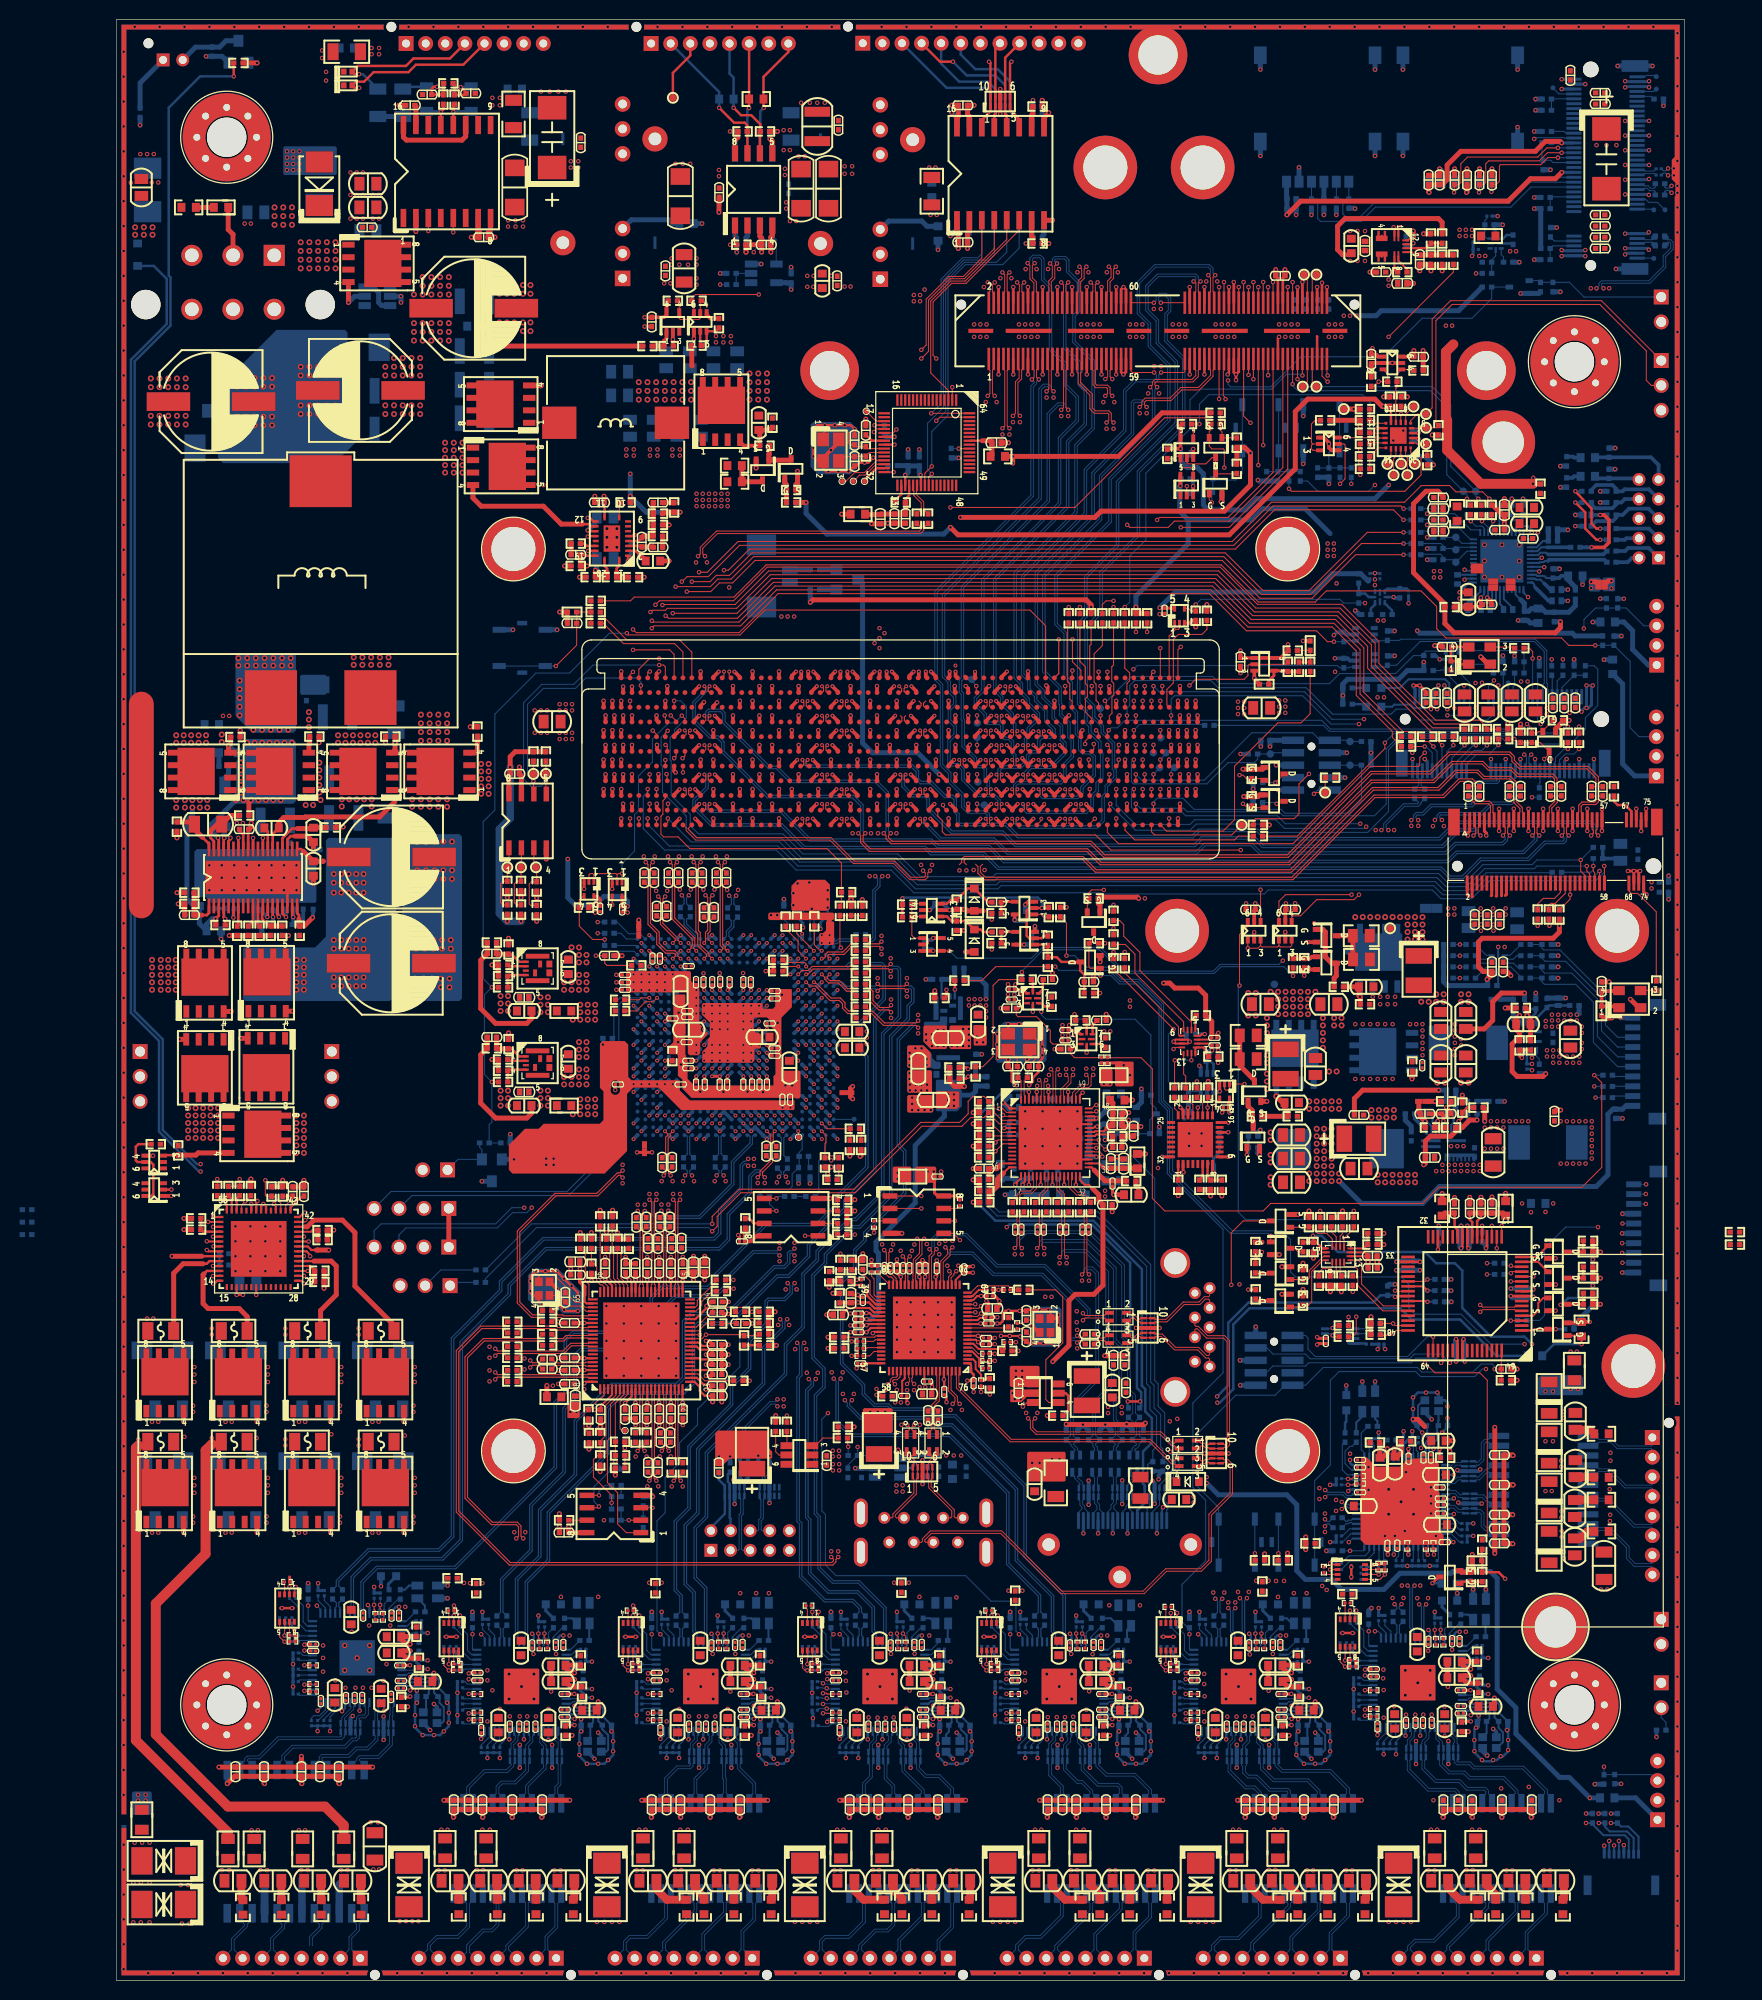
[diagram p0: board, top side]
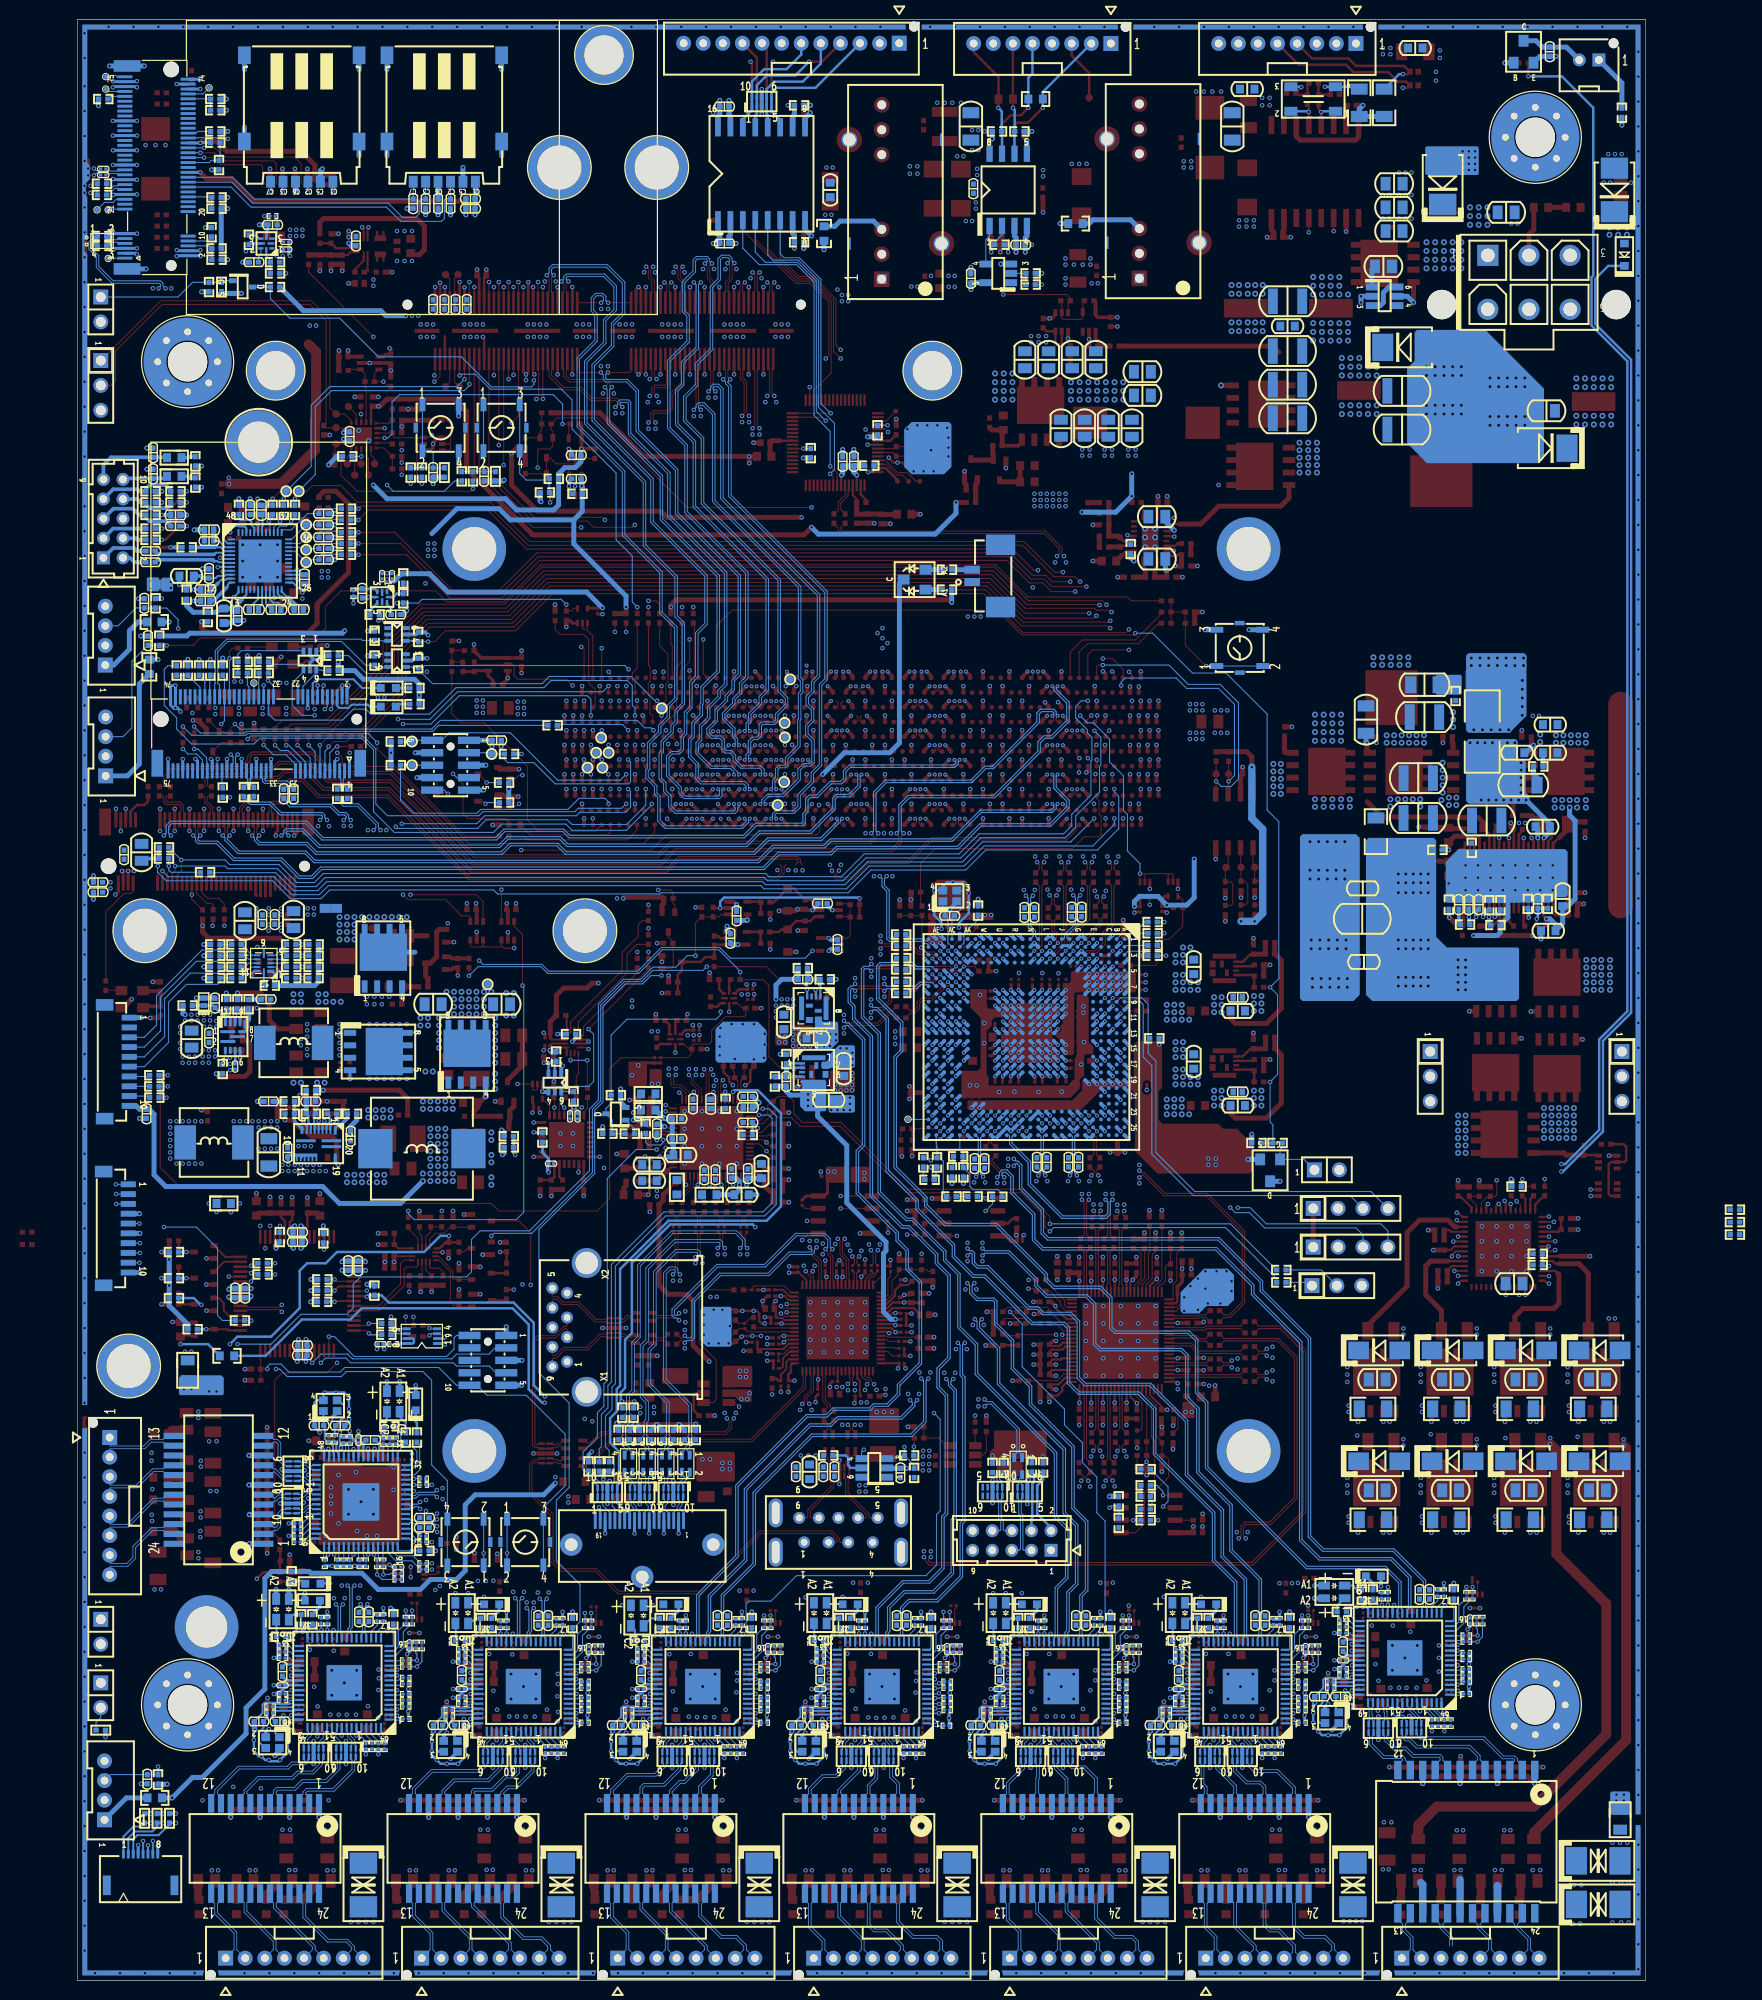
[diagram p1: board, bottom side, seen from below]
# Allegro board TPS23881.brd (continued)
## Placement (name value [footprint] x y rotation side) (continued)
NOREF#2230  -  []  136.13 34.9 0 top
NOREF#2231  -  []  150.88 179.2 0 top
NOREF#2232  -  []  92.93 99.68 90 top
NOREF#2233  -  []  93.21 23.8 270 top
NOREF#2234  -  []  55.77 36.88 270 top
NOREF#2235  -  []  101.3 102.82 0 top
NOREF#2236  -  []  34.46 32.28 0 top
NOREF#2237  -  []  43.46 64.77 0 top
NOREF#2238  -  []  56.52 55.84 270 top
NOREF#2239  -  []  134.95 86.56 90 top
NOREF#2240  -  []  123.42 70.43 0 top
NOREF#2241  -  []  63.25 176.79 90 top
NOREF#2242  -  []  57.26 91.53 0 top
NOREF#2243  -  []  138.25 83.64 90 top
NOREF#2244  -  []  31.19 192.61 0 top
NOREF#2245  -  []  19.8 32.13 0 top
NOREF#2246  -  []  127.03 177.52 270 top
NOREF#2247  -  []  16.48 108 0 top
NOREF#2248  -  []  92.33 61.21 270 top
NOREF#2249  -  []  30.56 36.84 0 top
NOREF#2250  -  []  52.57 36.63 0 top
NOREF#2251  -  []  18.02 31.11 0 top
NOREF#2252  -  []  139.24 140.18 90 top
NOREF#2253  -  []  89.61 29.71 0 top
NOREF#2254  -  []  23.42 28.52 90 top
NOREF#2255  -  []  112.67 37.52 0 top
NOREF#2256  -  []  40.01 95.99 270 top
NOREF#2257  -  []  73.96 111 0 top
NOREF#2258  -  []  38.51 92.08 0 top
NOREF#2259  -  []  150.57 178.1 270 top
NOREF#2260  -  []  128.91 12.52 0 top
NOREF#2261  -  []  93.04 190.7 90 top
NOREF#2262  -  []  130.72 173.1 0 top
NOREF#2263  -  []  126.54 132.26 270 top
NOREF#2264  -  []  129.36 64.76 90 top
NOREF#2265  -  []  68.33 12.52 0 top
NOREF#2266  -  []  79.76 33.9 90 top
NOREF#2267  -  []  63.26 34.52 270 top
NOREF#2268  -  []  61.8 173.69 90 top
NOREF#2269  -  []  156.54 177.5 90 top
NOREF#2270  -  []  65.61 29.58 0 top
NOREF#2271  -  []  126.19 32.5 0 top
NOREF#2272  -  []  127.53 65.43 0 top
NOREF#2273  -  []  146.71 87.67 90 top
NOREF#2274  -  []  130.71 174.24 0 top
NOREF#2275  -  []  58.09 58.6 270 top
NOREF#2276  -  []  36.53 30.75 0 top
NOREF#2277  -  []  52.53 54.43 0 top
NOREF#2278  -  []  121.08 33.01 90 top
NOREF#2279  -  []  130.78 63.24 0 top
NOREF#2280  -  []  48.59 27.42 0 top
NOREF#2281  -  []  61.14 53.09 270 top
NOREF#2282  -  []  116.97 17.4 90 top
NOREF#2283  -  []  87.43 26.34 270 top
NOREF#2284  -  []  137.77 40.21 90 top
NOREF#2285  -  []  124.64 38.96 90 top
NOREF#2286  -  []  133.34 42.85 0 top
NOREF#2287  -  []  39.58 37.2 90 top
NOREF#2288  -  []  56.21 51.38 0 top
NOREF#2289  -  []  50.44 55.37 0 top
NOREF#2290  -  []  109.72 30.61 0 top
NOREF#2291  -  []  146.86 134.54 270 top
NOREF#2292  -  []  136.6 90.09 270 top
NOREF#2293  -  []  48.13 12.52 0 top
NOREF#2294  -  []  73.14 29.21 0 top
NOREF#2295  -  []  150.6 17.02 270 top
NOREF#2296  -  []  37.03 18.72 0 top
NOREF#2297  -  []  103.71 18.72 0 top
NOREF#2298  -  []  83.71 53.94 90 top
NOREF#2299  -  []  -10.06 76.5 0 top
NOREF#2300  -  []  134.37 149.36 90 top
NOREF#2301  -  []  145.11 184.23 0 top
NOREF#2302  -  []  41.14 90.63 0 top
NOREF#2303  -  []  42.21 99.92 90 top
NOREF#2304  -  []  53.39 56.31 270 top
NOREF#2305  -  []  84.56 93.55 0 top
NOREF#2306  -  []  134.99 36.4 0 top
NOREF#2307  -  []  124.98 33.86 90 top
NOREF#2308  -  []  119.96 171.75 270 top
NOREF#2309  -  []  144.73 94.44 90 top
NOREF#2310  -  []  62.1 109.44 270 top
NOREF#2311  -  []  56.77 23.76 270 top
NOREF#2312  -  []  150.88 192.28 0 top
NOREF#2313  -  []  56.85 37.21 270 top
NOREF#2314  -  []  45.49 70.48 0 top
NOREF#2315  -  []  150.57 179.25 270 top
NOREF#2316  -  []  87.22 93.04 90 top
NOREF#2317  -  []  157 182.12 0 top
NOREF#2318  -  []  67.01 64.34 90 top
NOREF#2319  -  []  137.92 120.56 90 top
NOREF#2320  -  []  138.81 26.16 0 top
NOREF#2321  -  []  53.04 29.98 270 top
NOREF#2322  -  []  60.9 25.58 0 top
NOREF#2323  -  []  103.12 63.75 270 top
NOREF#2324  -  []  67.89 152.45 0 top
NOREF#2325  -  []  146 134.54 0 top
NOREF#2326  -  []  142.37 120.78 90 top
NOREF#2327  -  []  103.71 17.09 90 top
NOREF#2328  -  []  65.66 31.62 90 top
NOREF#2329  -  []  136.73 75.62 0 top
NOREF#2330  -  []  65.65 33.78 0 top
NOREF#2331  -  []  148.08 193.8 90 top
NOREF#2332  -  []  60.12 166.32 90 top
NOREF#2333  -  []  109.91 151.21 90 top
NOREF#2334  -  []  39.22 85.42 0 top
NOREF#2335  -  []  118.06 132.66 270 top
NOREF#2336  -  []  122.25 171.75 270 top
NOREF#2337  -  []  82.3 35.97 90 top
NOREF#2338  -  []  132.98 42.24 90 top
NOREF#2339  -  []  138.23 122.1 270 top
NOREF#2340  -  []  148.72 134.09 270 top
NOREF#2341  -  []  132.89 120.09 90 top
NOREF#2342  -  []  133.78 163.78 90 top
NOREF#2343  -  []  45.76 63.5 0 top
NOREF#2344  -  []  65.56 67.06 0 top
NOREF#2345  -  []  111.2 160.32 0 top
NOREF#2346  -  []  140.34 184.11 270 top
NOREF#2347  -  []  151.21 90.75 0 top
NOREF#2348  -  []  93.71 106.95 270 top
NOREF#2349  -  []  50.44 99.59 0 top
NOREF#2350  -  []  83.95 32.16 90 top
NOREF#2351  -  []  49.81 106.81 0 top
NOREF#2352  -  []  40.13 122.81 0 top
NOREF#2353  -  []  140.28 47.19 90 top
NOREF#2354  -  []  133.48 120.55 90 top
NOREF#2355  -  []  38.34 23.8 270 top
NOREF#2356  -  []  57.92 98.11 0 top
NOREF#2357  -  []  47.75 50.14 0 top
NOREF#2358  -  []  115.98 122.17 0 top
NOREF#2359  -  []  102.24 25.78 90 top
NOREF#2360  -  []  57.53 58.29 270 top
NOREF#2361  -  []  27.88 28.61 0 top
NOREF#2362  -  []  147.45 130.81 270 top
NOREF#2363  -  []  25.4 54.14 0 top
NOREF#2364  -  []  82.14 104.85 0 top
NOREF#2365  -  []  17.73 108.92 0 top
NOREF#2366  -  []  61.68 91.68 270 top
NOREF#2367  -  []  63.88 17.4 90 top
NOREF#2368  -  []  133.08 93.65 0 top
NOREF#2369  -  []  130.12 69.42 90 top
NOREF#2370  -  []  51.61 101.8 0 top
NOREF#2371  -  []  134.26 147.47 90 top
NOREF#2372  -  []  153.5 57.37 0 top
NOREF#2373  -  []  13.28 81.46 0 top
NOREF#2374  -  []  135.38 17.44 90 top
NOREF#2375  -  []  51.45 109.55 0 top
NOREF#2376  -  []  131.69 141.17 0 top
NOREF#2377  -  []  45.29 35.51 90 top
NOREF#2378  -  []  110.3 52.26 90 top
NOREF#2379  -  []  43 65.2 270 top
NOREF#2380  -  []  55.36 25.22 0 top
NOREF#2381  -  []  110.49 36.31 90 top
NOREF#2382  -  []  101.01 97.67 90 top
NOREF#2383  -  []  99.44 139.42 270 top
NOREF#2384  -  []  100.32 29.21 0 top
NOREF#2385  -  []  28.97 36.91 90 top
NOREF#2386  -  []  144.98 101.8 0 top
NOREF#2387  -  []  97.61 18.72 0 top
NOREF#2388  -  []  48.46 75.62 270 top
NOREF#2389  -  []  134.4 148.46 0 top
NOREF#2390  -  []  73.91 36.84 270 top
NOREF#2391  -  []  119.42 181.74 0 top
NOREF#2392  -  []  42.97 94.82 270 top
NOREF#2393  -  []  48.46 73.08 270 top
NOREF#2394  -  []  146.56 95.67 90 top
NOREF#2395  -  []  137.16 18.41 90 top
NOREF#2396  -  []  145.71 107.79 0 top
NOREF#2397  -  []  61.84 36.02 0 top
NOREF#2398  -  []  99.71 101.6 90 top
NOREF#2399  -  []  81.41 34.48 270 top
NOREF#2400  -  []  139.81 179.96 0 top
NOREF#2401  -  []  12.52 117.17 0 top
NOREF#2402  -  []  127.97 31.61 90 top
NOREF#2403  -  []  18.57 22.1 0 top
NOREF#2404  -  []  50.44 52.7 270 top
NOREF#2405  -  []  53.04 32.12 0 top
NOREF#2406  -  []  130.54 44.03 0 top
NOREF#2407  -  []  41.14 90.63 0 top
NOREF#2408  -  []  79.65 41 0 top
NOREF#2409  -  []  134.62 52.88 90 top
NOREF#2410  -  []  41.14 100.28 0 top
NOREF#2411  -  []  91.43 26.54 0 top
NOREF#2412  -  []  21.8 39.87 90 top
NOREF#2413  -  []  93.04 109.4 270 top
NOREF#2414  -  []  126.99 42.16 0 top
NOREF#2415  -  []  58.57 82.63 0 top
NOREF#2416  -  []  60.73 70.74 0 top
NOREF#2417  -  []  25.31 36.91 90 top
NOREF#2418  -  []  46.46 58.52 0 top
NOREF#2419  -  []  57.28 109.47 90 top
NOREF#2420  -  []  133.3 130 0 top
NOREF#2421  -  []  67.03 102.95 0 top
NOREF#2422  -  []  27.38 168.48 270 top
NOREF#2423  -  []  143.64 70.6 90 top
NOREF#2424  -  []  62.81 177.47 270 top
NOREF#2425  -  []  152.44 167.8 0 top
NOREF#2426  -  []  20.38 25.93 90 top
NOREF#2427  -  []  115.71 34.47 270 top
NOREF#2428  -  []  139.27 90.09 270 top
NOREF#2429  -  []  144.4 17.44 90 top
NOREF#2430  -  []  135.94 71.07 90 top
NOREF#2431  -  []  116.96 18.41 90 top
NOREF#2432  -  []  99.29 98.35 270 top
NOREF#2433  -  []  118.97 109.52 270 top
NOREF#2434  -  []  124.12 46.18 0 top
NOREF#2435  -  []  83.85 34.67 0 top
NOREF#2436  -  []  25.17 36.94 90 top
NOREF#2437  -  []  87.66 93.19 270 top
NOREF#2438  -  []  80.72 35.51 90 top
NOREF#2439  -  []  100.28 29.07 0 top
NOREF#2440  -  []  142.42 122.1 270 top
NOREF#2441  -  []  140.82 107.39 0 top
NOREF#2442  -  []  36.96 177.55 0 top
NOREF#2443  -  []  30.59 35.43 0 top
NOREF#2444  -  []  138.51 26.72 0 top
NOREF#2445  -  []  18.03 109.26 90 top
NOREF#2446  -  []  132.7 42.24 0 top
NOREF#2447  -  []  79.18 25.58 0 top
NOREF#2448  -  []  63.88 18.41 90 top
NOREF#2449  -  []  83.9 29.86 270 top
NOREF#2450  -  []  123.05 41.59 0 top
NOREF#2451  -  []  142.72 96.32 0 top
NOREF#2452  -  []  139.06 121.75 270 top
NOREF#2453  -  []  129.59 54.87 90 top
NOREF#2454  -  []  122.35 26.78 90 top
NOREF#2455  -  []  100.98 93.55 90 top
NOREF#2456  -  []  53.04 28.05 0 top
NOREF#2457  -  []  125.02 44.56 90 top
NOREF#2458  -  []  120.53 31.62 90 top
NOREF#2459  -  []  140.54 127.05 270 top
NOREF#2460  -  []  128.57 27.83 270 top
NOREF#2461  -  []  50.44 51.84 0 top
NOREF#2462  -  []  88.98 109.68 0 top
NOREF#2463  -  []  92.84 36.31 90 top
NOREF#2464  -  []  50.19 76.48 0 top
NOREF#2465  -  []  83.93 32.51 0 top
NOREF#2466  -  []  37.83 96.22 0 top
NOREF#2467  -  []  139.85 107.73 90 top
NOREF#2468  -  []  134.89 42.24 90 top
NOREF#2469  -  []  135.69 87 0 top
NOREF#2470  -  []  63.88 34.48 270 top
NOREF#2471  -  []  34.75 27.7 0 top
NOREF#2472  -  []  42.56 34.47 270 top
NOREF#2473  -  []  137.85 88.39 0 top
NOREF#2474  -  []  126.23 30.23 0 top
NOREF#2475  -  []  18.02 33.4 0 top
NOREF#2476  -  []  149.5 151.89 0 top
NOREF#2477  -  []  152.1 114.86 270 top
NOREF#2478  -  []  132.03 165.91 0 top
NOREF#2479  -  []  37.21 25.26 90 top
NOREF#2480  -  []  30.18 36.5 0 top
NOREF#2481  -  []  85.17 102.41 270 top
NOREF#2482  -  []  101.98 63.75 270 top
NOREF#2483  -  []  51.64 173.61 90 top
NOREF#2484  -  []  127.2 75.49 0 top
NOREF#2485  -  []  30.89 192.05 0 top
NOREF#2486  -  []  58.53 99.02 270 top
NOREF#2487  -  []  58.99 101.51 0 top
NOREF#2488  -  []  116.09 134.24 270 top
NOREF#2489  -  []  69.14 174.42 270 top
NOREF#2490  -  []  58.52 72.11 0 top
NOREF#2491  -  []  57.61 82.93 90 top
NOREF#2492  -  []  67.89 150.32 0 top
NOREF#2493  -  []  141.12 107.73 90 top
NOREF#2494  -  []  58.24 170.89 90 top
NOREF#2495  -  []  58.04 73.14 90 top
NOREF#2496  -  []  58.55 109.44 270 top
NOREF#2497  -  []  144.2 70.92 270 top
NOREF#2498  -  []  120.22 134.92 0 top
NOREF#2499  -  []  131.46 55.42 270 top
NOREF#2500  -  []  83.95 31.62 90 top
NOREF#2501  -  []  67.01 83.77 0 top
NOREF#2502  -  []  134.95 102.67 0 top
NOREF#2503  -  []  76.89 104.7 270 top
NOREF#2504  -  []  118.24 152.91 90 top
NOREF#2505  -  []  83.61 99.16 0 top
NOREF#2506  -  []  111.35 151.33 0 top
NOREF#2507  -  []  133.22 175.01 90 top
NOREF#2508  -  []  151.59 146.51 90 top
NOREF#2509  -  []  2.99 170.93 0 top
NOREF#2510  -  []  39.45 61.8 0 top
NOREF#2511  -  []  96.02 94.69 0 top
NOREF#2512  -  []  38.8 104.47 90 top
NOREF#2513  -  []  151.59 139.52 90 top
NOREF#2514  -  []  19.75 26.54 0 top
NOREF#2515  -  []  49.23 25.73 0 top
NOREF#2516  -  []  66.22 33.64 90 top
NOREF#2517  -  []  120.75 104.7 270 top
NOREF#2518  -  []  91.19 35.97 90 top
NOREF#2519  -  []  68.2 82.8 90 top
NOREF#2520  -  []  141.86 121.79 270 top
NOREF#2521  -  []  76.15 37.21 270 top
NOREF#2522  -  []  39.88 112.12 270 top
NOREF#2523  -  []  152.68 87.88 90 top
NOREF#2524  -  []  70.35 38.23 0 top
NOREF#2525  -  []  126.44 159.84 0 top
NOREF#2526  -  []  138.91 79.55 0 top
NOREF#2527  -  []  20.09 76.96 270 top
NOREF#2528  -  []  -9.6 76.07 0 top
NOREF#2529  -  []  135.25 143.51 0 top
NOREF#2530  -  []  136.27 34.86 270 top
NOREF#2531  -  []  151.87 17.02 270 top
NOREF#2532  -  []  134.76 34.85 270 top
NOREF#2533  -  []  118.12 34.52 270 top
NOREF#2534  -  []  140.59 46.35 0 top
NOREF#2535  -  []  126.31 143.94 0 top
NOREF#2536  -  []  31.29 31.45 90 top
NOREF#2537  -  []  134.95 104.95 270 top
NOREF#2538  -  []  107.65 156.64 270 top
NOREF#2539  -  []  65.79 176.78 0 top
NOREF#2540  -  []  128 29.59 0 top
NOREF#2541  -  []  37.13 27.44 270 top
NOREF#2542  -  []  82.8 102.54 0 top
NOREF#2543  -  []  61.79 61.55 90 top
NOREF#2544  -  []  19.25 127.3 0 top
NOREF#2545  -  []  146.86 106.1 270 top
NOREF#2546  -  []  132.35 42.24 90 top
NOREF#2547  -  []  37.85 23.76 270 top
NOREF#2548  -  []  152.02 139.98 90 top
NOREF#2549  -  []  146.86 104.95 270 top
NOREF#2550  -  []  30.61 33.53 90 top
NOREF#2551  -  []  139.22 78.27 90 top
NOREF#2552  -  []  52.7 32.14 90 top
NOREF#2553  -  []  107.9 32.4 270 top
NOREF#2554  -  []  79.49 36.63 270 top
NOREF#2555  -  []  37.36 94.64 0 top
NOREF#2556  -  []  81.97 26.42 0 top
NOREF#2557  -  []  149.5 150.75 0 top
NOREF#2558  -  []  100.46 34.48 270 top
NOREF#2559  -  []  146.58 128.52 0 top
NOREF#2560  -  []  119.38 180.47 0 top
NOREF#2561  -  []  122.68 70.89 90 top
NOREF#2562  -  []  68.58 174.12 270 top
NOREF#2563  -  []  126.26 88.01 0 top
NOREF#2564  -  []  75.54 84.28 0 top
NOREF#2565  -  []  42.98 125.78 270 top
NOREF#2566  -  []  78.3 25.58 0 top
NOREF#2567  -  []  57.26 23.8 270 top
NOREF#2568  -  []  138.76 29.35 0 top
NOREF#2569  -  []  6.93 108.92 0 top
NOREF#2570  -  []  124.66 76.4 90 top
NOREF#2571  -  []  138.76 182.83 0 top
NOREF#2572  -  []  60.66 109.74 0 top
NOREF#2573  -  []  75.77 52.27 270 top
NOREF#2574  -  []  48.63 27.56 0 top
NOREF#2575  -  []  12.09 119.25 270 top
NOREF#2576  -  []  144.65 18.41 90 top
NOREF#2577  -  []  58.24 109.78 0 top
NOREF#2578  -  []  141 127.64 0 top
NOREF#2579  -  []  49.33 142.7 90 top
NOREF#2580  -  []  134.95 103.81 0 top
NOREF#2581  -  []  149.2 73.2 0 top
NOREF#2582  -  []  138.81 184.15 270 top
NOREF#2583  -  []  73.1 78.05 0 top
NOREF#2584  -  []  45.72 35.97 90 top
NOREF#2585  -  []  44.15 35.51 0 top
NOREF#2586  -  []  74.83 85.7 270 top
NOREF#2587  -  []  139.09 139.47 90 top
NOREF#2588  -  []  93.68 36.23 90 top
NOREF#2589  -  []  153.16 139.99 90 top
NOREF#2590  -  []  100 97.66 0 top
NOREF#2591  -  []  134.68 50.15 0 top
NOREF#2592  -  []  147.11 120.49 0 top
NOREF#2593  -  []  54.94 51.51 0 top
NOREF#2594  -  []  56.18 149.17 90 top
NOREF#2595  -  []  53.92 76 270 top
NOREF#2596  -  []  26.87 0.16 90 top
NOREF#2597  -  []  50.52 48.08 0 top
NOREF#2598  -  []  108.03 151.21 0 top
NOREF#2599  -  []  68.99 108.94 270 top
NOREF#2600  -  []  134.72 50.29 0 top
NOREF#2601  -  []  27.94 6.93 90 top
NOREF#2602  -  []  100.28 27.47 0 top
NOREF#2603  -  []  65.48 51.79 90 top
NOREF#2604  -  []  135.18 89.66 0 top
NOREF#2605  -  []  164.19 75.49 270 top
NOREF#2606  -  []  61.2 36.63 0 top
NOREF#2607  -  []  131.33 42.24 90 top
NOREF#2608  -  []  34.42 17.44 90 top
NOREF#2609  -  []  45.72 66.8 90 top
NOREF#2610  -  []  58.24 170.89 0 top
NOREF#2611  -  []  137.07 76.33 0 top
NOREF#2612  -  []  53.07 26.29 0 top
NOREF#2613  -  []  76.58 18.41 270 top
NOREF#2614  -  []  43.46 65.91 0 top
NOREF#2615  -  []  75.46 105.03 0 top
NOREF#2616  -  []  54.69 104.5 270 top
NOREF#2617  -  []  125.97 33.86 0 top
NOREF#2618  -  []  149.39 7.98 90 top
NOREF#2619  -  []  55.37 72.17 90 top
NOREF#2620  -  []  92.98 36.27 90 top
NOREF#2621  -  []  126.19 32.78 270 top
NOREF#2622  -  []  75.67 108.15 0 top
NOREF#2623  -  []  140.82 107.39 90 top
NOREF#2624  -  []  135.23 90.37 0 top
NOREF#2625  -  []  64.82 189.03 270 top
NOREF#2626  -  []  139.32 120.78 90 top
NOREF#2627  -  []  102.79 32.37 90 top
NOREF#2628  -  []  101.31 65.81 0 top
NOREF#2629  -  []  122.83 159.13 0 top
NOREF#2630  -  []  88.09 93.65 270 top
NOREF#2631  -  []  128.91 141.57 270 top
NOREF#2632  -  []  118.88 34.52 270 top
NOREF#2633  -  []  54.18 37.39 0 top
NOREF#2634  -  []  71.2 108.51 270 top
NOREF#2635  -  []  42.71 102.77 0 top
NOREF#2636  -  []  83.52 33.58 0 top
NOREF#2637  -  []  133.07 87.96 0 top
NOREF#2638  -  []  60.57 34.47 0 top
NOREF#2639  -  []  151.21 135.71 90 top
NOREF#2640  -  []  84.51 31.93 270 top
NOREF#2641  -  []  131.97 52.91 90 top
NOREF#2642  -  []  48.59 56.79 90 top
NOREF#2643  -  []  49.71 58.55 270 top
NOREF#2644  -  []  60.48 64.14 0 top
NOREF#2645  -  []  122.81 77.83 270 top
NOREF#2646  -  []  85.17 102.41 0 top
NOREF#2647  -  []  43.13 63.07 0 top
NOREF#2648  -  []  120.35 154.36 0 top
NOREF#2649  -  []  52.7 36.59 270 top
NOREF#2650  -  []  54.74 145.92 0 top
NOREF#2651  -  []  61.44 52.74 270 top
NOREF#2652  -  []  141.12 107.73 90 top
NOREF#2653  -  []  42.61 25.58 0 top
NOREF#2654  -  []  119.18 26.99 270 top
NOREF#2655  -  []  84.79 110.16 270 top
NOREF#2656  -  []  127.46 55.3 270 top
NOREF#2657  -  []  141.99 120.73 90 top
NOREF#2658  -  []  65.1 67.77 90 top
NOREF#2659  -  []  73.1 26.4 0 top
NOREF#2660  -  []  117.98 34.48 270 top
NOREF#2661  -  []  10.41 54.14 0 top
NOREF#2662  -  []  89.78 33.65 90 top
NOREF#2663  -  []  15.75 106.58 90 top
NOREF#2664  -  []  10.06 72.54 90 top
NOREF#2665  -  []  30.3 29.26 270 top
NOREF#2666  -  []  114.11 25.58 90 top
NOREF#2667  -  []  24.87 2.26 90 top
NOREF#2668  -  []  146.87 0.16 90 top
NOREF#2669  -  []  57.28 166.27 90 top
NOREF#2670  -  []  58.3 109.47 90 top
NOREF#2671  -  []  122.94 181.73 90 top
NOREF#2672  -  []  121.23 78.28 0 top
NOREF#2673  -  []  56.38 18.41 90 top
NOREF#2674  -  []  53.07 31.62 0 top
NOREF#2675  -  []  140.16 107.39 90 top
NOREF#2676  -  []  12.01 109.32 90 top
NOREF#2677  -  []  115.21 108.97 0 top
NOREF#2678  -  []  57.07 53.26 270 top
NOREF#2679  -  []  121.06 71.53 90 top
NOREF#2680  -  []  100.15 35.51 90 top
NOREF#2681  -  []  53.04 28.97 270 top
NOREF#2682  -  []  135.59 35.89 90 top
NOREF#2683  -  []  109.91 155.27 90 top
NOREF#2684  -  []  21.11 54.14 90 top
NOREF#2685  -  []  49.81 105.56 0 top
NOREF#2686  -  []  34.79 30.48 0 top
NOREF#2687  -  []  149.66 69.6 0 top
NOREF#2688  -  []  20.78 20.82 90 top
NOREF#2689  -  []  76.14 197.59 90 top
NOREF#2690  -  []  73.71 27.44 270 top
NOREF#2691  -  []  157.66 184.01 90 top
NOREF#2692  -  []  33.81 41.02 0 top
NOREF#2693  -  []  120.65 29.95 270 top
NOREF#2694  -  []  122.38 159.56 270 top
NOREF#2695  -  []  53.92 76 0 top
NOREF#2696  -  []  87.41 92.19 90 top
NOREF#2697  -  []  57.53 109.44 270 top
NOREF#2698  -  []  37.21 23.76 270 top
NOREF#2699  -  []  138.8 33.53 0 top
NOREF#2700  -  []  21.16 25.97 90 top
NOREF#2701  -  []  37.36 105.44 90 top
NOREF#2702  -  []  63.14 68.2 0 top
NOREF#2703  -  []  83.64 26.34 270 top
NOREF#2704  -  []  141.6 17.4 90 top
NOREF#2705  -  []  100.89 27.75 270 top
NOREF#2706  -  []  122.56 73.86 90 top
NOREF#2707  -  []  89.4 33.48 0 top
NOREF#2708  -  []  51.77 142.7 0 top
NOREF#2709  -  []  110.22 25.22 90 top
NOREF#2710  -  []  31.17 31.61 90 top
NOREF#2711  -  []  51.59 109.51 270 top
NOREF#2712  -  []  48.81 150.75 0 top
NOREF#2713  -  []  65.47 91.68 0 top
NOREF#2714  -  []  39.45 61.52 270 top
NOREF#2715  -  []  68.28 108.48 270 top
NOREF#2716  -  []  75.46 102.74 0 top
NOREF#2717  -  []  138.81 83.95 90 top
NOREF#2718  -  []  134.75 42.28 90 top
NOREF#2719  -  []  83.06 57.1 90 top
NOREF#2720  -  []  118.87 35.97 90 top
NOREF#2721  -  []  97.78 36.63 270 top
NOREF#2722  -  []  75.26 86.16 270 top
NOREF#2723  -  []  149.52 149.48 0 top
NOREF#2724  -  []  128.32 158.7 90 top
NOREF#2725  -  []  63.73 78.16 0 top
NOREF#2726  -  []  134.95 103.81 270 top
NOREF#2727  -  []  93.37 106.77 270 top
NOREF#2728  -  []  139.67 89.36 0 top
NOREF#2729  -  []  90.75 37.39 0 top
NOREF#2730  -  []  60.27 18.72 0 top
NOREF#2731  -  []  55.07 56.97 0 top
NOREF#2732  -  []  134.4 151.26 0 top
NOREF#2733  -  []  136.73 75.01 90 top
NOREF#2734  -  []  34.75 28.33 270 top
NOREF#2735  -  []  45.16 45.92 0 top
NOREF#2736  -  []  157.38 112.27 0 top
NOREF#2737  -  []  14.17 108 0 top
NOREF#2738  -  []  97.59 139.88 270 top
NOREF#2739  -  []  69.16 81.48 0 top
NOREF#2740  -  []  59.25 25.58 90 top
NOREF#2741  -  []  140.54 128.07 0 top
NOREF#2742  -  []  138.32 79.24 90 top
NOREF#2743  -  []  139.37 32.75 90 top
NOREF#2744  -  []  135.94 69.93 90 top
NOREF#2745  -  []  54.81 109.87 270 top
NOREF#2746  -  []  116.47 34.47 270 top
NOREF#2747  -  []  126.8 27.8 90 top
NOREF#2748  -  []  55.36 23.8 0 top
NOREF#2749  -  []  82.03 34.52 0 top
NOREF#2750  -  []  124.41 42.68 270 top
NOREF#2751  -  []  134.23 44.63 0 top
NOREF#2752  -  []  60.53 69.52 0 top
NOREF#2753  -  []  142.49 178.03 270 top
NOREF#2754  -  []  140.59 183.13 90 top
NOREF#2755  -  []  31.86 30.48 0 top
NOREF#2756  -  []  36.16 193.5 270 top
NOREF#2757  -  []  137.24 45.2 90 top
NOREF#2758  -  []  60.01 25.58 0 top
NOREF#2759  -  []  121.36 133.05 0 top
NOREF#2760  -  []  52.7 31.51 0 top
NOREF#2761  -  []  76.02 18.72 270 top
NOREF#2762  -  []  119.2 152.48 0 top
NOREF#2763  -  []  86.44 93.55 270 top
NOREF#2764  -  []  135.25 177.19 90 top
NOREF#2765  -  []  121.78 26.92 0 top
NOREF#2766  -  []  140.61 72.01 0 top
NOREF#2767  -  []  47.93 33.01 90 top
NOREF#2768  -  []  137.96 136 0 top
NOREF#2769  -  []  90.83 98.91 90 top
NOREF#2770  -  []  64.87 2.26 90 top
NOREF#2771  -  []  53.64 27.42 90 top
NOREF#2772  -  []  152.48 137.46 0 top
NOREF#2773  -  []  108.74 158.75 0 top
NOREF#2774  -  []  54.94 187.83 90 top
NOREF#2775  -  []  136.83 142.43 90 top
NOREF#2776  -  []  98.27 100.28 0 top
NOREF#2777  -  []  16.54 81.41 0 top
NOREF#2778  -  []  144.07 133.78 270 top
NOREF#2779  -  []  42.3 184.31 0 top
NOREF#2780  -  []  50.09 150.44 90 top
NOREF#2781  -  []  54.48 75.69 270 top
NOREF#2782  -  []  55.5 55.84 270 top
NOREF#2783  -  []  126.19 32.14 270 top
NOREF#2784  -  []  64.2 66.76 90 top
NOREF#2785  -  []  138.25 83.64 0 top
NOREF#2786  -  []  100.89 26.99 270 top
NOREF#2787  -  []  45.72 63.75 0 top
NOREF#2788  -  []  119.08 135.2 0 top
NOREF#2789  -  []  141.81 120.47 0 top
NOREF#2790  -  []  119.61 102.82 90 top
NOREF#2791  -  []  14.94 190.7 0 top
NOREF#2792  -  []  140.64 27.17 90 top
NOREF#2793  -  []  32.77 29.21 0 top
NOREF#2794  -  []  6.5 111.38 0 top
NOREF#2795  -  []  89.32 109.98 0 top
NOREF#2796  -  []  60.78 63.58 0 top
NOREF#2797  -  []  55.99 23.8 0 top
NOREF#2798  -  []  96.58 25.58 90 top
NOREF#2799  -  []  134.05 25.96 90 top
NOREF#2800  -  []  65.23 188.16 0 top
NOREF#2801  -  []  55.98 84.25 270 top
NOREF#2802  -  []  7.19 77.01 0 top
NOREF#2803  -  []  141.05 17.09 90 top
NOREF#2804  -  []  66.22 28.05 90 top
NOREF#2805  -  []  139.12 104.95 270 top
NOREF#2806  -  []  39.83 36.23 90 top
NOREF#2807  -  []  144.7 104.95 270 top
NOREF#2808  -  []  25.11 178.82 0 top
NOREF#2809  -  []  67.84 108.94 270 top
NOREF#2810  -  []  54.81 26.4 0 top
NOREF#2811  -  []  76.89 100.89 270 top
NOREF#2812  -  []  134.7 182.83 0 top
NOREF#2813  -  []  84.86 94.11 270 top
NOREF#2814  -  []  57.23 109.78 0 top
NOREF#2815  -  []  157 183.26 0 top
NOREF#2816  -  []  111.2 159.18 270 top
NOREF#2817  -  []  70.52 108.58 0 top
NOREF#2818  -  []  121.67 181.74 270 top
NOREF#2819  -  []  156.84 176.91 90 top
NOREF#2820  -  []  108.87 0.16 0 top
NOREF#2821  -  []  42.97 101.97 90 top
NOREF#2822  -  []  19.81 130.07 90 top
NOREF#2823  -  []  157.1 100.99 90 top
NOREF#2824  -  []  95 35.89 90 top
NOREF#2825  -  []  57.35 76 0 top
NOREF#2826  -  []  14.38 108.74 90 top
NOREF#2827  -  []  19.76 34.15 90 top
NOREF#2828  -  []  134.06 145.21 0 top
NOREF#2829  -  []  57.1 37.17 270 top
NOREF#2830  -  []  137.69 42.16 270 top
NOREF#2831  -  []  48.9 148.82 0 top
NOREF#2832  -  []  137.24 45.83 0 top
NOREF#2833  -  []  53.54 113.3 0 top
NOREF#2834  -  []  137.16 17.4 90 top
NOREF#2835  -  []  152.63 87.58 90 top
NOREF#2836  -  []  38.34 23.8 0 top
NOREF#2837  -  []  18.8 186.18 270 top
NOREF#2838  -  []  124.66 129.74 0 top
NOREF#2839  -  []  152.68 15.57 0 top
NOREF#2840  -  []  67.49 26.78 90 top
NOREF#2841  -  []  65.65 29.72 0 top
NOREF#2842  -  []  136.65 133.15 90 top
NOREF#2843  -  []  87.22 91.77 0 top
NOREF#2844  -  []  146.86 131.11 270 top
NOREF#2845  -  []  20.75 115.32 0 top
NOREF#2846  -  []  124.41 44.84 0 top
NOREF#2847  -  []  126.75 140.49 90 top
NOREF#2848  -  []  135.33 74.75 90 top
NOREF#2849  -  []  143.97 125.81 0 top
NOREF#2850  -  []  140.59 53.85 0 top
NOREF#2851  -  []  55.7 77.84 90 top
NOREF#2852  -  []  17.93 107.7 0 top
NOREF#2853  -  []  34.75 28.69 0 top
NOREF#2854  -  []  32.46 28.65 0 top
NOREF#2855  -  []  56.43 98.26 0 top
NOREF#2856  -  []  79.73 108.89 270 top
NOREF#2857  -  []  64.14 75.53 270 top
NOREF#2858  -  []  148.64 193.5 90 top
NOREF#2859  -  []  97.03 58.04 270 top
NOREF#2860  -  []  46.34 73.3 0 top
NOREF#2861  -  []  127.36 72.95 0 top
NOREF#2862  -  []  134.06 147.5 0 top
NOREF#2863  -  []  60.91 113.3 270 top
NOREF#2864  -  []  126.23 32 0 top
NOREF#2865  -  []  22.61 180.47 90 top
NOREF#2866  -  []  64.58 101.51 0 top
NOREF#2867  -  []  101.98 63.75 90 top
NOREF#2868  -  []  81.02 18.41 90 top
NOREF#2869  -  []  102.22 28.19 0 top
NOREF#2870  -  []  138.81 30.99 90 top
NOREF#2871  -  []  131.19 42.28 90 top
NOREF#2872  -  []  47.36 29.72 0 top
NOREF#2873  -  []  156.54 177.34 0 top
NOREF#2874  -  []  121.08 30.4 270 top
NOREF#2875  -  []  146.09 147.96 0 top
NOREF#2876  -  []  132.51 54.56 90 top
NOREF#2877  -  []  135.13 36.44 90 top
NOREF#2878  -  []  63.32 18.72 0 top
NOREF#2879  -  []  52.96 72.17 90 top
NOREF#2880  -  []  2.24 53.8 0 top
NOREF#2881  -  []  102.22 33.15 0 top
NOREF#2882  -  []  115.82 119.79 90 top
NOREF#2883  -  []  18.19 54.94 0 top
NOREF#2884  -  []  132.07 55.42 0 top
NOREF#2885  -  []  150.57 176.96 270 top
NOREF#2886  -  []  58.66 93.94 270 top
NOREF#2887  -  []  11 79.58 90 top
NOREF#2888  -  []  61.46 101.55 0 top
NOREF#2889  -  []  16.26 107.21 90 top
NOREF#2890  -  []  117.3 35.51 90 top
NOREF#2891  -  []  60.83 18.41 90 top
NOREF#2892  -  []  132.7 54.81 90 top
NOREF#2893  -  []  126.95 41.03 0 top
NOREF#2894  -  []  74.52 110.03 0 top
NOREF#2895  -  []  142.8 175.56 270 top
NOREF#2896  -  []  112.13 23.8 0 top
NOREF#2897  -  []  54.36 57.28 90 top
NOREF#2898  -  []  116.98 36.02 90 top
NOREF#2899  -  []  144.07 135.46 90 top
NOREF#2900  -  []  75.01 106.6 0 top
NOREF#2901  -  []  74.92 23.8 0 top
NOREF#2902  -  []  91.69 38.76 90 top
NOREF#2903  -  []  125.08 58.13 0 top
NOREF#2904  -  []  56.39 108.55 90 top
NOREF#2905  -  []  99.01 35.51 90 top
NOREF#2906  -  []  96.77 17.4 90 top
NOREF#2907  -  []  89.65 32.26 0 top
NOREF#2908  -  []  107.61 31.65 0 top
NOREF#2909  -  []  22.81 38.86 90 top
NOREF#2910  -  []  142.19 132.92 0 top
NOREF#2911  -  []  115.8 70.92 0 top
NOREF#2912  -  []  89.61 30.62 270 top
NOREF#2913  -  []  46.35 145.16 0 top
NOREF#2914  -  []  54.78 150.75 0 top
NOREF#2915  -  []  10.74 109.3 90 top
NOREF#2916  -  []  66.6 85.39 270 top
NOREF#2917  -  []  65.66 79.93 0 top
NOREF#2918  -  []  64.03 64.8 90 top
NOREF#2919  -  []  111.25 138.71 90 top
NOREF#2920  -  []  140.03 134.06 0 top
NOREF#2921  -  []  65.58 64.77 0 top
NOREF#2922  -  []  55.12 58.29 270 top
NOREF#2923  -  []  20.47 22.1 0 top
NOREF#2924  -  []  60.58 17.44 90 top
NOREF#2925  -  []  54.18 49.81 270 top
NOREF#2926  -  []  138.81 32 90 top
NOREF#2927  -  []  127.97 29.45 0 top
NOREF#2928  -  []  124.76 182.04 270 top
NOREF#2929  -  []  113.87 157.78 0 top
NOREF#2930  -  []  39.57 104.22 0 top
NOREF#2931  -  []  107.9 28.05 0 top
NOREF#2932  -  []  140.24 177.16 90 top
NOREF#2933  -  []  125.65 136.09 90 top
NOREF#2934  -  []  21.65 26.54 0 top
NOREF#2935  -  []  18.29 39.51 270 top
NOREF#2936  -  []  131.19 141.99 270 top
NOREF#2937  -  []  50.7 74.19 0 top
NOREF#2938  -  []  137.81 111.93 90 top
NOREF#2939  -  []  13.61 65.44 90 top
NOREF#2940  -  []  50.06 143.13 0 top
NOREF#2941  -  []  134.37 144.65 0 top
NOREF#2942  -  []  52.19 73.14 90 top
NOREF#2943  -  []  157.07 111.71 0 top
NOREF#2944  -  []  47.37 32.16 90 top
NOREF#2945  -  []  81.99 29.07 0 top
NOREF#2946  -  []  126.75 143.48 270 top
NOREF#2947  -  []  75.46 99.31 0 top
NOREF#2948  -  []  56.64 52.81 270 top
NOREF#2949  -  []  155.5 100.96 270 top
NOREF#2950  -  []  75.46 106.68 0 top
NOREF#2951  -  []  101.68 35.1 0 top
NOREF#2952  -  []  136.02 130.3 90 top
NOREF#2953  -  []  70.99 32.42 0 top
NOREF#2954  -  []  57.26 23.8 0 top
NOREF#2955  -  []  87 51.08 90 top
NOREF#2956  -  []  117.4 116.28 90 top
NOREF#2957  -  []  40.08 17.09 90 top
NOREF#2958  -  []  34.79 28.83 0 top
NOREF#2959  -  []  47.32 31.93 0 top
NOREF#2960  -  []  136.56 63.75 0 top
NOREF#2961  -  []  114.87 25.58 90 top
NOREF#2962  -  []  6.5 110.24 0 top
NOREF#2963  -  []  76.89 106.6 270 top
NOREF#2964  -  []  129.18 139.32 0 top
NOREF#2965  -  []  94.59 106.98 270 top
NOREF#2966  -  []  56.01 173.9 90 top
NOREF#2967  -  []  52.18 102.43 90 top
NOREF#2968  -  []  128 55.3 0 top
NOREF#2969  -  []  134.11 184.14 90 top
NOREF#2970  -  []  99.01 35.51 0 top
NOREF#2971  -  []  154.98 115.32 90 top
NOREF#2972  -  []  74.64 199.29 0 top
NOREF#2973  -  []  139.12 106.1 270 top
NOREF#2974  -  []  -9.6 78.61 0 top
NOREF#2975  -  []  26.29 38.98 90 top
NOREF#2976  -  []  84.56 92.41 0 top
NOREF#2977  -  []  100.03 102.16 270 top
NOREF#2978  -  []  47.41 26.04 0 top
NOREF#2979  -  []  15.32 106.12 0 top
NOREF#2980  -  []  132.72 6.93 90 top
NOREF#2981  -  []  51.59 56.92 0 top
NOREF#2982  -  []  93.64 110.03 270 top
NOREF#2983  -  []  111.53 62.61 90 top
NOREF#2984  -  []  57.78 52.81 270 top
NOREF#2985  -  []  127.97 27.55 0 top
NOREF#2986  -  []  20.85 28.22 90 top
NOREF#2987  -  []  12.57 80.04 90 top
NOREF#2988  -  []  53.07 28.19 0 top
NOREF#2989  -  []  115.76 25.58 0 top
NOREF#2990  -  []  143.28 103.38 0 top
NOREF#2991  -  []  126.57 50.53 90 top
NOREF#2992  -  []  157.42 112.01 0 top
NOREF#2993  -  []  41 99.92 0 top
NOREF#2994  -  []  72.57 81.66 0 top
NOREF#2995  -  []  135.2 44.56 0 top
NOREF#2996  -  []  82.5 51.38 90 top
NOREF#2997  -  []  73.14 27.3 0 top
NOREF#2998  -  []  31.17 33.22 90 top
NOREF#2999  -  []  107.9 28.69 0 top
NOREF#3000  -  []  94.69 18.72 0 top
NOREF#3001  -  []  111.49 23.8 0 top
NOREF#3002  -  []  120.51 28.83 0 top
NOREF#3003  -  []  101.22 17.4 90 top
NOREF#3004  -  []  83.39 34.24 90 top
NOREF#3005  -  []  132.05 72.09 0 top
NOREF#3006  -  []  66.37 0.56 90 top
NOREF#3007  -  []  44.52 115.27 90 top
NOREF#3008  -  []  84.12 58.42 270 top
NOREF#3009  -  []  68.53 110.06 270 top
NOREF#3010  -  []  127.33 37.77 0 top
NOREF#3011  -  []  0 0 0 top
NOREF#3012  -  []  99.32 52.51 90 top
NOREF#3013  -  []  137.62 120.47 0 top
NOREF#3014  -  []  37.97 36.31 90 top
NOREF#3015  -  []  75.01 100.28 0 top
NOREF#3016  -  []  34.11 17.09 90 top
NOREF#3017  -  []  124.12 47.19 0 top
NOREF#3018  -  []  130.58 173.46 0 top
NOREF#3019  -  []  17.02 109.26 90 top
NOREF#3020  -  []  100.32 26.85 0 top
NOREF#3021  -  []  134.06 69.93 0 top
NOREF#3022  -  []  82.7 105.16 90 top
NOREF#3023  -  []  140.59 78.23 90 top
NOREF#3024  -  []  56.79 37.52 0 top
NOREF#3025  -  []  53.31 49.81 0 top
NOREF#3026  -  []  103.12 63.75 90 top
NOREF#3027  -  []  17.98 31.61 90 top
NOREF#3028  -  []  135.76 131.28 270 top
NOREF#3029  -  []  33.35 41.45 0 top
NOREF#3030  -  []  52.18 37.72 0 top
NOREF#3031  -  []  150.29 134.54 270 top
NOREF#3032  -  []  84.41 98.9 0 top
NOREF#3033  -  []  50.62 77.9 270 top
NOREF#3034  -  []  98.73 100.71 0 top
NOREF#3035  -  []  6.63 108.36 90 top
NOREF#3036  -  []  66.84 95.21 270 top
NOREF#3037  -  []  6.79 164.35 90 top
NOREF#3038  -  []  84.2 31.58 270 top
NOREF#3039  -  []  59.89 102.08 270 top
NOREF#3040  -  []  52.18 101.94 270 top
NOREF#3041  -  []  68.87 0.16 0 top
NOREF#3042  -  []  129.27 54.81 90 top
NOREF#3043  -  []  142.52 99.09 90 top
NOREF#3044  -  []  152.2 192.23 90 top
NOREF#3045  -  []  80.47 18.72 0 top
NOREF#3046  -  []  145.44 102.23 0 top
NOREF#3047  -  []  75.46 104.27 0 top
NOREF#3048  -  []  77.42 18.72 270 top
NOREF#3049  -  []  94.69 36.23 90 top
NOREF#3050  -  []  133.3 26 90 top
NOREF#3051  -  []  141.27 61.21 0 top
NOREF#3052  -  []  127.53 65.43 90 top
NOREF#3053  -  []  45.92 144.7 0 top
NOREF#3054  -  []  118.61 29.21 0 top
NOREF#3055  -  []  72.47 53.51 270 top
NOREF#3056  -  []  85.17 27.7 270 top
NOREF#3057  -  []  128.91 143.5 270 top
NOREF#3058  -  []  64.16 76.73 90 top
NOREF#3059  -  []  120.47 32.65 0 top
NOREF#3060  -  []  62.23 67.44 270 top
NOREF#3061  -  []  130.42 24.18 0 top
NOREF#3062  -  []  56.18 146.89 90 top
NOREF#3063  -  []  113.14 25.58 0 top
NOREF#3064  -  []  47.36 33.78 0 top
NOREF#3065  -  []  146.79 107.77 0 top
NOREF#3066  -  []  57.81 37.52 0 top
NOREF#3067  -  []  138.51 28.91 0 top
NOREF#3068  -  []  130.54 44.03 90 top
NOREF#3069  -  []  102.87 139.42 270 top
NOREF#3070  -  []  28.87 0.16 0 top
NOREF#3071  -  []  150.88 176.4 90 top
NOREF#3072  -  []  97.87 97.92 0 top
NOREF#3073  -  []  65.18 156.97 0 top
NOREF#3074  -  []  109.68 27.17 0 top
NOREF#3075  -  []  103.25 52.51 90 top
NOREF#3076  -  []  55.42 29.35 270 top
NOREF#3077  -  []  64.31 26.99 270 top
NOREF#3078  -  []  141.35 17.44 90 top
NOREF#3079  -  []  61.24 181.84 90 top
NOREF#3080  -  []  24.93 28.5 90 top
NOREF#3081  -  []  66.5 157.94 0 top
NOREF#3082  -  []  65.43 177.04 0 top
NOREF#3083  -  []  129.53 44.02 90 top
NOREF#3084  -  []  88.39 92.63 270 top
NOREF#3085  -  []  144.7 102.67 270 top
NOREF#3086  -  []  100.34 93.55 90 top
NOREF#3087  -  []  5.87 83.72 90 top
NOREF#3088  -  []  135.19 88.39 0 top
NOREF#3089  -  []  99.24 105.79 0 top
NOREF#3090  -  []  53.75 78.16 0 top
NOREF#3091  -  []  55.19 54.56 0 top
NOREF#3092  -  []  46.87 5.46 270 top
NOREF#3093  -  []  58.24 167.18 0 top
NOREF#3094  -  []  38.81 36.23 90 top
NOREF#3095  -  []  142.04 71.58 90 top
NOREF#3096  -  []  98.42 95.51 90 top
NOREF#3097  -  []  115.9 25.62 90 top
NOREF#3098  -  []  18.67 179.32 0 top
NOREF#3099  -  []  58.08 103.59 0 top
NOREF#3100  -  []  48.13 12.52 0 top
NOREF#3101  -  []  132.99 88.65 0 top
NOREF#3102  -  []  139.27 178.77 0 top
NOREF#3103  -  []  47.96 140.28 0 top
NOREF#3104  -  []  50.44 99.31 270 top
NOREF#3105  -  []  55.07 71.83 90 top
NOREF#3106  -  []  158.7 111.3 270 top
NOREF#3107  -  []  4.95 84.86 90 top
NOREF#3108  -  []  74.5 18.72 270 top
NOREF#3109  -  []  24.17 28.5 90 top
NOREF#3110  -  []  55.62 73.14 90 top
NOREF#3111  -  []  126.57 52.18 90 top
NOREF#3112  -  []  45.42 60.53 0 top
NOREF#3113  -  []  73.25 84.38 270 top
NOREF#3114  -  []  34.42 36.59 270 top
NOREF#3115  -  []  80.77 18.38 270 top
NOREF#3116  -  []  110.29 27.44 270 top
NOREF#3117  -  []  140.87 107.7 90 top
NOREF#3118  -  []  69.19 84.48 0 top
NOREF#3119  -  []  146.37 0.56 90 top
NOREF#3120  -  []  83.9 32.65 0 top
NOREF#3121  -  []  73.65 23.8 0 top
NOREF#3122  -  []  82.91 53.54 0 top
NOREF#3123  -  []  84.87 2.26 0 top
NOREF#3124  -  []  65.61 28.97 0 top
NOREF#3125  -  []  67.51 25.73 0 top
NOREF#3126  -  []  47.32 33.92 0 top
NOREF#3127  -  []  8.38 109.37 90 top
NOREF#3128  -  []  71.49 36.63 270 top
NOREF#3129  -  []  76.28 87.3 270 top
NOREF#3130  -  []  126.19 29.07 0 top
NOREF#3131  -  []  2.92 54.14 0 top
NOREF#3132  -  []  89.61 29.98 270 top
NOREF#3133  -  []  54.85 26.54 0 top
NOREF#3134  -  []  96.52 96.79 0 top
NOREF#3135  -  []  142.62 70.6 90 top
NOREF#3136  -  []  75.01 103.84 0 top
NOREF#3137  -  []  47.37 30.61 90 top
NOREF#3138  -  []  116.41 18.72 0 top
NOREF#3139  -  []  134.19 26 90 top
NOREF#3140  -  []  123.77 47.5 0 top
NOREF#3141  -  []  22.05 38.9 90 top
NOREF#3142  -  []  7.69 170.45 90 top
NOREF#3143  -  []  76.07 53.98 270 top
NOREF#3144  -  []  115.52 122.61 270 top
NOREF#3145  -  []  43.46 68.33 0 top
NOREF#3146  -  []  58.99 112.99 270 top
NOREF#3147  -  []  61.79 63.58 90 top
NOREF#3148  -  []  14.1 80.54 90 top
NOREF#3149  -  []  121.21 154.36 270 top
NOREF#3150  -  []  118.24 174.12 0 top
NOREF#3151  -  []  6.17 117.2 90 top
NOREF#3152  -  []  107.07 140 270 top
NOREF#3153  -  []  66.22 30.4 270 top
NOREF#3154  -  []  76.89 103.56 270 top
NOREF#3155  -  []  118.49 153.89 270 top
NOREF#3156  -  []  53.29 77.84 90 top
NOREF#3157  -  []  96.37 95 0 top
NOREF#3158  -  []  95.4 99.34 90 top
NOREF#3159  -  []  107.94 31.62 0 top
NOREF#3160  -  []  25.68 54.94 0 top
NOREF#3161  -  []  33.9 33.48 90 top
NOREF#3162  -  []  36.53 27.17 0 top
NOREF#3163  -  []  93.04 176.73 0 top
NOREF#3164  -  []  34.42 31.51 0 top
NOREF#3165  -  []  10.06 74.55 0 top
NOREF#3166  -  []  89.53 33.52 90 top
NOREF#3167  -  []  134.95 135.71 0 top
NOREF#3168  -  []  134.82 178.61 0 top
NOREF#3169  -  []  150.91 191.39 0 top
NOREF#3170  -  []  120.62 68.4 90 top
NOREF#3171  -  []  65.35 25.73 90 top
NOREF#3172  -  []  37.07 23.8 270 top
NOREF#3173  -  []  136.53 184.11 270 top
NOREF#3174  -  []  116.64 73.86 90 top
NOREF#3175  -  []  111.63 23.76 270 top
NOREF#3176  -  []  79.65 41 270 top
NOREF#3177  -  []  74.4 87.3 0 top
NOREF#3178  -  []  62.37 33.86 90 top
NOREF#3179  -  []  50.9 98.88 0 top
NOREF#3180  -  []  58.12 103.45 0 top
NOREF#3181  -  []  130.35 160.1 90 top
NOREF#3182  -  []  45.76 62.23 0 top
NOREF#3183  -  []  150.88 176.91 0 top
NOREF#3184  -  []  65.1 67.77 0 top
NOREF#3185  -  []  28.52 38.43 90 top
NOREF#3186  -  []  65.65 28.19 0 top
NOREF#3187  -  []  152.78 121.77 270 top
NOREF#3188  -  []  16.48 106.12 90 top
NOREF#3189  -  []  131.05 42.24 0 top
NOREF#3190  -  []  129.92 160.55 90 top
NOREF#3191  -  []  96.72 138 0 top
NOREF#3192  -  []  60.9 25.58 90 top
NOREF#3193  -  []  21.79 38.86 90 top
NOREF#3194  -  []  128.22 173.94 0 top
NOREF#3195  -  []  75.46 105.54 0 top
NOREF#3196  -  []  101.73 104.24 270 top
NOREF#3197  -  []  126.9 159.13 0 top
NOREF#3198  -  []  48.59 27.06 0 top
NOREF#3199  -  []  93.04 176.73 90 top
NOREF#3200  -  []  134.06 150.95 0 top
NOREF#3201  -  []  124.28 65.23 90 top
NOREF#3202  -  []  119.53 88.14 0 top
NOREF#3203  -  []  19.38 130.53 90 top
NOREF#3204  -  []  66.55 84.07 90 top
NOREF#3205  -  []  100.66 17.09 90 top
NOREF#3206  -  []  143.28 102.23 0 top
NOREF#3207  -  []  70.94 30.62 270 top
NOREF#3208  -  []  125.73 181.7 270 top
NOREF#3209  -  []  119.94 43.28 270 top
NOREF#3210  -  []  132.36 85.6 90 top
NOREF#3211  -  []  63.25 176.78 0 top
NOREF#3212  -  []  70.31 38.37 0 top
NOREF#3213  -  []  131.01 36.58 90 top
NOREF#3214  -  []  135.7 89.66 0 top
NOREF#3215  -  []  60.83 68.96 0 top
NOREF#3216  -  []  134.06 148.16 90 top
NOREF#3217  -  []  61.19 71.45 0 top
NOREF#3218  -  []  54.94 76 270 top
NOREF#3219  -  []  69.6 80.39 270 top
NOREF#3220  -  []  71.32 31.76 270 top
NOREF#3221  -  []  56.72 94.77 270 top
NOREF#3222  -  []  144.09 17.09 90 top
NOREF#3223  -  []  117.84 34.52 0 top
NOREF#3224  -  []  66.37 91.11 90 top
NOREF#3225  -  []  73.56 78.49 0 top
NOREF#3226  -  []  60.16 91.68 270 top
NOREF#3227  -  []  134.61 42.24 0 top
NOREF#3228  -  []  54.05 77.81 270 top
NOREF#3229  -  []  126.99 40.89 0 top
NOREF#3230  -  []  146.96 87.63 90 top
NOREF#3231  -  []  76.02 18.72 0 top
NOREF#3232  -  []  55.5 75.68 90 top
NOREF#3233  -  []  91.77 60.91 270 top
NOREF#3234  -  []  126.9 154.18 0 top
NOREF#3235  -  []  112.73 36.2 90 top
NOREF#3236  -  []  83.63 54.61 90 top
NOREF#3237  -  []  156.7 55.37 90 top
NOREF#3238  -  []  145.44 104.52 0 top
NOREF#3239  -  []  26.37 0.56 90 top
NOREF#3240  -  []  -9.6 77.34 0 top
NOREF#3241  -  []  21.74 40.18 0 top
NOREF#3242  -  []  134.37 145.8 0 top
NOREF#3243  -  []  47.45 139.12 90 top
NOREF#3244  -  []  131.27 178.23 270 top
NOREF#3245  -  []  141.22 149.52 90 top
NOREF#3246  -  []  82.4 24.99 90 top
NOREF#3247  -  []  132.72 175.01 90 top
NOREF#3248  -  []  49.01 112.13 270 top
NOREF#3249  -  []  127.99 67.01 0 top
NOREF#3250  -  []  55.07 73.46 0 top
NOREF#3251  -  []  17.77 36.4 0 top
NOREF#3252  -  []  98.17 18.41 90 top
NOREF#3253  -  []  151.78 101.89 270 top
NOREF#3254  -  []  140.72 177.83 270 top
NOREF#3255  -  []  24.71 65.1 0 top
NOREF#3256  -  []  91.39 31.23 90 top
NOREF#3257  -  []  43.47 62.36 0 top
NOREF#3258  -  []  97.42 34.47 270 top
NOREF#3259  -  []  44.17 94.02 270 top
NOREF#3260  -  []  156.54 176.48 90 top
NOREF#3261  -  []  33.9 34.09 0 top
NOREF#3262  -  []  132.79 127.3 0 top
NOREF#3263  -  []  56.39 82.63 0 top
NOREF#3264  -  []  137.16 36.35 90 top
NOREF#3265  -  []  137.27 45.34 0 top
NOREF#3266  -  []  61.75 181.84 90 top
NOREF#3267  -  []  16.09 170.45 0 top
NOREF#3268  -  []  75.46 103.12 0 top
NOREF#3269  -  []  141.3 89.36 90 top
NOREF#3270  -  []  71.6 31.79 270 top
NOREF#3271  -  []  140.63 47.5 0 top
NOREF#3272  -  []  124.45 42.55 0 top
NOREF#3273  -  []  39.45 64.21 0 top
NOREF#3274  -  []  18.75 108.92 0 top
NOREF#3275  -  []  83.9 33.29 0 top
NOREF#3276  -  []  103.18 67.09 90 top
NOREF#3277  -  []  144.73 122.1 0 top
NOREF#3278  -  []  52.1 103.96 0 top
NOREF#3279  -  []  132.51 125.43 90 top
NOREF#3280  -  []  118.19 154.23 270 top
NOREF#3281  -  []  47.62 186.94 90 top
NOREF#3282  -  []  24.71 53.8 0 top
NOREF#3283  -  []  146 120.47 0 top
NOREF#3284  -  []  66.04 85.09 270 top
NOREF#3285  -  []  73.1 27.17 0 top
NOREF#3286  -  []  128.91 12.52 0 top
NOREF#3287  -  []  141.52 139.83 0 top
NOREF#3288  -  []  84.19 100.36 0 top
NOREF#3289  -  []  45.42 67.36 270 top
NOREF#3290  -  []  35.67 192.48 0 top
NOREF#3291  -  []  39.83 123.37 0 top
NOREF#3292  -  []  134.82 56.85 0 top
NOREF#3293  -  []  58.99 102.12 270 top
NOREF#3294  -  []  20.37 29.32 90 top
NOREF#3295  -  []  85.72 110.21 270 top
NOREF#3296  -  []  136.83 126.44 90 top
NOREF#3297  -  []  149.2 69.16 0 top
NOREF#3298  -  []  119.61 104.7 0 top
NOREF#3299  -  []  98.7 101.6 0 top
NOREF#3300  -  []  100.69 24.99 90 top
NOREF#3301  -  []  71.36 31.62 0 top
NOREF#3302  -  []  61.85 82.93 90 top
NOREF#3303  -  []  45.45 27.61 0 top
NOREF#3304  -  []  129.26 71.3 0 top
NOREF#3305  -  []  43.13 62.05 0 top
NOREF#3306  -  []  83.9 28.33 0 top
NOREF#3307  -  []  54.56 113.3 0 top
NOREF#3308  -  []  90.22 27.42 90 top
NOREF#3309  -  []  44.87 2.26 90 top
NOREF#3310  -  []  92.93 99.68 90 top
NOREF#3311  -  []  133.21 53.64 0 top
NOREF#3312  -  []  30.61 34.54 90 top
NOREF#3313  -  []  140.03 104.19 270 top
NOREF#3314  -  []  73.1 31.51 0 top
NOREF#3315  -  []  115.25 109.22 0 top
NOREF#3316  -  []  121.69 73.86 0 top
NOREF#3317  -  []  104.06 26.78 90 top
NOREF#3318  -  []  134.72 90.09 0 top
NOREF#3319  -  []  109.47 35.97 90 top
NOREF#3320  -  []  126.35 37.01 0 top
NOREF#3321  -  []  126.19 31 270 top
NOREF#3322  -  []  126.44 157.15 270 top
NOREF#3323  -  []  145.29 173.2 270 top
NOREF#3324  -  []  64.11 24.99 90 top
NOREF#3325  -  []  53.85 112.95 270 top
NOREF#3326  -  []  129.49 160.1 0 top
NOREF#3327  -  []  17.98 33.26 90 top
NOREF#3328  -  []  53.98 103.96 270 top
NOREF#3329  -  []  57.66 75.65 270 top
NOREF#3330  -  []  56.69 83.91 270 top
NOREF#3331  -  []  146.41 87.33 90 top
NOREF#3332  -  []  20.57 39.23 90 top
NOREF#3333  -  []  77.53 26.19 270 top
NOREF#3334  -  []  36.56 26.54 0 top
NOREF#3335  -  []  123.65 44.25 0 top
NOREF#3336  -  []  65.61 31.93 0 top
NOREF#3337  -  []  34.28 36.63 270 top
NOREF#3338  -  []  89.92 36.59 270 top
NOREF#3339  -  []  64.31 27.75 270 top
NOREF#3340  -  []  86.14 26.04 0 top
NOREF#3341  -  []  99.69 98.22 0 top
NOREF#3342  -  []  83.64 26.34 0 top
NOREF#3343  -  []  124.09 46.94 90 top
NOREF#3344  -  []  50.52 46.94 0 top
NOREF#3345  -  []  136.86 29.45 0 top
NOREF#3346  -  []  51.46 91.25 90 top
NOREF#3347  -  []  132.69 88.09 0 top
NOREF#3348  -  []  83.16 109.55 0 top
NOREF#3349  -  []  101.93 26.34 0 top
NOREF#3350  -  []  38.98 23.8 270 top
NOREF#3351  -  []  44.97 34.52 270 top
NOREF#3352  -  []  120.4 181.48 90 top
NOREF#3353  -  []  143.51 120.78 90 top
NOREF#3354  -  []  126.37 0.56 90 top
NOREF#3355  -  []  128.65 24.14 270 top
NOREF#3356  -  []  75.01 100.89 0 top
NOREF#3357  -  []  146.33 140.36 90 top
NOREF#3358  -  []  120.04 103.28 90 top
NOREF#3359  -  []  65.61 32.65 0 top
NOREF#3360  -  []  50.06 50.06 0 top
NOREF#3361  -  []  146.13 171.78 0 top
NOREF#3362  -  []  156.7 55.37 90 top
NOREF#3363  -  []  140.54 126.19 0 top
NOREF#3364  -  []  26.28 37.39 0 top
NOREF#3365  -  []  37.13 29.35 270 top
NOREF#3366  -  []  27.46 126.87 0 top
NOREF#3367  -  []  68.35 150.75 0 top
NOREF#3368  -  []  140.15 176.67 0 top
NOREF#3369  -  []  60.83 82.93 90 top
NOREF#3370  -  []  61.04 169.98 0 top
NOREF#3371  -  []  28.83 36.94 90 top
NOREF#3372  -  []  70.48 108.33 0 top
NOREF#3373  -  []  45.72 67.31 0 top
NOREF#3374  -  []  125.12 131.83 0 top
NOREF#3375  -  []  18.69 106.58 90 top
NOREF#3376  -  []  137.67 121.79 270 top
NOREF#3377  -  []  14.94 30.8 0 top
NOREF#3378  -  []  125.35 55.85 270 top
NOREF#3379  -  []  101.73 106.65 270 top
NOREF#3380  -  []  49.1 56.92 0 top
NOREF#3381  -  []  57.87 95.57 0 top
NOREF#3382  -  []  73.81 108.61 90 top
NOREF#3383  -  []  41.27 112.12 270 top
NOREF#3384  -  []  55.75 54.86 90 top
NOREF#3385  -  []  150.88 191.13 90 top
NOREF#3386  -  []  114.25 25.62 90 top
NOREF#3387  -  []  151.38 121.79 270 top
NOREF#3388  -  []  100.34 93.55 0 top
NOREF#3389  -  []  145.44 105.66 0 top
NOREF#3390  -  []  80.52 33.9 90 top
NOREF#3391  -  []  37.49 96.52 0 top
NOREF#3392  -  []  86.44 51.38 90 top
NOREF#3393  -  []  86.44 92.41 270 top
NOREF#3394  -  []  125.12 130.18 0 top
NOREF#3395  -  []  20.22 71.25 0 top
NOREF#3396  -  []  17.98 32.63 0 top
NOREF#3397  -  []  68.99 108.94 0 top
NOREF#3398  -  []  18.8 109.22 90 top
NOREF#3399  -  []  128.78 42.28 90 top
NOREF#3400  -  []  135.15 88.14 90 top
NOREF#3401  -  []  58.62 82.93 90 top
NOREF#3402  -  []  39.9 63.5 0 top
NOREF#3403  -  []  18.26 34.71 270 top
NOREF#3404  -  []  58.43 113.3 0 top
NOREF#3405  -  []  137.24 46.47 0 top
NOREF#3406  -  []  3.2 54.94 0 top
NOREF#3407  -  []  82.6 29.35 270 top
NOREF#3408  -  []  54.85 27.3 0 top
NOREF#3409  -  []  30.59 31.11 0 top
NOREF#3410  -  []  138.02 89.46 0 top
NOREF#3411  -  []  118.44 35.51 90 top
NOREF#3412  -  []  86.39 52.7 0 top
NOREF#3413  -  []  50.55 25.78 90 top
NOREF#3414  -  []  150.57 179.78 0 top
NOREF#3415  -  []  89.65 31.62 0 top
NOREF#3416  -  []  52.88 150.32 90 top
NOREF#3417  -  []  17.65 34.43 0 top
NOREF#3418  -  []  152.86 20.99 270 top
NOREF#3419  -  []  138.85 26.42 0 top
NOREF#3420  -  []  99.87 139.88 270 top
NOREF#3421  -  []  103.58 139.88 0 top
NOREF#3422  -  []  95.86 108.03 90 top
NOREF#3423  -  []  135.66 89.41 0 top
NOREF#3424  -  []  135.08 18.72 0 top
NOREF#3425  -  []  34.67 17.4 90 top
NOREF#3426  -  []  52.73 78.16 270 top
NOREF#3427  -  []  126.35 34.03 90 top
NOREF#3428  -  []  123.19 41.63 90 top
NOREF#3429  -  []  124.23 101.35 0 top
NOREF#3430  -  []  103.25 59.94 90 top
NOREF#3431  -  []  76.89 101.14 270 top
NOREF#3432  -  []  84.07 57.1 90 top
NOREF#3433  -  []  131.09 125.86 0 top
NOREF#3434  -  []  66.84 100.29 0 top
NOREF#3435  -  []  36.56 31.37 0 top
NOREF#3436  -  []  134.82 48.37 0 top
NOREF#3437  -  []  51.73 109.55 270 top
NOREF#3438  -  []  74.42 23.76 270 top
NOREF#3439  -  []  75.01 106.25 0 top
NOREF#3440  -  []  107.43 36.63 0 top
NOREF#3441  -  []  41 90.27 0 top
NOREF#3442  -  []  81.03 18.41 270 top
NOREF#3443  -  []  150.8 122.1 270 top
NOREF#3444  -  []  133.36 93.04 90 top
NOREF#3445  -  []  53.31 31.79 270 top
NOREF#3446  -  []  124.92 56.31 270 top
NOREF#3447  -  []  101.3 107.65 0 top
NOREF#3448  -  []  38.96 102.44 0 top
NOREF#3449  -  []  142.57 70.92 0 top
NOREF#3450  -  []  50.89 91.39 0 top
NOREF#3451  -  []  129.15 24.18 270 top
NOREF#3452  -  []  126.19 28.71 270 top
NOREF#3453  -  []  138.38 33.96 0 top
NOREF#3454  -  []  11.25 109.3 90 top
NOREF#3455  -  []  89.31 106.68 90 top
NOREF#3456  -  []  141.25 148.16 90 top
NOREF#3457  -  []  75.69 23.76 270 top
NOREF#3458  -  []  98.04 34.43 270 top
NOREF#3459  -  []  107.57 32.42 0 top
NOREF#3460  -  []  53.04 27.7 0 top
NOREF#3461  -  []  144.98 187.02 90 top
NOREF#3462  -  []  66.88 100.91 0 top
NOREF#3463  -  []  61.79 67.9 90 top
NOREF#3464  -  []  121.11 170.13 0 top
NOREF#3465  -  []  145.31 175.51 0 top
NOREF#3466  -  []  34.09 28.65 90 top
NOREF#3467  -  []  34.75 30.34 0 top
NOREF#3468  -  []  53.04 30.34 0 top
NOREF#3469  -  []  11 109.33 90 top
NOREF#3470  -  []  115.77 73.86 0 top
NOREF#3471  -  []  37.48 36.27 90 top
NOREF#3472  -  []  95 25.62 90 top
NOREF#3473  -  []  54.76 147.32 0 top
NOREF#3474  -  []  48.41 138.43 0 top
NOREF#3475  -  []  19.43 81.28 270 top
NOREF#3476  -  []  150.57 177.5 0 top
NOREF#3477  -  []  138.3 17.44 90 top
NOREF#3478  -  []  19.76 34.43 0 top
NOREF#3479  -  []  59.13 91.64 270 top
NOREF#3480  -  []  36.27 40.94 0 top
NOREF#3481  -  []  120.09 33.58 0 top
NOREF#3482  -  []  53.75 49.35 270 top
NOREF#3483  -  []  17.48 107.26 90 top
NOREF#3484  -  []  104.26 18.41 90 top
NOREF#3485  -  []  25.03 37.52 0 top
NOREF#3486  -  []  55.83 18.72 0 top
NOREF#3487  -  []  35.94 17.44 90 top
NOREF#3488  -  []  102.36 29.95 270 top
NOREF#3489  -  []  149.2 73.86 0 top
NOREF#3490  -  []  101.93 28.52 0 top
NOREF#3491  -  []  102.24 31.62 90 top
NOREF#3492  -  []  49.81 107.95 0 top
NOREF#3493  -  []  51.84 76.07 0 top
NOREF#3494  -  []  72.21 144.32 270 top
NOREF#3495  -  []  135.24 34.85 0 top
NOREF#3496  -  []  132.69 88.09 90 top
NOREF#3497  -  []  35.36 27.42 90 top
NOREF#3498  -  []  39.52 37.52 0 top
NOREF#3499  -  []  136.53 63.5 0 top
NOREF#3500  -  []  152.35 120.35 0 top
NOREF#3501  -  []  131.7 44.59 270 top
NOREF#3502  -  []  145.64 100.51 0 top
NOREF#3503  -  []  66.22 32.37 90 top
NOREF#3504  -  []  137.24 44.56 90 top
NOREF#3505  -  []  91.62 35.51 90 top
NOREF#3506  -  []  124.41 42.05 270 top
NOREF#3507  -  []  139.83 127.61 270 top
NOREF#3508  -  []  107.94 29.84 0 top
NOREF#3509  -  []  65.67 25.78 90 top
NOREF#3510  -  []  56.77 168.16 0 top
NOREF#3511  -  []  133.68 174.57 90 top
NOREF#3512  -  []  93.34 23.76 270 top
NOREF#3513  -  []  149.17 71.17 0 top
NOREF#3514  -  []  137.03 34.86 270 top
NOREF#3515  -  []  65.66 33.12 270 top
NOREF#3516  -  []  61.2 36.02 90 top
NOREF#3517  -  []  121.16 17.44 90 top
NOREF#3518  -  []  89 107.24 270 top
NOREF#3519  -  []  142.82 105.23 0 top
NOREF#3520  -  []  104.01 138.46 90 top
NOREF#3521  -  []  108.58 153.42 0 top
NOREF#3522  -  []  60.64 102.12 270 top
NOREF#3523  -  []  89.28 32.14 90 top
NOREF#3524  -  []  134.37 54.98 90 top
NOREF#3525  -  []  41 99.92 90 top
NOREF#3526  -  []  66.33 97.75 270 top
NOREF#3527  -  []  59.75 101.51 0 top
NOREF#3528  -  []  53.04 31.76 270 top
NOREF#3529  -  []  85.06 101.55 0 top
NOREF#3530  -  []  124.41 50.41 0 top
NOREF#3531  -  []  109.2 151.47 0 top
NOREF#3532  -  []  16.5 36.4 0 top
NOREF#3533  -  []  134.26 149.76 0 top
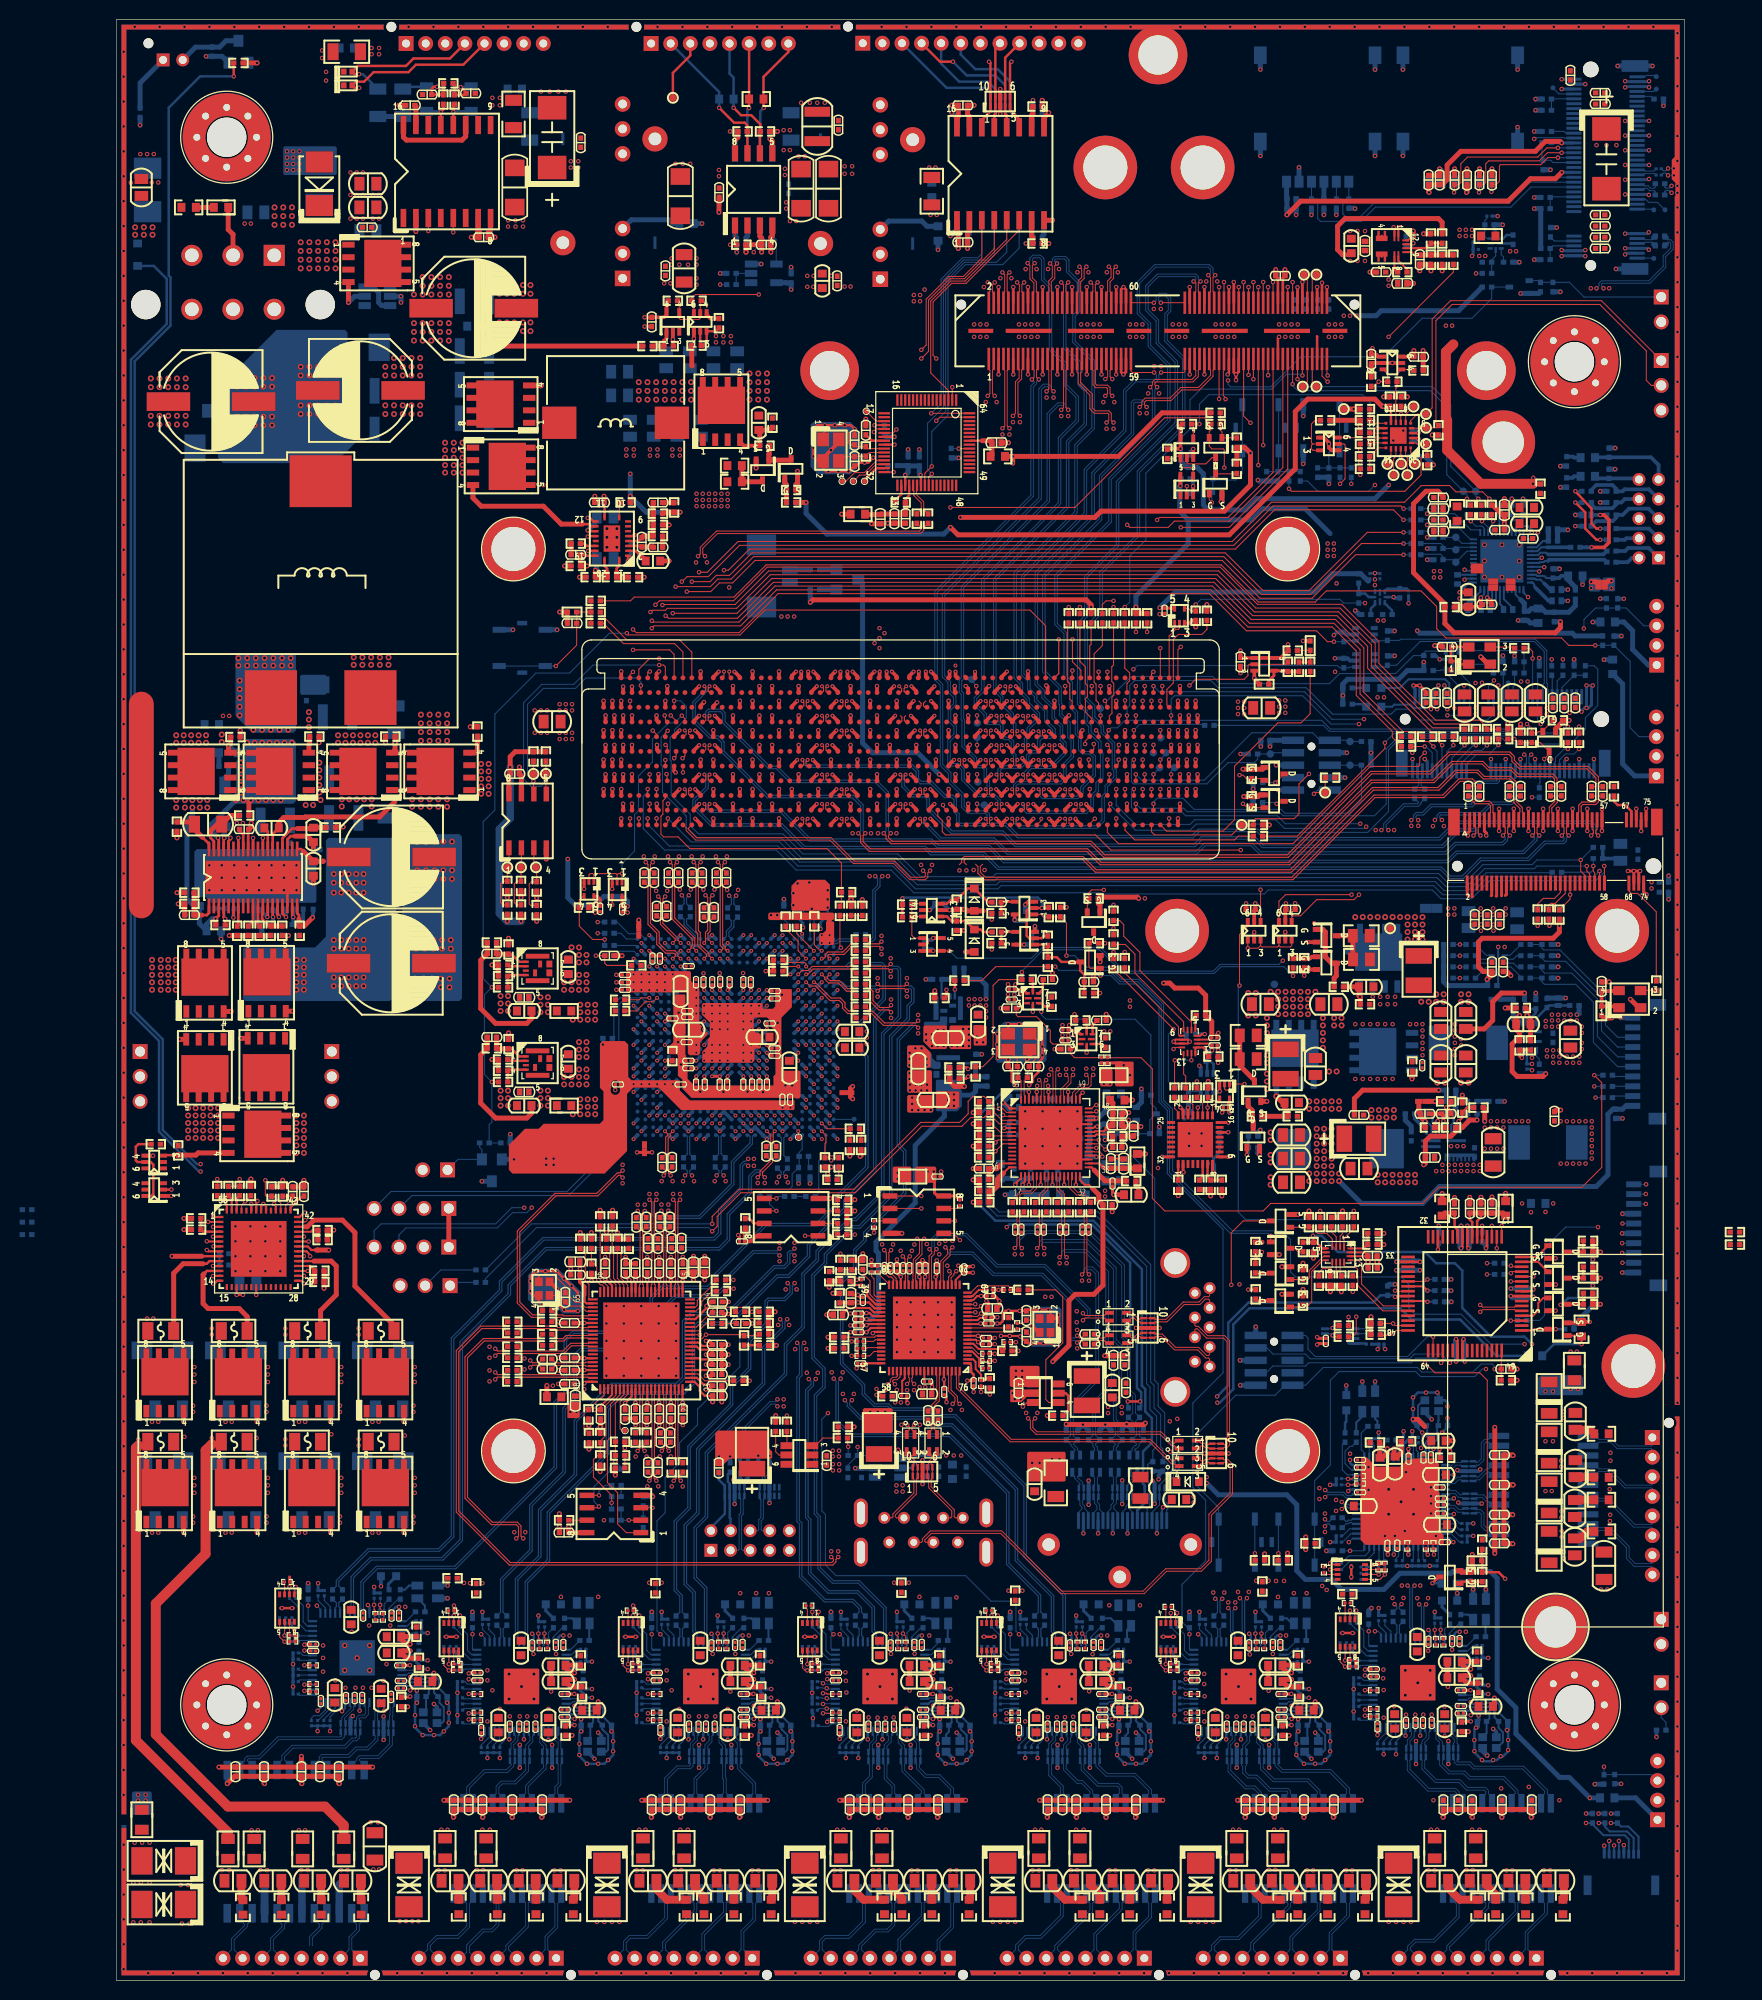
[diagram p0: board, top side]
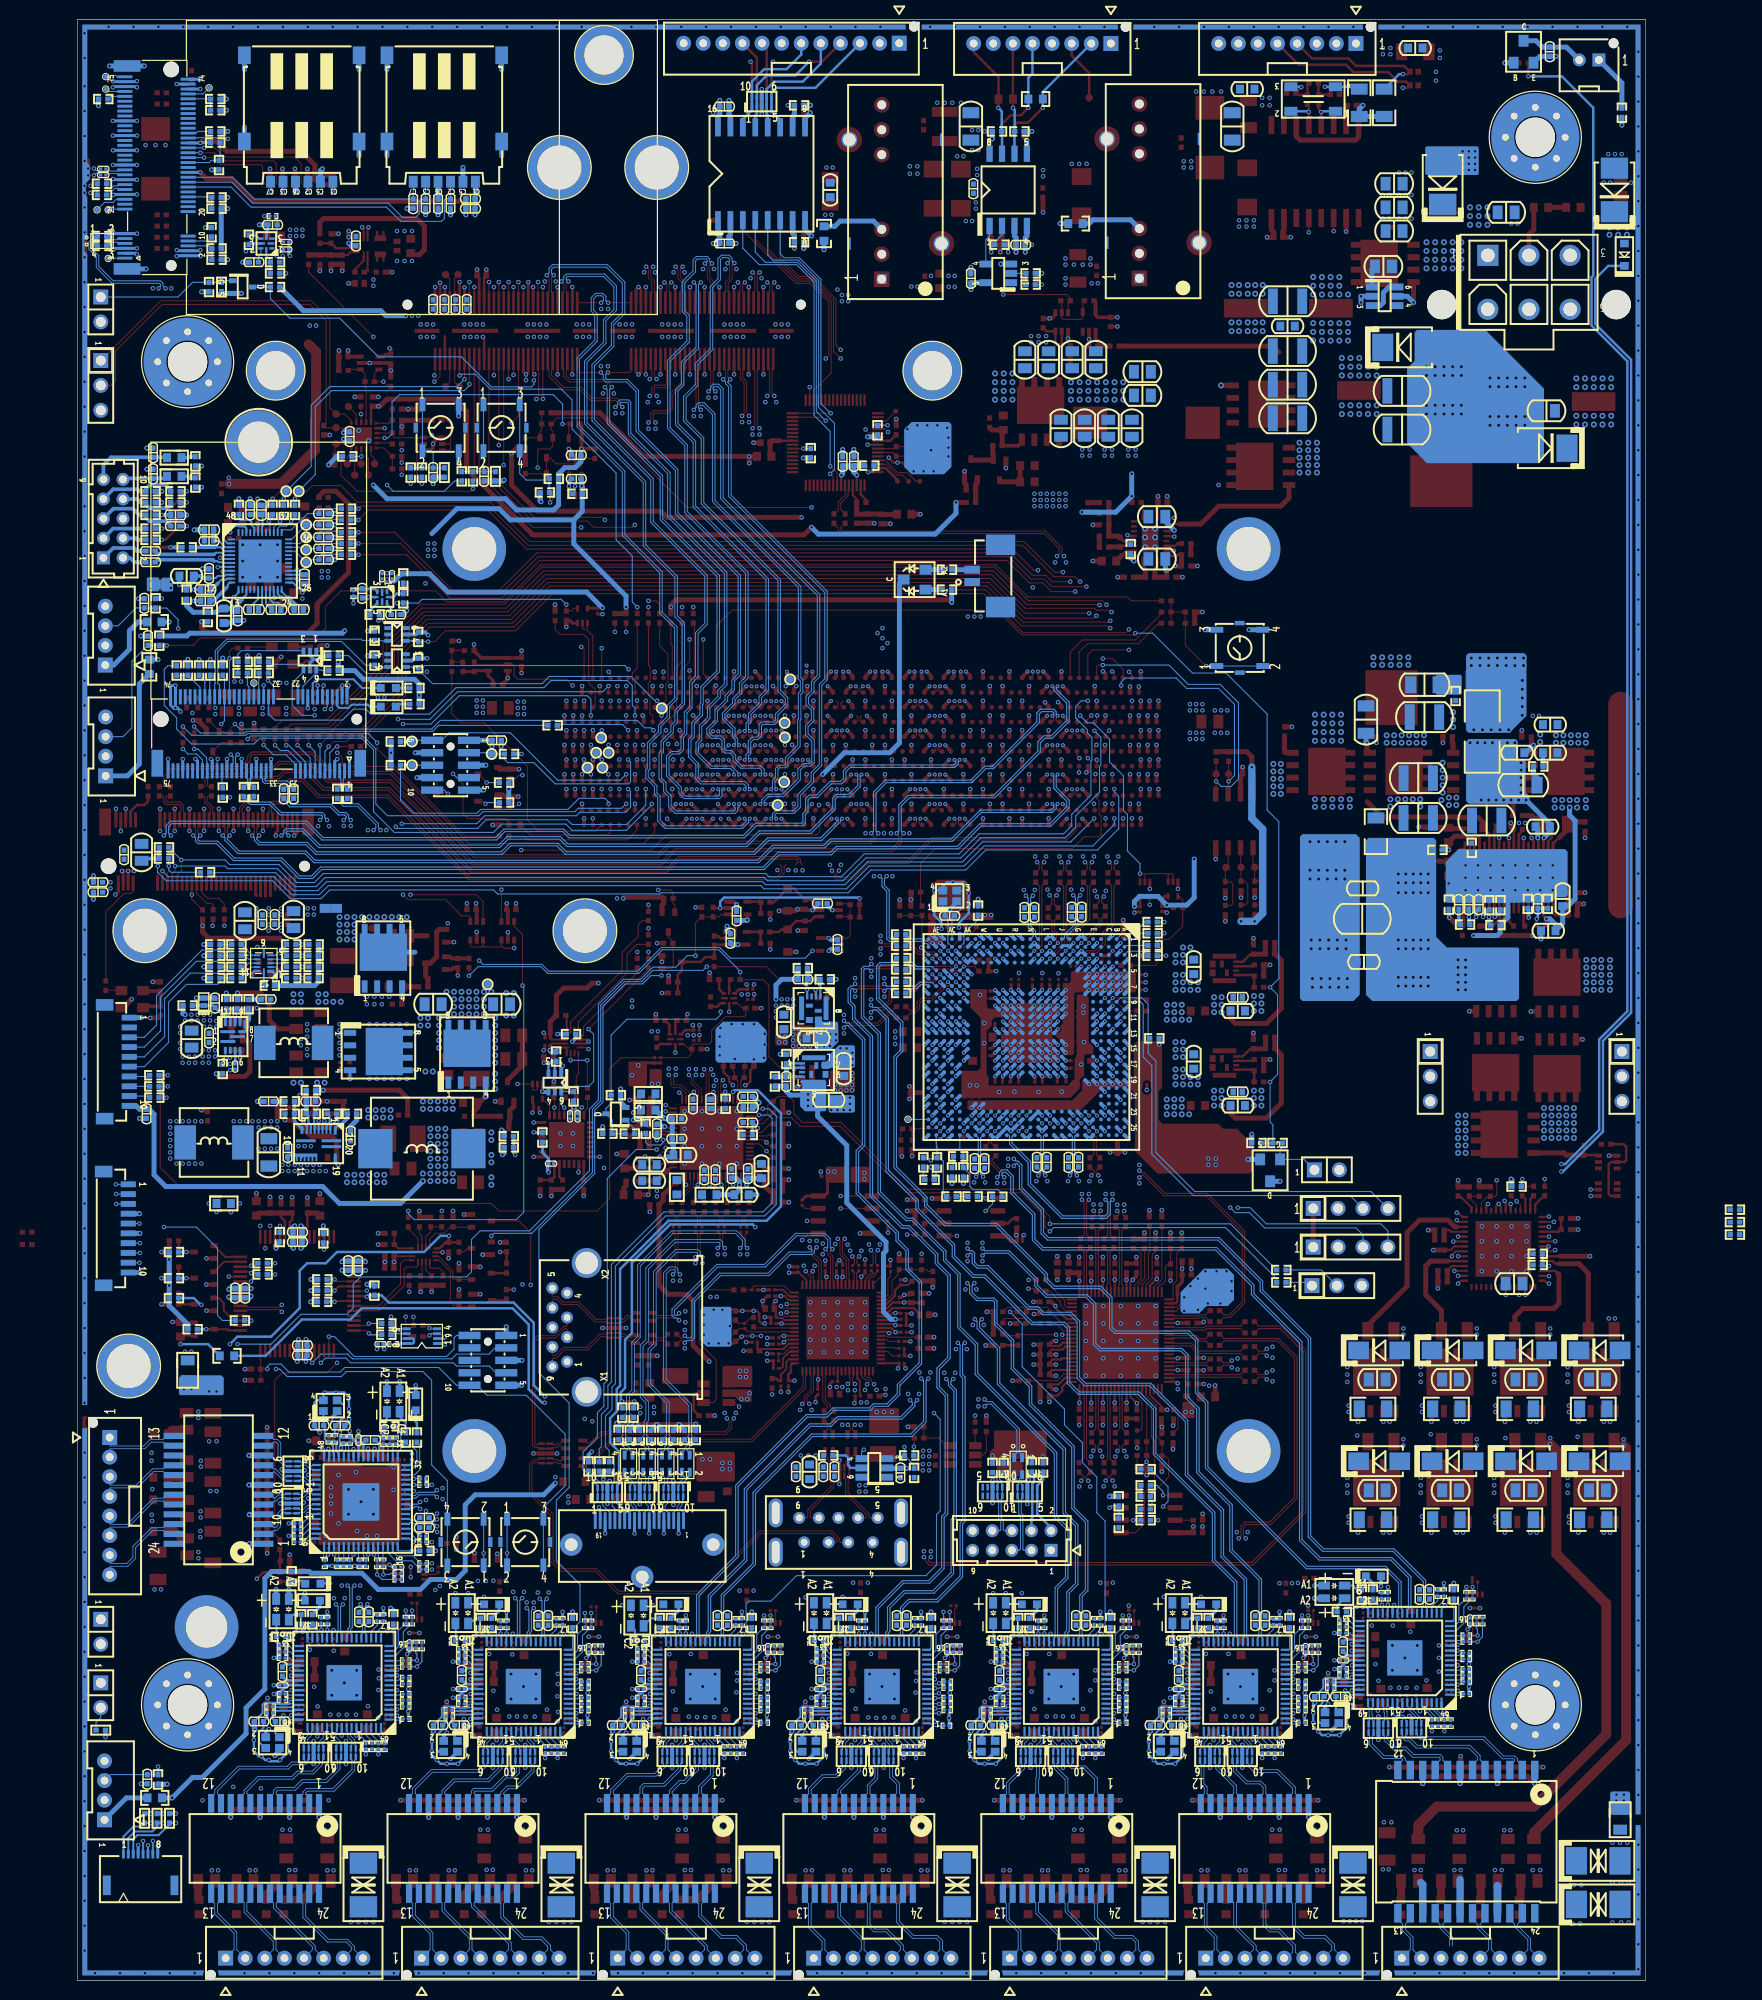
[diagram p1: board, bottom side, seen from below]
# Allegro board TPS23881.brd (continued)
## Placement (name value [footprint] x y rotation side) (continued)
NOREF#3534  -  []  53.29 145.87 90 top
NOREF#3535  -  []  58.53 98.39 270 top
NOREF#3536  -  []  54.31 147.75 0 top
NOREF#3537  -  []  52.65 56.97 0 top
NOREF#3538  -  []  144.98 104.09 0 top
NOREF#3539  -  []  146.56 130.77 270 top
NOREF#3540  -  []  82.8 58.08 270 top
NOREF#3541  -  []  56.13 17.44 90 top
NOREF#3542  -  []  142.09 98.63 90 top
NOREF#3543  -  []  149.2 69.39 0 top
NOREF#3544  -  []  49.99 75.62 270 top
NOREF#3545  -  []  135.17 40.06 0 top
NOREF#3546  -  []  138.33 78.23 90 top
NOREF#3547  -  []  115.44 18.41 90 top
NOREF#3548  -  []  124.28 66.37 90 top
NOREF#3549  -  []  30.56 35.57 0 top
NOREF#3550  -  []  19.12 21.79 90 top
NOREF#3551  -  []  57.4 37.52 270 top
NOREF#3552  -  []  135.23 87.96 0 top
NOREF#3553  -  []  157.09 184.15 0 top
NOREF#3554  -  []  29.16 191.57 0 top
NOREF#3555  -  []  128.78 36.69 90 top
NOREF#3556  -  []  127.18 143.94 270 top
NOREF#3557  -  []  111.66 159.89 0 top
NOREF#3558  -  []  63.4 188.59 0 top
NOREF#3559  -  []  50.11 73.14 90 top
NOREF#3560  -  []  150.75 120.78 90 top
NOREF#3561  -  []  138.51 26.11 90 top
NOREF#3562  -  []  127.53 66.57 90 top
NOREF#3563  -  []  145.95 147.6 90 top
NOREF#3564  -  []  143.89 92.95 90 top
NOREF#3565  -  []  45.73 34.52 270 top
NOREF#3566  -  []  89.28 109.73 90 top
NOREF#3567  -  []  96.56 95.89 0 top
NOREF#3568  -  []  102.18 28.97 0 top
NOREF#3569  -  []  50.44 53.11 0 top
NOREF#3570  -  []  133.55 182.83 90 top
NOREF#3571  -  []  51.89 58.2 270 top
NOREF#3572  -  []  51.83 33.48 90 top
NOREF#3573  -  []  31.17 36.56 90 top
NOREF#3574  -  []  115.49 84.96 0 top
NOREF#3575  -  []  126.23 26.67 0 top
NOREF#3576  -  []  55.45 77.81 270 top
NOREF#3577  -  []  124.79 135.31 0 top
NOREF#3578  -  []  136.6 18.72 0 top
NOREF#3579  -  []  22.38 20.47 90 top
NOREF#3580  -  []  103.45 27.42 0 top
NOREF#3581  -  []  73.51 111.43 270 top
NOREF#3582  -  []  133.97 53.64 0 top
NOREF#3583  -  []  85.01 91.97 0 top
NOREF#3584  -  []  98.81 64.64 0 top
NOREF#3585  -  []  152.8 98.84 0 top
NOREF#3586  -  []  120.22 134.92 270 top
NOREF#3587  -  []  127.38 177.38 270 top
NOREF#3588  -  []  134.4 147.83 0 top
NOREF#3589  -  []  135.25 142.8 90 top
NOREF#3590  -  []  138.89 174.83 90 top
NOREF#3591  -  []  61.61 33.86 90 top
NOREF#3592  -  []  127.37 55.3 0 top
NOREF#3593  -  []  120.52 32.16 90 top
NOREF#3594  -  []  149.22 127.23 270 top
NOREF#3595  -  []  150.88 177.55 90 top
NOREF#3596  -  []  39.57 94.56 0 top
NOREF#3597  -  []  143 121.79 270 top
NOREF#3598  -  []  123.49 182.04 270 top
NOREF#3599  -  []  134.95 106.1 0 top
NOREF#3600  -  []  84.07 18.41 270 top
NOREF#3601  -  []  116.84 36.06 90 top
NOREF#3602  -  []  17.22 65.1 0 top
NOREF#3603  -  []  144.87 2.26 0 top
NOREF#3604  -  []  152.55 21.34 270 top
NOREF#3605  -  []  145.54 184.68 90 top
NOREF#3606  -  []  135.41 102.23 0 top
NOREF#3607  -  []  85.47 101.85 0 top
NOREF#3608  -  []  43.04 34.47 0 top
NOREF#3609  -  []  121.67 171.45 270 top
NOREF#3610  -  []  99.83 34.52 270 top
NOREF#3611  -  []  17.91 36.44 90 top
NOREF#3612  -  []  58.88 83.91 270 top
NOREF#3613  -  []  141.48 103.85 270 top
NOREF#3614  -  []  100.89 29.35 270 top
NOREF#3615  -  []  56.13 108.58 90 top
NOREF#3616  -  []  131.8 85.29 90 top
NOREF#3617  -  []  144.4 127.23 270 top
NOREF#3618  -  []  142.47 66.88 90 top
NOREF#3619  -  []  118.61 27.61 0 top
NOREF#3620  -  []  138.99 176.42 90 top
NOREF#3621  -  []  45.59 34.48 270 top
NOREF#3622  -  []  28.75 29.79 0 top
NOREF#3623  -  []  144.37 98.63 0 top
NOREF#3624  -  []  53.07 32.26 0 top
NOREF#3625  -  []  19.13 40.31 0 top
NOREF#3626  -  []  51.56 76.07 270 top
NOREF#3627  -  []  143.89 70.57 270 top
NOREF#3628  -  []  127.99 67.01 0 top
NOREF#3629  -  []  137.79 184.11 270 top
NOREF#3630  -  []  52.55 194.36 90 top
NOREF#3631  -  []  11.26 70.72 90 top
NOREF#3632  -  []  24.87 2.26 0 top
NOREF#3633  -  []  149.17 73.84 0 top
NOREF#3634  -  []  20.52 25.97 90 top
NOREF#3635  -  []  19.89 25.97 90 top
NOREF#3636  -  []  132.54 26 90 top
NOREF#3637  -  []  103.3 61.26 270 top
NOREF#3638  -  []  128.77 142.93 0 top
NOREF#3639  -  []  117.09 34.43 270 top
NOREF#3640  -  []  156.41 192.33 0 top
NOREF#3641  -  []  42.11 123.9 0 top
NOREF#3642  -  []  44.58 35.97 90 top
NOREF#3643  -  []  97.41 98.35 0 top
NOREF#3644  -  []  60.78 84.25 270 top
NOREF#3645  -  []  70.98 28.83 0 top
NOREF#3646  -  []  156.64 25.07 0 top
NOREF#3647  -  []  95.02 103.4 90 top
NOREF#3648  -  []  55.42 27.44 270 top
NOREF#3649  -  []  32.92 193.93 270 top
NOREF#3650  -  []  44.69 34.52 0 top
NOREF#3651  -  []  30.56 31.89 0 top
NOREF#3652  -  []  130 36.58 90 top
NOREF#3653  -  []  1.14 178.69 0 top
NOREF#3654  -  []  122.38 158.7 0 top
NOREF#3655  -  []  96.58 25.58 0 top
NOREF#3656  -  []  108.96 138.44 90 top
NOREF#3657  -  []  89.61 28.33 270 top
NOREF#3658  -  []  127.47 130.32 0 top
NOREF#3659  -  []  82.03 27.61 0 top
NOREF#3660  -  []  128.15 141.72 270 top
NOREF#3661  -  []  134.44 159.05 270 top
NOREF#3662  -  []  32.8 28.96 0 top
NOREF#3663  -  []  126.19 30.37 270 top
NOREF#3664  -  []  100.63 110.79 270 top
NOREF#3665  -  []  125.22 133.88 90 top
NOREF#3666  -  []  140.61 73.15 0 top
NOREF#3667  -  []  151.08 70.03 270 top
NOREF#3668  -  []  104.01 17.44 90 top
NOREF#3669  -  []  51.23 104.95 270 top
NOREF#3670  -  []  83.93 29.72 0 top
NOREF#3671  -  []  45.72 61.98 90 top
NOREF#3672  -  []  133.54 83.95 0 top
NOREF#3673  -  []  51.61 101.04 0 top
NOREF#3674  -  []  127.97 31.89 0 top
NOREF#3675  -  []  116.2 74.32 90 top
NOREF#3676  -  []  46.81 35.1 0 top
NOREF#3677  -  []  42.21 90.27 90 top
NOREF#3678  -  []  107.05 33.48 90 top
NOREF#3679  -  []  101.3 105.23 0 top
NOREF#3680  -  []  100.32 34.52 0 top
NOREF#3681  -  []  33.4 33.52 90 top
NOREF#3682  -  []  76.02 52.24 270 top
NOREF#3683  -  []  37.83 36.27 0 top
NOREF#3684  -  []  123.39 152.98 0 top
NOREF#3685  -  []  151.08 74.73 270 top
NOREF#3686  -  []  5.87 85.6 0 top
NOREF#3687  -  []  49.83 140 270 top
NOREF#3688  -  []  40.13 35.89 90 top
NOREF#3689  -  []  112.52 12.52 270 top
NOREF#3690  -  []  132.61 73.41 270 top
NOREF#3691  -  []  55.75 145.93 90 top
NOREF#3692  -  []  55.12 167.13 270 top
NOREF#3693  -  []  134 34.85 270 top
NOREF#3694  -  []  45.97 138.18 90 top
NOREF#3695  -  []  48.92 52.1 0 top
NOREF#3696  -  []  138.55 18.41 90 top
NOREF#3697  -  []  127.97 31.13 0 top
NOREF#3698  -  []  2.92 65.44 0 top
NOREF#3699  -  []  51.94 72.17 90 top
NOREF#3700  -  []  131.04 72.09 0 top
NOREF#3701  -  []  58.12 83.95 270 top
NOREF#3702  -  []  60.78 60.4 0 top
NOREF#3703  -  []  116.89 154.38 0 top
NOREF#3704  -  []  56.77 54.86 90 top
NOREF#3705  -  []  88.52 12.52 0 top
NOREF#3706  -  []  140.59 178.82 90 top
NOREF#3707  -  []  59.88 91.68 0 top
NOREF#3708  -  []  136.73 35.89 0 top
NOREF#3709  -  []  123.65 43.38 90 top
NOREF#3710  -  []  126.9 156.72 0 top
NOREF#3711  -  []  54.81 29.07 0 top
NOREF#3712  -  []  120.47 33.92 0 top
NOREF#3713  -  []  129.53 42.52 270 top
NOREF#3714  -  []  60.2 109.44 270 top
NOREF#3715  -  []  53.04 29.71 0 top
NOREF#3716  -  []  62.61 51.84 90 top
NOREF#3717  -  []  120.47 29.58 0 top
NOREF#3718  -  []  132.84 42.28 90 top
NOREF#3719  -  []  64.02 34.52 270 top
NOREF#3720  -  []  54.81 30.75 0 top
NOREF#3721  -  []  94.69 109.91 0 top
NOREF#3722  -  []  61.54 91.64 270 top
NOREF#3723  -  []  107.01 37.96 90 top
NOREF#3724  -  []  5.08 -25.4 0 top
NOREF#3725  -  []  145.44 190.75 0 top
NOREF#3726  -  []  133.55 184.45 0 top
NOREF#3727  -  []  143.26 121.75 270 top
NOREF#3728  -  []  34.11 18.72 0 top
NOREF#3729  -  []  115.44 17.4 90 top
NOREF#3730  -  []  136.53 78.27 90 top
NOREF#3731  -  []  28.52 38.43 0 top
NOREF#3732  -  []  134.37 44.59 270 top
NOREF#3733  -  []  19.13 80.94 270 top
NOREF#3734  -  []  115.43 34.47 0 top
NOREF#3735  -  []  109.72 29.21 0 top
NOREF#3736  -  []  143.43 120.27 90 top
NOREF#3737  -  []  109.68 138.25 0 top
NOREF#3738  -  []  17.98 30.98 0 top
NOREF#3739  -  []  65.61 29.86 270 top
NOREF#3740  -  []  142.19 134.92 270 top
NOREF#3741  -  []  45.42 61.14 270 top
NOREF#3742  -  []  127.27 88.01 90 top
NOREF#3743  -  []  66.19 51.33 90 top
NOREF#3744  -  []  66.57 102.51 90 top
NOREF#3745  -  []  62.43 35.51 90 top
NOREF#3746  -  []  157.07 110.69 0 top
NOREF#3747  -  []  6.96 109.8 0 top
NOREF#3748  -  []  84.07 29.95 270 top
NOREF#3749  -  []  10.69 108.99 0 top
NOREF#3750  -  []  131.06 161.52 270 top
NOREF#3751  -  []  64.85 91.64 270 top
NOREF#3752  -  []  138.02 140.18 0 top
NOREF#3753  -  []  83.82 18.38 270 top
NOREF#3754  -  []  126.9 157.86 0 top
NOREF#3755  -  []  138.25 34.62 90 top
NOREF#3756  -  []  127.97 26.78 0 top
NOREF#3757  -  []  133.6 44.59 270 top
NOREF#3758  -  []  62.12 36.63 270 top
NOREF#3759  -  []  75.55 23.8 0 top
NOREF#3760  -  []  150.57 191.08 0 top
NOREF#3761  -  []  45.72 61.09 0 top
NOREF#3762  -  []  123.85 70.89 90 top
NOREF#3763  -  []  34.75 26.15 0 top
NOREF#3764  -  []  136.6 17.09 90 top
NOREF#3765  -  []  62.61 71.88 270 top
NOREF#3766  -  []  85.52 101.98 0 top
NOREF#3767  -  []  100.46 96.6 0 top
NOREF#3768  -  []  66.22 31.93 270 top
NOREF#3769  -  []  157.38 111.25 0 top
NOREF#3770  -  []  67.11 177.34 270 top
NOREF#3771  -  []  61.47 168.55 90 top
NOREF#3772  -  []  115.8 70.92 270 top
NOREF#3773  -  []  61.21 112.95 270 top
NOREF#3774  -  []  146.25 98.88 90 top
NOREF#3775  -  []  139.37 30.68 90 top
NOREF#3776  -  []  12.14 81.46 0 top
NOREF#3777  -  []  115.39 124 0 top
NOREF#3778  -  []  125.86 32.52 90 top
NOREF#3779  -  []  55.14 78.16 0 top
NOREF#3780  -  []  139.88 101.47 0 top
NOREF#3781  -  []  127.2 76.63 270 top
NOREF#3782  -  []  13.53 117.17 90 top
NOREF#3783  -  []  78.3 26.19 270 top
NOREF#3784  -  []  116.95 34.47 0 top
NOREF#3785  -  []  139.85 107.73 90 top
NOREF#3786  -  []  40.84 110.16 0 top
NOREF#3787  -  []  62.36 109.4 270 top
NOREF#3788  -  []  76.57 26.19 270 top
NOREF#3789  -  []  101.68 35.1 270 top
NOREF#3790  -  []  72.16 53.85 270 top
NOREF#3791  -  []  142.82 125.81 90 top
NOREF#3792  -  []  118.57 26.71 0 top
NOREF#3793  -  []  151.64 136.17 90 top
NOREF#3794  -  []  47.32 75.62 270 top
NOREF#3795  -  []  60.78 64.59 0 top
NOREF#3796  -  []  112.73 37.2 90 top
NOREF#3797  -  []  138.99 177.18 90 top
NOREF#3798  -  []  60.96 109.4 270 top
NOREF#3799  -  []  86.44 52.39 90 top
NOREF#3800  -  []  74.19 50.83 0 top
NOREF#3801  -  []  119.28 108.97 90 top
NOREF#3802  -  []  46.81 58.66 90 top
NOREF#3803  -  []  73.77 36.27 0 top
NOREF#3804  -  []  87.66 92.16 270 top
NOREF#3805  -  []  34.79 27.56 0 top
NOREF#3806  -  []  130.96 37.9 0 top
NOREF#3807  -  []  67.81 89.52 90 top
NOREF#3808  -  []  66.93 158.39 90 top
NOREF#3809  -  []  137.24 101.8 0 top
NOREF#3810  -  []  58.28 25.58 90 top
NOREF#3811  -  []  128.78 54.72 90 top
NOREF#3812  -  []  51.57 102.43 0 top
NOREF#3813  -  []  55.83 109.87 0 top
NOREF#3814  -  []  130.25 36.61 90 top
NOREF#3815  -  []  140.27 100.08 0 top
NOREF#3816  -  []  54.86 112.95 270 top
NOREF#3817  -  []  130 37.58 90 top
NOREF#3818  -  []  146.74 179.25 270 top
NOREF#3819  -  []  127.58 164.01 270 top
NOREF#3820  -  []  47.93 28.69 90 top
NOREF#3821  -  []  41.77 103.45 90 top
NOREF#3822  -  []  96.02 94.69 90 top
NOREF#3823  -  []  128.65 25.64 90 top
NOREF#3824  -  []  60.85 34.47 270 top
NOREF#3825  -  []  62.1 64.14 270 top
NOREF#3826  -  []  40.08 18.72 0 top
NOREF#3827  -  []  136.86 27.09 0 top
NOREF#3828  -  []  37.36 95.5 270 top
NOREF#3829  -  []  139.93 100.38 0 top
NOREF#3830  -  []  119.28 109.47 0 top
NOREF#3831  -  []  120.62 75.74 0 top
NOREF#3832  -  []  89.89 31.79 270 top
NOREF#3833  -  []  48.03 73.53 270 top
NOREF#3834  -  []  49.61 143.56 270 top
NOREF#3835  -  []  127.66 76.2 0 top
NOREF#3836  -  []  140.94 62.66 0 top
NOREF#3837  -  []  132.92 87.96 90 top
NOREF#3838  -  []  154.06 118.37 0 top
NOREF#3839  -  []  45.29 35.51 0 top
NOREF#3840  -  []  139.6 107.7 90 top
NOREF#3841  -  []  54.41 58.6 270 top
NOREF#3842  -  []  134.32 130 0 top
NOREF#3843  -  []  118.06 43.28 0 top
NOREF#3844  -  []  103 60.92 270 top
NOREF#3845  -  []  111.71 37.2 90 top
NOREF#3846  -  []  134.11 175.03 90 top
NOREF#3847  -  []  49.35 53.52 270 top
NOREF#3848  -  []  26.92 38.98 90 top
NOREF#3849  -  []  156.54 182.55 0 top
NOREF#3850  -  []  126.61 53.09 0 top
NOREF#3851  -  []  149.15 131.11 270 top
NOREF#3852  -  []  96.72 25.62 90 top
NOREF#3853  -  []  45.72 62.48 0 top
NOREF#3854  -  []  134.06 71.07 0 top
NOREF#3855  -  []  60.35 67.44 0 top
NOREF#3856  -  []  101.45 51.83 90 top
NOREF#3857  -  []  71.55 27.7 270 top
NOREF#3858  -  []  17.48 108.13 0 top
NOREF#3859  -  []  16.18 106.12 90 top
NOREF#3860  -  []  145.44 103.38 0 top
NOREF#3861  -  []  56.12 36.27 0 top
NOREF#3862  -  []  47.93 30.3 90 top
NOREF#3863  -  []  21.39 117.6 0 top
NOREF#3864  -  []  118.61 26.85 0 top
NOREF#3865  -  []  70.76 108.97 270 top
NOREF#3866  -  []  153.14 17.02 270 top
NOREF#3867  -  []  136.22 182.83 0 top
NOREF#3868  -  []  138.91 40.21 0 top
NOREF#3869  -  []  74.4 84.28 0 top
NOREF#3870  -  []  140.28 44.27 90 top
NOREF#3871  -  []  89.67 33.48 90 top
NOREF#3872  -  []  50.9 54.94 0 top
NOREF#3873  -  []  101.42 64.06 0 top
NOREF#3874  -  []  76.89 105.97 270 top
NOREF#3875  -  []  73.63 55.32 0 top
NOREF#3876  -  []  137.46 29.73 270 top
NOREF#3877  -  []  55.5 23.76 270 top
NOREF#3878  -  []  54.55 104.53 270 top
NOREF#3879  -  []  124.46 17.4 90 top
NOREF#3880  -  []  128 27.69 0 top
NOREF#3881  -  []  93.84 23.8 0 top
NOREF#3882  -  []  91.26 38.3 90 top
NOREF#3883  -  []  102.16 107.11 270 top
NOREF#3884  -  []  126.19 31.86 0 top
NOREF#3885  -  []  124.97 71.86 270 top
NOREF#3886  -  []  56.82 72.14 90 top
NOREF#3887  -  []  62.69 68.63 0 top
NOREF#3888  -  []  141.25 148.16 0 top
NOREF#3889  -  []  156.67 102.41 0 top
NOREF#3890  -  []  138.76 30.24 270 top
NOREF#3891  -  []  79.32 26.15 270 top
NOREF#3892  -  []  20.22 72.39 0 top
NOREF#3893  -  []  127.91 54.86 0 top
NOREF#3894  -  []  120.78 153.9 270 top
NOREF#3895  -  []  43.13 17.09 90 top
NOREF#3896  -  []  43.43 63.63 0 top
NOREF#3897  -  []  85.5 103.25 0 top
NOREF#3898  -  []  65.65 32.51 0 top
NOREF#3899  -  []  126.23 28.57 0 top
NOREF#3900  -  []  72.9 36.93 270 top
NOREF#3901  -  []  60.82 62.81 0 top
NOREF#3902  -  []  131.6 73.41 270 top
NOREF#3903  -  []  109.72 26.54 0 top
NOREF#3904  -  []  134.25 53.04 90 top
NOREF#3905  -  []  51.05 78.36 270 top
NOREF#3906  -  []  2.03 14.1 0 top
NOREF#3907  -  []  130.63 140.67 0 top
NOREF#3908  -  []  123.11 70.43 90 top
NOREF#3909  -  []  30.56 36.21 0 top
NOREF#3910  -  []  110.35 36.27 0 top
NOREF#3911  -  []  54.48 75.68 90 top
NOREF#3912  -  []  55.5 75.69 270 top
NOREF#3913  -  []  107.21 156.18 270 top
NOREF#3914  -  []  11.43 80.04 90 top
NOREF#3915  -  []  24.77 178.51 0 top
NOREF#3916  -  []  43.47 63.37 0 top
NOREF#3917  -  []  94.86 25.58 0 top
NOREF#3918  -  []  87.22 93.04 0 top
NOREF#3919  -  []  144.81 100.05 270 top
NOREF#3920  -  []  65.7 26.04 0 top
NOREF#3921  -  []  129.24 135.56 0 top
NOREF#3922  -  []  111.71 36.2 90 top
NOREF#3923  -  []  141.91 134.92 270 top
NOREF#3924  -  []  132.92 134.04 270 top
NOREF#3925  -  []  127 139.06 0 top
NOREF#3926  -  []  28.56 40.82 90 top
NOREF#3927  -  []  141 89.41 90 top
NOREF#3928  -  []  121.67 181.73 90 top
NOREF#3929  -  []  101.22 18.41 90 top
NOREF#3930  -  []  107.9 27.7 0 top
NOREF#3931  -  []  115.39 122.12 90 top
NOREF#3932  -  []  109.93 62.63 0 top
NOREF#3933  -  []  89.78 36.63 0 top
NOREF#3934  -  []  128.67 72.39 90 top
NOREF#3935  -  []  56.02 113.3 270 top
NOREF#3936  -  []  12.4 20.78 90 top
NOREF#3937  -  []  138.89 175.69 0 top
NOREF#3938  -  []  45.45 34.52 0 top
NOREF#3939  -  []  67.06 85.09 270 top
NOREF#3940  -  []  66.92 27.56 0 top
NOREF#3941  -  []  70.98 29.84 0 top
NOREF#3942  -  []  65.99 83.77 0 top
NOREF#3943  -  []  110.22 25.22 0 top
NOREF#3944  -  []  140.03 77.93 90 top
NOREF#3945  -  []  36.96 192.18 90 top
NOREF#3946  -  []  72.11 81.23 90 top
NOREF#3947  -  []  46.34 71.96 0 top
NOREF#3948  -  []  53.85 58.29 270 top
NOREF#3949  -  []  36.53 31.51 0 top
NOREF#3950  -  []  1.27 179.83 90 top
NOREF#3951  -  []  68.1 109.6 270 top
NOREF#3952  -  []  104.72 139.88 0 top
NOREF#3953  -  []  107.9 30.34 0 top
NOREF#3954  -  []  92.48 109.09 270 top
NOREF#3955  -  []  56.31 58.29 270 top
NOREF#3956  -  []  83.06 51.08 90 top
NOREF#3957  -  []  86.16 110.67 270 top
NOREF#3958  -  []  70.61 33.52 90 top
NOREF#3959  -  []  73.1 76.5 270 top
NOREF#3960  -  []  138.68 127.61 270 top
NOREF#3961  -  []  68.33 182.25 90 top
NOREF#3962  -  []  138.81 32.54 90 top
NOREF#3963  -  []  44.08 34.47 270 top
NOREF#3964  -  []  49.35 105.99 270 top
NOREF#3965  -  []  143.59 70.92 0 top
NOREF#3966  -  []  150.22 114 0 top
NOREF#3967  -  []  138.38 32.08 90 top
NOREF#3968  -  []  37.83 104.72 0 top
NOREF#3969  -  []  142.82 101.8 0 top
NOREF#3970  -  []  59.39 25.62 90 top
NOREF#3971  -  []  109.68 31.51 0 top
NOREF#3972  -  []  134.95 136.32 270 top
NOREF#3973  -  []  150.88 180.34 0 top
NOREF#3974  -  []  56.29 95.22 0 top
NOREF#3975  -  []  130.68 140.97 90 top
NOREF#3976  -  []  140.49 134.49 0 top
NOREF#3977  -  []  144.57 107.79 0 top
NOREF#3978  -  []  66.62 51.79 90 top
NOREF#3979  -  []  37.07 23.8 0 top
NOREF#3980  -  []  138.2 40.67 90 top
NOREF#3981  -  []  153.09 135.84 90 top
NOREF#3982  -  []  125.72 37.01 270 top
NOREF#3983  -  []  150.93 151.46 90 top
NOREF#3984  -  []  118.57 27.47 0 top
NOREF#3985  -  []  47.22 109.42 0 top
NOREF#3986  -  []  133.34 42.24 90 top
NOREF#3987  -  []  126.42 154.74 270 top
NOREF#3988  -  []  140.11 107.7 90 top
NOREF#3989  -  []  121.92 181.7 270 top
NOREF#3990  -  []  36.32 35.97 90 top
NOREF#3991  -  []  49.78 150.5 90 top
NOREF#3992  -  []  133.07 87.43 0 top
NOREF#3993  -  []  137.07 75.31 0 top
NOREF#3994  -  []  125.48 181.73 90 top
NOREF#3995  -  []  124.1 43.81 0 top
NOREF#3996  -  []  34.49 191.36 90 top
NOREF#3997  -  []  41.72 25.58 90 top
NOREF#3998  -  []  92.57 23.8 0 top
NOREF#3999  -  []  72.72 84.38 270 top
NOREF#4000  -  []  102.79 33.64 90 top
NOREF#4001  -  []  66.22 33.01 90 top
NOREF#4002  -  []  43.13 63.68 270 top
NOREF#4003  -  []  82.45 53.98 270 top
NOREF#4004  -  []  59.75 112.95 270 top
NOREF#4005  -  []  60.78 102.08 270 top
NOREF#4006  -  []  125.34 34.47 0 top
NOREF#4007  -  []  54.99 40.49 270 top
NOREF#4008  -  []  118.28 173.86 0 top
NOREF#4009  -  []  57.86 37.21 270 top
NOREF#4010  -  []  97.78 36.63 0 top
NOREF#4011  -  []  122.22 182.04 270 top
NOREF#4012  -  []  101.32 98.22 270 top
NOREF#4013  -  []  51.77 143.56 270 top
NOREF#4014  -  []  38.76 85.85 0 top
NOREF#4015  -  []  151.59 147.37 0 top
NOREF#4016  -  []  98.36 96.76 0 top
NOREF#4017  -  []  20.29 114.88 90 top
NOREF#4018  -  []  149.66 71.63 0 top
NOREF#4019  -  []  85.01 93.12 0 top
NOREF#4020  -  []  126.87 5.46 270 top
NOREF#4021  -  []  57.3 91.39 0 top
NOREF#4022  -  []  71.03 32.28 0 top
NOREF#4023  -  []  62.06 37.95 0 top
NOREF#4024  -  []  46.38 144.27 0 top
NOREF#4025  -  []  120.22 25.73 90 top
NOREF#4026  -  []  88.9 33.52 90 top
NOREF#4027  -  []  47.32 29.86 270 top
NOREF#4028  -  []  18.02 30.48 0 top
NOREF#4029  -  []  102.18 28.33 0 top
NOREF#4030  -  []  56.4 36.88 270 top
NOREF#4031  -  []  109.93 62.63 90 top
NOREF#4032  -  []  64.71 91.68 0 top
NOREF#4033  -  []  126.44 100 270 top
NOREF#4034  -  []  49.8 149.22 270 top
NOREF#4035  -  []  53.21 73.14 90 top
NOREF#4036  -  []  128.32 157.43 90 top
NOREF#4037  -  []  61.79 59.39 90 top
NOREF#4038  -  []  17.13 36.4 90 top
NOREF#4039  -  []  126.23 30.86 0 top
NOREF#4040  -  []  116.07 36.63 270 top
NOREF#4041  -  []  9.68 107.21 0 top
NOREF#4042  -  []  56.95 82.93 90 top
NOREF#4043  -  []  135.42 47.49 90 top
NOREF#4044  -  []  132.92 134.04 0 top
NOREF#4045  -  []  63.6 66.22 0 top
NOREF#4046  -  []  55.31 104.53 270 top
NOREF#4047  -  []  134.11 177.19 90 top
NOREF#4048  -  []  128.15 140.47 0 top
NOREF#4049  -  []  125.09 39.4 0 top
NOREF#4050  -  []  79.18 26.19 270 top
NOREF#4051  -  []  118.54 24.54 90 top
NOREF#4052  -  []  138.68 120.52 90 top
NOREF#4053  -  []  133.53 87 0 top
NOREF#4054  -  []  49.17 96.52 0 top
NOREF#4055  -  []  12.14 20.82 90 top
NOREF#4056  -  []  134.54 176.73 90 top
NOREF#4057  -  []  126.54 130.61 270 top
NOREF#4058  -  []  53.67 54.43 0 top
NOREF#4059  -  []  10.06 73.69 90 top
NOREF#4060  -  []  18.87 20.82 90 top
NOREF#4061  -  []  101.31 68.09 0 top
NOREF#4062  -  []  83.95 25.78 0 top
NOREF#4063  -  []  14.38 108.74 0 top
NOREF#4064  -  []  115.57 34.43 270 top
NOREF#4065  -  []  140.03 132.92 90 top
NOREF#4066  -  []  151.59 139.52 0 top
NOREF#4067  -  []  27.38 38.43 90 top
NOREF#4068  -  []  152.6 20.02 90 top
NOREF#4069  -  []  128.57 29.73 270 top
NOREF#4070  -  []  126.44 159.84 90 top
NOREF#4071  -  []  37.97 177.55 90 top
NOREF#4072  -  []  125.86 31.89 0 top
NOREF#4073  -  []  69.16 83.36 270 top
NOREF#4074  -  []  17.73 108.92 90 top
NOREF#4075  -  []  9.68 107.21 90 top
NOREF#4076  -  []  109.6 152.91 90 top
NOREF#4077  -  []  126.49 54.89 90 top
NOREF#4078  -  []  56.02 113.3 0 top
NOREF#4079  -  []  53.2 36.63 0 top
NOREF#4080  -  []  37.49 105.03 0 top
NOREF#4081  -  []  123.19 181.7 270 top
NOREF#4082  -  []  76.33 18.38 270 top
NOREF#4083  -  []  137.54 184.15 270 top
NOREF#4084  -  []  134.52 70.36 0 top
NOREF#4085  -  []  157.09 184.78 0 top
NOREF#4086  -  []  102.69 59.64 0 top
NOREF#4087  -  []  57.28 109.47 270 top
NOREF#4088  -  []  61.79 62.56 90 top
NOREF#4089  -  []  152.93 87.92 90 top
NOREF#4090  -  []  46.02 27.75 270 top
NOREF#4091  -  []  61.04 25.62 90 top
NOREF#4092  -  []  129.41 36.69 90 top
NOREF#4093  -  []  49.86 72.17 90 top
NOREF#4094  -  []  149.66 74.3 0 top
NOREF#4095  -  []  18.23 80.97 90 top
NOREF#4096  -  []  138.63 121.84 0 top
NOREF#4097  -  []  59.75 102.12 270 top
NOREF#4098  -  []  65.66 25.78 0 top
NOREF#4099  -  []  60.78 82.63 0 top
NOREF#4100  -  []  121.74 27.06 0 top
NOREF#4101  -  []  47.68 145.11 90 top
NOREF#4102  -  []  118.97 24.99 90 top
NOREF#4103  -  []  129.92 24.14 270 top
NOREF#4104  -  []  113.87 153.24 0 top
NOREF#4105  -  []  15.52 108.74 90 top
NOREF#4106  -  []  34.91 36.63 270 top
NOREF#4107  -  []  52.1 145.06 90 top
NOREF#4108  -  []  83.59 52.7 0 top
NOREF#4109  -  []  121.08 28.05 90 top
NOREF#4110  -  []  141.52 175.26 0 top
NOREF#4111  -  []  58.28 25.58 0 top
NOREF#4112  -  []  20.93 118.03 270 top
NOREF#4113  -  []  37.59 18.41 90 top
NOREF#4114  -  []  38.96 92.79 0 top
NOREF#4115  -  []  80.35 37.95 90 top
NOREF#4116  -  []  142.72 94.44 90 top
NOREF#4117  -  []  124.41 45.48 0 top
NOREF#4118  -  []  52.96 58.25 270 top
NOREF#4119  -  []  88.39 90.75 0 top
NOREF#4120  -  []  14.61 106.58 90 top
NOREF#4121  -  []  140.59 44.83 0 top
NOREF#4122  -  []  140.03 104.19 0 top
NOREF#4123  -  []  60.19 109.43 90 top
NOREF#4124  -  []  21.07 39.19 0 top
NOREF#4125  -  []  136.89 27.23 0 top
NOREF#4126  -  []  144.86 182.3 0 top
NOREF#4127  -  []  152.1 115.14 90 top
NOREF#4128  -  []  6.12 55.74 270 top
NOREF#4129  -  []  54.86 18.41 90 top
NOREF#4130  -  []  152.68 17.5 270 top
NOREF#4131  -  []  130.63 142.29 270 top
NOREF#4132  -  []  131.83 177.93 270 top
NOREF#4133  -  []  46 72.26 270 top
NOREF#4134  -  []  131.69 53.52 0 top
NOREF#4135  -  []  126.14 71.86 270 top
NOREF#4136  -  []  136.83 184.45 270 top
NOREF#4137  -  []  140.87 107.7 90 top
NOREF#4138  -  []  104.43 26.04 0 top
NOREF#4139  -  []  124.7 33.86 0 top
NOREF#4140  -  []  20.37 30.09 90 top
NOREF#4141  -  []  71.25 33.52 90 top
NOREF#4142  -  []  133.35 53.07 90 top
NOREF#4143  -  []  137.69 104.52 0 top
NOREF#4144  -  []  128.56 174.24 0 top
NOREF#4145  -  []  47.07 25.73 90 top
NOREF#4146  -  []  48.16 57.25 90 top
NOREF#4147  -  []  129.58 54.86 0 top
NOREF#4148  -  []  62.87 35.97 90 top
NOREF#4149  -  []  100.13 65.61 90 top
NOREF#4150  -  []  16.26 78.52 0 top
NOREF#4151  -  []  135.22 38.33 0 top
NOREF#4152  -  []  54.3 77.84 90 top
NOREF#4153  -  []  54.43 150.44 0 top
NOREF#4154  -  []  75.01 99.75 0 top
NOREF#4155  -  []  89.65 26.29 0 top
NOREF#4156  -  []  137.62 121.84 0 top
NOREF#4157  -  []  28.69 32.13 0 top
NOREF#4158  -  []  153.21 122.22 270 top
NOREF#4159  -  []  115.52 117.14 0 top
NOREF#4160  -  []  121.16 170.43 90 top
NOREF#4161  -  []  133.86 97.66 0 top
NOREF#4162  -  []  49.4 58.2 270 top
NOREF#4163  -  []  144.3 94.89 90 top
NOREF#4164  -  []  128.27 165.85 90 top
NOREF#4165  -  []  31.17 35.93 90 top
NOREF#4166  -  []  147.75 66.42 0 top
NOREF#4167  -  []  154.92 115.63 0 top
NOREF#4168  -  []  129.67 136.68 90 top
NOREF#4169  -  []  55.24 55.88 270 top
NOREF#4170  -  []  122.81 171.45 270 top
NOREF#4171  -  []  19.76 71.68 270 top
NOREF#4172  -  []  91.07 100.05 0 top
NOREF#4173  -  []  36.18 193.15 270 top
NOREF#4174  -  []  146.86 103.81 270 top
NOREF#4175  -  []  -8.18 78.18 90 top
NOREF#4176  -  []  136.91 17.44 90 top
NOREF#4177  -  []  132.46 157.99 270 top
NOREF#4178  -  []  61.21 109.43 90 top
NOREF#4179  -  []  131.09 126.87 0 top
NOREF#4180  -  []  120.62 72.95 0 top
NOREF#4181  -  []  120.53 25.78 90 top
NOREF#4182  -  []  126.19 29.35 270 top
NOREF#4183  -  []  53.04 26.15 0 top
NOREF#4184  -  []  19.76 31.99 0 top
NOREF#4185  -  []  100.98 93.55 0 top
NOREF#4186  -  []  92.34 36.27 90 top
NOREF#4187  -  []  42.61 25.58 90 top
NOREF#4188  -  []  83.82 58.08 270 top
NOREF#4189  -  []  133.3 156.01 270 top
NOREF#4190  -  []  124.08 46.94 0 top
NOREF#4191  -  []  20.47 20.47 90 top
NOREF#4192  -  []  73.14 26.54 0 top
NOREF#4193  -  []  10.69 108.99 90 top
NOREF#4194  -  []  93.5 177.16 0 top
NOREF#4195  -  []  108.07 33.65 90 top
NOREF#4196  -  []  131.8 172.75 90 top
NOREF#4197  -  []  107.9 29.71 0 top
NOREF#4198  -  []  147.22 109.19 270 top
NOREF#4199  -  []  14.17 106.12 90 top
NOREF#4200  -  []  132.11 72.39 90 top
NOREF#4201  -  []  63.23 67.01 0 top
NOREF#4202  -  []  49.49 109.6 270 top
NOREF#4203  -  []  75.46 103.89 0 top
NOREF#4204  -  []  27.32 37.39 270 top
NOREF#4205  -  []  47.78 54.38 0 top
NOREF#4206  -  []  65.2 79.5 90 top
NOREF#4207  -  []  62.97 61.16 0 top
NOREF#4208  -  []  141.17 102.57 0 top
NOREF#4209  -  []  151.33 21.44 0 top
NOREF#4210  -  []  55.68 58.6 270 top
NOREF#4211  -  []  134.86 48.51 0 top
NOREF#4212  -  []  63.56 75.39 0 top
NOREF#4213  -  []  128.64 73.66 90 top
NOREF#4214  -  []  121.41 171.41 270 top
NOREF#4215  -  []  141.38 107.7 90 top
NOREF#4216  -  []  135.59 35.89 0 top
NOREF#4217  -  []  52.55 199.66 0 top
NOREF#4218  -  []  63.07 109.74 0 top
NOREF#4219  -  []  83.5 109.86 0 top
NOREF#4220  -  []  134.95 102.67 270 top
NOREF#4221  -  []  151.08 72.06 270 top
NOREF#4222  -  []  45.49 70.48 270 top
NOREF#4223  -  []  58.22 53.26 270 top
NOREF#4224  -  []  146.56 120.78 90 top
NOREF#4225  -  []  67.31 85.05 270 top
NOREF#4226  -  []  134.4 148.97 0 top
NOREF#4227  -  []  67.13 82.5 0 top
NOREF#4228  -  []  83.49 100.2 0 top
NOREF#4229  -  []  17.65 39.51 270 top
NOREF#4230  -  []  138.3 83.95 90 top
NOREF#4231  -  []  115.42 87.71 0 top
NOREF#4232  -  []  133.68 176.73 0 top
NOREF#4233  -  []  121.06 75.29 270 top
NOREF#4234  -  []  60.15 25.62 90 top
NOREF#4235  -  []  136.07 131.62 270 top
NOREF#4236  -  []  19.05 109.26 90 top
NOREF#4237  -  []  146.33 141.5 90 top
NOREF#4238  -  []  114.87 25.58 0 top
NOREF#4239  -  []  32.44 29.71 90 top
NOREF#4240  -  []  158.8 57.37 270 top
NOREF#4241  -  []  63.28 177.04 0 top
NOREF#4242  -  []  65.58 65.91 0 top
NOREF#4243  -  []  49.78 78.36 270 top
NOREF#4244  -  []  140.34 103.85 270 top
NOREF#4245  -  []  135 184.11 270 top
NOREF#4246  -  []  103.58 138 90 top
NOREF#4247  -  []  89.65 28.19 0 top
NOREF#4248  -  []  121.18 104.24 270 top
NOREF#4249  -  []  107.66 139.99 270 top
NOREF#4250  -  []  16.78 36.4 90 top
NOREF#4251  -  []  57.59 112.98 90 top
NOREF#4252  -  []  146.02 113.46 270 top
NOREF#4253  -  []  137.49 182.83 0 top
NOREF#4254  -  []  137.24 104.09 0 top
NOREF#4255  -  []  150.22 115.14 0 top
NOREF#4256  -  []  118.44 35.51 0 top
NOREF#4257  -  []  139.78 43.26 270 top
NOREF#4258  -  []  3.2 66.24 0 top
NOREF#4259  -  []  123.44 170.43 90 top
NOREF#4260  -  []  43 67.61 0 top
NOREF#4261  -  []  128.73 139.75 270 top
NOREF#4262  -  []  64.99 91.68 270 top
NOREF#4263  -  []  67.71 178.58 90 top
NOREF#4264  -  []  9.73 65.1 0 top
NOREF#4265  -  []  6.87 127.8 90 top
NOREF#4266  -  []  91.43 29.21 0 top
NOREF#4267  -  []  40.39 94.36 270 top
NOREF#4268  -  []  102.79 30.3 90 top
NOREF#4269  -  []  131.9 164.64 0 top
NOREF#4270  -  []  36.7 39.52 90 top
NOREF#4271  -  []  73.65 25.83 270 top
NOREF#4272  -  []  116.07 36.63 0 top
NOREF#4273  -  []  63.82 101.51 0 top
NOREF#4274  -  []  56.26 56.97 0 top
NOREF#4275  -  []  146.3 121.75 270 top
NOREF#4276  -  []  126.57 52.95 90 top
NOREF#4277  -  []  55.42 83.95 270 top
NOREF#4278  -  []  85.78 27.06 270 top
NOREF#4279  -  []  142.82 104.09 0 top
NOREF#4280  -  []  135.46 130 0 top
NOREF#4281  -  []  88.52 6.93 90 top
NOREF#4282  -  []  125.55 154.74 0 top
NOREF#4283  -  []  139.34 75.34 90 top
NOREF#4284  -  []  135.29 50.15 90 top
NOREF#4285  -  []  47.9 143.13 0 top
NOREF#4286  -  []  133.16 25.96 90 top
NOREF#4287  -  []  44.87 2.26 0 top
NOREF#4288  -  []  141.38 107.7 90 top
NOREF#4289  -  []  54.85 31.37 0 top
NOREF#4290  -  []  127.71 166.17 270 top
NOREF#4291  -  []  107.9 31.48 0 top
NOREF#4292  -  []  34.75 28.97 270 top
NOREF#4293  -  []  134.06 150.95 90 top
NOREF#4294  -  []  97.9 34.47 0 top
NOREF#4295  -  []  54.43 146.48 0 top
NOREF#4296  -  []  140.28 50.24 0 top
NOREF#4297  -  []  139.37 30.78 270 top
NOREF#4298  -  []  24.93 28.5 0 top
NOREF#4299  -  []  126.19 28.08 0 top
NOREF#4300  -  []  49.56 74.19 0 top
NOREF#4301  -  []  142.93 67.31 0 top
NOREF#4302  -  []  65.61 28.33 0 top
NOREF#4303  -  []  135.08 17.09 90 top
NOREF#4304  -  []  126.03 182.04 270 top
NOREF#4305  -  []  132.46 120.55 90 top
NOREF#4306  -  []  152.04 148.08 0 top
NOREF#4307  -  []  138.91 43.51 0 top
NOREF#4308  -  []  138.18 120.78 90 top
NOREF#4309  -  []  70.99 32.14 90 top
NOREF#4310  -  []  51.94 50.06 90 top
NOREF#4311  -  []  19.8 30.23 0 top
NOREF#4312  -  []  62.45 91.68 270 top
NOREF#4313  -  []  54.94 76 0 top
NOREF#4314  -  []  52.18 101.18 270 top
NOREF#4315  -  []  57 84.25 270 top
NOREF#4316  -  []  13.28 79.58 90 top
NOREF#4317  -  []  85.51 102.11 0 top
NOREF#4318  -  []  133.86 183.17 90 top
NOREF#4319  -  []  73.1 29.07 0 top
NOREF#4320  -  []  37.13 26.68 270 top
NOREF#4321  -  []  24.77 179.12 270 top
NOREF#4322  -  []  110.29 29.35 270 top
NOREF#4323  -  []  69.42 108.48 270 top
NOREF#4324  -  []  156.54 181.69 90 top
NOREF#4325  -  []  64.39 61.59 270 top
NOREF#4326  -  []  145.7 100.2 90 top
NOREF#4327  -  []  144.87 2.26 90 top
NOREF#4328  -  []  121.41 17.4 90 top
NOREF#4329  -  []  61.98 36.59 270 top
NOREF#4330  -  []  140.28 44.27 0 top
NOREF#4331  -  []  131.52 155.88 0 top
NOREF#4332  -  []  147.65 125.81 0 top
NOREF#4333  -  []  140.28 53.29 0 top
NOREF#4334  -  []  129.41 42.28 90 top
NOREF#4335  -  []  39.9 66.04 0 top
NOREF#4336  -  []  56.06 145.87 90 top
NOREF#4337  -  []  136.89 29.59 0 top
NOREF#4338  -  []  144.86 181.43 90 top
NOREF#4339  -  []  98.17 17.4 90 top
NOREF#4340  -  []  145.62 142.72 0 top
NOREF#4341  -  []  50.85 26.34 270 top
NOREF#4342  -  []  135.41 126.87 0 top
NOREF#4343  -  []  46.94 31.7 90 top
NOREF#4344  -  []  76.53 108.15 90 top
NOREF#4345  -  []  143.15 94.89 90 top
NOREF#4346  -  []  136.89 34.9 0 top
NOREF#4347  -  []  7.65 76.58 0 top
NOREF#4348  -  []  103.49 27.56 0 top
NOREF#4349  -  []  65.65 33.15 0 top
NOREF#4350  -  []  62.1 62.1 270 top
NOREF#4351  -  []  120.52 25.78 0 top
NOREF#4352  -  []  102.18 32.65 0 top
NOREF#4353  -  []  142.26 62.11 90 top
NOREF#4354  -  []  130.56 36.27 90 top
NOREF#4355  -  []  67.89 151.18 270 top
NOREF#4356  -  []  127.56 41.03 270 top
NOREF#4357  -  []  102.18 31.93 0 top
NOREF#4358  -  []  128.64 55.3 0 top
NOREF#4359  -  []  134.86 56.59 0 top
NOREF#4360  -  []  111.96 36.23 90 top
NOREF#4361  -  []  91.39 30.75 0 top
NOREF#4362  -  []  143 120.73 90 top
NOREF#4363  -  []  139.37 33.39 90 top
NOREF#4364  -  []  35.64 18.72 0 top
NOREF#4365  -  []  20.93 117.17 0 top
NOREF#4366  -  []  151.79 12.88 0 top
NOREF#4367  -  []  97.14 34.47 0 top
NOREF#4368  -  []  158.7 112.32 270 top
NOREF#4369  -  []  49.53 26.29 0 top
NOREF#4370  -  []  63.37 109.4 270 top
NOREF#4371  -  []  38.51 102.87 0 top
NOREF#4372  -  []  107.82 33.52 90 top
NOREF#4373  -  []  123.7 25.78 90 top
NOREF#4374  -  []  158.39 110.74 90 top
NOREF#4375  -  []  152.53 137.15 90 top
NOREF#4376  -  []  134.75 184.15 270 top
NOREF#4377  -  []  41.86 25.62 90 top
NOREF#4378  -  []  118.57 29.07 0 top
NOREF#4379  -  []  19.76 33.46 90 top
NOREF#4380  -  []  75.01 105.46 0 top
NOREF#4381  -  []  47.38 25.78 90 top
NOREF#4382  -  []  56.71 77.84 90 top
NOREF#4383  -  []  88.98 110.29 270 top
NOREF#4384  -  []  59.66 73.33 0 top
NOREF#4385  -  []  62.26 174.12 0 top
NOREF#4386  -  []  54.31 17.09 90 top
NOREF#4387  -  []  56.39 17.4 90 top
NOREF#4388  -  []  150.88 179.83 90 top
NOREF#4389  -  []  49.35 109.56 270 top
NOREF#4390  -  []  68.73 89.56 90 top
NOREF#4391  -  []  76.4 86.16 270 top
NOREF#4392  -  []  109.68 29.07 0 top
NOREF#4393  -  []  138.8 32.89 0 top
NOREF#4394  -  []  49.48 104.83 0 top
NOREF#4395  -  []  74.8 18.38 270 top
NOREF#4396  -  []  139.32 183.13 90 top
NOREF#4397  -  []  138 18.72 0 top
NOREF#4398  -  []  144.73 92.02 90 top
NOREF#4399  -  []  115.01 25.62 90 top
NOREF#4400  -  []  93.12 106.81 270 top
NOREF#4401  -  []  134.95 127.3 0 top
NOREF#4402  -  []  115.52 119.71 90 top
NOREF#4403  -  []  87.3 190.83 90 top
NOREF#4404  -  []  53.29 147.5 0 top
NOREF#4405  -  []  140.82 107.39 0 top
NOREF#4406  -  []  82.21 105.66 270 top
NOREF#4407  -  []  53.75 46.18 90 top
NOREF#4408  -  []  65.65 28.83 0 top
NOREF#4409  -  []  69.84 33.48 0 top
NOREF#4410  -  []  37.2 36.27 0 top
NOREF#4411  -  []  149.87 189.45 270 top
NOREF#4412  -  []  137.69 105.66 0 top
NOREF#4413  -  []  47.32 32.65 0 top
NOREF#4414  -  []  135.97 174.57 90 top
NOREF#4415  -  []  136.22 65.07 0 top
NOREF#4416  -  []  62.43 35.51 0 top
NOREF#4417  -  []  57.96 98.25 0 top
NOREF#4418  -  []  59.45 113.3 270 top
NOREF#4419  -  []  60.64 101.51 0 top
NOREF#4420  -  []  97.16 139.42 270 top
NOREF#4421  -  []  137.27 46.61 0 top
NOREF#4422  -  []  47.37 31.62 90 top
NOREF#4423  -  []  88.82 92.18 270 top
NOREF#4424  -  []  150.67 114.43 0 top
NOREF#4425  -  []  127.66 72.39 0 top
NOREF#4426  -  []  62.61 70.74 270 top
NOREF#4427  -  []  129.78 24.18 0 top
NOREF#4428  -  []  100.32 27.61 0 top
NOREF#4429  -  []  39.9 67.18 0 top
NOREF#4430  -  []  56.9 75.69 270 top
NOREF#4431  -  []  80.19 109.73 0 top
NOREF#4432  -  []  139.34 172.72 0 top
NOREF#4433  -  []  48.63 26.92 0 top
NOREF#4434  -  []  151.59 150.32 0 top
NOREF#4435  -  []  150.91 176.66 0 top
NOREF#4436  -  []  92 26.68 270 top
NOREF#4437  -  []  74.19 50.83 90 top
NOREF#4438  -  []  152.44 30.8 0 top
NOREF#4439  -  []  20.55 76.53 0 top
NOREF#4440  -  []  136.22 64.06 0 top
NOREF#4441  -  []  54.41 72.14 90 top
NOREF#4442  -  []  137.11 126.19 0 top
NOREF#4443  -  []  10.61 71.37 0 top
NOREF#4444  -  []  123.77 101.78 270 top
NOREF#4445  -  []  75.77 52.27 90 top
NOREF#4446  -  []  7.65 77.72 0 top
NOREF#4447  -  []  53.24 167.13 0 top
NOREF#4448  -  []  10.29 80.04 90 top
NOREF#4449  -  []  133.59 54.94 0 top
NOREF#4450  -  []  118.52 42.85 0 top
NOREF#4451  -  []  53.7 166.7 0 top
NOREF#4452  -  []  9.55 108.86 0 top
NOREF#4453  -  []  21.21 39.23 90 top
NOREF#4454  -  []  56.82 56.18 270 top
NOREF#4455  -  []  122.38 78.28 0 top
NOREF#4456  -  []  63.74 29.21 0 top
NOREF#4457  -  []  7.44 154.38 90 top
NOREF#4458  -  []  98.84 64.9 0 top
NOREF#4459  -  []  88.52 12.52 0 top
NOREF#4460  -  []  19.76 30.09 0 top
NOREF#4461  -  []  59.64 109.74 0 top
NOREF#4462  -  []  56.31 173.56 90 top
NOREF#4463  -  []  157.12 25.53 0 top
NOREF#4464  -  []  56.87 58.6 270 top
NOREF#4465  -  []  110.44 152.73 0 top
NOREF#4466  -  []  10.06 73.41 0 top
NOREF#4467  -  []  105.16 52.51 90 top
NOREF#4468  -  []  147.16 121.81 270 top
NOREF#4469  -  []  47.42 72.95 90 top
NOREF#4470  -  []  89.31 107.19 0 top
NOREF#4471  -  []  148.01 134.54 270 top
NOREF#4472  -  []  92.28 59.89 90 top
NOREF#4473  -  []  39.45 66.47 270 top
NOREF#4474  -  []  133.86 34.81 270 top
NOREF#4475  -  []  45.45 26.85 0 top
NOREF#4476  -  []  34.81 33.48 90 top
NOREF#4477  -  []  17.98 35.04 0 top
NOREF#4478  -  []  43 66.34 270 top
NOREF#4479  -  []  30.59 32.64 0 top
NOREF#4480  -  []  12.56 117.42 0 top
NOREF#4481  -  []  45.42 63.8 270 top
NOREF#4482  -  []  11.84 20.47 90 top
NOREF#4483  -  []  153.47 151.46 90 top
NOREF#4484  -  []  53.04 28.33 270 top
NOREF#4485  -  []  127.23 56.95 0 top
NOREF#4486  -  []  140.59 103.88 90 top
NOREF#4487  -  []  37.34 36.31 90 top
NOREF#4488  -  []  106.41 33.48 0 top
NOREF#4489  -  []  63.73 76.28 90 top
NOREF#4490  -  []  108.71 6.93 90 top
NOREF#4491  -  []  36.19 18.41 90 top
NOREF#4492  -  []  54.85 30.61 0 top
NOREF#4493  -  []  67.61 85.39 270 top
NOREF#4494  -  []  5.74 116.74 90 top
NOREF#4495  -  []  94.44 36.2 90 top
NOREF#4496  -  []  107.9 31.76 270 top
NOREF#4497  -  []  138.8 30.1 0 top
NOREF#4498  -  []  140.16 72.72 0 top
NOREF#4499  -  []  134.09 68.78 0 top
NOREF#4500  -  []  134.9 75.21 90 top
NOREF#4501  -  []  52.57 36.63 270 top
NOREF#4502  -  []  92.33 12.52 270 top
NOREF#4503  -  []  136.53 64.52 0 top
NOREF#4504  -  []  7.62 5.84 90 top
NOREF#4505  -  []  34.79 32.26 0 top
NOREF#4506  -  []  82.6 26.99 270 top
NOREF#4507  -  []  80.35 37.95 0 top
NOREF#4508  -  []  127.46 54.43 0 top
NOREF#4509  -  []  102.57 64.06 270 top
NOREF#4510  -  []  75.46 98.17 0 top
NOREF#4511  -  []  68.4 56.95 270 top
NOREF#4512  -  []  45.45 29.21 0 top
NOREF#4513  -  []  18.15 39.55 0 top
NOREF#4514  -  []  37.71 23.8 0 top
NOREF#4515  -  []  45.39 24.54 90 top
NOREF#4516  -  []  108.28 152.86 0 top
NOREF#4517  -  []  71.11 33.48 0 top
NOREF#4518  -  []  123.39 64.96 90 top
NOREF#4519  -  []  39.12 96.52 270 top
NOREF#4520  -  []  81.55 34.52 270 top
NOREF#4521  -  []  133.05 121.97 0 top
NOREF#4522  -  []  103.18 64.81 90 top
NOREF#4523  -  []  121.67 76.86 90 top
NOREF#4524  -  []  134.54 69.22 0 top
NOREF#4525  -  []  151.66 92.33 0 top
NOREF#4526  -  []  132.37 165.61 0 top
NOREF#4527  -  []  114.99 135.31 270 top
NOREF#4528  -  []  84.51 28.33 270 top
NOREF#4529  -  []  137.92 121.75 270 top
NOREF#4530  -  []  89.31 105.79 0 top
NOREF#4531  -  []  30.56 34.85 0 top
NOREF#4532  -  []  56.43 97.98 90 top
NOREF#4533  -  []  98.41 36.02 0 top
NOREF#4534  -  []  89.34 106.93 0 top
NOREF#4535  -  []  135.25 135.76 90 top
NOREF#4536  -  []  34.42 32.14 90 top
NOREF#4537  -  []  150.5 121.75 270 top
NOREF#4538  -  []  3.07 85.72 0 top
NOREF#4539  -  []  119.96 35.1 270 top
NOREF#4540  -  []  54.4 73.14 90 top
NOREF#4541  -  []  30.61 28.71 90 top
NOREF#4542  -  []  128 26.92 0 top
NOREF#4543  -  []  134.87 158.6 270 top
NOREF#4544  -  []  62.56 101.55 90 top
NOREF#4545  -  []  115.98 120.14 0 top
NOREF#4546  -  []  13.03 106.12 90 top
NOREF#4547  -  []  75.01 102.69 0 top
NOREF#4548  -  []  136.83 24.92 90 top
NOREF#4549  -  []  62.51 61.59 0 top
NOREF#4550  -  []  114.43 135 270 top
NOREF#4551  -  []  33.86 37.86 0 top
NOREF#4552  -  []  144.98 191.47 90 top
NOREF#4553  -  []  126.58 49.64 90 top
NOREF#4554  -  []  131.85 85.6 90 top
NOREF#4555  -  []  108.28 159.18 0 top
NOREF#4556  -  []  126.61 51.44 0 top
NOREF#4557  -  []  43.43 63.12 90 top
NOREF#4558  -  []  91.94 23.8 270 top
NOREF#4559  -  []  0 0 0 top
NOREF#4560  -  []  134.4 144.91 0 top
NOREF#4561  -  []  72.57 81.66 0 top
NOREF#4562  -  []  136.73 76.02 90 top
NOREF#4563  -  []  0 0 0 top
NOREF#4564  -  []  127.75 142.93 0 top
NOREF#4565  -  []  127.7 72.64 0 top
NOREF#4566  -  []  65.05 51.33 90 top
NOREF#4567  -  []  131.34 73.37 270 top
NOREF#4568  -  []  119.51 134.47 270 top
NOREF#4569  -  []  74.55 36.84 270 top
NOREF#4570  -  []  54.86 17.4 90 top
NOREF#4571  -  []  47.5 29.95 270 top
NOREF#4572  -  []  138.07 78.27 90 top
NOREF#4573  -  []  48.92 56.26 0 top
NOREF#4574  -  []  55.5 25.26 90 top
NOREF#4575  -  []  59.25 25.58 0 top
NOREF#4576  -  []  126.19 28.44 0 top
NOREF#4577  -  []  81.97 24.54 90 top
NOREF#4578  -  []  85.72 108.05 270 top
NOREF#4579  -  []  140.39 179.82 90 top
NOREF#4580  -  []  107.19 33.52 90 top
NOREF#4581  -  []  48.03 73.53 0 top
NOREF#4582  -  []  110.82 140.13 0 top
NOREF#4583  -  []  60.48 62.1 0 top
NOREF#4584  -  []  152.78 136.18 90 top
NOREF#4585  -  []  44.15 35.51 90 top
NOREF#4586  -  []  136.41 34.9 270 top
NOREF#4587  -  []  43.18 34.43 270 top
NOREF#4588  -  []  63.53 75.25 0 top
NOREF#4589  -  []  58.05 93.66 0 top
NOREF#4590  -  []  93.43 37.2 90 top
NOREF#4591  -  []  34.91 33.65 90 top
NOREF#4592  -  []  70.94 27.7 0 top
NOREF#4593  -  []  7.62 14.1 270 top
NOREF#4594  -  []  54.61 17.44 90 top
NOREF#4595  -  []  73.1 78.92 270 top
NOREF#4596  -  []  134.4 149.61 0 top
NOREF#4597  -  []  138.89 173.15 0 top
NOREF#4598  -  []  63.12 34.48 270 top
NOREF#4599  -  []  17.27 36.44 90 top
NOREF#4600  -  []  57.92 98.74 0 top
NOREF#4601  -  []  68.83 182.25 90 top
NOREF#4602  -  []  70.47 34.09 0 top
NOREF#4603  -  []  30.05 38.02 0 top
NOREF#4604  -  []  123.39 170.13 0 top
NOREF#4605  -  []  48.92 56.26 270 top
NOREF#4606  -  []  93.37 37.52 0 top
NOREF#4607  -  []  144.98 190.32 0 top
NOREF#4608  -  []  29.26 31.99 90 top
NOREF#4609  -  []  121.06 68.86 90 top
NOREF#4610  -  []  42.44 110.11 0 top
NOREF#4611  -  []  149.17 70.56 270 top
NOREF#4612  -  []  122.38 25.73 0 top
NOREF#4613  -  []  11.84 22.1 0 top
NOREF#4614  -  []  46.05 70.17 90 top
NOREF#4615  -  []  29.32 30.42 90 top
NOREF#4616  -  []  55.24 75.65 270 top
NOREF#4617  -  []  16.64 36.44 90 top
NOREF#4618  -  []  128.09 64.76 90 top
NOREF#4619  -  []  120.7 182.04 270 top
NOREF#4620  -  []  53.98 52.83 270 top
NOREF#4621  -  []  112.45 128.45 270 top
NOREF#4622  -  []  57.04 113.3 0 top
NOREF#4623  -  []  20.71 39.19 90 top
NOREF#4624  -  []  57.23 18.72 0 top
NOREF#4625  -  []  62.1 83.91 270 top
NOREF#4626  -  []  134.37 151.51 0 top
NOREF#4627  -  []  107.94 28.83 0 top
NOREF#4628  -  []  99.21 110.36 0 top
NOREF#4629  -  []  54.31 18.72 0 top
NOREF#4630  -  []  130.7 42.24 90 top
NOREF#4631  -  []  145.44 191.9 0 top
NOREF#4632  -  []  53.8 56.97 0 top
NOREF#4633  -  []  12.45 108.86 90 top
NOREF#4634  -  []  134.82 176.73 90 top
NOREF#4635  -  []  121.74 27.42 0 top
NOREF#4636  -  []  107.9 29.98 270 top
NOREF#4637  -  []  31.66 190.3 0 top
NOREF#4638  -  []  129.39 42.48 270 top
NOREF#4639  -  []  31.83 30.34 0 top
NOREF#4640  -  []  144.7 106.1 270 top
NOREF#4641  -  []  56.26 71.83 90 top
NOREF#4642  -  []  44.88 68.76 270 top
NOREF#4643  -  []  107.68 33.48 0 top
NOREF#4644  -  []  138.76 33.03 0 top
NOREF#4645  -  []  111.66 158.75 0 top
NOREF#4646  -  []  131.9 156.67 0 top
NOREF#4647  -  []  128.51 25.6 90 top
NOREF#4648  -  []  31.19 192.1 90 top
NOREF#4649  -  []  73.1 30.75 0 top
NOREF#4650  -  []  140.17 134.25 90 top
NOREF#4651  -  []  132.21 42.28 90 top
NOREF#4652  -  []  103.45 27.06 0 top
NOREF#4653  -  []  143.87 94.44 0 top
NOREF#4654  -  []  43.46 67.18 0 top
NOREF#4655  -  []  30.47 191.01 90 top
NOREF#4656  -  []  82.55 58.12 270 top
NOREF#4657  -  []  129.27 36.65 0 top
NOREF#4658  -  []  17.98 29.07 0 top
NOREF#4659  -  []  45.42 26.71 0 top
NOREF#4660  -  []  142.06 176.61 0 top
NOREF#4661  -  []  151.41 17.5 270 top
NOREF#4662  -  []  37.71 23.8 270 top
NOREF#4663  -  []  45.42 66.75 0 top
NOREF#4664  -  []  140.63 53.59 0 top
NOREF#4665  -  []  124.45 50.55 0 top
NOREF#4666  -  []  140.03 182.83 0 top
NOREF#4667  -  []  114.88 17.09 90 top
NOREF#4668  -  []  51.94 46.51 90 top
NOREF#4669  -  []  101.3 138 0 top
NOREF#4670  -  []  124.66 78.28 0 top
NOREF#4671  -  []  145.24 148.82 0 top
NOREF#4672  -  []  66.22 28.69 90 top
NOREF#4673  -  []  133.74 44.63 270 top
NOREF#4674  -  []  43.55 36.02 0 top
NOREF#4675  -  []  54.1 112.98 90 top
NOREF#4676  -  []  107.96 33.48 90 top
NOREF#4677  -  []  125.86 32.8 0 top
NOREF#4678  -  []  75.13 37.21 270 top
NOREF#4679  -  []  58.7 171.32 0 top
NOREF#4680  -  []  83.26 102.11 0 top
NOREF#4681  -  []  28.71 29.65 0 top
NOREF#4682  -  []  40.39 103.15 90 top
NOREF#4683  -  []  54.1 112.99 270 top
NOREF#4684  -  []  128.51 24.18 0 top
NOREF#4685  -  []  151.5 98.44 90 top
NOREF#4686  -  []  116.93 38.75 270 top
NOREF#4687  -  []  129.41 66.57 90 top
NOREF#4688  -  []  110.16 158.32 90 top
NOREF#4689  -  []  56.89 75.68 90 top
NOREF#4690  -  []  83.99 26.04 0 top
NOREF#4691  -  []  141.05 18.72 0 top
NOREF#4692  -  []  140.63 50.55 0 top
NOREF#4693  -  []  52.65 71.83 90 top
NOREF#4694  -  []  114.3 157.33 270 top
NOREF#4695  -  []  135.41 103.38 0 top
NOREF#4696  -  []  56.57 58.25 270 top
NOREF#4697  -  []  85.42 190.83 0 top
NOREF#4698  -  []  43.69 36.06 90 top
NOREF#4699  -  []  102.44 138 0 top
NOREF#4700  -  []  89.61 31.76 270 top
NOREF#4701  -  []  132.21 54.85 90 top
NOREF#4702  -  []  57.84 109.78 270 top
NOREF#4703  -  []  41 99.92 0 top
NOREF#4704  -  []  116.7 36.02 0 top
NOREF#4705  -  []  134.95 104.95 0 top
NOREF#4706  -  []  72.11 81.23 90 top
NOREF#4707  -  []  139.55 107.39 0 top
NOREF#4708  -  []  49.63 96.09 0 top
NOREF#4709  -  []  134.37 151 90 top
NOREF#4710  -  []  37.06 85.42 0 top
NOREF#4711  -  []  140.59 47.24 90 top
NOREF#4712  -  []  134.95 106.1 270 top
NOREF#4713  -  []  124.41 51.32 0 top
NOREF#4714  -  []  102.74 60.96 270 top
NOREF#4715  -  []  101.12 93.59 90 top
NOREF#4716  -  []  62.32 178.53 90 top
NOREF#4717  -  []  125.48 181.74 270 top
NOREF#4718  -  []  128.91 12.52 270 top
NOREF#4719  -  []  125.7 72.31 270 top
NOREF#4720  -  []  146.3 130.81 270 top
NOREF#4721  -  []  41.71 112.57 270 top
NOREF#4722  -  []  65.82 177.04 0 top
NOREF#4723  -  []  34.75 32.4 270 top
NOREF#4724  -  []  116.19 34.47 0 top
NOREF#4725  -  []  66.84 95.21 0 top
NOREF#4726  -  []  64.01 35.97 90 top
NOREF#4727  -  []  59.27 91.68 270 top
NOREF#4728  -  []  96.52 17.44 90 top
NOREF#4729  -  []  131.09 54.99 0 top
NOREF#4730  -  []  72.16 53.85 0 top
NOREF#4731  -  []  84.41 97.96 0 top
NOREF#4732  -  []  27.81 38.89 90 top
NOREF#4733  -  []  43.83 36.02 90 top
NOREF#4734  -  []  68.33 6.93 90 top
NOREF#4735  -  []  107.61 32.28 0 top
NOREF#4736  -  []  66.83 55.52 0 top
NOREF#4737  -  []  21.79 164.67 0 top
NOREF#4738  -  []  81.43 53.94 90 top
NOREF#4739  -  []  149.15 134.54 270 top
NOREF#4740  -  []  23.37 38.56 90 top
NOREF#4741  -  []  151.66 90.04 0 top
NOREF#4742  -  []  98.3 139.42 270 top
NOREF#4743  -  []  39.45 62.66 270 top
NOREF#4744  -  []  48.41 140.72 0 top
NOREF#4745  -  []  108.03 60.04 0 top
NOREF#4746  -  []  126.44 158.29 0 top
NOREF#4747  -  []  102.18 29.86 270 top
NOREF#4748  -  []  137.77 79.55 0 top
NOREF#4749  -  []  51.13 75.62 270 top
NOREF#4750  -  []  73.56 77.22 0 top
NOREF#4751  -  []  27.94 12.52 0 top
NOREF#4752  -  []  77.72 18.38 270 top
NOREF#4753  -  []  91.64 99.91 90 top
NOREF#4754  -  []  98.27 101.14 270 top
NOREF#4755  -  []  134.05 25.96 0 top
NOREF#4756  -  []  59.13 83.95 270 top
NOREF#4757  -  []  45.19 46.94 0 top
NOREF#4758  -  []  107.9 32.12 0 top
NOREF#4759  -  []  123.77 46.89 90 top
NOREF#4760  -  []  109.72 27.3 0 top
NOREF#4761  -  []  128.64 42.24 0 top
NOREF#4762  -  []  114.73 153.24 90 top
NOREF#4763  -  []  61.93 113.3 0 top
NOREF#4764  -  []  11.66 126.82 0 top
NOREF#4765  -  []  104.27 17.4 90 top
NOREF#4766  -  []  137.24 44.56 0 top
NOREF#4767  -  []  66.57 102.51 0 top
NOREF#4768  -  []  77.98 18.41 270 top
NOREF#4769  -  []  142.47 67.74 0 top
NOREF#4770  -  []  47.36 28.19 0 top
NOREF#4771  -  []  27 127.3 0 top
NOREF#4772  -  []  115.52 122.61 0 top
NOREF#4773  -  []  45.67 138.13 90 top
NOREF#4774  -  []  111.53 62.61 90 top
NOREF#4775  -  []  41.27 108.74 90 top
NOREF#4776  -  []  77.67 26.15 270 top
NOREF#4777  -  []  136.14 133.65 90 top
NOREF#4778  -  []  142.11 121.75 270 top
NOREF#4779  -  []  134.26 149.76 90 top
NOREF#4780  -  []  89.78 36.63 270 top
NOREF#4781  -  []  44.88 67.61 270 top
NOREF#4782  -  []  55.42 26.68 270 top
NOREF#4783  -  []  136.53 63.5 90 top
NOREF#4784  -  []  83.93 33.15 0 top
NOREF#4785  -  []  61.21 109.44 270 top
NOREF#4786  -  []  46.3 72.21 0 top
NOREF#4787  -  []  60.82 60.66 0 top
NOREF#4788  -  []  56.29 95.22 270 top
NOREF#4789  -  []  124.09 45.93 90 top
NOREF#4790  -  []  128.64 54.69 90 top
NOREF#4791  -  []  120.47 29.86 270 top
NOREF#4792  -  []  48.9 76.07 270 top
NOREF#4793  -  []  153.11 21.03 270 top
NOREF#4794  -  []  134.82 176.45 0 top
NOREF#4795  -  []  126.62 49.78 0 top
NOREF#4796  -  []  132.51 126.44 90 top
NOREF#4797  -  []  10.69 54.94 0 top
NOREF#4798  -  []  102.79 33.01 90 top
NOREF#4799  -  []  129.67 134.14 90 top
NOREF#4800  -  []  65.23 33.58 0 top
NOREF#4801  -  []  150.09 9.7 0 top
NOREF#4802  -  []  17.51 39.55 270 top
NOREF#4803  -  []  106.79 140 0 top
NOREF#4804  -  []  95.25 17.4 90 top
NOREF#4805  -  []  108.06 36.63 270 top
NOREF#4806  -  []  47.32 28.33 0 top
NOREF#4807  -  []  78.85 34.47 0 top
NOREF#4808  -  []  124.21 181.73 90 top
NOREF#4809  -  []  112.32 153.59 270 top
NOREF#4810  -  []  7.62 5.84 90 top
NOREF#4811  -  []  15.39 79.53 90 top
NOREF#4812  -  []  123.9 17.09 90 top
NOREF#4813  -  []  61.69 52.77 90 top
NOREF#4814  -  []  73.14 30.61 0 top
NOREF#4815  -  []  83.39 35.1 0 top
NOREF#4816  -  []  67.06 156.11 90 top
NOREF#4817  -  []  124.74 65.66 0 top
NOREF#4818  -  []  18.26 106.12 0 top
NOREF#4819  -  []  61.7 52.78 270 top
NOREF#4820  -  []  130.42 42.24 0 top
NOREF#4821  -  []  59.66 72.11 90 top
NOREF#4822  -  []  123.95 76.86 90 top
NOREF#4823  -  []  20.07 109.25 90 top
NOREF#4824  -  []  109.6 155.32 90 top
NOREF#4825  -  []  88.85 105.36 0 top
NOREF#4826  -  []  55.49 36.27 0 top
NOREF#4827  -  []  116.93 37.95 0 top
NOREF#4828  -  []  70.12 33.48 90 top
NOREF#4829  -  []  49.35 105.99 0 top
NOREF#4830  -  []  17.98 33.26 0 top
NOREF#4831  -  []  138.05 183.13 90 top
NOREF#4832  -  []  53.85 146.18 90 top
NOREF#4833  -  []  137.17 34.9 270 top
NOREF#4834  -  []  128.14 54.72 90 top
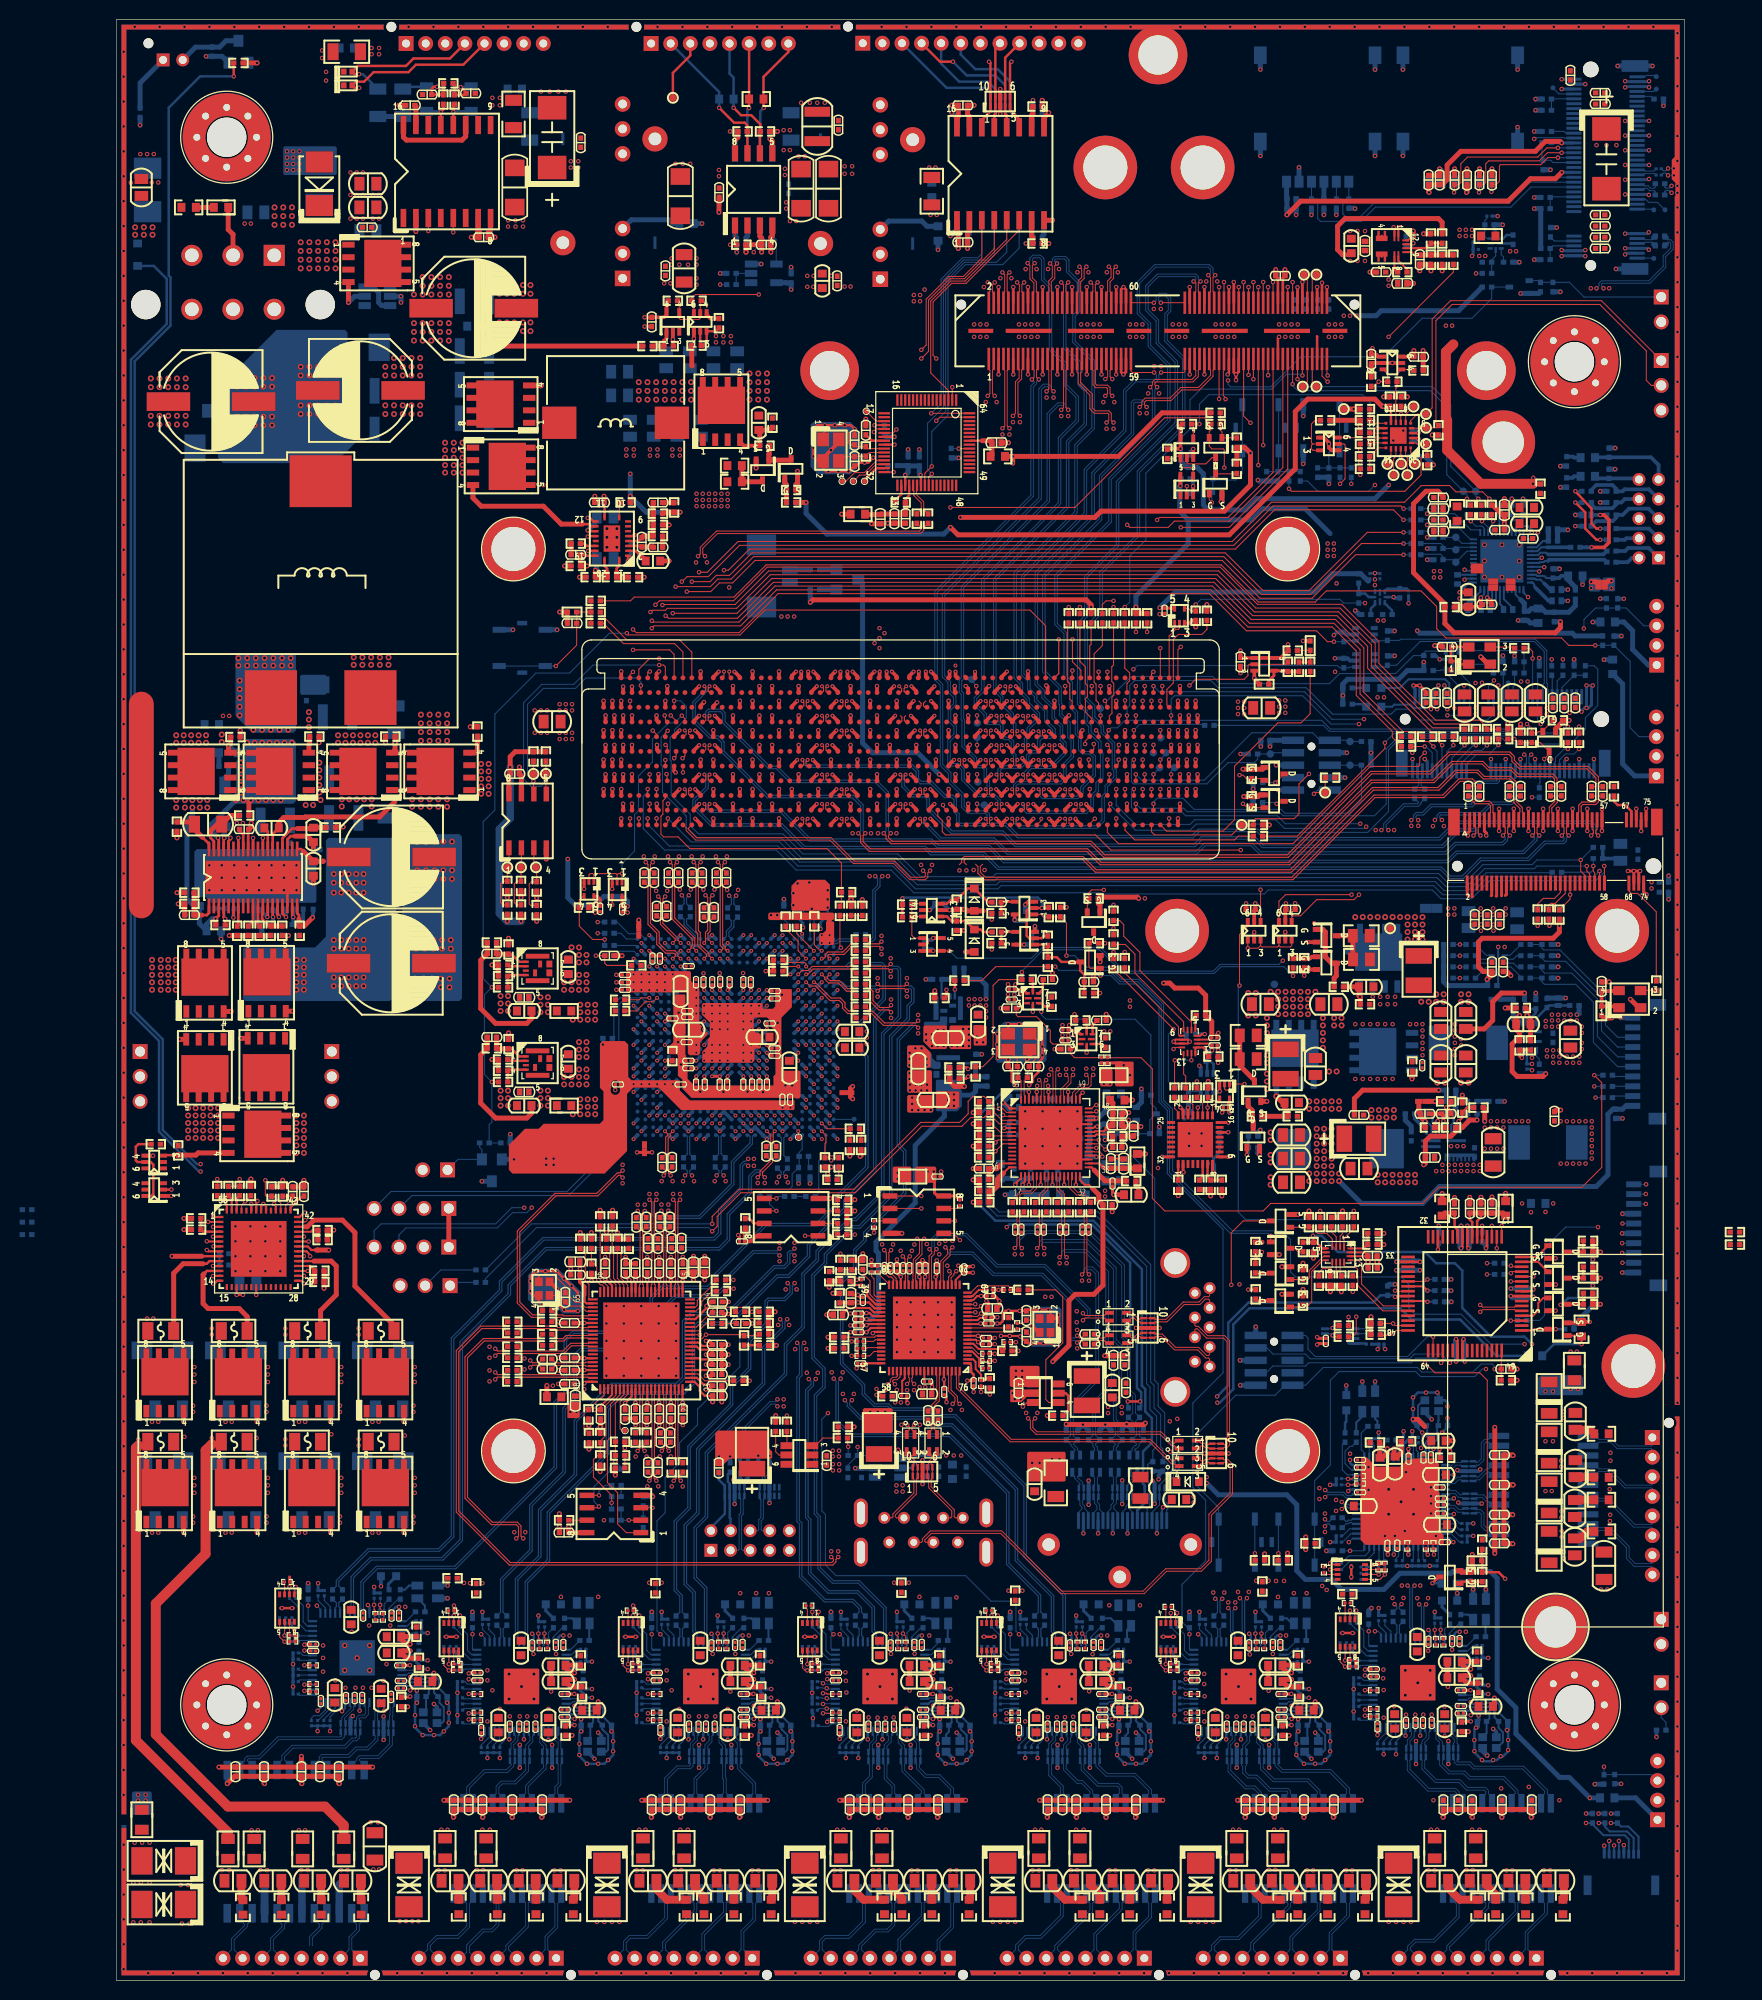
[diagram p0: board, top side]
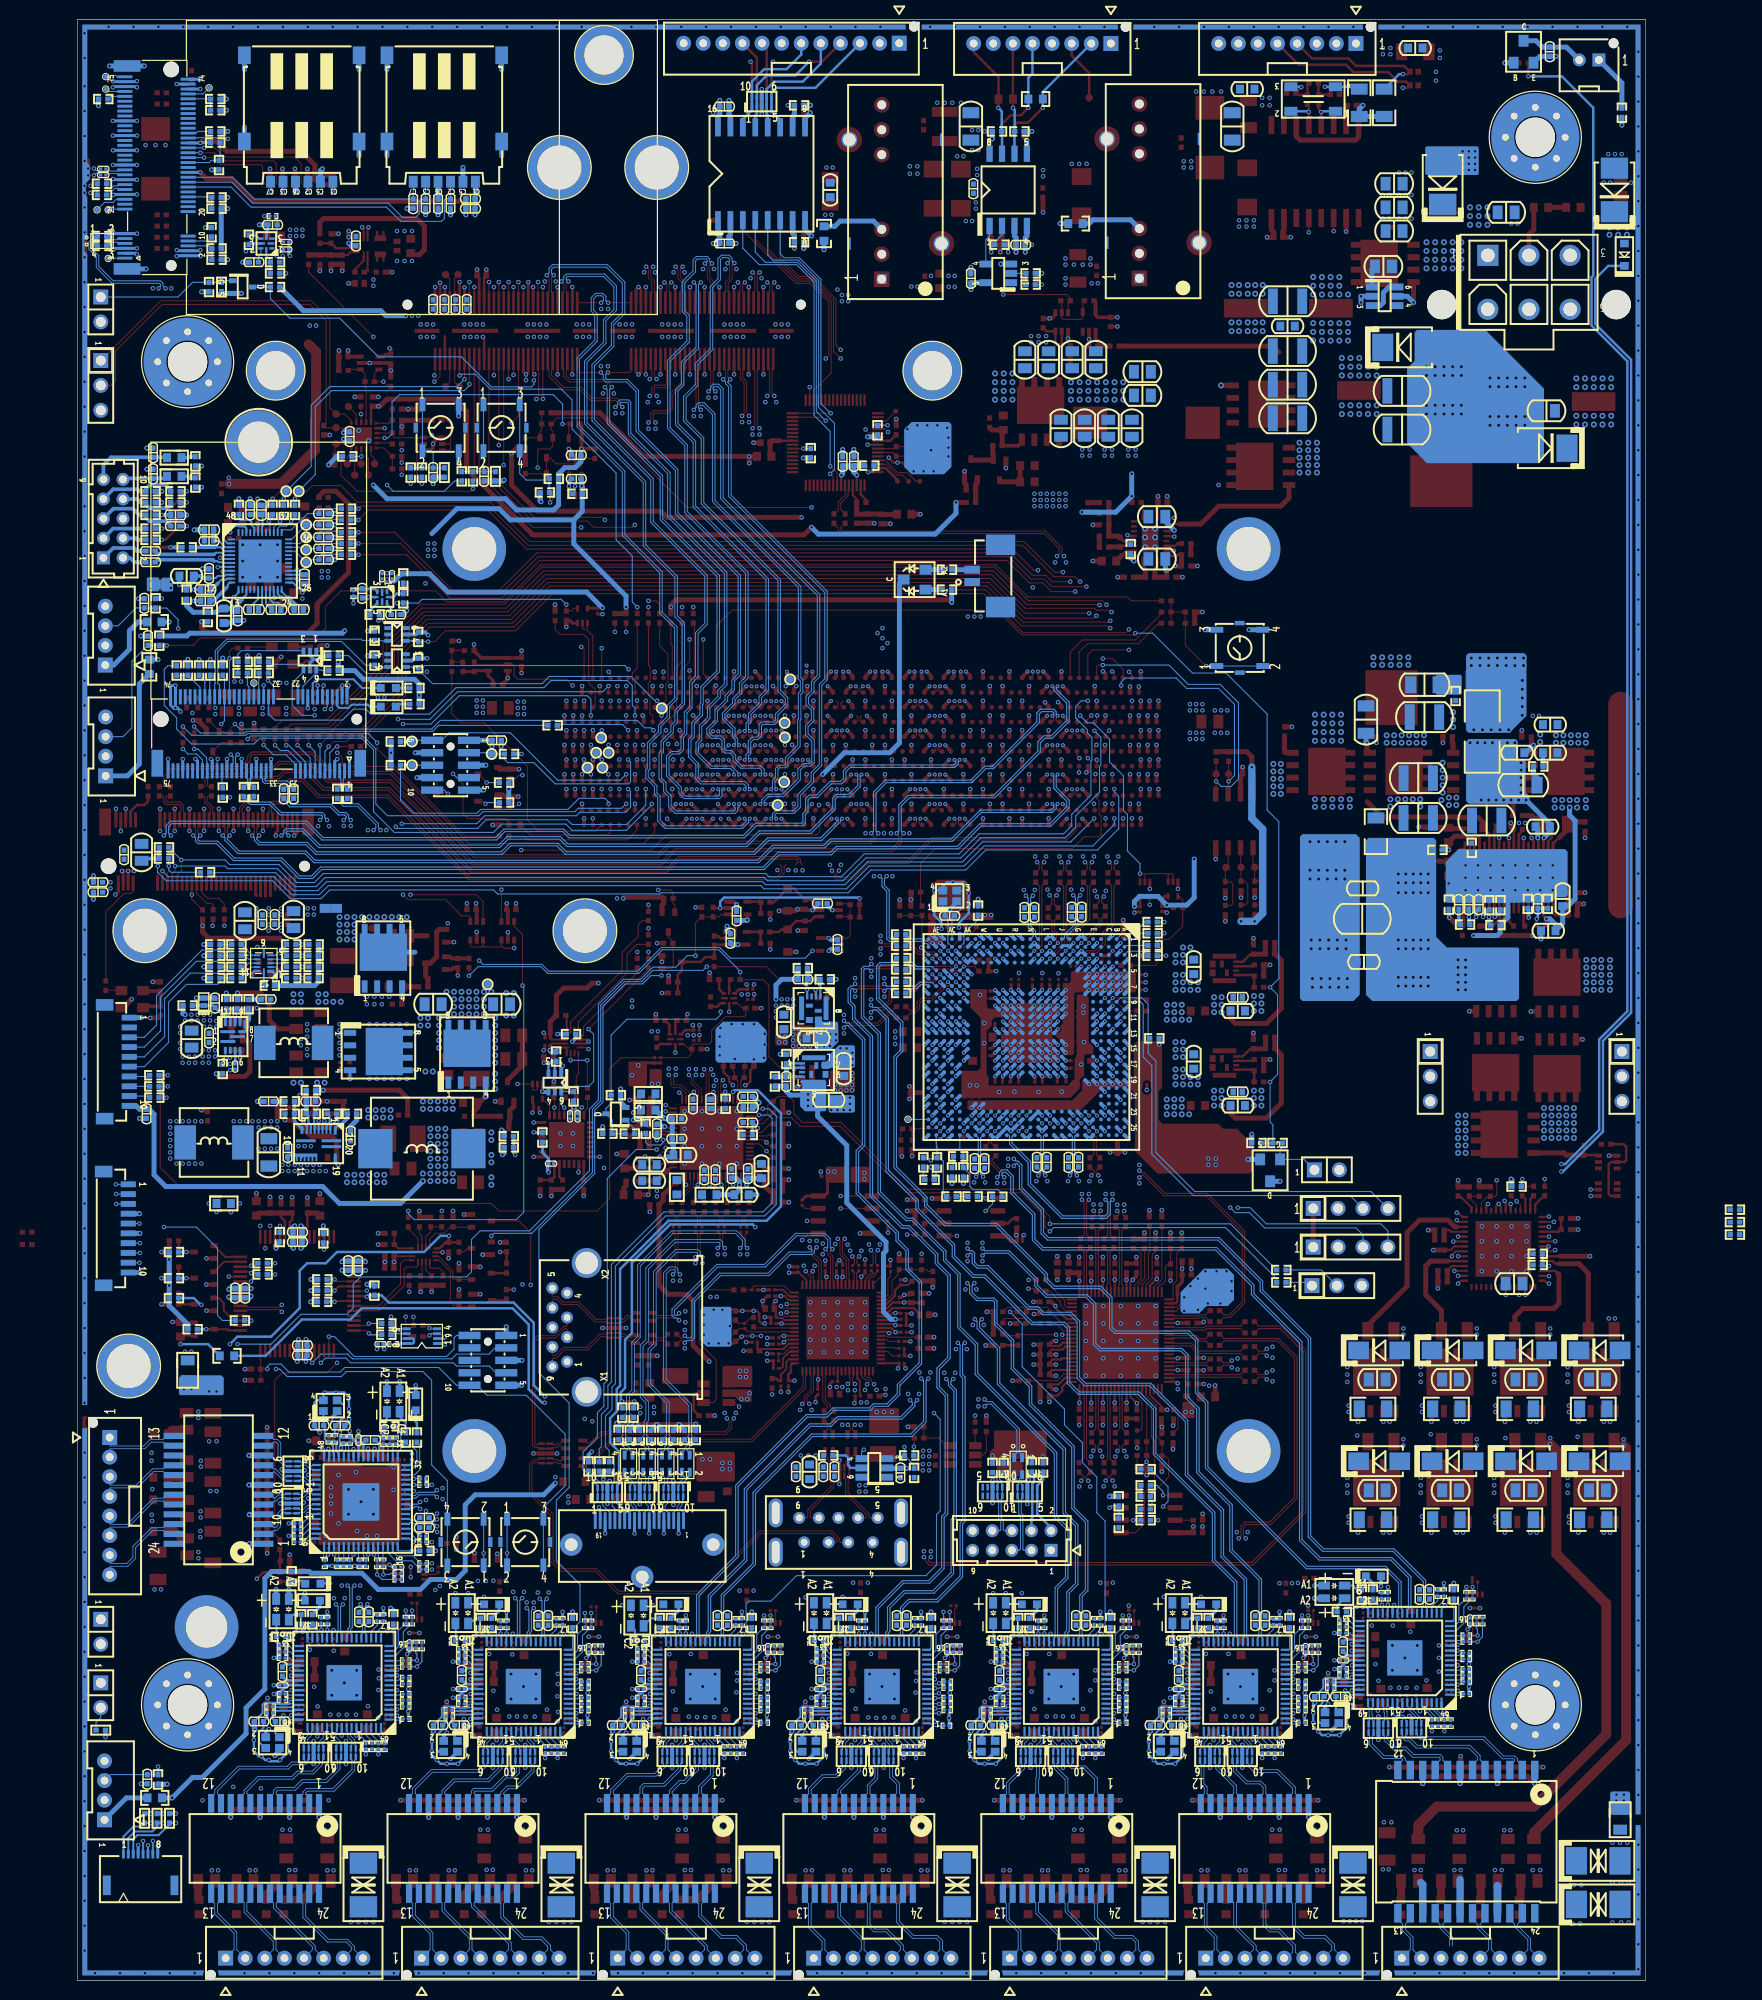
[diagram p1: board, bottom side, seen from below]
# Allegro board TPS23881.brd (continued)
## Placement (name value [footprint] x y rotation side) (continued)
NOREF#4835  -  []  52.2 58.55 270 top
NOREF#4836  -  []  75.06 23.76 270 top
NOREF#4837  -  []  76.1 37.52 0 top
NOREF#4838  -  []  138 17.09 90 top
NOREF#4839  -  []  134.47 76.63 0 top
NOREF#4840  -  []  91.39 30.47 90 top
NOREF#4841  -  []  140.02 89.66 0 top
NOREF#4842  -  []  156.87 191.9 0 top
NOREF#4843  -  []  88.27 33.52 90 top
NOREF#4844  -  []  74.96 108.61 90 top
NOREF#4845  -  []  135.41 105.66 0 top
NOREF#4846  -  []  99.01 138 0 top
NOREF#4847  -  []  58.09 93.8 0 top
NOREF#4848  -  []  42.55 125.32 270 top
NOREF#4849  -  []  45.52 140.03 0 top
NOREF#4850  -  []  28.05 199.26 0 top
NOREF#4851  -  []  63.68 109.74 270 top
NOREF#4852  -  []  91.39 31.51 0 top
NOREF#4853  -  []  66.88 27.06 0 top
NOREF#4854  -  []  14.83 107.65 0 top
NOREF#4855  -  []  107.43 36.63 270 top
NOREF#4856  -  []  141.22 103.89 270 top
NOREF#4857  -  []  134.86 49.15 0 top
NOREF#4858  -  []  157.81 74.05 90 top
NOREF#4859  -  []  126.95 42.3 0 top
NOREF#4860  -  []  127.37 54.69 90 top
NOREF#4861  -  []  75.72 52.58 0 top
NOREF#4862  -  []  35.05 36.59 270 top
NOREF#4863  -  []  140.03 27.8 0 top
NOREF#4864  -  []  62.48 112.99 270 top
NOREF#4865  -  []  39.45 110.69 0 top
NOREF#4866  -  []  67.67 110.06 0 top
NOREF#4867  -  []  22.35 38.56 90 top
NOREF#4868  -  []  138.91 74.88 0 top
NOREF#4869  -  []  126.19 26.53 0 top
NOREF#4870  -  []  139.37 122.1 270 top
NOREF#4871  -  []  61.09 83.91 270 top
NOREF#4872  -  []  45.76 60.83 0 top
NOREF#4873  -  []  67.01 65.48 90 top
NOREF#4874  -  []  54.15 72.17 90 top
NOREF#4875  -  []  34.91 36.63 0 top
NOREF#4876  -  []  138.76 120.47 0 top
NOREF#4877  -  []  67.84 108.94 0 top
NOREF#4878  -  []  135.25 183.13 90 top
NOREF#4879  -  []  137.69 102.23 0 top
NOREF#4880  -  []  53.04 77.81 270 top
NOREF#4881  -  []  10.69 66.24 0 top
NOREF#4882  -  []  93.68 107.11 270 top
NOREF#4883  -  []  158.39 111.76 90 top
NOREF#4884  -  []  85.42 176.86 0 top
NOREF#4885  -  []  132.07 42.24 0 top
NOREF#4886  -  []  72.11 82.09 0 top
NOREF#4887  -  []  76.89 99.75 270 top
NOREF#4888  -  []  140.16 71.58 0 top
NOREF#4889  -  []  61.04 168.1 90 top
NOREF#4890  -  []  22.76 40.18 0 top
NOREF#4891  -  []  134.35 37.01 270 top
NOREF#4892  -  []  98.95 34.47 270 top
NOREF#4893  -  []  51.94 52.58 270 top
NOREF#4894  -  []  140.59 103.89 270 top
NOREF#4895  -  []  67.13 84.12 270 top
NOREF#4896  -  []  84.51 33.92 270 top
NOREF#4897  -  []  83.9 51.42 90 top
NOREF#4898  -  []  73.69 83.92 270 top
NOREF#4899  -  []  126.67 78.28 270 top
NOREF#4900  -  []  50.06 46.51 0 top
NOREF#4901  -  []  137.39 89.23 0 top
NOREF#4902  -  []  143.23 100.51 0 top
NOREF#4903  -  []  60.78 59.39 0 top
NOREF#4904  -  []  66.87 5.46 270 top
NOREF#4905  -  []  39.57 36.2 90 top
NOREF#4906  -  []  39.45 65.61 0 top
NOREF#4907  -  []  135.36 89.36 90 top
NOREF#4908  -  []  94.69 17.09 90 top
NOREF#4909  -  []  149.66 75.44 0 top
NOREF#4910  -  []  19.8 33.6 0 top
NOREF#4911  -  []  6.63 108.36 0 top
NOREF#4912  -  []  66.88 94.31 0 top
NOREF#4913  -  []  125.96 88.57 0 top
NOREF#4914  -  []  75.06 18.41 270 top
NOREF#4915  -  []  55.31 103.92 0 top
NOREF#4916  -  []  149.66 127.69 270 top
NOREF#4917  -  []  126.23 27.94 0 top
NOREF#4918  -  []  116.61 132.21 0 top
NOREF#4919  -  []  125.81 76.4 0 top
NOREF#4920  -  []  116.41 17.09 90 top
NOREF#4921  -  []  148.59 130.81 270 top
NOREF#4922  -  []  94.97 100.76 0 top
NOREF#4923  -  []  134.67 126.44 90 top
NOREF#4924  -  []  137.85 43.26 0 top
NOREF#4925  -  []  40.31 112.57 270 top
NOREF#4926  -  []  128 30.99 0 top
NOREF#4927  -  []  115.49 86.11 0 top
NOREF#4928  -  []  63.82 91.68 0 top
NOREF#4929  -  []  56.85 37.2 90 top
NOREF#4930  -  []  149.39 12.68 90 top
NOREF#4931  -  []  123.77 100.91 0 top
NOREF#4932  -  []  57.48 73.46 0 top
NOREF#4933  -  []  131.97 141.78 270 top
NOREF#4934  -  []  19.99 38.43 90 top
NOREF#4935  -  []  73.1 31.51 270 top
NOREF#4936  -  []  140.08 184.15 270 top
NOREF#4937  -  []  120.27 171.41 270 top
NOREF#4938  -  []  134.06 145.75 90 top
NOREF#4939  -  []  56.26 73.46 0 top
NOREF#4940  -  []  120.52 30.61 90 top
NOREF#4941  -  []  18.75 108.92 90 top
NOREF#4942  -  []  146.47 140.72 0 top
NOREF#4943  -  []  140.59 45.85 90 top
NOREF#4944  -  []  120.51 33.15 0 top
NOREF#4945  -  []  53.21 57.28 90 top
NOREF#4946  -  []  73.38 110.03 0 top
NOREF#4947  -  []  145 109.21 270 top
NOREF#4948  -  []  145.31 181.86 0 top
NOREF#4949  -  []  142.62 70.61 270 top
NOREF#4950  -  []  72.11 81.23 0 top
NOREF#4951  -  []  120.62 75.74 270 top
NOREF#4952  -  []  60.71 34.43 270 top
NOREF#4953  -  []  134.37 131.32 270 top
NOREF#4954  -  []  102.23 30.61 90 top
NOREF#4955  -  []  39.9 61.09 0 top
NOREF#4956  -  []  54.43 151.05 270 top
NOREF#4957  -  []  134.85 47.62 0 top
NOREF#4958  -  []  152.86 141.27 0 top
NOREF#4959  -  []  149.86 134.09 270 top
NOREF#4960  -  []  55.63 72.14 90 top
NOREF#4961  -  []  17.13 37.01 0 top
NOREF#4962  -  []  57.53 17.44 90 top
NOREF#4963  -  []  36.53 30.47 90 top
NOREF#4964  -  []  54.18 45.72 90 top
NOREF#4965  -  []  34.79 29.84 0 top
NOREF#4966  -  []  131.57 36.27 90 top
NOREF#4967  -  []  134.49 36.97 270 top
NOREF#4968  -  []  136.27 184.15 270 top
NOREF#4969  -  []  110.36 25.26 90 top
NOREF#4970  -  []  41.77 94.24 270 top
NOREF#4971  -  []  2.03 10.29 0 top
NOREF#4972  -  []  121.08 33.64 90 top
NOREF#4973  -  []  126.7 139.62 0 top
NOREF#4974  -  []  12.14 79.58 90 top
NOREF#4975  -  []  87.3 176.86 90 top
NOREF#4976  -  []  62.48 112.98 90 top
NOREF#4977  -  []  126.44 153.75 0 top
NOREF#4978  -  []  30.56 31.25 0 top
NOREF#4979  -  []  138.8 28.57 0 top
NOREF#4980  -  []  91.43 30.61 0 top
NOREF#4981  -  []  122.25 170.13 0 top
NOREF#4982  -  []  137.11 90.37 90 top
NOREF#4983  -  []  129.55 36.65 90 top
NOREF#4984  -  []  96.14 197.59 0 top
NOREF#4985  -  []  127.01 139.07 90 top
NOREF#4986  -  []  40.39 17.44 90 top
NOREF#4987  -  []  34.79 31.62 0 top
NOREF#4988  -  []  43 64.34 0 top
NOREF#4989  -  []  107.94 28.19 0 top
NOREF#4990  -  []  61.47 51.84 90 top
NOREF#4991  -  []  140.15 177.66 270 top
NOREF#4992  -  []  146.47 141.86 0 top
NOREF#4993  -  []  132.67 56.34 90 top
NOREF#4994  -  []  107.57 32.14 90 top
NOREF#4995  -  []  6.3 154.25 90 top
NOREF#4996  -  []  62.81 176.61 0 top
NOREF#4997  -  []  146.61 122.1 270 top
NOREF#4998  -  []  58.04 57.28 90 top
NOREF#4999  -  []  92.57 23.8 270 top
NOREF#5000  -  []  99.44 35.97 90 top
NOREF#5001  -  []  36.6 84.99 0 top
NOREF#5002  -  []  15.95 109.19 90 top
NOREF#5003  -  []  86.87 0.16 90 top
NOREF#5004  -  []  138.84 107.7 90 top
NOREF#5005  -  []  12.39 21.79 90 top
NOREF#5006  -  []  108.03 60.04 90 top
NOREF#5007  -  []  95.86 109.91 0 top
NOREF#5008  -  []  40.64 18.41 90 top
NOREF#5009  -  []  132.66 174.7 0 top
NOREF#5010  -  []  71.63 36.59 270 top
NOREF#5011  -  []  54.76 148.46 0 top
NOREF#5012  -  []  119.63 153.9 270 top
NOREF#5013  -  []  60.78 67.89 0 top
NOREF#5014  -  []  138.94 120.56 90 top
NOREF#5015  -  []  27.94 12.52 0 top
NOREF#5016  -  []  17.65 35.34 0 top
NOREF#5017  -  []  124.58 42.41 0 top
NOREF#5018  -  []  125.02 45.2 90 top
NOREF#5019  -  []  20.09 75.08 0 top
NOREF#5020  -  []  123.52 76.4 90 top
NOREF#5021  -  []  110.63 36.27 90 top
NOREF#5022  -  []  43.38 123.9 0 top
NOREF#5023  -  []  62.18 51.38 0 top
NOREF#5024  -  []  17.91 54.14 0 top
NOREF#5025  -  []  124.41 50.41 90 top
NOREF#5026  -  []  18.95 131.95 0 top
NOREF#5027  -  []  145.31 176.66 0 top
NOREF#5028  -  []  57.48 71.83 90 top
NOREF#5029  -  []  0 0 0 top
NOREF#5030  -  []  133.3 156.01 0 top
NOREF#5031  -  []  150.99 99.86 0 top
NOREF#5032  -  []  128.24 141.1 0 top
NVMH1  STANDOFF-M3X6.6-W-update  [HOLEC256D177-PT]  40.5 146 0 top
NVMH2  STANDOFF-M3X6.6-W-update  [HOLEC256D177-PT]  119.5 146 0 top
NVMH3  STANDOFF-M3X6.6-W-update  [HOLEC256D177-PT]  40.5 54 0 top
NVMH4  STANDOFF-M3X6.6-W-update  [HOLEC256D177-PT]  119.5 54 0 top
OOB1  WF100-10/BM10B-SRSS-TB  [WF100S-10P-BM10B-SRSS]  154.7 93.7 270 bottom
OOBMH1  3525031514600P  [HOLEC256D177-PT]  108.21 107.07 180 bottom
OOBMH2  3525031514600P  [HOLEC256D177-PT]  153.11 107.07 180 bottom
OOBMH3  3525031514600P  [HOLEC256D177-PT]  154.76 62.67 180 bottom
PL1  IHLP2525/1UH  [IHLP2525_LS-030]  146.05 85.47 180 bottom
PL2  SMPI1004HW/1UH  [IHLP4040-S_LS-040]  124.84 84.84 180 bottom
PL3  SPM0630T/1.5UH  [IHLP2525_LS-030]  137.92 95.63 180 bottom
PL4  GSTC135P/6.8UH  [IHLP5050-S_LS-050]  50.93 158.88 0 top
PLED1  LED0603-Y  [SM0603_LED]  135.97 40.46 0 bottom
POE1  WF200-8/B08B-PASK(LF)(SN)  [WF200D-8P-PASK]  24.87 2.26 0 bottom
POE2  WF200-8/B08B-PASK(LF)(SN)  [WF200D-8P-PASK]  44.87 2.26 0 bottom
POE3  WF200-8/B08B-PASK(LF)(SN)  [WF200D-8P-PASK]  64.87 2.26 0 bottom
POE4  WF200-8/B08B-PASK(LF)(SN)  [WF200D-8P-PASK]  84.87 2.26 0 bottom
POE5  WF200-8/B08B-PASK(LF)(SN)  [WF200D-8P-PASK]  104.87 2.26 0 bottom
POE6  WF200-8/B08B-PASK(LF)(SN)  [WF200D-8P-PASK]  124.87 2.26 0 bottom
POE7  WF200-8/B08B-PASK(LF)(SN)  [WF200D-8P-PASK]  144.87 2.26 0 bottom
POE8  WF200-8/B08B-PASK(LF)(SN)  [WF200D-8P-PASK]  156.7 55.37 90 bottom
POESLT1  PH254-3X1  [CONHD3X1]  21.97 94.74 270 bottom
POESLT2  PH254-3X1  [CONHD3X1]  2.41 94.74 270 bottom
PSON1  SW-STS-05-A  [SWTS5X5_STS05]  116.71 158.37 180 bottom
PSON2  SW-STS-05-A  [SWTS5X5_STS05]  122.94 158.37 180 bottom
PSON3  SW-STS-05-A  [SWTS5X5_STS05]  41.4 135.92 90 bottom
PWRBTN1  WF200-04/CI0104P1VK0  [WF200D-4P]  157.23 16.38 270 bottom
Q2  PJT138K  [SOT363]  123.7 156.72 270 top
Q3  BSS138BKW  [SOT323-GSD]  99.34 103.89 90 top
Q4  BSS138BKW  [SOT323-GSD]  112.14 152.65 0 top
Q5  BSS138BKW  [SOT323-GSD]  112.14 156.34 180 top
Q6  BSS138BKW  [SOT323-GSD]  147.07 68.96 270 top
Q7  BSS138BKW  [SOT323-GSD]  147.07 71.63 270 top
Q8  BSS138BKW  [SOT323-GSD]  147.07 74.3 270 top
Q10  BSS138BKW  [SOT323-GSD]  147.07 66.42 90 top
Q11  BSS138BKW  [SOT323-GSD]  118.75 69.34 90 top
Q12  BSS138BKW  [SOT323-GSD]  118.77 77.47 90 top
Q13  BSS138BKW  [SOT323-GSD]  118.77 72.14 90 top
Q14  BSS138BKW  [SOT323-GSD]  118.77 74.68 270 top
Q15  PMBT3904,215  [SOT23-BEC]  12.45 196.72 180 bottom
Q17  BSS138BKW  [SOT323-GSD]  146.18 126.36 180 top
Q19  BSS138BKW  [SOT323-GSD]  136.04 41.15 90 top
Q20  PDC8974X  [POWERPAK-SO8]  4.95 50.27 0 top
Q21  PDC8974X  [POWERPAK-SO8]  12.45 50.27 0 top
Q22  PDC8974X  [POWERPAK-SO8]  4.95 61.57 0 top
Q23  PDC8974X  [POWERPAK-SO8]  12.45 61.57 0 top
Q24  PDC8974X  [POWERPAK-SO8]  19.94 50.27 0 top
Q25  PDC8974X  [POWERPAK-SO8]  19.94 61.57 0 top
Q26  PDC8974X  [POWERPAK-SO8]  27.43 50.27 0 top
Q27  PDC8974X  [POWERPAK-SO8]  27.43 61.57 0 top
Q29  PDN3916S  [SOT23-GSD]  38.3 82.63 0 bottom
Q30  PDC09D8BX  [POWERPAK-SO8]  27.18 175.13 270 top
Q31  PDC2601X  [POWERPAK-SO8]  61.72 160.66 0 top
Q32  BSS138BKW  [SOT323-GSD]  65.91 154.05 180 top
Q33  PJT138K  [SOT363]  59.56 169.16 0 top
Q34  BSS138BKW  [SOT323-GSD]  68.83 154.18 0 top
Q36  PDC2601X  [POWERPAK-SO8]  120.24 95.08 180 bottom
Q37  BSS138BKW  [SOT323-GSD]  116.1 90.68 0 top
Q38  BSS138BKW  [SOT323-GSD]  115.98 85.98 0 top
Q39  PDC2601X  [POWERPAK-SO8]  128.68 94.74 270 bottom
Q40  PDC2601X  [POWERPAK-SO8]  128.78 104.88 180 bottom
Q41  BSS138BKW  [SOT323-GSD]  123.44 106.55 270 top
Q42  BSS138BKW  [SOT323-GSD]  123.44 103.76 270 top
Q43  PDC09C6BX  [POWERPAK-SO8]  38.61 160.78 90 top
Q44  PDC0982BX  [POWERPAK-SO8]  39.88 154.43 270 top
Q45  PDC0982BX  [POWERPAK-SO8]  8.13 123.32 90 top
Q46  PDC0982BX  [POWERPAK-SO8]  24.64 123.32 90 top
Q47  PDC0982BX  [POWERPAK-SO8]  16.13 123.32 90 top
Q48  PDC0982BX  [POWERPAK-SO8]  32.51 123.32 90 top
Q50  BSS138BKW  [SOT323-GSD]  99.69 107.95 180 top
Q51  PJT138K  [SOT363]  111.28 91.57 0 bottom
Q52  PJT138K  [SOT363]  136.27 134.62 0 bottom
Q53  PJT138K  [SOT363]  127.38 137.29 270 bottom
Q54  PJT138K  [SOT363]  127.38 134.62 90 bottom
Q55  BSS138BKW  [SOT323-GSD]  105.05 88.39 90 bottom
Q57  BSS138BKW  [SOT323-GSD]  118.11 120.27 270 top
Q58  BSS138BKW  [SOT323-GSD]  143.13 172.72 270 bottom
Q59  BSS138BKW  [SOT323-GSD]  118.11 123.06 270 top
Q63  PDC6901X  [POWERPAK-SO8]  15.37 102.36 0 top
Q64  PDC6901X  [POWERPAK-SO8]  9.02 92.48 180 top
Q65  PDC6901X  [POWERPAK-SO8]  14.94 86.31 270 top
Q66  2N7002DW  [SOT363]  3.85 83.47 90 top
Q67  PDC6901X  [POWERPAK-SO8]  9.03 102.34 0 top
Q68  PDC6901X  [POWERPAK-SO8]  15.3 92.58 180 top
Q69  2N7002DW  [SOT363]  3.85 80.66 90 top
R2  47K-R2  [SM0402_R]  99.72 105.79 0 top
R3  47K-R2  [SM0402_R]  99.69 110.36 0 top
R4  @4.7K-R2  [SM0402_R]  145.92 102.23 0 bottom
R5  @4.7K-R2  [SM0402_R]  135.89 102.23 180 bottom
R6  @4.7K-R2  [SM0402_R]  145.92 103.38 0 bottom
R7  @4.7K-R2  [SM0402_R]  135.89 104.52 180 bottom
R8  @4.7K-R2  [SM0402_R]  145.92 104.52 0 bottom
R9  @4.7K-R2  [SM0402_R]  135.89 103.38 180 bottom
R10  @4.7K-R2  [SM0402_R]  145.92 105.66 0 bottom
R11  @4.7K-R2  [SM0402_R]  135.89 105.66 180 bottom
R22  1K-1%-R2  [SM0402_R]  71.27 141.86 0 bottom
R23  1K-1%-R2  [SM0402_R]  71.27 143.89 0 bottom
R24  100K-1%-R2  [SM0402_R]  110.11 139.19 270 top
R29  100K-R2  [SM0402_R]  128.02 163.07 90 top
R31  100K-R2  [SM0402_R]  127.38 155.45 180 top
R36  @10K-R2  [SM0402_R]  127.38 160.27 180 top
R40  100K-R2  [SM0402_R]  99.21 100.71 180 top
R42  162K-1%-R2  [SM0402_R]  85.72 107.57 270 top
R43  100K-R2  [SM0402_R]  89.79 105.79 180 top
R46  100K-R2  [SM0402_R]  108.97 151.64 0 bottom
R48  @10K-R2  [SM0402_R]  109.22 158.75 0 top
R51  5.1K-1%-R2  [SM0402_R]  111.38 153.16 0 bottom
R56  330-1%-R2  [SM0402_R]  150.14 74.3 0 bottom
R57  330-1%-R2  [SM0402_R]  150.14 71.63 0 bottom
R58  330-1%-R2  [SM0402_R]  150.14 69.6 0 bottom
R61  @4.7K-1%-R2  [SM0402_R]  165.13 76.33 0 top
R62  @4.7K-1%-R2  [SM0402_R]  165.13 75.06 180 top
R63  100K-1%-R2  [SM0402_R]  150.14 68.96 0 top
R64  100K-1%-R2  [SM0402_R]  150.14 72.77 0 top
R65  100K-1%-R2  [SM0402_R]  150.14 75.44 0 top
R81  10K-1%-R2  [SM0402_R]  141.76 61.21 0 top
R84  270-1%-R3  [SM0603_R]  135.25 78.74 90 top
R85  10K-1%-R2  [SM0402_R]  148.23 66.42 0 bottom
R86  470K-1%-R3  [SM0603_R]  144.73 63.7 0 bottom
R87  47K-1%-R3  [SM0603_R]  149.48 66.42 90 top
R90  @8.2K-R2  [SM0402_R]  128.14 76.2 180 top
R91  8.2K-R2  [SM0402_R]  128.14 75.06 0 top
R92  @2.2K-R2  [SM0402_R]  42.55 124.84 270 top
R93  @2.2K-R2  [SM0402_R]  43.81 124.84 270 top
R98  @10K-R2  [SM0402_R]  39.88 109.22 90 top
R100  @10K-R2  [SM0402_R]  42.88 111.58 270 top
R101  @10K-R2  [SM0402_R]  41.27 111.63 270 top
R112  @10K-R2  [SM0402_R]  140.31 149.99 270 top
R114  @10K-R2  [SM0402_R]  143.51 149.99 270 bottom
R123  @2.2K-R2  [SM0402_R]  139.24 149.99 270 top
R124  @2.2K-R2  [SM0402_R]  138.18 149.99 270 top
R139  33-R2  [SM0402_R]  2.41 190.5 270 bottom
R141  47K-R2  [SM0402_R]  115.95 125.09 0 bottom
R142  47K-R2  [SM0402_R]  127.51 126.36 180 bottom
R143  47K-R2  [SM0402_R]  127.51 123.95 180 bottom
R144  47K-R2  [SM0402_R]  123.83 122.68 180 top
R145  47K-R2  [SM0402_R]  116.46 117.86 0 top
R155  100K-1%-R1  [SM0201_R]  89.1 70.43 180 top
R156  100K-1%-R1  [SM0201_R]  88.72 62.43 180 top
R157  100K-1%-R1  [SM0201_R]  75.9 64.47 0 top
R158  100K-1%-R1  [SM0201_R]  77.67 72.59 270 top
R159  1M-1%-R1  [SM0201_R]  91.9 66.75 270 top
R162  @30K-1%-R2  [SM0402_R]  72.72 71.83 270 top
R163  5.1K-1%-R2  [SM0402_R]  74.37 71.32 180 top
R164  @39K-1%-R2  [SM0402_R]  75.01 72.97 270 top
R165  510K-R2  [SM0402_R]  90.88 64.21 0 top
R166  100K-1%-R1  [SM0201_R]  88.72 63.2 180 top
R167  20K-1%-R1  [SM0201_R]  75.9 65.18 180 top
R168  @100K-1%-R1  [SM0201_R]  88.72 63.92 0 top
R170  287-1%-R2  [SM0402_R]  96.09 57.61 0 top
R171  287-1%-R2  [SM0402_R]  83.39 53.54 180 bottom
R172  @10K-R2  [SM0402_R]  79.2 154.51 0 bottom
R173  12K-1%-R2  [SM0402_R]  80.01 150.75 180 top
R174  @10K-R2  [SM0402_R]  78.36 158.12 270 bottom
R175  @10K-R2  [SM0402_R]  85.17 155.78 270 bottom
R176  470K-R2  [SM0402_R]  76.45 155.96 90 top
R177  0-R3  [SM0603_R]  83.82 178.18 270 bottom
R178  0-R6  [SM1206_R]  83.19 182.5 90 top
R181  287-1%-R2  [SM0402_R]  67.26 56.46 270 top
R187  @47K-R2  [SM0402_R]  133.86 135.13 0 bottom
R188  330-1%-R2  [SM0402_R]  125.6 130.18 0 bottom
R189  330-1%-R2  [SM0402_R]  125.6 131.83 0 bottom
R190  47K-R2  [SM0402_R]  133.86 133.6 180 bottom
R191  @47K-R2  [SM0402_R]  145.16 133.6 90 bottom
R192  47K-R2  [SM0402_R]  143.13 134.49 180 bottom
R193  @47K-R2  [SM0402_R]  140.97 134.49 0 bottom
R194  33-1%-R2  [SM0402_R]  143.13 135.89 0 top
R195  47K-R2  [SM0402_R]  148.72 133.6 90 bottom
R196  @47K-R2  [SM0402_R]  147.07 128.52 180 top
R197  47K-R2  [SM0402_R]  129.67 137.16 90 bottom
R198  47K-R2  [SM0402_R]  125.22 137.03 90 bottom
R199  47K-R2  [SM0402_R]  143.26 126.75 90 top
R200  47K-R2  [SM0402_R]  129.67 134.62 90 bottom
R201  47K-R2  [SM0402_R]  125.22 134.37 90 bottom
R202  100-R2  [SM0402_R]  129.67 139.32 180 bottom
R204  @10K-R2  [SM0402_R]  126.75 143 90 bottom
R210  @10K-1%-R2  [SM0402_R]  145.8 175.51 180 bottom
R212  10K-1%-R2  [SM0402_R]  145.8 176.66 180 bottom
R213  10K-1%-R2  [SM0402_R]  146.3 178.31 90 bottom
R215  @10K-1%-R2  [SM0402_R]  145.8 181.86 180 bottom
R216  10K-1%-R2  [SM0402_R]  145.8 180.72 180 bottom
R221  10K-1%-R2  [SM0402_R]  145.92 188.59 180 bottom
R222  10K-1%-R2  [SM0402_R]  157.35 191.9 180 bottom
R223  @10K-R2  [SM0402_R]  139.83 175.26 180 bottom
R224  @100K-R2  [SM0402_R]  145.92 187.45 180 bottom
R225  @100K-R2  [SM0402_R]  145.92 190.75 0 bottom
R226  100-R2  [SM0402_R]  142.49 177.55 270 bottom
R227  100K-R2  [SM0402_R]  145.54 185.17 270 bottom
R228  100K-R2  [SM0402_R]  145.92 191.9 180 bottom
R230  330-R2  [SM0402_R]  138.13 41.22 270 bottom
R240  47K-R2  [SM0402_R]  120.02 135.64 180 top
R242  @2.2K-R2  [SM0402_R]  105.16 138.94 90 top
R243  @2.2K-R2  [SM0402_R]  104.01 138.94 90 top
R245  @10K-1%-R2  [SM0402_R]  135.25 175.51 90 top
R246  110K-1%-R2  [SM0402_R]  135.25 177.67 90 top
R247  30K-1%-R2  [SM0402_R]  134.11 177.67 270 top
R249  @120-R3  [SM0603_R]  65.28 191.9 0 top
R251  @120-R3  [SM0603_R]  62.23 191.9 180 bottom
R253  523-1%-R2  [SM0402_R]  63.88 188.59 180 top
R254  523-1%-R2  [SM0402_R]  66.17 188.59 180 top
R257  523-1%-R2  [SM0402_R]  66.17 188.59 0 bottom
R259  523-1%-R2  [SM0402_R]  63.88 188.59 0 bottom
R260  0-R3  [SM0603_R]  58.17 179.2 0 bottom
R261  0-R6  [SM1206_R]  40.51 190.37 270 top
R262  0-R6  [SM1206_R]  23.5 196.72 0 top
R264  59-1%-R6  [SM1206_R]  29.21 191.52 90 bottom
R265  @120-R2  [SM0402_R]  33.86 193.5 180 top
R267  59-1%-R6  [SM1206_R]  26.67 191.52 270 bottom
R269  1K-1%-R1  [SM0201_R]  26.29 39.24 270 bottom
R270  @1K-1%-R1  [SM0201_R]  26.42 37.08 270 top
R273  4.99K-1%-R2  [SM0402_R]  29.06 28.4 90 top
R274  @4.7K-1%-R2  [SM0402_R]  19.56 39.37 90 bottom
R275  3.3K-R1  [SM0201_R]  18.29 29.21 0 bottom
R276  3.3K-R1  [SM0201_R]  18.29 30.48 180 bottom
R277  3.3K-R1  [SM0201_R]  20.57 39.5 90 bottom
R278  3.3K-R1  [SM0201_R]  21.21 39.5 90 bottom
R279  3.3K-R1  [SM0201_R]  26.92 39.24 90 bottom
R280  @3.3K-R1  [SM0201_R]  27.18 37.08 270 top
R281  33-1%-R1  [SM0201_R]  18.29 34.54 0 bottom
R282  33-1%-R1  [SM0201_R]  18.29 35.18 0 bottom
R283  33-1%-R1  [SM0201_R]  17.65 39.24 270 bottom
R284  33-1%-R1  [SM0201_R]  18.29 39.24 270 bottom
R285  1M-R1  [SM0201_R]  32.13 29.84 180 bottom
R286  330-R2  [SM0402_R]  27.81 39.37 270 bottom
R287  @33-1%-R1  [SM0201_R]  17.27 36.7 270 bottom
R288  330-R2  [SM0402_R]  28.96 39.37 270 bottom
R289  330-R2  [SM0402_R]  30.99 37.59 180 bottom
R290  33K-R1  [SM0201_R]  17.96 34.57 180 top
R291  @3.3K-R1  [SM0201_R]  16.64 36.7 90 bottom
R293  1K-1%-R1  [SM0201_R]  43.05 36.32 270 bottom
R294  4.99K-1%-R2  [SM0402_R]  45.82 25.48 90 top
R295  @1K-1%-R1  [SM0201_R]  43.18 34.16 270 top
R298  @4.7K-1%-R2  [SM0402_R]  36.32 36.45 90 bottom
R299  3.3K-R1  [SM0201_R]  35.05 26.29 0 bottom
R300  3.3K-R1  [SM0201_R]  35.05 27.56 180 bottom
R301  3.3K-R1  [SM0201_R]  37.34 36.58 90 bottom
R302  3.3K-R1  [SM0201_R]  37.97 36.58 90 bottom
R303  3.3K-R1  [SM0201_R]  43.69 36.32 90 bottom
R304  @3.3K-R1  [SM0201_R]  43.94 34.16 270 top
R305  33-1%-R1  [SM0201_R]  35.05 31.62 0 bottom
R306  33-1%-R1  [SM0201_R]  35.05 32.26 0 bottom
R307  33-1%-R1  [SM0201_R]  34.42 36.32 270 bottom
R308  33-1%-R1  [SM0201_R]  35.05 36.32 270 bottom
R309  1M-R1  [SM0201_R]  48.9 26.92 180 bottom
R310  330-R2  [SM0402_R]  44.58 36.45 270 bottom
R311  @33-1%-R1  [SM0201_R]  34.04 33.78 270 bottom
R312  330-R2  [SM0402_R]  45.72 36.45 270 bottom
R313  330-R2  [SM0402_R]  47.75 34.67 180 bottom
R314  33K-R1  [SM0201_R]  34.72 31.65 180 top
R315  @3.3K-R1  [SM0201_R]  33.4 33.78 90 bottom
R317  1K-1%-R1  [SM0201_R]  61.34 36.32 270 bottom
R318  @1K-1%-R1  [SM0201_R]  61.47 34.16 270 top
R321  4.99K-1%-R2  [SM0402_R]  64.11 25.48 90 top
R322  @4.7K-1%-R2  [SM0402_R]  54.61 36.45 90 bottom
R323  3.3K-R1  [SM0201_R]  53.34 26.29 0 bottom
R324  3.3K-R1  [SM0201_R]  53.34 27.56 180 bottom
R325  3.3K-R1  [SM0201_R]  55.63 36.58 90 bottom
R326  3.3K-R1  [SM0201_R]  56.26 36.58 90 bottom
R327  3.3K-R1  [SM0201_R]  61.98 36.32 90 bottom
R328  @3.3K-R1  [SM0201_R]  62.23 34.16 270 top
R329  33-1%-R1  [SM0201_R]  53.34 31.62 0 bottom
R330  33-1%-R1  [SM0201_R]  53.34 32.26 0 bottom
R331  33-1%-R1  [SM0201_R]  52.7 36.32 270 bottom
R332  33-1%-R1  [SM0201_R]  53.34 36.32 270 bottom
R333  330-R2  [SM0402_R]  62.87 36.45 270 bottom
R334  1M-R1  [SM0201_R]  67.18 26.92 180 bottom
R335  @33-1%-R1  [SM0201_R]  52.32 33.78 270 bottom
R336  330-R2  [SM0402_R]  64.01 36.45 270 bottom
R337  330-R2  [SM0402_R]  66.04 34.67 180 bottom
R338  33K-R1  [SM0201_R]  53.01 31.65 180 top
R339  @3.3K-R1  [SM0201_R]  51.69 33.78 90 bottom
R341  1K-1%-R1  [SM0201_R]  79.63 36.32 270 bottom
R342  4.99K-1%-R2  [SM0402_R]  82.4 25.48 90 top
R343  @1K-1%-R1  [SM0201_R]  79.76 34.16 270 top
R346  @4.7K-1%-R2  [SM0402_R]  72.9 36.45 90 bottom
R347  3.3K-R1  [SM0201_R]  71.32 25.98 0 bottom
R348  3.3K-R1  [SM0201_R]  71.25 27.56 180 bottom
R349  3.3K-R1  [SM0201_R]  73.91 36.58 90 bottom
R350  3.3K-R1  [SM0201_R]  74.55 36.58 90 bottom
R351  3.3K-R1  [SM0201_R]  80.26 36.32 90 bottom
R352  @3.3K-R1  [SM0201_R]  80.52 34.16 270 top
R353  33-1%-R1  [SM0201_R]  71.63 31.62 0 bottom
R354  33-1%-R1  [SM0201_R]  71.63 32.26 0 bottom
R355  33-1%-R1  [SM0201_R]  70.99 36.32 270 bottom
R356  330-R2  [SM0402_R]  81.15 36.45 270 bottom
R357  33-1%-R1  [SM0201_R]  71.63 36.32 270 bottom
R358  1M-R1  [SM0201_R]  85.47 26.92 180 bottom
R359  @33-1%-R1  [SM0201_R]  70.61 33.78 270 bottom
R360  330-R2  [SM0402_R]  82.3 36.45 270 bottom
R361  330-R2  [SM0402_R]  84.33 34.67 180 bottom
R362  33K-R1  [SM0201_R]  71.3 31.65 180 top
R363  @3.3K-R1  [SM0201_R]  69.98 33.78 90 bottom
R364  1K-1%-R1  [SM0201_R]  97.92 36.32 270 bottom
R366  @1K-1%-R1  [SM0201_R]  98.04 34.16 270 top
R369  4.99K-1%-R2  [SM0402_R]  100.69 25.48 90 top
R370  @4.7K-1%-R2  [SM0402_R]  91.19 36.45 90 bottom
R371  3.3K-R1  [SM0201_R]  89.92 26.29 0 bottom
R372  3.3K-R1  [SM0201_R]  89.92 27.56 180 bottom
R373  3.3K-R1  [SM0201_R]  92.2 36.58 90 bottom
R374  3.3K-R1  [SM0201_R]  92.84 36.58 90 bottom
R375  3.3K-R1  [SM0201_R]  98.55 36.32 90 bottom
R376  @3.3K-R1  [SM0201_R]  98.81 34.16 270 top
R377  33-1%-R1  [SM0201_R]  89.92 31.62 0 bottom
R378  33-1%-R1  [SM0201_R]  89.92 32.26 0 bottom
R379  33-1%-R1  [SM0201_R]  89.28 36.32 270 bottom
R380  33-1%-R1  [SM0201_R]  89.92 36.32 270 bottom
R381  330-R2  [SM0402_R]  99.44 36.45 270 bottom
R382  1M-R1  [SM0201_R]  103.76 26.92 180 bottom
R383  @33-1%-R1  [SM0201_R]  88.9 33.78 270 bottom
R384  330-R2  [SM0402_R]  100.58 36.45 270 bottom
R385  330-R2  [SM0402_R]  102.62 34.67 180 bottom
R386  33K-R1  [SM0201_R]  89.59 31.65 180 top
R387  @3.3K-R1  [SM0201_R]  88.27 33.78 90 bottom
R389  1K-1%-R1  [SM0201_R]  116.2 36.32 270 bottom
R390  @1K-1%-R1  [SM0201_R]  116.33 34.16 270 top
R393  4.99K-1%-R2  [SM0402_R]  118.97 25.48 90 top
R394  @4.7K-1%-R2  [SM0402_R]  109.47 36.45 90 bottom
R395  3.3K-R1  [SM0201_R]  108.2 26.29 0 bottom
R396  3.3K-R1  [SM0201_R]  108.2 27.56 180 bottom
R397  3.3K-R1  [SM0201_R]  110.49 36.58 90 bottom
R398  3.3K-R1  [SM0201_R]  116.84 36.32 90 bottom
R399  3.3K-R1  [SM0201_R]  111.12 36.58 90 bottom
R400  @3.3K-R1  [SM0201_R]  117.09 34.16 270 top
R401  33-1%-R1  [SM0201_R]  108.2 31.62 0 bottom
R402  33-1%-R1  [SM0201_R]  108.2 32.26 0 bottom
R403  33-1%-R1  [SM0201_R]  107.57 36.32 270 bottom
R404  33-1%-R1  [SM0201_R]  108.2 36.32 270 bottom
R405  330-R2  [SM0402_R]  117.73 36.45 270 bottom
R406  1M-R1  [SM0201_R]  122.05 26.92 180 bottom
R407  @33-1%-R1  [SM0201_R]  107.19 33.78 270 bottom
R408  330-R2  [SM0402_R]  118.87 36.45 270 bottom
R409  330-R2  [SM0402_R]  120.9 34.67 180 bottom
R410  33K-R1  [SM0201_R]  107.87 31.65 180 top
R411  @3.3K-R1  [SM0201_R]  106.55 33.78 90 bottom
R412  1K-1%-R1  [SM0201_R]  134.49 36.7 270 bottom
R414  @1K-1%-R1  [SM0201_R]  134.62 34.54 270 top
R417  4.99K-1%-R2  [SM0402_R]  137.26 25.86 90 top
R418  @4.7K-1%-R2  [SM0402_R]  127.76 36.83 90 bottom
R419  3.3K-R1  [SM0201_R]  126.49 26.67 0 bottom
R420  3.3K-R1  [SM0201_R]  126.49 27.94 180 bottom
R421  3.3K-R1  [SM0201_R]  128.78 36.96 90 bottom
R422  3.3K-R1  [SM0201_R]  129.41 36.96 90 bottom
R423  3.3K-R1  [SM0201_R]  135.13 36.7 90 bottom
R424  @3.3K-R1  [SM0201_R]  135.38 34.54 270 top
R425  33-1%-R1  [SM0201_R]  126.49 32 0 bottom
R426  33-1%-R1  [SM0201_R]  126.49 32.64 0 bottom
R427  33-1%-R1  [SM0201_R]  125.86 36.7 270 bottom
R428  33-1%-R1  [SM0201_R]  126.49 36.7 270 bottom
R429  330-R2  [SM0402_R]  136.02 36.83 270 bottom
R430  1M-R1  [SM0201_R]  140.34 27.3 180 bottom
R431  @33-1%-R1  [SM0201_R]  125.48 34.16 270 bottom
R432  330-R2  [SM0402_R]  137.16 36.83 270 bottom
R433  330-R2  [SM0402_R]  139.19 35.05 180 bottom
R434  33K-R1  [SM0201_R]  126.16 32.03 180 top
R435  @3.3K-R1  [SM0201_R]  124.84 34.16 90 bottom
R437  1K-1%-R1  [SM0201_R]  124.71 50.55 0 bottom
R438  @1K-1%-R1  [SM0201_R]  126.87 50.67 0 top
R441  4.99K-1%-R2  [SM0402_R]  135.56 53.31 180 top
R442  @4.7K-1%-R2  [SM0402_R]  124.59 43.81 180 bottom
R443  3.3K-R1  [SM0201_R]  134.75 42.55 90 bottom
R444  3.3K-R1  [SM0201_R]  133.48 42.55 270 bottom
R445  3.3K-R1  [SM0201_R]  124.71 44.7 180 bottom
R446  3.3K-R1  [SM0201_R]  124.71 51.18 180 bottom
R447  3.3K-R1  [SM0201_R]  124.71 45.34 180 bottom
R448  @3.3K-R1  [SM0201_R]  126.87 51.44 0 top
R449  33-1%-R1  [SM0201_R]  129.41 42.55 90 bottom
R450  33-1%-R1  [SM0201_R]  128.78 42.55 90 bottom
R451  33-1%-R1  [SM0201_R]  124.71 41.91 0 bottom
R452  33-1%-R1  [SM0201_R]  124.71 42.55 0 bottom
R453  1M-R1  [SM0201_R]  134.37 55.24 270 bottom
R454  330-R2  [SM0402_R]  125.35 55.37 270 bottom
R455  @33-1%-R1  [SM0201_R]  127.25 41.53 0 bottom
R456  330-R2  [SM0402_R]  126.49 55.37 270 bottom
R457  330-R2  [SM0402_R]  128.17 56.52 180 bottom
R458  33K-R1  [SM0201_R]  129.39 42.21 270 top
R459  @3.3K-R1  [SM0201_R]  127.25 40.89 180 bottom
R460  75-1%-R3  [SM0603_R]  24.97 7.44 90 top
R461  75-1%-R3  [SM0603_R]  20.9 7.44 90 top
R462  75-1%-R3  [SM0603_R]  16.84 7.44 90 top
R463  75-1%-R3  [SM0603_R]  12.9 7.44 90 top
R464  75-1%-R3  [SM0603_R]  46.61 7.49 90 top
R465  75-1%-R3  [SM0603_R]  42.8 7.49 90 top
R466  75-1%-R3  [SM0603_R]  38.86 7.49 90 top
R467  75-1%-R3  [SM0603_R]  34.92 7.49 90 top
R468  75-1%-R3  [SM0603_R]  66.8 7.49 90 top
R469  75-1%-R3  [SM0603_R]  62.99 7.49 90 top
R470  75-1%-R3  [SM0603_R]  59.94 7.49 90 top
R471  75-1%-R3  [SM0603_R]  58.17 7.49 90 top
R472  75-1%-R3  [SM0603_R]  87 7.49 90 top
R473  75-1%-R3  [SM0603_R]  83.19 7.49 90 top
R474  75-1%-R3  [SM0603_R]  80.14 7.49 90 top
R475  75-1%-R3  [SM0603_R]  78.36 7.49 90 top
R476  75-1%-R3  [SM0603_R]  107.19 7.49 90 top
R477  75-1%-R3  [SM0603_R]  103.38 7.49 90 top
R478  75-1%-R3  [SM0603_R]  100.33 7.49 90 top
R479  75-1%-R3  [SM0603_R]  98.55 7.49 90 top
R480  75-1%-R3  [SM0603_R]  127.38 7.49 90 top
R481  75-1%-R3  [SM0603_R]  123.57 7.49 90 top
R482  75-1%-R3  [SM0603_R]  120.52 7.49 90 top
R483  75-1%-R3  [SM0603_R]  118.75 7.49 90 top
R484  75-1%-R3  [SM0603_R]  147.57 7.49 90 top
R485  75-1%-R3  [SM0603_R]  143.76 7.49 90 top
R486  75-1%-R3  [SM0603_R]  140.72 7.49 90 top
R487  75-1%-R3  [SM0603_R]  138.94 7.49 90 top
R488  75-1%-R3  [SM0603_R]  151.51 55.75 180 top
R489  75-1%-R3  [SM0603_R]  151.51 51.31 180 top
R490  75-1%-R3  [SM0603_R]  151.51 49.02 180 top
R491  75-1%-R3  [SM0603_R]  151.51 45.8 180 top
R496  0.2-1%-R6  [SM1206_R]  5.33 46.99 180 bottom
R497  0.2-1%-R6  [SM1206_R]  12.83 46.99 180 bottom
R498  0.2-1%-R6  [SM1206_R]  5.33 58.29 180 bottom
R499  0.2-1%-R6  [SM1206_R]  12.83 58.29 180 bottom
R500  0.2-1%-R6  [SM1206_R]  20.32 46.99 180 bottom
R501  0.2-1%-R6  [SM1206_R]  20.32 58.29 180 bottom
R502  0.2-1%-R6  [SM1206_R]  27.81 46.99 180 bottom
R503  0.2-1%-R6  [SM1206_R]  27.81 58.29 180 bottom
R504  1M-R2  [SM0402_R]  102.01 86.87 90 bottom
R505  499-1%-R2  [SM0402_R]  96.9 55.63 90 bottom
R506  499-1%-R2  [SM0402_R]  100.33 55.63 90 bottom
R507  499-1%-R2  [SM0402_R]  102.62 55.63 90 bottom
R508  499-1%-R2  [SM0402_R]  98.04 55.63 90 bottom
R509  2.2K-1%-R2  [SM0402_R]  102.11 86.11 180 top
R510  499-1%-R2  [SM0402_R]  99.19 55.63 90 bottom
R511  499-1%-R2  [SM0402_R]  101.47 55.63 90 bottom
R512  6.8K-1%-R2  [SM0402_R]  103.53 81.53 0 top
R513  499-1%-R2  [SM0402_R]  103.63 55.63 90 bottom
R514  499-1%-R2  [SM0402_R]  104.78 55.63 90 bottom
R515  10K-1%-R2  [SM0402_R]  93.85 89.41 270 bottom
R516  6.2-R2  [SM0402_R]  99.39 78.88 270 top
R517  6.2-R2  [SM0402_R]  98.3 78.87 270 top
R518  6.2-R2  [SM0402_R]  97.16 78.87 270 top
R519  47K-R2  [SM0402_R]  107.85 52.43 270 bottom
R520  6.2-R2  [SM0402_R]  96.01 78.87 270 top
R521  6.2-R2  [SM0402_R]  94.87 78.87 270 top
R522  6.2-R2  [SM0402_R]  93.73 78.87 270 top
R523  6.2-R2  [SM0402_R]  92.58 78.87 270 top
R524  6.2-R2  [SM0402_R]  91.44 78.87 270 top
R525  1M-1%-R2  [SM0402_R]  92.46 92.08 180 top
R526  10K-1%-R2  [SM0402_R]  104.39 57.91 270 bottom
R527  10K-1%-R2  [SM0402_R]  103.25 57.91 270 bottom
R528  0-R6  [SM1206_R]  95.83 50.75 270 top
R529  1M-R2  [SM0402_R]  91.59 86.23 180 bottom
R530  2K-1%-R2  [SM0402_R]  105.74 52.43 90 bottom
R531  2K-1%-R2  [SM0402_R]  106.76 52.43 90 bottom
R532  2K-1%-R2  [SM0402_R]  88.52 89.66 180 top
R533  2K-1%-R2  [SM0402_R]  88.52 88.52 180 top
R534  4.7K-1%-R2  [SM0402_R]  88.52 81.66 180 top
R535  2K-1%-R2  [SM0402_R]  88.52 87.38 0 top
R536  2K-1%-R2  [SM0402_R]  88.52 86.23 0 top
R537  2K-1%-R2  [SM0402_R]  88.52 85.09 0 top
R538  2K-1%-R2  [SM0402_R]  88.52 83.95 0 top
R539  1K-1%-R2  [SM0402_R]  88.54 79.38 180 top
R540  20K-1%-R2  [SM0402_R]  105.92 86.36 0 bottom
R541  @7.5K-1%-R2  [SM0402_R]  105.05 90.3 0 bottom
R558  12.1K-1%-R2  [SM0402_R]  68.1 109.12 90 bottom
R559  12.1K-1%-R2  [SM0402_R]  56.72 94.28 90 top
R560  47K-1%-R2  [SM0402_R]  47.7 109.42 180 top
R561  10K-1%-R2  [SM0402_R]  76.1 109.09 270 top
R562  @1K-R2  [SM0402_R]  74.96 109.09 90 top
R563  @4.7K-R2  [SM0402_R]  53.04 103.53 0 top
R565  1K-R2  [SM0402_R]  74.45 111 180 top
R566  4.7K-R2  [SM0402_R]  69.42 108 90 top
R567  4.7K-R2  [SM0402_R]  71.2 108.03 90 top
R568  4.7K-R2  [SM0402_R]  67.51 102.95 180 top
R569  4.7K-R2  [SM0402_R]  67.51 104.09 180 top
R570  4.7K-R2  [SM0402_R]  51.38 100.03 180 top
R571  4.7K-R2  [SM0402_R]  51.38 98.88 180 top
R574  200K-R2  [SM0402_R]  72.29 83.44 270 bottom
R575  200K-R2  [SM0402_R]  74.83 85.22 270 top
R578  200K-R2  [SM0402_R]  72.29 83.44 270 top
R579  1K-1%-R2  [SM0402_R]  68.28 108 90 top
R583  1K-1%-R2  [SM0402_R]  73.05 81.66 180 top
R585  1K-1%-R2  [SM0402_R]  75.97 85.22 270 top
R587  1K-1%-R2  [SM0402_R]  73.05 81.66 180 bottom
R589  @4.7K-1%-R2  [SM0402_R]  50.11 96.09 180 bottom
R605  200K-1%-R2  [SM0402_R]  -9.12 76.07 180 bottom
R606  200K-1%-R2  [SM0402_R]  69.6 82.42 270 bottom
R607  @4.7K-1%-R2  [SM0402_R]  74.04 77.22 180 top
R608  1K-R2  [SM0402_R]  64.16 77.22 90 top
R610  1K-1%-R2  [SM0402_R]  70.76 82.42 270 bottom
R615  1K-1%-R2  [SM0402_R]  -9.12 78.61 0 bottom
R618  1K-R2  [SM0402_R]  74.04 78.49 180 top
R621  @4.7K-1%-R2  [SM0402_R]  66.04 68.2 180 top
R622  @4.7K-1%-R2  [SM0402_R]  66.04 67.06 180 top
R625  4.7K-R2  [SM0402_R]  51.13 75.13 270 top
R626  4.7K-R2  [SM0402_R]  50.62 77.42 270 top
R627  4.7K-R2  [SM0402_R]  49.99 75.13 270 top
R628  4.7K-R2  [SM0402_R]  49.35 77.42 270 top
R629  200K-1%-R2  [SM0402_R]  49.35 53.04 270 top
R630  200K-1%-R2  [SM0402_R]  48.21 55.32 270 top
R631  @1K-1%-R2  [SM0402_R]  48.16 57.73 270 top
R632  1K-1%-R2  [SM0402_R]  52.27 75.13 90 top
R633  @1K-1%-R2  [SM0402_R]  49.35 55.32 90 top
R634  12.1K-1%-R2  [SM0402_R]  47.32 75.13 90 top
R635  12.1K-1%-R2  [SM0402_R]  63.45 61.16 0 top
R636  200K-1%-R2  [SM0402_R]  66.07 65.91 0 top
R637  200K-1%-R2  [SM0402_R]  51.38 54.94 0 top
R638  @10K-1%-R2  [SM0402_R]  48.46 75.13 270 top
R639  1K-1%-R2  [SM0402_R]  51.38 52.27 180 top
R640  1K-1%-R2  [SM0402_R]  66.07 64.77 0 top
R641  1K-1%-R2  [SM0402_R]  48.46 72.59 90 top
R644  @4.7K-1%-R2  [SM0402_R]  51 46.94 0 bottom
R645  1K-1%-R2  [SM0402_R]  45.67 46.94 0 top
R648  1K-1%-R2  [SM0402_R]  53.75 46.66 90 bottom
R651  316K-1%-R2  [SM0402_R]  38.3 95.07 180 top
R654  100K-1%-R2  [SM0402_R]  40.01 95.5 270 top
R655  226K-1%-R2  [SM0402_R]  38.3 105.87 180 top
R659  300K-1%-R2  [SM0402_R]  40.01 105.16 270 top
R661  100K-R2  [SM0402_R]  39.7 85.42 180 bottom
R662  47K-R3  [SM0603_R]  7.37 180.85 180 top
R663  150K-1%-R2  [SM0402_R]  54.18 166.7 0 top
R664  100K-R2  [SM0402_R]  66.93 158.88 270 top
R665  10K-1%-R2  [SM0402_R]  56.34 166.7 0 top
R667  100K-R2  [SM0402_R]  66.12 156.54 0 top
R668  100K-R2  [SM0402_R]  56.77 171.32 0 top
R669  309K-1%-R2  [SM0402_R]  59.18 166.75 0 top
R670  470-R3  [SM0603_R]  63.07 154.51 180 top
R671  470-R3  [SM0603_R]  63.07 152.86 180 top
R673  750K-1%-R2  [SM0402_R]  61.47 169.04 90 top
R674  100K-R2  [SM0402_R]  68.83 152.02 0 top
R677  330-R3  [SM0603_R]  152.1 18.62 0 bottom
R680  330-R3  [SM0603_R]  152.15 138.56 0 bottom
R681  @10K-R2  [SM0402_R]  152.02 140.46 270 bottom
R682  330-R3  [SM0603_R]  152.65 133.99 270 bottom
R684  @499K-1%-R2  [SM0402_R]  138.96 89.03 0 top
R685  @100K-1%-R2  [SM0402_R]  137.31 89.03 90 top
R686  20K-1%-R2  [SM0402_R]  136.17 90.81 0 bottom
R687  1K-1%-R2  [SM0402_R]  138.33 89.66 0 bottom
R688  4.7K-R2  [SM0402_R]  138.33 88.39 180 bottom
R689  2.7K-1%-R2  [SM0402_R]  136.17 88.39 0 bottom
R690  @243K-1%-R2  [SM0402_R]  136.17 87 0 top
R691  60.4K-1%-R2  [SM0402_R]  134.01 87 0 top
R692  7.87K-1%-R2  [SM0402_R]  134.01 88.39 0 bottom
R693  10-R5  [SM0805_R]  115.47 93.98 180 top
R694  10-R5  [SM0805_R]  115.47 96.39 180 top
R695  3.3-R2  [SM0402_R]  142.52 99.57 270 bottom
R696  10K-1%-R2  [SM0402_R]  148.74 99.44 0 bottom
R697  26.1K-1%-R2  [SM0402_R]  143.66 99.57 90 bottom
R698  5.76K-1%-R2  [SM0402_R]  144.81 99.57 270 bottom
R699  10K-1%-R2  [SM0402_R]  143.15 95.38 90 top
R700  @10K-1%-R2  [SM0402_R]  144.3 95.38 270 top
R701  10K-1%-R2  [SM0402_R]  145.16 92.96 270 bottom
R702  100K-R2  [SM0402_R]  132.21 93.22 90 top
R703  10-R5  [SM0805_R]  127 106.55 180 top
R704  10-R5  [SM0805_R]  127.03 104.14 180 top
R705  200K-1%-R2  [SM0402_R]  85.98 103.25 180 bottom
R706  100K-1%-R2  [SM0402_R]  88.82 91.69 270 bottom
R711  100K-1%-R2  [SM0402_R]  83.74 102.11 180 bottom
R713  100K-1%-R2  [SM0402_R]  87.66 93.98 270 bottom
R714  100-R2  [SM0402_R]  95.4 99.82 90 top
R715  100-R2  [SM0402_R]  100.89 95.66 90 top
R718  27.4K-1%-R2  [SM0402_R]  52.7 143.13 180 top
R719  402K-1%-R2  [SM0402_R]  50.55 143.13 180 top
R720  2.2-1%-R2  [SM0402_R]  48.39 143.13 0 top
R721  115-1%-R2  [SM0402_R]  56.9 150.24 270 top
R722  22.1K-1%-R2  [SM0402_R]  55.24 149.61 0 top
R723  24.9K-1%-R2  [SM0402_R]  52.53 146 270 bottom
R724  2.2-1%-R2  [SM0402_R]  46.86 146.56 0 top
R725  10.7K-1%-R2  [SM0402_R]  55.24 147.32 0 top
R726  1.58K-1%-R2  [SM0402_R]  55.24 148.46 180 top
R727  137-1%-R2  [SM0402_R]  46.86 144.27 0 top
R729  0.003-1%-R12  [SM2512_R]  16.66 127.38 90 bottom
R730  0.009-1%-R6  [SM1206_R]  27.51 117.17 270 bottom
R731  71.5K-1%-R2  [SM0402_R]  18.69 107.06 270 top
R733  1.3K-1%-R2  [SM0402_R]  20.07 109.73 270 bottom
R735  3.3-R2  [SM0402_R]  12.14 126.82 180 top
R737  10-R2  [SM0402_R]  13.03 118.82 180 top
R738  10-R2  [SM0402_R]  6.17 117.68 90 top
R739  3.3-R2  [SM0402_R]  27.94 126.87 0 top
R740  357K-1%-R2  [SM0402_R]  10.62 107.65 180 top
R741  100-R2  [SM0402_R]  14.61 107.06 90 top
R742  22.1K-1%-R2  [SM0402_R]  9.98 109.8 270 bottom
R744  3.3-R2  [SM0402_R]  20.19 126.87 0 top
R746  3.3-R2  [SM0402_R]  19.38 131.01 90 bottom
R747  8.2K-1%-R2  [SM0402_R]  18.41 107.7 180 bottom
R748  30K-1%-R2  [SM0402_R]  12.01 109.8 90 bottom
R749  3.3-R2  [SM0402_R]  36.83 127.38 90 top
R751  1.87K-1%-R2  [SM0402_R]  14.81 109.68 270 bottom
R752  165K-1%-R2  [SM0402_R]  15.32 107.65 0 bottom
R753  75K-1%-R2  [SM0402_R]  15.95 109.68 270 bottom
R756  47K-R2  [SM0402_R]  134.11 175.51 90 top
R757  47K-R2  [SM0402_R]  147.22 108.71 270 top
R759  @47K-R2  [SM0402_R]  151.16 114.43 0 bottom
R760  47K-R2  [SM0402_R]  151.16 115.57 0 bottom
R761  33-1%-R2  [SM0402_R]  157.1 101.47 90 top
R762  0-R3  [SM0603_R]  136.78 149.61 90 top
R763  1K-1%-R2  [SM0402_R]  140.36 101.47 0 bottom
R768  100K-R2  [SM0402_R]  111.63 81.15 90 top
R769  @10K-R2  [SM0402_R]  110.49 81.15 90 top
R771  2.2K-R2  [SM0402_R]  109.37 90.17 270 bottom
R1334  200K-R1  [SM0201_R]  127.79 64.9 180 bottom
R1474  47K-R2  [SM0402_R]  116.46 120.14 180 bottom
R1475  100K-R2  [SM0402_R]  146.56 172.72 270 bottom
R1476  100K-R2  [SM0402_R]  139.83 172.72 180 bottom
R1477  4.7K-R2  [SM0402_R]  116.2 74.8 270 top
R1478  162K-1%-R2  [SM0402_R]  85.72 109.73 270 top
R1479  100K-R2  [SM0402_R]  89.79 108.84 180 top
R1482  100K-R2  [SM0402_R]  96.29 108.97 90 top
R1483  100K-R2  [SM0402_R]  141.48 127.64 0 top
R1484  49.9-1%-R2  [SM0402_R]  110.24 90.55 270 top
R1485  49.9-1%-R2  [SM0402_R]  107.95 90.55 270 top
R1486  49.9-1%-R2  [SM0402_R]  109.09 90.55 270 top
R1488  @100K-R2  [SM0402_R]  112.78 81.15 90 top
R1490  47K-R2  [SM0402_R]  116.46 122.17 180 bottom
R1491  4.7K-1%-R2  [SM0402_R]  129.69 70.36 90 bottom
R1493  2.2K-1%-R2  [SM0402_R]  152.53 149.48 180 bottom
R1498  4.7K-1%-R2  [SM0402_R]  135.03 69.22 0 bottom
R1499  4.7K-1%-R2  [SM0402_R]  134.9 75.69 90 bottom
R1500  4.7K-1%-R2  [SM0402_R]  135 70.36 0 bottom
R1505  4.7K-1%-R2  [SM0402_R]  135 71.5 0 bottom
R1506  10K-1%-R2  [SM0402_R]  6.3 84.66 90 top
R1507  10K-1%-R2  [SM0402_R]  4.01 85.29 0 top
R1508  0-R3  [SM0603_R]  89.92 155.45 180 top
R1509  100K-R2  [SM0402_R]  138.2 41.15 90 top
R1510  3.3-R2  [SM0402_R]  10.95 123.83 0 bottom
RA1  10K-1%-R1  [SM0201_R]  100.48 93.85 90 top
RA2  10K-1%-R1  [SM0201_R]  101.12 93.85 90 top
RA3  10K-1%-R1  [SM0201_R]  86.06 79.32 270 top
RA4  10K-1%-R1  [SM0201_R]  77.29 77.17 90 top
RA5  10K-1%-R1  [SM0201_R]  77.04 72.59 270 top
RA6  10K-1%-R1  [SM0201_R]  90.88 70.43 0 top
RA7  10K-1%-R1  [SM0201_R]  76.02 71.2 90 top
RA8  @10K-1%-R1  [SM0201_R]  90.88 65.1 0 top
RA9  10K-1%-R1  [SM0201_R]  75.9 63.7 0 top
RA10  10K-1%-R1  [SM0201_R]  88.21 60.91 90 top
RA11  10K-1%-R1  [SM0201_R]  131.7 44.32 270 top
RA12  10K-1%-R1  [SM0201_R]  133.6 44.32 270 top
RA13  10K-1%-R1  [SM0201_R]  134.37 44.32 270 top
RA14  10K-1%-R1  [SM0201_R]  128.75 42.21 90 top
RA15  10K-1%-R1  [SM0201_R]  123.19 41.9 90 top
RA16  10K-1%-R1  [SM0201_R]  17.4 40.64 0 top
RA17  10K-1%-R1  [SM0201_R]  125.6 38.48 0 top
RA18  10K-1%-R1  [SM0201_R]  70.61 38.23 0 top
RA19  10K-1%-R1  [SM0201_R]  107.31 38.1 0 top
RA20  10K-1%-R1  [SM0201_R]  34.16 37.72 0 top
RA21  10K-1%-R1  [SM0201_R]  52.45 37.72 0 top
RA22  10K-1%-R1  [SM0201_R]  89.03 37.72 0 top
RA23  10K-1%-R1  [SM0201_R]  17.96 35.2 0 top
RA24  10K-1%-R1  [SM0201_R]  126.16 32.66 0 top
RA25  10K-1%-R1  [SM0201_R]  34.72 32.28 0 top
RA26  10K-1%-R1  [SM0201_R]  53.01 32.28 0 top
RA27  10K-1%-R1  [SM0201_R]  71.3 32.28 0 top
RA28  10K-1%-R1  [SM0201_R]  89.59 32.28 0 top
RA29  10K-1%-R1  [SM0201_R]  107.87 32.28 0 top
RA30  10K-1%-R1  [SM0201_R]  20.07 32.13 180 top
RA31  10K-1%-R1  [SM0201_R]  20.07 30.23 180 top
RA32  10K-1%-R1  [SM0201_R]  128.27 29.59 180 top
RA33  10K-1%-R1  [SM0201_R]  20.07 29.46 180 top
RA34  10K-1%-R1  [SM0201_R]  36.83 29.21 180 top
RA35  10K-1%-R1  [SM0201_R]  55.12 29.21 180 top
RA36  10K-1%-R1  [SM0201_R]  73.41 29.21 180 top
RA37  10K-1%-R1  [SM0201_R]  91.69 29.21 180 top
RA38  10K-1%-R1  [SM0201_R]  109.98 29.21 180 top
RA39  10K-1%-R1  [SM0201_R]  128.27 27.69 180 top
RA40  10K-1%-R1  [SM0201_R]  36.83 27.3 180 top
RA41  10K-1%-R1  [SM0201_R]  55.12 27.3 180 top
RA42  10K-1%-R1  [SM0201_R]  73.41 27.3 180 top
RA43  10K-1%-R1  [SM0201_R]  91.69 27.3 180 top
RA44  10K-1%-R1  [SM0201_R]  109.98 27.3 180 top
RA45  10K-1%-R1  [SM0201_R]  128.27 26.92 180 top
RA46  10K-1%-R1  [SM0201_R]  36.83 26.54 180 top
RA47  10K-1%-R1  [SM0201_R]  55.12 26.54 180 top
RA48  10K-1%-R1  [SM0201_R]  73.41 26.54 180 top
RA49  10K-1%-R1  [SM0201_R]  91.69 26.54 180 top
RA50  10K-1%-R1  [SM0201_R]  109.98 26.54 180 top
RA51  10K-1%-R1  [SM0201_R]  140.08 179.96 180 bottom
RA52  10K-1%-R1  [SM0201_R]  131.83 141.48 90 bottom
RA53  @10K-1%-R1  [SM0201_R]  132.84 55.12 270 bottom
RA54  @10K-1%-R1  [SM0201_R]  132.21 55.12 270 bottom
RA55  10K-1%-R1  [SM0201_R]  128.78 54.99 270 bottom
RA56  10K-1%-R1  [SM0201_R]  128.14 54.99 270 bottom
RA57  10K-1%-R1  [SM0201_R]  127.51 54.99 270 bottom
RA58  10K-1%-R1  [SM0201_R]  137.54 46.61 0 bottom
RA59  10K-1%-R1  [SM0201_R]  137.54 45.97 0 bottom
RA60  10K-1%-R1  [SM0201_R]  137.54 45.34 0 bottom
RA61  10K-1%-R1  [SM0201_R]  137.54 44.7 0 bottom
RA62  10K-1%-R1  [SM0201_R]  132.84 42.55 90 bottom
RA63  10K-1%-R1  [SM0201_R]  132.21 42.55 90 bottom
RA64  10K-1%-R1  [SM0201_R]  131.19 42.55 90 bottom
RA65  10K-1%-R1  [SM0201_R]  130.56 42.55 90 bottom
RA66  10K-1%-R1  [SM0201_R]  30.86 36.7 180 bottom
RA67  10K-1%-R1  [SM0201_R]  30.86 36.07 180 bottom
RA68  10K-1%-R1  [SM0201_R]  30.86 35.43 180 bottom
RA69  10K-1%-R1  [SM0201_R]  139.06 34.16 180 bottom
RA70  10K-1%-R1  [SM0201_R]  120.78 33.78 180 bottom
RA71  10K-1%-R1  [SM0201_R]  102.49 33.78 180 bottom
RA72  10K-1%-R1  [SM0201_R]  84.2 33.78 180 bottom
RA73  10K-1%-R1  [SM0201_R]  65.91 33.78 180 bottom
RA74  10K-1%-R1  [SM0201_R]  47.62 33.78 180 bottom
RA75  10K-1%-R1  [SM0201_R]  139.06 33.53 180 bottom
RA76  10K-1%-R1  [SM0201_R]  18.29 33.4 0 bottom
RA77  10K-1%-R1  [SM0201_R]  120.78 33.15 180 bottom
RA78  10K-1%-R1  [SM0201_R]  102.49 33.15 180 bottom
RA79  10K-1%-R1  [SM0201_R]  84.2 33.15 180 bottom
RA80  10K-1%-R1  [SM0201_R]  65.91 33.15 180 bottom
RA81  10K-1%-R1  [SM0201_R]  47.62 33.15 180 bottom
RA82  10K-1%-R1  [SM0201_R]  139.06 32.89 180 bottom
RA83  10K-1%-R1  [SM0201_R]  18.29 32.77 0 bottom
RA84  10K-1%-R1  [SM0201_R]  120.78 32.51 180 bottom
RA85  10K-1%-R1  [SM0201_R]  102.49 32.51 180 bottom
RA86  10K-1%-R1  [SM0201_R]  84.2 32.51 180 bottom
RA87  10K-1%-R1  [SM0201_R]  65.91 32.51 180 bottom
RA88  10K-1%-R1  [SM0201_R]  47.62 32.51 180 bottom
RA89  @10K-1%-R1  [SM0201_R]  30.86 31.75 180 bottom
RA90  10K-1%-R1  [SM0201_R]  18.29 31.75 0 bottom
RA91  @10K-1%-R1  [SM0201_R]  30.86 31.11 180 bottom
RA92  10K-1%-R1  [SM0201_R]  18.29 31.11 0 bottom
RA93  10K-1%-R1  [SM0201_R]  126.49 30.86 0 bottom
RA94  10K-1%-R1  [SM0201_R]  108.2 30.48 0 bottom
RA95  10K-1%-R1  [SM0201_R]  89.92 30.48 0 bottom
RA96  10K-1%-R1  [SM0201_R]  71.25 30.48 0 bottom
RA97  10K-1%-R1  [SM0201_R]  53.34 30.48 0 bottom
RA98  10K-1%-R1  [SM0201_R]  35.05 30.48 0 bottom
RA99  10K-1%-R1  [SM0201_R]  126.49 30.23 0 bottom
RA100  10K-1%-R1  [SM0201_R]  108.2 29.84 0 bottom
RA101  10K-1%-R1  [SM0201_R]  89.92 29.84 0 bottom
RA102  10K-1%-R1  [SM0201_R]  71.25 29.84 0 bottom
RA103  10K-1%-R1  [SM0201_R]  53.34 29.84 0 bottom
RA104  10K-1%-R1  [SM0201_R]  35.05 29.84 0 bottom
RA105  @10K-1%-R1  [SM0201_R]  139.06 29.21 180 bottom
RA106  10K-1%-R1  [SM0201_R]  126.49 29.21 0 bottom
RA107  @10K-1%-R1  [SM0201_R]  120.78 28.83 180 bottom
RA108  10K-1%-R1  [SM0201_R]  108.2 28.83 0 bottom
RA109  @10K-1%-R1  [SM0201_R]  102.49 28.83 180 bottom
RA110  10K-1%-R1  [SM0201_R]  89.92 28.83 0 bottom
RA111  @10K-1%-R1  [SM0201_R]  84.2 28.83 180 bottom
RA112  10K-1%-R1  [SM0201_R]  71.25 28.83 0 bottom
RA113  @10K-1%-R1  [SM0201_R]  65.91 28.83 180 bottom
RA114  10K-1%-R1  [SM0201_R]  53.34 28.83 0 bottom
RA115  @10K-1%-R1  [SM0201_R]  47.62 28.83 180 bottom
RA116  10K-1%-R1  [SM0201_R]  35.05 28.83 0 bottom
RA117  @10K-1%-R1  [SM0201_R]  139.06 28.57 180 bottom
RA118  10K-1%-R1  [SM0201_R]  126.49 28.57 0 bottom
RA119  @10K-1%-R1  [SM0201_R]  120.78 28.19 180 bottom
RA120  10K-1%-R1  [SM0201_R]  108.2 28.19 0 bottom
RA121  @10K-1%-R1  [SM0201_R]  102.49 28.19 180 bottom
RA122  10K-1%-R1  [SM0201_R]  89.92 28.19 0 bottom
RA123  @10K-1%-R1  [SM0201_R]  84.2 28.19 180 bottom
RA124  10K-1%-R1  [SM0201_R]  71.25 28.19 0 bottom
RA125  @10K-1%-R1  [SM0201_R]  65.91 28.19 180 bottom
RA126  10K-1%-R1  [SM0201_R]  53.34 28.19 0 bottom
RA127  @10K-1%-R1  [SM0201_R]  47.62 28.19 180 bottom
RA128  10K-1%-R1  [SM0201_R]  35.05 28.19 0 bottom
RA129  10K-1%-R1  [SM0201_R]  21.79 26.24 270 bottom
RA130  10K-1%-R1  [SM0201_R]  21.16 26.24 270 bottom
RA131  10K-1%-R1  [SM0201_R]  20.52 26.24 270 bottom
RA132  10K-1%-R1  [SM0201_R]  19.89 26.24 270 bottom
RA133  10K-1%-R1  [SM0201_R]  130.56 23.88 270 bottom
RA134  10K-1%-R1  [SM0201_R]  129.92 23.88 270 bottom
RA135  10K-1%-R1  [SM0201_R]  129.29 23.88 270 bottom
RA136  10K-1%-R1  [SM0201_R]  128.65 23.88 270 bottom
RA137  10K-1%-R1  [SM0201_R]  112.27 23.5 270 bottom
RA138  10K-1%-R1  [SM0201_R]  111.63 23.5 270 bottom
RA139  10K-1%-R1  [SM0201_R]  111 23.5 270 bottom
RA140  10K-1%-R1  [SM0201_R]  110.36 23.5 270 bottom
RA141  10K-1%-R1  [SM0201_R]  93.98 23.5 270 bottom
RA142  10K-1%-R1  [SM0201_R]  93.34 23.5 270 bottom
RA143  10K-1%-R1  [SM0201_R]  92.71 23.5 270 bottom
RA144  10K-1%-R1  [SM0201_R]  92.08 23.5 270 bottom
RA145  10K-1%-R1  [SM0201_R]  75.69 23.5 270 bottom
RA146  10K-1%-R1  [SM0201_R]  75.06 23.5 270 bottom
RA147  10K-1%-R1  [SM0201_R]  74.42 23.5 270 bottom
RA148  10K-1%-R1  [SM0201_R]  73.79 23.5 270 bottom
RA149  10K-1%-R1  [SM0201_R]  57.4 23.5 270 bottom
RA150  10K-1%-R1  [SM0201_R]  56.77 23.5 270 bottom
RA151  10K-1%-R1  [SM0201_R]  56.13 23.5 270 bottom
RA152  10K-1%-R1  [SM0201_R]  55.5 23.5 270 bottom
RA153  10K-1%-R1  [SM0201_R]  39.12 23.5 270 bottom
RA154  10K-1%-R1  [SM0201_R]  38.48 23.5 270 bottom
RA155  10K-1%-R1  [SM0201_R]  37.85 23.5 270 bottom
RA156  10K-1%-R1  [SM0201_R]  37.21 23.5 270 bottom
RB1  10K-R2  [SM0402_R]  93.98 191.13 180 top
RB2  10K-R2  [SM0402_R]  93.98 177.16 180 top
RB3  10K-R2  [SM0402_R]  63.75 177.04 180 top
RB4  10K-R2  [SM0402_R]  131.19 174.24 180 top
RB5  10K-R2  [SM0402_R]  132.84 164.21 0 top
RB6  10K-R2  [SM0402_R]  129.92 161.04 270 top
RB7  10K-R2  [SM0402_R]  131.06 161.04 270 top
RB8  10K-R2  [SM0402_R]  123.32 159.13 180 top
RB9  10K-R2  [SM0402_R]  127.38 159.13 0 top
RB10  10K-R2  [SM0402_R]  134.87 158.12 90 top
RB11  10K-R2  [SM0402_R]  127.38 157.86 0 top
RB12  10K-R2  [SM0402_R]  107.21 155.7 270 top
RB13  10K-R2  [SM0402_R]  133.73 155.07 90 top
RB14  0-R1  [SM0201_R]  32.13 30.48 0 bottom
RB15  0-R1  [SM0201_R]  48.9 27.56 0 bottom
RB16  0-R1  [SM0201_R]  67.18 27.56 0 bottom
RB17  0-R1  [SM0201_R]  85.47 27.56 0 bottom
RB18  0-R1  [SM0201_R]  103.76 27.56 0 bottom
RB19  0-R1  [SM0201_R]  122.05 27.56 0 bottom
RB20  0-R1  [SM0201_R]  140.34 27.94 0 bottom
RB21  0-R1  [SM0201_R]  133.73 55.24 90 bottom
RB22  10K-R2  [SM0402_R]  114.3 154.18 270 top
RB23  10K-R2  [SM0402_R]  51.94 150.75 0 top
RB24  10K-R2  [SM0402_R]  115.82 123.06 90 top
RB25  10K-R2  [SM0402_R]  115.82 120.27 90 top
RB26  10K-R2  [SM0402_R]  39.88 111.63 270 top
RB27  10K-R2  [SM0402_R]  41.27 109.22 90 top
RB28  10K-R2  [SM0402_R]  42.88 109.17 90 top
RB29  10K-R2  [SM0402_R]  12.32 107.06 270 top
RB30  10K-R2  [SM0402_R]  15.75 107.06 270 top
RB31  10K-R2  [SM0402_R]  39.45 103.58 0 top
RB32  10K-R2  [SM0402_R]  83.97 100.2 0 top
RB33  10K-R2  [SM0402_R]  39.45 102.44 0 top
RB34  10K-R2  [SM0402_R]  85.5 93.12 0 top
RB35  10K-R2  [SM0402_R]  85.5 91.97 0 top
RB36  10K-R2  [SM0402_R]  111.15 94.23 90 bottom
RB37  10K-R2  [SM0402_R]  109.63 96.52 0 bottom
RB38  10K-R2  [SM0402_R]  110.64 98.42 180 top
RB39  10K-R2  [SM0402_R]  111.91 94.23 180 top
RB40  10K-R2  [SM0402_R]  39.45 93.93 0 top
RB41  10K-R2  [SM0402_R]  39.45 92.79 0 top
RB42  10K-R2  [SM0402_R]  111.38 90.55 270 top
RB43  10K-R2  [SM0402_R]  116.36 88.14 180 top
RB44  10K-R2  [SM0402_R]  13.72 80.52 90 top
RB45  10K-R2  [SM0402_R]  15.82 80.47 90 top
RB46  10K-R2  [SM0402_R]  16.97 80.47 90 top
RB47  10K-R2  [SM0402_R]  121.67 77.34 90 top
RB48  10K-R2  [SM0402_R]  123.95 77.34 90 top
RB49  10K-R2  [SM0402_R]  125.09 77.34 90 top
RB50  10K-R2  [SM0402_R]  122.12 74.8 270 top
RB51  10K-R2  [SM0402_R]  121.06 72.01 90 top
RB52  10K-R2  [SM0402_R]  122.68 71.37 270 top
RB53  10K-R2  [SM0402_R]  123.85 71.37 270 top
RB54  10K-R2  [SM0402_R]  124.97 71.37 270 top
RB55  10K-R2  [SM0402_R]  121.06 69.34 90 top
RB56  10K-R2  [SM0402_R]  128.47 67.01 180 top
RB57  10K-R2  [SM0402_R]  128.47 65.86 180 top
RB58  10K-R2  [SM0402_R]  74.63 51.77 270 bottom
RB59  10K-R2  [SM0402_R]  74.12 56.46 180 top
RB60  10K-R2  [SM0402_R]  86.36 191.26 0 bottom
RB61  10K-R2  [SM0402_R]  86.36 177.29 0 bottom
RB62  10K-R2  [SM0402_R]  62.74 174.12 180 bottom
RB63  10K-R2  [SM0402_R]  132.46 155.45 180 bottom
RB64  10K-R2  [SM0402_R]  151.64 136.65 270 bottom
RB65  10K-R2  [SM0402_R]  13.16 80.98 0 bottom
RB66  10K-R2  [SM0402_R]  151.76 20.5 90 bottom
RECOVERY1  WF200-04/CI0104P1VK0  [WF200D-4P]  157.11 122.86 270 bottom
RESET1  WF200-04/CI0104P1VK0  [WF200D-4P]  157.14 134.17 270 bottom
RZ1  0-R2  [SM0402_R]  12.45 195.58 0 top
RZ2  0-R2  [SM0402_R]  136.4 175.51 90 top
RZ3  0-R2  [SM0402_R]  59.18 171.32 180 top
RZ4  0-R2  [SM0402_R]  112.14 159.89 0 top
RZ5  0-R2  [SM0402_R]  127.38 156.72 180 top
RZ6  0-R2  [SM0402_R]  127.38 154.18 180 top
RZ7  0-R2  [SM0402_R]  145.29 152.15 90 top
RZ8  0-R2  [SM0402_R]  68.83 150.75 180 top
RZ9  0-R2  [SM0402_R]  81.66 149.1 270 top
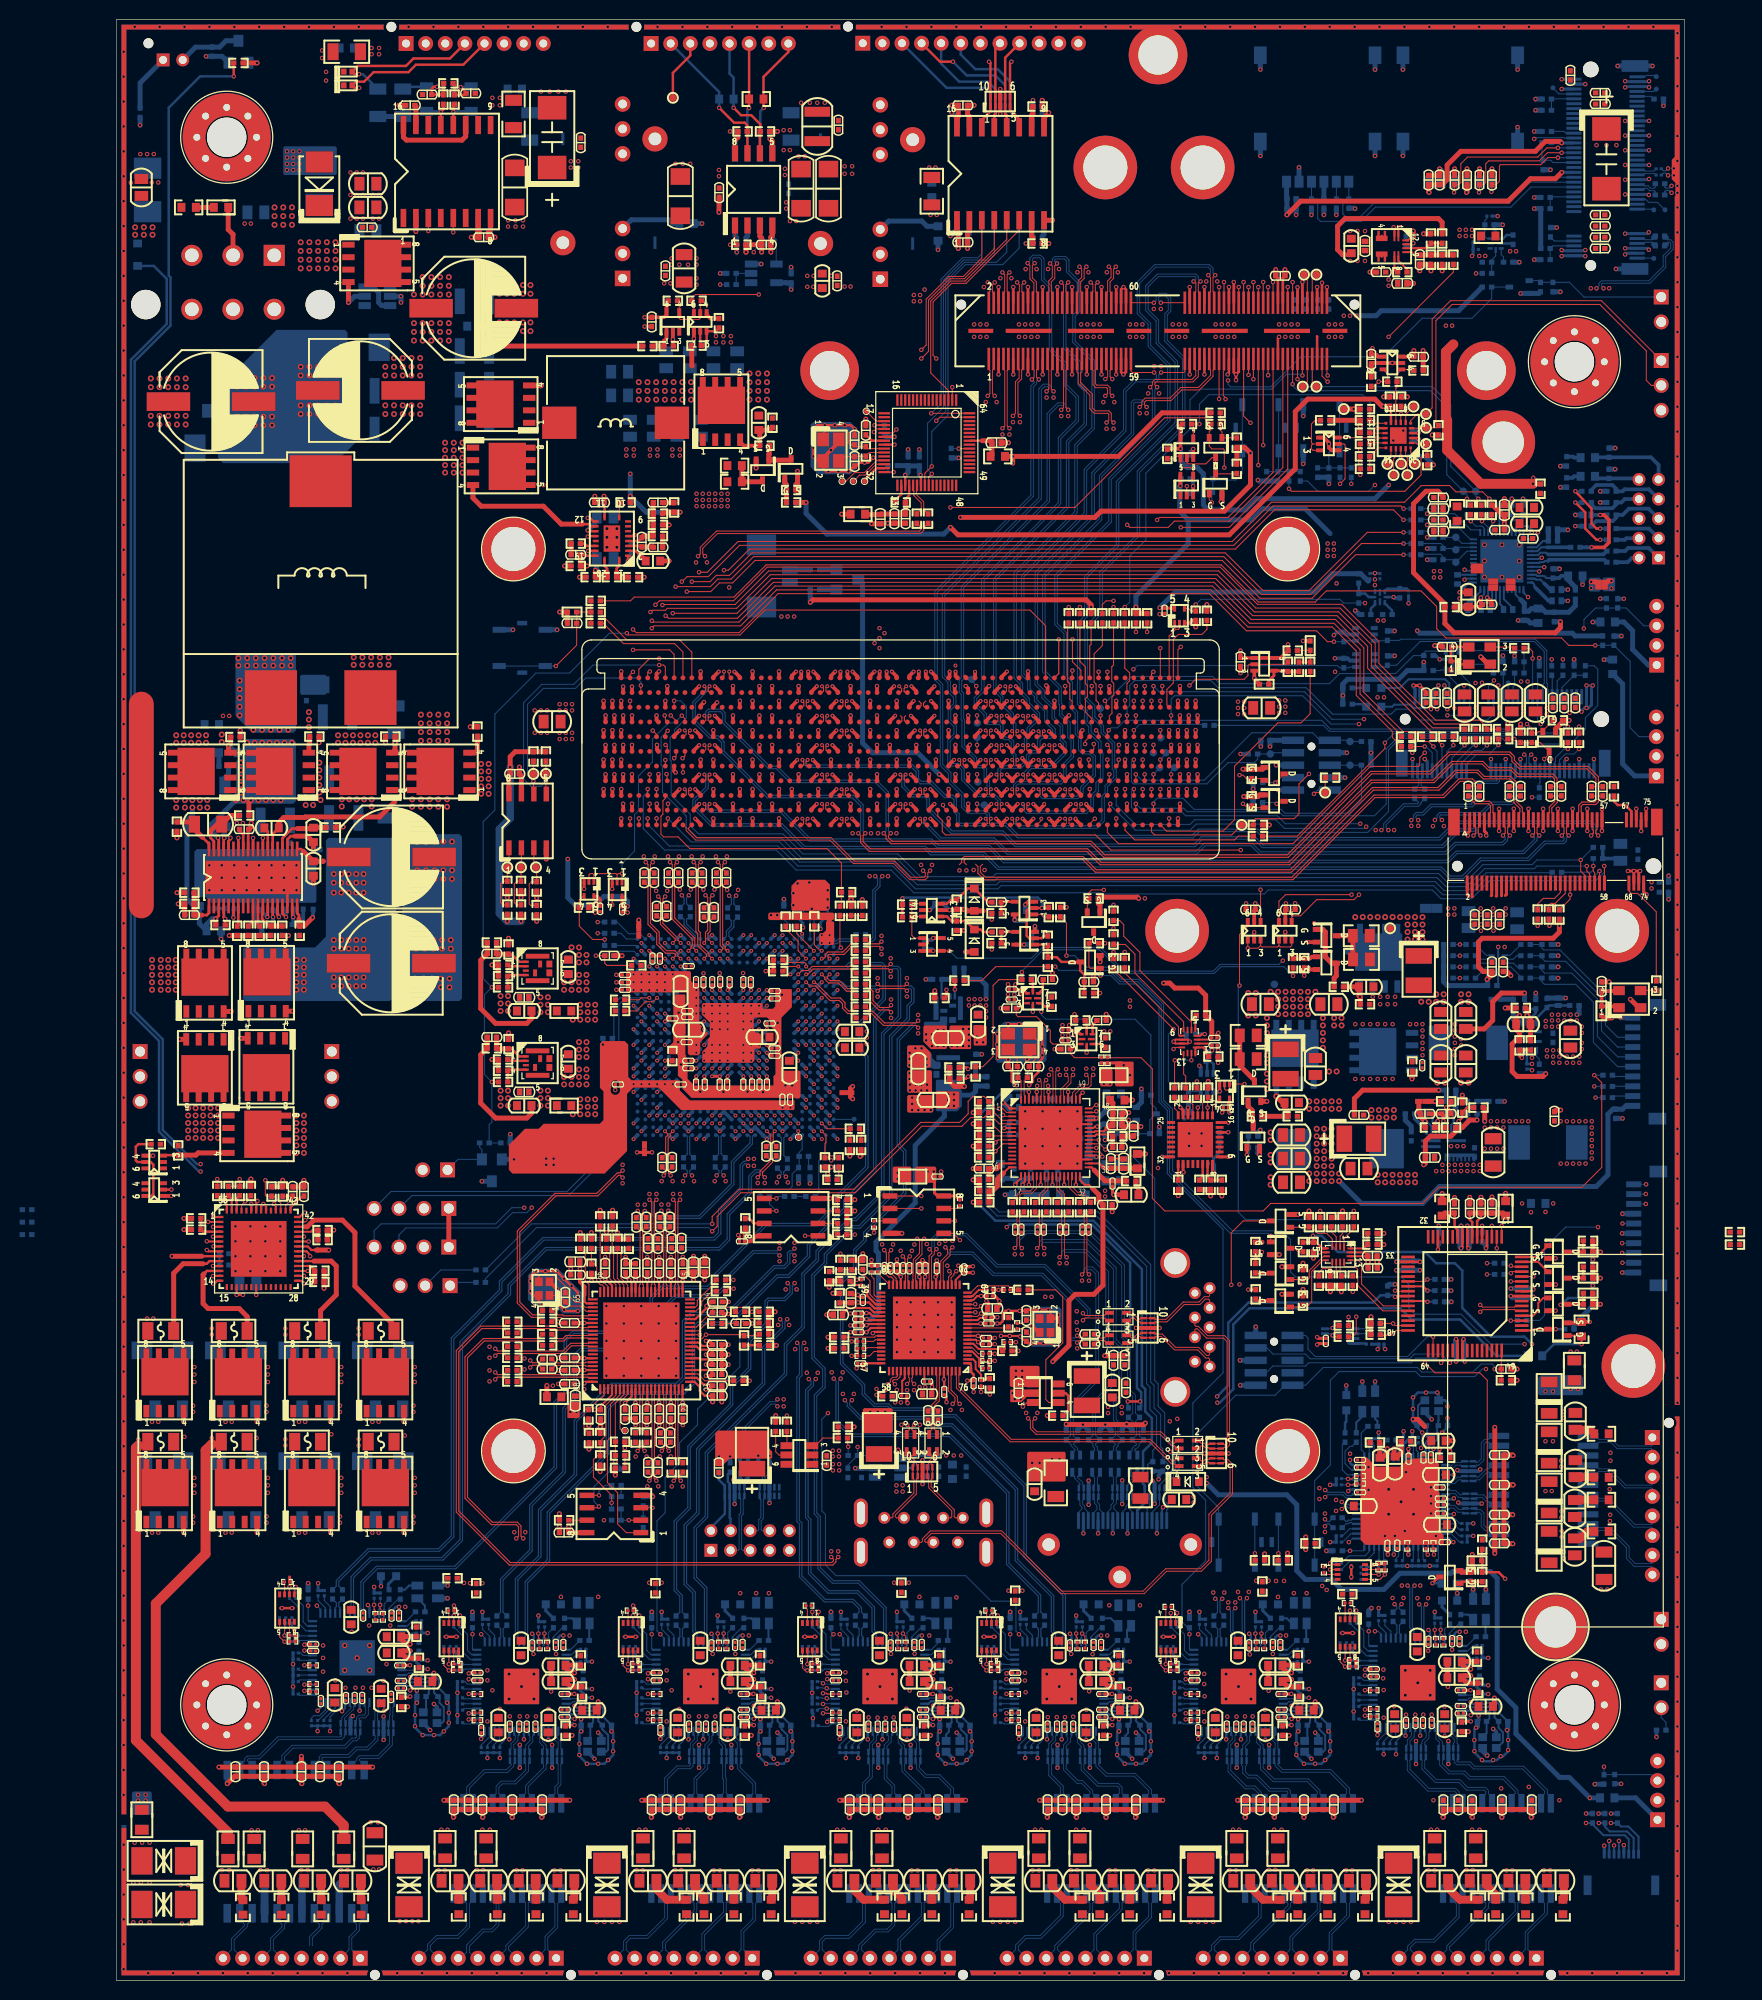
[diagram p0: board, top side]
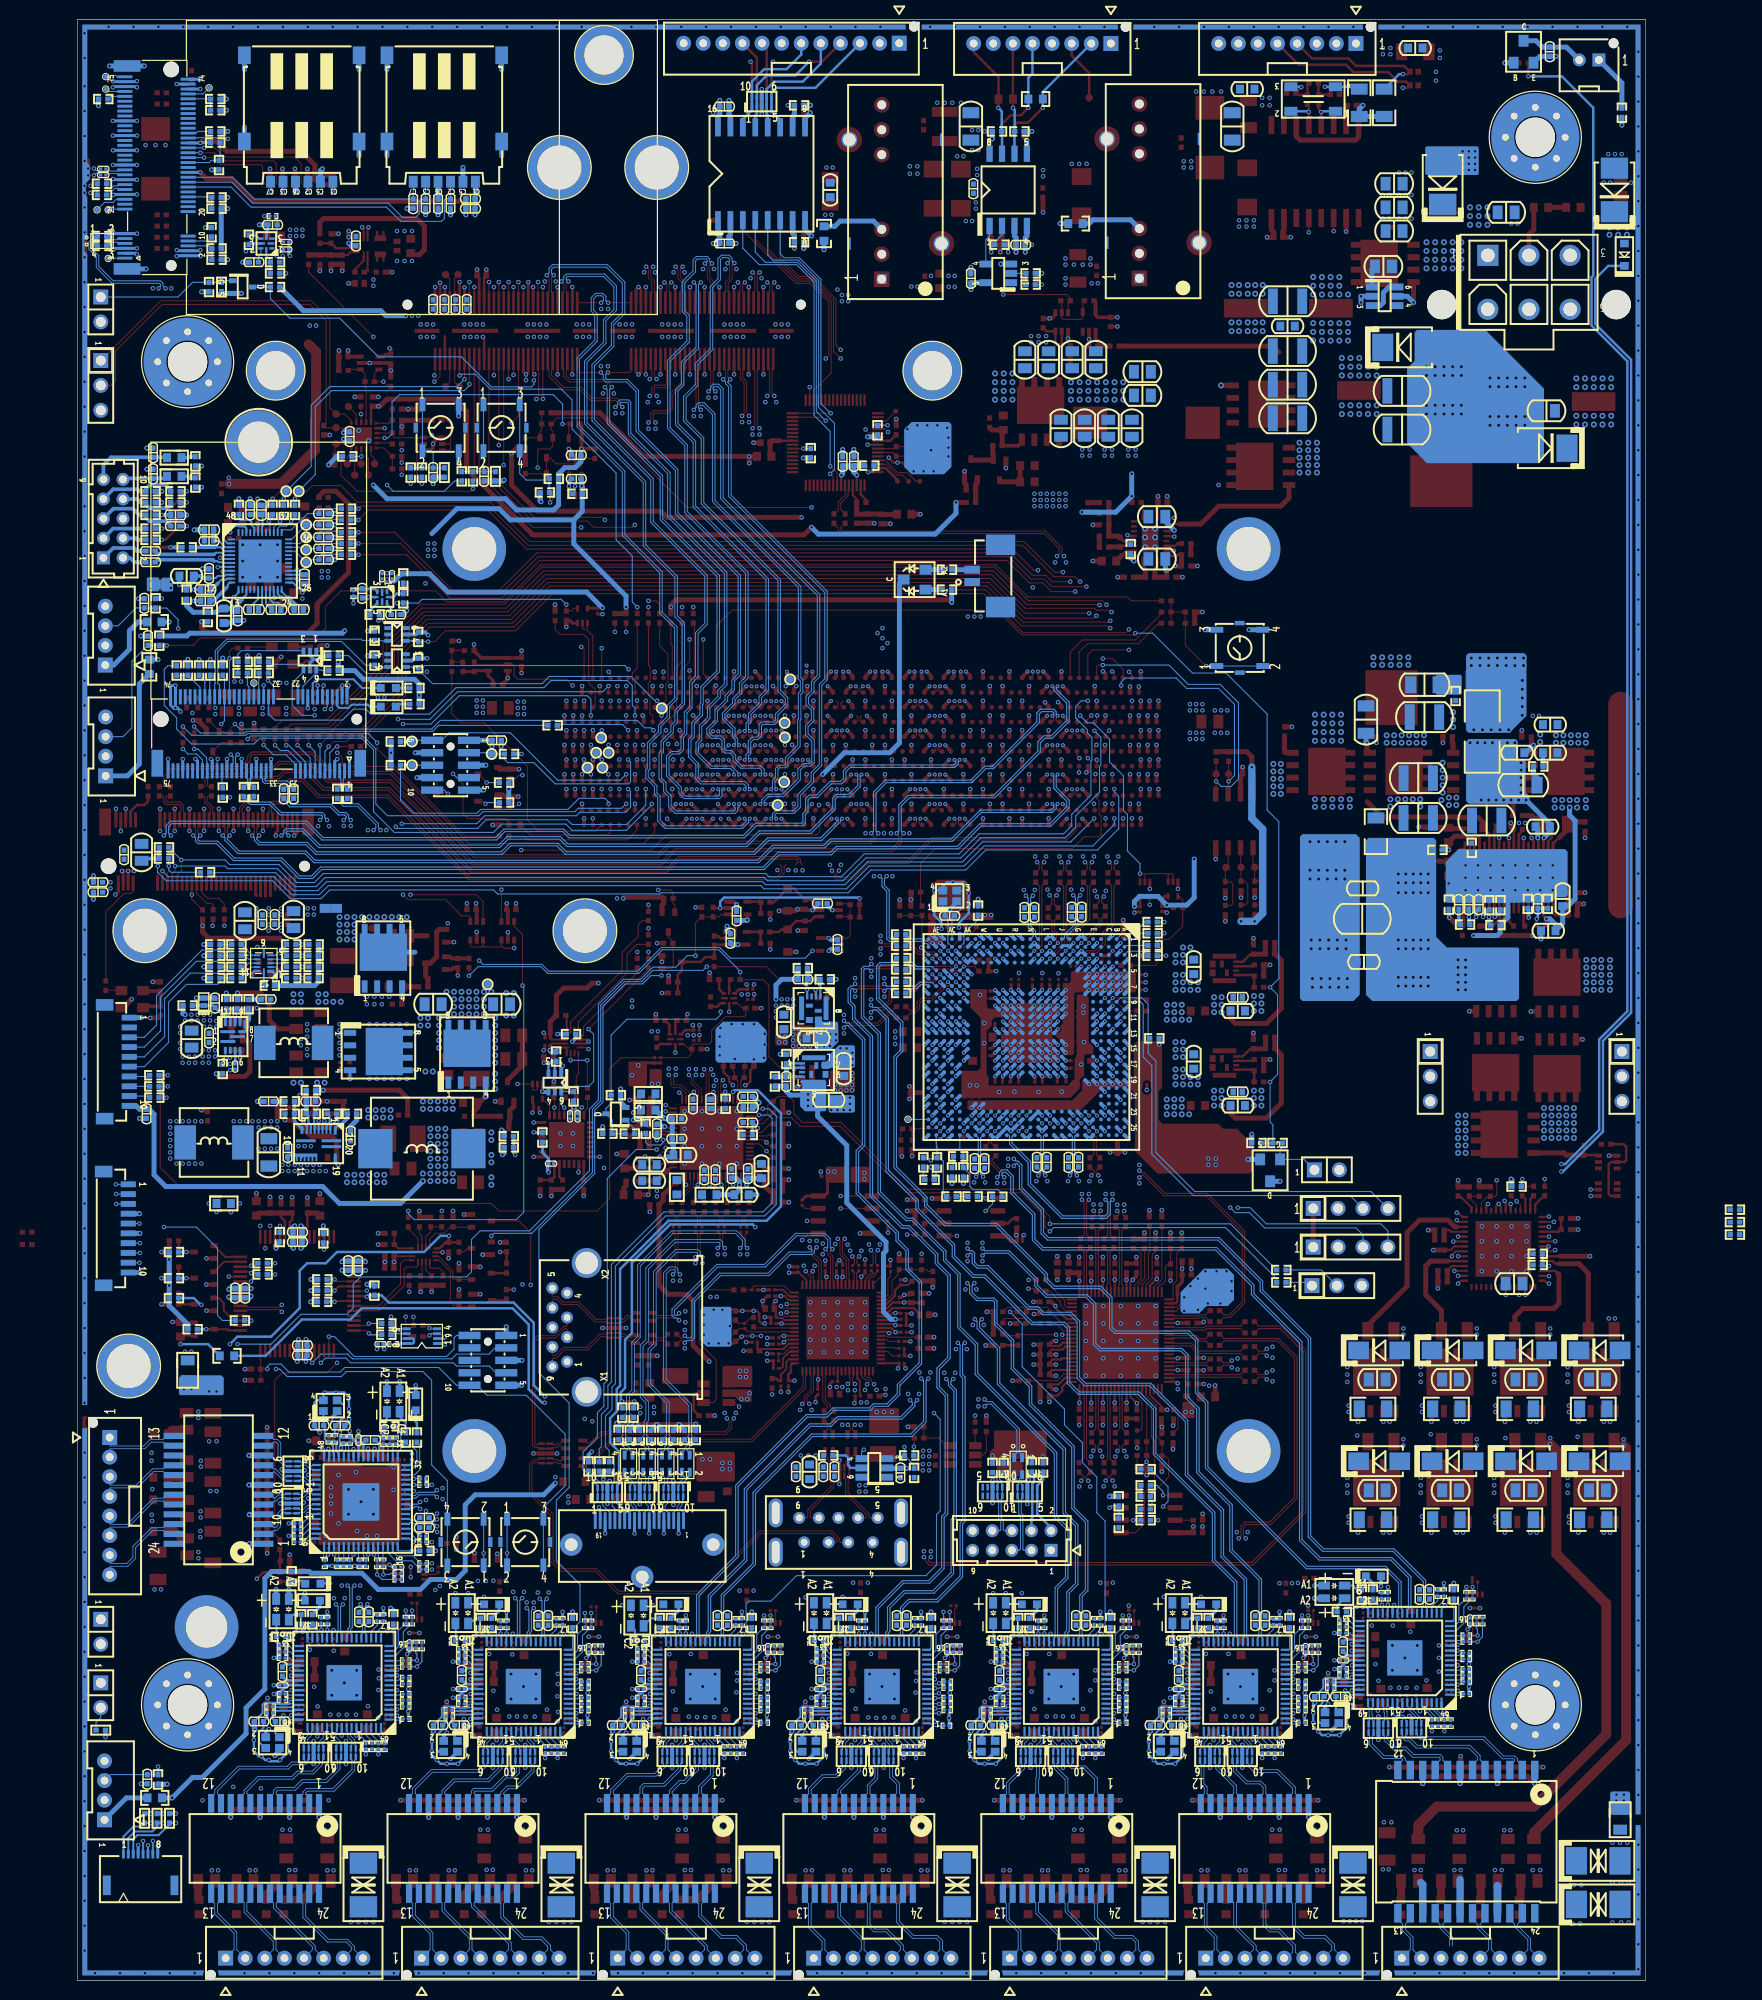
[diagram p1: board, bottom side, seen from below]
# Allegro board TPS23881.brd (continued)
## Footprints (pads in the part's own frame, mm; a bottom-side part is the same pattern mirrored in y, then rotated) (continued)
BTBS-60X2P05-QSH-01
  round 1.016 hole 1.016 unplated: (-20.065,2.67) (20.065,2.67)
  rect 0.279x2.286 smd: 1(-17.25,-2.865) 2(-17.25,2.865) 3(-16.75,-2.865) 4(-16.75,2.865) 5(-16.25,-2.865) 6(-16.25,2.865) 7(-15.75,-2.865) 8(-15.75,2.865) 9(-15.25,-2.865) 10(-15.25,2.865) 11(-14.75,-2.865) 12(-14.75,2.865) 13(-14.25,-2.865) 14(-14.25,2.865) 15(-13.75,-2.865) 16(-13.75,2.865) 17(-13.25,-2.865) 18(-13.25,2.865) 19(-12.75,-2.865) 20(-12.75,2.865) 21(-12.25,-2.865) 22(-12.25,2.865) 23(-11.75,-2.865) 24(-11.75,2.865) 25(-11.25,-2.865) 26(-11.25,2.865) 27(-10.75,-2.865) 28(-10.75,2.865) 29(-10.25,-2.865) 30(-10.25,2.865) 31(-9.75,-2.865) 32(-9.75,2.865) 33(-9.25,-2.865) 34(-9.25,2.865) 35(-8.75,-2.865) 36(-8.75,2.865) 37(-8.25,-2.865) 38(-8.25,2.865) 39(-7.75,-2.865) 40(-7.75,2.865) 41(-7.25,-2.865) 42(-7.25,2.865) 43(-6.75,-2.865) 44(-6.75,2.865) 45(-6.25,-2.865) 46(-6.25,2.865) 47(-5.75,-2.865) 48(-5.75,2.865) 49(-5.25,-2.865) 50(-5.25,2.865) 51(-4.75,-2.865) 52(-4.75,2.865) 53(-4.25,-2.865) 54(-4.25,2.865) 55(-3.75,-2.865) 56(-3.75,2.865) 57(-3.25,-2.865) 58(-3.25,2.865) 59(-2.75,-2.865) 60(-2.75,2.865) 61(2.75,-2.865) 62(2.75,2.865) 63(3.25,-2.865) 64(3.25,2.865) 65(3.75,-2.865) 66(3.75,2.865) 67(4.25,-2.865) 68(4.25,2.865) 69(4.75,-2.865) 70(4.75,2.865) 71(5.25,-2.865) 72(5.25,2.865) 73(5.75,-2.865) 74(5.75,2.865) 75(6.25,-2.865) 76(6.25,2.865) 77(6.75,-2.865) 78(6.75,2.865) 79(7.25,-2.865) 80(7.25,2.865) 81(7.75,-2.865) 82(7.75,2.865) 83(8.25,-2.865) 84(8.25,2.865) 85(8.75,-2.865) 86(8.75,2.865) 87(9.25,-2.865) 88(9.25,2.865) 89(9.75,-2.865) 90(9.75,2.865) 91(10.25,-2.865) 92(10.25,2.865) 93(10.75,-2.865) 94(10.75,2.865) 95(11.25,-2.865) 96(11.25,2.865) 97(11.75,-2.865) 98(11.75,2.865) 99(12.25,-2.865) 100(12.25,2.865) 101(12.75,-2.865) 102(12.75,2.865) 103(13.25,-2.865) 104(13.25,2.865) 105(13.75,-2.865) 106(13.75,2.865) 107(14.25,-2.865) 108(14.25,2.865) 109(14.75,-2.865) 110(14.75,2.865) 111(15.25,-2.865) 112(15.25,2.865) 113(15.75,-2.865) 114(15.75,2.865) 115(16.25,-2.865) 116(16.25,2.865) 117(16.75,-2.865) 118(16.75,2.865) 119(17.25,-2.865) 120(17.25,2.865)
  rect 2.54x0.432 smd: P1(-18.065,0) P4(-1.935,0) P5(1.935,0) P8(18.065,0)
  rect 4.699x0.432 smd: P2(-13.175,0) P3(-6.825,0) P6(6.825,0) P7(13.175,0)
BTBS-BGA699-MIRMEZ-203456003
  round 0.5 smd: A3(-28.5,-7.7) A4(-27.6,-7.7) A5(-26.7,-7.7) A6(-25.8,-7.7) A7(-24.9,-7.7) A8(-24,-7.7) A9(-23.1,-7.7) A10(-22.2,-7.7) A11(-21.3,-7.7) A12(-20.4,-7.7) A13(-19.1,-7.7) A14(-18.2,-7.7) A15(-17.3,-7.7) A16(-16.4,-7.7) A17(-15.1,-7.7) A18(-14.2,-7.7) A19(-13.3,-7.7) A20(-12.4,-7.7) A21(-11.1,-7.7) A22(-10.2,-7.7) A23(-9.3,-7.7) A24(-8.4,-7.7) A25(-7.1,-7.7) A26(-6.2,-7.7) A27(-5.3,-7.7) A28(-4.4,-7.7) A29(-3.1,-7.7) A30(-2.2,-7.7) A31(-1.3,-7.7) A32(-0.4,-7.7) A33(0.9,-7.7) A34(1.8,-7.7) A35(2.7,-7.7) A36(3.6,-7.7) A37(4.9,-7.7) A38(5.8,-7.7) A39(6.7,-7.7) A40(7.6,-7.7) A41(8.5,-7.7) A42(9.4,-7.7) A43(10.3,-7.7) A44(11.2,-7.7) A45(12.1,-7.7) A46(13,-7.7) A47(13.9,-7.7) A48(14.8,-7.7) A49(15.7,-7.7) A50(16.6,-7.7) A51(17.5,-7.7) A52(18.4,-7.7) A53(19.3,-7.7) A54(20.2,-7.7) A55(21.1,-7.7) A56(22,-7.7) A57(22.9,-7.7) A58(23.8,-7.7) A59(24.7,-7.7) A60(25.6,-7.7) A61(26.5,-7.7) A62(27.4,-7.7) A63(28.3,-7.7) B3(-28.3,-6.2) B4(-27.4,-6.2) B5(-26.5,-6.2) B6(-25.6,-6.2) B7(-24.7,-6.2) B8(-23.8,-6.2) B9(-22.9,-6.2) B10(-22,-6.2) B11(-21.1,-6.2) B12(-20.2,-6.2) B13(-19.3,-6.2) B14(-18.4,-6.2) B15(-17.1,-6.2) B16(-16.2,-6.2) B17(-15.3,-6.2) B18(-14.4,-6.2) B19(-13.1,-6.2) B20(-12.2,-6.2) B21(-11.3,-6.2) B22(-10.4,-6.2) B23(-9.1,-6.2) B24(-8.2,-6.2) B25(-7.3,-6.2) B26(-6.4,-6.2) B27(-5.1,-6.2) B28(-4.2,-6.2) B29(-3.3,-6.2) B30(-2.4,-6.2) B31(-1.1,-6.2) B32(-0.2,-6.2) B33(0.7,-6.2) B34(1.6,-6.2) B35(2.9,-6.2) B36(3.8,-6.2) B37(4.7,-6.2) B38(5.6,-6.2) B39(6.9,-6.2) B40(7.8,-6.2) B41(8.7,-6.2) B42(9.6,-6.2) B43(10.5,-6.2) B44(11.4,-6.2) B45(12.3,-6.2) B46(13.2,-6.2) B47(14.1,-6.2) B48(15,-6.2) B49(15.9,-6.2) B50(16.8,-6.2) B51(17.7,-6.2) B52(18.6,-6.2) B53(19.5,-6.2) B54(20.4,-6.2) B55(21.3,-6.2) B56(22.2,-6.2) B57(23.1,-6.2) B58(24,-6.2) B59(24.9,-6.2) B60(25.8,-6.2) B61(26.7,-6.2) B62(27.6,-6.2) B63(28.5,-6.2) C1(-30.3,-4.7) C2(-29.4,-4.7) C3(-28.5,-4.7) C4(-27.6,-4.7) C5(-26.7,-4.7) C6(-25.8,-4.7) C7(-24.9,-4.7) C8(-24,-4.7) C9(-23.1,-4.7) C10(-22.2,-4.7) C11(-21.3,-4.7) C12(-20.4,-4.7) C13(-19.1,-4.7) C14(-18.2,-4.7) C15(-17.3,-4.7) C16(-16.4,-4.7) C17(-15.1,-4.7) C18(-14.2,-4.7) C19(-13.3,-4.7) C20(-12.4,-4.7) C21(-11.1,-4.7) C22(-10.2,-4.7) C23(-9.3,-4.7) C24(-8.4,-4.7) C25(-7.1,-4.7) C26(-6.2,-4.7) C27(-5.3,-4.7) C28(-4.4,-4.7) C29(-3.1,-4.7) C30(-2.2,-4.7) C31(-1.3,-4.7) C32(-0.4,-4.7) C33(0.9,-4.7) C34(1.8,-4.7) C35(2.7,-4.7) C36(3.6,-4.7) C37(4.9,-4.7) C38(5.8,-4.7) C39(6.7,-4.7) C40(7.6,-4.7) C41(8.5,-4.7) C42(9.4,-4.7) C43(10.3,-4.7) C44(11.2,-4.7) C45(12.1,-4.7) C46(13,-4.7) C47(13.9,-4.7) C48(14.8,-4.7) C49(15.7,-4.7) C50(16.6,-4.7) C51(17.5,-4.7) C52(18.4,-4.7) C53(19.3,-4.7) C54(20.2,-4.7) C55(21.1,-4.7) C56(22,-4.7) C57(22.9,-4.7) C58(23.8,-4.7) C59(24.7,-4.7) C60(25.6,-4.7) C61(26.5,-4.7) C62(27.4,-4.7) C63(28.3,-4.7) C64(29.2,-4.7) C65(30.1,-4.7) D1(-30.1,-3.2) D2(-29.2,-3.2) D3(-28.3,-3.2) D4(-27.4,-3.2) D5(-26.5,-3.2) D6(-25.6,-3.2) D7(-24.7,-3.2) D8(-23.8,-3.2) D9(-22.9,-3.2) D10(-22,-3.2) D11(-21.1,-3.2) D12(-20.2,-3.2) D13(-19.3,-3.2) D14(-18.4,-3.2) D15(-17.1,-3.2) D16(-16.2,-3.2) D17(-15.3,-3.2) D18(-14.4,-3.2) D19(-13.1,-3.2) D20(-12.2,-3.2) D21(-11.3,-3.2) D22(-10.4,-3.2) D23(-9.1,-3.2) D24(-8.2,-3.2) D25(-7.3,-3.2) D26(-6.4,-3.2) D27(-5.1,-3.2) D28(-4.2,-3.2) D29(-3.3,-3.2) D30(-2.4,-3.2) D31(-1.1,-3.2) D32(-0.2,-3.2) D33(0.7,-3.2) D34(1.6,-3.2) D35(2.9,-3.2) D36(3.8,-3.2) D37(4.7,-3.2) D38(5.6,-3.2) D39(6.9,-3.2) D40(7.8,-3.2) D41(8.7,-3.2) D42(9.6,-3.2) D43(10.5,-3.2) D44(11.4,-3.2) D45(12.3,-3.2) D46(13.2,-3.2) D47(14.1,-3.2) D48(15,-3.2) D49(15.9,-3.2) D50(16.8,-3.2) D51(17.7,-3.2) D52(18.6,-3.2) D53(19.5,-3.2) D54(20.4,-3.2) D55(21.3,-3.2) D56(22.2,-3.2) D57(23.1,-3.2) D58(24,-3.2) D59(24.9,-3.2) D60(25.8,-3.2) D61(26.7,-3.2) D62(27.6,-3.2) D63(28.5,-3.2) D64(29.4,-3.2) D65(30.3,-3.2) E1(-30.3,-1.7) E2(-29.4,-1.7) E3(-28.5,-1.7) E4(-27.6,-1.7) E5(-26.7,-1.7) E6(-25.8,-1.7) E7(-24.9,-1.7) E8(-24,-1.7) E9(-23.1,-1.7) E10(-22.2,-1.7) E11(-21.3,-1.7) E12(-20.4,-1.7) E13(-19.1,-1.7) E14(-18.2,-1.7) E15(-17.3,-1.7) E16(-16.4,-1.7) E17(-15.1,-1.7) E18(-14.2,-1.7) E19(-13.3,-1.7) E20(-12.4,-1.7) E21(-11.1,-1.7) E22(-10.2,-1.7) E23(-9.3,-1.7) E24(-8.4,-1.7) E25(-7.1,-1.7) E26(-6.2,-1.7) E27(-5.3,-1.7) E28(-4.4,-1.7) E29(-3.1,-1.7) E30(-2.2,-1.7) E31(-1.3,-1.7) E32(-0.4,-1.7) E33(0.9,-1.7) E34(1.8,-1.7) E35(2.7,-1.7) E36(3.6,-1.7) E37(4.9,-1.7) E38(5.8,-1.7) E39(6.7,-1.7) E40(7.6,-1.7) E41(8.5,-1.7) E42(9.4,-1.7) E43(10.3,-1.7) E44(11.2,-1.7) E45(12.1,-1.7) E46(13,-1.7) E47(13.9,-1.7) E48(14.8,-1.7) E49(15.7,-1.7) E50(16.6,-1.7) E51(17.5,-1.7) E52(18.4,-1.7) E53(19.3,-1.7) E54(20.2,-1.7) E55(21.1,-1.7) E56(22,-1.7) E57(22.9,-1.7) E58(23.8,-1.7) E59(24.7,-1.7) E60(25.6,-1.7) E61(26.5,-1.7) E62(27.4,-1.7) E63(28.3,-1.7) E64(29.2,-1.7) E65(30.1,-1.7) F1(-30.1,-0.2) F2(-29.2,-0.2) F3(-28.3,-0.2) F4(-27.4,-0.2) F5(-26.5,-0.2) F6(-25.6,-0.2) F7(-24.7,-0.2) F8(-23.8,-0.2) F9(-22.9,-0.2) F10(-22,-0.2) F11(-21.1,-0.2) F12(-20.2,-0.2) F13(-19.3,-0.2) F14(-18.4,-0.2) F15(-17.1,-0.2) F16(-16.2,-0.2) F17(-15.3,-0.2) F18(-14.4,-0.2) F19(-13.1,-0.2) F20(-12.2,-0.2) F21(-11.3,-0.2) F22(-10.4,-0.2) F23(-9.1,-0.2) F24(-8.2,-0.2) F25(-7.3,-0.2) F26(-6.4,-0.2) F27(-5.1,-0.2) F28(-4.2,-0.2) F29(-3.3,-0.2) F30(-2.4,-0.2) F31(-1.1,-0.2) F32(-0.2,-0.2) F33(0.7,-0.2) F34(1.6,-0.2) F35(2.9,-0.2) F36(3.8,-0.2) F37(4.7,-0.2) F38(5.6,-0.2) F39(6.9,-0.2) F40(7.8,-0.2) F41(8.7,-0.2) F42(9.6,-0.2) F43(10.5,-0.2) F44(11.4,-0.2) F45(12.3,-0.2) F46(13.2,-0.2) F47(14.1,-0.2) F48(15,-0.2) F49(15.9,-0.2) F50(16.8,-0.2) F51(17.7,-0.2) F52(18.6,-0.2) F53(19.5,-0.2) F54(20.4,-0.2) F55(21.3,-0.2) F56(22.2,-0.2) F57(23.1,-0.2) F58(24,-0.2) F59(24.9,-0.2) F60(25.8,-0.2) F61(26.7,-0.2) F62(27.6,-0.2) F63(28.5,-0.2) F64(29.4,-0.2) F65(30.3,-0.2) G1(-30.3,1.3) G2(-29.4,1.3) G3(-28.5,1.3) G4(-27.6,1.3) G5(-26.7,1.3) G6(-25.8,1.3) G7(-24.9,1.3) G8(-24,1.3) G9(-23.1,1.3) G10(-22.2,1.3) G11(-21.3,1.3) G12(-20.4,1.3) G13(-19.1,1.3) G14(-18.2,1.3) G15(-17.3,1.3) G16(-16.4,1.3) G17(-15.1,1.3) G18(-14.2,1.3) G19(-13.3,1.3) G20(-12.4,1.3) G21(-11.1,1.3) G22(-10.2,1.3) G23(-9.3,1.3) G24(-8.4,1.3) G25(-7.1,1.3) G26(-6.2,1.3) G27(-5.3,1.3) G28(-4.4,1.3) G29(-3.1,1.3) G30(-2.2,1.3) G31(-1.3,1.3) G32(-0.4,1.3) G33(0.9,1.3) G34(1.8,1.3) G35(2.7,1.3) G36(3.6,1.3) G37(4.9,1.3) G38(5.8,1.3) G39(6.7,1.3) G40(7.6,1.3) G41(8.5,1.3) G42(9.4,1.3) G43(10.3,1.3) G44(11.2,1.3) G45(12.1,1.3) G46(13,1.3) G47(13.9,1.3) G48(14.8,1.3) G49(15.7,1.3) G50(16.6,1.3) G51(17.5,1.3) G52(18.4,1.3) G53(19.3,1.3) G54(20.2,1.3) G55(21.1,1.3) G56(22,1.3) G57(22.9,1.3) G58(23.8,1.3) G59(24.7,1.3) G60(25.6,1.3) G61(26.5,1.3) G62(27.4,1.3) G63(28.3,1.3) G64(29.2,1.3) G65(30.1,1.3) H1(-30.1,2.8) H2(-29.2,2.8) H3(-28.3,2.8) H4(-27.4,2.8) H5(-26.5,2.8) H6(-25.6,2.8) H7(-24.7,2.8) H8(-23.8,2.8) H9(-22.9,2.8) H10(-22,2.8) H11(-21.1,2.8) H12(-20.2,2.8) H13(-19.3,2.8) H14(-18.4,2.8) H15(-17.1,2.8) H16(-16.2,2.8) H17(-15.3,2.8) H18(-14.4,2.8) H19(-13.1,2.8) H20(-12.2,2.8) H21(-11.3,2.8) H22(-10.4,2.8) H23(-9.1,2.8) H24(-8.2,2.8) H25(-7.3,2.8) H26(-6.4,2.8) H27(-5.1,2.8) H28(-4.2,2.8) H29(-3.3,2.8) H30(-2.4,2.8) H31(-1.1,2.8) H32(-0.2,2.8) H33(0.7,2.8) H34(1.6,2.8) H35(2.9,2.8) H36(3.8,2.8) H37(4.7,2.8) H38(5.6,2.8) H39(6.9,2.8) H40(7.8,2.8) H41(8.7,2.8) H42(9.6,2.8) H43(10.5,2.8) H44(11.4,2.8) H45(12.3,2.8) H46(13.2,2.8) H47(14.1,2.8) H48(15,2.8) H49(15.9,2.8) H50(16.8,2.8) H51(17.7,2.8) H52(18.6,2.8) H53(19.5,2.8) H54(20.4,2.8) H55(21.3,2.8) H56(22.2,2.8) H57(23.1,2.8) H58(24,2.8) H59(24.9,2.8) H60(25.8,2.8) H61(26.7,2.8) H62(27.6,2.8) H63(28.5,2.8) H64(29.4,2.8) H65(30.3,2.8) J1(-30.3,4.3) J2(-29.4,4.3) J3(-28.5,4.3) J4(-27.6,4.3) J5(-26.7,4.3) J6(-25.8,4.3) J7(-24.9,4.3) J8(-24,4.3) J9(-23.1,4.3) J10(-22.2,4.3) J11(-21.3,4.3) J12(-20.4,4.3) J13(-19.1,4.3) J14(-18.2,4.3) J15(-17.3,4.3) J16(-16.4,4.3) J17(-15.1,4.3) J18(-14.2,4.3) J19(-13.3,4.3) J20(-12.4,4.3) J21(-11.1,4.3) J22(-10.2,4.3) J23(-9.3,4.3) J24(-8.4,4.3) J25(-7.1,4.3) J26(-6.2,4.3) J27(-5.3,4.3) J28(-4.4,4.3) J29(-3.1,4.3) J30(-2.2,4.3) J31(-1.3,4.3) J32(-0.4,4.3) J33(0.9,4.3) J34(1.8,4.3) J35(2.7,4.3) J36(3.6,4.3) J37(4.9,4.3) J38(5.8,4.3) J39(6.7,4.3) J40(7.6,4.3) J41(8.5,4.3) J42(9.4,4.3) J43(10.3,4.3) J44(11.2,4.3) J45(12.1,4.3) J46(13,4.3) J47(13.9,4.3) J48(14.8,4.3) J49(15.7,4.3) J50(16.6,4.3) J51(17.5,4.3) J52(18.4,4.3) J53(19.3,4.3) J54(20.2,4.3) J55(21.1,4.3) J56(22,4.3) J57(22.9,4.3) J58(23.8,4.3) J59(24.7,4.3) J60(25.6,4.3) J61(26.5,4.3) J62(27.4,4.3) J63(28.3,4.3) J64(29.2,4.3) J65(30.1,4.3) K3(-28.3,5.8) K4(-27.4,5.8) K5(-26.5,5.8) K6(-25.6,5.8) K7(-24.7,5.8) K8(-23.8,5.8) K9(-22.9,5.8) K10(-22,5.8) K11(-21.1,5.8) K12(-20.2,5.8) K13(-19.3,5.8) K14(-18.4,5.8) K15(-17.1,5.8) K16(-16.2,5.8) K17(-15.3,5.8) K18(-14.4,5.8) K19(-13.1,5.8) K20(-12.2,5.8) K21(-11.3,5.8) K22(-10.4,5.8) K23(-9.1,5.8) K24(-8.2,5.8) K25(-7.3,5.8) K26(-6.4,5.8) K27(-5.1,5.8) K28(-4.2,5.8) K29(-3.3,5.8) K30(-2.4,5.8) K31(-1.1,5.8) K32(-0.2,5.8) K33(0.7,5.8) K34(1.6,5.8) K35(2.9,5.8) K36(3.8,5.8) K37(4.7,5.8) K38(5.6,5.8) K39(6.9,5.8) K40(7.8,5.8) K41(8.7,5.8) K42(9.6,5.8) K43(10.5,5.8) K44(11.4,5.8) K45(12.3,5.8) K46(13.2,5.8) K47(14.1,5.8) K48(15,5.8) K49(15.9,5.8) K50(16.8,5.8) K51(17.7,5.8) K52(18.6,5.8) K53(19.5,5.8) K54(20.4,5.8) K55(21.3,5.8) K56(22.2,5.8) K57(23.1,5.8) K58(24,5.8) K59(24.9,5.8) K60(25.8,5.8) K61(26.7,5.8) K62(27.6,5.8) K63(28.5,5.8) L3(-28.5,7.3) L4(-27.6,7.3) L5(-26.7,7.3) L6(-25.8,7.3) L7(-24.9,7.3) L8(-24,7.3) L9(-23.1,7.3) L10(-22.2,7.3) L11(-21.3,7.3) L12(-20.4,7.3) L13(-19.1,7.3) L14(-18.2,7.3) L15(-17.3,7.3) L16(-16.4,7.3) L17(-15.1,7.3) L18(-14.2,7.3) L19(-13.3,7.3) L20(-12.4,7.3) L21(-11.1,7.3) L22(-10.2,7.3) L23(-9.3,7.3) L24(-8.4,7.3) L25(-7.1,7.3) L26(-6.2,7.3) L27(-5.3,7.3) L28(-4.4,7.3) L29(-3.1,7.3) L30(-2.2,7.3) L31(-1.3,7.3) L32(-0.4,7.3) L33(0.9,7.3) L34(1.8,7.3) L35(2.7,7.3) L36(3.6,7.3) L37(4.9,7.3) L38(5.8,7.3) L39(6.7,7.3) L40(7.6,7.3) L41(8.5,7.3) L42(9.4,7.3) L43(10.3,7.3) L44(11.2,7.3) L45(12.1,7.3) L46(13,7.3) L47(13.9,7.3) L48(14.8,7.3) L49(15.7,7.3) L50(16.6,7.3) L51(17.5,7.3) L52(18.4,7.3) L53(19.3,7.3) L54(20.2,7.3) L55(21.1,7.3) L56(22,7.3) L57(22.9,7.3) L58(23.8,7.3) L59(24.7,7.3) L60(25.6,7.3) L61(26.5,7.3) L62(27.4,7.3) L63(28.3,7.3)
CM-CHOKE-1210-4P
  rect 0.61x0.406 smd: 1(-0.584,0.33) 2(0.584,0.33) 3(0.584,-0.33) 4(-0.584,-0.33)
CM-CHOKE-2012-4P
  rect 0.914x0.406 smd: 1(-0.875,0.4) 2(0.875,0.4) 3(0.875,-0.4) 4(-0.875,-0.4)
CM-CHOKE-ACT45B-4P
  rect 1.346x0.914 smd: 1(-2.275,1.25) 2(2.275,1.25) 3(2.275,-1.25) 4(-2.275,-1.25)
CONHD2X1
  rect 1.524x1.524 hole 1.016: 1(0,0)
  round 1.524 hole 1.016: 2(2.54,0)
CONHD3X1
  rect 1.524x1.524 hole 1.016: 1(0,0)
  round 1.524 hole 1.016: 2(2.54,0) 3(5.08,0)
CONHD4X1
  rect 1.524x1.524 hole 1.016: 1(0,0)
  round 1.524 hole 1.016: 2(2.54,0) 3(5.08,0) 4(7.62,0)
CONHS5X2P127_WP
  round 0.813 hole 0.813 unplated: (-1.905,0) (1.905,0)
  rect 0.762x2.261 smd: 1(-2.54,1.875) 2(-1.27,1.875) 3(0,1.875) 4(1.27,1.875) 5(2.54,1.875) 6(-2.54,-1.875) 7(-1.27,-1.875) 8(0,-1.875) 9(1.27,-1.875) 10(2.54,-1.875)
DFN8_2X3P05H06-TH10X63
  rect 0.305x0.61 smd: 1(-0.75,-1.4) 2(-0.25,-1.4) 3(0.25,-1.4) 4(0.75,-1.4) 5(0.75,1.4) 6(0.25,1.4) 7(-0.25,1.4) 8(-0.75,1.4)
  rect 1.6x0.254 smd: 9(0,0)
DFN10_2D5X1P05H06
  rect 0.254x0.686 smd: 1(-1,-0.44) 2(-0.5,-0.44) 4(0.5,-0.44) 5(1,-0.44) 6(1,0.44) 7(0.5,0.44) 9(-0.5,0.44) 10(-1,0.44)
  rect 0.406x0.711 smd: 3(0,-0.44) 8(0,0.44)
DFN1006-2L
  rect 0.61x0.559 smd: 1(0,0.425) 2(0,-0.425)
DIPICS6P_RDL03W
  rect 1.6x1.6 hole 0.889: 1(0,0)
  round 1.6 hole 0.889: 2(2.54,0) 3(5.08,0) 6(12.7,0) 7(15.24,0) 8(17.78,0)
  round 2.591 hole 1.295: 9(3.632,-6.096) 12(14.224,3.302)
  rect 1.27x0.305 smd: 10(14.224,-6.096) 11(3.632,3.302)
FPC8P05_51540
  rect 0.305x0.889 smd: 1(-1.75,0) 2(-1.25,0) 3(-0.75,0) 4(-0.25,0) 5(0.25,0) 6(0.75,0) 7(1.25,0) 8(1.75,0)
  rect 0.813x2.007 smd: P1(3.45,-3.175) P2(-3.45,-3.175)
HDMI-S19PV_CHD-8X0A-190
  rect 0.305x1.702 smd: 1(-4.21,-2.45) 2(-3.71,-2.45) 3(-3.21,-2.45) 4(-2.71,-2.45) 5(-2.21,-2.45) 6(-1.71,-2.45) 7(-1.21,-2.45) 8(-0.71,-2.45) 9(-0.21,-2.45) 10(0.29,-2.45) 11(0.79,-2.45) 12(1.29,-2.45) 13(1.79,-2.45) 14(2.29,-2.45) 15(2.79,-2.45) 16(3.29,-2.45) 17(3.79,-2.45) 18(4.29,-2.45) 19(4.79,-2.45)
  round 2.286 hole 1.295: X1(-7.25,0) X2(0,3.3) X3(7.25,0)
HOLEC236D158-PT
  round 5.994 hole 4.013: 1(0,0)
HOLEC256D166-PT
  round 6.502 hole 4.216: 1(0,0)
HOLEC256D177-PT
  round 6.502 hole 4.496: 1(0,0)
HOLETB354C158D158N-V8_OSP
  round 4.013 hole 4.013 unplated: (0,0)
  round 1.219 hole 0.711: 2(3.048,0) 3(2.159,2.159) 4(0,3.048) 5(-2.159,2.159) 6(-3.048,0) 7(-2.159,-2.159) 8(0,-3.048) 9(2.159,-2.159)
IHLP2525_LS-030
  rect 2.21x3.505 smd: 1(-2.946,0) 2(2.946,0)
IHLP4040-S_LS-040
  rect 3.505x4.013 smd: 1(-4.75,0) 2(4.75,0)
IHLP5050-S_LS-050
  rect 3.505x3.302 smd: 1(-5.742,0) 2(5.742,0)
LQFP64_10X10P05H16
  rect 1.397x0.279 smd: 1(-5.8,3.75) 2(-5.8,3.25) 3(-5.8,2.75) 4(-5.8,2.25) 5(-5.8,1.75) 6(-5.8,1.25) 7(-5.8,0.75) 8(-5.8,0.25) 9(-5.8,-0.25) 10(-5.8,-0.75) 11(-5.8,-1.25) 12(-5.8,-1.75) 13(-5.8,-2.25) 14(-5.8,-2.75) 15(-5.8,-3.25) 16(-5.8,-3.75) 33(5.8,-3.75) 34(5.8,-3.25) 35(5.8,-2.75) 36(5.8,-2.25) 37(5.8,-1.75) 38(5.8,-1.25) 39(5.8,-0.75) 40(5.8,-0.25) 41(5.8,0.25) 42(5.8,0.75) 43(5.8,1.25) 44(5.8,1.75) 45(5.8,2.25) 46(5.8,2.75) 47(5.8,3.25) 48(5.8,3.75)
  rect 0.279x1.397 smd: 17(-3.75,-5.8) 18(-3.25,-5.8) 19(-2.75,-5.8) 20(-2.25,-5.8) 21(-1.75,-5.8) 22(-1.25,-5.8) 23(-0.75,-5.8) 24(-0.25,-5.8) 25(0.25,-5.8) 26(0.75,-5.8) 27(1.25,-5.8) 28(1.75,-5.8) 29(2.25,-5.8) 30(2.75,-5.8) 31(3.25,-5.8) 32(3.75,-5.8) 49(3.75,5.8) 50(3.25,5.8) 51(2.75,5.8) 52(2.25,5.8) 53(1.75,5.8) 54(1.25,5.8) 55(0.75,5.8) 56(0.25,5.8) 57(-0.25,5.8) 58(-0.75,5.8) 59(-1.25,5.8) 60(-1.75,5.8) 61(-2.25,5.8) 62(-2.75,5.8) 63(-3.25,5.8) 64(-3.75,5.8)
M2-67H40-E-2230
  round 1.092 hole 1.092 unplated: (-10,0)
  round 1.6 hole 1.6 unplated: (10,0)
  rect 0.305x1.549 smd: 1(-9.25,5.275) 2(-9,-2.275) 3(-8.75,5.275) 4(-8.5,-2.275) 5(-8.25,5.275) 6(-8,-2.275) 7(-7.75,5.275) 8(-7.5,-2.275) 9(-7.25,5.275) 10(-7,-2.275) 11(-6.75,5.275) 12(-6.5,-2.275) 13(-6.25,5.275) 14(-6,-2.275) 15(-5.75,5.275) 16(-5.5,-2.275) 17(-5.25,5.275) 18(-5,-2.275) 19(-4.75,5.275) 20(-4.5,-2.275) 21(-4.25,5.275) 22(-4,-2.275) 23(-3.75,5.275) 32(-1.5,-2.275) 33(-1.25,5.275) 34(-1,-2.275) 35(-0.75,5.275) 36(-0.5,-2.275) 37(-0.25,5.275) 38(0,-2.275) 39(0.25,5.275) 40(0.5,-2.275) 41(0.75,5.275) 42(1,-2.275) 43(1.25,5.275) 44(1.5,-2.275) 45(1.75,5.275) 46(2,-2.275) 47(2.25,5.275) 48(2.5,-2.275) 49(2.75,5.275) 50(3,-2.275) 51(3.25,5.275) 52(3.5,-2.275) 53(3.75,5.275) 54(4,-2.275) 55(4.25,5.275) 56(4.5,-2.275) 57(4.75,5.275) 58(5,-2.275) 59(5.25,5.275) 60(5.5,-2.275) 61(5.75,5.275) 62(6,-2.275) 63(6.25,5.275) 64(6.5,-2.275) 65(6.75,5.275) 66(7,-2.275) 67(7.25,5.275) 68(7.5,-2.275) 69(7.75,5.275) 70(8,-2.275) 71(8.25,5.275) 72(8.5,-2.275) 73(8.75,5.275) 74(9,-2.275) 75(9.25,5.275)
  rect 1.194x2.743 smd: P1(-10.35,4.5) P2(10.35,4.5)
M2-67H85-B-3052
  round 1.092 hole 1.092 unplated: (-10,0)
  round 1.6 hole 1.6 unplated: (10,0)
  rect 0.305x1.549 smd: 1(-9.25,4.725) 2(-9,-1.725) 3(-8.75,4.725) 4(-8.5,-1.725) 5(-8.25,4.725) 6(-8,-1.725) 7(-7.75,4.725) 8(-7.5,-1.725) 9(-7.25,4.725) 10(-7,-1.725) 11(-6.75,4.725) 20(-4.5,-1.725) 21(-4.25,4.725) 22(-4,-1.725) 23(-3.75,4.725) 24(-3.5,-1.725) 25(-3.25,4.725) 26(-3,-1.725) 27(-2.75,4.725) 28(-2.5,-1.725) 29(-2.25,4.725) 30(-2,-1.725) 31(-1.75,4.725) 32(-1.5,-1.725) 33(-1.25,4.725) 34(-1,-1.725) 35(-0.75,4.725) 36(-0.5,-1.725) 37(-0.25,4.725) 38(0,-1.725) 39(0.25,4.725) 40(0.5,-1.725) 41(0.75,4.725) 42(1,-1.725) 43(1.25,4.725) 44(1.5,-1.725) 45(1.75,4.725) 46(2,-1.725) 47(2.25,4.725) 48(2.5,-1.725) 49(2.75,4.725) 50(3,-1.725) 51(3.25,4.725) 52(3.5,-1.725) 53(3.75,4.725) 54(4,-1.725) 55(4.25,4.725) 56(4.5,-1.725) 57(4.75,4.725) 58(5,-1.725) 59(5.25,4.725) 60(5.5,-1.725) 61(5.75,4.725) 62(6,-1.725) 63(6.25,4.725) 64(6.5,-1.725) 65(6.75,4.725) 66(7,-1.725) 67(7.25,4.725) 68(7.5,-1.725) 69(7.75,4.725) 70(8,-1.725) 71(8.25,4.725) 72(8.5,-1.725) 73(8.75,4.725) 74(9,-1.725) 75(9.25,4.725)
  rect 1.194x2.743 smd: P1(-10.35,4.5) P2(10.35,4.5)
M2-67H85-M-2280
  round 1.092 hole 1.092 unplated: (-10,0)
  round 1.6 hole 1.6 unplated: (10,0)
  rect 0.305x1.549 smd: 1(-9.25,4.725) 2(-9,-1.725) 3(-8.75,4.725) 4(-8.5,-1.725) 5(-8.25,4.725) 6(-8,-1.725) 7(-7.75,4.725) 8(-7.5,-1.725) 9(-7.25,4.725) 10(-7,-1.725) 11(-6.75,4.725) 12(-6.5,-1.725) 13(-6.25,4.725) 14(-6,-1.725) 15(-5.75,4.725) 16(-5.5,-1.725) 17(-5.25,4.725) 18(-5,-1.725) 19(-4.75,4.725) 20(-4.5,-1.725) 21(-4.25,4.725) 22(-4,-1.725) 23(-3.75,4.725) 24(-3.5,-1.725) 25(-3.25,4.725) 26(-3,-1.725) 27(-2.75,4.725) 28(-2.5,-1.725) 29(-2.25,4.725) 30(-2,-1.725) 31(-1.75,4.725) 32(-1.5,-1.725) 33(-1.25,4.725) 34(-1,-1.725) 35(-0.75,4.725) 36(-0.5,-1.725) 37(-0.25,4.725) 38(0,-1.725) 39(0.25,4.725) 40(0.5,-1.725) 41(0.75,4.725) 42(1,-1.725) 43(1.25,4.725) 44(1.5,-1.725) 45(1.75,4.725) 46(2,-1.725) 47(2.25,4.725) 48(2.5,-1.725) 49(2.75,4.725) 50(3,-1.725) 51(3.25,4.725) 52(3.5,-1.725) 53(3.75,4.725) 54(4,-1.725) 55(4.25,4.725) 56(4.5,-1.725) 57(4.75,4.725) 58(5,-1.725) 67(7.25,4.725) 68(7.5,-1.725) 69(7.75,4.725) 70(8,-1.725) 71(8.25,4.725) 72(8.5,-1.725) 73(8.75,4.725) 74(9,-1.725) 75(9.25,4.725)
  rect 1.194x2.743 smd: P1(-10.35,4.5) P2(10.35,4.5)
OSC3225
  rect 1.194x0.94 smd: 1(-1.1,-0.875) 2(1.1,-0.875) 3(1.1,0.875) 4(-1.1,0.875)
POWERPAK-SO8
  rect 0.61x1.27 smd: 1(-1.905,-3.505) 2(-0.635,-3.505) 3(0.635,-3.505) 4(1.905,-3.505) 5(1.905,2.261) 6(0.635,2.261) 7(-0.635,2.261) 8(-1.905,2.261)
  rect 4.826x3.81 smd: 9(0,0)
QFN8_1D25X1D5P05H08
  rect 0.533x0.254 smd: 1(-0.565,0.5) 3(-0.565,-0.5) 5(0.565,-0.5) 7(0.565,0.5)
  rect 0.711x0.254 smd: 2(-0.475,0) 6(0.475,0)
  rect 0.254x0.584 smd: 4(0,-0.665) 8(0,0.665)
QFN10_3X3H13_MUN3CA
  rect 0.61x0.254 smd: 1(-1.2,0.675) 2(-1.2,0.225) 3(-1.2,-0.225) 4(-1.2,-0.675)
  rect 2.413x0.508 smd: 5(0,-1.247) 8(0,1.247)
  rect 0.61x0.711 smd: 6(1.2,-0.45) 7(1.2,0.45)
  rect 0.406x0.711 smd: 9(0.26,0.45) 10(-0.26,-0.45)
QFN12_2D5X3P04H10_MPS
  rect 1.041x0.203 smd: 1(-1.025,0.7) 2(-1.025,0.3) 7(1.025,0.3) 8(1.025,0.7)
  round 0 smd: 3(-1.05,-0.35) 6(1.05,-0.35)
  custom 0.263x0.263 smd: 4(-1.05,-1) 5(1.05,-1)
  rect 0.203x0.711 smd: 9(0.6,1.45) 10(0.2,1.45) 11(-0.2,1.45) 12(-0.6,1.45)
QFN12_2X3P05H10_MPS
  rect 1.549x0.305 smd: 1(-0.5,0.5) 2(-0.5,-0.5) 7(0.5,0)
  rect 0.305x0.711 smd: 3(-0.75,-1.4) 4(-0.25,-1.4) 5(0.25,-1.4) 6(0.75,-1.4) 9(0.75,1.4) 10(0.25,1.4) 11(-0.25,1.4) 12(-0.75,1.4)
  rect 0.711x0.305 smd: 8(0.9,0.5)
QFN20_3X3P05H08-TH67
  rect 0.292x0.292 smd: 1(-1.265,1.256) 6(-1.265,-1.256) 11(1.265,-1.256) 16(1.265,1.256)
  rect 0.559x0.254 smd: 2(-1.35,0.75) 3(-1.35,0.25) 4(-1.35,-0.25) 5(-1.35,-0.75) 12(1.35,-0.75) 13(1.35,-0.25) 14(1.35,0.25) 15(1.35,0.75)
  rect 0.254x0.559 smd: 7(-0.75,-1.35) 8(-0.25,-1.35) 9(0.25,-1.35) 10(0.75,-1.35) 17(0.75,1.35) 18(0.25,1.35) 19(-0.25,1.35) 20(-0.75,1.35)
  rect 1.702x1.702 smd: 21(0,0)
QFN20_4D5X3D5P05H10-TH67X106
  rect 0.254x0.61 smd: 1(-0.75,2.15) 10(-0.75,-2.15) 11(0.75,-2.15) 20(0.75,2.15)
  rect 0.61x0.254 smd: 2(-1.65,1.75) 3(-1.65,1.25) 4(-1.65,0.75) 5(-1.65,0.25) 6(-1.65,-0.25) 7(-1.65,-0.75) 8(-1.65,-1.25) 9(-1.65,-1.75) 12(1.65,-1.75) 13(1.65,-1.25) 14(1.65,-0.75) 15(1.65,-0.25) 16(1.65,0.25) 17(1.65,0.75) 18(1.65,1.25) 19(1.65,1.75)
  rect 1.702x2.692 smd: 21(0,0)
QFN21_3X4PH10_MPS
  rect 0.889x0.305 smd: 1(-1.35,1.7)
  rect 0.813x0.203 smd: 2(-1.4,1.2) 3(-1.4,0.8) 4(-1.4,0.4) 5(-1.4,0) 6(-1.4,-0.4) 7(-1.4,-0.8) 8(-1.4,-1.2)
  rect 0.813x0.305 smd: 9(-1.4,-1.7) 19(1.4,1.7)
  rect 0.305x2.007 smd: 10(-0.3,-1.3) 20(0.3,1.3) 21(-0.3,1.3)
  custom 0.2x0.2 smd: 11(1.4,-1.7)
  round 0 smd: 12(1.4,-1.2) 13(1.4,-0.8) 14(1.4,-0.4) 15(1.4,0) 16(1.4,0.4) 17(1.4,0.8) 18(1.4,1.2)
QFN32_5X5P05H06-TH142
  rect 0.813x0.305 smd: 1(-2.475,1.75) 2(-2.475,1.25) 3(-2.475,0.75) 4(-2.475,0.25) 5(-2.475,-0.25) 6(-2.475,-0.75) 7(-2.475,-1.25) 8(-2.475,-1.75) 17(2.475,-1.75) 18(2.475,-1.25) 19(2.475,-0.75) 20(2.475,-0.25) 21(2.475,0.25) 22(2.475,0.75) 23(2.475,1.25) 24(2.475,1.75)
  rect 0.305x0.813 smd: 9(-1.75,-2.475) 10(-1.25,-2.475) 11(-0.75,-2.475) 12(-0.25,-2.475) 13(0.25,-2.475) 14(0.75,-2.475) 15(1.25,-2.475) 16(1.75,-2.475) 25(1.75,2.475) 26(1.25,2.475) 27(0.75,2.475) 28(0.25,2.475) 29(-0.25,2.475) 30(-0.75,2.475) 31(-1.25,2.475) 32(-1.75,2.475)
  rect 3.607x3.607 smd: 33(0,0)
QFN48_6X6P04H10-TH173
  rect 0.711x0.203 smd: 1(-2.9,2.2) 2(-2.9,1.8) 3(-2.9,1.4) 4(-2.9,1) 5(-2.9,0.6) 6(-2.9,0.2) 7(-2.9,-0.2) 8(-2.9,-0.6) 9(-2.9,-1) 10(-2.9,-1.4) 11(-2.9,-1.8) 12(-2.9,-2.2) 25(2.9,-2.2) 26(2.9,-1.8) 27(2.9,-1.4) 28(2.9,-1) 29(2.9,-0.6) 30(2.9,-0.2) 31(2.9,0.2) 32(2.9,0.6) 33(2.9,1) 34(2.9,1.4) 35(2.9,1.8) 36(2.9,2.2)
  rect 0.203x0.711 smd: 13(-2.2,-2.9) 14(-1.8,-2.9) 15(-1.4,-2.9) 16(-1,-2.9) 17(-0.6,-2.9) 18(-0.2,-2.9) 19(0.2,-2.9) 20(0.6,-2.9) 21(1,-2.9) 22(1.4,-2.9) 23(1.8,-2.9) 24(2.2,-2.9) 37(2.2,2.9) 38(1.8,2.9) 39(1.4,2.9) 40(1,2.9) 41(0.6,2.9) 42(0.2,2.9) 43(-0.2,2.9) 44(-0.6,2.9) 45(-1,2.9) 46(-1.4,2.9) 47(-1.8,2.9) 48(-2.2,2.9)
  rect 4.394x4.394 smd: 49(0,0)
QFN56_8X8P05H10-TH224
  rect 0.61x0.24 smd: 1(-3.9,3.25) 2(-3.9,2.75) 3(-3.9,2.25) 4(-3.9,1.75) 5(-3.9,1.25) 6(-3.9,0.75) 7(-3.9,0.25) 8(-3.9,-0.25) 9(-3.9,-0.75) 10(-3.9,-1.25) 11(-3.9,-1.75) 12(-3.9,-2.25) 13(-3.9,-2.75) 14(-3.9,-3.25) 29(3.9,-3.25) 30(3.9,-2.75) 31(3.9,-2.25) 32(3.9,-1.75) 33(3.9,-1.25) 34(3.9,-0.75) 35(3.9,-0.25) 36(3.9,0.25) 37(3.9,0.75) 38(3.9,1.25) 39(3.9,1.75) 40(3.9,2.25) 41(3.9,2.75) 42(3.9,3.25)
  rect 0.24x0.61 smd: 15(-3.25,-3.9) 16(-2.75,-3.9) 17(-2.25,-3.9) 18(-1.75,-3.9) 19(-1.25,-3.9) 20(-0.75,-3.9) 21(-0.25,-3.9) 22(0.25,-3.9) 23(0.75,-3.9) 24(1.25,-3.9) 25(1.75,-3.9) 26(2.25,-3.9) 27(2.75,-3.9) 28(3.25,-3.9) 43(3.25,3.9) 44(2.75,3.9) 45(2.25,3.9) 46(1.75,3.9) 47(1.25,3.9) 48(0.75,3.9) 49(0.25,3.9) 50(-0.25,3.9) 51(-0.75,3.9) 52(-1.25,3.9) 53(-1.75,3.9) 54(-2.25,3.9) 55(-2.75,3.9) 56(-3.25,3.9)
  rect 5.69x5.69 smd: 57(0,0)
QFN64_8X8P04H09-TH256
  rect 0.813x0.203 smd: 1(-3.9,3) 2(-3.9,2.6) 3(-3.9,2.2) 4(-3.9,1.8) 5(-3.9,1.4) 6(-3.9,1) 7(-3.9,0.6) 8(-3.9,0.2) 9(-3.9,-0.2) 10(-3.9,-0.6) 11(-3.9,-1) 12(-3.9,-1.4) 13(-3.9,-1.8) 14(-3.9,-2.2) 15(-3.9,-2.6) 16(-3.9,-3) 33(3.9,-3) 34(3.9,-2.6) 35(3.9,-2.2) 36(3.9,-1.8) 37(3.9,-1.4) 38(3.9,-1) 39(3.9,-0.6) 40(3.9,-0.2) 41(3.9,0.2) 42(3.9,0.6) 43(3.9,1) 44(3.9,1.4) 45(3.9,1.8) 46(3.9,2.2) 47(3.9,2.6) 48(3.9,3)
  rect 0.203x0.813 smd: 17(-3,-3.9) 18(-2.6,-3.9) 19(-2.2,-3.9) 20(-1.8,-3.9) 21(-1.4,-3.9) 22(-1,-3.9) 23(-0.6,-3.9) 24(-0.2,-3.9) 25(0.2,-3.9) 26(0.6,-3.9) 27(1,-3.9) 28(1.4,-3.9) 29(1.8,-3.9) 30(2.2,-3.9) 31(2.6,-3.9) 32(3,-3.9) 49(3,3.9) 50(2.6,3.9) 51(2.2,3.9) 52(1.8,3.9) 53(1.4,3.9) 54(1,3.9) 55(0.6,3.9) 56(0.2,3.9) 57(-0.2,3.9) 58(-0.6,3.9) 59(-1,3.9) 60(-1.4,3.9) 61(-1.8,3.9) 62(-2.2,3.9) 63(-2.6,3.9) 64(-3,3.9)
  rect 6.502x6.502 smd: 65(0,0)
QFN64_9X9P05H10-TH142
  rect 0.914x0.229 smd: 1(-4.551,3.75) 2(-4.551,3.25) 3(-4.551,2.75) 4(-4.551,2.25) 5(-4.551,1.75) 6(-4.551,1.25) 7(-4.551,0.75) 8(-4.551,0.25) 9(-4.551,-0.25) 10(-4.551,-0.75) 11(-4.551,-1.25) 12(-4.551,-1.75) 13(-4.551,-2.25) 14(-4.551,-2.75) 15(-4.551,-3.25) 16(-4.551,-3.75) 33(4.551,-3.75) 34(4.551,-3.25) 35(4.551,-2.75) 36(4.551,-2.25) 37(4.551,-1.75) 38(4.551,-1.25) 39(4.551,-0.75) 40(4.551,-0.25) 41(4.551,0.25) 42(4.551,0.75) 43(4.551,1.25) 44(4.551,1.75) 45(4.551,2.25) 46(4.551,2.75) 47(4.551,3.25) 48(4.551,3.75)
  rect 0.229x0.914 smd: 17(-3.75,-4.551) 18(-3.25,-4.551) 19(-2.75,-4.551) 20(-2.25,-4.551) 21(-1.75,-4.551) 22(-1.25,-4.551) 23(-0.75,-4.551) 24(-0.25,-4.551) 25(0.25,-4.551) 26(0.75,-4.551) 27(1.25,-4.551) 28(1.75,-4.551) 29(2.25,-4.551) 30(2.75,-4.551) 31(3.25,-4.551) 32(3.75,-4.551) 49(3.75,4.551) 50(3.25,4.551) 51(2.75,4.551) 52(2.25,4.551) 53(1.75,4.551) 54(1.25,4.551) 55(0.75,4.551) 56(0.25,4.551) 57(-0.25,4.551) 58(-0.75,4.551) 59(-1.25,4.551) 60(-1.75,4.551) 61(-2.25,4.551) 62(-2.75,4.551) 63(-3.25,4.551) 64(-3.75,4.551)
  rect 3.607x3.607 smd: 65(0,0)
QFN76_9X9P04H09-TH252
  rect 0.864x0.241 smd: 1(-4.4,3.6) 2(-4.4,3.2) 3(-4.4,2.8) 4(-4.4,2.4) 5(-4.4,2) 6(-4.4,1.6) 7(-4.4,1.2) 8(-4.4,0.8) 9(-4.4,0.4) 10(-4.4,0) 11(-4.4,-0.4) 12(-4.4,-0.8) 13(-4.4,-1.2) 14(-4.4,-1.6) 15(-4.4,-2) 16(-4.4,-2.4) 17(-4.4,-2.8) 18(-4.4,-3.2) 19(-4.4,-3.6) 39(4.4,-3.6) 40(4.4,-3.2) 41(4.4,-2.8) 42(4.4,-2.4) 43(4.4,-2) 44(4.4,-1.6) 45(4.4,-1.2) 46(4.4,-0.8) 47(4.4,-0.4) 48(4.4,0) 49(4.4,0.4) 50(4.4,0.8) 51(4.4,1.2) 52(4.4,1.6) 53(4.4,2) 54(4.4,2.4) 55(4.4,2.8) 56(4.4,3.2) 57(4.4,3.6)
  rect 0.241x0.864 smd: 20(-3.6,-4.4) 21(-3.2,-4.4) 22(-2.8,-4.4) 23(-2.4,-4.4) 24(-2,-4.4) 25(-1.6,-4.4) 26(-1.2,-4.4) 27(-0.8,-4.4) 28(-0.4,-4.4) 29(0,-4.4) 30(0.4,-4.4) 31(0.8,-4.4) 32(1.2,-4.4) 33(1.6,-4.4) 34(2,-4.4) 35(2.4,-4.4) 36(2.8,-4.4) 37(3.2,-4.4) 38(3.6,-4.4) 58(3.6,4.4) 59(3.2,4.4) 60(2.8,4.4) 61(2.4,4.4) 62(2,4.4) 63(1.6,4.4) 64(1.2,4.4) 65(0.8,4.4) 66(0.4,4.4) 67(0,4.4) 68(-0.4,4.4) 69(-0.8,4.4) 70(-1.2,4.4) 71(-1.6,4.4) 72(-2,4.4) 73(-2.4,4.4) 74(-2.8,4.4) 75(-3.2,4.4) 76(-3.6,4.4)
  rect 6.401x6.401 smd: 77(0,0)
QFN88_10X10P04H10-TH
  rect 1.016x0.229 smd: 1(-4.95,4.2) 2(-4.95,3.8) 3(-4.95,3.4) 4(-4.95,3) 5(-4.95,2.6) 6(-4.95,2.2) 7(-4.95,1.8) 8(-4.95,1.4) 9(-4.95,1) 10(-4.95,0.6) 11(-4.95,0.2) 12(-4.95,-0.2) 13(-4.95,-0.6) 14(-4.95,-1) 15(-4.95,-1.4) 16(-4.95,-1.8) 17(-4.95,-2.2) 18(-4.95,-2.6) 19(-4.95,-3) 20(-4.95,-3.4) 21(-4.95,-3.8) 22(-4.95,-4.2) 45(4.95,-4.2) 46(4.95,-3.8) 47(4.95,-3.4) 48(4.95,-3) 49(4.95,-2.6) 50(4.95,-2.2) 51(4.95,-1.8) 52(4.95,-1.4) 53(4.95,-1) 54(4.95,-0.6) 55(4.95,-0.2) 56(4.95,0.2) 57(4.95,0.6) 58(4.95,1) 59(4.95,1.4) 60(4.95,1.8) 61(4.95,2.2) 62(4.95,2.6) 63(4.95,3) 64(4.95,3.4) 65(4.95,3.8) 66(4.95,4.2)
  rect 0.229x1.016 smd: 23(-4.2,-4.95) 24(-3.8,-4.95) 25(-3.4,-4.95) 26(-3,-4.95) 27(-2.6,-4.95) 28(-2.2,-4.95) 29(-1.8,-4.95) 30(-1.4,-4.95) 31(-1,-4.95) 32(-0.6,-4.95) 33(-0.2,-4.95) 34(0.2,-4.95) 35(0.6,-4.95) 36(1,-4.95) 37(1.4,-4.95) 38(1.8,-4.95) 39(2.2,-4.95) 40(2.6,-4.95) 41(3,-4.95) 42(3.4,-4.95) 43(3.8,-4.95) 44(4.2,-4.95) 67(4.2,4.95) 68(3.8,4.95) 69(3.4,4.95) 70(3,4.95) 71(2.6,4.95) 72(2.2,4.95) 73(1.8,4.95) 74(1.4,4.95) 75(1,4.95) 76(0.6,4.95) 77(0.2,4.95) 78(-0.2,4.95) 79(-0.6,4.95) 80(-1,4.95) 81(-1.4,4.95) 82(-1.8,4.95) 83(-2.2,4.95) 84(-2.6,4.95) 85(-3,4.95) 86(-3.4,4.95) 87(-3.8,4.95) 88(-4.2,4.95)
  rect 7.798x7.798 smd: 89(0,0)
SER2918H_LS-178
  rect 5.334x5.588 smd: 1(-5.08,-14.351) 2(5.08,-14.351)
  rect 6.35x5.283 smd: 3(0,7.722)
SHORT-0402
  rect 0.762x0.508 smd: 1(-0.378,0) 2(0.378,0)
SHORT-0603
  rect 1.143x0.914 smd: 1(-0.569,0) 2(0.569,0)
SHORT_25X40
  rect 0.635x1.016 smd: 1(-0.318,0) 2(0.318,0)
SIM_N0601B010
  rect 0.914x1.219 smd: C1(-3.175,0) C2(-0.635,0) C3(1.905,0) C5(-1.905,0) C6(0.635,0) C7(3.175,0)
  rect 1.295x1.803 smd: P1(-5.85,-4.1) P2(5.85,-4.1) P3(5.85,-12.9) P4(-5.85,-12.9)
SM0201_C
  rect 0.33x0.305 smd: 1(-0.267,0) 2(0.267,0)
SM0201_R
  rect 0.33x0.305 smd: 1(-0.267,0) 2(0.267,0)
SM0402_B
  rect 0.508x0.508 smd: 1(-0.457,0) 2(0.457,0)
SM0402_C
  rect 0.559x0.508 smd: 1(-0.47,0) 2(0.47,0)
SM0402_CM
  rect 0.559x0.711 smd: 1(-0.47,0) 2(0.47,0)
SM0402_D
  rect 0.508x0.711 smd: A(0.381,0) C(-0.381,0)
SM0402_R
  rect 0.559x0.508 smd: 1(-0.483,0) 2(0.483,0)
SM0402_V
  rect 0.559x0.508 smd: 1(-0.483,0) 2(0.483,0)
SM0603_B
  rect 0.813x0.914 smd: 1(-0.737,0) 2(0.737,0)
SM0603_C
  rect 0.813x0.914 smd: 1(-0.737,0) 2(0.737,0)
SM0603_LED
  rect 0.813x0.813 smd: A(0.775,0) C(-0.775,0)
SM0603_R
  rect 0.813x0.914 smd: 1(-0.737,0) 2(0.737,0)
SM0805_B
  rect 1.016x1.397 smd: 1(-1.016,0) 2(1.016,0)
SM0805_C
  rect 1.016x1.397 smd: 1(-0.864,0) 2(0.864,0)
SM0805_F
  rect 1.092x1.651 smd: 1(-1.092,0) 2(1.092,0)
SM0805_LED-4
  rect 1.194x0.813 smd: A1(-1.05,0.65) A2(-1.05,-0.65) C1(1.05,0.65) C2(1.05,-0.65)
SM0805_R
  rect 1.016x1.397 smd: 1(-0.864,0) 2(0.864,0)
SM1206_C
  rect 1.143x1.727 smd: 1(-1.397,0) 2(1.397,0)
SM1206_F
  rect 1.143x1.803 smd: 1(-1.321,0) 2(1.321,0)
SM1206_R
  rect 1.143x1.727 smd: 1(-1.397,0) 2(1.397,0)
SM1210_C
  rect 1.016x2.616 smd: 1(-1.499,0) 2(1.499,0)
SM1210_C30
  rect 1.016x2.616 smd: 1(-1.499,0) 2(1.499,0)
SM1512_CB20
  rect 1.6x2.692 smd: 1(-1.5,0) 2(1.5,0)
SM1808_C
  rect 1.702x2.007 smd: 1(-2,0) 2(2,0)
SM2512_R
  rect 2.032x3.048 smd: 1(-2.9,0) 2(2.9,0)
SM2917_CD19
  rect 2.413x2.921 smd: 1(-3.05,0) 2(3.05,0)
SMA
  rect 2.108x1.803 smd: A(-2.1,0) C(2.1,0)
SMB
  rect 2.159x2.794 smd: A(-2.223,0) C(2.223,0)
SMB_TVS
  rect 2.159x2.794 smd: 1(2.223,0) 2(-2.223,0)
SMEC103X103_165
  rect 4.445x1.905 smd: 1(-4.35,0) 2(4.35,0)
SMF
  rect 1.092x1.702 smd: 1(-1.6,0) 2(1.6,0)
SOD323
  rect 0.787x0.889 smd: A(-1.143,0) C(1.143,0)
SOP8_W150P127H18
  rect 0.559x1.524 smd: 1(-1.905,-2.746) 2(-0.635,-2.746) 3(0.635,-2.746) 4(1.905,-2.746) 5(1.905,2.746) 6(0.635,2.746) 7(-0.635,2.746) 8(-1.905,2.746)
SOP8_W200P127H22
  rect 0.635x1.651 smd: 1(-1.905,-3.683) 2(-0.635,-3.683) 3(0.635,-3.683) 4(1.905,-3.683) 5(1.905,3.683) 6(0.635,3.683) 7(-0.635,3.683) 8(-1.905,3.683)
SOP16_W300P127H27
  rect 0.584x1.854 smd: 1(-4.445,-4.74) 2(-3.175,-4.74) 3(-1.905,-4.74) 4(-0.635,-4.74) 5(0.635,-4.74) 6(1.905,-4.74) 7(3.175,-4.74) 8(4.445,-4.74) 9(4.445,4.74) 10(3.175,4.74) 11(1.905,4.74) 12(0.635,4.74) 13(-0.635,4.74) 14(-1.905,4.74) 15(-3.175,4.74) 16(-4.445,4.74)
SOT23-5
  rect 0.711x1.27 smd: 1(-0.95,-1.295) 2(0,-1.295) 3(0.95,-1.295) 4(0.95,1.295) 5(-0.95,1.295)
SOT23-6
  rect 0.711x1.27 smd: 1(-0.95,-1.295) 2(0,-1.295) 3(0.95,-1.295) 4(0.95,1.295) 5(0,1.295) 6(-0.95,1.295)
SOT23-AAC
  rect 1.016x1.219 smd: A1(-1.016,-1.118) A2(1.016,-1.118) C(0,1.118)
SOT23-BEC
  rect 1.016x1.219 smd: B(-1.016,-1.118) C(0,1.118) E(1.016,-1.118)
SOT23-GSD
  rect 1.016x1.219 smd: D(0,1.118) G(-1.016,-1.118) S(1.016,-1.118)
SOT323-GSD
  rect 0.508x0.762 smd: D(0,1.016) G(-0.65,-1.016) S(0.65,-1.016)
SOT353
  rect 0.406x0.813 smd: 1(-0.65,-1) 2(0,-1) 3(0.65,-1) 4(0.65,1) 5(-0.65,1)
SOT363
  rect 0.406x0.711 smd: 1(-0.65,-0.95) 2(0,-0.95) 3(0.65,-0.95) 4(0.65,0.95) 5(0,0.95) 6(-0.65,0.95)
SOT553
  rect 0.305x0.66 smd: 1(-0.5,-0.75) 2(0,-0.75) 3(0.5,-0.75) 4(0.5,0.75) 5(-0.5,0.75)
SWTS5X5_STS05
  rect 0.61x1.346 smd: 1(-1.85,2.35) 2(-1.85,-2.35) 3(1.85,2.35) 4(1.85,-2.35)
  rect 0.457x1.016 smd: 5(-2.525,0) 6(2.525,0)
TF-18D1X12D2X6D2P127-24P
  rect 0.762x1.905 smd: 1(-6.985,-7.303) 2(-5.715,-7.303) 3(-4.445,-7.303) 4(-3.175,-7.303) 5(-1.905,-7.303) 6(-0.635,-7.303) 7(0.635,-7.303) 8(1.905,-7.303) 9(3.175,-7.303) 10(4.445,-7.303) 11(5.715,-7.303) 12(6.985,-7.303) 13(6.985,7.303) 14(5.715,7.303) 15(4.445,7.303) 16(3.175,7.303) 17(1.905,7.303) 18(0.635,7.303) 19(-0.635,7.303) 20(-1.905,7.303) 21(-3.175,7.303) 22(-4.445,7.303) 23(-5.715,7.303) 24(-6.985,7.303)
TF-L22T0022-24P
  rect 0.635x1.905 smd: 1(-5.5,-4.6) 2(-4.5,-4.6) 3(-3.5,-4.6) 4(-2.5,-4.6) 5(-1.5,-4.6) 6(-0.5,-4.6) 7(0.5,-4.6) 8(1.5,-4.6) 9(2.5,-4.6) 10(3.5,-4.6) 11(4.5,-4.6) 12(5.5,-4.6) 13(5.5,4.6) 14(4.5,4.6) 15(3.5,4.6) 16(2.5,4.6) 17(1.5,4.6) 18(0.5,4.6) 19(-0.5,4.6) 20(-1.5,4.6) 21(-2.5,4.6) 22(-3.5,4.6) 23(-4.5,4.6) 24(-5.5,4.6)
TF-L22T0030-24P
  rect 0.635x2.108 smd: 1(-5.5,-4.55) 2(-4.5,-4.55) 3(-3.5,-4.55) 4(-2.5,-4.55) 5(-1.5,-4.55) 6(-0.5,-4.55) 7(0.5,-4.55) 8(1.5,-4.55) 9(2.5,-4.55) 10(3.5,-4.55) 11(4.5,-4.55) 12(5.5,-4.55) 13(5.5,4.55) 14(4.5,4.55) 15(3.5,4.55) 16(2.5,4.55) 17(1.5,4.55) 18(0.5,4.55) 19(-0.5,4.55) 20(-1.5,4.55) 21(-2.5,4.55) 22(-3.5,4.55) 23(-4.5,4.55) 24(-5.5,4.55)
TP20T
  round 0.508 smd: 1(0,0)
TP30T
  round 0.762 smd: 1(0,0)
TQFN12_2X1D7P04H06
  rect 0.66x0.305 smd: 1(-0.68,0.85)
  rect 0.66x0.203 smd: 2(-0.68,0.4) 3(-0.68,0) 4(-0.68,-0.4) 5(-0.68,-0.8) 7(0.68,-0.8) 8(0.68,-0.4) 9(0.68,0) 10(0.68,0.4) 11(0.68,0.8)
  rect 0.203x0.66 smd: 6(0,-0.85) 12(0,0.85)
TQFN16_2D6X1D8P04H06
  rect 0.762x0.203 smd: 1(-0.725,0.6)
  rect 0.66x0.203 smd: 2(-0.775,0.2) 3(-0.775,-0.2) 4(-0.775,-0.6) 9(0.775,-0.6) 10(0.775,-0.2) 11(0.775,0.2) 12(0.775,0.6)
  rect 0.203x0.559 smd: 5(-0.6,-1.226) 8(0.6,-1.226) 13(0.6,1.226) 16(-0.6,1.226)
  rect 0.203x0.66 smd: 6(-0.2,-1.175) 7(0.2,-1.175) 14(0.2,1.175) 15(-0.2,1.175)
TQFP64_7X7P04H12
  rect 1.194x0.241 smd: 1(-4.35,3) 2(-4.35,2.6) 3(-4.35,2.2) 4(-4.35,1.8) 5(-4.35,1.4) 6(-4.35,1) 7(-4.35,0.6) 8(-4.35,0.2) 9(-4.35,-0.2) 10(-4.35,-0.6) 11(-4.35,-1) 12(-4.35,-1.4) 13(-4.35,-1.8) 14(-4.35,-2.2) 15(-4.35,-2.6) 16(-4.35,-3) 33(4.35,-3) 34(4.35,-2.6) 35(4.35,-2.2) 36(4.35,-1.8) 37(4.35,-1.4) 38(4.35,-1) 39(4.35,-0.6) 40(4.35,-0.2) 41(4.35,0.2) 42(4.35,0.6) 43(4.35,1) 44(4.35,1.4) 45(4.35,1.8) 46(4.35,2.2) 47(4.35,2.6) 48(4.35,3)
  rect 0.241x1.194 smd: 17(-3,-4.35) 18(-2.6,-4.35) 19(-2.2,-4.35) 20(-1.8,-4.35) 21(-1.4,-4.35) 22(-1,-4.35) 23(-0.6,-4.35) 24(-0.2,-4.35) 25(0.2,-4.35) 26(0.6,-4.35) 27(1,-4.35) 28(1.4,-4.35) 29(1.8,-4.35) 30(2.2,-4.35) 31(2.6,-4.35) 32(3,-4.35) 49(3,4.35) 50(2.6,4.35) 51(2.2,4.35) 52(1.8,4.35) 53(1.4,4.35) 54(1,4.35) 55(0.6,4.35) 56(0.2,4.35) 57(-0.2,4.35) 58(-0.6,4.35) 59(-1,4.35) 60(-1.4,4.35) 61(-1.8,4.35) 62(-2.2,4.35) 63(-2.6,4.35) 64(-3,4.35)
TSSOP38_W170P05H12-TH134X382
  rect 1.524x0.279 smd: 1(-2.9,4.5) 2(-2.9,4) 3(-2.9,3.5) 4(-2.9,3) 5(-2.9,2.5) 6(-2.9,2) 7(-2.9,1.5) 8(-2.9,1) 9(-2.9,0.5) 10(-2.9,0) 11(-2.9,-0.5) 12(-2.9,-1) 13(-2.9,-1.5) 14(-2.9,-2) 15(-2.9,-2.5) 16(-2.9,-3) 17(-2.9,-3.5) 18(-2.9,-4) 19(-2.9,-4.5) 20(2.9,-4.5) 21(2.9,-4) 22(2.9,-3.5) 23(2.9,-3) 24(2.9,-2.5) 25(2.9,-2) 26(2.9,-1.5) 27(2.9,-1) 28(2.9,-0.5) 29(2.9,0) 30(2.9,0.5) 31(2.9,1) 32(2.9,1.5) 33(2.9,2) 34(2.9,2.5) 35(2.9,3) 36(2.9,3.5) 37(2.9,4) 38(2.9,4.5)
  rect 3.404x9.703 smd: 39(0,0)
USB3A_WU3R-09
  round 1.219 hole 0.711: 1(-3.5,2) 2(-1,2) 3(1,2) 4(3.5,2) 5(4,3.5) 6(2,3.5) 7(0,3.5) 8(-2,3.5) 9(-4,3.5)
  round 3.048 hole 2.311: X1(-6.57,0) X2(6.57,0)
USB31AV_UAA131C-40021
  round 1.219 hole 0.711: 1(3.5,1) 2(1,1) 3(-1,1) 4(-3.5,1) 5(-4,-1.5) 6(-2,-1.5) 7(0,-1.5) 8(2,-1.5) 9(4,-1.5)
  oval 1.422x2.946 hole 0.787x2.311: X1(-6.4,2) X2(6.4,2) X3(6.4,-2) X4(-6.4,-2)
VSSOP8_W90P05H09
  rect 0.813x0.305 smd: 1(-1.55,0.75) 2(-1.55,0.25) 3(-1.55,-0.25) 4(-1.55,-0.75) 5(1.55,-0.75) 6(1.55,-0.25) 7(1.55,0.25) 8(1.55,0.75)
WF100S-10P-BM10B-SRSS
  rect 0.61x1.549 smd: 1(-4.5,0) 2(-3.5,0) 3(-2.5,0) 4(-1.5,0) 5(-0.5,0) 6(0.5,0) 7(1.5,0) 8(2.5,0) 9(3.5,0) 10(4.5,0)
  rect 1.194x1.803 smd: P1(-5.8,-2.515) P2(5.8,-2.515)
WF125S-2P-85205
  rect 0.813x1.6 smd: 1(-0.625,0) 2(0.625,0)
  rect 2.108x2.997 smd: P1(-3.175,-2.9) P2(3.175,-2.9)
WF200D-2P-PASK
  round 1.016 hole 1.016 unplated: (1.5,1.7)
  rect 1.321x1.321 hole 0.813: 1(0,0)
  round 1.321 hole 0.813: 2(-2,0)
WF200D-4P
  rect 1.524x1.524 hole 0.813: 1(0,0)
  round 1.524 hole 0.813: 2(-2,0) 3(-4,0) 4(-6,0)
WF200D-5X2P-CI01
  rect 1.321x1.321 hole 0.813: 1(4,-1)
  round 1.321 hole 0.813: 2(4,1) 3(2,-1) 4(2,1) 5(0,-1) 6(0,1) 7(-2,-1) 8(-2,1) 9(-4,-1) 10(-4,1)
WF200D-8P-PASK
  round 1.016 hole 1.016 unplated: (1.5,1.7)
  rect 1.524x1.524 hole 0.813: 1(0,0)
  round 1.524 hole 0.813: 2(-2,0) 3(-4,0) 4(-6,0) 5(-8,0) 6(-10,0) 7(-12,0) 8(-14,0)
WF200D-12P-PASK
  round 1.016 hole 1.016 unplated: (1.5,1.7)
  rect 1.524x1.524 hole 0.813: 1(0,0)
  round 1.524 hole 0.813: 2(-2,0) 3(-4,0) 4(-6,0) 5(-8,0) 6(-10,0) 7(-12,0) 8(-14,0) 9(-16,0) 10(-18,0) 11(-20,0) 12(-22,0)
XTAL2016-4
  rect 0.889x0.813 smd: 1(-0.7,-0.55) 2(0.7,-0.55) 3(0.7,0.55) 4(-0.7,0.55)
XTAL3225-4
  rect 1.397x1.194 smd: 1(-1.1,-0.8) 2(1.1,-0.8) 3(1.1,0.8) 4(-1.1,0.8)

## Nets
1V2_DCVDD: C27.1 CA130.1 U16.42
1V8_AVDD: C38.1 CA134.1 RZ166.1 RZ168.1 U16.15
1V8_CPVDD: C42.1 CA54.1 RZ12.1 U16.23
1V8_TPM_IRQ#: J1.C57 Q57.S RB25.1
3.3VCC: C69.1 CA49.1 CA127.1 CA128.1 R172.2 R174.2 R175.2 U25.23 U25.35 U25.39
3V3_MICVDD: C40.1 CA131.1 U16.3
3V3_SPI_CLK: R1484.1 U86.12
3V3_SPI_MISO_IO1: R1485.1 U86.15
3V3_SPI_MOSI_IO0: R1486.1 U86.13
5V_DISCHG_D: Q37.D R693.2 R694.2
5V_GP_OOB: OOB1.7 RZ187.2
5V_HDMI2: C292.2 F9.2 HDMI1.18 R530.1 R531.1
5V_ON_D: Q37.G Q38.D RB43.2
5V_SPKVDD: C34.1 C35.1 CA52.1 RZ7.1 U16.2 U16.46
5V_SW_G: C407.2 Q36.4 RB43.1 RZ113.2
5VCC: CB5.1 R1508.2 U25.57
+V1.2S: FB29.2 FB30.2 FB32.2 FB33.2 FB34.2 R715.2 U81.6(VOUT)
+V1.2SB: C427.1 C428.1 C429.1 C431.1 CA26.1 R706.2 U20.46 U79.5(VOUT1) U81.2
+V1.2SB_PG: RB34.2 RZ57.1 U79.2
+V1.05S: C374.1 C385.1 C386.1 C387.1 CB6.2 FB35.1 R655.2 U73.5(VOUT1)
+V1.05S_PG: RB31.2 U73.2
+V1.8S: C136.1 C891.1 C910.1 CA11.1 CA50.1 CA56.1 CA59.1 CA123.1 CA124.1 CA129.1 CA136.1 CA145.1 J4.1 J14.102 Q17.G Q50.G Q52.2 Q52.5 Q53.5 Q54.2 Q57.G Q59.G R3.2 R5.2 R7.2 R9.2 R11.2 R46.1 R92.1 R93.1 R98.1 R114.1 R141.1 R142.1 R143.1 R144.1 R187.2 R193.2 R195.2 R196.1 R198.2 R201.2 R240.2 R242.2 R243.2 R540.2 R681.1 R714.2 R757.2 R762.1 R763.1 R1476.2 R1483.2 RB3.1 RB24.2 RB25.2 RB27.1 RB28.1 RB62.2 U10.5 U15.8 U33.1 U33.5 U36.3 U37.5 U38.3 U80.6(VOUT) U85.1 U87.2
+V1.8S_PG: CM44.1 CM45.1 RA1.2 RA2.2 RZ187.1 U80.3 U81.3
+V1.8SB: C424.1 C425.1 C426.1 C430.1 CB12.1 R705.1 RB38.1 U78.5(VOUT1) U80.2 U86.3
+V1.8SB_EN: RZ51.2 U78.4
+V1.8SB_PG: RB32.2 U78.2
+V2.5S: C376.1 C380.1 C381.1 C382.1 CB8.2 FB37.1 R651.2 U72.5(VOUT1)
+V2.5S_PG: RB40.2 U72.2
+V3.3_WLAN: C81.1 C82.1 C83.1 C84.1 C87.1 C88.1 C89.1 C90.1 CA57.1 CA58.1 FB5.2 R188.1 R189.1 R190.2 R192.2 R197.2 R199.2 R200.2 R202.2 RA52.1 U30.6(VOUT) WIFI1.2 WIFI1.4 WIFI1.72 WIFI1.74
+V3.3_WLAN_PG: CM65.1 RA52.2 U30.3
+V3.3NVME: C479.1 C480.1 C481.1 C482.1 C483.1 C486.1 C487.1 C488.1 CA137.1 CA138.1 CA139.1 FB39.2 R759.2 R760.2 S8.2 SSD2.2 SSD2.4 SSD2.12 SSD2.14 SSD2.16 SSD2.18 SSD2.70 SSD2.72 SSD2.74
+V3.3S: C137.1 C138.1 C139.1 C140.1 C141.1 C892.2 CA8.1 CA18.1 CA62.2 CA63.2 CA144.2 CB3.1 CB4.1 CE8.1 FB7.1 FB28.2 FB31.2 J14.108 J14.110 J14.118 J14.120 Q29.D(3) Q40.5 Q40.6 Q40.7 Q40.8 Q40.9 R2.2 R4.2 R6.2 R8.2 R10.2 R191.2 R245.1 R560.1 R703.1 R704.1 R1334.1 R1474.2 R1490.2 RA1.1 RA2.1 RB4.2 RB6.1 RB7.1 RB31.1 RB33.1 RB34.1 RB35.1 RB40.1 RB41.1 RB44.2 RB45.2 RB46.2 RB56.2 RB57.2 RB65.2 S8.1 TP51.1 U3.5 U5.5 U34.7 U40.7 U85.11(VCCB) U88.5(VCC) U89.5(VCC)
+V3.3SB: C91.1 C129.1 C341.1 C344.1 C347.1 C419.1 CA46.1 CA125.1 CA126.1 CA140.1 CA141.1 CA142.1 CA143.1 CB1.1 CB2.1 CB10.1 CB11.1 CB13.1 CB19.1 CB134.1 CB135.1 CB137.1 CB138.1 FB3.1 J11.1 J13.1 Q39.5 Q39.6 Q39.7 Q39.8 Q39.9 Q40.1 Q40.2 Q40.3(S3) R22.1 R40.1 R48.1 R51.1 R204.2 R223.2 R561.1 R563.2 R605.2 R621.1 R622.1 R636.2 R771.2 R1475.2 R1488.1 RB8.1 RB9.1 RB10.1 RB11.1 RB12.1 RB13.1 RB32.1 RB36.2 RB42.1 RB63.1 RB64.1 RB66.1 RZ15.1 RZ61.1 RZ99.2 RZ117.2 RZ118.1 RZ122.2 RZ123.2 RZ124.2 RZ125.2 RZ126.2 RZ127.2 RZ192.1 U4.5 U6.4(VDD) U7.6(VCCB) U9.5 U11.5 U12.5 U18.8(VDD#8) U18.22 U19.5 U30.1 U30.2 U32.1 U32.2 U67.D5 U67.E5 U67.F5 U67.G5 U80.1 U81.1 U86.2(VCCB) U90.5(VCC) U91.5
+V3.3SB_EN: Q14.G RZ32.2 RZ51.1
+V3.3SB_EN#: JPSON1.1 Q39.4 R702.1 RB50.1 RZ72.2 U14.5
+V3.3SB_GND: C418.2 R700.1 RZ53.2 U77.10
+V3.3SB_PGOOD: R701.1 U77.3
+V3.3SB_VCC: C418.1 R699.2 R701.2 U77.9
+V3.3V: CA68.2 U65.43
+V3P3A_HUB: CA22.1 FB3.2 R155.1 R156.1 R157.1 R158.1 R166.1 RA3.1 RA4.1 RA5.1 RA6.1 RA9.1 RA10.1 RZ79.1 RZ90.2 RZ98.1 U20.49 U21.8
+V5S: C71.1 C900.1 C901.1 C902.1 C903.1 C904.1 C905.1 C906.1 C907.1 C908.1 C909.1 CA7.1 CA10.1 CA122.1 CE9.1 D54.A J1.L22(SYS_VIN_MV_10) J1.L23 J1.L26 J1.L27 J1.L30 J1.L31 J1.L34 J1.L35 J1.L38 J1.L39 Q36.5 Q36.6 Q36.7 Q36.8 Q36.9 R230.1 R677.1 R680.1 R682.1 R693.1 R694.1 R1508.1 RB2.1 RB59.1 RB61.1 RZ4.1 RZ7.2 TP50.1 U24.1 U26.1 U40.1
+V5S_ISO: C74.2 C76.2 C77.1 CA1.1 CA2.1 CA5.1 CA118.1 CA119.1 R254.1 R259.1 RB1.1 RB60.1 U24.16 U26.16 U27.6 U36.8(VDDB) U38.8(VDDB) UART1.1 UART1.12
+V5SB: C63.1 C64.1 C80.1 C378.1 C379.1 C383.1 C384.1 C400.2 C401.1 C402.1 C403.1 C404.1 C407.1 C420.1 C421.1 C422.1 C423.1 CA45.1 CA47.2 CA67.1 CA148.1 CE10.1 OOB1.10 PL2.2 Q36.1 Q36.2 Q36.3(S3) R162.2 R163.2 R165.2 R668.1 R686.1 RB22.1 RB58.2 RZ113.1 RZU5.1 U7.1 U22.1 U23.1 U28.1 U72.3 U72.6 U72.10 U73.3 U73.6 U73.10 U75.5(VDD) U78.3 U78.6 U78.10 U79.3 U79.6 U79.10
+V5SB_EN: R684.1 R685.1 R1477.2 RZ73.2 U76.8
+V5SB_EN#: Q13.G RB51.1 U14.7
+V5SB_GND: C405.2 R691.1 R692.1 S6.1 U76.2
+V5SB_PGOOD: R687.1 R688.2 U76.9
+V12S_PGOOD: RB23.1 U92.10
+V12SB: C394.1 C396.1 C409.1 C410.1 C447.1 C448.1 C449.1 C450.1 C451.1 C452.1 C453.1 C454.1 C455.1 C456.1 CA146.1 PL1.1 PL4.2 Q31.5 Q31.6 Q31.7 Q31.8 Q31.9 R664.1 R669.1 R696.2 R721.2 R722.2 RB23.2 U77.1
+VIN_PSON#: Q65.4 Q66.3 R1506.1
AGND: AUDIO1.6(NC/MIC2) C38.2 C40.2 C42.2 C46.2 C47.2 C54.2 C838.2 C839.2 CA14.2 CA15.2 CA16.2 CA54.2 CA131.2 CA132.2 CA134.2 RZ153.1 RZ154.1 U16.9 U16.22 U16.25 VS1.2(B) VS2.2(B) VS3.2(B) VS4.2(B) VS5.2(B)
AVDD33_HUB: CA25.1 CA29.1 CA30.1 CA32.1 RZ98.2 U20.1 U20.11 U20.21 U20.62
AVDD_CAM_2V8: C142.1 C143.1 CA121.1 J14.81 J14.82 J14.83 R246.2 U34.5 U34.6 U34.12(VOUT_S)
DVDD10_HUB: C499.1 CA42.1 CA43.1 CA44.1 U20.12 U20.45 U20.47
DVDD33_HUB: C59.1 CA27.1 CA28.1 CA31.1 CA33.1 RZ79.2 U20.7 U20.17 U20.30 U20.43
DVDD_CAM_LV: J14.55 J14.56 J14.57 J14.58
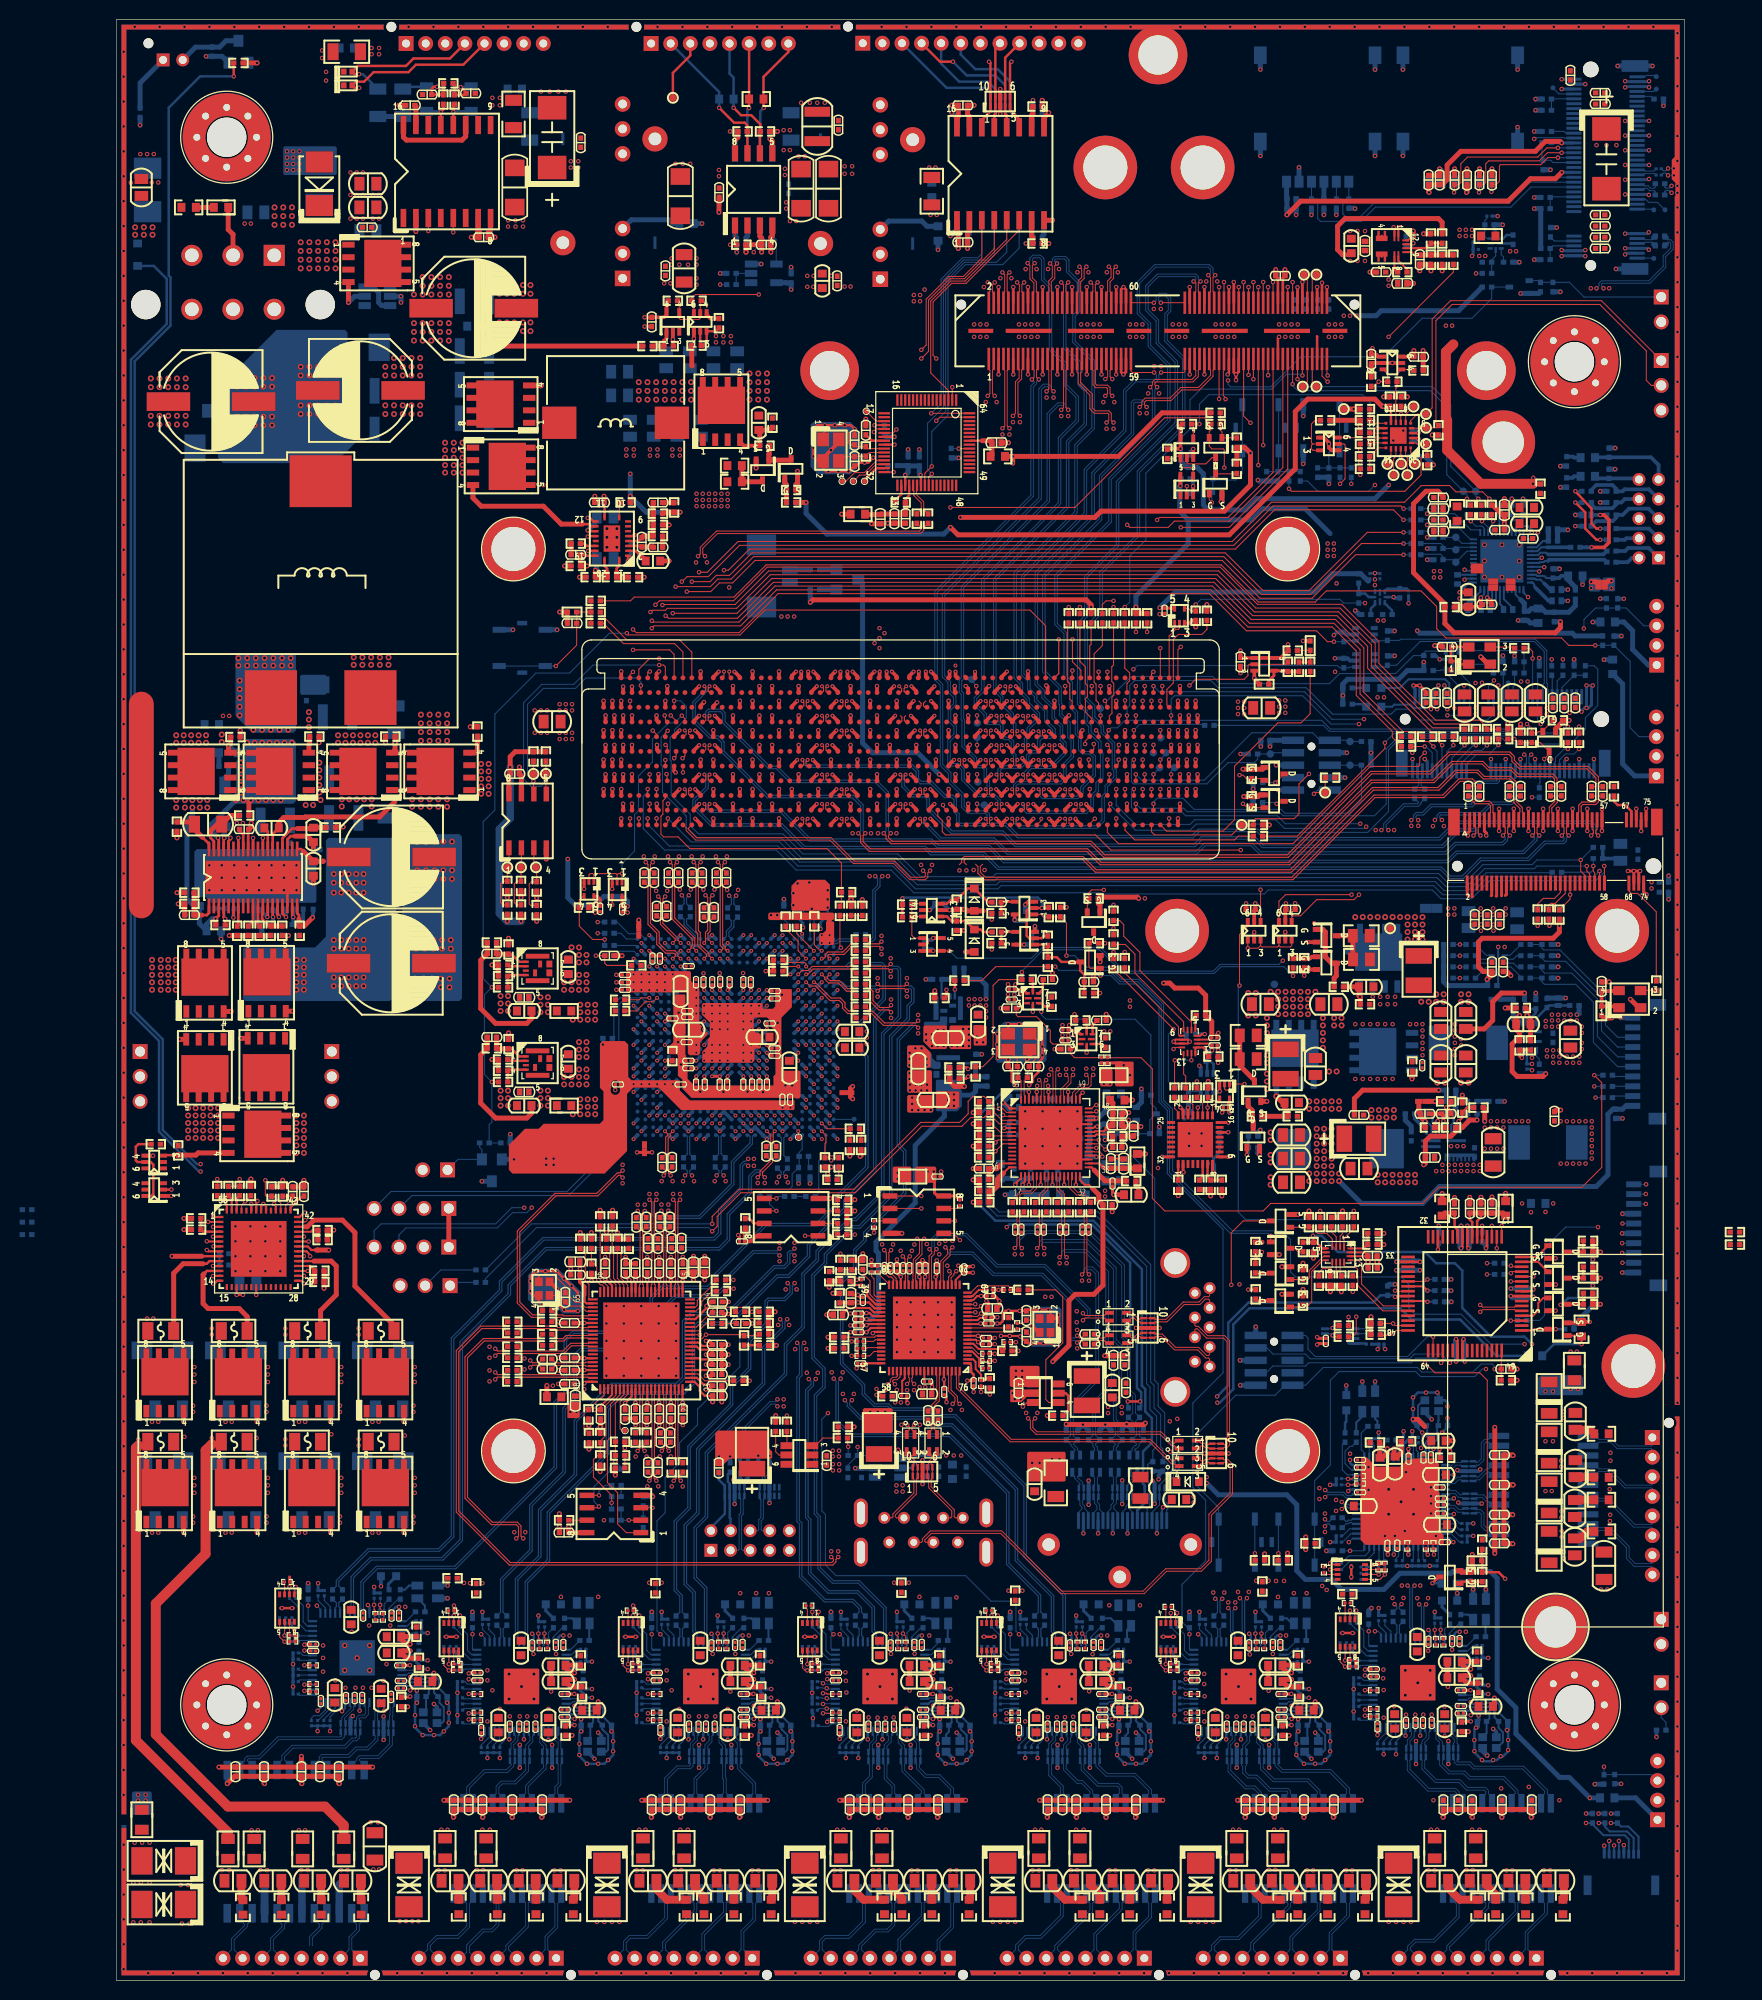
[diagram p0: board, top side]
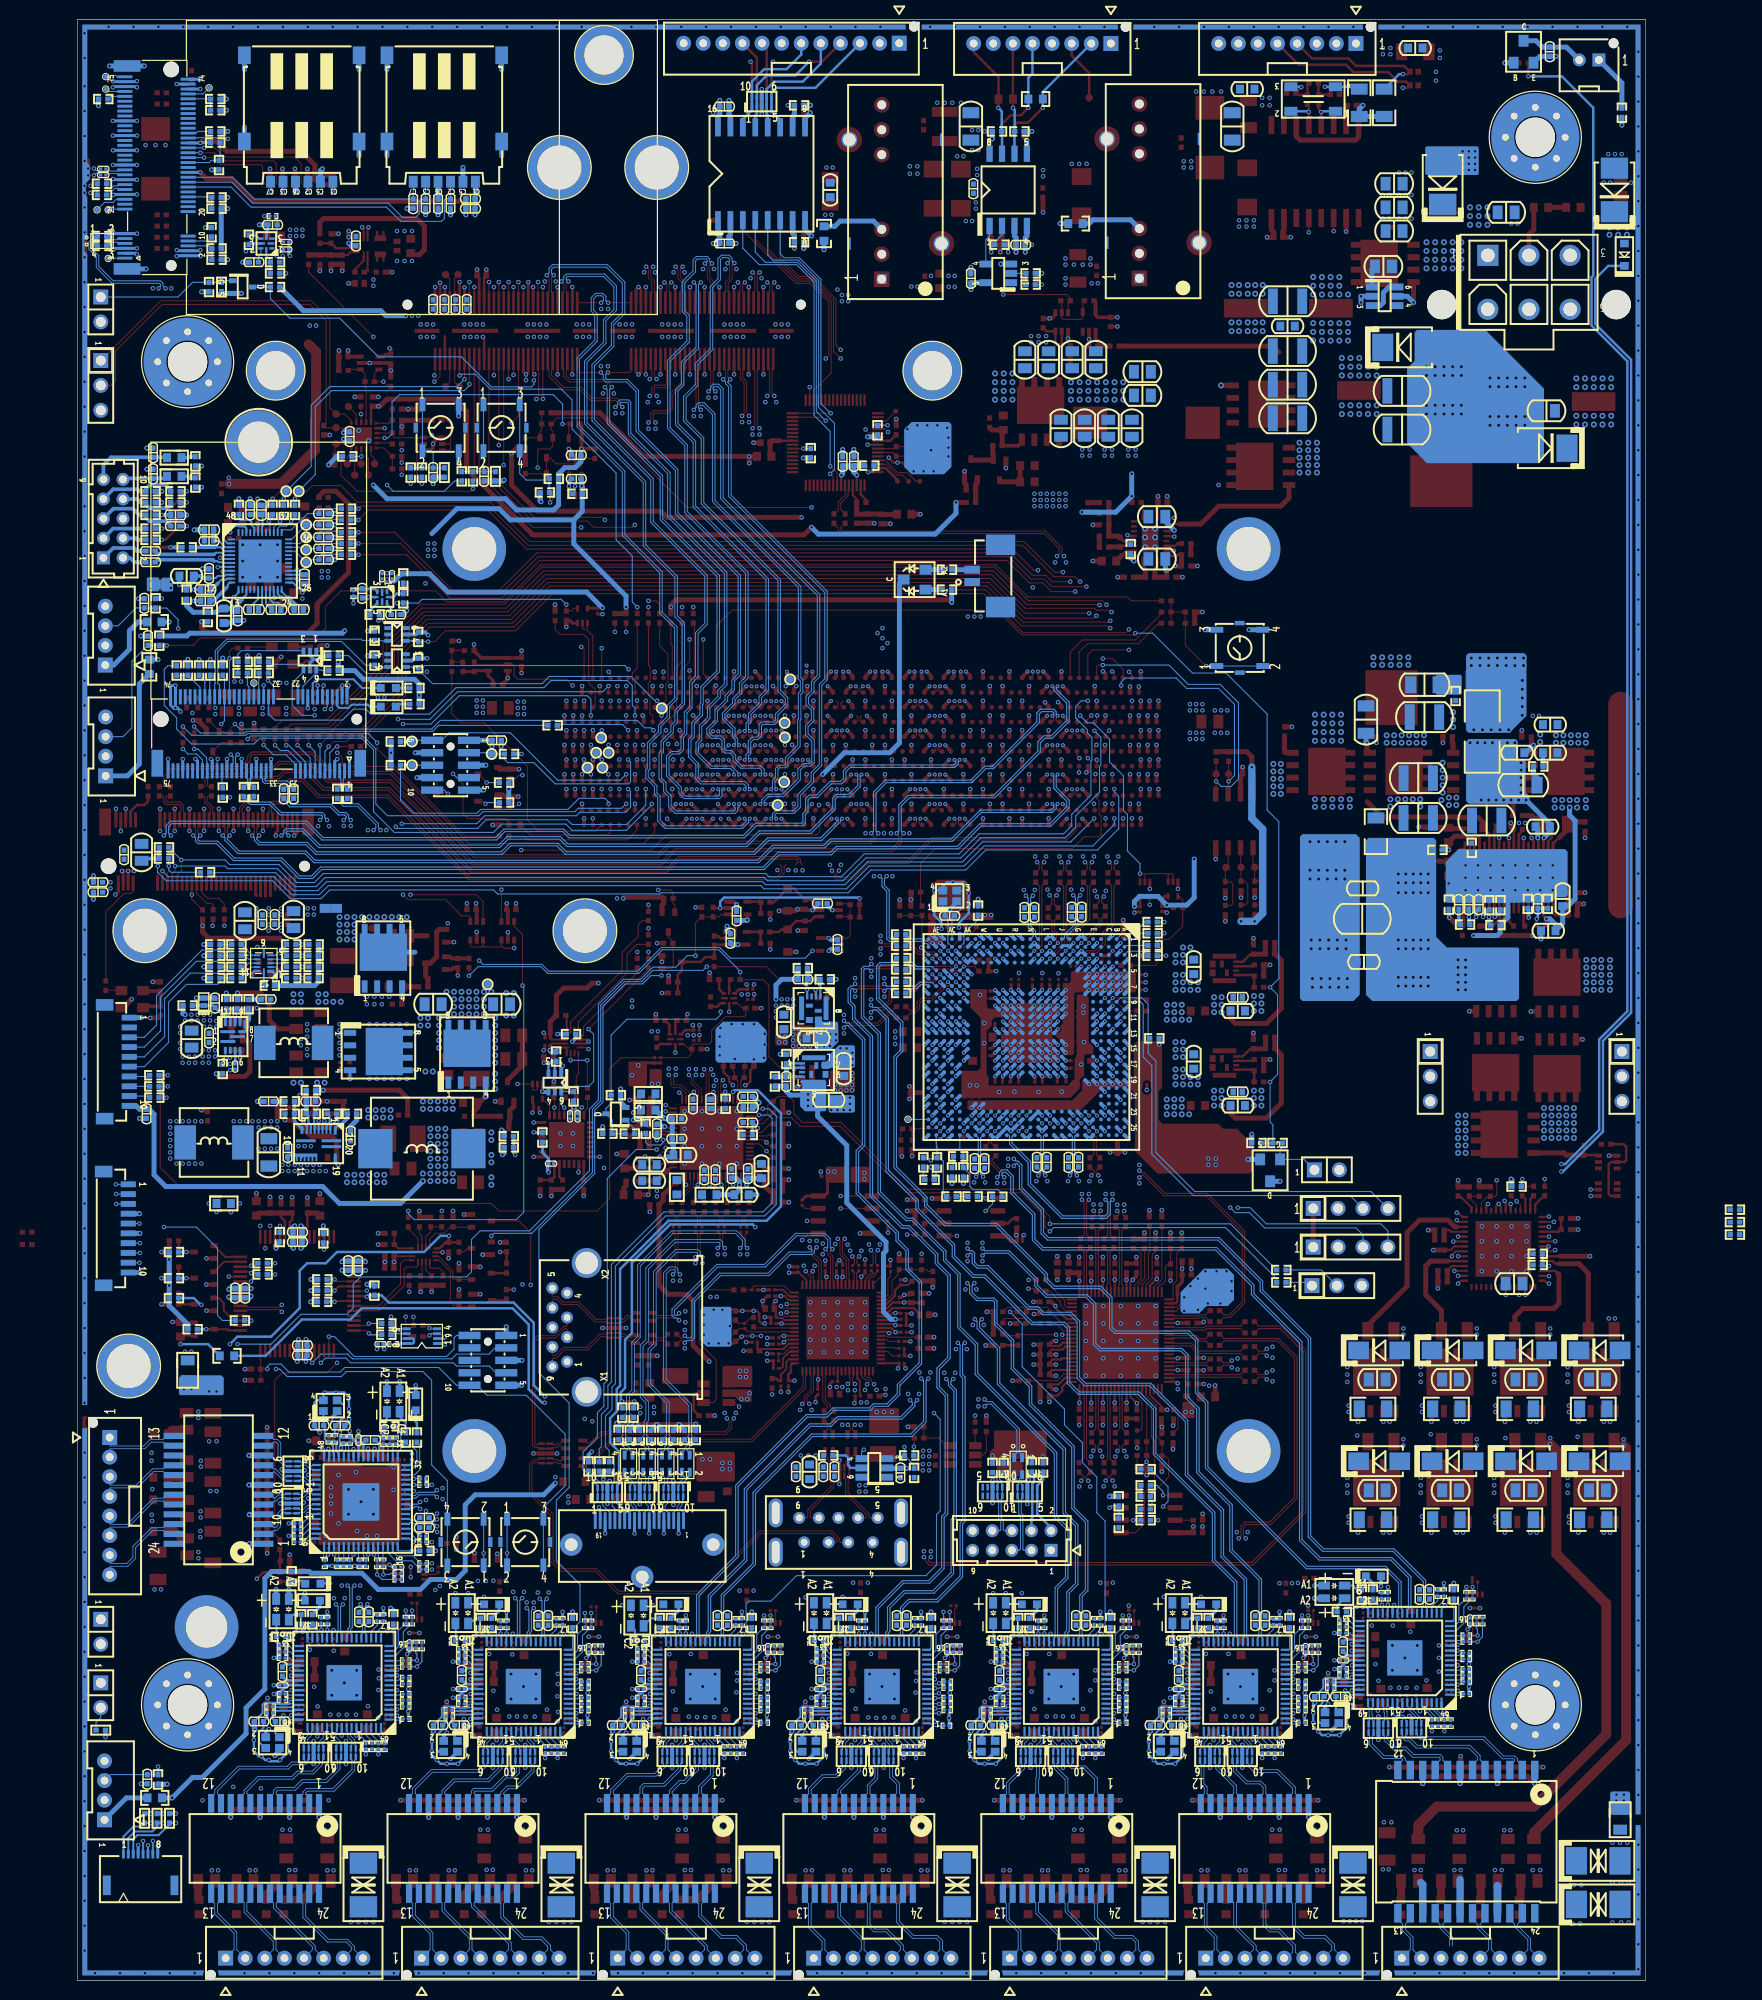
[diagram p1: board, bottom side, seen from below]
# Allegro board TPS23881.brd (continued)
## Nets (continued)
GND: BAT1.1 BAT1.P1 BAT1.P2 C1.2 C2.2 C18.2 C19.2 C20.2 C21.2 C22.2 C23.2 C24.2 C25.2 C27.2 C30.2 C34.2 C35.2 C57.2 C58.2 C59.2 C60.2 C61.2 C62.2 C63.2 C64.2 C65.2 C66.2 C67.2 C68.2 C70.2 C72.2 C73.2 C75.2 C78.1 C79.1 C80.2 C81.2 C82.2 C83.2 C84.2 C87.2 C88.2 C89.2 C90.2 C91.2 C92.2 C110.2 C111.1 C112.1 C113.1 C117.1 C118.1 C119.1 C120.1 C121.1 C123.1 C124.1 C125.1 C126.1 C128.1 C129.2 C130.2 C132.2 C134.2 C135.2 C136.2 C137.2 C138.2 C139.2 C140.2 C141.2 C142.2 C143.2 C156.2 C158.1 C160.1 C166.2 C167.2 C168.2 C169.2 C170.2 C172.2 C173.2 C174.2 C175.2 C176.2 C177.2 C178.2 C179.2 C181.2 C182.2 C183.2 C184.2 C185.2 C186.2 C187.2 C188.2 C190.2 C191.2 C192.2 C193.2 C194.2 C195.2 C196.2 C197.2 C199.2 C200.2 C201.2 C202.2 C203.2 C204.2 C205.2 C207.2 C208.2 C209.2 C210.2 C211.2 C212.2 C213.2 C214.2 C215.2 C217.2 C218.2 C219.2 C220.2 C221.2 C222.2 C223.2 C224.2 C226.2 C227.2 C228.2 C229.2 C230.2 C231.2 C232.2 C233.2 C235.2 C236.2 C237.2 C239.2 C243.2 C248.2 C253.2 C258.2 C263.2 C268.2 C273.2 C279.2 C288.2 C290.2 C291.1 C292.1 C293.2 C294.1 C295.2 C296.2 C297.1 C298.2 C299.2 C300.2 C301.2 C302.2 C303.2 C304.2 C305.2 C306.2 C307.2 C308.2 C309.2 C310.2 C311.2 C312.2 C313.2 C314.2 C315.2 C316.2 C317.2 C318.2 C323.2 C324.2 C326.2 C327.2 C329.2 C330.2 C332.2 C333.2 C335.2 C336.2 C337.2 C338.2 C339.2 C340.2 C341.2 C342.2 C343.2 C344.2 C345.2 C346.2 C347.2 C348.2 C349.2 C350.2 C351.2 C352.2 C353.2 C354.2 C355.2 C356.2 C357.2 C358.2 C359.2 C360.2 C361.2 C362.2 C363.2 C364.2 C369.2 C370.2 C374.2 C375.2 C376.2 C377.2 C378.2 C379.2 C381.2 C382.2 C383.2 C384.2 C386.2 C387.2 C388.2 C389.1 C390.2 C391.2 C393.2 C396.2 C397.2 C398.2 C399.2 C401.2 C402.2 C403.2 C404.2 C406.2 C409.2 C410.2 C412.2 C413.2 C414.2 C415.2 C417.2 C420.2 C421.2 C422.2 C423.2 C425.2 C426.2 C428.2 C429.2 C430.2 C431.2 C432.2 C434.2 C436.2 C437.2 C438.2 C439.2 C442.2 C443.2 C444.2 C447.2 C448.2 C449.2 C450.2 C451.2 C452.2 C453.2 C454.2 C455.2 C456.2 C457.1 C458.2 C462.1 C463.2 C464.2 C465.2 C466.1 C468.1 C469.1 C479.2 C480.2 C481.2 C482.2 C483.2 C486.2 C487.2 C488.2 C499.2 C891.2 C892.1 C900.2 C901.2 C902.2 C903.2 C904.2 C905.2 C906.2 C907.2 C908.2 C909.2 C910.2 C911.2 C912.2 C913.2 C914.2 C915.2 C916.2 C920.2 C921.2 C922.1 CA4.2 CA5.2 CA6.1 CA7.2 CA8.2 CA9.1 CA10.2 CA11.2 CA12.1 CA13.2 CA17.2 CA18.2 CA19.2 CA22.2 CA25.2 CA26.2 CA27.2 CA28.2 CA29.2 CA30.2 CA31.2 CA32.2 CA33.2 CA34.2 CA35.2 CA36.2 CA37.2 CA38.2 CA39.2 CA40.2 CA41.2 CA42.2 CA43.2 CA44.2 CA45.2 CA46.2 CA47.1 CA48.2 CA50.2 CA51.2 CA52.2 CA55.2 CA56.2 CA57.2 CA58.2 CA59.2 CA60.2 CA61.2 CA62.1 CA63.1 CA64.2 CA65.2 CA67.2 CA68.1 CA69.2 CA70.2 CA71.2 CA72.2 CA73.2 CA76.2 CA77.2 CA80.2 CA81.2 CA82.2 CA83.2 CA84.2 CA85.2 CA86.2 CA87.2 CA88.2 CA89.2 CA90.2 CA91.2 CA92.2 CA93.2 CA94.2 CA95.2 CA96.2 CA97.2 CA98.2 CA99.2 CA100.2 CA101.2 CA102.2 CA103.2 CA104.2 CA105.2 CA106.2 CA107.2 CA108.2 CA109.2 CA110.2 CA111.2 CA112.2 CA113.2 CA114.2 CA115.2 CA116.2 CA117.2 CA119.2 CA120.2 CA121.2 CA122.2 CA123.2 CA124.2 CA125.2 CA126.2 CA127.2 CA128.2 CA129.2 CA130.2 CA133.2 CA135.2 CA136.2 CA137.2 CA138.2 CA139.2 CA140.2 CA141.2 CA142.2 CA143.2 CA144.1 CA145.2 CA146.2 CA147.2 CA148.2 CA149.2 CA150.2 CA151.2 CA152.2 CA153.2 CA248.2 CAMMH1.1 CAMMH2.1 CAMMH3.1 CB1.2 CB2.2 CB3.2 CB4.2 CB5.2 CB6.1 CB7.1 CB8.1 CB9.1 CB10.2 CB11.2 CB12.2 CB13.2 CB14.2 CB15.2 CB16.2 CB17.2 CB18.2 CB19.2 CB20.1 CB29.2 CB30.2 CB31.2 CB32.2 CB33.2 CB34.2 CB35.2 CB36.2 CB37.2 CB38.2 CB39.2 CB40.2 CB41.2 CB42.2 CB43.2 CB44.2 CB45.2 CB46.2 CB47.2 CB48.2 CB49.2 CB50.2 CB51.2 CB52.2 CB53.2 CB54.2 CB55.2 CB56.2 CB57.2 CB58.2 CB59.2 CB60.2 CB61.2 CB62.2 CB63.2 CB64.2 CB65.2 CB66.2 CB67.2 CB68.2 CB69.2 CB70.2 CB71.2 CB72.2 CB73.2 CB74.2 CB75.2 CB76.2 CB77.2 CB78.2 CB79.2 CB80.2 CB81.2 CB82.2 CB83.2 CB84.2 CB85.2 CB86.2 CB87.2 CB88.2 CB89.2 CB90.2 CB91.2 CB92.2 CB93.2 CB94.2 CB95.2 CB96.2 CB97.2 CB98.2 CB99.2 CB100.2 CB101.2 CB102.2 CB103.2 CB104.2 CB105.2 CB106.2 CB107.2 CB108.2 CB109.2 CB110.2 CB111.2 CB112.2 CB113.2 CB114.2 CB115.2 CB116.2 CB117.2 CB118.2 CB119.2 CB120.2 CB121.2 CB122.2 CB123.2 CB124.2 CB125.2 CB126.2 CB127.2 CB128.2 CB129.2 CB130.2 CB131.2 CB132.2 CB133.2 CB134.2 CB135.2 CB136.2 CB137.2 CB138.2 CB139.2 CB140.2 CB141.2 CB142.2 CB143.2 CB144.2 CB145.2 CB146.2 CB147.2 CB148.2 CB149.2 CB150.2 CB151.2 CB152.2 CB153.2 CB154.2 CE2.2 CE3.2(-) CE4.2(-) CE5.2(-) CE6.2(-) CE7.2(-) CE8.2(-) CE9.2(-) CE10.2(-) CE11.2(-) CE12.2(-) CE13.2(-) CM2.2 CM3.2 CM4.2 CM5.2 CM6.2 CM7.2 CM8.2 CM9.2 CM10.2 CM11.2 CM12.2 CM13.2 CM14.2 CM15.2 CM16.2 CM17.2 CM18.2 CM19.2 CM20.2 CM21.2 CM22.2 CM23.2 CM24.2 CM44.2 CM45.2 CM64.2 CM65.2 CN1.4 CN1.7 CN1.X1 CN1.X2 CN2.4 CN2.7 CN2.X1 CN2.X2 CN2.X3 CN2.X4 CV1.1 CV8.1 D2.A D5.3 D5.8 D7.3 D7.8 D8.3 D8.8 D11.3 D11.8 D12.1 D13.1 D16.3 D16.8 D19.3 D19.8 D21.3 D21.8 D23.3 D23.8 D24.3 D24.8 D27.3 D27.8 D29.3 D29.8 D31.3 D31.8 D32.3 D32.8 D35.3 D35.8 D37.3 D37.8 D39.3 D39.8 D42.3 D42.8 D43.3 D43.8 D44.3 D44.8 D45.3 D45.8 D55.3 D55.8 D56.3 D56.8 D57.3 D57.8 D59.A D60.A D62.C D63.A D64.A D65.A D66.3 D66.8 DB1.3 DB1.5 DC_IN1.4 DC_IN1.5 DC_IN1.6 FB46.2 FB47.1 FB48.1 FB49.1 FB50.1 H1.2 H1.3 H1.4 H1.5 H1.6 H1.7 H1.8 H1.9 H2.2 H2.3 H2.4 H2.5 H2.6 H2.7 H2.8 H2.9 H3.2 H3.3 H3.4 H3.5 H3.6 H3.7 H3.8 H3.9 H4.2 H4.3 H4.4 H4.5 H4.6 H4.7 H4.8 H4.9 HDMI1.2 HDMI1.5 HDMI1.8 HDMI1.11 HDMI1.17 J1.A3 J1.A9 J1.A12 J1.A13 J1.A16 J1.A17 J1.A20 J1.A21 J1.A24 J1.A25 J1.A28 J1.A29 J1.A32 J1.A33 J1.A36 J1.A37 J1.A40 J1.A43 J1.A46 J1.A49 J1.A52 J1.A63 J1.B4 J1.B7 J1.B11 J1.B14 J1.B15 J1.B18 J1.B19 J1.B22 J1.B23 J1.B26 J1.B27 J1.B30 J1.B31 J1.B34 J1.B35 J1.B38 J1.B39 J1.B41 J1.B44 J1.B47 J1.B50 J1.B53 J1.B57 J1.C3 J1.C9 J1.C12 J1.C13 J1.C16 J1.C17 J1.C20 J1.C21 J1.C24 J1.C25 J1.C28 J1.C29 J1.C32 J1.C33 J1.C36 J1.C37 J1.C40 J1.C43 J1.C46 J1.C49 J1.C52 J1.C62 J1.D4 J1.D7 J1.D11 J1.D14 J1.D15 J1.D18 J1.D19 J1.D22 J1.D23 J1.D26 J1.D27 J1.D30 J1.D31 J1.D34 J1.D35 J1.D38 J1.D39 J1.D41 J1.D44 J1.D47 J1.D50 J1.D53 J1.D57 J1.D63 J1.E3 J1.E9 J1.E12 J1.E13 J1.E16 J1.E17 J1.E20 J1.E21 J1.E24 J1.E25 J1.E28 J1.E29 J1.E32 J1.E33 J1.E36 J1.E37 J1.E40 J1.E43 J1.E46 J1.E49 J1.E52 J1.E57 J1.E62 J1.F4 J1.F7 J1.F11 J1.F14 J1.F15 J1.F18 J1.F19 J1.F22 J1.F23 J1.F26 J1.F27 J1.F30 J1.F31 J1.F34 J1.F35 J1.F38 J1.F39 J1.F41 J1.F44 J1.F47 J1.F50 J1.F57 J1.F62 J1.G3 J1.G9 J1.G12 J1.G13 J1.G16 J1.G17 J1.G20 J1.G21 J1.G24 J1.G25 J1.G28 J1.G29 J1.G32 J1.G33 J1.G36 J1.G37 J1.G40 J1.G43 J1.G46 J1.G49 J1.G52 J1.G57 J1.G62 J1.H4 J1.H7 J1.H11 J1.H14 J1.H15 J1.H18 J1.H19 J1.H22 J1.H23 J1.H26 J1.H27 J1.H30 J1.H31 J1.H34 J1.H35 J1.H38 J1.H39 J1.H41 J1.H44 J1.H47 J1.H50 J1.H56 J1.H63 J1.J3 J1.J8 J1.J12 J1.J13 J1.J16 J1.J17 J1.J20 J1.J21 J1.J24 J1.J25 J1.J28 J1.J29 J1.J32 J1.J33 J1.J36 J1.J37 J1.J40 J1.J43 J1.J46 J1.J49 J1.J56 J1.K4 J1.K8 J1.K11 J1.K14 J1.K15 J1.K18 J1.K19 J1.K22 J1.K23 J1.K26 J1.K27 J1.K30 J1.K31 J1.K34 J1.K35 J1.K38 J1.K39 J1.K41 J1.K42 J1.K45 J1.K48 J1.K55 J1.K63 J1.L3 J1.L7 J1.L12 J1.L13 J1.L16 J1.L17 J1.L20 J1.L21 J1.L24 J1.L25 J1.L28 J1.L29 J1.L32 J1.L33 J1.L36 J1.L37 J1.L40 J1.L43 J1.L46 J4.3 J4.5 J4.7 J4.9 J7.3 J11.2 J13.2 J14.5 J14.6 J14.11 J14.12 J14.17 J14.18 J14.23 J14.24 J14.29 J14.30 J14.35 J14.36 J14.41 J14.42 J14.47 J14.48 J14.53 J14.54 J14.63 J14.64 J14.69 J14.70 J14.79 J14.80 J14.99 J14.100 J14.115 J14.116 J14.P1 J14.P2 J14.P3 J14.P4 J14.P5 J14.P6 J14.P7 J14.P8 JPPCIE1.2 JPSON1.2 JSIM1.C5 JSIM1.P1 JSIM1.P2 JSIM1.P3 JSIM1.P4 JSIM2.C5 JSIM2.P1 JSIM2.P2 JSIM2.P3 JSIM2.P4 MCUCON1.3 MHB1.1 MHB2.1 MHE1.1 MHM1.1 NCSI1.4 NCSI1.6 NCSI1.10 NGFF1.3 NGFF1.5 NGFF1.11 NGFF1.27 NGFF1.33 NGFF1.39 NGFF1.45 NGFF1.51 NGFF1.57 NGFF1.71 NGFF1.73 NGFF1.P1 NGFF1.P2 NVMH1.1 NVMH2.1 NVMH3.1 NVMH4.1 OOB1.1 OOBMH1.1 OOBMH2.1 OOBMH3.1 POESLT1.3 POESLT2.3 PSON2.3 PSON2.4 PSON3.3 PSON3.4 PWRBTN1.2(GND1) PWRBTN1.4 Q2.1 Q2.4(S2) Q3.S Q4.S Q6.S(SOURCE) Q7.S(SOURCE) Q8.S(SOURCE) Q10.S(SOURCE) Q11.S(SOURCE) Q12.S(SOURCE) Q13.S(SOURCE) Q14.S(SOURCE) Q15.E(EMITTER) Q19.S Q32.S Q33.1 Q33.4(S2) Q34.S Q37.S Q38.S Q41.S Q42.S Q44.1 Q44.2 Q44.3(S3) Q47.1 Q47.2 Q47.3(S3) Q48.1 Q48.2 Q48.3(S3) Q51.1 Q51.4(S2) Q55.S(SOURCE) Q58.S Q66.4(S2) Q69.1 R24.2 R29.2 R31.2 R36.2 R42.2 R43.2 R61.1 R63.2 R64.2 R65.2 R87.2 R91.2 R100.2 R101.2 R145.2 R164.1 R167.2 R168.2 R170.1 R171.1 R177.2 R178.1 R181.1 R210.2 R215.2 R227.2 R228.2 R247.1 R260.2 R262.1 R270.2 R273.1 R280.2 R287.1 R291.2 R294.1 R295.2 R304.2 R311.1 R315.2 R318.2 R321.1 R328.2 R335.1 R339.2 R342.1 R343.2 R352.2 R359.1 R363.2 R366.2 R369.1 R376.2 R383.1 R387.2 R390.2 R393.1 R400.2 R407.1 R411.2 R414.2 R417.1 R424.2 R431.1 R435.2 R438.2 R441.1 R448.2 R455.1 R459.2 R496.1 R497.1 R498.1 R499.1 R500.1 R501.1 R502.1 R503.1 R504.2 R515.2 R519.1 R528.1 R529.1 R539.2 R541.1 R558.2 R559.2 R562.2 R565.1 R566.2 R567.2 R568.2 R569.2 R570.2 R571.2 R579.2 R583.2 R585.2 R587.2 R610.2 R615.2 R625.1 R626.1 R627.1 R628.1 R631.2 R632.2 R633.2 R634.2 R635.2 R639.2 R640.2 R641.1 R654.1 R659.1 R661.1 R665.2 R673.2 R674.2 R685.2 R698.1 R711.2 R713.1 R718.1 R723.1 R726.1 R746.1 R756.1 R768.1 R769.1 R1478.2 R1479.2 R1482.2 R1509.2 R1510.1 RA7.2 RA8.2 RA11.1 RA12.1 RA13.1 RA30.1 RA31.1 RA32.1 RA33.1 RA34.1 RA35.1 RA36.1 RA37.1 RA38.1 RA39.1 RA40.1 RA41.1 RA42.1 RA43.1 RA44.1 RA45.1 RA46.1 RA47.1 RA48.1 RA49.1 RA50.1 RB5.2 RB26.2 RB37.1 RB39.1 RECOVERY1.2(GND1) RECOVERY1.4 RESET1.2(GND1) RESET1.4 RZ13.2 RZ53.1 RZ58.1 RZ66.1 RZ69.1 RZ70.1 RZ71.1 RZ75.1 RZ77.1 RZ112.2 RZ116.1 RZ119.2 RZ121.1 RZ177.1 RZ199.2 RZ200.1 RZ202.1 RZ207.1 RZ208.1 RZ209.1 RZ210.1 RZU19.1 RZU29.2 RZU34.1 RZU36.2 RZU38.2 S2.1 S3.1 S4.1 S5.1 S6.2 SPI1.4 SPI2.4 SSD2.1 SSD2.3 SSD2.9 SSD2.15 SSD2.21 SSD2.27 SSD2.33 SSD2.39 SSD2.45 SSD2.51 SSD2.57 SSD2.71 SSD2.73 SSD2.75 TP17.1 TP18.4 TP18.8 U3.3 U4.3 U5.3 U6.3 U6.12 U6.21 U7.2 U7.5 U9.3 U10.3 U11.3 U12.3 U13.9 U13.20(VSSA) U13.25 U13.55 U14.6 U15.4 U15.7(WP) U16.49 U18.2 U18.9 U18.16 U18.23 U18.32 U18.33 U19.3 U20.77 U21.4 U22.2 U23.2 U24.2 U24.8 U25.25 U26.2 U26.8 U27.1 U28.2 U29.2 U30.4 U32.4 U33.3 U34.1 U34.2 U34.11 U36.4 U37.3 U38.4 U39.1 U40.2 U40.8 U41.65 U42.4 U42.9 U43.65 U44.4 U44.9 U45.65 U46.4 U46.9 U47.65 U48.4 U48.9 U49.65 U50.4 U50.9 U51.65 U52.4 U52.9 U53.65 U54.4 U54.9 U55.65 U56.4 U56.9 U65.21 U65.46 U65.48 U65.49 U65.50 U65.51 U65.57 U66.19 U66.25 U66.31 U66.35 U66.44(VSS_2) U66.65 U67.K10 U67.K11 U67.K15 U67.K16 U67.L10 U67.L11 U67.L12 U67.L13 U67.L14 U67.L15 U67.L16 U67.M10 U67.M11 U67.M12 U67.M13 U67.M14 U67.M15 U67.M16 U67.N10 U67.N11 U67.N12 U67.N13 U67.N14 U67.N15 U67.N16 U67.P10 U67.P11 U67.P12 U67.P13 U67.P14 U67.P15 U67.P16 U67.R10 U67.R11 U67.R12 U67.R13 U67.R14 U67.R15 U67.R16 U67.T10 U67.T11 U67.T14 U67.T16 U70.89 U72.7 U73.7 U74.2 U75.2 U76.11 U76.12 U76.13 U76.14 U76.15 U76.16 U76.17 U76.18 U77.2 U78.7 U79.7 U80.4 U81.4 U83.30 U84.2 U85.6 U86.10 U86.11 U87.1 U88.2 U89.2 U90.2 U91.3 U92.6 U92.12 U92.15 U92.21 USB1.7 USB1.9 USB1.10 VS1.1 VS2.1 VS3.1 VS4.1 VS5.1 WIFI1.1 WIFI1.7 WIFI1.18 WIFI1.33 WIFI1.39 WIFI1.45 WIFI1.51 WIFI1.57 WIFI1.63 WIFI1.69 WIFI1.75 WOL1.2 X1.2 X1.4 X2.2 X2.4 X3.2 X3.4 X4.2 X4.4 X5.2 X5.4 X6.2 X6.4 X7.2 X7.4 X8.2 X8.4 X9.2 X9.4 X10.2 X10.4 X11.2 X11.4 Y1.2 Y1.4 Y2.2 Y2.4 Z1.1 Z2.1 Z3.1 Z4.1 Z5.1 Z6.1 Z7.1 Z8.1 Z9.1 Z10.1 Z12.1 Z16.1 Z17.1 Z18.1
GNDA: S2.2 S3.2 S4.2 S5.2 U67.A4 U67.A10 U67.A13 U67.A14 U67.A17 U67.A18 U67.A20 U67.A24 U67.A26 U67.AA2 U67.AA4 U67.AA5 U67.AA7 U67.AA24 U67.AA26 U67.AB1 U67.AB3 U67.AB8 U67.AB10 U67.AB17 U67.AB18 U67.AB21 U67.AB22 U67.AC4 U67.AC6 U67.AC8 U67.AC10 U67.AC15 U67.AC16 U67.AC19 U67.AC20 U67.AC23 U67.AC25 U67.AC26 U67.AD1 U67.AD2 U67.AD5 U67.AD7 U67.AD9 U67.AD11 U67.AD17 U67.AD18 U67.AD21 U67.AD22 U67.AE1 U67.AE2 U67.AE15 U67.AE16 U67.AE19 U67.AE20 U67.AE23 U67.AE24 U67.AF4 U67.AF6 U67.AF8 U67.AF10 U67.AF17 U67.AF18 U67.AF21 U67.AF22 U67.AF26 U67.B2 U67.B3 U67.B11 U67.B12 U67.B15 U67.B16 U67.B21 U67.B25 U67.C1 U67.C5 U67.C10 U67.C13 U67.C14 U67.C17 U67.C18 U67.C23 U67.D11 U67.D12 U67.D15 U67.D16 U67.D20 U67.D22 U67.D23 U67.D25 U67.E2 U67.E4 U67.E13 U67.E14 U67.E17 U67.E18 U67.E24 U67.E26 U67.F1 U67.F3 U67.F24 U67.F26 U67.G1 U67.G3 U67.G23 U67.G25 U67.H2 U67.H4 U67.H23 U67.H25 U67.J2 U67.J4 U67.J24 U67.J26 U67.K1 U67.K3 U67.K9 U67.K12 U67.K13 U67.K14 U67.K17 U67.K24 U67.K26 U67.L1 U67.L3 U67.L9 U67.L17 U67.L23 U67.L25 U67.M2 U67.M4 U67.M9 U67.M17 U67.M23 U67.M25 U67.N2 U67.N4 U67.N9 U67.N17 U67.N24 U67.N26 U67.P1 U67.P3 U67.P9 U67.P17 U67.P24 U67.P26 U67.R1 U67.R3 U67.R9 U67.R17 U67.R23 U67.R25 U67.T2 U67.T4 U67.T9(GNDA99) U67.T12 U67.T13 U67.T15 U67.T17 U67.T23 U67.T25 U67.U2 U67.U4 U67.U24 U67.U26 U67.V1 U67.V3 U67.V24 U67.V26 U67.W1 U67.W3 U67.W23 U67.W25 U67.Y2 U67.Y4 U67.Y23 U67.Y25
V0P9_LAN1: C172.1 CB43.1 CB44.1 CB49.1 CB66.1 CB90.1 RZ128.2 U41.11 U41.32 U41.42 U41.59
V0P9_LAN2: C181.1 CB50.1 CB51.1 CB68.1 CB82.1 CB109.1 RZ130.2 U43.11 U43.32 U43.42 U43.59
V0P9_LAN3: C190.1 CB52.1 CB53.1 CB69.1 CB83.1 CB113.1 RZ131.2 U45.11 U45.32 U45.42 U45.59
V0P9_LAN4: C199.1 CB54.1 CB55.1 CB70.1 CB84.1 CB117.1 RZ132.2 U47.11 U47.32 U47.42 U47.59
V0P9_LAN5: C208.1 CB56.1 CB57.1 CB71.1 CB85.1 CB121.1 RZ133.2 U49.11 U49.32 U49.42 U49.59
V0P9_LAN6: C217.1 CB58.1 CB59.1 CB72.1 CB86.1 CB125.1 RZ134.2 U51.11 U51.32 U51.42 U51.59
V0P9_LAN7: C226.1 CB46.1 CB47.1 CB67.1 CB81.1 CB104.1 RZ129.2 U53.11 U53.32 U53.42 U53.59
V0P9_LAN8: C235.1 CB32.1 CB33.1 CB34.1 CB39.1 CB42.1 RZ105.2 U55.11 U55.32 U55.42 U55.59
V1P5_LAN1: C170.1 CB79.1 CB80.1 CB88.1 CB89.1 RZ135.2 U41.47 U41.56
V1P5_LAN2: C179.1 CB93.1 CB99.1 CB110.1 CB111.1 RZ137.2 U43.47 U43.56
V1P5_LAN3: C188.1 CB94.1 CB100.1 CB114.1 CB115.1 RZ138.2 U45.47 U45.56
V1P5_LAN4: C197.1 CB95.1 CB101.1 CB118.1 CB119.1 RZ139.2 U47.47 U47.56
V1P5_LAN5: C207.1 CB96.1 CB102.1 CB122.1 CB123.1 RZ140.2 U49.47 U49.56
V1P5_LAN6: C215.1 CB97.1 CB103.1 CB126.1 CB127.1 RZ141.2 U51.47 U51.56
V1P5_LAN7: C224.1 CB92.1 CB98.1 CB105.1 CB106.1 RZ136.2 U53.47 U53.56
V1P5_LAN8: C233.1 CB30.1 CB31.1 CB37.1 CB38.1 RZ104.2 U55.47 U55.56
V1P8_B: R212.2 R216.2 R222.1
V3.3_M2_B: C110.1 C111.2 C112.2 C113.2 CA6.2 CA9.2 CA12.2 CE2.1 FB7.2 NGFF1.2 NGFF1.4 NGFF1.70 NGFF1.72 NGFF1.74 R213.2 R221.2 R226.2 RA51.1 U32.6(VOUT)
V3P3_LAN1: C168.1 C169.1 CB45.1 CB65.1 CB87.1 CB91.1 CB141.1 CB148.1 LANACT1.A LANLINK1.A1 LANLINK1.A2 R269.1 R274.2 R275.1 R276.2 R277.2 R278.2 R279.2 R290.1 RA16.2 RA23.2 RA66.1 RA67.1 RA68.1 RA76.1 RA83.1 RA89.1 RA90.1 RA91.1 RA92.1 RA96.1 RA102.1 RA111.1 RA112.1 RA123.1 RA124.1 RA129.2 RA130.2 RA131.2 RA132.2 RZ117.1 U41.10 U41.27 U41.41 U41.51 U41.64 U42.8
V3P3_LAN2: C177.1 C178.1 CB60.1 CB74.1 CB112.1 CB129.1 CB147.1 CB154.1 LANACT2.A LANLINK2.A1 LANLINK2.A2 R293.1 R298.2 R299.1 R300.2 R301.2 R302.2 R303.2 R314.1 RA20.2 RA25.2 RA74.1 RA81.1 RA88.1 RA98.1 RA104.1 RA115.1 RA116.1 RA127.1 RA128.1 RA153.2 RA154.2 RA155.2 RA156.2 RZ122.1 U43.10 U43.27 U43.41 U43.51 U43.64 U44.8
V3P3_LAN3: C186.1 C187.1 CB61.1 CB75.1 CB116.1 CB130.1 CB146.1 CB153.1 LANACT3.A LANLINK3.A1 LANLINK3.A2 R317.1 R322.2 R323.1 R324.2 R325.2 R326.2 R327.2 R338.1 RA21.2 RA26.2 RA73.1 RA80.1 RA87.1 RA97.1 RA103.1 RA113.1 RA114.1 RA125.1 RA126.1 RA149.2 RA150.2 RA151.2 RA152.2 RZ123.1 U45.10 U45.27 U45.41 U45.51 U45.64 U46.8
V3P3_LAN4: C195.1 C196.1 CB62.1 CB76.1 CB120.1 CB131.1 CB145.1 CB152.1 LANACT4.A LANLINK4.A1 LANLINK4.A2 R341.1 R346.2 R347.1 R348.2 R349.2 R350.2 R351.2 R362.1 RA18.2 RA27.2 RA72.1 RA79.1 RA86.1 RA145.2 RA146.2 RA147.2 RA148.2 RZ124.1 U47.10 U47.27 U47.41 U47.51 U47.64 U48.8
V3P3_LAN5: C204.1 C205.1 CB63.1 CB77.1 CB124.1 CB132.1 CB144.1 CB151.1 LANACT5.A LANLINK5.A1 LANLINK5.A2 R364.1 R370.2 R371.1 R372.2 R373.2 R374.2 R375.2 R386.1 RA22.2 RA28.2 RA71.1 RA78.1 RA85.1 RA95.1 RA101.1 RA109.1 RA110.1 RA121.1 RA122.1 RA141.2 RA142.2 RA143.2 RA144.2 RZ125.1 U49.10 U49.27 U49.41 U49.51 U49.64 U50.8
V3P3_LAN6: C213.1 C214.1 CB64.1 CB78.1 CB128.1 CB133.1 CB143.1 CB150.1 LANACT6.A LANLINK6.A1 LANLINK6.A2 R389.1 R394.2 R395.1 R396.2 R397.2 R398.2 R399.2 R410.1 RA19.2 RA29.2 RA70.1 RA77.1 RA84.1 RA94.1 RA100.1 RA107.1 RA108.1 RA119.1 RA120.1 RA137.2 RA138.2 RA139.2 RA140.2 RZ126.1 U51.10 U51.27 U51.41 U51.51 U51.64 U52.8
V3P3_LAN7: C222.1 C223.1 CB48.1 CB73.1 CB107.1 CB108.1 CB142.1 CB149.1 LANACT7.A LANLINK7.A1 LANLINK7.A2 R412.1 R418.2 R419.1 R420.2 R421.2 R422.2 R423.2 R434.1 RA17.2 RA24.2 RA69.1 RA75.1 RA82.1 RA93.1 RA99.1 RA105.1 RA106.1 RA117.1 RA118.1 RA133.2 RA134.2 RA135.2 RA136.2 RZ127.1 U53.10 U53.27 U53.41 U53.51 U53.64 U54.8
V3P3_LAN8: C231.1 C232.1 CB35.1 CB36.1 CB40.1 CB41.1 CB139.1 CB140.1 LANACT8.A LANLINK8.A1 LANLINK8.A2 R437.1 R442.2 R443.1 R444.2 R445.2 R446.2 R447.2 R458.1 RA14.2 RA15.2 RA53.1 RA54.1 RA55.1 RA56.1 RA57.1 RA58.2 RA59.2 RA60.2 RA61.2 RA62.1 RA63.1 RA64.1 RA65.1 RZ99.1 U55.10 U55.27 U55.41 U55.51 U55.64 U56.8
VBUS_IN: R163.1 RA7.1 U20.42
VCC1.8: C70.1 U25.24
VCC5_USB1: C65.1 C66.1 CA76.1 CA77.1 CE11.1 CN1.1(VBUS) U22.6(VO)
VCC5_USB2: C67.1 C68.1 CA82.1 CA83.1 CA84.1 CE12.1 CE13.1 CN2.1(VBUS) U23.6(VO) U28.6(VO) USB1.1
VCC25P: C324.1 C327.1 C330.1 C333.1 C336.1 C338.1 C340.1 C343.1 C346.1 C349.1 C351.1 C353.1 C355.1 C357.1 C359.1 C377.1 CB9.2 CM17.1 CM18.1 CM19.1 CM20.1 CM21.1 CM22.1 CM23.1 CM24.1 FB37.2 U67.AA12 U67.AA13 U67.AA14 U67.AA15 U67.AA16 U67.AB12 U67.AB13 U67.AB14 U67.AC12 U67.AC13 U67.AC14 U67.AD12 U67.AD13 U67.AD14 U67.AE12 U67.AE13 U67.AE14 U67.AF12 U67.AF13 U67.AF14 U67.E11 U67.E12 U67.J16 U67.J17 U67.J18 U67.K8 U67.K18 U67.L8 U67.M8 U67.N18 U67.R8 U67.T8 U67.T18 U67.U10 U67.U18 U70.13 U70.19 U70.24 U70.29 U70.48 U70.54 U70.68 U70.85
VCC_DCIN: C388.1 C389.2 C437.1 C438.1 C439.1 C442.1 C443.1 C459.2 C462.2 C469.2 C922.2 CE3.1 CE4.1 D60.C Q30.5 Q30.6 Q30.7 Q30.8 Q30.9 Q43.5 Q43.6 Q43.7 Q43.8 Q43.9 Q45.5 Q45.6 Q45.7 Q45.8 Q45.9 R663.1 R720.1 R740.2 U74.4 U83.3
VCC_SRC: C1.1 C2.1 C74.1 C75.1 C155.1 C156.1 CA17.1 CA19.1 J1.B3 J1.B63 J1.C1 J1.C2 J1.C63 J1.C64 J1.C65 J1.D1 J1.D2 J1.D3 J1.D64 J1.D65 J1.E1 J1.E2 J1.E63 J1.E64 J1.E65 J1.F1 J1.F2 J1.F3 J1.F63 J1.F64 J1.F65 J1.G1 J1.G2 J1.G63 J1.G64 J1.G65 J1.H1 J1.H2 J1.H3 J1.H64 J1.H65 J1.J1 J1.J2 J1.J63 J1.J64 J1.J65 J1.K3 Q31.1 Q31.2 Q31.3(S3) R139.2 R670.2 R671.2 RZ27.1 U27.2 U39.2
VDD105: CM5.1 CM8.1 CM11.1 CM14.1 FB36.2 U70.9 U70.23 U70.33 U70.58
VDD105P: C323.1 C326.1 C329.1 C332.1 C335.1 C337.1 C339.1 C342.1 C345.1 C348.1 C350.1 C352.1 C354.1 C356.1 C358.1 C360.1 C361.1 C362.1 C363.1 C364.1 C375.1 CB7.2 CM2.1 CM3.1 CM4.1 CM6.1 CM7.1 CM9.1 CM10.1 CM12.1 CM13.1 CM15.1 CM16.1 FB35.2 FB36.1 U67.A6 U67.A7 U67.A8 U67.B6 U67.B7 U67.B8 U67.C6 U67.C7 U67.C8 U67.D6 U67.D7 U67.D8 U67.E6 U67.E7 U67.E8 U67.F6 U67.F7 U67.F8 U67.J8 U67.J9 U67.J10 U67.J11 U67.J14 U67.J15 U67.L18 U67.M18 U67.N8 U67.P8 U67.P18 U67.R18 U67.U8 U67.U9 U67.U13 U67.U14 U67.U15 U67.U16 U67.U17 U70.10 U70.16 U70.22 U70.26 U70.32 U70.45 U70.51 U70.57 U70.73 U70.82 U70.88
VDD_1V8_CDC: C30.1 C911.1 CA48.1 CA51.1 R112.1 R123.1 R124.1 R762.2 RZ12.2 RZ168.2 U16.43
VDD_A: C313.1 C314.1 C315.1 C316.1 C317.1 FB34.1 U66.17 U66.36 U66.45 U66.46
VDD_BBAT: D1.C J1.D37
VDD_PLL_A_A: C307.1 C308.1 FB31.1 U66.34
VDD_PLL_P_A: C309.1 C310.1 FB32.1 U66.42
VDDE_A: C298.1 C299.1 C300.1 FB28.1 R532.2 R533.2 R534.2 R535.1 R536.1 R537.1 R538.1 RZU28.2 U66.1 U66.43
VIN_PWR_BAD_G: Q5.G RZ4.2 RZU4.1 RZU5.2
VIN_PWR_BAD_N: J1.L55 Q5.S Q33.6 RZ3.2 RZU4.2
VIN_PWR_ON: RB6.2 RZ8.1 RZ191.1 U6.10
VIN_PWR_ON_5V: Q38.G RZ116.2 RZ191.2
VIN_PWR_ON_SRC: Q34.G R674.1 RZ8.2
VIN_SHUTDOWN_N: Q33.5 R668.2 RZ3.1 U75.4
VIN_SHUTDOWN_Q: Q33.2 Q33.3 R669.2 R673.1
06DPE_RSTN: C370.1 R622.2 RZ85.2
06DPE_RSTN_R: RZ85.1 U70.36
06INT_HOTPLUG: TP49.1 U70.8
06PERSTN: C369.1 R621.2 RZ81.1 U70.37
06REXT: R634.1 U70.67
06REXT2: R635.1 U70.25
06SM_CLK: RZU32.1 U70.42
06SM_DATA: RZU33.1 U70.41
06SPI_CS: SPI2.1 U70.6
06SPI_SCK: R637.1 RZ108.2 RZ111.2 U70.7
06SPI_SDIO: R629.1 R633.1 RZ109.1 RZ114.1 U70.5
06SPI_SDIO1: RZ109.2 RZ110.2
06TESTEN: R632.1 U70.59
06UART_RX: J13.4 U70.35
06UART_TX: J13.3 R636.1 RZ89.2 U70.34
06UPE_CLKREQN: R638.2 R641.2 U70.65
06WP#: R648.2 RZU36.1 SPI2.3(WP#)
06XI: C371.2 U70.69 X11.3
06XO: C371.1 U70.70(XO) X11.1
12DPE_CLKN0: RZ37.2 RZ83.1
12DPE_CLKP0: RZ33.2 RZ80.1
12DPE_CLKREQN0: R566.1 U67.AC3
12DPE_CLKREQN1: R567.1 U67.AD3
12DPE_CLKREQN2: R568.1 U67.AB5
12DPE_CLKREQN3: R569.1 U67.AC5
12DPE_CLKREQN4: R570.1 U67.C9
12DPE_CLKREQN5: R571.1 U67.D9
12DPE_RSTN: C318.1 R563.1 RZ182.1
12DPE_RXN0: CM56.2 U67.P23
12DPE_RXN1: CM50.2 U67.T24
12DPE_RXP0: CM57.2 U67.N23
12DPE_RXP1: CM51.2 U67.R24
12DPE_TXN0: CM52.2 U67.P25
12DPE_TXN1: CM54.2 U67.T26
12DPE_TXP0: CM53.2 U67.N25
12DPE_TXP1: CM55.2 U67.R26
422RX+: NMEA0183.5 R251.1 R254.2 U36.6
422RX-: NMEA0183.2 R251.2 R253.1 U36.7
422TX+_485+: NMEA0183.6 R249.1 R259.2 U38.6
422TX-_485-: NMEA0183.8 R249.2 R257.1 U38.7
1812_RST_N: RZ180.1 U67.A2
1812DEBUG27: R575.1 RZ59.1 U67.AD24
1812DEBUG27_P: R585.1 RZ59.2
1812DEBUG28: TP48.1 U67.AF24
1812GPIO5: R578.1 RZ60.1 U67.AD25
1812GPIO5_P: R583.1 RZ60.2
1812INT_HOTPLUG: TP47.1 U67.AA25
1812SMCL: RZU44.1 U67.A1
1812SMDA: RZU43.1 U67.B1
1812SPI_CS: SPI1.1 U67.AD26
1812SPI_SCK: R606.1 RZ65.2 RZ196.2 U67.AB26
1812SPI_SCK_P: R610.1 RZ196.1
1812SPI_SDIO: R574.1 RZ68.1 RZ195.1 RZ197.1 U67.AE26
1812SPI_SDIO1: RZ197.2 RZ198.2
1812SPI_SDIO_P: R587.1 RZ195.2
1812TESTEN: R579.1 U67.AB4
1812UART_TX: R605.1 RZ193.2
1812UART_TX_P: R615.1 RZ193.1
1812WP#: R618.2 RZU29.1 SPI1.3(WP#)
1812XI: C319.2 U67.AC1 X10.3
1812XO: C319.1 U67.AC2 X10.1
6408_INT#: RB54.1 RZU31.2 U14.11
9633_HPD: Q55.G R504.1 RZU45.2 U66.40
51770_AGND: C459.1 C460.1 C471.1 C475.1 C476.1 C477.1 R733.1 R742.1 R748.2 R751.1 R752.1 R753.1 RZ177.2 RZ687.1 U83.17 U83.39
51770_ATRK: C477.2 U83.16
51770_BIAS: CA64.1 RZ27.2 RZU19.2 U83.1
51770_COMP: C475.2 R747.2 U83.18
51770_IMONOUT: R748.1 U83.6
51770_MODE: RB30.1 RZ687.2 U83.12
51770_VCC: C468.2 CA60.1 R741.1 RB29.2 RB30.2 RZ31.1 U83.31
-SPKOUT: BUZZ1.2 CA117.1 Q15.C
ACC_ON: D58.C R86.1
ACC_ON#: Q10.D R85.1 U13.1
ACC_ON_R: Q10.G R86.2 R87.1
ACOK_CON: AUTOPW1.2 R1482.1 RZU20.1 U91.1 Z16.2
ACOK_CON_OR: C894.1 R1479.1 U91.4(Y)
ACOK_CON_OR_CR: C894.2 D65.C(-) R1478.1 U90.3
ACOK_OR_RISING: RZ6.2 U12.4(Y)
ACOK_WOL_FB: RZ28.2 RZ30.2 RZU20.2 RZU24.2 U9.2 U91.2
ACOK_WOL_OR: C10.1 R43.1 U9.4(Y)
ACOK_WOL_OR_CR: C10.2 D2.C(-) R42.1 U90.1
ACOK_WOL_RISING: RZ28.1 RZ30.1 U12.1 U12.2 U90.4 U90.6
ALERT: NMEA0183.3 TP60.1
ASM1806_GPIO5: R630.1 R631.1 U70.2
ASM_VCC33: CA72.1 CA73.1 CA80.1 CA88.1 CB15.1 CB16.1 CB17.1 CB18.1 CB29.1 Q29.S R574.2 R575.2 R578.2 R589.2 R606.2 R607.1 R608.1 R618.1 R629.2 R630.2 R637.2 R638.1 R644.1 R645.1 R648.1 SPI1.8 SPI2.8 U67.A19 U67.AA8 U67.AA9 U67.B19 U67.C19 U67.D19 U67.E19 U67.F19 U67.W22 U67.Y22 U70.4 U70.39 U70.63
AUD_MCLK01_CDC: C916.1 RZ155.2 U16.37
AUDIO_CODEC_INT: R112.2 RZ156.2 U16.40
AUDIO_CPN1: C43.2 U16.21
AUDIO_CPN2: C45.2 U16.18
AUDIO_CPN_VEE: C47.1 U16.27
AUDIO_CPP1: C43.1 U16.20
AUDIO_CPP2: C45.1 U16.19
AUDIO_CPP_VPP: C46.1 U16.24
AUDIO_LDO_EN: R114.2 U16.44
AUDIO_MIC1P: C44.2 U16.13
AUDIO_MIC_1P: AUDIO1.5 C44.1 R1493.1
AUDIO_MICBIAS: CA14.1 R1493.2 RZ164.1
AUDIO_MICBIAS_C: RZ164.2 U16.4
AUDIO_VREF1: CA15.1 U16.11
AUDIO_VREF2: CA16.1 U16.12(VREF2)
AUDIO_VREF_DAC: C54.1 CA132.1 RZ166.2 U16.10
AUTOPWON: RZ115.1 U13.40
BAT_CONN: BAT1.2 R23.1
BAT_CONN_LIM: D1.A2 R23.2
BRD_SEL: R36.1 RB9.2 U6.11
BT_WAKE_AP_M2E_CON: Q52.6 R190.1 WIFI1.20
BTN_OOB: OOB1.9 RZ190.2
BUTTON_POWER_ON_N: RB13.2 RZ152.2 TP12.1 U6.2
BUTTON_POWER_ON_N_CON: CA153.1 PWRBTN1.3 RB66.2 RZ151.1 RZ190.1
BUTTON_POWER_ON_N_KEY: C132.1 PSON1.1 PSON1.2 RZ151.2 RZ152.1 Z7.2
CAM0_PWDN: J1.L49 J14.93
CAM0_RST: J1.L5 J14.95
CAM1_PWDN: J1.F10 J14.90
CAM1_RST: J1.F9 J14.92
CAM_AVDD_EN: J1.F56 RZ2.1
CAM_BACKLIGHT_PWM: J14.109 RZ18.1
CAM_ERROR1: J1.L15 J14.76
CAM_ERROR2: J1.L9 J14.78
CAM_ERROR3: J1.A7 J14.84
CAM_ERROR4: J1.L4 J14.86
CAM_FRSYNC1: J1.A62 J14.85
CAM_FRSYNC2: J1.F59 J14.98
CAM_FRSYNC3: J1.E59 J14.97
CAM_FRSYNC4: J1.G7 J14.96
CAM_INT1: J1.E61 J14.117 TP10.1
CAM_INT2: J1.D62 J14.106 TP9.1
CAM_INT3: J1.F60 J14.103 TP8.1
CAM_INT4: J1.D60 J14.104 TP7.1
CAM_PG: RB4.1 U34.8
CAM_SPI_CS0: J14.113 TP53.1
CAM_SPI_MISO: J14.114 TP55.1
CAM_SPI_MOSI: J14.112 TP54.1
CAM_SPI_SCK: J14.111 TP52.1
CAM_TE_RSV: J14.101 RZU7.1
CAM_VDD_SYS_EN: J1.E10 J14.119
CAM_VDDEN: CA13.1 R245.2 R756.2 RZ2.2 U34.9
CAN0_DIN: J1.F58 U40.5
CAN0_DOUT: J1.D59 U40.3
CAN_REF: C159.1 C162.2 C163.2 C164.2 NMEA2000.6 R261.1 U40.9 U40.10 U40.15
CANH: C162.1 D12.2 FL2.4 NMEA2000.5 R264.2 R265.2 RZU1.2
CANL: C164.1 D13.2 FL2.3 NMEA2000.4 R265.1 R267.1 RZU2.2
CARRIER_POWER_ON: R24.1 RZ5.2 RZ45.1 RZ56.1 RZ147.1 RZ167.1 RZU26.1 U4.4(Y)
CARRIER_SHUTDOWN_N: Q4.D Q5.D RB22.2 U11.2
CASE1_GND: C160.2 NMEA2000.1 R262.2
CCG4_LED: AUTOPW1.1 RZ115.2 RZ120.1 Z10.2
CHIPENABLE: RZ90.1 RZU34.2 U20.50
CLK-ISP0: R61.2 R62.1
CLK-ISP0#: RZ203.2 SW1.3 SW1.4 U13.13
CLKREQ_M2_KEY_B_N: NGFF1.52 R221.1
CODEC_INT: J1.B8 RZ156.1
COMR_A: C291.2 R505.2 R506.2 R507.2 R508.2 R510.2 R511.2 R513.2 R514.2 U66.32
CSI_0_CLK_N: J1.F42 J14.9
CSI_0_CLK_P: J1.F43 J14.7
CSI_0_D0_N: J1.E41 J14.3
CSI_0_D0_P: J1.E42 J14.1
CSI_0_D1_N: J1.E38 J14.15
CSI_0_D1_P: J1.E39 J14.13
CSI_1_CLK_N: J1.H42 J14.10
CSI_1_CLK_P: J1.H43 J14.8
CSI_1_D0_N: J1.G42 J14.4
CSI_1_D0_P: J1.G41 J14.2
CSI_1_D1_N: J1.J42 J14.16
CSI_1_D1_P: J1.J41 J14.14
CSI_2_CLK_N: J1.B42 J14.27
CSI_2_CLK_P: J1.B43 J14.25
CSI_2_D0_N: J1.A42 J14.21
CSI_2_D0_P: J1.A41 J14.19
CSI_2_D1_N: J1.C41 J14.33
CSI_2_D1_P: J1.C42 J14.31
CSI_3_CLK_N: J1.F45 J14.28
CSI_3_CLK_P: J1.F46 J14.26
CSI_3_D0_N: J1.E44 J14.22
CSI_3_D0_P: J1.E45 J14.20
CSI_3_D1_N: J1.G45 J14.34
CSI_3_D1_P: J1.G44 J14.32
CSI_4_CLK_N: J1.F49 J14.45
CSI_4_CLK_P: J1.F48 J14.43
CSI_4_D0_N: J1.G47 J14.39
CSI_4_D0_P: J1.G48 J14.37
CSI_4_D1_N: J1.E48 J14.51
CSI_4_D1_P: J1.E47 J14.49
CSI_5_CLK_N: J1.C45 J14.67
CSI_5_CLK_P: J1.C44 J14.65
CSI_5_D0_N: J1.D43 J14.61
CSI_5_D0_P: J1.D42 J14.59
CSI_5_D1_N: J1.D45 J14.73
CSI_5_D1_P: J1.D46 J14.71
CSI_6_CLK_N: J1.J45 J14.46
CSI_6_CLK_P: J1.J44 J14.44
CSI_6_D0_N: J1.K43 J14.40
CSI_6_D0_P: J1.K44 J14.38
CSI_6_D1_N: J1.H45 J14.52
CSI_6_D1_P: J1.H46 J14.50
CSI_7_CLK_N: J1.B46 J14.68
CSI_7_CLK_P: J1.B45 J14.66
CSI_7_D0_N: J1.A45 J14.62
CSI_7_D0_P: J1.A44 J14.60
CSI_7_D1_N: J1.C48 J14.74
CSI_7_D1_P: J1.C47 J14.72
CTS2#: R174.1 U25.20
CVB_STBY: RZU8.2 RZU9.1 U33.4(Y) Z8.2
CVM_PRSNT: J1.L63 PSON1.3 PSON1.4 Q4.G R51.2 RZU38.1
DCD2#: TP38.1 U25.19
DIO_INT#: RZU31.1 U13.18
DIO_SCL: U13.44 U14.12
DIO_SDA: U13.43 U14.13
DM: RZ9.1 U25.37
DP: RZ10.1 U25.38
DP2_AUX_CH_N_I2C6_DAT: J1.G54 U66.47
DP2_AUX_CH_P_I2C6_CLK: J1.G53 U66.48
DP2_HPD_CH0_HPD: J1.K50 Q55.D R540.1 R541.2 RZU45.1
DPE_CLKN0: RZ87.1 U70.75
DPE_CLKN1: RZ93.1 U70.77
DPE_CLKN2: RZ94.1 U70.79
DPE_CLKP0: RZ84.1 U70.74
DPE_CLKP1: RZ88.1 U70.76
DPE_CLKP2: RZ92.1 U70.78
DPE_CLKREQN0: R625.2 U70.60
DPE_CLKREQN1: R626.2 U70.61
DPE_CLKREQN2: R627.2 U70.62
DPE_CLKREQN3: R628.2 U70.64
DPE_RSTN_R: RZ182.2 U67.A3
DPE_RXN0: RZ107.1 U70.21
DPE_RXN1: RZ102.1 U70.12
DPE_RXN6: RZ97.1 U70.87
DPE_RXP0: RZ106.1 U70.20
DPE_RXP1: RZ101.1 U70.11
DPE_RXP6: RZ96.1 U70.86
DPE_TXN0: CM61.1 U70.18
DPE_TXN1: CM63.1 U70.15
DPE_TXN6: CM59.1 U70.84
DPE_TXP0: CM60.1 U70.17
DPE_TXP1: CM62.1 U70.14
DPE_TXP6: CM58.1 U70.83
DSR2#: R172.1 U25.32
DSR4#: R175.1 U25.55
DTR2: TP37.1 U25.29
E_TX0N_A: R522.1 U66.23
E_TX0N_R_A: CB23.2 R522.2
E_TX0P_A: R521.1 U66.24
E_TX0P_R_A: CB24.2 R521.2
E_TX1N_A: R520.1 U66.26
E_TX1N_R_A: CB25.2 R520.2
E_TX1P_A: R518.1 U66.27
E_TX1P_R_A: CB26.2 R518.2
E_TX2N_A: R517.1 U66.29
E_TX2N_R_A: CB27.2 R517.2
E_TX2P_A: R516.1 U66.30
E_TX2P_R_A: CB28.2 R516.2
E_TXCN_A: R524.1 U66.20
E_TXCN_R_A: CB21.2 R524.2
E_TXCP_A: R523.1 U66.21
E_TXCP_R_A: CB22.2 R523.2
EEPROM_A0: R98.2 RB26.1 TP23.1 U15.1
EEPROM_A1: R101.1 RB27.2 TP22.1 U15.2
EEPROM_A2: R100.1 RB28.2 TP20.1 U15.3
EFM8_ACOK: R31.1 RZ6.1 U6.16
EFM8_D_ONKEY_N: RB63.2 TP13.1 U6.19
EFM8_FORCE_SHUTDOWN: R48.2 RZ204.1 U6.14 U11.4(Y)
EFM8_MODULE_POWER_ON: RB5.1 RZU3.2 U6.9 U7.4
EFM8_P0_4: TP14.1 U6.18
EFM8_PSHOLD: RZ5.1 U6.15
EFM8_RST_MON: Q2.6 RB11.2 RZ201.1 U6.13 U19.1 U19.2
EFM8SB10_C2CK: MCUCON1.2 RB10.2 TP16.1 U6.5
EFM8SB10_C2D: MCUCON1.1 TP15.1 U6.6
ETH_WOL_EN_N: Q58.G R1475.1 WOL1.1 Z17.2
ETH_WOL_EN_STATUS: J1.A47 Q58.D R1476.1
F1: R1498.1 TP18.3 U13.42 Z4.2
F2: R1499.1 TP18.2 U13.30 Z3.2
F3: R1500.1 TP18.1 U13.39 Z2.2
FC_PWR_OFF: NGFF1.6 R210.1 R212.1
FORCE_RECOVERY_N: J1.L10 RZ19.2
FORCE_RECOVERY_N_CON: CA135.1 RB64.2 RECOVERY1.3 RZ11.1
FORCE_RECOVERY_N_KEY: C135.1 PSON3.1 PSON3.2 RZ11.2 RZ19.1 RZU6.1 Z12.2
HDMI_DP0_TX0_N: J1.D52 U66.51
HDMI_DP0_TX0_P: J1.D51 U66.50
HDMI_DP0_TX1_N: J1.B52 U66.54
HDMI_DP0_TX1_P: J1.B51 U66.53
HDMI_DP0_TX2_N: J1.A50 U66.56
HDMI_DP0_TX2_P: J1.A51 U66.55
HDMI_DP0_TX3_N: J1.C50 U66.59
HDMI_DP0_TX3_P: J1.C51 U66.58
HDMI_GND: C294.2 HDMI1.X1 HDMI1.X2 HDMI1.X3 R528.2
HMCU_SCL_A: R535.2 U66.7
HMCU_SDA_A: R536.2 U66.8
HPO_L: FB41.1 RZ686.2
HPO_R: FB40.2 RZ685.2
HUB_RESET#: C60.1 R162.1 R164.2 RZ76.1 U20.41
HUB_XTAL1: C58.1 R159.2 U20.9 X1.1
HUB_XTAL2: RZ82.2 U20.10(X2)
HUB_XTAL2_R: C57.1 R159.1 RZ82.1 X1.3
I2C_GP1_CLK: J1.K5 R92.2 TP21.1 U15.6
I2C_GP1_DAT: J1.L8 R93.2 TP19.1 U15.5
I2C_GP2_CLK: J1.J61 J14.87 RZ91.1 RZU22.2
I2C_GP2_CLK_3V3: RB57.1 RZ206.2 RZU32.2 RZU44.2 U13.48
I2C_GP2_DAT: J1.K61 J14.89 RZ86.1 RZU23.2
I2C_GP2_DAT_3V3: RB56.1 RZ205.2 RZU33.2 RZU43.2 U13.47
I2C_GP3_CLK: J1.F53 J14.75 R242.1
I2C_GP3_DAT: J1.E53 J14.77 R243.1
I2C_GP9_CLK: J1.A53 J14.105 RZ158.1 RZU40.2 TP29.1
I2C_GP9_DAT: J1.C53 J14.107 RZ157.1 RZU41.2 TP28.1
I2C_INT_CCG4: J1.E56 Q59.S RB24.1
I2C_SCL_CDC: R124.2 RZ158.2 U16.38
I2C_SDA_CDC: R123.2 RZ157.2 U16.39
I2S1_DIN: J1.H8 RZ163.1
I2S1_DIN_CDC: C912.1 RZ163.2 TP27.1 U16.34
I2S1_DOUT: J1.C7 RZ165.1
I2S1_DOUT_CDC: C913.1 RZ165.2 TP26.1 U16.33
I2S1_FS: J1.D8 RZ161.1
I2S1_FS_CDC: C914.1 RZ161.2 TP25.1 U16.35
I2S1_SCLK: J1.L14 RZ159.1
I2S1_SCLK_CDC: C915.1 RZ159.2 TP24.1 U16.36
I2S4_DIN: J1.J59 WIFI1.12
I2S4_DOUT: J1.K59 WIFI1.14
I2S4_FS: J1.C60 WIFI1.10
I2S4_SCLK: J1.C59 WIFI1.8
I210_JTAG_CLK1: R278.1 U41.19
I210_JTAG_TDI1: R279.1 R280.1 U41.29
I210_JTAG_TDO1: R276.1 U41.4
I210_JTAG_TMS1: R277.1 U41.18
I2101 SDP0: RA132.1 U41.63
I2101 SDP1: RA130.1 U41.61
I2101 SDP2: RA131.1 U41.62
I2101 SDP3: RA129.1 U41.60
I2101_RSET: R273.2 U41.48
I2101_SMB_ALERT#: RA67.2 U41.35
I2101_SMCLK: RA66.2 U41.34
I2101_SMDATA: RA68.2 U41.36
I2102_RSET: R294.2 U43.48
I2102_SMB_ALERT#: RA81.2 U43.35
I2102_SMCLK: RA74.2 U43.34
I2102_SMDATA: RA88.2 U43.36
I2103_RSET: R321.2 U45.48
I2103_SMB_ALERT#: RA80.2 U45.35
I2103_SMCLK: RA73.2 U45.34
I2103_SMDATA: RA87.2 U45.36
I2104_RSET: R342.2 U47.48
I2104_SMB_ALERT#: RA79.2 U47.35
I2104_SMCLK: RA72.2 U47.34
I2104_SMDATA: RA86.2 U47.36
I2105_RSET: R369.2 U49.48
I2105_SMB_ALERT#: RA78.2 U49.35
I2105_SMCLK: RA71.2 U49.34
I2105_SMDATA: RA85.2 U49.36
I2106_RSET: R393.2 U51.48
I2106_SMB_ALERT#: RA77.2 U51.35
I2106_SMCLK: RA70.2 U51.34
I2106_SMDATA: RA84.2 U51.36
I2107_RSET: R417.2 U53.48
I2107_SMB_ALERT#: RA75.2 U53.35
I2107_SMCLK: RA69.2 U53.34
I2107_SMDATA: RA82.2 U53.36
I2108_RSET: R441.2 U55.48
I2108_SMB_ALERT#: RA56.2 U55.35
I2108_SMCLK: RA57.2 U55.34
I2108_SMDATA: RA55.2 U55.36
IGN: DC_IN1.2 FB38.1
IN1P: AUDIO1.1 C898.1
IN2P: AUDIO1.2 C899.1
INTR_ISP1: R1505.1 U13.38
ISO12_REF: C157.2 C158.2 C159.2 CA3.2 CE1.2(-) NMEA0183.1 NMEA2000.8 R261.2 U39.7
ISO_+V12S: C155.2 C157.1 CA3.1 CE1.1 NMEA0183.4 NMEA2000.7 U39.6
ISO_GND: C76.1 C77.2 C78.2 CA1.2 CA2.2 CA118.2 D9.3 D9.8 D10.3 D10.8 NMEA0183.7 R253.2 R257.2 U24.9 U24.15 U26.9 U26.15 U27.7 U36.5 U38.5 UART1.11
ISO_RX1: D9.4 D9.7 U24.12 UART1.9
ISO_RX2: D9.5 D9.6(NC4) U24.11 UART1.7
ISO_RX3: D10.4 D10.7 U26.12 UART1.5
ISO_RX4: D10.5 D10.6(NC4) U26.11 UART1.3
ISO_TX1: D9.1 D9.10 U24.14 UART1.10
ISO_TX2: D9.2 D9.9 U24.13 UART1.8
ISO_TX3: D10.1 D10.10 U26.14 UART1.6
ISO_TX4: D10.2 D10.9 U26.13 UART1.4
JD1: RZ160.1 RZU37.1 U16.6
JD2: RZ162.2 RZU39.2 U16.8
JTAG_TCK: J1.A60 J4.4 R145.1 TP33.1
JTAG_TDI: J1.B60 J4.8 R143.2 TP31.1
JTAG_TDO: J1.D58 J4.6 R142.2 TP32.1
JTAG_TMS: J1.E58 J4.2 R141.2 TP34.1
JTAG_TRST_N: J1.G61 TP6.1
KSENSA: RZ66.2 RZ69.2 U65.4
KSENSB: RZ200.2 RZ202.2 U65.11
KSENSC: RZ75.2 RZ77.2 U65.32
KSENSD: RZ70.2 RZ71.2 U65.39
LAN1_ACT#: R286.2 U41.30
LAN1_CBOT: C171.2 U41.37
LAN1_CT1_A+_V-: C242.2 D14.1 FB8.1 U57.24
LAN1_CT2_A-_V+: C241.2 D15.1 FB9.1 U57.21
LAN1_CT3_B+_V+: C240.2 D17.1 FB10.1 U57.18
LAN1_CT4_B-_V-: C238.2 D18.1 FB11.1 U57.15
LAN1_CTOP: C171.1 U41.40
LAN1_DEV_OFF: R269.2 R270.1 U41.28
LAN1_LINK_100#: R288.2 U41.31
LAN1_LINK_1000#: R289.2 U41.33
LAN1_MDI0+: D16.1 D16.10 U41.58 U57.2
LAN1_MDI0+_T: POE1.8 U57.23
LAN1_MDI0-: D16.2 D16.9 U41.57 U57.3
LAN1_MDI0-_T: POE1.7 U57.22
LAN1_MDI1+: D16.4 D16.7 U41.55 U57.5
LAN1_MDI1+_T: POE1.6 U57.20
LAN1_MDI1-: D16.5 D16.6(NC4) U41.54 U57.6
LAN1_MDI1-_T: POE1.5 U57.19
LAN1_MDI2+: D19.1 D19.10 U41.53 U57.8
LAN1_MDI2+_T: POE1.3 U57.17
LAN1_MDI2-: D19.2 D19.9 U41.52 U57.9
LAN1_MDI2-_T: POE1.4 U57.16
LAN1_MDI3+: D19.4 D19.7 U41.50 U57.11
LAN1_MDI3+_T: POE1.2 U57.14
LAN1_MDI3-: D19.5 D19.6(NC4) U41.49 U57.12(TD4-)
LAN1_MDI3-_T: POE1.1 U57.13
LAN1_NVM_CS: R284.1 U42.1
LAN1_NVM_SI: R281.1 R290.2 R291.1 U42.5
LAN1_NVM_SK: R282.1 R287.2 U42.6
LAN1_NVM_SO: R283.1 U42.2
LAN1_PWR_GOOD: R275.2 U41.1
LAN1_VDD0P9_OUT: C166.1 RZ128.1 U41.38
LAN1_VDD1P5_OUT: C167.1 RZ135.1 U41.39
LAN1_XTAL1: C174.1 R285.2 U41.46 X2.1
LAN1_XTAL2: RB14.1 U41.45(XTAL2)
LAN2_ACT#: R310.2 U43.30
LAN2_CBOT: C180.2 U43.37
LAN2_CT1_A+_V-: C247.2 D20.1 FB12.1 U58.24
LAN2_CT2_A-_V+: C246.2 D22.1 FB13.1 U58.21
LAN2_CTOP: C180.1 U43.40
LAN2_DEV_OFF: R293.2 R295.1 U43.28
LAN2_LINK_100#: R312.2 U43.31
LAN2_LINK_1000#: R313.2 U43.33
LAN2_MDI0+: D21.1 D21.10 U43.58 U58.2
LAN2_MDI0+_T: POE2.8 U58.23
LAN2_MDI0-: D21.2 D21.9 U43.57 U58.3
LAN2_MDI0-_T: POE2.7 U58.22
LAN2_MDI1+: D21.4 D21.7 U43.55 U58.5
LAN2_MDI1+_T: POE2.6 U58.20
LAN2_MDI1-: D21.5 D21.6(NC4) U43.54 U58.6
LAN2_MDI1-_T: POE2.5 U58.19
LAN2_MDI2+: D23.1 D23.10 U43.53 U58.8
LAN2_MDI2+_T: POE2.4 U58.17
LAN2_MDI2-: D23.2 D23.9 U43.52 U58.9
LAN2_MDI2-_T: POE2.3 U58.16
LAN2_MDI3+: D23.4 D23.7 U43.50 U58.11
LAN2_MDI3+_T: POE2.2 U58.14
LAN2_MDI3-: D23.5 D23.6(NC4) U43.49 U58.12(TD4-)
LAN2_MDI3-_T: POE2.1 U58.13
LAN2_NVM_CS: R308.1 U44.1
LAN2_NVM_SI: R305.1 R314.2 R315.1 U44.5
LAN2_NVM_SK: R306.1 R311.2 U44.6
LAN2_NVM_SO: R307.1 U44.2
LAN2_PWR_GOOD: R299.2 U43.1
LAN2_VDD0P9_OUT: C175.1 RZ130.1 U43.38
LAN2_VDD1P5_OUT: C176.1 RZ137.1 U43.39
LAN2_XTAL1: C183.1 R309.2 U43.46 X3.1
LAN2_XTAL2: RB15.1 U43.45(XTAL2)
LAN3_ACT#: R333.2 U45.30
LAN3_CBOT: C189.2 U45.37
LAN3_CT1_A+_V-: C252.2 D25.1 FB16.1 U59.24
LAN3_CT2_A-_V+: C251.2 D26.1 FB17.1 U59.21
LAN3_CTOP: C189.1 U45.40
LAN3_DEV_OFF: R317.2 R318.1 U45.28
LAN3_LINK_100#: R336.2 U45.31
LAN3_LINK_1000#: R337.2 U45.33
LAN3_MDI0+: D24.1 D24.10 U45.58 U59.2
LAN3_MDI0+_T: POE3.8 U59.23
LAN3_MDI0-: D24.2 D24.9 U45.57 U59.3
LAN3_MDI0-_T: POE3.7 U59.22
LAN3_MDI1+: D24.4 D24.7 U45.55 U59.5
LAN3_MDI1+_T: POE3.6 U59.20
LAN3_MDI1-: D24.5 D24.6(NC4) U45.54 U59.6
LAN3_MDI1-_T: POE3.5 U59.19
LAN3_MDI2+: D27.1 D27.10 U45.53 U59.8
LAN3_MDI2+_T: POE3.4 U59.17
LAN3_MDI2-: D27.2 D27.9 U45.52 U59.9
LAN3_MDI2-_T: POE3.3 U59.16
LAN3_MDI3+: D27.4 D27.7 U45.50 U59.11
LAN3_MDI3+_T: POE3.2 U59.14
LAN3_MDI3-: D27.5 D27.6(NC4) U45.49 U59.12(TD4-)
LAN3_MDI3-_T: POE3.1 U59.13
LAN3_NVM_CS: R332.1 U46.1
LAN3_NVM_SI: R329.1 R338.2 R339.1 U46.5
LAN3_NVM_SK: R330.1 R335.2 U46.6
LAN3_NVM_SO: R331.1 U46.2
LAN3_PWR_GOOD: R323.2 U45.1
LAN3_VDD0P9_OUT: C184.1 RZ131.1 U45.38
LAN3_VDD1P5_OUT: C185.1 RZ138.1 U45.39
LAN3_XTAL1: C192.1 R334.2 U45.46 X4.1
LAN3_XTAL2: RB16.1 U45.45(XTAL2)
LAN4_ACT#: R356.2 U47.30
LAN4_CBOT: C198.2 U47.37
LAN4_CT1_A+_V-: C257.2 D28.1 FB18.1 U60.24
LAN4_CT2_A-_V+: C256.2 D30.1 FB19.1 U60.21
LAN4_CTOP: C198.1 U47.40
LAN4_DEV_OFF: R341.2 R343.1 U47.28
LAN4_LINK_100#: R360.2 U47.31
LAN4_LINK_1000#: R361.2 U47.33
LAN4_MDI0+: D29.1 D29.10 U47.58 U60.2
LAN4_MDI0+_T: POE4.8 U60.23
LAN4_MDI0-: D29.2 D29.9 U47.57 U60.3
LAN4_MDI0-_T: POE4.7 U60.22
LAN4_MDI1+: D29.4 D29.7 U47.55 U60.5
LAN4_MDI1+_T: POE4.6 U60.20
LAN4_MDI1-: D29.5 D29.6(NC4) U47.54 U60.6
LAN4_MDI1-_T: POE4.5 U60.19
LAN4_MDI2+: D31.1 D31.10 U47.53 U60.8
LAN4_MDI2+_T: POE4.4 U60.17
LAN4_MDI2-: D31.2 D31.9 U47.52 U60.9
LAN4_MDI2-_T: POE4.3 U60.16
LAN4_MDI3+: D31.4 D31.7 U47.50 U60.11
LAN4_MDI3+_T: POE4.2 U60.14
LAN4_MDI3-: D31.5 D31.6(NC4) U47.49 U60.12(TD4-)
LAN4_MDI3-_T: POE4.1 U60.13
LAN4_NVM_CS: R357.1 U48.1
LAN4_NVM_SI: R353.1 R362.2 R363.1 U48.5
LAN4_NVM_SK: R354.1 R359.2 U48.6
LAN4_NVM_SO: R355.1 U48.2
LAN4_PWR_GOOD: R347.2 U47.1
LAN4_VDD0P9_OUT: C193.1 RZ132.1 U47.38
LAN4_VDD1P5_OUT: C194.1 RZ139.1 U47.39
LAN4_XTAL1: C201.1 R358.2 U47.46 X5.1
LAN4_XTAL2: RB17.1 U47.45(XTAL2)
LAN5_ACT#: R381.2 U49.30
LAN5_CBOT: C206.2 U49.37
LAN5_CT1_A+_V-: C262.2 D33.1 FB20.1 U61.24
LAN5_CT2_A-_V+: C261.2 D34.1 FB21.1 U61.21
LAN5_CTOP: C206.1 U49.40
LAN5_DEV_OFF: R364.2 R366.1 U49.28
LAN5_LINK_100#: R384.2 U49.31
LAN5_LINK_1000#: R385.2 U49.33
LAN5_MDI0+: D32.1 D32.10 U49.58 U61.2
LAN5_MDI0+_T: POE5.8 U61.23
LAN5_MDI0-: D32.2 D32.9 U49.57 U61.3
LAN5_MDI0-_T: POE5.7 U61.22
LAN5_MDI1+: D32.4 D32.7 U49.55 U61.5
LAN5_MDI1+_T: POE5.6 U61.20
LAN5_MDI1-: D32.5 D32.6(NC4) U49.54 U61.6
LAN5_MDI1-_T: POE5.5 U61.19
LAN5_MDI2+: D35.1 D35.10 U49.53 U61.8
LAN5_MDI2+_T: POE5.4 U61.17
LAN5_MDI2-: D35.2 D35.9 U49.52 U61.9
LAN5_MDI2-_T: POE5.3 U61.16
LAN5_MDI3+: D35.4 D35.7 U49.50 U61.11
LAN5_MDI3+_T: POE5.2 U61.14
LAN5_MDI3-: D35.5 D35.6(NC4) U49.49 U61.12(TD4-)
LAN5_MDI3-_T: POE5.1 U61.13
LAN5_NVM_CS: R380.1 U50.1
LAN5_NVM_SI: R377.1 R386.2 R387.1 U50.5
LAN5_NVM_SK: R378.1 R383.2 U50.6
LAN5_NVM_SO: R379.1 U50.2
LAN5_PWR_GOOD: R371.2 U49.1
LAN5_VDD0P9_OUT: C202.1 RZ133.1 U49.38
LAN5_VDD1P5_OUT: C203.1 RZ140.1 U49.39
LAN5_XTAL1: C210.1 R382.2 U49.46 X6.1
LAN5_XTAL2: RB18.1 U49.45(XTAL2)
LAN6_ACT#: R405.2 U51.30
LAN6_CBOT: C216.2 U51.37
LAN6_CT1_A+_V-: C267.2 D36.1 FB22.1 U62.24
LAN6_CT2_A-_V+: C266.2 D38.1 FB23.1 U62.21
LAN6_CTOP: C216.1 U51.40
LAN6_DEV_OFF: R389.2 R390.1 U51.28
LAN6_LINK_100#: R408.2 U51.31
LAN6_LINK_1000#: R409.2 U51.33
LAN6_MDI0+: D37.1 D37.10 U51.58 U62.2
LAN6_MDI0+_T: POE6.8 U62.23
LAN6_MDI0-: D37.2 D37.9 U51.57 U62.3
LAN6_MDI0-_T: POE6.7 U62.22
LAN6_MDI1+: D37.4 D37.7 U51.55 U62.5
LAN6_MDI1+_T: POE6.6 U62.20
LAN6_MDI1-: D37.5 D37.6(NC4) U51.54 U62.6
LAN6_MDI1-_T: POE6.5 U62.19
LAN6_MDI2+: D39.1 D39.10 U51.53 U62.8
LAN6_MDI2+_T: POE6.4 U62.17
LAN6_MDI2-: D39.2 D39.9 U51.52 U62.9
LAN6_MDI2-_T: POE6.3 U62.16
LAN6_MDI3+: D39.4 D39.7 U51.50 U62.11
LAN6_MDI3+_T: POE6.2 U62.14
LAN6_MDI3-: D39.5 D39.6(NC4) U51.49 U62.12(TD4-)
LAN6_MDI3-_T: POE6.1 U62.13
LAN6_NVM_CS: R404.1 U52.1
LAN6_NVM_SI: R401.1 R410.2 R411.1 U52.5
LAN6_NVM_SK: R402.1 R407.2 U52.6
LAN6_NVM_SO: R403.1 U52.2
LAN6_PWR_GOOD: R395.2 U51.1
LAN6_VDD0P9_OUT: C211.1 RZ134.1 U51.38
LAN6_VDD1P5_OUT: C212.1 RZ141.1 U51.39
LAN6_XTAL1: C219.1 R406.2 U51.46 X7.1
LAN6_XTAL2: RB19.1 U51.45(XTAL2)
LAN7_ACT#: R429.2 U53.30
LAN7_CBOT: C225.2 U53.37
LAN7_CT1_A+_V-: C272.2 D40.1 FB26.1 U63.24
LAN7_CT2_A-_V+: C271.2 D41.1 FB27.1 U63.21
LAN7_CTOP: C225.1 U53.40
LAN7_DEV_OFF: R412.2 R414.1 U53.28
LAN7_LINK_100#: R432.2 U53.31
LAN7_LINK_1000#: R433.2 U53.33
LAN7_MDI0+: D42.1 D42.10 U53.58 U63.2
LAN7_MDI0+_T: POE7.8 U63.23
LAN7_MDI0-: D42.2 D42.9 U53.57 U63.3
LAN7_MDI0-_T: POE7.7 U63.22
LAN7_MDI1+: D42.4 D42.7 U53.55 U63.5
LAN7_MDI1+_T: POE7.6 U63.20
LAN7_MDI1-: D42.5 D42.6(NC4) U53.54 U63.6
LAN7_MDI1-_T: POE7.5 U63.19
LAN7_MDI2+: D43.1 D43.10 U53.53 U63.8
LAN7_MDI2+_T: POE7.4 U63.17
LAN7_MDI2-: D43.2 D43.9 U53.52 U63.9
LAN7_MDI2-_T: POE7.3 U63.16
LAN7_MDI3+: D43.4 D43.7 U53.50 U63.11
LAN7_MDI3+_T: POE7.2 U63.14
LAN7_MDI3-: D43.5 D43.6(NC4) U53.49 U63.12(TD4-)
LAN7_MDI3-_T: POE7.1 U63.13
LAN7_NVM_CS: R428.1 U54.1
LAN7_NVM_SI: R425.1 R434.2 R435.1 U54.5
LAN7_NVM_SK: R426.1 R431.2 U54.6
LAN7_NVM_SO: R427.1 U54.2
LAN7_PWR_GOOD: R419.2 U53.1
LAN7_VDD0P9_OUT: C220.1 RZ129.1 U53.38
LAN7_VDD1P5_OUT: C221.1 RZ136.1 U53.39
LAN7_XTAL1: C228.1 R430.2 U53.46 X8.1
LAN7_XTAL2: RB20.1 U53.45(XTAL2)
LAN8_ACT#: R454.2 U55.30
LAN8_CBOT: C234.2 U55.37
LAN8_CTOP: C234.1 U55.40
LAN8_DEV_OFF: R437.2 R438.1 U55.28
LAN8_LINK_100#: R456.2 U55.31
LAN8_LINK_1000#: R457.2 U55.33
LAN8_MDI0+: D44.1 D44.10 U55.58 U64.2
LAN8_MDI0+_T: POE8.8 U64.23
LAN8_MDI0-: D44.2 D44.9 U55.57 U64.3
LAN8_MDI0-_T: POE8.7 U64.22
LAN8_MDI1+: D44.4 D44.7 U55.55 U64.5
LAN8_MDI1+_T: POE8.6 U64.20
LAN8_MDI1-: D44.5 D44.6(NC4) U55.54 U64.6
LAN8_MDI1-_T: POE8.5 U64.19
LAN8_MDI2+: D45.1 D45.10 U55.53 U64.8
LAN8_MDI2+_T: POE8.4 U64.17
LAN8_MDI2-: D45.2 D45.9 U55.52 U64.9
LAN8_MDI2-_T: POE8.3 U64.16
LAN8_MDI3+: D45.4 D45.7 U55.50 U64.11
LAN8_MDI3+_T: POE8.2 U64.14
LAN8_MDI3-: D45.5 D45.6(NC4) U55.49 U64.12(TD4-)
LAN8_MDI3-_T: POE8.1 U64.13
LAN8_NVM_CS: R452.1 U56.1
LAN8_NVM_SI: R449.1 R458.2 R459.1 U56.5
LAN8_NVM_SK: R450.1 R455.2 U56.6
LAN8_NVM_SO: R451.1 U56.2
LAN8_PWR_GOOD: R443.2 U55.1
LAN8_VDD0P9_OUT: C229.1 RZ105.1 U55.38
LAN8_VDD1P5_OUT: C230.1 RZ104.1 U55.39
LAN8_XTAL1: C237.1 R453.2 U55.46 X9.1
LAN8_XTAL2: RB21.1 U55.45(XTAL2)
LAN_CLKN1: RZ184.2 U41.25
LAN_CLKN2: RZ50.2 U43.25
LAN_CLKN3: RZ48.2 U45.25
LAN_CLKN4: RZ186.2 U47.25
LAN_CLKN5: RZ54.2 U49.25
LAN_CLKN6: RZ87.2 U51.25
LAN_CLKN7: RZ93.2 U53.25
LAN_CLKN8: RZ94.2 U55.25
LAN_CLKP1: RZ183.2 U41.26
LAN_CLKP2: RZ52.2 U43.26
LAN_CLKP3: RZ42.2 U45.26
LAN_CLKP4: RZ185.2 U47.26
LAN_CLKP5: RZ55.2 U49.26
LAN_CLKP6: RZ84.2 U51.26
LAN_CLKP7: RZ88.2 U53.26
LAN_CLKP8: RZ92.2 U55.26
LAN_GND: CV1.2 CV8.2 D14.2(CATHODE) D15.2(CATHODE) D17.2(CATHODE) D18.2(CATHODE) D20.2(CATHODE) D22.2(CATHODE) D25.2(CATHODE) D26.2(CATHODE) D28.2(CATHODE) D30.2(CATHODE) D33.2(CATHODE) D34.2(CATHODE) D36.2(CATHODE) D38.2(CATHODE) D40.2(CATHODE) D41.2(CATHODE) FB47.2 FB48.2 FB49.2 FB50.2 R460.1 R461.1 R462.1 R463.1 R464.1 R465.1 R466.1 R467.1 R468.1 R469.1 R470.1 R471.1 R472.1 R473.1 R474.1 R475.1 R476.1 R477.1 R478.1 R479.1 R480.1 R481.1 R482.1 R483.1 R484.1 R485.1 R486.1 R487.1 R488.1 R489.1 R490.1 R491.1 TH1.2(P2) TH2.2(P2) TH3.2(P2) TH4.2(P2)
LED_ON1: Q6.D R58.1 R63.1 TP18.7 Z1.2
LED_ON1#: Q6.G U13.4
LED_ON2: Q7.D R57.1 R64.1 TP18.6 Z5.2
LED_ON2#: Q7.G U13.15
LED_ON3: Q8.D R56.1 R65.1 TP18.5 Z6.2
LED_ON3#: Q8.G U13.16
LOUT-L: AUDIO1.9 C838.1 FB41.2
LOUT-R: AUDIO1.10 C839.1 FB40.1
M2_5G_PLTRST_N: NGFF1.50 U88.6
M2_B_EN: R223.1 RZ147.2 U32.8
M2_B_PG: CM64.1 RA51.2 U32.3
M2_WIFI_PLTRST_N: R191.1 U88.4 WIFI1.52
M2E_ALERT_N: J1.B55 RZ169.2
M2E_AP_WAKE_BT: Q52.4(S2) R193.1 RZ22.1 RZ25.2 RZU42.2
M2E_AP_WAKE_BT_CON: Q52.3 R192.1 RZ170.2
M2E_BT_DISABLE_N: J1.F55 Q54.1 R201.1
M2E_BT_WAKE: J1.J55 Q52.1 R187.1
M2E_SAR_TOUT: RZ21.1 RZ171.2
M2E_SDIO_EN: J1.B58 RZU17.1
M2E_SDIO_WAKE: J1.L6 R1483.1 RZU12.1
M2E_WIFI_DISABLE_N: J1.J4 Q53.4(S2) R198.1
M2E_WIFI_WAKE: J1.G55 Q17.S Q50.S R3.1 R196.2 RZU16.1
M2M_ALERT_N: J1.A55 R757.1 SSD2.44
M.2_BT_RF_KILL#: Q54.6 R200.1 WIFI1.54
M.2_RESET: NGFF1.67 R222.2
M.2_WIFI_RF_KILL#: Q53.3 R197.1 WIFI1.56(W_DISABLE#)
M.2_WIFI_SUS_CLK: R194.2 WIFI1.50
MCLK01_AUDIO_MCLK: J1.H9 RZ155.1
MCLK02_CAM0_MCLK: J14.91 RZ16.1
MCLK02_MCLK: J1.J54 RZ16.2
MCLK03_CAM1_MCLK: J14.88 RZ14.1
MCLK03_MCLK: J1.H53 RZ14.2
MCLK04_CAM2_MCLK: J14.94 RZ17.1
MCLK04_MCLK: J1.H55 RZ17.2
MCU2_FLASH#: J1.C61 RZ203.1
MCU2_RST#: C24.1 DB1.10 R81.1 SW2.3 SW2.4 U13.64
MCU2_VDD: C18.1 C19.1 C20.1 C21.1 CA70.1 CA71.1 CA149.1 CA150.1 CA151.1 CA152.1 DB1.1 FB1.2 FB2.1 R56.2 R57.2 R58.2 R62.2 R81.2 R84.2 R85.2 R90.1 R1477.1 R1491.2 R1498.2 R1499.2 R1500.2 R1505.2 RB47.2 RB48.2 RB49.2 RB50.2 RB51.2 RB52.2 RB53.2 RB54.2 RB55.2 U13.8 U13.24 U13.34 U13.56 U14.14(VCCP) U14.15
MCU2_VDD_REF: C22.1 C23.1 CA69.1 FB2.2 U13.22 U13.23
MCU_BUZZ: R1491.1 RZ1.1 U13.41
MCU_CARRIER_POWER_ON: J1.L62 U4.1 U4.2
MCU_IRQ#: Q59.D R1490.1 U13.19
MCU_OP_A: R539.1 RZU28.1 U66.16
MCU_P25_A: R515.1 U66.60
MCU_P70_RXD: R532.1 RZU47.1 U66.4
MCU_P71_TXD: R533.1 RZU46.1 U66.5
MCU_SCL_A: R537.2 U66.9 U66.38
MCU_SDA_A: R538.2 U66.10 U66.37
MCU_VDD: C412.1 C413.1 C414.1 C415.1 CB14.1 CB136.1 FB1.1 PL3.2 Q39.1 Q39.2 Q39.3(S3) R697.2 R702.2 U77.5(VOUT)
MCU_VDD_EN: C417.1 D64.C(-) R696.1 U77.12
MOD_SHUTDOWN_N: J1.L52 R46.2 U10.2
MOD_SHUTDOWN_N_3V3: RB12.2 U10.4(Y) U11.1
MOD_TEMP_SHDN_EN_N: J1.J62 RZ13.1
MODULE_POWER_ON: J1.L54 R29.1 RZU3.1 U7.3
N_SIN1: U24.5 U25.3
N_SIN2: U24.6(VOD) U25.22
N_SIN3: U25.41 U26.5
N_SIN4: U25.64 U26.6(VOD)
N_SOUT1: U24.3 U25.2
N_SOUT2: U24.4 U25.21
N_SOUT3: U25.40 U26.3
N_SOUT4: U25.63 U26.4
NC_SI1_ARB_IN: RA89.2 U41.43
NC_SI1_ARB_OUT: RA91.2 U41.44
NC_SI1_CLK: RA33.2 U41.2
NC_SI1_CRS_DV: RA31.2 U41.3
NC_SI1_RXD0: RA90.2 U41.6
NC_SI1_RXD1: RA92.2 U41.5
NC_SI1_TX_EN: RA30.2 U41.7
NC_SI1_TXD0: RA76.2 U41.9
NC_SI1_TXD1: RA83.2 U41.8
NCSI4_ARBIN: RA111.2 U47.43
NCSI4_ARBOUT: RA123.2 U47.44
NCSI4_CLKIN: NCSI1.5 RA48.2 U47.2
NCSI4_CRS_DV: NCSI1.9 RA42.2 U47.3
NCSI4_RXD0: NCSI1.7 RA112.2 U47.6
NCSI4_RXD1: NCSI1.8 RA124.2 U47.5
NCSI4_TX_EN: NCSI1.3 RA36.2 U47.7
NCSI4_TXD0: NCSI1.1 RA96.2 U47.9
NCSI4_TXD1: NCSI1.2 RA102.2 U47.8
NVM_CS1: R284.2 U41.15
NVM_SI1: R281.2 U41.12
NVM_SK1: R282.2 U41.13
NVM_SO1: R283.2 U41.14
NVME_PCIE_WAKE_N: R759.1 RZ178.1 SSD2.54
OVCUR1#: RA6.2 RZ74.1 U20.19
OVCUR2#: RA10.2 RZ95.1 U20.2
OVCUR3#: RA9.2 U20.54
OVCUR4#: RA5.2 U20.40
P0_TOD_CLK_IN_3V3: RZ41.1 U85.8
P1_TOD_CLK_IN_3V3: RZ47.1 U85.7
P_SPI_CK: U20.14 U21.6
P_SPI_CZ: U20.16 U21.1
P_SPI_DI: U20.15 U21.2
P_SPI_DO: U20.13 U21.5
P_SPI_HOLD#: RA3.2 U21.7
P_SPI_WP#: RA4.2 U21.3(WP#)
PCIE1_CLKREQ_N: J1.B37 RZ174.1
PCIE1_RST_N: J1.B36 U88.1 U88.3 U89.1 U89.3
PCIE4_CLK_N: J1.E22 SSD2.53
PCIE4_CLK_P: J1.E23 SSD2.55
PCIE4_CLKREQ_N: J1.G8 SSD2.52
PCIE4_RST_N: J1.J9 R760.1 SSD2.50
PCIE5_CLK_N: J1.F25 RZ181.2
PCIE5_CLK_P: J1.F24 RZ179.2
PCIE5_CLKREQ_N: J1.C8 R565.2 RZU21.2
PCIE5_RST_N: R560.2 RZ81.2 RZ180.2 U3.4(Y) U41.17 U43.17 U45.17 U47.17
PCIE5_RST_N1: U5.4(Y) U49.17 U51.17 U53.17 U55.17
PCIE5RST_N: J1.H10 U3.1 U3.2 U5.1 U5.2
PCIE_3V3_EN: J1.L48 R661.2 RZ194.2 RZU25.1 RZU27.1
PCIE_RST#: RZ67.1 U89.6
PCIE_RXN1: CM82.2 U67.V23
PCIE_RXN2: CM94.2 U67.Y24
PCIE_RXN3: CM92.2 U67.L24
PCIE_RXN4: CM90.2 U67.G24
PCIE_RXN5: CM88.2 U67.E23
PCIE_RXN6: CM86.2 RZ107.2
PCIE_RXN7: CM84.2 RZ102.2
PCIE_RXN8: CM80.2 RZ97.2
PCIE_RXP1: CM81.2 U67.U23
PCIE_RXP2: CM93.2 U67.W24
PCIE_RXP3: CM91.2 U67.M24
PCIE_RXP4: CM89.2 U67.H24
PCIE_RXP5: CM87.2 U67.F23
PCIE_RXP6: CM85.2 RZ106.2
PCIE_RXP7: CM83.2 RZ101.2
PCIE_RXP8: CM79.2 RZ96.2
PCIE_TXN1: CM47.2 U41.23
PCIE_TXN2: CM77.2 U43.23
PCIE_TXN3: CM74.2 U45.23
PCIE_TXN4: CM76.2 U47.23
PCIE_TXN5: CM48.2 U49.23
PCIE_TXN6: CM61.2 U51.23
PCIE_TXN7: CM63.2 U53.23
PCIE_TXN8: CM59.2 U55.23
PCIE_TXP1: CM46.2 U41.24
PCIE_TXP2: CM78.2 U43.24
PCIE_TXP3: CM73.2 U45.24
PCIE_TXP4: CM75.2 U47.24
PCIE_TXP5: CM49.2 U49.24
PCIE_TXP6: CM60.2 U51.24
PCIE_TXP7: CM62.2 U53.24
PCIE_TXP8: CM58.2 U55.24
PCIE_WAKE#: Q3.G Q50.D R2.1 R274.1 R298.1 R322.1 R346.1 R370.1 R394.1 R418.1 R442.1 U41.16 U43.16 U45.16 U47.16 U49.16 U51.16 U53.16 U55.16
PCIE_WAKE_N: J1.A8 RZ178.2
PGANG: R166.2 R168.1 U20.5
PLTRST#_TPM: U18.17 U19.4(Y)
POE_56: C460.2 C466.2 C920.1 C921.1 CE6.1 CE7.1 Q63.5 Q63.6 Q63.7 Q63.8 Q63.9 R730.2 R731.2 RZ26.1 U83.20(VOUT)
POE_EN: C471.2 Q69.2 R740.1 R742.2 RZ78.2 U83.4
POE_EN#: Q11.G RB55.1 U14.8
POE_FAST_SHUTDOWN: RZ62.1 U65.56
POE_GATE: Q64.5 Q64.6 Q64.7 Q64.8 Q64.9 Q65.1 Q65.2 Q65.3(S3) Q68.5 Q68.6 Q68.7 Q68.8 Q68.9 R1506.2 R1507.2
POE_IN: C393.1 CE5.1 D63.C DC_IN1.3 Q67.5 Q67.6 Q67.7 Q67.8 Q67.9
POE_IN_MOS: POESLT2.1 Q64.1 Q64.2 Q64.3(S3) Q67.1 Q67.2 Q67.3(S3)
POE_INT#: RB45.1 U13.17 U65.45
POE_OUT1A: C280.2 D46.A F1.2 FB8.2
POE_OUT1B: C281.2 D47.A F2.2 FB11.2
POE_OUT2: C282.2 D48.A F3.2 FB12.2
POE_OUT3: C283.2 D49.A F4.2 FB16.2
POE_OUT4: C284.2 D50.A F5.2 FB18.2
POE_OUT5: C285.2 D51.A F6.2 FB20.2
POE_OUT6: C286.2 D52.A F7.2 FB22.2
POE_OUT7: C287.2 D53.A F8.2 FB26.2
POE_RST#: CA248.1 RB46.1 U65.44
POE_SCL: RB44.1 U13.12 U65.53
POE_SDA: RB65.1 RZ63.2 RZ64.2 U13.11
POE_SHUTDOWN: RZ62.2 RZU30.2
POE_VCC: C279.1 C280.1 C281.1 C282.1 C283.1 C284.1 C285.1 C286.1 C287.1 D46.C(CATHODE) D47.C(CATHODE) D48.C(CATHODE) D49.C(CATHODE) D50.C(CATHODE) D51.C(CATHODE) D52.C(CATHODE) D53.C(CATHODE) FB9.2 FB10.2 FB13.2 FB17.2 FB19.2 FB21.2 FB23.2 FB27.2 Q65.5 Q65.6 Q65.7 Q65.8 Q65.9 U65.17(VPWR)
POE_VCC_MOS: POESLT1.1 Q63.1 Q63.2 Q63.3(S3) Q68.1 Q68.2 Q68.3(S3)
POWER_BTN_DEB_N: J1.L61 RB7.2 U6.8
PREXT1: R558.1 U67.AB2
PREXT2: R559.1 U67.E16
PSE_D1: F1.1 Q20.5 Q20.6 Q20.7 Q20.8 Q20.9 U65.3
PSE_D2: F2.1 Q21.5 Q21.6 Q21.7 Q21.8 Q21.9 U65.5
PSE_D3: F3.1 Q22.5 Q22.6 Q22.7 Q22.8 Q22.9 U65.10
PSE_D4: F4.1 Q23.5 Q23.6 Q23.7 Q23.8 Q23.9 U65.12
PSE_D5: F5.1 Q24.5 Q24.6 Q24.7 Q24.8 Q24.9 U65.31
PSE_D6: F6.1 Q25.5 Q25.6 Q25.7 Q25.8 Q25.9 U65.33
PSE_D7: F7.1 Q26.5 Q26.6 Q26.7 Q26.8 Q26.9 U65.38
PSE_D8: F8.1 Q27.5 Q27.6 Q27.7 Q27.8 Q27.9 U65.40
PSE_GATE1: Q20.4 U65.1
PSE_GATE2: Q21.4 U65.7
PSE_GATE3: Q22.4 U65.8
PSE_GATE4: Q23.4 U65.14
PSE_GATE5: Q24.4 U65.29
PSE_GATE6: Q25.4 U65.35
PSE_GATE7: Q26.4 U65.36
PSE_GATE8: Q27.4 U65.42
PSE_SEN1: Q20.1 Q20.2 Q20.3(S3) R496.2 U65.2
PSE_SEN2: Q21.1 Q21.2 Q21.3(S3) R497.2 U65.6
PSE_SEN3: Q22.1 Q22.2 Q22.3(S3) R498.2 U65.9
PSE_SEN4: Q23.1 Q23.2 Q23.3(S3) R499.2 U65.13
PSE_SEN5: Q24.1 Q24.2 Q24.3(S3) R500.2 U65.30
PSE_SEN6: Q25.1 Q25.2 Q25.3(S3) R501.2 U65.34
PSE_SEN7: Q26.1 Q26.2 Q26.3(S3) R502.2 U65.37
PSE_SEN8: Q27.1 Q27.2 Q27.3(S3) R503.2 U65.41
PSELF: R165.1 RA8.1 U20.6
PWM01_BKLIGHT_GMSL_INT3_GP68: J1.K57 RZ18.2
PWREN1#: R155.2 U20.18
PWREN2#: R156.2 U20.4
PWREN3#: R157.2 U20.53
PWREN4#: R158.2 U20.38
RI2#: TP35.1 U25.31
RTERM: R167.1 U20.51
RTS2#: TP36.1 U25.30
RX_PAVDD_A: C301.1 C302.1 FB29.1 U66.49 U66.52 U66.57
RXNE_UP: CA23.2 U20.36
RXPE_UP: CA24.2 U20.37
SAFE_3V3: J1.L53 RZ15.2
SBU1: D66.1 D66.10 RZ207.2 USB1.6
SBU2: D66.2 D66.9 RZ208.2 USB1.8
SDMMC1_CLK: J1.B6 RZU18.1
SDMMC1_CMD: J1.A5 RZU13.1
SDMMC1_D0: J1.E8 RZU14.1
SDMMC1_D1: J1.F8 RZU15.1
SDMMC1_D2: J1.A4 RZU10.1
SDMMC1_D3: J1.D6 RZU11.1
SNN_EFM8_P1_7: TP59.1 U6.7
SNN_EFM8SB10_P0_1: TP57.1 U6.1
SNN_EFM8SB10_P0_2: TP58.1 U6.20
SNN_EFM8SB10_P0_5: TP56.1 U6.17
SNN_GP92_CAN2: J1.F40 TP3.1
SNN_GP93_CAN2: J1.D40 TP4.1
SNN_GP94_CAN2: J1.B40 TP5.1
SNN_MID1: J1.H40 TP2.1
SOC_PWR_REQ: J1.J60 RZU8.1 U33.2
SPI1_CS0: J1.E55 RZ43.1
SPI1_MISO: J1.A56 RZ29.1
SPI1_MOSI: J1.D55 RZ34.1
SPI1_SCK: J1.J57 RZ44.1
SPKOUT: BUZZ1.1 R139.1
SRC_ON_D: Q32.G Q34.D R667.2
STANDBY_REQ_N_GP109: J1.L11 RZU6.2
SW2CLK: DB1.4 U13.52
SW2DIO: DB1.2 U13.53
SW2O: DB1.6 U13.50
SYS_RST_IN_N: J1.L60 J4.10 Q2.5 R144.2 RZ150.2 RZ188.1 TP30.1
SYS_RST_IN_N_CON: CA133.1 R681.2 RESET1.3 RZ149.1
SYS_RST_IN_N_KEY: C134.1 PSON2.1 PSON2.2 RZ149.2 RZ150.1 Z9.2
SYS_RST_IN_Q: Q2.2 Q2.3 RB8.2
SYSRST#_OOB: OOB1.8 RZ188.2
SYSTEM_OC_N: J1.A61 RZ20.2
SYSTEM_OC_N_BU: R240.1 RZ20.1 RZU9.2 Z18.2
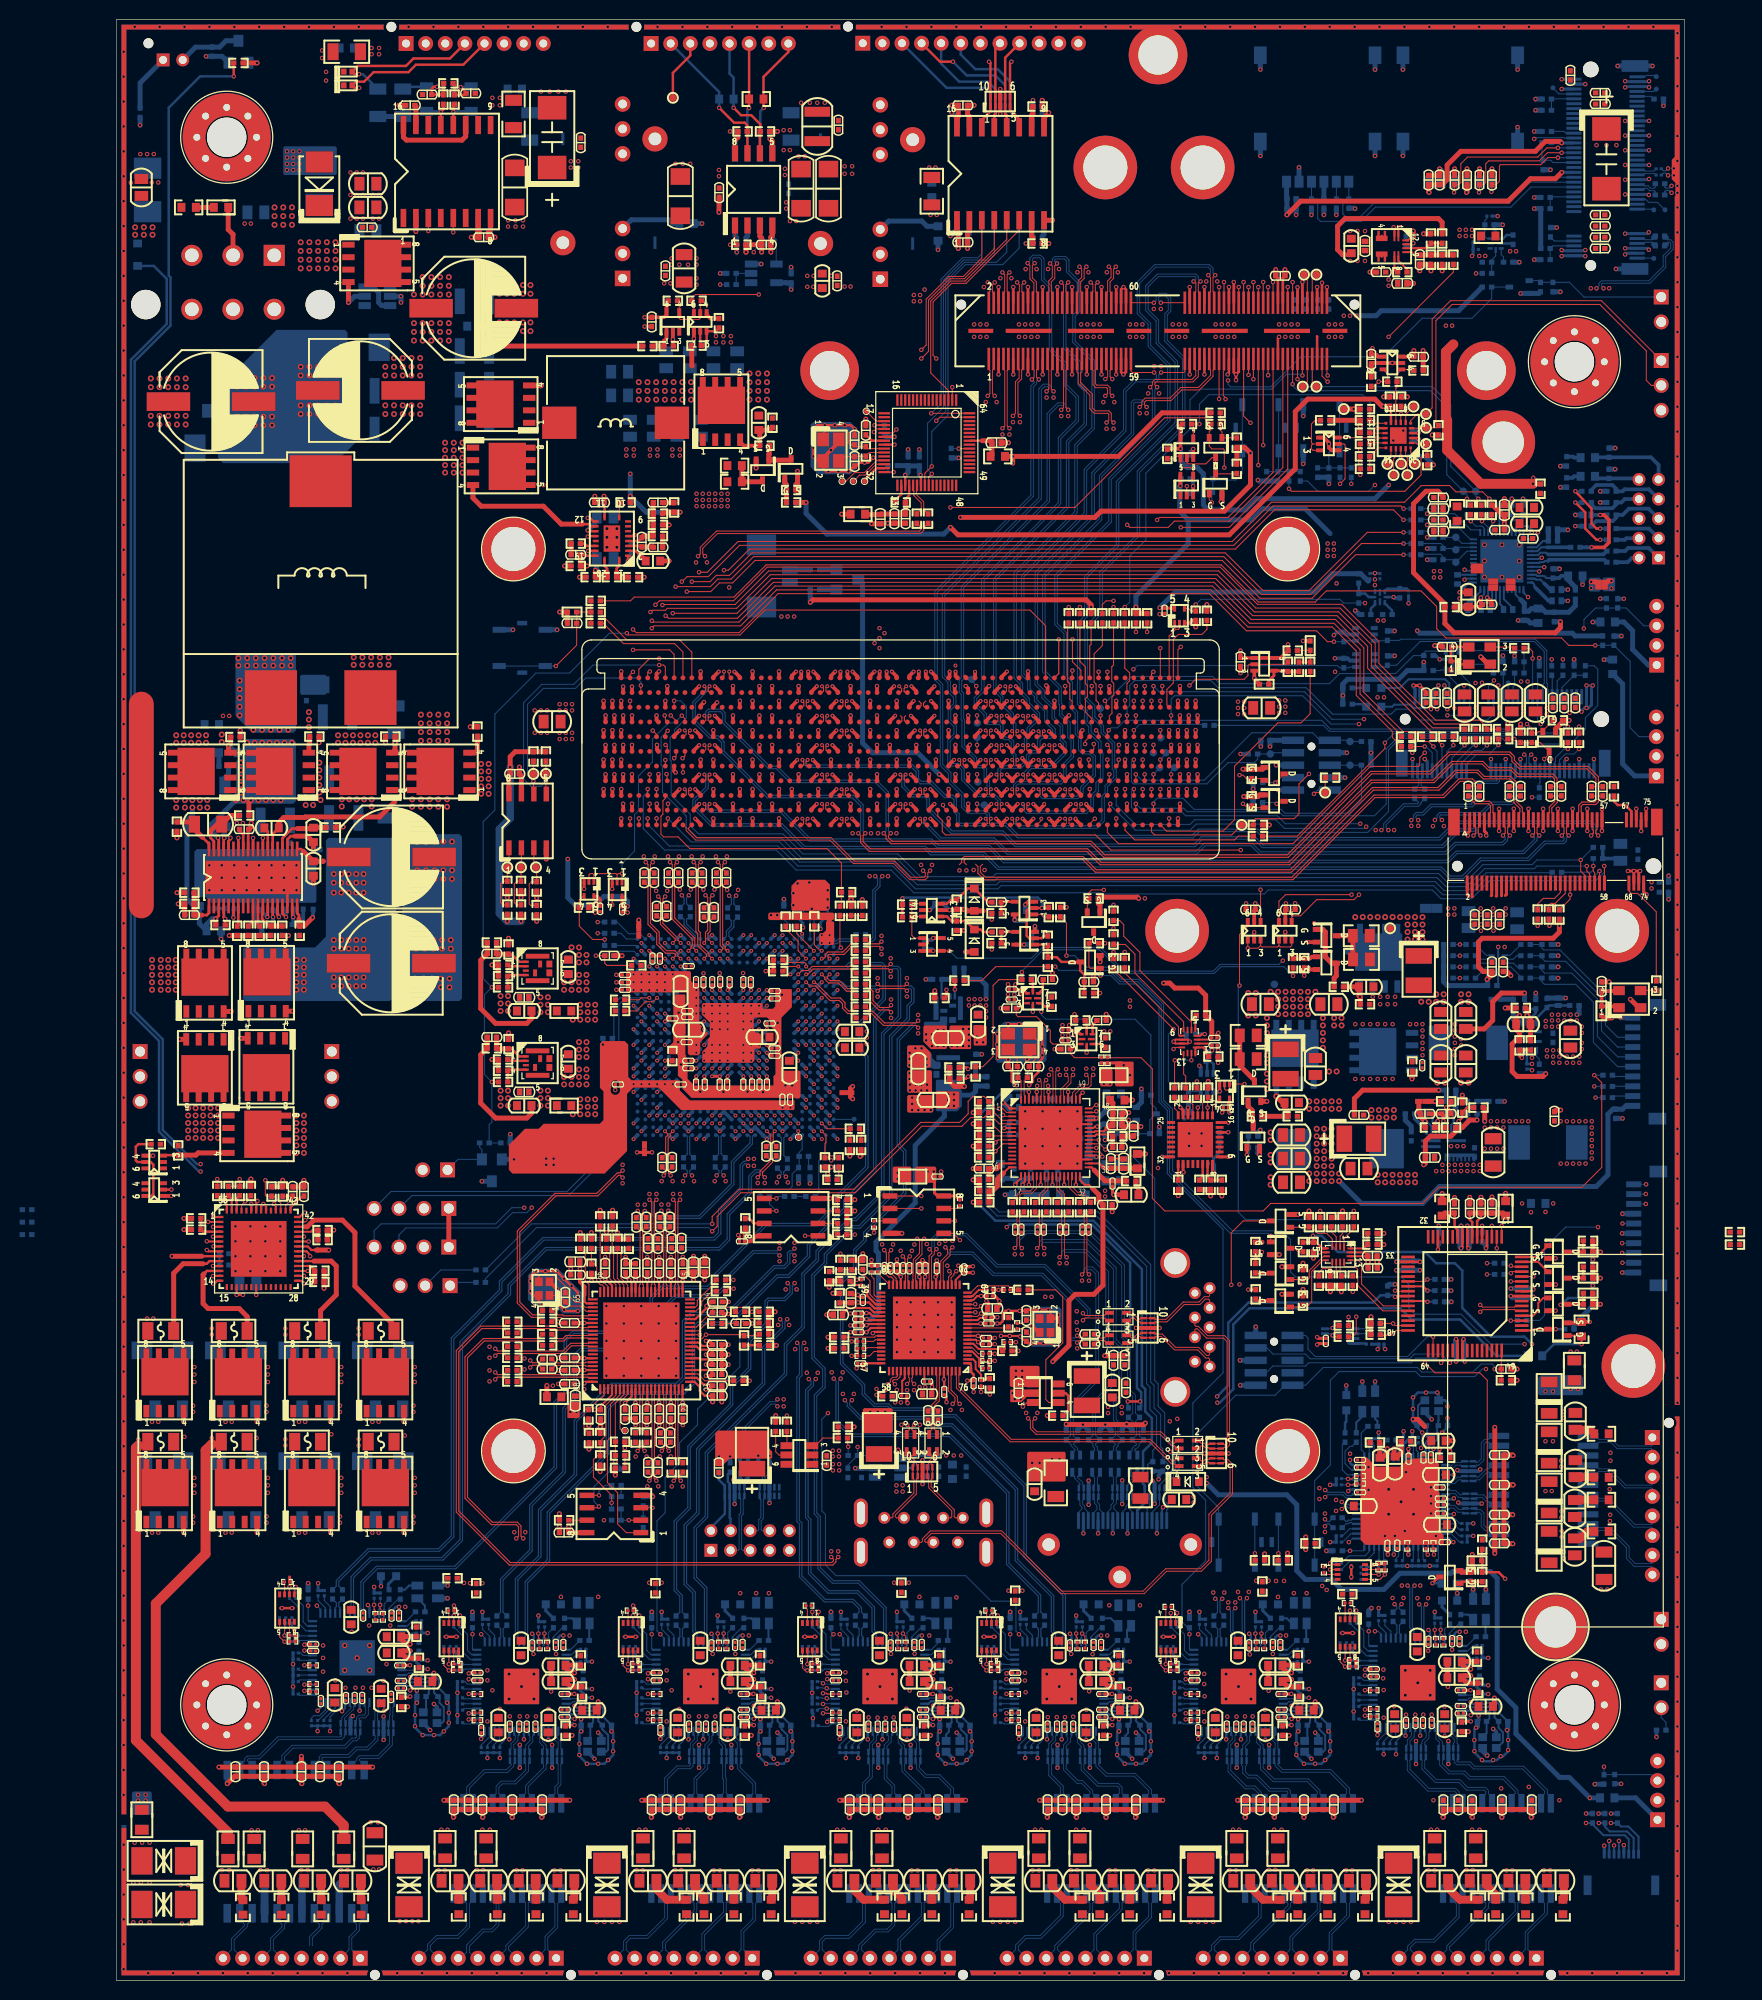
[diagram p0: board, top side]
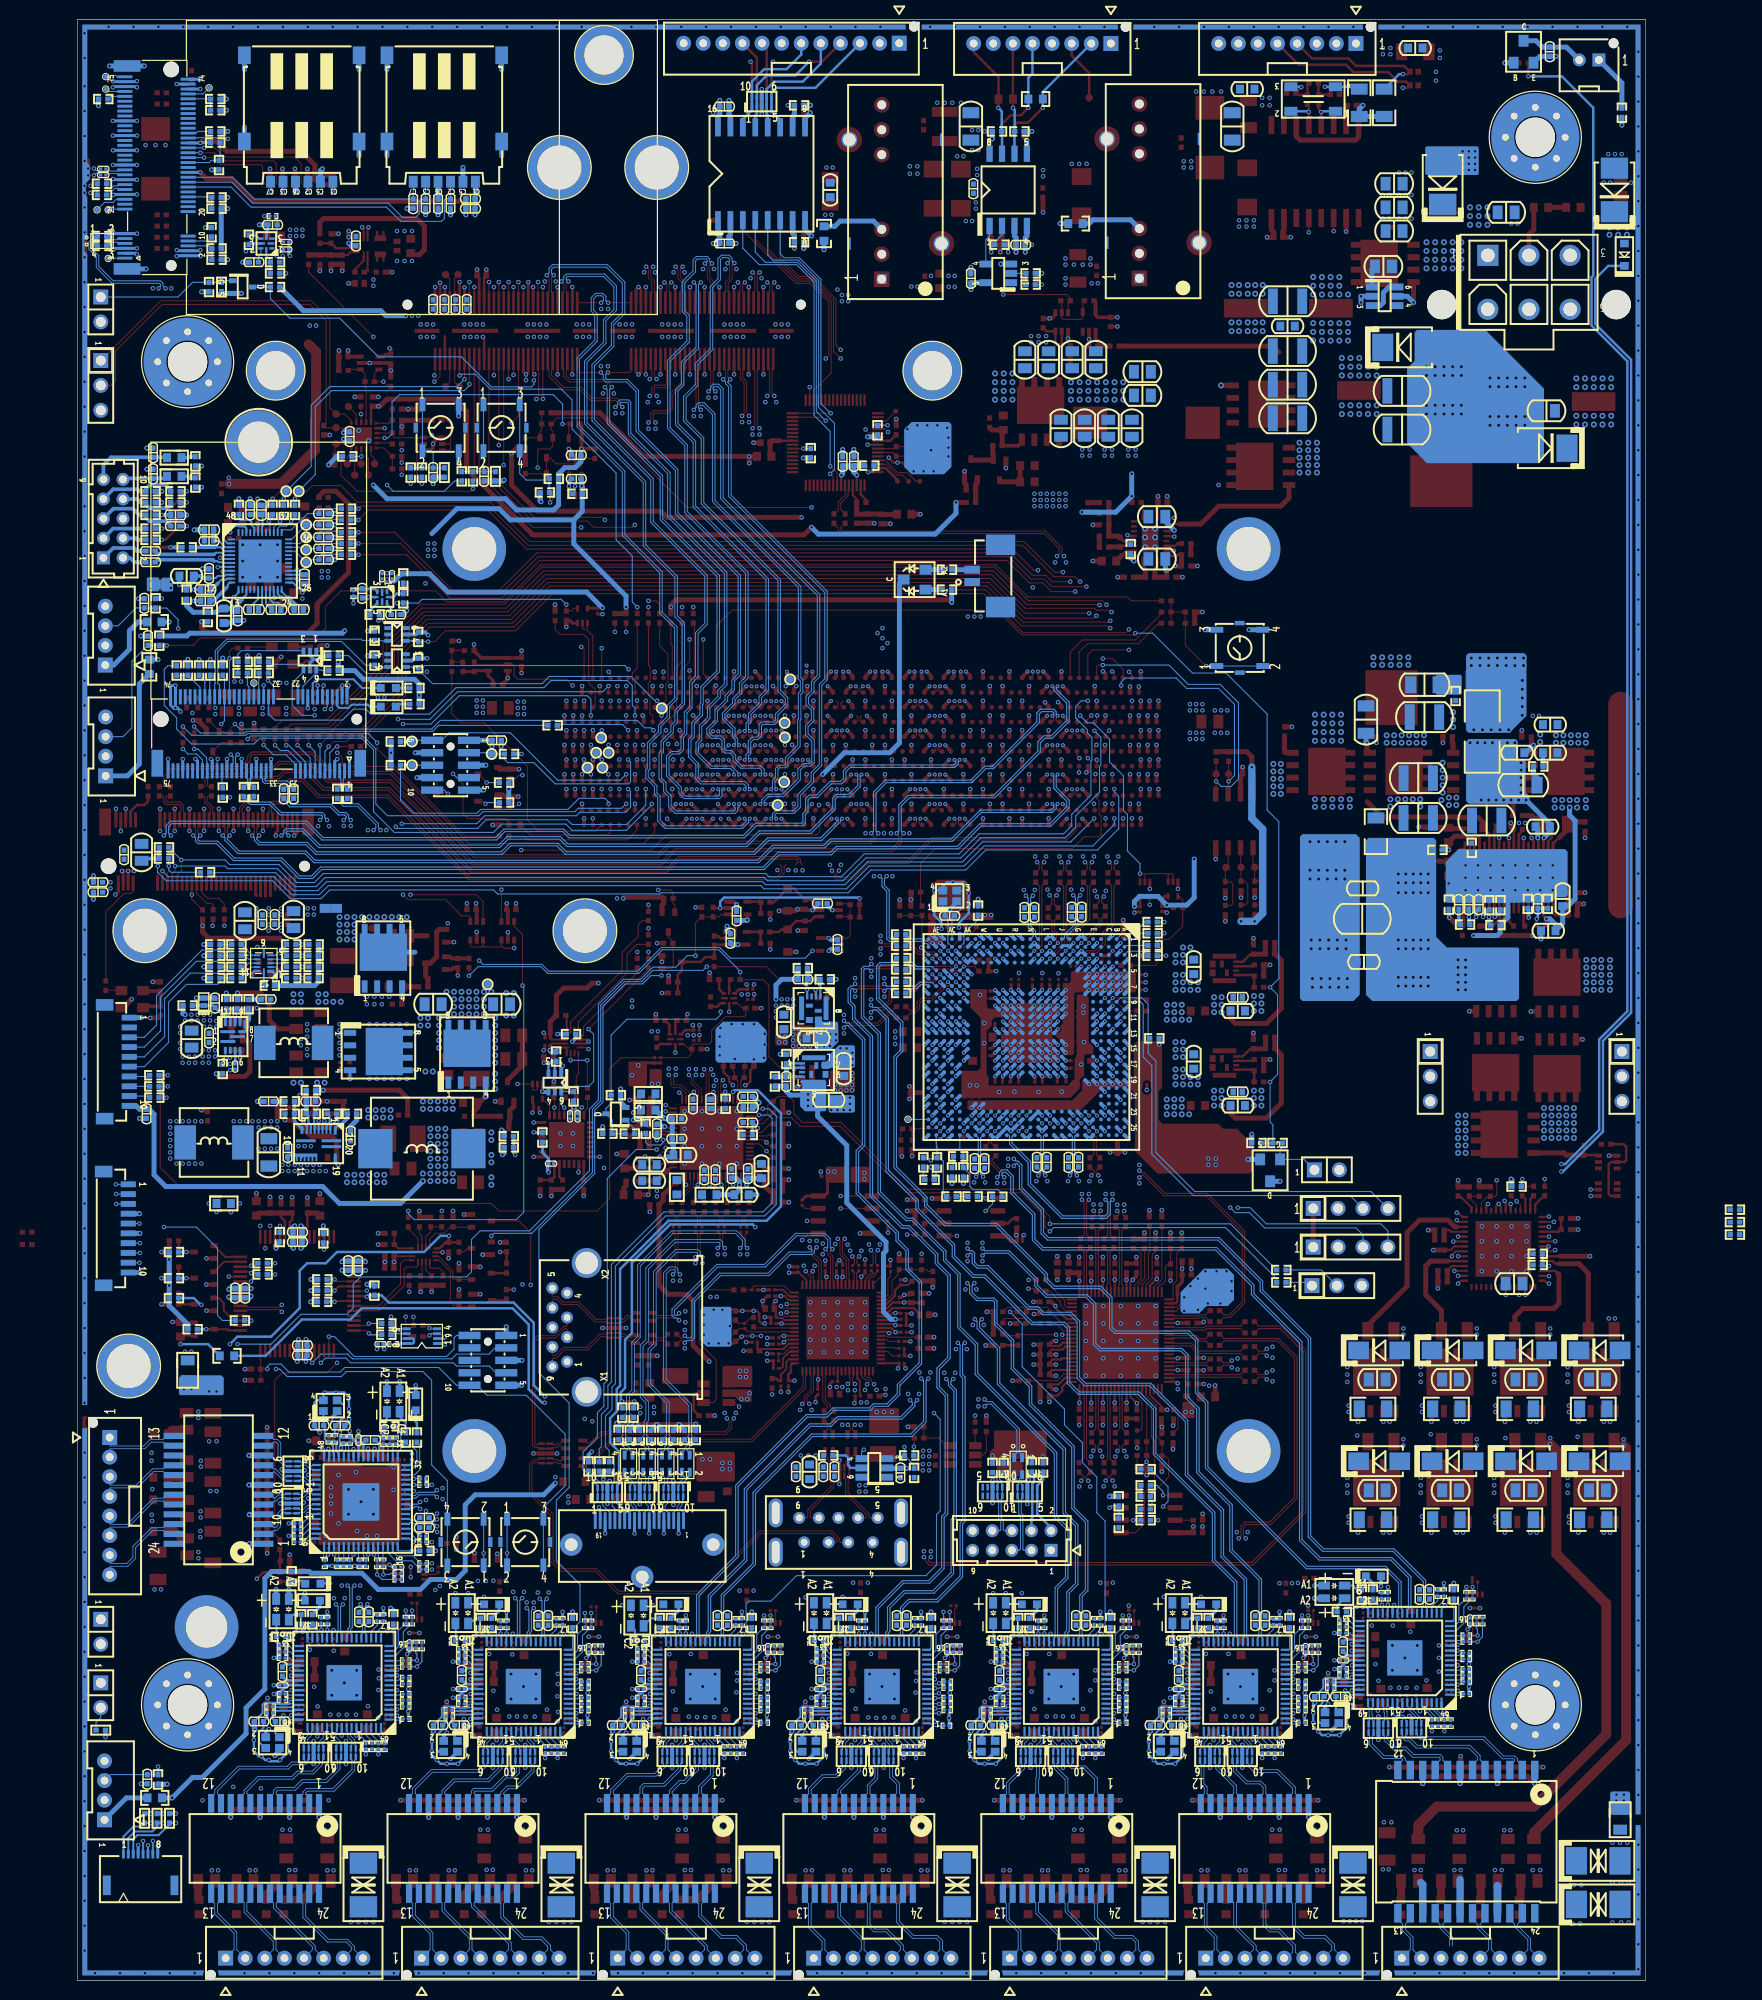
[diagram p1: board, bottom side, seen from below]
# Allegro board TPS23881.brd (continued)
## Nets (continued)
TCA6408A_ADDR: R90.2 R91.1 U14.16
TPM_CS#: Q51.6 R771.1 U18.20
TPM_IRQ#: Q57.D R1474.1 RB42.2 U18.18
TPM_PP: R768.2 R1488.2 U18.7
TPM_SPI_CS0: Q51.5 RZ43.2
TPM_SPI_MISO: RZ29.2 U86.6
TPM_SPI_MOSI: RZ34.2 U86.8
TPM_SPI_SCK: RZ44.2 U86.9
TX0N_A: CB23.1 L10.4 R507.1
TX0N_A-E: D56.2 D56.9 HDMI1.9 L10.3
TX0P_A: CB24.1 L10.1 R511.1
TX0P_A-E: D56.1 D56.10 HDMI1.7 L10.2
TX1N_A: CB25.1 L9.4 R506.1
TX1N_A-E: D55.5 D55.6(NC4) HDMI1.6 L9.3
TX1P_A: CB26.1 L9.1 R510.1
TX1P_A-E: D55.4 D55.7 HDMI1.4 L9.2
TX2N_A: CB27.1 L8.4 R508.1
TX2N_A-E: D55.2 D55.9 HDMI1.3 L8.3
TX2P_A: CB28.1 L8.1 R505.1
TX2P_A-E: D55.1 D55.10 HDMI1.1 L8.2
TX_AVDD_A: C303.1 C304.1 C305.1 C306.1 FB30.1 U66.22 U66.28
TX_CEC_A: D57.5 D57.6(NC4) HDMI1.13 U66.62
TX_HPD_A: D57.1 D57.10 HDMI1.19 R519.2 U66.39
TX_PVDD_A: C311.1 C312.1 FB33.1 U66.18
TX_RSEN_A: C296.1 R526.1 R527.1 R529.2 U66.6
TX_SCL_A: D57.4 D57.7 HDMI1.15 R530.2 U66.2
TX_SDA_A: D57.2 D57.9 HDMI1.16(TMDS-SDA) R531.2 U66.3
TXCN_A: CB21.1 L11.4 R514.1 R526.2
TXCN_A-E: D56.5 D56.6(NC4) HDMI1.12 L11.3
TXCP_A: CB22.1 L11.1 R513.1 R527.2
TXCP_A-E: D56.4 D56.7 HDMI1.10 L11.2
TXNE_UP: CA20.2 U20.33
TXPE_UP: CA21.2 U20.34
TYPE-C0_CC1-C: D11.5 D11.6(NC4) RZ209.2 USB1.2
TYPE-C0_CC2-C: D11.4 D11.7 RZ210.2 USB1.4
TYPEC0_DM-E: D11.2 D11.9 L7.2 USB1.3
TYPEC0_DP-E: D11.1 D11.10 L7.3 USB1.5
UART0_RX_OOB_3V3: OOB1.5 R6.1 RZ39.2
UART0_TX_OOB_3V3: OOB1.6 R4.1 RZ36.2
UART1_CTS: J1.H54 TP11.1
UART1_RTS: J1.L51 RZ148.1
UART1_RXD: J1.K54 RB3.2 U36.1
UART1_TXD: J1.K53 RZ145.1
UART2_CTS: J1.A57 RZ25.1
UART2_RTS: J1.G58 RZ171.1
UART2_RX_OOB_3V3: OOB1.3 R10.1 RZ47.2
UART2_RXD: J1.C56 R9.1 RZ38.1
UART2_RXD_3V3: RZ39.1 U85.9
UART2_TX_OOB_3V3: OOB1.4 R8.1 RZ41.2
UART2_TXD: J1.C58 R5.1 RZ35.1
UART2_TXD_3V3: RZ36.1 U85.10
UART3_RXD: J1.K60 R11.1 RZ46.1
UART3_TXD: J1.H62 R7.1 RZ40.1
UART5_CTS: J1.H57 WIFI1.34
UART5_RTS: J1.K58 WIFI1.36
UART5_RXD: J1.H58 WIFI1.22
UART5_TXD: J1.J58 WIFI1.32
UART1812_RX: J11.4 R589.1 U67.B9
UART1812_TX: J11.3 U67.A9
UART_RXD: J7.2 RZU47.2
UART_TXD: J7.1 RZU46.2
UFS0_REF_CLK: J1.A6 SSD2.56
UFS0_RST_N: J1.C6 SSD2.58
UIM1_CLK: C120.2 JSIM1.C3 NGFF1.32
UIM1_DATA: C118.2 JSIM1.C7 NGFF1.34
UIM1_DET: NGFF1.66 R225.2 R228.1
UIM1_PWR: C119.2 CA120.1 JSIM1.C1 NGFF1.36 R225.1
UIM1_RESET: C121.2 JSIM1.C2 NGFF1.30
UIM1_VPP: C117.2 JSIM1.C6(VPP)
UIM2_CLK: C125.2 JSIM2.C3 NGFF1.44
UIM2_DATA: C124.2 JSIM2.C7 NGFF1.42
UIM2_DET: NGFF1.40 R224.2 R227.1
UIM2_PWR: C128.2 CA4.1 JSIM2.C1 NGFF1.48 R224.1
UIM2_RESET: C126.2 JSIM2.C2 NGFF1.46
UIM2_VPP: C123.2 JSIM2.C6(VPP)
UPE_CLKN: RZ83.2 U70.72
UPE_CLKP: RZ80.2 U70.71
UPE_CLKREQN: R561.2 R562.1 RZU21.1 U67.AF3
UPE_RXN0: CM56.1 U70.47
UPE_RXN1: CM50.1 U70.56
UPE_RXP0: CM57.1 U70.46
UPE_RXP1: CM51.1 U70.55
UPE_TXN0: CM52.1 U70.50
UPE_TXN1: CM54.1 U70.53
UPE_TXP0: CM53.1 U70.49
UPE_TXP1: CM55.1 U70.52
UPHY0_RX2_N: CA20.1 J1.C35
UPHY0_RX2_P: CA21.1 J1.C34
UPHY0_RX3_N: J1.B32 RZ172.1
UPHY0_RX3_P: J1.B33 RZ173.1
UPHY0_RX4_N: J1.D32 SSD2.5
UPHY0_RX4_P: J1.D33 SSD2.7
UPHY0_RX5_N: J1.A35 SSD2.17
UPHY0_RX5_P: J1.A34 SSD2.19
UPHY0_SF_PCIE1_CLK_N: J1.D48 WIFI1.49
UPHY0_SF_PCIE1_CLK_P: J1.D49 WIFI1.47
UPHY0_TX2_N: CA23.1 J1.K33
UPHY0_TX2_P: CA24.1 J1.K32
UPHY0_TX3_N: CM66.1 J1.G34
UPHY0_TX3_P: CM67.1 J1.G35
UPHY0_TX4_N: CM25.1 J1.J34
UPHY0_TX4_N_M2M: CM25.2 SSD2.11
UPHY0_TX4_P: CM26.1 J1.J35
UPHY0_TX4_P_M2M: CM26.2 SSD2.13
UPHY0_TX5_N: CM27.1 J1.H33
UPHY0_TX5_N_M2M: CM27.2 SSD2.23
UPHY0_TX5_P: CM28.1 J1.H32
UPHY0_TX5_P_M2M: CM28.2 SSD2.25
UPHY0_TX6_N_M2M: CM29.2 SSD2.35
UPHY0_TX6_P_M2M: CM1.2 SSD2.37
UPHY0_TX7_N_M2M: CM30.2 SSD2.47
UPHY0_TX7_P_M2M: CM31.2 SSD2.49
UPHY1_RX0_N: CM41.2 J1.D25
UPHY1_RX0_P: CM40.2 J1.D24
UPHY1_RX1_N: CM68.2 J1.B24
UPHY1_RX1_P: CM69.2 J1.B25
UPHY1_RX2_N: CM43.2 J1.C26
UPHY1_RX2_P: CM42.2 J1.C27
UPHY1_RX3_N: CM70.2 J1.A27
UPHY1_RX3_P: CM71.2 J1.A26
UPHY1_TX0_N: CM33.2 J1.H25
UPHY1_TX0_P: CM32.2 J1.H24
UPHY1_TX1_N: CM35.2 J1.K24
UPHY1_TX1_P: CM34.2 J1.K25
UPHY1_TX2_N: CM37.2 J1.G26
UPHY1_TX2_P: CM36.2 J1.G27
UPHY1_TX3_N: CM39.2 J1.J27
UPHY1_TX3_P: CM38.2 J1.J26
UPHY_RX0_N: J1.A23 RZ143.1
UPHY_RX0_P: J1.A22 RZ142.1
UPHY_RX10_N: J1.B13 SSD2.29
UPHY_RX10_P: J1.B12 SSD2.31
UPHY_RX11_N: J1.D13 SSD2.41
UPHY_RX11_P: J1.D12 SSD2.43
UPHY_TX0_N: CA246.1 J1.J23
UPHY_TX0_P: CA247.1 J1.J22
UPHY_TX10_N: CM29.1 J1.K12
UPHY_TX10_P: CM1.1 J1.K13
UPHY_TX11_N: CM30.1 J1.H13
UPHY_TX11_P: CM31.1 J1.H12
USB2_0_N: J1.F13 L7.1
USB2_0_P: J1.F12 L7.4
USB2_1_N: FL1.1 J1.C10 RZ144.1
USB2_1_P: FL1.4 J1.C11 RZ146.1
USB2_1N_CON: CN1.2 D5.1 D5.10 L2.2
USB2_1P_CON: CN1.3 D5.2 D5.9 L2.3
USB2_2_N: J1.A11 U20.32
USB2_2_P: J1.A10 U20.31
USB2_2N_CON: CN2.2 D5.4 D5.7 L1.2
USB2_2P_CON: CN2.3 D5.5 D5.6(NC4) L1.3
USB2_3_N: J1.G10 RZ175.1
USB2_3_P: J1.G11 RZ176.1
USB2_DWN_DM1: L2.1 U20.23
USB2_DWN_DM2: L1.1 U20.76
USB2_DWN_DM3: U13.6 U20.61
USB2_DWN_DM4: RZ9.2 U20.64
USB2_DWN_DP1: L2.4 U20.22
USB2_DWN_DP2: L1.4 U20.75
USB2_DWN_DP3: U13.5 U20.60
USB2_DWN_DP4: RZ10.2 U20.63
USB3_DWN_RXN1: L4.1 U20.27
USB3_DWN_RXN2: L3.4 U20.73
USB3_DWN_RXP1: L4.4 U20.28
USB3_DWN_RXP2: L3.1 U20.74
USB3_DWN_TXN1: CA74.1 U20.24
USB3_DWN_TXN2: CA79.1 U20.70
USB3_DWN_TXP1: CA75.1 U20.25
USB3_DWN_TXP2: CA78.1 U20.71
USB3_RXN1_CON: CN1.5 D7.1 D7.10 L4.2
USB3_RXN2_CON: CN2.5 D8.1 D8.10 L3.3
USB3_RXP1_CON: CN1.6 D7.2 D7.9 L4.3
USB3_RXP2_CON: CN2.6 D8.2 D8.9 L3.2
USB3_TXN1_CON: CN1.8 D7.4 D7.7 L6.2
USB3_TXN2_CON: CN2.8 D8.4 D8.7 L5.3
USB3_TXP1_CON: CN1.9 D7.5 D7.6(NC4) L6.3
USB3_TXP2_CON: CN2.9 D8.5 D8.6(NC4) L5.2
USB31_RX_DN: NGFF1.29 RZ143.2
USB31_RX_DP: NGFF1.31 RZ142.2
USB31_TX_DN: CA246.2 NGFF1.35
USB31_TX_DP: CA247.2 NGFF1.37
USB_AGND: C69.2 C71.2 CA49.2 FB46.1 R173.1 U25.36
USB_EN: Q12.D RZ100.1 RZU35.1
USB_EN#: Q12.G RB47.1 U14.4
USB_EN_R: RB58.1 RZ100.2 U22.3 U23.3
USB_GND: C79.2 R178.2 UART1.2
USB_N0: FL1.2 NGFF1.9 RZ144.2
USB_OC0_N: RZ74.2 U22.4
USB_OC1_N: RZ95.2 RZ103.1 U23.4
USB_P0: FL1.3 NGFF1.7 RZ146.2
USBHUB_PLTRST_N: RZ76.2 U89.4
VP10_HUB: C61.1 CA34.1 CA35.1 CA36.1 CA37.1 CA38.1 CA39.1 CA40.1 CA41.1 U20.8 U20.26 U20.29 U20.35 U20.48 U20.57 U20.67 U20.72
VP10_MEM_A: C62.1 U20.44
WDISABLE#1: NGFF1.8(W_DISABLE#1 (O)(0/3.3V)) R213.1
WDISABLE#2: NGFF1.26 R215.1 R216.1
WLAN_EN: R204.1 RZ167.2 U30.8
XOSCI: C72.1 R176.1 U25.27 Y1.3
XOSCO: C73.1 R176.2 U25.26(XTAL_OUT) Y1.1
N16109: J1.J51 RZU7.2
N19928: CA61.1 Q3.D R40.2 RZ32.1 RZU24.1 U9.1
N16629600: R305.2 U43.12
N16629602: R306.2 U43.13
N16629604: R307.2 U43.14
N16629606: R308.2 U43.15
N16629666: RA104.2 U43.8
N16629668: RA40.2 U43.3
N16629670: RA116.2 U43.6
N16629672: RA128.2 U43.5
N16629674: RA34.2 U43.7
N16629676: RA98.2 U43.9
N16629678: RA46.2 U43.2
N16629694: RA156.1 U43.63
N16629698: RA154.1 U43.61
N16629702: RA155.1 U43.62
N16629706: RA153.1 U43.60
N16629714: R301.1 U43.18
N16629874: RA20.1 U44.3(WP#)
N16629908: R303.1 R304.1 U43.29
N16629916: RA115.2 U43.43
N16629918: RA127.2 U43.44
N16629942: C182.1 R309.1 RB15.2 X3.3
N16629964: R302.1 U43.19
N16629966: RA25.1 U44.7
N16629970: R300.1 U43.4
N16633178: R329.2 U45.12
N16633180: R330.2 U45.13
N16633182: R331.2 U45.14
N16633184: R332.2 U45.15
N16633272: RA152.1 U45.63
N16633276: RA150.1 U45.61
N16633280: RA151.1 U45.62
N16633284: RA149.1 U45.60
N16633292: R325.1 U45.18
N16633452: RA21.1 U46.3(WP#)
N16633486: R327.1 R328.1 U45.29
N16633520: C191.1 R334.1 RB16.2 X4.3
N16633542: R326.1 U45.19
N16633544: RA26.1 U46.7
N16633548: R324.1 U45.4
N16636756: R353.2 U47.12
N16636758: R354.2 U47.13
N16636760: R355.2 U47.14
N16636762: R357.2 U47.15
N16636850: RA148.1 U47.63
N16636854: RA146.1 U47.61
N16636858: RA147.1 U47.62
N16636862: RA145.1 U47.60
N16636870: R349.1 U47.18
N16637030: RA18.1 U48.3(WP#)
N16637064: R351.1 R352.1 U47.29
N16637098: C200.1 R358.1 RB17.2 X5.3
N16637120: R350.1 U47.19
N16637122: RA27.1 U48.7
N16637126: R348.1 U47.4
N16640334: R377.2 U49.12
N16640336: R378.2 U49.13
N16640338: R379.2 U49.14
N16640340: R380.2 U49.15
N16640428: RA144.1 U49.63
N16640432: RA142.1 U49.61
N16640436: RA143.1 U49.62
N16640440: RA141.1 U49.60
N16640448: R373.1 U49.18
N16640608: RA22.1 U50.3(WP#)
N16640642: R375.1 R376.1 U49.29
N16640676: C209.1 R382.1 RB18.2 X6.3
N16640698: R374.1 U49.19
N16640700: RA28.1 U50.7
N16640704: R372.1 U49.4
N16643912: R401.2 U51.12
N16643914: R402.2 U51.13
N16643916: R403.2 U51.14
N16643918: R404.2 U51.15
N16644006: RA140.1 U51.63
N16644010: RA138.1 U51.61
N16644014: RA139.1 U51.62
N16644018: RA137.1 U51.60
N16644026: R397.1 U51.18
N16644186: RA19.1 U52.3(WP#)
N16644220: R398.1 R400.1 U51.29
N16644254: C218.1 R406.1 RB19.2 X7.3
N16644276: R399.1 U51.19
N16644278: RA29.1 U52.7
N16644282: R396.1 U51.4
N16647490: R425.2 U53.12
N16647492: R426.2 U53.13
N16647494: R427.2 U53.14
N16647496: R428.2 U53.15
N16647584: RA136.1 U53.63
N16647588: RA134.1 U53.61
N16647592: RA135.1 U53.62
N16647596: RA133.1 U53.60
N16647604: R421.1 U53.18
N16647764: RA17.1 U54.3(WP#)
N16647798: R423.1 R424.1 U53.29
N16647832: C227.1 R430.1 RB20.2 X8.3
N16647854: R422.1 U53.19
N16647856: RA24.1 U54.7
N16647860: R420.1 U53.4
N16651068: R449.2 U55.12
N16651070: R450.2 U55.13
N16651072: R451.2 U55.14
N16651074: R452.2 U55.15
N16651162: RA61.1 U55.63
N16651166: RA59.1 U55.61
N16651170: RA60.1 U55.62
N16651174: RA58.1 U55.60
N16651182: R445.1 U55.18
N16651342: RA15.1 U56.3(WP#)
N16651376: R446.1 R448.1 U55.29
N16651410: C236.1 R453.1 RB21.2 X9.3
N16651432: R447.1 U55.19
N16651434: RA14.1 U56.7
N16651438: R444.1 U55.4
N16705548: CA53.2 PL4.1 Q43.1 Q43.2 Q43.3(S3) Q44.5 Q44.6 Q44.7 Q44.8 Q44.9 R727.2 U92.19
N16706602: Q44.4 U92.13
N16715221: C472.1 C917.2 C919.1 Q45.1 Q45.2 Q45.3(S3) Q47.5 Q47.6 Q47.7 Q47.8 Q47.9 R729.1 R737.1 U83.36
N16715269: L12.1 R729.2 R738.1
N16715333: R735.1 U83.34
N16715396: C467.2 C473.1 C474.2 L12.2 Q46.1 Q46.2 Q46.3(S3) Q48.5 Q48.6 Q48.7 Q48.8 Q48.9 U83.25
N16716334: C463.1 C464.1 C465.1 Q46.5 Q46.6 Q46.7 Q46.8 Q46.9 R730.1 RZ24.1
N16716474: C472.2 U83.35
N16716845: C470.1 R738.2 U83.38
N16716849: C470.2 R737.2 U83.37
N16717006: C919.2 Q45.4 R735.2
N16717017: C467.1 Q46.4 R739.2
N16717021: R739.1 U83.27
N16717190: Q48.4 R749.1
N16717194: R749.2 U83.29
N16717547: Q47.4 R744.1
N16717551: R744.2 U83.32
N16717863: C473.2 U83.26
N16718141: C474.1 R746.2
N16719242: C918.2 RZ24.2 U83.23
N16719249: C918.1 RZ26.2 U83.22
N16719556: R731.1 R733.2 U83.19
N16830344: C419.2 Q40.4 RZ49.1 RZ118.2
N16830441: Q41.G Q42.D RZ49.2
N16830443: Q41.D R703.2 R704.2
N16830501: Q42.G RZ45.2 RZ121.2
N16831259: C424.2 R705.2 R711.1 U78.1
N16831562: R718.2 R719.1 U92.1
N16831739: C436.1 R719.2 R720.2 U92.20(VIN)
N16832049: R723.2 U92.2
N16832178: C444.1 U92.3
N16832533: C441.1 C446.1 U92.4
N16832601: C441.2 R725.2
N16833149: C440.1 R721.1
N16833152: C440.2 C446.2 R722.1 R725.1 R726.2 U92.5
N16834080: R724.2 U92.17
N16834083: CA53.1 R724.1
N16834553: RA47.2 U45.2
N16834556: RA41.2 U45.3
N16834559: RA114.2 U45.6
N16834562: RA126.2 U45.5
N16834578: RA35.2 U45.7
N16834580: RA97.2 U45.9
N16834582: RA103.2 U45.8
N16834584: RA113.2 U45.43
N16834593: RA125.2 U45.44
N16835211: C457.2 R727.1 U92.11
N16835305: C458.1 U92.14
N16836271: Q43.4 U92.18
N16840068: RA49.2 U49.2
N16840070: RA43.2 U49.3
N16840072: RA110.2 U49.6
N16840074: RA122.2 U49.5
N16840076: RA37.2 U49.7
N16840078: RA95.2 U49.9
N16840080: RA101.2 U49.8
N16840082: RA109.2 U49.43
N16840084: RA121.2 U49.44
N16841727: RA50.2 U51.2
N16841729: RA44.2 U51.3
N16841731: RA108.2 U51.6
N16841733: RA120.2 U51.5
N16841735: RA38.2 U51.7
N16841737: RA94.2 U51.9
N16841739: RA100.2 U51.8
N16841741: RA107.2 U51.43
N16841743: RA119.2 U51.44
N16843394: RA45.2 U53.2
N16843396: RA39.2 U53.3
N16843398: RA106.2 U53.6
N16843400: RA118.2 U53.5
N16843402: RA32.2 U53.7
N16843404: RA93.2 U53.9
N16843406: RA99.2 U53.8
N16843408: RA105.2 U53.43
N16843410: RA117.2 U53.44
N16845078: RA13.2 U55.2
N16845083: RA12.2 U55.3
N16845085: RA63.2 U55.6
N16845087: RA62.2 U55.5
N16845090: RA11.2 U55.7
N16845094: RA65.2 U55.9
N16845096: RA64.2 U55.8
N16845099: RA54.2 U55.43
N16845103: RA53.2 U55.44
N16849261: R741.2 U83.11
N16849480: RB29.1 U83.7
N16849547: RZ31.2 U83.10
N16849713: R753.2 U83.15
N16849718: R752.2 U83.14
N16849723: R751.2 U83.13
N16849728: C476.2 R747.1
N16940595: C258.1 CA105.1 CA106.1 CA107.1 CA108.1 U61.1 U61.4 U61.7 U61.10
N16940606: C259.1 R476.2
N16940607: C260.1 R477.2
N16940608: C261.1 R478.2
N16940609: C262.1 R479.2
N16940656: C263.1 CA109.1 CA110.1 CA111.1 CA112.1 U62.1 U62.4 U62.7 U62.10
N16940667: C264.1 R480.2
N16940668: C265.1 R481.2
N16940669: C266.1 R482.2
N16940670: C267.1 R483.2
N16942353: C273.1 CA81.1 CA85.1 CA86.1 CA87.1 U64.1 U64.4 U64.7 U64.10
N16942364: C274.1 R488.2
N16942365: C275.1 R489.2
N16942366: C276.1 R490.2
N16942367: C277.1 R491.2
N16942442: C269.1 R484.2
N16942443: C270.1 R485.2
N16942444: C271.1 R486.2
N16942445: C272.1 R487.2
N17060195: RB62.1 RZ148.2 U37.2
N17060201: U37.4(Y) U38.1
N17062477: RZ119.1 SW2.1 SW2.2
N17062487: RZ112.1 SW1.1 SW1.2
N17062540: RZ199.1 U13.21
N17062551: C25.1 R84.1 U13.26
N17068458: U40.11 U40.16(VISOOUT)
N17071169: FL2.1 RZU1.1 U40.13
N17071172: FL2.2 RZU2.1 U40.12
N17071866: C163.1 R264.1 R267.2
N17107581: D1.A1(ANODE) R22.2
N17475821: C239.1 CA89.1 CA90.1 CA91.1 CA92.1 U57.1 U57.4 U57.7 U57.10
N17477312: C243.1 CA93.1 CA94.1 CA95.1 CA96.1 U58.1 U58.4 U58.7 U58.10
N17477531: C245.2 U58.18
N17477559: C244.2 U58.15
N17486236: C248.1 CA97.1 CA98.1 CA99.1 CA100.1 U59.1 U59.4 U59.7 U59.10
N17486352: C250.2 U59.18
N17486475: C249.2 U59.15
N17486917: C253.1 CA101.1 CA102.1 CA103.1 CA104.1 U60.1 U60.4 U60.7 U60.10
N17487128: C255.2 U60.18
N17487156: C254.2 U60.15
N17488314: C260.2 U61.18
N17488336: C259.2 U61.15
N17488976: C265.2 U62.18
N17489028: C264.2 U62.15
N17489888: C269.2 U63.15
N17489893: C270.2 U63.18
N17490600: C274.2 TH4.1 U64.15
N17490605: C275.2 TH3.1 U64.18
N17490610: C276.2 TH2.1 U64.21
N17490615: C277.2 TH1.1 U64.24
N17518837: RB59.2 RZU35.2 U28.3
N17518839: R181.2 U28.5
N17518846: RZ103.2 U28.4
N17524230: D54.C(CATHODE) F9.1
N17525472: R177.1 U27.3
N17533418: RB2.2 U24.7
N17533420: RB1.2 U24.10
N17533862: RB61.2 U26.7
N17533864: RB60.2 U26.10
N17921312: C293.1 R525.1 U66.63 Y2.1
N17921343: C295.1 R525.2 U66.64 Y2.3(XOUT)
N17924096: C297.2 R534.1 U66.15
N17924979: C289.1 R509.2 U66.41
N17925260: C288.1 C289.2 R509.1
N17925590: CB20.2 R512.1 U66.33
N17925618: C290.1 R512.2
N17945769: RZ145.2 U38.2
N17954676: C268.1 CA113.1 CA114.1 CA115.1 CA116.1 U63.1 U63.4 U63.7 U63.10
N17962248: RZ63.1 U65.55
N17962251: RZ64.1 U65.54
N17978352: CM46.1 U67.U25
N17978356: CM47.1 U67.V25
N17978406: CM78.1 U67.W26
N17978410: CM77.1 U67.Y26
N17979269: CM73.1 U67.M26
N17979281: CM74.1 U67.L26
N17979323: CM75.1 U67.H26
N17979335: CM76.1 U67.G26
N17979425: CM49.1 U67.F25
N17979437: CM48.1 U67.E25
N17981424: RZ183.1 U67.AE5
N17981427: RZ184.1 U67.AF5
N17981727: RZ52.1 U67.AD6
N17981744: RZ50.1 U67.AE6
N17982049: RZ185.1 U67.AE7
N17982065: RZ186.1 U67.AF7
N17982119: RZ55.1 U67.AB7
N17982135: RZ54.1 U67.AC7
N17983399: CM33.1 U67.G4
N17983402: CM32.1 U67.F4
N17983405: CM41.1 U67.G2
N17983408: CM40.1 U67.F2
N17983588: CM69.1 U67.H1
N17983600: CM68.1 U67.J1
N17983612: CM34.1 U67.H3
N17983616: CM35.1 U67.J3
N17983696: CM42.1 U67.K2
N17983708: CM43.1 U67.L2
N17983720: CM36.1 U67.K4
N17983724: CM37.1 U67.L4
N17983804: CM71.1 U67.M1
N17983816: CM70.1 U67.N1
N17983828: CM38.1 U67.M3
N17983832: CM39.1 U67.N3
N17985522: CM81.1 U41.21
N17985526: CM82.1 U41.20
N17985638: CM93.1 U43.21
N17985642: CM94.1 U43.20
N17985774: CM91.1 U45.21
N17985778: CM92.1 U45.20
N17985910: CM89.1 U47.21
N17985914: CM90.1 U47.20
N17986046: CM87.1 U49.21
N17986050: CM88.1 U49.20
N17986184: CM85.1 U51.21
N17986188: CM86.1 U51.20
N17986320: CM83.1 U53.21
N17986324: CM84.1 U53.20
N17986454: CM79.1 U55.21
N17986458: CM80.1 U55.20
N17989951: C385.2 R655.1 R659.2 U73.1
N17989959: RB33.2 RZU25.2 U73.4
N17990621: RB41.2 RZU27.2 U72.4
N17990625: C380.2 R651.1 R654.2 U72.1
N18023847: Q11.D RZ78.1
N18024364: Q14.D RZ72.1
N18025778: R714.1 U80.5
N18025836: RZ56.2 U80.8
N18025865: C434.1 U80.7
N18053287: R226.1 U32.5
N18053364: C130.1 U32.7
N18054826: C427.2 R706.1 R713.2 U79.1
N18054834: RB35.2 RZU26.2 U79.4
N18055461: R246.1 R247.2 U34.10
N18068175: JPPCIE1.1 Q29.G RZ194.1
N18076130: LANLINK1.C1 R288.1
N18076153: LANLINK1.C2(CATHODE2_2) R289.1
N18076291: LANACT1.C(2) R286.1
N18076865: LANACT2.C(2) R310.1
N18076892: LANLINK2.C1 R312.1
N18076913: LANLINK2.C2(CATHODE2_2) R313.1
N18077498: LANACT3.C(2) R333.1
N18077525: LANLINK3.C1 R336.1
N18077546: LANLINK3.C2(CATHODE2_2) R337.1
N18078897: LANACT4.C(2) R356.1
N18078924: LANLINK4.C1 R360.1
N18078945: LANLINK4.C2(CATHODE2_2) R361.1
N18079699: LANACT5.C(2) R381.1
N18079726: LANLINK5.C1 R384.1
N18079747: LANLINK5.C2(CATHODE2_2) R385.1
N18080540: LANACT6.C(2) R405.1
N18080567: LANLINK6.C1 R408.1
N18080588: LANLINK6.C2(CATHODE2_2) R409.1
N18081372: LANACT7.C(2) R429.1
N18081399: LANLINK7.C1 R432.1
N18081420: LANLINK7.C2(CATHODE2_2) R433.1
N18082215: LANACT8.C(2) R454.1
N18082242: LANLINK8.C1 R456.1
N18082263: LANLINK8.C2(CATHODE2_2) R457.1
N18092346: J1.K40 TP1.1
N18120066: R260.1 U39.3
N18165594: R715.1 U81.5
N18165656: RZ57.2 U81.8
N18165690: C432.1 U81.7
N18173925: RZ204.2 U13.3
N18173928: RZ201.2 U13.14
N18186882: RZU22.1 SSD2.40
N18186907: RZU23.1 SSD2.42
N18187137: RZ23.2 SSD2.69
N18187139: R761.2 SSD2.68(SUSCLK)
N18187141: R761.1 U84.3
N18187143: CA65.1 FB39.1 U84.1 U84.4(VDD)
N18192110: R763.2 U85.12
N18192155: RZ35.2 U85.2
N18192178: RZ38.2 U85.3
N18192205: RZ40.2 U85.4
N18192224: RZ46.2 U85.5
N18194663: RZ61.2 U18.1
N18194685: RZ192.2 U18.14
N18194768: R1484.2 U18.19
N18194804: R1485.2 U18.24
N18194817: R1486.2 U18.21
N18194942: R769.2 U18.6
N18195475: RB38.2 U86.5
N18195479: RB39.2 U86.1 U86.16
N18195489: RB37.2 U86.4
N18196140: Q51.2 Q51.3 RB36.1
N18233097: Q15.B RZ1.2
N18237049: RZ176.2 WIFI1.3
N18237080: RZ175.2 WIFI1.5
N18237082: LED1.C WIFI1.6
N18237084: LED1.A R188.2
N18237134: RZU18.2 WIFI1.9
N18237158: RZU13.2 WIFI1.11
N18237182: RZU14.2 WIFI1.13
N18237217: RZU15.2 WIFI1.15
N18237219: LED2.C WIFI1.16
N18237221: LED2.A R189.2
N18237240: RZU10.2 WIFI1.17
N18237264: RZU11.2 WIFI1.19
N18237285: RZU12.2 WIFI1.21
N18237289: RZU17.2 WIFI1.23
N18237399: CM67.2 WIFI1.35
N18237422: CM66.2 WIFI1.37
N18237451: RZU42.1 WIFI1.38
N18237476: RZ173.2 WIFI1.41
N18237478: TP39.1 WIFI1.40
N18237490: RZ172.2 WIFI1.43
N18237492: RZ170.1 WIFI1.42
N18237555: RZ174.2 WIFI1.53
N18237567: Q17.D R199.1 RZU16.2 WIFI1.55
N18237624: RZ21.2 WIFI1.59
N18237626: RZU41.1 WIFI1.58
N18237645: RZ22.2 WIFI1.61
N18237647: RZU40.1 WIFI1.60
N18237667: R195.1 RZ169.1 WIFI1.62
N18238169: R194.1 U29.3
N18238171: CA55.1 FB5.1 U29.1 U29.4(VDD)
N18239373: R202.1 U30.5
N18239450: C92.1 U30.7
N18353073: PLED1.A R230.2
N18353085: PLED1.C(2) Q19.D
N18355368: PWRBTN1.1 R677.2
N18355613: R680.2 RESET1.1
N18355836: R682.2 RECOVERY1.1
N18552806: AUDIO1.4 RZ162.1
N18554011: AUDIO1.3 RZ160.2
N18656044: R1334.2 U87.7(VREF2) U87.8
N18656142: RZ91.2 U87.3
N18656144: RZ206.1 U87.6
N18656178: RZ86.2 U87.4
N18656180: RZ205.1 U87.5
N18665598: POESLT1.2 Q63.4 Q68.4
N18665787: POESLT2.2 Q64.4 Q67.4
N18665860: Q66.5 Q69.6 R1507.1
N18790442: RZ67.2 U14.1
N18790882: RB53.1 U14.10
N18790917: RB48.1 RZU30.1 U14.3
N18790923: RB49.1 U14.2
N18791105: RB52.1 U14.9
N18797950: C391.1 C392.1 D61.C DC_IN1.1(VCC1) Q30.1 Q30.2 Q30.3(S3) U74.3 U74.6
N18798062: Q30.4 U74.5
N18798086: D61.A D62.A
N18798173: C392.2 U74.1(VCAP)
N18798292: C394.2 Q31.4 R664.2 R667.1
N18798370: Q32.D R670.1 R671.1
N18798998: R663.2 R665.1 U75.1
N18799362: FB38.2 R662.1
N18799364: C390.1 D58.A D59.C R662.2
N18880064: Q13.D RZ73.1
N18880909: Q19.G R1509.1 RZ120.2
N18881934: RZ685.1 U16.26
N18881943: RZ686.1 U16.28
N18882012: AUDIO1.7 RZ153.2 RZU37.2
N18882124: AUDIO1.8 RZ154.2 RZU39.1
N18931604: R173.2 U25.34
N19048317: C898.2 U16.5
N19048952: C899.2 U16.7
N19126579: C917.1 R1510.2
N20328471: R644.2 RZ114.2 SPI2.2
N20328520: RZ111.1 SPI2.6
N20328523: RZ110.1 SPI2.5
N20328554: R645.2 SPI2.7
N20493475: R639.1 RZ108.1
N20493478: R640.1 RZ89.1
N25237920: C173.1 R285.1 RB14.2 X2.3
N53913115: R607.2 RZ68.2 SPI1.2
N53913461: RZ65.1 SPI1.6
N53913464: RZ198.1 SPI1.5
N53913963: R608.2 SPI1.7
N54184803: RZ33.1 U67.AD4
N54186028: RZ37.1 U67.AE4
N54369784: RZ179.1 U67.AF1
N54371660: RZ181.1 U67.AF2
N54465881: RZ42.1 U67.AA6
N54465893: RZ48.1 U67.AB6
N59689924: C254.1 R472.2
N59689926: C255.1 R473.2
N59689928: C256.1 R474.2
N59689930: C257.1 R475.2
N59691945: C249.1 R468.2
N59691947: C250.1 R469.2
N59691949: C251.1 R470.2
N59691951: C252.1 R471.2
N59697516: C238.1 R460.2
N59697518: C240.1 R461.2
N59697520: C241.1 R462.2
N59697522: C242.1 R463.2
N59698211: C244.1 R464.2
N59698213: C245.1 R465.2
N59698215: C246.1 R466.2
N59698217: C247.1 R467.2
N60625316: CA75.2 L6.4
N60625341: CA74.2 L6.1
N63435656: R170.2 U22.5
N63437012: R171.2 U23.5
N63438290: CA79.2 L5.4
N63438309: CA78.2 L5.1
N66390376: NGFF1.1 TP40.1
N66390584: NGFF1.21 TP41.1
N66390616: NGFF1.25 TP42.1
N66390835: NGFF1.69 TP43.1
N66390837: NGFF1.68 TP44.1
N66390898: NGFF1.75 TP45.1
N100957080: RA16.1 U42.3(WP#)
N101129395: RA23.1 U42.7
N198711181: R695.2 U77.8
N198711183: CM72.1 R695.1
N198715748: CM72.2 PL3.1 U77.7
N209543093: R697.1 R698.2 U77.11
N209574440: R699.1 R700.2 U77.6
N236903799: RZ189.2 U76.1
N236903801: C395.1 RZ189.1
N236903803: C397.1 C398.1 C399.1 PL1.2(L2) R684.2 U76.10 U76.21(VIN_2)
N236903807: C395.2 PL2.1 U76.20
N236903827: C400.1 R686.2 R689.2 U76.7
N236903834: CA147.1 R687.2
N236903849: CA66.1 R689.1 RZ58.2 U76.6
N236903854: C406.1 R688.1 R690.2 U76.19
N236903856: C405.1 CA66.2 U76.5
N236903864: R690.1 R691.2 U76.4
N236903867: R692.2 U76.3

Pads without a net: D66 4 5 6 7; DB1 7 8 9; HDMI1 14; J1 A14 A15 A18 A19 A30 A31 A38 A39 A48 A54 A58 A59 B5 B9 B10 B16 B17 B20 B21 B28 B29 B48 B49 B54 B56 B59 B61 B62 C4 C5 C14 C15 C18 C19 C22 C23 C30 C31 C38 C39 C54 C55 D5 D9 D10 D16 D17 D20 D21 D28 D29 D36 D54 D56 D61 E4 E5 E6 E7 E11 E14 E15 E18 E19 E26 E27 E30 E31 E34 E35 E50 E51 E54 E60 F5 F6 F16 F17 F20 F21 F28 F29 F32 F33 F36 F37 F51 F52 F54 F61 G4 G5 G6 G14 G15 G18 G19 G22 G23 G30 G31 G38 G39 G50 G51 G56 G59 G60 H5 H6 H16 H17 H20 H21 H28 H29 H36 H37 H48 H49 H51 H52 H59 H60 H61 J5 J6 J7 J10 J11 J14 J15 J18 J19 J30 J31 J38 J39 J47 J48 J50 J52 J53 K6 K7 K9 K10 K16 K17 K20 K21 K28 K29 K36 K37 K46 K47 K49 K51 K52 K56 K62 L18 L19 L41 L42 L44 L45 L47 L50 L56 L57 L58 L59; L12 3; NCSI1 P1 P2; NGFF1 10 20 22 23 24 28 38 41 43 47 49 53 54 55 56 58 59 60 61 62 63 64 65; NMEA2000 2 3; OOB1 2 P1 P2; PSON1 5 6; PSON2 5 6; PSON3 5 6; Q53 1 2 6; Q54 3 4 5; Q66 1 2 6; Q69 3 4 5; RZ23 1; SSD2 6 8 10 20 22 24 26 28 30 32 34 36 38 46 48 67 P1 P2; SW1 5 6; SW2 5 6; TP18 P1 P2; U10 1; U13 2 7 10 27 28 29 31 32 33 35 36 37 45 46 49 51 54 57 58 59 60 61 62 63; U16 1 14 16 17 29 30 31 32 41 45 47 48; U18 3 4 5 10 11 12 13 15 25 26 27 28 29 30 31; U20 3 20 39 52 55 56 58 59 65 66 68 69; U25 1 4 5 6 7 8 9 10 11 12 13 14 15 16 17 18 28 33 42 43 44 45 46 47 48 49 50 51 52 53 54 56 58 59 60 61 62; U27 8 9 10 11 12; U34 3 4; U36 2; U37 1; U39 8 9 10 11 12; U40 4 6 14; U41 22; U43 22; U45 22; U47 22; U49 22; U51 22; U53 22; U55 22; U65 15 16 18 19 20 22 23 24 25 26 27 28 47 52; U66 11 12 13 14 61; U67 A5 A11 A12 A15 A16 A21 A22 A23 A25 AA1 AA3 AB9 AB11 AB23 AB24 AB25 AC9 AC11 AC17 AC18 AC21 AC22 AC24 AD8 AD10 AD15 AD16 AD19 AD20 AD23 AE3 AE8 AE9 AE10 AE11 AE17 AE18 AE21 AE22 AE25 AF9 AF11 AF15 AF16 AF19 AF20 AF23 AF25 B4 B5 B10 B13 B14 B17 B18 B20 B22 B23 B24 B26 C2 C3 C4 C11 C12 C15 C16 C20 C21 C22 C24 C25 C26 D1 D2 D3 D4 D10 D13 D14 D17 D18 D21 D24 D26 E1 E3 E9 E10 J23 J25 K23 K25 P2 P4 R2 R4 T1 T3 U1 U3 V2 V4 W2 W4 Y1 Y3; U70 1 3 27 28 30 31 38 40 43 44 66 80 81; U72 8 9; U73 8 9; U75 3; U77 4; U78 8 9; U79 8 9; U83 2 5 8 9 21 24 28 33; U86 7 14; U92 7 8 9 16; WIFI1 44 46 48 64 65 66 67 68 70 71 73 P1 P2

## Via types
v1: diameter 0.457, hole 0.254, TOP to BOTTOM, 3886 vias
v2: diameter 0.61, hole 0.305, TOP to BOTTOM, 723 vias
v3: diameter 0.406, hole 0.203, TOP to BOTTOM, 593 vias
v4: diameter 0.559, hole 0.305, TOP to BOTTOM, 40 vias
v5: diameter 0.508, hole 0.305, TOP to BOTTOM, 8 vias
v6: diameter 0.508, hole 0.254, TOP to BOTTOM, 2 vias

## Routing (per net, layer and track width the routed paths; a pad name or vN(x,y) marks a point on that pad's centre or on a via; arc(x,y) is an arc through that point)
1V2_DCVDD: length 3.1
  BOTTOM w0.203: U16.42 141.15,148.28 141.1,148.34 141.1,149.39 C27.1
  BOTTOM w0.508: CA130.1 C27.1
1V8_AVDD: length 9
  BOTTOM w0.203: U16.15 142.75,141.35 143.26,140.84
  BOTTOM w0.508: RZ166.1 148.84,140.21 148.18,139.55 RZ168.1 145.82,139.55 145.44,139.93 C38.1 144.37,139.93 144.11,139.66 CA134.1 143.64,140.46 143.26,140.84
1V8_CPVDD: length 4.7
  TOP w0.381: v1(139.19,141.05) 139.19,140.5 CA54.1 139.13,140.11 C42.1
  TOP w0.508: RZ12.1 136.53,140.11 C42.1
  BOTTOM w0.203: U16.23 139.55,141.41 v1(139.19,141.05)
1V8_TPM_IRQ#: length 15.9
  TOP w0.107: J1.C57 v1(102.9,121.52) ; v1(114.94,120.02) 115.16,119.79 RB25.1 115.99,119.62 Q57.S
  IN1 w0.124: v1(102.9,121.52) 102.9,121.13 103.38,120.65 114.3,120.65 v1(114.94,120.02)
3.3VCC: length 11.1
  TOP w0.229: v1(82.04,153.54) 82.08,153.51 U25.39 ; U25.35 v1(80.48,153.54)
  TOP w0.254: U25.23 v1(79.38,157.44)
  TOP w0.508: v1(78.69,148.63) C69.1 CA49.1
  BOTTOM w0.508: R174.2 78.55,157.44 v1(79.38,157.44) ; CA128.1 CA127.1 81.92,153.67 v1(82.04,153.54) ; CA128.1 80.73,154.51 R172.2 ; CA128.1 80.77,153.84 v1(80.48,153.54) ; R175.2 v1(85.93,155.3)
3V3_MICVDD: length 3.2
  BOTTOM w0.203: CA131.1 145.54,146.81 144.9,146.18 U16.3
  BOTTOM w0.508: CA131.1 C40.1
3V3_SPI_CLK: length 5.9
  TOP w0.107: R1484.1 v1(110.24,91.69) ; v1(107.85,95) 108.01,95.16 U86.12
  IN3 w0.124: v1(107.85,95) 108.61,94.23 108.61,93.32 v1(110.24,91.69)
3V3_SPI_MISO_IO1: length 5.3
  TOP w0.107: R1485.1 107.95,93.83 v1(107.98,93.85) ; U86.15 v1(109.67,93.85)
  BOTTOM w0.107: v1(109.67,93.85) v1(107.98,93.85)
3V3_SPI_MOSI_IO0: length 3.6
  TOP w0.107: U86.13 108.87,92.46 109.09,92.24 R1486.1
5V_DISCHG_D: length 5.3
  TOP w0.508: Q37.D 116.1,91.82 114.6,93.32 R693.2 R694.2
5V_GP_OOB: length 2.1
  BOTTOM w0.107: OOB1.7 152.76,92.2 RZ187.2
5V_HDMI2: length 3.4
  BOTTOM w0.203: v1(106.78,48.26) 106.65,48.13 HDMI1.18
  BOTTOM w0.381: R530.1 R531.1 106.32,51.51 v1(106.32,51.1)
5V_ON_D: length 2.9
  TOP w0.508: Q37.G 115.45,89.15 115.87,88.73 RB43.2 115.87,87.76 115.98,87.66 Q38.D
5V_SPKVDD: length 4.3
  BOTTOM w0.203: U16.46 142.75,148.13 142.95,148.34 144.02,148.34 144.4,147.96 v1(144.4,147.7) ; U16.2 144.68,146.58 145.03,146.94 v1(145.03,147.7)
5V_SW_G: length 6.7
  TOP w0.508: v2(118.34,90.17) 118.97,89.53 C407.2 119.18,89 119.53,88.65 RZ113.2 RB43.1
  BOTTOM w0.508: Q36.4 v2(118.34,90.17)
5VCC: length 3.8
  TOP w0.229: 88.34,157.04 U25.57
  TOP w0.508: 88.34,157.04 89.12,157.04 CB5.1 89.32,155.59 R1508.2
+V1.2S: length 0.8
  TOP w0.508: FB32.2 v1(103.66,89.79)
  vias: v1(100.76,96.8) v1(100.86,80.54) v1(100.86,79.96) v1(101.4,96.8)
+V1.2SB: length 31.5
  TOP w0.229: v1(76.53,67.44) 76.61,67.44 76.7,67.35 U20.46
  TOP w0.254: CA26.1 v1(76.53,67.44)
  BOTTOM w0.508: v1(76.53,67.44) 76.99,67.44 77.75,68.2 77.75,74.17 77.5,74.42 77.5,75.31 81.5,79.31 81.5,85.17 84.47,88.14 84.47,89.14 84.48,89.15 ; R706.2 88.81,91.22 C427.1 87.66,90.68 87.27,90.3 85.62,90.3
  vias: v1(84.86,90.37) v1(84.86,89.79) v1(84.86,89.2) v1(85.45,90.37) v1(85.45,89.79) v1(85.45,89.2) v1(97.12,96.41) v1(97.73,96.41)
+V1.2SB_PG: length 17.6
  TOP w0.254: v1(86.89,92.96) 86.74,93.12 RB34.2 ; RZ57.1 97.87,98.42 v1(97.74,98.55)
  IN1 w0.254: v1(97.74,98.55) 97.36,98.17 90.07,98.17 89.05,97.16 89.05,93.98 88.04,92.96 v1(86.89,92.96)
  BOTTOM w0.254: U79.2 86.77,93.09 v1(86.89,92.96)
+V1.05S: length 13.8
  TOP w0.508: 42.37,98.88 42.37,98.12 41.86,97.61 38.68,97.61 37.16,99.14 37.16,104.05 C385.1 37.83,105.85 R655.2
  vias: v2(43.26,100.28) v2(43.26,99.52) v2(43.26,98.76) v2(44.02,100.28) v2(44.02,99.52) v2(44.02,98.76)
+V1.05S_PG: length 1.9
  TOP w0.254: RB31.2 40.06,103.45 U73.2
+V1.8S: length 228.3
  TOP w0.279: J14.102 119,173.65 C136.1
  TOP w0.305: C891.1 122.62,65.49 v1(122.5,65.61) ; U33.1 115.32,134.89
  TOP w0.381: 115.32,134.89 114.75,134.89 CA56.1 v1(114.68,135.64) ; U10.5 v1(108.55,152.44) ; U33.1 U33.5 118.79,134.89 R240.2 v1(119.53,136.27)
  TOP w0.508: U15.8 40.05,122.94 CA59.1 v1(40.17,123.75) 40.17,124.82 40.68,125.32 R92.1 R93.1 ; v1(115.01,120.75) RB25.2 116.46,120.75 116.63,120.92 Q57.G ; Q17.G 146.83,127.65 147.55,128.37 R196.1 v1(148.21,128.52) ; CA11.1 65.82,177.72 65.65,177.9 U36.3 ; CA11.1 RB3.1 64.24,176.29 v1(64.22,176.28) ; CA11.1 v1(65.82,176.28) ; R1483.2 v1(141.96,128.24) ; v1(104.01,140.08) R243.2 R242.2 ; v1(104.29,110.36) 104.17,110.49 100.3,110.49 R3.2 100.18,109.84 100.34,109.68 Q50.G ; R98.1 v1(39.88,108.03) ; v1(139.84,102.11) 140.34,102.6 CA145.1 139.43,102.91 138.96,103.38 138.96,105.92 139.34,106.3 146.58,106.3 147.22,106.93 v1(147.22,107.57) R757.2 ; v1(114.94,123.55) RB24.2 116.93,123.55 Q59.G ; C136.1 v1(119.21,174.5) ; RB28.1 v1(42.88,108.03) ; RB27.1 v1(41.27,108.03)
  IN2 w0.508: v1(148.21,128.52) 149.63,128.52 150.01,128.14 150.01,127.51 153.06,124.46 153.06,113.16 147.47,107.57 v1(147.22,107.57)
  IN2 w1.016: 52.86,113.28 52.4,113.74 52.4,113.87 47.83,113.87 42.88,108.92 v1(42.88,108.03) v1(41.27,108.03) v1(39.88,108.03)
  IN3 w0.508: 106.83,88.39 107.4,87.82 107.4,85.28 110.52,82.17 110.52,78.36 117.63,71.25 117.63,67.94 119.96,65.61 v1(122.5,65.61)
  BOTTOM w0.254: U85.1 140.09,102.91 139.84,102.66 v1(139.84,102.11) ; v1(122.5,65.61) 122.65,65.47 U87.2
  BOTTOM w0.305: 135.89,134.75 136.27,135.13 Q52.2 ; 135.89,134.75 v1(135,134.75) 134.62,135.13 R187.2 ; 135.89,134.75 136.27,134.37 Q52.5
  BOTTOM w0.381: v1(124.21,137.21) 124.51,137.52 R198.2 125.45,137.29 Q53.5 ; Q54.2 125.86,134.62 125.63,134.85 R201.2 v1(124.31,134.85) ; R141.1 v1(114.68,125.09) ; R681.1 v1(151.38,140.94)
  BOTTOM w0.508: R193.2 v1(141.45,135.13) ; U37.5 68.33,173.17 68.35,173.14 CA124.1 v1(68.83,172.47) ; v1(126.49,169.8) 128.52,169.8 129.03,170.31 136.93,170.31 R1476.2 ; R143.1 v1(127.99,125.22) R142.1 ; R114.1 v1(143.51,151.13) ; v1(64.22,176.28) CA123.1 64.22,177.76 64.39,177.93 U38.3 ; v1(139.84,102.11) 139.88,102.07 R763.1 135.79,101.47 135.41,101.85 R5.2 R9.2 R7.2 R11.2 ; 123.83,147.57 121.28,150.11 116.97,150.11 115.82,148.97 109.35,148.97 ; v1(104.01,140.08) 104.01,141.2 109.35,146.53 109.35,148.97 ; CA129.1 108.55,153.09 v1(108.55,152.44) 108.48,152.38 R46.1 108.48,149.83 109.35,148.97 ; R540.2 v1(106.4,87.07) ; R195.2 v1(148.72,134.75) ; J4.1 CA136.1 v1(117.69,125.86) ; RB62.2 v1(61.59,174.12)
  BOTTOM w0.762: v1(40.17,123.75) 40.17,118.53 39.07,117.42 39.07,108.84 v1(39.88,108.03) v1(41.27,108.03)
  vias: v1(103.4,99.95) v1(103.4,99.31) v1(104.93,110.36) v1(123.57,146.56) v1(123.57,145.92) v1(123.57,145.29) v1(124.21,146.56) v1(124.21,145.92) v1(124.21,145.29) v1(125.22,169.8) v1(125.86,169.8) v1(134.42,143.74) v1(134.42,143.1) v1(135.05,143.74) v1(135.05,143.1)
+V1.8S_PG: length 92.7
  TOP w0.107: CM45.1 97.31,94.56 97.75,94.12 RA1.2 RA2.2 101.13,94.11 104.55,94.11 105.69,92.96 105.69,79.76 106.96,78.49 116.99,78.49 117.75,79.25 133.25,79.25 134.9,80.9 149.5,80.9 151.54,82.93 151.54,91.57 v1(150.77,92.33) ; CM45.1 97.59,95 98.1,95.51 U81.3 ; CM45.1 97.31,95.38 97.18,95.5 95.53,95.5 95.28,95.76 95.28,96.9 93.88,98.3 91.97,98.3 91.81,98.46 CM44.1 92.13,99.16 92.64,99.68 U80.3
  BOTTOM w0.107: RZ187.1 v1(150.77,92.33)
+V1.8SB: length 16.1
  TOP w0.203: U86.3 111.57,95.96 CB12.1
  TOP w0.305: 111.75,96.56 CB12.1
  TOP w0.508: v1(106.83,101.73) 107.47,101.73 107.98,101.22 110.39,101.22 111.12,100.48 RB38.1 111.75,97.8 111.75,96.56
  BOTTOM w0.508: R705.1 86.46,102.12 C424.1 88.14,102.11 88.72,101.52 v1(88.72,100.08)
  vias: v1(86.97,100.08) v1(86.97,99.44) v1(87.55,100.08) v1(87.55,99.44) v1(88.14,100.08) v1(88.14,99.44) v1(88.72,99.44) v1(88.72,98.86) v1(88.72,98.22) v1(91.61,100.57) v1(92.21,100.57)
+V1.8SB_EN: length 1.6
  TOP w0.254: RZ51.2 85.54,101.97 v1(85.54,101.07)
  BOTTOM w0.203: U78.4 v1(85.54,101.07)
+V1.8SB_PG: length 1.6
  TOP w0.254: v1(84.68,101.04) 84.68,100.43 RB32.2
  BOTTOM w0.203: v1(84.68,101.04) 84.64,100.99 U78.2
+V2.5S: length 13.8
  TOP w0.508: 42.37,89.23 42.37,88.47 41.86,87.96 38.68,87.96 37.16,89.48 37.16,94.41 R651.2 37.82,96.2 C380.1
  vias: v2(43.26,90.75) v2(43.26,89.99) v2(43.26,89.23) v2(44.02,90.75) v2(44.02,89.99) v2(44.02,89.23)
+V2.5S_PG: length 1.9
  TOP w0.254: RB40.2 40.06,93.79 U72.2
+V3.3_WLAN: length 30.7
  TOP w0.305: C84.1 133.6,131.44 v1(132.97,132.08) v1(132.33,132.08)
  TOP w0.508: R199.2 v1(143.26,128.14)
  IN1 w0.508: v1(143.26,128.14) 143.26,128.3 142.67,128.88 142.67,131.85 v1(143.31,132.49)
  BOTTOM w0.279: WIFI1.74 150.49,131.95 v1(150.61,132.08) v1(149.99,132.08) ; WIFI1.72 v1(149.99,129.79)
  BOTTOM w0.305: WIFI1.74 150.49,130.1 150.18,129.79 v1(149.99,129.79) 149.78,129.79 149.48,129.49 v1(149.48,129.41) ; WIFI1.2 132.49,131.75 132.33,131.9 v1(132.33,132.08) ; RA52.1 v1(131.83,140.46) ; v1(132.97,132.08) 132.99,132.06 WIFI1.4 ; v1(149.99,132.08) WIFI1.72
  BOTTOM w0.508: v1(133.38,134.47) R190.2 131.7,133.6 130.81,132.72 125.6,132.72 125.12,132.23 R189.1 v1(125.12,131.06) R188.1 ; R197.2 v1(130.4,137.64) ; R192.2 v1(142.65,135.1) ; R200.2 v1(130.4,135.1)
  vias: v1(128.7,138.71) v1(129.29,138.71) v1(138.66,132.33) v1(139.32,132.36) v1(143.97,132.49)
+V3.3_WLAN_PG: length 2.6
  BOTTOM w0.254: U30.3 129.4,141.69 129.66,141.95 CM65.1
  BOTTOM w0.305: CM65.1 131.62,141.95 RA52.2
+V3.3NVME: length 29.6
  TOP w0.305: 141.71,110.67 141.81,110.77 SSD2.18 ; 140.77,110.59 140.81,110.64 SSD2.14 ; SSD2.70 v1(154.81,113.16) ; v1(154.81,113.16) v1(155.45,113.16) 155.31,113.02 SSD2.72 ; v1(154.81,113.16) v1(154.2,113.16) ; SSD2.4 138.31,110.56 138.33,110.54 ; SSD2.2 137.81,110.73 137.97,110.57 ; 141.3,110.64 141.31,110.65 SSD2.16 ; SSD2.12 140.31,110.7 140.26,110.64 ; SSD2.74 155.81,111.04 v1(156.11,110.74)
  TOP w0.508: v1(152.55,98.17) 151.77,98.17 FB39.2
  IN1 w0.508: 148.36,109.09 149,108.46 149,104.39 151.54,101.85 151.54,98.55 151.92,98.17 v1(152.55,98.17)
  BOTTOM w0.381: 152.81,114.43 R759.2 R760.2
  vias: v1(135.86,109.35) v1(135.86,108.71) v1(136.5,109.35) v1(136.5,108.71) v1(139.19,109.35) v1(139.19,108.71) v1(140.46,109.35) v1(140.46,108.71) v1(141.73,109.35) v1(141.73,108.71) v1(156.62,112.01) v1(156.62,111.38)
+V3.3S: length 287.2
  TOP w0.203: U34.7 130.39,174.46 130.3,174.37
  TOP w0.279: J14.110 v1(121,173.23) ; J14.120 v1(123.5,172.72) ; J14.118 v1(123,173.17) ; J14.108 v1(120.5,172.7)
  TOP w0.305: U3.5 49.05,110.58 49.35,110.27 CB3.1 48.96,109.56 v1(48.84,109.68) ; RA1.1 RA2.1 102.53,93.59 v1(102.77,93.34) ; v1(52.15,109.55) 52.11,109.51 CB4.1 51.58,109.52 U5.5
  TOP w0.381: v1(119.32,109.86) CA63.2 119.25,109.21 U88.5 ; R560.1 48.44,109.68 v1(48.84,109.68) ; R2.2 v1(100.86,105.79) ; U89.5 116.08,109.11 CA62.2 v1(116.19,109.86)
  TOP w0.508: v1(104.98,84.3) FB31.2 ; v1(86.51,91.19) 85.52,91.19 85.01,91.69 RB35.1 RB34.1 ; v1(127.99,67.69) RB56.2 RB57.2 ; RB7.1 v1(131.7,161.52) ; RB44.2 v1(13.72,81.74) ; R245.1 v1(135.25,174.37) ; v1(16.97,81.61) RB46.2 RB45.2 ; v1(38.3,93.93) RB40.1 RB41.1 ; v1(36.2,177.8) CA8.1 ; v1(142.27,102.49) 141.85,102.91 CA144.2 ; RB33.1 RB31.1 v1(38.3,103.58) ; RB6.1 v1(129.29,161.52)
  TOP w0.559: U40.7 36.9,178.44 37,178.34 CA8.1
  IN1 w0.508: v1(114.58,70.99) 114.58,69.85 115.47,68.96 127.15,68.96 127.99,68.12 v1(127.99,67.69) ; v1(124.49,142.49) 124.49,139.83 127.32,136.99 135.11,136.99 135.86,136.25 144.58,136.25 145.16,135.66 v1(145.16,134.87) ; v1(100.86,105.79) 103.4,105.79 106.2,103 112.67,103 112.93,103.25
  IN2 w0.508: v1(128.68,64.39) 128.68,64.64 127.99,65.33 v1(127.99,67.69)
  IN2 w0.762: 120.52,176.02 88.21,176.02 87.78,175.59 82.88,175.59 79.2,171.91 69.67,171.91 68.78,171.02 63.96,171.02 63.07,171.91 46.41,171.91 41.66,176.66 36.96,176.66 36.2,177.42 v1(36.2,177.8)
  IN3 w0.508: 125.55,104.24 130.61,104.24 133.5,101.35 141.12,101.35 v1(142.27,102.49) 142.39,102.62 144.42,102.62 144.81,102.23 v1(147.09,102.23) v1(147.09,103.38) v1(147.09,104.52) v1(147.09,105.66) ; 106.26,77.72 106.96,77.03 109.18,77.03 114.58,71.63 v1(114.58,70.99) ; 106.26,77.72 v1(106.26,82.87) ; 106.26,77.72 104.38,75.84 89.79,75.84 88.16,77.47 88.16,89.03 86.51,90.68 v1(86.51,91.19)
  BOTTOM w0.203: v1(142.27,102.49) 142.27,102.62 141.92,102.96 U85.11
  BOTTOM w0.305: R1334.1 C892.2 128.79,64.5 v1(128.68,64.39)
  BOTTOM w0.508: v1(46.05,114.38) 46.05,110.44 46.81,109.68 v1(48.84,109.68) 49.73,110.57 51.64,110.57 52.15,110.06 v1(52.15,109.55) ; R1490.2 v1(115.98,121.54) R1474.2 ; R4.2 v1(147.09,102.23) ; Q40.9 125.55,104.88 ; R10.2 v1(147.09,105.66) ; Q29.D v1(37.29,81.51) ; v1(13.72,81.74) 13.64,81.66 RB65.2 ; R6.2 v1(147.09,103.38) ; R191.2 v1(145.16,134.87) ; R8.2 v1(147.09,104.52)
  vias: v1(103.4,92.33) v1(128.47,117.33) v1(129.79,173.48) v1(129.79,172.85) v1(130.35,117.33) v1(137.03,178.56) v1(137.03,177.93) v1(137.67,178.56) v1(137.67,177.93) v1(138.3,178.56) v1(138.3,177.93) v2(126.39,108.46) v2(127.15,108.46) v2(127.91,108.46) v2(128.68,108.46) v2(129.44,108.46) v2(130.2,108.46) v2(130.96,108.46) v2(131.72,108.46) v2(131.72,107.7) v2(131.72,106.93) v2(131.72,106.17) v2(132.49,108.46) v2(132.49,107.7) v2(132.49,106.93) v2(132.49,106.17) v2(133.25,108.46) v2(133.25,107.7) v2(133.25,106.93) v2(133.25,106.17)
+V3.3SB: length 164.5
  TOP w0.203: CB13.1 111.59,95.56 U86.2
  TOP w0.254: v1(113.56,88.52) 113.45,88.63 CB19.1 113.45,89.42 113.56,89.53 U19.5 ; U6.4 132.8,157.82 v1(132.84,157.86) ; v1(91.72,101.6) 91.61,101.49 CB10.1 92.48,101.09 92.9,100.68 U80.1 ; v1(97.21,97.43) 97.09,97.32 CB11.1 97.97,96.93 98.38,96.51 U81.1
  TOP w0.305: CB13.1 v1(111.77,94.87) ; U18.22 v1(109.32,89.03) ; U18.8 111.82,82.51 v1(111.91,82.42) ; U4.5 107.93,139.97 CB2.1 106.9,140 v1(106.43,140)
  TOP w0.381: RB12.1 107.26,156.23 v1(108.56,156.23) U11.5 108.56,158.57 R48.1 ; U9.5 v1(92.61,105.65) ; R40.1 v1(100.36,100.71) ; U91.5 v1(91.64,108.16) ; U7.6 132.36,165.62 CA46.1 ; U90.5 v1(82.96,109.17) ; U12.5 v1(83.34,106.31)
  TOP w0.508: v1(67.21,68.2) R621.1 R622.1 66.52,65.94 R636.2 ; v1(121.34,45.24) RZ99.2 v1(121.34,43.94) ; RB10.1 v1(134.24,157.63) ; RB11.1 v1(126.9,158.5) RB9.1 RB8.1 ; CA46.1 v1(132.37,166.24) ; v1(70.79,140.56) 71.04,140.82 98.93,140.82 99.44,140.31 v1(99.44,140.08) RZ15.1 ; R1488.1 v1(112.78,80.01) ; RB13.1 v1(134.37,154.58) ; RZ61.1 v1(108.33,80.04) ; RB32.1 v1(83.49,100.94) ; J11.1 J13.1 ; RB42.1 v1(111.38,91.69) ; R561.1 v1(76.1,110.24)
  IN2 w0.508: v1(99.44,140.08) 99.95,140.08 101.35,141.48 105.54,141.48 106.43,140.59 v1(106.43,140)
  BOTTOM w0.305: U67.D5 v3(55.16,103.42) ; U67.E5 v3(55.96,103.42) ; RZ192.1 112.55,84.45 111.93,83.83 CB138.1 112.04,83.2 112.04,82.55 v1(111.91,82.42) ; U67.F5 v3(56.76,103.42) ; CB1.1 109.73,88.62 v1(109.32,89.03) 108.97,88.67 CB137.1
  BOTTOM w0.381: v1(82.96,109.17) 83.01,109.17 83.5,109.66 CA141.1 ; v3(57.56,103.42) 57.96,103.02 U67.G5 ; v1(108.56,156.23) 108.62,156.17 CA126.1 ; CA143.1 83.16,106.13 v1(83.34,106.31)
  BOTTOM w0.508: 127.76,142.75 127.69,142.75 126.95,143.48 R204.2 124.05,143.48 122.17,141.6 108.03,141.6 v1(106.43,140) ; R22.1 v1(70.79,140.56) ; CA142.1 93.19,105.65 v1(92.61,105.65) ; v1(132.72,137.67) 132.97,137.41 148.54,137.41 148.82,137.13 RB64.1 ; RB36.2 111.62,94.72 v1(111.77,94.87) ; v1(109.32,89.03) 109.37,89.08 R771.2 ; CA125.1 132.75,157.95 v1(132.84,157.86) ; v1(147.32,172.24) R1475.2 ; CA140.1 91.68,108.12 v1(91.64,108.16) ; CA126.1 108.62,154.9 109.22,154.31 110.26,154.31 110.9,153.67 R51.1 110.9,150.5 111.4,149.99 115.19,149.99 116.33,151.13 128.4,151.13 v1(129.79,152.53) ; RB63.1 133.5,155.45 v1(134.37,154.58) ; RB66.1 v1(150.83,20.02)
  vias: v1(35.46,40.54) v1(36.07,40.51) v1(37.34,40.51) v1(54.36,40.56) v1(55.63,40.56) v1(79.35,40.56) v1(79.71,82.37) v1(79.71,81.74) v1(80.85,40.56) v1(91.01,39.75) v1(92.43,39.75) v1(116.28,40.77) v1(117.55,40.77) v1(118.31,40.74) v1(119.13,40.74) v1(123.01,40.23) v1(123.47,39.83) v1(126.39,97.54) v1(126.39,91.95) v1(127.15,97.54) v1(127.15,91.95) v1(127.91,97.54) v1(127.91,91.95) v1(128.17,100.33) v1(128.4,142.9) v1(128.4,142.32) v1(128.68,97.54) v1(128.68,91.95) v1(128.93,100.33) v1(128.93,99.57) v1(129.44,97.54) v1(129.44,91.95) v1(129.69,100.33) v1(129.69,99.57) v1(130.2,97.54) v1(130.2,91.95) v1(130.45,100.33) v1(130.45,99.57) v1(132.11,117.76) v1(132.82,117.76) v1(139.04,175.9) v1(139.65,175.9)
+V3.3SB_EN: length 53.4
  TOP w0.107: v1(95.78,103.4) RZ32.2 89.71,103.4 88.29,101.98 RZ51.1 ; Q14.G v1(117.75,75.95)
  BOTTOM w0.107: v1(95.78,103.4) 96.16,103.02 101.27,103.02 102.42,101.87 104.2,101.87 106.6,99.47 106.6,89.69 107.45,88.84 107.45,82.39 113.64,76.2 117.5,76.2 v1(117.75,75.95)
+V3.3SB_EN#: length 112.6
  TOP w0.254: RB50.1 122.12,75.9 v1(122.07,75.95) ; RB50.1 122.42,75.29 123.04,74.66 U14.5 ; RB50.1 RZ72.2
  TOP w0.508: R702.1 132.21,92.1 132.18,92.08 v1(132.18,91.95)
  IN1 w0.254: v1(132.18,91.95) 132.18,91.39 131.34,90.55 119.91,90.55 118.39,89.03 116.87,89.03 116.1,88.27 116.1,78.61 118.77,75.95 v1(122.07,75.95) ; v1(144.42,64.9) 143.41,63.88 143.41,60.45 139.78,56.82 139.78,43.73 142.74,40.77 149.1,40.77 153.04,36.83 JPSON1.1
  BOTTOM w0.254: v1(144.42,64.9) 143.66,65.66 140.23,65.66 137.31,68.58 137.31,72.39 136.56,73.15 134.65,73.15 133.5,74.3 124.61,74.3 122.96,75.95 v1(122.07,75.95) ; Q39.4 v1(132.18,91.95)
+V3.3SB_GND: length 4.3
  TOP w0.508: RZ53.2 143.92,99.03 v1(143.92,98.42) 144.27,98.07 C418.2 144.27,95.89 R700.1
  BOTTOM w0.305: v1(143.92,98.42) 143.9,98.4 U77.10
+V3.3SB_PGOOD: length 1.5
  BOTTOM w0.107: U77.3 144.9,94.23 145.16,93.97 R701.1
+V3.3SB_VCC: length 11.8
  TOP w0.508: v1(145.82,92.48) 145.54,92.2 142.9,92.2 142.39,92.71 142.39,95.5 142.75,95.86 R699.2 143.15,96.65 142.8,97 C418.1 142.8,98.07 v1(143.15,98.42)
  BOTTOM w0.305: U77.9 143.39,98.18 v1(143.15,98.42)
  BOTTOM w0.508: R701.2 v1(145.82,92.48)
+V3.3V: length 2.1
  TOP w0.229: CA68.2 18.75,79.83 17.76,78.85 U65.43
+V3P3A_HUB: length 14
  TOP w0.229: U20.49 77.29,66.15 v1(77.17,66.02)
  TOP w0.254: R156.1 R166.1 v1(89.61,63.2) ; R157.1 RA9.1 v1(75.01,63.7) ; RA10.1 v1(88.21,60.02)
  TOP w0.305: RA6.1 v1(89.99,70.43) R155.1 ; RA3.1 85.64,80.01 U21.8 83.77,80.01 83.46,80.32 83.46,81.95 CA22.1 ; RA4.1 v1(77.29,76.28) ; v1(77.55,59.72) 77.93,59.72 RZ98.1 ; R158.1 RA5.1 v1(77.04,73.48)
  TOP w0.508: RZ79.1 v1(73.1,70.08) ; RZ90.2 v1(72.59,65.61)
  vias: v1(77.55,60.33) v1(82.75,82.5) v1(83.39,82.5)
+V5S: length 173.5
  TOP w0.107: 77.94,148.63 C71.1
  TOP w0.381: J1.L31 78.58,132.98 v3(78.58,133.5) ; J1.L26 73.86,132.92 v3(73.86,133.5) ; v3(69.86,133.5) 69.86,132.92 J1.L22 ; J1.L38 85.61,133.05 v3(85.61,133.5) ; J1.L27 74.58,132.98 v3(74.58,133.5) ; v3(81.86,133.5) 81.86,132.92 J1.L34 ; 86.58,132.98 J1.L39 ; J1.L30 77.86,132.92 v3(77.86,133.5) ; J1.L23 70.58,132.98 v3(70.58,133.5) ; v3(82.58,133.5) 82.58,132.98 J1.L35
  TOP w0.508: v1(91.44,155.45) R1508.1 ; v1(91.44,155.45) v1(91.44,154.76) ; v1(91.44,155.45) 102.23,155.45 106.68,159.89 RZ4.1 ; RB59.1 v1(75.26,56.46) ; RB2.1 v1(95.12,177.16) ; v1(85.89,176.66) CA10.1 85.89,178.27 85.75,178.41 U24.1 ; C71.1 v1(77.04,148.58)
  TOP w1.016: v1(144.53,152.65) 139.19,152.65 135.76,156.08 135.76,159.14 135.64,159.27 135.64,166.12 136.4,166.88
  IN1 w0.508: v1(144.53,152.65) 136.65,152.65 134.75,150.75 134.75,145.03 133.65,143.94 133.65,140.21 136.32,137.54 147.96,137.54 148.97,138.56 v1(150.62,138.56) 151.13,138.56 151.64,138.05 151.64,134.85 v1(151.76,134.72)
  BOTTOM w0.508: R680.1 v1(150.62,138.56) ; v1(95.12,177.16) CA122.1 94.45,177.89 94.61,178.05 94.61,178.88 U26.1 ; R677.1 v1(150.32,18.62) 148.23,20.7 147.24,20.7 142.78,25.16 142.78,27.81 140.87,29.72 140.87,41.02 140.18,41.71 R230.1 136.35,41.71 136.17,41.53 130.96,41.53 129.31,39.88 124.99,39.88 123.98,40.89 121.31,40.89 120.42,41.78 120.42,48.51 119.41,49.53 112.42,49.53 v1(111.23,50.72) ; v1(85.89,176.66) 85.88,176.67 RB61.1 ; R682.1 v1(151.76,134.72)
  vias: v1(26.16,182.12) v1(26.16,179.71) v1(26.8,182.12) v1(26.8,179.71) v1(76.84,112.62) v1(78.72,112.62) v1(81.36,171.91) v1(81.36,171.27) v1(81.99,171.91) v1(81.99,171.27) v1(82.45,172.47) v1(94.77,69.72) v1(95.4,69.72) v1(111.23,51.33) v1(135.64,168.78) v1(136.27,168.78) v1(144.55,153.26) v2(117.37,98.17) v2(117.37,97.41) v2(117.37,96.65) v2(117.37,95.89) v2(117.37,95.12) v2(117.37,94.36) v2(117.37,93.6) v2(117.75,100.84) v2(118.52,100.84) v2(118.52,100.08) v2(118.52,99.31) v2(118.52,98.55) v2(119.28,100.84) v2(119.28,100.08) v2(119.28,99.31) v2(119.28,98.55) v2(120.04,100.84) v2(120.04,100.08) v2(120.04,99.31) v2(120.04,98.55) v2(120.8,100.84) v2(120.8,100.08) v2(120.8,99.31) v2(120.8,98.55) v2(121.56,100.84) v2(121.56,100.08) v2(121.56,99.31) v2(121.56,98.55) v2(122.33,100.84) v2(123.09,98.17) v2(123.09,97.41) v2(123.09,96.65) v2(123.09,95.89) v2(123.09,95.12) v3(85.6,134.11)
+V5S_ISO: length 8.7
  TOP w0.508: v1(85.22,191.26) CA1.1 85.89,190.13 85.75,189.99 U24.16 ; v1(67.44,188.59) R254.1 ; v1(94.45,191.77) 94.46,191.76 RB1.1
  BOTTOM w0.508: U26.16 94.64,190.12 94.45,190.31 CA118.1 v1(94.45,191.77) ; v1(85.22,191.26) RB60.1 ; v1(62.61,188.59) R259.1
  vias: v1(61.47,184.66) v1(61.47,184.02) v1(68.07,188.72) v1(68.07,186.69) v1(68.2,184.78) v1(68.2,184.15) v1(68.71,188.72) v1(68.71,186.69) v1(74.3,185.04) v1(74.3,184.28) v1(75.06,185.04) v1(75.06,184.28)
+V5SB: length 230.6
  TOP w0.254: R165.2 v1(92.02,64.21)
  TOP w0.356: U75.5 56.12,169.89 55.87,169.63 CA45.1 v1(53.89,169.63)
  TOP w0.381: U7.1 128.74,165.62 128.54,165.82 CA47.2 128.02,166.34 v1(128.14,166.47) ; U75.5 56.12,171.16 R668.1
  TOP w0.508: v1(72.72,70.69) R162.2 73.86,71.35 R163.2 ; CA67.1 126.3,89.95 127.15,90.81 v1(134.9,90.81) ; v1(86.11,149.22) 99.82,149.22 100.46,149.86 113.03,149.86 115.7,152.53 v1(115.7,155.77) 115.11,156.36 RZU5.1 RB22.1
  IN1 w0.508: 68.53,147.78 68.53,164.29 64.08,168.73 54.79,168.73 v1(53.89,169.63) ; 68.53,147.78 67.94,147.19 56.79,147.19 48.16,138.56 48.16,122.17 44.7,118.72 44.7,102.77 v2(45.67,101.8) ; 68.53,147.78 69.11,147.19 82.68,147.19 84.71,149.22 v1(86.11,149.22) ; v1(128.14,166.47) 128.14,166.37 126.75,164.97 126.75,161.93 120.65,155.83 115.75,155.83 v1(115.7,155.77)
  BOTTOM w0.508: C400.2 135.7,90.41 R686.1 v1(134.9,90.81) ; v2(124.74,81.53) 127.03,79.25 133.25,79.25 134.98,80.98 150.98,80.98 152.17,82.17 152.17,88.35 152.68,88.86 CA148.1 153.66,88.86 154,89.2 OOB1.10
  vias: v1(40.59,45.72) v1(41.71,45.72) v1(73.1,52.65) v1(73.1,52.02) v1(73.74,52.65) v1(73.74,52.02) v1(80.92,92.53) v1(80.92,91.95) v1(80.95,91.36) v1(80.95,90.78) v1(81.53,91.36) v1(81.53,90.78) v1(82.12,91.36) v1(82.12,90.78) v1(82.7,91.36) v1(82.7,90.78) v1(85.22,95.3) v1(85.8,95.3) v1(86.39,97.05) v1(86.39,96.47) v1(86.39,95.89) v1(86.39,95.3) v1(86.97,97.05) v1(86.97,96.47) v1(86.97,95.89) v1(86.97,95.3) v1(91.77,62.18) v1(91.77,61.54) v1(92.41,62.18) v1(92.41,61.54) v2(45.67,101.04) v2(45.67,92.15) v2(45.67,91.39) v2(46.43,101.8) v2(46.43,101.04) v2(46.43,92.15) v2(46.43,91.39) v2(47.19,102.57) v2(47.19,101.8) v2(47.19,101.04) v2(47.19,92.91) v2(47.19,92.15) v2(47.19,91.39) v2(47.96,102.57) v2(47.96,101.8) v2(47.96,101.04) v2(47.96,92.91) v2(47.96,92.15) v2(47.96,91.39) v2(121.69,89.66) v2(121.69,88.9) v2(121.69,82.3) v2(121.69,81.53) v2(122.45,89.66) v2(122.45,88.9) v2(122.45,86.87) v2(122.45,86.11) v2(122.45,85.34) v2(122.45,84.58) v2(122.45,83.82) v2(122.45,83.06) v2(122.45,82.3) v2(122.45,81.53) v2(123.22,89.66) v2(123.22,88.9) v2(123.22,86.87) v2(123.22,86.11) v2(123.22,85.34) v2(123.22,84.58) v2(123.22,83.82) v2(123.22,83.06) v2(123.22,82.3) v2(123.22,81.53) v2(123.98,89.66) v2(123.98,88.9) v2(123.98,86.87) v2(123.98,86.11) v2(123.98,85.34) v2(123.98,84.58) v2(123.98,83.82) v2(123.98,83.06) v2(123.98,82.3) v2(123.98,81.53) v2(124.74,89.66) v2(124.74,88.9) v2(124.74,82.3)
+V5SB_EN: length 33.9
  TOP w0.254: R684.1 137.79,89.03 R685.1 137.31,88.01 v1(136.93,87.63) ; RZ73.2 R1477.2 116.84,74.32 v1(116.87,74.3)
  IN1 w0.254: v1(116.87,74.3) 117.63,74.3 118.39,75.06 125.37,75.06 127.66,77.34 131.72,77.34 134.14,79.76 134.14,83.19 135.53,84.58 135.53,86.23 v1(136.93,87.63)
  BOTTOM w0.203: U76.8 136.58,87.15 136.93,87.5 v1(136.93,87.63)
+V5SB_EN#: length 5.1
  TOP w0.107: Q13.G 121.02,71.49 RB51.1 121.58,71.53 121.69,71.63 121.69,72.39 123.16,73.86 U14.7
+V5SB_GND: length 5
  TOP w0.508: R691.1 133.5,87.02 v1(133.5,87.63) 133.03,88.1 C405.2 132.87,88.55 S6.1
  BOTTOM w0.203: v1(133.5,87.63) 133.67,87.63 134.18,87.11 U76.2
  BOTTOM w0.305: v1(133.5,87.63) 133.5,88.37 R692.1
+V5SB_PGOOD: length 3.2
  BOTTOM w0.305: U76.9 137.08,86.89 137.85,87.66 R688.2 R687.1
+V12S_PGOOD: length 1.6
  TOP w0.107: RB23.1 51.3,150.58 U92.10
+V12SB: length 13.7
  TOP w0.508: R722.2 55.88,149.76 R721.2 v1(57.51,149.76) ; 58.75,164.67 58.7,164.72 R669.1 ; RB23.2 v1(52.43,151.38)
  BOTTOM w0.508: v1(149,98.5) 149.1,98.6 149.22,98.6 R696.2 ; v1(52.43,153.67) v1(52.43,151.38) 54.05,149.76 v1(57.51,149.76)
  vias: v1(134.32,117.73) v1(135.43,117.73) v1(145.82,97.87) v1(145.82,97.28) v1(146.46,98.5) v1(146.46,97.92) v1(146.46,97.28) v1(147.09,98.5) v1(147.09,97.92) v1(147.09,97.28) v1(147.35,87.63) v1(147.35,83.31) v1(147.73,98.5) v1(147.73,97.92) v1(147.98,87.63) v1(147.98,83.31) v1(148.36,98.5) v1(148.36,97.92) v1(148.62,87.63) v1(148.62,83.31) v1(149,97.92) v1(149.25,87.63) v1(149.25,83.31) v1(149.5,97.28) v1(149.5,96.65) v1(149.89,87.63) v1(149.89,83.31) v1(150.52,87.63) v1(150.52,87) v1(150.52,86.36) v1(150.52,85.72) v1(150.52,85.09) v1(150.52,84.45) v1(150.52,83.82) v2(53.29,163.02) v2(53.29,162.13) v2(53.29,161.24) v2(54.18,163.02) v2(54.18,162.13) v2(54.18,161.24) v2(55.07,163.02) v2(55.07,162.13) v2(55.07,161.24) v2(55.96,163.02) v2(55.96,162.13) v2(55.96,161.24) v2(56.85,163.02) v2(56.85,162.13) v2(56.85,161.24) v2(57.73,163.02) v2(57.73,162.13) v2(57.73,161.24) v2(58.62,163.02) v2(58.62,162.13) v2(58.62,161.24) v2(64.59,163.91) v2(64.59,163.02) v2(64.59,162.13) v2(64.59,161.24) v2(65.48,163.91) v2(65.48,163.02) v2(65.48,162.13) v2(65.48,161.24) v2(66.37,163.91) v2(66.37,163.02) v2(66.37,162.13) v2(66.37,161.24)
+VIN_PSON#: length 6.7
  TOP w0.254: Q66.3 4.87,84.18 R1506.1
  TOP w0.508: Q65.4 8.33,84.4 8.1,84.18 R1506.1
AGND: length 16.8
  TOP w0.381: CA54.2 140.3,140.6 v1(139.85,141.05) ; C42.2 v1(137.03,141.58)
  TOP w0.508: VS1.2 150.91,142.65 v1(150.46,142.65)
  BOTTOM w0.203: U16.9 145.09,143.78 v1(145.16,143.71) ; U16.25 138.01,142.58 137.16,141.73 137.16,141.71 v1(137.03,141.58) ; v1(139.85,141.05) 139.95,141.15 U16.22
  BOTTOM w0.381: CA16.2 v1(148.08,140.72) ; CA15.2 v1(148.08,141.86)
  BOTTOM w0.508: C54.2 v1(149.58,142.37) ; RZ154.1 v1(151.38,150.75) ; CA131.2 C40.2 v1(148.08,147.96) ; C38.2 144.25,138.46 143.98,138.72 CA134.2 v1(143,138.72) ; CA132.2 v1(147.23,143.98) ; RZ153.1 v1(151.38,151.89) ; C839.2 v1(152.91,154.14) ; C838.2 v1(152.91,156.3) ; CA14.2 v1(148.84,149.48)
  vias: v1(137.03,140.94) v1(150.46,142.02)
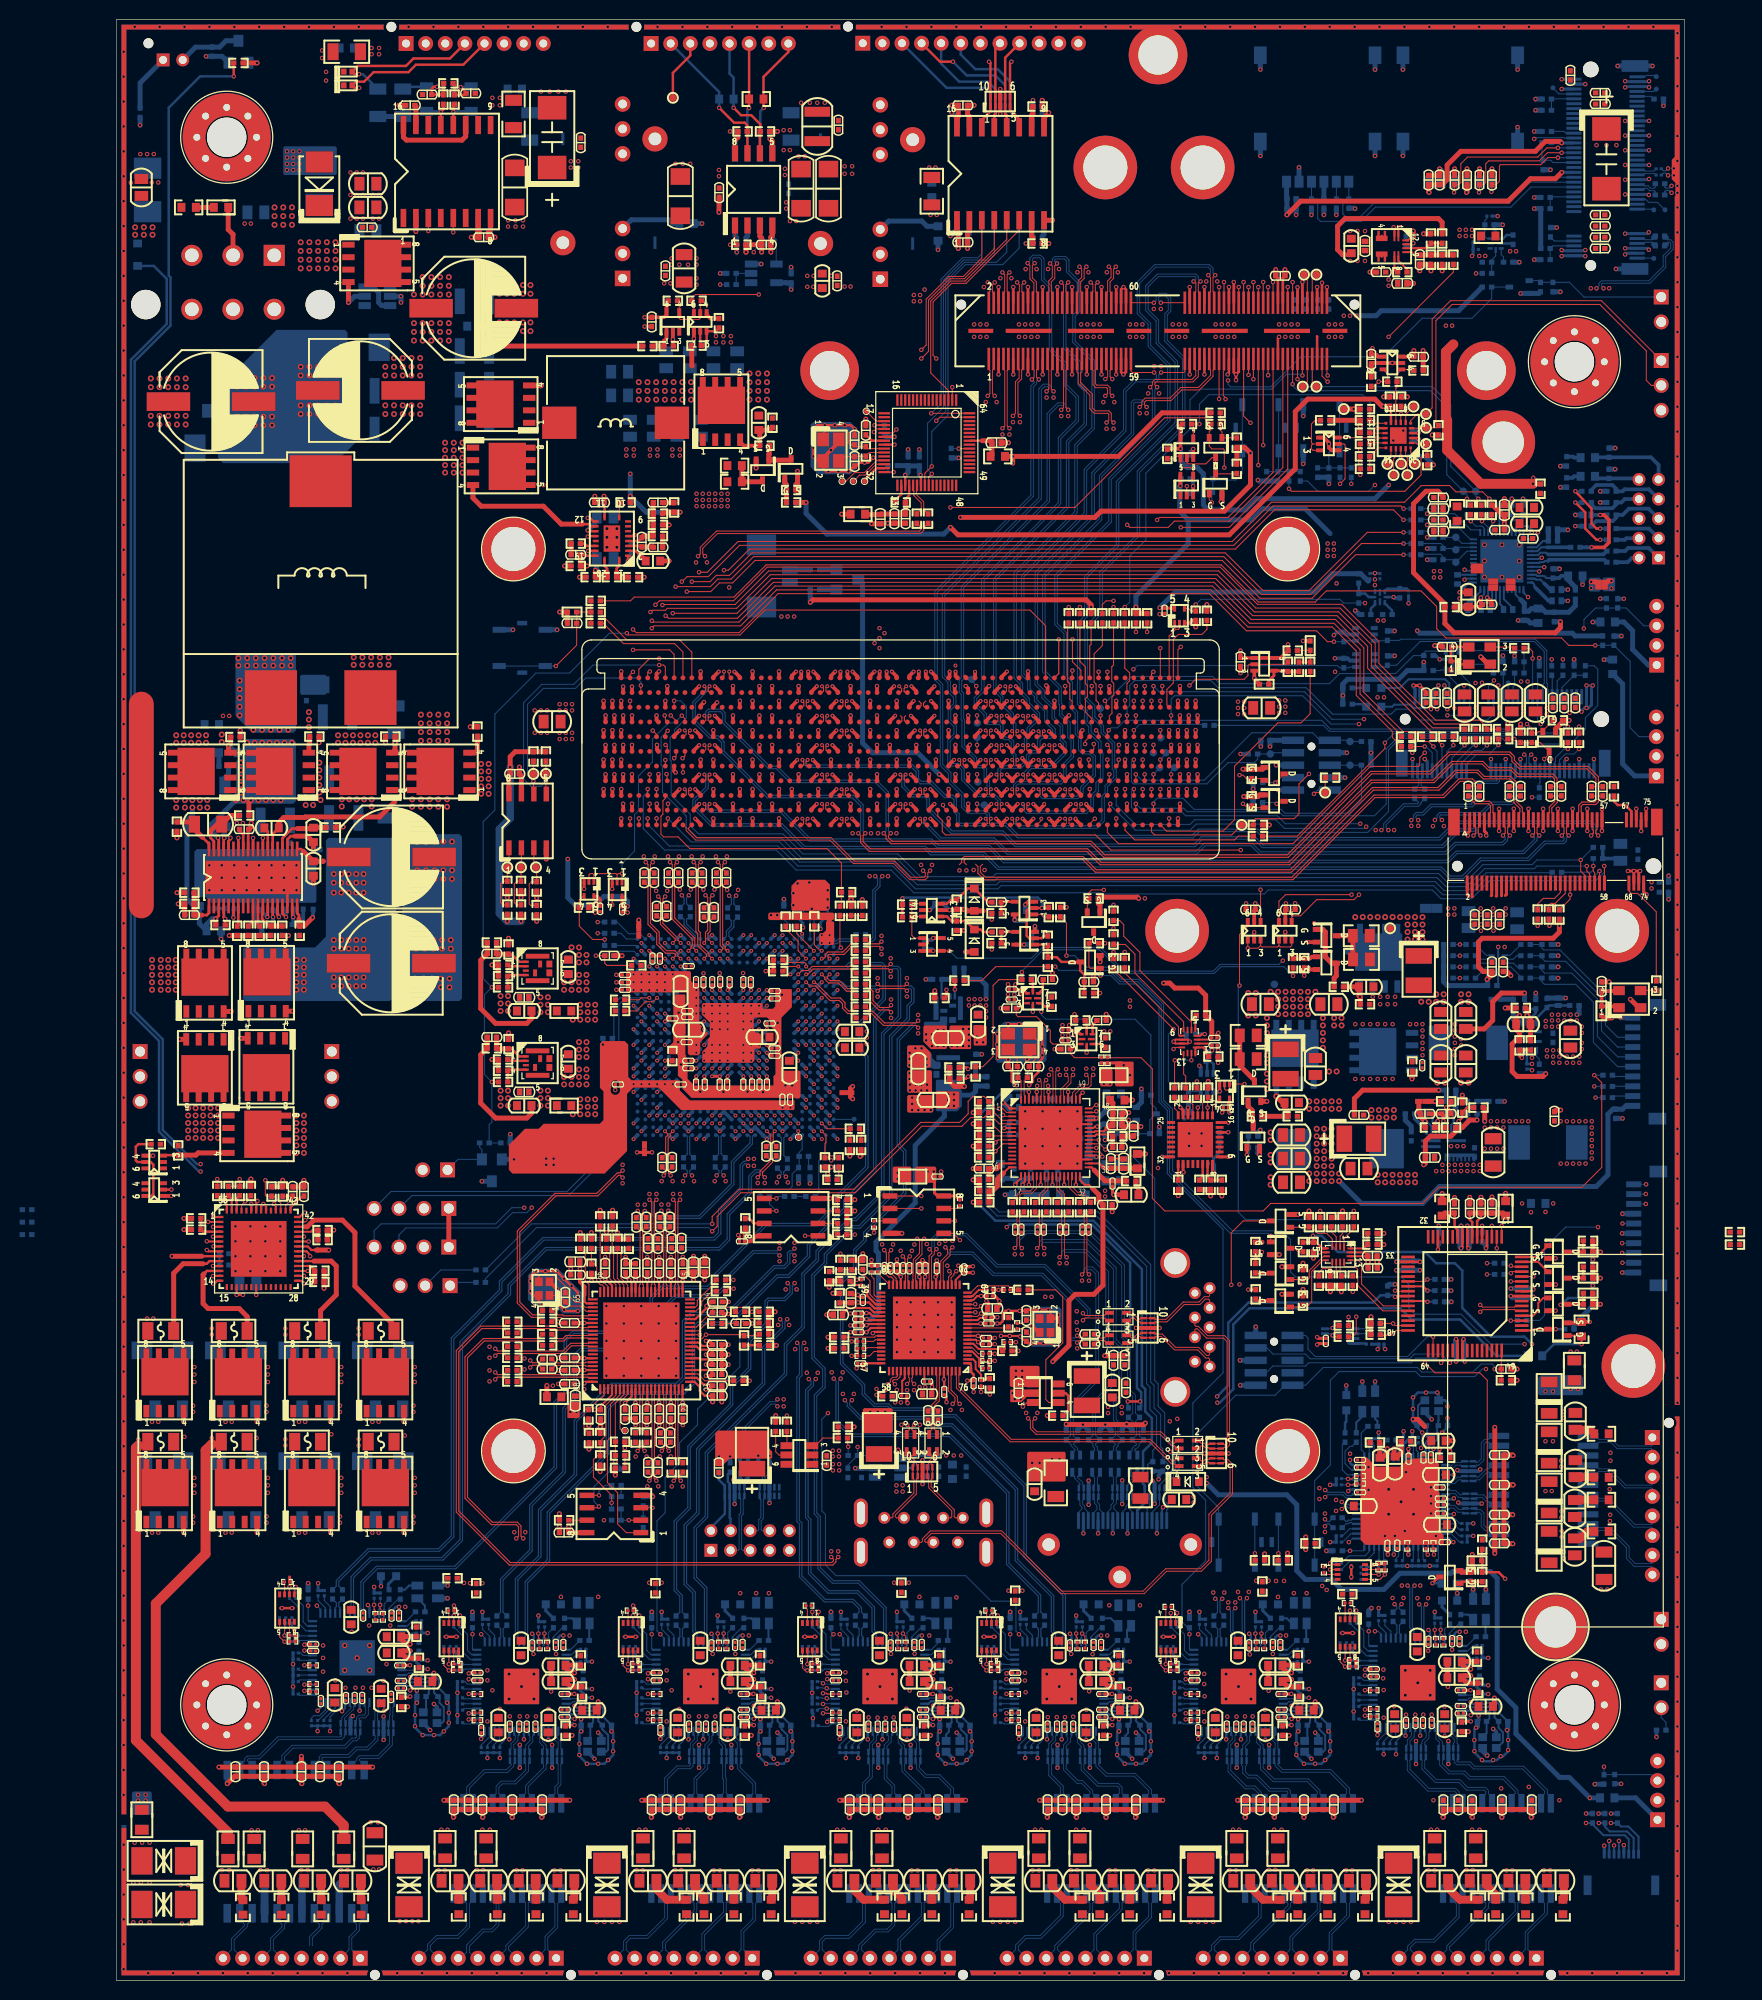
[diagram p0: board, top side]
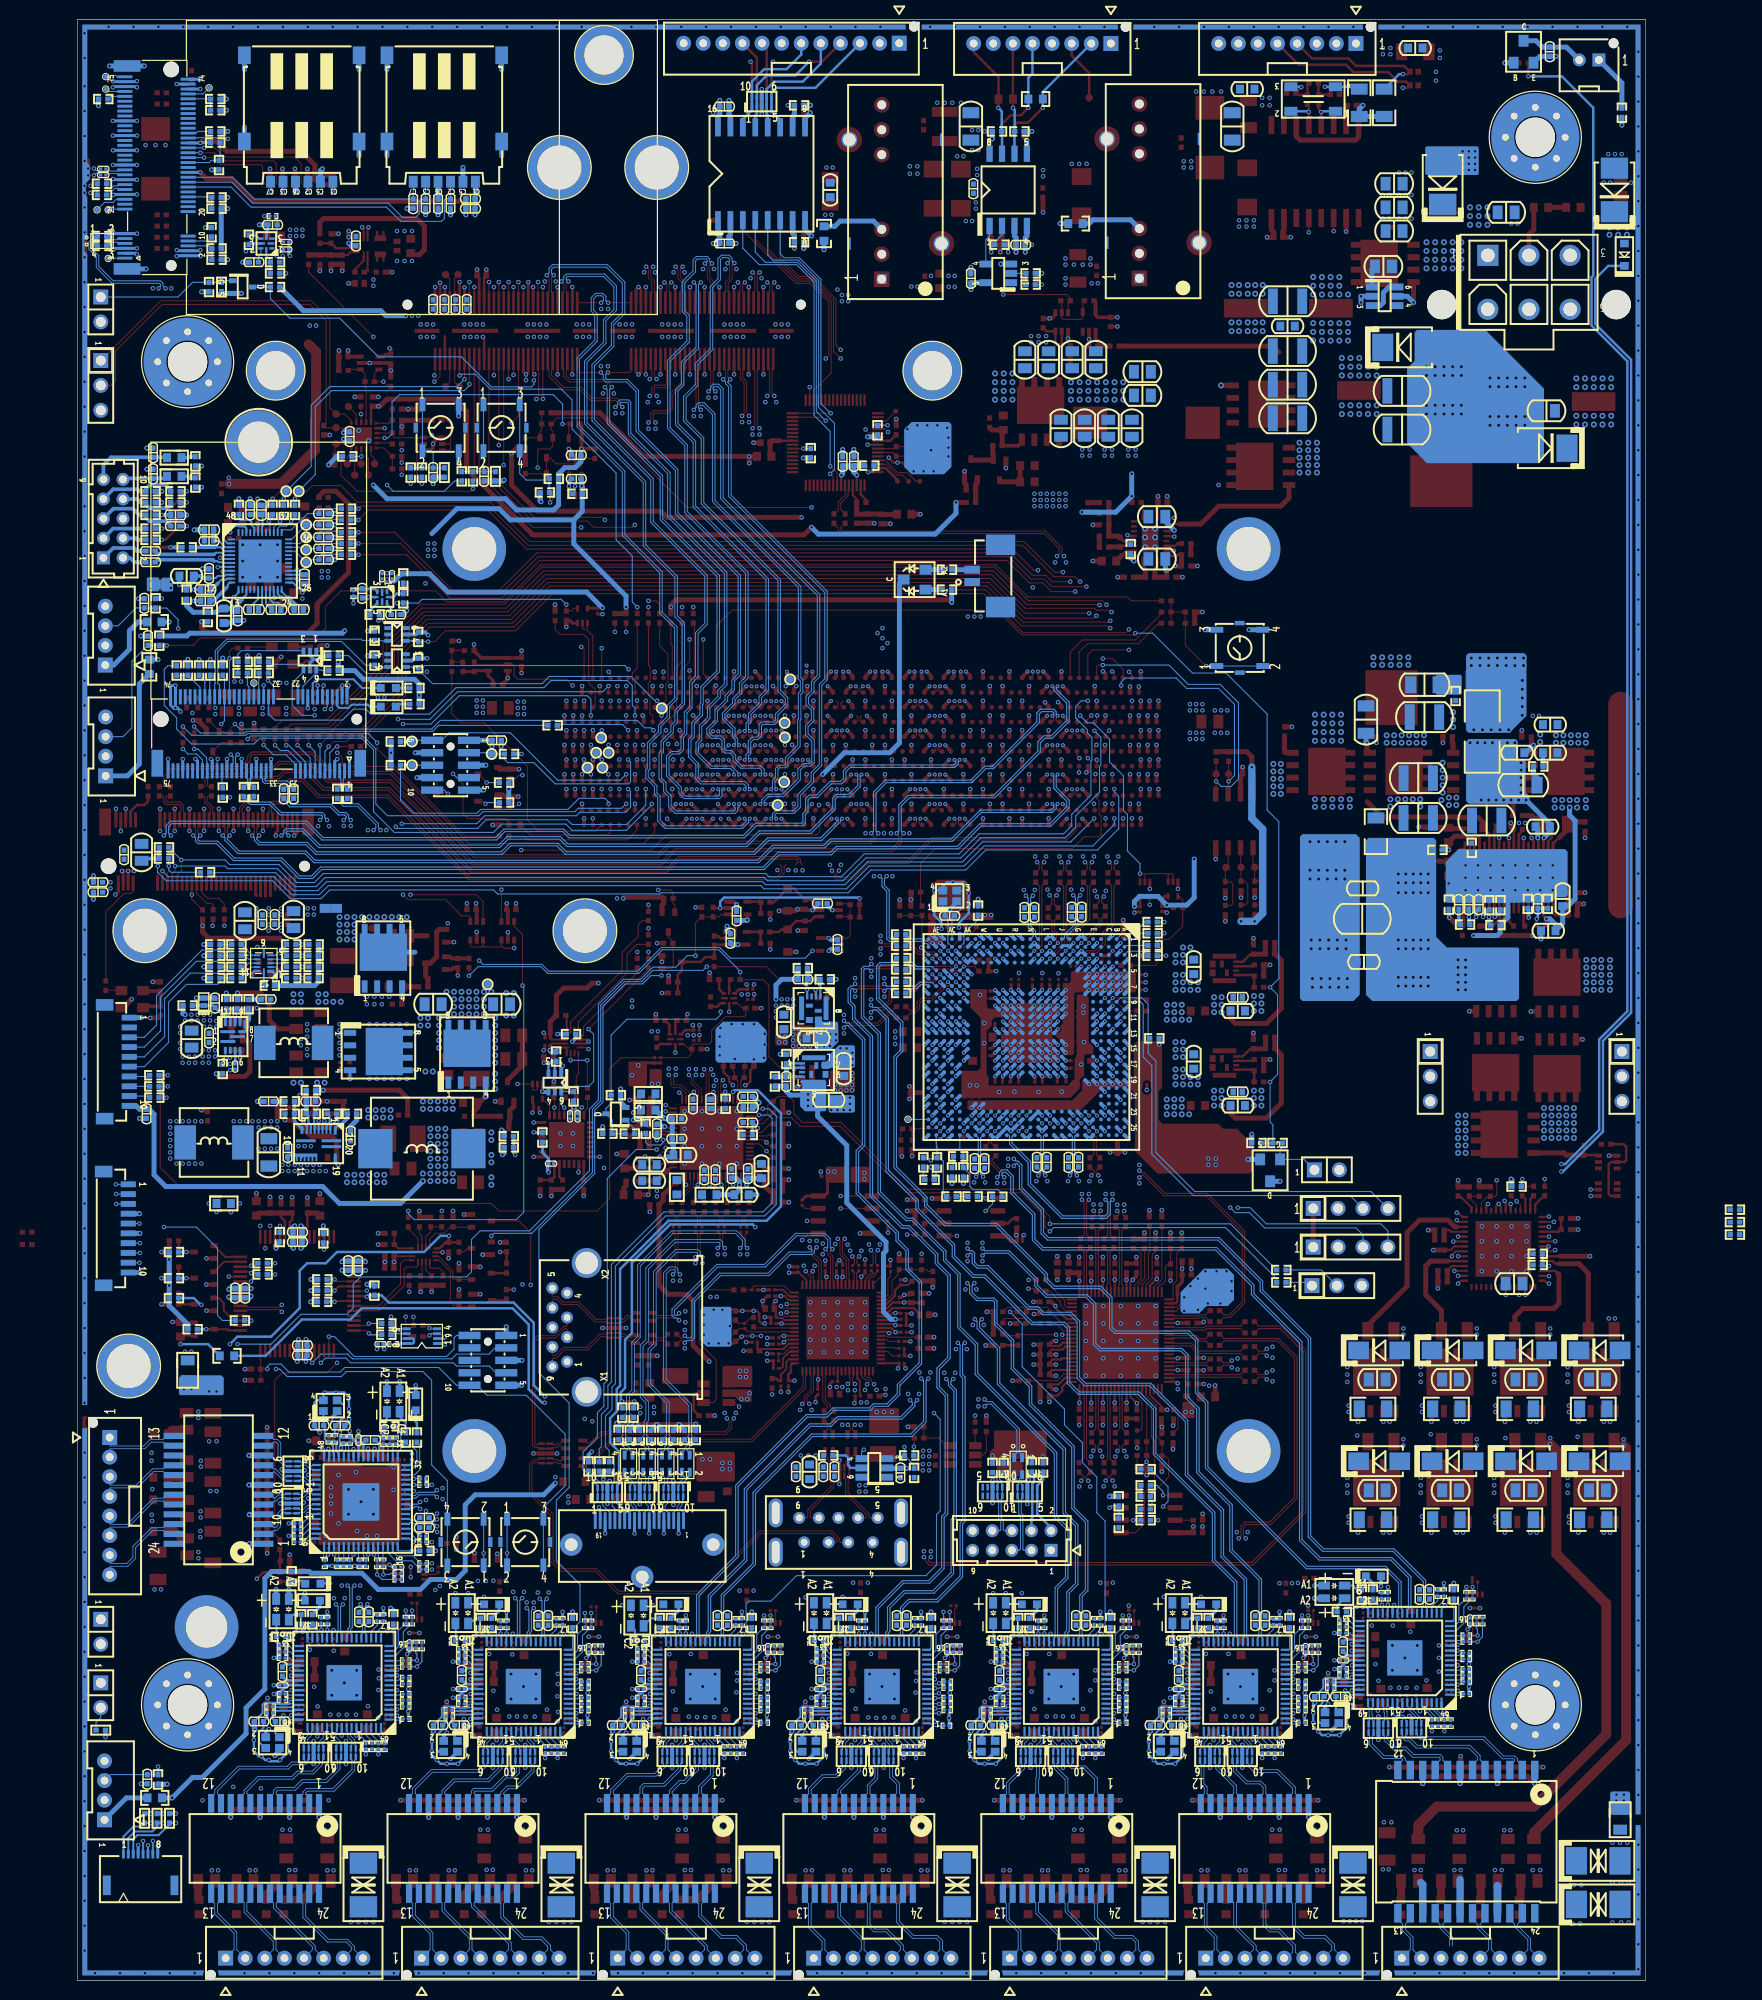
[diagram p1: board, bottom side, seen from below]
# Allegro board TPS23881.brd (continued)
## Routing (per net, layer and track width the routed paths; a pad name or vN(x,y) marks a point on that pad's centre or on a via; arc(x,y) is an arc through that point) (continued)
AVDD33_HUB: length 10
  TOP w0.203: CA29.1 86.42,72.25 85.62,71.45 U20.21 ; CA30.1 80.16,59.68 80.16,61.14 80.42,61.4 U20.62 ; U20.1 86.99,62.95 87.2,62.74 87.2,62.43 ; U20.11 88.11,66.95 v1(88.16,67)
  TOP w0.254: CA25.1 87.45,61.8 87.2,62.05 87.2,62.43
  TOP w0.305: CA25.1 v1(86.82,61.18) ; CA32.1 88.22,67.01 88.21,67 v1(88.16,67) ; v1(87.38,72.19) 86.55,72.19 CA29.1
  vias: v1(79.45,58.95) v1(80.04,58.95)
AVDD_CAM_2V8: length 23.3
  TOP w0.203: v1(132.31,177.8) 132.08,177.8 131.77,177.48 U34.12
  TOP w0.279: v1(114.22,163.8) v1(114.22,163.22) ; v1(114.22,163.8) 114,164.03 J14.81 ; v1(114.22,163.8) 114.5,164.08 J14.83 ; J14.82 v1(114,173.23)
  TOP w0.508: R246.2 135.25,179.32 134.87,179.71 125.35,179.71 124.59,178.94 124.59,176.53 125.09,176.02 125.35,176.02 ; v1(132.31,177.8) v1(132.31,178.44)
  vias: v1(125.86,175.39) v1(126.62,175.39) v1(127.38,175.39)
DVDD10_HUB: length 8.2
  TOP w0.203: CA42.1 88.63,67.56 88.08,67.56 87.87,67.35 U20.12
  TOP w0.229: U20.47 76.65,66.95 v1(76.53,66.83) ; CA44.1 76.01,68.07 v1(76.53,68.07) 76.84,68.07 77.16,67.75 U20.45
  TOP w0.254: CA43.1 76.45,66.8 76.48,66.83 v1(76.53,66.83) ; CA42.1 88.71,68.16 88.89,68.34 C499.1
  TOP w0.305: C499.1 88.98,68.62 88.98,69.08 v1(88.76,69.29)
DVDD33_HUB: length 10
  TOP w0.203: U20.7 87.66,65.35 v1(87.91,65.1) 88.11,64.9 CA31.1 ; U20.17 87.25,69.35 87.31,69.4 87.42,69.4 87.82,69.8 v1(88.21,69.8)
  TOP w0.229: v1(81.92,71.75) 82.02,71.65 U20.30 ; C59.1 74.96,69.15 v1(75.64,69.15) CA28.1 76.77,69.15 77.37,68.55 U20.43
  TOP w0.305: RZ79.2 73.8,69.13 C59.1 ; CA27.1 v1(88.21,69.8) ; CA33.1 v1(81.92,71.75)
DVDD_CAM_LV: length 15.7
  TOP w0.279: J14.57 103,164.06 v1(102.74,163.8) 102.5,164.05 J14.55 ; J14.58 103,172.46 v1(102.74,172.72) 102.5,172.48 J14.56
  IN1 w0.508: v1(102.74,163.8) v1(102.74,172.72)
GND: length 1417.8
  TOP w0.203: U66.19 v1(93.09,81.15) ; U34.1 130.79,178.67 v1(130.94,178.82) ; U66.25 v1(95.49,81.15) ; v1(132.31,177.19) 132.2,177.08 U34.11 ; U66.35 98.47,83.73 v1(98.04,83.31) ; U34.2 130.39,178.73 v1(130.3,178.82) ; U14.6 v1(122.73,74.26) ; U66.31 v1(97.89,81.15) ; v1(90.25,65.74) v1(91.14,65.74) 92.15,65.74 v1(92.21,65.67) 92.7,65.19 C58.2 ; U66.44 96.69,87.33 U66.65 ; U86.11 109.3,95.56 v1(109.5,95.76) 109.3,95.96 U86.10 108.05,95.96 v1(107.85,95.76) 108.05,95.56 U86.11
  TOP w0.229: CA37.2 75.63,62.55 v1(75.51,62.43) ; U65.46 16.26,79.01 v1(16.08,79.2) ; U65.49 14.76,78.97 v1(14.99,79.2) 15.03,79.2 15.26,78.97 U65.48 ; U65.21 v1(14.26,69.93) ; U25.25 v1(79.38,156.65)
  TOP w0.254: v1(87.45,60.02) CA25.2 ; v1(136.68,63.12) 136.83,63.27 U13.55 136.83,65.26 v1(136.68,65.41) ; v1(118.62,167.64) 118.5,167.52 J14.99 ; v1(74.88,66.8) CA43.2 CA26.2 CA44.2 v1(74.88,68.02) ; v1(96.52,96.42) 96.52,95.92 C431.2 ; v1(90.96,100.58) 90.96,100.16 C430.2 ; CB11.2 96.56,97.4 v1(96.52,97.43) ; v1(47.07,68.28) 45.8,68.28 v1(45.67,68.4) 45.03,69.04 v1(44.65,69.04) v1(43.38,69.04) 43.34,69.04 43.09,69.29 X11.4 42.49,69.86 42.24,70.12 v1(42.24,70.31) v1(42.24,71.32) 42.24,71.83 v1(42.75,72.34) v1(43.76,72.34) v1(44.91,72.34) 44.91,72.34 v1(45.67,71.58) v1(46.43,70.82) 47.07,70.18 v1(47.07,69.67) ; J14.115 122.5,167.67 122.48,167.69 ; U6.3 132.74,157.32 v1(132.84,157.23) ; CB19.2 112.92,88.63 v1(112.8,88.52) ; CA40.2 84.68,59.52 v1(84.68,58.98) ; C58.2 93.05,64.97 v1(93.55,64.97) v1(94.56,64.97) v1(95.58,64.97) 96.09,65.48 v1(96.09,65.86) v1(96.09,66.88) v1(96.09,67.89) 95.7,67.5 X1.2 95.29,68.2 v1(95.08,68.41) v1(94.18,68.41) 92.96,68.41 C57.2 v1(92.15,68.29) v1(91.01,68.29) 90.68,68.29 90.43,68.03 90.43,67.26 90.18,67.01 v1(89.87,67.01) ; J14.23 v1(94.5,163.8) ; J14.41 v1(99,163.8) ; J14.47 v1(100.5,163.8) ; v1(91.85,91.31) 91.72,91.31 91.34,91.69 91.34,92.85 C295.2 ; v1(52.86,147.42) 52.75,147.32 U92.6 ; v1(113.37,163.8) 113.5,163.93 J14.79 ; v1(75.01,65.18) R167.2 ; v1(144.55,70.48) 144.36,70.3 U13.9 ; v1(137.19,74.68) 137.33,74.82 U13.25 137.33,76.82 v1(137.19,76.96) ; v1(90.96,101.6) 91.07,101.49 CB10.2 ; U6.12 v1(128.65,158.32) ; U92.12 48.67,148.82 48.31,149.17 v1(48.08,149.17) ; U80.4 v1(93.5,98.81) ; U13.20 139.83,74.78 v1(139.73,74.68) ; RA8.2 v1(91.77,65.1) ; v1(48.08,147.27) 48.13,147.32 U92.15 ; v1(14.39,79.5) 14.26,79.38 U65.50 ; v1(90.97,93.94) 90.81,94.11 v1(89.94,94.11) 89.87,94.18 v1(89.87,95.47) v1(89.87,96.56) Y2.2 v1(90.97,97.54) v1(92.1,97.54) v1(93.24,97.54) 94.01,97.54 v1(94.39,97.16) 94.49,97.05 94.49,96.29 v1(94.47,96.27) v1(94.47,95.25) v1(94.47,94.36) 94.47,94.03 94.07,93.64 C293.2 94.07,92.65 93.5,92.08 93.5,91.69 v1(93.12,91.31) ; J14.63 v1(109.5,163.8) ; v1(77.22,155.32) 76.71,154.81 v1(76.33,154.81) 75.82,154.81 75.48,154.47 C72.2 74.76,153.92 v1(74.68,153.92) v1(73.66,153.92) v1(72.64,153.92) 72.39,153.92 72.1,154.22 Y1.2 71.59,154.98 v1(71.12,155.45) v1(71.12,156.34) v1(71.12,157.35) 71.12,158.24 v1(71.25,158.37) 71.5,158.62 v1(72.26,158.62) v1(73.28,158.62) v1(74.3,158.62) 74.93,158.62 v1(75.31,158.24) C73.2 ; U65.51 v1(13.76,79.2) ; J14.35 v1(97.5,163.8) ; J14.29 v1(96,163.8) ; J14.69 v1(111,163.8) ; J14.53 v1(102,163.8) ; U81.4 v1(98.98,94.64) ; CA36.2 v1(74.88,66.12)
  TOP w0.279: J14.70 v1(111,172.72) ; J14.54 v1(102,172.72) ; J14.48 v1(100.5,172.72) ; CA60.2 13.44,117.36 U83.30 ; J14.80 v1(113.5,172.72) ; J14.36 v1(97.5,172.72) ; J14.5 v1(90,163.8) ; J14.100 118.5,173.64 C136.2 118.15,173.99 ; J14.24 v1(94.5,172.72) ; J14.18 v1(93,172.72) ; J14.17 v1(93,163.8) ; J14.116 v1(122.5,172.72) ; J14.6 v1(90,172.72) ; J14.30 v1(96,172.72) ; J14.64 v1(109.5,172.72) ; J14.11 v1(91.5,163.8) ; J14.42 v1(99,172.72) ; J14.12 v1(91.5,172.72)
  TOP w0.305: CB12.2 112.28,96.51 v1(112.42,96.65) ; 91.4,125.45 J1.F44 ; 91.4,125.45 v3(90.85,126) ; 91.4,125.45 v3(91.95,126) ; CA22.2 84.15,82.11 v1(84.15,82.5) ; SSD2.75 v1(156.06,119.51) ; v1(63.44,76.02) 63.56,75.9 CB29.2 ; U18.16 v1(113.44,87.51) ; SSD2.3 138.06,117.23 137.87,117.04 v1(137.87,116.78) 137.56,117.09 SSD2.1 ; v1(141.06,117.24) SSD2.15 v1(141.06,119.51) ; C341.2 C344.2 54.69,104.69 v3(54.36,105.02) ; v3(94.65,126) 94.1,125.45 ; 94.1,125.45 J1.F47 ; 94.1,125.45 v3(93.55,126) ; CA32.2 CA42.2 v1(89.87,67.64) ; v1(151.56,117.24) SSD2.57 v1(151.56,119.51) ; U18.2 108.82,82.46 v1(108.86,82.42) ; CA27.2 89.62,69.8 90.08,69.34 v1(90.08,69.29) 90.08,68.78 C499.2 ; C345.2 v1(51,101.8) ; CB15.2 v1(50.89,90.82) ; CA33.2 81.92,73.13 v1(82.25,73.46) 82.55,73.15 CA35.2 ; U18.32 v1(106.71,84) ; v1(139.75,116.78) 139.75,117.04 139.56,117.23 SSD2.9 ; CB4.2 52.08,108.98 v1(52.15,108.92) ; C891.2 122.62,64.96 v1(122.5,64.85) ; v1(106.43,139.36) 106.86,139.36 CB2.2 ; CB20.1 101.63,80.26 v1(101.75,80.14) ; v1(144.06,117.24) SSD2.27 v1(144.06,119.51) ; SSD2.71 v1(155.06,119.51) ; v1(147.06,117.24) SSD2.39 v1(147.06,119.51) ; v1(145.56,117.24) SSD2.33 v1(145.56,119.51) ; v1(53.11,84.46) S5.1 v1(54.64,84.46) ; U3.3 v1(47.71,111.33) ; SSD2.73 v1(155.56,117.23) ; C61.2 83.21,59.86 v1(83.21,60.53) 83.21,60.85 CA41.2 ; C59.2 75.07,69.93 v1(75.64,69.93) 75.88,69.68 CA28.2 ; v1(150.06,119.51) SSD2.51 v1(150.06,117.24) ; U4.3 109.47,138.44 109.74,138.71 R24.2 ; U19.3 v1(112.56,90.68) ; CA39.2 v1(89.61,65.53) ; U5.3 v1(50.58,111.33) ; R168.2 v1(89.61,63.92) ; v1(87.38,72.83) 87.05,72.83 87,72.78 CA29.2 ; C360.2 v1(51,102.57) ; v1(108.53,89.05) 108.82,88.76 U18.23 ; v1(80.72,58.88) 80.63,58.97 CA30.2 ; RA7.2 v1(75.51,71.46) ; v1(148.56,117.24) SSD2.45 v1(148.56,119.51) ; v1(48.84,108.92) 48.96,109.03 CB3.2 ; CB13.2 112.31,94.98 v1(112.42,94.87) ; v1(142.56,119.51) SSD2.21 v1(142.56,117.24) ; CA34.2 v1(79.63,73.53) ; CA38.2 v1(83.69,73.43) ; CA31.2 v1(89.61,64.9) ; 112.39,93.85 v1(112.39,93.6) ; C348.2 v1(51,101.04) ; U18.9 v1(113.44,84)
  TOP w0.356: CA45.2 v1(53.89,168.69)
  TOP w0.381: J1.H30 v1(77.6,129.02) ; J1.C20 v1(67.6,121.52) ; Q10.S 149.39,67.07 R87.2 v1(150.29,67.16) ; J1.F11 58.9,125.44 v3(59.45,126) ; v1(62.41,67.97) 61.94,67.97 C369.2 ; J1.K48 95,131.95 v1(94.87,132.08) ; J1.B14 61.6,119.45 v3(61.05,120) ; v1(61.28,130.35) 60.9,129.97 J1.J13 ; J1.E25 v1(72.9,124.52) ; 96.8,122.45 v3(97.35,123) ; 96.8,122.45 v3(96.25,122.99) ; 96.8,122.45 J1.D50 ; J1.B38 85.6,119.45 v3(85.05,120) ; J1.D18 v1(65.6,123.02) ; J1.K39 86.9,131.77 v1(86.65,132.02) ; J1.H15 v1(62.9,129.02) ; J1.E12 v1(59.6,124.52) ; v3(89.25,120) 88.7,119.45 J1.B41 ; J1.G36 83.6,126.95 v3(83.05,127.5) ; J1.H4 v1(52.6,129.02) ; CM7.2 CM14.2 v1(51.94,73.79) ; v1(90.22,99.16) CM44.2 ; J1.J37 v1(84.9,130.52) ; J1.A32 v1(79.6,118.52) ; CM9.2 v1(45.09,63.5) ; J1.F35 v1(82.9,126.02) ; J1.H41 88.7,128.44 v3(89.25,128.99) ; 93,123.94 93,124.02 92.43,124.59 v3(92.43,124.66) ; 93,123.94 J1.E46 ; 93,123.94 v3(93.55,124.5) ; v3(83.11,130.5) 83.6,130 J1.J36 ; J1.K35 82.9,131.44 v3(83.45,132) ; J1.C40 87.6,120.94 v3(88.15,121.5) ; v3(90.85,124.5) 90.3,123.94 ; 90.3,123.94 90.3,123.95 v3(89.75,124.5) ; 90.3,123.94 J1.E43 ; v1(52.96,56.64) CM16.2 51.94,57.32 CM11.2 ; v1(102.33,129.02) 102.2,128.89 J1.H56 ; v3(88.15,130.5) 87.6,129.94 J1.J40 ; J1.J25 72.9,129.94 v3(73.45,130.5) ; v3(91.95,128.99) 91.91,128.99 91.4,128.48 91.4,128.45 ; v3(73.05,122.99) 73.6,122.45 J1.D26 ; J1.E24 71.6,123.95 v3(71.05,124.5) ; v1(57.05,123.22) 56.9,123.36 J1.E9 ; J1.C62 v1(107.4,121.52) ; CM2.2 CM5.2 v1(62.43,64.85) ; CM2.2 v1(62.43,63.83) ; CM2.2 CM20.2 ; J1.H39 v1(86.9,129.02) ; v3(90.85,120) 91.4,119.45 ; 91.4,119.45 J1.B44 ; 91.4,119.45 v3(91.95,120) ; J1.E49 95.7,123.95 v3(95.15,124.5) ; J1.C28 75.6,120.95 v3(75.05,121.5) ; J1.H23 70.9,128.44 v3(71.45,128.99) ; J1.E28 v1(75.6,124.52) ; J1.E57 v1(102.9,124.52) ; J1.L29 76.9,133.06 v3(77.33,133.5) ; 93,117.94 93,117.95 v3(92.45,118.5) ; 93,117.94 J1.A46 ; 93,117.94 v3(93.55,118.5) ; J1.H19 v1(66.9,129.02) ; v3(59.05,127.5) 59.6,126.95 J1.G12 ; J1.J33 80.9,130.06 v3(81.33,130.5) ; U91.3 93.04,110.03 v1(92.74,109.73) ; 93,126.94 J1.G46 ; 93,126.94 93.08,126.94 v3(93.55,127.41) ; 93,126.94 92.91,126.94 v3(92.45,127.41) ; J1.D63 v1(108.5,123.02) ; J1.L7 55.1,133.26 v1(55.35,133.52) ; v3(85,133.5) 85,132.96 J1.L37 ; 95.7,120.95 J1.C49 ; 95.7,120.95 v3(96.25,121.5) ; 95.7,120.95 v3(95.15,121.5) ; J1.E52 98.27,123.99 v1(98.27,124.52) ; Q33.4 60.21,169.9 60.59,169.52 v1(60.81,169.52) R673.2 ; 94.1,122.45 J1.D47 ; 94.1,122.45 v3(93.55,122.99) ; 94.1,122.45 v3(94.65,122.99) ; CM10.2 v1(45.09,60.83) ; J1.F23 70.9,125.44 v3(71.45,126) ; CM19.2 v1(54.15,73.79) ; v3(87.6,133.48) J1.L40 ; J1.H50 96.8,128.65 v1(97.18,129.03) ; J1.C17 v1(64.9,121.52) ; J1.A28 75.6,117.95 v3(75.05,118.5) ; J1.J16 v1(63.6,130.52) ; v3(89.75,130.5) 90.3,129.95 90.3,129.94 ; v3(79.11,133.5) 79.6,133 J1.L32 ; J1.A21 68.9,117.94 v3(69.45,118.5) ; v3(73.33,133.5) 72.9,133.06 J1.L25 ; J1.C36 83.6,120.95 v3(83.05,121.5) ; v1(93.42,66.75) 94.07,66.1 X1.4 ; v3(81.45,121.5) 80.9,120.94 J1.C33 ; v3(59.05,118.5) 59.6,117.95 J1.A12 ; v3(61.05,123) 61.6,122.45 J1.D14 ; J1.J24 71.6,129.95 v3(71.05,130.5) ; J1.G3 v1(51.5,127.52) ; J1.B19 v1(66.9,120.02) ; J1.F26 73.6,125.45 v3(73.05,126) ; CA56.2 v1(114.68,133.35) ; J1.C9 56.9,120.94 v3(57.45,121.5) ; J1.H22 v1(69.6,129.02) ; J1.B34 81.6,119.45 v3(81.05,120) ; v3(59.45,128.99) 58.9,128.44 J1.H11 ; v1(44.91,70.56) 44.21,71.26 X11.2 ; v3(75.05,130.5) 75.6,129.95 J1.J28 ; J1.E62 v1(107.4,124.52) ; J1.G25 72.9,126.94 v3(73.45,127.5) ; J1.D34 81.6,122.45 v3(81.05,122.99) ; J1.K41 88.7,131.69 v1(89.03,132.02) ; R665.2 56.77,166.75 v1(56.77,167.39) U75.2 ; U33.3 v1(116.09,132.84) 116.09,132.72 Z8.1 ; J1.H31 78.9,128.44 v3(79.45,128.99) ; J1.L46 v1(93,133.52) ; CM3.2 45.21,67.06 v1(45.09,67.18) ; Q2.1 123.18,157.37 123.7,156.84 v1(123.7,156.72) 123.7,156.34 123.97,156.07 Q2.4 ; CM23.2 v1(54.1,56.64) ; J1.J32 v1(79.6,130.52) ; J1.F27 v1(74.9,126.02) ; C308.2 101.8,83.78 v1(102.06,84.04) 102.31,83.78 C307.2 ; v3(57.45,127.5) 56.9,126.94 J1.G9 ; v3(83.45,128.99) 82.9,128.44 J1.H35 ; CM21.2 v1(56.57,56.64) ; R1482.2 v1(96.93,109.45) ; 91.4,128.45 v3(90.85,128.99) ; 91.4,128.45 J1.H44 ; v3(90.85,121.5) 90.3,120.94 ; 90.3,120.94 J1.C43 ; 90.3,120.94 90.3,120.95 v3(89.75,121.5) ; 95.7,117.95 J1.A49 ; 95.7,117.95 v3(95.15,118.5) ; 95.7,117.95 v3(96.25,118.5) ; J1.D27 v1(74.9,123.02) ; J1.D57 v1(103.1,123.02) ; v3(97.85,121.5) 98.4,120.95 J1.C52 ; v3(90.15,132) 89.6,131.44 J1.K42 ; U7.5 v1(130.18,164.97) U7.2 128.23,164.97 CA47.1 ; J1.A25 72.9,117.94 v3(73.45,118.5) ; v3(89.25,122.99) 88.7,122.44 J1.D41 ; v3(61.05,126) 61.6,125.45 J1.F14 ; v3(81.33,133.5) 80.9,133.06 J1.L33 ; R31.2 v1(126.9,154.81) ; J1.G29 v1(76.9,127.52) ; v3(79.33,132) 78.9,131.56 J1.K31 ; v3(92.45,130.5) 93,129.95 J1.J46 ; J1.J49 v1(95.7,130.52) ; J1.E17 v1(64.9,124.52) ; v3(69.45,130.5) 68.9,129.94 J1.J21 ; J1.G20 v1(67.6,127.52) ; 90.3,129.94 J1.J43 ; 90.3,129.94 v3(90.85,130.5) ; v3(59.45,123) 58.9,122.44 J1.D11 ; J1.G57 v1(102.9,127.52) ; CA63.1 v1(120.26,109.86) ; J1.A24 71.6,117.95 v3(71.05,118.5) ; J1.H47 94.1,128.45 v3(93.55,128.99) ; J1.C21 v1(68.9,121.52) ; 91.4,122.45 91.4,122.49 91.91,122.99 v3(91.95,122.99) ; 91.4,122.45 J1.D44 ; 91.4,122.45 v3(90.85,122.99) ; J1.F7 55.15,125.51 v1(55.15,126.02) ; J1.E29 v1(76.9,124.52) ; v1(111.05,53.75) D5.3 D5.8 v1(113.46,53.75) ; CA72.2 v1(49.86,73.79) ; J1.C25 72.9,120.94 v3(73.45,121.5) ; J1.B53 98.95,119.91 v3(98.95,120) ; J1.L17 v1(64.9,133.52) ; J1.K34 81.6,131.5 v3(81.11,132) ; J1.F57 v1(103.1,126.02) ; J1.G17 v1(64.9,127.52) ; v3(63.05,133.5) 63.6,132.95 J1.L16 ; 90.3,126.94 J1.G43 ; 90.3,126.94 90.3,126.95 v3(89.75,127.5) ; 90.3,126.94 90.38,126.94 v3(90.85,127.41) ; J1.H26 73.6,128.45 v3(73.05,128.99) ; CA73.2 v1(62.46,69.22) ; v3(69.45,124.5) 68.9,123.94 J1.E21 ; C370.2 v1(64.85,67.01) ; U88.2 v1(119.25,106.93) ; J1.F22 v1(69.6,126.02) ; J1.A36 83.6,117.95 v3(83.05,118.5) ; U9.3 v1(93.71,107.53) ; J1.A40 87.6,117.94 v3(88.15,118.5) ; U89.2 v1(116.08,106.91) ; J1.F62 v1(107.6,126.02) ; v3(97.85,118.5) 97.85,118.41 J1.A52 ; J1.A17 v1(64.9,118.52) ; v3(93.55,120) 94.1,119.45 J1.B47 94.65,119.91 v3(94.65,120) ; J1.J3 v1(51.5,130.52) ; v3(92.45,121.5) 93,120.95 93,120.94 ; v1(66.24,102.95) R568.2 R569.2 ; J1.B11 58.9,119.44 v3(59.45,120) ; J1.G13 v1(60.9,127.52) ; J1.G33 80.9,126.94 v3(81.45,127.5) ; v1(82.25,50.62) D8.3 D8.8 v1(82.25,53.06) ; J1.A33 80.9,117.94 v3(81.45,118.5) ; 90.3,117.94 90.3,117.95 v3(89.75,118.5) ; 90.3,117.94 v3(90.85,118.5) ; 90.3,117.94 J1.A43 ; J1.H7 55.1,128.56 v1(55.1,129.02) ; J1.F38 v1(85.6,126.02) ; J1.C3 v1(51.5,121.52) ; J1.A20 v1(67.6,118.52) ; J1.G24 v1(71.6,127.52) ; J1.E36 v1(83.6,124.52) ; J1.K30 v1(77.6,132.02) ; Q41.S v1(121.56,105.9) ; J1.K14 61.6,131.45 v3(61.05,132) ; J1.K27 v1(74.9,132.02) ; CM20.2 v1(62.43,62.81) ; CM20.2 CM6.2 ; U90.2 v1(84.99,109.17) 85.65,109.17 R1478.2 ; J1.K22 v1(69.6,132.02) ; CM12.2 v1(55.37,56.64) ; J1.D35 v1(82.9,123.02) ; J1.B35 82.9,119.44 v3(83.45,120) ; Q6.S v1(146.82,68.31) ; v1(85.52,132.02) 85.52,131.44 J1.K38 ; v1(98.55,127.51) 98.4,127.36 J1.G52 ; J1.C13 v1(60.9,121.52) ; v3(57.45,118.5) 56.9,117.94 J1.A9 ; CM4.2 v1(55.37,73.79) ; v3(73.05,132) 73.6,131.45 J1.K26 ; J1.D4 v1(52.6,123.02) ; J1.H34 81.6,128.45 v3(81.05,128.99) ; v3(61.05,128.99) 61.6,128.45 J1.H14 ; J1.K8 v1(56.2,132.02) ; J1.L13 60.9,132.94 v3(61.45,133.5) ; J1.B57 v1(103.1,120.02) ; J1.C24 v1(71.6,121.52) ; v3(75.11,133.5) 75.6,133 J1.L28 ; J1.E32 v1(79.6,124.52) ; v3(90.85,133.5) 90.3,132.94 J1.L43 ; v3(91.75,132) 92.3,131.45 J1.K45 ; J1.B39 v1(86.9,120.02) ; J1.F39 86.9,125.86 v1(87.07,126.03) ; v3(71.45,132) 70.9,131.44 J1.K23 ; 87.6,123.94 v3(88.15,124.5) ; 87.6,123.94 87.6,123.95 v3(87.05,124.5) ; 87.6,123.94 J1.E40 ; J1.F41 88.7,125.44 v3(89.25,126) ; J1.F15 v1(62.9,126.02) ; CM24.2 v1(46.34,72.59) CB9.1 ; 93,120.94 J1.C46 ; 93,120.94 v3(93.55,121.5) ; J1.E33 v1(80.9,124.52) ; R641.1 v1(48.46,71.37) ; J1.D15 v1(62.9,123.02) ; J1.L21 68.9,133.06 v3(69.33,133.5) ; Q66.4 v1(3.73,84.12) ; J1.K15 v1(62.9,132.02) ; J1.E20 v1(67.6,124.52) ; J1.F19 v1(66.9,126.02) ; v3(98.95,123) 99.5,122.45 J1.D53 ; J1.A29 v1(76.9,118.52) ; J1.C16 v1(63.6,121.52) ; J1.D19 v1(66.9,123.02) ; J1.G40 87.6,126.94 v3(88.15,127.5) ; J1.D39 v1(86.9,123.02) ; Q8.S v1(146.82,73.65) ; J1.D38 v1(85.6,123.02) ; J1.B15 v1(62.9,120.02) ; v3(79.45,120) 78.9,119.44 J1.B31 ; J1.C32 v1(79.6,121.51) ; J1.B18 v1(65.6,120.02) ; J1.G62 v1(107.4,127.52) ; J1.B23 70.9,119.44 v3(71.45,120) ; R635.2 v1(64.59,61.16) ; R43.2 v1(89.31,105.16) ; J1.H18 v1(65.6,129.02) ; v1(55.12,120.02) 55.12,119.54 J1.B7 ; R1479.2 v1(89.31,108.2) ; Q7.S v1(146.84,70.98) ; U12.3 v1(83.34,105.01) ; J1.K63 v1(108.5,132.02) ; J1.F31 v1(78.9,126.02) ; v3(71.11,133.5) 71.6,133 J1.L24 ; J1.F50 96.8,125.45 v3(96.25,126) ; J1.B4 v1(52.6,120.02) ; J1.G28 75.6,126.95 v3(75.05,127.5) ; v3(79.45,122.99) 78.9,122.44 J1.D31 ; Y1.4 73.7,156.88 v1(72.9,156.08) 72.1,155.28 Y1.2 ; J1.F18 v1(65.6,126.02) ; J1.F34 v1(81.6,126.02) ; J1.D22 v1(69.6,123.02) ; CM15.2 v1(57.78,56.64) ; J1.J17 v1(64.9,130.52) ; J1.K11 58.9,131.44 v3(59.45,132) ; J1.L12 v1(59.6,133.52) ; J1.J8 v1(56,130.52) ; v1(59.94,130.38) 59.6,130.03 J1.J12 ; J1.C37 v1(84.9,121.52) ; J1.L20 v1(67.6,133.52) ; J1.K4 v1(52.6,131.97) ; CM13.2 v1(57.78,73.79) ; Q33.1 v1(58.91,167.46) ; J1.E37 84.9,123.94 v3(85.45,124.5) ; J1.H38 v1(85.6,129.02) ; J1.L3 v1(51.5,133.52) ; J1.G32 v1(79.6,127.52) ; v3(95.15,127.41) J1.G49 ; J1.K18 v1(65.6,132.02) ; J1.J29 v1(76.9,130.52) ; v1(101.3,132.02) J1.K55 ; CM22.2 v1(56.57,73.79) ; J1.E3 v1(51.5,124.52) ; J1.J20 v1(67.6,130.52) ; J1.H27 v1(74.9,129.02) ; J1.D30 v1(77.6,123.02) ; CA62.1 v1(115.25,109.86) ; v3(71.45,122.99) 70.9,122.44 J1.D23 ; J1.G37 v1(84.9,127.52) ; J1.H63 v1(108.5,129.02) ; J1.E16 v1(63.6,124.52) ; J1.A3 v1(51.5,118.52) ; J1.B22 v1(69.6,120.02) ; J1.F30 v1(77.6,126.02) ; J1.L36 83.6,133 v3(83.11,133.5) ; J1.F4 v1(52.6,126.02) ; J1.G21 v1(68.9,127.52) ; J1.A37 v1(84.9,118.52) ; v1(102,130.52) J1.J56 ; v1(95.73,95) CM45.2 ; Q69.1 v1(5.59,80.01) ; J1.C29 v1(76.9,121.52) ; J1.B50 96.8,119.45 v3(97.35,120) ; CM17.2 v1(45.09,62.23) ; J1.A16 v1(63.6,118.52) ; v1(121.18,102.49) RZ121.1 121.67,103.28 121.83,103.11 Q42.S ; J1.C12 59.6,120.95 v3(59.05,121.5) ; J1.K19 v1(66.9,132.02) ; U10.3 v1(109.85,152.4) ; J1.B30 v1(77.6,120.02) ; J1.B26 73.6,119.45 v3(73.05,120) ; J1.E13 v1(60.9,124.52) ; J1.G16 v1(63.6,127.52) ; J1.D7 v1(55.3,123.04) ; U11.3 v1(109.86,156.21) ; J1.B27 v1(74.9,120.02) ; J1.A63 v1(108.3,118.52) ; J1.A13 v1(60.9,118.52) ; Z18.1 v1(121.06,136.63)
  TOP w0.406: v1(104.01,66.55) D7.3 D7.8 v1(106.43,66.55)
  TOP w0.508: C211.2 C212.2 ; R64.2 Z5.1 v1(151.41,71.63) ; R417.1 v1(137.92,25.37) ; RZ13.2 v1(111.25,140.34) ; v1(76.15,74.12) C60.2 76.14,73.46 R164.1 ; Q19.S 137.23,41.63 R1509.2 138.33,41.76 Z10.1 v1(138.33,43.43) ; 133.48,56.49 132.74,57.23 v1(132.28,57.23) ; C377.2 v1(60.02,73.86) ; CA65.2 v1(152.3,101.85) ; C179.2 49.15,27.71 v1(49.15,28.42) ; CA91.2 CA90.2 CA89.2 v1(10.45,21.76) ; CA91.2 v1(18.87,22.86) ; CA91.2 C239.2 CA92.2 v1(26.14,21.76) ; C207.2 104.01,27.71 v1(104.01,28.42) ; C233.2 v1(136.4,55.04) ; 65.26,155.07 v1(65.26,154.25) ; C432.2 v1(100.98,98.54) ; v1(51.13,76.28) R625.1 R632.2 ; CA18.2 v1(127.89,174.24) ; CA5.2 v1(61.47,180.34) ; C30.2 v1(141.6,151.13) ; C25.2 v1(136.53,79.86) ; RZ71.1 RZ70.1 v1(22.17,76.53) ; CA4.2 C128.1 v1(135,184.78) ; C224.2 140.59,28.09 v1(140.59,28.8) ; RZ119.2 v1(117.14,43.51) ; 119.76,69.99 v1(118.9,69.99) ; CA80.2 49.4,56.52 v1(49.35,56.46) R633.2 ; C70.2 v1(76.45,159.26) ; R726.1 v1(56.39,148.46) ; R101.2 v1(41.27,110.44) ; CA88.2 v1(45.2,46.3) ; U24.2 87.02,178.46 86.83,178.27 CA10.2 v1(86.83,176.66) ; C396.2 146.88,88.77 v1(147.35,88.77) ; R659.1 v1(40.01,106.3) ; C24.2 v1(142.9,62.36) ; v1(69.48,153.93) Q34.S 69.48,152.73 69.32,152.56 R674.2 ; v1(13.75,118.06) 13.75,117.68 CA60.2 ; v1(86.64,18.38) CA104.2 C253.2 CA103.2 CA102.2 CA101.2 v1(73.79,18.38) ; R393.1 v1(119.63,24.99) ; R42.2 v1(86.49,107.09) ; R654.1 v1(40.01,96.65) ; v1(75.11,91.19) 74.9,90.98 S3.1 74.9,90.12 v1(75.11,89.92) ; v1(53.59,18.38) CA97.2 CA98.2 CA99.2 C248.2 CA100.2 v1(66.45,18.38) ; v1(48.21,56.59) 48.16,56.64 R631.2 ; Z1.1 R63.2 v1(151.41,68.96) ; v1(134.11,174.37) R756.1 134.1,175.04 CA13.2 v1(132.97,174.37) ; v1(103.28,88.52) 102.73,88.52 C310.2 102.6,87.27 C309.2 102.74,87.08 C288.2 v1(104.52,87.08) ; C318.2 v1(51.59,104.52) ; v1(33.4,18.38) CA93.2 CA94.2 CA95.2 C243.2 CA96.2 v1(46.25,18.38) ; R181.1 v1(67.26,57.61) ; v1(94.18,18.38) CA105.2 CA106.2 CA107.2 C258.2 CA108.2 v1(106.76,18.38) ; R685.2 v1(137.31,90.3) ; v1(154.46,100.08) 155.32,99.21 U84.2 ; R91.2 v1(129.31,75.06) ; RZ53.1 v1(141.68,99.19) ; Q14.S v1(118.64,74.03) ; U15.4 v1(43.86,114.38) ; R583.2 v1(72.57,82.3) ; S6.2 v1(134.52,89.66) RZ58.1 ; R565.1 74.93,110.26 v1(74.96,110.24) R562.2 ; C295.2 v1(90.97,93.94) ; R1478.2 v1(86.51,109.25) 86.64,109.25 86.79,109.09 D65.A v1(88.42,109.09) ; R24.2 v1(110.11,138.05) ; C23.2 v1(139.22,79.88) ; C184.2 C185.2 ; CA71.2 128.64,73.25 v1(128.61,73.28) CA70.2 ; C297.1 v1(87.41,82.8) ; C197.2 85.72,27.71 v1(85.72,28.42) ; CA76.2 C66.2 v1(100.83,63.72) ; R634.2 v1(47.32,76.28) ; R65.2 Z6.1 v1(151.41,74.3) ; Q12.S v1(120.55,78.12) ; U24.8 v1(95.5,179.54) ; v1(32.38,31.34) 32.38,30.63 C170.2 ; C188.2 67.44,27.71 v1(67.44,28.42) ; R639.2 v1(50.9,51.54) ; v1(61.76,59) CM8.2 CM18.2 ; C444.2 v1(56.39,144.78) ; v1(54.71,49.35) 54.58,49.48 SPI2.4 ; Q4.S 112.79,150.92 v1(112.7,150.83) ; D2.A v1(86.64,104.9) ; v1(139.19,135) 139.94,134.25 U29.2 ; v1(127.03,18.38) CA112.2 C263.2 CA111.2 CA110.2 CA109.2 v1(114.38,18.38) ; v1(19.13,81.61) CA68.1 CA248.2 ; v1(152.53,142.75) 152.21,142.75 VS1.1 ; RZ69.1 v1(6.88,76.58) ; v1(75.87,84.05) 75.97,84.15 R585.2 ; U36.4 66.92,177.95 66.76,177.8 CA11.2 v1(66.76,176.28) ; v1(92.92,93.98) 93.18,94.23 Y2.4 ; CA64.2 6.96,108.67 RZU19.1 v1(6.3,109.8) ; R342.1 v1(83.06,24.99) ; R626.1 v1(50.62,78.56) ; CA8.2 37.93,178.33 38.17,178.56 U40.8 ; R100.2 v1(42.88,110.39) ; v1(140.63,43.56) CA87.2 CA86.2 CA85.2 C273.2 CA81.2 v1(140.63,56.41) ; R145.2 v1(117.63,117.86) ; Q38.S v1(116.63,84.22) ; R321.1 v1(64.77,24.99) ; C290.2 v1(101.75,80.14) ; CA55.2 135.17,136.14 v1(134.49,136.14) ; FB46.2 v1(73.99,149.56) ; U40.2 v1(30.55,178.38) ; C193.2 C194.2 ; RB26.2 v1(39.88,110.44) ; v1(119.48,43.59) RZ112.2 ; RZ75.1 RZ77.1 v1(21.18,70.59) ; C202.2 C203.2 ; S4.1 v1(53.29,108.15) ; C123.1 v1(137.79,184.78) ; CB7.1 v1(58.88,73.86) ; CA61.2 v1(99.68,102.49) ; RZU34.1 v1(72.59,64.47) ; CA69.2 v1(138.07,79.88) ; C135.2 46,138.44 Z12.1 v1(45.21,139.57) ; R294.1 v1(46.48,24.99) ; SPI1.4 v1(72.8,79.76) ; R36.2 v1(126.24,160.27) TP17.1 ; CB5.2 v1(91.01,156.84) ; Q13.S v1(118.9,72.79) ; C141.2 v1(132.33,173.1) ; RB39.1 112.39,93.85 ; C434.2 v1(95.49,102.78) ; C457.1 v1(48.81,151.38) ; R273.1 v1(29.72,27.91) ; v1(122.3,28.42) 122.3,27.71 C215.2 ; v1(133.31,166.24) CA46.2 133.32,165.6 RB5.2 ; C175.2 C176.2 ; C22.2 v1(140.34,79.91) ; C291.1 v1(101.59,78.4) ; R29.2 v1(128.02,164.21) CA47.1 ; Q3.S v1(100.36,103.89) ; R539.2 v1(87.4,79.38) ; Q37.S v1(117.37,89.66) ; R628.1 v1(49.35,78.56) ; R170.1 v1(94.97,57.61) ; R769.1 R768.1 v1(111.63,80.01) ; v1(136.04,53.98) R441.1 ; C220.2 C221.2 ; RZU29.2 v1(75.34,79.63) ; C124.1 v1(140.34,184.78) ; R718.1 v1(53.85,143.13) ; R369.1 v1(101.35,24.99) ; U15.7 41.32,122.86 CA59.2 v1(41.11,123.76) ; C125.1 v1(139.06,184.78) ; RZ66.1 v1(6.88,77.72) ; R640.2 v1(67.34,64.77) ; C62.2 v1(72.47,67.89) ; C136.2 v1(118.28,174.5) ; U21.4 v1(80.14,76.2) ; C126.1 v1(136.53,184.78) ; R627.1 v1(49.99,76.28) ; R247.1 v1(133.35,178.16)
  TOP w0.559: CA8.2 v1(38.61,177.8)
  IN3 w0.124: 110.91,46.74 112.76,48.6 112.76,54.86 117.4,59.5 121.64,59.5 125.26,63.11 130.68,63.11 131.7,64.13 138.09,64.13 141.86,67.89 145.4,67.89 146.95,69.45 151.59,69.45 153.06,70.92 153.06,75.64 v1(153.62,76.2) 154.18,76.2 154.38,76.4 154.38,77.5 154.26,77.62 153.19,77.62 152.17,76.61 152.17,72.39 v1(151.41,71.63) 151.41,70.71 151,70.31 146.34,70.31 144.78,68.75 141.5,68.75 137.74,64.99 131.34,64.99 130.33,63.97 124.9,63.97 121.39,60.46 117.01,60.46 111.8,55.25 111.8,48.99 110.51,47.7 94.82,47.7 89.04,41.92 88.42,41.92 87.53,42.8 77.84,42.8 76.88,41.85 69.94,41.85 67.45,39.35 67.45,29.13 67.97,28.61 67.97,27.56 70.2,25.33 72.32,25.33 73.41,26.42 v1(74.42,26.42) 74.42,26.57 74.12,26.87 72.36,26.87 71.78,26.29 70.46,26.29 68.83,27.92 68.83,28.96 68.31,29.48 68.31,39 70.3,40.99 77.24,40.99 78.2,41.94 87.18,41.94 88.06,41.06 89.39,41.06 95.08,46.74 110.91,46.74
  BOTTOM w0.203: C227.2 141.1,27.27 141.1,28.12 140.89,28.32 139.81,28.32 139.68,28.19 138.37,28.19 v1(138.18,28.39) ; v1(101.6,28.01) 101.8,27.81 103.11,27.81 103.23,27.94 104.32,27.94 104.52,27.74 104.52,26.89 C209.2 ; C182.2 49.66,26.89 49.66,27.74 49.45,27.94 48.37,27.94 48.24,27.81 46.93,27.81 v1(46.74,28.01) ; v1(65.02,28.01) 65.22,27.81 66.53,27.81 66.66,27.94 67.74,27.94 67.94,27.74 67.94,26.89 C191.2 ; v1(83.31,28.01) 83.51,27.81 84.82,27.81 84.94,27.94 86.03,27.94 86.23,27.74 86.23,26.89 C200.2 ; v1(119.89,28.01) 120.08,27.81 121.39,27.81 121.52,27.94 122.61,27.94 122.81,27.74 122.81,26.89 C218.2 ; C173.2 32.89,29.81 32.89,30.66 32.69,30.86 31.6,30.86 31.48,30.73 30.17,30.73 v1(29.97,30.93) ; U85.6 v1(140.97,105.41) ; C236.2 132.7,56.4 v1(133.22,55.88) 133.22,54.43 v1(133.1,54.31)
  BOTTOM w0.254: v1(50.51,25.4) 50.67,25.23 v1(50.67,24.38) v1(50.67,23.37) 50.67,22.99 v1(50.16,22.48) 49.78,22.1 v1(49.15,22.1) v1(48.01,22.1) 47.23,22.87 v1(47.23,23) v1(47.23,24.13) 47.23,25.22 v1(47.41,25.4) ; v1(71.83,107.26) 71.83,107.9 72.57,108.64 v1(72.57,109.42) v1(72.57,110.26) v1(72.57,111.19) 71.72,111.19 X10.4 71.69,111.59 71.3,111.99 v1(70.69,111.99) 69.6,111.99 v1(69.49,111.89) 69.06,111.45 v1(69.06,110.9) v1(69.06,109.68) 69.06,108.85 70.05,107.85 v1(70.05,107.39) ; v1(30.65,28.32) 30.47,28.14 v1(30.47,27.05) v1(30.47,25.92) 30.47,25.8 v1(31.24,25.02) v1(32.38,25.02) 33.02,25.02 v1(33.4,25.4) 33.4,25.43 33.91,25.93 v1(33.91,26.29) v1(33.91,27.3) 33.91,28.16 v1(33.74,28.32) ; U32.4 140.72,178.41 140.55,178.57 CM64.2 ; CB135.2 127.93,143.54 v1(128.4,143.54) 128.87,143.54 C91.2 ; v1(123.66,25.4) 123.83,25.23 v1(123.83,24.38) v1(123.83,23.37) 123.83,22.99 v1(123.32,22.48) 122.94,22.1 v1(122.3,22.1) v1(121.16,22.1) 120.38,22.87 v1(120.38,23) v1(120.38,24.13) 120.38,25.22 v1(120.56,25.4) ; v1(135.25,55.88) 135.8,56.43 C237.2 ; v1(105.37,25.4) 105.54,25.23 v1(105.54,24.38) v1(105.54,23.37) 105.54,22.99 v1(105.03,22.48) 104.65,22.1 v1(104.01,22.1) v1(102.87,22.1) 102.09,22.87 v1(102.09,23) v1(102.09,24.13) 102.09,25.22 v1(102.27,25.4) ; v1(144.42,92.84) 144.31,92.95 CB136.2 ; v1(122.5,64.85) 122.62,64.97 U87.1 ; U30.4 v1(130.3,141.1) ; v1(141.88,25.53) 141.99,25.43 v1(141.99,24.51) v1(141.99,23.5) 141.99,23.37 141.48,22.86 v1(141.22,22.86) 140.84,22.48 v1(140.46,22.48) 140.34,22.35 139.45,22.35 v1(139.32,22.48) 138.54,23.26 v1(138.54,23.38) v1(138.54,24.51) 138.54,25.6 v1(138.72,25.78) ; v1(68.8,25.4) 68.96,25.23 v1(68.96,24.38) v1(68.96,23.37) 68.96,22.99 v1(68.45,22.48) 68.07,22.1 v1(67.44,22.1) v1(66.29,22.1) 65.52,22.87 v1(65.52,23) v1(65.52,24.13) 65.52,25.22 v1(65.7,25.4) ; v1(135.8,57.35) v1(135.8,58.55) 135.8,58.92 135.54,59.17 X9.4 134.89,59.83 v1(134.76,59.96) v1(133.6,59.96) 132.78,59.96 v1(132.28,59.46) v1(132.28,58.29) v1(132.28,57.23) ; v1(87.08,25.4) 87.25,25.23 v1(87.25,24.38) v1(87.25,23.37) 87.25,22.99 v1(86.74,22.48) 86.36,22.1 v1(85.72,22.1) v1(84.58,22.1) 83.81,22.87 v1(83.81,23) v1(83.81,24.13) 83.81,25.22 v1(83.99,25.4)
  BOTTOM w0.305: v1(156.37,189.67) NGFF1.57 v1(153.92,189.67) ; CB139.2 v1(131.32,56.01) ; v1(156.37,193.09) 156.29,193.17 NGFF1.71 154,193.17 v1(153.92,193.09) ; WIFI1.33 v1(140.24,124.58) ; WIFI1.63 147.74,124.37 v1(147.96,124.59) ; CB148.2 v1(31.75,32.64) ; HDMI1.5 v1(100.15,45.59) ; CB134.2 C129.2 138.42,176.01 v1(138.3,175.9) ; v1(133.48,124.58) 133.74,124.32 WIFI1.7 ; NGFF1.3 154.05,176.17 v1(153.92,176.04) ; WIFI1.45 v1(143.24,124.58) ; v1(156.34,178.31) 156.2,178.17 NGFF1.11 v1(153.92,178.17) ; v1(156.37,188.17) NGFF1.51 v1(153.92,188.17) ; HDMI1.8 v1(101.65,45.59) ; WIFI1.57 146.24,124.45 v1(146.36,124.58) ; WIFI1.18 v1(136.49,129.76) ; v1(156.34,176.53) 156.2,176.67 NGFF1.5 v1(153.92,176.67) ; WIFI1.1 v1(132.24,124.58) ; v1(156.34,182.12) 156.29,182.17 NGFF1.27 v1(153.92,182.17) ; HDMI1.2 v1(98.65,45.59) ; CB154.2 v1(48.51,29.72) ; CB149.2 v1(139.95,30.1) ; CB151.2 v1(103.38,29.72) ; HDMI1.17 v1(106.15,45.59) ; HDMI1.11 v1(103.15,45.59) ; CB153.2 v1(66.8,29.72) ; WIFI1.39 v1(141.74,124.58) ; v1(156.37,185.17) NGFF1.39 v1(153.92,185.17) ; v1(156.37,193.72) 156.31,193.67 NGFF1.73 153.97,193.67 v1(153.92,193.72) ; TP18.8 v1(151.79,13.74) ; WIFI1.75 v1(150.74,124.58) ; v1(129.44,64.39) 129.32,64.5 C892.1 ; WIFI1.69 v1(149.24,124.58) ; v1(156.37,183.75) 156.29,183.67 NGFF1.33 v1(153.92,183.67) ; CB150.2 v1(121.67,29.72) ; WIFI1.51 v1(144.74,124.58) ; v1(153.92,186.67) NGFF1.45 v1(156.37,186.67) ; TP18.4 v1(153.79,13.79) ; CB152.2 v1(85.09,29.72)
  BOTTOM w0.356: v3(61.56,99.42) 61.96,99.02 U67.M10 ; U67.L10 v3(60.76,99.42) ; v3(61.56,98.62) 61.96,98.22 U67.M11 ; U67.N11 v3(62.36,98.62) ; U67.L12 v3(60.76,97.82) ; U67.P14 63.56,95.82 v3(63.96,95.42) ; U67.M12 61.96,97.42 v3(61.56,97.82) ; U67.M15 v3(61.56,94.62) ; U67.R15 64.36,95.02 v3(64.76,94.62) ; U67.N14 v3(62.36,95.42) ; U67.P11 v3(63.96,98.62) ; v3(61.56,97.02) 61.96,96.62 U67.M13 ; U67.M16 v3(61.56,93.82) ; U67.R16 64.36,94.22 v3(64.76,93.82) ; U67.L15 v3(60.76,94.62) ; v3(64.76,95.42) 64.36,95.82 U67.R14 ; U67.R11 v3(64.76,98.62) ; U67.M14 v3(61.56,95.42) ; U67.P15 63.56,95.02 v3(63.96,94.62) ; U67.P12 v3(63.96,97.82) ; U67.N10 v3(62.36,99.42) ; U67.K16 v3(59.96,93.82) ; v3(65.56,95.42) 65.16,95.82 U67.T14 ; U67.K11 v3(59.96,98.62) ; U67.P10 v3(63.96,99.42) ; U67.T16 65.16,94.22 v3(65.56,93.82) ; U67.R13 v3(64.76,97.02) ; U67.N15 v3(62.36,94.62) ; v3(63.96,93.82) 63.56,94.22 U67.P16 ; U67.T11 v3(65.56,98.62) ; U67.T10 v3(65.56,99.42) ; U67.R12 v3(64.76,97.82) ; U67.L16 v3(60.76,93.82) ; U67.R10 v3(64.76,99.42) ; U67.L14 v3(60.76,95.42) ; U67.N12 v3(62.36,97.82) ; U67.N16 v3(62.36,93.82) ; U67.L13 v3(60.76,97.02) ; U67.L11 v3(60.76,98.62) ; U67.K15 v3(59.96,94.62) ; U67.K10 v3(59.96,99.42) ; U67.P13 v3(63.96,97.02) ; U67.N13 v3(62.36,97.02)
  BOTTOM w0.381: v1(59.44,21.69) D24.8 D24.3 v1(59.44,24.03) ; X7.4 121.22,23.31 v1(121.92,22.61) ; v1(109.85,152.4) 109.85,152.88 CA129.2 ; CA141.2 84.44,109.71 v1(84.99,109.17) ; C219.2 v1(120.56,26.64) ; v1(67.44,25.27) 67.76,24.95 X4.2 ; v1(81.03,21.69) D31.8 D31.3 v1(81.03,24.03) ; v1(139.29,48.64) D44.8 D44.3 137.01,48.64 v1(136.91,48.74) ; v1(135.89,22.07) D43.8 D43.3 v1(135.89,24.41) ; v1(105.92,48.62) D57.3 D57.8 105.92,50.72 v1(105.69,50.95) ; v1(62.94,51.05) 63.07,50.93 D11.8 D11.3 v1(63.07,48.59) ; v1(85.72,25.27) 86.04,24.95 X5.2 ; v1(96.01,24.03) D32.3 D32.8 v1(96.01,21.69) ; Z4.1 v1(149.94,17.02) ; v1(122.3,25.27) 122.62,24.95 X7.2 ; v1(102.62,48.59) D56.8 D56.3 v1(102.62,51) ; v1(99.19,50.98) D55.3 D55.8 v1(99.19,48.51) ; v1(107.52,53.92) 107.85,53.59 R519.1 ; v1(139.14,52.12) 138.96,51.94 D45.8 D45.3 136.91,51.94 v1(136.8,52.04) ; v1(103.63,22.61) 102.93,23.31 X6.4 ; v1(77.72,21.69) D29.8 D29.3 v1(77.72,24.03) ; RZ208.1 v1(66.62,53.52) ; v1(130.3,141.1) 130.39,141.01 CM65.2 ; X3.4 48.07,23.31 v1(48.77,22.61) ; v1(32.38,28.19) 32.7,27.87 X2.2 ; v1(140.46,25.65) 140.78,25.33 X8.2 ; v1(49.15,25.27) 49.47,24.95 X3.2 ; v1(110.49,93.29) 110.63,93.16 Q51.1 ; Z2.1 v1(152.48,17.02) ; v1(117.6,24.03) D39.3 D39.8 v1(117.6,21.69) ; C237.2 v1(135.8,57.35) ; v1(99.31,24.03) D35.3 D35.8 v1(99.31,21.69) ; D16.8 D16.3 23.88,26.75 v1(24.1,26.97) ; v1(66.62,51.03) D66.3 D66.8 v1(66.62,48.69) ; Z16.1 v1(157.12,24.82) ; Q51.4 112.49,90.62 v1(112.56,90.68) ; X2.4 31.3,26.23 v1(32,25.53) ; v1(132.28,57.23) 132.28,57.01 C236.2 ; v1(132.59,22.07) D42.8 D42.3 v1(132.59,24.41) ; v1(67.06,22.61) 66.36,23.31 X4.4 ; v1(83.34,105.01) 83.16,105.19 CA143.2 ; v1(109.86,156.21) 109.56,155.91 CA126.2 ; C183.2 v1(47.41,26.64) ; X10.2 70.29,109.95 v1(70.94,109.3) ; v1(138.98,27.03) 138.98,26.54 C228.2 ; v1(62.74,21.69) D27.8 D27.3 v1(62.74,24.03) ; v1(114.3,21.69) D37.8 D37.3 v1(114.3,24.03) ; v1(27.25,26.92) D19.3 D19.8 v1(27.25,24.54) ; CA153.2 v1(153.52,20.05) ; C192.2 v1(65.7,26.64) ; RZ207.1 v1(65.48,53.52) ; X9.2 133.49,57.93 v1(134.19,57.23) ; v1(104.01,25.27) 104.33,24.95 X6.2 ; RZ209.1 v1(61.47,53.44) ; C174.2 v1(30.65,29.57) ; v1(109.5,95.76) 109.14,96.11 RB37.1 ; C210.2 v1(102.27,26.64) ; CA133.2 v1(153.8,140.93) ; RZ210.1 v1(62.61,53.44) ; v1(41.15,24.03) D21.3 D21.8 v1(41.15,21.69) ; v1(136.68,65.41) 136.56,65.29 C19.2 CA152.2 136.68,63.64 v1(136.68,63.12) ; v1(85.34,22.61) 84.64,23.31 X5.4 ; v1(44.45,24.03) D23.3 D23.8 v1(44.45,21.69) ; Z3.1 v1(151.21,17.02) ; C201.2 v1(83.99,26.64)
  BOTTOM w0.508: NCSI1.10 v1(153.63,72.2) ; JSIM2.P1 v1(131.25,186.11) ; v1(137.19,76.96) 137.07,76.85 C18.2 CA149.2 137.07,74.79 v1(137.19,74.68) ; v1(116.63,84.22) 116.46,84.38 RZ116.1 ; v1(120.36,180.09) C119.1 CA120.2 ; CA124.2 v1(68.83,174.75) ; v1(138.72,25.78) 138.85,25.91 C228.2 ; J4.5 v1(118.54,121.41) ; v1(139.85,22.94) 139.38,23.41 X8.4 ; R558.2 v1(68.1,110.29) ; C182.2 v1(50.51,25.4) ; JSIM1.C5 v1(120.65,184.92) ; v1(153.16,195.27) NGFF1.P2 v1(156.72,195.27) ; PSON3.3 v1(44.96,137.77) ; C922.1 v1(10.67,106.22) ; PSON2.4 v1(121.09,154.69) ; C227.2 141.95,25.67 141.88,25.6 v1(141.88,25.53) ; v1(92.79,177.16) CA122.2 93.51,177.91 93.37,178.05 U26.2 ; C219.2 v1(120.56,25.4) ; v1(63.28,176.28) CA123.2 63.28,177.76 63.12,177.93 U38.4 ; CA136.2 v1(116.75,125.86) ; v1(132.84,157.23) 132.63,157.01 CA125.2 ; C92.2 126.8,139.32 v1(126.39,139.73) ; C913.2 v1(133.73,144.91) ; R610.2 v1(70.76,81.28) ; v1(103.28,87.76) 102.41,87.76 R504.2 ; C183.2 v1(47.41,25.4) ; U23.2 77.36,52.24 C64.2 v1(75.37,52.24) ; R583.2 v1(72.57,82.3) ; C192.2 v1(65.7,25.4) ; C912.2 v1(133.73,146.05) ; v1(126.36,180.72) 126.33,180.76 C118.1 ; C914.2 v1(133.73,147.19) ; C120.1 v1(124.46,180.09) ; C200.2 v1(87.08,25.4) ; v1(33.74,28.32) C173.2 ; JSIM1.P1 v1(116.71,186.11) ; R711.2 v1(82.58,102.11) ; JSIM2.P3 v1(142.95,194.91) ; R227.2 v1(146.3,184.68) ; v1(30.65,28.32) C174.2 ; C300.2 v1(100.86,85.72) ; v1(9.14,196.25) CA117.2 10.78,196.25 Q15.E ; C209.2 v1(105.37,25.4) ; CA128.2 v1(80.77,156.16) ; R215.2 v1(144.65,181.86) ; R713.1 v1(88.29,94.46) ; C132.2 118.48,152.93 Z7.1 116.56,152.93 v1(116.46,153.03) ; v1(29.03,171.15) v1(29.03,171.78) U74.2 ; R177.2 v1(83.82,176.53) ; v1(142.37,151.13) CA130.2 C27.2 ; R698.1 v1(144.81,100.71) ; v1(147.85,100.2) D64.A 145.99,100.2 C417.2 ; U26.8 85.75,178.59 v1(85.09,177.93) ; CM64.2 v1(141.43,179.07) ; OOB1.1 v1(153.47,98.2) ; v1(139.73,74.68) 139.73,74.96 RZ199.2 ; v1(135,184.78) 135.2,184.59 JSIM2.C5 ; CA142.2 93.71,107.11 v1(93.71,107.53) ; C201.2 v1(83.99,25.4) ; J4.7 v1(125.53,125.22) ; v1(144.55,70.48) 144.46,70.57 CA150.2 CA151.2 v1(142.27,70.57) ; Z17.1 145.12,172.07 Q58.S v1(143.26,172.07) ; R228.2 v1(144.78,191.9) ; JSIM1.P2 v1(128.41,186.11) ; J4.9 v1(125.35,122.68) ; C191.2 v1(68.8,25.4) ; CA148.2 v1(153.66,87.92) ; J4.3 v1(118.31,123.95) ; v1(112.7,150.83) 112.78,150.9 RZU38.2 ; JSIM2.P4 v1(131.25,194.91) ; CA140.2 v1(92.74,109.73) ; C210.2 v1(102.27,25.4) ; U37.3 v1(65.79,175.07) ; C130.2 v1(143.13,175.26) ; v1(104.57,90.93) R541.1 104.57,89.58 Q55.S ; CA147.2 v1(141.63,89.66) ; R210.2 v1(144.65,175.51) ; Z9.1 123.71,153.33 C134.2 v1(123.7,152.65) ; C117.1 v1(123.19,180.09) ; R661.1 v1(40.18,86.31) ; v1(132.99,72.43) C21.2 C20.2 v1(130.58,72.43) ; NCSI1.6 v1(153.62,76.2) ; JSIM1.P3 v1(128.41,194.91) ; DB1.3 v1(114.63,63.25) ; JSIM2.P2 v1(142.95,189.02) ; C121.1 v1(121.92,180.09) ; CA127.2 v1(81.92,156.16) ; C311.2 v1(90.65,80.14) ; C218.2 v1(123.66,25.4) ; RZU36.2 v1(54.71,49.35) ; JSIM1.P4 v1(116.71,194.91) ; NGFF1.P1 v1(152.98,174.57) ; C915.2 v1(133.73,148.46) ; CA135.2 v1(153.54,137.12) ; CA121.2 132.07,176.95 v1(132.31,177.19) ; PSON3.4 v1(40.46,137.77) ; R1510.1 C462.1 ; NCSI1.4 v1(153.65,78.2) ; C916.2 v1(133.73,149.61) ; R260.2 v1(59.74,179.2) ; PSON2.3 v1(121.09,159.57) ; C487.2 v1(158.36,110.27) ; CA137.2 v1(158.36,112.67) ; DB1.5 v1(114.66,60.71)
  vias: v1(0.74,196.72) v1(0.74,194.18) v1(0.74,191.64) v1(0.74,189.1) v1(0.74,186.56) v1(0.74,184.02) v1(0.74,181.48) v1(0.74,178.94) v1(0.74,176.4) v1(0.74,173.86) v1(0.74,171.32) v1(0.74,168.78) v1(0.74,166.24) v1(0.74,163.7) v1(0.74,161.16) v1(0.74,158.62) v1(0.74,156.08) v1(0.74,153.54) v1(0.74,151) v1(0.74,148.46) v1(0.74,145.92) v1(0.74,143.38) v1(0.74,140.84) v1(0.74,138.3) v1(0.74,135.76) v1(0.74,133.22) v1(0.74,130.68) v1(0.74,128.14) v1(0.74,125.6) v1(0.74,123.06) v1(0.74,120.52) v1(0.74,117.98) v1(0.74,115.44) v1(0.74,112.9) v1(0.74,110.36) v1(0.74,107.82) v1(0.74,105.28) v1(0.74,102.74) v1(0.74,100.2) v1(0.74,97.66) v1(0.74,95.12) v1(0.74,92.58) v1(0.74,90.04) v1(0.74,87.5) v1(0.74,84.96) v1(0.74,82.42) v1(0.74,79.88) v1(0.74,77.34) v1(0.74,74.8) v1(0.74,72.26) v1(0.74,69.72) v1(0.74,67.18) v1(0.74,64.64) v1(0.74,62.1) v1(0.74,59.56) v1(0.74,57.02) v1(0.74,54.48) v1(0.74,51.94) v1(0.74,49.4) v1(0.74,46.86) v1(0.74,44.32) v1(0.74,41.78) v1(0.74,39.24) v1(0.74,36.7) v1(0.74,34.16) v1(0.74,31.62) v1(0.74,29.08) v1(0.74,26.54) v1(0.74,24) v1(0.74,21.46) v1(0.74,18.92) v1(1.47,183.36) v1(1.87,199.26) v1(2.21,18.95) v1(2.21,18.34) v1(2.44,186.28) v1(2.97,18.95) v1(2.97,18.34) v1(3.12,186.28) v1(3.61,183.39) v1(3.81,186.28) v1(4.27,183.39) v1(4.41,199.26) v1(6.95,199.26) v1(7.82,58.62) v1(7.82,57.99) v1(7.82,47.32) v1(7.82,46.69) v1(9.49,199.26) v1(10.87,128.98) v1(11.51,128.98) v1(12.03,199.26) v1(12.14,76.91) v1(12.14,75.39) v1(12.14,73.86) v1(12.14,72.34) v1(13.08,179.2) v1(13.72,179.2) v1(13.67,76.91) v1(13.67,75.39) v1(13.67,73.86) v1(13.67,72.34) v1(14.57,199.26) v1(15.19,76.91) v1(15.19,75.39) v1(15.19,73.86) v1(15.19,72.34) v1(15.32,58.62) v1(15.32,57.99) v1(15.32,47.32) v1(15.32,46.69) v1(16.71,76.91) v1(16.71,75.39) v1(16.71,73.86) v1(16.71,72.34) v1(16.89,37.97) v1(17.11,199.26) v1(17.91,37.97) v1(19.65,199.26) v1(20.98,196.85) v1(20.98,196.09) v1(21.08,34.16) v1(21.08,32.89) v1(21.08,31.5) v1(21.39,194.67) v1(21.39,193.78) v1(22.19,199.26) v1(22.35,30.61) v1(22.81,58.62) v1(22.81,57.99) v1(22.81,47.32) v1(22.81,46.69) v1(23.37,29.84) v1(23.88,184.4) v1(23.88,182.12) v1(23.88,179.71) v1(24,35.56) v1(24.38,29.84) v1(24.51,184.4) v1(24.51,182.12) v1(24.51,179.71) v1(24.73,199.26) v1(25.15,184.4) v1(25.15,182.12) v1(25.15,179.71) v1(25.15,29.84) v1(25.78,36.2) v1(25.93,16.13) v1(26.04,29.84) v1(26.7,16.13) v1(27.25,30.56) v1(27.56,32.26) v1(27.94,36.2) v1(29.81,199.26) v1(30.3,58.62) v1(30.3,57.99) v1(30.3,47.32) v1(30.3,46.69) v1(32.35,199.26) v1(33.66,35.05) v1(34.67,35.05) v1(34.89,199.26) v1(37.43,199.26) v1(37.85,31.62) v1(37.85,30.61) v1(37.85,26.42) v1(38.06,64.63) v1(38.06,63.51) v1(38.06,62.22) v1(38.06,61.1) v1(38.35,29.59) v1(39.12,27.69) v1(39.97,199.26) v1(39.95,179.53) v1(39.95,178.89) v1(40.13,26.92) v1(40.72,179.53) v1(40.72,178.89) v1(41.15,26.92) v1(41.48,179.53) v1(41.48,178.89) v1(41.63,63.44) v1(41.63,62.32) v1(41.91,26.92) v1(42.51,199.26) v1(42.55,33.3) v1(42.67,129.54) v1(42.67,127.25) v1(42.8,26.92) v1(43.31,129.54) v1(43.31,127.25) v1(43.94,129.54) v1(43.94,127.25) v1(44.07,27.69) v1(44.35,29.46) v1(44.86,33.3) v1(45.05,199.26) v1(46.3,57.99) v1(46.94,57.99) v1(47.59,199.26) v1(49.99,68.78) v1(49.99,67.01) v1(49.99,65.23) v1(49.99,63.45) v1(49.99,61.67) v1(50.13,199.26) v1(51.64,83.19) v1(51.64,81.31) v1(51.77,68.78) v1(51.77,67.01) v1(51.77,65.23) v1(51.77,63.45) v1(51.77,61.67) v1(51.94,35.05) v1(52.02,156.16) v1(52.02,155.52) v1(52.78,156.16) v1(52.78,155.52) v1(52.97,53.43) v1(52.96,35.05) v1(53.19,79.12) v1(53.54,68.78) v1(53.54,67.01) v1(53.54,65.23) v1(53.54,63.45) v1(53.54,61.67) v1(53.8,114.64) v1(53.9,79.12) v1(54.09,53.43) v1(54.17,50.39) v1(54.43,156.16) v1(54.43,155.52) v1(54.38,80.21) v1(54.91,114.64) v1(55.07,111.14) v1(55.09,80.21) v1(55.21,199.26) v1(55.19,156.16) v1(55.19,155.52) v1(55.32,68.78) v1(55.32,67.01) v1(55.32,65.23) v1(55.32,63.45) v1(55.32,61.67) v1(55.28,50.39) v1(55.44,53.44) v1(55.63,81.52) v1(55.6,79.14) v1(55.88,173.1) v1(56.13,31.62) v1(56.13,30.61) v1(56.13,26.42) v1(56.18,111.14) v1(56.27,114.64) v1(56.31,79.14) v1(56.52,173.1) v1(56.55,53.44) v1(56.64,29.59) v1(56.72,156.16) v1(56.72,155.52) v1(56.74,81.52) v1(56.65,50.38) v1(56.79,80.21) v1(57.1,68.78) v1(57.1,67.01) v1(57.1,65.23) v1(57.1,63.45) v1(57.1,61.67) v1(57.3,95.71) v1(57.39,114.64) v1(57.35,99.34) v1(57.35,98.7) v1(57.4,27.69) v1(57.48,156.16) v1(57.48,155.52) v1(57.48,111.26) v1(57.51,80.21) v1(57.58,93.42) v1(57.75,199.26) v1(57.81,81.52) v1(57.77,50.38) v1(58.42,26.92) v1(58.6,111.26) v1(58.69,114.64) v1(58.93,81.52) v1(59.18,173.61) v1(59.18,172.97) v1(59.44,26.92) v1(59.56,90.65) v1(59.8,114.64) v1(59.89,111.26) v1(59.89,102.72) v1(60.2,26.92) v1(60.29,199.26) v1(60.83,33.3) v1(61.01,111.26) v1(61.04,81.52) v1(61.09,26.92) v1(61.16,167.72) v1(61.16,167.08) v1(61.16,114.64) v1(61.54,102.74) v1(61.93,167.72) v1(61.93,167.08) v1(61.93,90.63) v1(62.15,81.52) v1(62.28,114.64) v1(62.31,111.23) v1(62.36,27.69) v1(62.64,29.46) v1(62.69,167.72) v1(62.69,167.08) v1(62.83,199.26) v1(63.14,33.3) v1(63.42,111.23) v1(63.93,102.74) v1(64.39,90.65) v1(65.04,83.79) v1(65.04,83.08) v1(65.37,199.26) v1(65.43,81.33) v1(65.96,90.6) v1(66.14,81.33) v1(66.78,108.66) v1(67.41,108.66) v1(67.39,81.39) v1(67.46,97.66) v1(67.46,95.61) v1(67.51,66.85) v1(67.65,75.23) v1(67.65,73.36) v1(67.84,139.12) v1(67.91,199.26) v1(67.89,100.53) v1(68.07,59.27) v1(68.07,58.55) v1(68.25,91.29) v1(68.33,181.36) v1(68.33,180.72) v1(68.28,70.48) v1(68.48,139.12) v1(68.5,81.39) v1(68.63,66.85) v1(68.71,179.45) v1(68.94,91.29) v1(69.14,139.12) v1(69.17,75.23) v1(69.17,73.36) v1(69.25,64.39) v1(69.34,179.45) v1(69.39,70.48) v1(70.23,35.05) v1(70.45,199.26) v1(70.37,64.39) v1(70.43,61.98) v1(70.48,172.75) v1(71.09,172.75) v1(71.25,35.05) v1(71.55,61.98) v1(72.92,43.76) v1(72.99,199.26) v1(72.97,62.02) v1(73.08,54.03) v1(73.08,53.44) v1(73.63,43.76) v1(73.71,54.03) v1(73.71,53.44) v1(74.09,62.02) v1(74.12,59.82) v1(74.3,172.77) v1(74.37,31.42) v1(74.42,30.56) v1(74.47,29.36) v1(74.9,172.77) v1(75.11,117.01) v1(75.23,59.82) v1(75.54,27.53) v1(76.56,96.8) v1(76.56,96.16) v1(76.56,95.5) v1(76.73,26.82) v1(76.91,57.99) v1(76.99,117.01) v1(77.65,26.8) v1(77.7,117.01) v1(77.66,102.22) v1(77.66,100.34) v1(77.67,57.99) v1(78.07,199.26) v1(78.05,106.54) v1(78.05,104.66) v1(78.12,75.07) v1(78.44,57.99) v1(78.46,60.22) v1(78.49,26.77) v1(78.99,104.25) v1(78.99,102.37) v1(79.03,100.05) v1(79.03,98.17) v1(79.02,33.3) v1(79.24,75.07) v1(79.3,26.82) v1(79.58,117.01) v1(79.63,69.16) v1(79.63,67.89) v1(79.63,66.62) v1(79.63,65.35) v1(79.63,64.08) v1(79.63,60.22) v1(80.01,74.42) v1(80.09,56.67) v1(80.61,199.26) v1(80.64,102.23) v1(80.64,100.36) v1(80.59,27.71) v1(80.67,60.2) v1(80.92,94.61) v1(80.92,93.98) v1(80.92,93.34) v1(80.92,29.57) v1(81.03,69.16) v1(81.03,67.89) v1(81.03,66.62) v1(81.03,65.35) v1(81.03,64.08) v1(81.18,90.04) v1(81.18,89.41) v1(81.18,88.77) v1(81.15,74.42) v1(81.41,75.06) v1(81.38,60.2) v1(81.43,33.32) v1(81.51,95.07) v1(81.51,94.49) v1(81.79,98.48) v1(81.79,96.6) v1(81.81,90.04) v1(81.81,89.41) v1(81.81,88.77) v1(81.97,56.67) v1(82.09,113.78) v1(82.14,95.07) v1(82.14,94.49) v1(82.45,88.77) v1(82.42,69.16) v1(82.42,67.89) v1(82.42,66.62) v1(82.42,65.35) v1(82.42,64.08) v1(82.6,96.49) v1(82.6,95.89) v1(82.65,93.95) v1(82.65,93.37) v1(82.68,75.11) v1(83.15,199.26) v1(83.06,180.09) v1(83.08,88.77) v1(83.21,113.78) v1(83.21,96.49) v1(83.21,95.89) v1(83.21,95.3) v1(83.69,180.09) v1(83.79,96.93) v1(83.79,95.3) v1(83.82,69.16) v1(83.82,67.89) v1(83.82,66.62) v1(83.82,65.35) v1(83.82,64.08) v1(83.95,75.16) v1(83.95,74.07) v1(84.4,96.93) v1(84.4,95.3) v1(84.57,75.44) v1(84.66,53.54) v1(84.77,72.9) v1(85.09,58.19) v1(85.22,69.16) v1(85.22,67.89) v1(85.22,66.62) v1(85.22,65.35) v1(85.22,64.08) v1(85.28,75.44) v1(85.42,53.54) v1(85.69,199.26) v1(85.89,72.9) v1(86,113.22) v1(86.18,53.54) v1(86.26,58.19) v1(86.72,113.22) v1(87.5,168.91) v1(87.5,167.64) v1(87.45,113.26) v1(87.76,96.27) v1(87.78,95.68) v1(88.14,168.91) v1(88.14,167.64) v1(88.23,199.26) v1(88.39,96.27) v1(88.42,95.68) v1(88.5,172.72) v1(88.52,35.05) v1(88.57,113.26) v1(88.69,160.99) v1(88.77,168.91) v1(88.77,167.64) v1(89.53,35.05) v1(89.81,160.99) v1(90.19,173.63) v1(90.4,157.68) v1(90.77,199.26) v1(91.11,157.68) v1(91.31,173.63) v1(91.41,59.89) v1(91.47,158.94) v1(91.64,59.28) v1(91.66,74.06) v1(92.08,168.91) v1(92.08,167.64) v1(92.18,158.94) v1(92.25,59.28) v1(92.37,74.06) v1(92.71,168.91) v1(92.71,167.64) v1(92.71,88.65) v1(92.71,86.87) v1(92.71,85.09) v1(92.71,83.31) v1(92.68,31.37) v1(92.68,30.58) v1(92.71,26.42) v1(92.76,174.55) v1(92.81,57.89) v1(92.76,29.39) v1(93.31,199.26) v1(93.34,168.91) v1(93.34,167.64) v1(93.42,52.78) v1(93.42,52.15) v1(93.88,174.55) v1(93.93,91.24) v1(93.94,74.06) v1(93.85,27.61) v1(93.98,168.91) v1(93.98,167.64) v1(93.95,57.89) v1(94.18,52.78) v1(94.18,52.15) v1(94.49,88.65) v1(94.49,86.87) v1(94.49,85.09) v1(94.49,83.31) v1(94.65,74.06) v1(94.89,161.45) v1(95.05,174.56) v1(95.02,26.85) v1(95.13,92.35) v1(95.05,91.24) v1(95.45,53.16) v1(95.61,161.45) v1(95.85,199.26) v1(95.94,26.85) v1(96.16,174.56) v1(96.23,73.15) v1(96.22,53.16) v1(96.25,92.35) v1(96.27,88.65) v1(96.27,86.87) v1(96.27,85.09) v1(96.27,83.31) v1(96.39,159.56) v1(96.77,26.85) v1(96.89,92.94) v1(96.94,73.15) v1(97.1,159.56) v1(97.41,33.3) v1(97.6,92.94) v1(97.61,26.9) v1(98.05,174.23) v1(98.04,88.65) v1(98.04,86.87) v1(98.04,85.09) v1(97.97,68.25) v1(97.97,67.13) v1(98.02,66.34) v1(98.02,64.47) v1(98.39,199.26) v1(98.42,168.91) v1(98.42,167.64) v1(98.51,71.37) v1(98.95,93) v1(98.96,27.61) v1(99.06,168.91) v1(99.06,167.64) v1(99.16,174.23) v1(99.23,71.37) v1(99.24,29.49) v1(99.59,33.27) v1(99.69,168.91) v1(99.69,167.64) v1(99.66,93) v1(100.33,168.91) v1(100.33,167.64) v1(100.69,160.99) v1(100.93,199.26) v1(101.05,174.23) v1(101.02,158.27) v1(101.17,58.5) v1(101.17,57.86) v1(101.73,158.27) v1(101.8,160.99) v1(102.16,174.23) v1(102.57,58.5) v1(102.57,57.86) v1(103.4,168.91) v1(103.4,167.64) v1(103.47,199.26) v1(104.04,168.91) v1(104.04,167.64) v1(104.39,159.85) v1(104.67,168.91) v1(104.67,167.64) v1(105.11,159.85) v1(105.26,161.87) v1(105.84,170.49) v1(105.87,164.64) v1(106.38,161.87) v1(106.55,170.49) v1(106.58,164.64) v1(106.81,35.05) v1(107.77,168.91) v1(107.77,167.64) v1(107.82,35.05) v1(108.41,168.91) v1(108.41,167.64) v1(108.55,199.26) v1(109.04,168.91) v1(109.04,167.64) v1(109.44,86.39) v1(109.44,85.12) v1(109.91,49.35) v1(109.91,48.74) v1(110.71,86.39) v1(110.71,85.12) v1(110.95,27.38) v1(110.97,31.27) v1(110.97,30.23) v1(111.02,28.98) v1(111,26.42) v1(111.09,199.26) v1(111.19,173.3) v1(111.91,39.56) v1(112.14,168.91) v1(112.14,167.64) v1(112.09,27.61) v1(112.31,173.3) v1(112.78,168.91) v1(112.78,167.64) v1(113.02,39.56) v1(113.33,26.9) v1(113.41,168.91) v1(113.41,167.64) v1(113.44,38.56) v1(113.63,199.26) v1(114.05,168.91) v1(114.05,167.64) v1(114.15,38.56) v1(114.27,26.9) v1(114.43,39.62) v1(115.14,26.92) v1(115.53,39.62) v1(115.62,33.25) v1(115.93,26.92) v1(116.17,199.26) v1(117.17,27.61) v1(117.55,29.54) v1(117.98,33.3) v1(118.62,168.91) v1(118.62,130.56) v1(118.62,129.92) v1(118.62,129.29) v1(118.71,199.26) v1(119.25,168.91) v1(119.25,167.64) v1(119.25,130.56) v1(119.25,129.92) v1(119.25,129.29) v1(119.89,168.91) v1(119.89,167.64) v1(120.52,168.91) v1(120.52,167.64) v1(121.25,199.26) v1(122.73,50.22) v1(122.73,49.1) v1(123.3,47.62) v1(123.3,45.74) v1(123.7,168.91) v1(123.7,167.64) v1(123.79,199.26) v1(124.33,168.91) v1(124.33,167.64) v1(124.43,49) v1(124.43,47.89) v1(124.97,168.91) v1(124.97,167.64) v1(125.09,35.43) v1(125.86,178.44) v1(125.98,42.16) v1(125.98,41.15) v1(126.11,35.43) v1(126.33,199.26) v1(126.62,178.44) v1(127.38,178.44) v1(127.74,52.35) v1(127.74,50.04) v1(128.87,199.26) v1(129.24,30.81) v1(129.26,31.7) v1(129.29,29.62) v1(129.29,26.8) v1(129.41,45.34) v1(130.19,39.01) v1(130.43,45.34) v1(130.35,27.97) v1(131.14,40.27) v1(131.31,39.01) v1(131.41,199.26) v1(131.44,45.85) v1(131.57,51.84) v1(131.57,27.1) v1(132.51,27.1) v1(132.72,38.99) v1(133.02,40.27) v1(133.35,51.56) v1(133.35,46.61) v1(133.32,27.1) v1(133.82,38.99) v1(133.83,33.63) v1(133.95,199.26) v1(134.11,50.29) v1(134.11,49.4) v1(134.11,48.64) v1(134.11,47.62) v1(134.19,27.1) v1(134.37,18.38) v1(134.65,82.55) v1(134.62,45.34) v1(135.28,83.19) v1(135.28,82.55) v1(135.48,27.94) v1(135.79,129.67) v1(135.84,29.95) v1(135.92,83.19) v1(135.92,82.55) v1(136.27,33.73) v1(136.49,199.26) v1(136.55,83.19) v1(136.55,82.55) v1(137.19,83.19) v1(137.19,82.55) v1(137.82,83.19) v1(137.82,82.55) v1(138.46,83.19) v1(138.46,82.55) v1(138.68,129.79) v1(138.68,129.16) v1(139.03,199.26) v1(139.09,83.19) v1(139.09,82.55) v1(139.22,107.7) v1(139.22,107.06) v1(140.49,107.7) v1(140.49,107.06) v1(141.1,129.79) v1(141.1,129.16) v1(141.27,19.58) v1(141.57,199.26) v1(141.63,105.41) v1(143.51,129.79) v1(143.51,129.16) v1(144.11,199.26) v1(144.09,19.74) v1(145.92,129.79) v1(145.92,129.16) v1(145.95,94.87) v1(145.95,94.23) v1(146.65,199.26) v1(146.58,94.87) v1(146.58,94.23) v1(146.58,93.6) v1(147.22,94.87) v1(147.22,94.23) v1(147.22,93.6) v1(147.22,18.38) v1(147.98,94.23) v1(147.98,93.6) v1(148.26,129.29) v1(148.36,64.14) v1(148.62,94.23) v1(148.62,93.6) v1(149,64.14) v1(149.19,199.26) v1(149.25,94.23) v1(149.25,93.6) v1(149.5,95.63) v1(149.5,95) v1(150.42,172.59) v1(151.46,39.88) v1(151.73,199.26) v1(152.12,39.88) v1(152.3,172.59) v1(152.53,141.99) v1(154.27,199.26) v1(156.81,199.26) v1(158.89,184.82) v1(158.89,184.11) v1(159.26,198.62) v1(159.26,196.08) v1(159.26,193.21) v1(159.26,190.67) v1(159.26,188.13) v1(159.26,185.59) v1(159.26,183.05) v1(159.26,182.33) v1(159.26,180.84) v1(159.26,178.3) v1(159.26,175.76) v1(159.26,173.22) v1(159.26,170.68) v1(159.26,168.14) v1(159.26,165.6) v1(159.26,163.06) v1(159.26,160.52) v1(159.26,157.98) v1(159.26,155.44) v1(159.26,152.9) v1(159.26,150.36) v1(159.26,147.82) v1(159.26,145.28) v1(159.26,142.74) v1(159.26,140.2) v1(159.26,137.66) v1(159.26,135.12) v1(159.26,132.58) v1(159.26,130.04) v1(159.26,127.5) v1(159.26,124.96) v1(159.26,122.42) v1(159.26,119.88) v1(159.26,117.34) v1(159.26,114.8) v1(159.26,112.26) v1(159.26,109.72) v1(159.26,107.18) v1(159.26,104.64) v1(159.26,102.1) v1(159.26,99.56) v1(159.26,97.02) v1(159.26,94.48) v1(159.26,91.94) v1(159.26,89.4) v1(159.26,86.86) v1(159.26,84.32) v1(159.26,81.78) v1(159.26,79.24) v1(159.26,76.7) v1(159.26,74.16) v1(159.26,71.62) v1(159.26,69.08) v1(159.26,66.54) v1(159.26,64) v1(159.26,61.46) v1(159.26,58.92) v2(10.74,127.08) v2(10.74,126.31) v2(12.32,163.45) v2(12.32,162.56) v2(12.32,159.51) v2(12.32,158.62) v2(13.21,163.45) v2(13.21,162.56) v2(13.21,159.51) v2(13.21,158.62) v2(14.1,163.45) v2(14.1,162.56) v2(14.1,159.51) v2(14.1,158.62) v2(14.99,163.45) v2(14.99,162.56) v2(14.99,159.51) v2(14.99,158.62) v2(15.88,163.45) v2(15.88,162.56) v2(15.88,159.51) v2(15.88,158.62) v2(18.8,164.59) v2(18.8,163.7) v2(18.8,160.66) v2(18.8,159.77) v2(19.3,120.65) v2(19.3,119.89) v2(19.63,129.36) v2(19.63,128.6) v2(19.63,127.84) v2(19.68,164.59) v2(19.68,163.7) v2(19.68,160.66) v2(19.68,159.77) v2(20.07,120.65) v2(20.07,119.89) v2(20.57,164.59) v2(20.57,163.7) v2(20.57,160.66) v2(20.57,159.77) v2(20.7,124.21) v2(20.7,123.44) v2(20.7,122.68) v2(20.7,121.92) v2(20.7,121.16) v2(20.83,120.4) v2(21.46,164.59) v2(21.46,163.7) v2(21.46,160.66) v2(21.46,159.77) v2(22.35,164.59) v2(22.35,163.7) v2(22.35,160.66) v2(22.35,159.77) v2(30.43,102.18) v2(30.43,101.3) v2(30.56,106.12) v2(30.56,105.23) v2(30.68,116.15) v2(30.68,113.23) v2(30.68,112.34) v2(31.32,102.18) v2(31.32,101.3) v2(31.45,106.12) v2(31.45,105.23) v2(31.57,116.15) v2(31.57,113.23) v2(31.57,112.34) v2(32.21,102.18) v2(32.21,101.3) v2(32.33,106.12) v2(32.33,105.23) v2(32.46,116.15) v2(32.46,113.23) v2(32.46,112.34) v2(33.1,102.18) v2(33.1,101.3) v2(33.22,106.12) v2(33.22,105.23) v2(33.35,116.15) v2(33.35,113.23) v2(33.35,112.34) v2(33.53,156.84) v2(33.53,156.08) v2(33.53,155.32) v2(33.53,154.56) v2(33.53,153.8) v2(33.99,102.18) v2(33.99,101.3) v2(34.11,106.12) v2(34.11,105.23) v2(34.24,116.15) v2(34.24,113.23) v2(34.24,112.34) v2(34.42,156.84) v2(34.42,156.08) v2(34.42,155.32) v2(34.42,154.56) v2(34.42,153.8) v2(35.31,156.84) v2(35.31,156.08) v2(35.31,155.32) v2(35.31,154.56) v2(35.31,153.8) v2(37.21,124.08) v2(37.21,123.32) v2(37.21,122.56) v2(37.21,121.79) v2(37.21,121.03) v2(37.97,124.08) v2(37.97,123.32) v2(37.97,122.56) v2(37.97,121.79) v2(37.97,121.03) v2(39.07,172.92) v2(39.07,172.03) v2(39.07,169.11) v2(39.07,168.22) v2(39.19,100.41) v2(39.19,99.64) v2(39.19,98.88) v2(39.19,90.75) v2(39.19,89.99) v2(39.19,89.23) v2(39.83,172.92) v2(39.83,172.03) v2(39.83,169.11) v2(39.83,168.22) v2(39.95,100.41) v2(39.95,99.64) v2(39.95,98.88) v2(39.95,90.75) v2(39.95,89.99) v2(39.95,89.23) v2(40.59,172.92) v2(40.59,172.03) v2(40.59,169.11) v2(40.59,168.22) v2(41.48,172.92) v2(41.48,172.03) v2(41.48,169.11) v2(41.48,168.22) v2(42.24,172.92) v2(42.24,172.03) v2(42.24,169.11) v2(42.24,168.22) v2(46.43,105.36) v2(47.19,105.36) v2(47.19,104.6) v2(47.19,103.84) v2(47.19,95.71) v2(47.19,94.95) v2(47.19,94.18) v2(47.96,104.6) v2(47.96,103.84) v2(47.96,95.71) v2(47.96,94.95) v2(47.96,94.18) v2(50.04,148.08) v2(50.04,147.19) v2(50.04,146.18) v2(51.05,148.08) v2(51.05,147.19) v2(51.05,146.18) v2(115.47,100.71) v2(115.47,98.42) v2(116.23,100.71) v2(116.23,98.42) v2(117.37,92.48) v2(117.37,91.69) v2(117.37,90.93) v2(117.75,86.49) v2(117.75,85.72) v2(117.75,84.2) v2(117.75,83.44) v2(117.75,81.92) v2(117.75,81.15) v2(123.72,92.71) v2(124.23,98.17) v2(124.23,97.41) v2(124.49,92.71) v2(124.99,98.17) v2(124.99,97.41) v2(128.04,88.77) v2(128.04,88.01) v2(128.68,82.17) v2(128.68,81.41) v2(128.8,88.77) v2(128.8,88.01) v2(129.44,82.17) v2(129.44,81.41) v2(129.57,88.77) v2(129.57,88.01) v2(130.2,82.17) v2(130.2,81.41) v2(130.33,88.77) v2(130.33,88.01) v2(130.96,82.17) v2(130.96,81.41) v2(131.72,82.17) v2(131.72,81.41) v2(132.49,82.17) v2(132.49,81.41) v2(133.12,99.82) v2(133.88,99.82) v2(134.65,100.58) v2(134.65,99.82) v2(134.77,91.57) v2(135.41,100.58) v2(135.41,99.82) v2(135.53,91.57) v2(137.19,100.58) v2(137.19,99.82) v2(137.19,91.57) v2(137.95,100.58) v2(137.95,99.82) v2(137.95,91.57) v4(23.29,34.16) v4(23.29,31.62) v4(24.56,32.89) v4(25.83,34.16) v4(25.83,31.62) v4(40.06,31.24) v4(40.06,28.7) v4(41.33,29.97) v4(42.6,31.24) v4(42.6,28.7) v4(58.34,31.24) v4(58.34,28.7) v4(59.61,29.97) v4(60.88,31.24) v4(60.88,28.7) v4(76.63,31.24) v4(76.63,28.7) v4(77.9,29.97) v4(79.17,31.24) v4(79.17,28.7) v4(94.92,31.24) v4(94.92,28.7) v4(96.19,29.97) v4(97.46,31.24) v4(97.46,28.7) v4(113.21,31.24) v4(113.21,28.7) v4(114.48,29.97) v4(115.75,31.24) v4(115.75,28.7) v4(129.79,50.09) v4(129.79,47.55) v4(131.06,48.82) v4(131.5,31.62) v4(131.5,29.08) v4(132.33,50.09) v4(132.33,47.55) v4(132.77,30.35) v4(134.04,31.62) v4(134.04,29.08) v5(139.57,146.43) v5(139.57,144.78) v5(139.57,143.13) v5(141.35,146.43) v5(141.35,143.13) v5(143.13,146.43) v5(143.13,144.78) v5(143.13,143.13) v6(130.27,157.07) v6(131.29,158.08)
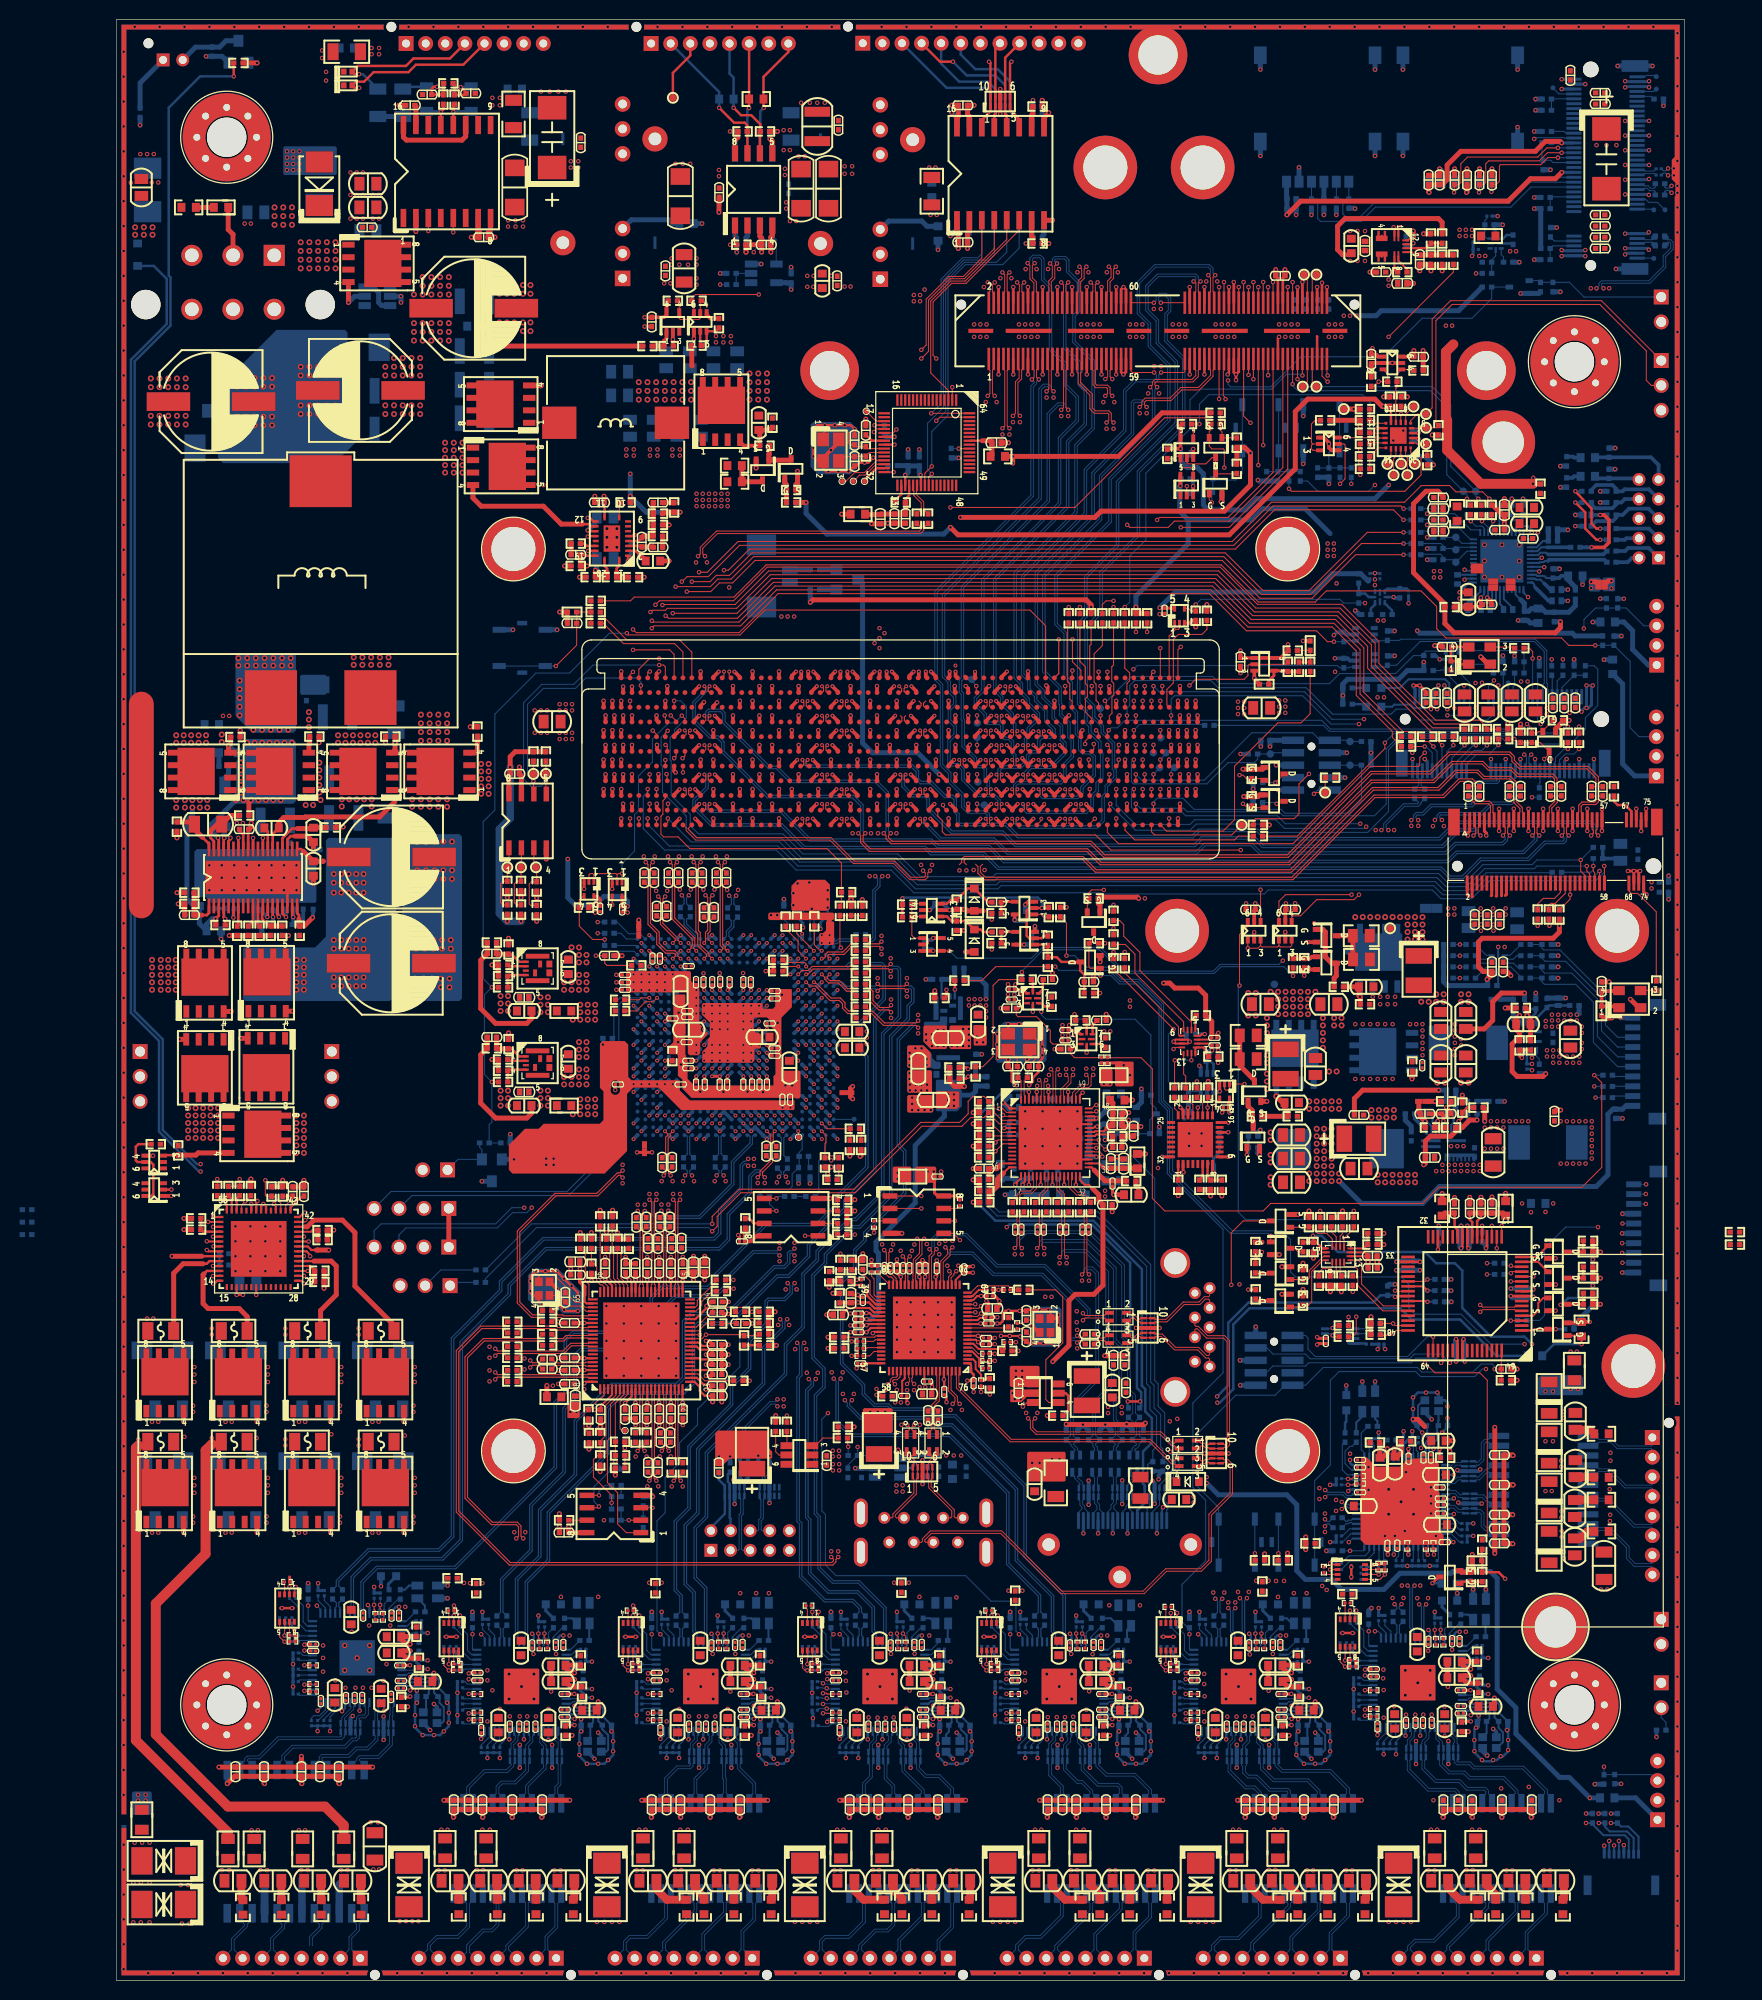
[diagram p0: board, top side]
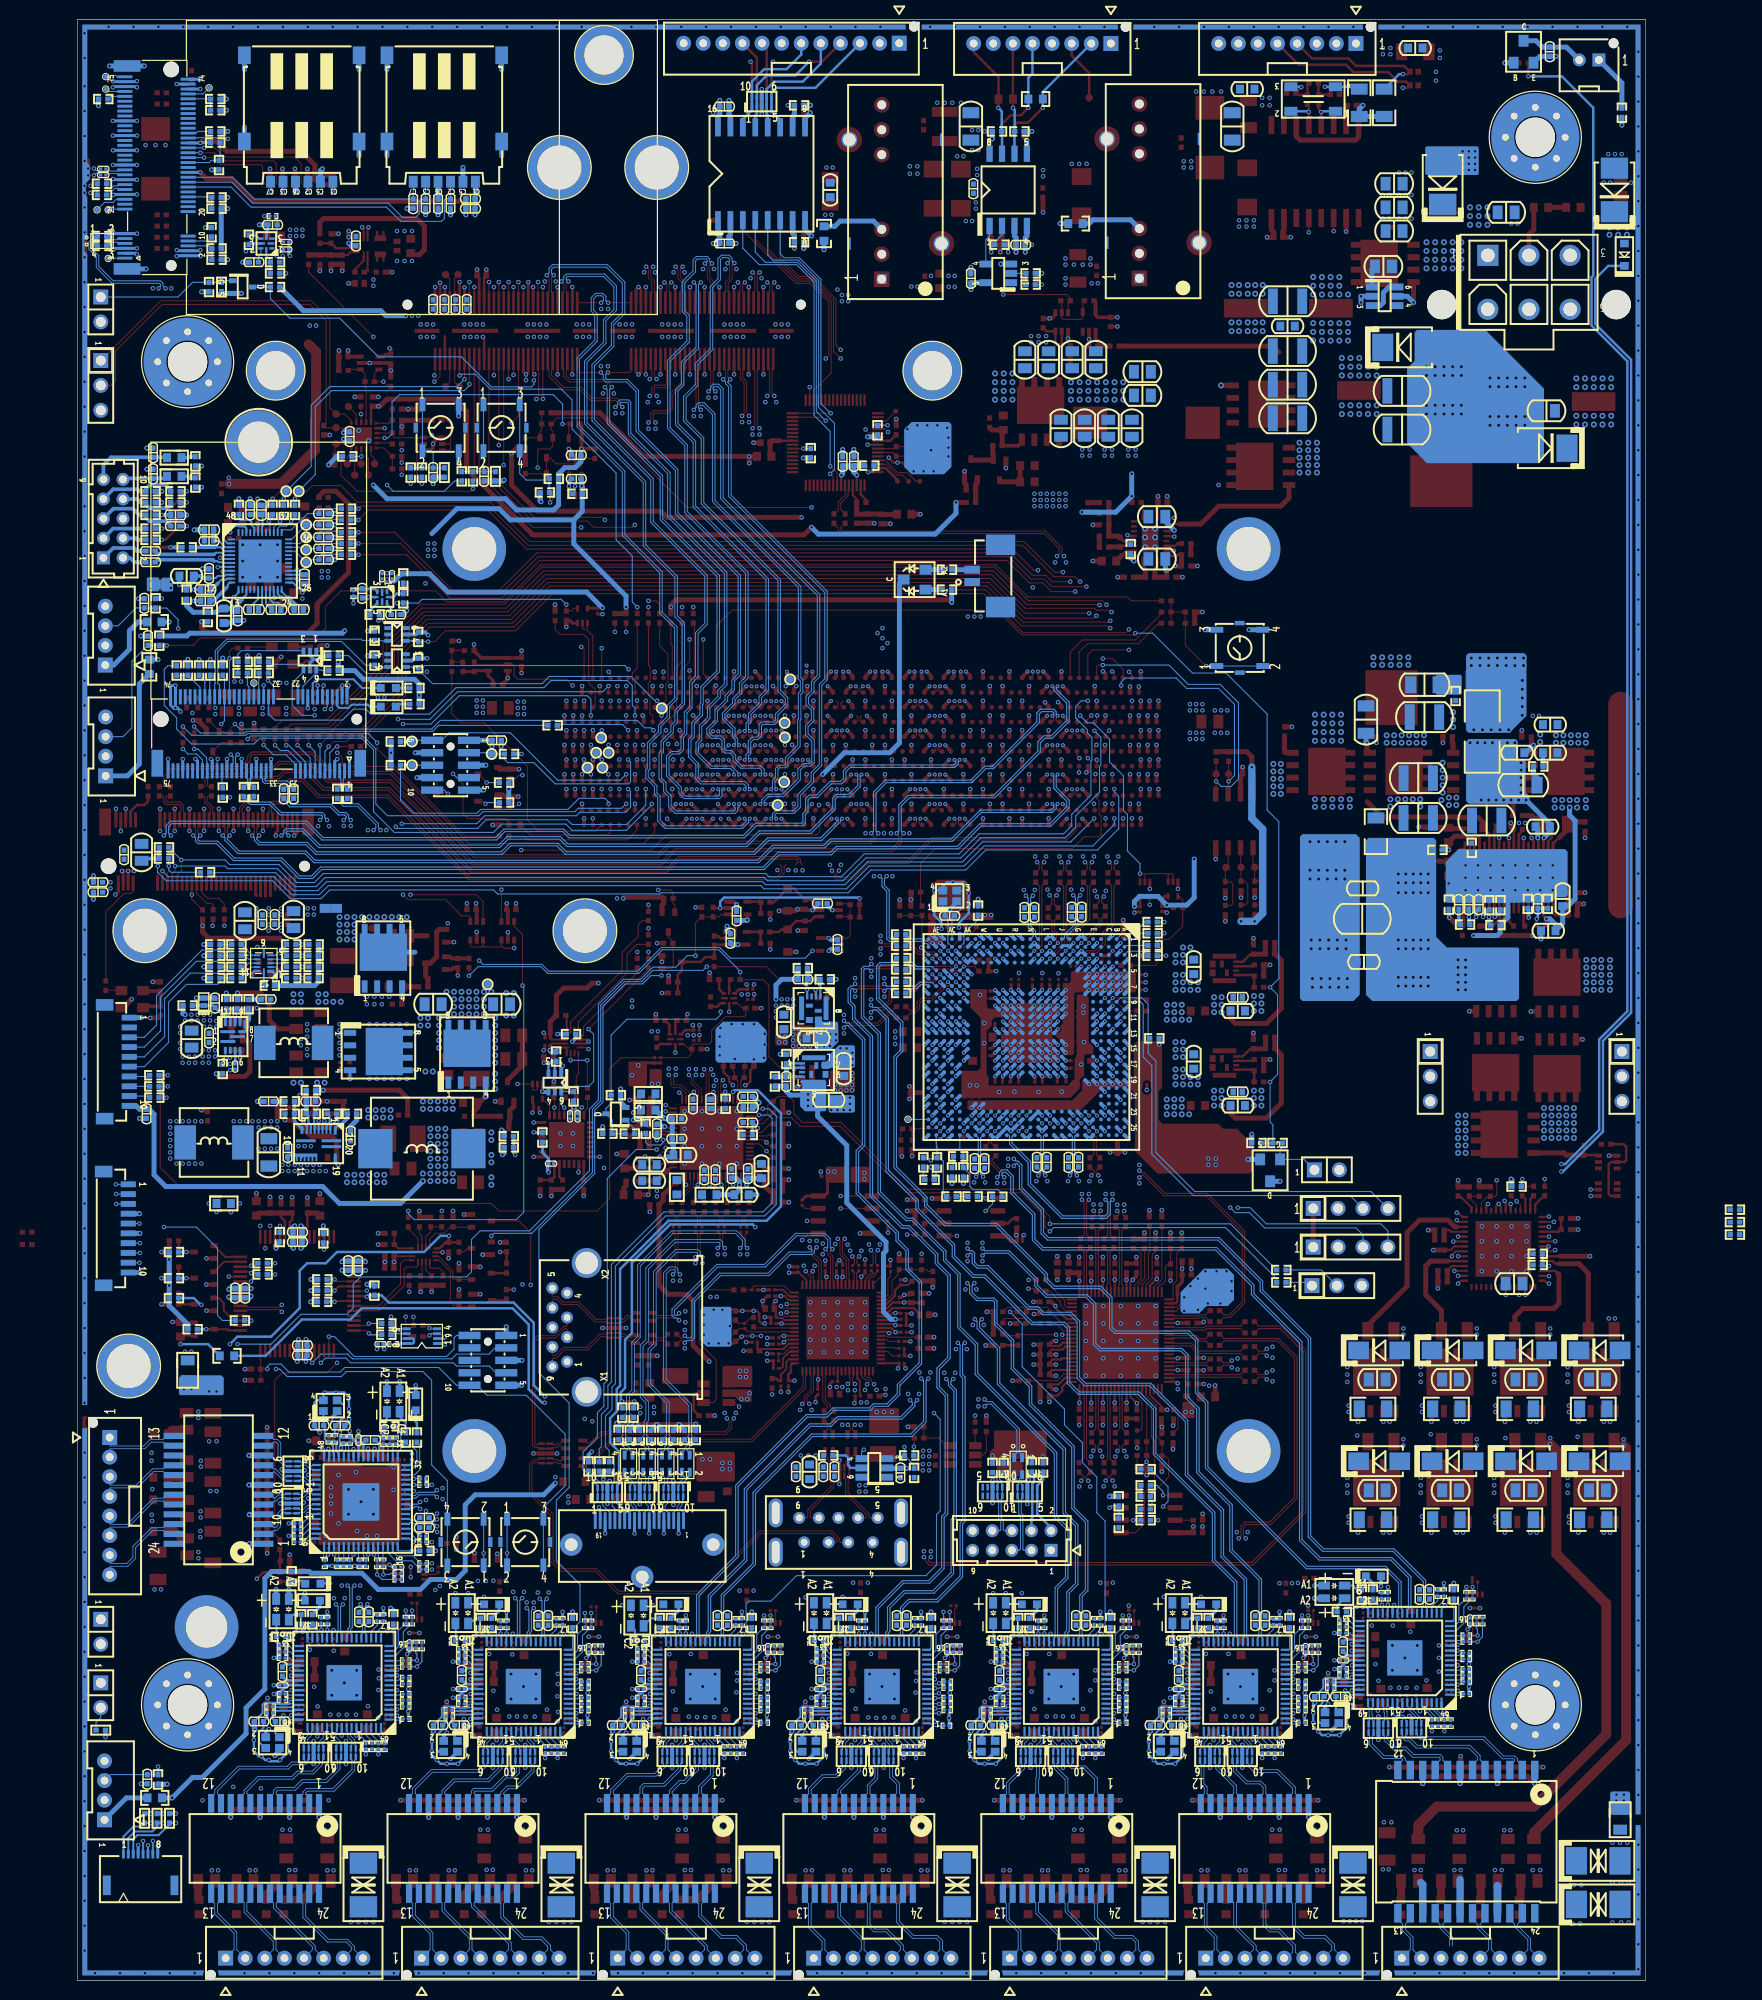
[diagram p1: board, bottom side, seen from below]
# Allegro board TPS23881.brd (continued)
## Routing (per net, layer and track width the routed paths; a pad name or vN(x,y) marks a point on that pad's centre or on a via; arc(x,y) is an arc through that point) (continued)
GNDA: length 101.2
  BOTTOM w0.305: v3(58.36,105.82) U67.H2 58.88,105.54 59.44,105.54 U67.J2
  BOTTOM w0.356: v3(63.96,93.02) 63.56,93.42 U67.P17 ; U67.N9 v3(62.36,100.22) ; U67.K14 v3(59.96,95.42) ; U67.L9 v3(60.76,100.22) ; v3(61.56,100.22) 61.96,99.82 U67.M9 ; U67.T17 65.16,93.42 v3(65.56,93.02) ; v3(64.76,93.02) 64.36,93.42 U67.R17 ; U67.M17 v3(61.56,93.02) ; U67.K12 v3(59.96,97.82) ; U67.T15 65.16,95.02 v3(65.56,94.62) ; U67.R9 v3(64.76,100.22) ; U67.K17 v3(59.96,93.02) ; U67.N17 v3(62.36,93.02) ; U67.T12 v3(65.56,97.82) ; U67.T13 v3(65.56,97.02) ; U67.P9 v3(63.96,100.22) ; U67.K9 v3(59.96,100.22) ; U67.T9 v3(65.56,100.22) ; U67.K13 v3(59.96,97.02) ; U67.L17 v3(60.76,93.02)
  BOTTOM w0.381: U67.D16 55.56,94.22 v3(55.16,93.82) ; v3(54.36,93.02) 54.76,93.42 U67.C17 ; U67.K24 60.36,87.82 v3(59.96,87.42) ; U67.AB21 v3(70.36,89.82) ; U67.H25 58.76,87.02 v3(58.36,86.62) 58.35,86.61 58.34,86.61 58.34,86.63 57.96,87.02 U67.G25 ; U67.T2 v3(65.56,105.82) ; v3(72.76,91.42) 72.36,91.82 U67.AE19 ; U67.A13 v3(52.76,97.02) ; U67.C1 v3(54.36,106.62) ; U67.AB10 v3(70.36,99.42) ; v3(55.96,93.02) 56.36,93.42 U67.E17 ; U67.AB18 v3(70.36,92.22) ; U67.D15 v3(55.16,94.62) ; v3(53.56,86.62) 53.96,87.02 U67.B25 ; U67.AD17 71.56,93.42 v3(71.96,93.02) ; U67.C13 v3(54.36,97.02) ; v3(55.16,86.62) 55.56,87.02 U67.D25 ; U67.F1 v3(57.56,106.62) U67.G1 ; U67.M4 v3(61.56,104.22) ; U67.AC6 v3(71.16,102.62) U67.AD5 ; U67.C14 v3(54.36,95.42) ; U67.B12 53.96,97.42 v3(53.56,97.82) ; U67.M2 v3(62.36,105.82) U67.N2 ; v3(55.16,89.02) 55.56,89.42 U67.D22 ; U67.M25 61.96,87.02 v3(61.56,86.62) 61.16,87.02 U67.L25 ; U67.L1 v3(60.76,106.62) U67.K1 ; U67.Y2 v3(67.96,105.82) ; U67.AA2 v3(68.76,105.82) ; U67.B15 v3(53.56,94.62) ; U67.A17 v3(52.76,93.02) ; U67.G3 v3(57.56,105.02) U67.F3 ; U67.AA26 69.16,86.21 v3(68.76,85.82) ; U67.R1 v3(64.76,106.62) ; v3(55.16,90.62) 55.56,91.02 U67.D20 ; v3(70.36,93.02) 69.96,93.42 U67.AB17 ; v3(55.96,95.42) 56.36,95.82 U67.E14 ; U67.J26 59.56,86.22 v3(59.16,85.82) ; U67.L23 61.16,88.62 v3(60.76,88.22) ; U67.AD9 v3(71.96,100.22) ; U67.AC15 70.76,95.02 v3(71.16,94.62) ; U67.N4 v3(62.36,104.22) ; v3(72.76,93.82) 72.36,94.22 U67.AE16 ; U67.AD21 v3(71.96,89.82) ; U67.AC25 v3(71.16,86.62) ; U67.AF17 73.16,93.42 v3(73.56,93.02) ; U67.C18 54.76,92.62 v3(54.36,92.22) ; U67.A10 v3(52.76,99.42) ; U67.B3 v3(53.56,105.02) ; U67.AB22 v3(70.36,89.02) ; U67.U2 v3(66.36,105.82) ; U67.W3 v3(67.96,105.02) ; v3(58.36,88.22) 58.76,88.62 U67.H23 ; U67.AF21 73.16,90.22 v3(73.56,89.82) ; U67.R3 v3(64.76,105.02) ; U67.AA7 v3(69.56,101.82) ; U67.N24 U67.M23 61.96,88.62 v3(61.56,88.22) ; U67.E24 56.36,87.82 v3(56.76,87.42) 57.16,87.82 U67.F24 ; U67.B21 53.96,90.22 v3(53.56,89.82) ; U67.T23 v3(65.56,88.22) 65.96,87.82 U67.U24 ; U67.C5 v3(54.36,103.42) ; U67.Y4 v3(68.76,104.22) U67.AA4 v3(69.56,104.22) ; U67.AC16 70.76,94.22 v3(71.16,93.82) ; U67.A24 53.16,87.82 v3(52.76,87.42) ; U67.AF18 73.16,92.62 v3(73.56,92.22) ; U67.W1 v3(67.96,106.62) ; U67.AE2 v3(72.76,105.82) ; v3(71.16,91.42) 70.76,91.82 U67.AC19 ; U67.AD7 v3(71.96,101.82) ; v3(54.36,88.22) 54.76,88.62 U67.C23 ; U67.Y23 v3(68.76,88.22) ; v3(52.76,90.62) 53.16,91.02 U67.A20 ; U67.AE1 v3(72.76,106.62) ; U67.AF22 73.16,89.42 v3(73.56,89.02) ; U67.E2 v3(55.96,105.82) ; v3(57.56,88.22) 57.96,88.62 U67.G23 ; v3(59.96,85.82) 60.36,86.22 U67.K26 ; v3(72.76,90.62) 72.36,91.02 U67.AE20 ; U67.K3 v3(60.76,105.02) U67.L3 ; U67.AF8 v3(73.56,101.02) ; U67.E4 v3(55.96,104.22) ; v3(59.16,87.42) 59.56,87.82 U67.J24 ; U67.B2 v3(53.56,105.82) ; U67.R23 v3(64.76,88.22) ; U67.A18 v3(52.76,92.22) ; U67.AD2 v3(71.96,105.82) ; U67.AC26 v3(71.16,85.82) ; U67.E13 v3(55.96,97.02) ; U67.E18 56.36,92.62 v3(55.96,92.22) ; U67.AD22 v3(71.96,89.02) ; U67.P3 v3(63.96,105.02) ; U67.C10 v3(54.36,99.42) ; U67.H4 v3(58.36,104.22) ; U67.V1 v3(67.16,106.62) ; U67.V26 66.76,86.21 v3(66.36,85.82) 65.96,86.22 U67.U26 U67.T25 65.16,87.01 v3(64.76,86.62) 64.36,87.02 U67.R25 v3(63.96,87.42) 63.56,87.82 U67.P24 ; U67.AF26 v3(73.56,85.82) ; v3(52.76,85.82) 53.16,86.22 U67.A26 ; U67.AE15 72.36,95.02 v3(72.76,94.62) ; U67.AB1 v3(69.96,106.76) ; U67.AB3 v3(70.36,105.02) ; U67.AF4 v3(73.56,104.22) ; U67.AC8 v3(71.16,101.02) ; U67.AC10 v3(71.16,99.42) ; U67.D23 55.56,88.62 v3(55.16,88.22) ; U67.AB8 v3(70.36,101.02) ; U67.V24 v3(67.16,87.42) ; U67.AD18 71.56,92.62 v3(71.96,92.22) ; U67.AD11 v3(71.96,98.62) ; U67.D12 v3(55.16,97.82) ; U67.B11 53.96,98.22 v3(53.56,98.62) ; U67.A14 v3(52.76,95.42) ; U67.J4 v3(59.16,104.22) ; U67.AC20 v3(71.16,90.62) ; U67.B16 v3(53.56,93.82) ; U67.T4 v3(65.56,104.22) ; U67.AC23 v3(71.16,88.22) ; U67.AE24 v3(72.76,87.42) ; U67.E26 56.36,86.22 v3(56.76,85.82) 57.16,86.22 U67.F26 ; U67.U4 v3(66.36,104.22) ; U67.W25 v3(67.96,86.62) 68.36,87.02 U67.Y25 ; U67.AF6 v3(73.56,102.62) ; U67.D11 v3(55.16,98.62) ; U67.N26 v3(63.16,85.82) 63.56,86.22 U67.P26 ; U67.V3 v3(67.16,105.02) ; U67.W23 v3(67.96,88.22) ; U67.AC4 v3(71.16,104.22) ; U67.P1 v3(63.96,106.62) ; U67.AA24 v3(69.56,87.42) ; U67.AF10 v3(73.56,99.42) ; U67.AE23 v3(72.76,88.22) ; U67.A4 v3(52.76,104.22) ; U67.AA5 v3(68.76,102.62) ; U67.AD1 v3(71.96,106.62)
V0P9_LAN1: length 5.1
  TOP w0.305: CB49.1 19.23,34.29 v1(19.18,34.24) ; CB66.1 29.93,32.13 v1(29.95,32.14)
  BOTTOM w0.229: v1(28.83,38.1) 28.52,38.1 28.31,37.9 U41.32 ; v1(19.18,34.24) 19.27,34.14 U41.11 ; U41.42 v1(29.95,32.14) ; U41.59 23.31,27.76 v1(23.01,27.46)
  vias: v1(29.46,38.1)
V0P9_LAN2: length 5
  TOP w0.305: v1(46.71,29.22) 46.7,29.21 CB82.1 ; v1(35.94,31.32) 35.99,31.37 CB68.1
  BOTTOM w0.229: v1(45.59,35.18) 45.28,35.18 45.08,34.98 U43.32 ; U43.59 v1(40.08,24.59) ; v1(35.94,31.32) 36.04,31.22 U43.11 ; U43.42 v1(46.71,29.22)
  vias: v1(46.23,35.18)
V0P9_LAN3: length 5
  TOP w0.305: v1(65,29.22) 64.99,29.21 CB83.1 ; v1(54.23,31.32) 54.28,31.37 CB69.1
  BOTTOM w0.229: v1(54.23,31.32) 54.33,31.22 U45.11 ; v1(63.88,35.18) 63.57,35.18 63.36,34.98 U45.32 ; U45.59 v1(58.36,24.59) ; U45.42 v1(65,29.22)
  vias: v1(64.52,35.18)
V0P9_LAN4: length 5
  TOP w0.305: CB84.1 83.27,29.21 v1(83.29,29.22) ; CB70.1 72.57,31.37 v1(72.52,31.32)
  BOTTOM w0.229: v1(82.17,35.18) 81.86,35.18 81.65,34.98 U47.32 ; U47.11 72.61,31.22 v1(72.52,31.32) ; U47.59 v1(76.65,24.59)
  BOTTOM w0.254: U47.42 v1(83.29,29.22)
  vias: v1(82.93,35.18)
V0P9_LAN5: length 5
  TOP w0.305: CB85.1 101.56,29.21 v1(101.57,29.22) ; CB71.1 90.86,31.37 v1(90.81,31.32)
  BOTTOM w0.229: U49.11 90.9,31.22 v1(90.81,31.32) ; U49.32 99.94,34.98 100.14,35.18 v1(100.46,35.18) ; U49.59 v1(94.94,24.59)
  BOTTOM w0.254: U49.42 v1(101.57,29.22)
  vias: v1(101.09,35.18)
V0P9_LAN6: length 5
  TOP w0.305: v1(119.86,29.22) 119.85,29.21 CB86.1 ; CB72.1 109.14,31.37 v1(109.09,31.32)
  BOTTOM w0.229: U51.42 v1(119.86,29.22) ; v1(109.09,31.32) 109.19,31.22 U51.11 ; v1(118.75,35.18) 118.43,35.18 118.23,34.98 U51.32 ; U51.59 v1(113.23,24.59)
  vias: v1(119.33,35.18)
V0P9_LAN7: length 5
  TOP w0.305: CB81.1 138.14,29.59 v1(138.15,29.6) ; CB67.1 127.43,31.75 v1(127.38,31.7)
  BOTTOM w0.229: U53.59 v1(131.52,24.97) ; U53.42 v1(138.15,29.6) ; v1(127.38,31.7) 127.48,31.6 U53.11 ; U53.32 136.52,35.36 136.72,35.56 v1(137.03,35.56)
  vias: v1(137.67,35.56)
V0P9_LAN8: length 5
  TOP w0.305: CB42.1 129.67,43.48 v1(129.72,43.43) ; v1(131.81,54.2) 131.83,54.19 CB32.1
  BOTTOM w0.229: U55.59 v1(136.45,47.57) ; v1(125.86,53.09) 125.86,52.77 126.06,52.57 U55.32 ; U55.11 129.81,43.53 v1(129.72,43.43) ; U55.42 v1(131.81,54.2)
  vias: v1(125.86,53.72)
V1P5_LAN1: length 10
  IN3 w0.508: v1(24.81,27.51) 26.13,26.19 27.94,26.19 28.73,26.97 28.73,28.93 29.38,29.58 v1(29.97,29.58)
  BOTTOM w0.203: U41.56 v1(24.81,27.51)
  BOTTOM w0.229: U41.47 29.91,29.64 v1(29.97,29.58)
V1P5_LAN2: length 9.9
  IN3 w0.508: v1(41.58,24.59) 42.79,23.37 45.19,23.37 45.69,23.88 45.69,25.88 46.47,26.66 v1(46.74,26.66)
  BOTTOM w0.229: U43.47 46.67,26.72 v1(46.74,26.66) ; U43.56 v1(41.58,24.59)
V1P5_LAN3: length 9.9
  IN3 w0.508: v1(59.86,24.59) 61.08,23.37 63.5,23.37 64.01,23.88 64.01,25.91 64.76,26.66 v1(65.02,26.66)
  BOTTOM w0.229: U45.47 64.96,26.72 v1(65.02,26.66) ; U45.56 v1(59.86,24.59)
V1P5_LAN4: length 10
  IN3 w0.508: v1(78.15,24.59) 79.5,23.24 81.56,23.24 82.32,24 82.32,25.93 83.05,26.66 v1(83.31,26.66)
  BOTTOM w0.229: U47.56 v1(78.15,24.59)
  BOTTOM w0.254: v1(83.31,26.66) 83.25,26.72 U47.47
V1P5_LAN5: length 9.9
  IN3 w0.508: v1(101.6,26.66) 101.33,26.66 100.48,25.81 100.48,23.88 99.97,23.37 97.66,23.37 v1(96.44,24.59)
  BOTTOM w0.229: U49.56 v1(96.44,24.59)
  BOTTOM w0.254: v1(101.6,26.66) 101.54,26.72 U49.47
V1P5_LAN6: length 9.9
  IN3 w0.508: v1(119.89,26.66) 119.62,26.66 118.77,25.81 118.77,23.88 118.26,23.37 115.95,23.37 v1(114.73,24.59)
  BOTTOM w0.229: U51.56 v1(114.73,24.59) ; v1(119.89,26.66) 119.82,26.72 U51.47
V1P5_LAN7: length 10.1
  IN3 w0.508: v1(133.02,24.97) 133.63,24.97 134.92,23.67 136.55,23.67 137.06,24.18 137.06,26.35 137.74,27.04 v1(138.18,27.04)
  BOTTOM w0.229: U53.56 v1(133.02,24.97) ; U53.47 138.11,27.1 v1(138.18,27.04)
V1P5_LAN8: length 7.7
  IN3 w0.508: v1(134.38,54.23) 134.38,53.86 135.53,52.7 135.53,50.08 v1(136.45,49.17)
  BOTTOM w0.229: v1(134.38,54.23) 134.31,54.17 U55.47 ; v1(136.45,49.17) 136.35,49.07 U55.56
V1P8_B: length 26.1
  IN3 w0.508: v1(144.65,180.72) 145.67,180.72 148.72,183.77 148.72,189.1 150.83,191.21 v1(157.84,191.21)
  BOTTOM w0.508: R222.1 v1(157.84,191.21) ; v1(144.65,180.72) R216.2 R212.2
V3.3_M2_B: length 11.9
  BOTTOM w0.254: U32.6 142.39,177.16 R226.2
  BOTTOM w0.305: v1(149.86,176.5) 149.78,176.42 NGFF1.4 147.52,176.42 v1(147.45,176.5) ; v1(147.45,175.87) 147.5,175.92 NGFF1.2 149.81,175.92 v1(149.86,175.87) ; RA51.1 v1(140.92,179.96) ; NGFF1.72 v1(149.86,193.42) ; NGFF1.70 v1(147.45,192.92) ; NGFF1.74 v1(147.45,193.92)
  BOTTOM w0.508: v1(146.94,178.79) R213.2 ; R221.2 v1(144.65,188.59)
  vias: v1(142.19,176.38) v1(142.8,176.38) v1(151,187.2) v1(152.02,187.2) v1(153.03,187.2)
V3P3_LAN1: length 27.5
  TOP w0.305: RA16.2 17.67,41.15 ; R290.1 RA23.2 18.15,35.28 v1(18.15,35.81)
  BOTTOM w0.203: 20.81,27.92 20.81,27.8 v1(20.52,27.51)
  BOTTOM w0.229: v1(25.65,38.28) 25.81,38.12 U41.27 ; v1(21.79,25.43) RA129.2 RA130.2 RA131.2 ; RA131.2 v1(20.52,25.43) ; RA131.2 RA132.2 ; 30.23,32.64 U41.41 ; 20.81,27.92 U41.64 ; U41.10 v1(19.18,33.64) ; U41.51 v1(27.31,27.51)
  BOTTOM w0.254: CB141.1 17.91,36.06 v1(18.15,35.81)
  BOTTOM w0.305: v1(31.75,35.43) RA68.1 RA67.1 RA66.1 ; LANLINK1.A1 v1(33.78,40.27) ; RA76.1 RA83.1 v1(18.02,32.26) RA90.1 RA92.1 R276.2 v1(18.02,29.97) R275.1 ; RA124.1 RA112.1 v1(70.98,29.34) RA102.1 RA96.1 ; v1(26.29,40.13) R269.1 R279.2 ; RA91.1 RA89.1 ; RA89.1 31.13,31.93 30.85,32.21 30.85,32.21 30.59,32.46 30.59,32.64 CB148.1 30.23,32.64 ; RA89.1 v1(31.75,31.75) ; v1(20.57,40.51) R277.2 R278.2
  BOTTOM w0.381: LANACT1.A v1(26.99,40.2)
  BOTTOM w0.508: LANLINK1.A2 v1(33.78,38.97) ; R274.2 v1(19.56,40.51)
V3P3_LAN2: length 23.7
  TOP w0.229: CB129.1 v1(37.21,24.64)
  TOP w0.254: U44.8 v1(34.91,32.89)
  TOP w0.305: R314.1 RA25.2 34.91,32.36 v1(34.91,32.89) ; RA20.2 v1(34.43,38.23)
  BOTTOM w0.229: RA155.2 RA154.2 RA153.2 v1(39.12,22.68) ; RA155.2 v1(37.85,22.68) ; RA155.2 RA156.2 ; U43.27 42.58,35.2 v1(42.42,35.36) ; U43.51 v1(44.08,24.51) ; U43.10 v1(35.94,30.72) ; v1(37.21,24.64) 37.58,25 U43.64 ; U43.41 46.99,29.72
  BOTTOM w0.254: v1(34.91,32.89) 34.67,33.14 CB147.1
  BOTTOM w0.305: R299.1 v1(34.79,27.05) R300.2 RA128.1 RA116.1 v1(34.79,29.34) RA104.1 RA98.1 ; v1(48.51,32.51) RA88.1 RA81.1 RA74.1 ; v1(37.34,37.59) R301.2 R302.2 ; v1(43.05,37.21) R293.1 R303.2 ; RA115.1 47.89,29.01 47.61,29.29 47.61,29.29 47.36,29.54 CB154.1 47.35,29.72 46.99,29.72 ; RA115.1 RA127.1 ; RA115.1 v1(48.51,28.83)
  BOTTOM w0.508: R298.2 v1(36.32,37.59)
  vias: v1(45.35,39.12) v1(49.15,39.12)
V3P3_LAN3: length 22.9
  TOP w0.229: CB130.1 v1(55.5,24.64)
  TOP w0.305: RA21.2 v1(52.72,38.23) ; v1(53.2,32.89) 53.2,32.36 RA26.2 R338.1
  BOTTOM w0.229: RA152.2 RA151.2 ; RA151.2 v1(56.13,22.68) ; RA151.2 RA150.2 RA149.2 v1(57.4,22.68) ; v1(55.5,24.64) 55.86,25 U45.64 ; U45.51 v1(62.36,24.51) ; U45.10 v1(54.23,30.72) ; v1(60.71,35.36) 60.86,35.2 U45.27 ; 65.28,29.72 U45.41
  BOTTOM w0.254: CB146.1 52.96,33.14 v1(53.2,32.89)
  BOTTOM w0.305: v1(66.8,32.51) RA87.1 RA80.1 RA73.1 ; R323.1 v1(53.07,27.05) R324.2 RA126.1 RA114.1 v1(53.07,29.34) RA103.1 RA97.1 ; v1(55.63,37.59) R325.2 R326.2 ; R327.2 R317.1 v1(61.34,37.21) ; 65.28,29.72 65.64,29.72 CB153.1 65.65,29.54 65.9,29.29 65.9,29.29 66.18,29.01 RA113.1 ; RA113.1 RA125.1 ; RA113.1 v1(66.8,28.83)
  BOTTOM w0.508: R322.2 v1(54.61,37.59)
  vias: v1(63.64,39.5) v1(65.26,39.5) v1(66.56,39.5)
V3P3_LAN4: length 19.5
  TOP w0.229: CB131.1 v1(73.79,24.64)
  TOP w0.305: v1(71.49,32.89) 71.49,32.36 RA27.2 R362.1
  BOTTOM w0.229: v1(72.52,30.72) U47.10 ; v1(73.79,24.64) 74.15,25 U47.64 ; RA147.2 v1(74.42,22.68) ; RA147.2 RA148.2 ; RA147.2 RA146.2 RA145.2 v1(75.69,22.68) ; v1(78.99,35.36) 79.15,35.2 U47.27 ; U47.51 v1(80.65,24.51) ; U47.41 83.57,29.72
  BOTTOM w0.254: v1(71.49,32.89) 71.25,33.14 CB145.1
  BOTTOM w0.305: RA72.1 RA79.1 RA86.1 v1(85.09,32.51) ; R348.2 70.98,27.3 71.06,27.23 v1(71.06,26.75) R347.1 ; v1(85.09,28.83) 84.64,28.83 83.93,29.54 CB152.1 83.93,29.72 83.57,29.72 ; R351.2 R341.1 v1(79.63,37.59) ; R350.2 R349.2 v1(73.91,37.59)
  BOTTOM w0.508: R346.2 v1(72.9,37.59)
  vias: v1(81.93,39.12) v1(85.7,39.07)
V3P3_LAN5: length 22.5
  TOP w0.229: CB132.1 v1(92.08,24.64)
  TOP w0.305: R386.1 RA28.2 89.78,32.36 v1(89.78,32.89)
  BOTTOM w0.229: U49.27 97.44,35.2 v1(97.28,35.36) ; RA143.2 RA142.2 RA141.2 v1(93.98,22.68) ; RA143.2 RA144.2 ; RA143.2 v1(92.71,22.68) ; U49.41 101.85,29.72 ; U49.51 v1(98.94,24.51) ; v1(92.08,24.64) 92.44,25 U49.64 ; U49.10 v1(90.81,30.72)
  BOTTOM w0.254: CB144.1 89.53,33.14 v1(89.78,32.89)
  BOTTOM w0.305: v1(97.92,37.21) R364.1 R375.2 ; 101.85,29.72 102.22,29.72 CB151.1 102.22,29.54 102.47,29.29 102.59,29.29 102.76,29.12 RA109.1 ; R371.1 v1(89.65,27.05) R372.2 RA122.1 RA110.1 v1(89.65,29.34) RA101.1 RA95.1 ; R374.2 R373.2 v1(92.2,37.59) ; v1(103.38,28.83) RA109.1 ; RA109.1 RA121.1 ; RA71.1 RA78.1 RA85.1 v1(103.38,32.51)
  BOTTOM w0.508: R370.2 v1(91.19,37.59)
  vias: v1(101.3,38.26) v1(104.42,38.26)
V3P3_LAN6: length 22.9
  TOP w0.229: CB133.1 v1(110.36,24.64)
  TOP w0.305: v1(108.07,32.89) 108.07,32.36 RA29.2 R410.1
  BOTTOM w0.229: RA139.2 RA138.2 RA137.2 v1(112.27,22.68) ; RA139.2 v1(111,22.68) ; RA139.2 RA140.2 ; v1(115.57,35.36) 115.73,35.2 U51.27 ; 120.14,29.72 U51.41 ; v1(110.36,24.64) 110.73,25 U51.64 ; U51.51 v1(117.23,24.51) ; U51.10 v1(109.09,30.72)
  BOTTOM w0.254: v1(108.07,32.89) 107.82,33.14 CB143.1
  BOTTOM w0.305: RA70.1 RA77.1 RA84.1 v1(121.67,32.51) ; R398.2 R389.1 v1(116.2,37.59) ; RA107.1 121.04,29.07 120.83,29.29 120.76,29.29 120.51,29.54 CB150.1 120.51,29.72 120.14,29.72 ; RA107.1 RA119.1 ; RA107.1 v1(121.67,28.83) ; R399.2 R397.2 v1(110.49,37.59) ; R395.1 v1(107.94,27.05) R396.2 RA120.1 RA108.1 v1(107.94,29.34) RA100.1 RA94.1
  BOTTOM w0.508: R394.2 v1(109.47,37.59)
  vias: v1(118.5,39.12) v1(120.13,39.5) v1(121.43,39.5)
V3P3_LAN7: length 25.3
  TOP w0.229: CB108.1 v1(128.65,25.02)
  TOP w0.305: v1(126.35,33.27) 126.35,32.74 RA24.2 R434.1
  BOTTOM w0.229: RA136.2 RA135.2 ; RA135.2 v1(129.29,23.06) ; RA135.2 RA134.2 RA133.2 v1(130.56,23.06) ; U53.51 v1(135.52,24.89) ; U53.64 129.02,25.38 v1(128.65,25.02) ; U53.10 v1(127.38,31.1) ; v1(133.86,35.74) 134.02,35.58 U53.27 ; 138.43,30.1 U53.41
  BOTTOM w0.254: v1(126.35,33.27) 126.11,33.52 CB142.1
  BOTTOM w0.305: RA105.1 139.33,29.39 139.05,29.67 139.05,29.67 138.8,29.92 CB149.1 138.79,30.1 138.43,30.1 ; RA105.1 v1(139.95,29.21) ; RA105.1 RA117.1 ; v1(128.78,37.97) R421.2 R422.2 ; R423.2 R412.1 v1(134.49,37.59) ; RA93.1 RA99.1 v1(126.23,29.72) RA106.1 RA118.1 R420.2 v1(126.23,27.43) R419.1 ; RA69.1 RA75.1 RA82.1 v1(139.95,32.89)
  BOTTOM w0.508: R418.2 127.76,37.69 v1(128.04,37.97) ; LANLINK7.A1 v1(138.42,39.88) ; LANACT7.A v1(136.79,39.5) ; LANLINK7.A2 v1(139.71,39.88)
V3P3_LAN8: length 24.7
  TOP w0.229: CB40.1 v1(136.4,44.7)
  TOP w0.305: R458.1 RA14.2 128.68,42.41 v1(128.14,42.41)
  BOTTOM w0.229: v1(125.68,49.91) 125.84,50.07 U55.27 ; 131.31,54.48 U55.41 ; U55.64 136.03,45.07 v1(136.4,44.7) ; U55.51 v1(136.45,51.57) ; U55.10 v1(130.31,43.43)
  BOTTOM w0.254: v1(128.14,42.41) 127.9,42.16 CB140.1 ; v1(138.43,45.34) RA60.2 RA61.2 ; v1(138.43,46.61) RA58.2 RA59.2
  BOTTOM w0.305: v1(132.21,56.01) RA54.1 ; RA54.1 132.03,55.38 131.75,55.11 131.75,55.1 131.5,54.85 CB139.1 131.31,54.85 131.31,54.48 ; RA54.1 RA53.1 ; v1(128.78,55.88) RA55.1 RA56.1 RA57.1 ; R446.2 R437.1 v1(123.83,50.55) ; R447.2 R445.2 v1(123.83,44.7) ; R443.1 v1(133.99,42.28) R444.2 RA62.1 RA63.1 v1(131.7,42.28) RA64.1 RA65.1
  BOTTOM w0.381: LANACT8.A v1(125.48,60.68) ; LANLINK8.A1 v1(127.11,61.09) ; LANLINK8.A2 v1(128.41,61.09)
  BOTTOM w0.508: R442.2 v1(123.44,43.81)
VBUS_IN: length 4.5
  TOP w0.229: R163.1 75.25,70.93 RA7.1 76.59,70.36 76.59,69.83 77.47,68.95 U20.42
VCC1.8: length 2.1
  TOP w0.229: U25.24 77.34,157.04
  TOP w0.254: C70.1 77.05,157.04 77.34,157.04
VCC5_USB2:
  vias: v1(79.58,50.5) v1(79.58,49.86) v1(80.21,50.5) v1(80.21,49.86)
VCC25P: length 49.6
  TOP w0.229: U70.24 59.22,61.46 59.89,60.78 60.69,60.78 CM18.1 ; U70.54 v1(54.16,71.46) ; U70.48 v1(56.56,71.33) ; 47.76,69.93 47.76,69.23 47.94,69.06 U70.68 ; U70.85 v1(47.74,62.26) ; U70.29 59.51,63.46 59.63,63.33 60.53,63.33 60.82,63.05 CM20.1 ; U70.13 v1(54.16,58.93) ; U70.19 v1(56.56,58.93)
  TOP w0.305: C349.1 61.59,101.05 v3(61.56,101.02) ; C333.1 60.02,92.16 v3(59.96,92.22) ; C340.1 59.15,93.8 v3(59.16,93.82) ; C355.1 60.78,101.04 v3(60.76,101.02) ; v3(59.96,101.02) 59.89,101.09 C338.1 ; C351.1 64.72,101.06 v3(64.76,101.02) ; C359.1 62.31,92.16 v3(62.36,92.22) ; v3(59.16,92.22) 59.13,92.19 C353.1 ; v3(55.96,97.82) 56.26,98.12 C357.1 ; v3(59.16,93.02) 59.14,93.04 C346.1 ; C336.1 65.61,92.17 v3(65.56,92.22) ; v3(66.36,92.22) 66.37,92.21 C343.1
  TOP w0.381: CM19.1 54.15,72.04 54.15,71.47 v1(54.16,71.46) ; v1(60.15,60.27) 60.44,60.27 CM18.1 ; v1(47.74,62.26) 47.73,62.24 46.71,62.24 CM17.1 ; CM21.1 56.57,58.92 v1(56.56,58.93) ; CM22.1 56.55,72.03 56.55,71.34 v1(56.56,71.33) ; CM23.1 54.16,58.44 v1(54.16,58.93) ; v1(60.15,62.81) CM20.1 ; CB9.2 v1(47.28,72.59) CM24.1 47.28,71.23 47.76,70.75 47.76,69.93
  TOP w0.508: C377.1 v1(60.02,71.45)
  BOTTOM w0.356: v3(65.56,92.22) 65.16,92.62 U67.T18 ; U67.U18 v3(66.36,92.22) ; U67.M8 61.96,100.62 v3(61.56,101.02) ; U67.T8 v3(65.56,101.02) ; U67.J16 v3(59.16,93.82) ; U67.R8 v3(64.76,101.02) ; U67.K8 v3(59.96,101.02) ; U67.K18 v3(59.96,92.22) ; U67.J18 v3(59.16,92.22) ; U67.L8 v3(60.76,101.02) ; U67.U10 v3(66.36,99.42) ; U67.J17 v3(59.16,93.02) ; U67.N18 v3(62.36,92.22)
  BOTTOM w0.381: U67.AA16 69.16,94.22 v3(69.56,93.82) ; v3(73.56,95.42) 73.16,95.82 U67.AF14 ; U67.AF12 73.16,97.42 v3(73.56,97.82) ; U67.AA13 69.16,96.62 v3(69.56,97.02) ; v3(71.16,97.02) 70.76,96.62 U67.AC13 ; U67.AA14 69.16,95.82 v3(69.56,95.42) ; v3(71.96,97.02) 71.56,96.62 U67.AD13 ; v3(71.96,95.42) 71.56,95.82 U67.AD14 ; v3(71.16,97.82) 70.76,97.42 U67.AC12 ; U67.AD12 71.56,97.42 v3(71.96,97.82) ; U67.AA12 69.16,97.42 v3(69.56,97.82) ; U67.E11 v3(55.96,98.62) ; U67.AE12 72.36,97.42 v3(72.76,97.82) ; U67.AB13 69.96,96.62 v3(70.36,97.02) ; v3(70.36,95.42) 69.96,95.82 U67.AB14 ; v3(70.36,97.82) 69.96,97.42 U67.AB12 ; v3(72.76,97.02) 72.36,96.62 U67.AE13 ; U67.E12 v3(55.96,97.82) ; v3(69.56,94.62) 69.16,95.02 U67.AA15 ; U67.AC14 70.76,95.82 v3(71.16,95.42) ; v3(72.76,95.42) 72.36,95.82 U67.AE14 ; v3(73.56,97.02) 73.16,96.62 U67.AF13
  vias: v2(46.56,88.34) v2(47.32,89.87) v2(47.32,89.1) v2(47.32,88.34) v2(48.08,89.87) v2(48.08,89.1) v2(48.08,88.34) v2(48.84,89.87) v2(48.84,89.1) v2(48.84,88.34)
VCC_DCIN: length 66.9
  TOP w0.279: v1(10.11,108.28) 10.44,108.61 U83.3
  TOP w0.508: R663.1 38.05,166.7 37.41,166.07 ; R740.2 10.13,108.25 v1(10.11,108.28) ; R720.1 v1(47.24,143.13)
  IN1 w0.508: v1(47.24,143.13) 47.24,142.62 46.1,141.48 37.34,141.48 35.76,143.05 35.76,149.91 30.99,154.69 v2(30.99,159.77)
  BOTTOM w0.508: v2(7.75,119.63) 7.75,118.85 7.19,118.29 7.19,110.31 7.92,109.58 C459.2 8.46,107.8 C922.2 9.19,107.72 9.75,108.28 v1(10.11,108.28)
  vias: v2(6.1,127) v2(6.1,126.24) v2(6.1,120.4) v2(6.1,119.63) v2(6.86,127) v2(6.86,126.24) v2(6.99,120.4) v2(6.99,119.63) v2(7.62,127) v2(7.62,126.24) v2(7.75,120.4) v2(8.38,127) v2(8.38,126.24) v2(8.51,120.4) v2(8.51,119.63) v2(9.14,127) v2(9.14,126.24) v2(9.27,120.4) v2(9.27,119.63) v2(27.43,164.59) v2(27.43,163.7) v2(27.43,160.66) v2(27.43,159.77) v2(28.32,165.48) v2(28.32,164.59) v2(28.32,163.7) v2(28.32,160.66) v2(28.32,159.77) v2(29.21,165.48) v2(29.21,164.59) v2(29.21,163.7) v2(29.21,160.66) v2(29.21,159.77) v2(30.1,165.48) v2(30.1,164.59) v2(30.1,163.7) v2(30.1,160.66) v2(30.1,159.77) v2(30.35,171.96) v2(30.35,169.04) v2(30.35,168.15) v2(30.35,167.26) v2(30.99,165.48) v2(30.99,164.59) v2(30.99,163.7) v2(30.99,160.66) v2(31.24,173.74) v2(31.24,172.85) v2(31.24,171.96) v2(31.24,169.04) v2(31.24,168.15) v2(31.24,167.26) v2(32.13,173.74) v2(32.13,172.85) v2(32.13,171.96) v2(32.13,169.04) v2(32.13,168.15) v2(32.13,167.26) v2(33.02,173.74) v2(33.02,172.85) v2(33.02,171.96) v2(33.02,169.04) v2(33.02,168.15) v2(33.02,167.26) v2(33.91,173.74) v2(33.91,172.85) v2(33.91,171.96) v2(33.91,169.04) v2(33.91,168.15) v2(33.91,167.26)
VCC_SRC: length 177.1
  TOP w0.381: J1.F2 v1(50.8,126.02) ; J1.C1 v1(49.7,121.52) ; J1.E65 v1(110.1,124.52) ; J1.C2 v1(50.6,121.52) ; J1.B3 v1(51.7,120.02) ; J1.H1 v1(49.9,129.02) ; J1.J65 v1(110.1,130.52) ; J1.B63 v1(108.5,120.02) ; J1.H65 v1(110.3,129.02) ; J1.D2 v1(50.8,123.02) ; J1.K3 v1(51.7,131.97) ; J1.D3 v1(51.7,123.02) ; J1.G64 v1(109.2,127.52) ; J1.J64 v1(109.2,130.52) ; J1.C64 v1(109.2,121.52) ; J1.H3 v1(51.7,129.02) ; J1.J1 v1(49.7,130.52) ; J1.C63 v1(108.3,121.52) ; J1.G2 v1(50.6,127.52) ; J1.J63 v1(108.3,130.52) ; J1.J2 v1(50.6,130.52) ; J1.F1 v1(49.9,126.02) ; J1.E63 v1(108.3,124.52) ; J1.G65 v1(110.1,127.52) ; J1.H64 v1(109.4,129.02) ; J1.E2 v1(50.6,124.52) ; J1.E1 v1(49.7,124.52) ; J1.H2 v1(50.8,129.02) ; J1.D1 v1(49.9,123.02) ; J1.F64 v1(109.4,126.02) ; J1.G63 v1(108.3,127.52) ; J1.C65 v1(110.1,121.52) ; J1.G1 v1(49.7,127.52) ; J1.F3 v1(51.7,126.02) ; J1.D65 v1(110.3,123.02) ; J1.E64 v1(109.2,124.52) ; J1.D64 v1(109.4,123.02) ; J1.F65 v1(110.3,126.02) ; J1.F63 v1(108.5,126.02)
  TOP w0.508: v1(6.17,110.95) RZ27.1
  IN1 w0.508: U39.2 50.07,174.57 43.26,174.57 41.35,176.48 25.6,176.48 22.56,179.53 22.56,187.15 16.97,192.74 15.7,192.74 13.03,195.4 9.86,195.4 3.68,189.23 v1(2.41,189.23) 2.41,188.95 5.16,186.21 5.16,168.61 1.98,165.43 1.98,111.96 3,110.95 v1(6.17,110.95)
  BOTTOM w0.508: R139.2 v1(2.41,189.23)
  vias: v1(45.21,130.18) v1(45.21,129.54) v1(45.21,127.25) v1(45.21,126.62) v1(45.85,130.18) v1(45.85,129.54) v1(45.85,127.25) v1(45.85,126.62) v1(46.48,130.18) v1(46.48,129.54) v1(46.48,127.25) v1(46.48,126.62) v1(56.64,175.64) v1(56.64,175.01) v1(57.43,175.01) v1(58.32,175.01) v1(59.13,144.64) v1(59.18,175.64) v1(59.18,175.01) v1(59.18,151.64) v1(59.18,151) v1(59.18,150.37) v1(59.82,151.64) v1(59.82,151) v1(59.82,150.37) v1(60.25,144.64) v1(60.45,151.64) v1(60.45,151) v1(60.45,150.37) v1(61.09,151.64) v1(61.09,151) v1(61.09,150.37) v1(61.72,151.64) v1(61.72,151) v1(61.72,150.37) v1(62.36,151.64) v1(62.36,151) v1(62.36,150.37) v1(70.48,173.86) v1(71.12,173.86) v1(72.9,173.86) v1(114.43,130.43) v1(114.43,129.79) v1(114.43,129.16) v1(115.06,130.43) v1(115.06,129.79) v1(115.06,129.16)
VDD105: length 12.9
  TOP w0.229: U70.33 59.43,65.06 59.77,64.72 60.69,64.72 CM5.1 ; CM8.1 60.02,59.64 59.51,60.15 59.51,60.53 58.98,61.06 U70.23 ; v1(52.32,71.45) 52.37,71.4 52.37,71.35 52.56,71.16 U70.58 ; U70.9 52.56,59.54 v1(51.89,58.88)
  TOP w0.381: CM11.1 v1(51.89,58.88) ; v1(60.15,65.23) 60.44,65.23 CM5.1 ; v1(52.32,71.45) 51.94,71.83 CM14.1
  TOP w0.508: FB36.2 v1(43.92,60.68) ; CM8.1 v1(60.82,59)
  vias: v1(44.53,60.66)
VDD105P: length 53.8
  TOP w0.229: U70.51 v1(55.36,71.46) ; U70.16 v1(55.36,58.93) ; U70.10 52.95,60.29 v1(52.95,58.93) ; U70.26 60.59,62.26 60.82,62.03 CM6.1 ; U70.82 v1(47.74,63.46) ; U70.73 v1(47.74,67.06) ; U70.45 v1(57.76,71.33) ; U70.88 47.89,61.06 v1(47.74,60.9) ; CM2.1 60.82,64.11 60.59,64.34 59.51,64.34 59.19,64.66 U70.32 ; U70.22 v1(57.76,58.93)
  TOP w0.254: U70.57 v1(52.96,71.45)
  TOP w0.305: C354.1 66.67,94.31 v3(66.36,94.62) ; v3(66.36,100.22) 66.43,100.15 C352.1 ; v3(59.16,101.02) 59.13,101.05 C337.1 ; C332.1 64.76,91.73 v3(64.76,92.22) ; v3(63.96,92.22) 63.96,92.21 C350.1 ; C339.1 66.71,95.07 v3(66.36,95.42) ; C358.1 66.46,100.91 v3(66.36,101.02) ; C335.1 63.96,101.02 v3(63.96,101.02) ; v3(66.36,97.02) 66.37,97.03 C342.1 ; C356.1 62.56,101.22 v3(62.36,101.02) ; v3(60.76,92.22) v3(61.56,92.22) 61.54,92.2 C364.1
  TOP w0.381: CM6.1 60.69,61.67 v1(60.15,61.67) ; CM2.1 v1(60.15,63.83) ; CM12.1 55.37,58.92 v1(55.36,58.93) ; CM4.1 55.37,71.47 v1(55.36,71.46) ; v1(57.76,58.93) 57.78,58.9 CM15.1 ; v1(47.74,67.06) CM3.1 ; v1(57.76,71.33) 57.78,71.36 CM13.1 ; v1(47.74,63.46) 47.69,63.5 CM9.1 ; CM16.1 52.96,58.92 v1(52.95,58.93)
  TOP w0.508: CM13.1 58.8,72.17 CB7.2 v1(58.88,71.45) ; CM7.1 v1(52.96,71.45)
  BOTTOM w0.356: U67.U15 v3(66.36,94.62) ; U67.J14 v3(59.16,95.42) ; U67.J11 v3(59.16,98.62) ; U67.M18 v3(61.56,92.22) ; U67.N8 v3(62.36,101.02) ; U67.P18 63.56,92.62 v3(63.96,92.22) ; v3(64.76,92.22) 64.36,92.62 U67.R18 ; U67.U14 v3(66.36,95.42) ; U67.L18 v3(60.76,92.22) ; U67.U9 v3(66.36,100.22) ; U67.J8 v3(59.16,101.02) ; U67.P8 v3(63.96,101.02) ; U67.U13 v3(66.36,97.02) ; U67.U8 v3(66.36,101.02) ; U67.J10 v3(59.16,99.42) ; U67.J15 v3(59.16,94.62) ; U67.U16 v3(66.36,93.82) ; U67.J9 v3(59.16,100.22) ; U67.U17 v3(66.36,93.02)
  BOTTOM w0.381: U67.A8 v3(52.76,101.02) ; U67.C8 v3(54.36,101.02) ; U67.D8 v3(55.16,101.02) ; v3(53.56,101.02) 53.96,100.62 U67.B8 ; U67.B6 53.96,102.22 v3(53.56,102.62) ; U67.A7 v3(52.76,101.82) ; U67.E7 v3(55.96,101.82) ; U67.A6 v3(52.76,102.62) ; U67.E6 v3(55.96,102.62) ; U67.D7 v3(55.16,101.82) ; U67.F6 v3(56.76,102.62) ; U67.B7 53.96,101.42 v3(53.56,101.82) ; U67.C6 54.36,102.62 v3(54.36,102.62) ; U67.D6 v3(55.16,102.62) ; U67.E8 v3(55.96,101.02) ; U67.C7 v3(54.36,101.82) ; U67.F8 v3(56.76,101.02) ; U67.F7 v3(56.76,101.82)
  vias: v1(47.73,60.3) v2(46.56,97.99) v2(47.32,99.52) v2(47.32,98.76) v2(47.32,97.99) v2(48.08,99.52) v2(48.08,98.76) v2(48.08,97.99) v2(48.84,99.52) v2(48.84,98.76) v2(48.84,97.99)
VDD_1V8_CDC: length 35.2
  TOP w0.508: v1(147.32,138.58) 147.32,137.98 146.81,137.46 136.47,137.46 135.53,138.4 RZ12.2 135.53,140.39 132.33,143.59 132.33,150.62 133.6,151.89 134.84,151.89 135.34,151.39 CA48.1 ; CA51.1 141.6,147.97 v1(141.6,148.59) C30.1 141.37,149.52 140.42,150.47 R112.1
  BOTTOM w0.203: U16.43 141.55,148.54 v1(141.6,148.59)
  BOTTOM w0.508: RZ168.2 v1(147.32,138.58)
VDD_A: length 34.5
  TOP w0.203: U66.36 99.84,84.13 v1(99.97,84) ; U66.17 92.29,81.85 91.84,81.4 91.84,81.28 v1(91.71,81.15) ; U66.45 99.77,87.73 v1(99.97,87.93) 99.77,88.13 U66.46
  IN1 w0.508: v1(99.97,87.93) 100.05,88.01 100.74,88.01 101.51,87.24 101.51,84.49 101.24,84.23 101.24,83.82 100.74,83.31 ; 100.74,83.31 100.21,83.31 99.97,83.54 v1(99.97,84) ; 100.74,83.31 100.1,82.68 100.1,79.5 99.59,78.99 92.22,78.99 91.71,79.5 v1(91.71,81.15)
  BOTTOM w0.508: FB34.1 100.76,88.54 100.15,87.93 v1(99.97,87.93) 99.92,87.88 C315.1 C316.1 99.3,85.33 99.19,85.22 C314.1 99.39,84 v1(99.97,84) ; v1(91.71,81.15) 91.71,81.71 C317.1 91.58,81.81 C313.1
VDD_BBAT: length 27
  TOP w0.381: J1.D37 84.05,123.01 v1(83.95,123.01)
  BOTTOM w0.508: v1(83.95,123.01) 81.74,125.22 77.11,125.22 76.12,126.21 76.12,142.44 D1.C
VDD_PLL_A_A: length 5.2
  TOP w0.203: 100.6,83.02 100.28,83.33 U66.34
  TOP w0.406: 100.6,83.02 100.77,82.84 C308.1
  TOP w0.508: FB31.1 104.15,82.84 C307.1 C308.1
VDD_PLL_P_A: length 5.4
  TOP w0.203: 101.05,86.93 100.74,86.61 99.85,86.61 99.77,86.53 U66.42
  TOP w0.508: 101.05,86.93 101.37,87.25 C309.1 101.64,88.37 C310.1 101.66,89.5 FB32.1
VDDE_A: length 13.1
  TOP w0.203: v1(100.06,87.08) 99.81,87.08 99.66,86.93 U66.43 ; v1(90.45,89.53) 90.58,89.53 91.18,88.93 U66.1
  TOP w0.508: R537.1 v1(87.4,85.09) ; R537.1 R538.1 ; R537.1 R536.1 R535.1 v1(87.4,87.38) ; v1(87.4,88.52) R533.2 R532.2 ; v1(87.4,81.66) R534.2 88.04,80.59 RZU28.2
  BOTTOM w0.508: C300.1 100.57,87.34 100.32,87.08 v1(100.06,87.08) ; C299.1 91.08,90.17 v1(90.45,89.53) 90.96,89.03 C298.1
  vias: v1(100.74,91.44) v1(101.37,91.44)
VIN_PWR_BAD_G: length 4.1
  TOP w0.107: RZU5.2 114.27,157.35 Q5.G 112.79,157.95 112.62,158.12 RZU4.1 RZ4.2
VIN_PWR_BAD_N: length 110
  TOP w0.107: v1(85.09,150.24) 97.79,150.24 106.93,159.38 111.02,159.38 RZU4.2 111.66,158.16 111.49,157.99 Q5.S 111.49,156.48 111.76,156.21 112.92,156.21 113.03,156.1 v1(113.03,154.31) ; Q33.6 58.91,171.11 RZ3.2 58.7,171.6 59.05,171.96 v1(65.53,171.96) ; J1.L55 v1(101.1,133.48)
  IN1 w0.124: v1(101.1,133.48) 101.1,144.56 107.8,151.26 109.68,151.26 112.73,154.31 v1(113.03,154.31)
  IN3 w0.124: v1(65.53,171.96) 65.53,169.59 69.34,165.78 69.34,155.14 70.24,154.24 70.24,152.26 71.5,151 84.33,151 v1(85.09,150.24)
VIN_PWR_ON: length 159.7
  TOP w0.254: U6.10 130.03,160.44 RB6.2
  TOP w0.508: v1(85.09,148.21) 85.85,147.45 113.54,147.45 120.27,154.18 120.27,160.02 121.54,161.29 128.4,161.29 129.13,160.55 v1(129.29,160.55) RB6.2 ; RZ8.1 v1(70.36,150.75)
  IN3 w0.508: v1(116.71,86.74) 115.98,87.48 115.98,92.08 114.78,93.27 114.78,97.54 113.97,98.35 113.97,101.73 115.24,103 116.23,103 120.04,106.81 122.58,106.81 124,108.23 124,131.24 125.78,133.02 125.78,140.87 126.27,141.35 126.27,151.47 126.62,151.82 126.62,152.91 126.11,153.42 126.11,158.75 127.91,160.55 v1(129.29,160.55)
  BOTTOM w0.508: v1(85.09,148.21) 84.4,147.52 72.47,147.52 70.36,149.63 v1(70.36,150.75) ; RZ191.1 116.46,86.49 v1(116.71,86.74)
VIN_PWR_ON_5V: length 2.7
  TOP w0.254: Q38.G v1(115.33,84.2)
  BOTTOM w0.254: v1(115.33,84.2) 115.49,84.37 RZ116.2 RZ191.2
VIN_PWR_ON_SRC: length 2.5
  TOP w0.508: RZ8.2 R674.1 68.35,152.56 68.18,152.73 Q34.G
VIN_SHUTDOWN_N: length 5.9
  TOP w0.107: RZ3.1 59.56,171.22 Q33.5 59.56,169.54 59.44,169.42 57.53,169.42 57.42,169.53 U75.4 57.42,171.16 R668.2
VIN_SHUTDOWN_Q: length 4.8
  TOP w0.254: Q33.2 59.56,166.85 R669.2 59.96,166.75 60.21,167 Q33.3 61.13,168.21 R673.1
06DPE_RSTN: length 4.6
  TOP w0.107: R622.2 65.56,67.41 65.45,67.51 63.34,67.51 63.23,67.41 C370.1 RZ85.2
06DPE_RSTN_R: length 2.6
  TOP w0.107: RZ85.1 60.15,67.01 59.4,66.26 U70.36
06INT_HOTPLUG: length 4.9
  TOP w0.107: TP49.1 51.56,56.08 51.38,56.26 51.38,59 52.16,59.78 U70.8
06PERSTN: length 8.7
  TOP w0.107: RZ81.1 63.14,68.33 ; 63.14,68.33 63.14,68.35 63.45,68.66 65.1,68.66 R621.2 ; 63.14,68.33 62.81,68.66 61.04,68.66 60.82,68.44 C369.1 60.68,68.15 59.19,66.66 U70.37
06REXT: length 5.9
  TOP w0.107: U70.67 48.32,69.46 48.21,69.56 48.21,70.99 47.83,71.37 47.83,74.14 R634.1
06REXT2: length 4.7
  TOP w0.107: U70.25 59.33,61.86 60.02,61.16 R635.1
06SM_CLK: length 4.2
  TOP w0.107: RZU32.1 61.19,71.29 59.26,69.36 59.26,68.85 59.06,68.66 U70.42
06SM_DATA: length 3.8
  TOP w0.107: RZU33.1 60.78,70.31 59.71,69.24 59.71,68.86 59.11,68.26 U70.41
06SPI_CS: length 17.4
  TOP w0.107: SPI2.1 52.02,45.67 51.13,46.56 51.13,49.73 50.09,50.77 50.09,55.05 50.41,55.37 50.41,58.77 51.36,59.72 U70.6
06SPI_SCK: length 8.8
  TOP w0.107: v1(50.9,52.91) RZ108.2 R637.1 50.9,54.95 50.9,58.87 51.76,59.73 U70.7
  BOTTOM w0.107: RZ111.2 51.49,52.32 v1(50.9,52.91)
06SPI_SDIO: length 14.8
  TOP w0.107: v1(50.52,48.72) 50.52,49.48 48.66,51.34 48.66,53.13 49.05,53.52 R629.1 R633.1 49.35,55.01 49.92,55.58 49.92,58.66 50.96,59.7 U70.5
  BOTTOM w0.107: RZ109.1 v1(50.52,48.72) RZ114.1
06SPI_SDIO1: length 1.1
  BOTTOM w0.107: RZ110.2 RZ109.2
06TESTEN: length 5.2
  TOP w0.107: R632.1 52.06,74.65 51.49,74.08 51.49,71.59 52.16,70.92 U70.59
06UART_RX: length 47.8
  TOP w0.107: U70.35 v1(59.51,65.86)
  IN3 w0.124: v1(59.51,65.86) 59.51,66.09 60.72,67.29 60.72,71.8 59.97,72.54 51.92,72.54 49.21,75.26 44.53,75.26 41.61,78.18 v1(41.61,78.82)
  BOTTOM w0.107: v1(41.61,78.82) 40.34,78.82 38.68,77.17 27,77.17 26.29,76.45 J13.4
06UART_TX: length 51.9
  TOP w0.107: R636.1 65.43,65.76 RZ89.2 63.93,65.86 v1(60.15,65.86) 59.73,65.45 59.34,65.45 59.33,65.46 U70.34
  IN3 w0.124: v1(42.37,78.82) 42.37,78.03 44.7,75.69 49.39,75.69 52.1,72.97 60.15,72.97 61.15,71.98 61.15,67.11 60.15,66.12 v1(60.15,65.86)
  BOTTOM w0.107: J13.3 28.83,76.04 29.54,76.75 38.85,76.75 40.41,78.31 41.86,78.31 v1(42.37,78.82)
06UPE_CLKREQN: length 5.2
  TOP w0.107: U70.65 49.76,70.73 49.55,70.94 49.38,70.94 48.99,71.33 48.99,72.81 48.72,73.08 R641.2 R638.2
06WP#: length 3.4
  TOP w0.107: SPI2.3 v1(54.69,48.21)
  BOTTOM w0.107: v1(54.69,48.21) 54.51,48.39 RZU36.1 R648.2
06XI: length 7.8
  TOP w0.107: X11.3 43.09,71.79 43.21,71.91 44.7,71.91 45.8,70.82 C371.2 45.83,70.14 46.81,69.16 47.32,69.16 47.83,68.66 U70.69
06XO: length 5.1
  TOP w0.107: U70.70 47.9,68.26 47.37,68.78 46.22,68.78 C371.1 45.14,69.86 X11.1
12DPE_CLKN0: length 81.1
  TOP w0.114: v1(78.05,105.24) 77.83,105.47 76.87,105.47 RZ37.2 ; v1(51.64,82.6) 51.41,82.37 51.1,82.37 49.01,80.28 44.74,80.28 40.89,76.43 40.89,69.09 42.35,67.63 43.01,67.63 RZ83.1
  IN1 w0.122: v1(78.05,105.24) 77.83,105.47 77.55,105.47 77.17,105.86 77.17,107.77 76.78,108.15 68.66,108.15 67.51,109.3 64.59,109.3 62.69,107.39 52.91,107.39 52.27,106.76 52.27,103.71 51.89,103.33 51.89,90.09 51,89.2 51,82.5 51.13,82.37 51.41,82.37 v1(51.64,82.6)
12DPE_CLKP0: length 81.1
  TOP w0.114: RZ33.2 76.87,105.73 77.83,105.73 v1(78.05,105.96) ; RZ80.1 43.01,67.88 42.46,67.88 41.15,69.19 41.15,76.33 44.84,80.02 49.11,80.02 51.21,82.12 51.41,82.12 v1(51.64,81.89)
  IN1 w0.122: v1(51.64,81.89) 51.41,82.12 51.03,82.12 50.75,82.39 50.75,89.31 51.64,90.2 51.64,103.43 52.02,103.81 52.02,106.86 52.8,107.65 62.58,107.65 64.49,109.55 67.62,109.55 68.76,108.41 76.89,108.41 77.42,107.88 77.42,105.96 77.65,105.73 77.83,105.73 v1(78.05,105.96)
12DPE_CLKREQN0: length 3.8
  TOP w0.107: R566.1 69.42,106.76 70.31,105.87 70.31,105.87 v3(71.16,105.02)
  BOTTOM w0.107: U67.AC3 v3(71.16,105.02)
12DPE_CLKREQN1: length 3.5
  TOP w0.107: R567.1 71.2,105.64 71.82,105.02 v3(71.96,105.02)
  BOTTOM w0.107: U67.AD3 v3(71.96,105.02)
12DPE_CLKREQN2: length 2.3
  TOP w0.107: R568.1 68.47,103.42 v3(69.56,103.42)
  BOTTOM w0.114: U67.AB5 v3(69.56,103.42)
12DPE_CLKREQN3: length 3.4
  TOP w0.107: v3(70.36,103.42) 70.36,103.68 70.21,103.83 68.25,103.83 R569.1
  BOTTOM w0.114: U67.AC5 v3(70.36,103.42)
12DPE_CLKREQN4: length 3.1
  TOP w0.107: v3(54.36,100.22) 53.54,100.22 53.35,100.03 R570.1
  BOTTOM w0.107: U67.C9 v3(54.36,100.22)
12DPE_CLKREQN5: length 4.4
  TOP w0.107: v3(55.16,100.22) 54.76,99.82 53.98,99.82 53.04,98.88 R571.1
  BOTTOM w0.107: U67.D9 v3(55.16,100.22)
12DPE_RSTN: length 5.4
  TOP w0.107: R563.1 50.04,103.53 49.82,103.75 C318.1 v1(48.92,104.52)
  BOTTOM w0.107: RZ182.1 v1(48.92,104.52)
12DPE_RXN0: length 19.6
  TOP w0.114: v1(56.79,79.63) 57.02,79.4 57.02,76.03 CM56.2
  IN3 w0.122: v1(56.79,79.63) 57.02,79.4 57.02,78.52 57.29,78.25 58.16,78.25 60.27,80.36 60.27,83.92 62.69,86.33 62.69,86.74 63.65,87.7 63.65,87.9 v3(63.96,88.22)
  BOTTOM w0.114: v3(63.96,88.22) 63.56,88.62 U67.P23
12DPE_RXN1: length 22.2
  TOP w0.114: CM50.2 53.37,78.14 53.37,78.31 v1(53.19,78.49)
  IN3 w0.122: v1(53.19,78.49) 53.42,78.26 53.42,77.92 54.89,76.45 59.41,76.45 63.78,80.82 63.78,84.02 65.43,85.67 65.43,87.28 v3(65.56,87.42)
  BOTTOM w0.114: v3(65.56,87.42) 65.16,87.82 U67.T24
12DPE_RXP0: length 18.7
  TOP w0.114: CM57.2 57.28,76.03 57.28,79.4 v1(57.51,79.63)
  IN3 w0.122: v3(63.16,88.21) 63.4,87.98 63.4,87.81 62.43,86.84 62.43,86.44 60.02,84.02 60.02,80.47 58.06,78.51 57.4,78.51 57.28,78.63 57.28,79.4 v1(57.51,79.63)
  BOTTOM w0.114: U67.N23 62.76,88.61 v3(63.16,88.21)
12DPE_RXP1: length 21.5
  TOP w0.114: v1(53.9,78.49) 53.72,78.31 53.72,78.14 CM51.2
  IN3 w0.122: v3(64.76,87.42) 65.18,87 65.18,85.78 63.53,84.12 63.53,80.92 59.31,76.71 54.99,76.71 53.67,78.03 53.67,78.26 v1(53.9,78.49)
  BOTTOM w0.114: U67.R24 64.36,87.82 v3(64.76,87.42)
12DPE_TXN0: length 17.1
  TOP w0.114: v1(55.6,78.5) 55.79,78.31 55.79,78.15 CM52.2
  IN3 w0.122: v1(55.6,78.5) 55.83,78.27 55.83,77.65 56.13,77.34 59.13,77.34 62.97,81.18 62.97,84.43 63.83,85.29 63.83,86.48 v3(63.96,86.62)
  BOTTOM w0.114: v3(63.96,86.62) 63.56,87.02 U67.P25
12DPE_TXN1: length 21.8
  TOP w0.114: CM54.2 54.61,76.03 54.61,79.4 v1(54.38,79.63)
  BOTTOM w0.114: U67.T26 65,86.22 64.89,86.1 64.89,85.32 62.99,83.42 62.99,81.17 59.54,77.72 55.01,77.72 54.61,78.13 54.61,79.4 v1(54.38,79.63)
12DPE_TXP0: length 16.4
  TOP w0.114: CM53.2 56.12,78.15 56.12,78.31 v1(56.31,78.5)
  IN3 w0.122: v1(56.31,78.5) 56.08,78.27 56.08,77.75 56.24,77.6 59.03,77.6 62.71,81.28 62.71,84.54 63.58,85.4 63.58,86.2 v3(63.16,86.62)
  BOTTOM w0.114: U67.N25 62.76,87.02 v3(63.16,86.62)
12DPE_TXP1: length 21
  TOP w0.114: CM55.2 54.86,76.03 54.86,79.4 v1(55.09,79.63)
  BOTTOM w0.114: U67.R26 64.52,86.22 64.63,86.1 64.63,85.42 62.74,83.53 62.74,81.28 59.44,77.98 55.12,77.98 54.86,78.23 54.86,79.4 v1(55.09,79.63)
422RX+: length 13.1
  TOP w0.254: v1(62.97,191.01) 63.73,190.25 64.77,190.25 65.68,189.33 R254.2 65.65,188.56 U36.6
  BOTTOM w0.254: NMEA0183.5 62.55,194.5 62.97,194.08 R251.1 v1(62.97,191.01)
422RX-: length 15.1
  TOP w0.254: v1(61.49,191.01) 63.02,189.48 64.11,189.48 64.36,189.23 R253.1 64.38,188.58 U36.7
  BOTTOM w0.254: v1(61.49,191.01) R251.2 61.49,192.62 NMEA0183.2
422TX+_485+: length 11.3
  TOP w0.254: NMEA0183.6 64.55,191.9 R249.1 v1(64.54,190.98)
  BOTTOM w0.254: U38.6 64.39,188.57 R259.2 64.36,190.8 v1(64.54,190.98)
422TX-_485-: length 12.5
  TOP w0.254: v1(66.04,191.01) 66.01,191.03 R249.2 66.01,194.16 68.55,196.69 NMEA0183.8
  BOTTOM w0.254: U38.7 65.66,188.57 R257.1 65.68,190.65 v1(66.04,191.01)
1812_RST_N: length 2.4
  BOTTOM w0.107: RZ180.1 53.02,105.56 U67.A2
1812DEBUG27: length 4.9
  TOP w0.107: R575.1 74.85,85.72 RZ59.1 72.51,86.87 v3(71.96,87.42)
  BOTTOM w0.107: U67.AD24 v3(71.96,87.42)
1812DEBUG27_P: length 1.2
  TOP w0.107: R585.1 75.97,86.72 RZ59.2
1812DEBUG28: length 2.1
  BOTTOM w0.107: TP48.1 75.24,87.82 U67.AF24
1812GPIO5: length 5
  TOP w0.107: v3(71.96,86.62) 72.4,86.18 72.4,85.46 72.29,85.34 R578.1 72.57,83.92 72.75,84.1 73.15,84.1 73.33,83.92 RZ60.1
  BOTTOM w0.107: U67.AD25 v3(71.96,86.62)
1812GPIO5_P: length 1.4
  TOP w0.107: RZ60.2 73.69,81.81 R583.1
1812INT_HOTPLUG: length 1.2
  TOP w0.107: v3(69.56,86.62) 69.6,86.58 TP47.1
  BOTTOM w0.107: U67.AA25 v3(69.56,86.62)
1812SMCL: length 2.6
  BOTTOM w0.107: U67.A1 52.05,106.22 51.46,106.81 RZU44.1
1812SMDA: length 3.9
  BOTTOM w0.107: U67.B1 53.42,106.76 52.27,106.76 51.08,107.95 RZU43.1
1812SPI_CS: length 12.7
  TOP w0.107: SPI1.1 v1(70.26,75.95)
  IN1 w0.124: v1(70.26,75.95) 70.64,75.95 71.4,76.71 71.4,85.25 v3(71.96,85.82)
  BOTTOM w0.107: U67.AD26 v3(71.96,85.82)
1812SPI_SCK: length 9.9
  BOTTOM w0.107: U67.AB26 69.96,84.77 69.65,84.46 RZ196.2 69.65,82.7 R606.1 68.94,82.25 68.94,80.98 68.61,80.64 66.07,80.64 65.66,80.24 65.66,79.93
1812SPI_SCK_P: length 1.4
  BOTTOM w0.107: RZ196.1 70.61,82.8 R610.1
1812SPI_SDIO: length 18.1
  TOP w0.107: RZ68.1 v1(75.34,76.07)
  IN1 w0.124: v1(72.92,83.64) 73.36,83.64 73.81,83.19 73.81,77.6 v1(75.34,76.07)
  BOTTOM w0.107: R574.1 72.01,83.92 71.65,83.57 71.65,80.31 RZ197.1 ; R574.1 72.29,85.02 72.36,85.09 U67.AE26 ; R574.1 72.64,83.92 v1(72.92,83.64) 73.2,83.92 RZ195.1
1812SPI_SDIO1: length 1.2
  BOTTOM w0.107: RZ197.2 RZ198.2
1812SPI_SDIO_P: length 1.4
  BOTTOM w0.107: RZ195.2 73.69,81.81 R587.1
1812TESTEN: length 4.7
  TOP w0.107: R579.1 68.28,107.26 69.55,105.99 69.55,105.03 v3(70.36,104.22)
  BOTTOM w0.107: U67.AB4 v3(70.36,104.22)
1812WP#: length 3.1
  TOP w0.107: SPI1.3 R618.2 RZU29.1
1812XI: length 6
  BOTTOM w0.107: U67.AC1 70.76,108.35 C319.2 69.64,109.47 69.64,111.04 69.76,111.17 X10.3
1812XO: length 5
  BOTTOM w0.107: X10.1 71.69,109.16 71.46,108.93 C319.1 71.18,108.3 71.18,105.85 70.76,105.43 U67.AC2
6408_INT#: length 2.7
  TOP w0.107: RZU31.2 RB54.1 124.85,71.98 U14.11
9633_HPD: length 7.1
  TOP w0.107: U66.40 v1(100.23,85.73)
  BOTTOM w0.107: v1(100.23,85.73) 100.23,85.48 100.49,85.22 101.75,85.22 102.01,85.47 R504.1 103.12,86.39 RZU45.2 103.15,86.85 Q55.G
51770_AGND: length 9.8
  TOP w0.279: v1(17.09,111.2) 17.44,110.86 U83.17
  TOP w0.508: C460.1 v1(20.09,111.89) ; RZ687.1 v1(17.55,106.58)
  BOTTOM w0.508: 14.05,110.31 14.05,108.43 R752.1 14.83,106.86 15.11,106.58 v1(17.55,106.58)
  vias: v1(9.47,113.74) v1(9.47,112.47) v1(9.47,111.2) v1(10.74,113.74) v1(10.74,112.47) v1(10.74,111.2) v1(12.01,113.74) v1(12.01,112.47) v1(12.01,111.2) v1(13.28,113.74) v1(13.28,112.47) v1(13.28,111.2) v1(14.55,113.74) v1(14.55,112.47) v1(14.55,111.2) v1(15.82,113.74) v1(15.82,112.47) v1(15.82,111.2) v1(17.09,113.74) v1(17.09,112.47) v1(18.36,113.74) v1(18.36,112.47) v1(18.36,111.2)
51770_ATRK: length 2.2
  TOP w0.279: v1(17.3,108.46) 16.94,108.82 U83.16
  BOTTOM w0.381: v1(17.3,108.46) 17.3,108.98 C477.2
51770_BIAS: length 4.6
  TOP w0.279: U83.1 9.44,108.88 9.22,108.66 8.71,108.66
  TOP w0.508: RZ27.2 RZU19.2 7.91,109.79 CA64.1 8.71,108.66
51770_COMP: length 2.8
  TOP w0.279: v1(18.03,108.46) 17.94,108.56 U83.18
  BOTTOM w0.381: R747.2 18.03,107.8 v1(18.03,108.46) C475.2
51770_IMONOUT: length 2.1
  TOP w0.279: U83.6 v1(11.94,108.41)
  BOTTOM w0.381: v1(11.94,108.41) 11.94,109.24 R748.1
51770_MODE: length 3.7
  TOP w0.279: U83.12 14.94,108.84 14.86,108.76 14.86,108.28 15.6,107.54 RB30.1
  TOP w0.508: RZ687.2 RB30.1
51770_VCC: length 24
  TOP w0.279: CA60.1 12.56,117.26 12.94,116.88 U83.31
  TOP w0.508: v1(11.51,106.58) RB29.2 RZ31.1 R741.1 RB30.2
  IN3 w0.508: v1(11.51,106.58) 10.9,107.19 9.17,107.19 8.08,108.28 8.08,116.03 9.47,117.42 11.65,117.42 v1(12.28,118.06) v1(12.9,118.06)
-SPKOUT: length 6.5
  BOTTOM w0.508: BUZZ1.2 8.07,197.19 CA117.1 10.53,197.19 11.18,197.84 Q15.C
ACC_ON: length 266.9
  IN3 w0.254: v1(8.59,82.5) 8.76,82.68 21.26,82.68 23.62,80.31 35.08,80.31 39.22,76.17 39.22,70.37 46,63.59 46,59.88 47.08,58.8 49.11,58.8 50.74,57.18 61.06,57.18 62.33,55.9 67.23,55.9 72.13,51 77.42,51 79.07,52.65 81.43,52.65 81.89,52.2 89.95,52.2 92.07,54.32 105.94,54.32 106.7,55.09 108.55,55.09 112.32,58.85 v1(112.32,58.93)
  BOTTOM w0.254: v1(8.59,82.5) 8.43,82.5 4.34,86.58 4.34,95.83 1.48,98.7 1.48,165.31 5.13,168.96 5.13,173.56 3.81,174.88 D58.C ; R86.1 140.79,63.7 137.08,67.41 132.13,67.41 130.99,68.55 115.6,68.55 113.94,66.9 113.94,60.3 112.57,58.93 v1(112.32,58.93)
ACC_ON#: length 4.4
  TOP w0.203: Q10.D 144.68,66.42 144.55,66.3 U13.1
  TOP w0.254: Q10.D v1(146.84,66.42)
  BOTTOM w0.254: R85.1 v1(146.84,66.42)
ACC_ON_R: length 6.7
  TOP w0.203: v1(149.48,64.9) R87.1 149.39,65.77 Q10.G
  BOTTOM w0.254: v1(149.48,64.9) 146.66,64.9 R86.2
ACOK_CON: length 137.5
  TOP w0.107: U91.1 94.32,108.73 94.56,108.48 RZU20.1 R1482.1 96.93,107.85 v1(96.93,104.52)
  IN1 w0.124: v1(143.66,64.9) 142.32,63.55 142.32,59.82 139.09,56.59 139.09,53.58 138.57,53.06 138.57,47.32 139.41,46.48 139.41,41.97 141.31,40.07 148.78,40.07 155.34,33.51 155.34,29.03 156.56,27.81 157.61,27.81
  BOTTOM w0.107: v1(143.66,64.9) 140.23,64.9 137.19,67.94 132.49,67.94 131.85,68.58 131.85,70.99 131.09,71.75 120.29,71.75 119.79,72.26 119.79,75.56 118.9,76.45 113.87,76.45 107.75,82.58 107.75,88.87 106.83,89.79 106.83,99.57 104.29,102.11 102.51,102.11 101.27,103.35 98.93,103.35 97.76,104.52 v1(96.93,104.52) ; Z16.2 158.09,26.31 157.61,26.8 157.61,27.81
ACOK_CON_OR: length 2.5
  TOP w0.254: R1479.1 90.26,108.85 C894.1 90.31,110.03 U91.4
ACOK_CON_OR_CR: length 6.4
  TOP w0.254: C894.2 88.93,109.98 D65.C 86.89,111.38 R1478.1 85.13,110.21 84.73,109.82 U90.3
ACOK_OR_RISING: length 92
  TOP w0.107: RZ6.2 v1(126.9,153.57) ; U12.4 v1(84.99,105.01)
  IN3 w0.124: v1(126.9,153.57) 127.21,153.26 127.21,151.78 126.81,151.38 126.81,131.7 124.44,129.34 124.44,107.14 122.33,105.03 120.01,105.03 v1(119,104.01)
  BOTTOM w0.107: v1(84.99,105.01) 85.74,104.27 93.37,104.27 94.46,105.36 100.41,105.36 102.82,102.95 111.91,102.95 112.6,103.63 118.62,103.63 v1(119,104.01)
ACOK_WOL_FB: length 24.3
  TOP w0.254: RZU20.2 94.93,109.38 v1(94.41,109.38) U91.2 93.15,109.38 92.86,109.09 92.86,106.55 93.12,106.3 U9.2 94.39,106.3 94.61,106.53 RZU24.2 ; RZ30.2 RZ28.2 v1(80.19,110.36)
  BOTTOM w0.254: v1(94.41,109.38) 94.41,110.04 94.01,110.45 80.27,110.45 v1(80.19,110.36)
ACOK_WOL_OR: length 2.6
  TOP w0.254: R43.1 90.28,105.8 C10.1 90.3,106.95 U9.4
ACOK_WOL_OR_CR: length 5.9
  TOP w0.254: U90.1 84.73,108.52 85.2,108.05 R42.1 86.66,108.05 D2.C 88.16,107.19 88.42,106.93 C10.2
ACOK_WOL_RISING: length 8.3
  TOP w0.107: RZ30.1 81.15,106.58 81.42,106.31 U12.1 82.69,106.31 82.83,106.17 82.83,105.79 82.7,105.66 U12.2 ; RZ30.1 81.21,108.52 U90.6 ; RZ30.1 RZ28.1 81.24,109.82 U90.4
ALERT: length 6.3
  TOP w0.254: TP60.1 56.77,194.56 58.55,196.34 NMEA0183.3
ASM1806_GPIO5: length 5.8
  TOP w0.107: U70.2 49.76,59.66 49.48,59.39 49.33,59.39 R631.1 47.83,58.22 47.7,58.09 47.7,56.31 R630.1
ASM_VCC33: length 32
  TOP w0.203: U70.4 50.56,59.73 49.4,58.57 CA80.1
  TOP w0.229: U70.63 50.56,70.88 49.9,71.54 v1(49.86,71.54) ; U70.39 59.07,67.46 60.2,68.58 v1(60.2,68.78)
  TOP w0.305: v3(68.76,89.02) 68.73,89.05 CB18.1 ; v3(67.96,89.02) 67.94,89.03 CB17.1 ; v3(56.76,91.42) 56.79,91.39 CB16.1
  TOP w0.381: v1(49.86,71.54) CA72.1 ; R637.2 v1(51.87,54.31) ; v1(48.79,58.2) CA80.1 ; v1(64.21,76.02) 64.1,75.91 CB29.1 64.74,75.39 65.3,75.95 SPI1.8 ; CA73.1 60.63,69.22 v1(60.2,68.78)
  TOP w0.508: R629.2 v1(49.35,51.89) ; R608.1 64.16,76.07 v1(64.21,76.02) ; SPI2.8 CA88.1 v1(46.14,46.3) ; R630.2 v1(48.21,54.18) ; R645.1 v1(45.19,47.6) ; R607.1 R618.1 v1(75.34,78.49) ; R638.1 v1(48.46,76.28) ; R575.2 v1(74.83,84.07) ; R578.2 v1(72.92,82.96)
  BOTTOM w0.305: v1(49.63,95.45) R589.2 ; U67.AA8 v3(69.56,101.02) ; U67.AA9 v3(69.56,100.22)
  BOTTOM w0.381: U67.W22 v3(67.96,89.02) ; v3(54.36,91.42) 54.76,91.82 U67.C19 ; U67.E19 56.36,91.82 v3(55.96,91.42) ; v3(56.76,91.42) 57.16,91.82 U67.F19 ; U67.A19 53.16,91.82 v3(52.76,91.42) ; U67.B19 53.96,91.82 v3(53.56,91.42) ; U67.D19 55.56,91.82 v3(55.16,91.42) ; U67.Y22 v3(68.76,89.02)
  BOTTOM w0.508: R606.2 v1(69.6,81.28) ; Q29.S v1(40.56,83.74) ; R578.2 v1(72.92,82.96)
  vias: v1(43.84,83.82) v1(43.84,83.19) v1(44.6,83.82) v1(44.6,83.19) v1(49.73,46.94)
AUD_MCLK01_CDC: length 7.4
  BOTTOM w0.107: RZ155.2 135.13,150.11 135.34,149.9 C916.1 136.53,149.61 138.18,147.96 139.04,147.96 139.15,147.85 U16.37
AUDIO_CODEC_INT: length 2.8
  TOP w0.107: v1(140.46,148.84) 140.31,149 R112.2
  BOTTOM w0.107: RZ156.2 140.08,149.22 v1(140.46,148.84) 140.35,148.73 U16.40
AUDIO_CPN1: length 2.8
  BOTTOM w0.203: U16.21 140.35,140.86 140.02,140.53 139.51,140.53 139.23,140.25 C43.2
AUDIO_CPN2: length 2.4
  BOTTOM w0.203: C45.2 142.46,139.99 141.55,140.9 U16.18
AUDIO_CPN_VEE: length 1.6
  BOTTOM w0.203: U16.27 136.84,143.38 C47.1
AUDIO_CPP1: length 2.3
  BOTTOM w0.203: C43.1 140.75,140.41 U16.20
AUDIO_CPP2: length 2.2
  BOTTOM w0.203: C45.1 141.52,140.04 141.15,140.41 U16.19
AUDIO_CPP_VPP: length 2.6
  BOTTOM w0.203: U16.24 139.15,141.65 138.51,141.01
  BOTTOM w0.508: 138.51,141.01 137.88,140.38 C46.1
AUDIO_LDO_EN: length 3
  BOTTOM w0.203: U16.44 141.95,148.17 142.24,148.46 142.24,148.77 142.44,148.97 143.31,148.97 143.51,149.17 R114.2
AUDIO_MIC1P: length 12.2
  IN3 w0.508: v1(144.02,141.1) 144.02,141.48 144.53,141.99 144.53,145.54 145.92,146.94 148.08,146.94 148.84,147.7 v1(148.84,148.34)
  BOTTOM w0.203: U16.13 143.55,141.56 v1(144.02,141.1)
  BOTTOM w0.381: C44.2 v1(148.84,148.34)
AUDIO_MIC_1P: length 8.2
  BOTTOM w0.381: AUDIO1.5 156.32,150.11 154.31,150.11 153.67,149.48 R1493.1 153.01,149.2 152.65,148.84 150.96,148.84 C44.1
AUDIO_MICBIAS: length 8.1
  TOP w0.381: v1(150.5,146.16) 151.76,146.16 152.27,146.67 152.27,148.97 151.76,149.48 v1(151.38,149.48)
  BOTTOM w0.381: RZ164.1 149.97,146.18 149.99,146.16 v1(150.5,146.16) ; R1493.2 v1(151.38,149.48) CA14.1
AUDIO_MICBIAS_C: length 4.3
  BOTTOM w0.203: U16.4 144.97,145.78 145.37,146.18 145.95,146.18
  BOTTOM w0.381: RZ164.2 145.95,146.18
AUDIO_VREF1: length 2.7
  BOTTOM w0.203: 145.67,142.49 145.29,142.88 144.83,142.88 144.73,142.98 U16.11
  BOTTOM w0.381: CA15.1 146.22,141.95 145.67,142.49
AUDIO_VREF2: length 3.1
  BOTTOM w0.203: U16.12 144.44,142.58 144.65,142.37 144.65,142.18 144.78,142.05
  BOTTOM w0.381: 144.78,142.05 146.12,140.72 CA16.1
AUDIO_VREF_DAC: length 5.8
  BOTTOM w0.203: CA132.1 145.88,143.04 145.67,143.26 144.97,143.26 144.85,143.38 U16.10
  BOTTOM w0.381: C54.1 147.41,143.26 147.19,143.04 CA132.1
  BOTTOM w0.508: RZ166.2 148.84,142.11 148.11,142.85 C54.1
AUTOPWON: length 34.1
  TOP w0.107: RZ115.1 139.34,44.96 139.85,45.47 139.85,61.21 139.09,61.98 134.52,61.98 v1(133.5,62.99) ; v1(130.45,70.36) 130.52,70.3 U13.40
  IN1 w0.124: v1(133.5,62.99) 131.98,64.52 131.98,69.85 131.47,70.36 v1(130.45,70.36)
BAT_CONN: length 2.1
  BOTTOM w0.508: BAT1.2 70.78,143.88 R23.1
BAT_CONN_LIM: length 1.7
  BOTTOM w0.508: R23.2 D1.A2
BRD_SEL: length 2.9
  TOP w0.107: U6.11 128.17,158.83 RB9.2 R36.1
BT_WAKE_AP_M2E_CON: length 4.6
  BOTTOM w0.107: WIFI1.20 136.99,132 135.62,133.36 Q52.6 135.13,133.67 135.06,133.6 R190.1
BTN_OOB: length 2.1
  BOTTOM w0.107: RZ190.2 152.79,90.2 OOB1.9
BUTTON_POWER_ON_N: length 20.3
  TOP w0.107: U6.2 132.58,156.82 132.69,156.72 TP12.1 133.73,156.59 RB13.2 133.32,155.55 133.1,155.32 133.1,153.54 131.44,151.89 119.89,151.89 v1(119.63,152.15)
  BOTTOM w0.107: RZ152.2 v1(119.63,152.15)
BUTTON_POWER_ON_N_CON: length 183.6
  IN1 w0.124: v1(151.76,21.79) 154.99,25.02 154.99,33.5 148.67,39.82 141.12,39.82 138.98,41.97 138.98,43.7 138.01,44.66 138.01,47.48 138.31,47.78 138.31,53.16 138.72,53.57 138.72,56.58 142.02,59.88 142.02,64.02 145.06,67.06 148.62,67.06 149.76,68.2 149.76,77.6 153.19,81.03 153.19,87.76 v1(150.9,90.04)
  IN3 w0.124: v1(128.4,152.53) 128.4,151.4 127.98,150.98 127.98,141.51 128.24,141.25 128.24,139.9 127.92,139.58 127.92,128.6 130.36,126.16 130.36,123.03 133.38,120.02 133.38,114.17 137.31,110.24 143.54,110.24 144.42,109.35 144.42,107.31 145.54,106.2 147.53,106.2 147.69,106.05 147.69,104.89 150.3,102.28 150.3,96.74 151.41,95.63 151.41,90.55 v1(150.9,90.04)
  BOTTOM w0.107: v1(128.4,152.53) 127.76,151.89 122.56,151.89 121.51,152.93 RZ151.1 ; RZ190.1 v1(150.9,90.04) ; PWRBTN1.3 156.62,20.99 CA153.1 151.78,20.99 RB66.2 v1(151.76,21.79)
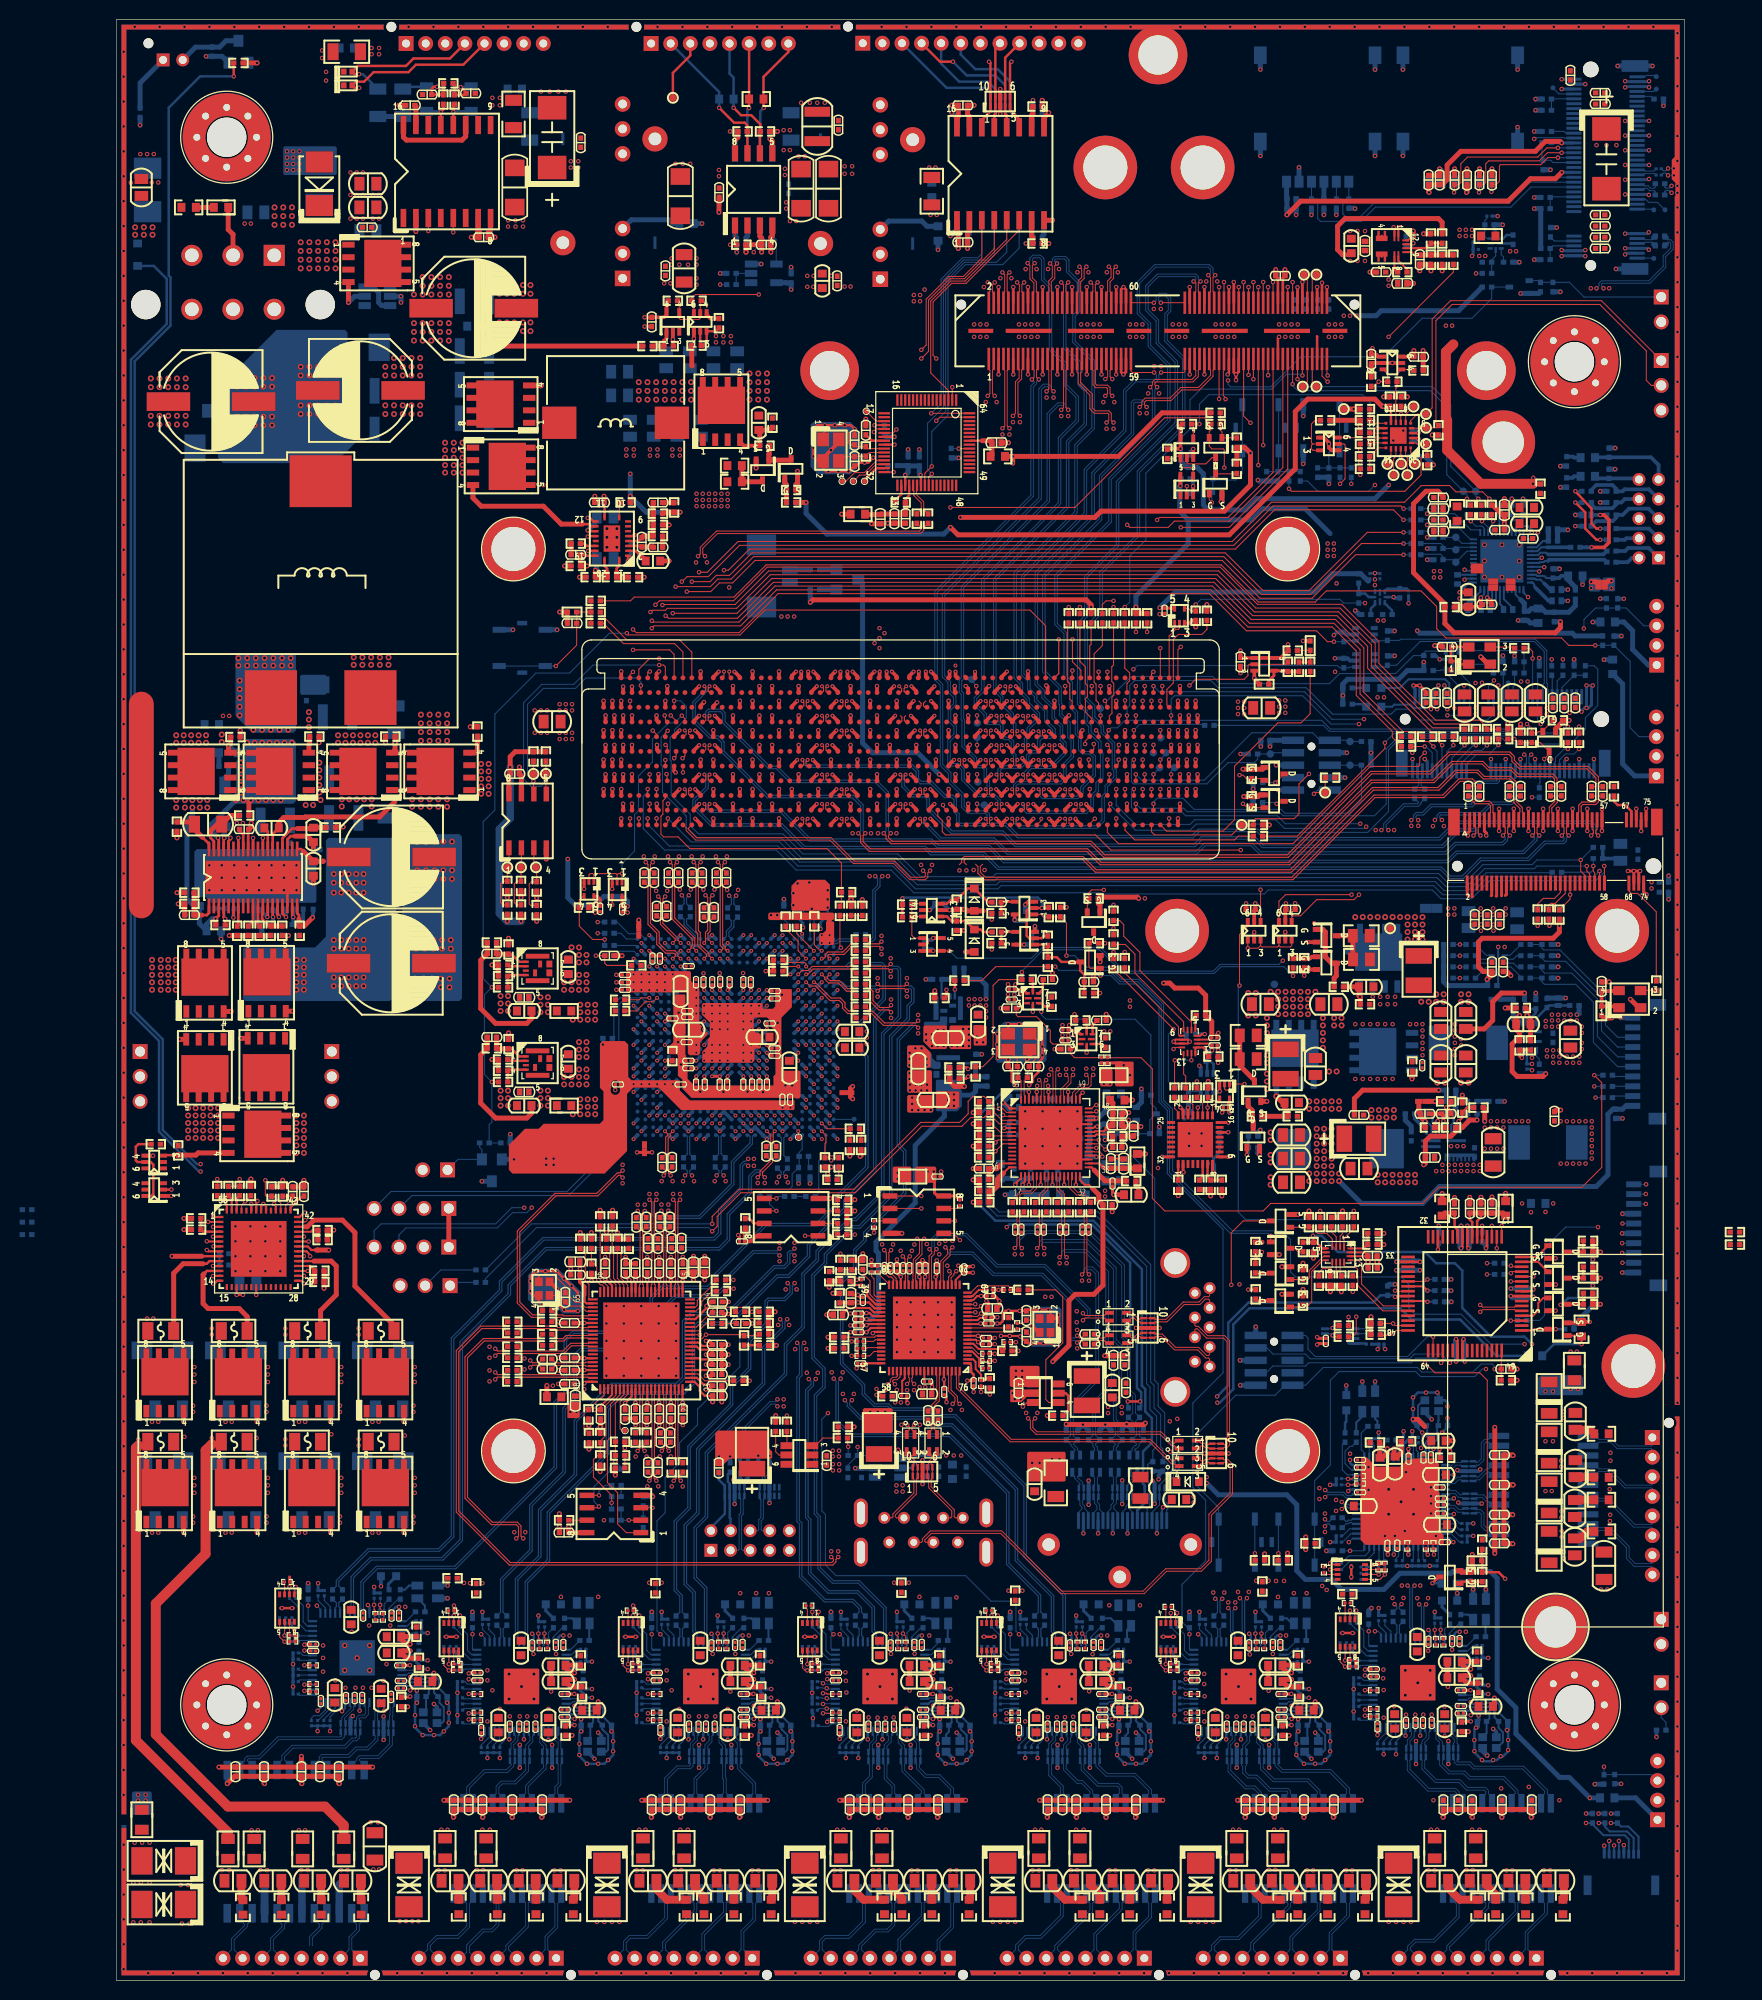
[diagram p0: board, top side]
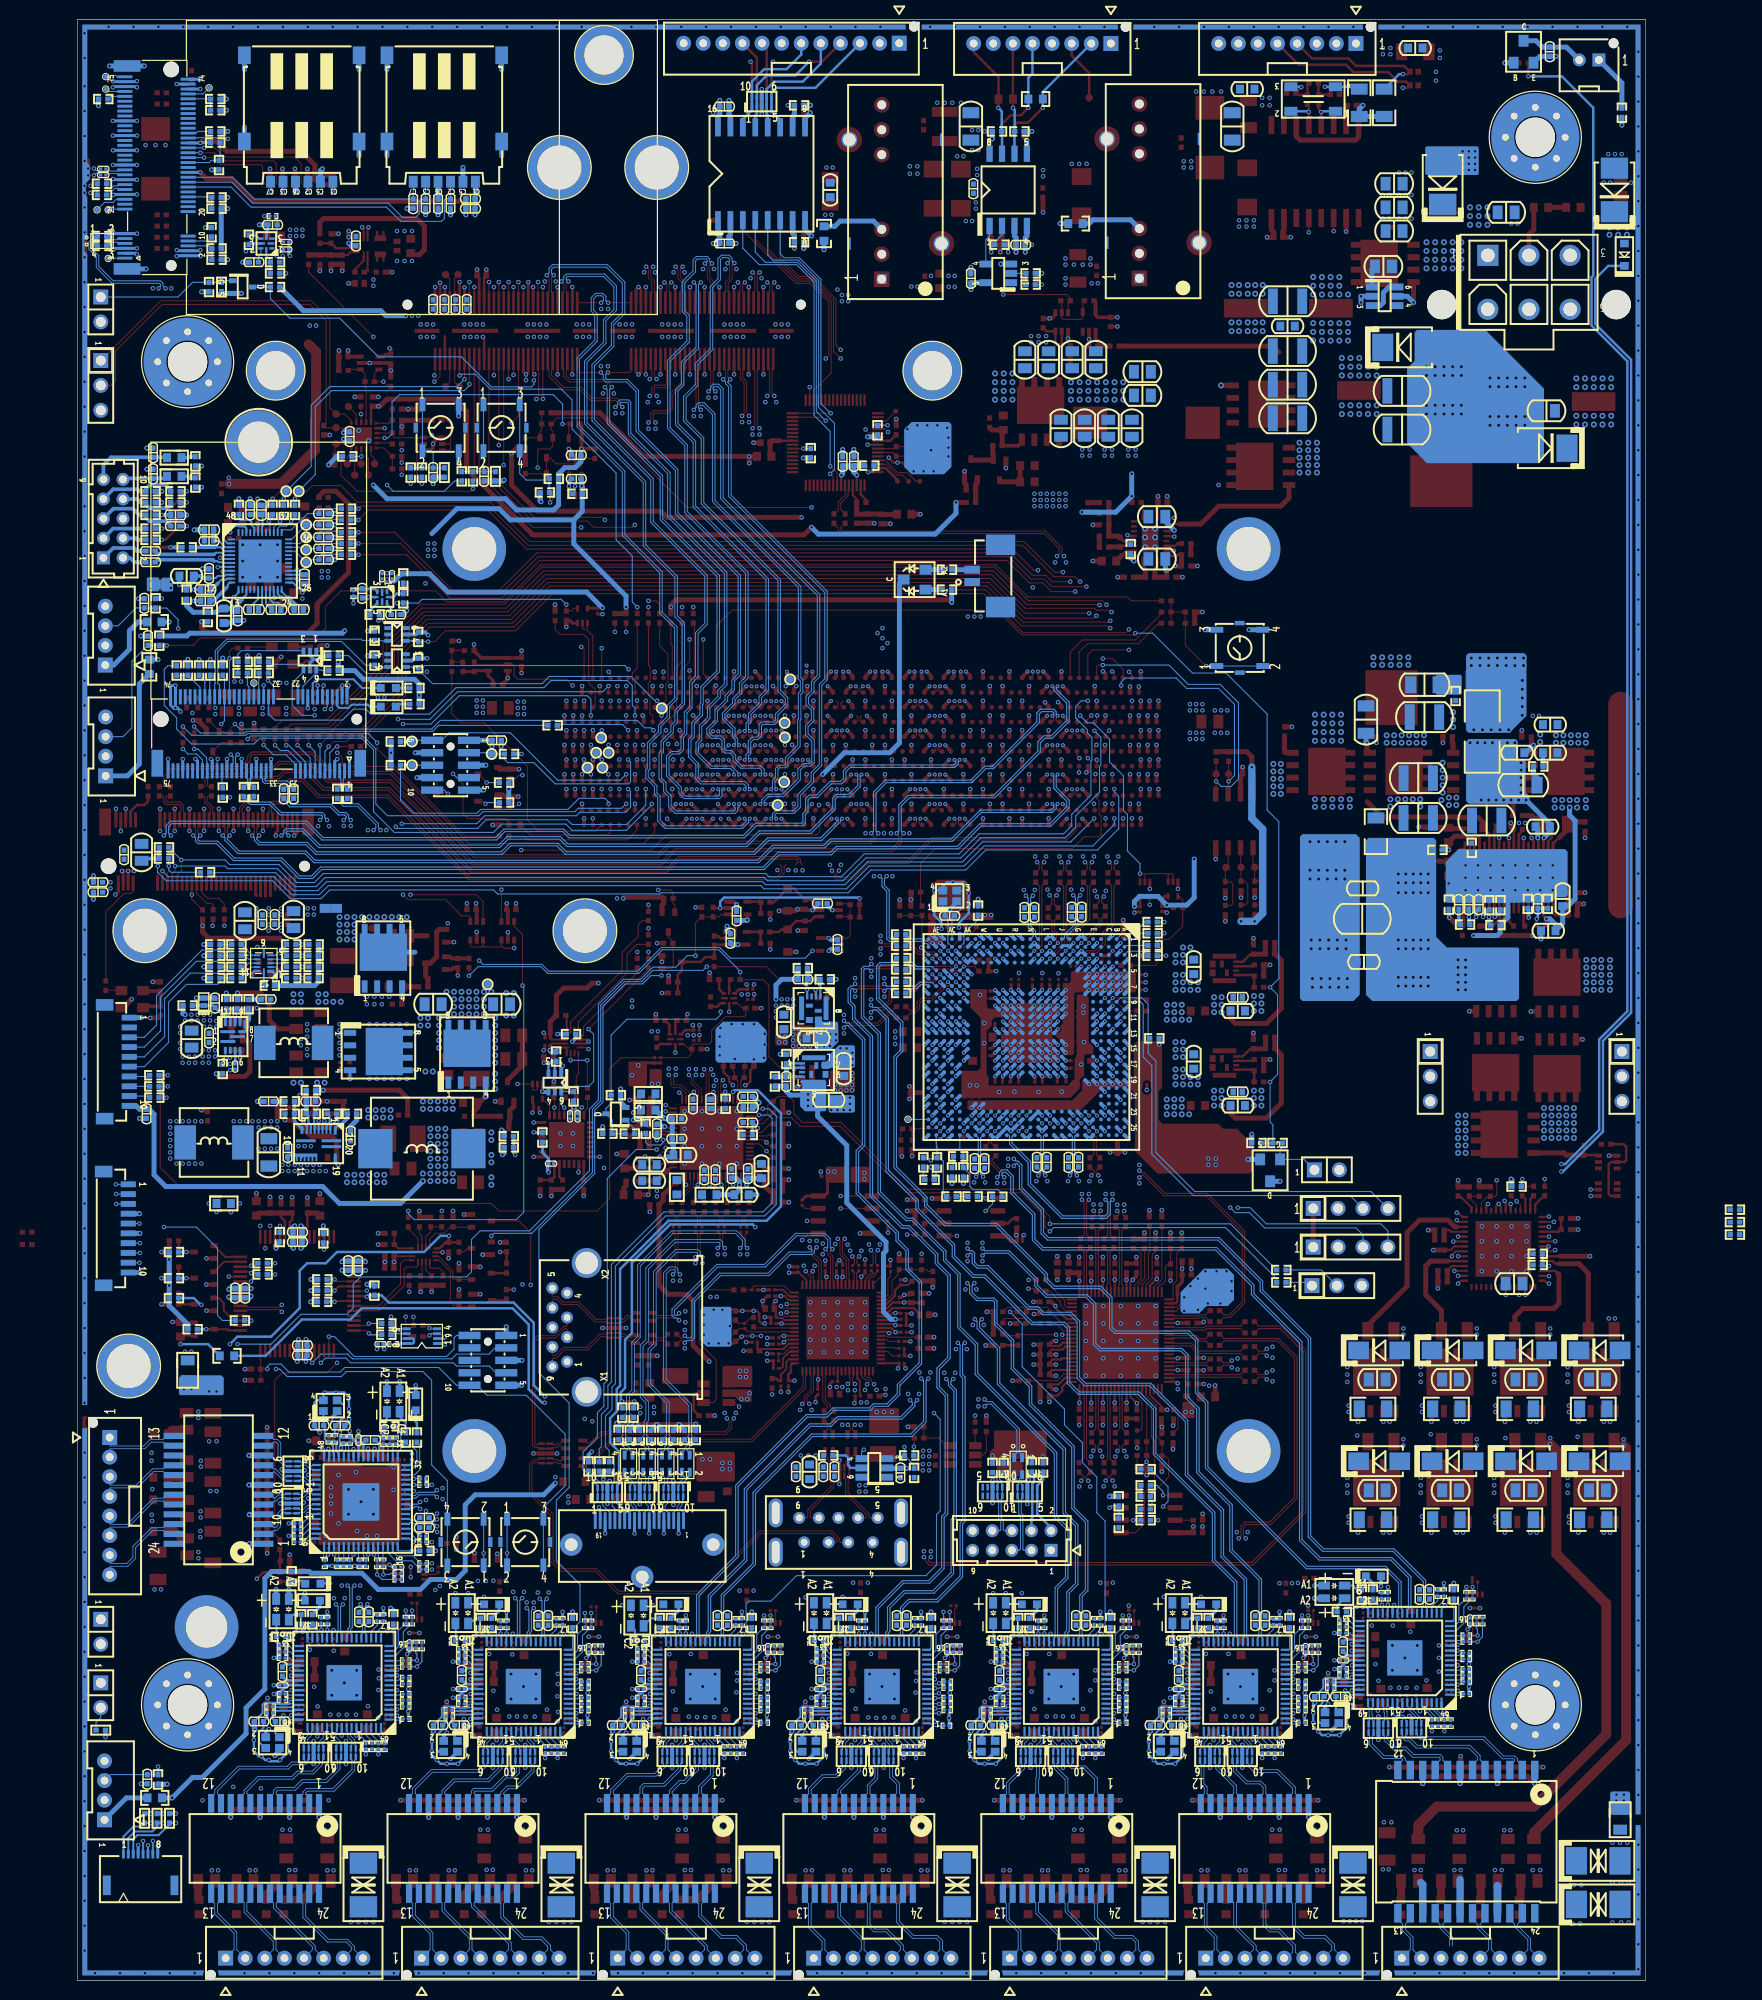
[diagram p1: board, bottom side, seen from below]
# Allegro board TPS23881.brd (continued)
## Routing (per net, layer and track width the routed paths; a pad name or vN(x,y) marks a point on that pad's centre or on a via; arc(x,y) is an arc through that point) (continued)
BUTTON_POWER_ON_N_KEY: length 10.3
  BOTTOM w0.107: PSON1.1 PSON1.2 118.56,153.96 118.5,153.9 ; 118.5,153.9 C132.1 ; 118.5,153.9 Z7.2 ; 118.5,153.9 RZ152.1 RZ151.2
CAM0_PWDN: length 44.3
  TOP w0.107: J14.93 v1(117,156.59)
  TOP w0.127: v1(96.14,136.78) 96.14,133.3 J1.L49
  IN1 w0.124: v1(96.14,136.78) 97.69,138.33 97.69,142.24 108.61,153.16 110.42,153.16 113.85,156.59 v1(117,156.59)
CAM0_RST: length 79.6
  TOP w0.107: J1.L5 53.3,133.74 54.38,134.82 v1(55.37,134.82) ; J14.95 v1(117.5,163.73)
  IN1 w0.124: v1(117.5,163.73) 117.5,163.02 114.92,160.44 109.54,160.44 91.85,142.75 70.23,142.75 63.31,135.83 57.27,135.83 56.26,134.82 v1(55.37,134.82)
CAM1_PWDN: length 101.2
  TOP w0.107: v1(57.76,124.66) 58,124.9 J1.F10 ; J14.90 v1(116,173.23)
  IN1 w0.124: v1(116,173.23) 116,170.9 115.66,170.56 115.66,165.97 114.93,165.24 114.93,162.84 114.49,162.39 111.77,162.39 111.35,161.97 109.25,161.97 91.33,144.05 69.72,144.05 62.78,137.11 55.86,137.11 53.52,134.77 53.52,133.1 53.92,132.7 53.92,131.13 53.52,130.73 53.52,126.09 55.58,124.03 57.12,124.03 v1(57.76,124.66)
CAM1_RST: length 98.6
  TOP w0.107: J14.92 v1(116.5,172.72) ; J1.F9 57.1,124.87 v1(56.9,124.66)
  IN1 w0.124: v1(116.5,172.72) 116.5,163.23 115.23,161.97 111.95,161.97 111.53,161.55 109.43,161.55 91.49,143.6 69.87,143.6 62.96,136.69 56.04,136.69 53.95,134.6 53.95,133.27 54.35,132.87 54.35,130.96 53.95,130.56 53.95,126.26 55.19,125.02 56.54,125.02 v1(56.9,124.66)
CAM_AVDD_EN: length 69.8
  TOP w0.107: RZ2.1 136.4,174.24 v1(129.79,167.64) ; v1(102.28,126.02) 102.2,125.94 J1.F56
  IN1 w0.124: v1(102.28,126.02) 101.73,126.57 101.73,127.89 101.26,128.35 101.26,130.98 102.11,131.83 102.11,137.16 104.78,139.83 104.78,145.14 112.79,153.15 113.78,153.15 114.26,153.64 122.04,153.64 124.99,156.59 124.99,158.01 129.31,162.33 129.31,167.16 v1(129.79,167.64)
CAM_BACKLIGHT_PWM: length 38.8
  TOP w0.107: J14.109 v1(121,163.7) ; RZ18.1 v1(102.87,140.08)
  BOTTOM w0.107: v1(121,163.7) 120.87,163.83 119.38,163.83 117.86,162.31 110.62,162.31 109.53,161.22 109.53,158.25 105.03,153.75 105.03,146.94 103.38,145.29 103.38,140.59 v1(102.87,140.08)
CAM_ERROR1: length 80.7
  TOP w0.107: v3(62.52,133.5) 62.52,133.04 J1.L15 ; J14.76 v1(112.5,172.72)
  IN1 w0.124: v1(62.52,142.08) 62.61,141.99 65.53,141.99 68.83,145.29 91.14,145.29 108.84,162.98 110.94,162.98 111.55,163.6 112.44,163.6 112.45,163.6 112.45,164.19 114.66,166.39 114.66,169.98 112.5,172.13 v1(112.5,172.72)
  IN3 w0.124: v3(62.52,133.5) v1(62.52,142.08)
CAM_ERROR2: length 91.8
  TOP w0.107: J14.78 v1(113,173.23) ; v1(52.7,135.71) 56.44,135.71 56.9,135.25 J1.L9
  IN1 w0.124: v1(113,173.23) 113,171.99 114.91,170.08 114.91,166.29 112.7,164.08 112.7,163.5 112.55,163.34 111.66,163.34 111.04,162.73 108.94,162.73 91.25,145.04 68.94,145.04 62.39,138.49 55.84,138.49 53.06,135.71 v1(52.7,135.71)
CAM_ERROR3: length 103.1
  TOP w0.107: J14.84 v1(114.5,172.72) ; J1.A7 v1(55.1,118.52)
  IN1 w0.124: v1(55.1,118.52) 55.1,118.81 54.69,119.23 53.9,119.23 53.08,120.04 53.08,132.16 52.22,133.02 52.22,134.52 55.94,138.24 62.49,138.24 69.04,144.79 91.35,144.79 109.04,162.48 111.15,162.48 111.76,163.09 112.65,163.09 112.95,163.4 112.95,163.98 115.16,166.18 115.16,170.21 114.5,170.87 v1(114.5,172.72)
CAM_ERROR4: length 88.3
  TOP w0.107: v1(52.7,133.47) 52.4,133.17 J1.L4 ; J14.86 v1(115,173.23)
  IN1 w0.124: v1(115,173.23) 115,170.73 115.41,170.31 115.41,166.08 114.68,165.35 114.68,162.94 114.39,162.65 111.67,162.65 111.25,162.23 109.15,162.23 91.46,144.53 69.15,144.53 62.6,137.98 56.37,137.98 52.7,134.32 v1(52.7,133.47)
CAM_FRSYNC1: length 52.4
  TOP w0.107: J1.A62 v1(107.4,118.52) ; v1(115.7,158.88) 115,159.58 J14.85
  IN3 w0.124: v1(115.7,158.88) 115.32,158.88 111.02,154.58 111.02,151.89 109.75,150.62 109.75,147.57 109.12,146.94 109.12,138.56 108.1,137.54 108.1,132.21 108.08,132.19 108.08,131.85 108.1,131.83 108.1,131.32 108.72,130.7 108.72,130.05 108.08,129.41 108.08,128.65 107.82,128.4 107.82,126.75 108.02,126.55 108.02,125.85 107.82,125.65 107.82,123.83 108.08,123.57 108.08,122.43 107.82,122.17 107.82,121.03 107.4,120.61 v1(107.4,118.52)
CAM_FRSYNC2: length 57.3
  TOP w0.107: J1.F59 v1(104.9,126.02) ; J14.98 v1(118,173.23)
  IN3 w0.124: v1(104.9,126.02) 104.9,129.79 105.16,130.05 105.16,131.68 105.32,131.85 105.32,136.27 106.06,137.01 106.06,138.39 106.94,139.27 106.94,146.97 106.65,147.26 106.65,156.25 110.72,160.32 113.48,160.32 114.79,161.63 114.79,165.53 116.36,167.1 116.36,170.39 118,172.03 v1(118,173.23)
CAM_FRSYNC3: length 51.6
  TOP w0.107: v1(106.17,148.97) 106.43,149.22 113.41,149.22 118,153.81 J14.97 ; J1.E59 v1(104.7,124.52)
  IN3 w0.124: v1(106.17,148.97) 106.17,147.32 105.74,146.89 105.74,137.38 104.42,136.05 104.42,131.85 104.27,131.69 104.27,130.36 104.42,130.21 104.42,128.85 104.27,128.69 104.27,126.62 104.42,126.47 104.42,125.2 104.7,124.92 v1(104.7,124.52)
CAM_FRSYNC4: length 93.7
  TOP w0.107: v1(54.71,127.48) 55.1,127.09 J1.G7 ; J14.96 v1(117.5,172.72)
  IN1 w0.124: v1(54.71,127.48) 54.48,127.71 54.48,130.05 54.84,130.4 54.84,134.88 56.21,136.26 63.13,136.26 70.05,143.17 91.67,143.17 109.37,160.87 111.19,160.87 111.19,160.87 112.55,160.87 114.75,160.87 117.03,163.16 117.03,172.25 v1(117.5,172.72)
CAM_INT1: length 52.5
  TOP w0.107: J1.E61 v1(106.5,124.52) ; J14.117 123,163.64 v1(123.57,163.07)
  IN3 w0.124: v1(106.5,124.52) 106.93,124.95 106.93,129.12 107.84,130.03 107.84,131.73 107.83,131.74 107.83,132.3 107.85,132.32 107.85,137.65 108.86,138.66 108.86,147.04 109.44,147.62 109.44,150.67 110.52,151.74 110.52,154.71 117.98,162.18 120.4,162.18 121.28,163.07 v1(123.57,163.07)
  BOTTOM w0.107: TP10.1 107.06,125.08 v1(106.5,124.52)
CAM_INT2: length 61.1
  TOP w0.107: J14.106 v1(120,173.23) ; J1.D62 v1(107.6,123.02)
  IN3 w0.124: v1(107.6,123.02) 106.95,123.02 105.98,123.99 105.98,125.15 106.3,125.48 106.3,126.36 105.79,126.87 105.79,128.33 107.59,130.13 107.59,131.62 107.58,131.64 107.58,132.4 107.6,132.42 107.6,137.75 108.61,138.76 108.61,147.15 109.19,147.72 109.19,150.77 110.26,151.84 110.26,154.82 116.87,161.42 116.87,169.37 120,172.5 v1(120,173.23)
  BOTTOM w0.107: TP9.1 107.6,123.35 v1(107.6,123.02)
CAM_INT3: length 55
  TOP w0.107: J14.103 119.5,154.17 113.54,148.21 v1(108.58,148.21) ; J1.F60 v1(105.8,126.02)
  IN1 w0.124: v1(105.8,126.02) 105.8,126.36 105.41,126.75 102.36,126.75 101.98,127.13 101.98,127.99 101.52,128.46 101.52,130.88 102.36,131.72 102.36,137.06 105.03,139.72 105.03,145.03 108.2,148.21 v1(108.58,148.21)
  BOTTOM w0.107: v1(105.8,126.02) 105.79,126.01 TP8.1
CAM_INT4: length 59.2
  TOP w0.107: J14.104 v1(119.5,172.72) ; J1.D60 v1(105.8,123.02)
  IN3 w0.124: v1(119.5,172.72) 119.5,172.36 116.61,169.47 116.61,161.52 107.94,152.84 107.94,147.8 108.23,147.5 108.23,138.74 107.35,137.85 107.35,132.53 107.33,132.51 107.33,131.53 107.34,131.52 107.34,130.33 105.38,128.37 105.38,124.23 105.8,123.82 v1(105.8,123.02)
  BOTTOM w0.107: TP7.1 106.43,123.64 v1(105.8,123.02)
CAM_PG: length 2
  TOP w0.203: RB4.1 131.67,174.52 130.79,175.41 U34.8
CAM_SPI_CS0: length 3
  TOP w0.107: J14.113 122,162.99 TP53.1
CAM_SPI_MISO: length 3
  TOP w0.107: TP55.1 122,173.56 J14.114
CAM_SPI_MOSI: length 3
  TOP w0.107: TP54.1 121.5,173.65 J14.112
CAM_SPI_SCK: length 3
  TOP w0.107: TP52.1 121.5,163.03 J14.111
CAM_TE_RSV: length 41.2
  TOP w0.107: J14.101 119,154.3 113.54,148.85 107.95,148.85 107.31,148.21 103.38,148.21 v1(103.12,148.46) ; RZU7.1 v1(97.16,140.08)
  IN3 w0.124: v1(97.16,140.08) 97.16,142.62 103,148.46 v1(103.12,148.46)
CAM_VDD_SYS_EN: length 94.5
  TOP w0.107: J1.E10 v1(57.8,123.22) ; J14.119 123.5,163.78 v1(123.57,163.7)
  IN1 w0.124: v1(123.57,163.7) 123.06,163.7 121.27,161.91 117,161.91 115.1,160.01 109.72,160.01 92.02,142.32 74.55,142.32 67.63,135.4 57.44,135.4 56.06,134.01 56.06,133.22 55.52,132.69 55.52,127.51 58.19,124.84 58.19,123.61 v1(57.8,123.22)
CAM_VDDEN: length 5
  TOP w0.203: U34.9 132.15,176.28 132.45,175.98 CA13.1
  TOP w0.508: CA13.1 134.1,175.98 R756.2 R245.2 RZ2.2
CAN0_DIN: length 107.5
  TOP w0.107: U40.5 v1(34.36,178.31) ; J1.F58 v1(104,126.02)
  IN1 w0.124: v1(104,126.02) 103.33,125.35 101.09,125.35 100.58,125.86 100.58,127.89 98.81,129.67 98.81,131.44 93.85,136.4 v1(77.34,136.4)
  IN3 w0.124: v1(77.34,136.4) 76.99,136.4 76.28,137.11 76.28,142.27 67.62,150.93 67.62,164.99 61.8,170.81 46.71,170.81 40.36,177.16 35.51,177.16 v1(34.36,178.31)
CAN0_DOUT: length 112.7
  TOP w0.107: U40.3 v1(31.82,178.44) ; J1.D59 v1(104.9,123.02)
  IN1 w0.124: v1(104.9,123.02) 104.9,123.32 104.65,123.57 101.09,123.57 100.2,124.46 100.2,126.36 99.19,127.38 99.19,128.4 98.3,129.29 98.3,131.44 93.85,135.89 v1(77.85,135.89)
  IN3 w0.124: v1(31.82,178.44) 32,178.44 33.53,176.91 40.26,176.91 46.61,170.56 61.7,170.56 67.25,165.01 67.25,150.95 76.03,142.17 76.03,136.57 76.71,135.89 v1(77.85,135.89)
CAN_REF: length 2.1
  TOP w0.508: U40.15 30.55,191.15 C163.2
  vias: v1(38.35,192.02) v1(38.35,191.26) v1(39.12,192.02) v1(39.12,191.26)
CANH: length 31.3
  TOP w0.254: NMEA2000.5 35.39,195.4 30.56,195.4 29.79,194.64 26.24,194.64 25.27,193.68 24.43,193.68 D12.2 24.3,193.04 v1(24.77,193.04) ; v1(32.72,193.15) 32.36,193.15 32.17,192.95 C162.1 33.32,192.35 RZU1.2 33.38,192.35 R265.2
  IN1 w0.254: v1(32.72,193.15) 24.87,193.15 v1(24.77,193.04)
  BOTTOM w0.254: R264.2 29.44,193.15 FL2.4 v1(32.72,193.15)
CANL: length 31.4
  TOP w0.254: v1(24.77,194.44) 24.3,194.44 D13.2 24.63,195.28 29.54,195.28 30.3,196.04 34.02,196.04 NMEA2000.4 ; v1(35.12,193.12) 35.67,192.56 C164.1 35.52,192.33 RZU2.2 34.49,193.34 R265.1
  IN1 w0.254: v1(35.12,193.12) 34.45,193.12 33.76,193.8 25.4,193.8 v1(24.77,194.44)
  BOTTOM w0.254: FL2.3 35.15,193.15 v1(35.12,193.12) ; v1(24.77,194.44) 25.15,194.44 R267.1
CARRIER_POWER_ON: length 148.4
  TOP w0.107: U4.4 109.36,139.94 109.63,139.67 R24.1 v1(110.11,140.34) ; v1(92.38,102.84) RZ56.1 90.04,102.08 89.43,101.47 89.43,94.23 88.39,93.19 RZU26.1 ; RZ45.1 v1(120.04,102.46) ; RZ5.2 v1(126.9,156.08)
  IN3 w0.124: v1(120.04,102.46) 120.04,103.89 120.93,104.78 122.43,104.78 124.74,107.08 124.74,129.28 127.06,131.6 127.06,140.17 v1(127.38,140.49) 127.12,140.75 127.12,151.34 127.46,151.68 127.46,155.52 v1(126.9,156.08) 127.46,156.64 127.46,158.42 128.32,159.28 131.85,159.28 134.87,162.31 134.87,165.33 138.05,168.5 138.05,173.46 v1(138.71,174.12)
  BOTTOM w0.107: v1(127.38,140.49) RZ167.1 125.2,140.49 124.82,140.87 110.64,140.87 v1(110.11,140.34) ; v1(92.38,102.84) 92.38,102.95 94.56,105.13 100.31,105.13 102.72,102.71 112.01,102.71 112.7,103.4 119.11,103.4 v1(120.04,102.46) ; RZ147.1 v1(138.71,174.12)
CARRIER_SHUTDOWN_N: length 7.6
  TOP w0.107: U11.2 109.21,154.79 109.32,154.69 111.15,154.69 111.78,155.32 Q5.D Q4.D 114.27,153.67 RB22.2
CASE1_GND:
  vias: v1(26.04,197.1) v1(26.04,196.47) v1(26.8,197.1) v1(26.8,196.47)
CCG4_LED: length 26.9
  TOP w0.254: v1(141.68,40.97) 141.02,41.63 RZ120.1 139.34,42.75 Z10.2 139.29,43.92 RZ115.2
  IN1 w0.254: v1(141.68,40.97) 142.27,40.39 148.91,40.39 155.65,33.64 155.65,31.01 156.31,30.35 AUTOPW1.1
CHIPENABLE: length 5
  TOP w0.107: U20.50 77.47,65.75 77.33,65.61 RZ90.1 RZU34.2
CLK-ISP0#: length 49.4
  TOP w0.107: v1(142.27,72.14) 142.42,72.3 U13.13
  IN1 w0.124: v1(142.27,72.14) 141.63,72.14 141.25,71.75 141.25,66.55 139.73,65.02 v1(139.73,62.36)
  BOTTOM w0.107: v1(139.73,62.36) 139.34,62.36 138.58,61.59 133.06,61.59 132.55,62.1 124.74,62.1 123.85,61.21 123.85,52.58 122.25,50.97 SW1.4 SW1.3 ; v1(142.27,72.14) 141.71,72.14 RZ203.2
CLKREQ_M2_KEY_B_N: length 2.4
  BOTTOM w0.107: R221.1 147.7,188.59 147.88,188.42 NGFF1.52
CODEC_INT: length 111.9
  TOP w0.107: J1.B8 56.28,119.44 v1(56.28,120.02) ; v1(140.08,151.13) 139.38,151.83 136.66,151.83 136.02,152.48 133.12,152.48 131.42,150.77 117.84,150.77 113.84,146.77 63.42,146.77 60.29,143.64 v1(59.44,143.64)
  IN3 w0.124: v1(56.28,120.02) 56.28,121.1 58.72,123.55 58.72,125.91 59.94,127.13 59.94,127.86 58.98,128.83 58.98,140.46 59.44,140.92 v1(59.44,143.64)
  BOTTOM w0.107: RZ156.1 v1(140.08,151.13)
COMR_A: length 45
  TOP w0.203: U66.32 98.29,81.64 98.78,81.15 99.21,81.15 99.59,80.77
  TOP w0.508: 99.59,80.77 100.23,80.14 100.23,79.57 C291.2 100.65,70.9 99.72,69.98 97.82,69.98 97.18,69.34 97.18,64.77 v1(95.53,63.12) ; v1(96.9,56.74) 96.95,56.69 v1(98.6,56.69) v1(100.89,56.69) 103.01,56.69 v1(103.06,56.74) 103.12,56.68 104.81,56.68 v1(104.98,56.85)
  IN1 w0.508: v1(95.53,63.12) 95.53,58.12 v1(96.9,56.74)
  BOTTOM w0.508: R511.2 v1(100.89,56.69) 100.33,56.13 R506.2 ; R510.2 v1(98.6,56.69) 98.04,56.13 R508.2 ; R505.2 v1(96.9,56.74) ; v1(104.98,56.85) 104.78,56.64 R514.2 ; R513.2 103.63,56.17 v1(103.06,56.74) 102.62,56.3 R507.2
CSI_0_CLK_N: length 47.3
  TOP w0.102: J1.F42 89.8,125.36 89.93,125.49 89.93,125.85 v3(89.78,126) ; v1(91.11,158.32) 90.88,158.54 90.88,164.21 91,164.33 J14.9
  IN3 w0.109: v3(89.78,126) 89.92,126.13 89.92,126.58 89.81,126.69 88.03,126.69 86.14,128.58 86.14,129.36 86.31,129.53 86.31,131.03 85.98,131.36 85.98,132.69 86.06,132.77 86.06,144.74 89.48,148.16 89.48,158.55 89.99,159.05 90.62,159.05 90.88,158.8 90.88,158.54 v1(91.11,158.32)
CSI_0_CLK_P: length 46.5
  TOP w0.102: J14.7 90.5,164.34 90.63,164.21 90.63,158.54 v1(90.4,158.32) ; v3(90.32,126) 90.18,125.86 90.18,125.49 90.31,125.36 J1.F43
  IN3 w0.109: v3(90.32,126) 90.18,126.13 90.18,126.68 89.92,126.94 88.14,126.94 86.39,128.68 86.39,129.23 86.56,129.4 86.56,131.13 86.23,131.46 86.23,132.58 86.32,132.67 86.32,144.64 89.74,148.06 89.74,158.44 90.1,158.8 90.52,158.8 90.63,158.69 90.63,158.54 v1(90.4,158.32)
CSI_0_D0_N: length 49.8
  TOP w0.102: v3(88.68,124.5) 88.83,124.35 88.83,123.99 88.7,123.86 J1.E41 ; J14.3 89.5,164.35 89.38,164.23 89.38,161.85 v1(89.6,161.62)
  IN3 w0.109: v3(88.68,124.5) 88.82,124.36 88.82,123.88 88.71,123.78 85.63,123.78 85.07,124.34 85.07,126.39 84.48,126.97 84.48,128.34 84.22,128.6 84.22,132.25 83.81,132.65 83.81,144.62 88.11,148.92 88.11,159.21 89.38,160.47 89.38,161.39 v1(89.6,161.62)
CSI_0_D0_P: length 50.6
  TOP w0.102: J1.E42 89.25,123.86 89.08,124.03 89.08,124.36 v3(89.22,124.5) ; J14.1 89,164.34 89.12,164.22 89.12,161.85 v1(88.89,161.62)
  IN3 w0.109: v1(88.89,161.62) 89.12,161.39 89.12,160.58 87.86,159.31 87.86,149.03 83.56,144.73 83.56,132.55 83.96,132.14 83.96,128.5 84.23,128.23 84.23,126.87 84.81,126.28 84.81,124.23 85.52,123.52 88.82,123.52 89.08,123.78 89.08,124.36 v3(89.22,124.5)
CSI_0_D1_N: length 49.1
  TOP w0.102: J14.15 92.5,164.41 92.35,164.26 92.35,163.34 91.97,162.96 91.97,159.78 v1(92.18,159.58) ; v3(85.98,124.5) 86.13,124.35 86.13,123.99 86,123.86 J1.E38
  IN3 w0.109: v3(85.98,124.5) 86.08,124.59 86.08,127.47 84.82,128.73 84.82,129.67 85.35,130.2 85.35,130.71 84.73,131.33 84.73,132.46 84.33,132.87 84.33,144.27 88.65,148.58 88.65,158.96 90.04,160.35 91.61,160.35 91.95,160.01 91.95,159.81 v1(92.18,159.58)
CSI_0_D1_P: length 48.2
  TOP w0.102: J1.E39 86.51,123.86 86.38,123.99 86.38,124.36 v3(86.52,124.5) ; v1(91.47,159.58) 91.72,159.83 91.72,163.07 92.1,163.44 92.1,164.26 92,164.36 J14.13
  IN3 w0.109: v1(91.47,159.58) 91.69,159.81 91.69,159.9 91.5,160.1 90.14,160.1 88.9,158.85 88.9,148.48 84.58,144.16 84.58,132.97 84.99,132.57 84.99,131.44 85.61,130.82 85.61,130.1 85.07,129.56 85.07,128.84 86.33,127.57 86.33,124.68 v3(86.52,124.5)
CSI_1_CLK_N: length 57.2
  TOP w0.102: J14.10 91,172.15 90.88,172.27 90.88,173.98 v1(91.1,174.21) ; J1.H42 89.8,128.36 89.93,128.49 89.93,128.85 v3(89.78,128.99)
  IN3 w0.109: v1(91.1,174.21) 90.88,174.44 90.88,174.54 90.98,174.65 91.46,174.65 92.27,173.84 93.24,173.84 93.5,173.58 93.5,172.21 91.34,170.05 91.34,167.03 92.13,166.24 92.13,162.74 94.5,160.36 94.5,148.66 89.3,143.45 89.3,132.5 89.47,132.33 89.47,131.5 90.15,130.82 90.15,130.32 89.94,130.1 89.94,129.15 v3(89.78,128.99)
CSI_1_CLK_P: length 58
  TOP w0.102: v1(90.39,174.21) 90.62,173.98 90.62,172.29 90.5,172.17 J14.8 ; J1.H43 90.33,128.36 90.18,128.51 90.18,128.86 v3(90.32,128.99)
  IN3 w0.109: v3(90.32,128.99) 90.19,129.12 90.19,130 90.41,130.21 90.41,130.92 89.72,131.61 89.72,132.44 89.55,132.61 89.55,143.35 94.76,148.55 94.76,160.47 92.38,162.84 92.38,166.34 91.59,167.13 91.59,169.95 93.75,172.11 93.75,173.68 93.34,174.09 92.38,174.09 91.57,174.9 90.88,174.9 90.62,174.65 90.62,174.44 v1(90.39,174.21)
CSI_1_D0_N: length 53.9
  TOP w0.102: J14.4 89.5,172.15 89.38,172.27 89.38,172.96 v1(89.6,173.19) ; J1.G42 89.2,126.86 89.08,126.97 89.08,127.36 v3(89.22,127.5)
  IN3 w0.109: v3(89.22,127.5) 89.06,127.65 89.06,128.28 88.66,128.68 88.66,129.37 87.6,130.42 87.6,131.56 87.31,131.85 87.31,132.88 87.12,133.07 87.12,143.69 93.22,149.78 93.22,159.83 89.51,163.54 89.51,170.26 89.38,170.39 89.38,172.96 v1(89.6,173.19)
CSI_1_D0_P: length 53.9
  TOP w0.102: J14.2 89,172.16 89.12,172.28 89.12,172.96 v1(88.89,173.19) ; J1.G41 88.7,126.86 88.83,126.99 88.83,127.35 v3(88.68,127.5)
  IN3 w0.109: v1(88.89,173.19) 89.12,172.96 89.12,170.28 89.26,170.15 89.26,163.43 92.96,159.72 92.96,149.89 86.87,143.79 86.87,132.97 87.06,132.78 87.06,131.74 87.35,131.45 87.35,130.31 88.4,129.26 88.4,128.58 88.81,128.18 88.81,127.62 v3(88.68,127.5)
CSI_1_D1_N: length 50.5
  TOP w0.102: v1(92.6,173.19) 92.38,172.96 92.38,172.27 92.5,172.15 J14.16 ; v3(89.22,130.5) 89.08,130.36 89.08,129.99 89.21,129.86 J1.J42
  IN3 w0.109: v1(92.6,173.19) 92.38,172.96 92.38,172.03 90.73,170.38 90.73,163.41 93.99,160.15 93.99,149.11 88.78,143.91 88.78,132.61 88.58,132.41 88.58,131.47 89.06,130.99 89.06,130.65 v3(89.22,130.5)
CSI_1_D1_P: length 50.5
  TOP w0.102: J1.J41 88.7,129.86 88.83,129.99 88.83,130.35 v3(88.68,130.5) ; v1(91.89,173.19) 92.12,172.96 92.12,172.29 92,172.17 J14.14
  IN3 w0.109: v3(88.68,130.5) 88.81,130.62 88.81,130.88 88.32,131.36 88.32,132.51 88.53,132.72 88.53,144.01 93.73,149.22 93.73,160.04 90.47,163.3 90.47,170.48 92.12,172.13 92.12,172.96 v1(91.89,173.19)
CSI_2_CLK_N: length 57.6
  TOP w0.102: J1.B42 89.8,119.36 89.93,119.49 89.93,119.85 v3(89.78,120) ; v1(95.61,162.08) 95.38,162.31 95.38,164.25 95.5,164.37 J14.27
  BOTTOM w0.102: v1(95.61,162.08) 95.38,162.31 95.38,162.56 95.13,162.81 94.56,162.81 94.11,162.36 94.11,151.22 84.25,141.37 84.25,132.97 84.84,132.38 84.84,131.43 85.39,130.87 85.39,130.22 84.86,129.69 84.86,128.46 85.45,127.88 85.45,127.15 84.81,126.51 84.81,124.24 85.19,123.86 85.83,123.86 86.23,123.46 86.23,122.45 87.94,120.74 89.49,120.74 89.92,120.31 89.92,120.13 v3(89.78,120)
CSI_2_CLK_P: length 56.8
  TOP w0.102: J14.25 95,164.37 95.12,164.25 95.12,162.31 v1(94.89,162.08) ; v3(90.32,120) 90.18,119.86 90.18,119.49 90.31,119.36 J1.B43
  BOTTOM w0.102: v1(94.89,162.08) 95.12,162.31 95.12,162.46 95.02,162.56 94.67,162.56 94.36,162.26 94.36,151.12 84.51,141.26 84.51,133.07 85.09,132.49 85.09,131.54 85.65,130.98 85.65,130.11 85.12,129.58 85.12,128.56 85.7,127.98 85.7,127.04 85.06,126.41 85.06,124.34 85.29,124.11 85.94,124.11 86.49,123.56 86.49,122.56 88.05,121 89.59,121 90.18,120.41 90.18,120.13 v3(90.32,120)
CSI_2_D0_N: length 55.6
  TOP w0.102: J1.A42 89.21,117.86 89.08,117.99 89.08,118.36 v3(89.22,118.5) ; J14.21 94,164.36 93.88,164.23 93.88,163.53 v1(94.1,163.3)
  BOTTOM w0.102: v3(89.22,118.5) 89.08,118.63 89.08,118.99 88.77,119.29 86.95,119.29 86.49,119.76 86.49,120.97 85.14,122.32 85.14,123.19 84.3,124.03 84.3,132.2 83.74,132.76 83.74,141.58 93.55,151.38 93.55,162.53 93.88,162.86 93.88,163.07 v1(94.1,163.3)
CSI_2_D0_P: length 55.6
  TOP w0.102: v1(93.39,163.3) 93.62,163.53 93.62,164.23 93.5,164.36 J14.19 ; J1.A41 88.7,117.86 88.83,117.99 88.83,118.35 v3(88.68,118.5)
  BOTTOM w0.102: v3(88.68,118.5) 88.82,118.63 88.82,118.88 88.67,119.04 86.85,119.04 86.23,119.66 86.23,120.86 84.89,122.21 84.89,123.08 84.05,123.92 84.05,132.09 83.49,132.65 83.49,141.69 93.29,151.49 93.29,162.64 93.62,162.97 93.62,163.07 v1(93.39,163.3)
CSI_2_D1_N: length 52.9
  TOP w0.102: v3(88.68,121.5) 88.83,121.35 88.83,120.99 88.7,120.86 J1.C41 ; v1(97.1,160.2) 96.88,160.43 96.88,164.24 97,164.36 J14.33
  BOTTOM w0.102: v3(88.68,121.5) 88.82,121.63 88.82,122.26 88.52,122.57 88.52,123.51 88.34,123.69 87.75,123.69 87.5,123.94 87.5,124.61 86.26,125.86 86.26,128.51 86.18,128.59 86.18,131.18 85.98,131.38 85.98,132.64 86.18,132.84 86.18,142.19 94.95,150.95 94.95,159.82 96.04,160.91 96.63,160.91 96.88,160.66 96.88,160.43 v1(97.1,160.2)
CSI_2_D1_P: length 52.1
  TOP w0.102: J1.C42 89.21,120.86 89.08,120.99 89.08,121.36 v3(89.22,121.5) ; J14.31 96.5,164.36 96.62,164.24 96.62,160.43 v1(96.39,160.2)
  BOTTOM w0.102: v3(89.22,121.5) 89.08,121.63 89.08,122.37 88.77,122.67 88.77,123.61 88.44,123.94 87.86,123.94 87.76,124.04 87.76,124.72 86.51,125.96 86.51,128.62 86.44,128.69 86.44,131.29 86.23,131.49 86.23,132.53 86.44,132.74 86.44,142.08 95.2,150.84 95.2,159.71 96.14,160.66 96.52,160.66 96.62,160.55 96.62,160.43 v1(96.39,160.2)
CSI_3_CLK_N: length 62.7
  TOP w0.102: J14.28 95.5,172.15 95.38,172.27 95.38,173.25 95.73,173.61 95.73,174.9 v1(95.96,175.13) ; J1.F45 92.5,125.36 92.63,125.49 92.63,125.85 v3(92.48,126)
  BOTTOM w0.102: v3(92.48,126) 92.62,126.13 92.62,126.65 92.89,126.92 92.89,127.73 93.93,128.77 93.93,129.15 92.89,130.2 92.89,130.63 92.2,131.32 92.2,132.21 91.57,132.84 91.57,143.62 97.76,149.81 97.76,156.63 99.52,158.39 99.52,165.15 97.56,167.1 97.56,169.85 98.02,170.31 98.02,173.17 96.93,174.27 96.93,175.38 96.72,175.59 95.83,175.59 95.73,175.48 95.73,175.35 v1(95.96,175.13)
CSI_3_CLK_P: length 63.5
  TOP w0.102: v1(95.25,175.13) 95.48,174.9 95.48,173.71 95.12,173.35 95.12,172.26 95,172.14 J14.26 ; v3(93.02,126) 92.88,125.86 92.88,125.51 93.04,125.36 J1.F46
  BOTTOM w0.102: v3(93.02,126) 92.88,126.13 92.88,126.55 93.14,126.81 93.14,127.62 94.19,128.67 94.19,129.26 93.14,130.3 93.14,130.74 92.46,131.42 92.46,132.31 91.82,132.95 91.82,143.51 98.02,149.71 98.02,156.53 99.77,158.28 99.77,165.25 97.82,167.21 97.82,169.75 98.27,170.21 98.27,173.28 97.18,174.37 97.18,175.49 96.83,175.84 95.73,175.84 95.48,175.59 95.48,175.35 v1(95.25,175.13)
CSI_3_D0_N: length 66.3
  TOP w0.102: J14.22 94,172.12 93.85,172.27 93.85,173.25 93.45,173.66 93.45,174.93 v1(93.68,175.16) ; J1.E44 91.4,123.86 91.53,123.99 91.53,124.35 v3(91.38,124.5)
  BOTTOM w0.102: v3(91.38,124.5) 91.52,124.63 91.52,124.93 91.29,125.16 91.29,126.3 91.03,126.56 90.57,126.56 90.2,126.94 90.2,127.98 90.06,128.11 88.87,128.11 88.52,128.46 88.52,129.07 87.52,130.08 87.52,130.85 88.27,131.6 88.27,142.9 96.09,150.72 96.09,157.36 97.89,159.16 97.89,161.46 96.7,162.66 96.7,164.82 95.17,166.34 95.17,172.67 94.39,173.45 94.39,175.51 94.18,175.72 93.6,175.72 93.45,175.56 93.45,175.39 v1(93.68,175.16)
CSI_3_D0_P: length 67.2
  TOP w0.102: J14.20 93.5,172.19 93.57,172.27 93.6,172.27 93.6,172.27 93.6,173.15 93.19,173.55 93.19,174.93 v1(92.96,175.16) ; v3(91.92,124.5) 91.78,124.36 91.78,123.98 91.9,123.86 J1.E45
  BOTTOM w0.102: v1(92.96,175.16) 93.19,175.39 93.19,175.67 93.5,175.97 94.28,175.97 94.64,175.62 94.64,173.56 95.43,172.77 95.43,166.45 96.95,164.92 96.95,162.76 98.15,161.57 98.15,159.06 96.34,157.25 96.34,150.62 88.52,142.79 88.52,131.5 87.77,130.75 87.77,130.18 88.77,129.18 88.77,128.56 88.98,128.36 90.17,128.36 90.45,128.08 90.45,127.04 90.68,126.81 91.14,126.81 91.54,126.41 91.54,125.27 91.78,125.03 91.78,124.63 v3(91.92,124.5)
CSI_3_D1_N: length 54.6
  TOP w0.102: v3(91.91,127.43) 91.78,127.3 91.78,126.99 91.91,126.86 J1.G45 ; J14.34 97,172.15 96.88,172.27 96.88,172.96 v1(97.1,173.19)
  BOTTOM w0.102: v3(91.91,127.43) 91.89,127.43 91.77,127.55 91.77,128.23 91.52,128.49 91.52,129.23 90.44,130.3 90.44,130.96 89.74,131.67 89.74,142.85 97.17,150.28 97.17,156.88 98.97,158.68 98.97,162.22 98.37,162.81 98.37,165.07 96.88,166.57 96.88,172.96 v1(97.1,173.19)
CSI_3_D1_P: length 54.6
  TOP w0.102: J14.32 96.5,172.11 96.62,172.24 96.62,172.96 v1(96.39,173.19) ; J1.G44 91.4,126.86 91.53,126.99 91.53,127.29 v3(91.38,127.43)
  BOTTOM w0.102: v1(96.39,173.19) 96.62,172.96 96.62,166.47 98.12,164.97 98.12,162.71 98.72,162.11 98.72,158.79 96.91,156.99 96.91,150.38 89.48,142.95 89.48,131.56 90.19,130.86 90.19,130.19 91.26,129.12 91.26,128.38 91.52,128.13 91.52,127.55 91.4,127.43 v3(91.38,127.43)
CSI_4_CLK_N: length 47
  TOP w0.102: J14.45 100,164.36 99.88,164.24 99.88,162.87 100.03,162.71 101.12,162.71 101.37,162.46 101.37,161.85 v1(101.6,161.62) ; v3(95.72,126) 95.58,125.86 95.58,125.48 95.7,125.36 J1.F49
  IN3 w0.109: v3(95.72,126) 95.56,126.15 95.56,126.77 95.78,126.99 95.78,127.84 95.23,128.39 95.23,129.53 95.12,129.64 95.12,131.2 95.53,131.61 95.53,134.7 94.88,135.35 94.88,143.07 102.86,151.06 102.86,159.89 102.22,160.53 101.57,160.53 101.37,160.73 101.37,161.39 v1(101.6,161.62)
CSI_4_CLK_P: length 47
  TOP w0.102: J14.43 99.5,164.36 99.62,164.24 99.62,162.76 99.92,162.46 101.02,162.46 101.12,162.36 101.12,161.85 v1(100.89,161.62) ; J1.F48 95.2,125.36 95.33,125.49 95.33,125.85 v3(95.18,126)
  IN3 w0.109: v1(100.89,161.62) 101.12,161.39 101.12,160.63 101.47,160.27 102.12,160.27 102.61,159.78 102.61,151.16 94.63,143.18 94.63,135.24 95.28,134.59 95.28,131.72 94.85,131.29 94.85,129.55 94.98,129.42 94.98,128.29 95.53,127.74 95.53,127.1 95.29,126.86 95.29,126.1 v3(95.18,126)
CSI_4_D0_N: length 46.7
  TOP w0.102: J14.39 98.5,164.07 98.38,163.95 98.38,162.99 99.57,161.8 99.57,160.4 99.87,160.1 101.25,160.1 101.5,159.85 101.5,159.13 v1(101.73,158.9) ; J1.G47 94.1,126.86 94.23,126.99 94.23,127.27 v3(94.08,127.41)
  IN3 w0.109: v1(101.73,158.9) 101.5,159.13 101.5,159.44 101.22,159.72 100.36,159.72 99.85,159.2 99.85,149.49 93.84,143.48 93.84,129.45 94.19,129.1 94.19,127.53 v3(94.08,127.41)
CSI_4_D0_P: length 45.8
  TOP w0.102: v1(101.02,158.9) 101.24,159.13 101.24,159.74 101.14,159.84 99.77,159.84 99.31,160.3 99.31,161.69 98.12,162.89 98.12,163.95 98,164.07 J14.37 ; v3(94.61,127.41) 94.48,127.28 94.48,127.04 94.66,126.86 J1.G48
  IN3 w0.109: v3(94.61,127.41) 94.46,127.56 94.46,129.21 94.11,129.57 94.11,143.39 100.1,149.38 100.1,159.1 100.46,159.46 101.11,159.46 101.24,159.33 101.24,159.13 v1(101.02,158.9)
CSI_4_D1_N: length 49.4
  TOP w0.102: J14.51 101.5,164.33 101.38,164.21 101.38,163.57 v1(101.6,163.34) ; v3(94.62,124.5) 94.48,124.36 94.48,123.96 94.58,123.86 J1.E48
  IN3 w0.109: v3(94.62,124.5) 94.49,124.62 94.49,124.8 94.72,125.03 96.19,125.03 96.89,125.73 96.89,127.88 96.27,128.5 96.27,129.79 96.52,130.05 96.52,131.1 96.3,131.32 96.3,135.02 95.67,135.65 95.67,142.7 103.68,150.71 103.68,161.24 102.16,162.76 101.53,162.76 101.37,162.92 101.37,163.11 v1(101.6,163.34)
CSI_4_D1_P: length 49.4
  TOP w0.102: v3(94.08,124.5) 94.23,124.35 94.23,123.99 94.1,123.86 J1.E47 ; J14.49 101,164.33 101.12,164.21 101.12,163.57 v1(100.89,163.34)
  IN3 w0.109: v3(94.08,124.5) 94.24,124.65 94.24,124.91 94.61,125.29 96.09,125.29 96.64,125.84 96.64,127.77 96.01,128.4 96.01,129.9 96.27,130.15 96.27,131 96.05,131.22 96.05,134.91 95.41,135.55 95.41,142.8 103.42,150.81 103.42,161.14 102.05,162.51 101.43,162.51 101.12,162.82 101.12,163.11 v1(100.89,163.34)
CSI_5_CLK_N: length 60
  TOP w0.102: v3(91.92,121.5) 91.78,121.36 91.78,121 91.92,120.86 J1.C45 ; J14.67 110.5,164.37 110.38,164.25 110.38,163.59 109.83,163.04 106.05,163.04 105.94,162.94 105.94,162.74 v1(106.17,162.51)
  BOTTOM w0.102: v1(106.17,162.51) 105.94,162.28 105.94,158.79 100.53,153.38 100.53,148.99 94.74,143.19 94.74,133.58 96.39,131.93 96.39,130.28 96.47,130.21 96.47,129.14 97.3,128.31 97.3,126.92 97.65,126.57 97.65,124.78 96.9,124.04 96.9,122.54 96.4,122.04 91.98,122.04 91.78,121.83 91.78,121.63 v3(91.92,121.5)
CSI_5_CLK_P: length 60.1
  TOP w0.102: J14.65 110,164.35 110.12,164.22 110.12,163.69 109.72,163.3 105.94,163.3 105.69,163.05 105.69,162.74 v1(105.46,162.51) ; v3(91.38,121.5) 91.53,121.35 91.53,120.99 91.4,120.86 J1.C44
  BOTTOM w0.102: v1(105.46,162.51) 105.69,162.28 105.69,158.9 100.28,153.48 100.28,149.09 94.49,143.3 94.49,133.48 96.14,131.83 96.14,130.18 96.22,130.1 96.22,129.04 97.05,128.2 97.05,126.81 97.39,126.47 97.39,124.89 96.65,124.14 96.65,122.65 96.29,122.29 91.88,122.29 91.52,121.94 91.52,121.63 v3(91.38,121.5)
CSI_5_D0_N: length 58.3
  TOP w0.102: v3(90.32,122.99) 90.18,122.86 90.18,122.49 90.31,122.36 J1.D43 ; v1(106.58,164.01) 108.89,164.01 109,164.12 J14.61
  BOTTOM w0.102: v1(106.58,164.01) 106.35,163.78 106.35,163.32 106.07,163.04 103.97,163.04 103,162.07 103,158.03 98.98,154.02 98.98,149.59 92.58,143.19 92.58,133.26 93.22,132.63 93.22,131.74 93.9,131.05 93.9,130.62 94.95,129.57 94.95,128.51 95.78,127.68 95.78,127.15 95.32,126.69 94.46,126.69 94.23,126.46 94.23,125.52 93.9,125.19 93.4,125.19 93.09,124.88 93.09,124.42 92.3,123.64 90.38,123.64 90.18,123.43 90.18,123.13 v3(90.32,122.99)
CSI_5_D0_P: length 58.3
  TOP w0.102: v1(105.87,164.01) 103.66,164.01 103.5,164.17 J14.59 ; v3(89.78,122.99) 89.93,122.85 89.93,122.49 89.8,122.36 J1.D42
  BOTTOM w0.102: v3(89.78,122.99) 89.92,123.13 89.92,123.54 90.28,123.89 92.2,123.89 92.83,124.53 92.83,124.98 93.29,125.44 93.8,125.44 93.98,125.62 93.98,126.56 94.36,126.94 95.21,126.94 95.53,127.26 95.53,127.57 94.69,128.41 94.69,129.47 93.65,130.51 93.65,130.95 92.96,131.63 92.96,132.52 92.33,133.16 92.33,143.3 98.73,149.7 98.73,154.13 102.74,158.14 102.74,162.18 103.86,163.3 105.97,163.3 106.1,163.42 106.1,163.78 v1(105.87,164.01)
CSI_5_D1_N: length 59.7
  TOP w0.102: v3(92.48,122.99) 92.63,122.85 92.63,122.49 92.5,122.36 J1.D45 ; J14.73 112,164.37 111.88,164.25 111.88,163.61 110.49,162.23 108.69,162.23 107.6,161.14 105.06,161.14 104.88,160.96 104.88,160.71 v1(105.11,160.48)
  BOTTOM w0.102: v3(92.48,122.99) 92.48,123.1 93.25,123.87 95.29,123.87 96.63,125.21 96.63,126.15 96.29,126.5 96.29,127.89 95.46,128.72 95.46,129.78 94.41,130.83 94.41,131.47 93.73,132.15 93.73,143.62 99.52,149.41 99.52,153.8 103.53,157.81 103.53,160.96 103.78,161.21 104.63,161.21 104.88,160.96 104.88,160.71 v1(105.11,160.48)
CSI_5_D1_P: length 58.7
  TOP w0.102: J1.D46 93.03,122.36 92.88,122.51 92.88,122.86 v3(93.02,122.99) ; J14.71 111.5,164.37 111.62,164.25 111.62,163.72 110.39,162.48 108.58,162.48 107.49,161.39 104.95,161.39 104.62,161.06 104.62,160.71 v1(104.39,160.48)
  BOTTOM w0.102: v3(93.02,122.99) 93.02,123.27 93.36,123.61 95.4,123.61 96.89,125.1 96.89,126.26 96.54,126.6 96.54,127.99 95.71,128.83 95.71,129.89 94.67,130.93 94.67,131.57 93.98,132.26 93.98,143.51 99.77,149.3 99.77,153.7 103.78,157.71 103.78,160.86 103.89,160.96 104.52,160.96 104.62,160.86 104.62,160.71 v1(104.39,160.48)
CSI_6_CLK_N: length 50.4
  TOP w0.102: J14.46 100,172.15 99.88,172.27 99.88,172.96 v1(100.1,173.19) ; v3(91.92,130.5) 91.78,130.36 91.78,129.99 91.91,129.86 J1.J45
  IN3 w0.109: v1(100.1,173.19) 99.88,172.96 99.88,171.32 97.87,169.31 97.87,165.1 98.4,164.57 98.4,149.86 91.69,143.15 91.69,133.1 92.48,132.31 92.48,131.66 91.81,130.99 91.81,130.6 v3(91.92,130.5)
CSI_6_CLK_P: length 50.5
  TOP w0.102: v3(91.38,130.5) 91.53,130.35 91.53,129.99 91.4,129.86 J1.J44 ; J14.44 99.5,172.11 99.62,172.24 99.62,172.96 v1(99.39,173.19)
  IN3 w0.109: v3(91.38,130.5) 91.54,130.65 91.54,131.1 92.23,131.79 92.23,132.21 91.44,132.99 91.44,143.26 98.15,149.97 98.15,164.46 97.61,164.99 97.61,169.42 99.62,171.43 99.62,172.96 v1(99.39,173.19)
CSI_6_D0_N: length 54.2
  TOP w0.102: v3(90.68,132) 90.8,131.88 90.8,131.51 90.66,131.36 J1.K43 ; v1(98.96,174.8) 98.73,174.57 98.73,173.61 98.38,173.25 98.38,172.27 98.5,172.15 J14.40
  IN3 w0.109: v3(90.68,132) 90.79,132.1 90.79,132.47 90.07,133.2 90.07,142.97 95.4,148.31 95.4,160.27 96.57,161.44 96.57,169.85 97.94,171.22 97.94,173.17 97.28,173.83 97.28,175.18 97.62,175.51 98.5,175.51 98.73,175.28 98.73,175.02 v1(98.96,174.8)
CSI_6_D0_P: length 53.4
  TOP w0.102: v1(98.25,174.8) 98.48,174.57 98.48,173.71 98.12,173.35 98.12,172.26 98,172.14 J14.38 ; J1.K44 91.2,131.36 91.06,131.5 91.06,131.83 v3(91.22,132)
  IN3 w0.109: v1(98.25,174.8) 98.48,175.02 98.48,175.18 98.4,175.26 97.72,175.26 97.54,175.07 97.54,173.94 98.2,173.28 98.2,171.12 96.82,169.74 96.82,161.34 95.66,160.17 95.66,148.21 90.32,142.87 90.32,133.31 91.05,132.58 91.05,132.17 v3(91.22,132)
CSI_6_D1_N: length 57.7
  TOP w0.102: v1(101.96,174.8) 101.73,174.57 101.73,173.61 101.38,173.25 101.38,172.27 101.5,172.15 J14.52 ; J1.H45 92.48,128.36 92.63,128.51 92.63,128.85 v3(92.48,128.99)
  IN3 w0.109: v1(101.96,174.8) 101.73,175.02 101.73,175.21 101.47,175.46 100.58,175.46 100.28,175.16 100.28,173.86 100.94,173.2 100.94,165.84 99.64,164.55 99.64,163.5 99,162.86 99,149.73 92.21,142.94 92.21,133.31 93,132.53 93,130.1 92.62,129.72 92.62,129.13 v3(92.48,128.99)
CSI_6_D1_P: length 56.8
  TOP w0.102: J1.H46 93.01,128.36 92.88,128.49 92.88,128.86 v3(93.02,128.99) ; J14.50 101,172.14 101.12,172.26 101.12,173.35 101.48,173.71 101.48,174.57 v1(101.25,174.8)
  IN3 w0.109: v1(101.25,174.8) 101.48,175.02 101.48,175.1 101.37,175.21 100.69,175.21 100.53,175.05 100.53,173.97 101.19,173.31 101.19,165.74 99.9,164.44 99.9,163.4 99.25,162.75 99.25,149.62 92.46,142.84 92.46,133.42 93.25,132.63 93.25,129.99 92.89,129.63 92.89,129.12 v3(93.02,128.99)
CSI_7_CLK_N: length 77.1
  TOP w0.102: J1.B46 93.01,119.36 92.88,119.49 92.88,119.86 v3(93.02,120) ; J14.68 110.5,172.15 110.38,172.27 110.38,173.14 110.53,173.3 v1(110.6,173.3)
  BOTTOM w0.102: v3(93.02,120) 93.02,119.71 92.88,119.57 92.88,119.39 92.98,119.29 98.9,119.29 99.42,119.81 99.42,120.85 99.93,121.37 99.93,122.19 100.39,122.65 100.39,125.08 100.2,125.27 100.2,126.26 99.19,127.28 99.19,127.89 98.78,128.3 98.78,129.44 98.04,130.18 98.04,138.46 98.78,139.19 98.78,143.21 102.01,146.43 102.01,152.89 108,158.88 108,165.05 106.07,166.98 106.07,169.26 105,170.33 105,172.85 106.19,174.04 110.13,174.04 110.38,173.79 110.38,173.52 v1(110.6,173.3)
CSI_7_CLK_P: length 77.1
  TOP w0.102: v1(109.89,173.3) 109.97,173.3 110.12,173.14 110.12,172.26 110,172.14 J14.66 ; J1.B45 92.5,119.36 92.63,119.49 92.63,119.85 v3(92.48,120)
  BOTTOM w0.102: v1(109.89,173.3) 110.12,173.52 110.12,173.69 110.02,173.79 106.3,173.79 105.26,172.75 105.26,170.43 106.32,169.37 106.32,167.08 108.25,165.15 108.25,158.77 102.26,152.78 102.26,146.33 99.03,143.1 99.03,139.09 98.3,138.35 98.3,130.28 99.03,129.54 99.03,128.4 99.44,127.99 99.44,127.38 100.46,126.37 100.46,125.37 100.65,125.18 100.65,122.54 100.19,122.08 100.19,121.26 99.67,120.74 99.67,119.7 99.01,119.04 92.87,119.04 92.62,119.29 92.62,119.57 92.48,119.71 v3(92.48,120)
CSI_7_D0_N: length 74.6
  TOP w0.102: v3(91.92,118.5) 91.78,118.36 91.78,117.99 91.91,117.86 J1.A45 ; J14.62 v1(106.55,171.12)
  BOTTOM w0.102: v3(91.92,118.5) 91.78,118.36 91.78,118.21 92.22,117.77 99.95,117.77 100.53,118.35 100.53,120.79 100.86,121.12 100.86,121.86 101.75,122.75 101.75,123.38 101.59,123.54 101.59,126.12 100.46,127.25 100.46,127.89 99.57,128.78 99.57,129.92 98.81,130.68 98.81,138.05 100.33,139.57 100.33,143.68 104.14,147.49 104.14,153.94 108.76,158.56 108.76,165.38 106.96,167.18 106.96,170 107.31,170.36 107.31,171.53 107.01,171.83 106.5,171.83 106.32,171.65 106.32,171.35 v1(106.55,171.12)
CSI_7_D0_P: length 76.2
  TOP w0.102: v1(105.84,171.12) J14.60 ; J1.A44 91.4,117.86 91.53,117.99 91.53,118.35 v3(91.38,118.5)
  BOTTOM w0.102: v1(105.84,171.12) 106.07,171.35 106.07,171.76 106.4,172.09 107.12,172.09 107.57,171.63 107.57,170.25 107.21,169.9 107.21,167.29 109.02,165.48 109.02,158.46 104.39,153.84 104.39,147.39 100.58,143.58 100.58,139.47 99.06,137.94 99.06,130.79 99.82,130.03 99.82,128.88 100.71,127.99 100.71,127.36 101.85,126.22 101.85,123.65 102.01,123.49 102.01,122.64 101.12,121.75 101.12,121.02 100.79,120.69 100.79,118.25 100.05,117.52 92.11,117.52 91.52,118.1 91.52,118.36 v3(91.38,118.5)
CSI_7_D1_N: length 78.7
  TOP w0.102: J14.74 112,172.15 111.88,172.27 111.88,173.7 v1(112.1,173.93) ; J1.C48 94.6,120.86 94.48,120.98 94.48,121.36 v3(94.62,121.5)
  BOTTOM w0.102: v3(94.62,121.5) 94.48,121.36 94.48,120.9 94.58,120.79 97.97,120.79 98.37,121.2 98.37,121.71 99.63,122.96 99.63,124.76 99.3,125.09 98.55,125.09 98.16,125.49 98.16,126.79 97.81,127.13 97.81,129.26 97.28,129.79 97.28,132.33 96.67,132.94 96.67,137.36 95.73,138.3 95.73,143.33 101.24,148.84 101.24,153.2 107.24,159.2 107.24,164.69 105.26,166.67 105.26,168.91 104.14,170.02 104.14,173.23 105.92,175.01 111.51,175.01 111.88,174.64 111.88,174.16 v1(112.1,173.93)
CSI_7_D1_P: length 78.7
  TOP w0.102: v3(94.08,121.5) 94.23,121.35 94.23,120.99 94.1,120.86 J1.C47 ; v1(111.39,173.93) 111.62,173.7 111.62,172.24 111.5,172.11 J14.72
  BOTTOM w0.102: v3(94.08,121.5) 94.22,121.36 94.22,120.79 94.47,120.54 98.08,120.54 98.63,121.09 98.63,121.6 99.88,122.86 99.88,124.87 99.4,125.35 98.66,125.35 98.41,125.6 98.41,126.89 98.07,127.23 98.07,129.37 97.54,129.9 97.54,132.44 96.93,133.05 96.93,137.47 95.99,138.41 95.99,143.23 101.5,148.74 101.5,153.1 107.49,159.09 107.49,164.8 105.51,166.78 105.51,169.01 104.39,170.13 104.39,173.12 106.02,174.75 111.4,174.75 111.62,174.54 111.62,174.16 v1(111.39,173.93)
CTS2#: length 2
  TOP w0.107: U25.20 77.37,158.65 v1(77.34,158.62)
  BOTTOM w0.107: v1(77.34,158.62) 78.33,158.62 R174.1
CVB_STBY: length 4.2
  TOP w0.305: RZU9.1 RZU8.2 119.42,133.59 U33.4 118.09,133.1 117.58,132.58 Z8.2
CVM_PRSNT: length 35.2
  TOP w0.107: v1(111.76,150.75) 111.49,151.02 Q4.G ; v1(108.58,136.02) 108.3,135.73 J1.L63
  IN1 w0.124: v1(108.58,136.02) 110.9,136.02 112.67,137.79 112.67,148.95 111.76,149.86 v1(111.76,150.75)
  BOTTOM w0.107: v1(111.76,150.75) 111.76,151.71 RZU38.1 111.86,151.82 R51.2 111.99,153.03 114.2,153.03 114.86,153.7 PSON1.4 PSON1.3
DCD2#: length 2.2
  TOP w0.107: U25.19 77.51,159.04 TP38.1
DIO_INT#: length 18.5
  TOP w0.107: U13.18 v1(140.83,74.68) ; RZU31.1 v1(126.14,70.23)
  IN3 w0.124: v1(126.14,70.23) 128.04,70.23 129.31,71.5 132.99,71.5 135.53,74.04 140.36,74.04 140.83,74.51 v1(140.83,74.68)
DIO_SCL: length 9.8
  TOP w0.107: U13.44 129.22,68.3 126.64,70.87 126.64,72.52 126.39,72.77 125.37,72.77 125.25,72.9 U14.12
DIO_SDA: length 9.1
  TOP w0.107: U14.13 126.67,73.46 127.03,73.1 127.03,71.03 129.26,68.8 U13.43
DM: length 3.4
  TOP w0.102: U25.37 81.28,152 81.36,151.92 81.36,151.46 82.11,150.71 82.11,150.03 RZ9.1
DP: length 3.4
  TOP w0.102: RZ10.1 82.36,150.03 82.36,150.81 81.61,151.56 81.61,151.92 81.68,151.98 U25.38
DP2_AUX_CH_N_I2C6_DAT: length 42.8
  TOP w0.107: v1(99.95,127.51) 100.2,127.26 J1.G54 ; v1(99.97,88.65) 99.86,88.53 U66.47
  IN3 w0.124: v1(99.97,88.65) 102.28,90.95 102.28,103.38 100.2,105.46 100.2,114.5 100.67,114.97 100.67,120.88 100.2,121.35 100.2,127.26 v1(99.95,127.51)
DP2_AUX_CH_P_I2C6_CLK: length 41.2
  TOP w0.107: v1(99.97,89.28) 99.85,89.28 99.5,88.93 U66.48 ; J1.G53 98.83,126.39 v1(98.83,126.11)
  IN3 w0.124: v1(98.83,126.11) 98.77,126.05 98.77,123.89 99.77,122.89 99.77,121.16 100.24,120.69 100.24,115.15 99.77,114.68 99.77,105.28 101.85,103.2 101.85,91.25 99.97,89.37 v1(99.97,89.28)
DP2_HPD_CH0_HPD: length 60.8
  TOP w0.107: J1.K50 v1(96.8,132.02)
  IN3 w0.124: v1(94.36,98.81) 94.36,99.14 93.6,99.9 93.6,106.4 93.17,106.83 93.17,116.81 93.97,117.61 93.97,118.76 95.61,120.4 95.61,121.76 96.65,122.81 96.65,124.44 97.69,125.48 97.69,131.13 v1(96.8,132.02)
  BOTTOM w0.107: RZU45.1 R540.1 105.44,87.76 Q55.D 106.07,88.93 105.54,89.46 R541.2 105.54,96.42 103.91,98.04 94.82,98.04 94.36,98.5 v1(94.36,98.81)
DPE_CLKN0: length 8
  TOP w0.114: RZ87.1 41.31,66.48 44.77,66.48 44.92,66.33 48.12,66.33 48.2,66.26 U70.75
DPE_CLKN1: length 4.5
  TOP w0.114: RZ93.1 44.87,65.21 45.66,65.21 45.97,65.53 48.08,65.53 48.16,65.46 U70.77
DPE_CLKN2: length 8.3
  TOP w0.114: RZ94.1 41.31,63.94 45.66,63.94 46.44,64.73 48.12,64.73 48.2,64.66 U70.79
DPE_CLKP0: length 8
  TOP w0.114: U70.74 48.19,66.66 48.12,66.58 45.03,66.58 44.87,66.74 41.31,66.74 RZ84.1
DPE_CLKP1: length 4.5
  TOP w0.114: RZ88.1 44.87,65.47 45.55,65.47 45.87,65.78 48.13,65.78 48.2,65.86 U70.76
DPE_CLKP2: length 8.3
  TOP w0.114: U70.78 48.22,65.06 48.14,64.98 46.34,64.98 45.55,64.2 41.31,64.2 RZ92.1
DPE_CLKREQN0: length 4.7
  TOP w0.107: R625.2 51.1,74.62 51.1,71.61 51.76,70.95 U70.60
DPE_CLKREQN1: length 7.1
  TOP w0.107: U70.61 51.36,70.97 50.71,71.61 50.71,74.19 50.58,74.33 50.58,76.89 R626.2
DPE_CLKREQN2: length 4.8
  TOP w0.107: R627.2 49.99,74.37 50.33,74.03 50.33,71.58 50.96,70.95 U70.62
DPE_CLKREQN3: length 7.3
  TOP w0.107: 49.35,77.06 R628.2 49.35,71.47 49.69,71.13 49.8,71.13 50.16,70.77 U70.64
DPE_RSTN_R: length 2.7
  BOTTOM w0.107: U67.A3 52.8,104.98 51.23,104.98 RZ182.2
DPE_RXN0: length 7.7
  TOP w0.114: U70.21 57.36,59.85 57.29,59.78 57.29,53.31 RZ107.1
DPE_RXN1: length 4.7
  TOP w0.114: RZ102.1 53.65,56.31 53.65,59.24 53.69,59.27 53.69,59.78 53.76,59.85 U70.12
DPE_RXN6: length 8
  TOP w0.114: RZ97.1 41.31,61.53 48.1,61.53 48.17,61.46 U70.87
DPE_RXP0: length 7.7
  TOP w0.114: U70.20 56.96,59.86 57.03,59.78 57.03,53.2 RZ106.1
DPE_RXP1: length 4.7
  TOP w0.114: U70.11 53.36,59.85 53.43,59.78 53.43,59.38 53.4,59.34 53.4,56.29 RZ101.1
DPE_RXP6: length 8
  TOP w0.114: U70.86 48.17,61.86 48.09,61.78 41.32,61.78 RZ96.1
DPE_TXN0: length 4.7
  TOP w0.114: U70.18 56.16,59.85 56.09,59.78 56.09,56.27 CM61.1
DPE_TXN1: length 7.7
  TOP w0.114: U70.15 54.96,59.85 54.89,59.78 54.89,53.15 CM63.1
DPE_TXN6: length 4.4
  TOP w0.114: U70.84 47.88,62.66 47.8,62.73 44.78,62.73 CM59.1
DPE_TXP0: length 4.6
  TOP w0.114: CM60.1 55.83,56.17 55.83,59.78 55.76,59.86 U70.17
DPE_TXP1: length 7.7
  TOP w0.114: U70.14 54.56,59.86 54.63,59.78 54.63,53.2 CM62.1
DPE_TXP6: length 4.4
  TOP w0.114: CM58.1 44.8,62.98 47.8,62.98 47.88,63.06 U70.83
DSR2#: length 2.1
  TOP w0.107: U25.32 v1(79.3,153.85)
  BOTTOM w0.107: R172.1 78.71,153.97 78.84,153.85 v1(79.3,153.85)
DSR4#: length 1.9
  TOP w0.107: U25.55 v1(85.93,156.25)
  BOTTOM w0.107: v1(85.93,156.25) 85.18,156.25 R175.1
DTR2: length 5.2
  TOP w0.107: U25.29 77.57,155.04 76.32,153.8 75.31,153.8 74.42,152.91 TP37.1
E_TX0N_A: length 3.1
  TOP w0.089: R522.1 94.16,79.78 94.16,80.16 94.75,80.76 94.75,81.65 94.69,81.71 U66.23
E_TX0N_R_A: length 1.8
  TOP w0.089: R522.2 94.16,77.95 94.16,77.03 CB23.2
E_TX0P_A: length 3.1
  TOP w0.089: U66.24 95.09,81.71 95.03,81.65 95.03,80.64 94.44,80.05 94.44,79.78 R521.1
E_TX0P_R_A: length 1.8
  TOP w0.089: CB24.2 94.44,77.03 94.44,77.95 R521.2
E_TX1N_A: length 3.1
  TOP w0.089: R520.1 96.44,79.78 96.44,80.1 95.95,80.59 95.95,81.62 95.89,81.68 U66.26
E_TX1N_R_A: length 1.8
  TOP w0.089: CB25.2 96.44,77.03 96.44,77.95 R520.2
E_TX1P_A: length 3.1
  TOP w0.089: R518.1 96.72,79.78 96.72,80.21 96.23,80.71 96.23,81.6 96.29,81.66 U66.27
E_TX1P_R_A: length 1.8
  TOP w0.089: R518.2 96.72,77.95 96.72,77.03 CB26.2
E_TX2N_A: length 3.8
  TOP w0.089: R517.1 98.7,79.76 98.7,79.87 98.46,80.11 97.95,80.11 97.16,80.91 97.16,81.64 97.09,81.7 U66.29
E_TX2N_R_A: length 1.8
  TOP w0.089: R517.2 98.73,77.95 98.73,77.03 CB27.2
E_TX2P_A: length 3.8
  TOP w0.089: R516.1 98.98,79.78 98.98,79.98 98.58,80.39 98.07,80.39 97.43,81.03 97.43,81.66 97.49,81.72 U66.30
E_TX2P_R_A: length 1.8
  TOP w0.089: R516.2 99.01,78.02 99.01,77.03 CB28.2
E_TXCN_A: length 4.2
  TOP w0.089: U66.20 93.49,81.72 93.57,81.64 93.57,80.86 93.23,80.52 92.23,80.52 91.9,80.19 91.9,79.81 R524.1
E_TXCN_R_A: length 1.8
  TOP w0.089: R524.2 91.87,77.95 91.87,77.03 CB21.2
E_TXCP_A: length 4.2
  TOP w0.089: U66.21 93.89,81.67 93.85,81.64 93.85,80.75 93.34,80.24 92.34,80.24 92.18,80.07 92.18,79.76 R523.1
E_TXCP_R_A: length 1.8
  TOP w0.089: CB22.2 92.15,77.03 92.15,77.95 R523.2
EEPROM_A0: length 7
  TOP w0.107: U15.1 40.05,113.71 TP23.1 RB26.1 39.47,112.12 39.19,111.84 39.19,109.93 39.42,109.7 R98.2
EEPROM_A1: length 6.9
  TOP w0.107: RB27.2 40.82,109.7 40.59,109.93 40.59,111.84 40.87,112.12 R101.1 TP22.1 41.32,113.58 U15.2
EEPROM_A2: length 7.3
  TOP w0.107: RB28.2 42.27,109.65 42.11,109.8 42.11,111.84 42.34,112.06 R100.1 42.88,113.46 TP20.1 42.59,113.75 U15.3
EFM8_ACOK: length 3.3
  TOP w0.107: U6.16 128.73,156.32 R31.1 RZ6.1
EFM8_D_ONKEY_N: length 2.5
  TOP w0.107: TP13.1 131.03,154.97 v1(131.03,155.45) U6.19
  BOTTOM w0.107: RB63.2 v1(131.03,155.45)
EFM8_FORCE_SHUTDOWN: length 136.4
  TOP w0.107: U11.4 109.86,158.59 R48.2 v1(110.49,158.75) ; U6.14 v1(128.65,157.32)
  IN3 w0.124: v1(151.16,76.83) 153.16,78.84 153.16,96.16 151.84,97.48 151.84,102.92 149.23,105.53 149.23,106.8 143.89,112.14 140.94,112.14 136.72,116.36 136.72,119.16 132.99,122.89 132.99,125.35 129.95,128.4 129.95,131.64 128.27,133.32 128.27,139.57 128.91,140.21 128.91,157.07 v1(128.65,157.32)
  BOTTOM w0.107: v1(110.49,158.75) 110.49,160.78 111.45,161.74 127.13,161.74 127.89,160.98 127.89,157.73 128.3,157.32 v1(128.65,157.32) ; RZ204.1 145.19,67.31 145.69,67.82 145.69,74.68 147.85,76.83 v1(151.16,76.83)
EFM8_MODULE_POWER_ON: length 6.9
  TOP w0.107: RB5.1 132.25,164.32 U7.4 130.66,163.86 RZU3.2 130.66,162.53 130.53,162.41 U6.9
EFM8_P0_4: length 2.8
  TOP w0.107: U6.18 130.53,155.45 130.3,155.22 TP14.1
EFM8_PSHOLD: length 1.6
  TOP w0.107: RZ5.1 127.97,156.82 U6.15
EFM8_RST_MON: length 127.3
  TOP w0.107: U6.13 127.9,157.82 RB11.2 127.86,157.58 127.64,157.35 124.66,157.35 Q2.6 124.19,157.37 123.95,157.61 v1(123.83,157.61) ; v1(115.09,91.43) U19.1 113.56,91.42 113.56,90.93 113.44,90.81 113.18,90.81 113.06,90.93 U19.2
  IN1 w0.124: v1(115.09,91.43) 115.47,91.05 115.47,85.34 114.83,84.71 114.83,81.28 115.3,80.81 115.3,73.95 117.01,72.24 128.65,72.24 130.58,74.17 134.26,74.17 135.28,73.15 v1(139.83,73.15)
  IN3 w0.124: v1(123.83,157.61) 124.33,157.1 124.33,152.27 125.22,151.39 125.22,149.03 125.22,141.79 124.73,141.3 124.73,134.64 122.95,132.86 122.95,125.48 119.86,122.39 119.86,118.87 119.27,118.28 119.27,114.55 118.16,113.45 118.16,106.15 115.9,103.89 115.25,103.89 113.35,101.98 113.35,97.91 114.09,97.18 114.09,92.43 v1(115.09,91.43)
  BOTTOM w0.107: RZ201.1 v1(139.83,73.15)
EFM8SB10_C2CK: length 42.5
  TOP w0.107: MCUCON1.2 156.59,162.69 156.08,163.19 156.08,166.2 151.35,170.94 136.27,170.94 134.62,169.29 134.62,158.85 RB10.2 134.65,158.37 TP16.1 133.56,158.32 U6.5
EFM8SB10_C2D: length 38.7
  TOP w0.107: U6.6 132.05,159.1 132.72,159.77 TP15.1 134.23,160.4 134.23,169.45 136.11,171.33 151.51,171.33 MCUCON1.1
ETH_WOL_EN_N: length 14.2
  BOTTOM w0.107: Q58.G 145.12,173.37 Z17.2 R1475.1 148.23,173.2 149.73,171.7 WOL1.1
ETH_WOL_EN_STATUS: length 89
  TOP w0.107: v3(94.36,118.49) 94.36,118.32 J1.A47
  IN3 w0.124: v1(113.41,163.19) 112.83,163.19 111.86,162.23 110.8,162.23 105.15,156.58 105.15,149.89 104.81,149.54 104.81,147.78 104.45,147.42 104.45,138.74 102.53,136.82 101.59,136.82 97.94,133.18 97.94,125.37 96.9,124.33 96.9,122.7 95.86,121.66 95.86,120.29 94.36,118.8 v3(94.36,118.49)
  BOTTOM w0.107: v1(113.41,163.19) 113.41,162.79 113.67,162.54 117.76,162.54 120.83,165.61 129.29,165.61 133.22,169.54 138.3,169.54 140.31,171.55 R1476.1 Q58.D
F1: length 73.8
  TOP w0.203: U13.42 133.68,69.3 v1(133.76,69.22)
  IN1 w0.203: v1(133.76,69.22) 133.76,68.2 135.03,66.93 137.14,66.93 138.56,65.52 138.56,58.69 137.11,57.25 137.11,54.24 135.61,52.74 135.61,39.61 140.92,34.3 140.92,30.62 142.19,29.35 142.19,27.01 143,25.05 143,22.95 145.68,20.27 147.08,20.27 149.38,17.97 149.38,16.26 149.58,16.05 v1(149.94,16.05)
  BOTTOM w0.203: TP18.3 154.29,14.39 153.87,14.81 151.71,14.81 150.6,15.93 Z4.2 v1(149.94,16.05) ; R1498.1 v1(133.76,69.22)
F2: length 81
  TOP w0.254: U13.30 v1(134.83,74.55)
  IN1 w0.203: v1(151.23,16.05) 150.72,16.05 150.52,16.26 150.52,17.29 147.21,20.6 145.82,20.6 143.33,23.08 143.33,25.12 142.52,27.08 142.52,29.48 141.25,30.75 141.25,34.44 137.31,38.37 137.31,41.61 135.94,42.98 135.94,52.6 137.44,54.1 137.44,57.11 138.89,58.56 138.89,65.84 140.61,67.56 140.61,73.66 140.36,73.91 135.46,73.91 v1(134.83,74.55)
  BOTTOM w0.203: v1(151.23,16.05) Z3.2 151.87,15.67 152.35,15.19 154.13,15.19 154.79,14.52 TP18.2
  BOTTOM w0.254: v1(134.83,74.55) 134.9,74.62 R1499.1
F3: length 77.4
  TOP w0.203: U13.39 133.32,70.8 v1(133.76,70.36)
  IN1 w0.203: v1(133.76,70.36) 133.25,69.85 133.25,68.2 134.9,66.55 137.06,66.55 138.23,65.38 138.23,58.83 136.78,57.39 136.78,56.07 135.53,54.82 135.53,53.13 135.28,52.87 135.28,39.47 140.59,34.16 140.59,30.48 141.86,29.21 141.86,26.95 142.67,24.98 142.67,22.81 145.54,19.94 146.94,19.94 149.05,17.83 149.05,16.12 149.67,15.49 151.92,15.49 v1(152.48,16.05)
  BOTTOM w0.203: v1(152.48,16.05) Z2.2 153.49,15.7 154.25,15.7 155.29,14.66 TP18.1 ; R1500.1 v1(133.76,70.36)
FC_PWR_OFF: length 3.7
  BOTTOM w0.107: NGFF1.6 146.54,176.92 R212.1 R210.1
FORCE_RECOVERY_N: length 12.3
  TOP w0.107: J1.L10 57.8,135.49 56.95,136.35 51.74,136.35 49.66,138.43 RZ19.2
FORCE_RECOVERY_N_CON: length 122.8
  TOP w0.107: RZ11.1 52.45,140.72 52.83,141.1 63,141.1 66.29,144.38 112.72,144.38 116.51,140.59 122.31,140.59 123.44,141.73 133.1,141.73 134.7,140.13 134.7,137.87 135.64,136.93 147.42,136.93 148.18,136.17 v1(150.88,136.17)
  BOTTOM w0.107: v1(150.88,136.17) RB64.2 151.65,136.18 CA135.1 154.43,134.53 154.43,127.76 155.33,126.86 RECOVERY1.3
FORCE_RECOVERY_N_KEY: length 15.9
  TOP w0.107: RZU6.1 RZ11.2 ; RZU6.1 Z12.2 46.96,138.44 C135.1 46.95,136.19 v1(44.83,134.07) ; RZU6.1 RZ19.1
  BOTTOM w0.107: v1(44.83,134.07) PSON3.1 PSON3.2
HDMI_DP0_TX0_N: length 39.9
  TOP w0.089: J1.D52 98.41,122.36 98.3,122.47 98.3,122.88 v3(98.42,123) ; U66.51 97.49,90.18 97.56,90.25 97.56,90.55 98.35,91.34 99.07,91.34 99.16,91.43 99.16,92.14 v1(98.95,92.36)
  IN3 w0.094: v3(98.42,123) 98.29,122.87 98.29,122.27 98.55,122.01 98.55,121.35 99.62,120.28 99.62,119.52 99.29,119.19 99.29,114.89 98.79,114.39 98.79,101.9 99.29,101.4 99.29,95.67 100.84,94.12 100.84,92.3 100.1,91.57 99.42,91.57 99.16,91.82 99.16,92.14 v1(98.95,92.36)
HDMI_DP0_TX0_P: length 38.9
  TOP w0.089: v3(97.88,123) 98.02,122.86 98.02,122.47 97.91,122.36 J1.D51 ; v1(99.66,92.36) 99.44,92.14 99.44,91.31 99.19,91.06 98.46,91.06 97.84,90.44 97.84,90.25 97.89,90.19 U66.50
  IN3 w0.094: v1(99.66,92.36) 99.44,92.14 99.44,91.94 99.53,91.85 99.99,91.85 100.56,92.42 100.56,94.01 99.01,95.56 99.01,101.28 98.51,101.78 98.51,114.51 99.01,115.01 99.01,119.3 99.34,119.63 99.34,120.17 98.27,121.24 98.27,121.9 98.01,122.16 98.01,122.87 v3(97.88,123)
HDMI_DP0_TX1_N: length 35.7
  TOP w0.089: U66.54 96.29,90.18 96.35,90.24 96.35,90.91 97.1,91.66 97.1,92.14 v1(96.89,92.36) ; J1.B52 98.5,119.36 98.3,119.56 98.3,119.88 v3(98.42,120)
  IN3 w0.094: v3(98.42,120) 98.29,119.87 98.29,118.98 98.51,118.77 98.51,115.34 97.97,114.8 97.97,101.62 98.51,101.08 98.51,91.44 98.19,91.13 97.36,91.13 97.1,91.39 97.1,92.14 v1(96.89,92.36)
HDMI_DP0_TX1_P: length 34.8
  TOP w0.089: v1(97.6,92.36) 97.38,92.14 97.38,91.54 96.63,90.79 96.63,90.24 96.69,90.18 U66.53 ; J1.B51 97.83,119.36 98.02,119.55 98.02,119.86 v3(97.88,120)
  IN3 w0.094: v1(97.6,92.36) 97.38,92.14 97.38,91.5 97.48,91.41 98.08,91.41 98.23,91.56 98.23,100.96 97.69,101.5 97.69,114.92 98.23,115.46 98.23,118.65 98.01,118.87 98.01,119.87 v3(97.88,120)
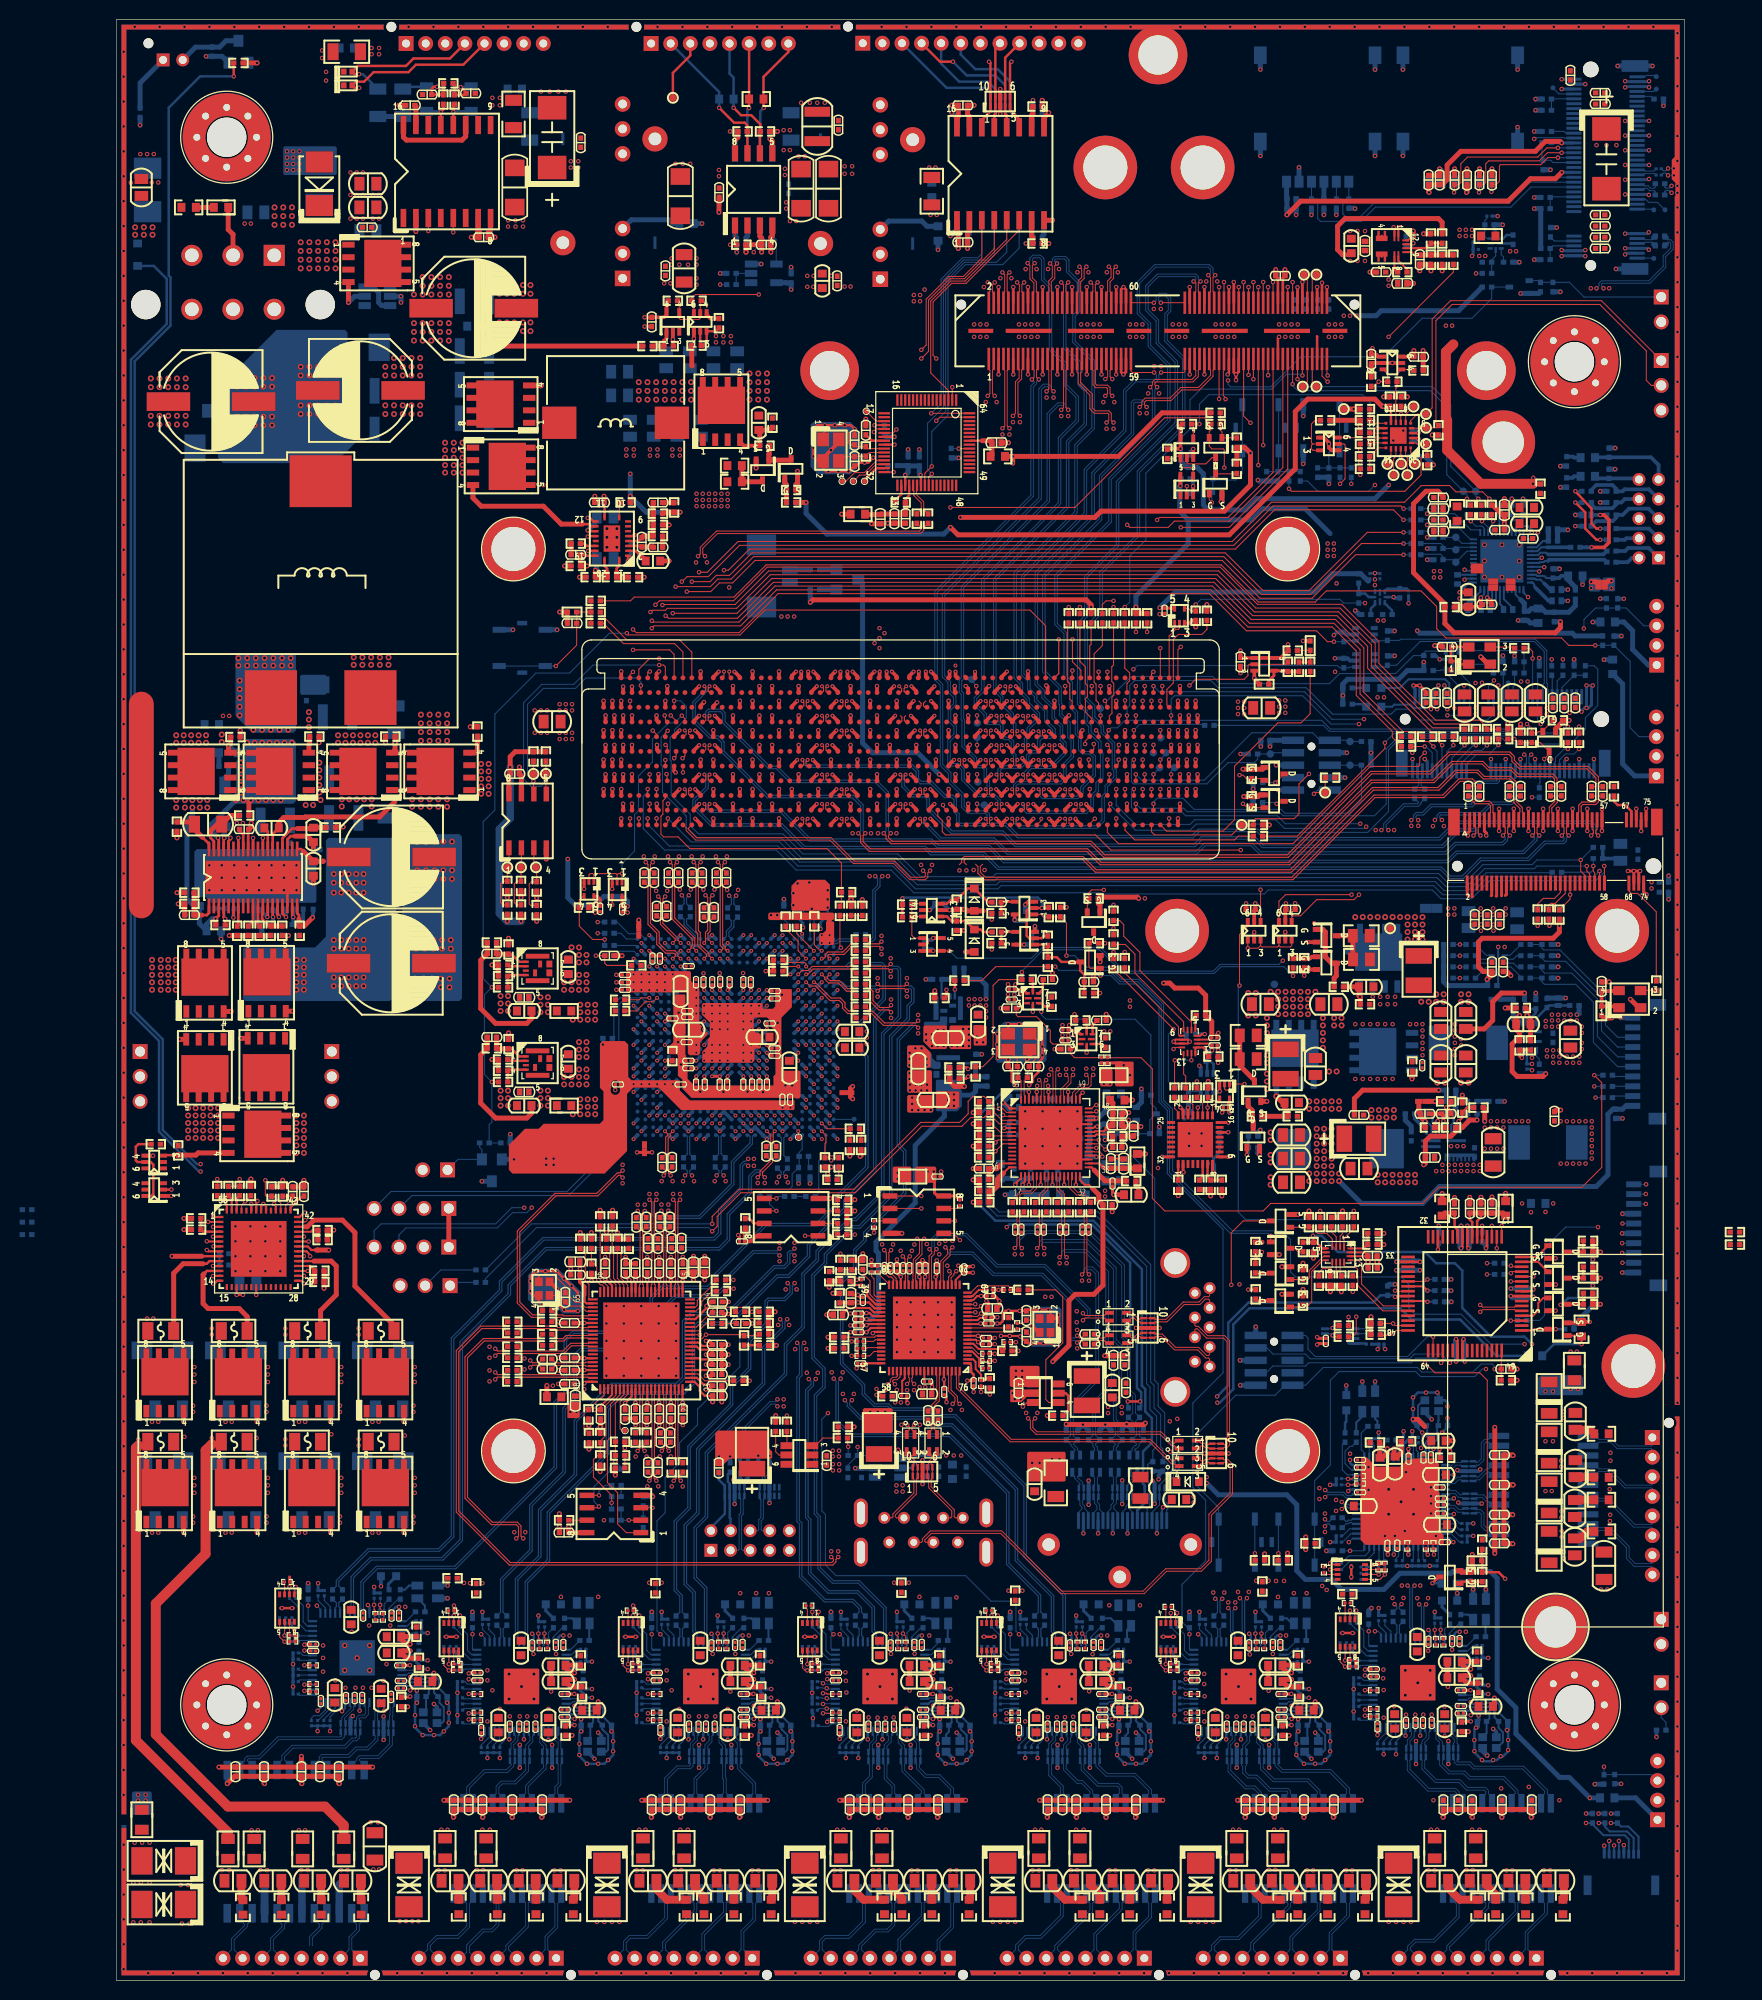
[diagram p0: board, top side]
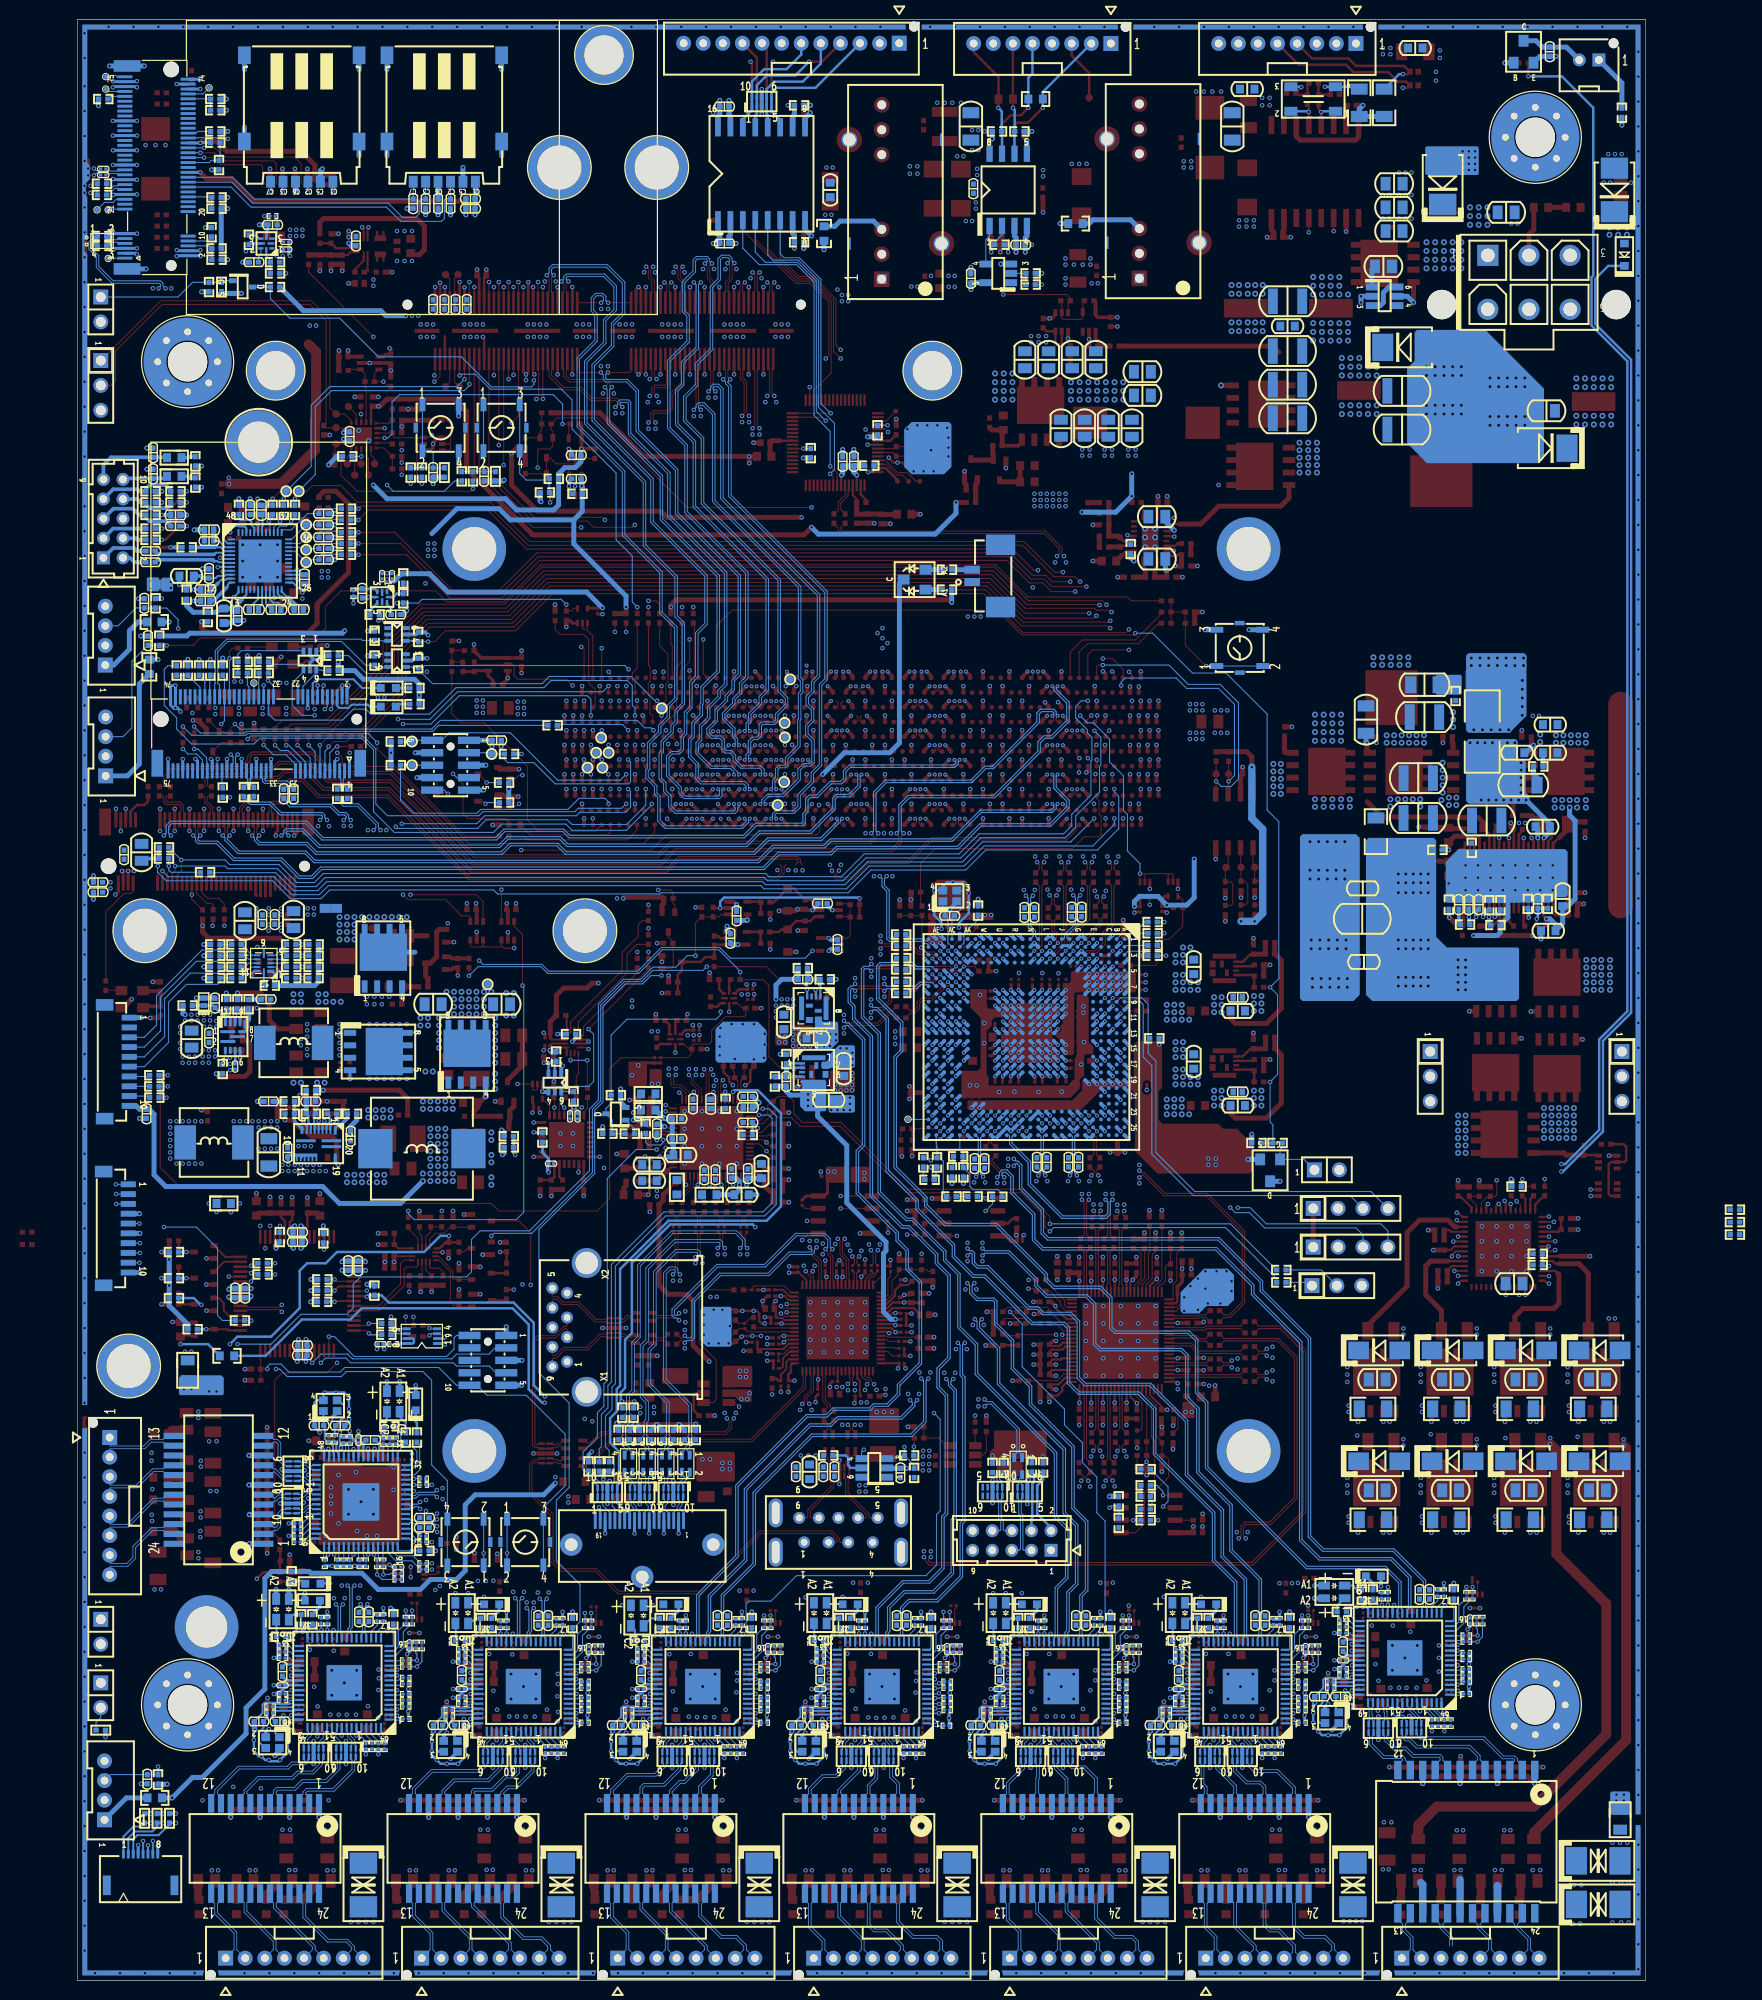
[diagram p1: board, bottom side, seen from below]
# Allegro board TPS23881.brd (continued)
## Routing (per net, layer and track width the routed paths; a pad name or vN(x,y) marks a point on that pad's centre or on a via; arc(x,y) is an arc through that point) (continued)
HDMI_DP0_TX2_N: length 31.4
  TOP w0.089: J1.A50 96.75,117.86 96.9,118.01 96.9,118.38 v3(96.78,118.5) ; U66.56 95.49,90.17 95.55,90.23 95.55,92.72 v1(95.34,92.94)
  IN3 w0.094: v3(96.78,118.5) 96.91,118.37 96.91,117.68 95.55,116.32 95.55,104.37 96.39,103.53 96.39,99.77 95.83,99.2 95.83,95.49 96.22,95.1 96.22,94.07 95.55,93.41 95.55,93.15 v1(95.34,92.94)
HDMI_DP0_TX2_P: length 31.4
  TOP w0.089: v3(97.32,118.5) 97.18,118.36 97.18,118.01 97.33,117.86 J1.A51 ; v1(96.05,92.94) 95.83,92.72 95.83,90.22 95.89,90.16 U66.55
  IN3 w0.094: v1(96.05,92.94) 95.83,93.15 95.83,93.29 96.49,93.95 96.49,95.21 96.11,95.6 96.11,99.09 96.67,99.66 96.67,103.65 95.83,104.48 95.83,116.21 97.19,117.56 97.19,118.37 v3(97.32,118.5)
HDMI_DP0_TX3_N: length 35
  TOP w0.089: J1.C50 96.74,120.86 96.9,121.02 96.9,121.38 v3(96.78,121.5) ; U66.59 94.29,90.17 94.35,90.23 94.35,91.61 v1(94.14,91.83)
  IN3 w0.094: v1(94.14,91.83) 94.35,92.04 94.35,93.38 95.05,94.08 95.05,99.18 94.22,100.01 94.22,107.87 93.68,108.4 93.68,116.01 95.58,117.91 95.58,119.29 96.91,120.62 96.91,121.37 v3(96.78,121.5)
HDMI_DP0_TX3_P: length 35
  TOP w0.089: J1.C51 97.34,120.86 97.18,121.02 97.18,121.36 v3(97.32,121.5) ; U66.58 94.69,90.12 94.63,90.18 94.63,91.61 v1(94.85,91.83)
  IN3 w0.094: v1(94.85,91.83) 94.63,92.04 94.63,93.27 95.33,93.96 95.33,99.3 94.5,100.13 94.5,107.98 93.96,108.52 93.96,115.89 95.86,117.79 95.86,119.17 97.19,120.5 97.19,121.37 v3(97.32,121.5)
HMCU_SCL_A: length 2.8
  TOP w0.107: U66.7 90.83,86.53 90.78,86.49 90.2,86.49 89.31,87.38 R535.2
HMCU_SDA_A: length 2.4
  TOP w0.107: U66.8 89.56,86.13 89.46,86.23 R536.2
HPO_L: length 1.5
  BOTTOM w0.381: FB41.1 148.72,155.32 148.62,155.42 RZ686.2
HPO_R: length 1.5
  BOTTOM w0.381: FB40.2 148.72,153.42 148.56,153.26 RZ685.2
HUB_RESET#: length 7.8
  TOP w0.107: U20.41 77.49,69.35 76.88,69.96 76.88,71.35 76.28,71.96 76.28,72.38 C60.1 75.02,72.5 R164.2 RZ76.1 73.38,72.49 73.2,72.31 R162.1
HUB_XTAL1: length 9.6
  TOP w0.107: U20.9 91.56,66.15 R159.2 92.48,66.48 C58.1 93.49,65.48 95.07,65.48 95.29,65.7 X1.1 95.29,66.23
HUB_XTAL2: length 4.2
  TOP w0.107: U20.10 90.91,66.55 RZ82.2
HUB_XTAL2_R: length 3.6
  TOP w0.107: X1.3 94.04,67.35 C57.1 92.51,67.02 R159.1 91.3,67.61 RZ82.1
I2C_GP1_CLK: length 25.4
  TOP w0.107: U15.6 42.55,121.06 v1(42.55,122.3) TP21.1 R92.2 ; J1.K5 v1(53.5,132.08)
  BOTTOM w0.107: v1(42.55,122.3) 41.94,122.91 41.94,130.15 43.57,131.78 46.83,131.78 47.89,132.84 53.09,132.84 53.5,132.43 v1(53.5,132.08)
I2C_GP1_DAT: length 31.2
  TOP w0.107: J1.L8 56,133.99 55.83,134.16 v1(55.37,134.16) ; R93.2 TP19.1 v1(43.81,122.3) 43.81,121.06 U15.5
  BOTTOM w0.107: v1(55.37,134.16) 48.63,134.16 46.66,132.19 43.4,132.19 41.53,130.32 41.53,122.56 42.29,121.79 43.31,121.79 v1(43.81,122.3)
I2C_GP2_CLK: length 164.3
  TOP w0.107: RZ91.1 126.11,65.66 126.49,66.04 v1(126.49,67.69) ; J14.87 v1(115.5,163.76) ; RZU22.2 v1(145,107.57) ; J1.J61 v1(106.5,130.52)
  IN1 w0.124: v1(128.66,130.87) 127.89,131.65 122.66,131.65 122.04,131.04 107.02,131.04 v1(106.5,130.52)
  IN3 w0.124: v1(115.5,163.76) 115.44,163.7 115.44,161.57 113.77,159.89 110.9,159.89 107.08,156.07 107.08,147.44 107.37,147.15 107.37,139.09 106.49,138.21 106.49,136.84 106.08,136.43 106.08,134.05 106.27,133.86 106.27,130.75 v1(106.5,130.52) ; v1(126.49,67.69) 127.39,68.59 134.04,68.59 134.52,69.08 134.52,72.21 135.92,73.61 140.66,73.61 142.52,75.47 145.75,75.47 151.84,81.56 151.84,95.91 150.73,97.02 150.73,102.46 148.12,105.07 148.12,106.22 147.71,106.63 145.94,106.63 v1(145,107.57) 145,109.38 143.6,110.77 137.38,110.77 133.8,114.35 133.8,120.19 130.79,123.2 130.79,126.34 128.66,128.47 v1(128.66,130.87)
I2C_GP2_CLK_3V3: length 130.8
  TOP w0.107: U13.48 130.56,66.3 v1(130.25,65.99) 130.05,65.79 129.03,65.79 RB57.1 ; RZU32.2 v1(62.94,71.45)
  IN1 w0.124: v1(130.25,65.99) 127.33,65.99 120.14,58.8 114.83,58.8 112.88,56.85 107.64,56.85 v1(107.47,57.02)
  IN3 w0.124: v1(49.1,106.81) 49.1,106.06 49.91,105.25 49.91,100.71 50.62,100 50.62,93.17 50.04,92.58 50.04,80.8 51.97,78.86 51.97,78.01 54.9,75.08 60.3,75.08 62.94,72.44 v1(62.94,71.45) 63.7,70.69 63.7,67.01 71.53,59.18 73.15,59.18 74.42,57.91 75.57,57.91 77.47,56.01 105.24,56.01 106.26,57.02 v1(107.47,57.02)
  BOTTOM w0.107: v1(130.25,65.99) 130.12,65.86 RB57.1 ; RZU44.2 v1(49.1,106.81)
I2C_GP2_DAT: length 159.6
  TOP w0.107: RZU23.2 146.14,107.63 v1(146.2,107.57) ; J14.89 v1(116,163.32) ; J1.K61 v1(106.7,132.02) ; RZ86.1 v1(125.7,67.67)
  IN1 w0.124: v1(106.7,132.02) 107.22,132.54 109.86,132.54 110.92,131.47 121.87,131.47 122.48,132.08 128.12,132.08 v1(129.32,130.87)
  IN3 w0.124: v1(116,163.32) 116,161.51 107.51,153.02 107.51,147.62 107.8,147.32 107.8,138.91 106.92,138.03 106.92,132.7 106.7,132.48 v1(106.7,132.02) ; v1(129.32,130.87) 129.32,128.41 131.22,126.51 131.22,123.7 136.04,118.88 136.04,116.08 140.66,111.46 141.65,111.46 143.61,111.46 146.2,108.87 v1(146.2,107.57) 146.71,107.06 147.89,107.06 148.55,106.4 148.55,105.25 151.16,102.64 151.16,97.2 152.27,96.09 152.27,81.38 145.93,75.04 142.7,75.04 140.32,72.66 135.57,72.66 134.95,72.03 134.95,68.9 134.21,68.16 127.73,68.16 126.75,67.18 126.19,67.18 v1(125.7,67.67)
I2C_GP2_DAT_3V3: length 133.4
  TOP w0.107: RB56.1 v1(130.25,67.01) 130.46,66.8 U13.47 ; v1(62.97,70.56) 62.41,70.56 RZU33.2
  IN1 w0.124: v1(108.23,57.28) 112.7,57.28 114.66,59.23 119.96,59.23 127.28,66.55 129.79,66.55 v1(130.25,67.01)
  IN3 w0.124: v1(108.23,57.28) 108.23,57.15 107.42,56.34 106.18,56.34 105.42,55.58 86.94,55.58 77.29,55.58 75.39,57.48 74.24,57.48 72.97,58.75 71.35,58.75 63.27,66.83 63.27,70.33 63.05,70.56 v1(62.97,70.56) 62.46,71.07 62.46,72.32 60.12,74.66 54.72,74.66 51.54,77.83 51.54,78.68 49.61,80.62 49.61,92.76 50.19,93.34 50.19,99.82 49.48,100.53 49.48,105.07 48.54,106.01 48.54,107.39 v1(49.1,107.95)
  BOTTOM w0.107: RB56.1 v1(130.25,67.01) ; RZU43.2 v1(49.1,107.95)
I2C_GP3_CLK: length 48.8
  TOP w0.107: J14.75 v1(112.5,161.31) ; J1.F53 99.72,125.58 v1(99.72,126.11) ; R242.1 v1(105.16,137.54)
  IN3 w0.124: v1(112.5,161.31) 111.1,161.31 106.01,156.22 106.01,149.53 105.66,149.18 105.66,147.42 105.31,147.07 105.31,137.7 v1(105.16,137.54) 103.38,135.76 101.74,135.76 98.93,132.95 98.93,130.53 99.49,129.97 99.49,127.12 99.74,126.87 99.74,126.14 v1(99.72,126.11)
I2C_GP3_DAT: length 51.8
  TOP w0.107: R243.1 v1(104.01,137.54) ; v1(99.2,124.52) 99.2,123.96 J1.E53 ; J14.77 113,164.2 112.93,164.13 112.93,161.65 113.16,161.42 v1(113.16,161.29)
  IN3 w0.124: v1(113.16,161.29) 113.16,161.54 112.9,161.8 110.98,161.8 105.58,156.4 105.58,149.71 105.23,149.36 105.23,147.6 104.88,147.24 104.88,138.41 v1(104.01,137.54) 102.87,136.4 101.77,136.4 98.5,133.13 98.5,130.35 99.06,129.79 99.06,126.75 99.3,126.51 99.3,124.62 v1(99.2,124.52)
I2C_GP9_CLK: length 116.4
  TOP w0.107: v1(99.82,118.49) 99.3,117.97 J1.A53 ; J14.105 v1(120,162.81)
  IN1 w0.124: v1(99.82,118.49) 100.74,117.57 112.64,117.57 113.6,118.53 122.41,118.53 125.36,121.48 134.3,121.48 136.4,123.57 137.67,123.57 139.19,125.09 142.6,125.09 144.85,127.35 144.85,132.03 v1(147.57,134.75)
  IN3 w0.124: v1(147.57,134.75) 147.57,135.04 145.15,137.46 137.14,137.46 135.96,138.63 135.96,149.3 v1(137.79,151.13)
  BOTTOM w0.107: RZU40.2 v1(147.57,134.75) ; RZ158.1 v1(137.79,151.13) 137.79,151.51 TP29.1 135.73,153.58 135.73,160.49 134.06,162.15 120.51,162.15 120,162.67 v1(120,162.81)
I2C_GP9_DAT: length 119.7
  TOP w0.107: J1.C53 v1(99.3,121.52) ; J14.107 v1(120.5,163.32)
  IN1 w0.124: v1(146.43,134.75) 146.43,134.47 144.42,132.46 144.42,127.53 142.42,125.52 139.01,125.52 137.49,124 136.22,124 134.12,121.9 125.18,121.9 122.24,118.96 113.42,118.96 112.47,118.01 100.91,118.01 100.33,118.59 100.33,120.49 v1(99.3,121.52)
  IN3 w0.124: v1(146.43,134.75) 145.92,135.25 145.92,136.08 144.97,137.03 136.96,137.03 135.54,138.46 135.54,149.48 137.82,151.76 138.3,151.76 v1(138.94,151.13)
  BOTTOM w0.107: RZU41.2 v1(146.43,134.75) ; v1(120.5,163.32) 121.26,162.57 124.04,162.57 134.23,162.57 136.14,160.66 136.14,154.44 TP28.1 138.68,151.38 v1(138.94,151.13) RZ157.1
I2C_INT_CCG4: length 16.7
  TOP w0.107: v1(114.58,122.94) 114.94,122.94 115.29,122.58 RB24.1 116.93,122.58 Q59.S ; v1(102.25,124.52) 102.2,124.47 102.2,124.06 J1.E56
  IN1 w0.124: v1(114.58,122.94) 111.76,122.94 110.87,123.82 102.49,123.82 102.25,124.06 v1(102.25,124.52)
I2C_SCL_CDC: length 3.6
  TOP w0.107: R124.2 v1(138.18,148.84)
  BOTTOM w0.107: RZ158.2 137.79,149.22 v1(138.18,148.84) 138.68,148.34 139.32,148.34 139.55,148.1 U16.38
I2C_SDA_CDC: length 2.9
  TOP w0.107: R123.2 139.24,148.92 v1(139.32,148.84)
  BOTTOM w0.107: U16.39 139.95,148.21 v1(139.32,148.84) 138.94,149.22 RZ157.2
I2S1_DIN: length 94.6
  TOP w0.107: J1.H8 56.01,128.55 56.01,128.95 v1(55.94,129.02) ; v1(57.05,142.16) 60.59,142.16 61.36,142.93 62.7,142.93 65,145.22 112.97,145.22 116.83,141.37 121.83,141.37 127.02,146.56 v1(131.32,146.56)
  IN3 w0.124: v1(57.05,142.16) 57.25,141.96 57.25,131.78 56.44,130.96 56.44,129.52 v1(55.94,129.02)
  BOTTOM w0.107: RZ163.1 v1(131.32,146.56)
I2S1_DIN_CDC: length 5.9
  BOTTOM w0.107: RZ163.2 135.13,146.56 135.34,146.34 C912.1 136.53,146.05 TP27.1 136.91,146.18 U16.34
I2S1_DOUT: length 101.6
  TOP w0.107: v1(58.19,141.66) 60.63,141.66 61.52,142.54 62.87,142.54 65.16,144.84 112.81,144.84 116.67,140.98 121.99,140.98 126.42,145.41 v1(131.32,145.41) ; J1.C7 v1(55.1,121.52)
  IN3 w0.124: v1(58.19,141.66) 58.19,141.22 58.12,141.15 58.12,128.5 57.71,128.09 57.11,128.09 56.9,127.88 56.9,125.73 56.46,125.3 56.46,124.36 55.92,123.82 55.31,123.82 54.88,123.39 54.88,121.74 v1(55.1,121.52)
  BOTTOM w0.107: RZ165.1 v1(131.32,145.41)
I2S1_DOUT_CDC: length 6.6
  BOTTOM w0.107: U16.33 137.78,145.78 TP26.1 136.4,144.91 C913.1 135.34,145.2 135.08,145.47 133.27,145.47 133.07,145.26 RZ165.2
I2S1_FS: length 100.9
  TOP w0.107: v1(58.7,142.67) 60.55,142.67 61.2,143.32 62.54,143.32 64.84,145.61 113.13,145.61 116.99,141.75 121.67,141.75 127.61,147.7 v1(131.32,147.7) ; v1(56.12,123.04) 56.17,122.99 56.17,122.39 J1.D8
  IN3 w0.124: v1(56.12,123.04) 56.12,123.19 57.34,124.41 57.34,125.13 59.51,127.3 59.51,127.69 58.55,128.65 58.55,140.64 58.7,140.79 v1(58.7,142.67)
  BOTTOM w0.107: RZ161.1 v1(131.32,147.7)
I2S1_FS_CDC: length 6.2
  BOTTOM w0.107: RZ161.2 133.2,147.83 135.13,147.83 135.34,147.61 C914.1 TP25.1 137.26,146.58 U16.35
I2S1_SCLK: length 84.2
  TOP w0.107: v1(131.32,148.97) 130.29,150 118.16,150 114.16,145.99 64.59,145.99 62.43,143.84 v1(61.98,143.84) ; J1.L14 61.98,133.04 v3(61.98,133.5)
  IN3 w0.124: v3(61.98,133.5) v1(61.98,143.84)
  BOTTOM w0.107: RZ159.1 v1(131.32,148.97)
I2S1_SCLK_CDC: length 6.4
  BOTTOM w0.107: U16.36 138.14,146.98 TP24.1 C915.1 135.34,148.76 135.06,149.03 133.13,149.03 RZ159.2
I2S4_DIN: length 34.3
  TOP w0.107: J1.J59 v1(104.7,130.52)
  IN1 w0.124: v1(104.7,130.52) 104.74,130.52 105.41,131.19 105.74,131.19 106.25,131.7 106.25,132.26 106.97,132.98 110.02,132.98 111.1,131.9 121.69,131.9 122.3,132.51 134.44,132.51 v1(134.87,132.08)
  BOTTOM w0.107: v1(134.87,132.08) 134.99,131.97 WIFI1.12
I2S4_DOUT: length 34.1
  TOP w0.107: J1.K59 v1(104.9,132.02)
  IN1 w0.124: v1(135.49,132.08) 134.63,132.94 122.12,132.94 121.51,132.33 111.28,132.33 110.2,133.41 106.7,133.41 105.74,132.45 105.17,132.45 104.9,132.18 v1(104.9,132.02)
  BOTTOM w0.107: WIFI1.14 v1(135.49,132.08)
I2S4_FS: length 34.8
  TOP w0.107: J1.C60 v1(105.6,121.52)
  IN1 w0.124: v1(105.6,121.52) 106.11,122.02 114.97,122.02 116.05,123.1 119.9,123.1 120.98,124.18 125.95,124.18 128.65,126.88 132.43,126.88 134.75,129.2 v1(134.75,129.67)
  BOTTOM w0.107: v1(134.75,129.67) 134.49,129.93 WIFI1.10
I2S4_SCLK: length 35
  TOP w0.107: J1.C59 v1(104.7,121.52)
  IN1 w0.124: v1(104.7,121.52) 105.63,122.45 114.79,122.45 115.87,123.53 119.73,123.53 120.8,124.61 125.77,124.61 128.47,127.31 132.25,127.31 134.11,129.17 v1(134.11,129.67)
  BOTTOM w0.107: v1(134.11,129.67) 133.99,129.79 WIFI1.8
I210_JTAG_CLK1: length 2
  BOTTOM w0.107: U41.19 21.81,38.13 21.21,38.73 R278.1
I210_JTAG_TDI1: length 2.6
  TOP w0.107: v1(26.9,38.3) 26.9,37.92 27.18,37.64 R280.1
  BOTTOM w0.107: R279.1 26.92,38.33 v1(26.9,38.3) 26.81,38.22 U41.29
I210_JTAG_TDO1: length 1.6
  BOTTOM w0.107: U41.4 18.66,30.64 18.55,30.54 R276.1
I210_JTAG_TMS1: length 2.1
  BOTTOM w0.107: U41.18 21.31,38 20.57,38.73 R277.1
I2101 SDP0: length 2.8
  BOTTOM w0.107: RA132.1 19.89,26.77 20.12,27 20.73,27 21.31,27.59 U41.63
I2101 SDP1: length 2.3
  BOTTOM w0.107: U41.61 22.31,27.77 21.16,26.62 RA130.1
I2101 SDP2: length 2.4
  BOTTOM w0.107: RA131.1 20.56,26.5 21.81,27.75 U41.62
I2101 SDP3: length 2.3
  BOTTOM w0.107: RA129.1 21.79,26.87 22.81,27.89 U41.60
I2101_RSET: length 1.9
  TOP w0.254: R273.2 29.9,28.88 v1(29.97,28.96)
  BOTTOM w0.229: U41.48 29.79,29.14 v1(29.97,28.96)
I2101_SMB_ALERT#: length 1.7
  BOTTOM w0.107: U41.35 29.67,35.64 30.1,36.07 RA67.2
I2101_SMCLK: length 1.7
  BOTTOM w0.107: RA66.2 30.23,36.7 29.67,36.14 U41.34
I2101_SMDATA: length 1.6
  BOTTOM w0.107: U41.36 29.84,35.14 30.14,35.43 RA68.2
I2102_RSET: length 1.9
  TOP w0.254: v1(46.74,26.04) 45.9,26.04 R294.2
  BOTTOM w0.229: U43.48 46.55,26.22 v1(46.74,26.04)
I2102_SMB_ALERT#: length 1.7
  BOTTOM w0.107: RA81.2 46.86,33.15 46.44,32.72 U43.35
I2102_SMCLK: length 1.7
  BOTTOM w0.107: U43.34 46.43,33.22 46.99,33.78 RA74.2
I2102_SMDATA: length 1.6
  BOTTOM w0.107: U43.36 46.61,32.22 46.9,32.51 RA88.2
I2103_RSET: length 1.9
  TOP w0.254: R321.2 64.19,26.04 v1(65.02,26.04)
  BOTTOM w0.229: v1(65.02,26.04) 64.84,26.22 U45.48
I2103_SMB_ALERT#: length 1.7
  BOTTOM w0.107: RA80.2 65.15,33.15 64.73,32.72 U45.35
I2103_SMCLK: length 1.7
  BOTTOM w0.107: U45.34 64.72,33.22 65.28,33.78 RA73.2
I2103_SMDATA: length 1.6
  BOTTOM w0.107: U45.36 64.9,32.22 65.19,32.51 RA87.2
I2104_RSET: length 1.9
  TOP w0.254: R342.2 82.47,26.04 v1(83.31,26.04)
  BOTTOM w0.254: v1(83.31,26.04) 83.13,26.22 U47.48
I2104_SMB_ALERT#: length 1.7
  BOTTOM w0.107: U47.35 83.14,32.72 83.57,33.15 RA79.2
I2104_SMCLK: length 1.7
  BOTTOM w0.107: U47.34 83.13,33.22 83.69,33.78 RA72.2
I2104_SMDATA: length 1.6
  BOTTOM w0.107: RA86.2 83.41,32.51 83.12,32.22 U47.36
I2105_RSET: length 1.9
  TOP w0.254: v1(101.6,26.04) 100.76,26.04 R369.2
  BOTTOM w0.107: U49.48 101.41,26.22 v1(101.6,26.04)
I2105_SMB_ALERT#: length 1.7
  BOTTOM w0.107: U49.35 101.3,32.72 101.73,33.15 RA78.2
I2105_SMCLK: length 1.7
  BOTTOM w0.107: U49.34 101.29,33.22 101.85,33.78 RA71.2
I2105_SMDATA: length 1.6
  BOTTOM w0.107: RA85.2 101.76,32.51 101.47,32.22 U49.36
I2106_RSET: length 1.9
  TOP w0.254: R393.2 119.05,26.04 v1(119.89,26.04)
  BOTTOM w0.229: v1(119.89,26.04) 119.7,26.22 U51.48
I2106_SMB_ALERT#: length 1.7
  BOTTOM w0.107: U51.35 119.59,32.72 120.02,33.15 RA77.2
I2106_SMCLK: length 1.7
  BOTTOM w0.107: U51.34 119.58,33.22 120.14,33.78 RA70.2
I2106_SMDATA: length 1.6
  BOTTOM w0.107: RA84.2 120.05,32.51 119.76,32.22 U51.36
I2107_RSET: length 1.9
  TOP w0.254: R417.2 137.34,26.42 v1(138.18,26.42)
  BOTTOM w0.229: U53.48 137.99,26.6 v1(138.18,26.42)
I2107_SMB_ALERT#: length 1.7
  BOTTOM w0.107: U53.35 137.88,33.1 138.3,33.53 RA75.2
I2107_SMCLK: length 1.7
  BOTTOM w0.107: RA69.2 138.43,34.16 137.87,33.6 U53.34
I2107_SMDATA: length 1.6
  BOTTOM w0.107: U53.36 138.05,32.6 138.34,32.89 RA82.2
I2108_RSET: length 1.9
  TOP w0.254: v1(135,54.23) 135,53.39 R441.2
  BOTTOM w0.229: v1(135,54.23) 134.81,54.04 U55.48
I2108_SMB_ALERT#: length 1.4
  BOTTOM w0.107: U55.35 128.31,54.55 RA56.2
I2108_SMCLK: length 1.5
  BOTTOM w0.107: RA57.2 127.81,54.42 U55.34
I2108_SMDATA: length 1.4
  BOTTOM w0.107: RA55.2 128.81,54.69 U55.36
IGN: length 5.1
  TOP w0.508: DC_IN1.2 11.89,178.1 11.4,178.59 FB38.1
IN1P: length 4.9
  BOTTOM w0.381: AUDIO1.1 156.33,146.1 154.23,146.1 153.92,145.8 C898.1
IN2P: length 2.5
  BOTTOM w0.381: AUDIO1.2 154.62,145.1 154.18,144.65 C899.1
INTR_ISP1: length 2.8
  TOP w0.107: U13.38 133.55,71.3 v1(133.76,71.5)
  BOTTOM w0.107: R1505.1 v1(133.76,71.5)
ISO12_REF:
  vias: v1(43.31,192.66) v1(44.2,192.66) v1(45.09,192.66) v1(45.85,192.66)
ISO_+V12S:
  vias: v1(46.35,185.55) v1(46.35,184.91) v1(47.12,185.55) v1(47.12,184.91) v1(57.02,185.29) v1(57.78,185.29) v1(58.55,185.29)
ISO_GND: length 19
  TOP w0.381: v1(90.17,192.91) D9.8 D9.3 v1(90.17,190.37)
  TOP w0.508: R253.2 63.4,187.99 v1(63.12,187.71) ; v1(95.12,190.5) 94.64,190.02 U24.9 ; v1(66.67,187.83) 66.92,187.59 U36.5 ; U24.15 87.02,190.12 86.83,190.31 CA1.2 v1(87.5,191.26)
  BOTTOM w0.381: v1(90.17,192.91) D9.8 D9.3 v1(90.17,190.37)
  BOTTOM w0.508: v1(85.22,190.5) 85.75,189.97 U26.9 ; v1(63.12,187.71) U38.5 ; v1(93.51,191.77) CA118.2 93.51,190.26 93.37,190.12 U26.15 ; R257.2 66.65,187.86 v1(66.67,187.83)
  vias: v1(69.6,186.06) v1(69.85,191.52) v1(70.23,186.06) v1(70.74,191.52) v1(71.5,191.52) v1(72.26,191.52)
ISO_RX1: length 9.2
  TOP w0.254: UART1.9 90.67,196.12 D9.7 D9.4 90.67,190.38 90.83,190.22 U24.12
ISO_RX2: length 11.1
  TOP w0.254: U24.11 92.1,189.84 91.17,190.77 D9.5 D9.6 91.17,195.56 v1(91.31,195.71)
  IN3 w0.254: UART1.7 90.03,195.71 v1(91.31,195.71)
ISO_RX3: length 12.6
  BOTTOM w0.254: U26.12 89.56,190.27 89.67,190.38 D10.4 D10.7 89.67,192.9 88.9,193.68 85.98,193.68 84.14,195.51 UART1.5
ISO_RX4: length 15
  BOTTOM w0.254: U26.11 88.29,189.76 89.17,190.64 D10.5 D10.6 89.17,192.53 88.66,193.04 84.69,193.04 UART1.3
ISO_TX1: length 13
  TOP w0.254: U24.14 88.29,189.76 89.17,190.64 D9.1 D9.10 89.17,195.56 v1(89.03,195.71)
  IN1 w0.254: v1(89.03,195.71) 89.41,196.09 92.64,196.09 UART1.10
ISO_TX2: length 8.8
  TOP w0.254: UART1.8 89.67,197.12 D9.9 D9.2 89.67,190.38 89.56,190.27 U24.13
ISO_TX3: length 12.4
  BOTTOM w0.254: U26.14 92.1,189.84 91.17,190.77 D10.1 D10.10 91.17,193.69 89.92,194.94 87.63,194.94 86.14,196.43 UART1.6
ISO_TX4: length 14.7
  TOP w0.254: UART1.4 84.03,195.71 v1(85.34,195.71)
  BOTTOM w0.254: U26.13 90.83,190.22 90.67,190.38 D10.2 D10.9 90.67,193.3 89.66,194.31 86.74,194.31 v1(85.34,195.71)
JD1: length 14.8
  TOP w0.254: v1(151.38,148.08) 151,148.08 150.5,148.59 150.5,150.11 v1(148.84,151.89)
  IN3 w0.254: v1(151.38,148.08) 150.5,148.08 147.52,145.11 v1(145.41,145.11)
  BOTTOM w0.203: v1(145.41,145.11) 145.24,145.11 145.11,144.98 U16.6
  BOTTOM w0.254: RZU37.1 v1(148.84,151.89) ; RZ160.1 v1(151.38,148.08)
JD2: length 14.7
  TOP w0.254: v1(148.84,150.75) 149.86,149.73 149.86,148.08 151,146.94 v1(151.38,146.94)
  IN3 w0.254: v1(145.67,144.15) 146.05,144.53 147.96,144.53 150.37,146.94 v1(151.38,146.94)
  BOTTOM w0.203: U16.8 145.63,144.18 v1(145.67,144.15)
  BOTTOM w0.254: RZ162.2 v1(151.38,146.94) ; RZU39.2 v1(148.84,150.75)
JTAG_TCK: length 23.3
  TOP w0.107: v1(121.67,123.06) 120.65,122.05 120.65,119 120.14,118.49 116.21,118.49 115.98,118.26 R145.1 TP33.1 113.79,116.84 105.92,116.84 105.6,117.16 J1.A60
  BOTTOM w0.107: J4.4 121.28,122.68 v1(121.67,123.06)
JTAG_TDI: length 30.2
  TOP w0.107: J1.B60 v1(105.8,120.02)
  BOTTOM w0.107: J4.8 TP31.1 R143.2 127.03,120.4 125.68,119.05 119.23,119.05 118.84,119.44 109.95,119.44 108.81,120.57 106.17,120.57 105.8,120.2 v1(105.8,120.02)
JTAG_TDO: length 26.3
  TOP w0.107: J1.D58 v1(104,123.02)
  BOTTOM w0.107: R142.2 TP32.1 125.73,126.49 J4.6 122.81,126.49 122.05,127.25 115.82,127.25 111,122.43 104.59,122.43 v1(104,123.02)
JTAG_TMS: length 21.2
  TOP w0.107: J1.E58 v1(103.8,124.52)
  BOTTOM w0.107: v1(103.8,124.52) 103.55,124.27 103.55,122.26 103.76,122.05 111.25,122.05 113.41,124.21 116.08,124.21 116.43,124.56 R141.2 TP34.1 117.86,125.22 J4.2
JTAG_TRST_N: length 1.5
  TOP w0.107: J1.G61 v1(106.5,127.52)
  BOTTOM w0.107: TP6.1 106.55,127.47 v1(106.5,127.52)
KSENSA: length 3.2
  TOP w0.254: RZ66.2 RZ69.2 8.83,76.37 U65.4
KSENSB: length 2.6
  TOP w0.229: U65.11 v1(9.86,72.87)
  BOTTOM w0.229: RZ200.2 RZ202.2 10.41,72.87 v1(9.86,72.87)
KSENSC: length 3.1
  TOP w0.203: U65.32 19.51,72.87
  TOP w0.254: RZ75.2 19.74,72.87 19.51,72.87
  TOP w0.508: RZ77.2 RZ75.2
KSENSD: length 3.2
  TOP w0.203: U65.39 19.85,76.37 20.02,76.53 RZ70.2
  TOP w0.508: RZ70.2 RZ71.2
LAN1_ACT#: length 1.7
  BOTTOM w0.107: U41.30 27.31,38.39 R286.2
LAN1_CBOT: length 1.9
  BOTTOM w0.229: C171.2 30.61,34.76 29.78,34.76 29.66,34.64 U41.37
LAN1_CT1_A+_V-:
  vias: v1(10.74,11.25) v1(11.51,11.25)
LAN1_CT2_A-_V+: length 2.8
  BOTTOM w0.813: U57.21 15.11,9.65
  vias: v1(14.68,11.25) v1(15.37,11.25)
LAN1_CT3_B+_V+: length 3.4
  BOTTOM w0.762: U57.18 18.92,10.29
  vias: v1(6.55,9.73) v1(7.32,9.73) v1(18.87,11.25) v1(19.51,11.25)
LAN1_CT4_B-_V-: length 3.2
  BOTTOM w0.762: U57.15 22.73,9.78 22.94,9.98
  vias: v1(6.67,5.8) v1(7.44,5.79) v1(22.94,11.25) v1(23.57,11.25)
LAN1_CTOP: length 1.9
  BOTTOM w0.229: 30.16,33.14 U41.40
  BOTTOM w0.305: C171.1 30.44,33.14 30.16,33.14
LAN1_DEV_OFF: length 2.5
  TOP w0.107: v1(26.29,38.3) 26.29,37.82 26.42,37.69 R270.1
  BOTTOM w0.107: U41.28 26.31,38.28 v1(26.29,38.3) R269.2
LAN1_LINK_100#: length 2.1
  BOTTOM w0.107: U41.31 27.81,37.97 28.73,38.89 R288.2
LAN1_LINK_1000#: length 1.8
  BOTTOM w0.107: R289.2 29.56,36.64 U41.33
LAN1_MDI0+: length 16.2
  BOTTOM w0.089: U57.2 12.57,21.89 13.08,22.4 13.08,22.63 13.33,22.89 14.49,22.89 16.44,24.84 22.88,24.84 22.97,24.93 22.97,25.02 22.88,25.11 D16.10 D16.1 22.88,26.48 22.99,26.59 22.99,26.84 23.93,27.77 23.93,27.91 23.81,28.03 U41.58
LAN1_MDI0+_T: length 5.7
  BOTTOM w0.089: POE1.8 11.73,3.13 11.73,4.25 13.07,5.59 13.07,5.72 12.57,6.21 U57.23
LAN1_MDI0-: length 16.2
  BOTTOM w0.089: U41.57 24.31,27.99 24.21,27.89 24.21,27.66 23.27,26.72 23.27,26.59 23.38,26.48 D16.2 D16.9 23.38,25.15 23.25,25.03 23.25,24.81 22.99,24.56 16.56,24.56 14.61,22.61 13.45,22.61 13.36,22.52 13.36,22.4 13.84,21.92 U57.3
LAN1_MDI0-_T: length 5.7
  BOTTOM w0.089: POE1.7 12.01,3.13 12.01,4.14 13.35,5.47 13.35,5.73 13.84,6.22 U57.22
LAN1_MDI1+: length 14.4
  BOTTOM w0.089: U57.5 16.38,22 16.88,22.49 16.88,22.94 17.91,23.98 23.28,23.98 24.01,24.71 24.38,24.71 24.49,24.82 24.49,24.99 24.38,25.1 D16.7 D16.4 24.38,26.45 24.49,26.56 24.49,26.81 24.74,27.06 25.26,27.06 25.42,27.22 25.42,27.82 25.31,27.93 U41.55
LAN1_MDI1+_T: length 5.6
  BOTTOM w0.089: U57.20 16.38,6.22 16.88,5.73 16.88,5.44 15.73,4.3 15.73,3.13 POE1.6
LAN1_MDI1-: length 14.4
  BOTTOM w0.089: U41.54 25.81,27.97 25.7,27.86 25.7,27.11 25.38,26.78 24.85,26.78 24.77,26.69 24.77,26.57 24.88,26.46 D16.5 D16.6 24.88,25.1 24.77,24.99 24.77,24.7 24.5,24.43 24.13,24.43 23.39,23.7 18.03,23.7 17.16,22.83 17.16,22.5 17.65,22 U57.6
LAN1_MDI1-_T: length 5.6
  BOTTOM w0.089: POE1.5 16.01,3.13 16.01,4.18 17.16,5.33 17.16,5.73 17.65,6.22 U57.19
LAN1_MDI2+: length 11.9
  BOTTOM w0.089: U41.53 26.31,27.97 26.42,27.86 26.42,27.48 26.37,27.42 26.37,26.52 26.25,26.41 D19.1 D19.10 26.25,25.08 26.39,24.94 26.39,24.61 25.58,23.8 24.41,23.8 23.65,23.04 20.94,23.04 20.69,22.79 20.69,22.47 20.19,21.97 U57.8
LAN1_MDI2+_T: length 3.9
  BOTTOM w0.089: 19.71,3.53 19.71,4.47 20.69,5.44 20.69,5.73 20.19,6.22 U57.17
LAN1_MDI2-: length 11.9
  BOTTOM w0.089: U41.52 26.81,27.95 26.7,27.84 26.7,27.36 26.64,27.3 26.64,26.52 26.75,26.41 D19.2 D19.9 26.75,25.03 26.67,24.94 26.67,24.5 25.69,23.52 24.53,23.52 23.77,22.76 21.06,22.76 20.97,22.67 20.97,22.47 21.46,21.97 U57.9
LAN1_MDI2-_T: length 3.9
  BOTTOM w0.089: U57.16 21.46,6.22 20.97,5.73 20.97,5.33 19.99,4.35 19.99,3.53
LAN1_MDI3+: length 9.8
  BOTTOM w0.089: U41.50 27.81,27.94 27.92,27.83 27.92,27.1 27.86,27.04 27.86,26.54 27.75,26.43 D19.4 D19.7 27.75,25.08 27.86,24.97 27.86,24.12 26.66,22.91 24.78,22.91 24.52,22.66 24.52,22.47 24,21.95 U57.11
LAN1_MDI3+_T: length 5.5
  BOTTOM w0.089: U57.14 24,6.22 24.5,5.73 24.5,5.19 23.73,4.43 23.73,3.13 POE1.2
LAN1_MDI3-: length 9.7
  BOTTOM w0.089: U57.12 25.27,21.97 24.8,22.44 24.8,22.54 24.89,22.63 26.77,22.63 28.14,24 28.14,24.94 28.25,25.05 D19.6 D19.5 28.25,26.43 28.14,26.54 28.14,26.92 28.2,26.98 28.2,27.85 28.31,27.96 U41.49
LAN1_MDI3-_T: length 5.5
  BOTTOM w0.089: POE1.1 24.01,3.13 24.01,4.31 24.78,5.08 24.78,5.73 25.27,6.22 U57.13
LAN1_NVM_CS: length 1.4
  TOP w0.107: U42.1 18.15,39.99 v1(18.29,40.13)
  BOTTOM w0.107: R284.1 v1(18.29,40.13)
LAN1_NVM_SI: length 5.8
  TOP w0.107: U42.5 16.65,35.04 v1(17.14,34.54) 17.17,34.57 R290.2
  BOTTOM w0.107: R291.1 16.64,35.05 v1(17.14,34.54) R281.1
LAN1_NVM_SK: length 3.6
  TOP w0.107: v1(17.14,35.18) 17.15,35.18 U42.6
  BOTTOM w0.107: R287.2 17.27,35.89 17.14,35.76 v1(17.14,35.18) R282.1
LAN1_NVM_SO: length 1.4
  TOP w0.107: U42.2 v1(17.65,40.13)
  BOTTOM w0.107: R283.1 17.65,40.13 v1(17.65,40.13)
LAN1_PWR_GOOD: length 1.5
  BOTTOM w0.107: R275.2 18.68,29.08 19.43,29.08 19.49,29.14 U41.1
LAN1_VDD0P9_OUT: length 3.9
  TOP w0.508: RZ128.1 29.08,35.08 C166.1 29.06,34.8 29.57,34.29 v1(29.97,34.29)
  BOTTOM w0.229: U41.38 29.82,34.14 v1(29.97,34.29)
LAN1_VDD1P5_OUT: length 3.9
  TOP w0.508: v1(29.97,33.62) 29.27,33.62 C167.1 29.59,32.87 RZ135.1
  BOTTOM w0.229: U41.39 29.95,33.64 v1(29.97,33.62)
LAN1_XTAL1: length 5.6
  BOTTOM w0.203: U41.46 29.55,30.14 29.65,30.04 31.67,30.04 R285.2 31.86,29.24 C174.1 31.58,27.63 X2.1
LAN1_XTAL2: length 2.9
  BOTTOM w0.203: U41.45 29.59,30.64 29.83,30.4 31.79,30.4 RB14.1
LAN2_ACT#: length 1.7
  BOTTOM w0.107: R310.2 44.08,35.47 U43.30
LAN2_CBOT: length 1.9
  BOTTOM w0.229: C180.2 47.37,31.84 46.54,31.84 46.42,31.72 U43.37
LAN2_CT1_A+_V-:
  vias: v1(32.87,11.23) v1(33.5,11.23)
LAN2_CT2_A-_V+:
  vias: v1(36.78,11.25) v1(37.41,11.25)
LAN2_CTOP: length 1.9
  BOTTOM w0.229: 46.93,30.22 U43.40
  BOTTOM w0.305: C180.1 47.2,30.22 46.93,30.22
LAN2_DEV_OFF: length 2.5
  TOP w0.107: R295.1 43.18,34.77 43.05,34.9 v1(43.05,35.38)
  BOTTOM w0.107: R293.2 v1(43.05,35.38) 43.08,35.36 U43.28
LAN2_LINK_100#: length 2.1
  BOTTOM w0.107: R312.2 45.49,35.97 44.58,35.05 U43.31
LAN2_LINK_1000#: length 1.8
  BOTTOM w0.107: U43.33 46.32,33.72 R313.2
LAN2_MDI0+: length 11
  BOTTOM w0.089: U58.2 35.38,18.74 35.74,19.1 35.74,19.72 37.5,21.49 39.79,21.49 40.26,21.96 40.26,22.07 40.15,22.18 D21.10 D21.1 40.15,23.54 40.26,23.65 40.26,24.14 40.69,24.57 40.69,24.94 40.58,25.05 U43.58
LAN2_MDI0+_T: length 10
  BOTTOM w0.089: U58.23 35.38,8.18 35.74,7.82 35.74,5.54 34.77,4.57 32.64,4.57 31.73,3.66 31.73,3.13 POE2.8
LAN2_MDI0-: length 11
  BOTTOM w0.089: U43.57 41.08,25.07 40.97,24.96 40.97,24.46 40.54,24.03 40.54,23.65 40.65,23.54 D21.2 D21.9 40.65,22.21 40.54,22.1 40.54,21.84 39.9,21.21 37.62,21.21 36.02,19.61 36.02,19.13 36.38,18.77 U58.3
LAN2_MDI0-_T: length 10
  BOTTOM w0.089: POE2.7 32.01,3.13 32.01,3.55 32.75,4.29 34.89,4.29 36.02,5.42 36.02,7.82 36.38,8.18 U58.22
LAN2_MDI1+: length 9.9
  BOTTOM w0.089: U58.5 38.38,18.69 38.74,19.05 38.74,19.82 39.24,20.32 40.63,20.32 41.76,21.45 41.76,22.12 41.65,22.23 D21.7 D21.4 41.65,23.54 41.76,23.65 41.76,24.02 42.19,24.45 42.19,24.92 42.08,25.03 U43.55
LAN2_MDI1+_T: length 9
  BOTTOM w0.089: U58.20 38.38,8.23 38.74,7.87 38.74,5.73 38.24,5.23 37.35,5.23 35.73,3.61 35.73,2.87 35.12,2.26 POE2.6
LAN2_MDI1-: length 9.9
  BOTTOM w0.089: U58.6 39.38,18.69 39.02,19.05 39.02,19.7 39.36,20.04 40.74,20.04 42.04,21.34 42.04,22.12 42.15,22.23 D21.6 D21.5 42.15,23.56 42.04,23.67 42.04,23.9 42.47,24.33 42.47,24.92 42.58,25.03 U43.54
LAN2_MDI1-_T: length 9
  BOTTOM w0.089: U58.19 39.38,8.23 39.02,7.87 39.02,5.62 38.35,4.95 37.47,4.95 36.01,3.5 36.01,2.87 36.61,2.26 POE2.5
LAN2_MDI2+: length 8.6
  BOTTOM w0.089: U43.53 43.08,25.12 43.19,25.01 43.19,24.25 43.56,23.88 43.56,23.62 43.45,23.51 D23.1 D23.10 43.45,22.16 43.56,22.05 43.56,21.7 41.73,19.87 41.73,19.1 41.38,18.75 U58.8
LAN2_MDI2+_T: length 7.9
  BOTTOM w0.089: U58.17 41.38,8.28 41.74,7.92 41.74,5.56 39.73,3.55 39.73,3.13 POE2.4
LAN2_MDI2-: length 8.6
  BOTTOM w0.089: U58.9 42.38,18.73 42.01,19.1 42.01,19.75 43.84,21.58 43.84,22.05 43.95,22.16 D23.9 D23.2 43.95,23.51 43.84,23.62 43.84,23.99 43.47,24.37 43.47,25.01 43.58,25.12 U43.52
LAN2_MDI2-_T: length 7.9
  BOTTOM w0.089: POE2.3 40.87,2.26 40.01,3.12 40.01,3.43 42.02,5.44 42.02,7.92 42.38,8.28 U58.16
LAN2_MDI3+: length 7.9
  BOTTOM w0.089: U43.50 44.58,25.07 44.69,24.96 44.69,24.58 45.06,24.21 45.06,23.67 44.95,23.56 D23.4 D23.7 44.95,22.16 45.06,22.05 45.06,20.07 44.74,19.75 44.74,19.06 44.38,18.7 U58.11
LAN2_MDI3+_T: length 7.5
  BOTTOM w0.089: POE2.2 43.73,3.13 43.73,4.49 44.74,5.5 44.74,7.84 44.38,8.2 U58.14
LAN2_MDI3-: length 7.9
  BOTTOM w0.089: U58.12 45.38,18.7 45.02,19.06 45.02,19.63 45.34,19.96 45.34,22.05 45.45,22.16 D23.6 D23.5 45.45,23.56 45.34,23.67 45.34,24.32 44.97,24.7 44.97,24.98 45.08,25.09 U43.49
LAN2_MDI3-_T: length 7.5
  BOTTOM w0.089: U58.13 45.38,8.2 45.02,7.84 45.02,5.38 44.01,4.37 44.01,3.12 44.87,2.26 POE2.1
LAN2_NVM_CS: length 1.4
  TOP w0.107: U44.1 34.91,37.07 v1(35.05,37.21)
  BOTTOM w0.107: R308.1 v1(35.05,37.21)
LAN2_NVM_SI: length 5.8
  TOP w0.107: U44.5 33.41,32.12 v1(33.91,31.62) R314.2
  BOTTOM w0.107: R305.1 v1(33.91,31.62) 33.4,32.13 R315.1
LAN2_NVM_SK: length 3.6
  TOP w0.107: v1(33.91,32.26) 33.91,32.26 U44.6
  BOTTOM w0.107: R306.1 v1(33.91,32.26) 33.91,32.89 34.04,33.02 R311.2
LAN2_NVM_SO: length 1.4
  TOP w0.107: v1(34.41,37.21) U44.2
  BOTTOM w0.107: R307.1 34.42,37.21 v1(34.41,37.21)
LAN2_PWR_GOOD: length 1.5
  BOTTOM w0.107: U43.1 36.25,26.22 36.2,26.16 35.45,26.16 R299.2
LAN2_VDD0P9_OUT: length 3.9
  TOP w0.508: v1(46.74,31.37) 46.33,31.37 45.82,31.88 C175.1 45.85,32.16 RZ130.1
  BOTTOM w0.229: U43.38 46.59,31.22 v1(46.74,31.37)
LAN2_VDD1P5_OUT: length 3.8
  TOP w0.508: v1(46.74,30.7) 46.04,30.7 C176.1 46.35,29.95 RZ137.1
  BOTTOM w0.229: v1(46.74,30.7) 46.71,30.72 U43.39
LAN2_XTAL1: length 5.6
  BOTTOM w0.203: X3.1 48.35,24.71 C183.1 48.63,26.31 R309.2 48.44,27.12 46.42,27.12 46.31,27.22 U43.46
LAN2_XTAL2: length 2.9
  BOTTOM w0.203: U43.45 46.35,27.72 46.59,27.48 48.55,27.48 RB15.1
LAN3_ACT#: length 1.7
  BOTTOM w0.107: U45.30 62.36,35.47 R333.2
LAN3_CBOT: length 1.9
  BOTTOM w0.229: C189.2 65.66,31.84 64.83,31.84 64.71,31.72 U45.37
LAN3_CT1_A+_V-:
  vias: v1(53.06,11.23) v1(53.7,11.23)
LAN3_CT2_A-_V+:
  vias: v1(57,11.25) v1(57.63,11.25)
LAN3_CTOP: length 1.9
  BOTTOM w0.229: 65.21,30.22 U45.40
  BOTTOM w0.305: C189.1 65.49,30.22 65.21,30.22
LAN3_DEV_OFF: length 2.5
  TOP w0.107: v1(61.34,35.38) 61.34,34.9 61.47,34.77 R318.1
  BOTTOM w0.107: R317.2 v1(61.34,35.38) 61.36,35.36 U45.28
LAN3_LINK_100#: length 2.1
  BOTTOM w0.107: U45.31 62.86,35.05 63.78,35.97 R336.2
LAN3_LINK_1000#: length 1.8
  BOTTOM w0.107: R337.2 64.61,33.72 U45.33
LAN3_MDI0+: length 9.7
  BOTTOM w0.089: U45.58 58.86,25.05 58.97,24.94 58.97,24.57 58.55,24.14 58.55,23.65 58.44,23.54 D24.1 D24.10 58.44,22.18 58.55,22.07 58.55,21.96 58.46,21.87 57.16,21.87 55.93,20.64 55.93,19.13 55.57,18.77 U59.2
LAN3_MDI0+_T: length 9.9
  BOTTOM w0.089: POE3.8 51.73,3.13 51.73,3.99 52.31,4.57 54.1,4.57 55.93,6.4 55.93,7.82 55.57,8.18 U59.23
LAN3_MDI0-: length 9.7
  BOTTOM w0.089: U59.3 56.57,18.77 56.21,19.13 56.21,20.52 57.28,21.59 58.57,21.59 58.83,21.84 58.83,22.1 58.94,22.21 D24.9 D24.2 58.94,23.54 58.83,23.65 58.83,24.03 59.25,24.46 59.25,24.96 59.36,25.07 U45.57
LAN3_MDI0-_T: length 9.9
  BOTTOM w0.089: U59.22 56.57,8.18 56.21,7.82 56.21,6.29 54.22,4.29 52.43,4.29 52.01,3.88 52.01,3.13 POE3.7
LAN3_MDI1+: length 8.3
  BOTTOM w0.089: U59.5 58.57,18.69 58.93,19.05 58.93,20.6 59.09,20.76 59.1,20.76 60.05,21.71 60.05,22.12 59.94,22.23 D24.7 D24.4 59.94,23.54 60.05,23.65 60.05,24.02 60.47,24.45 60.47,24.92 60.36,25.03 U45.55
LAN3_MDI1+_T: length 8.4
  BOTTOM w0.089: U59.20 58.57,8.23 58.93,7.87 58.93,7.12 55.73,3.91 55.73,3.13 POE3.6
LAN3_MDI1-: length 8.3
  BOTTOM w0.089: U45.54 60.86,25.03 60.75,24.92 60.75,24.33 60.33,23.9 60.33,23.67 60.44,23.56 D24.5 D24.6 60.44,22.23 60.33,22.12 60.33,21.59 59.21,20.48 59.21,20.48 59.21,19.07 59.57,18.71 U59.6
LAN3_MDI1-_T: length 8.4
  BOTTOM w0.089: POE3.5 56.01,3.13 56.01,3.8 59.21,7 59.21,7.87 59.57,8.23 U59.19
LAN3_MDI2+: length 7.8
  BOTTOM w0.089: U59.8 61.57,18.77 61.93,19.13 61.93,20.48 61.85,20.56 61.85,22.05 61.74,22.16 D27.10 D27.1 61.74,23.51 61.85,23.62 61.85,23.88 61.47,24.25 61.47,25.01 61.36,25.12 U45.53
LAN3_MDI2+_T: length 8
  BOTTOM w0.089: POE3.4 59.73,3.13 59.73,4.75 61.93,6.95 61.93,7.92 61.57,8.28 U59.17
LAN3_MDI2-: length 7.8
  BOTTOM w0.089: U45.52 61.86,25.12 61.75,25.01 61.75,24.37 62.13,23.99 62.13,23.62 62.24,23.51 D27.2 D27.9 62.24,22.16 62.13,22.05 62.13,20.68 62.21,20.6 62.21,19.13 62.57,18.77 U59.9
LAN3_MDI2-_T: length 8
  BOTTOM w0.089: U59.16 62.57,8.28 62.21,7.92 62.21,6.84 60.01,4.64 60.01,3.13 POE3.3
LAN3_MDI3+: length 8.5
  BOTTOM w0.089: U45.50 62.86,25.07 62.97,24.96 62.97,24.58 63.35,24.21 63.35,23.67 63.24,23.56 D27.4 D27.7 63.24,22.16 63.35,22.05 63.35,21.6 64.93,20.02 64.93,19.02 64.57,18.66 U59.11
LAN3_MDI3+_T: length 7.6
  BOTTOM w0.089: U59.14 64.57,8.2 64.93,7.84 64.93,6.27 63.73,5.07 63.73,3.12 POE3.2
LAN3_MDI3-: length 8.5
  BOTTOM w0.089: U59.12 65.57,18.66 65.21,19.02 65.21,20.13 63.63,21.72 63.63,22.05 63.74,22.16 D27.6 D27.5 63.74,23.56 63.63,23.67 63.63,24.32 63.25,24.7 63.25,24.98 63.36,25.09 U45.49
LAN3_MDI3-_T: length 7.6
  BOTTOM w0.089: POE3.1 64.01,3.13 64.01,4.95 65.21,6.16 65.21,7.84 65.57,8.2 U59.13
LAN3_NVM_CS: length 1.4
  TOP w0.107: U46.1 53.2,37.07 v1(53.34,37.21)
  BOTTOM w0.107: R332.1 v1(53.34,37.21)
LAN3_NVM_SI: length 5.8
  TOP w0.107: R338.2 v1(52.2,31.62) 51.7,32.12 U46.5
  BOTTOM w0.107: R329.1 v1(52.2,31.62) 51.69,32.13 R339.1
LAN3_NVM_SK: length 3.6
  TOP w0.107: v1(52.2,32.26) 52.2,32.26 U46.6
  BOTTOM w0.107: R330.1 v1(52.2,32.26) 52.2,32.89 52.32,33.02 R335.2
LAN3_NVM_SO: length 1.4
  TOP w0.107: v1(52.7,37.21) U46.2
  BOTTOM w0.107: v1(52.7,37.21) 52.7,37.21 R331.1
LAN3_PWR_GOOD: length 1.5
  BOTTOM w0.107: U45.1 54.54,26.22 54.48,26.16 53.73,26.16 R323.2
LAN3_VDD0P9_OUT: length 3.9
  TOP w0.508: v1(65.02,31.37) 64.62,31.37 64.11,31.88 C184.1 64.14,32.16 RZ131.1
  BOTTOM w0.229: U45.38 64.88,31.22 v1(65.02,31.37)
LAN3_VDD1P5_OUT: length 3.8
  TOP w0.508: RZ138.1 64.64,29.95 C185.1 64.33,30.7 v1(65.02,30.7)
  BOTTOM w0.229: v1(65.02,30.7) 65,30.72 U45.39
LAN3_XTAL1: length 5.6
  BOTTOM w0.203: U45.46 64.6,27.22 64.71,27.12 66.72,27.12 R334.2 66.92,26.31 C192.1 66.64,24.71 X4.1
LAN3_XTAL2: length 2.9
  BOTTOM w0.203: RB16.1 66.84,27.48 64.88,27.48 64.64,27.72 U45.45
LAN4_ACT#: length 1.7
  BOTTOM w0.107: U47.30 80.65,35.47 R356.2
LAN4_CBOT: length 1.9
  BOTTOM w0.229: U47.37 83,31.72 83.12,31.84 83.95,31.84 C198.2
LAN4_CT1_A+_V-:
  vias: v1(73.25,11.23) v1(73.89,11.23)
LAN4_CT2_A-_V+:
  vias: v1(77.19,11.25) v1(77.83,11.25)
LAN4_CTOP: length 1.9
  BOTTOM w0.229: U47.40 83.5,30.22
  BOTTOM w0.305: C198.1 83.78,30.22 83.5,30.22
LAN4_DEV_OFF: length 2.5
  TOP w0.107: v1(79.63,35.38) 79.63,35.18 79.76,35.05 R343.1
  BOTTOM w0.107: R341.2 v1(79.63,35.38) 79.65,35.36 U47.28
LAN4_LINK_100#: length 2.1
  BOTTOM w0.107: U47.31 81.15,35.05 82.07,35.97 R360.2
LAN4_LINK_1000#: length 1.9
  BOTTOM w0.107: U47.33 83.13,33.72 83.85,34.44 R361.2
LAN4_MDI0+: length 8.1
  BOTTOM w0.089: U60.2 75.76,18.74 76.12,19.1 76.12,20.12 76.83,20.83 76.83,21.97 76.72,22.08 D29.10 D29.1 76.72,23.54 76.83,23.65 76.83,24.14 77.26,24.57 77.26,24.95 77.15,25.06 U47.58
LAN4_MDI0+_T: length 10.3
  BOTTOM w0.089: U60.23 75.76,8.18 76.12,7.82 76.12,6.03 74.66,4.57 72.25,4.57 71.73,4.05 71.73,3.13 POE4.8
LAN4_MDI0-: length 8.1
  BOTTOM w0.089: U47.57 77.65,25.07 77.54,24.96 77.54,24.46 77.11,24.03 77.11,23.65 77.22,23.54 D29.2 D29.9 77.22,22.11 77.11,22 77.11,20.71 76.4,20 76.4,19.13 76.76,18.77 U60.3
LAN4_MDI0-_T: length 10.3
  BOTTOM w0.089: POE4.7 72.01,3.12 72.01,3.94 72.36,4.29 74.78,4.29 76.4,5.92 76.4,7.82 76.76,8.18 U60.22
LAN4_MDI1+: length 8.1
  BOTTOM w0.089: U47.55 78.65,25.03 78.76,24.92 78.76,24.45 78.33,24.02 78.33,23.65 78.22,23.54 D29.4 D29.7 78.22,22.11 78.33,22 78.33,20.56 79.12,19.77 79.12,19.05 78.76,18.69 U60.5
LAN4_MDI1+_T: length 9.2
  BOTTOM w0.089: U60.20 78.76,8.23 79.12,7.87 79.12,5.73 78.62,5.23 77.37,5.23 75.73,3.59 75.73,3.13 POE4.6
LAN4_MDI1-: length 8.1
  BOTTOM w0.089: U47.54 79.15,25.03 79.04,24.92 79.04,24.33 78.61,23.9 78.61,23.67 78.72,23.56 D29.5 D29.6 78.72,22.08 78.61,21.97 78.61,20.68 79.4,19.89 79.4,19.05 79.76,18.69 U60.6
LAN4_MDI1-_T: length 9.2
  BOTTOM w0.089: U60.19 79.76,8.23 79.4,7.87 79.4,5.62 78.74,4.95 77.48,4.95 76.01,3.48 76.01,3.12 POE4.5
LAN4_MDI2+: length 8.6
  BOTTOM w0.089: U60.8 81.76,18.74 82.12,19.1 82.12,19.33 80.14,21.32 80.14,21.97 80.03,22.08 D31.10 D31.1 80.03,23.51 80.14,23.62 80.14,23.88 79.76,24.25 79.76,25.01 79.65,25.12 U47.53
LAN4_MDI2+_T: length 8.1
  BOTTOM w0.089: U60.17 81.76,8.28 82.12,7.92 82.12,6.57 79.73,4.18 79.73,3.13 POE4.4
LAN4_MDI2-: length 8.6
  BOTTOM w0.089: U60.9 82.76,18.73 82.4,19.09 82.4,19.45 80.42,21.44 80.42,22 80.53,22.11 D31.9 D31.2 80.53,23.51 80.42,23.62 80.42,23.99 80.04,24.37 80.04,25.01 80.15,25.12 U47.52
LAN4_MDI2-_T: length 8.1
  BOTTOM w0.089: U60.16 82.76,8.28 82.4,7.92 82.4,6.46 80.01,4.06 80.01,3.12 POE4.3
LAN4_MDI3+: length 10
  BOTTOM w0.089: U60.11 84.76,18.72 85.12,19.08 85.12,19.46 83.9,20.69 82.52,20.69 81.64,21.58 81.64,22 81.53,22.11 D31.7 D31.4 81.53,23.56 81.64,23.67 81.64,24.21 81.26,24.58 81.26,24.96 81.15,25.07 U47.50
LAN4_MDI3+_T: length 7.7
  BOTTOM w0.089: POE4.2 83.73,3.13 83.73,4.1 85.12,5.5 85.12,7.84 84.76,8.2 U60.14
LAN4_MDI3-: length 10
  BOTTOM w0.089: U47.49 81.65,25.09 81.54,24.98 81.54,24.7 81.92,24.32 81.92,23.67 82.03,23.56 D31.5 D31.6 82.03,22.08 81.92,21.97 81.92,21.7 82.64,20.97 84.01,20.97 85.4,19.58 85.4,19.02 85.76,18.66 U60.12
LAN4_MDI3-_T: length 7.7
  BOTTOM w0.089: U60.13 85.76,8.2 85.4,7.84 85.4,5.38 84.01,3.99 84.01,3.12 POE4.1
LAN4_NVM_CS: length 2.2
  TOP w0.107: U48.1 71.49,37.07 71.63,37.22 v1(71.63,37.59)
  BOTTOM w0.107: R357.1 71.63,37.59 v1(71.63,37.59)
LAN4_NVM_SI: length 5.9
  TOP w0.107: U48.5 69.99,31.88 70.25,31.62 v1(70.48,31.62) 70.51,31.65 R362.2
  BOTTOM w0.107: R363.1 69.98,32.13 v1(70.48,31.62) R353.1
LAN4_NVM_SK: length 3.6
  TOP w0.107: U48.6 70.49,32.26 v1(70.48,32.26)
  BOTTOM w0.107: R359.2 70.61,33.02 70.48,32.89 v1(70.48,32.26) R354.1
LAN4_NVM_SO: length 2.1
  TOP w0.107: U48.2 70.99,37.59 v1(70.99,37.59)
  BOTTOM w0.107: R355.1 v1(70.99,37.59)
LAN4_PWR_GOOD: length 1.9
  BOTTOM w0.107: R347.2 71.66,25.91 72.65,25.91 72.96,26.22 U47.1
LAN4_VDD0P9_OUT: length 3.9
  TOP w0.508: v1(83.31,31.37) 82.91,31.37 82.4,31.88 C193.1 82.42,32.16 RZ132.1
  BOTTOM w0.254: U47.38 83.16,31.22 v1(83.31,31.37)
LAN4_VDD1P5_OUT: length 3.8
  TOP w0.508: v1(83.31,30.7) 82.61,30.7 C194.1 82.93,29.95 RZ139.1
  BOTTOM w0.254: v1(83.31,30.7) 83.29,30.72 U47.39
LAN4_XTAL1: length 5.6
  BOTTOM w0.203: X5.1 84.64,25.08 84.92,25.36 C201.1 85.2,26.31 R358.2 85.01,27.12 82.99,27.12 82.89,27.22 U47.46
LAN4_XTAL2: length 2.9
  BOTTOM w0.203: RB17.1 85.13,27.48 83.17,27.48 82.93,27.72 U47.45
LAN5_ACT#: length 1.7
  BOTTOM w0.107: U49.30 98.94,35.47 R381.2
LAN5_CBOT: length 1.9
  BOTTOM w0.229: C206.2 102.23,31.84 101.41,31.84 101.29,31.72 U49.37
LAN5_CT1_A+_V-:
  vias: v1(93.47,11.23) v1(94.11,11.23)
LAN5_CT2_A-_V+:
  vias: v1(97.38,11.25) v1(98.02,11.25)
LAN5_CTOP: length 1.9
  BOTTOM w0.229: U49.40 101.79,30.22
  BOTTOM w0.305: 101.79,30.22 102.07,30.22 C206.1
LAN5_DEV_OFF: length 2.5
  TOP w0.107: R366.1 98.04,34.92 97.92,35.05 v1(97.92,35.38)
  BOTTOM w0.107: U49.28 97.94,35.36 v1(97.92,35.38) R364.2
LAN5_LINK_100#: length 2.1
  BOTTOM w0.107: U49.31 99.44,35.05 100.36,35.97 R384.2
LAN5_LINK_1000#: length 1.8
  BOTTOM w0.107: R385.2 101.18,33.72 U49.33
LAN5_MDI0+: length 8.3
  BOTTOM w0.089: U49.58 95.44,25.03 95.55,24.92 95.55,24.57 95.12,24.14 95.12,23.65 95.01,23.54 D32.1 D32.10 95.01,22.16 95.12,22.05 95.12,20.89 96.32,19.7 96.32,19.1 95.96,18.74 U61.2
LAN5_MDI0+_T: length 9.9
  BOTTOM w0.089: U61.23 95.96,8.18 96.32,7.82 96.32,6.66 94.23,4.57 92.7,4.57 91.73,3.6 91.73,3.13 POE5.8
LAN5_MDI0-: length 8.3
  BOTTOM w0.089: U61.3 96.96,18.76 96.6,19.12 96.6,19.81 95.4,21.01 95.4,22.02 95.51,22.13 D32.9 D32.2 95.51,23.54 95.4,23.65 95.4,24.03 95.83,24.46 95.83,24.94 95.94,25.05 U49.57
LAN5_MDI0-_T: length 9.9
  BOTTOM w0.089: POE5.7 92.01,3.12 92.01,3.48 92.82,4.29 94.35,4.29 96.6,6.54 96.6,7.82 96.96,8.18 U61.22
LAN5_MDI1+: length 9.2
  BOTTOM w0.089: U49.55 96.94,24.88 97.05,24.77 97.05,24.45 96.62,24.02 96.62,23.65 96.51,23.54 D32.4 D32.7 96.51,22.16 96.62,22.05 96.62,21.47 98,20.1 98.46,20.1 99.32,19.24 99.32,19.07 98.96,18.71 U61.5
LAN5_MDI1+_T: length 8.6
  BOTTOM w0.089: POE5.6 95.73,3.13 95.73,3.54 99.32,7.13 99.32,7.87 98.96,8.23 U61.20
LAN5_MDI1-: length 9.2
  BOTTOM w0.089: U61.6 99.96,18.69 99.6,19.05 99.6,19.36 98.58,20.38 98.11,20.38 96.9,21.59 96.9,22.02 97.01,22.13 D32.6 D32.5 97.01,23.56 96.9,23.67 96.9,23.9 97.33,24.33 97.33,24.77 97.44,24.88 U49.54
LAN5_MDI1-_T: length 8.6
  BOTTOM w0.089: POE5.5 96.01,3.12 96.01,3.43 99.6,7.01 99.6,7.87 99.96,8.23 U61.19
LAN5_MDI2+: length 10.6
  BOTTOM w0.089: U49.53 97.94,24.88 98.05,24.77 98.05,24.25 98.42,23.88 98.42,23.75 98.31,23.64 D35.1 D35.10 98.31,22.21 98.42,22.1 98.42,21.46 100.08,19.81 102.1,19.81 102.32,19.59 102.32,19.09 101.96,18.73 U61.8
LAN5_MDI2+_T: length 8.2
  BOTTOM w0.089: U61.17 101.96,8.28 102.32,7.92 102.32,7.34 99.73,4.75 99.73,3.13 POE5.4
LAN5_MDI2-: length 10.6
  BOTTOM w0.089: U49.52 98.44,24.88 98.33,24.77 98.33,24.37 98.7,23.99 98.7,23.79 98.81,23.68 D35.2 D35.9 98.81,22.11 98.7,22 98.7,21.58 100.19,20.09 102.21,20.09 102.6,19.71 102.6,19.09 102.96,18.73 U61.9
LAN5_MDI2-_T: length 8.2
  BOTTOM w0.089: POE5.3 100.01,3.12 100.01,4.63 102.6,7.22 102.6,7.92 102.96,8.28 U61.16
LAN5_MDI3+: length 11.7
  BOTTOM w0.089: U49.50 99.44,25 99.55,24.89 99.55,24.58 99.92,24.21 99.92,23.67 99.81,23.56 D35.4 D35.7 99.81,22.23 99.92,22.12 99.92,21.86 100.95,20.83 103.83,20.83 105.32,19.34 105.32,19.07 104.96,18.71 U61.11
LAN5_MDI3+_T: length 7.8
  BOTTOM w0.089: U61.14 104.96,8.2 105.32,7.84 105.32,6.51 103.73,4.92 103.73,3.13 POE5.2
LAN5_MDI3-: length 11.7
  BOTTOM w0.089: U61.12 105.96,18.66 105.6,19.02 105.6,19.45 103.94,21.11 101.07,21.11 100.2,21.97 100.2,22.1 100.31,22.21 D35.6 D35.5 100.31,23.56 100.2,23.67 100.2,24.32 99.83,24.7 99.83,24.89 99.94,25 U49.49
LAN5_MDI3-_T: length 7.8
  BOTTOM w0.089: POE5.1 104.01,3.12 104.01,4.81 105.6,6.4 105.6,7.84 105.96,8.2 U61.13
LAN5_NVM_CS: length 1.4
  TOP w0.107: U50.1 89.78,37.07 v1(89.92,37.21)
  BOTTOM w0.107: R380.1 v1(89.92,37.21)
LAN5_NVM_SI: length 5.8
  TOP w0.107: U50.5 88.28,32.12 v1(88.77,31.62) 88.8,31.65 R386.2
  BOTTOM w0.107: R377.1 v1(88.77,31.62) 88.27,32.13 R387.1
LAN5_NVM_SK: length 3.6
  TOP w0.107: v1(88.77,32.26) 88.77,32.89 88.78,32.89 U50.6
  BOTTOM w0.107: R383.2 88.9,33.02 88.77,32.89 v1(88.77,32.26) R378.1
LAN5_NVM_SO: length 1.4
  TOP w0.107: v1(89.28,37.21) U50.2
  BOTTOM w0.107: R379.1 89.28,37.21 v1(89.28,37.21)
LAN5_PWR_GOOD: length 1.5
  BOTTOM w0.107: R371.2 90.42,26.29 90.55,26.16 91.06,26.16 91.12,26.22 U49.1
LAN5_VDD0P9_OUT: length 3.9
  TOP w0.508: RZ133.1 100.71,32.16 C202.1 100.69,31.88 101.19,31.37 v1(101.6,31.37)
  BOTTOM w0.254: U49.38 101.45,31.22 v1(101.6,31.37)
LAN5_VDD1P5_OUT: length 3.8
  TOP w0.508: RZ140.1 101.22,29.95 C203.1 100.9,30.7 v1(101.6,30.7)
  BOTTOM w0.254: U49.39 101.57,30.72 v1(101.6,30.7)
LAN5_XTAL1: length 5.6
  BOTTOM w0.203: X6.1 102.93,24.95 103.21,25.24 C210.1 103.49,26.31 R382.2 103.3,27.12 101.28,27.12 101.18,27.22 U49.46
LAN5_XTAL2: length 2.9
  BOTTOM w0.203: U49.45 101.22,27.72 101.46,27.48 103.42,27.48 RB18.1
LAN6_ACT#: length 1.7
  BOTTOM w0.107: U51.30 117.23,35.47 R405.2
LAN6_CBOT: length 1.9
  BOTTOM w0.229: U51.37 119.58,31.72 119.69,31.84 120.18,31.84 120.43,31.58 C216.2
LAN6_CT1_A+_V-:
  vias: v1(113.59,11.23) v1(114.22,11.23)
LAN6_CT2_A-_V+:
  vias: v1(117.6,11.28) v1(118.24,11.28)
LAN6_CTOP: length 1.9
  BOTTOM w0.229: U51.40 120.08,30.22
  BOTTOM w0.305: C216.1 120.35,30.22 120.08,30.22
LAN6_DEV_OFF: length 2.5
  TOP w0.107: R390.1 116.33,34.77 116.2,34.9 v1(116.2,35.38)
  BOTTOM w0.107: U51.28 116.23,35.36 v1(116.2,35.38) R389.2
LAN6_LINK_100#: length 2.1
  BOTTOM w0.107: R408.2 118.64,35.97 117.73,35.05 U51.31
LAN6_LINK_1000#: length 1.8
  BOTTOM w0.107: R409.2 119.47,33.72 U51.33
LAN6_MDI0+: length 9.6
  BOTTOM w0.089: U62.2 116.15,18.64 116.51,19 116.51,19.09 116.05,19.54 115.15,19.54 113.41,21.29 113.41,22.07 113.3,22.18 D37.10 D37.1 113.3,23.54 113.41,23.65 113.41,24.14 113.84,24.57 113.84,24.94 113.73,25.05 U51.58
LAN6_MDI0+_T: length 10.2
  BOTTOM w0.089: U62.23 116.15,8.18 116.51,7.82 116.51,6.54 114.41,4.45 112.58,4.45 111.73,3.6 111.73,3.13 POE6.8
LAN6_MDI0-: length 9.6
  BOTTOM w0.089: U62.3 117.15,18.64 116.79,19 116.79,19.2 116.17,19.82 115.27,19.82 113.69,21.4 113.69,22.05 113.8,22.16 D37.9 D37.2 113.8,23.54 113.69,23.65 113.69,24.03 114.12,24.46 114.12,24.96 114.23,25.07 U51.57
LAN6_MDI0-_T: length 10.2
  BOTTOM w0.089: POE6.7 112.01,3.13 112.01,3.48 112.69,4.17 114.53,4.17 116.79,6.43 116.79,7.82 117.15,8.18 U62.22
LAN6_MDI1+: length 11.3
  BOTTOM w0.089: U51.55 115.23,25.03 115.34,24.92 115.34,24.45 114.91,24.02 114.91,23.65 114.8,23.54 D37.4 D37.7 114.8,21.93 114.91,21.82 114.91,21.14 115.4,20.65 116.26,20.65 117.6,19.3 119.42,19.3 119.51,19.22 119.51,19.09 119.15,18.73 U62.5
LAN6_MDI1+_T: length 8.7
  BOTTOM w0.089: POE6.6 115.73,3.13 115.73,3.84 119.51,7.62 119.51,7.87 119.15,8.23 U62.20
LAN6_MDI1-: length 11.3
  BOTTOM w0.089: U62.6 120.15,18.69 119.79,19.05 119.79,19.33 119.54,19.58 117.72,19.58 116.37,20.93 115.52,20.93 115.19,21.26 115.19,21.82 115.3,21.93 D37.6 D37.5 115.3,23.56 115.19,23.67 115.19,23.9 115.62,24.33 115.62,24.92 115.73,25.03 U51.54
LAN6_MDI1-_T: length 8.7
  BOTTOM w0.089: POE6.5 116.01,3.13 116.01,3.73 119.79,7.51 119.79,7.87 120.15,8.23 U62.19
LAN6_MDI2+: length 12.2
  BOTTOM w0.089: U51.53 116.23,25.12 116.34,25.01 116.34,24.25 116.71,23.88 116.71,23.62 116.6,23.51 D39.1 D39.10 116.6,22.18 116.71,22.07 116.71,21.56 118.01,20.27 121.5,20.27 122.51,19.26 122.51,19.03 122.15,18.67 U62.8
LAN6_MDI2+_T: length 8.3
  BOTTOM w0.089: U62.17 122.15,8.28 122.51,7.92 122.51,7.19 119.73,4.41 119.73,3.13 POE6.4
LAN6_MDI2-: length 12.2
  BOTTOM w0.089: U51.52 116.73,25.12 116.62,25.01 116.62,24.37 116.99,23.99 116.99,23.62 117.1,23.51 D39.2 D39.9 117.1,22.18 116.99,22.07 116.99,21.68 118.12,20.55 121.62,20.55 122.79,19.37 122.79,19.02 123.15,18.66 U62.9
LAN6_MDI2-_T: length 8.3
  BOTTOM w0.089: U62.16 123.15,8.28 122.79,7.92 122.79,7.08 120.01,4.3 120.01,3.13 POE6.3
LAN6_MDI3+: length 13.7
  BOTTOM w0.089: U51.50 117.73,25.07 117.84,24.96 117.84,24.58 118.21,24.21 118.21,23.67 118.1,23.56 D39.4 D39.7 118.1,22.19 118.21,22.08 118.21,21.89 118.87,21.23 123.77,21.23 125.51,19.49 125.51,19.06 125.15,18.7 U62.11
LAN6_MDI3+_T: length 7.8
  BOTTOM w0.089: POE6.2 123.73,3.13 123.73,4.86 125.51,6.64 125.51,7.84 125.15,8.2 U62.14
LAN6_MDI3-: length 13.7
  BOTTOM w0.089: U51.49 118.23,25.09 118.12,24.98 118.12,24.7 118.49,24.32 118.49,23.67 118.6,23.56 D39.5 D39.6 118.6,22.18 118.49,22.07 118.49,22.01 118.99,21.51 123.88,21.51 125.79,19.61 125.79,19.09 126.15,18.73 U62.12
LAN6_MDI3-_T: length 7.8
  BOTTOM w0.089: POE6.1 124.01,3.13 124.01,4.74 125.79,6.52 125.79,7.84 126.15,8.2 U62.13
LAN6_NVM_CS: length 2
  TOP w0.107: v1(108.21,37.47) 108.21,37.22 108.07,37.07 U52.1
  BOTTOM w0.107: R404.1 108.2,37.46 v1(108.21,37.47)
LAN6_NVM_SI: length 5.8
  TOP w0.107: U52.5 106.56,32.12 v1(107.06,31.62) R410.2
  BOTTOM w0.107: R401.1 v1(107.06,31.62) 106.55,32.13 R411.1
LAN6_NVM_SK: length 3.6
  TOP w0.107: v1(107.06,32.26) 107.07,32.26 U52.6
  BOTTOM w0.107: R402.1 v1(107.06,32.26) 107.06,32.89 107.19,33.02 R407.2
LAN6_NVM_SO: length 1.9
  TOP w0.107: v1(107.57,37.47) 107.56,37.46 U52.2
  BOTTOM w0.107: R403.1 v1(107.57,37.47)
LAN6_PWR_GOOD: length 1.5
  BOTTOM w0.107: U51.1 109.41,26.22 109.35,26.16 108.84,26.16 108.71,26.29 R395.2
LAN6_VDD0P9_OUT: length 3.9
  TOP w0.508: RZ134.1 119,32.16 C211.1 118.97,31.88 119.48,31.37 v1(119.89,31.37)
  BOTTOM w0.229: U51.38 119.74,31.22 v1(119.89,31.37)
LAN6_VDD1P5_OUT: length 3.8
  TOP w0.508: RZ141.1 119.51,29.95 C212.1 119.19,30.7 v1(119.89,30.7)
  BOTTOM w0.229: v1(119.89,30.7) 119.86,30.72 U51.39
LAN6_XTAL1: length 5.6
  BOTTOM w0.203: X7.1 121.5,24.71 C219.1 121.78,26.31 R406.2 121.59,27.12 119.57,27.12 119.46,27.22 U51.46
LAN6_XTAL2: length 2.9
  BOTTOM w0.203: RB19.1 121.7,27.48 119.75,27.48 119.51,27.72 U51.45
LAN7_ACT#: length 1.7
  BOTTOM w0.107: U53.30 135.52,35.85 R429.2
LAN7_CBOT: length 1.9
  BOTTOM w0.229: C225.2 138.81,32.22 137.98,32.22 137.86,32.1 U53.37
LAN7_CT1_A+_V-:
  vias: v1(133.86,11.23) v1(134.49,11.23)
LAN7_CT2_A-_V+:
  vias: v1(137.74,11.25) v1(138.38,11.25)
LAN7_CTOP: length 1.9
  BOTTOM w0.229: 138.37,30.6 U53.40
  BOTTOM w0.305: 138.37,30.6 138.64,30.6 C225.1
LAN7_DEV_OFF: length 2.5
  TOP w0.107: R414.1 134.62,35.15 134.49,35.28 v1(134.49,35.76)
  BOTTOM w0.107: R412.2 v1(134.49,35.76) 134.52,35.74 U53.28
LAN7_LINK_100#: length 2.1
  BOTTOM w0.107: R432.2 136.93,36.35 136.02,35.43 U53.31
LAN7_LINK_1000#: length 1.8
  BOTTOM w0.107: R433.2 137.76,34.1 U53.33
LAN7_MDI0+: length 11.9
  BOTTOM w0.089: U63.2 136.34,18.64 136.7,19 136.7,19.11 136.51,19.3 133.79,19.3 131.7,21.4 131.7,22.45 131.59,22.56 D42.10 D42.1 131.59,23.94 131.7,24.05 131.7,24.52 132.13,24.95 132.13,25.32 132.02,25.43 U53.58
LAN7_MDI0+_T: length 10.3
  BOTTOM w0.089: POE7.8 131.73,3.13 131.73,3.47 132.45,4.19 134.37,4.19 136.7,6.53 136.7,7.82 136.34,8.18 U63.23
LAN7_MDI0-: length 11.9
  BOTTOM w0.089: U53.57 132.52,25.45 132.41,25.34 132.41,24.84 131.98,24.41 131.98,24.05 132.09,23.94 D42.2 D42.9 132.09,22.57 131.98,22.46 131.98,21.51 133.91,19.58 136.63,19.58 136.98,19.23 136.98,19 137.34,18.64 U63.3
LAN7_MDI0-_T: length 10.3
  BOTTOM w0.089: U63.22 137.34,8.18 136.98,7.82 136.98,6.41 134.48,3.91 132.56,3.91 132.01,3.36 132.01,3.13 POE7.7
LAN7_MDI1+: length 13.4
  BOTTOM w0.089: U53.55 133.52,25.41 133.63,25.3 133.63,24.83 133.2,24.4 133.2,24.16 133.09,24.05 D42.4 D42.7 133.09,22.59 133.2,22.48 133.2,21.55 134.55,20.19 136.96,20.19 137.74,19.41 139.55,19.41 139.7,19.25 139.7,19.03 139.34,18.67 U63.5
LAN7_MDI1+_T: length 8.7
  BOTTOM w0.089: U63.20 139.34,8.23 139.7,7.87 139.7,7.5 135.73,3.52 135.73,3.13 POE7.6
LAN7_MDI1-: length 13.4
  BOTTOM w0.089: U63.6 140.34,18.68 139.98,19.04 139.98,19.37 139.67,19.68 137.86,19.68 137.07,20.47 134.67,20.47 133.48,21.67 133.48,22.45 133.59,22.56 D42.6 D42.5 133.59,23.94 133.48,24.05 133.48,24.28 133.91,24.71 133.91,25.3 134.02,25.41 U53.54
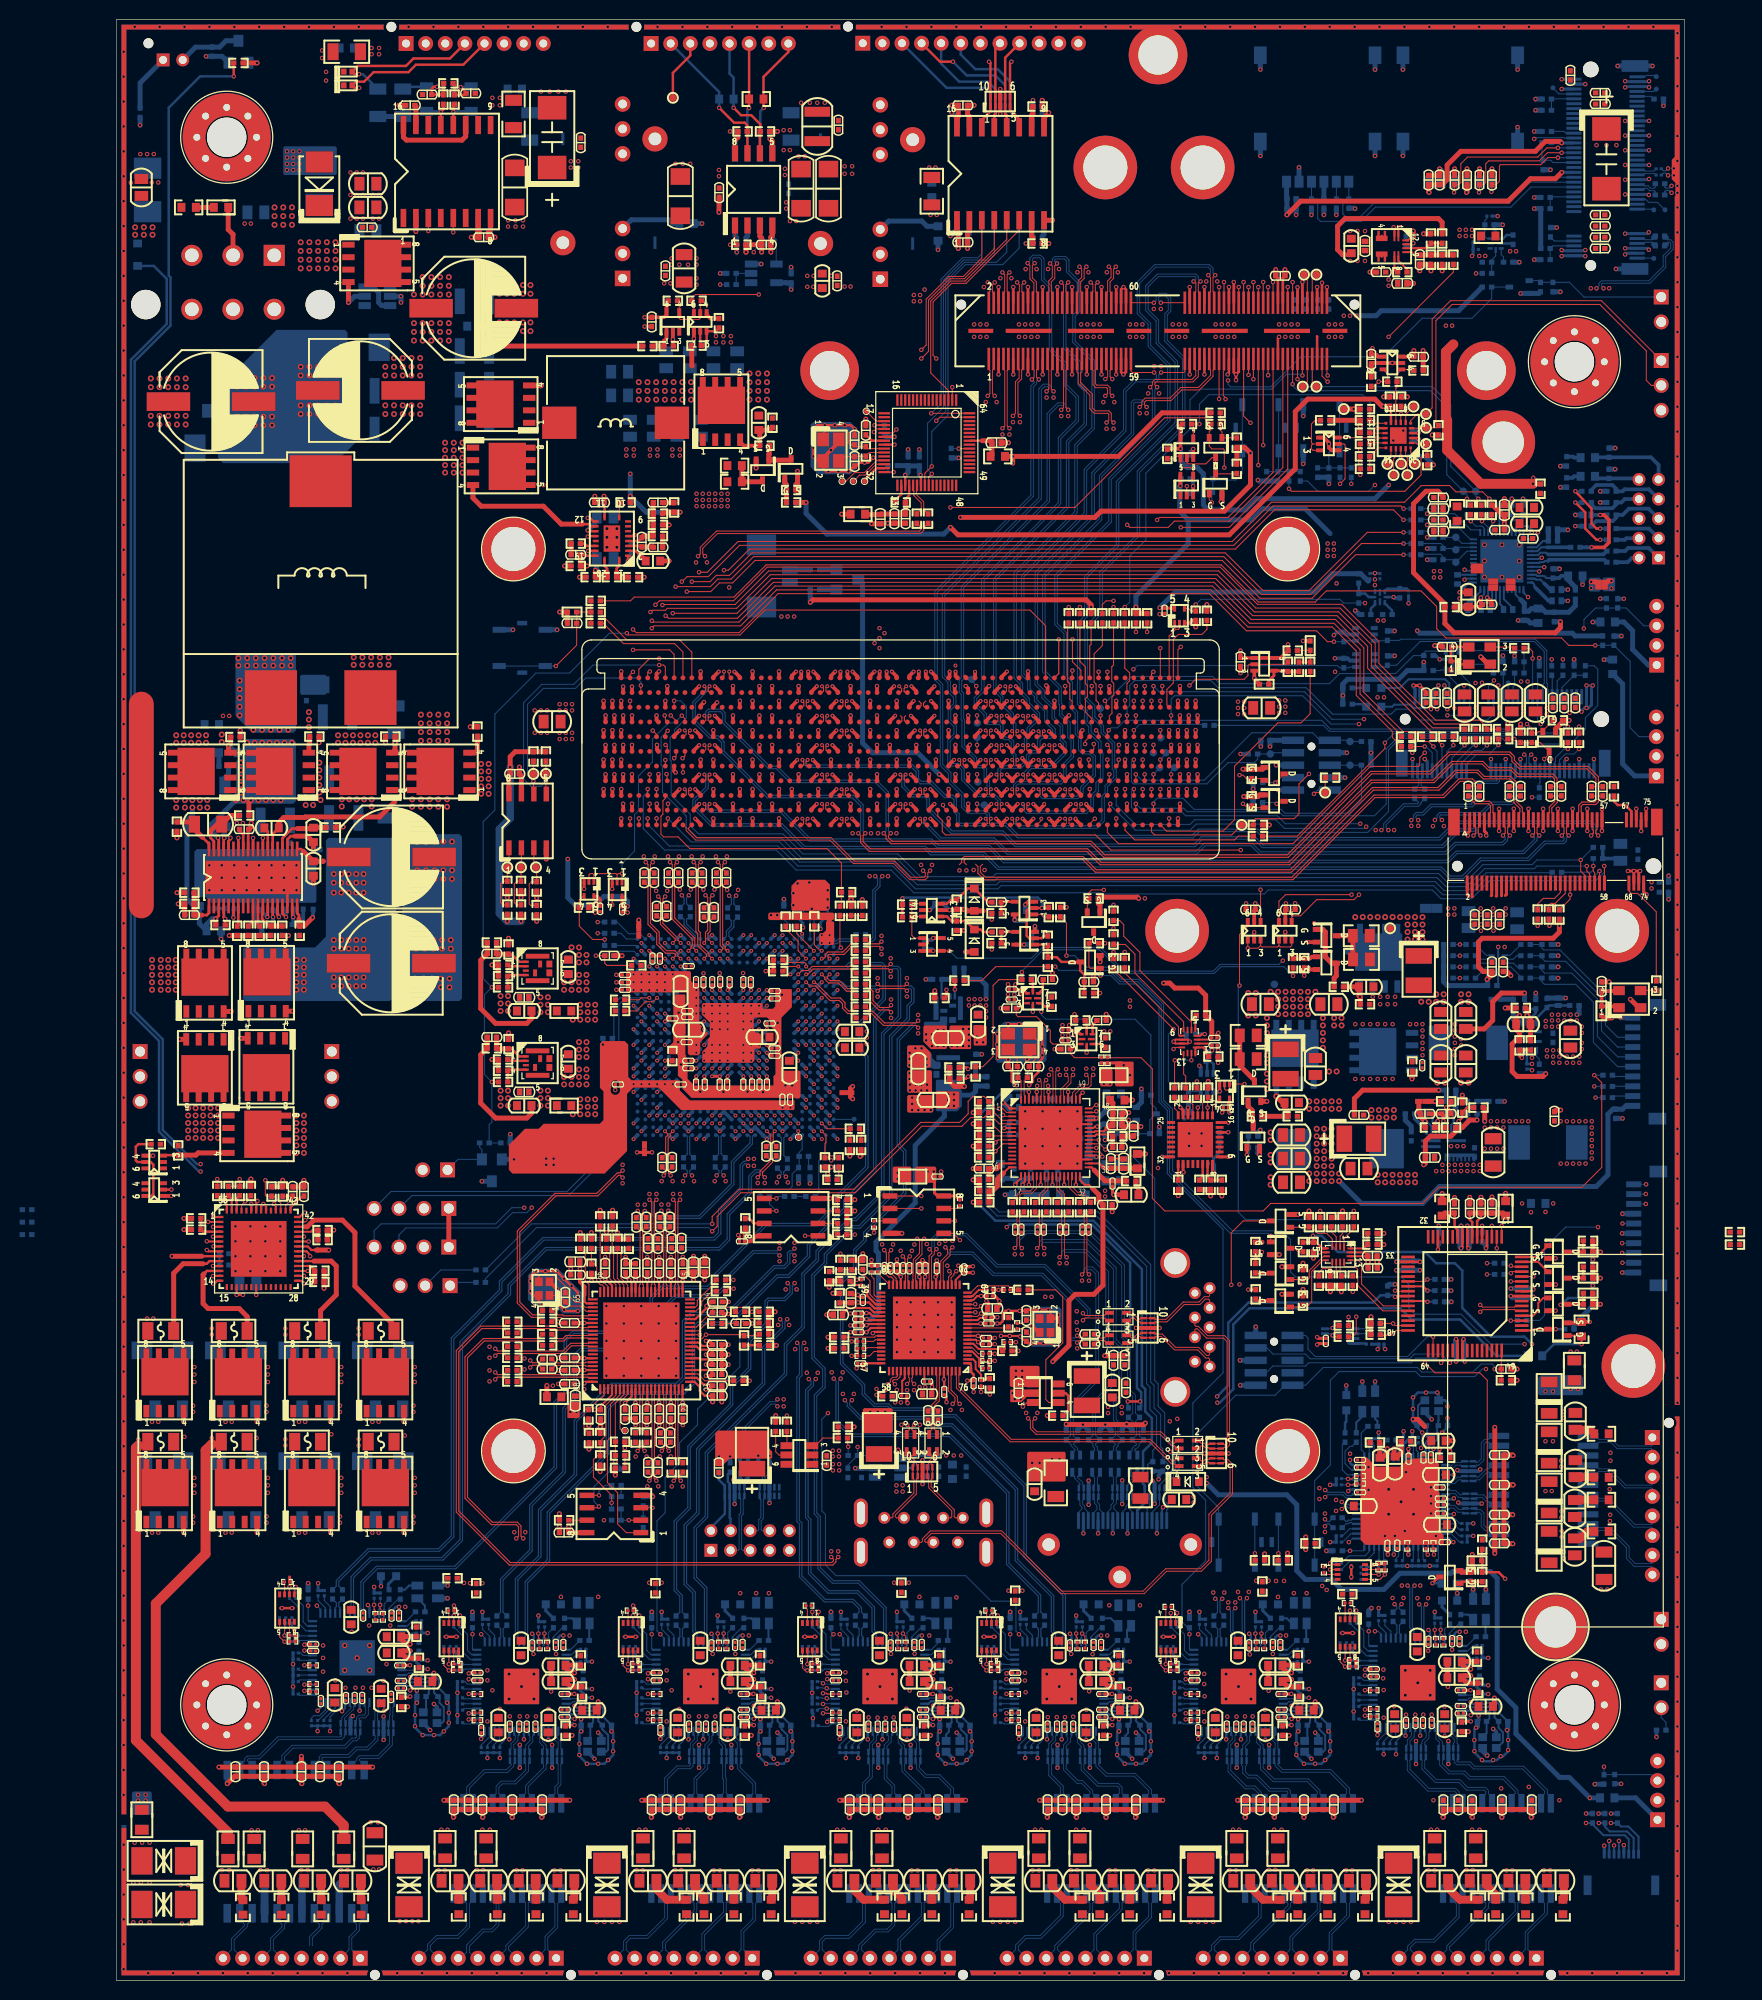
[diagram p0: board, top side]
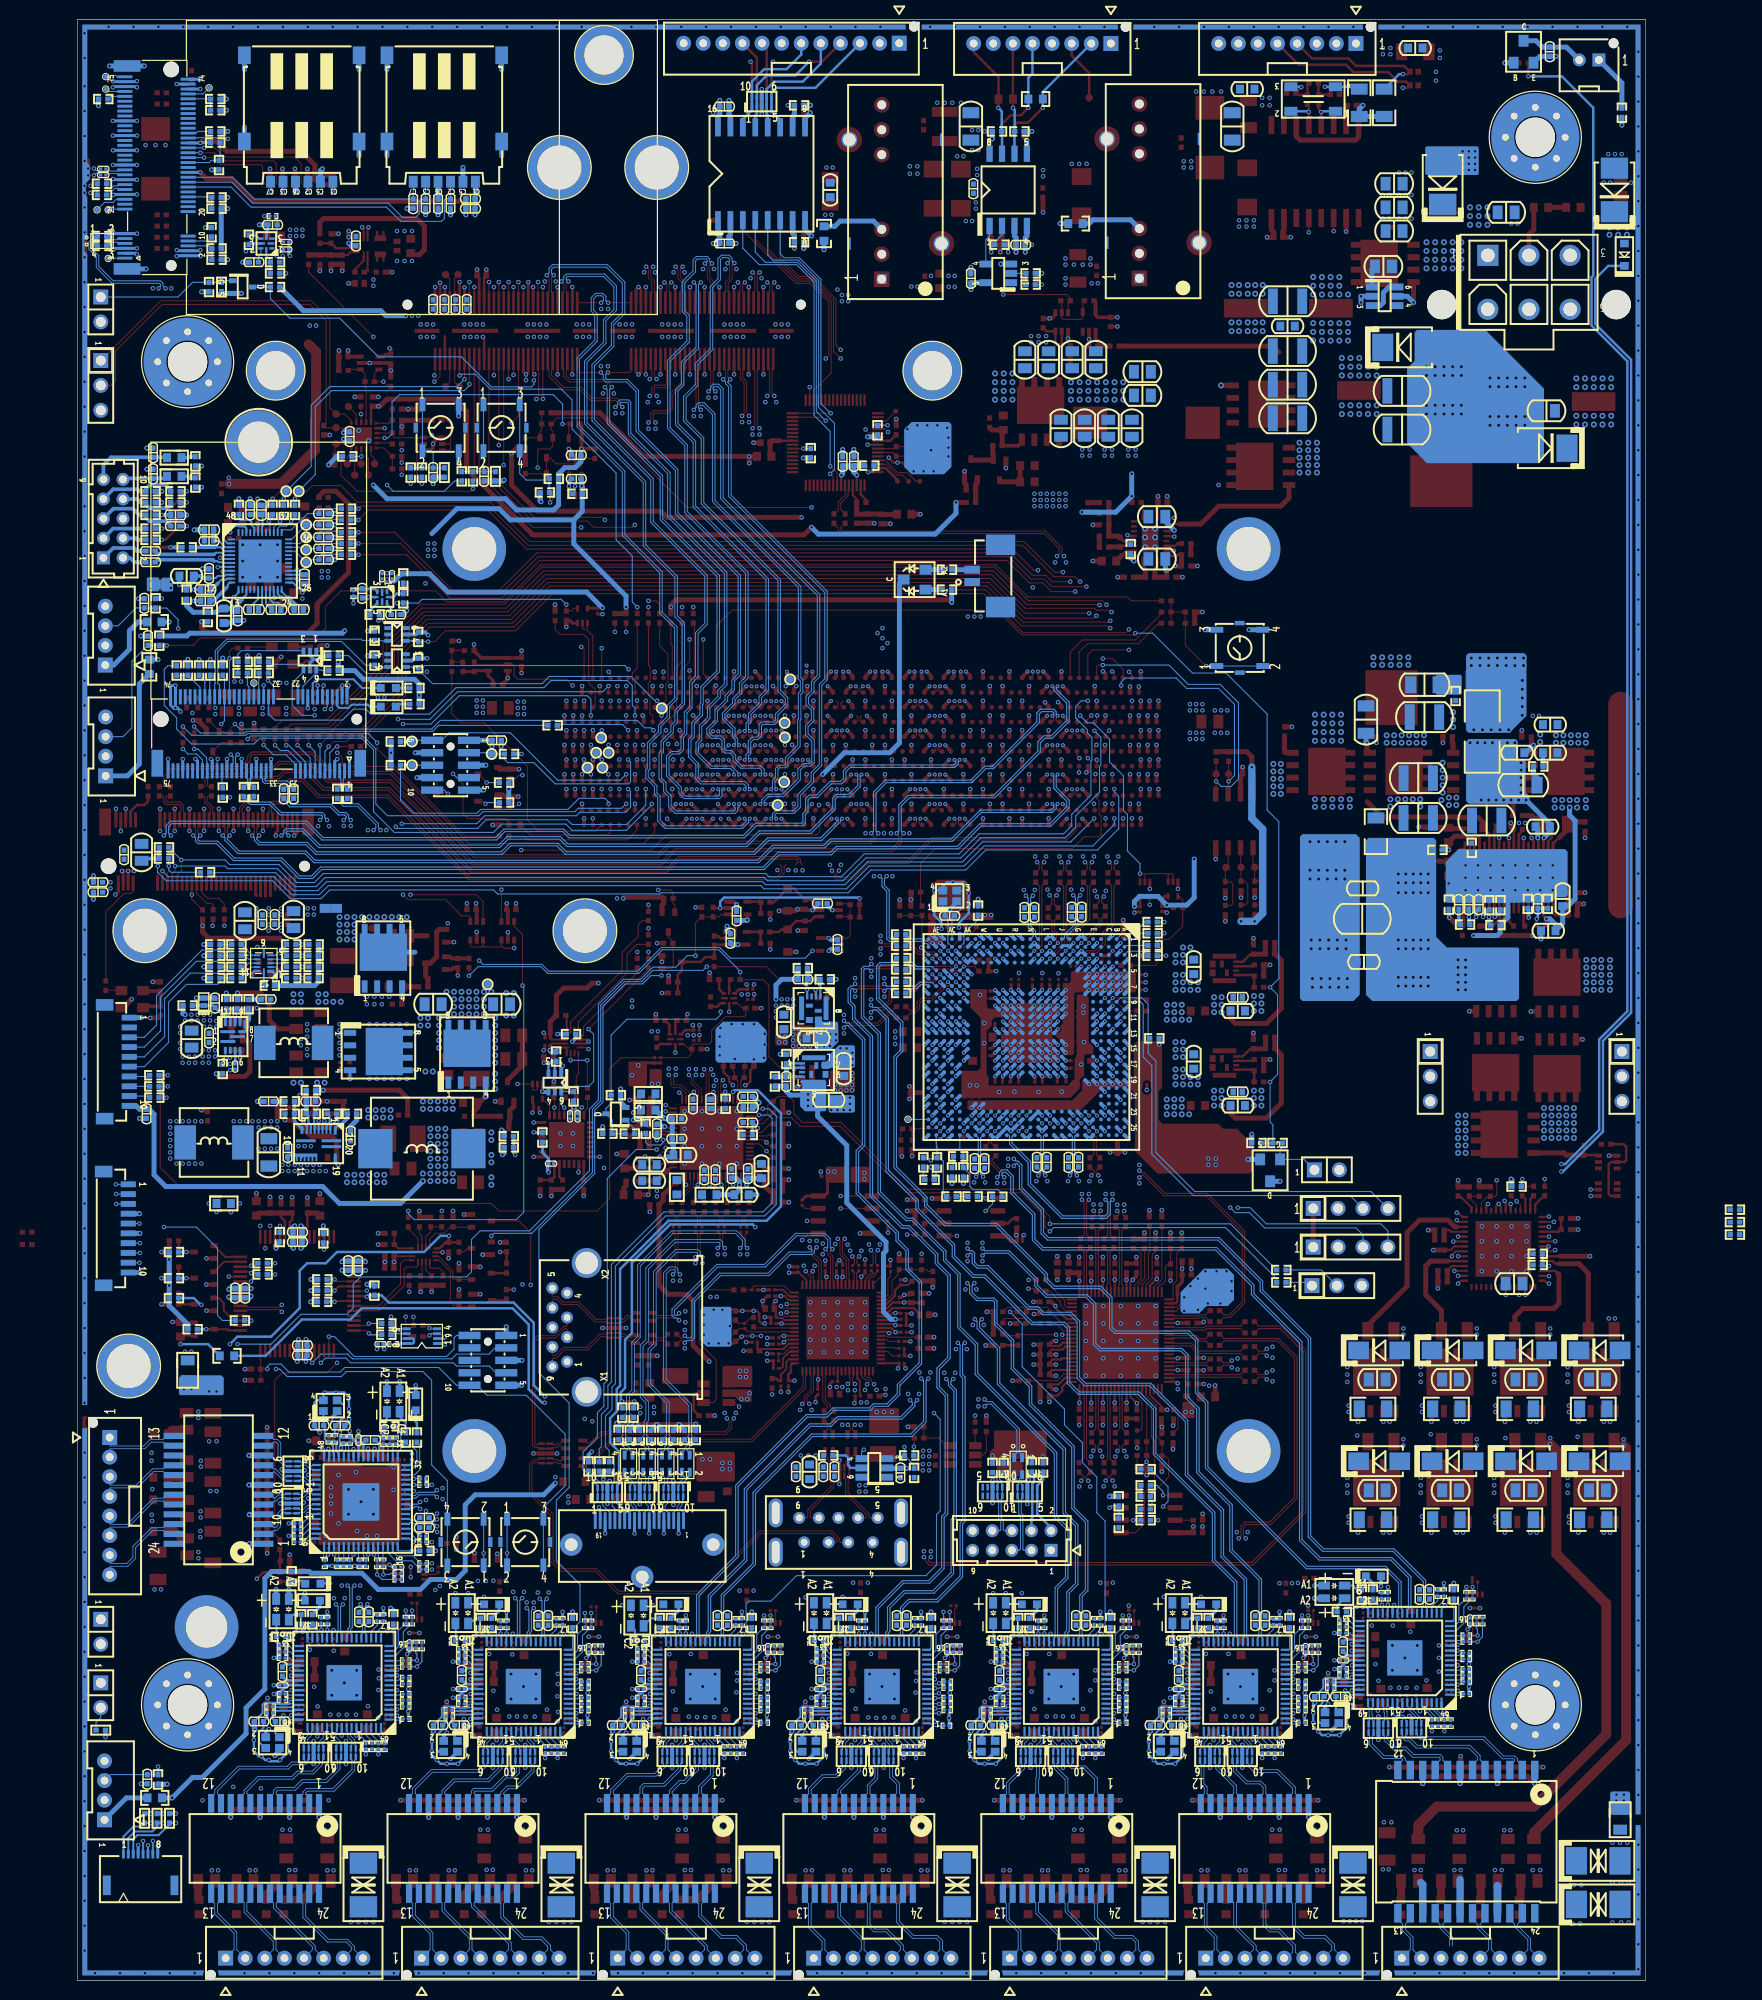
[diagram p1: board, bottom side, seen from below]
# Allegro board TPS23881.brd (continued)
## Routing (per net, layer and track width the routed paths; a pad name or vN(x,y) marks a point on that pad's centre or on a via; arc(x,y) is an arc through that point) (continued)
LAN7_MDI1-_T: length 8.7
  BOTTOM w0.089: POE7.5 136.01,3.13 136.01,3.41 139.98,7.38 139.98,7.87 140.34,8.23 U63.19
LAN7_MDI2+: length 14.3
  BOTTOM w0.089: U63.8 142.34,18.7 142.7,19.06 142.7,19.27 141.45,20.52 138,20.52 137.45,21.07 135.9,21.07 135,21.97 135,22.44 134.89,22.55 D43.10 D43.1 134.89,23.89 135,24 135,24.26 134.63,24.63 134.63,25.39 134.52,25.5 U53.53
LAN7_MDI2+_T: length 8.3
  BOTTOM w0.089: U63.17 142.34,8.28 142.7,7.92 142.7,7.07 139.73,4.09 139.73,3.13 POE7.4
LAN7_MDI2-: length 14.3
  BOTTOM w0.089: U53.52 135.02,25.5 134.91,25.39 134.91,24.75 135.28,24.37 135.28,24 135.39,23.89 D43.2 D43.9 135.39,22.56 135.28,22.45 135.28,22.09 136.02,21.35 137.57,21.35 138.11,20.8 141.57,20.8 142.98,19.39 142.98,19.06 143.34,18.7 U63.9
LAN7_MDI2-_T: length 8.3
  BOTTOM w0.089: U63.16 143.34,8.28 142.98,7.92 142.98,6.95 140.01,3.98 140.01,3.13 POE7.3
LAN7_MDI3+: length 15.7
  BOTTOM w0.089: U63.11 145.34,18.7 145.7,19.06 145.7,19.32 143.46,21.56 138.46,21.56 138.02,22 136.75,22 136.5,22.25 136.5,22.48 136.39,22.59 D43.7 D43.4 136.39,24.15 136.5,24.26 136.5,24.59 136.13,24.96 136.13,25.34 136.02,25.45 U53.50
LAN7_MDI3+_T: length 7.9
  BOTTOM w0.089: U63.14 145.34,8.2 145.7,7.84 145.7,6.89 143.73,4.92 143.73,3.13 POE7.2
LAN7_MDI3-: length 15.7
  BOTTOM w0.089: U63.12 146.34,18.7 145.98,19.06 145.98,19.44 143.58,21.84 138.57,21.84 138.14,22.28 136.87,22.28 136.78,22.36 136.78,22.48 136.89,22.59 D43.6 D43.5 136.89,24.08 136.78,24.19 136.78,24.7 136.41,25.08 136.41,25.36 136.52,25.47 U53.49
LAN7_MDI3-_T: length 7.9
  BOTTOM w0.089: POE7.1 144.01,3.13 144.01,4.8 145.98,6.78 145.98,7.84 146.34,8.2 U63.13
LAN7_NVM_CS: length 1.7
  TOP w0.107: v1(126.49,37.72) 126.35,37.58 U54.1
  BOTTOM w0.107: R428.1 v1(126.49,37.72)
LAN7_NVM_SI: length 5.8
  TOP w0.107: U54.5 124.85,32.5 v1(125.35,32) R434.2
  BOTTOM w0.107: R425.1 v1(125.35,32) 124.84,32.51 R435.1
LAN7_NVM_SK: length 3.6
  TOP w0.107: U54.6 125.35,32.64 v1(125.35,32.64)
  BOTTOM w0.107: R426.1 v1(125.35,32.64) 125.35,33.27 125.48,33.4 R431.2
LAN7_NVM_SO: length 1.6
  TOP w0.107: v1(125.85,37.72) U54.2
  BOTTOM w0.107: R427.1 125.86,37.71 v1(125.85,37.72)
LAN7_PWR_GOOD: length 1.5
  BOTTOM w0.107: U53.1 127.69,26.6 127.64,26.54 126.89,26.54 R419.2
LAN7_VDD0P9_OUT: length 3.9
  TOP w0.508: v1(138.18,31.75) 137.77,31.75 137.26,32.26 C220.1 137.29,32.54 RZ129.1
  BOTTOM w0.229: v1(138.18,31.75) 138.03,31.6 U53.38
LAN7_VDD1P5_OUT: length 3.8
  TOP w0.508: RZ136.1 137.79,30.33 C221.1 137.48,31.08 v1(138.18,31.08)
  BOTTOM w0.229: U53.39 138.15,31.1 v1(138.18,31.08)
LAN7_XTAL1: length 5.7
  BOTTOM w0.203: U53.46 137.75,27.6 137.86,27.5 139.88,27.5 R430.2 140.07,26.7 C228.1 139.79,25.21 X8.1
LAN7_XTAL2: length 2.9
  BOTTOM w0.203: U53.45 137.79,28.1 138.03,27.86 139.99,27.86 RB20.1
LAN8_ACT#: length 4.6
  BOTTOM w0.107: R454.2 125.07,54.61 125.07,52.07 125.57,51.57 U55.30
LAN8_CBOT: length 2
  BOTTOM w0.229: U55.37 129.31,53.92 129.2,54.03 129.2,54.7 C234.2
LAN8_CTOP: length 1.9
  BOTTOM w0.229: 130.81,54.42 U55.40
  BOTTOM w0.305: 130.81,54.42 130.81,54.86 C234.1
LAN8_DEV_OFF: length 2.5
  TOP w0.107: v1(125.66,50.55) 126.14,50.55 126.26,50.67 R438.1
  BOTTOM w0.107: R437.2 v1(125.66,50.55) 125.68,50.57 U55.28
LAN8_LINK_100#: length 4.2
  BOTTOM w0.107: R456.2 126.09,54.48 125.86,54.48 125.35,53.98 125.35,52.7 125.99,52.07 U55.31
LAN8_LINK_1000#: length 3.6
  BOTTOM w0.107: R457.2 127,55.83 127,54.13 127.31,53.81 U55.33
LAN8_MDI0+: length 7.4
  BOTTOM w0.089: U55.58 135.98,48.07 136.09,48.18 136.41,48.18 136.84,47.75 137.42,47.75 137.53,47.64 D44.1 D44.10 138.73,47.75 139.05,47.75 139.24,47.56 139.24,46.3 139.65,45.9 139.95,45.9 140.31,45.54 U64.2
LAN8_MDI0+_T: length 9.7
  BOTTOM w0.089: U64.23 150.87,45.54 151.23,45.9 152.3,45.9 154.05,44.15 154.05,43.03 154.84,42.23 156.61,42.23 156.7,42.15 POE8.8
LAN8_MDI0-: length 7.4
  BOTTOM w0.089: U55.57 135.96,48.57 136.07,48.46 136.53,48.46 136.96,48.03 137.36,48.03 137.47,48.14 D44.2 D44.9 138.73,48.03 139.17,48.03 139.52,47.68 139.52,46.42 139.77,46.18 139.93,46.18 140.29,46.54 U64.3
LAN8_MDI0-_T: length 9.7
  BOTTOM w0.089: POE8.7 156.7,42.6 156.61,42.51 154.96,42.51 154.33,43.14 154.33,44.26 152.41,46.18 151.23,46.18 150.87,46.54 U64.22
LAN8_MDI1+: length 6
  BOTTOM w0.089: U55.55 136,49.57 136.12,49.68 136.53,49.68 136.96,49.25 137.29,49.25 137.4,49.14 D44.4 D44.7 138.69,49.14 138.8,49.25 139.34,49.25 139.7,48.9 139.9,48.9 140.26,48.54 U64.5
LAN8_MDI1+_T: length 8.6
  BOTTOM w0.089: U64.20 150.9,48.54 151.26,48.9 152.13,48.9 154.79,46.23 156.61,46.23 156.7,46.15 POE8.6
LAN8_MDI1-: length 6
  BOTTOM w0.089: U64.6 140.27,49.54 139.91,49.18 139.81,49.18 139.46,49.53 138.79,49.53 138.67,49.64 D44.6 D44.5 137.4,49.64 137.29,49.53 137.07,49.53 136.64,49.96 136.12,49.96 136,50.07 U55.54
LAN8_MDI1-_T: length 8.6
  BOTTOM w0.089: U64.19 150.89,49.54 151.25,49.18 152.24,49.18 154.91,46.51 156.61,46.51 156.7,46.6 POE8.5
LAN8_MDI2+: length 6.2
  BOTTOM w0.089: U64.8 140.33,51.54 140,51.87 139.87,51.87 139.05,51.05 138.73,51.05 138.62,50.94 D45.10 D45.1 137.3,50.94 137.19,51.05 136.91,51.05 136.53,50.68 136.02,50.68 135.91,50.57 U55.53
LAN8_MDI2+_T: length 8.2
  BOTTOM w0.089: POE8.4 156.7,50.15 156.61,50.23 153.88,50.23 152.22,51.9 151.21,51.9 150.85,51.54 U64.17
LAN8_MDI2-: length 6.2
  BOTTOM w0.089: U55.52 135.91,51.07 136.02,50.96 136.42,50.96 136.79,51.33 137.16,51.33 137.27,51.44 D45.2 D45.9 138.65,51.44 138.76,51.33 138.94,51.33 139.75,52.15 139.95,52.15 140.35,52.54 U64.9
LAN8_MDI2-_T: length 8.2
  BOTTOM w0.089: POE8.3 156.7,50.6 156.61,50.51 154,50.51 152.33,52.18 151.23,52.18 150.87,52.54 U64.16
LAN8_MDI3+: length 7.8
  BOTTOM w0.089: U64.11 140.36,54.54 140,54.9 139.71,54.9 139.52,54.71 139.52,53.09 138.99,52.55 138.73,52.55 138.63,52.44 D45.7 D45.4 137.27,52.44 137.16,52.55 136.66,52.55 136.29,52.18 136.08,52.18 135.96,52.07 U55.50
LAN8_MDI3+_T: length 7.8
  BOTTOM w0.089: U64.14 150.88,54.54 151.24,54.9 152.44,54.9 153.11,54.23 156.61,54.23 156.7,54.15 POE8.2
LAN8_MDI3-: length 7.8
  BOTTOM w0.089: U55.49 135.95,52.57 136.06,52.46 136.17,52.46 136.54,52.83 137.19,52.83 137.3,52.94 D45.5 D45.6 138.65,52.94 138.76,52.83 138.87,52.83 139.24,53.2 139.24,54.83 139.59,55.18 139.97,55.18 140.33,55.54 U64.12
LAN8_MDI3-_T: length 7.8
  BOTTOM w0.089: POE8.1 156.7,54.6 156.61,54.51 153.22,54.51 152.56,55.18 151.27,55.18 150.91,55.54 U64.13
LAN8_NVM_CS: length 1.4
  TOP w0.107: U56.1 123.96,42.41 v1(123.83,42.55)
  BOTTOM w0.107: R452.1 v1(123.83,42.55)
LAN8_NVM_SI: length 5.8
  TOP w0.107: R458.2 v1(129.41,41.4) 128.92,40.91 U56.5
  BOTTOM w0.107: R449.1 v1(129.41,41.4) 128.91,40.89 R459.1
LAN8_NVM_SK: length 3.6
  TOP w0.107: U56.6 128.77,41.41 v1(128.78,41.4)
  BOTTOM w0.107: R455.2 128.02,41.53 128.14,41.4 v1(128.78,41.4) R450.1
LAN8_NVM_SO: length 1.4
  TOP w0.107: U56.2 v1(123.83,41.91)
  BOTTOM w0.107: R451.1 123.83,41.91 v1(123.83,41.91)
LAN8_PWR_GOOD: length 1.5
  BOTTOM w0.107: R443.2 134.87,42.94 134.87,43.69 134.81,43.75 U55.1
LAN8_VDD0P9_OUT: length 3.9
  TOP w0.508: RZ105.1 128.88,53.34 C229.1 129.16,53.31 129.67,53.82 v1(129.67,54.23)
  BOTTOM w0.229: v1(129.67,54.23) 129.81,54.08 U55.38
LAN8_VDD1P5_OUT: length 3.8
  TOP w0.508: v1(130.34,54.23) 130.34,53.53 C230.1 130.56,53.31 131.09,53.85 RZ104.1
  BOTTOM w0.229: v1(130.34,54.23) 130.31,54.2 U55.39
LAN8_XTAL1: length 5.2
  BOTTOM w0.203: X9.1 134.89,57.16 134.86,57.14 C237.1 134.75,56.48 134.75,55.2 134.53,54.98 R453.2 134.37,54.97 133.91,54.52 133.91,53.89 133.81,53.8 U55.46
LAN8_XTAL2: length 1.8
  BOTTOM w0.203: U55.45 133.31,53.76 133.58,54.03 133.58,54.83 RB21.1
LAN_CLKN1: length 105.5
  BOTTOM w0.114: RZ184.2 76.87,103.57 78,103.57 78.2,103.37 78.2,100.17 75.77,97.74 75.77,94.79 76.43,94.13 76.43,83.01 73.3,79.88 73.3,79.12 71.4,77.22 66.19,77.22 61.04,72.06 61.04,71.56 60.3,70.82 55.58,70.82 54.43,69.67 54.43,66.62 54.05,66.24 46.56,66.24 45.67,65.35 45.67,60.02 44.65,59 44.65,52.38 34.51,42.24 26.51,42.24 24.93,40.66 24.93,37.94 24.81,37.82 U41.25
LAN_CLKN2: length 91.2
  TOP w0.114: v1(79.03,99.47) 78.8,99.24 77.88,99.24 77.19,99.93 77.19,100.89 76.92,101.16 76.67,101.16 76.43,101.4 RZ50.2
  BOTTOM w0.114: U43.25 41.58,34.89 41.7,35.01 41.7,40.66 43.94,42.9 43.94,47.75 49.96,53.77 49.96,58.34 51.64,60.02 57.76,60.02 58.75,61.01 58.75,66.6 59.28,67.13 62.53,67.13 67.36,71.96 68.53,71.96 70.48,73.91 70.48,75.04 74.19,78.74 74.19,79.58 77.24,82.63 77.24,98.12 78.36,99.24 78.8,99.24 v1(79.03,99.47)
LAN_CLKN3: length 81.8
  TOP w0.114: v1(78.99,102.96) 78.77,103.19 76.87,103.19 RZ48.2
  BOTTOM w0.114: v1(78.99,102.96) 79.22,103.19 79.64,103.19 79.76,103.07 79.76,98.32 78.05,96.61 78.05,80.45 75.36,77.75 74.72,77.75 71.37,74.4 71.37,73.53 69.93,72.09 69.93,66.7 68.14,64.91 68.14,61.91 64.52,58.29 60.07,53.85 60.07,47.35 58.93,46.21 58.93,41.02 59.99,39.96 59.99,35.01 59.86,34.89 U45.25
LAN_CLKN4: length 81.8
  TOP w0.114: v1(77.66,100.93) 77.9,101.17 80.42,101.17 v1(80.64,100.94)
  BOTTOM w0.114: v1(77.66,100.93) 77.43,101.16 76.87,101.16 RZ186.2 ; U47.25 78.15,34.89 78.27,35.01 78.27,37.93 75.69,40.51 73.05,40.51 71.56,42 71.56,47.21 71.2,47.57 71.2,59.72 72.05,60.57 72.05,62.34 70.94,63.45 70.94,71.96 72.21,73.23 72.21,74.1 75.09,76.97 75.75,76.97 78.87,80.09 78.87,96.33 80.66,98.12 80.66,99.42 81.11,99.87 81.11,101.06 81,101.17 80.87,101.17 v1(80.64,100.94)
LAN_CLKN5: length 87.1
  TOP w0.114: RZ54.2 76.87,98.87 77.15,98.87 78.36,97.66 81.56,97.66 v1(81.79,97.89)
  BOTTOM w0.114: v1(81.79,97.89) 81.56,97.66 81.29,97.66 79.65,96.02 79.65,85.16 80.29,84.53 80.29,80.37 76.23,76.31 76.23,75.54 75.21,74.53 75.21,72.62 73.86,71.28 73.86,62.89 76.08,60.67 76.08,59.76 77.29,58.55 78.69,58.55 79.09,58.14 82.8,58.14 83.49,57.45 85.52,57.45 92.58,50.39 92.58,43.2 96.56,39.22 96.56,35.01 96.44,34.89 U49.25
LAN_CLKN6: length 114.2
  TOP w0.114: RZ87.2 39.46,66.48 37.27,66.48 34.92,64.14 34.92,47.88 40.18,42.62 72.98,42.62 73.15,42.79 73.15,42.95 v1(72.92,43.18)
  IN1 w0.122: v1(72.92,43.18) 73.15,42.95 73.15,42.31 74.32,41.15 77.66,41.15 78.57,42.06 87.02,42.06 88.57,40.51 100.1,40.51 101.42,39.19 103.51,39.19 104.45,40.13 114.73,40.13 114.85,40.01 114.85,39.22 v1(114.62,38.99)
  BOTTOM w0.114: v1(114.62,38.99) 114.85,38.76 114.85,35.01 114.73,34.89 U51.25
LAN_CLKN7: length 135.3
  TOP w0.114: RZ93.2 43.01,65.21 37.53,65.21 35.81,63.5 35.81,49.28 38.35,46.74 40.89,46.74 41.27,46.35 41.27,45.31 v1(41.5,45.09)
  IN1 w0.122: v1(41.5,45.09) 41.27,44.86 41.27,44.44 41.4,44.32 53.41,44.32 58.87,38.86 61.73,38.86 63.11,37.48 69.07,37.48 69.72,36.83 83.67,36.83 86.85,33.66 95.63,33.66 96.52,32.77 100.71,32.77 101.6,33.66 114.7,33.66 115.59,34.54 131.21,34.54 133.14,36.47 133.14,38.13 v1(132.91,38.35)
  BOTTOM w0.114: v1(132.91,38.35) 133.14,38.13 133.14,35.48 133.02,35.36 U53.25
LAN_CLKN8: length 100.6
  TOP w0.114: RZ94.2 39.46,63.94 38.87,63.94 v1(38.65,63.72)
  IN1 w0.122: v1(123.32,49.3) 123.09,49.53 121.06,49.53 119.41,47.88 108.61,47.88 107.39,49.1 92.28,49.1 90.15,51.22 71.99,51.22 66.78,56.43 62.24,56.43 59.21,59.46 59.21,62.38 57.58,64.01 42.69,64.01 41.41,65.29 39.51,65.29 39.37,65.15 39.37,64.16 39.15,63.94 38.87,63.94 v1(38.65,63.72)
  BOTTOM w0.114: v1(123.32,49.3) 123.55,49.53 125.12,49.53 125.45,49.19 125.93,49.19 126.06,49.07 U55.25
LAN_CLKP1: length 105.9
  BOTTOM w0.114: RZ183.2 76.87,103.82 78.11,103.82 78.45,103.48 78.45,100.07 76.02,97.63 76.02,94.9 76.68,94.24 76.68,82.9 73.56,79.78 73.56,79.02 71.5,76.96 66.29,76.96 61.29,71.96 61.29,71.45 60.4,70.56 55.68,70.56 54.69,69.57 54.69,66.52 54.16,65.99 46.66,65.99 45.92,65.25 45.92,59.91 44.91,58.9 44.91,52.27 34.62,41.99 26.62,41.99 25.19,40.56 25.19,37.96 25.31,37.83 U41.26
LAN_CLKP2: length 90.8
  TOP w0.114: v1(79.03,98.76) 78.8,98.98 77.77,98.98 76.94,99.82 76.94,100.78 76.82,100.9 76.67,100.9 76.43,100.66 RZ52.2
  BOTTOM w0.114: U43.26 42.08,34.89 41.95,35.01 41.95,40.56 44.2,42.8 44.2,47.65 50.22,53.67 50.22,58.24 51.74,59.77 57.86,59.77 59,60.91 59,66.5 59.39,66.88 62.64,66.88 67.47,71.7 68.63,71.7 70.74,73.81 70.74,74.93 74.45,78.64 74.45,79.47 77.5,82.52 77.5,98.01 78.47,98.98 78.8,98.98 v1(79.03,98.76)
LAN_CLKP3: length 82.2
  TOP w0.114: RZ42.2 76.87,103.44 78.77,103.44 v1(78.99,103.67)
  BOTTOM w0.114: U45.26 60.36,34.89 60.24,35.01 60.24,40.07 59.18,41.13 59.18,46.1 60.33,47.24 60.33,53.74 64.62,58.04 68.39,61.81 68.39,64.8 70.18,66.59 70.18,71.98 71.63,73.43 71.63,74.3 74.83,77.49 75.46,77.49 78.31,80.34 78.31,96.51 80.01,98.21 80.01,103.18 79.74,103.44 79.22,103.44 v1(78.99,103.67)
LAN_CLKP4: length 82.2
  TOP w0.114: v1(80.64,101.65) 80.42,101.42 77.88,101.42 v1(77.66,101.64)
  BOTTOM w0.114: v1(80.64,101.65) 80.87,101.42 81.1,101.42 81.36,101.16 81.36,99.76 80.91,99.31 80.91,98.02 79.12,96.22 79.12,79.98 75.86,76.72 75.2,76.72 72.47,73.99 72.47,73.12 71.2,71.85 71.2,63.55 72.3,62.45 72.3,60.46 71.45,59.61 71.45,47.68 71.82,47.31 71.82,42.1 73.16,40.77 75.8,40.77 78.53,38.04 78.53,35.01 78.65,34.89 U47.26 ; RZ185.2 76.87,101.41 77.43,101.41 v1(77.66,101.64)
LAN_CLKP5: length 86.7
  TOP w0.114: RZ55.2 76.87,98.62 77.05,98.62 78.25,97.41 81.56,97.41 v1(81.79,97.18)
  BOTTOM w0.114: v1(81.79,97.18) 81.56,97.41 81.4,97.41 79.91,95.92 79.91,85.27 80.54,84.63 80.54,80.26 76.48,76.2 76.48,75.44 75.46,74.42 75.46,72.52 74.12,71.17 74.12,62.99 76.34,60.77 76.34,59.86 77.4,58.8 78.79,58.8 79.2,58.39 82.91,58.39 83.6,57.71 85.63,57.71 92.84,50.5 92.84,43.31 96.82,39.33 96.82,35.01 96.94,34.89 U49.26
LAN_CLKP6: length 115.5
  TOP w0.114: v1(73.63,43.18) 73.41,42.95 73.41,42.68 73.09,42.37 40.08,42.37 34.67,47.77 34.67,64.24 37.17,66.74 39.46,66.74 RZ84.2
  IN1 w0.122: v1(115.33,38.99) 115.1,39.22 115.1,40.12 114.83,40.39 104.34,40.39 103.4,39.45 101.52,39.45 100.2,40.77 88.67,40.77 87.13,42.31 78.46,42.31 77.55,41.4 74.42,41.4 73.41,42.42 73.41,42.95 v1(73.63,43.18)
  BOTTOM w0.114: U51.26 115.23,34.89 115.1,35.01 115.1,38.76 v1(115.33,38.99)
LAN_CLKP7: length 137
  TOP w0.114: RZ88.2 43.01,65.47 37.42,65.47 35.56,63.61 35.56,49.17 38.25,46.48 40.79,46.48 41.02,46.25 41.02,45.31 v1(40.79,45.09)
  IN1 w0.122: v1(133.62,38.35) 133.39,38.13 133.39,36.37 131.32,34.29 115.7,34.29 114.81,33.4 101.71,33.4 100.82,32.51 96.41,32.51 95.53,33.4 86.74,33.4 83.57,36.58 69.62,36.58 68.97,37.23 63,37.23 61.62,38.61 58.77,38.61 53.31,44.07 41.29,44.07 41.02,44.34 41.02,44.86 v1(40.79,45.09)
  BOTTOM w0.114: 133.52,34.52 U53.26 133.52,35.39 133.39,35.52 133.39,38.13 v1(133.62,38.35)
LAN_CLKP8: length 100.6
  TOP w0.114: v1(38.65,64.43) 38.87,64.2 39.46,64.2 RZ92.2
  IN1 w0.122: v1(38.65,64.43) 38.87,64.2 39.05,64.2 39.12,64.27 39.12,65.26 39.4,65.54 41.52,65.54 42.8,64.26 57.68,64.26 59.46,62.48 59.46,59.56 62.34,56.68 66.89,56.68 72.1,51.48 90.26,51.48 92.38,49.35 107.5,49.35 108.72,48.13 119.3,48.13 120.95,49.78 123.09,49.78 v1(123.32,50.01)
  BOTTOM w0.114: v1(123.32,50.01) 123.55,49.78 125.22,49.78 125.56,49.45 125.98,49.45 126.1,49.57 U55.26
LAN_GND:
  vias: v1(0.74,13.84) v1(0.74,11.3) v1(0.74,8.76) v1(0.74,6.22) v1(0.74,3.68) v1(0.74,1.14) v1(1.73,9.98) v1(1.73,5.92) v1(1.85,14.05) v1(2.49,9.98) v1(2.49,5.92) v1(2.62,14.05) v1(3.24,0.74) v1(3.38,14.05) v1(3.38,9.98) v1(3.38,5.92) v1(5.78,0.74) v1(8.32,0.74) v1(10.86,0.74) v1(13.4,0.74) v1(15.94,0.74) v1(18.48,0.74) v1(21.02,0.74) v1(23.56,0.74) v1(26.21,11.33) v1(26.8,11.33) v1(28.64,0.74) v1(28.91,6.05) v1(29.54,6.05) v1(30.18,6.05) v1(30.81,6.05) v1(31.18,0.74) v1(33.72,0.74) v1(36.26,0.74) v1(38.8,0.74) v1(41.34,0.74) v1(43.88,0.74) v1(49.02,5.97) v1(48.96,0.74) v1(49.78,5.97) v1(50.55,5.97) v1(51.31,5.97) v1(51.5,0.74) v1(54.04,0.74) v1(56.58,0.74) v1(59.12,0.74) v1(61.66,0.74) v1(64.2,0.74) v1(69.22,5.97) v1(69.28,0.74) v1(69.98,5.97) v1(70.74,5.97) v1(71.5,5.97) v1(71.82,0.74) v1(74.36,0.74) v1(76.9,0.74) v1(79.44,0.74) v1(81.98,0.74) v1(84.52,0.74) v1(89.41,5.97) v1(89.6,0.74) v1(90.17,5.97) v1(90.93,5.97) v1(91.69,5.97) v1(92.14,0.74) v1(94.68,0.74) v1(97.22,0.74) v1(99.76,0.74) v1(102.3,0.74) v1(104.84,0.74) v1(107.38,0.74) v1(109.6,5.97) v1(109.92,0.74) v1(110.36,5.97) v1(111.12,5.97) v1(111.89,5.97) v1(112.46,0.74) v1(115,0.74) v1(117.54,0.74) v1(120.08,0.74) v1(122.62,0.74) v1(125.16,0.74) v1(127.7,0.74) v1(129.79,5.97) v1(130.24,0.74) v1(130.56,5.97) v1(131.32,5.97) v1(132.08,5.97) v1(132.78,0.74) v1(135.32,0.74) v1(137.86,0.74) v1(140.4,0.74) v1(142.94,0.74) v1(145.8,60.07) v1(145.8,54.99) v1(145.8,49.91) v1(146.43,49.91) v1(146.56,60.07) v1(146.56,54.99) v1(147.45,45.85) v1(147.45,45.21) v1(148.02,0.74) v1(148.36,60.33) v1(149.12,60.33) v1(150.56,0.74) v1(152.35,50.11) v1(152.43,53.82) v1(152.43,53.01) v1(152.4,47.5) v1(152.37,46.86) v1(153.1,0.74) v1(155.64,0.74) v1(158.18,0.74) v1(159.26,53.84) v1(159.26,51.3) v1(159.26,48.76) v1(159.26,46.22) v1(159.26,43.68) v1(159.26,41.14) v1(159.26,38.6) v1(159.26,36.06) v1(159.26,33.52) v1(159.26,30.98) v1(159.26,28.44) v1(159.26,25.9) v1(159.26,23.36) v1(159.26,20.82) v1(159.26,18.28) v1(159.26,15.74) v1(159.26,13.2) v1(159.26,10.66) v1(159.26,8.12) v1(159.26,5.58) v1(159.26,3.04)
LED_ON1: length 77.1
  TOP w0.254: Z1.2 R63.1 Q6.D 147.4,68.96 v1(147.35,68.91)
  IN1 w0.203: v1(152.29,14.22) 152.29,14.98 153.06,15.75 153.06,18.74 150.88,20.93 145.95,20.93 143.66,23.22 143.66,25.18 142.85,27.15 142.85,29.62 141.58,30.89 141.58,34.57 137.64,38.51 137.64,41.74 137.06,42.32 137.06,47.87 137.36,48.17 137.36,53.56 137.77,53.97 137.77,56.97 141.07,60.27 141.07,64.41 145.57,68.91 v1(147.35,68.91)
  BOTTOM w0.203: TP18.7 v1(152.29,14.22)
  BOTTOM w0.254: v1(147.35,68.91) 147.42,68.91 148.11,69.6 R58.1
LED_ON1#: length 3.9
  TOP w0.203: U13.4 144.53,67.8 145.06,68.33 145.06,69.09 145.58,69.61 Q6.G
LED_ON2: length 78.6
  TOP w0.203: Q7.D v1(148.87,71.63)
  TOP w0.254: R64.1 Z5.2 v1(148.87,71.63)
  IN1 w0.203: v1(148.87,71.63) 148.87,68.33 148.22,67.68 144.8,67.68 141.4,64.28 141.4,60.14 138.1,56.84 138.1,53.83 137.69,53.42 137.69,48.04 137.39,47.73 137.39,42.67 138.96,41.1 138.96,37.66 141.91,34.71 141.91,31.03 143.18,29.76 143.18,27.21 143.99,25.25 143.99,23.36 146.09,21.26 151.01,21.26 153.39,18.88 153.39,15.61 152.79,15.01 v1(152.79,13.77)
  BOTTOM w0.203: TP18.6 v1(152.79,13.77)
  BOTTOM w0.254: v1(148.87,71.63) Z5.2
LED_ON2#: length 3.1
  TOP w0.203: U13.15 145.03,73.3 Q7.G
LED_ON3: length 81.5
  TOP w0.254: R65.1 Z6.2 v1(148.87,74.3) Q8.D
  IN1 w0.203: v1(153.29,14.22) 153.29,15.04 153.72,15.47 153.72,19.02 151.15,21.59 146.23,21.59 144.32,23.49 144.32,25.31 143.51,27.28 143.51,29.89 142.24,31.16 142.24,34.85 140.41,36.68 140.41,40.13 137.72,42.81 137.72,47.6 138.02,47.9 138.02,53.28 138.43,53.69 138.43,56.7 141.73,60 141.73,64.14 144.94,67.35 148.4,67.35 149.38,68.33 149.38,73.79 v1(148.87,74.3)
  BOTTOM w0.203: TP18.5 v1(153.29,14.22)
  BOTTOM w0.254: Z6.2 v1(148.87,74.3)
LED_ON3#: length 3.2
  TOP w0.203: Q8.G 144.9,73.8 U13.16
LOUT-L: length 8.3
  BOTTOM w0.381: FB41.2 150.89,155.36 C838.1 156.55,155.36 157.34,154.58 AUDIO1.9
LOUT-R: length 4.6
  BOTTOM w0.381: FB40.1 151.07,153.2 C839.1 155.23,153.2 AUDIO1.10
M2_5G_PLTRST_N: length 101
  TOP w0.107: v1(126.01,110.74) 119.28,110.74 118.6,110.07 U88.6
  IN3 w0.124: v1(126.01,110.74) 126.06,110.8 126.06,130 127.49,131.42 127.49,139.76 127.81,140.08 127.81,141.07 127.55,141.33 127.55,151.16 127.95,151.56 127.95,158.3 128.5,158.85 132.18,158.85 135.64,162.31 135.64,165.48 143.69,173.53 143.69,182.68 144.65,183.64 v1(144.65,187.83)
  BOTTOM w0.107: v1(144.65,187.83) 144.78,187.96 147.7,187.96 147.74,187.92 NGFF1.50
M2_B_EN: length 2.6
  BOTTOM w0.107: U32.8 140.72,175.9 140.31,175.49 R223.1 RZ147.2
M2_B_PG: length 2.8
  BOTTOM w0.107: U32.3 139.78,177.66 139.61,177.84 CM64.1 139.61,179.51 139.81,179.71 RA51.2
M2_WIFI_PLTRST_N: length 59.4
  TOP w0.107: v1(126.77,110.74) 126.26,110.24 122.45,110.24 120.8,108.58 120.04,108.58 119.9,108.45 U88.4
  IN1 w0.124: v1(126.77,110.74) 126.77,111.25 131.72,116.2 152.43,116.2 152.81,116.59 152.81,124.97 151.03,126.75 146.71,126.75 v1(145.31,128.14)
  BOTTOM w0.107: R191.1 144.99,132.95 WIFI1.52 144.99,128.47 v1(145.31,128.14)
M2E_ALERT_N: length 67.6
  TOP w0.107: J1.B55 101.3,119.91 101.4,120.01 v1(101.4,120.02)
  BOTTOM w0.107: v1(101.4,120.02) 101.4,119.89 103.97,117.31 109.52,117.31 110.16,117.95 116.69,117.95 117.54,117.09 127.66,117.09 129.78,119.21 129.78,125.51 130.97,126.7 141.4,126.7 141.99,126.11 148.34,126.11 149.86,127.64 149.86,128.78 151.13,130.05 151.13,133.73 150.77,134.09 RZ169.2
M2E_AP_WAKE_BT: length 57.7
  TOP w0.107: RZ22.1 v1(149.22,127.89) ; RZ25.2 120.48,116.71 129.41,125.65 v1(129.41,126.24)
  IN1 w0.124: v1(135.79,129.03) 135.19,129.03 132.61,126.45 129.63,126.45 v1(129.41,126.24)
  BOTTOM w0.107: v1(129.41,126.24) 129.41,126.27 130.31,127.17 142.65,127.17 142.82,127 148.34,127 v1(149.22,127.89) ; v1(135.79,129.03) 137.06,129.03 138.07,130.05 138.07,132.33 136.92,133.49 Q52.4 136.92,134.13 137.03,134.24 140.23,134.24 R193.1 RZU42.2
M2E_AP_WAKE_BT_CON: length 8.8
  BOTTOM w0.107: RZ170.2 R192.1 143.61,135.28 143.26,135.64 137.24,135.64 Q52.3
M2E_BT_DISABLE_N: length 33.2
  TOP w0.107: v1(101.1,126.02) 101.3,125.82 J1.F55
  IN3 w0.124: v1(103.76,133.73) 103.12,133.73 102.36,132.97 102.36,131.83 101.47,130.94 101.47,129.67 101.85,129.29 101.85,126.87 101.1,126.12 v1(101.1,126.02)
  BOTTOM w0.107: Q54.1 125.86,133.97 125.77,133.88 R201.1 124.82,133.88 124.59,134.11 104.14,134.11 v1(103.76,133.73)
M2E_BT_WAKE: length 38.4
  TOP w0.107: v1(100.85,130.52) 100.97,130.39 100.97,129.99 J1.J55
  BOTTOM w0.107: Q52.1 135.61,135.59 133.56,135.59 133.38,135.4 R187.1 132.33,135.13 130.5,133.3 124.79,133.3 123.76,132.27 112.57,132.27 111.84,133 103.54,133 101.05,130.52 v1(100.85,130.52)
M2E_SAR_TOUT: length 37.3
  TOP w0.107: RZ21.1 v1(148.08,127.89)
  BOTTOM w0.107: RZ171.2 123.13,128.02 123.75,127.4 142.75,127.4 142.92,127.23 147.43,127.23 v1(148.08,127.89)
M2E_SDIO_EN: length 47.2
  TOP w0.107: J1.B58 v1(104,120.02) ; RZU17.1 v1(142.62,126.62)
  BOTTOM w0.107: v1(104,120.02) 104.46,119.56 108.89,119.56 109.24,119.21 118.61,119.21 119.03,118.8 128.35,118.8 129.55,119.99 129.55,125.61 130.87,126.93 142.31,126.93 v1(142.62,126.62)
M2E_SDIO_WAKE: length 103.8
  TOP w0.107: v1(54.42,133.5) 54.31,133.5 54.2,133.4 J1.L6 ; v1(54.99,140.31) 55.41,140.73 62.96,140.73 66.39,144.15 112.62,144.15 116.41,140.36 125.01,140.36 128.81,136.56 128.81,134.32 134.59,128.54 139.09,128.54 139.83,127.8 RZU12.1 140.97,127.61 R1483.1
  IN3 w0.124: v1(54.99,140.31) 55.12,140.18 55.12,136.9 54.42,136.21 v1(54.42,133.5)
M2E_WIFI_DISABLE_N: length 86.7
  TOP w0.107: J1.J4 v1(52.4,130.52) ; v1(124.21,136.55) 123.55,136.55 122.44,137.66 115.29,137.66 111.5,141.45 67.51,141.45 63.53,137.47 53.03,137.47 v1(52.7,137.79)
  IN3 w0.124: v1(52.7,137.79) 52.7,136.91 51.08,135.29 51.08,131.84 v1(52.4,130.52)
  BOTTOM w0.107: v1(124.21,136.55) R198.1 125.31,136.64 Q53.4
M2E_WIFI_WAKE: length 69.5
  TOP w0.107: v1(100.74,111.23) 99.49,111.23 99.21,110.95 R3.1 99.21,109.86 99.05,109.69 Q50.S ; v1(101.23,127.52) 101.1,127.39 J1.G55 ; v1(143.92,128.14) 144.4,127.66 RZU16.1 144.91,127.23 145.06,127.38 Q17.S 145.53,127.47 R196.2
  IN3 w0.124: v1(100.74,111.23) 100.63,111.33 100.63,114.32 101.1,114.79 101.1,118.98 101.81,119.7 101.81,120.48 100.63,121.67 100.63,126.92 v1(101.23,127.52)
  BOTTOM w0.107: v1(143.92,128.14) 143.41,127.64 123.85,127.64 122.96,128.52 102.87,128.52 102.11,127.76 101.47,127.76 v1(101.23,127.52)
M2M_ALERT_N: length 65.2
  TOP w0.107: SSD2.44 v1(148.31,110.74) 148.31,110.29 R757.1 ; v1(133.48,125.22) 132.97,124.71 132.97,123.93 132.86,123.83 127.92,123.83 120.04,115.95 102.24,115.95 101.1,117.09 J1.A55
  IN3 w0.124: v1(133.48,125.22) 133.73,125.22 134.09,124.86 134.09,122.15 136.97,119.26 136.97,116.46 141.04,112.39 144.17,112.39 145.82,110.74 v1(148.31,110.74)
M.2_BT_RF_KILL#: length 23.5
  BOTTOM w0.107: WIFI1.54 145.49,132.13 145.67,132.31 145.67,135.56 144.66,136.57 133.01,136.57 130.58,134.14 R200.1 129.5,133.97 Q54.6
M.2_RESET: length 1.8
  BOTTOM w0.107: R222.2 156.6,192.17 NGFF1.67
M.2_WIFI_RF_KILL#: length 22.9
  BOTTOM w0.107: Q53.3 129.63,136.64 R197.1 130.91,136.68 131.04,136.8 144.75,136.8 145.92,135.64 145.92,132.33 145.99,132.27 WIFI1.56
M.2_WIFI_SUS_CLK: length 5.6
  TOP w0.107: v1(144.49,134.83) 144.49,135.55 144.15,135.89 R194.2
  BOTTOM w0.107: WIFI1.50 v1(144.49,134.83)
MCLK01_AUDIO_MCLK: length 92.7
  TOP w0.107: v1(57.68,142.67) 57.71,142.67 58.22,143.18 60.38,143.18 63.58,146.38 114,146.38 118,150.39 131.04,150.39 v1(131.32,150.11) ; v1(56.55,129.02) 57.1,128.47 J1.H9
  IN3 w0.124: v1(56.55,129.02) 57.68,130.16 v1(57.68,142.67)
  BOTTOM w0.107: RZ155.1 v1(131.32,150.11)
MCLK02_CAM0_MCLK: length 34.7
  TOP w0.107: J14.91 v1(116.5,154.56) ; v1(101.73,140.72) 100.97,140.72 100.58,140.34 RZ16.1
  IN1 w0.124: v1(101.73,140.72) 101.73,142.7 112.61,153.58 113.6,153.58 114.58,154.56 v1(116.5,154.56)
MCLK02_MCLK: length 9.1
  TOP w0.107: RZ16.2 100.58,136.14 99.74,135.3 99.74,132.41 99.95,132.21 99.95,130.56 100.2,130.3 J1.J54
MCLK03_CAM1_MCLK: length 42.4
  TOP w0.107: J14.88 v1(115.5,172.72) ; v1(98.3,140.08) RZ14.1
  IN3 w0.124: v1(98.3,140.08) 98.3,143 103.95,148.65 103.95,149.9 104.29,150.24 104.29,156.93 110.45,163.09 111.13,163.09 115.5,167.45 v1(115.5,172.72)
MCLK03_MCLK: length 10.8
  TOP w0.107: RZ14.2 98.3,134.54 98.86,133.99 98.86,132.28 99.06,132.08 99.06,130.94 98.86,130.73 98.86,129.36 99.5,128.72 J1.H53
MCLK04_CAM2_MCLK: length 43.2
  TOP w0.107: J14.94 v1(117,173.23) ; RZ17.1 v1(101.73,140.08)
  IN3 w0.124: v1(117,173.23) 117,171.64 115.93,170.57 115.93,167.28 111.31,162.66 110.62,162.66 104.72,156.76 104.72,150.06 104.38,149.72 104.38,148.32 101.09,145.03 101.09,140.72 v1(101.73,140.08)
MCLK04_MCLK: length 10.4
  TOP w0.107: RZ17.2 101.73,134.16 101.55,133.99 101.55,132.49 101.75,132.28 101.75,131.09 101.57,130.91 101.57,129.26 101.3,128.99 J1.H55
MCU2_FLASH#: length 100.8
  TOP w0.107: J1.C61 v1(106.5,121.52)
  IN1 w0.124: v1(132.21,125.22) 130.74,123.75 121.16,123.75 120.08,122.68 116.23,122.68 114.45,120.9 106.81,120.9 106.5,121.21 v1(106.5,121.52)
  IN3 w0.124: v1(139.83,72.01) 140.36,72.01 142.96,74.61 146.49,74.61 152.78,80.9 152.78,96.19 151.59,97.38 151.59,102.81 148.98,105.43 148.98,106.7 143.79,111.89 140.84,111.89 136.47,116.26 136.47,119.06 132.74,122.78 132.74,124.97 132.49,125.22 v1(132.21,125.22)
  BOTTOM w0.107: RZ203.1 v1(139.83,72.01)
MCU2_RST#: length 52.1
  TOP w0.107: C24.1 v1(140.61,62.36) ; C24.1 141.29,63.33 141.33,63.37 U13.64 ; C24.1 141.29,61.23 R81.1
  BOTTOM w0.107: v1(140.61,62.36) 140.61,62.61 140.36,62.87 139.22,62.87 138.4,62.05 133.18,62.05 132.72,62.51 123.12,62.51 121.31,60.71 DB1.10 119.23,60.71 118.21,59.69 114.2,59.69 110.23,55.72 110.23,50.45 112.45,48.23 SW2.3 SW2.4
MCU2_VDD: length 49.1
  TOP w0.203: U14.14 127.37,73.86 CA70.1 127.32,74.26 U14.15
  TOP w0.254: v1(137.95,74.68) 137.83,74.8 U13.24 v1(137.83,76.96) ; v1(137.57,63.12) 137.33,63.36 U13.56 137.33,65.29 v1(137.44,65.41) ; U13.34 v1(132.99,73.3)
  TOP w0.279: U13.34 v1(130.6,73.3) ; v1(142.27,69.8) U13.8 144.48,69.8 v1(144.55,69.72)
  TOP w0.508: v1(125.09,78.49) RB49.2 RB48.2 ; RB53.2 RB54.2 v1(124.97,70.23) ; RB53.2 RB52.2 ; RB53.2 v1(123.85,70.23) ; R84.2 v1(135.25,80.26) ; RB47.2 v1(121.67,78.49) ; RB55.2 v1(121.06,70.48) ; R1477.1 v1(116.87,75.29) ; CA71.1 127.7,73.25 v1(127.67,73.28) CA70.1 ; FB2.1 v1(141.73,80.29) ; RB50.2 v1(122.12,73.66) ; R81.2 v1(142.9,61.21) ; RB51.2 v1(121.06,73.15) ; R90.1 v1(129.31,76.2)
  BOTTOM w0.381: v1(137.44,65.41) 137.5,65.34 C19.1 CA152.1 137.5,63.18 v1(137.57,63.12)
  BOTTOM w0.508: v1(137.95,74.68) 138.01,74.74 CA149.1 C18.1 138.01,76.78 v1(137.83,76.96) ; R1500.2 v1(136.17,70.36) ; R56.2 v1(150.62,73.53) R57.2 v1(150.62,70.87) R58.2 150.62,68.81 148.72,66.9 R85.2 ; DB1.1 v1(116.23,66.67) ; v1(144.55,69.72) 144.46,69.63 CA150.1 CA151.1 142.43,69.63 v1(142.27,69.8) ; R1505.2 v1(136.17,71.5) ; v1(130.6,73.3) 130.67,73.37 C20.1 C21.1 132.92,73.37 v1(132.99,73.3) ; R1499.2 v1(134.9,76.96) ; R1498.2 v1(136.19,69.22) ; v1(130.45,70.99) 129.84,70.99 R1491.2
  vias: v1(143.41,79.25) v1(144.32,78.36)
MCU2_VDD_REF: length 8.9
  TOP w0.254: CA69.1 138.07,77.6 138.33,77.35 U13.23 ; C23.1 139.22,77.85 138.83,77.46 U13.22
  TOP w0.508: FB2.2 141.47,78.27 C22.1 C23.1 CA69.1
MCU_BUZZ: length 275.7
  TOP w0.254: U13.41 130.53,69.8 v1(130.45,69.72) ; RZ1.1 v1(11.96,194.21)
  IN3 w0.254: v1(112.29,59.56) 112.1,59.56 111.75,59.21 111.75,58.82 108.39,55.47 106.55,55.47 105.78,54.7 91.91,54.7 89.79,52.58 82.05,52.58 81.59,53.04 78.69,53.04 77.04,51.38 72.29,51.38 67.39,56.28 62.49,56.28 61.22,57.56 50.9,57.56 49.27,59.18 47.24,59.18 46.38,60.04 46.38,63.75 39.6,70.53 39.6,76.33 35.24,80.7 23.78,80.7 21.42,83.06 8.79,83.06 v1(8.59,83.26)
  BOTTOM w0.254: v1(130.45,69.72) 130.3,69.88 R1491.1 128.96,69.88 128.22,69.14 115.49,69.14 113.44,67.08 113.44,60.71 v1(112.29,59.56) ; v1(8.59,83.26) 8.2,83.26 4.72,86.74 4.72,95.99 1.86,98.85 1.86,165.15 5.51,168.8 5.51,173.72 5.33,173.89 5.33,191.01 8.53,194.21 v1(11.96,194.21)
MCU_CARRIER_POWER_ON: length 6.9
  TOP w0.107: U4.1 107.96,137.91 108.07,137.81 ; 108.07,137.81 108.34,137.81 108.46,137.92 U4.2 ; 108.07,137.81 107.4,137.14 J1.L62
MCU_IRQ#: length 76.7
  TOP w0.107: Q59.D v1(118.24,122.17) ; U13.19 v1(140.33,76.96)
  IN3 w0.124: v1(140.33,76.96) 139.56,77.72 128.68,77.72 127.03,79.38 116.87,79.38 114.81,81.43 114.81,89.31 113.66,90.46 113.66,97 112.92,97.74 112.92,102.16 115.16,104.4 115.81,104.4 117.73,106.33 117.73,113.62 118.84,114.73 118.84,118.46 119.43,119.05 119.43,121.95 119.2,122.17 v1(118.24,122.17)
  BOTTOM w0.107: R1490.1 v1(118.24,122.17)
MCU_OP_A: length 4.9
  TOP w0.203: U66.16 91.09,82.93 90.51,82.36
  TOP w0.508: R539.1 RZU28.1 89.37,80.52 89.88,81.03 89.88,81.72 90.51,82.36
MCU_P25_A: length 1.5
  TOP w0.203: U66.60 v1(93.89,90.63)
  BOTTOM w0.203: v1(93.89,90.63) 93.85,90.08 R515.1
MCU_P70_RXD: length 63.7
  TOP w0.107: U66.4 90.34,87.73 89.56,88.52 89.56,89.28 89.17,89.66 R532.1 88.62,90.06 88.51,90.17 87.4,90.17 86.89,89.66 86.89,88.39 86.02,87.52 82.05,87.52 75.24,80.7 63.55,80.7 60.78,77.93 v1(60.78,77.17)
  BOTTOM w0.107: v1(60.78,77.17) 42.34,77.17 RZU47.1
MCU_P71_TXD: length 62.7
  TOP w0.107: v1(60.78,76.4) 61.29,76.91 61.29,77.93 63.7,80.34 75.39,80.34 82.17,87.12 86.26,87.12 87.15,88.01 88.51,88.01 88.62,88.12 R533.1 88.93,88.52 90.07,87.38 90.86,87.38 90.9,87.33 U66.5
  BOTTOM w0.107: v1(60.78,76.4) 60.4,76.78 42.85,76.78 37.64,71.58 RZU46.1
MCU_SCL_A: length 16.5
  TOP w0.107: U66.38 99.92,84.93 99.95,84.91 v1(99.97,84.91) ; R537.2 89.31,85.09 v1(89.69,85.47) 89.95,85.73 U66.9
  IN3 w0.124: v1(99.97,84.91) 98.96,83.9 98.96,83.06 98.32,82.42 92.74,82.42 v1(89.69,85.47)
MCU_SDA_A: length 17.6
  TOP w0.107: U66.37 99.77,84.53 99.8,84.5 100.33,84.5 100.58,84.25 v1(100.58,84.02) ; R538.2 89.05,83.95 v1(89.69,84.58) 90.44,85.33 U66.10
  IN3 w0.124: v1(89.69,84.58) 92.28,81.99 98.66,81.99 100.58,83.92 v1(100.58,84.02)
MCU_VDD: length 11.2
  TOP w0.508: C413.1 139.55,97.05 140.41,97.92 140.41,99.82 141.3,100.71 v1(143.66,100.71)
  BOTTOM w0.254: U77.5 143.9,93.62 CB136.1 v1(144.42,93.48)
  BOTTOM w0.508: R697.2 v1(143.66,100.71)
  vias: v1(131.98,97.54) v1(132.61,97.54) v1(133.25,97.54) v1(133.25,96.9) v1(133.25,96.27) v1(133.25,95.63) v1(133.25,95) v1(133.25,94.36) v1(136.55,97.54) v1(136.55,96.9) v1(136.55,96.27) v1(136.55,95.63) v1(136.55,95) v1(136.55,94.36) v1(137.19,96.01) v1(137.19,95.38) v1(144.42,94.11) v1(145.8,78.38) v1(146.58,79.25)
MCU_VDD_EN: length 4.4
  BOTTOM w0.254: U77.12 144.9,98.17 C417.1 146.16,99.44 D64.C R696.1
MOD_SHUTDOWN_N: length 27.1
  TOP w0.107: v1(97.54,136.78) 97.54,134.49 98.4,133.63 J1.L52 ; U10.2 109.2,152.4 v1(109.21,152.41)
  IN1 w0.124: v1(109.21,152.41) 108.56,151.76 107.57,151.76 98.83,143.03 98.83,138.07 v1(97.54,136.78)
  BOTTOM w0.107: R46.2 109.21,151.88 v1(109.21,152.41)
MOD_SHUTDOWN_N_3V3: length 4.4
  TOP w0.107: RB12.2 107.85,155.22 108.1,155.47 108.37,155.47 U11.1 108.56,154.46 108.71,154.31 109.6,154.31 109.85,154.06 U10.4
MOD_TEMP_SHDN_EN_N: length 12
  TOP w0.107: RZ13.1 111.25,137.79 110.74,137.29 108.33,137.29 107.83,136.79 107.83,132.34 107.17,131.68 107.17,130.09 J1.J62
MODULE_POWER_ON: length 52.3
  TOP w0.107: J1.L54 v1(100.2,133.48) ; U7.3 129.69,163.86 RZU3.1 v1(128.78,163.07) 128.3,162.59 R29.1
  IN1 w0.124: v1(100.2,133.48) 100.61,133.89 100.61,144.42 107.7,151.51 109.58,151.51 113.26,155.19 123.24,155.19 124.74,156.69 124.74,158.12 128.78,162.15 v1(128.78,163.07)
N_SIN1: length 23.2
  TOP w0.107: U25.3 84.88,162.16 83.08,163.96 83.08,171.29 85.12,173.33 86.59,173.33 90.83,177.57 U24.5
N_SIN2: length 29.1
  TOP w0.107: U25.22 79.23,157.84 v1(79.58,158.19) ; U24.6 92.1,178.51 86.69,173.1 85.22,173.1 83.31,171.2 83.31,165.76 v1(83.64,165.43)
  IN1 w0.124: v1(83.64,165.43) 79.58,161.37 v1(79.58,158.19)
N_SIN3: length 31.7
  TOP w0.107: U25.41 82.88,153.36 v1(83.19,153.67)
  BOTTOM w0.107: v1(83.19,153.67) 82.75,154.1 82.75,158.83 84.37,160.44 84.37,173.42 86.42,175.47 89.03,175.47 89.56,176.01 U26.5
N_SIN4: length 26.6
  TOP w0.107: U25.64 v1(83.13,159.84)
  BOTTOM w0.107: v1(83.13,159.84) 84.13,160.85 84.13,173.52 86.32,175.71 87.88,175.71 88.29,176.11 U26.6
N_SOUT1: length 24.3
  TOP w0.107: U25.2 v1(85.28,162.51) ; v1(82.12,166.32) 82.61,166.81 82.61,171.49 84.93,173.8 86.4,173.8 88.29,175.69 U24.3
  IN1 w0.124: v1(85.28,162.51) 85.28,165.19 84.15,166.32 v1(82.12,166.32)
N_SOUT2: length 28.9
  TOP w0.107: v1(77.29,157.94) 77.6,158.25 U25.21 ; U24.4 89.56,176.63 86.5,173.57 85.02,173.57 82.84,171.39 82.84,166.16 v1(82.12,165.43)
  IN1 w0.124: v1(82.12,165.43) 82.12,164.8 78.82,161.49 78.82,159.08 77.67,157.94 v1(77.29,157.94)
N_SOUT3: length 33.3
  TOP w0.107: U25.40 82.48,153.72 v1(83.19,154.43)
  BOTTOM w0.107: U26.3 92.1,176.68 90.42,175.01 86.61,175.01 84.84,173.23 84.84,159.64 83.19,157.99 v1(83.19,154.43)
N_SOUT4: length 28.9
  TOP w0.107: U25.63 84.01,159.44 v1(83.64,159.08)
  BOTTOM w0.107: v1(83.64,159.08) 84.6,160.04 84.6,173.33 86.52,175.24 89.79,175.24 90.83,176.28 U26.4
NC_SI1_ARB_IN: length 1.5
  BOTTOM w0.107: RA89.2 30.49,31.64 U41.43
NC_SI1_ARB_OUT: length 1.7
  BOTTOM w0.107: RA91.2 30.37,31.34 29.8,31.34 29.61,31.14 U41.44
NC_SI1_CLK: length 1.5
  TOP w0.107: RA33.2 19.25,29.46 v1(19.18,29.54)
  BOTTOM w0.107: v1(19.18,29.54) 19.23,29.59 19.3,29.59 19.36,29.64 U41.2
NC_SI1_CRS_DV: length 1.5
  TOP w0.107: v1(19.18,30.17) 19.74,30.17 RA31.2
  BOTTOM w0.107: U41.3 19.3,30.14 19.28,30.17 v1(19.18,30.17)
NC_SI1_RXD0: length 1.5
  BOTTOM w0.107: U41.6 18.66,31.64 RA90.2
NC_SI1_RXD1: length 1.5
  BOTTOM w0.107: RA92.2 18.58,31.14 U41.5
NC_SI1_TX_EN: length 1.5
  TOP w0.107: v1(19.18,32.14) 19.19,32.13 RA30.2
  BOTTOM w0.107: U41.7 v1(19.18,32.14)
NC_SI1_TXD0: length 1.6
  BOTTOM w0.107: U41.9 19.05,33.14 18.79,33.4 RA76.2
NC_SI1_TXD1: length 1.5
  BOTTOM w0.107: RA83.2 18.68,32.64 U41.8
NCSI4_ARBIN: length 1.5
  BOTTOM w0.107: RA111.2 83.91,28.8 82.96,28.8 82.88,28.72 U47.43
NCSI4_ARBOUT: length 1.7
  BOTTOM w0.203: U47.44 82.85,28.22 83.1,28.47 83.62,28.47 83.9,28.19 RA123.2
NCSI4_CLKIN: length 128.7
  TOP w0.107: v1(72.52,26.37) 72.52,26.44 72.62,26.54 RA48.2
  IN3 w0.124: v1(72.52,26.37) 72.01,25.86 70.28,25.86 68.4,27.74 68.4,28.78 67.88,29.3 67.88,39.17 70.12,41.42 77.06,41.42 78.02,42.37 87.36,42.37 88.24,41.49 89.22,41.49 94.9,47.17 110.73,47.17 112.33,48.78 112.33,55.03 117.23,59.93 121.47,59.93 125.08,63.54 130.51,63.54 131.52,64.56 137.91,64.56 141.68,68.32 145.22,68.32 146.77,69.88 151.41,69.88 152.6,71.07 152.6,76.15 v1(153.65,77.2)
  BOTTOM w0.107: v1(72.52,26.37) 72.52,26.62 72.62,26.72 U47.2 ; NCSI1.5 v1(153.65,77.2)
NCSI4_CRS_DV: length 125.7
  TOP w0.107: v1(72.09,27.25) 73.08,27.25 RA42.2
  IN3 w0.124: v1(153.65,73.2) 153.77,73.2 154.08,72.9 154.08,71.02 151.59,68.53 148.08,68.53 147.37,67.82 146.08,67.82 144.82,66.56 141.17,66.56 138.28,63.67 131.89,63.67 130.87,62.66 125.45,62.66 121.73,58.94 117.63,58.94 114.3,55.61 114.3,46.55 108.66,40.92 106.3,40.92 105.15,39.77 100.48,39.77 98.49,41.76 91.11,41.76 89.96,40.61 87.87,40.61 86.99,41.49 78.38,41.49 77.38,40.48 70.44,40.48 68.76,38.81 68.76,29.67 70.69,27.74 71.59,27.74 v1(72.09,27.25)
  BOTTOM w0.107: U47.3 72.54,27.22 72.52,27.25 v1(72.09,27.25) ; NCSI1.9 v1(153.65,73.2)
NCSI4_RXD0: length 125.9
  IN3 w0.124: v1(72.47,28.78) 72.41,28.72 71,28.72 69.67,30.05 69.67,38.43 70.82,39.57 77.75,39.57 78.19,40.01 86.97,40.01 87.4,39.57 90.24,39.57 91.18,40.51 98.45,40.51 100.1,38.86 105.53,38.86 106.67,40.01 109.04,40.01 115.21,46.18 115.21,55.23 118.01,58.03 122.11,58.03 125.82,61.75 131.25,61.75 131.49,61.99 137.89,61.99 141.54,65.65 145.23,65.65 146.47,66.88 147.72,66.88 148.46,67.62 151.99,67.62 155.27,70.9 155.27,73.55 v1(153.62,75.2)
  BOTTOM w0.107: RA112.2 71.98,28.83 72.03,28.78 v1(72.47,28.78) 72.52,28.72 U47.6 ; NCSI1.7 v1(153.62,75.2)
NCSI4_RXD1: length 125.7
  IN3 w0.124: v1(72.09,28.19) 70.88,28.19 69.22,29.86 69.22,38.62 70.63,40.03 77.57,40.03 78.57,41.03 86.8,41.03 87.68,40.15 90.15,40.15 91.3,41.3 98.31,41.3 100.29,39.32 105.34,39.32 106.49,40.46 108.85,40.46 114.76,46.37 114.76,55.42 117.82,58.49 121.92,58.49 125.63,62.2 131.06,62.2 131.38,62.52 137.77,62.52 141.35,66.1 145.05,66.1 146.28,67.34 147.54,67.34 148.27,68.07 151.8,68.07 154.82,71.09 154.82,73 v1(153.62,74.2)
  BOTTOM w0.107: U47.5 72.11,28.22 v1(72.09,28.19) RA124.2 ; NCSI1.8 v1(153.62,74.2)
NCSI4_TX_EN: length 121.8
  TOP w0.107: v1(72.09,29.29) 72.45,29.29 72.53,29.21 RA36.2
  IN3 w0.124: v1(72.09,29.29) 71.81,29.29 71.07,30.03 71.07,32.59 70.83,32.83 70.83,35.62 72.29,37.08 72.29,37.74 73.66,39.12 77.94,39.12 78.37,39.55 86.78,39.55 87.5,38.83 90.28,38.83 90.58,39.14 98.76,39.14 100.22,37.67 104.98,37.67 106.86,39.55 109.23,39.55 119.21,49.53 120.17,49.53 123.34,52.7 123.34,54.28 130.36,61.29 131.44,61.29 131.68,61.54 138.07,61.54 140.9,64.36 146.19,64.36 148.49,66.66 151.67,66.66 156.03,71.02 v1(156.03,79.2)
  BOTTOM w0.107: v1(72.09,29.29) 72.15,29.22 U47.7 ; NCSI1.3 v1(156.03,79.2)
NCSI4_TXD0: length 120.9
  IN3 w0.124: v1(156.06,81.2) 156.94,80.32 156.94,70.64 149.52,63.22 142.94,63.22 140.34,60.63 132.06,60.63 131.81,60.38 130.74,60.38 124.25,53.9 124.25,52.33 120.54,48.62 119.58,48.62 109.61,38.64 107.24,38.64 105.36,36.76 99.85,36.76 98.38,38.23 90.96,38.23 90.66,37.92 81.22,37.92 80.97,38.18 75.16,38.18 74.07,37.08 73.94,37.08 72.57,35.71 72.57,32.23 72.09,31.75 v1(72.09,30.3)
  BOTTOM w0.107: RA96.2 71.91,30.48 v1(72.09,30.3) 72.17,30.22 U47.9 ; NCSI1.1 v1(156.06,81.2)
NCSI4_TXD1: length 121.3
  IN3 w0.124: v1(72.47,29.79) 71.95,29.79 71.63,30.11 71.63,31.94 72.11,32.42 72.11,35.9 73.43,37.22 73.43,37.97 74.09,38.63 81.15,38.63 81.41,38.38 90.47,38.38 90.77,38.68 98.57,38.68 100.04,37.21 105.17,37.21 107.05,39.1 109.42,39.1 119.4,49.08 120.36,49.08 123.8,52.52 123.8,54.09 130.55,60.84 131.63,60.84 131.87,61.08 140.15,61.08 142.75,63.68 149.33,63.68 156.49,70.83 156.49,79.76 v1(156.03,80.21)
  BOTTOM w0.107: U47.8 72.54,29.72 v1(72.47,29.79) 72.09,29.79 72.03,29.84 RA102.2 ; NCSI1.2 156.02,80.2 v1(156.03,80.21)
NVM_CS1: length 3.9
  BOTTOM w0.107: R284.2 19.05,38.21 19.05,36.58 19.48,36.14 U41.15
NVM_SI1: length 1.5
  BOTTOM w0.107: R281.2 18.68,34.67 19.43,34.67 19.46,34.64 U41.12
NVM_SK1: length 1.5
  BOTTOM w0.107: R282.2 18.59,35.14 U41.13
NVM_SO1: length 4.7
  BOTTOM w0.107: U41.14 19.35,35.64 18.54,36.45 18.54,38.09 R283.2
NVME_PCIE_WAKE_N: length 6.3
  TOP w0.107: v1(150.67,113.67) 150.67,113.13 150.81,112.99 SSD2.54
  BOTTOM w0.107: RZ178.1 150.44,113.03 150.67,113.26 v1(150.67,113.67) R759.1
OVCUR1#: length 5.8
  TOP w0.107: U20.19 87.17,70.15 87.86,70.84 90.98,70.84 91.15,70.68 RA6.2 RZ74.1
OVCUR2#: length 4.1
  TOP w0.203: RA10.2 88.21,61.8 87.66,62.36 87.66,63.09 87.4,63.35 U20.2
  TOP w0.254: RZ95.1 88.7,61.39 88.48,61.18 RA10.2
OVCUR3#: length 2
  TOP w0.107: U20.54 77.29,64.15 76.85,63.7 RA9.2
OVCUR4#: length 3.3
  TOP w0.107: U20.40 77.47,69.75 77.29,69.93 77.29,71.58 77.04,71.83 RA5.2
P0_TOD_CLK_IN_3V3: length 1.8
  BOTTOM w0.107: RZ41.1 142.88,104.52 142.52,104.16 U85.8
P1_TOD_CLK_IN_3V3: length 2.1
  BOTTOM w0.107: U85.7 142.18,104.56 RZ47.1
P_SPI_CK: length 13.2
  TOP w0.107: v1(87.63,68.15) U20.14 ; U21.6 v1(85.55,77.47)
  IN1 w0.124: v1(87.63,68.15) 86.99,68.15 86.57,68.57 86.57,71.75 86.94,72.13 86.94,76.66 86.13,77.47 v1(85.55,77.47)
P_SPI_CZ: length 19.6
  TOP w0.107: v1(87.62,68.97) 87.59,68.95 U20.16 ; U21.1 v1(82.12,80.01)
  IN1 w0.124: v1(87.62,68.97) 87.62,70.9 88.34,71.62 88.34,76.69 85.02,80.01 v1(82.12,80.01)
P_SPI_DI: length 20.7
  TOP w0.107: U20.15 87.43,68.55 87.44,68.56 87.99,68.56 v1(88.21,68.78) ; U21.2 v1(82.12,78.74)
  IN1 w0.124: v1(82.12,78.74) 85.58,78.74 87.84,76.48 87.84,71.83 87.07,71.07 87.07,68.78 87.32,68.53 87.96,68.53 v1(88.21,68.78)
P_SPI_DO: length 13.7
  TOP w0.107: v1(86.06,75.51) 85.37,76.2 U21.5 ; U20.13 87.4,67.75 87.43,67.72 87.84,67.72 88.14,68.02 v1(88.21,68.02)
  IN1 w0.124: v1(88.21,68.02) 88.21,67.89 87.83,67.51 86.91,67.51 86.06,68.36 86.06,71.96 86.44,72.34 86.44,75.13 v1(86.06,75.51)
P_SPI_HOLD#: length 1.8
  TOP w0.107: U21.7 85.74,78.74 RA3.2
P_SPI_WP#: length 1.6
  TOP w0.107: RA4.2 77.33,77.47 U21.3
PCIE1_CLKREQ_N: length 66.2
  TOP w0.107: v1(84.33,119.89) 84.33,119.73 J1.B37
  IN1 w0.124: v1(84.33,119.89) 84.35,119.87 84.35,117.55 84.78,117.12 93.21,117.12 94.07,116.26 122.17,116.26 125.96,120.04 143.79,120.04 v1(144.42,120.68)
  BOTTOM w0.107: RZ174.1 v1(144.42,120.68)
PCIE1_RST_N: length 51.2
  TOP w0.107: 118.6,105.55 118.46,105.41 116.87,105.41 116.73,105.55 ; 118.6,105.55 U88.1 ; 118.6,105.55 118.75,105.41 119.76,105.41 119.9,105.55 U88.3 ; 116.73,105.55 116.46,105.28 v1(115.43,105.28) U89.1 ; 116.73,105.55 U89.3 ; J1.B36 83.8,118.76 84.25,118.31 84.25,117.17 84.58,116.84 99.9,116.84 101.45,115.29 v1(114.71,115.29)
  IN3 w0.124: v1(115.43,105.28) 114.71,106 v1(114.71,115.29)
PCIE4_CLK_N: length 91
  TOP w0.114: J1.E22 69.99,123.86 70.1,123.98 70.1,124.37 v3(69.98,124.5) ; v1(150.46,116.78) 150.68,117.01 150.68,117.29 150.56,117.42 SSD2.53
  BOTTOM w0.114: v3(69.98,124.5) 70.12,124.36 70.12,124.06 70.46,123.72 81.13,123.72 81.58,123.27 81.58,122.48 82.02,122.05 83.08,122.05 84.48,120.65 85.22,120.65 85.45,120.42 85.45,119.17 85.72,118.89 85.72,118.04 85.99,117.78 90.7,117.78 91.94,116.54 109.84,116.54 110.48,117.18 116.37,117.18 117.22,116.32 135.04,116.32 136.71,118 150.38,118 150.68,117.69 150.68,117.01 v1(150.46,116.78)
PCIE4_CLK_P: length 91
  TOP w0.114: J1.E23 70.48,123.86 70.36,123.98 70.36,124.34 v3(70.52,124.5) ; SSD2.55 151.06,117.42 150.94,117.29 150.94,117.01 v1(151.17,116.78)
  BOTTOM w0.114: v3(70.52,124.5) 70.38,124.36 70.38,124.16 70.56,123.98 81.23,123.98 81.84,123.37 81.84,122.58 82.12,122.3 83.19,122.3 84.59,120.9 85.32,120.9 85.7,120.53 85.7,119.28 85.98,119 85.98,118.15 86.09,118.03 90.8,118.03 92.04,116.79 109.74,116.79 110.37,117.43 116.47,117.43 117.33,116.58 134.93,116.58 136.61,118.25 150.48,118.25 150.94,117.79 150.94,117.01 v1(151.17,116.78)
PCIE4_CLKREQ_N: length 109.3
  TOP w0.107: J1.G8 56,127.22 v1(56.24,127.46) ; SSD2.52 150.31,112.86 150.01,113.16 v1(150.01,113.67)
  BOTTOM w0.107: v1(56.24,127.46) 55.58,126.8 55.58,123.95 55.71,123.82 55.71,121.19 58.14,118.76 58.14,117.61 59.21,116.54 67.82,116.54 69.87,114.49 79.54,114.49 81.87,112.17 89.6,112.17 89.92,112.48 134.73,112.48 135.64,111.57 137.76,111.57 139.59,113.4 144.66,113.4 144.93,113.67 v1(150.01,113.67)
PCIE4_RST_N: length 114.7
  TOP w0.107: J1.J9 v1(56.9,130.52) ; SSD2.50 149.81,112.72 149.39,113.14 v1(149.39,114.29)
  BOTTOM w0.107: v1(56.9,130.52) 57.57,130.52 58.14,129.95 58.14,128.75 56.95,127.56 56.95,127.25 56.49,126.79 56.49,124.49 56.59,124.39 56.59,120.89 58.55,118.93 58.55,117.78 59.38,116.95 67.99,116.95 70.04,114.9 79.71,114.9 82.04,112.58 89.43,112.58 89.75,112.9 134.9,112.9 135.82,111.98 137.59,111.98 139.42,113.81 144.44,113.81 144.92,114.29 v1(149.39,114.29) R760.1
PCIE5_CLK_N: length 29.2
  TOP w0.114: v3(72.52,126) 72.39,125.87 72.39,125.5 72.53,125.36 J1.F25
  IN1 w0.122: v1(78.13,112.62) 77.9,112.85 77.9,114.86 77.12,115.65 73.86,115.65 72.69,116.81 72.69,118.57 73.71,119.58 73.71,120.52 72.97,121.26 72.97,121.77 74.27,123.06 74.27,124.87 73.66,125.48 72.53,125.48 72.38,125.63 72.38,125.86 v3(72.52,126)
  BOTTOM w0.114: v1(78.13,112.62) 77.9,112.39 77.9,111.58 77.42,111.1 77.42,106.25 77.15,105.98 76.87,105.98 RZ181.2
PCIE5_CLK_P: length 28.8
  TOP w0.114: J1.F24 71.99,125.36 72.14,125.5 72.14,125.84 v3(71.98,126)
  IN1 w0.122: v1(77.42,112.62) 77.65,112.85 77.65,114.75 77.01,115.39 73.76,115.39 72.44,116.71 72.44,118.67 73.46,119.69 73.46,120.42 72.72,121.15 72.72,121.87 74.02,123.17 74.02,124.76 73.55,125.22 72.42,125.22 72.12,125.52 72.12,125.86 v3(71.98,126)
  BOTTOM w0.114: RZ179.2 76.87,106.24 77.05,106.24 77.17,106.35 77.17,111.2 77.65,111.69 77.65,112.39 v1(77.42,112.62)
PCIE5_CLKREQ_N: length 28.2
  TOP w0.107: J1.C8 56,120.57 55.75,120.32 55.75,118.95 55.55,118.75 55.55,116.92 55.83,116.64 57.3,116.64 58.5,115.44 72.49,115.44 73.96,113.97 R565.2 73.96,109.75 RZU21.2
PCIE5_RST_N: length 153.8
  TOP w0.107: U3.4 47.54,110.53 47.22,110.21 R560.2 47.22,107.54 48.59,106.17 v1(49.81,106.17) ; RZ81.2 v1(64.85,68.2)
  IN1 w0.124: v1(20.45,38.23) 20.45,37.77 20.7,37.51 30.02,37.51 31.04,36.5 36.02,36.5 v1(37.21,35.31) 37.92,34.59 50.11,34.59 51.51,35.99 54.82,35.99 v1(55.5,35.31) 55.5,34.97 55.88,34.59 67,34.59 68.4,35.99 73.1,35.99 v1(73.79,35.31)
  IN3 w0.124: v1(49.81,106.17) 50.34,105.64 50.34,100.88 51.05,100.18 51.05,92.99 50.46,92.4 50.46,80.98 52.4,79.04 52.4,78.19 55.08,75.51 60.48,75.51 64.85,71.15 v1(64.85,68.2)
  BOTTOM w0.107: U47.17 74.15,34.94 v1(73.79,35.31) ; v1(64.85,68.2) 63.6,66.95 63.6,62.59 59.28,58.27 59.28,56.67 57.45,54.84 57.45,52.81 55.98,51.33 55.98,47.7 55.14,46.86 55.14,35.66 v1(55.5,35.31) 55.86,34.94 U45.17 ; U41.17 20.81,37.86 v1(20.45,38.23) ; U43.17 37.58,34.94 v1(37.21,35.31) ; RZ180.2 v1(49.81,106.17)
PCIE5_RST_N1: length 164.4
  TOP w0.107: U5.4 v1(50.58,109.72)
  IN1 w0.124: v1(50.58,109.72) 50.58,106.35 49.72,105.49 49.72,100.21 50.1,99.83 50.1,94.38 49.39,93.67 49.39,81.24 51.75,78.87 51.75,75.44 52.36,74.83 52.36,73.44 53.35,72.45 58.89,72.45 59.39,71.96 59.39,70.56 60.94,69 60.94,61.91 64.74,58.12 72.34,58.12 v1(72.59,57.86)
  IN3 w0.124: v1(92.08,35.31) 92.2,35.18 95.38,35.18 96.09,35.89 98.63,35.89 98.65,35.87 105.72,35.87 105.74,35.89 108.03,35.89 109.12,34.8 109.86,34.8 v1(110.36,35.31) 110.62,35.56 113.92,35.56 114.94,36.58 121.16,36.58 123.19,34.54 127.56,34.54 128.4,35.38 v1(128.4,35.61) 128.4,36.2 127.51,37.08 127.51,42.93 v1(125.73,44.7)
  BOTTOM w0.107: U49.17 92.44,34.94 v1(92.08,35.31) 92.08,35.33 91.77,35.64 91.77,38.4 91.49,38.68 89.23,38.68 86.63,41.28 73.42,41.28 72.34,42.37 72.34,47.53 71.97,47.89 71.97,57.24 v1(72.59,57.86) ; v1(128.4,35.61) 128.73,35.61 129.02,35.32 U53.17 ; v1(125.73,44.7) 126.09,45.07 U55.17 ; U51.17 110.73,34.94 v1(110.36,35.31)
PCIE5RST_N: length 26.4
  TOP w0.107: 48.71,112.78 48.59,112.89 48.34,112.89 48.21,112.77 U3.2 ; 48.71,112.78 48.83,112.89 50.96,112.89 51.08,112.78 ; 48.71,112.78 U3.1 ; U5.1 v1(51.58,112.89) 51.2,112.89 51.08,112.78 ; 51.08,112.78 U5.2 ; v1(57.68,129.01) 58,128.69 J1.H10
  BOTTOM w0.107: v1(57.68,129.01) 56.95,128.27 56.34,128.27 54.69,126.62 54.69,124.28 53.26,122.86 53.26,119.33 52.86,118.92 52.86,115.19 51.58,113.91 v1(51.58,112.89)
PCIE_3V3_EN: length 114.6
  TOP w0.107: v1(52.07,137.41) 52.25,137.24 63.63,137.24 66.17,139.78 93.19,139.78 94.8,138.17 J1.L48 ; RZU25.1 v1(38.3,101.3) ; RZU27.1 v1(38.3,91.64)
  BOTTOM w0.107: v1(52.07,137.41) 50.29,137.41 46.23,133.35 42.8,133.35 38.61,129.16 38.61,119.38 37.41,118.19 37.41,102.18 v1(38.3,101.3) 37.54,100.53 37.54,92.41 v1(38.3,91.64) 38.3,87.55 38.02,87.27 RZ194.2 R661.2
PCIE_RST#: length 43.3
  TOP w0.107: v1(114.58,101.47) 114.58,106.68 115.43,107.53 U89.6 ; RZ67.1 v1(126.24,78.49)
  BOTTOM w0.107: v1(126.24,78.49) 126.24,78.21 125.63,77.6 115.21,77.6 114.45,78.36 114.45,101.35 v1(114.58,101.47)
PCIE_RXN1: length 83.2
  IN1 w0.122: v1(64.45,83.79) 64.22,83.57 64.05,83.57 63.88,83.74 63.88,84.6 65.57,86.29 65.57,86.47 66.88,87.78 66.88,87.93 v3(67.16,88.22)
  BOTTOM w0.114: v1(64.45,83.79) 64.22,83.57 64.03,83.57 63.63,83.16 63.63,80.88 61.42,78.67 61.42,76.28 60.91,75.77 43.51,75.77 39.07,71.32 39.07,70.43 34.16,65.53 34.16,45.34 32.84,44.02 25.65,44.02 22.43,40.8 22.43,40.22 CM82.2 ; U67.V23 v3(67.16,88.22)
PCIE_RXN2: length 73.3
  IN1 w0.122: v1(67.65,74.65) 67.42,74.42 67.21,74.42 66.7,74.93 66.7,80.67 66.93,80.9 66.93,82.17 68.32,83.56 68.32,85.97 68.63,86.28 68.63,87.28 v3(68.76,87.42)
  BOTTOM w0.114: v1(67.65,74.65) 67.42,74.42 64.92,74.42 62.05,71.56 62.05,70.92 61.06,69.93 56.97,69.93 56.08,69.04 56.08,64.97 55.58,64.47 47.32,64.47 46.69,63.83 46.69,59.51 45.54,58.37 45.54,51.89 42.16,48.51 42.16,43.92 39.19,40.94 39.19,37.55 CM94.2 ; U67.Y24 v3(68.76,87.42)
PCIE_RXN3: length 61.3
  IN1 w0.122: v1(68.48,71.12) 68.71,71.35 68.71,72.18 68.5,72.39 67.67,72.39 65.61,74.45 65.61,79.96 60.55,85.01 60.55,86.77 60.88,87.1 60.88,87.29 v3(60.76,87.42)
  BOTTOM w0.114: v3(60.76,87.42) 61.16,87.82 U67.L24 ; v1(68.48,71.12) 68.71,70.89 68.71,70.18 68.12,69.6 66.47,69.6 66.17,69.3 66.17,67.01 64.47,65.3 64.47,62.48 62.62,60.64 62.62,58.81 58.29,54.48 58.29,48.24 56.9,46.84 56.9,39.75 57.47,39.17 57.47,37.55 CM92.2
PCIE_RXN4: length 61.9
  IN1 w0.122: v3(57.56,87.42) 57.71,87.27 57.71,85.19 60.33,82.57 60.33,81.07 62.43,78.96 62.43,75.41 66.5,71.35 66.5,66.52 67.36,65.66 69.56,65.66 69.68,65.54 69.68,65.25 v1(69.45,65.02)
  BOTTOM w0.114: v3(57.56,87.42) 57.96,87.82 U67.G24 ; v1(69.45,65.02) 69.68,64.8 69.68,61.8 69.42,61.54 69.42,46.81 69.68,46.55 69.68,41.14 72.22,38.61 75.08,38.61 75.76,37.93 75.76,37.55 CM90.2
PCIE_RXN5: length 80.5
  IN1 w0.122: v3(55.96,88.22) 56.23,87.94 56.23,87.84 56.03,87.63 54.74,87.63 54.36,87.25 54.36,85.85 55.5,84.71 57.04,84.71 59.54,82.21 59.54,80.49 61.65,78.38 61.65,75.09 65.71,71.02 65.71,64.83 67.17,63.37 73.28,63.37 73.41,63.25 73.41,61.61 v1(73.18,61.38)
  BOTTOM w0.114: U67.E23 56.36,88.62 v3(55.96,88.22) ; CM88.2 94.05,37.55 94.05,39.2 90.81,42.44 90.81,49.66 84.99,55.47 74.85,55.47 73.41,56.92 73.41,61.15 v1(73.18,61.38)
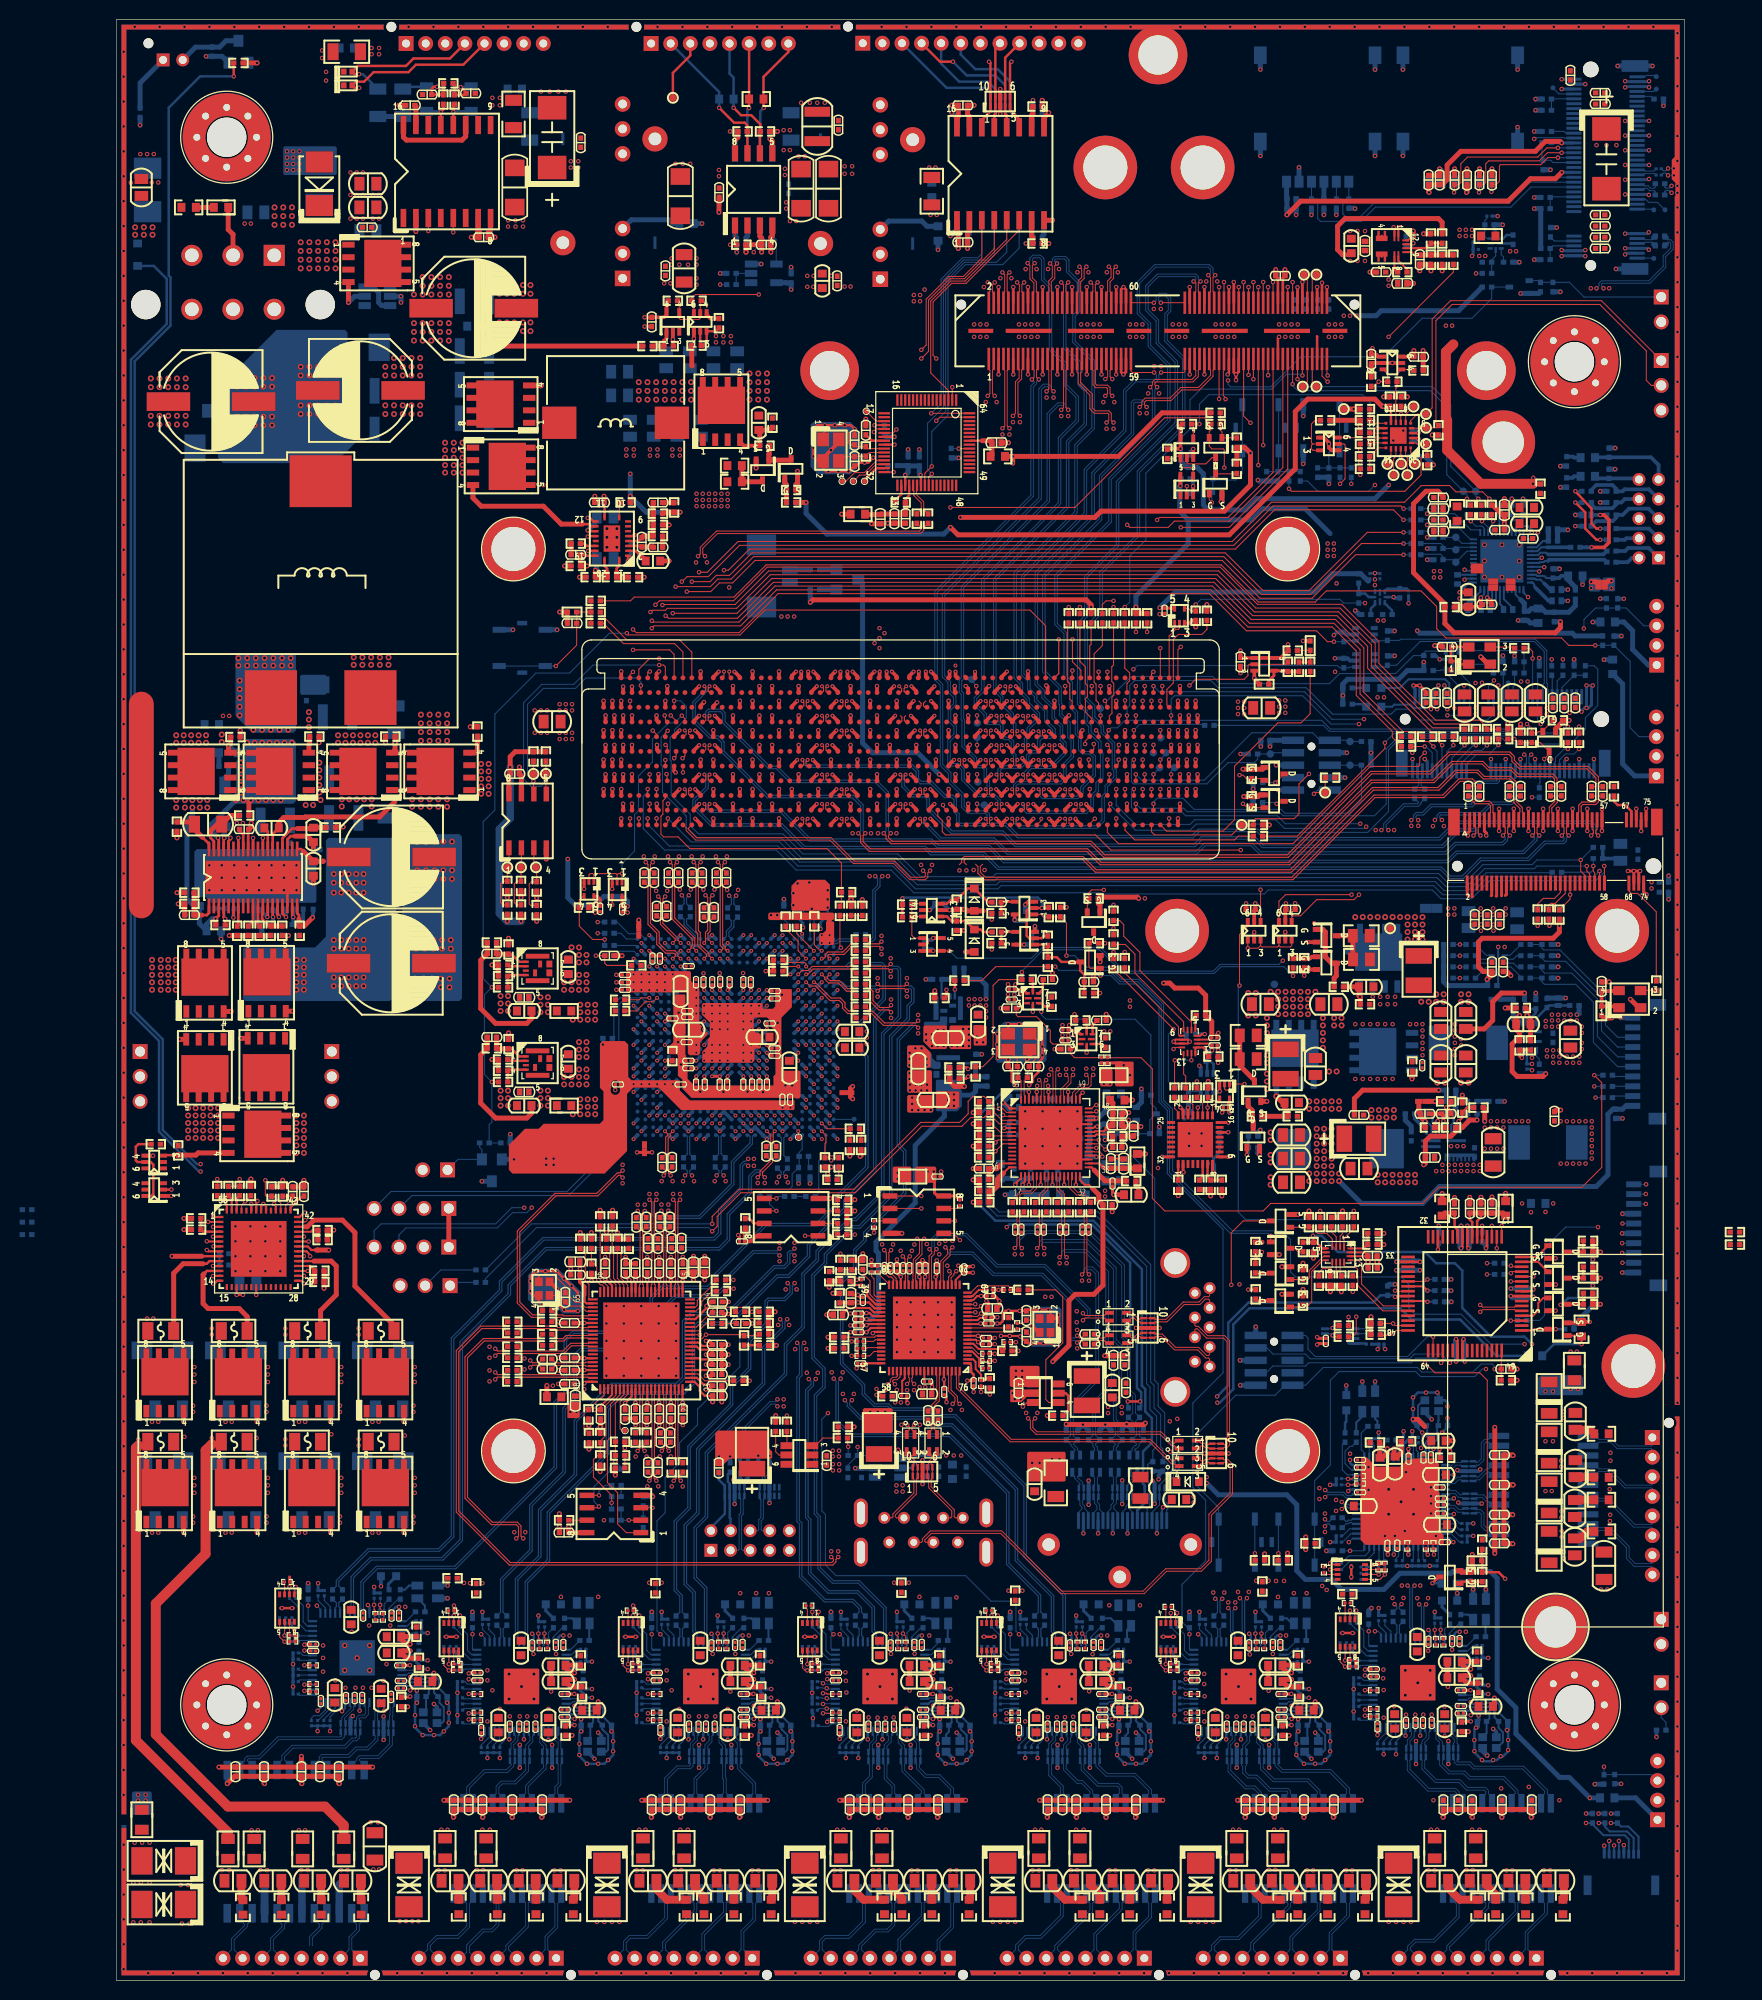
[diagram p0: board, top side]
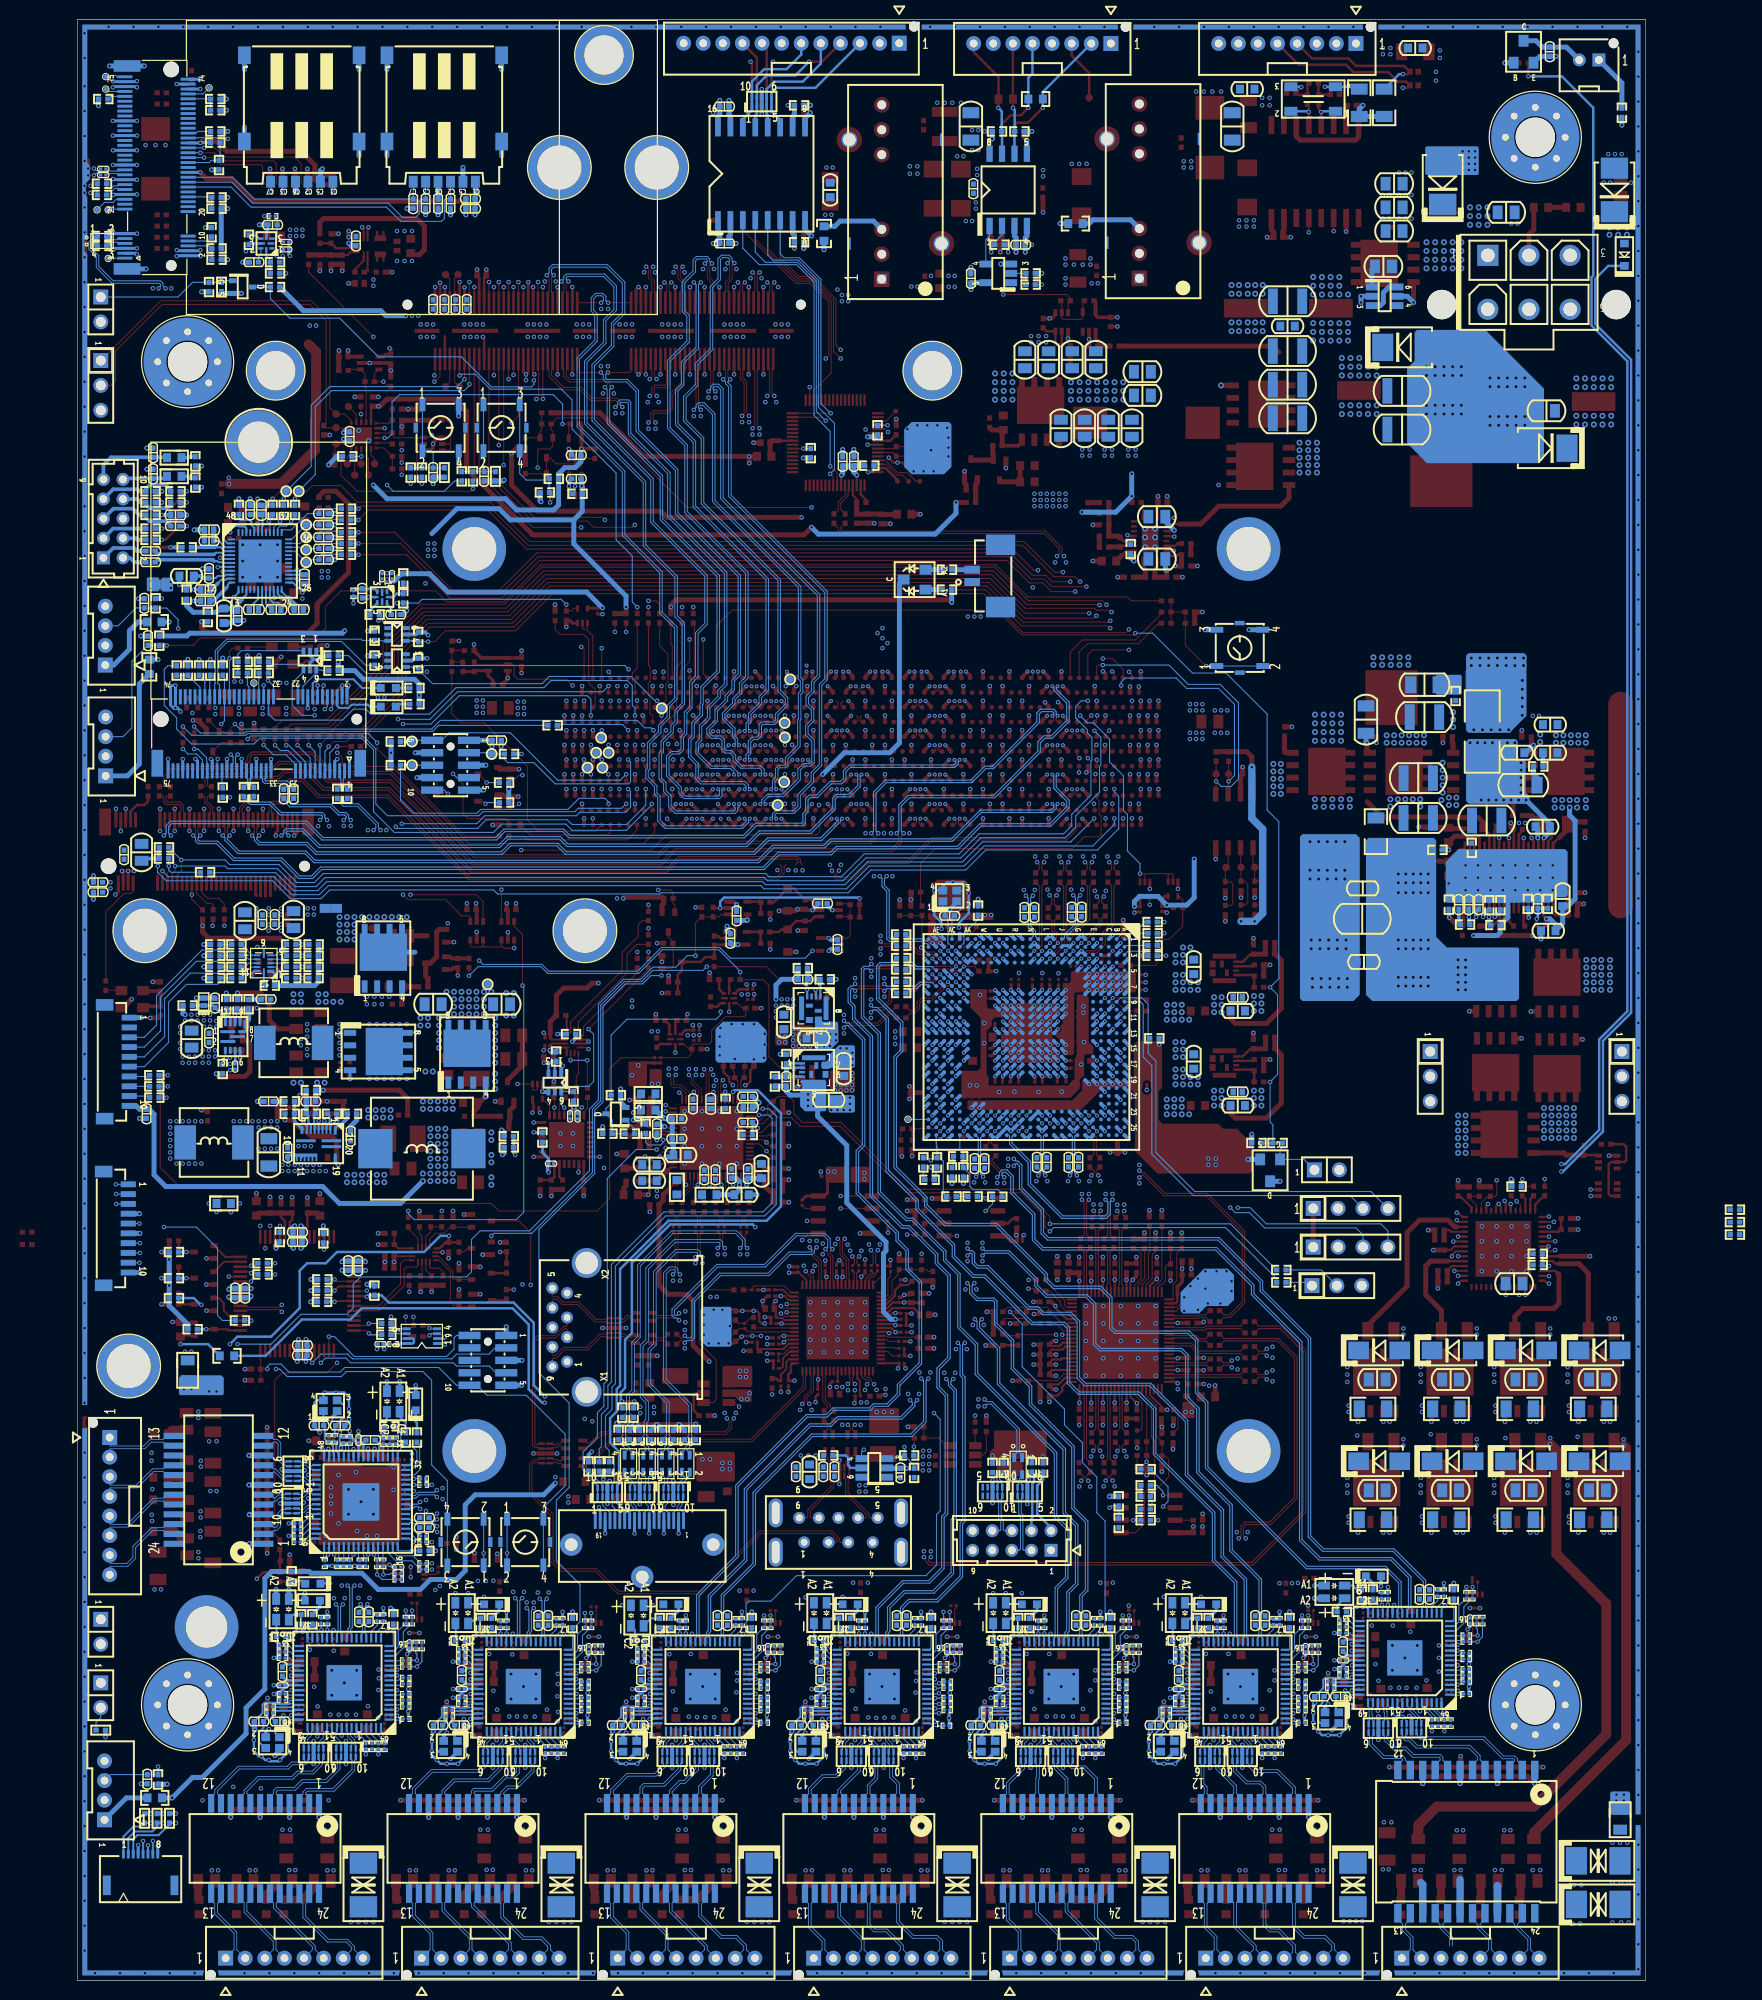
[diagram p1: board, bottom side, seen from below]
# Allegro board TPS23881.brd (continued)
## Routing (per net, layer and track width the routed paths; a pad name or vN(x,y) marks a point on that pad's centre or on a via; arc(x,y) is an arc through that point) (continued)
PCIE_RXN6: length 68.8
  TOP w0.114: RZ107.2 57.34,51.4 57.34,51.19 v1(57.57,50.97)
  IN1 w0.122: v1(57.57,50.97) 57.34,50.74 57.34,45.05 60.22,42.16 72.55,42.16 74.1,40.62 77.88,40.62 78.79,41.53 86.75,41.53 89.05,39.22 98.92,39.22 100.4,37.74 105.1,37.74 105.76,38.41 112.22,38.41 112.34,38.53 112.34,38.7 v1(112.11,38.93)
  BOTTOM w0.114: v1(112.11,38.93) 112.34,38.7 112.34,37.55 CM86.2
PCIE_RXN7: length 94.9
  TOP w0.114: v1(53.89,54.01) 53.66,54.24 53.66,54.44 RZ102.2
  IN1 w0.122: v1(130.4,38.37) 130.63,38.14 130.63,37 130.45,36.83 122.96,36.83 122.32,36.2 115.34,36.2 113.69,34.54 87.21,34.54 84.04,37.72 80.45,37.72 79.91,38.26 63.85,38.26 62.42,39.69 59.27,39.69 53.66,45.3 53.66,53.78 v1(53.89,54.01)
  BOTTOM w0.114: CM84.2 130.63,37.93 130.63,38.14 v1(130.4,38.37)
PCIE_RXN8: length 95.9
  TOP w0.114: v1(38.65,61.3) 38.87,61.53 39.46,61.53 RZ97.2
  IN1 w0.122: v1(123.3,46.32) 123.07,46.55 122.2,46.55 121.88,46.23 107.21,46.23 106.89,46.55 92.46,46.55 89.36,49.66 87.71,49.66 86.26,48.21 77.93,48.21 76.48,49.66 71.34,49.66 66.13,54.86 61.26,54.86 58.21,57.91 51.71,57.91 50.53,59.1 48.62,59.1 48.33,58.8 43.52,58.8 42.25,60.07 39.77,60.07 39.24,60.6 39.24,61.46 39.17,61.53 38.87,61.53 v1(38.65,61.3)
  BOTTOM w0.114: v1(123.3,46.32) 123.53,46.55 123.74,46.55 CM80.2
PCIE_RXP1: length 83.2
  IN1 w0.122: v1(64.45,83.08) 64.22,83.31 63.95,83.31 63.63,83.63 63.63,84.71 65.32,86.4 65.32,86.58 66.62,87.89 66.62,87.95 v3(66.36,88.22)
  BOTTOM w0.114: U67.U23 v3(66.36,88.22) ; CM81.2 22.68,40.22 22.68,40.69 25.75,43.76 32.95,43.76 34.42,45.23 34.42,65.43 39.32,70.33 39.32,71.22 43.62,75.51 61.01,75.51 61.67,76.17 61.67,78.56 63.88,80.77 63.88,83.06 64.14,83.31 64.22,83.31 v1(64.45,83.08)
PCIE_RXP2: length 73.4
  IN1 w0.122: v1(67.65,73.94) 67.42,74.17 67.1,74.17 66.45,74.82 66.45,80.77 66.67,81 66.67,82.27 68.07,83.67 68.07,86.08 68.38,86.39 68.38,87 v3(67.96,87.42)
  BOTTOM w0.114: v1(67.65,73.94) 67.42,74.17 65.02,74.17 62.31,71.45 62.31,70.82 61.16,69.67 57.08,69.67 56.34,68.93 56.34,64.87 55.68,64.21 47.43,64.21 46.94,63.72 46.94,59.41 45.8,58.26 45.8,51.79 42.42,48.41 42.42,43.81 39.44,40.84 39.44,37.56 CM93.2 ; U67.W24 v3(67.96,87.42)
PCIE_RXP3: length 61.5
  IN1 w0.122: v1(69.19,71.12) 68.96,71.35 68.96,72.29 68.61,72.64 67.77,72.64 65.86,74.55 65.86,80.06 60.81,85.12 60.81,86.67 61.14,87 61.14,87.17 61.38,87.42 v3(61.56,87.42)
  BOTTOM w0.114: v3(61.56,87.42) 61.96,87.82 U67.M24 ; v1(69.19,71.12) 68.96,70.89 68.96,70.08 68.22,69.34 66.57,69.34 66.42,69.19 66.42,66.9 64.72,65.2 64.72,62.38 62.88,60.54 62.88,58.71 58.55,54.38 58.55,48.13 57.15,46.74 57.15,39.86 57.73,39.28 57.73,37.56 CM91.2
PCIE_RXP4: length 62
  IN1 w0.122: v1(70.16,65.02) 69.93,65.25 69.93,65.64 69.66,65.91 67.46,65.91 66.75,66.62 66.75,71.45 62.69,75.52 62.69,79.07 60.58,81.18 60.58,82.68 57.96,85.29 57.96,87.02 v3(58.36,87.42)
  BOTTOM w0.114: v1(70.16,65.02) 69.93,64.8 69.93,61.69 69.67,61.43 69.67,46.92 69.93,46.66 69.93,41.25 72.32,38.86 75.18,38.86 76.02,38.03 76.02,37.56 CM89.2 ; U67.H24 58.76,87.82 v3(58.36,87.42)
PCIE_RXP5: length 80.5
  IN1 w0.122: v3(56.76,88.22) 56.49,87.94 56.49,87.73 56.13,87.38 54.84,87.38 54.61,87.14 54.61,85.96 55.6,84.96 57.15,84.96 59.8,82.32 59.8,80.59 61.9,78.49 61.9,75.19 65.97,71.13 65.97,64.94 67.28,63.63 73.38,63.63 73.66,63.35 73.66,61.61 v1(73.89,61.38)
  BOTTOM w0.114: CM87.2 94.3,37.56 94.3,39.3 91.06,42.55 91.06,49.76 85.09,55.73 74.96,55.73 73.66,57.03 73.66,61.15 v1(73.89,61.38) ; v3(56.76,88.22) 57.16,88.62 U67.F23
PCIE_RXP6: length 69.6
  TOP w0.114: v1(56.86,50.97) 57.09,51.19 57.09,51.4 RZ106.2
  IN1 w0.122: v1(56.86,50.97) 57.09,50.74 57.09,44.94 60.12,41.91 72.45,41.91 73.99,40.37 77.98,40.37 78.89,41.27 86.64,41.27 88.95,38.97 98.81,38.97 100.3,37.49 105.2,37.49 105.87,38.15 112.32,38.15 112.59,38.42 112.59,38.7 v1(112.82,38.93)
  BOTTOM w0.114: CM85.2 112.59,37.56 112.59,38.7 v1(112.82,38.93)
PCIE_RXP7: length 95.8
  TOP w0.114: v1(53.17,54.01) 53.4,54.24 53.4,54.44 RZ101.2
  IN1 w0.122: v1(131.11,38.37) 130.88,38.14 130.88,36.9 130.56,36.58 123.06,36.58 122.43,35.94 115.44,35.94 113.79,34.29 87.11,34.29 83.93,37.47 80.35,37.47 79.8,38.01 63.74,38.01 62.31,39.44 59.16,39.44 53.4,45.2 53.4,53.78 v1(53.17,54.01)
  BOTTOM w0.114: CM83.2 130.88,37.94 130.88,38.14 v1(131.11,38.37)
PCIE_RXP8: length 95.9
  TOP w0.114: v1(38.65,62.01) 38.87,61.79 39.46,61.79 RZ96.2
  IN1 w0.122: v1(38.65,62.01) 38.87,61.79 39.28,61.79 39.5,61.57 39.5,60.7 39.87,60.33 42.35,60.33 43.62,59.05 48.22,59.05 48.52,59.35 50.64,59.35 51.82,58.17 58.32,58.17 61.37,55.12 66.24,55.12 71.45,49.91 76.58,49.91 78.03,48.46 86.15,48.46 87.6,49.91 89.46,49.91 92.57,46.81 107,46.81 107.32,46.48 121.77,46.48 122.09,46.81 123.07,46.81 v1(123.3,47.03)
  BOTTOM w0.114: CM79.2 123.73,46.81 123.53,46.81 v1(123.3,47.03)
PCIE_TXN1: length 81.3
  TOP w0.114: v1(66.14,81.92) 65.91,82.14 65.91,82.42 66.93,83.44 66.93,83.73 CM47.2
  BOTTOM w0.114: U41.23 23.81,37.81 23.93,37.93 23.93,41.17 25.89,43.13 33.21,43.13 35.05,44.97 35.05,65.15 39.95,70.05 39.95,70.94 43.76,74.75 61.44,74.75 62.31,75.62 62.31,78.18 64.52,80.39 64.52,82.04 65.15,82.68 65.65,82.68 65.91,82.41 65.91,82.14 v1(66.14,81.92)
PCIE_TXN2: length 68.4
  IN1 w0.122: v1(69.17,74.65) 68.95,74.42 68.7,74.42 68.58,74.54 68.58,80.01 68.07,80.52 68.07,81.75 v1(68.3,81.98)
  BOTTOM w0.114: v1(68.3,81.98) 68.07,82.21 68.07,82.46 CM77.2 ; v1(69.17,74.65) 68.95,74.42 68.68,74.42 68.45,74.2 68.45,73.26 68.1,72.9 67.06,72.9 62.87,68.71 61.98,68.71 61.42,68.15 58.62,68.15 57.73,67.26 57.73,61.52 57.12,60.91 50.5,60.91 46.7,57.11 46.7,51.65 43.05,48.01 43.05,43.31 40.7,40.95 40.7,34.98 40.58,34.86 U43.23
PCIE_TXN3: length 56.3
  IN1 w0.122: v1(61.24,82.11) 61.47,81.88 61.47,81.2 64.72,77.95 64.72,74.23 67.34,71.61 67.35,71.61 67.39,71.57 67.39,69.69 67.94,69.13 67.94,67.67 v1(67.72,67.44)
  BOTTOM w0.114: v1(61.24,82.11) 61.47,82.33 61.47,82.59 CM74.2 ; U45.23 58.86,34.86 58.99,34.98 58.99,35.4 58.8,35.58 58.8,39.5 57.91,40.39 57.91,46.46 59.18,47.73 59.18,54.23 65.89,60.93 65.89,64.54 67.94,66.6 67.94,67.21 v1(67.72,67.44)
PCIE_TXN4: length 62.3
  IN1 w0.122: v1(58.01,82.11) 58.24,81.88 58.24,81.23 58.76,80.71 58.76,80.16 59.97,78.96 59.97,75.66 63.96,71.67 63.96,63.92 65.39,62.48 70.76,62.48 70.87,62.38 70.87,61.57 v1(70.64,61.34)
  BOTTOM w0.114: v1(70.64,61.34) 70.87,61.11 70.87,60.78 70.31,60.22 70.31,47.19 70.6,46.9 70.6,41.48 72.59,39.5 75.57,39.5 77.09,37.97 77.09,35.58 77.27,35.4 77.27,34.98 77.15,34.86 U47.23 ; v1(58.01,82.11) 58.24,82.33 58.24,82.59 CM76.2
PCIE_TXN5: length 75.9
  TOP w0.114: CM48.2 56.06,82.59 56.06,82.33 v1(55.83,82.11)
  IN1 w0.122: v1(74.32,59.18) 74.55,59.41 74.55,60.33 74.43,60.45 66.17,60.45 63.07,63.55 63.07,69.34 61.87,70.53 61.87,72.65 57.98,76.55 57.98,80.33 57.54,80.77 56.48,80.77 56.06,81.19 56.06,81.88 v1(55.83,82.11)
  BOTTOM w0.114: v1(74.32,59.18) 74.55,58.95 74.55,58.57 75.87,57.25 82.35,57.25 83.08,56.52 85.2,56.52 91.69,50.03 91.69,42.82 95.38,39.14 95.38,35.58 95.56,35.4 95.56,34.98 95.44,34.86 U49.23
PCIE_TXN6: length 75.7
  TOP w0.114: CM61.2 56.12,54.51 56.12,54.25 v1(56.35,54.03)
  IN1 w0.122: v1(113.44,37.97) 113.67,37.74 113.67,37.21 113.42,36.96 100.08,36.96 98.59,38.44 88.73,38.44 87.34,39.83 73.68,39.83 72.12,41.38 59.82,41.38 56.44,44.76 56.44,49.94 56.12,50.25 56.12,53.8 v1(56.35,54.03)
  BOTTOM w0.114: U51.23 113.73,34.86 113.85,34.98 113.85,35.4 113.67,35.58 113.67,37.74 v1(113.44,37.97)
PCIE_TXN7: length 95.5
  TOP w0.114: v1(55.08,50.98) 54.85,51.21 54.85,51.46 CM63.2
  IN1 w0.122: v1(131.72,40.27) 131.95,40.05 131.95,39.87 131.83,39.75 124.48,39.75 121.8,37.07 114.69,37.07 113.69,36.07 87.61,36.07 85.07,38.61 81.28,38.61 80.84,39.04 73.35,39.04 71.8,40.6 59.48,40.6 55.52,44.56 55.52,49.56 54.85,50.23 54.85,50.75 v1(55.08,50.98)
  BOTTOM w0.114: v1(131.72,40.27) 131.95,40.05 131.95,35.96 132.14,35.78 132.14,35.43 132.02,35.31 U53.23
PCIE_TXN8: length 97.7
  TOP w0.114: CM59.2 43.08,62.75 42.44,62.75 v1(42.21,62.52)
  IN1 w0.122: v1(42.21,62.52) 42.44,62.75 42.62,62.75 42.67,62.69 42.67,60.75 43.81,59.61 48.04,59.61 49.42,61 58.17,61 58.4,60.77 58.4,59.16 58.47,59.08 61.91,55.65 66.46,55.65 71.67,50.44 76.8,50.44 78.25,48.99 85.93,48.99 87.38,50.44 89.79,50.44 92.79,47.45 107.34,47.45 107.78,47.01 120.02,47.01 121.33,48.32 124.79,48.32 v1(125.01,48.09)
  BOTTOM w0.114: v1(125.01,48.09) 125.24,48.32 125.57,48.32 125.69,48.19 125.98,48.19 126.11,48.07 U55.23
PCIE_TXP1: length 80.5
  TOP w0.114: CM46.2 66.67,83.73 66.67,83.54 65.66,82.53 65.66,82.14 v1(65.43,81.92)
  BOTTOM w0.114: v1(65.43,81.92) 65.66,82.14 65.66,82.31 65.54,82.42 65.26,82.42 64.77,81.94 64.77,80.29 62.56,78.08 62.56,75.51 61.54,74.5 43.87,74.5 40.21,70.84 40.21,69.95 35.31,65.05 35.31,44.87 33.32,42.88 26,42.88 24.19,41.07 24.19,37.91 24.31,37.79 U41.24
PCIE_TXP2: length 68.4
  IN1 w0.122: v1(67.59,81.98) 67.82,81.75 67.82,80.41 68.33,79.9 68.33,74.44 68.6,74.17 68.95,74.17 v1(69.17,73.94)
  BOTTOM w0.114: CM78.2 67.82,82.46 67.82,82.21 v1(67.59,81.98) ; v1(69.17,73.94) 68.95,74.17 68.78,74.17 68.71,74.09 68.71,73.15 68.2,72.65 67.16,72.65 62.97,68.45 62.08,68.45 61.52,67.89 58.73,67.89 57.99,67.15 57.99,61.42 57.23,60.66 50.6,60.66 46.95,57.01 46.95,51.55 43.31,47.9 43.31,43.2 40.95,40.85 40.95,34.99 41.08,34.87 U43.24
PCIE_TXP3: length 56.3
  IN1 w0.122: v1(68.43,67.44) 68.2,67.67 68.2,69.24 67.64,69.8 67.64,71.67 67.45,71.86 67.45,71.86 64.97,74.34 64.97,78.05 61.72,81.31 61.72,81.88 v1(61.95,82.11)
  BOTTOM w0.114: v1(61.95,82.11) 61.72,82.33 61.72,82.59 CM73.2 ; v1(68.43,67.44) 68.2,67.21 68.2,66.49 66.14,64.44 66.14,60.83 59.44,54.12 59.44,47.62 58.17,46.35 58.17,40.49 59.05,39.6 59.05,35.69 59.24,35.5 59.24,34.99 59.36,34.87 U45.24
PCIE_TXP4: length 62.3
  IN1 w0.122: v1(71.35,61.34) 71.12,61.57 71.12,62.48 70.87,62.74 65.5,62.74 64.21,64.02 64.21,71.78 60.22,75.77 60.22,79.06 59.01,80.27 59.01,80.81 58.5,81.33 58.5,81.88 v1(58.72,82.11)
  BOTTOM w0.114: CM75.2 58.5,82.59 58.5,82.33 v1(58.72,82.11) ; U47.24 77.65,34.87 77.53,34.99 77.53,35.5 77.34,35.69 77.34,38.08 75.67,39.75 72.69,39.75 70.85,41.59 70.85,47.01 70.56,47.3 70.56,60.12 71.12,60.68 71.12,61.11 v1(71.35,61.34)
PCIE_TXP5: length 75.9
  TOP w0.114: CM49.2 56.31,82.59 56.31,82.33 v1(56.54,82.11)
  IN1 w0.122: v1(56.54,82.11) 56.31,81.88 56.31,81.3 56.58,81.03 57.64,81.03 58.23,80.44 58.23,76.65 62.13,72.75 62.13,70.64 63.32,69.44 63.32,63.66 66.27,60.71 74.53,60.71 74.8,60.44 74.8,59.41 v1(75.03,59.18)
  BOTTOM w0.114: U49.24 95.94,34.87 95.82,34.99 95.82,35.5 95.63,35.69 95.63,39.24 91.95,42.93 91.95,50.13 85.31,56.77 83.19,56.77 82.45,57.51 75.97,57.51 74.8,58.68 74.8,58.95 v1(75.03,59.18)
PCIE_TXP6: length 76.6
  TOP w0.114: v1(55.64,54.03) 55.87,54.25 55.87,54.53 CM60.2
  IN1 w0.122: v1(114.15,37.97) 113.92,37.74 113.92,37.1 113.52,36.7 99.97,36.7 98.49,38.19 88.62,38.19 87.24,39.57 73.57,39.57 72.02,41.13 59.71,41.13 56.18,44.65 56.18,49.83 55.87,50.15 55.87,53.8 v1(55.64,54.03)
  BOTTOM w0.114: v1(114.15,37.97) 113.92,37.74 113.92,35.69 114.1,35.5 114.1,34.99 114.23,34.87 U51.24
PCIE_TXP7: length 96.4
  TOP w0.114: v1(54.37,50.98) 54.6,51.21 54.6,51.49 CM62.2
  IN1 w0.122: v1(54.37,50.98) 54.6,50.75 54.6,50.12 55.27,49.45 55.27,44.45 59.38,40.35 71.69,40.35 73.25,38.79 80.74,38.79 81.17,38.35 84.96,38.35 87.5,35.81 113.79,35.81 114.8,36.82 121.91,36.82 124.59,39.5 131.94,39.5 132.21,39.77 132.21,40.05 v1(132.44,40.27)
  BOTTOM w0.114: v1(132.44,40.27) 132.21,40.05 132.21,36.07 132.39,35.88 132.39,35.37 132.52,35.25 U53.24
PCIE_TXP8: length 97.7
  TOP w0.114: CM58.2 43.1,63 42.44,63 v1(42.21,63.23)
  IN1 w0.122: v1(125.01,48.8) 124.79,48.57 121.22,48.57 119.91,47.26 107.88,47.26 107.45,47.7 92.89,47.7 89.9,50.69 87.28,50.69 85.83,49.25 78.36,49.25 76.91,50.69 71.77,50.69 66.56,55.9 62.02,55.9 58.65,59.26 58.65,60.88 58.28,61.25 49.32,61.25 47.93,59.87 43.92,59.87 42.93,60.86 42.93,62.8 42.72,63 42.44,63 v1(42.21,63.23)
  BOTTOM w0.114: U55.24 126.17,48.57 126.04,48.45 125.8,48.45 125.67,48.57 125.24,48.57 v1(125.01,48.8)
PCIE_WAKE#: length 228.6
  TOP w0.107: v1(100.41,102.49) 100.36,102.54 Q3.G 99.35,103.24 99.21,103.38 99.21,105.77 R2.1 99.24,105.97 99.69,106.43 Q50.D
  IN1 w0.124: v1(19.56,38.23) 19.56,37.97 20.45,37.08 29.84,37.08 30.86,36.07 35.56,36.07 v1(36.32,35.31) 37.47,34.16 50.29,34.16 51.69,35.56 54.36,35.56 v1(54.61,35.31) 54.61,34.8 55.24,34.16 67.18,34.16 68.58,35.56 72.9,35.56 v1(73.15,35.31)
  IN3 w0.124: v1(125.86,43.81) 126.01,43.81 127.08,42.75 127.08,36.91 127.76,36.22 v1(127.76,35.61) 127.76,35.58 127.15,34.97 123.37,34.97 121.34,37.01 114.76,37.01 113.74,35.99 110.16,35.99 v1(109.47,35.31) 108.46,36.32 105.56,36.32 105.54,36.3 98.82,36.3 98.81,36.32 95.91,36.32 95.2,35.61 92.71,35.61 92.5,35.81 91.69,35.81 v1(91.19,35.31) 90.3,36.2 77.34,36.2 76.71,35.56 74.68,35.56 74.42,35.81 73.66,35.81 v1(73.15,35.31)
  BOTTOM w0.107: v1(100.41,102.49) 101.47,102.49 102.32,101.64 104.1,101.64 106.37,99.37 106.37,89.59 107.21,88.75 107.21,82.3 112.9,76.61 112.9,61.98 109.82,58.89 109.82,50.28 111.12,48.97 111.12,42.8 108.71,40.39 108.71,36.58 109.32,35.97 R394.1 v1(109.47,35.31) 109.47,33.83 109.58,33.72 U51.16 ; U55.16 127.31,43.92 127.21,43.81 v1(125.86,43.81) R442.1 ; U53.16 127.87,34.1 127.76,34.21 v1(127.76,35.61) R418.1 ; R274.1 v1(19.56,38.23) 19.56,36.75 19.66,36.64 U41.16 ; U45.16 54.72,33.72 54.61,33.83 v1(54.61,35.31) R322.1 ; R346.1 72.9,35.56 v1(73.15,35.31) 72.9,35.05 72.9,33.9 73.08,33.72 U47.16 ; R298.1 v1(36.32,35.31) 36.32,33.83 36.43,33.72 U43.16 ; U49.16 91.37,33.72 91.19,33.91 v1(91.19,35.31) R370.1
PCIE_WAKE_N: length 95.1
  TOP w0.107: v1(56.25,118.52) 56.25,118.11 J1.A8
  BOTTOM w0.107: v1(56.25,118.52) 58.6,116.18 58.65,116.12 67.65,116.12 69.7,114.08 79.37,114.08 81.7,111.76 89.77,111.76 90.09,112.07 134.56,112.07 135.47,111.16 137.93,111.16 139.76,112.99 146.44,112.99 RZ178.2
PGANG: length 2.6
  TOP w0.107: R166.2 R168.1 87.93,63.92 87.3,64.55 U20.5
PLTRST#_TPM: length 2
  TOP w0.107: U18.17 111.82,89.2 U19.4
POE_56: length 3.2
  TOP w0.254: U83.20 18.84,115.4 19.06,115.18
  TOP w0.508: 21.11,114.17 21.08,114.15 C460.2 19.06,115.18
  vias: v2(18.36,104.09) v2(18.36,103.33) v2(18.36,102.57) v2(18.36,101.8) v2(18.36,101.04) v2(19.13,104.09) v2(19.13,103.33) v2(19.13,102.57) v2(19.13,101.8) v2(19.13,101.04) v2(22.17,112.85) v2(22.17,111.96) v2(22.17,110.95) v2(22.17,106.12) v2(22.17,105.23) v2(22.17,102.31) v2(22.17,101.42) v2(22.94,112.85) v2(22.94,111.96) v2(22.94,110.95) v2(22.94,106.12) v2(22.94,105.23) v2(22.94,102.31) v2(22.94,101.42) v2(23.7,112.85) v2(23.7,111.96) v2(23.7,110.95) v2(23.7,106.12) v2(23.7,105.23) v2(23.7,102.31) v2(23.7,101.42) v2(24.46,112.85) v2(24.46,111.96) v2(24.46,110.95) v2(24.46,106.12) v2(24.46,105.23) v2(24.46,102.31) v2(24.46,101.42) v2(25.22,112.85) v2(25.22,111.96) v2(25.22,110.95) v2(25.22,106.12) v2(25.22,105.23) v2(25.22,102.31) v2(25.22,101.42)
POE_EN: length 178.5
  TOP w0.254: RZ78.2 v1(115.47,70.46) ; R740.1 v1(11.1,108.28) ; Q69.2 v1(5.61,80.66)
  TOP w0.279: U83.4 10.94,108.44 v1(11.1,108.28)
  IN3 w0.254: v1(5.61,80.66) 5.61,83.64 6.12,84.15 ; 6.12,84.15 5.61,84.66 5.61,97.05 6.17,97.61 12.01,97.61 12.52,98.12 12.52,107.26 12.27,107.52 11.86,107.52 v1(11.1,108.28) ; 6.12,84.15 9.09,84.15 9.8,83.44 21.58,83.44 23.94,81.08 35.39,81.08 39.98,76.49 39.98,70.69 46.76,63.91 46.76,60.2 47.4,59.56 49.43,59.56 51.05,57.94 61.38,57.94 62.65,56.66 68.02,56.66 69.6,55.08 87.15,55.08 87.15,55.08 105.62,55.08 106.39,55.85 108.24,55.85 111.31,58.93 111.31,59.8 113.07,61.56 113.07,68.07 v1(115.47,70.46)
  BOTTOM w0.254: v1(11.1,108.28) 11,108.38 C471.2 9.99,109.33 R742.2
POE_EN#: length 7.5
  TOP w0.107: U14.8 123.1,73.46 121.95,72.31 121.95,69.22 121.59,68.86 RB55.1 120.89,68.69 119.76,68.69
POE_FAST_SHUTDOWN: length 2
  TOP w0.229: RZ62.1 10.36,80.04 11.26,79.13 U65.56
POE_GATE:
  vias: v2(7.32,88.98) v2(7.32,88.21) v2(7.32,87.45) v2(7.32,86.69) v2(7.32,85.93) v2(8.08,88.98) v2(8.08,88.21) v2(8.08,87.45) v2(8.08,86.69) v2(8.08,85.93) v2(8.84,88.98) v2(8.84,88.21) v2(8.84,87.45) v2(8.84,86.69) v2(8.84,85.93) v2(9.6,88.98) v2(9.6,88.21) v2(9.6,87.45) v2(9.6,86.69) v2(9.6,85.93) v2(10.36,88.98) v2(10.36,88.21) v2(10.36,87.45) v2(10.36,86.69) v2(10.36,85.93)
POE_IN: length 20.6
  TOP w2.54: 2.54,109.6 2.54,130.18
  vias: v2(3.51,163.4) v2(3.51,162.51) v2(3.51,159.59) v2(3.51,158.7) v2(3.63,104.09) v2(3.63,103.33) v2(3.63,102.57) v2(3.63,101.8) v2(3.63,101.04) v2(4.39,163.4) v2(4.39,162.51) v2(4.39,159.59) v2(4.39,158.7) v2(4.52,104.09) v2(4.52,103.33) v2(4.52,102.57) v2(4.52,101.8) v2(4.52,101.04) v2(5.28,163.4) v2(5.28,162.51) v2(5.28,159.59) v2(5.28,158.7) v2(5.28,104.09) v2(5.28,103.33) v2(5.28,102.57) v2(5.28,101.8) v2(5.28,101.04) v2(6.05,104.09) v2(6.05,103.33) v2(6.05,102.57) v2(6.05,101.8) v2(6.05,101.04) v2(6.17,163.4) v2(6.17,162.51) v2(6.17,159.59) v2(6.17,158.7) v2(7.06,163.4) v2(7.06,162.51) v2(7.06,159.59) v2(7.06,158.7)
POE_INT#: length 166.8
  TOP w0.107: v1(15.19,81.61) 15.19,80.09 15.3,79.98 RB45.1 16.05,79.98 16.76,79.28 U65.45 ; U13.17 v1(141.33,76.96)
  IN3 w0.124: v1(15.19,81.61) 15.7,81.1 21.67,81.1 25.6,77.17 36.59,77.17 38.2,75.55 38.2,69.72 42.87,65.05 42.87,59.84 47.01,55.7 60.8,55.7 61.56,54.94 67.39,54.94 71.89,50.44 77.71,50.44 79.29,52.01 81.27,52.01 81.65,51.63 95.91,51.63 97.46,53.18 107.6,53.18 113.64,59.23 113.64,60.48 116.71,63.55 122.66,63.55 123.31,64.2 123.31,70.96 124.49,72.14 128.85,72.14 132.78,76.07 140.44,76.07 v1(141.33,76.96)
POE_OUT1A: length 44.1
  TOP w1.016: FB8.2 11.38,15.09 1.98,24.49 1.98,54.31 v1(2.24,54.56)
  vias: v1(2.24,55.19)
POE_OUT1B: length 56.4
  TOP w1.016: v1(9.73,54.69) 9.09,54.05 9.09,43.51 4.01,38.43 4.01,25.1 11.38,17.73 21.29,17.73 23.19,15.82 FB11.2
  vias: v1(9.73,55.32)
POE_OUT2: length 70.4
  IN2 w1.016: 3.71,66.55 3.76,66.5 3.76,59.89 5.41,58.24 5.41,45.03 13.36,37.08 26.11,37.08 26.95,36.25 26.95,34.92 28.6,33.27 28.6,19.71 32.03,16.28 32.03,15.37
  vias: v1(3.12,67.51) v1(3.76,67.51) v1(33.15,15.37) v1(33.78,15.37)
POE_OUT3: length 84.8
  IN2 w1.016: 10.74,65.1 10.74,62.56 13.16,60.15 13.16,42.37 16.28,39.24 30.12,39.24 32.66,36.7 32.66,34.82 33.3,34.19 48.87,34.19 50.55,32.51 50.55,27.51 52.11,25.95 52.11,16.12 53.11,15.11
  vias: v1(9.73,66.5) v1(9.73,65.86) v1(53.34,15.37) v1(53.98,15.37)
POE_OUT4: length 85.2
  IN2 w1.016: 17.17,54.1 17.22,54.05 17.22,44.27 19.46,42.04 37.24,42.04 40.87,38.4 43.76,38.4 44.3,37.87 49.17,37.87 50.72,36.32 57.43,36.32 59.59,34.16 67.36,34.16 68.63,32.89 68.63,27.41 70.48,25.55 70.48,17.3 72.54,15.24
  vias: v1(17.22,55.19) v1(17.22,54.56) v1(73.53,15.37) v1(74.17,15.37)
POE_OUT5: length 113.5
  IN2 w1.016: 18.24,65.86 18.24,64.21 19.25,63.2 19.25,59 20.9,57.35 20.9,45.29 22.12,44.07 37.87,44.07 41.17,40.77 52.04,40.77 54.33,38.48 61.37,38.48 63.14,36.7 68.12,36.7 68.38,36.45 84.07,36.45 86.69,33.83 86.69,28.35 88.82,26.21 88.82,18.54 92,15.37 92.61,15.37
  vias: v1(17.22,66.5) v1(17.22,65.86) v1(93.73,15.37) v1(94.36,15.37)
POE_OUT6: length 111.3
  IN2 w1.016: 113.56,15.37 113.18,15.37 108.28,20.27 108.28,24.61 105.82,27.08 105.82,29.01 104.44,30.38 104.44,32.99 103.15,34.29 95.78,34.29 93.73,36.35 86.51,36.35 84.79,38.07 80.85,38.07 80.24,38.68 69.09,38.68 67.26,40.51 58.06,40.51 55.65,42.93 41.43,42.93 35.89,48.46 28.52,48.46 24.66,52.32 24.66,53.59
  IN3 w1.016: v1(24.71,55.19) v1(24.71,54.56)
  vias: v1(113.92,15.37) v1(114.55,15.37)
POE_OUT7: length 140.9
  IN2 w1.016: 25.17,65.15 26.24,64.08 31.83,64.08 33.22,62.69 33.22,53.92 38.38,48.76 40.8,48.76 44.86,44.7 56.54,44.7 59.11,42.14 67.89,42.14 69.24,40.79 77.19,40.79 78.05,41.66 85.37,41.66 88.37,38.66 98.4,38.66 100.1,36.96 103.15,36.96 103.78,36.32 112.17,36.32 113.18,35.31 113.18,33.53 114.33,32.38 117.37,32.38 118.77,30.99 118.77,22.1 120.84,20.03 128.23,20.03 132.89,15.37 133.38,15.37
  vias: v1(24.71,66.5) v1(24.71,65.86) v1(134.11,15.37) v1(134.75,15.37)
POE_RST#: length 2.8
  TOP w0.107: RB46.1 17.97,79.98 CA248.1 17.98,79.79 17.26,79.07 U65.44
POE_SCL: length 165.6
  TOP w0.107: U65.53 12.76,79.08 v1(13.14,79.46) RB44.1 ; U13.12 v1(144.55,71.8)
  IN3 w0.124: v1(144.55,71.8) 143.66,70.91 143.66,69.77 143.13,69.24 141.45,69.24 140.97,69.72 138.25,69.72 134.69,66.17 131.72,66.17 130.58,65.02 125.35,65.02 123.01,62.69 117.53,62.69 115.77,60.93 115.77,60.1 108,52.32 97.82,52.32 95.7,50.2 81.5,50.2 80.56,51.15 79.64,51.15 78.07,49.58 71.54,49.58 67.03,54.08 61.21,54.08 60.48,54.81 46.69,54.81 40.1,61.4 40.1,66.48 37.31,69.27 37.31,75.18 36.22,76.28 25.2,76.28 21.44,80.04 13.27,80.04 13.14,79.91 v1(13.14,79.46)
POE_SDA: length 162.8
  TOP w0.107: U13.11 v1(142.27,71.3) ; v1(12.57,81.74) RZ64.2 RZ63.2
  IN3 w0.124: v1(142.27,71.3) 141.35,70.38 138.3,70.38 135.45,67.53 129.4,67.53 127.91,66.04 125.76,66.04 122.83,63.12 117.35,63.12 115.34,61.11 115.34,60.27 107.82,52.75 107.78,52.75 97.64,52.75 96.08,51.2 81.11,51.2 80.73,51.58 79.47,51.58 77.89,50.01 71.71,50.01 67.21,54.51 61.39,54.51 60.66,55.24 46.87,55.24 40.52,61.58 40.52,66.66 37.74,69.44 37.74,75.36 36.4,76.71 25.37,76.71 21.61,80.47 13.67,80.47 12.57,81.56 v1(12.57,81.74)
  BOTTOM w0.107: RB65.1 12.67,81.64 v1(12.57,81.74)
POE_SHUTDOWN: length 155.5
  TOP w0.107: RZ62.2 v1(10.29,81.74) ; RZU30.2 v1(122.81,78.49)
  IN3 w0.124: v1(122.81,78.49) 123.8,77.5 123.8,71.81 123.05,71.06 123.05,64.3 122.55,63.8 116.61,63.8 113.39,60.58 113.39,59.33 108.83,54.77 106.84,54.77 106.07,54.01 92.2,54.01 90.08,51.88 81.76,51.88 81.37,52.26 79.13,52.26 77.55,50.69 72,50.69 67.49,55.19 61.67,55.19 60.91,55.95 47.16,55.95 43.12,59.99 43.12,65.16 38.46,69.82 38.46,75.66 36.69,77.42 25.7,77.42 20.88,82.24 11.38,82.24 10.87,81.74 v1(10.29,81.74)
POE_VCC: length 1.4
  TOP w0.229: U65.17 v1(12.26,69.93) v1(12.9,69.93)
  vias: v1(7.95,62.56) v1(7.95,61.8) v1(7.95,61.04) v1(7.95,51.26) v1(7.95,50.5) v1(7.95,49.73) v1(13.79,15.32) v1(14.43,15.32) v1(15.44,62.56) v1(15.44,61.8) v1(15.44,61.04) v1(15.44,51.26) v1(15.44,50.5) v1(15.44,49.73) v1(18.62,15.32) v1(19.25,15.32) v1(22.94,62.56) v1(22.94,61.8) v1(22.94,61.04) v1(22.94,51.26) v1(22.94,50.5) v1(22.94,49.73) v1(30.43,62.56) v1(30.43,61.8) v1(30.43,61.04) v1(30.43,51.26) v1(30.43,50.5) v1(30.43,49.73) v1(37.34,15.37) v1(38.1,15.37) v1(57.53,15.37) v1(58.29,15.37) v1(77.72,15.37) v1(78.49,15.37) v1(97.92,15.37) v1(98.68,15.37) v1(118.11,15.37) v1(118.87,15.37) v1(138.3,15.37) v1(139.06,15.37) v2(18.36,88.21) v2(18.36,87.45) v2(18.36,86.69) v2(18.36,85.93) v2(18.36,85.17) v2(18.36,84.4) v2(19.13,88.21) v2(19.13,87.45) v2(19.13,86.69) v2(19.13,85.93) v2(19.13,85.17) v2(19.13,84.4)
POWER_BTN_DEB_N: length 47
  TOP w0.107: RB7.2 v1(131.06,159.77) 131.03,159.73 U6.8 ; v1(106.5,135.89) J1.L61
  IN1 w0.124: v1(131.06,159.77) 127.1,159.77 125.24,157.91 125.24,156.48 122.14,153.38 118.11,153.38 113.18,148.46 113.18,137.29 111.15,135.25 107.14,135.25 v1(106.5,135.89)
PREXT1: length 4
  BOTTOM w0.107: R558.1 68.1,108.2 69.55,106.76 69.55,105.83 U67.AB2
PREXT2: length 1.3
  TOP w0.305: v3(55.96,93.82) 55.98,93.8 R559.1
  BOTTOM w0.107: v3(55.96,93.82) 56.36,94.22 U67.E16
PSE_D1: length 25.7
  TOP w0.229: U65.3 v1(9.86,76.87)
  IN1 w0.508: v1(6.93,55.45) 6.55,55.45 5.54,56.46 5.54,72.47 7.44,74.37 7.44,76.02 7.95,76.53 9.52,76.53 v1(9.86,76.87)
PSE_D2: length 24.4
  TOP w0.229: U65.5 v1(9.86,75.87)
  IN3 w0.508: v1(14.3,55.32) 14.55,55.32 15.19,55.96 15.19,57.23 14.15,58.27 14.15,65.76 11.25,68.66 11.25,75.01 10.36,75.9 9.88,75.9 v1(9.86,75.87)
PSE_D3: length 11.2
  TOP w0.229: 10.11,73.37 U65.10
  TOP w0.254: 10.11,73.37 9.48,73.37 9.22,73.1 8.84,73.1
  TOP w0.508: 8.84,73.1 6.81,73.1 5.84,72.14 F3.1
PSE_D4: length 11.4
  TOP w0.254: U65.12 9.22,72.37 8.94,72.09
  TOP w0.508: F4.1 13.34,67.72 12.52,68.53 9.35,68.53 8.84,69.04 8.84,71.98 8.94,72.09
PSE_D5: length 19.3
  TOP w0.203: U65.31 v1(19.51,72.37)
  IN1 w0.508: v1(19.51,72.37) 19.61,72.37 20.27,71.7 20.27,56.59 21.16,55.7 v1(21.92,55.7)
PSE_D6: length 11.5
  TOP w0.254: U65.33 20.14,73.37
  TOP w0.508: 20.14,73.37 21.92,73.37 22.43,72.86 22.43,69.93 20.83,68.33 F6.1
PSE_D7: length 28.7
  TOP w0.229: U65.38 v1(19.13,75.87)
  IN3 w0.508: v1(29.41,55.58) 29.03,55.96 25.73,55.96 25.1,56.59 25.1,61.8 22.81,64.08 22.81,74.4 21.11,76.1 19.36,76.1 v1(19.13,75.87)
PSE_D8: length 18.4
  TOP w0.229: U65.40 19.25,76.87
  TOP w0.508: 19.25,76.87 19.46,76.87 20.14,77.55 23.06,77.55 24.33,76.28 24.33,70.82 28.32,66.83 F8.1
PSE_GATE1: length 42.8
  TOP w0.203: U65.1 10.04,77.87 9.98,77.93 v1(9.86,77.93)
  TOP w0.508: v1(6.86,45.67) Q20.4
  IN1 w0.508: v1(6.86,45.67) 6.86,52.6 2.24,57.23 2.24,75.18 5.92,78.87 8.92,78.87 v1(9.86,77.93)
PSE_GATE2: length 34.7
  TOP w0.229: U65.7 v1(9.91,74.87)
  TOP w0.508: v1(14.35,45.67) Q21.4
  IN1 w0.508: v1(9.91,74.87) 10.51,74.87 10.87,74.51 10.87,69.8 16.21,64.47 16.21,54.81 14.35,52.96 v1(14.35,45.67)
PSE_GATE3: length 21
  TOP w0.229: U65.8 9.35,74.37 v1(9.22,74.5)
  TOP w0.508: v1(6.86,56.97) Q22.4
  IN1 w0.508: v1(9.22,74.5) 9.22,73.86 6.86,71.5 v1(6.86,56.97)
PSE_GATE4: length 17.9
  TOP w0.229: U65.14 10.28,71.37 9.98,71.07 v1(9.86,71.07)
  TOP w0.508: v1(14.35,56.97) Q23.4
  IN1 w0.508: v1(9.86,71.07) 9.86,69.16 14.35,64.67 v1(14.35,56.97)
PSE_GATE5: length 29.9
  TOP w0.203: v1(19.13,71.07) 18.83,71.37 U65.29
  TOP w0.508: v1(21.84,45.67) Q24.4
  IN1 w0.508: v1(21.84,45.67) 21.84,51.84 17.35,56.34 17.35,63.7 19.06,65.42 19.06,71.01 v1(19.13,71.07)
PSE_GATE6: length 20.9
  TOP w0.229: U65.35 19.39,74.37 19.76,73.99 v1(19.76,73.86)
  TOP w0.508: v1(21.84,56.97) Q25.4
  IN1 w0.508: v1(19.76,73.86) 22.3,71.32 22.3,66.62 21.84,66.17 v1(21.84,56.97)
PSE_GATE7: length 36.5
  TOP w0.229: 20.4,74.5 19.89,74.5 19.52,74.87 U65.36
  TOP w0.508: v1(29.34,45.67) Q26.4 ; v1(21.66,74.49) 20.53,74.49 20.52,74.5 20.4,74.5
  IN1 w0.508: v1(21.66,74.49) 24.46,71.69 24.46,69.16 28.14,65.48 28.14,55.32 29.34,54.13 v1(29.34,45.67)
PSE_GATE8: length 29.3
  TOP w0.229: v1(19.25,78.31) 19.13,78.31 18.68,77.87 U65.42
  TOP w0.508: v1(29.34,56.97) Q27.4
  IN1 w0.508: v1(29.34,56.97) 29.34,67.21 25.73,70.82 25.73,72.49 23.34,74.88 23.34,76.99 22.02,78.31 v1(19.25,78.31)
PSE_SEN1: length 38.9
  TOP w0.203: U65.2 v1(9.35,77.37)
  IN3 w0.508: v1(9.35,77.37) 7.72,75.74 4.75,75.74 2.21,73.2 2.21,56.49 3.63,55.07 v1(3.63,45.67) v1(4.27,45.67)
PSE_SEN2: length 34.7
  TOP w0.229: v1(9.22,75.39) 9.24,75.37 U65.6
  IN3 w0.508: v1(9.22,75.39) 8.84,75.39 6.93,73.48 6.93,60.66 8.71,58.88 8.71,54.56 11.13,52.15 v1(11.13,45.67) v1(11.76,45.67)
PSE_SEN3: length 23.1
  TOP w0.254: 8.71,73.87 U65.9
  TOP w0.508: v1(5.66,73.87) 8.71,73.87
  IN3 w0.508: v1(3.63,56.97) v1(4.27,56.97) 5.66,58.37 5.66,73.86 v1(5.66,73.87)
PSE_SEN4: length 18.6
  TOP w0.229: U65.13 9.89,71.87 v1(9.86,71.83)
  IN3 w0.508: v1(11.76,56.97) v1(11.13,56.97) 11.13,61.93 8.33,64.72 8.33,71.2 8.97,71.83 v1(9.86,71.83)
PSE_SEN5: length 30.3
  TOP w0.229: U65.30 v1(19.13,71.87)
  IN3 w0.508: v1(19.13,71.87) 18.53,71.87 16,69.34 16,64.31 17.53,62.79 17.53,56.54 18.62,55.45 v1(18.62,45.67) v1(19.25,45.67)
PSE_SEN6: length 19
  TOP w0.229: U65.34 v1(19.12,73.87)
  IN3 w0.508: v1(19.12,73.87) 19.12,73.61 20.16,72.57 20.16,57.88 v1(19.25,56.97) v1(18.62,56.97)
PSE_SEN7: length 34.4
  TOP w0.229: U65.37 v1(19.61,75.37)
  IN3 w0.508: v1(19.61,75.37) 21.92,73.06 21.92,60.78 23.7,59 23.7,56.97 23.44,56.72 23.44,52.53 24.33,51.64 24.33,47.45 v1(26.11,45.67) v1(26.75,45.67)
PSE_SEN8: length 25.3
  TOP w0.229: v1(19.25,77.55) 19.07,77.37 U65.41
  IN1 w0.508: v1(19.25,77.55) 19.76,77.55 20.52,76.78 20.52,74.24 23.32,71.45 23.32,64.59 26.11,61.8 v1(26.11,56.97) v1(26.75,56.97)
PSELF: length 4.9
  TOP w0.203: U20.6 87.41,64.95 87.96,64.4 90.21,64.4 R165.1
  TOP w0.254: R165.1 90.61,64.43 RA8.1
PWM01_BKLIGHT_GMSL_INT3_GP68: length 7.4
  TOP w0.107: RZ18.2 102.87,133.86 103.37,133.36 103.37,132.57 103.1,132.3 J1.K57
PWREN1#: length 2.3
  TOP w0.203: U20.18 87.22,69.75 87.27,69.79 87.35,69.79 87.99,70.43 R155.2
PWREN2#: length 2.8
  TOP w0.203: R156.2 88.22,62.43 88.01,62.64 88.01,63.43 87.3,64.15 U20.4
PWREN3#: length 1.9
  TOP w0.107: R157.2 76.54,64.47 76.63,64.55 U20.53
PWREN4#: length 1.9
  TOP w0.107: U20.38 78.82,71 77.67,72.15 R158.2
RI2#: length 2.6
  TOP w0.254: TP35.1 76.33,153.03 77.54,154.25 U25.31
RTERM: length 1.9
  TOP w0.107: U20.51 77.42,65.35 77.25,65.18 R167.1
RTS2#: length 3.9
  TOP w0.107: U25.30 77.5,154.65 76.4,153.54 75.82,153.54 TP36.1
RX_PAVDD_A: length 2.4
  TOP w0.203: U66.57 v1(95.09,90.63) ; U66.49 98.29,90.27 v1(98.58,90.55) ; U66.52 v1(97.09,90.63)
RXNE_UP: length 2
  TOP w0.114: U20.36 79.62,71.3 79.55,71.37 79.55,71.61 79.15,72.01 78.9,72.01 78.79,72.12 78.79,72.17 CA23.2
RXPE_UP: length 2
  TOP w0.114: CA24.2 78.54,72.2 78.54,72.02 78.8,71.75 79.04,71.75 79.3,71.5 79.3,71.37 79.22,71.3 U20.37
SAFE_3V3: length 5.7
  TOP w0.107: RZ15.2 99.44,136.28 99.3,136.14 J1.L53
SBU1: length 7.2
  BOTTOM w0.102: USB1.6 65.42,45.87 65.53,45.97 65.53,46.98 65.75,47.21 65.75,49.04 65.62,49.16 D66.10 D66.1 65.62,50.61 65.75,50.74 65.75,50.97 65.91,51.13 65.91,51.36 RZ207.2
SBU2: length 7.2
  BOTTOM w0.102: RZ208.2 66.17,51.33 66.17,51.03 66,50.86 66,50.74 66.12,50.61 D66.2 D66.9 66.12,49.16 66,49.03 66,47.1 65.78,46.88 65.78,45.97 65.88,45.87 USB1.8
SDMMC1_CLK: length 107.1
  TOP w0.107: RZU18.1 130.18,126.77 130.18,127.38 126.49,131.06 126.49,135.6 124.05,138.04 115.45,138.04 111.66,141.83 67.35,141.83 63.68,138.17 54.86,138.17 v1(54.62,137.92) ; J1.B6 v1(54.4,120.02)
  IN3 w0.124: v1(54.62,137.92) 54.62,137.01 53.98,136.37 53.98,133.26 54.23,133.01 54.23,131.6 53.78,131.15 53.78,120.75 54.4,120.13 v1(54.4,120.02)
SDMMC1_CMD: length 108.9
  TOP w0.107: v1(54.62,138.68) 54.75,138.55 63.52,138.55 67.19,142.22 111.82,142.22 115.61,138.43 124.21,138.43 126.88,135.76 126.88,131.22 130.64,127.46 130.64,127.32 RZU13.1 ; J1.A5 v1(53.3,118.52)
  IN3 w0.124: v1(53.3,118.52) 53.3,119.53 53.35,119.58 53.35,131.64 53.08,131.91 53.08,132.25 53.55,132.72 53.55,136.55 54.13,137.13 54.13,138.56 54.25,138.68 v1(54.62,138.68)
SDMMC1_D0: length 104.4
  TOP w0.107: RZU14.1 133.1,126.87 132.59,127.38 131.27,127.38 127.26,131.38 127.26,135.92 124.37,138.82 115.77,138.82 111.98,142.61 67.03,142.61 63.36,138.94 56.31,138.94 56.06,139.19 v1(56.03,139.19) ; J1.E8 v1(56,124.49)
  IN3 w0.124: v1(56,124.49) 55.58,124.91 55.58,126.29 55.28,126.58 55.28,128.08 54.68,128.68 54.68,130.84 55.09,131.24 55.09,132.36 56.03,133.31 v1(56.03,139.19)
SDMMC1_D1: length 103
  TOP w0.107: J1.F8 56.2,125.84 v1(56.02,126.02) ; RZU15.1 134.9,127.38 134.11,127.38 127.65,133.84 127.65,136.08 124.53,139.2 115.93,139.2 112.14,142.99 66.87,142.99 63.32,139.45 v1(56.76,139.45)
  IN3 w0.124: v1(56.02,126.02) 56.02,126.45 55.71,126.76 55.71,128.26 55.52,128.45 55.52,132.19 56.76,133.43 v1(56.76,139.45)
SDMMC1_D2: length 115.8
  TOP w0.107: J1.A4 v1(52.4,118.52) ; RZU10.1 137.38,127.77 134.27,127.77 128.04,134 128.04,136.24 124.69,139.59 116.09,139.59 112.3,143.38 66.71,143.38 63.28,139.95 56.21,139.95 56.01,139.75 54.66,139.75 v1(54.48,139.57)
  IN3 w0.124: v1(52.4,118.52) 52.18,118.74 52.18,129.52 52.92,130.26 52.92,131.05 52.18,131.8 52.18,135.78 53.19,136.78 53.19,138.28 v1(54.48,139.57)
SDMMC1_D3: length 111
  TOP w0.107: J1.D6 v1(54.4,123.02) ; v1(55.7,140.28) 55.76,140.34 63.12,140.34 66.55,143.76 112.46,143.76 116.25,139.97 124.85,139.97 128.42,136.4 128.42,134.16 134.43,128.15 138.14,128.15 RZU11.1
  IN3 w0.124: v1(55.7,140.28) 55.58,140.16 55.58,136.75 54.9,136.08 54.9,132.78 54.66,132.54 54.66,131.42 54.25,131.01 54.25,123.16 v1(54.4,123.02)
SNN_EFM8_P1_7: length 1.9
  TOP w0.107: TP59.1 131.53,159.73 U6.7
SNN_EFM8SB10_P0_1: length 1.8
  TOP w0.107: U6.1 132.05,155.83 132.46,155.41 TP57.1
SNN_EFM8SB10_P0_2: length 2.7
  TOP w0.107: TP58.1 131.7,155.32 131.53,155.49 U6.20
SNN_EFM8SB10_P0_5: length 1.7
  TOP w0.107: U6.17 130.03,155.57 129.67,155.21 TP56.1
SNN_GP92_CAN2: length 1.4
  TOP w0.107: J1.F40 v1(87.8,126.02)
  BOTTOM w0.107: v1(87.8,126.02) 87.81,126.03 TP3.1
SNN_GP93_CAN2: length 1.5
  TOP w0.107: J1.D40 v1(87.8,123.02)
  BOTTOM w0.107: TP4.1 87.8,122.32 v1(87.8,123.02)
SNN_GP94_CAN2: length 1.5
  TOP w0.107: J1.B40 v1(87.8,120.02)
  BOTTOM w0.107: v1(87.8,120.02) 87.93,119.89 TP5.1
SNN_MID1: length 1.4
  TOP w0.107: J1.H40 v1(87.8,129.02)
  BOTTOM w0.107: TP2.1 87.83,128.99 v1(87.8,129.02)
SOC_PWR_REQ: length 16.8
  TOP w0.107: J1.J60 v1(105.6,130.52) ; v1(109.47,132.08) 110.11,132.72 115.06,132.72 115.44,133.1 115.44,134.11 115.57,134.24 U33.2 119.28,134.24 RZU8.1
  IN1 w0.124: v1(105.6,130.52) 105.75,130.52 106.35,131.11 106.49,131.11 106.97,131.59 108.99,131.59 v1(109.47,132.08)
SPI1_CS0: length 22.9
  TOP w0.107: J1.E55 v1(101.1,124.52) ; RZ43.1 v1(101.73,104.9)
  IN3 w0.124: v1(101.73,104.9) 102.87,106.04 102.87,117.53 103.52,118.18 103.52,120.41 103.02,120.9 102.71,120.9 102.42,121.2 102.42,121.69 101.81,122.3 101.81,123.81 v1(101.1,124.52)
SPI1_MISO: length 10.2
  TOP w0.107: RZ29.1 v1(101.73,109.7) ; J1.A56 v1(102,118.52)
  IN3 w0.124: v1(102,118.52) 101.86,118.38 101.86,109.83 v1(101.73,109.7)
SPI1_MOSI: length 17.8
  TOP w0.107: RZ34.1 v1(101.73,107.31) ; J1.D55 v1(101.3,123.02)
  IN3 w0.124: v1(101.73,107.31) 102.36,107.95 102.36,117.98 102.49,118.11 102.49,120.41 101.3,121.6 v1(101.3,123.02)
SPI1_SCK: length 29.2
  TOP w0.107: RZ44.1 v1(102.87,104.9) ; J1.J57 v1(102.9,130.56)
  IN3 w0.124: v1(102.9,130.56) 103.54,129.91 103.54,128.56 103.38,128.4 103.38,127.25 103.57,127.06 103.57,125.54 103.38,125.35 103.38,124.08 102.62,123.32 102.62,122.68 103.38,121.92 103.38,121.26 104.42,120.22 104.42,118.36 103.37,117.32 103.37,105.4 v1(102.87,104.9)
SPKOUT: length 5.9
  BOTTOM w0.508: R139.1 2.41,193.54 BUZZ1.1
SRC_ON_D: length 3.8
  TOP w0.508: Q34.D 68.71,155.07 66.56,155.07 66.56,155.65 66.6,155.69 R667.2
STANDBY_REQ_N_GP109: length 13.7
  TOP w0.107: J1.L11 58.7,135.48 57.45,136.73 52.07,136.73 49.38,139.42 RZU6.2
SW2CLK: length 21.1
  TOP w0.107: U13.52 135.33,63.16 v1(135.15,62.99)
  BOTTOM w0.107: DB1.4 117.3,61.98 117.98,62.66 121.31,62.66 121.64,62.99 132.11,62.99 132.58,63.47 134.68,63.47 v1(135.15,62.99)
SW2DIO: length 22.2
  TOP w0.107: U13.53 135.83,63.21 v1(136.04,62.99)
  BOTTOM w0.107: v1(136.04,62.99) 135.15,63.88 132.41,63.88 131.93,63.4 121.79,63.4 121.31,63.88 118.01,63.88 117.37,64.52 DB1.2
SW2O: length 18.2
  TOP w0.107: U13.50 v1(134.33,65.66)
  BOTTOM w0.107: DB1.6 121.31,65.79 121.56,65.53 121.56,64.39 122.32,63.64 131.73,63.64 133.76,65.66 v1(134.33,65.66)
SYS_RST_IN_N: length 123.4
  TOP w0.107: J1.L60 105.6,133.29 v1(105.79,133.48) ; R144.2 123.32,122.66 TP30.1 122.3,121.16 v1(122.17,121.03) ; Q2.5 125.24,156.72 125.35,156.61 125.35,153.16 v1(124.84,152.65)
  IN1 w0.124: v1(150.77,91.19) 151.03,91.19 151.66,91.82 151.66,97.28 150.77,98.17 150.77,101.74 148.38,104.14 148.38,106.03 147.85,106.55 136.42,106.55 132.99,109.98 123.6,109.98 122.2,108.58 v1(122.2,107.82) ; v1(124.33,133.48) 123.32,133.48 122.89,133.91 106.37,133.91 105.94,133.48 v1(105.79,133.48)
  IN3 w0.124: v1(124.84,152.65) 124.84,152.37 125.64,151.57 125.64,141.61 125.16,141.12 125.16,134.3 v1(124.33,133.48) 123.38,132.52 123.38,121.73 122.68,121.03 v1(122.17,121.03) 122.17,107.85 v1(122.2,107.82)
  BOTTOM w0.107: RZ150.2 v1(124.84,152.65) ; v1(122.17,121.03) 122.56,121.41 J4.10 ; RZ188.1 v1(150.77,91.19)
SYS_RST_IN_N_CON: length 46.5
  IN1 w0.124: v1(149.71,137.9) 149.2,137.9 148.22,136.92 136.06,136.92 134.43,138.56 130.58,138.56 125.98,143.15 v1(125.98,152.65)
  BOTTOM w0.107: RESET1.3 155.84,138.17 154.01,139.99 CA133.1 153.15,139.98 R681.2 150.9,139.98 149.72,138.8 149.72,137.91 v1(149.71,137.9) ; RZ149.1 v1(125.98,152.65)
SYS_RST_IN_N_KEY: length 10.9
  BOTTOM w0.107: C134.1 122.57,154.27 Z9.2 ; C134.1 123.7,155.83 123.89,156.02 PSON2.2 PSON2.1 ; C134.1 123.71,154.28 RZ150.1 RZ149.2
SYS_RST_IN_Q: length 5.3
  TOP w0.107: 122.05,156.72 121.92,156.84 121.92,158.75 122.3,159.13 RB8.2 ; 122.05,156.72 Q2.2 ; 122.05,156.72 121.92,156.59 121.92,156.21 122.06,156.07 Q2.3
SYSRST#_OOB: length 2.1
  BOTTOM w0.107: RZ188.2 152.64,91.2 OOB1.8
SYSTEM_OC_N: length 28
  TOP w0.107: RZ20.2 121.79,129.21 120.85,128.27 118.49,128.27 114.07,123.85 114.07,118.39 112.91,117.22 107.14,117.22 J1.A61
SYSTEM_OC_N_BU: length 3.6
  TOP w0.107: R240.1 120.52,135.66 Z18.2 RZ20.1 RZU9.2
TCA6408A_ADDR: length 3.1
  TOP w0.203: R90.2 R91.1 127.27,74.66 U14.16
TPM_CS#: length 3.8
  TOP w0.107: U18.20 v1(110.32,89.03)
  BOTTOM w0.107: R771.1 110.59,90.65 Q51.6 110.63,89.33 v1(110.32,89.03)
TPM_IRQ#: length 39.5
  TOP w0.107: U18.18 v1(111.32,89.03) 111.32,90.01 RB42.2 ; Q57.D 118.62,120.27 v1(118.36,120.02)
  IN3 w0.124: v1(118.36,120.02) 118.36,114.61 117.48,113.73 117.48,106.43 115.7,104.65 115.06,104.65 112.67,102.27 112.67,97.63 113.4,96.9 113.4,90.39 112.04,89.03 v1(111.32,89.03)
  BOTTOM w0.107: R1474.1 118.24,120.14 v1(118.36,120.02)
TPM_PP: length 2.9
  TOP w0.254: R1488.2 R768.2 111.32,81.94 U18.7
TPM_SPI_CS0: length 18.9
  TOP w0.107: RZ43.2 101.73,103.15 v1(107.85,97.03)
  BOTTOM w0.107: v1(107.85,97.03) 107.32,96.5 107.32,91.69 107.83,91.19 111.02,91.19 111.28,90.93 Q51.5
TPM_SPI_MISO: length 14.8
  TOP w0.107: U86.6 109.67,97.74 104.42,103 104.42,104.86 102.77,106.51 102.77,107.7 102.36,108.1 RZ29.2
TPM_SPI_MOSI: length 12.4
  TOP w0.107: RZ34.2 101.75,105.66 102.92,105.66 103.91,104.67 103.91,102.74 108.87,97.78 U86.8
TPM_SPI_SCK: length 9.5
  TOP w0.107: U86.9 108.46,96.36 108.36,96.46 108.36,97.28 102.87,102.77 RZ44.2
TX0N_A: length 31.8
  TOP w0.089: v1(93.94,74.7) 94.16,74.91 94.16,76.14 CB23.1
  BOTTOM w0.089: L10.4 102.25,53.79 101.99,54.05 101.99,54.32 102.18,54.51 102.18,54.71 R507.1 102.18,55.58 102.18,57.02 101.99,57.21 101.99,58.9 102.57,59.47 102.57,64.8 101.99,65.37 101.99,72.67 99.1,75.56 94.41,75.56 94.16,75.31 94.16,74.91 v1(93.94,74.7)
TX0N_A-E: length 5.4
  BOTTOM w0.089: L10.3 102.25,51.58 102.01,51.33 102.01,50.52 102.12,50.41 D56.2 D56.9 102.12,49.09 102.01,48.98 102.01,48.64 101.75,48.39 101.75,48.13 102.15,47.73 HDMI1.9
TX0P_A: length 30.9
  TOP w0.089: CB24.1 94.44,76.14 94.44,74.91 v1(94.65,74.7)
  BOTTOM w0.089: v1(94.65,74.7) 94.44,74.91 94.44,75.2 94.53,75.29 98.98,75.29 101.71,72.56 101.71,65.25 102.29,64.68 102.29,59.59 101.71,59.02 101.71,57.1 101.9,56.91 101.9,55.58 R511.1 101.9,54.71 101.9,54.62 101.71,54.43 101.71,54.05 101.45,53.79 L10.1
TX0P_A-E: length 5.4
  BOTTOM w0.089: HDMI1.7 101.15,47.81 101.47,48.13 101.47,48.5 101.73,48.76 101.73,48.98 101.62,49.09 D56.10 D56.1 101.62,50.44 101.73,50.55 101.73,51.33 101.45,51.61 L10.2
TX1N_A: length 29.4
  TOP w0.089: CB25.1 96.44,76.14 96.44,73.97 v1(96.23,73.76)
  BOTTOM w0.089: L9.4 100.35,53.8 100.08,54.08 100.08,54.41 99.9,54.59 99.9,54.71 R506.1 99.9,55.58 99.9,58.88 101.78,60.76 101.78,64.36 101.22,64.92 101.22,72.29 98.96,74.55 96.7,74.55 96.44,74.3 96.44,73.97 v1(96.23,73.76)
TX1N_A-E: length 5.4
  BOTTOM w0.089: L9.3 100.35,51.58 100.08,51.31 100.08,50.55 100.19,50.44 D55.5 D55.6 100.19,49.13 100.08,49.02 100.08,48.77 100.31,48.53 100.31,48.03 100.65,47.68 HDMI1.6
TX1P_A: length 28.5
  TOP w0.089: v1(96.94,73.76) 96.72,73.97 96.72,76.14 CB26.1
  BOTTOM w0.089: v1(96.94,73.76) 96.72,73.97 96.72,74.18 96.81,74.27 98.84,74.27 100.94,72.17 100.94,64.81 101.5,64.25 101.5,60.87 99.62,58.99 99.62,55.58 R510.1 99.62,54.71 99.62,54.47 99.8,54.29 99.8,54.08 99.55,53.83 L9.1
TX1P_A-E: length 5.4
  BOTTOM w0.089: HDMI1.4 99.65,47.65 100.03,48.03 100.03,48.42 99.8,48.65 99.8,49.02 99.69,49.13 D55.7 D55.4 99.69,50.44 99.8,50.55 99.8,51.31 99.55,51.56 L9.2
TX2N_A: length 27.2
  TOP w0.089: CB27.1 98.73,76.14 98.73,72.22 v1(98.51,72.01)
  BOTTOM w0.089: v1(98.51,72.01) 98.73,72.22 98.73,72.52 98.98,72.77 99.59,72.77 100.2,72.16 100.2,61.21 97.61,58.62 97.61,55.58 R508.1 97.66,54.76 97.66,54.66 98.07,54.25 98.07,54.05 98.32,53.8 L8.4
TX2N_A-E: length 5.6
  BOTTOM w0.089: L8.3 98.32,51.64 98.06,51.38 98.06,51.31 98.58,50.79 98.58,50.55 98.69,50.44 D55.2 D55.9 98.69,49.03 98.58,48.92 98.58,48.59 98.79,48.38 98.79,48.1 99.15,47.74 HDMI1.3
TX2P_A: length 26.3
  TOP w0.089: v1(99.23,72.01) 99.01,72.22 99.01,76.14 CB28.1
  BOTTOM w0.089: L8.1 97.52,53.75 97.79,54.03 97.79,54.14 97.38,54.54 97.38,54.66 R505.1 97.33,55.58 97.33,58.74 99.92,61.33 99.92,72.05 99.48,72.49 99.1,72.49 99.01,72.4 99.01,72.22 v1(99.23,72.01)
TX2P_A-E: length 5.6
  BOTTOM w0.089: HDMI1.1 98.15,47.74 98.51,48.1 98.51,48.26 98.3,48.47 98.3,48.9 98.19,49.01 D55.10 D55.1 98.19,50.44 98.3,50.55 98.3,50.67 97.78,51.19 97.78,51.38 97.52,51.64 L8.2
TX_AVDD_A: length 1.8
  TOP w0.203: U66.22 v1(94.29,81.15) ; U66.28 v1(96.69,81.15)
TX_CEC_A: length 62.1
  TOP w0.203: U66.62 v1(93.09,90.63)
  BOTTOM w0.254: HDMI1.13 104.15,47.95 104.92,48.72 D57.5 D57.6 104.92,50.48 104.74,50.66 104.74,53.94 105.64,54.84 105.64,57.35 104.97,58.02 104.97,60.31 104.62,60.66 104.62,72.54 99.67,77.49 89.67,77.49 88.21,78.95 88.21,88.44 90.58,90.81 92.91,90.81 v1(93.09,90.63)
TX_HPD_A: length 45.2
  TOP w0.107: U66.39 99.8,85.33 99.8,85.33 100.32,85.33 v1(100.9,84.75)
  BOTTOM w0.107: v1(100.9,84.75) 102.98,84.75 105.93,81.8 105.93,61.2 106.27,60.85 106.27,58.57 106.94,57.9 106.94,55.36 108.41,53.9 108.41,52.15 108.2,51.94 R519.2 107.85,51.37 106.92,50.44 D57.10 D57.1 106.92,48.94 107.28,48.58 107.28,48.1 107.15,47.97 HDMI1.19
TX_PVDD_A: length 5.3
  TOP w0.203: U66.18 92.69,81.49 92.45,81.25 v1(92.45,81.15)
  BOTTOM w0.508: FB33.1 C311.1 92.45,80.65 v1(92.45,81.15) 92.45,81.51 92.77,81.83 C312.1
TX_RSEN_A: length 47
  TOP w0.203: U66.6 v1(90.58,86.93)
  TOP w0.254: v1(103.17,59.05) v1(104.43,59.05)
  IN3 w0.254: v1(90.83,76.83) 90.22,76.83 89.05,78 89.05,86.49 89.5,86.93 v1(90.58,86.93)
  BOTTOM w0.254: R527.1 103.17,58.47 v1(103.17,59.05) ; R526.1 104.55,58.55 104.55,58.94 v1(104.43,59.05) 104.55,59.17 104.55,59.99 104.11,60.43 104.11,65.35 103.42,66.04 103.42,73.2 99.52,77.11 91.1,77.11 v1(90.83,76.83) ; R529.2 91.12,86.25 C296.1 90.58,86.96 v1(90.58,86.93)
TX_SCL_A: length 58.3
  TOP w0.107: v1(90.07,88.9) 90.45,88.9 90.81,88.53 U66.2
  BOTTOM w0.107: D57.7 105.42,50.61 105.22,50.81 105.22,52.6 105.53,52.91 R530.2 105.74,54.05 106.12,54.43 106.12,57.55 105.45,58.22 105.45,60.51 105.11,60.86 105.11,72.84 99.97,77.97 89.87,77.97 88.69,79.15 88.69,88.16 89.43,88.9 v1(90.07,88.9) ; D57.7 105.38,50.19 ; D57.7 D57.4 105.42,48.39 105.15,48.13 HDMI1.15
TX_SDA_A: length 57.8
  TOP w0.107: U66.3 90.58,88.13 v1(90.45,88.27)
  BOTTOM w0.107: HDMI1.16 105.65,47.74 106.42,48.51 D57.2 D57.9 106.42,50.53 107.26,51.37 107.26,52.68 107.04,52.91 R531.2 106.76,54.21 106.53,54.43 106.53,57.73 105.86,58.4 105.86,60.68 105.52,61.03 105.52,73.01 100.14,78.39 90.04,78.39 89.1,79.32 89.1,87.93 89.43,88.27 v1(90.45,88.27)
TXCN_A: length 36.6
  TOP w0.089: v1(91.66,74.7) 91.87,74.91 91.87,76.14 CB21.1
  BOTTOM w0.089: L11.4 104.16,53.79 103.9,54.05 103.9,54.15 104,54.26 104.09,54.26 104.34,54.51 104.34,54.71 R514.1 104.34,55.58 104.34,56.58 103.99,56.94 103.99,57.02 104.39,57.43 R526.2 103.96,57.86 103.96,59.69 103.43,60.22 103.43,65.1 102.84,65.68 102.84,72.96 99.35,76.45 92.74,76.45 91.87,75.59 91.87,74.91 v1(91.66,74.7)
TXCN_A-E: length 5.5
  BOTTOM w0.089: L11.3 104.16,51.61 103.91,51.36 103.91,51.08 103.51,50.67 103.51,50.55 103.62,50.44 D56.5 D56.6 103.62,49.13 103.51,49.02 103.51,48.48 103.28,48.25 103.28,48.15 103.65,47.78 HDMI1.12
TXCP_A: length 35.7
  TOP w0.089: v1(92.37,74.7) 92.15,74.91 92.15,76.14 CB22.1
  BOTTOM w0.089: L11.1 103.36,53.79 103.62,54.05 103.62,54.27 103.88,54.54 103.97,54.54 104.06,54.62 104.06,54.71 R513.1 104.06,55.58 104.06,56.46 103.71,56.82 103.71,56.97 R527.2 103.68,57.86 103.68,59.57 103.15,60.11 103.15,64.98 102.57,65.57 102.57,72.85 99.24,76.17 92.85,76.17 92.15,75.47 92.15,74.91 v1(92.37,74.7)
TXCP_A-E: length 5.5
  BOTTOM w0.089: L11.2 103.36,51.61 103.63,51.34 103.63,51.2 103.23,50.79 103.23,50.55 103.12,50.44 D56.4 D56.7 103.12,49.13 103.23,49.02 103.23,48.59 103,48.36 103,48.13 102.65,47.79 HDMI1.10
TXNE_UP: length 1.5
  TOP w0.114: CA20.2 80.75,72.22 80.75,71.37 80.82,71.3 U20.33
TXPE_UP: length 1.6
  TOP w0.114: U20.34 80.42,71.28 80.49,71.35 80.49,72.15 CA21.2
TYPE-C0_CC1-C: length 6.8
  BOTTOM w0.254: USB1.2 60.65,46.17 62.07,47.59 D11.5 D11.6 62.07,50.45 61.47,51.05 RZ209.2
TYPE-C0_CC2-C: length 6.2
  BOTTOM w0.254: RZ210.2 62.38,51.61 62.38,50.85 62.57,50.66 D11.7 D11.4 62.57,47.19 62.65,47.1 USB1.4
TYPEC0_DM-E: length 8.9
  BOTTOM w0.102: L7.2 63.61,51.43 63.88,51.16 63.88,50.98 63.7,50.8 63.7,50.64 63.57,50.5 D11.9 D11.2 63.57,49.23 63.69,49.11 63.69,47.67 63.53,47.5 63.53,43.97 63.42,43.87 USB1.3
TYPEC0_DP-E: length 8.9
  BOTTOM w0.102: L7.3 64.41,51.43 64.14,51.16 64.14,50.88 63.96,50.7 63.96,50.62 64.07,50.51 D11.10 D11.1 64.07,49.23 63.95,49.11 63.95,47.56 63.78,47.4 63.78,43.97 63.88,43.87 USB1.5
UART0_RX_OOB_3V3: length 16.7
  BOTTOM w0.107: RZ39.2 R6.1 145.44,103 145.69,102.74 148.47,102.74 151.09,100.12 151.09,96.27 153.16,94.2 OOB1.5
UART0_TX_OOB_3V3: length 16.8
  BOTTOM w0.107: OOB1.6 153.16,93.2 150.68,95.68 150.68,99.79 148.87,101.6 145.69,101.6 145.44,101.85 R4.1 RZ36.2
UART1_CTS: length 1.4
  TOP w0.107: J1.H54 v1(100.4,129.02)
  BOTTOM w0.107: TP11.1 100.4,129.74 v1(100.4,129.02)
UART1_RTS: length 65.7
  TOP w0.107: v1(97.54,133.6) 97.5,133.57 J1.L51
  IN1 w0.124: v1(97.54,133.6) 97.53,133.6 97.07,134.07 96.82,134.07 93.98,136.91 v1(77.85,136.91)
  IN3 w0.124: v1(61.59,172.97) 61.59,171.62 68.05,165.17 68.05,151.1 76.71,142.45 76.71,137.29 77.09,136.91 v1(77.85,136.91)
  BOTTOM w0.107: RZ148.1 v1(61.59,172.97)
UART1_RXD: length 74.1
  TOP w0.107: J1.K54 v1(100.4,132.02) ; U36.1 63.11,177.2 RB3.2 v1(62.61,177.04)
  IN1 w0.124: v1(77.85,137.92) 94.23,137.92 97.23,134.92 98.12,134.92 100.4,132.64 v1(100.4,132.02)
  IN3 w0.124: v1(77.85,137.92) 77.85,141.91 68.48,151.28 68.48,165.34 64.59,169.23 64.59,173.91 62.61,175.9 v1(62.61,177.04)
UART1_TXD: length 69.9
  TOP w0.107: J1.K53 v1(99.5,132.02)
  IN1 w0.124: v1(78.36,137.41) 94.13,137.41 97.05,134.5 97.94,134.5 99.5,132.93 v1(99.5,132.02)
  IN3 w0.124: v1(65.02,176.28) 65.02,169.41 68.91,165.52 68.91,151.46 78.36,142.01 v1(78.36,137.41)
  BOTTOM w0.107: RZ145.1 65.43,176.81 65.02,176.4 v1(65.02,176.28)
UART2_CTS: length 14.2
  TOP w0.107: J1.A57 102.9,117.32 103.89,116.33 114.07,116.33 114.45,116.71 RZ25.1
UART2_RTS: length 8.2
  TOP w0.107: J1.G58 v1(103.8,127.52)
  BOTTOM w0.107: v1(103.8,127.52) 104.39,128.11 110.99,128.11 RZ171.1
UART2_RX_OOB_3V3: length 16.4
  BOTTOM w0.107: OOB1.3 153.16,96.2 151.92,97.44 151.92,100.46 147.27,105.1 145.62,105.1 145.44,105.28 R10.1 RZ47.2
UART2_RXD: length 49
  TOP w0.107: J1.C56 v1(102,121.52)
  IN3 w0.124: v1(127.51,117.68) 127.33,117.5 127.33,116.89 134.59,109.63 134.59,108.18 136.09,106.68 136.09,104.35 v1(137.06,103.38)
  BOTTOM w0.107: R9.1 v1(137.06,103.38) RZ38.1 ; v1(127.51,117.68) 127.34,117.51 119.15,117.51 118.27,118.38 110.01,118.38 109.54,117.91 103.96,117.91 102,119.87 v1(102,121.52)
UART2_RXD_3V3: length 1.8
  BOTTOM w0.107: RZ39.1 142.9,103.38 142.52,103.76 U85.9
UART2_TX_OOB_3V3: length 16.5
  BOTTOM w0.107: RZ41.2 R8.1 145.44,104.27 145.76,103.95 147.84,103.95 151.51,100.29 151.51,96.86 153.16,95.2 OOB1.4
UART2_TXD: length 47.9
  TOP w0.107: J1.C58 v1(103.8,121.52)
  IN3 w0.124: v1(126.9,117.98) 126.9,116.71 134.16,109.45 134.16,108 135.66,106.5 135.66,103.63 v1(137.06,102.23)
  BOTTOM w0.107: RZ35.1 v1(137.06,102.23) R5.1 ; v1(103.8,121.52) 103.56,121.28 103.56,119.66 104.07,119.15 108.72,119.15 109.07,118.8 118.44,118.8 119.26,117.98 v1(126.9,117.98)
UART2_TXD_3V3: length 2.2
  BOTTOM w0.107: RZ36.1 143.28,102.36 142.28,103.36 U85.10
UART3_RXD: length 51.9
  TOP w0.107: J1.K60 v1(105.8,132.02)
  IN3 w0.124: v1(137.06,105.66) 137.06,106.93 135.45,108.54 135.45,109.99 131.26,114.17 131.26,120.58 127.38,124.46 127.38,128.55 v1(127.28,128.65)
  BOTTOM w0.107: v1(127.28,128.65) 127.26,128.63 124.01,128.63 121.2,131.44 106.37,131.44 v1(105.8,132.02) ; R11.1 v1(137.06,105.66) RZ46.1
UART3_TXD: length 52
  TOP w0.107: J1.H62 v1(107.6,129.02)
  IN3 w0.124: v1(126.77,128.14) 126.87,128.04 126.87,124.36 130.84,120.4 130.84,113.99 135.02,109.81 135.02,108.36 136.52,106.86 136.52,105.06 v1(137.06,104.52)
  BOTTOM w0.107: v1(107.6,129.02) 107.6,130.68 107.95,131.03 121.03,131.03 123.92,128.14 v1(126.77,128.14) ; R7.1 v1(137.06,104.52) RZ40.1
UART5_CTS: length 45.2
  TOP w0.107: J1.H57 v1(103.1,129.02)
  BOTTOM w0.107: v1(103.1,129.02) 103.1,129.77 103.38,130.05 103.38,132.08 103.89,132.59 111.67,132.59 112.4,131.86 121.37,131.86 124.07,129.16 130.05,129.16 130.56,129.67 131.83,129.67 132.94,128.55 139.86,128.55 140.49,129.18 WIFI1.34
UART5_RTS: length 42
  TOP w0.107: J1.K58 v1(104,132.02)
  IN1 w0.124: v1(140.99,132.09) 140.43,132.09 139.15,133.37 128.47,133.37 126.38,135.46 121.97,135.46 120.85,134.34 105.77,134.34 104,132.58 v1(104,132.02)
  BOTTOM w0.107: WIFI1.36 v1(140.99,132.09)
UART5_RXD: length 37.7
  TOP w0.107: J1.H58 v1(104,129.02)
  IN1 w0.124: v1(104,129.02) 106.16,129.02 106.68,129.54 112.27,129.54 113.67,128.14 122.3,128.14 123.57,129.41 130.05,129.41 131.44,130.81 136.22,130.81 v1(137.49,132.08)
  BOTTOM w0.107: WIFI1.22 v1(137.49,132.08)
UART5_TXD: length 44.6
  TOP w0.107: J1.J58 v1(103.8,130.52)
  IN1 w0.124: v1(103.8,130.52) 103.8,131.02 103.5,131.32 103.5,132.72 105.56,134.77 120.67,134.77 121.79,135.89 126.56,135.89 128.65,133.8 139.33,133.8 v1(140.54,132.59)
  BOTTOM w0.107: WIFI1.32 139.99,132.04 v1(140.54,132.59)
UART1812_RX: length 45.3
  BOTTOM w0.107: J11.4 28.02,80.47 45.98,80.47 49.96,84.45 49.96,93.77 50.75,94.56 50.75,95.94 R589.1 50.75,96.24 50.75,99.59 51.38,100.22 53.56,100.22 53.96,99.82 U67.B9
UART1812_TX: length 41.5
  BOTTOM w0.107: J11.3 30.14,80.06 46.15,80.06 50.37,84.28 50.37,93.29 51.26,94.18 51.26,99.52 51.56,99.82 U67.A9
UART_RXD: length 5.8
  BOTTOM w0.107: RZU47.2 33.1,72.47 J7.2
UART_TXD: length 2.8
  BOTTOM w0.107: J7.1 34.37,71.2 RZU46.2
UFS0_REF_CLK: length 103.8
  TOP w0.107: SSD2.56 v1(151.31,113.16) ; J1.A6 v1(54.2,118.52)
  BOTTOM w0.107: v1(151.31,113.16) 150.73,112.57 139.93,112.57 138.1,110.75 135.3,110.75 134.39,111.66 90.26,111.66 89.94,111.34 81.52,111.34 79.2,113.67 69.53,113.67 67.48,115.71 56.4,115.71 54.2,117.91 v1(54.2,118.52)
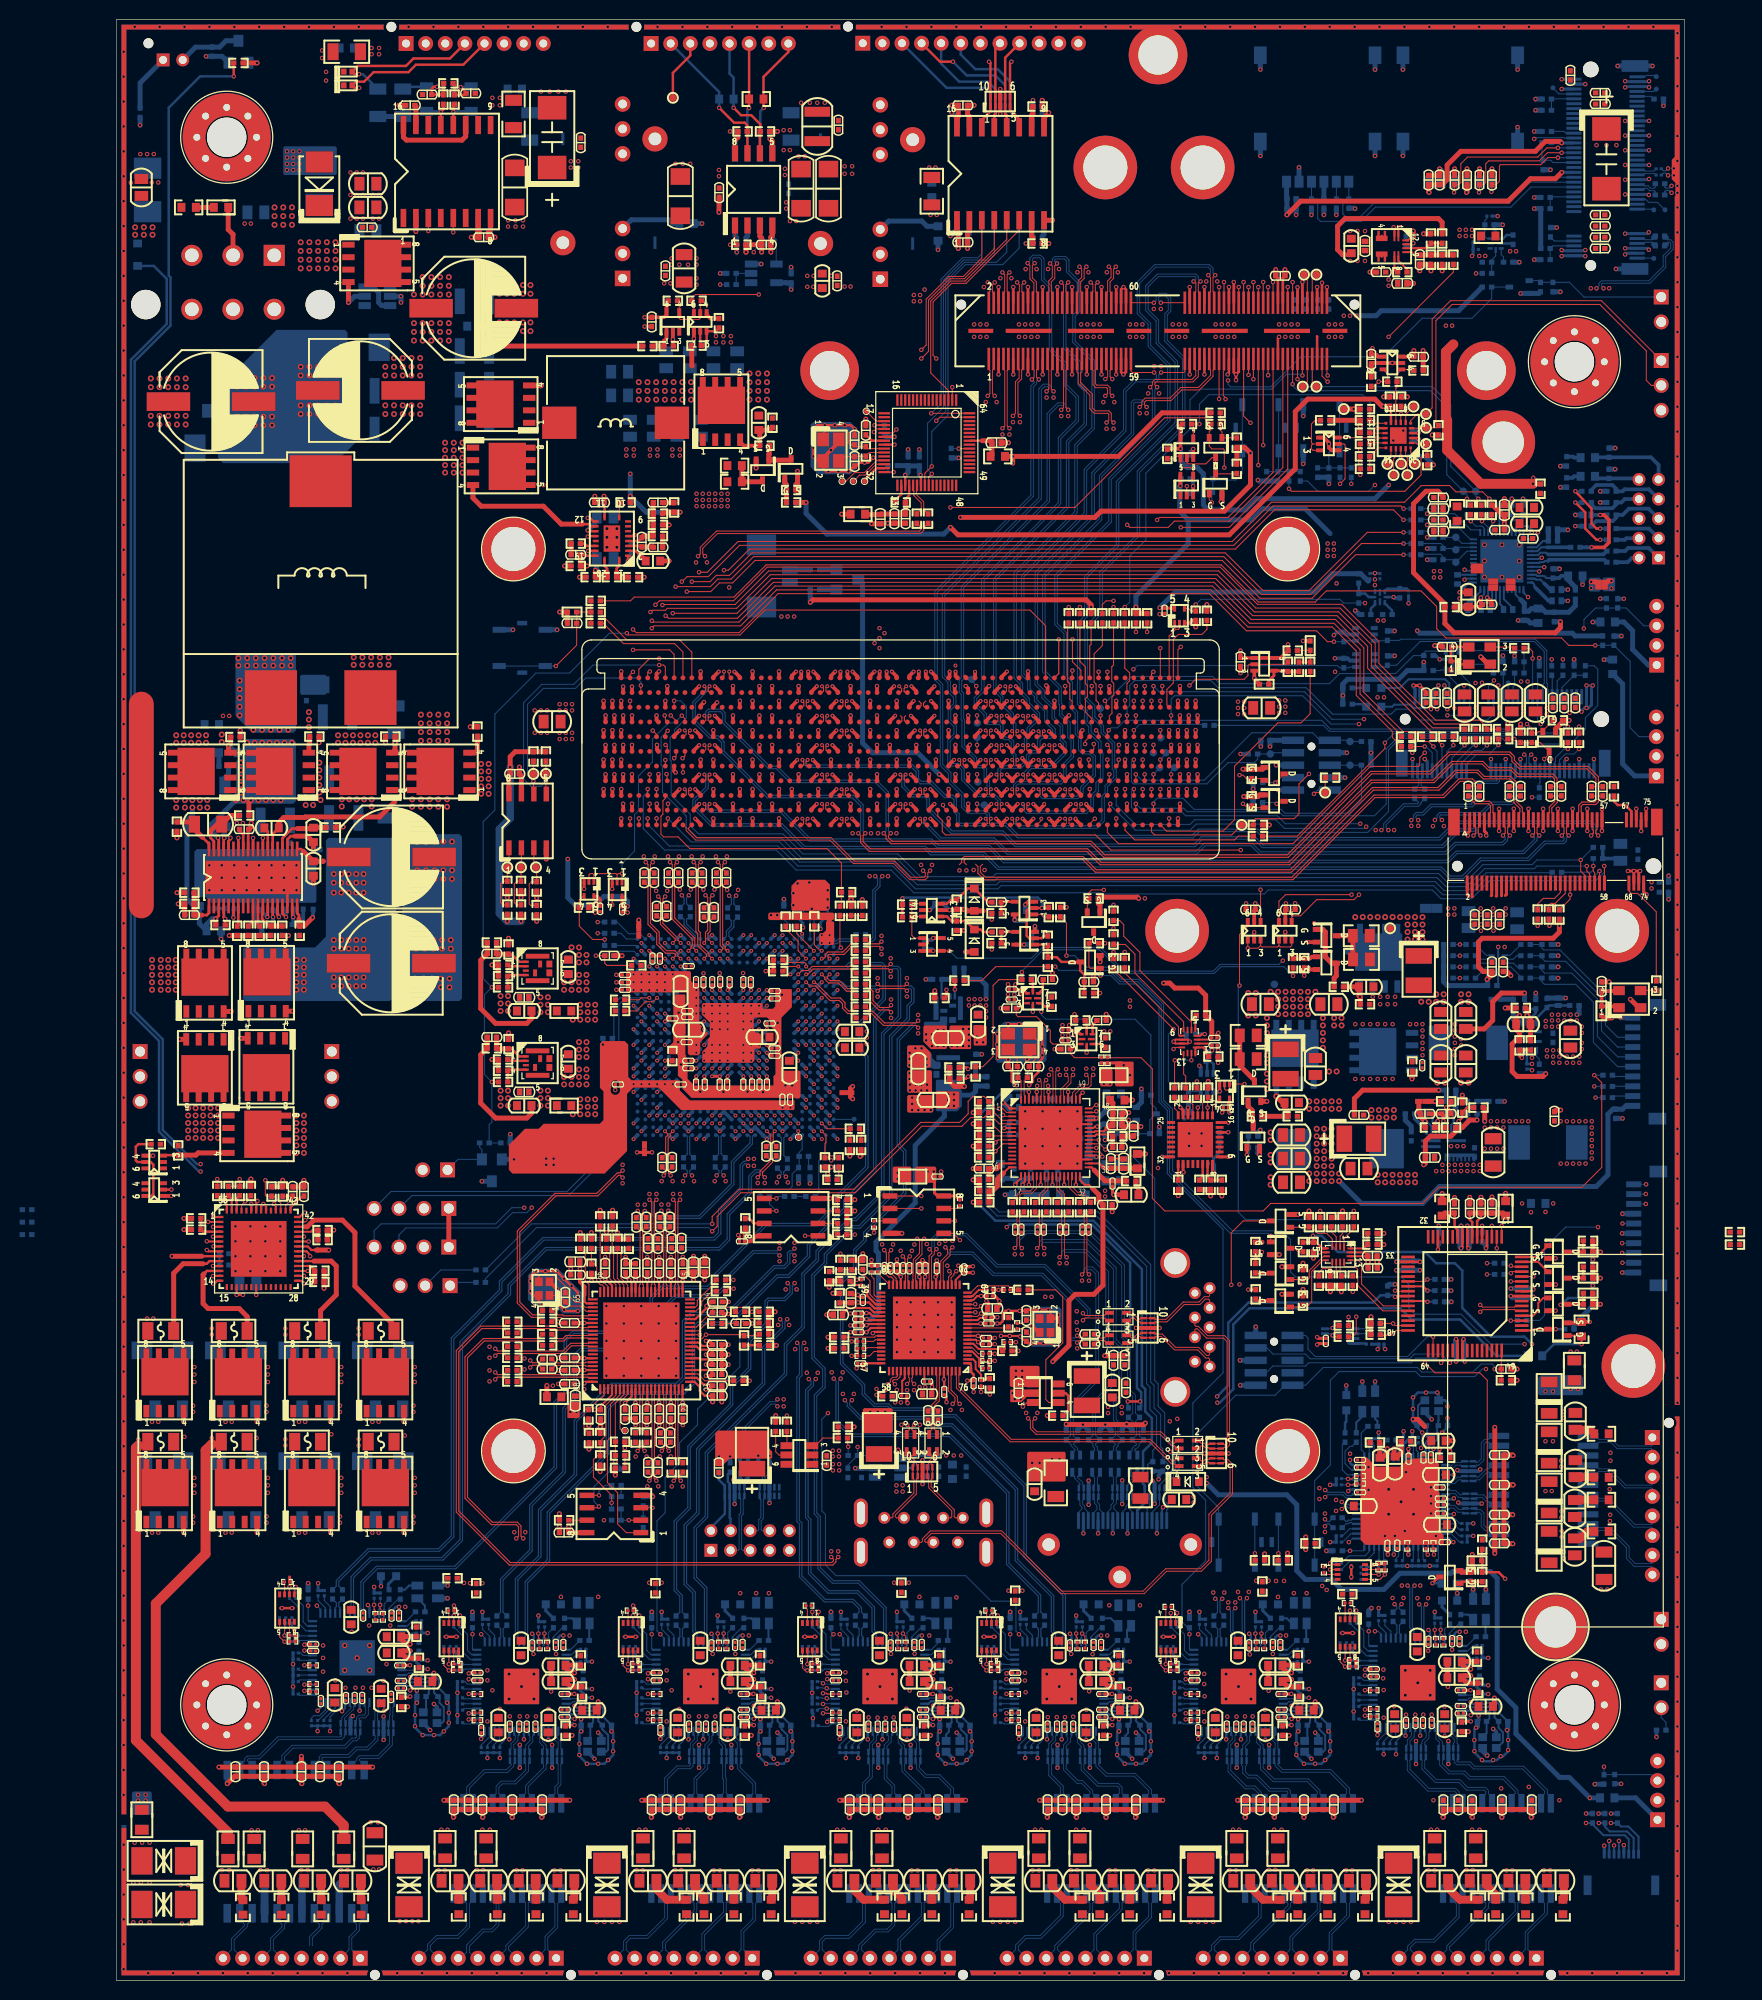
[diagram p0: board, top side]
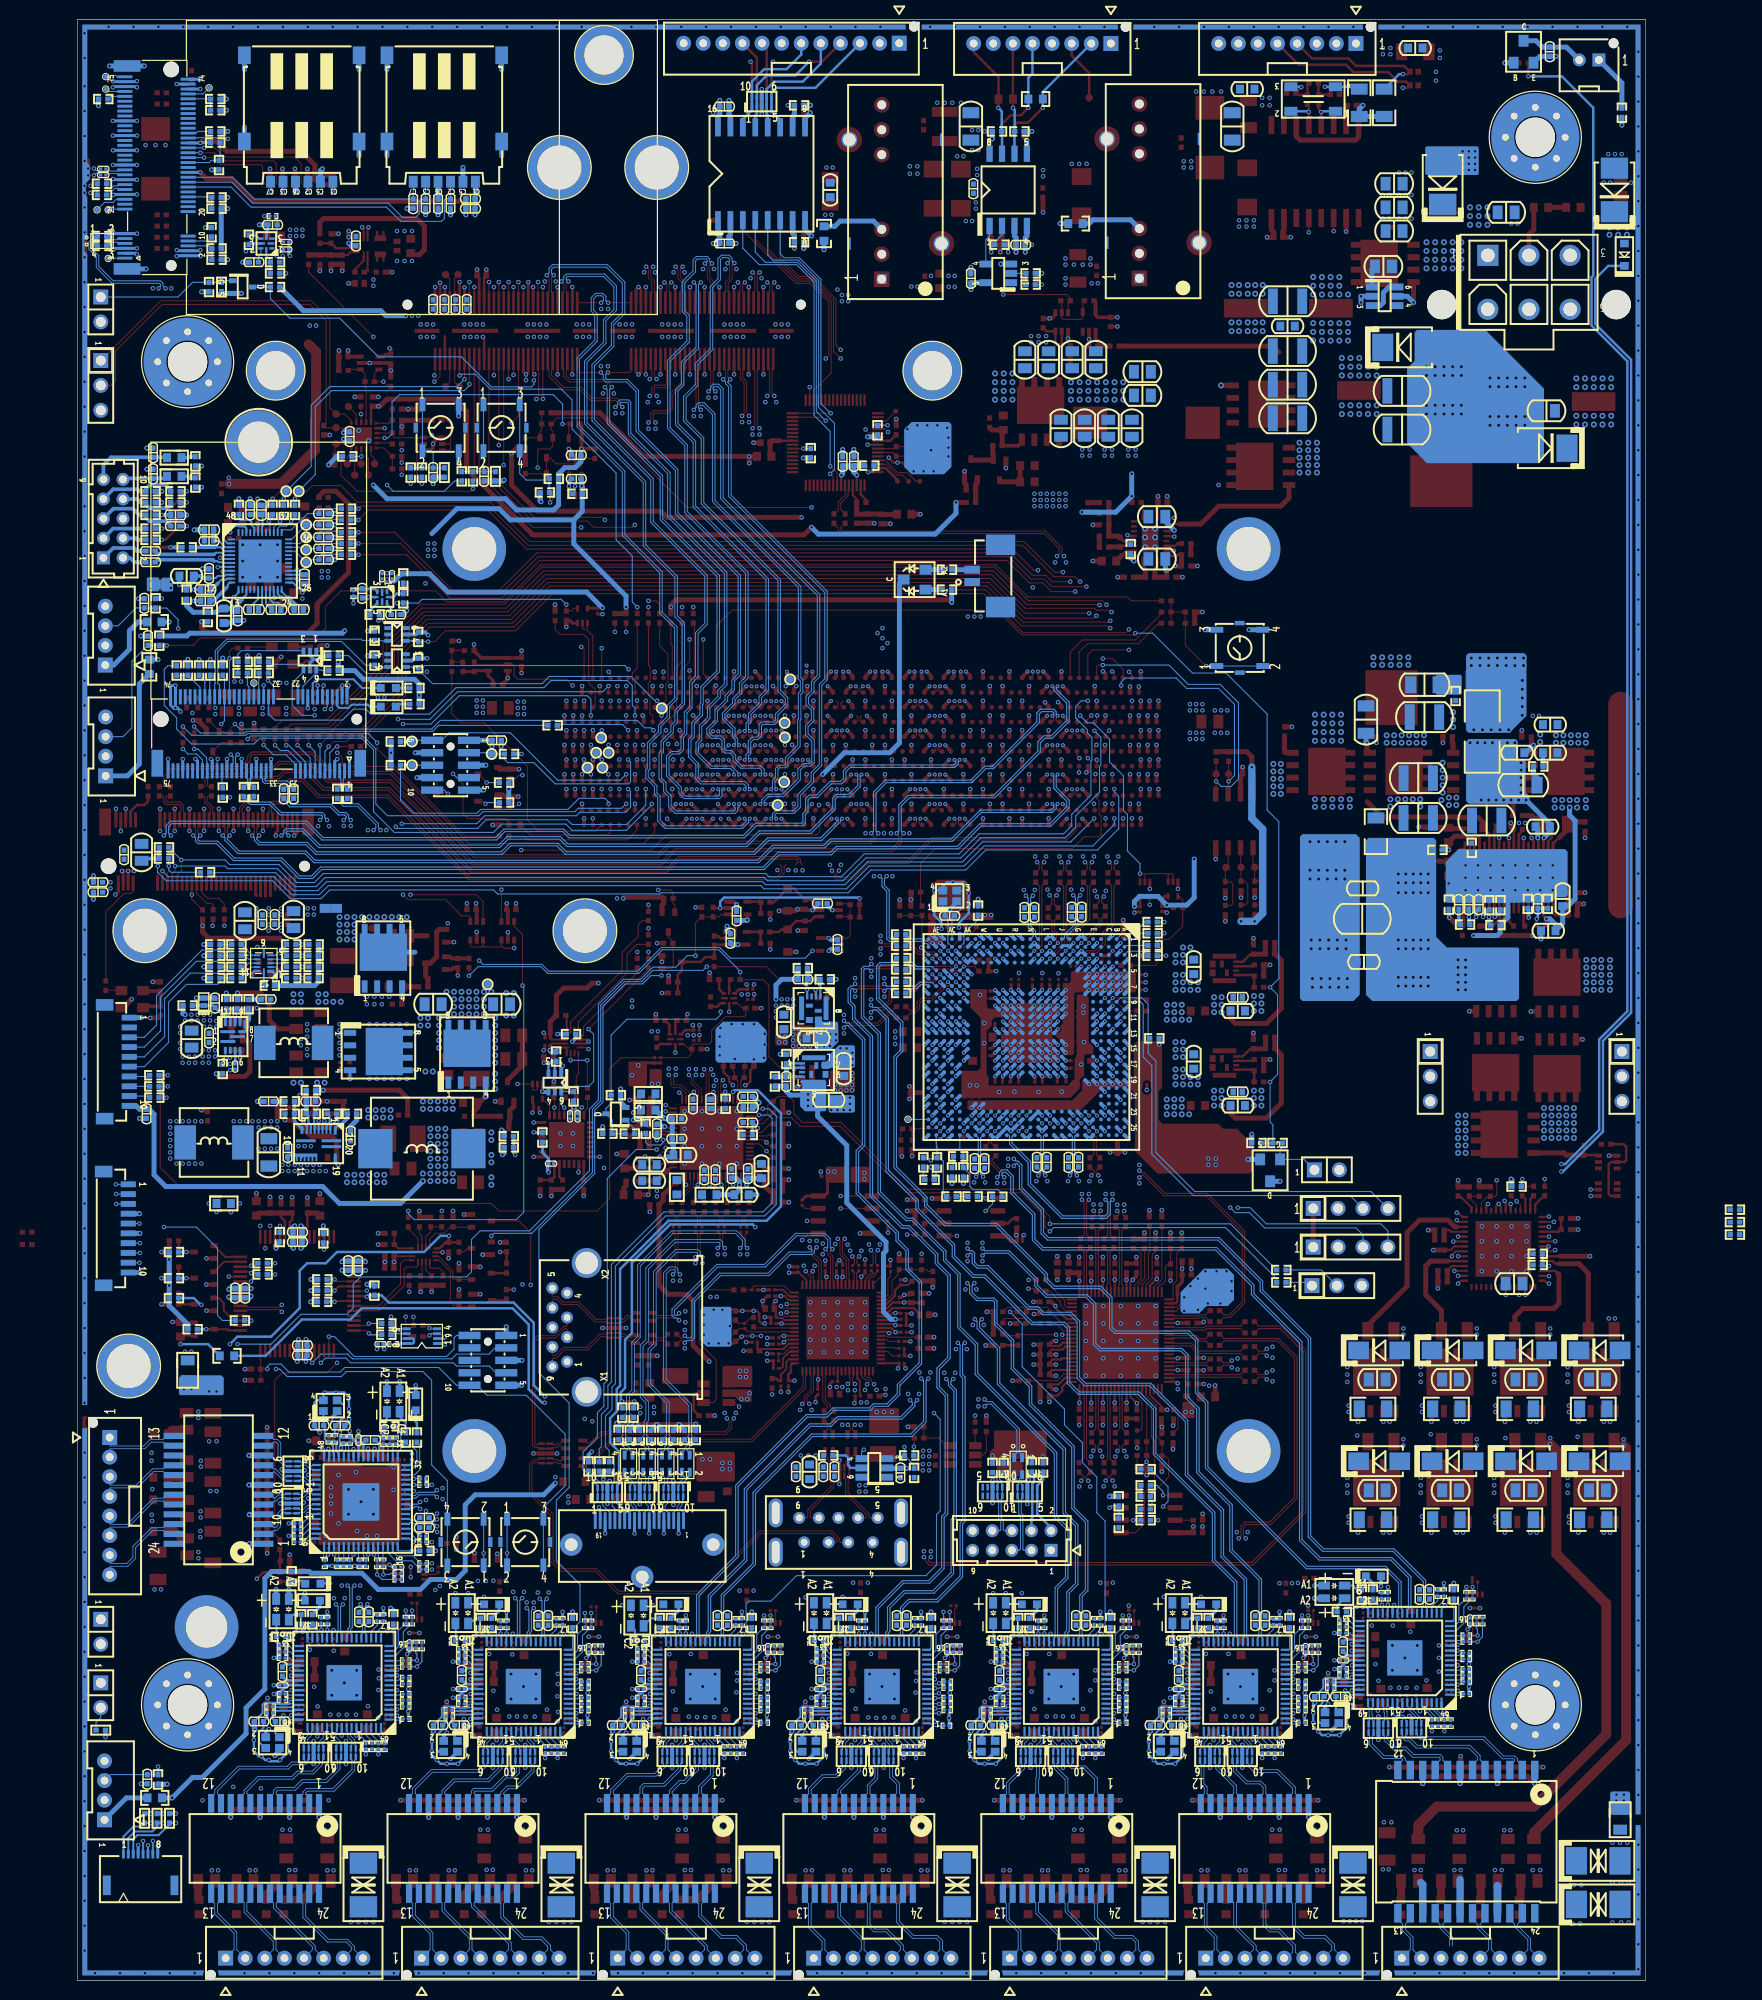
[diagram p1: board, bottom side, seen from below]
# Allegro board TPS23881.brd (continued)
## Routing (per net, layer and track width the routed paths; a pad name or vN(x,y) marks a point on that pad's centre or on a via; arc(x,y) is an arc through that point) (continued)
UFS0_RST_N: length 109.7
  TOP w0.107: v1(151.79,113.67) 151.81,113.64 SSD2.58 ; J1.C6 v1(54.2,121.52)
  BOTTOM w0.107: v1(151.79,113.67) 151.81,113.64 151.81,113.05 150.92,112.16 140.1,112.16 138.27,110.33 135.13,110.33 134.24,111.23 117.53,111.23 117.12,110.82 100.57,110.82 100.45,110.93 81.35,110.93 79.03,113.25 69.36,113.25 67.31,115.3 55.92,115.3 53.75,117.47 53.75,120.78 54.2,121.23 v1(54.2,121.52)
UIM1_CLK: length 29
  BOTTOM w0.107: NGFF1.32 144.23,183.42 142.09,181.28 128.28,181.28 126.83,179.83 125.48,179.83 125.12,180.19 125.12,181.48 124.9,181.7 C120.2 124.46,181.7 JSIM1.C3
UIM1_DATA: length 25.7
  BOTTOM w0.107: JSIM1.C7 125.73,181.7 C118.2 125.73,181.7 141.92,181.7 144.15,183.92 NGFF1.34
UIM1_DET: length 3.4
  BOTTOM w0.107: R225.2 R228.1 146.43,191.92 NGFF1.66
UIM1_PWR: length 43.2
  TOP w0.508: v1(119.42,180.09) 120.82,181.48 141.99,181.48 144.27,183.77 146.81,183.77 v1(147.46,184.42)
  IN3 w0.508: v1(144.78,190.75) 145.8,190.75 146.3,190.25 146.3,185.58 v1(147.46,184.42)
  BOTTOM w0.305: NGFF1.36 v1(147.46,184.42)
  BOTTOM w0.508: v1(119.42,180.09) C119.2 CA120.1 119.38,181.9 JSIM1.C1 ; R225.1 v1(144.78,190.75)
UIM1_RESET: length 32
  BOTTOM w0.107: JSIM1.C2 121.92,181.7 C121.2 122.45,181.7 122.56,181.59 122.56,179.71 122.84,179.42 127,179.42 128.45,180.87 142.27,180.87 144.31,182.92 NGFF1.30
UIM1_VPP: length 1.8
  BOTTOM w0.508: JSIM1.C6 123.19,181.7 C117.2
UIM2_CLK: length 14
  TOP w0.107: v1(147.45,186.42) 146,186.42 145.17,185.59 140,185.59 139.7,185.29 139.7,183.39 139.48,183.17 C125.2 139.06,182.43 v1(139.01,182.37)
  BOTTOM w0.107: v1(139.01,182.37) JSIM2.C3 ; NGFF1.44 v1(147.45,186.42)
UIM2_DATA: length 12.2
  TOP w0.107: v1(147.07,185.92) 147.06,185.93 146.05,185.93 145.33,185.2 141.22,185.2 141.1,185.08 141.1,183.51 140.75,183.17 C124.2 140.34,182.5 v1(140.28,182.44)
  BOTTOM w0.107: NGFF1.42 v1(147.07,185.92) ; JSIM2.C7 v1(140.28,182.44)
UIM2_DET: length 5.1
  BOTTOM w0.107: R224.2 145.44,185.75 R227.1 146.33,185.65 146.56,185.42 NGFF1.40
UIM2_PWR: length 20.6
  TOP w0.508: v1(147.45,187.42) 147.29,187.58 145.78,187.58 144.76,186.56 137.16,186.56 135.76,185.17 135.76,183.68 135.25,183.17 C128.2 CA4.1 133.87,182.43 v1(133.93,182.37)
  BOTTOM w0.107: JSIM2.C1 v1(133.93,182.37)
  BOTTOM w0.305: R224.1 147.41,187.45 v1(147.45,187.42) NGFF1.48
UIM2_RESET: length 16.8
  TOP w0.107: v1(136.47,182.37) 136.54,182.44 C126.2 136.94,183.17 137.16,183.39 137.16,185.29 137.84,185.98 145.01,185.98 145.95,186.92 v1(147.07,186.92)
  BOTTOM w0.107: v1(136.47,182.37) JSIM2.C2 ; NGFF1.46 v1(147.07,186.92)
UIM2_VPP: length 1.9
  TOP w0.508: C123.2 137.79,182.43 v1(137.74,182.37)
  BOTTOM w0.508: JSIM2.C6 v1(137.74,182.37)
UPE_CLKN: length 4.4
  TOP w0.114: U70.72 48.19,67.46 48.12,67.53 45.53,67.53 45.43,67.63 44.87,67.63 RZ83.2
UPE_CLKP: length 4.4
  TOP w0.114: U70.71 48.2,67.86 48.12,67.78 45.63,67.78 45.53,67.88 44.87,67.88 RZ80.2
UPE_CLKREQN: length 6.7
  TOP w0.107: R561.2 R562.1 RZU21.1 73.81,105.44 v1(73.91,105.34)
  BOTTOM w0.107: v1(73.91,105.34) 73.84,105.34 73.16,104.66 U67.AF3
UPE_RXN0: length 4.7
  TOP w0.114: CM56.1 57.03,74.32 57.03,71.01 56.96,70.94 U70.47
UPE_RXN1: length 6.9
  TOP w0.114: CM50.1 53.43,76.48 53.43,71.01 53.36,70.94 U70.56
UPE_RXP0: length 4.7
  TOP w0.114: U70.46 57.36,70.94 57.29,71.01 57.29,74.34 CM57.1
UPE_RXP1: length 6.8
  TOP w0.114: U70.55 53.76,70.94 53.69,71.01 53.69,76.51 CM51.1
UPE_TXN0: length 6.9
  TOP w0.114: U70.50 55.76,70.94 55.83,71.01 55.83,76.49 CM52.1
UPE_TXN1: length 4.7
  TOP w0.114: CM54.1 54.63,74.31 54.63,71.01 54.56,70.94 U70.53
UPE_TXP0: length 6.9
  TOP w0.114: CM53.1 56.09,76.49 56.09,71.01 56.16,70.94 U70.49
UPE_TXP1: length 4.7
  TOP w0.114: U70.52 54.96,70.94 54.89,71.01 54.89,74.36 CM55.1
UPHY0_RX2_N: length 52.6
  TOP w0.114: J1.C35 82.55,120.86 82.39,121.01 82.39,121.37 v3(82.52,121.5) ; v1(80.94,73.85) 80.71,73.62 80.71,73.1 CA20.1
  IN3 w0.122: v3(82.52,121.5) 82.38,121.36 82.38,120.99 82.04,120.65 82.04,120.02 81.03,119 81.03,118.36 81.41,117.98 81.41,110.19 79.78,108.56 79.78,101.85 78.51,100.58 78.51,77.58 79.02,77.07 79.02,76.47 80.71,74.78 80.71,74.08 v1(80.94,73.85)
UPHY0_RX2_P: length 52.7
  TOP w0.114: v3(81.98,121.5) 82.14,121.34 82.14,121.02 81.99,120.86 J1.C34 ; CA21.1 80.45,73.1 80.45,73.62 v1(80.23,73.85)
  IN3 w0.122: v3(81.98,121.5) 82.12,121.36 82.12,121.09 81.79,120.76 81.79,120.12 80.77,119.1 80.77,118.26 81.15,117.88 81.15,110.29 79.53,108.67 79.53,101.96 78.26,100.69 78.26,77.47 78.77,76.96 78.77,76.37 80.45,74.68 80.45,74.08 v1(80.23,73.85)
UPHY0_RX3_N: length 73.1
  TOP w0.114: v3(79.98,120) 80.12,119.86 80.12,119.54 79.93,119.36 J1.B32
  IN1 w0.122: v3(79.98,120) 79.98,119.71 80.12,119.57 80.12,118.02 82.7,115.44 92.35,115.44 94.39,113.41 121.54,113.41 126.61,118.47 130.34,118.47 131.85,116.97 134.62,116.97 135,117.35 135,118.14 v1(135.23,118.37)
  BOTTOM w0.114: RZ172.1 142.62,120.35 142.62,120.2 142.36,119.94 140.36,119.94 139.3,118.87 135.12,118.87 135,118.76 135,118.6 v1(135.23,118.37)
UPHY0_RX3_P: length 72.3
  TOP w0.114: J1.B33 80.51,119.36 80.37,119.5 80.37,119.85 v3(80.52,120)
  IN1 w0.122: v1(134.52,118.37) 134.75,118.14 134.75,117.45 134.51,117.22 131.95,117.22 130.45,118.73 126.5,118.73 121.44,113.67 94.49,113.67 92.46,115.7 82.8,115.7 80.38,118.12 80.38,119.57 80.52,119.71 v3(80.52,120)
  BOTTOM w0.114: v1(134.52,118.37) 134.75,118.6 134.75,118.86 135.01,119.13 139.19,119.13 140.26,120.19 142.25,120.19 142.37,120.31 142.37,120.35 RZ173.1
UPHY0_RX4_N: length 67.5
  TOP w0.114: v3(79.98,122.99) 80.12,122.86 80.12,122.51 79.96,122.36 J1.D32 ; SSD2.5 138.56,117.71 138.68,117.59 138.68,117.01 v1(138.46,116.78)
  BOTTOM w0.114: v3(79.98,122.99) 80.12,122.86 80.12,121.76 81.16,120.72 82.44,120.72 82.68,120.48 82.68,119.47 85.15,116.99 90.34,116.99 91.68,115.65 110.05,115.65 110.8,116.4 116.05,116.4 116.9,115.55 135.36,115.55 137.03,117.22 138.57,117.22 138.68,117.11 138.68,117.01 v1(138.46,116.78)
UPHY0_RX4_P: length 67.5
  TOP w0.114: v3(80.52,122.99) 80.37,122.85 80.37,122.52 80.52,122.36 J1.D33 ; SSD2.7 139.06,117.73 138.94,117.6 138.94,117.01 v1(139.17,116.78)
  BOTTOM w0.114: v3(80.52,122.99) 80.38,122.86 80.38,121.86 81.27,120.97 82.55,120.97 82.93,120.59 82.93,119.57 85.26,117.25 90.45,117.25 91.79,115.91 109.94,115.91 110.69,116.66 116.15,116.66 117.01,115.8 135.25,115.8 136.93,117.47 138.68,117.47 138.94,117.21 138.94,117.01 v1(139.17,116.78)
UPHY0_RX5_N: length 65.2
  TOP w0.114: v3(82.52,118.5) 82.39,118.37 82.39,118.08 82.62,117.86 J1.A35 ; v1(141.46,116.78) 141.68,117.01 141.68,117.59 141.56,117.71 SSD2.17
  BOTTOM w0.114: v3(82.52,118.5) 82.38,118.36 82.38,118.31 84.15,116.54 89.56,116.54 90.98,115.12 110.11,115.12 110.97,115.98 115.87,115.98 116.74,115.12 135.59,115.12 136.55,116.08 141.38,116.08 141.68,116.39 141.68,116.55 v1(141.46,116.78)
UPHY0_RX5_P: length 66.1
  TOP w0.114: v1(142.17,116.78) 141.94,117.01 141.94,117.6 142.06,117.73 SSD2.19 ; v3(81.98,118.5) 82.14,118.34 82.14,118.02 81.98,117.86 J1.A34
  BOTTOM w0.114: v1(142.17,116.78) 141.94,116.55 141.94,116.28 141.48,115.82 136.65,115.82 135.69,114.86 116.63,114.86 115.77,115.73 111.08,115.73 110.21,114.86 90.88,114.86 89.46,116.28 84.05,116.28 82.12,118.21 82.12,118.36 v3(81.98,118.5)
UPHY0_SF_PCIE1_CLK_N: length 61.2
  TOP w0.114: J1.D48 95.2,122.36 95.33,122.49 95.33,122.85 v3(95.18,122.99)
  IN1 w0.122: v3(95.18,122.99) 95.32,122.86 95.32,122.12 95.6,121.84 95.6,117.9 96.72,116.79 121.94,116.79 125.73,120.57 134.79,120.57 136.91,122.68 143,122.68 144.11,123.79 144.11,124.8 v1(144.34,125.03)
  BOTTOM w0.114: WIFI1.49 144.24,124.02 144.11,124.14 144.11,124.8 v1(144.34,125.03)
UPHY0_SF_PCIE1_CLK_P: length 60.4
  TOP w0.114: v3(95.72,122.99) 95.58,122.86 95.58,122.49 95.71,122.36 J1.D49
  IN1 w0.122: v1(143.63,125.03) 143.86,124.8 143.86,123.9 142.9,122.94 136.8,122.94 134.69,120.82 125.62,120.82 121.84,117.04 96.83,117.04 95.86,118.01 95.86,121.95 95.58,122.23 95.58,122.86 v3(95.72,122.99)
  BOTTOM w0.114: v1(143.63,125.03) 143.86,124.8 143.86,124.14 143.74,124.02 WIFI1.47
UPHY0_TX2_N: length 65
  TOP w0.114: v3(80.58,132) 80.36,131.78 80.36,131.47 80.48,131.36 J1.K33 ; v1(79.03,74.49) 78.8,74.26 78.8,73.1 CA23.1
  IN3 w0.122: v1(79.03,74.49) 78.8,74.71 78.8,75.42 78.13,76.09 78.13,76.81 77.62,77.32 77.62,99.17 77.24,99.55 77.24,109.98 80.26,113 80.26,117.45 79.86,117.86 79.1,117.86 78.36,118.6 78.36,130.43 79.12,131.19 80.07,131.19 80.35,131.47 80.35,131.77 v3(80.58,132)
UPHY0_TX2_P: length 64.9
  TOP w0.114: v3(79.86,132) 80.11,131.75 80.11,131.47 79.99,131.36 J1.K32 ; CA24.1 78.55,73.1 78.55,74.26 v1(78.32,74.49)
  IN3 w0.122: v3(79.86,132) 80.09,131.77 80.09,131.57 79.97,131.44 79.02,131.44 78.11,130.53 78.11,118.49 78.99,117.6 79.76,117.6 80.01,117.35 80.01,113.11 76.99,110.09 76.99,99.44 77.37,99.06 77.37,77.22 77.88,76.71 77.88,75.98 78.55,75.31 78.55,74.71 v1(78.32,74.49)
UPHY0_TX3_N: length 75.8
  TOP w0.114: J1.G34 81.99,126.86 82.12,126.99 82.12,127.36 v3(81.98,127.5)
  IN1 w0.122: v3(81.98,127.5) 82.17,127.68 82.17,127.87 82.44,128.14 83.39,128.14 84.81,126.72 84.81,122.65 83.82,121.66 83.82,121.16 83.06,120.4 83.06,119.49 83.82,118.72 83.82,117.33 84.56,116.59 92.99,116.59 95.03,114.55 121.22,114.55 126.18,119.51 132.06,119.51 132.59,118.98 132.59,118.57 v1(132.82,118.34)
  BOTTOM w0.114: CM66.1 138.56,120.18 138.56,119.93 138.33,119.71 134.19,119.71 133.35,118.87 132.72,118.87 132.59,118.75 132.59,118.57 v1(132.82,118.34)
UPHY0_TX3_P: length 75
  TOP w0.114: J1.G35 82.49,126.86 82.37,126.97 82.37,127.35 v3(82.52,127.5)
  IN1 w0.122: v1(132.11,118.34) 132.33,118.57 132.33,118.88 131.95,119.26 126.28,119.26 121.33,114.3 94.92,114.3 92.89,116.33 84.45,116.33 83.57,117.22 83.57,118.62 82.8,119.38 82.8,120.5 83.57,121.26 83.57,121.77 84.56,122.76 84.56,126.62 83.29,127.89 82.54,127.89 82.42,127.77 82.42,127.59 v3(82.52,127.5)
  BOTTOM w0.114: v1(132.11,118.34) 132.33,118.57 132.33,118.85 132.61,119.13 133.24,119.13 134.08,119.96 138.23,119.96 138.3,120.04 138.3,120.18 CM67.1
UPHY0_TX4_N: length 76.9
  TOP w0.114: CM25.1 138.25,121.75 138.37,121.87 138.37,122.19 138.25,122.3 137.08,122.3 135.42,120.65 128.4,120.65 120.02,112.27 88.55,112.27 87.88,112.94 87.88,113.61 87.66,113.84 ; 81.86,130.5 82.09,130.27 82.09,130.02 81.93,129.86 J1.J34
  IN3 w0.122: 87.66,113.84 87.86,114.05 87.86,114.86 86.17,116.54 86.17,120.96 84.43,122.7 84.43,123.24 84.04,123.63 84.04,125.96 83.45,126.55 83.45,127.85 82.09,129.21 82.09,130.27 81.86,130.5
UPHY0_TX4_N_M2M: length 4.4
  TOP w0.114: SSD2.11 140.06,119 140.18,119.13 140.18,119.81 139.98,120.02 138.63,120.02 138.37,120.28 138.37,120.7 138.25,120.82 CM25.2
UPHY0_TX4_P: length 77
  TOP w0.114: 88.37,113.84 88.14,113.61 88.14,113.04 88.66,112.52 119.92,112.52 128.3,120.9 135.32,120.9 136.97,122.56 138.36,122.56 138.62,122.29 138.62,121.87 138.73,121.75 CM26.1 ; 82.58,130.5 82.35,130.27 82.35,130 82.48,129.86 J1.J35
  IN3 w0.122: 88.37,113.84 88.11,114.1 88.11,114.96 86.43,116.65 86.43,121.07 84.68,122.81 84.68,123.35 84.29,123.74 84.29,126.07 83.7,126.65 83.7,127.95 82.35,129.31 82.35,130.27 82.58,130.5
UPHY0_TX4_P_M2M: length 4.4
  TOP w0.114: CM26.2 138.73,120.82 138.62,120.7 138.62,120.38 138.74,120.27 140.08,120.27 140.44,119.91 140.44,119.15 140.56,119.03 SSD2.13
UPHY0_TX5_N: length 82.3
  TOP w0.114: 80.52,128.99 80.39,128.87 80.39,128.5 80.53,128.36 J1.H33 ; CM27.1 142.44,121.75 142.56,121.87 142.56,122.13 142.13,122.56 139.45,122.56 138.81,123.19 136.71,123.19 134.93,121.41 128.25,121.41 119.87,113.03 99.87,113.03 98.53,114.38 86.6,114.38 86.49,114.26 86.49,114.03 86.72,113.8
  IN3 w0.122: 86.72,113.8 86.49,114.03 86.49,115.07 85.7,115.85 85.7,120.46 85.19,120.97 84.63,120.97 84.33,121.27 84.33,121.92 83.72,122.53 82.75,122.53 82.4,122.89 82.4,124.43 80.8,126.03 80.8,128.23 80.38,128.65 80.38,128.86 80.52,128.99
UPHY0_TX5_N_M2M: length 3.1
  TOP w0.114: CM27.2 142.46,120.82 142.57,120.7 142.57,120.14 143.18,119.53 143.18,119.18 143.06,119.06 SSD2.23
UPHY0_TX5_P: length 83.2
  TOP w0.114: 79.98,128.99 80.14,128.84 80.14,128.47 80.02,128.36 J1.H32 ; 86,113.8 86.23,114.03 86.23,114.37 86.5,114.63 98.63,114.63 99.98,113.28 119.76,113.28 128.14,121.67 134.82,121.67 136.6,123.44 138.92,123.44 139.55,122.81 142.24,122.81 142.81,122.24 142.81,121.87 142.93,121.75 CM28.1
  IN3 w0.122: 79.98,128.99 80.12,128.86 80.12,128.54 80.54,128.12 80.54,125.93 82.14,124.33 82.14,122.78 82.65,122.28 83.61,122.28 84.07,121.81 84.07,121.17 84.52,120.72 85.09,120.72 85.45,120.36 85.45,115.75 86.23,114.96 86.23,114.03 86,113.8
UPHY0_TX5_P_M2M: length 3.1
  TOP w0.114: SSD2.25 143.56,119.07 143.44,119.2 143.44,119.63 142.82,120.25 142.82,120.7 142.94,120.82 CM28.2
UPHY0_TX6_N_M2M: length 3.1
  TOP w0.114: CM29.2 146.62,120.82 146.74,120.7 146.74,120.24 146.18,119.69 146.18,119.13 146.06,119.01 SSD2.35
UPHY0_TX6_P_M2M: length 3.1
  TOP w0.114: SSD2.37 146.56,119 146.44,119.13 146.44,119.58 146.99,120.13 146.99,120.7 147.12,120.83 CM1.2
UPHY0_TX7_N_M2M: length 4.4
  TOP w0.114: SSD2.47 149.06,119.07 149.18,119.19 149.18,119.87 149.51,120.19 150.83,120.19 150.94,120.31 150.94,120.7 150.83,120.82 CM30.2
UPHY0_TX7_P_M2M: length 4.4
  TOP w0.114: CM31.2 151.31,120.82 151.19,120.7 151.19,120.2 150.93,119.94 149.62,119.94 149.44,119.76 149.44,119.19 149.56,119.07 SSD2.49
UPHY1_RX0_N: length 28.7
  TOP w0.114: CM41.2 55.75,110.03 55.75,110.32 v1(55.98,110.55) ; J1.D25 72.56,122.36 72.39,122.53 72.39,122.87 v3(72.52,122.99)
  IN3 w0.122: v1(55.98,110.55) 55.75,110.78 55.75,112.12 56.24,112.6 61.4,112.6 62.06,113.26 65,113.26 68.22,116.48 70.48,116.48 71.7,117.7 71.7,118.97 70.97,119.71 70.97,120.31 71.27,120.61 71.91,120.61 72.38,121.08 72.38,122.86 v3(72.52,122.99)
UPHY1_RX0_P: length 28.7
  TOP w0.114: v3(71.98,122.99) 72.14,122.84 72.14,122.53 71.97,122.36 J1.D24 ; CM40.2 55.5,110.03 55.5,110.32 v1(55.27,110.55)
  IN3 w0.122: v1(55.27,110.55) 55.5,110.78 55.5,112.22 56.13,112.85 61.29,112.85 61.95,113.51 64.89,113.51 68.12,116.74 70.38,116.74 71.45,117.81 71.45,118.87 70.71,119.6 70.71,120.42 71.17,120.87 71.8,120.87 72.12,121.19 72.12,122.86 v3(71.98,122.99)
UPHY1_RX1_N: length 23.4
  TOP w0.114: v3(71.98,120) 72.11,119.87 72.11,119.51 71.96,119.36 J1.B24
  IN3 w0.122: v3(71.98,120) 72.12,119.86 72.12,119.5 72.36,119.26 72.36,117.61 70.46,115.7 68.22,115.7 65.25,112.73 62.63,112.73 61.97,112.06 59.51,112.06 59.18,111.74 59.18,110.52 58.9,110.24 58.29,110.24 58.17,110.36 58.17,110.45 v1(58.39,110.68)
  BOTTOM w0.114: CM68.2 58.17,109.82 58.17,110.45 v1(58.39,110.68)
UPHY1_RX1_P: length 24.3
  TOP w0.114: v3(72.52,120) 72.36,119.84 72.36,119.51 72.51,119.36 J1.B25
  IN3 w0.122: v3(72.52,120) 72.38,119.86 72.38,119.6 72.62,119.36 72.62,117.5 70.56,115.44 68.33,115.44 65.36,112.47 62.74,112.47 62.08,111.81 59.61,111.81 59.44,111.63 59.44,110.41 59,109.98 58.18,109.98 57.91,110.25 57.91,110.45 v1(57.68,110.68)
  BOTTOM w0.114: v1(57.68,110.68) 57.91,110.45 57.91,109.82 CM69.2
UPHY1_RX2_N: length 25.6
  TOP w0.114: J1.C26 74,120.86 74.12,120.98 74.12,121.36 v3(73.98,121.5) ; CM43.2 60.58,109.78 60.58,110.45 v1(60.81,110.68)
  IN3 w0.122: v3(73.98,121.5) 73.98,121.21 74.12,121.07 74.12,119.73 74.72,119.13 75.31,119.13 75.56,118.87 75.56,118.19 75.26,117.88 74.96,117.88 70.54,113.46 68.5,113.46 65.2,110.16 60.73,110.16 60.58,110.31 60.58,110.45 v1(60.81,110.68)
UPHY1_RX2_P: length 26.5
  TOP w0.114: J1.C27 74.49,120.86 74.37,120.98 74.37,121.35 v3(74.52,121.5) ; v1(60.1,110.68) 60.33,110.45 60.33,109.78 CM42.2
  IN3 w0.122: v3(74.52,121.5) 74.52,121.21 74.38,121.07 74.38,119.83 74.83,119.38 75.42,119.38 75.82,118.98 75.82,118.08 75.37,117.63 75.06,117.63 70.64,113.21 68.61,113.21 65.3,109.91 60.62,109.91 60.33,110.2 60.33,110.45 v1(60.1,110.68)
UPHY1_RX3_N: length 17.9
  TOP w0.114: J1.A27 74.61,117.86 74.37,118.11 74.37,118.35 v3(74.52,118.5)
  IN3 w0.122: v1(63.22,110.64) 62.99,110.87 62.99,111.46 63.2,111.66 65.84,111.66 68.56,114.38 70.67,114.38 74.37,118.08 74.37,118.35 v3(74.52,118.5)
  BOTTOM w0.114: CM70.2 62.99,109.78 62.99,110.41 v1(63.22,110.64)
UPHY1_RX3_P: length 17.9
  TOP w0.114: v3(73.98,118.5) 74.12,118.36 74.12,118.06 73.92,117.86
  TOP w0.127: J1.A26 73.92,117.86
  IN3 w0.122: v3(73.98,118.5) 74.12,118.36 74.12,118.19 70.56,114.63 68.45,114.63 65.74,111.91 63.09,111.91 62.74,111.56 62.74,110.87 v1(62.51,110.64)
  BOTTOM w0.114: CM71.2 62.74,109.78 62.74,110.41 v1(62.51,110.64)
UPHY1_TX0_N: length 31
  TOP w0.114: v1(54.71,114.06) 54.48,113.83 54.48,113.33 CM33.2 ; v3(72.52,128.99) 72.39,128.87 72.39,128.47 72.5,128.36 J1.H25
  IN3 w0.122: v3(72.52,128.99) 72.39,128.87 72.39,128.47 72.13,128.21 67.63,128.21 66.17,126.75 65.23,126.75 64.34,125.86 64.34,120.04 61.82,117.53 56.64,117.53 54.48,115.37 54.48,114.29 v1(54.71,114.06)
UPHY1_TX0_P: length 31.1
  TOP w0.114: v3(71.98,128.99) 72.14,128.84 72.14,128.47 72.02,128.36 J1.H24 ; CM32.2 54.23,113.33 54.23,113.83 v1(54,114.06)
  IN3 w0.122: v1(54,114.06) 54.23,114.29 54.23,115.47 56.54,117.78 61.72,117.78 64.08,120.15 64.08,125.96 65.12,127 66.06,127 67.52,128.46 72.02,128.46 72.14,128.57 72.14,128.84 v3(71.98,128.99)
UPHY1_TX1_N: length 33.6
  TOP w0.114: CM35.2 56.96,113.33 56.96,113.83 v1(57.19,114.06) ; J1.K24 71.97,131.36 72.14,131.52 72.14,131.84 v3(71.98,132)
  IN3 w0.122: v3(71.98,132) 72.12,131.86 72.12,130.72 73.46,129.38 73.46,128.65 71.6,126.8 69.14,126.8 67.82,125.48 67.06,125.48 66.17,124.59 66.17,120.63 66.04,120.5 66.04,118.65 64.31,116.92 59.64,116.92 57.91,115.19 57.91,113.81 57.74,113.64 57.08,113.64 56.96,113.76 56.96,113.83 v1(57.19,114.06)
UPHY1_TX1_P: length 34.4
  TOP w0.114: v1(56.48,114.06) 56.71,113.83 56.71,113.33 CM34.2 ; J1.K25 72.55,131.36 72.39,131.52 72.39,131.87 v3(72.52,132)
  IN3 w0.122: v1(56.48,114.06) 56.71,113.83 56.71,113.66 56.98,113.39 57.84,113.39 58.17,113.71 58.17,115.09 59.74,116.66 64.41,116.66 66.29,118.54 66.29,120.4 66.42,120.52 66.42,124.48 67.16,125.22 67.92,125.22 69.24,126.54 71.7,126.54 73.71,128.55 73.71,129.49 72.38,130.82 72.38,131.86 v3(72.52,132)
UPHY1_TX2_N: length 27.9
  TOP w0.114: v3(73.98,127.5) 74.12,127.36 74.12,127 73.98,126.86 J1.G26 ; CM37.2 59.37,113.21 59.37,113.83 v1(59.6,114.06)
  IN3 w0.122: v3(73.98,127.5) 74.12,127.36 74.12,125.99 73.48,125.35 68.98,125.35 68.45,124.82 68.45,122.15 68.07,121.77 68.07,120.88 67.82,120.63 67.82,119.76 66.93,118.88 66.93,118.24 64.81,116.12 61.1,116.12 60.35,115.37 60.35,114.1 59.89,113.64 59.49,113.64 59.37,113.76 59.37,113.83 v1(59.6,114.06)
UPHY1_TX2_P: length 28.8
  TOP w0.114: v1(58.89,114.06) 59.12,113.83 59.12,113.21 CM36.2 ; v3(74.52,127.5) 74.37,127.35 74.37,127.01 74.52,126.86 J1.G27
  IN3 w0.122: v1(58.89,114.06) 59.12,113.83 59.12,113.66 59.39,113.39 59.99,113.39 60.6,114 60.6,115.26 61.21,115.87 64.92,115.87 67.18,118.14 67.18,118.77 68.07,119.66 68.07,120.52 68.33,120.78 68.33,121.67 68.71,122.05 68.71,124.71 69.09,125.09 73.58,125.09 74.37,125.88 74.37,127.35 v3(74.52,127.5)
UPHY1_TX3_N: length 29.2
  TOP w0.114: CM39.2 61.85,113.33 61.85,113.83 v1(62.08,114.06) ; J1.J27 74.48,129.86 74.37,129.97 74.37,130.35 v3(74.52,130.5)
  IN3 w0.122: v1(62.08,114.06) 61.85,114.29 61.85,114.97 61.97,115.09 65.58,115.09 68.99,118.5 68.99,120.24 70.84,122.09 70.84,123.18 71.27,123.61 73.73,123.61 75.82,125.7 75.82,129.31 75.37,129.76 74.76,129.76 74.38,130.15 74.38,130.36 v3(74.52,130.5)
UPHY1_TX3_P: length 29.2
  TOP w0.114: v3(73.98,130.5) 74.11,130.36 74.11,129.97 74,129.86 J1.J26 ; CM38.2 61.59,113.33 61.59,113.83 v1(61.37,114.06)
  IN3 w0.122: v3(73.98,130.5) 74.12,130.36 74.12,130.04 74.66,129.51 75.26,129.51 75.56,129.21 75.56,125.81 73.62,123.87 71.17,123.87 70.59,123.29 70.59,122.19 68.74,120.34 68.74,118.6 65.48,115.34 61.87,115.34 61.59,115.07 61.59,114.29 v1(61.37,114.06)
UPHY_RX0_N: length 133.7
  TOP w0.114: v3(70.52,118.5) 70.36,118.34 70.36,117.98 70.48,117.86 J1.A23
  IN1 w0.122: v3(70.52,118.5) 70.38,118.63 70.38,122.6 71.7,123.93 71.7,124.92 70.99,125.63 70.99,129.29 72.8,131.09 73.43,131.09 73.91,131.57 73.91,132.38 74.14,132.61 75.36,132.61 75.95,133.2 75.95,138.81 76.71,139.57 92.82,139.57 107.26,154.02 110.53,154.02 113.86,157.35 121.05,157.35 126.02,162.33 126.02,165.36 131.33,170.67 139.62,170.67 140.02,171.07 154.33,171.07 158.01,174.75 158.01,182.44 158.14,182.56 158.43,182.56 v1(158.66,182.33)
  BOTTOM w0.114: v1(158.66,182.33) 158.43,182.56 158.08,182.56 157.96,182.45 RZ143.1
UPHY_RX0_P: length 134.1
  TOP w0.114: J1.A22 69.99,117.86 70.1,117.97 70.1,118.37 v3(69.98,118.5)
  IN1 w0.122: v3(69.98,118.5) 70.12,118.63 70.12,122.71 71.45,124.03 71.45,124.81 70.74,125.52 70.74,129.39 72.69,131.34 73.33,131.34 73.66,131.68 73.66,132.49 74.04,132.87 75.26,132.87 75.69,133.3 75.69,138.92 76.6,139.83 92.71,139.83 107.16,154.27 110.42,154.27 113.76,157.61 120.95,157.61 125.77,162.43 125.77,165.47 131.23,170.92 139.52,170.92 139.92,171.32 154.22,171.32 157.76,174.86 157.76,182.55 158.03,182.82 158.43,182.82 v1(158.66,183.05)
  BOTTOM w0.114: v1(158.66,183.05) 158.43,182.82 158.08,182.82 157.96,182.93 RZ142.1
UPHY_RX10_N: length 91
  TOP w0.114: SSD2.29 144.56,117.71 144.68,117.59 144.68,117.01 v1(144.46,116.78) ; J1.B13 60.5,119.36 60.38,119.48 60.38,119.85 v3(60.52,120)
  BOTTOM w0.114: v1(144.46,116.78) 144.68,116.55 144.68,116.39 143.49,115.19 136.67,115.19 135.74,114.25 90.6,114.25 89.08,115.77 83.85,115.77 83.19,116.43 70.82,116.43 67.87,119.38 60.63,119.38 60.38,119.63 60.38,119.86 v3(60.52,120)
UPHY_RX10_P: length 91.9
  TOP w0.114: v1(145.17,116.78) 144.94,117.01 144.94,117.6 145.06,117.73 SSD2.31 ; v3(59.98,120) 60.12,119.86 60.12,119.47 60.01,119.36 J1.B12
  BOTTOM w0.114: v1(145.17,116.78) 144.94,116.55 144.94,116.28 143.59,114.94 136.78,114.94 135.84,114 90.49,114 88.97,115.52 83.74,115.52 83.08,116.18 70.71,116.18 67.76,119.13 60.53,119.13 60.12,119.53 60.12,119.86 v3(59.98,120)
UPHY_RX11_N: length 100.2
  TOP w0.114: J1.D13 60.5,122.36 60.38,122.47 60.38,122.86 v3(60.52,123) ; SSD2.41 147.56,117.71 147.68,117.59 147.68,117.01 v1(147.46,116.78)
  BOTTOM w0.114: v1(147.46,116.78) 147.68,116.55 147.68,116.32 147.57,116.2 145.69,116.2 143.97,114.48 139.14,114.48 137.31,112.65 136.09,112.65 135.18,113.56 90.02,113.56 88.52,115.06 83.16,115.06 82.55,115.67 70.22,115.67 67.9,117.98 60.78,117.98 59.05,119.71 59.05,120.27 60.38,121.59 60.38,122.86 v3(60.52,123)
UPHY_RX11_P: length 101.1
  TOP w0.114: SSD2.43 148.06,117.73 147.94,117.6 147.94,117.01 v1(148.17,116.78) ; J1.D12 60.04,122.36 60.13,122.45 60.13,122.85 v3(59.98,123)
  BOTTOM w0.114: v1(148.17,116.78) 147.94,116.55 147.94,116.21 147.68,115.95 145.8,115.95 144.07,114.22 139.24,114.22 137.41,112.39 135.99,112.39 135.07,113.31 89.91,113.31 88.41,114.81 83.05,114.81 82.44,115.42 70.11,115.42 67.8,117.73 60.68,117.73 58.8,119.6 58.8,120.37 60.12,121.7 60.12,122.86 v3(59.98,123)
UPHY_TX0_N: length 122.2
  TOP w0.114: J1.J23 70.5,129.86 70.38,129.97 70.38,130.36 v3(70.52,130.5)
  IN1 w0.122: v3(70.52,130.5) 70.38,130.63 70.38,131.64 72.34,133.6 72.34,136.6 76.2,140.46 92.54,140.46 106.96,154.88 110.29,154.88 113.54,158.14 120.73,158.14 125.24,162.65 125.24,165.69 131.01,171.45 139.3,171.45 140.55,172.71 148.5,172.71 149.35,171.85 154.01,171.85 157.23,175.08 157.23,183.81 157.76,184.34 158.08,184.34 v1(158.31,184.11)
  BOTTOM w0.114: CA246.1 157.81,184.34 158.08,184.34 v1(158.31,184.11)
UPHY_TX0_P: length 122.6
  TOP w0.114: v3(69.98,130.5) 70.13,130.35 70.13,130.02 69.97,129.86 J1.J22
  IN1 w0.122: v3(69.98,130.5) 70.12,130.63 70.12,131.74 72.09,133.71 72.09,136.71 76.09,140.72 92.44,140.72 106.86,155.14 110.18,155.14 113.43,158.39 120.62,158.39 124.99,162.76 124.99,165.79 130.9,171.7 139.19,171.7 140.45,172.96 148.6,172.96 149.46,172.11 153.9,172.11 156.98,175.18 156.98,183.92 157.65,184.59 158.08,184.59 v1(158.31,184.82)
  BOTTOM w0.114: v1(158.31,184.82) 158.08,184.59 157.81,184.59 CA247.1
UPHY_TX10_N: length 108.1
  TOP w0.114: J1.K12 59.95,131.36 60.12,131.53 60.12,131.86 v3(59.98,132) ; v1(75.69,117.01) 75.92,116.78 75.92,116.05 76.81,115.16 98.98,115.16 100.36,113.79 119.71,113.79 128.09,122.17 134.43,122.17 136.34,124.08 139.32,124.08 139.95,123.44 142.26,123.44 142.91,122.79 146.47,122.79 146.71,122.55 146.71,121.88 146.59,121.75 CM29.1
  BOTTOM w0.114: v3(59.98,132) 60.12,131.86 60.12,131.7 58.8,130.38 58.8,128.42 60.53,126.7 61.29,126.7 61.75,126.24 61.75,125.27 66.39,120.62 75.1,120.62 75.93,119.8 75.93,117.24 v1(75.69,117.01)
UPHY_TX10_P: length 108.1
  TOP w0.114: 60.52,131.36 60.38,131.51 60.38,131.85 v3(60.52,132) ; CM1.1 147.08,121.77 146.97,121.88 146.97,122.65 146.57,123.05 143.02,123.05 142.37,123.7 140.06,123.7 139.42,124.33 136.23,124.33 134.33,122.43 127.99,122.43 119.61,114.05 100.46,114.05 99.09,115.42 76.91,115.42 76.17,116.15 76.17,116.78 v1(76.4,117.01)
  TOP w0.127: 60.52,131.36 J1.K13
  BOTTOM w0.114: v1(76.4,117.01) 76.18,117.22 76.18,119.9 75.21,120.88 66.5,120.88 62,125.37 62,126.34 61.4,126.95 60.63,126.95 59.05,128.53 59.05,130.28 60.38,131.6 60.38,131.86 v3(60.52,132)
UPHY_TX11_N: length 108.3
  TOP w0.114: J1.H13 60.54,128.36 60.38,128.52 60.38,128.85 v3(60.52,128.99) ; CM30.1 150.83,121.75 150.94,121.87 150.94,122.67 150.03,123.57 143.15,123.57 142.37,124.35 142.37,124.74 142.06,125.04 136.04,125.04 134.07,123.06 128.07,123.06 119.56,114.55 100.73,114.55 99.34,115.94 79.03,115.94 78.51,116.46 78.51,116.78 v1(78.28,117.01)
  BOTTOM w0.114: v3(60.52,128.99) 60.38,129.13 60.38,129.3 60.49,129.41 61.62,129.41 61.85,129.18 61.85,128.27 66.52,123.6 67.31,123.6 68.73,122.17 77.44,122.17 78.51,121.1 78.51,117.23 v1(78.28,117.01)
UPHY_TX11_P: length 109.5
  TOP w0.114: CM31.1 151.31,121.75 151.19,121.87 151.19,122.77 150.14,123.83 143.26,123.83 142.62,124.46 142.62,124.84 142.22,125.24 ; v3(59.98,128.99) 60.12,128.86 60.12,128.52 59.96,128.36 J1.H12 ; 142.22,125.24 142.17,125.29 135.94,125.29 133.96,123.32 127.96,123.32 119.45,114.81 100.83,114.81 99.44,116.19 79.13,116.19 78.77,116.56 78.77,116.78 v1(78.99,117.01) ; 142.22,125.24 142.42,125.04
  BOTTOM w0.114: v1(78.99,117.01) 78.77,117.23 78.77,121.21 77.55,122.43 68.84,122.43 67.42,123.85 66.63,123.85 62.1,128.38 62.1,129.29 61.72,129.67 60.39,129.67 60.12,129.4 60.12,129.13 v3(59.98,128.99)
USB2_0_N: length 98.5
  TOP w0.102: J1.F13 60.54,125.36 60.38,125.53 60.38,125.85 v3(60.52,126)
  IN1 w0.109: v3(60.52,126) 60.38,125.86 60.38,125.38 60.49,125.28 61.7,125.28 62.1,124.87 62.1,117.5 60.18,115.57 53.54,115.57 53.04,115.06 53.04,112.62 51.38,110.97 51.38,106.06 50.5,105.17 50.5,100.53 50.88,100.15 50.88,94.06 50.16,93.34 50.16,81.56 52.53,79.2 52.53,75.76 53.14,75.15 53.14,73.76 53.67,73.23 59.49,73.23 61.35,71.37 61.35,69.82 61.72,69.45 61.72,62.23 64.91,59.04 67.21,59.04 v1(67.44,59.27)
  BOTTOM w0.102: L7.1 63.61,53.57 63.88,53.85 63.88,56.24 66.68,59.04 67.21,59.04 v1(67.44,59.27)
USB2_0_P: length 98.5
  TOP w0.102: v3(59.98,126) 60.12,125.86 60.12,125.53 59.96,125.36 J1.F12
  IN1 w0.109: v3(59.98,126) 60.12,125.86 60.12,125.28 60.38,125.02 61.59,125.02 61.85,124.77 61.85,117.6 60.07,115.82 53.44,115.82 52.78,115.17 52.78,112.72 51.13,111.07 51.13,106.16 50.24,105.27 50.24,100.43 50.62,100.05 50.62,94.16 49.91,93.45 49.91,81.45 52.27,79.09 52.27,75.65 52.88,75.04 52.88,73.65 53.56,72.97 59.39,72.97 61.1,71.26 61.1,69.72 61.47,69.35 61.47,62.12 64.81,58.78 67.21,58.78 v1(67.44,58.55)
  BOTTOM w0.102: L7.4 64.41,53.57 64.14,53.85 64.14,56.13 66.78,58.78 67.21,58.78 v1(67.44,58.55)
USB2_1_N: length 139.9
  TOP w0.114: v3(57.98,121.5) 58.13,121.35 58.13,120.95 58.04,120.86 J1.C10
  IN1 w0.109: v3(57.98,121.5) 58.12,121.63 58.12,122.69 58.8,123.37 58.8,125.04 56.79,127.05 56.79,128.22 56.97,128.4 56.97,129.75 57.45,130.23 57.45,134.34 57.98,134.87 67.85,134.87 74.63,141.66 92.25,141.66 110.09,159.49 115.32,159.49 117.14,161.31 122.45,161.31 124.08,162.94 124.08,165.99 130.57,172.48 138.87,172.48 140.13,173.74 150.88,173.74 151.49,173.13 151.49,172.82 v1(151.71,172.59)
  BOTTOM w0.102: v1(151.71,172.59) 151.51,172.8 151.51,173 151.61,173.1 156.44,173.1 158.06,174.72 158.06,175.82 158.83,176.58 158.83,177.3 158.58,177.55 158.27,177.55 FL1.1
USB2_1_P: length 138.8
  TOP w0.114: J1.C11 58.5,120.86 58.38,120.97 58.38,121.36 v3(58.52,121.5)
  IN1 w0.109: v1(151,172.59) 151.23,172.82 151.23,173.02 150.77,173.48 140.23,173.48 138.98,172.23 130.68,172.23 124.33,165.88 124.33,162.84 122.55,161.06 117.25,161.06 115.43,159.24 110.19,159.24 92.36,141.4 74.73,141.4 67.95,134.62 58.09,134.62 57.71,134.24 57.71,130.12 57.23,129.64 57.23,128.3 57.05,128.12 57.05,127.16 59.05,125.15 59.05,123.26 58.38,122.58 58.38,121.63 v3(58.52,121.5)
  BOTTOM w0.102: v1(151,172.59) 151.26,172.85 151.26,173.1 151.51,173.35 156.34,173.35 157.81,174.83 157.81,175.92 158.57,176.69 158.57,177.19 158.47,177.29 158.27,177.29 FL1.4 157.96,176.99 RZ146.1
USB2_1N_CON: length 18.5
  TOP w0.102: CN1.2 110.03,66.36 110.13,66.46 110.28,66.46 111.23,65.51 112.95,65.51 113.31,65.15 113.31,54.73 113.21,54.62 113.04,54.62 112.92,54.75 D5.10 D5.1 111.5,54.75 111.38,54.62 111.17,54.62 111,54.79 110.67,54.79 110.39,55.06 L2.2
USB2_1P_CON: length 19.4
  TOP w0.102: CN1.3 110.03,66.84 110.16,66.71 110.38,66.71 111.33,65.76 113.06,65.76 113.56,65.26 113.56,54.62 113.31,54.37 113.02,54.37 112.9,54.25 D5.9 D5.2 111.5,54.25 111.38,54.37 111.06,54.37 110.9,54.53 110.67,54.53 110.39,54.26 L2.3
USB2_2_N: length 72.5
  TOP w0.102: v1(81.7,75.64) 81.93,75.41 81.93,74.16 81.3,73.53 81.3,72.07 81.25,72.03 81.25,71.48 81.3,71.44 81.3,71.34 81.22,71.27 U20.32 ; J1.A11 58.38,117.54 58.38,117.39 59.21,116.56 72.9,116.56 75.29,114.17 79.4,114.17 81.05,112.52 82.42,112.52 82.52,112.62 82.52,112.97 v1(82.3,113.2)
  IN3 w0.109: v1(81.7,75.64) 81.93,75.87 81.93,76.07 80.42,77.59 80.42,83.06 79.65,83.82 79.65,98.4 81.33,100.08 81.33,109.09 82.52,110.29 82.52,112.97 v1(82.3,113.2)
USB2_2_P: length 73.3
  TOP w0.102: v1(83.01,113.2) 82.78,112.97 82.78,112.52 82.53,112.27 80.95,112.27 79.29,113.92 75.18,113.92 72.8,116.31 59.1,116.31 58.12,117.29 58.12,117.54 J1.A10 ; U20.31 81.62,71.31 81.55,71.38 81.55,71.55 81.51,71.59 81.51,71.92 81.55,71.96 81.55,73.42 82.18,74.06 82.18,75.41 v1(82.41,75.64)
  IN3 w0.109: v1(82.41,75.64) 82.18,75.87 82.18,76.18 80.67,77.69 80.67,83.16 79.91,83.93 79.91,98.29 81.58,99.97 81.58,108.99 82.78,110.18 82.78,112.97 v1(83.01,113.2)
USB2_2N_CON: length 49.4
  TOP w0.102: L1.2 110.39,53.26 110.67,52.98 110.93,52.98 111.07,53.12 111.42,53.12 111.54,53.25 D5.4 D5.7 112.87,53.25 113.01,53.11 113.41,53.11 113.87,52.65 113.87,49.61 111.71,47.45 111.71,42.75 110.69,41.73 107.14,41.73 104.85,39.45 96.36,39.45 90.22,45.59 83.14,45.59 82.47,44.93 82.47,44.78 82.58,44.68 CN2.2
USB2_2P_CON: length 49
  TOP w0.102: L1.3 110.39,52.46 110.67,52.73 111.04,52.73 111.17,52.87 111.42,52.87 111.54,52.75 D5.5 D5.6 112.87,52.75 112.98,52.86 113.31,52.86 113.61,52.55 113.61,49.71 111.46,47.55 111.46,42.85 110.59,41.99 107.03,41.99 104.75,39.7 96.47,39.7 90.32,45.85 83.03,45.85 82.22,45.03 82.22,44.78 82.12,44.68 CN2.3
USB2_3_N: length 93.2
  TOP w0.102: v3(57.98,127.5) 58.12,127.36 58.12,127.1 57.87,126.86
  TOP w0.127: J1.G10 57.87,126.86
  IN1 w0.109: v1(129.77,117.33) 129.54,117.1 129.54,116.61 125.57,112.64 89.78,112.64 88.4,111.25 76.23,111.25 73.05,114.43 66.82,114.43 64.14,117.12 64.14,125.75 63.36,126.53 60.19,126.53 59.86,126.85 58.37,126.85 58.12,127.11 58.12,127.36 v3(57.98,127.5)
  BOTTOM w0.102: RZ175.1 133.1,120.17 133.1,120.01 132.85,119.76 131.42,119.76 129.54,117.88 129.54,117.56 v1(129.77,117.33)
USB2_3_P: length 92.3
  TOP w0.102: 58.66,126.86 58.37,127.15 58.37,127.35 v3(58.52,127.5)
  TOP w0.127: J1.G11 58.66,126.86
  IN1 w0.109: v1(129.06,117.33) 129.29,117.1 129.29,116.71 125.46,112.89 89.67,112.89 88.29,111.51 76.33,111.51 73.16,114.68 66.93,114.68 64.39,117.22 64.39,125.86 63.47,126.78 60.29,126.78 59.97,127.1 58.48,127.1 58.37,127.21 58.37,127.35 v3(58.52,127.5)
  BOTTOM w0.102: RZ176.1 132.84,120.17 132.84,120.12 132.74,120.02 131.31,120.02 129.29,117.99 129.29,117.56 v1(129.06,117.33)
USB2_DWN_DM1: length 48.2
  TOP w0.102: v1(93.73,57.33) 93.5,57.1 93.5,56.39 93.93,55.96 106.58,55.96 107.75,54.79 107.92,54.79 108.2,55.06 L2.1 ; U20.23 84.82,71.31 84.9,71.38 84.9,71.77 85.19,72.06 85.19,72.13 v1(84.98,72.34)
  IN3 w0.109: v1(84.98,72.34) 85.2,72.57 85.2,73.4 85.59,73.79 90.94,73.79 92.76,71.96 96.32,71.96 97.23,71.05 97.23,63.68 93.5,59.94 93.5,57.56 v1(93.73,57.33)
USB2_DWN_DM2: length 27.4
  TOP w0.102: U20.76 86.02,61.8 85.95,61.73 85.95,60.54 91.29,55.19 105.49,55.19 107.72,52.96 107.87,52.96 108.17,53.26 L1.1
USB2_DWN_DM3: length 78.4
  TOP w0.102: v1(79.43,60.81) 79.21,61.03 79.21,61.16 79.31,61.26 79.66,61.26 79.95,61.56 79.95,61.79 80.02,61.86 U20.61 ; v1(139.14,68.9) 139.37,68.67 142.61,68.67 142.73,68.8 U13.6
  IN1 w0.109: v1(79.43,60.81) 79.2,61.04 79.2,62.56 79.45,62.81 86.18,62.81 86.69,62.31 90.1,62.31 91.24,63.45 92.68,63.45 93.24,64.01 96.5,64.01 97.36,64.87 97.36,68.53 98.5,69.67 107.9,69.67 110.31,72.09 115.72,72.09 116.34,71.46 133.08,71.46 133.76,72.14 137.31,72.14 139.78,69.67 139.78,68.92 139.52,68.67 139.37,68.67 v1(139.14,68.9)
USB2_DWN_DM4: length 147.5
  TOP w0.102: U20.64 81.22,61.51 81.15,61.44 81.15,61.06 v1(81.38,60.84) ; RZ9.2 82.12,148.16 82.12,148.03 81.92,147.83 61.21,147.83 59.56,146.18 59.56,145.5 v1(59.33,145.27)
  IN3 w0.109: v1(81.38,60.84) 81.15,61.06 81.15,61.29 80.89,61.54 75.62,61.54 74.12,63.05 74.12,72.87 74.88,73.63 74.88,74.39 76.4,75.92 76.4,82.22 76.73,82.55 76.73,93.86 75.97,94.62 75.97,98.91 74.96,99.93 74.96,107.42 74.3,108.08 54.99,108.08 48.9,114.18 48.9,136.78 53.09,140.97 54.33,140.97 59.16,145.8 59.45,145.8 59.56,145.69 59.56,145.5 v1(59.33,145.27)
USB2_DWN_DP1: length 47.8
  TOP w0.102: v1(85.69,72.34) 85.44,72.1 85.44,71.96 85.15,71.67 85.15,71.39 85.22,71.32 U20.22 ; v1(93.01,57.33) 93.24,57.1 93.24,56.28 93.82,55.7 106.47,55.7 107.64,54.53 107.95,54.53 108.22,54.26 L2.4
  IN3 w0.109: v1(93.01,57.33) 93.24,57.56 93.24,60.05 96.98,63.78 96.98,70.94 96.22,71.7 92.66,71.7 90.83,73.53 85.69,73.53 85.46,73.3 85.46,72.57 v1(85.69,72.34)
USB2_DWN_DP2: length 27.8
  TOP w0.102: U20.75 85.62,61.8 85.7,61.73 85.7,60.43 91.19,54.94 105.38,54.94 107.62,52.7 107.9,52.7 108.15,52.46 L1.4
USB2_DWN_DP3: length 79.7
  TOP w0.102: U20.60 79.62,61.88 79.7,61.81 79.7,61.66 79.55,61.52 79.2,61.52 78.95,61.27 78.95,61.05 v1(78.71,60.81) ; U13.5 142.77,68.3 142.65,68.42 139.37,68.42 v1(139.14,68.19)
  IN1 w0.109: v1(78.71,60.81) 78.94,61.04 78.94,62.67 79.35,63.07 86.29,63.07 86.8,62.56 89.99,62.56 91.14,63.7 92.58,63.7 93.14,64.26 96.39,64.26 97.1,64.97 97.1,68.63 98.4,69.93 107.79,69.93 110.21,72.34 115.83,72.34 116.45,71.72 132.98,71.72 133.65,72.39 137.42,72.39 140.03,69.78 140.03,68.82 139.63,68.42 139.37,68.42 v1(139.14,68.19)
USB2_DWN_DP4: length 148.3
  TOP w0.102: RZ10.2 82.37,148.18 82.37,147.93 82.02,147.57 61.32,147.57 59.82,146.07 59.82,145.5 v1(60.05,145.27) ; U20.63 80.82,61.51 80.9,61.44 80.9,61.06 v1(80.67,60.84)
  IN3 w0.109: v1(80.67,60.84) 80.9,61.06 80.9,61.18 80.79,61.29 75.51,61.29 73.86,62.94 73.86,72.97 74.63,73.74 74.63,74.5 76.15,76.02 76.15,82.33 76.48,82.66 76.48,93.75 75.72,94.51 75.72,98.81 74.7,99.82 74.7,107.31 74.19,107.82 54.89,107.82 48.64,114.07 48.64,136.88 52.98,141.22 54.23,141.22 59.06,146.05 59.56,146.05 59.82,145.79 59.82,145.5 v1(60.05,145.27)
USB3_DWN_RXN1: length 27.8
  TOP w0.102: v1(98.61,68.05) 98.83,67.82 100.76,67.82 101.03,68.09 L4.1 ; v1(83.67,74.58) 83.44,74.35 83.44,74.06 83.16,73.78 83.16,71.35 83.22,71.29 U20.27
  BOTTOM w0.102: v1(98.61,68.05) 98.83,67.82 98.98,67.82 99.08,67.92 99.08,68.35 94.66,72.77 89.79,72.77 86.61,75.95 83.82,75.95 83.44,75.56 83.44,74.81 v1(83.67,74.58)
USB3_DWN_RXN2: length 11.4
  TOP w0.102: v1(80.67,56.67) 80.9,56.44 80.9,56.16 80.63,55.89 L3.4 ; U20.73 84.82,61.81 84.89,61.73 84.89,60.11 85.55,59.46 85.55,59.04 v1(85.32,58.81)
  IN3 w0.109: v1(80.67,56.67) 80.9,56.9 80.9,57.16 81.19,57.45 84.98,57.45 85.55,58.02 85.55,58.58 v1(85.32,58.81)
USB3_DWN_RXP1: length 29.1
  TOP w0.102: L4.4 101.06,67.29 100.79,67.56 98.83,67.56 v1(98.61,67.34) ; v1(82.96,74.58) 83.19,74.35 83.19,74.17 82.91,73.89 82.91,71.37 82.82,71.29 U20.28
  BOTTOM w0.102: v1(98.61,67.34) 98.83,67.56 99.08,67.56 99.33,67.81 99.33,68.46 94.77,73.03 89.89,73.03 86.72,76.2 83.71,76.2 83.19,75.67 83.19,74.81 v1(82.96,74.58)
USB3_DWN_RXP2: length 11.4
  TOP w0.102: U20.74 85.22,61.81 85.15,61.73 85.15,60.22 85.8,59.56 85.8,59.04 v1(86.03,58.81) ; v1(81.38,56.67) 81.15,56.44 81.15,56.16 81.43,55.89 L3.1
  IN3 w0.109: v1(81.38,56.67) 81.15,56.9 81.15,57.05 81.3,57.2 85.09,57.2 85.8,57.91 85.8,58.58 v1(86.03,58.81)
USB3_DWN_TXN1: length 24.7
  TOP w0.102: U20.24 84.42,71.28 84.35,71.35 84.35,73.25 85.05,73.96 85.05,74.54 v1(85.28,74.77) ; CA74.1 98.46,65.53 98.25,65.53 v1(98.02,65.76)
  BOTTOM w0.102: v1(98.02,65.76) 97.79,65.53 97.39,65.53 97.28,65.64 97.28,69.34 94.49,72.14 89.53,72.14 87.38,74.3 85.16,74.3 85.05,74.4 85.05,74.54 v1(85.28,74.77)
USB3_DWN_TXN2: length 4.5
  TOP w0.102: U20.70 83.62,61.77 83.7,61.69 83.7,59.21 83.19,58.71 83.19,58.46 CA79.1
USB3_DWN_TXP1: length 25.1
  TOP w0.102: U20.25 84.02,71.3 84.1,71.37 84.1,73.36 84.8,74.06 84.8,74.54 v1(84.57,74.77) ; v1(98.02,65.05) 98.25,65.28 98.46,65.28 CA75.1
  BOTTOM w0.102: v1(98.02,65.05) 97.79,65.28 97.28,65.28 97.03,65.53 97.03,69.24 94.38,71.88 89.43,71.88 87.27,74.04 85.05,74.04 84.8,74.29 84.8,74.54 v1(84.57,74.77)
USB3_DWN_TXP2: length 4.5
  TOP w0.102: CA78.1 83.44,58.46 83.44,58.6 83.95,59.11 83.95,61.7 84.02,61.77 U20.71
USB3_RXN1_CON: length 10.6
  TOP w0.102: L4.2 103.26,68.09 103.53,67.82 103.94,67.82 104.32,67.44 104.39,67.44 104.5,67.55 D7.1 D7.10 105.88,67.55 106.01,67.43 107.07,67.43 108.84,69.19 110.44,69.19 110.98,69.74 111.43,69.74 111.53,69.84 CN1.5
USB3_RXN2_CON: length 8.9
  TOP w0.102: L3.3 80.63,53.74 80.9,53.47 80.9,53.23 81.37,52.76 81.37,52.65 81.25,52.53 D8.10 D8.1 81.25,51.24 81.36,51.13 81.36,49.71 79.22,47.57 79.22,47.28 79.12,47.18 CN2.5
USB3_RXP1_CON: length 10.6
  TOP w0.102: L4.3 103.28,67.29 103.56,67.56 103.83,67.56 104.21,67.18 104.39,67.18 104.53,67.05 D7.2 D7.9 105.91,67.05 106.03,67.17 107.18,67.17 108.94,68.94 110.54,68.94 111.09,69.48 111.43,69.48 111.53,69.38 CN1.6
USB3_RXP2_CON: length 8.9
  TOP w0.102: L3.2 81.43,53.74 81.15,53.47 81.15,53.34 81.62,52.87 81.62,52.64 81.75,52.52 D8.9 D8.2 81.75,51.27 81.61,51.13 81.61,49.61 79.47,47.47 79.47,47.28 79.58,47.18 CN2.6
USB3_TXN1_CON: length 10.6
  TOP w0.102: CN1.8 111.53,63.84 111.43,63.74 111.24,63.74 110.41,64.57 108.06,64.57 106.7,65.92 106.03,65.92 105.91,66.05 D7.7 D7.4 104.55,66.05 104.44,65.94 104.17,65.94 103.76,65.53 103.56,65.53 103.28,65.81 L6.2
USB3_TXN2_CON: length 8.9
  TOP w0.102: L5.3 82.91,53.71 83.19,53.44 83.19,53.23 82.85,52.9 82.85,52.68 82.75,52.57 D8.7 D8.4 82.75,51.26 82.87,51.14 82.87,50.25 85.22,47.9 85.22,47.28 85.12,47.18 CN2.8
USB3_TXP1_CON: length 10.6
  TOP w0.102: L6.3 103.31,65 103.58,65.28 103.87,65.28 104.28,65.68 104.42,65.68 104.56,65.55 D7.5 D7.6 105.88,65.55 106.01,65.67 106.59,65.67 107.95,64.31 110.31,64.31 111.14,63.48 111.43,63.48 111.53,63.38 CN1.9
USB3_TXP2_CON: length 8.9
  TOP w0.102: L5.2 83.71,53.71 83.44,53.44 83.44,53.13 83.11,52.8 83.11,52.65 83.25,52.52 D8.6 D8.5 83.25,51.25 83.12,51.13 83.12,50.35 85.47,48 85.47,47.28 85.58,47.18 CN2.9
USB31_RX_DN: length 2.4
  BOTTOM w0.102: RZ143.2 157,182.45 156.9,182.55 156.41,182.55 156.17,182.79 155.87,182.79 155.75,182.67 NGFF1.29
USB31_RX_DP: length 2.4
  BOTTOM w0.102: NGFF1.31 155.77,183.17 155.89,183.05 156.28,183.05 156.52,182.8 156.9,182.8 157,182.91 RZ142.2
USB31_TX_DN: length 2.1
  BOTTOM w0.102: NGFF1.35 155.83,184.17 155.96,184.29 156.94,184.29 CA246.2
USB31_TX_DP: length 2.1
  BOTTOM w0.102: NGFF1.37 155.83,184.67 155.96,184.55 156.85,184.55 CA247.2
USB_AGND: length 7.3
  TOP w0.229: U25.36 80.88,151.49 80.49,151.1 R173.1
  TOP w0.508: R173.1 80.49,149.59 CA49.2 C69.2 77.98,149.57 C71.2 76.42,149.52 FB46.1
USB_EN: length 64.2
  TOP w0.107: RZU35.1 74.6,54.48 v1(74.65,54.43) ; v1(113.74,70.94) 113.74,76.25 114.96,77.47 Q12.D
  IN1 w0.124: v1(74.65,54.43) 76.68,52.4 87.38,52.4 89.92,54.94 103.99,54.94 106.96,57.91 109.12,57.91 113.74,62.53 v1(113.74,70.94)
  BOTTOM w0.107: v1(74.65,54.43) RZ100.1
USB_EN#: length 5.6
  TOP w0.107: Q12.G 121.63,76.82 RB47.1 121.92,76.86 122.58,76.2 123.47,76.2 124.05,75.62 U14.4
USB_EN_R: length 25
  TOP w0.107: v1(92.48,58.52) 92.9,58.94 U22.3
  IN1 w0.124: v1(75.62,54.41) 76.48,53.54 83.44,53.54 88.27,58.37 92.33,58.37 v1(92.48,58.52)
  BOTTOM w0.107: RZ100.2 v1(75.62,54.41) ; RZ100.2 76.4,53.54 76.72,53.22 U23.3 ; RZ100.2 74.63,52.55 RB58.1
USB_GND:
  vias: v1(82.93,184.91) v1(83.57,184.91)
USB_N0: length 2.1
  BOTTOM w0.102: RZ144.2 157,177.85 FL1.2 156.69,177.55 155.96,177.55 155.83,177.67 NGFF1.9
USB_OC0_N: length 16.4
  TOP w0.107: U22.4 95.13,58.94 94.82,59.26 94.82,63.3 96.55,65.02 96.55,69.72 95.83,70.43 RZ74.2
USB_OC1_N: length 26.8
  TOP w0.107: RZ95.2 v1(89.1,59.77) ; RZ103.1 v1(68.4,57.61)
  IN1 w0.124: v1(89.1,59.77) 83.46,54.13 v1(79.76,54.13) 77.39,54.13 75.95,55.58 74.68,55.58 73.03,57.23 68.78,57.23 v1(68.4,57.61)
  BOTTOM w0.107: U23.4 79.98,53.9 v1(79.76,54.13)
USB_P0: length 2.1
  BOTTOM w0.102: NGFF1.7 155.83,177.17 155.96,177.29 156.69,177.29 FL1.3 157,176.99 RZ146.2
USBHUB_PLTRST_N: length 75.6
  TOP w0.107: U89.4 v1(116.73,111.25) ; RZ76.2 v1(73.86,74.12)
  IN1 w0.124: v1(116.73,111.25) 115.97,112.01 90.58,112.01 84.23,105.66 84.23,102.36 79.45,97.59 79.45,83.64 76.72,80.91 76.72,76.31 74.52,74.12 v1(73.86,74.12)
VP10_HUB: length 13.9
  TOP w0.203: U20.67 82.42,61.1 CA41.1 ; CA39.1 88.25,65.74 v1(87.91,65.74) 87.83,65.74 87.82,65.75 U20.8
  TOP w0.229: v1(76.53,66.12) 76.96,66.55 U20.48 ; U20.26 83.62,71.7 v1(83.57,71.75) ; v1(82.5,71.75) 82.5,71.7 82.42,71.63 U20.29 ; v1(76.28,62.43) 76.16,62.55 CA37.1 76.17,62.95 U20.57 ; v1(80.02,71.77) U20.35 ; U20.72 v1(84.42,61.29)
  TOP w0.254: CA36.1 v1(76.53,66.12) ; v1(84.42,61.29) 84.45,61.26 CA40.1
  TOP w0.305: CA38.1 83.69,71.88 v1(83.57,71.75) ; v1(82.5,71.75) 82.55,71.81 CA35.1 ; CA34.1 79.63,72.16 v1(80.02,71.77)
  vias: v1(81.94,60.53) v1(82.52,60.53)
VP10_MEM_A: length 4.5
  TOP w0.229: U20.44 77.27,68.15 76.83,68.58 74.68,68.58 74.08,67.98 C62.1
WDISABLE#1: length 2.6
  BOTTOM w0.107: R213.1 146.71,177.42 NGFF1.8
WDISABLE#2: length 3.6
  BOTTOM w0.107: NGFF1.26 146.33,181.92 R215.1 R216.1
WLAN_EN: length 2.7
  BOTTOM w0.254: U30.8 127.76,141.1 127.41,141.45 RZ167.2 R204.1
XOSCI: length 5
  TOP w0.107: U25.27 76.83,155.85 R176.1 75.37,155.47 C72.1 74.13,155.41 Y1.3
XOSCO: length 8.4
  TOP w0.107: U25.26 76.65,156.25 R176.2 75.5,156.44 C73.1 74.89,156.63 74.68,156.84 74.68,157.86 74.42,158.12 72.39,158.12 72.1,157.82 Y1.1
N16109: length 8.8
  TOP w0.107: RZU7.2 97.05,138.35 97.05,132.44 97.26,132.23 97.26,130.71 97.5,130.46 J1.J51
N19928: length 9.4
  TOP w0.254: R40.2 98.74,100.72 CA61.1 98.74,102.58 98.32,103 Q3.D 96.42,103.89 95.94,104.37 RZ32.1 RZU24.1 94.93,105.65 U9.1
N16629600: length 1.5
  BOTTOM w0.107: R305.2 35.45,31.75 36.2,31.75 36.22,31.72 U43.12
N16629602: length 1.5
  BOTTOM w0.107: U43.13 35.35,32.22 R306.2
N16629604: length 4.7
  BOTTOM w0.107: U43.14 36.11,32.72 35.31,33.53 35.31,35.17 R307.2
N16629606: length 3.9
  BOTTOM w0.107: U43.15 36.25,33.22 35.81,33.66 35.81,35.29 R308.2
N16629666: length 1.5
  BOTTOM w0.107: RA104.2 35.44,29.72 U43.8
N16629668: length 1.5
  TOP w0.107: RA40.2 36.51,27.25 v1(35.94,27.25)
  BOTTOM w0.107: U43.3 36.07,27.22 36.04,27.25 v1(35.94,27.25)
N16629670: length 1.5
  BOTTOM w0.107: RA116.2 35.43,28.72 U43.6
N16629672: length 1.5
  BOTTOM w0.107: U43.5 35.35,28.22 RA128.2
N16629674: length 1.5
  TOP w0.107: v1(35.94,29.22) 35.95,29.21 RA34.2
  BOTTOM w0.107: v1(35.94,29.22) U43.7
N16629676: length 1.6
  BOTTOM w0.107: RA98.2 35.56,30.48 35.81,30.22 U43.9
N16629678: length 1.5
  TOP w0.107: v1(35.94,26.62) 36.02,26.54 RA46.2
  BOTTOM w0.107: v1(35.94,26.62) 35.99,26.67 36.07,26.67 36.12,26.72 U43.2
N16629694: length 2
  BOTTOM w0.107: U43.63 38.08,24.87 37.21,24 RA156.1
N16629698: length 1.9
  BOTTOM w0.107: RA154.1 38.48,24 39.08,24.6 U43.61
N16629702: length 2
  BOTTOM w0.107: RA155.1 37.85,24 38.58,24.73 U43.62
N16629706: length 1.8
  BOTTOM w0.107: U43.60 39.58,24.46 39.12,24 RA153.1
N16629714: length 2.1
  BOTTOM w0.107: R301.1 37.34,35.81 38.08,35.08 U43.18
N16629874: length 1.3
  TOP w0.107: U44.3 33.91,37.7 RA20.1
N16629908: length 2.6
  TOP w0.107: v1(43.66,35.38) 43.66,35 43.94,34.72 R304.1
  BOTTOM w0.107: U43.29 43.58,35.3 v1(43.66,35.38) 43.69,35.41 R303.1
N16629916: length 1.5
  BOTTOM w0.107: RA115.2 47.25,28.72 U43.43
N16629918: length 1.7
  BOTTOM w0.107: U43.44 46.37,28.22 46.57,28.42 47.13,28.42 RA127.2
N16629942: length 5.2
  BOTTOM w0.203: RB15.2 R309.1 49.16,26.44 C182.1 49.57,25.62 50.16,25.02 50.16,23.53 49.96,23.33 X3.3
N16629964: length 2
  BOTTOM w0.107: U43.19 38.58,35.21 37.97,35.81 R302.1
N16629966: length 1.4
  TOP w0.107: RA25.1 34.41,32.33 U44.7
N16629970: length 1.6
  BOTTOM w0.107: U43.4 35.43,27.72 35.32,27.62 R300.1
N16633178: length 1.5
  BOTTOM w0.107: U45.12 54.51,31.72 54.48,31.75 53.73,31.75 R329.2
N16633180: length 1.5
  BOTTOM w0.107: R330.2 53.64,32.22 U45.13
N16633182: length 4.7
  BOTTOM w0.107: R331.2 53.59,35.17 53.59,33.53 54.4,32.72 U45.14
N16633184: length 3.9
  BOTTOM w0.107: R332.2 54.1,35.29 54.1,33.66 54.54,33.22 U45.15
N16633272: length 2
  BOTTOM w0.107: RA152.1 55.5,24 56.36,24.87 U45.63
N16633276: length 1.9
  BOTTOM w0.107: U45.61 57.36,24.6 56.77,24 RA150.1
N16633280: length 2
  BOTTOM w0.107: RA151.1 56.13,24 56.86,24.73 U45.62
N16633284: length 1.8
  BOTTOM w0.107: RA149.1 57.4,24 57.86,24.46 U45.60
N16633292: length 2.1
  BOTTOM w0.107: R325.1 55.63,35.81 56.36,35.08 U45.18
N16633452: length 1.3
  TOP w0.107: RA21.1 52.2,37.7 U46.3
N16633486: length 2.6
  TOP w0.107: R328.1 62.23,34.72 61.95,35 v1(61.95,35.38)
  BOTTOM w0.107: U45.29 61.86,35.3 v1(61.95,35.38) 61.98,35.41 R327.1
N16633520: length 5.2
  BOTTOM w0.203: X4.3 68.25,23.33 68.45,23.53 68.45,25.02 67.86,25.62 C191.1 67.45,26.44 R334.1 RB16.2
N16633542: length 2
  BOTTOM w0.107: U45.19 56.86,35.21 56.26,35.81 R326.1
N16633544: length 1.4
  TOP w0.107: RA26.1 52.7,32.33 U46.7
N16633548: length 1.6
  BOTTOM w0.107: U45.4 53.71,27.72 53.61,27.62 R324.1
N16636756: length 1.5
  BOTTOM w0.107: U47.12 72.8,31.72 72.77,31.75 72.26,31.75 72.14,31.62 R353.2
N16636758: length 1.5
  BOTTOM w0.107: U47.13 72.39,32.22 72.35,32.26 R354.2 71.93,32.22
N16636760: length 4.7
  BOTTOM w0.107: U47.14 72.69,32.72 71.88,33.53 71.88,35.17 R355.2
N16636762: length 3.9
  BOTTOM w0.107: R357.2 72.39,35.29 72.39,33.66 72.82,33.22 U47.15
N16636850: length 2
  BOTTOM w0.107: RA148.1 73.79,24 74.65,24.87 U47.63
N16636854: length 1.9
  BOTTOM w0.107: U47.61 75.65,24.6 75.06,24 RA146.1
N16636858: length 2
  BOTTOM w0.107: RA147.1 74.42,24 75.15,24.73 U47.62
N16636862: length 1.8
  BOTTOM w0.107: RA145.1 75.69,24 76.15,24.46 U47.60
N16636870: length 2.1
  BOTTOM w0.107: U47.18 74.65,35.08 73.91,35.81 R349.1
N16637030: length 1.8
  TOP w0.107: U48.3 70.49,37.84 70.35,37.99 RA18.1
N16637064: length 2.6
  TOP w0.107: R352.1 80.52,35.1 v1(80.24,35.38)
  BOTTOM w0.107: U47.29 80.15,35.3 v1(80.24,35.38) 80.26,35.41 R351.1
N16637098: length 5.2
  BOTTOM w0.203: RB17.2 R358.1 85.74,26.44 C200.1 86.14,25.62 86.74,25.02 86.74,23.53 86.54,23.33 X5.3
N16637120: length 2
  BOTTOM w0.107: R350.1 74.55,35.81 75.15,35.21 U47.19
N16637122: length 1.4
  TOP w0.107: 70.99,32.33 RA27.1 71.03,32.6 70.99,32.64 U48.7
N16637126: length 1.9
  BOTTOM w0.107: R348.1 71.68,27.72 v1(72.47,27.72) U47.4
N16640334: length 1.5
  BOTTOM w0.107: R377.2 90.42,31.62 90.55,31.75 91.06,31.75 91.09,31.72 U49.12
N16640336: length 1.5
  BOTTOM w0.107: U49.13 90.68,32.22 90.64,32.26 R378.2 90.22,32.22
N16640338: length 4.7
  BOTTOM w0.107: U49.14 90.98,32.72 90.17,33.53 90.17,35.17 R379.2
N16640340: length 3.9
  BOTTOM w0.107: U49.15 91.11,33.22 90.68,33.66 90.68,35.29 R380.2
N16640428: length 2
  BOTTOM w0.107: RA144.1 92.08,24 92.94,24.87 U49.63
N16640432: length 1.9
  BOTTOM w0.107: U49.61 93.94,24.6 93.34,24 RA142.1
N16640436: length 2
  BOTTOM w0.107: U49.62 93.44,24.73 92.71,24 RA143.1
N16640440: length 1.8
  BOTTOM w0.107: RA141.1 93.98,24 94.44,24.46 U49.60
N16640448: length 2.1
  BOTTOM w0.107: U49.18 92.94,35.08 92.2,35.81 R373.1
N16640608: length 1.3
  TOP w0.107: U50.3 88.78,37.34 88.76,37.35 RA22.1
N16640642: length 2.6
  TOP w0.107: v1(98.53,35.38) 98.81,35.1 R376.1
  BOTTOM w0.107: R375.1 98.55,35.41 v1(98.53,35.38) 98.44,35.3 U49.29
N16640676: length 5.2
  BOTTOM w0.203: RB18.2 R382.1 104.03,26.44 C209.1 104.43,25.62 105.03,25.02 105.03,23.57 104.83,23.37 104.37,23.37 X6.3
N16640698: length 2
  BOTTOM w0.107: R374.1 92.84,35.81 93.44,35.21 U49.19
N16640700: length 1.4
  TOP w0.107: RA28.1 89.28,32.33 U50.7
N16640704: length 1.6
  BOTTOM w0.107: U49.4 90.55,27.72 90.39,27.56 R372.1 90.18,27.62
N16643912: length 1.5
  BOTTOM w0.107: U51.12 109.38,31.72 109.35,31.75 108.84,31.75 108.71,31.62 R401.2
N16643914: length 1.5
  BOTTOM w0.107: U51.13 108.84,32.22 108.8,32.26 R402.2 108.51,32.22
N16643916: length 4.7
  BOTTOM w0.107: R403.2 108.46,35.17 108.46,33.53 109.26,32.72 U51.14
N16643918: length 3.9
  BOTTOM w0.107: R404.2 108.97,35.29 108.97,33.66 109.4,33.22 U51.15
N16644006: length 2
  BOTTOM w0.107: U51.63 111.23,24.87 110.36,24 RA140.1
N16644010: length 1.9
  BOTTOM w0.107: RA138.1 111.63,24 112.23,24.6 U51.61
N16644014: length 2
  BOTTOM w0.107: RA139.1 111,24 111.73,24.73 U51.62
N16644018: length 1.8
  BOTTOM w0.107: U51.60 112.73,24.46 112.27,24 RA137.1
N16644026: length 2.1
  BOTTOM w0.107: U51.18 111.23,35.08 110.49,35.81 R397.1
N16644186: length 1.6
  TOP w0.107: U52.3 107.07,37.7 RA19.1
N16644220: length 2.6
  TOP w0.107: R400.1 117.09,34.72 116.81,35 v1(116.81,35.38)
  BOTTOM w0.107: R398.1 116.84,35.41 v1(116.81,35.38) 116.73,35.3 U51.29
N16644254: length 5.2
  BOTTOM w0.203: X7.3 123.11,23.33 123.32,23.53 123.32,25.02 122.72,25.62 C218.1 122.31,26.44 R406.1 RB19.2
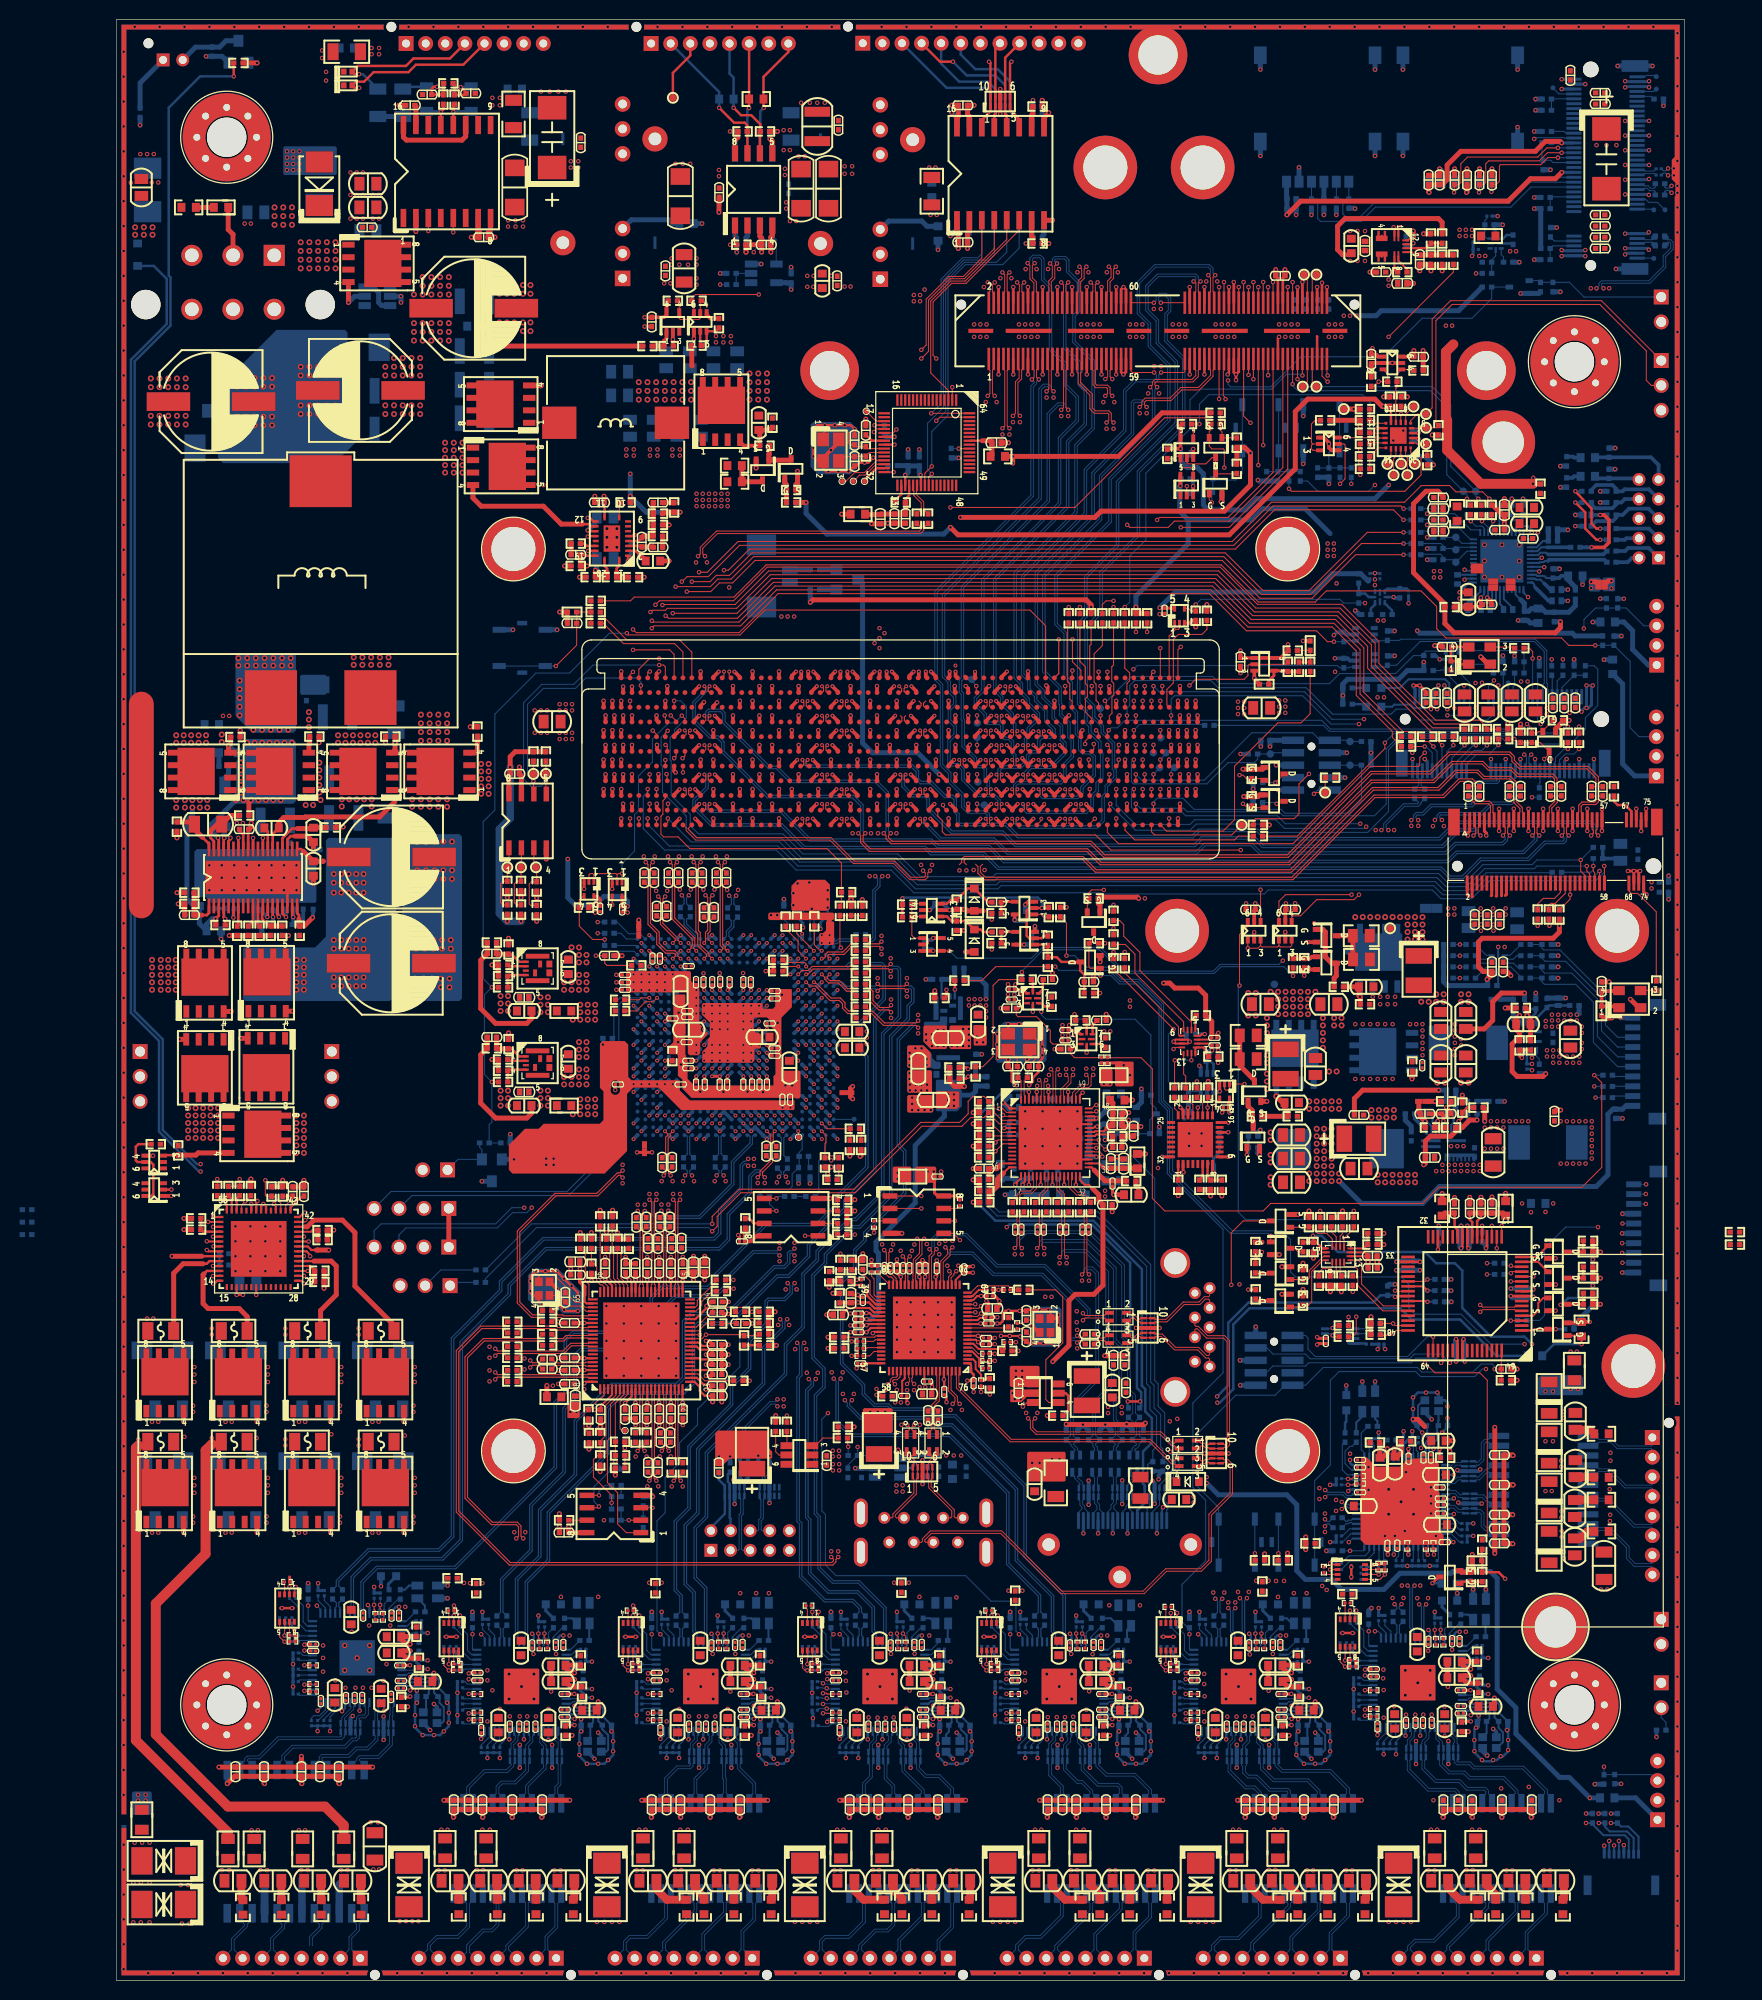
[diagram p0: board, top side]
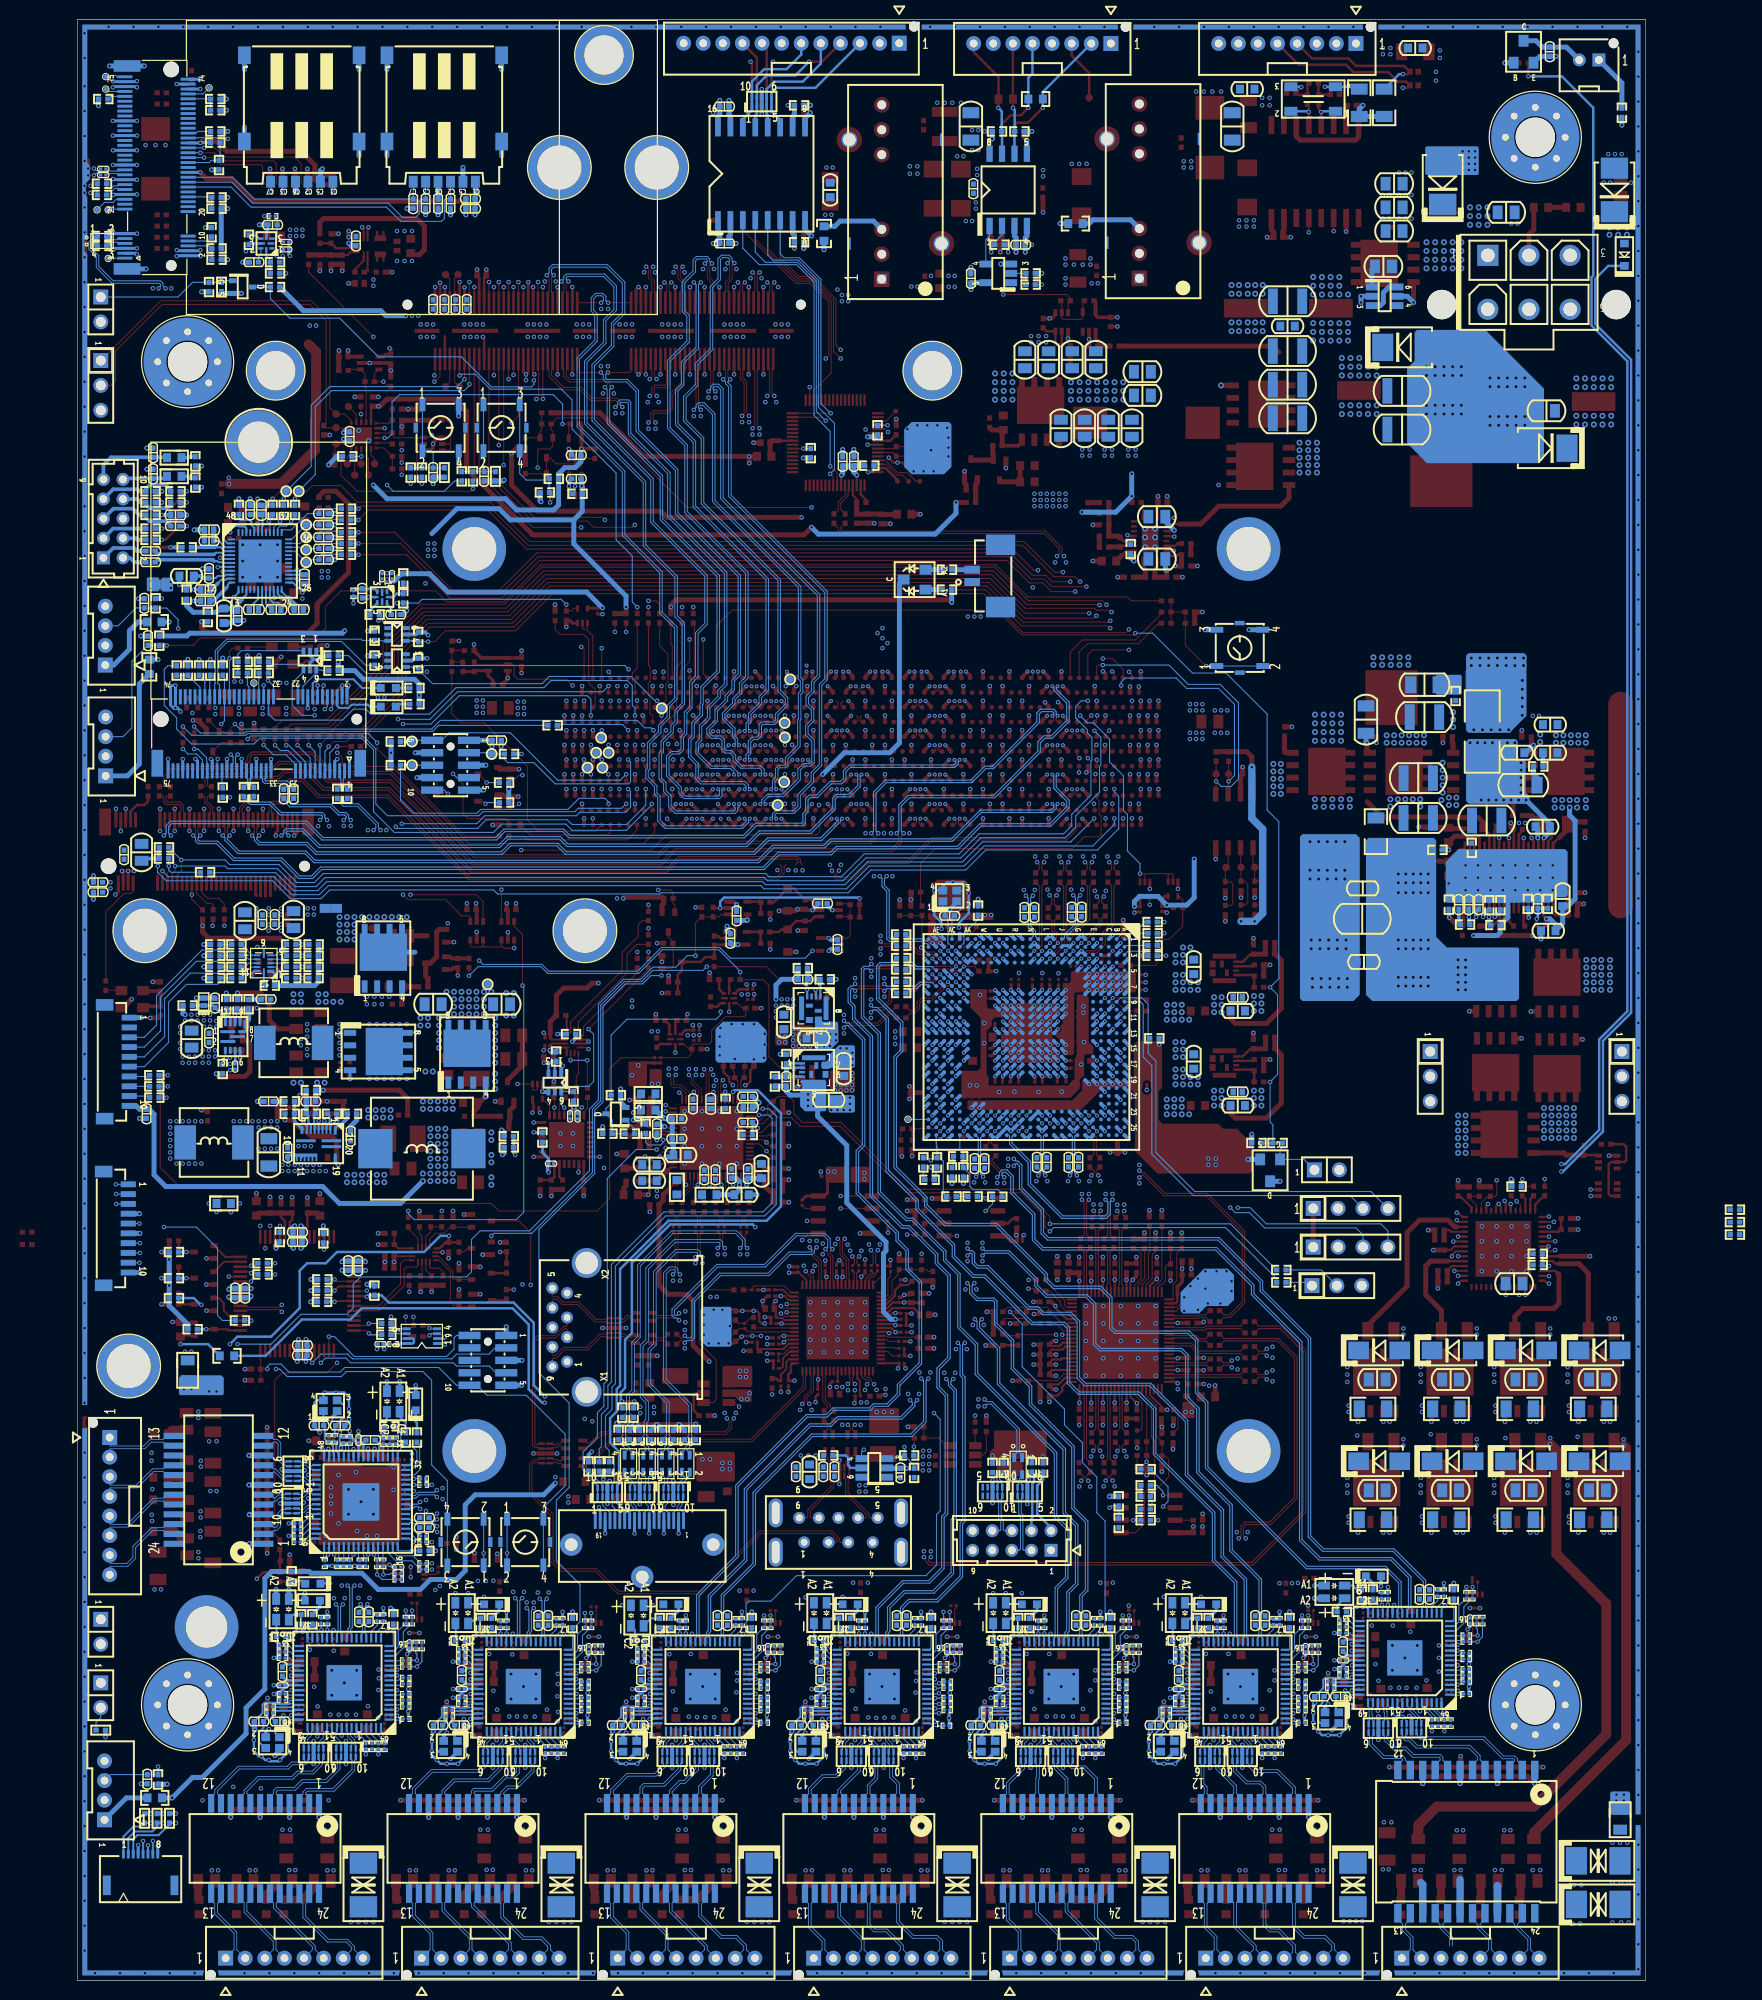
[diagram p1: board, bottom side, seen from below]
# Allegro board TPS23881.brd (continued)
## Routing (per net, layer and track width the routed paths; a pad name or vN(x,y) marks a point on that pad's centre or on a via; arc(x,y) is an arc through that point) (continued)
N16644276: length 2
  BOTTOM w0.107: U51.19 111.73,35.21 111.12,35.81 R399.1
N16644278: length 1.4
  TOP w0.107: 107.56,32.33 RA29.1 107.61,32.72 107.56,32.77 U52.7
N16644282: length 1.5
  BOTTOM w0.107: U51.4 108.84,27.72 108.68,27.56 R396.1
N16647490: length 1.5
  BOTTOM w0.107: R425.2 126.89,32.13 127.64,32.13 127.66,32.1 U53.12
N16647492: length 1.5
  BOTTOM w0.107: U53.13 126.79,32.6 R426.2
N16647494: length 4.7
  BOTTOM w0.107: U53.14 127.55,33.1 126.75,33.91 126.75,35.55 R427.2
N16647496: length 3.9
  BOTTOM w0.107: U53.15 127.69,33.6 127.25,34.04 127.25,35.67 R428.2
N16647584: length 2
  BOTTOM w0.107: U53.63 129.52,25.25 128.65,24.38 RA136.1
N16647588: length 1.9
  BOTTOM w0.107: RA134.1 129.92,24.38 130.52,24.98 U53.61
N16647592: length 2
  BOTTOM w0.107: RA135.1 129.29,24.38 130.02,25.11 U53.62
N16647596: length 1.8
  BOTTOM w0.107: U53.60 131.02,24.84 130.56,24.38 RA133.1
N16647604: length 2.1
  BOTTOM w0.107: U53.18 129.52,35.46 128.78,36.2 R421.1
N16647764: length 1.7
  TOP w0.107: U54.3 125.35,38.46 RA17.1
N16647798: length 2.6
  TOP w0.107: v1(135.1,35.76) 135.1,35.38 135.38,35.1 R424.1
  BOTTOM w0.107: U53.29 135.02,35.68 v1(135.1,35.76) 135.13,35.79 R423.1
N16647832: length 4.9
  BOTTOM w0.203: X8.3 140.86,23.71 141.45,24.31 141.45,25.31 141.01,25.75 C227.1 140.6,26.82 R430.1 RB20.2
N16647854: length 2
  BOTTOM w0.107: R422.1 129.41,36.2 130.02,35.59 U53.19
N16647856: length 1.4
  TOP w0.107: U54.7 125.85,32.71 RA24.1
N16647860: length 1.6
  BOTTOM w0.107: U53.4 126.87,28.1 126.76,28 R420.1
N16651068: length 1.5
  BOTTOM w0.107: U55.12 129.31,43.72 129.29,43.69 129.29,42.94 R449.2
N16651070: length 1.5
  BOTTOM w0.107: U55.13 128.81,42.85 R450.2
N16651072: length 4.7
  BOTTOM w0.107: R451.2 125.87,42.8 127.51,42.8 128.31,43.6 U55.14
N16651074: length 3.9
  BOTTOM w0.107: U55.15 127.81,43.74 127.38,43.31 125.74,43.31 R452.2
N16651162: length 2
  BOTTOM w0.107: RA61.1 137.03,44.7 136.17,45.57 U55.63
N16651166: length 1.9
  BOTTOM w0.107: U55.61 136.44,46.57 137.03,45.97 RA59.1
N16651170: length 2
  BOTTOM w0.107: RA60.1 137.03,45.34 136.3,46.07 U55.62
N16651174: length 1.8
  BOTTOM w0.107: U55.60 136.57,47.07 137.03,46.61 RA58.1
N16651182: length 1.9
  BOTTOM w0.107: U55.18 125.96,45.57 125.09,44.7 R445.1
N16651342: length 1.5
  TOP w0.107: RA15.1 123.41,41.41 U56.3
N16651376: length 2.6
  TOP w0.107: v1(125.65,51.16) 126.03,51.16 126.31,51.44 R448.1
  BOTTOM w0.107: U55.29 125.74,51.07 v1(125.65,51.16) 125.63,51.18 R446.1
N16651410: length 5.1
  BOTTOM w0.203: X9.3 133.34,59.17 132.79,58.62 132.79,57.48 133.64,56.63 C236.1 133.73,56.5 RB21.2 R453.1
N16651432: length 1.8
  BOTTOM w0.107: R447.1 125.09,45.34 125.82,46.07 U55.19
N16651434: length 1.4
  TOP w0.107: U56.7 128.71,41.91 RA14.1
N16651438: length 1.6
  BOTTOM w0.107: U55.4 133.31,42.92 133.42,42.81 R444.1
N16705548: length 14.1
  TOP w0.254: U92.19 47.85,145.32 47.75,145.41 CA53.2
  TOP w0.508: CA53.2 47.35,145.4 R727.2 v1(48.01,144.27)
  IN3 w0.508: v1(43.56,152.53) 44.96,151.13 44.96,146.3 46.99,144.27 v1(48.01,144.27)
N16706602: length 15
  TOP w0.254: U92.13 48.43,148.32 48.21,148.54 47.55,148.54
  TOP w0.508: 47.55,148.54 45.39,148.54 43.56,150.37 37.21,150.37 36.37,151.21 Q44.4
N16715221: length 7.9
  TOP w0.279: U83.36 10.44,116.46 v1(10.36,116.54)
  TOP w0.508: v2(13.72,120.4) 13.51,120.19 R737.1
  BOTTOM w0.508: v2(12.19,120.4) 9.75,117.96 C472.1 9.75,117.14 v1(10.36,116.54)
  vias: v2(12.7,124.21) v2(12.7,123.44) v2(12.7,122.68) v2(12.7,121.92) v2(12.7,121.16) v2(12.95,120.4) v2(13.34,126.24) v2(14.1,126.24) v2(14.48,120.4) v2(14.86,126.24) v2(15.24,120.4) v2(15.62,126.24) v2(16,120.4) v2(16.38,126.24) v2(16.76,120.4) v2(17.14,126.24) v2(17.91,126.24)
N16715269: length 17.6
  TOP w0.508: R738.1 v1(6.17,116.54)
  IN3 w0.508: v1(6.17,116.54) 6.17,116.66 8.08,118.57 10.24,118.57 11,119.33 11,124.08 12.34,125.43 12.34,126.57 11.76,127.15 11.76,127.91 12.57,128.73 v2(12.57,129.03)
  vias: v2(12.45,134.87) v2(12.45,134.11) v2(12.57,132.59) v2(12.57,131.7) v2(12.57,130.81) v2(12.57,129.92) v2(13.34,134.87) v2(13.34,134.11) v2(13.97,127.56) v2(14.22,134.87) v2(14.22,134.11) v2(14.86,127.56) v2(15.11,134.87) v2(15.11,134.11) v2(15.75,127.56) v2(16,134.87) v2(16,134.11) v2(16.64,127.56) v2(16.89,134.87) v2(16.89,134.11) v2(17.53,127.56) v2(17.78,134.87) v2(17.78,134.11)
N16715333: length 13.9
  TOP w0.279: v1(11.63,116.54) 11.63,116.41 11.44,116.21 U83.34
  TOP w0.508: R735.1 v1(12.62,127.51)
  IN1 w0.508: v1(12.62,127.51) 12.34,127.23 12.34,125.35 10.92,123.93 10.92,118.52 11.63,117.81 v1(11.63,116.54)
N16715396: length 15.9
  TOP w0.107: 19.08,118.49 19.2,118.62
  TOP w0.279: U83.25 15.94,116.93 C473.1
  TOP w0.508: C473.1 16.56,118.11 17.07,118.62 19.2,118.62 19.25,118.67 26.85,118.67 28.4,120.22
  vias: v2(24.21,134.95) v2(24.21,134.19) v2(25.1,134.95) v2(25.1,134.19) v2(25.98,134.95) v2(25.98,134.19) v2(26.87,134.95) v2(26.87,134.19) v2(27.76,134.95) v2(27.76,134.19) v2(30.18,120.47) v2(30.18,119.71) v2(31.06,129.11) v2(31.06,128.22) v2(31.06,127.33) v2(31.06,126.44) v2(31.06,120.47) v2(31.06,119.71) v2(31.95,129.11) v2(31.95,128.22) v2(31.95,127.33) v2(31.95,126.44) v2(31.95,120.47) v2(31.95,119.71) v2(32.84,129.11) v2(32.84,128.22) v2(32.84,127.33) v2(32.84,126.44) v2(32.84,120.47) v2(32.84,119.71) v2(33.73,129.11) v2(33.73,128.22) v2(33.73,127.33) v2(33.73,126.44) v2(33.73,120.47) v2(33.73,119.71)
N16716334: length 3
  TOP w0.508: v1(23.14,117.65) 22.4,117.65 RZ24.1
  IN1 w0.508: v1(23.14,117.65) 22.99,117.81 v2(22.99,119.74)
  vias: v2(22.61,127) v2(22.61,126.24) v2(22.99,120.47) v2(23.37,127) v2(23.37,126.24) v2(23.75,120.47) v2(24.13,127) v2(24.13,126.24) v2(24.51,120.47) v2(24.89,127) v2(24.89,126.24) v2(25.27,120.47) v2(25.65,127) v2(25.65,126.24) v2(26.04,120.47) v2(26.04,119.74) v2(26.42,127) v2(26.42,126.24)
N16716474: length 2.4
  TOP w0.279: U83.35 10.94,116.47 v1(11,116.54)
  BOTTOM w0.508: v1(11,116.54) 11,117.45 C472.2
N16716845: length 5
  TOP w0.279: U83.38 9.44,115.94 8.78,116.6
  TOP w0.508: R738.2 7.72,118.16 C470.1 7.95,117.42 8.78,116.6
N16716849: length 5.6
  TOP w0.279: 9.6,116.92 9.6,116.54 9.94,116.2 U83.37
  TOP w0.508: 9.6,116.92 9.6,117.25 10.28,117.93 C470.2 11.63,118.82 R737.2
N16717006: length 3
  TOP w0.508: Q45.4 11.43,125.43 v1(11.43,125.98) 11.63,126.19 11.63,126.8 R735.2
  BOTTOM w0.508: v1(11.43,125.98) 12.19,125.22 C919.2
N16717017: length 2.8
  TOP w0.508: R739.2 v1(28.42,126.19) 28.42,125.5 Q46.4
  BOTTOM w0.508: C467.1 28.52,126.29 v1(28.42,126.19)
N16717021: length 22.3
  TOP w0.279: U83.27 v1(14.94,116.54)
  TOP w0.508: R739.1 v1(27.46,126.24)
  IN1 w0.508: v1(14.94,116.54) 20.65,116.54 20.75,116.64 24.64,116.64 27.46,119.46 v1(27.46,126.24)
N16717190: length 2.4
  TOP w0.508: Q48.4 36.83,125.27 R749.1
N16717194: length 36.1
  TOP w0.279: U83.29 v1(13.94,116.54)
  TOP w0.508: R749.2 v1(36.09,127.86)
  IN1 w0.508: v1(36.09,127.86) 35.38,127.15 35.38,118.82 34.87,118.31 30.18,118.31 26.16,114.3 19.46,114.3 18.95,114.81 14.5,114.81 13.94,115.37 v1(13.94,116.54)
N16717547: length 1.7
  TOP w0.508: Q47.4 19.63,126.11 19.71,126.19 R744.1
N16717551: length 16.9
  TOP w0.279: U83.32 v1(12.44,116.54)
  TOP w0.508: R744.2 v1(20.68,126.24)
  IN1 w0.508: v1(20.68,126.24) 19.81,126.24 18.03,124.46 18.03,119.51 17.27,118.75 15.75,118.75 14.3,117.3 13.2,117.3 v1(12.44,116.54)
N16717863: length 2.3
  TOP w0.279: C473.2 15.44,117.2 U83.26
N16719242: length 6
  TOP w0.279: U83.23 16.94,116.5 17.92,117.49 18.44,117.49
  TOP w0.508: 18.44,117.49 20,117.49 C918.2 20.12,117.6 RZ24.2
N16719249: length 5.5
  TOP w0.279: U83.22 17.44,116.37 17.78,116.71 18.19,116.71
  TOP w0.508: v1(20.09,115.32) C918.1 19.48,116.71 18.19,116.71
  BOTTOM w0.508: RZ26.2 v1(20.09,115.32)
N16719556: length 4.7
  TOP w0.279: 18.62,108.28 18.62,108.66 18.44,108.84 U83.19
  TOP w0.508: v1(20.02,108.41) 19.15,107.54 R731.1 18.62,107.62 18.62,108.28
  BOTTOM w0.381: R733.2 20.07,108.46 v1(20.02,108.41)
N16830344: length 4.4
  TOP w0.508: RZ118.2 126.9,100.3 v1(126.87,100.33) 126.77,100.43 C419.2 RZ49.1
  BOTTOM w0.508: Q40.4 v1(126.87,100.33)
N16830441: length 7.5
  TOP w0.508: RZ49.2 124.23,102.23 124.46,102.46 Q42.D 123.98,103.76 123.34,104.39 123.34,106.93 123.07,107.2 Q41.G
N16830443: length 4.1
  TOP w0.508: R704.2 126.14,104.17 R703.2 Q41.D
N16830501: length 2.5
  TOP w0.381: RZ45.2 RZ121.2 121.79,104.24 121.96,104.41 Q42.G
N16831259: length 4.2
  BOTTOM w0.229: R711.1 84.19,102.02 U78.1
  BOTTOM w0.508: R705.2 85.51,103.24 C424.2 R711.1
N16831562: length 3.1
  TOP w0.254: 51.03,143.64 51.03,144.02 51.3,144.29 U92.1
  TOP w0.508: R718.2 R719.1 51.03,143.64
N16831739: length 5
  TOP w0.254: 50.06,143.64 50.06,144 49.8,144.27 U92.20
  TOP w0.508: v1(48.87,143.84) R720.2 R719.2 50.06,143.64
  BOTTOM w0.508: v1(48.87,143.84) 49,143.97 C436.1
N16832049: length 1.4
  TOP w0.254: U92.2 v1(52.2,144.78)
  BOTTOM w0.508: v1(52.2,144.78) 52.53,145.11 R723.2
N16832178: length 2.2
  TOP w0.254: 53.42,145.36 52.96,145.82 U92.3
  TOP w0.508: C444.1 53.42,145.36
N16832533: length 2.6
  TOP w0.254: U92.4 53.49,146.32 C446.1
  TOP w0.508: C441.1 54.74,146.22 C446.1
N16832601: length 1.1
  TOP w0.508: R725.2 55.73,146.19 C441.2
N16833149: length 1.2
  TOP w0.508: C440.1 55.74,150.72 R721.1
N16833152: length 6.2
  TOP w0.254: C446.2 53.26,146.82 U92.5
  TOP w0.508: C446.2 53.76,147.32 R725.1 R726.2 R722.1 54.76,150.74 C440.2
N16834080: length 1.7
  TOP w0.254: R724.2 47.75,146.56 47.99,146.32 U92.17
N16834083: length 1.1
  TOP w0.508: CA53.1 46.39,146.55 R724.1
N16834553: length 1.5
  TOP w0.107: v1(54.23,26.62) 54.31,26.54 RA47.2
  BOTTOM w0.107: v1(54.23,26.62) 54.28,26.67 54.36,26.67 54.41,26.72 U45.2
N16834556: length 1.5
  TOP w0.107: v1(54.23,27.25) 54.79,27.25 RA41.2
  BOTTOM w0.107: v1(54.23,27.25) 54.33,27.25 54.36,27.22 U45.3
N16834559: length 1.5
  BOTTOM w0.107: U45.6 53.71,28.72 RA114.2
N16834562: length 1.5
  BOTTOM w0.107: U45.5 53.63,28.22 RA126.2
N16834578: length 1.5
  TOP w0.107: v1(54.23,29.22) 54.24,29.21 RA35.2
  BOTTOM w0.107: v1(54.23,29.22) U45.7
N16834580: length 1.6
  BOTTOM w0.107: U45.9 54.1,30.22 53.84,30.48 RA97.2
N16834582: length 1.5
  BOTTOM w0.107: U45.8 53.73,29.72 RA103.2
N16834584: length 1.5
  BOTTOM w0.107: U45.43 65.54,28.72 RA113.2
N16834593: length 1.7
  BOTTOM w0.107: RA125.2 65.42,28.42 64.85,28.42 64.66,28.22 U45.44
N16835211: length 13.3
  TOP w0.254: C457.2 49.8,150.7 U92.11
  TOP w0.508: C457.2 v1(49.75,151.38) ; R727.1 v1(45.72,144.27)
  IN1 w0.508: v1(45.72,144.27) 45.72,149.48 46.48,150.24 49.28,150.24 49.75,150.71 v1(49.75,151.38)
N16835305: length 2.6
  TOP w0.254: v1(48.08,147.9) 48.17,147.82 U92.14
  BOTTOM w0.508: C458.1 49,148.82 v1(48.08,147.9)
N16836271: length 24.9
  TOP w0.254: U92.18 v1(48.13,145.82)
  TOP w0.508: Q43.4 v2(43.31,162.69)
  IN3 w0.508: v1(48.13,145.82) 47.83,145.82 47.32,146.32 47.32,151.33 48.72,152.73 48.72,162 48.03,162.69 v2(43.31,162.69)
N16840068: length 1.5
  TOP w0.107: v1(90.81,26.62) 90.88,26.54 RA49.2
  BOTTOM w0.107: v1(90.81,26.62) 90.91,26.72 U49.2
N16840070: length 1.6
  TOP w0.107: v1(90.81,27.25) 90.86,27.3 RA43.2
  BOTTOM w0.107: U49.3 90.83,27.22 v1(90.81,27.25) 90.91,27.25
N16840072: length 1.5
  BOTTOM w0.107: RA110.2 90.44,28.83 90.55,28.72 U49.6
N16840074: length 1.5
  BOTTOM w0.107: RA122.2 90.21,28.22 U49.5
N16840076: length 1.5
  TOP w0.107: RA37.2 90.82,29.21 v1(90.81,29.22)
  BOTTOM w0.107: v1(90.81,29.22) U49.7
N16840078: length 1.6
  BOTTOM w0.107: RA95.2 90.42,30.48 90.68,30.22 U49.9
N16840080: length 1.5
  BOTTOM w0.107: RA101.2 90.43,29.84 90.55,29.72 U49.8
N16840082: length 1.5
  BOTTOM w0.107: U49.43 101.73,28.72 101.83,28.83 RA109.2
N16840084: length 1.7
  BOTTOM w0.107: U49.44 101.12,28.22 101.32,28.42 102,28.42 RA121.2
N16841727: length 1.5
  TOP w0.107: RA50.2 109.17,26.54 v1(109.09,26.62)
  BOTTOM w0.107: U51.2 109.2,26.72 v1(109.09,26.62)
N16841729: length 1.6
  TOP w0.107: RA44.2 109.66,27.25 v1(109.09,27.25)
  BOTTOM w0.107: 109.19,27.25 v1(109.09,27.25) 109.12,27.22 U51.3
N16841731: length 1.5
  BOTTOM w0.107: U51.6 108.97,28.72 108.86,28.83 RA108.2
N16841733: length 1.5
  BOTTOM w0.107: U51.5 108.97,28.22 108.94,28.19 RA120.2 108.5,28.22
N16841735: length 1.5
  TOP w0.107: RA38.2 109.1,29.21 v1(109.09,29.22)
  BOTTOM w0.107: v1(109.09,29.22) U51.7
N16841737: length 1.6
  BOTTOM w0.107: U51.9 108.97,30.22 108.71,30.48 RA94.2
N16841739: length 1.5
  BOTTOM w0.107: RA100.2 108.84,29.84 108.97,29.72 U51.8
N16841741: length 1.5
  BOTTOM w0.107: U51.43 120.4,28.72 RA107.2
N16841743: length 1.7
  BOTTOM w0.107: RA119.2 120.29,28.42 119.6,28.42 119.41,28.22 U51.44
N16843394: length 1.5
  TOP w0.107: RA45.2 127.46,26.92 v1(127.38,27)
  BOTTOM w0.107: v1(127.38,27) 127.43,27.05 127.51,27.05 127.56,27.1 U53.2
N16843396: length 1.5
  TOP w0.107: RA39.2 127.95,27.63 v1(127.38,27.63)
  BOTTOM w0.107: v1(127.38,27.63) 127.48,27.63 127.51,27.6 U53.3
N16843398: length 1.5
  BOTTOM w0.107: U53.6 126.87,29.1 RA106.2
N16843400: length 1.5
  BOTTOM w0.107: RA118.2 126.79,28.6 U53.5
N16843402: length 1.5
  TOP w0.107: RA32.2 127.39,29.59 v1(127.38,29.6)
  BOTTOM w0.107: v1(127.38,29.6) U53.7
N16843404: length 1.6
  BOTTOM w0.107: U53.9 127.25,30.6 127,30.86 RA93.2
N16843406: length 1.5
  BOTTOM w0.107: U53.8 126.88,30.1 RA99.2
N16843408: length 1.5
  BOTTOM w0.107: U53.43 138.69,29.1 RA105.2
N16843410: length 1.7
  BOTTOM w0.107: RA117.2 138.57,28.8 138.01,28.8 137.81,28.6 U53.44
N16845078: length 1.5
  TOP w0.107: RA13.2 134.37,43.48 v1(134.42,43.43)
  BOTTOM w0.107: U55.2 134.31,43.61 134.37,43.56 134.37,43.48 v1(134.42,43.43)
N16845083: length 1.5
  TOP w0.107: RA12.2 133.6,43.62 v1(133.79,43.43)
  BOTTOM w0.107: U55.3 133.81,43.56 133.79,43.54 v1(133.79,43.43)
N16845085: length 1.5
  BOTTOM w0.107: U55.6 132.31,42.92 RA63.2
N16845087: length 1.5
  BOTTOM w0.107: RA62.2 132.81,42.84 U55.5
N16845090: length 1.5
  TOP w0.107: RA11.2 131.7,43.55 v1(131.81,43.43)
  BOTTOM w0.107: v1(131.81,43.43) U55.7
N16845094: length 1.6
  BOTTOM w0.107: RA65.2 130.56,43.05 130.81,43.31 U55.9
N16845096: length 1.5
  BOTTOM w0.107: U55.8 131.31,42.93 RA64.2
N16845099: length 1.5
  BOTTOM w0.107: RA54.2 132.31,54.74 U55.43
N16845103: length 1.7
  BOTTOM w0.107: U55.44 132.81,53.86 132.62,54.06 132.62,54.63 RA53.2
N16849261: length 2.1
  TOP w0.279: R741.2 14.44,107.71 U83.11
N16849480: length 2.1
  TOP w0.279: RB29.1 12.44,107.66 U83.7
N16849547: length 2.3
  TOP w0.279: RZ31.2 13.94,108.02 U83.10
N16849713: length 2.2
  TOP w0.279: v1(16.57,108.47) 16.57,108.57 16.44,108.71 U83.15
  BOTTOM w0.381: R753.2 16.05,109.19 16.57,108.67 v1(16.57,108.47)
N16849718: length 2
  TOP w0.279: v1(15.98,108.46) 15.94,108.5 U83.14
  BOTTOM w0.381: v1(15.98,108.46) 15.98,107.82 R752.2
N16849723: length 2.1
  TOP w0.279: U83.13 15.44,108.5 v1(15.39,108.46)
  BOTTOM w0.381: v1(15.39,108.46) 14.81,109.04 R751.2
N16849728: length 1.6
  BOTTOM w0.381: R747.1 19.05,107.85 C476.2
N16940595: length 18
  TOP w0.508: CA107.1 CA106.1 CA105.1 95,16.68 v1(94.96,16.64) ; CA107.1 97.92,16.68 v1(97.96,16.64) ; CA107.1 C258.1 ; v1(103.96,16.64) 104.01,16.69 CA108.1 C258.1 ; v1(100.96,16.64) 100.97,16.64 C258.1
  BOTTOM w0.508: U61.7 v1(100.96,16.64) ; U61.4 v1(97.96,16.64) ; U61.10 v1(103.96,16.64) ; U61.1 v1(94.96,16.64)
N16940606: length 2.1
  TOP w0.762: 107.29,10.29 C259.1
  TOP w0.813: R476.2 107.19,9.02 107.29,9.12 C259.1
N16940607: length 2.1
  TOP w0.762: 103.35,10.29 C260.1
  TOP w0.813: R477.2 103.38,10.13 C260.1
N16940608: length 2.4
  TOP w0.813: R478.2 100.33,8.76 99.42,9.68 C261.1 99.42,10.29
N16940609: length 4.4
  TOP w0.813: R479.2 96.77,8.23 95.48,9.53 C262.1 95.48,10.29
N16940656: length 18
  TOP w0.508: v1(118.15,16.64) 118.11,16.68 CA111.1 ; CA111.1 CA110.1 CA109.1 115.19,16.68 v1(115.15,16.64) ; CA111.1 C263.1 ; C263.1 CA112.1 124.21,16.69 v1(124.15,16.64) ; C263.1 121.16,16.64 v1(121.15,16.64)
  BOTTOM w0.508: U62.4 v1(118.15,16.64) ; U62.10 v1(124.15,16.64) ; U62.7 v1(121.15,16.64) ; U62.1 v1(115.15,16.64)
N16940667: length 2.1
  TOP w0.762: 127.48,10.29 C264.1
  TOP w0.813: C264.1 127.48,8.33 R480.2
N16940668: length 2.1
  TOP w0.762: 123.55,10.29 C265.1
  TOP w0.813: C265.1 123.55,8.26 R481.2
N16940669: length 2.4
  TOP w0.813: R482.2 120.52,8.76 119.61,9.68 C266.1 119.61,10.29
N16940670: length 4.2
  TOP w0.813: C267.1 115.67,9.53 116.97,8.23 R483.2
N16942353: length 18.9
  TOP w0.508: v1(142.49,50.54) 142.49,50.55 C273.1 ; C273.1 CA85.1 ; C273.1 CA81.1 142.44,53.59 v1(142.49,53.54) ; v1(142.46,47.5) CA85.1 ; CA85.1 CA86.1 CA87.1 141.61,44.54 v1(142.47,44.54)
  BOTTOM w0.508: v1(142.49,53.54) U64.10 140.94,53.54 ; 140.94,44.54 U64.1 v1(142.47,44.54) ; v1(142.46,47.5) 142.42,47.54 U64.4 140.94,47.54 ; 140.94,50.54 U64.7 v1(142.49,50.54)
N16942364: length 2.1
  TOP w0.813: R488.2 150.37,56.16 C274.1
N16942365: length 1.9
  TOP w0.813: R489.2 150.75,51.33 C275.1
N16942366: length 2
  TOP w0.813: C276.1 148.82,49.02 R490.2
N16942367: length 2.3
  TOP w0.813: R491.2 150.06,45.8 149.35,45.09 C277.1
N16942442: length 2.1
  TOP w0.762: 147.68,10.29 C269.1
  TOP w0.813: R484.2 147.68,8.33 C269.1
N16942443: length 2.1
  TOP w0.762: 143.74,10.29 C270.1
  TOP w0.813: C270.1 143.74,8.26 R485.2
N16942444: length 2.4
  TOP w0.813: 139.8,10.29 C271.1 139.8,9.68 140.72,8.76 R486.2
N16942445: length 4.4
  TOP w0.813: R487.2 137.06,8.23 135.86,9.42 C272.1 135.86,10.29
N17060195: length 2.7
  BOTTOM w0.107: U37.2 RB62.1 RZ148.2
N17060201: length 4
  BOTTOM w0.107: U38.1 66.93,177.93 67.31,177.55 67.31,175.3 U37.4
N17062477: length 5.4
  TOP w0.107: RZ119.1 116.15,42.88 v1(116.15,43.56)
  BOTTOM w0.107: SW2.2 v1(116.15,43.56) SW2.1
N17062487: length 5.4
  TOP w0.107: RZ112.1 118.55,42.88 v1(118.55,43.56)
  BOTTOM w0.107: SW1.2 v1(118.55,43.56) SW1.1
N17062540: length 1.8
  TOP w0.254: U13.21 v1(139.33,76.96)
  BOTTOM w0.254: v1(139.33,76.96) 139.32,76.95 RZ199.1
N17062551: length 3.9
  TOP w0.254: U13.26 136.83,76.56 136.53,76.86 C25.1
  TOP w0.508: R84.1 135.52,78.27 C25.1
N17068458: length 9
  TOP w0.508: U40.16 29.28,188.02 29.59,187.71 35.25,187.71 35.63,188.09 U40.11
N17071169: length 3.8
  TOP w0.254: RZU1.1 33.35,190.84 v1(33.09,190.58) U40.13
  BOTTOM w0.127: FL2.1 31.51,190.65
  BOTTOM w0.254: FL2.1 33.02,190.65 v1(33.09,190.58)
N17071172: length 4
  TOP w0.254: U40.12 34.36,190.57 v1(34.37,190.58) 34.37,191.24 RZU2.1
  BOTTOM w0.254: FL2.2 34.44,190.65 v1(34.37,190.58)
N17071866: length 4.5
  TOP w0.508: C163.1 v1(28.83,191.26)
  BOTTOM w0.508: R267.2 R264.1 29.21,190.88 v1(28.83,191.26)
N17107581: length 1.7
  BOTTOM w0.508: R22.2 D1.A1
N17475821: length 19.5
  TOP w0.508: CA91.1 C239.1 CA92.1 22.68,20.12 v1(22.73,20.07) ; CA91.1 18.87,20.12 v1(18.92,20.07) ; CA91.1 CA90.1 ; CA90.1 CA89.1 12.05,20.82 v1(11.3,20.07) ; CA90.1 15.06,20.12 v1(15.11,20.07)
  BOTTOM w0.508: U57.4 v1(15.11,20.07) ; U57.7 v1(18.92,20.07) ; U57.1 v1(11.3,20.07) ; U57.10 v1(22.73,20.07)
N17477312: length 18
  TOP w0.508: CA95.1 CA94.1 CA93.1 34.42,16.68 v1(34.38,16.64) ; CA95.1 C243.1 ; CA95.1 37.34,16.68 v1(37.38,16.64) ; C243.1 40.39,16.64 v1(40.38,16.64) ; C243.1 CA96.1 43.43,16.69 v1(43.38,16.64)
  BOTTOM w0.508: U58.7 v1(40.38,16.64) ; U58.1 v1(34.38,16.64) ; U58.4 v1(37.38,16.64) ; U58.10 v1(43.38,16.64)
N17477531:
  vias: v1(40.82,11.23) v1(41.43,11.23)
N17477559:
  vias: v1(44.68,11.23) v1(45.31,11.23)
N17486236: length 18
  TOP w0.508: CA99.1 C248.1 ; CA99.1 CA98.1 CA97.1 54.61,16.68 v1(54.57,16.64) ; CA99.1 57.53,16.68 v1(57.57,16.64) ; C248.1 60.58,16.64 v1(60.57,16.64) ; C248.1 CA100.1 63.63,16.69 v1(63.57,16.64)
  BOTTOM w0.508: U59.1 v1(54.57,16.64) ; U59.4 v1(57.57,16.64) ; U59.10 v1(63.57,16.64) ; U59.7 v1(60.57,16.64)
N17486352:
  vias: v1(60.96,11.23) v1(61.57,11.23)
N17486475:
  vias: v1(64.87,11.23) v1(65.51,11.23)
N17486917: length 18
  TOP w0.508: C253.1 CA103.1 ; C253.1 CA104.1 83.82,16.69 v1(83.76,16.64) ; C253.1 80.77,16.64 v1(80.76,16.64) ; CA103.1 77.72,16.68 v1(77.76,16.64) ; CA103.1 CA102.1 CA101.1 74.8,16.68 v1(74.76,16.64)
  BOTTOM w0.508: U60.7 v1(80.76,16.64) ; U60.10 v1(83.76,16.64) ; U60.4 v1(77.76,16.64) ; U60.1 v1(74.76,16.64)
N17487128:
  vias: v1(81.13,11.23) v1(81.74,11.23)
N17487156:
  vias: v1(85.06,11.23) v1(85.7,11.23)
N17488314:
  vias: v1(101.32,11.23) v1(101.93,11.23)
N17488336:
  vias: v1(105.26,11.23) v1(105.89,11.23)
N17488976:
  vias: v1(121.49,11.23) v1(122.1,11.23)
N17489028:
  vias: v1(125.45,11.23) v1(126.09,11.23)
N17489888:
  vias: v1(145.64,11.23) v1(146.28,11.23)
N17489893:
  vias: v1(141.81,11.23) v1(142.42,11.23)
N17490600:
  vias: v1(147.65,58.01) v1(147.65,57.38)
N17490605:
  vias: v1(147.4,53.01) v1(147.4,52.4)
N17490610:
  vias: v1(147.42,47.85) v1(147.42,47.22)
N17490615:
  vias: v1(147.65,43.69) v1(147.65,43.05)
N17518837: length 4.1
  TOP w0.107: U28.3 71.31,54.54 72.09,55.32 RZU35.2 RB59.2
N17518839: length 3.3
  TOP w0.107: R181.2 67.26,53.92 67.59,53.59 U28.5
N17518846: length 1.4
  TOP w0.107: U28.4 68.4,54.57 RZ103.2
N17525472: length 6.5
  BOTTOM w0.508: U27.3 78.78,179.45 82.17,179.45 82.7,178.92 R177.1
N17533418: length 2.4
  TOP w0.508: RB2.2 93.5,177.77 93.37,177.9 U24.7
N17533420: length 2.2
  TOP w0.508: RB1.2 93.5,190.37 93.37,190.25 U24.10
N17533862: length 2.3
  BOTTOM w0.508: U26.7 87.02,178.18 86.84,178 RB61.2
N17533864: length 2.3
  BOTTOM w0.508: U26.10 87.02,190.07 86.84,190.25 RB60.2
N17921312: length 7.8
  TOP w0.107: U66.63 92.69,90.26 92.61,90.34 92.61,91.75 R525.1 92.94,92.63 93.13,92.82 C293.1 93.13,93.36 94.05,94.29 94.05,95.79 93.28,96.56 Y2.1
N17921343: length 5.7
  TOP w0.107: U66.64 92.29,91.76 R525.2 91.97,93.15 C295.1 91.91,94.02 Y2.3
N17924096: length 3.8
  TOP w0.203: 90.13,83.12 90.35,83.33 U66.15
  TOP w0.508: R534.1 89,82.79 C297.2 89.81,82.8 90.13,83.12
N17924979: length 3.7
  TOP w0.203: U66.41 99.83,86.13 99.98,86.28 101.45,86.28 101.6,86.13
  TOP w0.381: R509.2 101.6,86.13
  TOP w0.508: C289.1 101.64,86.09 R509.2
N17925260: length 2.4
  TOP w0.508: C289.2 102.59,84.98 R509.1 103.75,86.11 C288.1
N17925590: length 4.4
  TOP w0.203: 99.75,82.66 99.48,82.93 U66.33
  TOP w0.508: 99.75,82.66 100.86,81.55 CB20.2 103.04,81.55 R512.1
N17925618: length 1.5
  TOP w0.508: C290.1 104.27,80.8 104.01,81.05 R512.2
N17945769: length 2.2
  BOTTOM w0.107: U38.2 65.66,178.05 66.4,177.32 RZ145.2
N17954676: length 18
  TOP w0.508: v1(138.34,16.64) 138.3,16.68 CA115.1 ; CA116.1 141.35,16.64 v1(141.34,16.64) ; CA116.1 CA115.1 ; CA116.1 C268.1 144.4,16.69 v1(144.34,16.64) ; CA115.1 CA114.1 CA113.1 135.38,16.68 v1(135.34,16.64)
  BOTTOM w0.508: U63.1 v1(135.34,16.64) ; U63.10 v1(144.34,16.64) ; U63.7 v1(141.34,16.64) ; U63.4 v1(138.34,16.64)
N17962248: length 1.7
  TOP w0.229: RZ63.1 11.76,79.7 U65.55
N17962251: length 1.6
  TOP w0.229: U65.54 12.26,79.72 RZ64.1
N17978352: length 2.5
  TOP w0.114: CM46.1 66.38,85.05 66.75,85.42 66.75,86.23 v3(66.36,86.62)
  BOTTOM w0.114: v3(66.36,86.62) 65.96,87.02 U67.U25
N17978356: length 2.3
  TOP w0.114: v3(67.16,86.62) 67.01,86.46 67.01,85.42 67.31,85.12 CM47.1
  BOTTOM w0.114: U67.V25 v3(67.16,86.62)
N17978406: length 2.7
  BOTTOM w0.114: U67.W26 67.83,85.94 67.83,84.18 CM78.1
N17978410: length 2.7
  BOTTOM w0.114: CM77.1 68.09,84.15 68.09,85.95 U67.Y26
N17979269: length 2.7
  BOTTOM w0.114: CM73.1 61.69,84.32 61.69,86.1 61.8,86.22 U67.M26
N17979281: length 2.7
  BOTTOM w0.114: U67.L26 61.32,86.22 61.43,86.1 61.43,84.26 CM74.1
N17979323: length 2.7
  BOTTOM w0.114: CM75.1 58.49,84.3 58.49,86.1 58.6,86.22 U67.H26
N17979335: length 2.7
  BOTTOM w0.114: U67.G26 58.12,86.22 58.23,86.1 58.23,84.28 CM76.1
N17979425: length 3.6
  TOP w0.114: v3(56.76,86.62) 56.49,86.34 56.49,86.1 56.29,85.9 56.29,84.32 CM49.1
  BOTTOM w0.114: v3(56.76,86.62) 57.16,87.02 U67.F25
N17979437: length 3.6
  TOP w0.114: CM48.1 56.03,84.26 56.03,86.01 56.23,86.21 56.23,86.34 v3(55.96,86.62)
  BOTTOM w0.114: v3(55.96,86.62) 56.36,87.02 U67.E25
N17981424: length 3.6
  BOTTOM w0.114: RZ183.1 75.02,103.82 74.76,103.82 74.35,103.41 72.8,103.41 72.41,103.02 U67.AE5
N17981427: length 2.7
  BOTTOM w0.114: RZ184.1 75.02,103.57 74.86,103.57 74.45,103.16 73.3,103.16 U67.AF5
N17981727: length 5.1
  TOP w0.114: RZ52.1 75.02,100.9 74.49,100.9 73.66,101.73 72.66,101.73 72.27,102.12 72.27,102.31 v3(71.96,102.62)
  BOTTOM w0.114: U67.AD6 v3(71.96,102.62)
N17981744: length 4.6
  TOP w0.114: RZ50.1 75.02,101.16 74.59,101.16 73.77,101.98 72.77,101.98 72.53,102.22 72.53,102.38 v3(72.76,102.62)
  BOTTOM w0.114: U67.AE6 v3(72.76,102.62)
N17982049: length 3.6
  BOTTOM w0.114: RZ185.1 75.02,101.41 74.49,101.41 74.08,101.81 72.8,101.81 72.41,101.42 U67.AE7
N17982065: length 2.7
  BOTTOM w0.114: U67.AF7 73.3,101.56 73.98,101.56 74.38,101.16 75.02,101.16 RZ186.1
N17982119: length 7.5
  TOP w0.114: v3(70.36,101.82) 70.76,101.42 71.32,101.42 72.79,99.95 73.75,99.95 74.08,99.62 74.08,99.15 74.61,98.62 75.02,98.62 RZ55.1
  BOTTOM w0.114: U67.AB7 v3(70.36,101.82)
N17982135: length 6.5
  TOP w0.114: v3(71.16,101.82) 71.3,101.68 71.42,101.68 72.9,100.2 73.85,100.2 74.33,99.72 74.33,99.26 74.72,98.87 75.02,98.87 RZ54.1
  BOTTOM w0.114: U67.AC7 v3(71.16,101.82)
N17983399: length 10.3
  TOP w0.114: v3(57.56,104.22) 57.29,104.49 57.29,104.71 56.97,105.03 56.13,105.03 55.37,105.79 55.37,106.93 54.48,107.82 54.48,111.63 CM33.1
  BOTTOM w0.114: U67.G4 v3(57.56,104.22)
N17983402: length 10.3
  TOP w0.114: CM32.1 54.23,111.63 54.23,107.72 55.12,106.83 55.12,105.69 56.03,104.78 56.87,104.78 57.03,104.61 57.03,104.49 v3(56.76,104.22)
  BOTTOM w0.114: U67.F4 v3(56.76,104.22)
N17983405: length 4.3
  TOP w0.114: v3(57.56,105.82) 57.29,106.09 57.29,106.29 55.75,107.82 55.75,108.33 56.13,108.58
  BOTTOM w0.114: U67.G2 v3(57.56,105.82)
N17983408: length 4.3
  TOP w0.114: 55.12,108.58 55.5,108.33 55.5,107.72 57.03,106.18 57.03,106.09 v3(56.76,105.82)
  BOTTOM w0.114: U67.F2 v3(56.76,105.82)
N17983588: length 3.2
  BOTTOM w0.114: CM69.1 57.91,108.24 57.91,107.66 59.03,106.54 59.03,106.33 58.92,106.22 U67.H1
N17983600: length 3.2
  BOTTOM w0.114: CM68.1 58.17,108.24 58.17,107.77 59.29,106.65 59.29,106.33 59.4,106.22 U67.J1
N17983612: length 8.7
  TOP w0.114: v3(58.36,105.02) 58.62,105.28 58.62,105.49 58.75,105.61 58.75,106.2 56.71,108.24 56.71,111.63 CM34.1
  BOTTOM w0.114: U67.H3 v3(58.36,105.02)
N17983616: length 8.7
  TOP w0.114: CM35.1 56.96,111.63 56.96,108.35 59,106.3 59,105.51 58.88,105.38 58.88,105.3 v3(59.16,105.02)
  BOTTOM w0.114: U67.J3 v3(59.16,105.02)
N17983696: length 3.5
  TOP w0.114: CM42.1 60.31,108.09 60.31,107.12 60.1,106.9 60.1,105.95 v3(59.96,105.82)
  BOTTOM w0.114: U67.K2 v3(59.96,105.82)
N17983708: length 3.6
  TOP w0.114: v3(60.76,105.82) 60.35,106.23 60.35,106.8 60.57,107.01 60.57,108.06 CM43.1
  BOTTOM w0.114: U67.L2 v3(60.76,105.82)
N17983720: length 9.1
  TOP w0.114: v3(59.96,104.22) 60.2,104.46 60.2,104.64 59.31,105.53 59.31,106.78 59.12,106.97 59.12,111.63 CM36.1
  BOTTOM w0.114: U67.K4 v3(59.96,104.22)
N17983724: length 9.1
  TOP w0.114: CM37.1 59.37,111.63 59.37,107.08 59.56,106.89 59.56,105.64 60.45,104.75 60.45,104.53 v3(60.76,104.22)
  BOTTOM w0.114: U67.L4 v3(60.76,104.22)
N17983804: length 2.7
  BOTTOM w0.114: U67.M1 62.23,106.49 62.23,107.04 62.74,107.55 62.74,108.08 CM71.1
N17983816: length 2.7
  BOTTOM w0.114: CM70.1 62.99,108.08 62.99,107.44 62.48,106.93 62.48,106.49 U67.N1
N17983828: length 8
  TOP w0.114: CM38.1 61.59,111.63 61.59,105.57 61.85,105.32 61.85,105.16 61.71,105.02 v3(61.56,105.02)
  BOTTOM w0.114: U67.M3 v3(61.56,105.02)
N17983832: length 8
  TOP w0.114: v3(62.36,105.02) 62.24,105.02 62.1,105.16 62.1,105.42 61.85,105.68 61.85,111.63 CM39.1
  BOTTOM w0.114: U67.N3 v3(62.36,105.02)
N17985522: length 1.7
  BOTTOM w0.114: U41.21 22.81,38 22.69,38.13 22.69,38.53 CM81.1
N17985526: length 1.7
  BOTTOM w0.114: U41.20 22.31,38 22.43,38.13 22.43,38.51 CM82.1
N17985638: length 1.9
  BOTTOM w0.114: CM93.1 39.45,35.86 39.45,35.05 39.58,34.93 U43.21
N17985642: length 1.9
  BOTTOM w0.114: U43.20 39.08,34.9 39.2,35.02 39.2,35.85 CM94.1
N17985774: length 1.9
  BOTTOM w0.114: U45.21 57.86,34.93 57.74,35.05 57.74,35.86 CM91.1
N17985778: length 1.9
  BOTTOM w0.114: U45.20 57.36,34.9 57.49,35.02 57.49,35.85 CM92.1
N17985910: length 1.9
  BOTTOM w0.114: CM89.1 76.03,35.86 76.03,35.17 76.15,35.05 U47.21
N17985914: length 1.9
  BOTTOM w0.114: U47.20 75.65,35.05 75.77,35.17 75.77,35.85 CM90.1
N17986046: length 1.9
  BOTTOM w0.114: U49.21 94.44,34.93 94.32,35.05 94.32,35.86 CM87.1
N17986050: length 1.9
  BOTTOM w0.114: CM88.1 94.06,35.85 94.06,35.02 93.94,34.9 U49.20
N17986184: length 1.9
  BOTTOM w0.114: CM85.1 112.6,35.86 112.6,35.05 112.73,34.93 U51.21
N17986188: length 1.9
  BOTTOM w0.114: CM86.1 112.35,35.85 112.35,35.02 112.23,34.9 U51.20
N17986320: length 1.9
  BOTTOM w0.114: CM83.1 130.89,36.24 130.89,35.43 131.02,35.31 U53.21
N17986324: length 1.9
  BOTTOM w0.114: CM84.1 130.64,36.23 130.64,35.4 130.52,35.28 U53.20
N17986454: length 1.7
  BOTTOM w0.114: CM79.1 125.42,46.83 125.58,46.83 125.69,46.95 125.98,46.95 126.11,47.07 U55.21
N17986458: length 1.7
  BOTTOM w0.114: U55.20 126.14,46.57 126.01,46.69 125.8,46.69 125.68,46.58 125.46,46.58 CM80.1
N17989951: length 4.5
  TOP w0.254: U73.1 41.1,103.9 40.32,104.67 R659.2
  TOP w0.508: R655.1 38.79,104.74 C385.2 38.82,104.67 R659.2
N17989959: length 3
  TOP w0.254: RZU25.2 RB33.2 40.04,102.55 U73.4
N17990621: length 3
  TOP w0.254: RZU27.2 RB41.2 40.04,92.89 U72.4
N17990625: length 4.5
  TOP w0.254: R654.2 40.32,95.02 41.1,94.24 U72.1
  TOP w0.508: C380.2 38.77,95.08 R651.1 38.84,95.02 R654.2
N18023847: length 1.6
  TOP w0.254: RZ78.1 116.38,69.34 Q11.D
N18024364: length 1.4
  TOP w0.107: Q14.D 120.19,74.68 120.55,74.32 RZ72.1
N18025778: length 1.5
  TOP w0.254: R714.1 94.69,99.34 94.35,99.68 U80.5
N18025836: length 1.3
  TOP w0.254: U80.8 93.5,101.93 RZ56.2
N18025865: length 1.6
  TOP w0.254: U80.7 94.1,100.68 94.51,101.09 94.51,102.04 C434.1
N18053287: length 1.4
  BOTTOM w0.254: U32.5 141.47,177.66 141.83,178.03 R226.1
N18053364: length 1.5
  BOTTOM w0.107: U32.7 141.28,176.02 141.52,175.79 C130.1
N18054826: length 4.1
  BOTTOM w0.254: R713.2 87.62,93.54 U79.1
  BOTTOM w0.508: R706.1 88.81,92.16 C427.2 R713.2
N18054834: length 2.6
  TOP w0.254: RB35.2 86.68,91.97 v1(86.89,92.19) 86.93,92.23 RZU26.2
  BOTTOM w0.254: U79.4 v1(86.89,92.19)
N18055461: length 3.9
  TOP w0.203: 132.51,176.68 U34.10
  TOP w0.254: R246.1 R247.2 133.61,176.68 132.51,176.68
N18068175: length 5.7
  BOTTOM w0.107: RZ194.1 37.06,84.96 37.29,84.73 Q29.G 34.85,83.74 JPPCIE1.1
N18076130: length 1.9
  BOTTOM w0.203: LANLINK1.C1 29.86,40.27 29.44,39.85 R288.1
N18076153: length 1.7
  BOTTOM w0.203: LANLINK1.C2 30.72,38.97 31.47,38.23 R289.1
N18076291: length 1.7
  BOTTOM w0.305: R286.1 27.74,39.93 27.74,40.42 LANACT1.C
N18076865: length 1.7
  BOTTOM w0.305: R310.1 43.8,37.71 LANACT2.C
N18076892: length 1.5
  BOTTOM w0.203: R312.1 46.46,36.93 LANLINK2.C1
N18076913: length 1.8
  BOTTOM w0.203: LANLINK2.C2 48.23,36.37 R313.1
N18077498: length 1.7
  BOTTOM w0.305: LANACT3.C 62.09,37.71 R333.1
N18077525: length 1.5
  BOTTOM w0.203: LANLINK3.C1 64.75,36.93 R336.1
N18077546: length 1.8
  BOTTOM w0.203: R337.1 66.52,36.37 LANLINK3.C2
N18078897: length 1.7
  BOTTOM w0.305: LANACT4.C 80.38,37.71 R356.1
N18078924: length 1.5
  BOTTOM w0.203: LANLINK4.C1 83.03,36.93 R360.1
N18078945: length 1.8
  BOTTOM w0.203: R361.1 84.81,36.37 LANLINK4.C2
N18079699: length 1.7
  BOTTOM w0.305: R381.1 98.67,37.71 LANACT5.C
N18079726: length 2
  BOTTOM w0.203: LANLINK5.C1 101.45,36.93 R384.1
N18079747: length 1.7
  BOTTOM w0.203: R385.1 103.1,35.74 LANLINK5.C2
N18080540: length 1.7
  BOTTOM w0.305: R405.1 116.95,37.71 LANACT6.C
N18080567: length 1.5
  BOTTOM w0.203: R408.1 119.41,36.93 119.92,36.41 LANLINK6.C1
N18080588: length 1.8
  BOTTOM w0.203: LANLINK6.C2 121.39,36.37 R409.1
N18081372: length 1.7
  BOTTOM w0.305: LANACT7.C 135.24,38.09 R429.1
N18081399: length 1.5
  BOTTOM w0.203: R432.1 137.9,37.31 LANLINK7.C1
N18081420: length 1.8
  BOTTOM w0.203: LANLINK7.C2 139.67,36.76 R433.1
N18082215: length 2.4
  BOTTOM w0.254: LANACT8.C 125.48,57 125.35,56.87 R454.1
N18082242: length 2.4
  BOTTOM w0.203: LANLINK8.C1 127.11,57.52 126.49,56.9 R456.1
N18082263: length 1.6
  BOTTOM w0.203: 128.65,56.52 128.65,57.04 128.41,57.28 LANLINK8.C2
N18092346: length 1.6
  TOP w0.107: J1.K40 87.72,131.44 v1(87.72,132.02)
  BOTTOM w0.107: TP1.1 87.27,132.53 87.72,132.08 v1(87.72,132.02)
N18120066: length 6.3
  BOTTOM w0.508: R260.1 56.77,179.2 56.39,179.58 52.53,179.58 51.64,178.69
N18165594: length 1.5
  TOP w0.254: U81.5 100.55,95.51 R715.1
N18165656: length 1.3
  TOP w0.254: RZ57.2 98.98,97.76 U81.8
N18165690: length 1.6
  TOP w0.254: C432.1 99.59,97.47 99.59,96.56 U81.7
N18173925: length 1.8
  TOP w0.107: U13.3 v1(142.25,67.3)
  BOTTOM w0.107: v1(142.25,67.3) 142.24,67.31 RZ204.2
N18173928: length 1.9
  TOP w0.107: v1(142.27,72.9) 142.37,72.8 U13.14
  BOTTOM w0.107: RZ201.2 141.83,72.9 v1(142.27,72.9)
N18186882: length 4.3
  TOP w0.107: RZU22.1 145,109.8 145.57,110.36 146.71,110.36 147.31,110.96 SSD2.40
N18186907: length 3.7
  TOP w0.107: RZU23.1 146.14,109.67 146.33,109.86 146.79,109.86 147.81,110.88 SSD2.42
N18187137: length 3.6
  TOP w0.254: RZ23.2 152.78,120.27 153.16,119.89 153.92,119.89 154.56,119.25 SSD2.69
N18187139: length 11.5
  TOP w0.107: SSD2.68 154.31,111.12 154.56,110.87 155.22,110.87 157.1,108.99 R761.2
N18187141: length 2.1
  TOP w0.107: U84.3 155.27,100.99 R761.1
N18187143: length 5.2
  TOP w0.381: U84.1 153.16,99.36 FB39.1 151.52,99.38 CA65.1 152.61,100.91 U84.4
N18192110: length 1.5
  BOTTOM w0.203: R763.2 140.97,101.6 U85.12
N18192155: length 2.1
  BOTTOM w0.107: U85.2 139.78,103.36 RZ35.2
N18192178: length 1.8
  BOTTOM w0.107: RZ38.2 139.04,103.76 U85.3
N18192205: length 1.8
  BOTTOM w0.107: U85.4 139.02,104.16 RZ40.2
N18192224: length 2.1
  BOTTOM w0.107: RZ46.2 139.76,104.56 U85.5
N18194663: length 1.6
  TOP w0.254: RZ61.2 108.32,81.64 U18.1
N18194685: length 1.8
  TOP w0.254: U18.14 v1(113.44,86.51)
  BOTTOM w0.254: v1(113.44,86.51) 113.39,86.46 RZ192.2
N18194768: length 2.1
  TOP w0.107: U18.19 110.82,89.48 R1484.2
N18194804: length 2
  TOP w0.107: U18.24 108.32,88.58 107.95,88.95 R1485.2
N18194817: length 2.1
  TOP w0.107: R1486.2 109.82,89.34 U18.21
N18194942: length 1.8
  TOP w0.254: U18.6 110.82,81.97 R769.2
N18195475: length 1.5
  TOP w0.203: RB38.2 110.07,98.26 U86.5
N18195479: length 2.5
  TOP w0.203: 111.04,95.01 110.9,95.16 U86.1 110.07,95.03 U86.16
  TOP w0.254: 111.04,95.01 111.17,94.89 111.17,94.5 RB39.2
N18195489: length 1.8
  TOP w0.203: U86.4 110.57,96.36 110.73,96.52 v1(111.02,96.52)
  BOTTOM w0.381: 110.11,96.52 v1(111.02,96.52)
N18196140: length 3.1
  BOTTOM w0.254: Q51.2 111.28,93.62 RB36.1 111.63,93.75 111.93,93.46 Q51.3
N18233097: length 2.3
  TOP w0.508: RZ1.2 v1(14.35,195.58)
  BOTTOM w0.508: v1(14.35,195.58) 14.33,195.61 Q15.B
N18237049: length 2.1
  BOTTOM w0.102: WIFI1.3 132.74,122.68 132.86,122.56 132.86,121.91 RZ176.2
N18237080: length 2.1
  BOTTOM w0.102: RZ175.2 133.11,121.88 133.11,122.57 133.24,122.7 WIFI1.5
N18237082: length 5.7
  BOTTOM w0.203: LED1.C 130.16,129.92 130.37,130.13 132.02,130.13 132.35,129.79 133.28,129.79 133.49,130 WIFI1.6
N18237084: length 1.5
  BOTTOM w0.254: LED1.A 127.24,130.18 R188.2
N18237134: length 4.3
  TOP w0.107: RZU18.2 v1(133.48,125.86)
  BOTTOM w0.107: v1(133.48,125.86) 133.6,125.86 134.24,125.22 WIFI1.9
N18237158: length 5.4
  TOP w0.107: RZU13.2 132.56,126.36 133.86,126.36 v1(134.37,125.86)
  BOTTOM w0.107: WIFI1.11 134.74,125.36 134.37,125.73 v1(134.37,125.86)
N18237182: length 4
  TOP w0.107: v1(135.25,125.98) 134.37,126.87 RZU14.2
  BOTTOM w0.107: WIFI1.13 135.24,125.97 v1(135.25,125.98)
N18237217: length 3.8
  TOP w0.107: v1(136.4,125.98) 136.4,126.59 RZU15.2
  BOTTOM w0.107: WIFI1.15 135.74,125.32 v1(136.4,125.98)
N18237219: length 8.8
  BOTTOM w0.203: WIFI1.16 135.99,132.29 135.56,132.72 131.83,132.72 130.94,131.83 LED2.C
N18237221: length 1.4
  BOTTOM w0.254: R189.2 LED2.A
N18237240: length 3.8
  TOP w0.107: RZU10.2 v1(137.54,125.98)
  BOTTOM w0.107: WIFI1.17 136.24,124.68 v1(137.54,125.98)
N18237264: length 4.2
  TOP w0.107: RZU11.2 v1(138.68,125.98)
  BOTTOM w0.107: v1(138.68,125.98) 138.43,125.98 136.74,124.29 WIFI1.19
N18237285: length 4.8
  TOP w0.107: RZU12.2 v1(139.83,125.98)
  BOTTOM w0.107: v1(139.83,125.98) 139.29,125.45 138.51,125.45 137.24,124.18 WIFI1.21
N18237289: length 5.4
  TOP w0.107: RZU17.2 v1(141,126.01)
  BOTTOM w0.107: WIFI1.23 137.74,124.05 138.71,125.02 140,125.02 v1(141,126.01)
N18237399: length 4.4
  BOTTOM w0.114: CM67.2 138.3,121.88 138.3,122.08 138.57,122.34 140.78,122.34 140.85,122.41 140.85,122.6 140.74,122.71 WIFI1.35
N18237422: length 4.4
  BOTTOM w0.114: WIFI1.37 141.24,122.74 141.1,122.6 141.1,122.3 140.89,122.09 138.67,122.09 138.56,121.97 138.56,121.88 CM66.2
N18237451: length 2.4
  BOTTOM w0.107: RZU42.1 141.49,133.32 WIFI1.38
N18237476: length 1.9
  BOTTOM w0.114: RZ173.2 142.36,122.07 142.36,122.56 142.24,122.68 WIFI1.41
N18237478: length 1.4
  BOTTOM w0.107: TP39.1 141.99,131.95 WIFI1.40
N18237490: length 1.9
  BOTTOM w0.114: WIFI1.43 142.74,122.67 142.61,122.55 142.61,122.08 RZ172.2
N18237492: length 2.5
  BOTTOM w0.107: RZ170.1 142.65,132.11 142.49,131.95 WIFI1.42
N18237555: length 1.8
  BOTTOM w0.107: WIFI1.53 145.24,122.17 145.16,122.1 RZ174.2
N18237567: length 5.5
  TOP w0.107: v1(145.67,124.59) 146.18,125.09 Q17.D 145.26,126.26 RZU16.2 R199.1
  BOTTOM w0.107: WIFI1.55 145.74,124.48 145.67,124.55 v1(145.67,124.59)
N18237624: length 3.7
  TOP w0.107: RZ21.2 v1(148.08,125.6)
  BOTTOM w0.107: v1(148.08,125.6) 147.7,125.6 146.81,124.71 146.81,124.33 146.74,124.26 WIFI1.59
N18237626: length 2.2
  BOTTOM w0.107: WIFI1.58 146.49,133.07 RZU41.1
N18237645: length 4.2
  TOP w0.107: RZ22.2 v1(149.22,125.6)
  BOTTOM w0.107: v1(149.22,125.6) 148.72,125.09 147.83,125.09 147.24,124.5 WIFI1.61
N18237647: length 2.4
  BOTTOM w0.107: WIFI1.60 146.99,132.53 RZU40.1
N18237667: length 3.8
  BOTTOM w0.107: RZ169.1 R195.1 147.49,131.89 WIFI1.62
N18238169: length 2.5
  TOP w0.107: U29.3 142.53,136 R194.1
N18238171: length 5.2
  TOP w0.254: U29.4 137.95,136.02 CA55.1 136.14,135.93 FB5.1 136.7,134.57 137.02,134.25 U29.1
N18239373: length 1.5
  BOTTOM w0.254: U30.5 129.4,140.47 130.15,139.73 R202.1
N18239450: length 1.4
  BOTTOM w0.254: U30.7 128.41,140.34 127.98,139.92 C92.1
N18353073: length 1.5
  BOTTOM w0.254: PLED1.A 137.02,40.74 R230.2
N18353085: length 2
  TOP w0.254: v1(134.26,40.51) 134.9,41.15 Q19.D
  BOTTOM w0.254: v1(134.26,40.51) 135.14,40.51 PLED1.C
N18355368: length 5.3
  BOTTOM w0.508: R677.2 154.99,18.62 PWRBTN1.1
N18355613: length 7.2
  BOTTOM w0.508: RESET1.1 156.28,134.17 154.69,135.76 154.69,137.67 153.8,138.56 R680.2
N18355836: length 13.5
  BOTTOM w0.508: R682.2 153.67,132.23 153.67,124.08 154.89,122.86 RECOVERY1.1
N18552806: length 2.4
  BOTTOM w0.381: RZ162.1 153.89,146.94 154.05,147.1 AUDIO1.4
N18554011: length 4.7
  BOTTOM w0.381: RZ160.2 156.35,148.08 AUDIO1.3
N18656044: length 3
  BOTTOM w0.254: U87.7 125.76,65.47 125.66,65.36 125.66,65.08 125.78,64.97 U87.8 127.45,64.97 R1334.2
N18656142: length 1.6
  TOP w0.107: v1(124.08,65.79) 124.21,65.66 RZ91.2
  BOTTOM w0.107: v1(124.08,65.79) 123.9,65.97 U87.3
N18656144: length 1.6
  BOTTOM w0.107: U87.6 127.89,65.97 RZ206.1
N18656178: length 1.6
  TOP w0.107: RZ86.2 124.33,66.8 v1(124.08,66.55)
  BOTTOM w0.107: v1(124.08,66.55) 124,66.47 U87.4
N18656180: length 1.8
  BOTTOM w0.107: RZ205.1 127.45,66.47 U87.5
N18665598: length 17
  TOP w0.508: Q63.4 v1(17.98,98.86) ; Q68.4 v1(12.65,96.09)
  IN1 w0.508: POESLT1.2 20.6,92.2 19.51,93.29 19.51,97.33 v1(17.98,98.86) 15.42,98.86 v1(12.65,96.09)
N18665787: length 14.6
  TOP w0.508: v1(6.43,95.99) Q64.4 ; Q67.4 v1(11.71,98.83)
  IN1 w0.508: POESLT2.2 4.45,92.2 5.79,93.55 5.79,95.35 v1(6.43,95.99) 8.86,95.99 v1(11.71,98.83)
N18665860: length 9
  TOP w0.254: Q69.6 3.56,80.01 3.76,80.21 3.76,83.22 3.51,83.47 Q66.5 2.15,83.47 1.97,83.65 1.97,85.03 2.24,85.29 R1507.1
N18790442: length 2.5
  TOP w0.107: U14.1 125.25,75.69 126.24,76.68 RZ67.2
N18790882: length 1.7
  TOP w0.107: RB53.1 124.45,72.45 U14.10
N18790917: length 3.4
  TOP w0.107: RZU30.1 RB48.1 123.95,76.35 124.45,75.86 U14.3
N18790923: length 2.1
  TOP w0.107: RB49.1 125.09,76.17 124.85,75.93 U14.2
N18791105: length 2.5
  TOP w0.107: RB52.1 122.68,72.24 123.09,72.64 123.91,72.64 124.05,72.78 U14.9
N18797950: length 4
  BOTTOM w0.508: U74.6 26.18,172.73 26.75,172.16 26.75,171.15 27.06,170.83 U74.3
  vias: v2(16.13,180.85) v2(16.13,179.96) v2(16.13,179.07) v2(17.02,180.85) v2(17.02,179.96) v2(17.02,179.07) v2(17.91,180.85) v2(17.91,179.96) v2(17.91,179.07) v2(18.8,177.29) v2(18.8,176.4) v2(18.8,175.51) v2(18.8,174.62) v2(19.68,177.29) v2(19.68,176.4) v2(19.68,175.51) v2(19.68,174.62) v2(20.57,177.29) v2(20.57,176.4) v2(20.57,175.51) v2(20.57,174.62) v2(21.46,177.29) v2(21.46,176.4) v2(21.46,175.51) v2(21.46,174.62) v2(22.35,177.29) v2(22.35,176.4) v2(22.35,175.51) v2(22.35,174.62)
N18798062: length 4
  TOP w0.508: Q30.4 v1(23.67,171.15)
  BOTTOM w0.508: v1(23.67,171.15) 24.31,171.78 U74.5
N18798086:
  vias: v1(17.4,186.56) v1(17.4,185.93) v1(17.4,185.29) v1(17.4,184.66) v1(18.03,186.56) v1(18.03,185.93) v1(18.03,185.29) v1(18.03,184.66) v1(18.67,186.56) v1(18.67,185.93) v1(18.67,185.29) v1(18.67,184.66)
N18798173: length 2.2
  BOTTOM w0.508: U74.1 27.91,174.52 C392.2
N18798292: length 5.5
  TOP w0.381: R667.1 64.01,156.54 63.63,156.92 Q31.4
  TOP w0.508: R667.1 65.63,158.04 C394.2 66.67,158.14 R664.2
N18798370: length 3.8
  TOP w0.508: R670.1 R671.1 65.74,152.86 Q32.D
N18798998: length 2.8
  TOP w0.381: R665.1 55.85,167.23 56.12,167.5 U75.1
  TOP w0.508: R665.1 R663.2
N18799362: length 1.8
  TOP w0.508: FB38.2 R662.1
N18799364:
  vias: v2(1.91,178.82) v2(1.91,178.05) v2(2.79,178.82) v2(2.79,178.05) v2(3.68,178.82) v2(3.68,178.05)
N18880064: length 1.6
  TOP w0.254: RZ73.1 116.23,72.14 Q13.D
N18880909: length 2.4
  TOP w0.254: RZ120.2 R1509.1 137.23,40.67 Q19.G
N18881934: length 23.9
  IN1 w0.508: v1(137.54,142.88) 137.54,142.11 138.3,141.35 138.3,140.97 138.94,140.34 145.41,140.34 146.43,141.35 146.43,144.27 147.32,145.16 v1(147.32,152.3)
  BOTTOM w0.203: v1(137.54,142.88) 137.65,142.98 U16.26
  BOTTOM w0.508: RZ685.1 v1(147.32,152.3)
N18881943: length 23.2
  IN1 w0.508: v1(137.54,143.89) 138.05,143.89 138.56,143.38 138.56,142.37 139.06,141.86 143.64,141.86 144.27,142.49 144.27,145.29 146.43,147.45 146.43,153.57 v1(147.32,154.46)
  BOTTOM w0.203: U16.28 137.65,143.78 v1(137.54,143.89)
  BOTTOM w0.508: RZ686.1 v1(147.32,154.46)
N18882012: length 8.1
  BOTTOM w0.381: RZU37.2 150.47,152.02 150.98,152.53 152.63,152.53 153.01,152.15 RZ153.2 153.67,151.89 153.87,152.1 156.34,152.1 AUDIO1.7
N18882124: length 5.7
  BOTTOM w0.381: AUDIO1.8 153.89,151.1 153.54,150.75 RZ154.2 153.01,150.55 152.63,150.16 150.85,150.16 150.47,150.55 RZU39.1
N18931604: length 2
  TOP w0.229: U25.34 80.08,151.58 79.53,151.03 R173.2
N19048317: length 8.1
  BOTTOM w0.203: U16.5 145.04,145.38 145.28,145.62 145.88,145.62 146.05,145.45
  BOTTOM w0.381: C898.2 151.71,145.45 146.05,145.45
N19048952: length 8
  BOTTOM w0.203: 146.05,144.78 145.73,144.78 145.6,144.65 145.23,144.65 145.16,144.58 U16.7
  BOTTOM w0.381: 146.05,144.78 146.18,144.91 151.8,144.91 C899.2
N19126579: length 2.1
  BOTTOM w0.508: R1510.2 11.43,123.04 11.07,122.68 C917.1
N20328471: length 3.2
  TOP w0.107: SPI2.2 v1(52.27,46.94)
  BOTTOM w0.107: v1(52.27,46.94) R644.2 RZ114.2
N20328520: length 6
  TOP w0.107: SPI2.6 49.1,48.21 v1(49.23,48.34)
  BOTTOM w0.107: v1(49.23,48.34) 48.72,48.84 48.72,50.34 RZ111.1
N20328523: length 3.2
  TOP w0.107: SPI2.5 v1(49.23,49.48)
  BOTTOM w0.107: RZ110.1 49.86,50.5 49.23,49.86 v1(49.23,49.48)
N20328554: length 1.9
  TOP w0.107: R645.2 SPI2.7
N20493475: length 1.3
  TOP w0.107: RZ108.1 R639.1
N20493478: length 1.6
  TOP w0.254: RZ89.1 64.41,64.79 65.56,64.79 R640.1
N25237920: length 5.2
  BOTTOM w0.203: RB14.2 R285.1 32.4,29.36 C173.1 32.97,28.79 32.97,28.3 33.4,27.86 33.4,26.45 33.2,26.25 X2.3
N53913115: length 3.1
  TOP w0.107: RZ68.2 R607.2 SPI1.2
N53913461: length 3
  TOP w0.107: v1(67.34,78.49) SPI1.6
  BOTTOM w0.107: v1(67.34,78.49) 66.62,79.2 RZ65.1
N53913464: length 2.2
  TOP w0.107: SPI1.5 v1(67.34,79.76)
  BOTTOM w0.107: v1(67.34,79.76) 67.54,79.96 RZ198.1
N53913963: length 2.1
  TOP w0.254: SPI1.7 65.05,77.22 64.57,77.7 R608.2
N54184803: length 5.2
  TOP w0.114: RZ33.1 75.46,105.87 75.3,105.7 74.92,105.7 74.12,104.9 72.57,104.9 72.33,104.66 72.33,104.4 72.15,104.22 v3(71.96,104.22)
  BOTTOM w0.114: U67.AD4 v3(71.96,104.22)
N54186028: length 4.5
  TOP w0.114: RZ37.1 75.46,105.23 75.25,105.45 75.02,105.45 74.22,104.65 72.68,104.65 72.59,104.55 72.59,104.39 v3(72.76,104.22)
  BOTTOM w0.114: U67.AE4 v3(72.76,104.22)
N54369784: length 2.7
  BOTTOM w0.114: RZ179.1 75.02,106.24 73.66,106.24 73.44,106.02 73.28,106.02 73.16,106.13 U67.AF1
N54371660: length 2.8
  BOTTOM w0.114: RZ181.1 75.02,105.98 73.76,105.98 73.54,105.76 73.35,105.76 73.16,105.58 U67.AF2
N54465881: length 7
  TOP w0.114: RZ42.1 75,103.42 70.99,103.42 70.57,103.01 69.95,103.01 v3(69.56,102.62)
  BOTTOM w0.114: U67.AA6 v3(69.56,102.62)
N54465893: length 6.1
  TOP w0.114: RZ48.1 75.04,103.17 71.09,103.17 70.54,102.62 v3(70.36,102.62)
  BOTTOM w0.114: U67.AB6 v3(70.36,102.62)
N59689924: length 2.1
  TOP w0.762: 87.1,10.29 C254.1
  TOP w0.813: R472.2 87.1,8.33 C254.1
N59689926: length 2.1
  TOP w0.762: 83.16,10.29 C255.1
  TOP w0.813: R473.2 83.16,8.26 C255.1
N59689928: length 2.4
  TOP w0.813: 79.22,10.29 C256.1 79.22,9.3 80.14,8.38 R474.2
N59689930: length 4.5
  TOP w0.813: R475.2 76.23,8.23 75.29,9.17 C257.1
N59691945: length 2.1
  TOP w0.762: 66.9,10.29 C249.1
  TOP w0.813: C249.1 66.9,8.33 R468.2
N59691947: length 2.1
  TOP w0.762: 62.97,10.29 C250.1
  TOP w0.813: R469.2 62.97,8.26 C250.1
N59691949: length 2.4
  TOP w0.813: 59.03,10.29 C251.1 59.03,9.42 59.94,8.51 R470.2
N59691951: length 4.5
  TOP w0.813: 55.09,10.29 C252.1 55.09,9.3 56.16,8.23 R471.2
N59697516: length 2
  TOP w0.813: C238.1 24.94,8.2 R460.2
N59697518: length 2
  TOP w0.813: R461.2 20.88,8.2 C240.1
N59697520: length 2
  TOP w0.813: R462.2 16.81,8.2 C241.1
N59697522: length 2
  TOP w0.813: R463.2 12.75,8.33 C242.1
N59698211: length 2.1
  TOP w0.762: 46.71,10.29 C244.1
  TOP w0.813: C244.1 46.71,8.33 R464.2
N59698213: length 2.1
  TOP w0.762: 42.77,10.29 C245.1
  TOP w0.813: R465.2 42.77,8.26 C245.1
N59698215: length 2.1
  TOP w0.813: 38.84,10.29 C246.1 38.84,8.26 R466.2
N59698217: length 2.1
  TOP w0.813: R467.2 34.9,8.38 C247.1 34.9,10.29
N60625316: length 1.8
  TOP w0.102: L6.4 101.03,65 100.76,65.28 100.16,65.28 CA75.2
N60625341: length 1.8
  TOP w0.102: CA74.2 100.16,65.53 100.76,65.53 101.03,65.81 L6.1
N63435656: length 3.3
  TOP w0.254: R170.2 97.1,58.14 97.1,59.64 96.85,59.89 U22.5
N63437012: length 3.9
  BOTTOM w0.254: U23.5 81.1,52.27 81.36,52.53 81.36,53.29 81.61,53.54 R171.2
N63438290: length 1.7
  TOP w0.102: L5.4 82.91,55.91 83.19,56.18 83.19,56.76 CA79.2
N63438309: length 1.7
  TOP w0.102: CA78.2 83.44,56.76 83.44,56.21 83.71,55.94 L5.1
N66390376: length 1.7
  BOTTOM w0.107: NGFF1.1 156.82,175.67 TP40.1
N66390584: length 1.7
  BOTTOM w0.107: NGFF1.21 156.79,180.67 TP41.1
N66390616: length 3.3
  BOTTOM w0.107: NGFF1.25 156.02,181.67 156.34,181.36 157.23,181.36 TP42.1
N66390835: length 2.1
  BOTTOM w0.107: TP43.1 156.86,192.67 NGFF1.69
N66390837: length 2.4
  BOTTOM w0.107: NGFF1.68 147.18,192.42 TP44.1
N66390898: length 2.1
  BOTTOM w0.107: TP45.1 156.97,194.31 156.08,194.31 155.94,194.17 NGFF1.75
N100957080: length 1.3
  TOP w0.107: U42.3 17.15,40.62 RA16.1
N101129395: length 1.4
  TOP w0.107: U42.7 17.65,35.25 RA23.1
N198711181: length 2.8
  BOTTOM w0.254: U77.8 142.91,96.77 142.77,96.9 142.77,97.28
  BOTTOM w0.508: 142.77,97.28 142.77,97.79 142.52,98.04 R695.2
N198711183: length 1.3
  BOTTOM w0.508: CM72.1 142.49,100.08 R695.1
N209543093: length 2.7
  BOTTOM w0.254: U77.11 144.39,98.27 144.81,98.68 R698.2 R697.1
N209574440: length 2.8
  TOP w0.381: R700.2 R699.1 143.15,94.35 v1(143.39,94.11)
  BOTTOM w0.254: U77.6 v1(143.39,94.11)
N236903799: length 2.3
  BOTTOM w0.203: 133.06,87.31 133.25,87.12 133.48,87.12 133.68,86.92 U76.1
  BOTTOM w0.381: RZ189.2 132.46,87.91 133.06,87.31
N236903801: length 2.1
  BOTTOM w0.508: C395.1 132.11,87.12 131.5,87.73 RZ189.1
N236903803: length 1.5
  TOP w0.508: v1(139.6,87.63) 139.6,88.87 R684.2
  vias: v1(136.17,85.09) v1(136.8,85.09) v1(137.44,85.09) v1(139.6,87) v1(139.6,84.84) v1(140.23,87.63) v1(140.23,87) v1(140.23,84.84) v1(140.87,87.63) v1(140.87,87) v1(140.87,84.84) v1(141.5,87.63) v1(141.5,87) v1(141.5,84.84) v1(142.14,87.63) v1(142.77,87.63) v1(143.41,87.63) v1(144.04,87.63)
N236903827: length 4.3
  BOTTOM w0.203: U76.7 136.18,87.26 136.42,87.5 136.42,87.76
  BOTTOM w0.254: R689.2 136.42,88.16 136.42,87.76
  BOTTOM w0.508: R686.2 136.65,89.67 C400.1 136.64,88.4 R689.2
N236903834: length 1.2
  BOTTOM w0.508: 138.81,89.66 CA147.1
N236903849: length 4
  TOP w0.381: RZ58.2 136.14,89.48 v1(135.69,89.03) 136.13,88.58 CA66.1
  BOTTOM w0.203: U76.6 135.78,87.38 135.84,87.44 135.84,87.88
  BOTTOM w0.305: 135.84,87.88 135.84,88.24 R689.1 v1(135.69,89.03)
N236903854: length 10.4
  TOP w0.508: v1(138.81,87.76) 138.07,87.76 137.31,87 R690.2 136.65,86.61 136.14,86.11 134.05,86.11 133.54,85.6 C406.1 133.54,83.35 v1(133.38,83.19)
  BOTTOM w0.305: U76.19 133.68,83.49 133.38,83.19 v1(133.38,83.19) ; 138.81,88.39 v1(138.81,87.76)
N236903856: length 2.9
  TOP w0.381: v1(135.38,87.66) 135.38,88.2 CA66.2 C405.1
  BOTTOM w0.203: U76.5 v1(135.38,87.66)
N236903864: length 3
  TOP w0.381: v1(134.8,87.66) 134.49,87.35 R691.2
  TOP w0.508: R690.1 R691.2
  BOTTOM w0.203: v1(134.8,87.66) 134.8,87.57 134.98,87.38 U76.4
N236903867: length 1.9
  BOTTOM w0.203: R692.2 134.26,88.16 134.26,87.5 134.58,87.19 U76.3

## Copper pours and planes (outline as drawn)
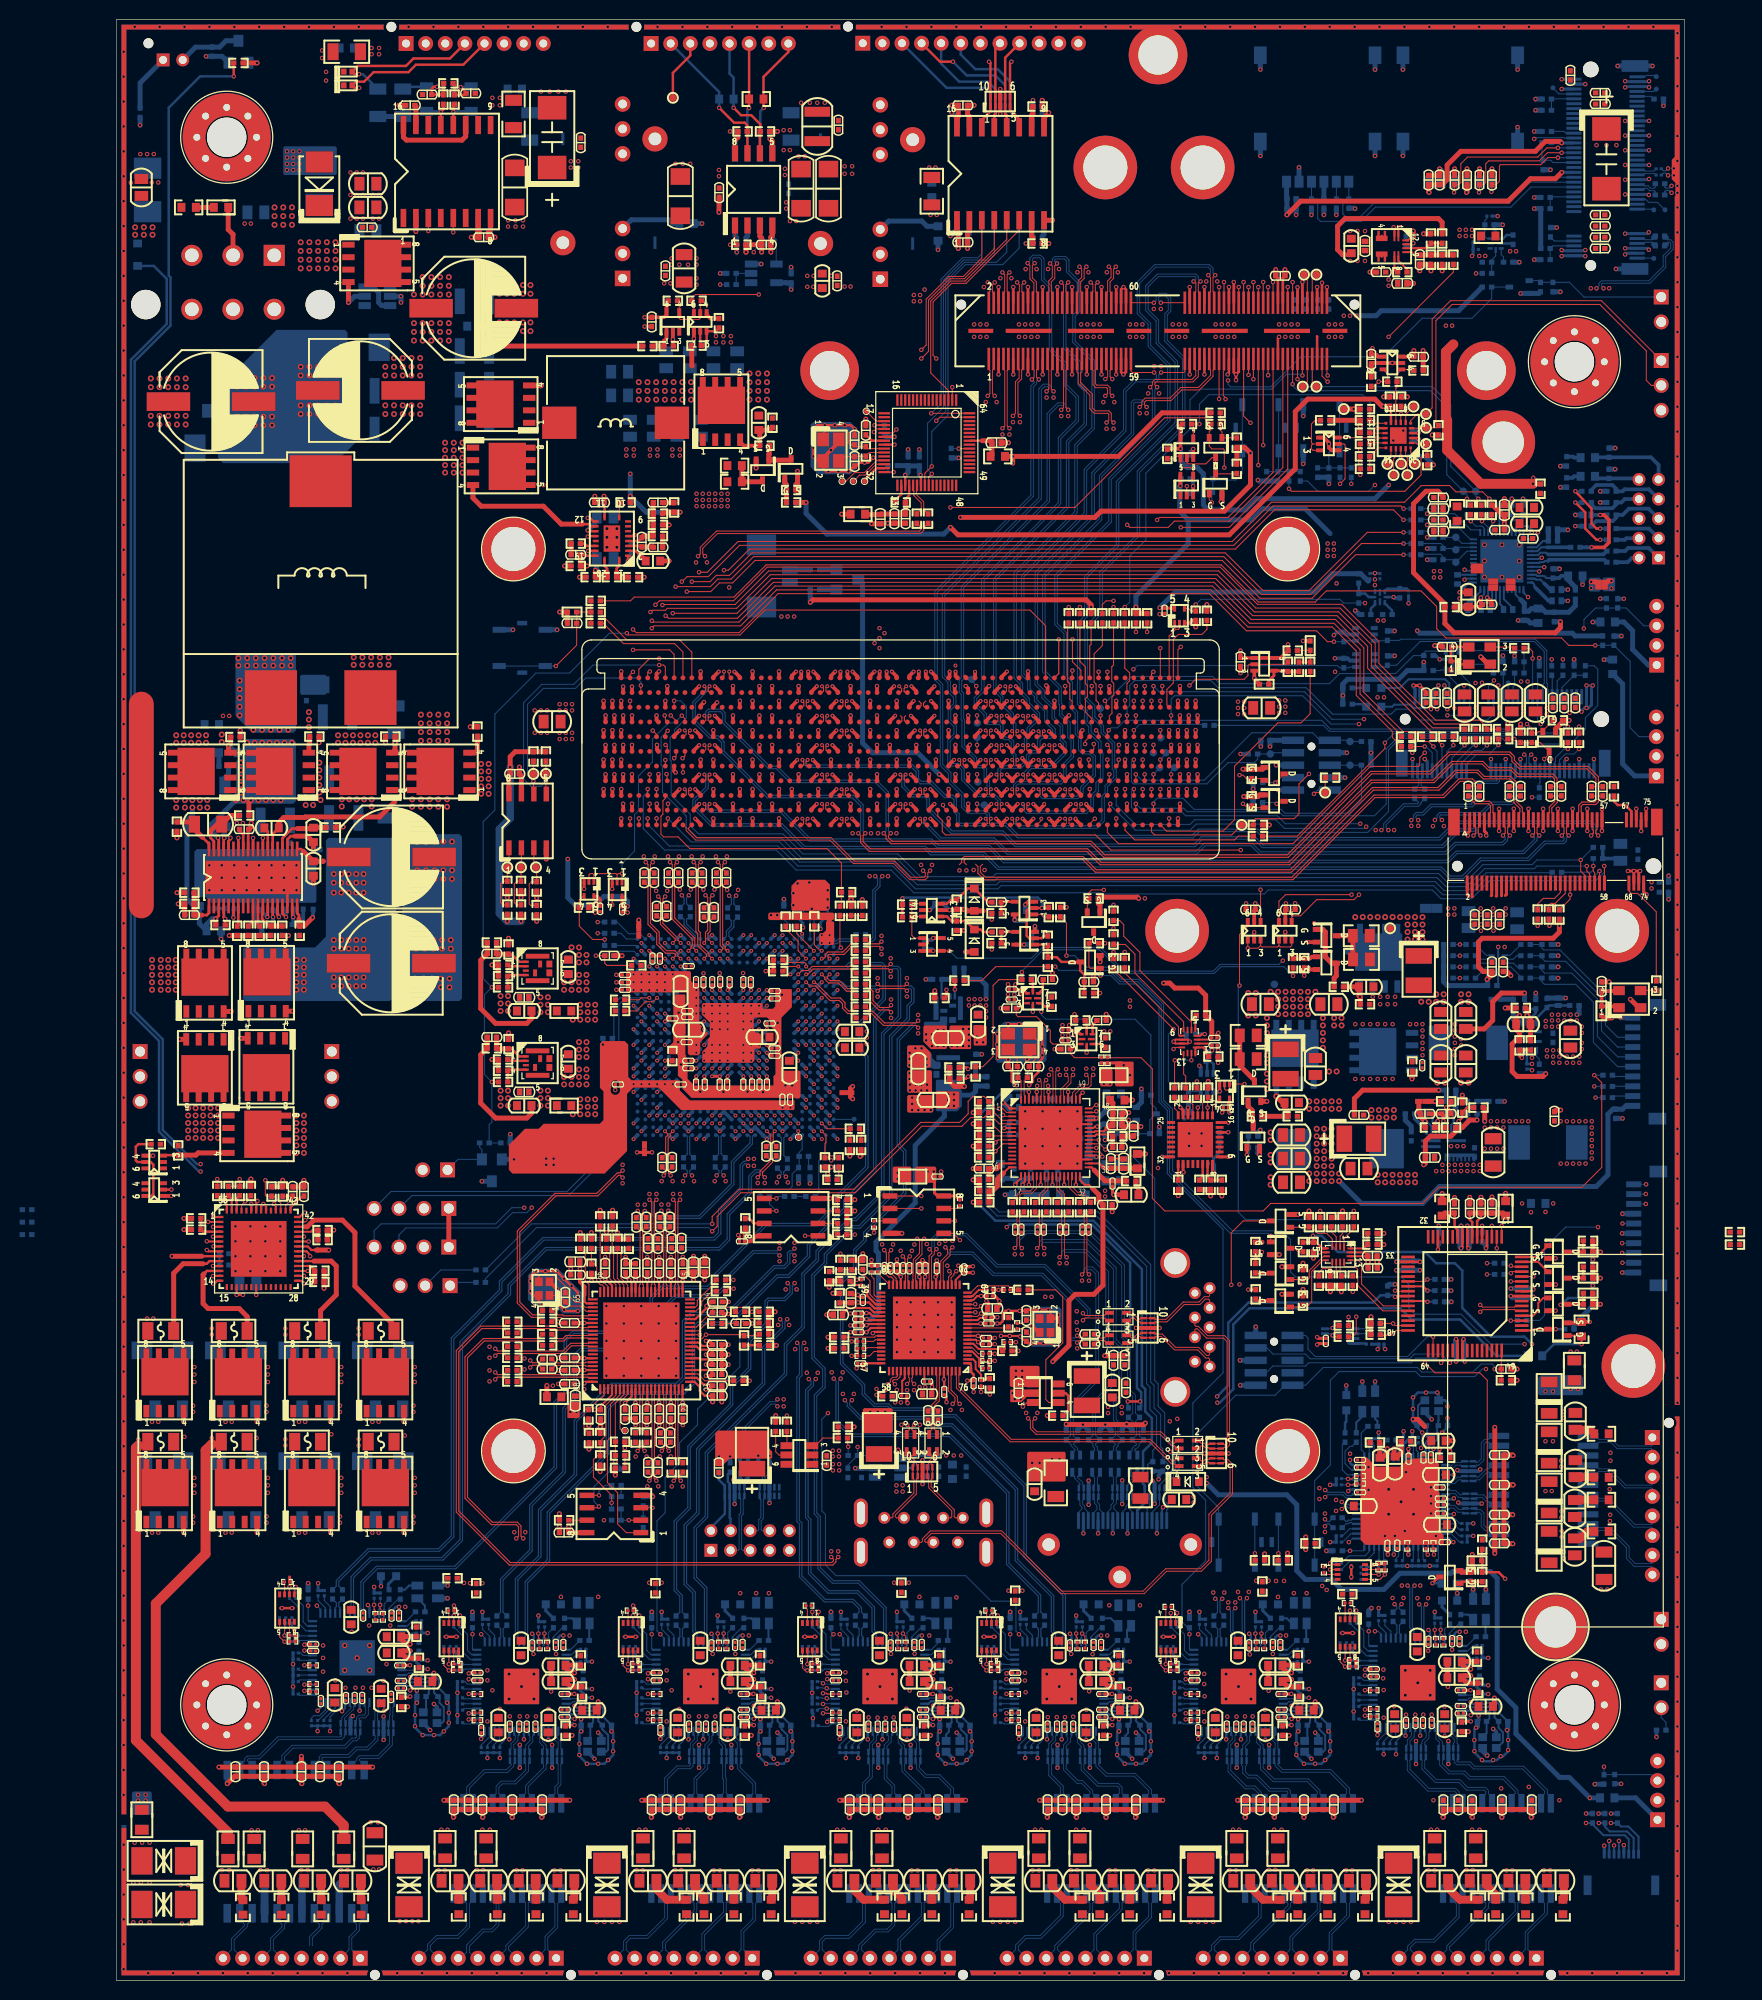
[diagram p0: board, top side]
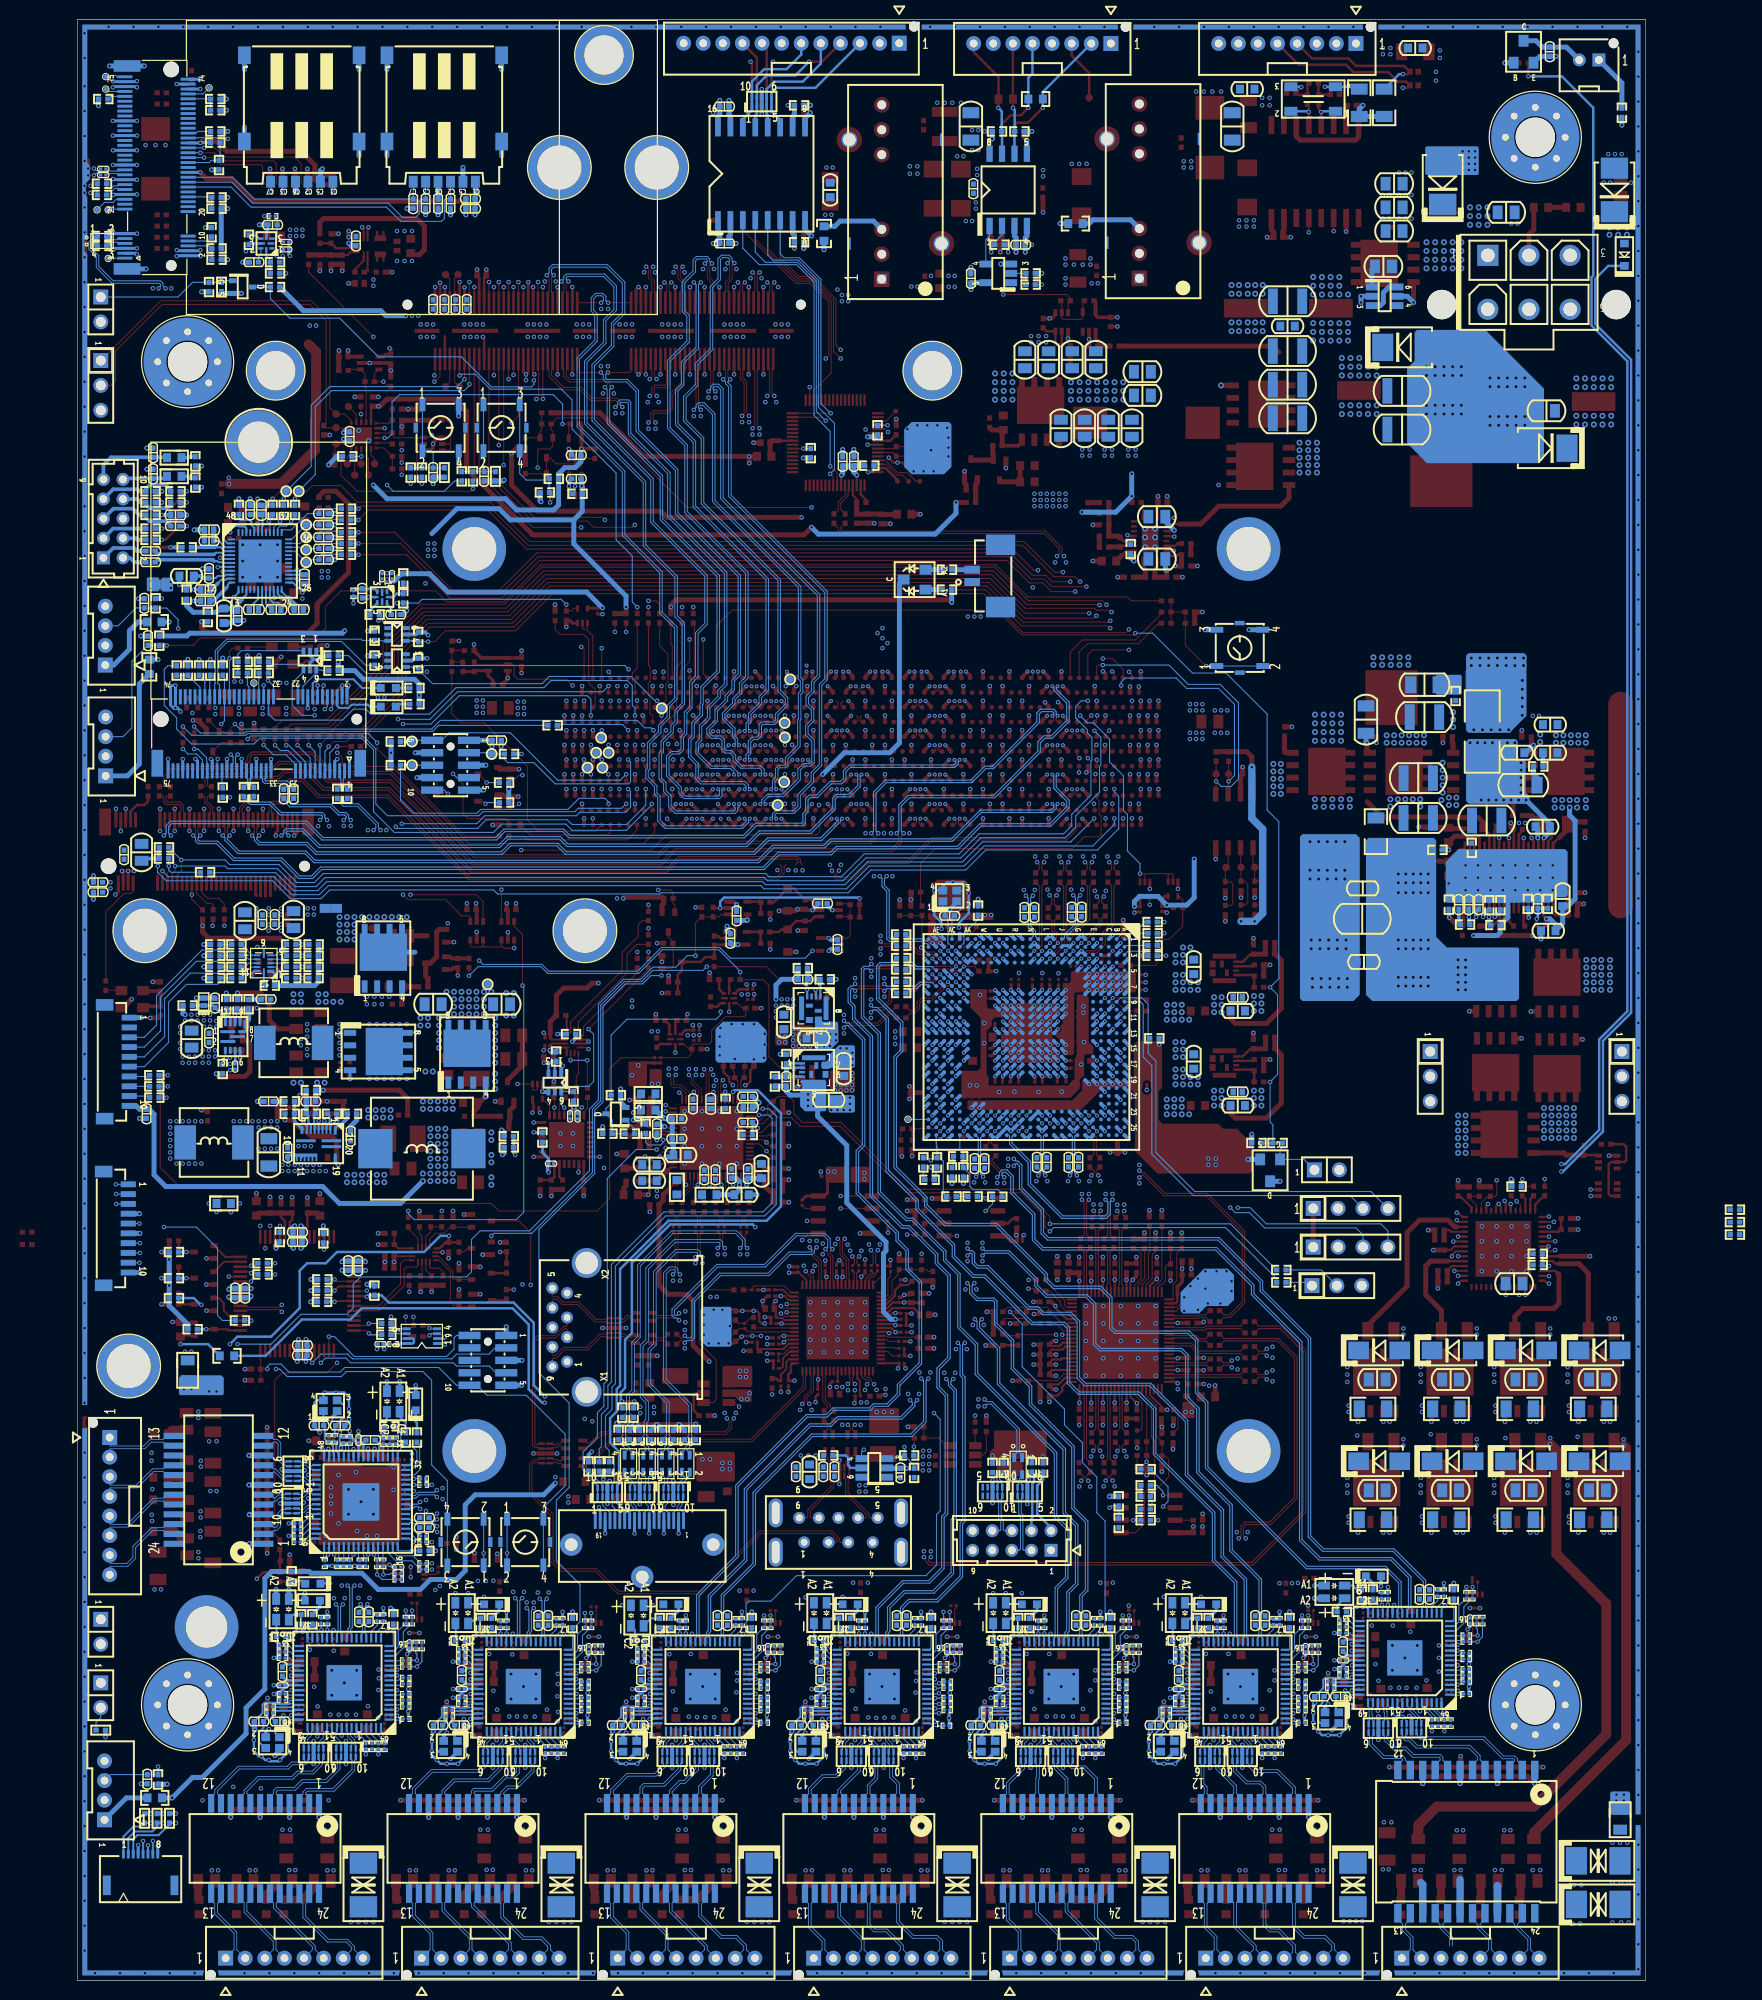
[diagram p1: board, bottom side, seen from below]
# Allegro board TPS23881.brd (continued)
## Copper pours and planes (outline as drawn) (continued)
3.3VCC on IN1: 78.44,157.81 86.18,157.81 86.44,157.56 86.44,152.48 81.99,148.03 78.18,148.03 77.93,148.29 77.93,157.3
5V_HDMI2 on TOP: 103.58,47.96 103.45,48.08 103.45,49.99 103.58,50.11 105.87,50.11 106.1,50.34 106.1,51.23 106.18,51.32 106.45,51.32 106.76,51.01 106.76,50.54 107.67,49.63 107.98,49.63 108.1,49.5 108.1,48.08 107.98,47.96
5V_SPKVDD on TOP: 145.41,149.22 145.41,147.45 144.65,146.69 144.27,146.69 144.15,146.81 144.15,151.89 144.27,152.02 145.54,152.02 145.67,151.89 145.67,149.48
+V1.2S on TOP: 101.65,95.94 101.55,95.83 99.11,95.83 99.06,95.89 99.06,96.14 99.09,96.16 99.92,96.16 100.38,96.62 100.38,97.05 100.51,97.18 101.52,97.18 101.65,97.05
+V1.2S on BOTTOM: 99.97,97.16 102.39,97.16 103.91,95.63 103.91,89.66 103.15,88.9 103.15,88.39 103.02,88.27 102.01,88.27 101.88,88.39 101.88,91.44 99.85,93.47 99.85,97.03
+V1.2S on BOTTOM: 101.24,80.64 101.24,79.63 101.12,79.5 95.78,79.5 95.66,79.63 95.66,80.64 95.78,80.77 101.12,80.77
+V1.2S on IN3: 102.64,90.3 104.04,90.3 104.17,90.17 104.17,80.39 103.28,79.5 100.61,79.5 100.36,79.76 100.36,82.55 101.24,83.44 101.24,88.9
+V1.2SB on TOP (solid shape): 86,90.55 86,89.15 85.75,88.9 83.72,88.9 83.59,89.03 83.59,90.55 83.72,90.68 85.88,90.68
+V1.2SB on BOTTOM (solid shape): 86.26,91.69 86.26,91.6 86.09,91.42 86.03,91.19 86.09,90.95 86.26,90.78 86.26,89.15 85.75,88.65 83.72,88.65 83.59,88.77 83.59,91.69 83.72,91.82 86.13,91.82
+V1.2SB on TOP: 97.82,96.57 98.2,96.19 98.83,96.19 98.88,96.14 98.88,95.91 98.83,95.86 98.09,95.86 97.94,95.71 96.93,95.71 96.85,95.78 96.85,96.47 96.95,96.57
+V1.2SB on IN1: 84.48,88.9 85.5,88.9 86.51,89.92 88.67,89.92 90.58,91.82 93.5,91.82 94.01,92.33 94.39,92.33 95.4,93.34 97.94,93.34 98.32,93.73 98.32,96.65 98.2,96.77 96.93,96.77 96.8,96.65 96.8,95.38 96.16,94.74 95.53,94.74 94.13,93.34 89.81,93.34 87.91,91.44 84.61,91.44 84.35,91.19 84.35,89.03
+V1.05S on TOP: 41.99,98.25 45.29,98.25 45.42,98.37 45.42,99.52 44.91,100.03 44.91,101.93 44.65,102.18 41.86,102.18 41.73,102.06 41.73,98.5
+V1.05S on BOTTOM: 41.86,100.91 44.4,100.91 44.53,100.79 44.53,98.25 44.4,98.12 41.86,98.12 41.73,98.25 41.73,100.79
+V1.8S on TOP: 135.13,149.35 137.29,149.35 137.41,149.22 137.41,145.67 136.02,144.27 136.02,143 135.89,142.88 134.29,142.88 134.11,143.05 134.11,144.25 134.26,144.4 134.26,146.71 135,147.45 135,149.22
+V1.8S on TOP: 95.78,100 93.62,100 93.57,100.05 93.57,100.3 93.6,100.33 94.44,100.33 94.89,100.79 94.89,101.22 95.02,101.35 96.8,101.35 97.94,100.2 104.04,100.2 104.55,99.69 104.55,99.19 104.29,98.93 96.8,98.93 96.16,99.57 96.16,99.62
+V1.8S on TOP: 118.62,127.76 128.4,127.76 128.65,127.51 128.65,124.97 125.86,122.17 124.08,122.17 123.95,122.3 123.95,123.57 123.57,123.95 118.24,123.95 117.47,124.71 117.47,126.62
+V1.8S on BOTTOM: 127.95,148.02 131.13,144.84 133.16,144.84 133.6,144.4 135.38,144.4 135.51,144.27 135.51,142.62 135.38,142.49 130.53,142.49 128.88,144.15 123.7,144.15 123.32,144.53 123.32,147.89 123.44,148.02
+V1.8S on IN1: 103.5,181.36 123.95,181.36 128.27,177.04 128.27,170.94 126.36,169.04 123.19,169.04 116.08,176.15 88.77,176.15 82.8,170.18 63.4,170.18 60.91,172.67 60.91,178.77 62.36,180.21 102.36,180.21
+V1.8S on IN2: 52.6,114.3 62.51,114.3 62.64,114.43 103.91,114.43 105.69,112.65 105.69,110.11 105.18,109.6 103.4,109.6 101.63,111.38 75.46,111.38 73.56,113.28 63.91,113.28 63.02,112.39 52.98,112.39 52.22,113.16 52.22,113.92
+V1.8S on IN3: 121.41,162.69 121.41,173.48 121.03,173.86 119.13,173.86 119,173.99 119,175.64 119.25,175.9 123.19,175.9 128.14,170.94 128.14,161.54 124.97,158.37 124.97,133.86 122.81,131.7 122.81,126.11 117.86,121.16 117.86,116.69 117.25,116.08 114.83,116.08 114.26,115.51 114.26,103.82 112.8,102.36 112.8,98.68 112.42,98.3 108.48,98.3 107.47,97.28 107.47,94.49 107.59,94.36 107.59,86.49 107.21,86.11 105.31,86.11 105.05,86.36 104.93,86.36 104.93,91.57 103.15,93.34 103.15,101.09 103.16,101.1 103.16,103.95 103.91,104.7 103.91,111.76 104.17,112.01 104.17,112.14 111.38,119.35 111.38,154.56 117.22,160.4 119.13,160.4
+V1.8S on IN3: 154.28,141.4 154.74,140.94 154.74,122.71 153.92,121.89 136.09,121.89 134.85,123.14 134.85,125.96 131.72,129.08 131.72,131.42 129.67,133.48 129.67,150.11 132.79,153.24 143.81,153.24 144.07,152.98 144.07,151.1 143.69,150.72 139.9,150.72 138.71,151.92 136.7,151.92 135.31,150.52 135.31,138.13 137.34,136.09 145.85,136.09 151.16,141.4
+V1.8SB on TOP: 92.33,100.74 92.71,100.36 93.34,100.36 93.4,100.3 93.4,100.08 93.34,100.03 92.61,100.03 92.46,99.87 91.44,99.87 91.36,99.95 91.36,100.63 91.47,100.74
+V1.8SB on TOP: 88.93,100.58 89.05,100.46 89.05,98.04 88.93,97.92 86.77,97.92 86.64,98.04 86.64,100.46 86.77,100.58
+V1.8SB on BOTTOM: 89.05,98.04 88.93,97.92 86.06,97.92 85.92,98.06 85.92,100.5 86,100.58 88.93,100.58 89.05,100.46
+V1.8SB on IN1: 87.27,102.74 91.47,102.74 91.97,102.23 106.96,102.23 107.21,101.98 107.21,99.19 106.83,98.81 97.82,98.81 97.05,99.57 90.58,99.57 88.93,97.92 86.89,97.92 86.51,98.3 86.51,101.98
+V2.5S on TOP: 41.99,88.6 45.29,88.6 45.42,88.72 45.42,89.87 44.91,90.37 44.91,92.28 44.65,92.53 41.86,92.53 41.73,92.41 41.73,88.85
+V2.5S on BOTTOM: 41.86,91.26 44.4,91.26 44.53,91.14 44.53,88.6 44.4,88.47 41.86,88.47 41.73,88.6 41.73,91.14
+V3.3_WLAN on TOP: 132.97,130.94 136.14,130.94 136.65,130.43 149.1,130.43 149.22,130.3 149.22,129.29 149.35,129.16 150.5,129.16 151,129.67 151,133.73 150.5,134.24 144.53,134.24 143.38,135.38 142.24,135.38 142.11,135.25 142.11,134.37 141.1,133.35 137.16,133.35 136.53,133.99 135.76,133.99 134.26,135.48 134.26,140.08 132.51,141.83 129.87,141.83 129.78,141.74 128.79,141.74 128.27,141.22 128.27,138.56 129.41,137.41 129.41,134.49
+V3.3_WLAN on BOTTOM: 128.78,141 129.03,141 129.06,140.97 129.06,140.26 129.51,139.8 129.51,138.51 129.46,138.46 128.47,138.46 128.42,138.51 128.42,139.83 128.75,140.16 128.75,140.97
+V3.3NVME on TOP: 142.14,110.74 142.14,108.46 142.01,108.33 134.65,108.33 134.52,108.46 134.52,110.74 134.65,110.87 142.01,110.87
+V3.3NVME on BOTTOM: 152.68,114.81 155.35,114.81 155.6,114.55 155.6,113.41 156.49,112.52 157.63,112.52 157.76,112.39 157.76,110.36 157.51,110.11 155.6,110.11 154.97,110.74 151.54,110.74 149.12,108.33 134.65,108.33 134.39,108.58 134.39,109.73 134.65,109.98 138.46,109.98 140.36,111.89 151.28,111.89 152.43,113.03 152.43,114.55
+V3.3NVME on IN1: 136.3,116.33 157.89,116.33 158.27,115.95 158.27,110.62 157.76,110.11 155.47,110.11 154.84,110.74 151.41,110.74 149,108.33 135.66,108.33 135.41,108.58 135.41,115.44
+V3.3S on TOP (solid shape): 103.78,93.6 103.78,91.31 103.66,91.19 102.01,91.19 101.88,91.31 101.88,93.6 102.01,93.73 103.66,93.73
+V3.3S on TOP: 139.57,179.07 139.7,178.94 139.7,177.55 139.57,177.42 136.78,177.42 136.65,177.55 136.65,178.94 136.78,179.07
+V3.3S on TOP: 126.77,110.11 134.01,110.11 134.26,109.86 134.26,103.38 134.14,103.25 127.41,103.25 127.28,103.38 127.28,106.93 126.01,108.2 126.01,109.35
+V3.3S on TOP: 131.06,174.5 131.06,172.34 130.94,172.21 129.29,172.21 129.16,172.34 129.16,174.5 129.29,174.62 129.79,174.62 130.3,175.13 130.43,175.13
+V3.3S on BOTTOM: 125.88,109.98 133.88,109.98 134.01,109.86 134.01,103.12 133.76,102.87 125.76,102.87 125.5,103.12 125.5,109.6
+V3.3S on BOTTOM: 120.02,171.07 133.99,171.07 135.89,172.97 135.89,175.13 135.51,175.51 130.18,175.51 128.4,173.74 127.38,173.74 126.75,174.37 120.78,174.37 119.89,173.48 119.89,171.2
+V3.3S on IN1: 113.06,88.27 107.21,82.42 102.9,82.42 102.26,83.06 102.26,95.38 102.32,95.44 102.32,97.6 102.9,98.17 106.96,98.17 107.72,98.93 107.72,101.22 112.29,105.79 112.29,108.33 114.2,110.24 128.17,110.24 128.8,109.6 132.74,109.6 136.3,106.05 147.35,106.05 147.98,105.41 147.98,100.2 147.47,99.69 132.49,99.69 130.84,98.04 130.84,92.84 129.37,91.38 119.28,91.38 118.83,91.82 118.77,91.82 118.52,92.08 118.52,95.25 118.14,95.63 115.6,95.63 113.06,93.09
+V3.3S on IN2: 131.44,168.02 131.44,163.7 131.95,163.19 131.95,161.42 131.7,161.16 128.27,161.16 125.98,158.88 125.98,122.43 133.63,114.78 133.63,105.89 133.4,105.66 116.48,105.66 107.34,114.81 47.37,114.81 39.19,106.63 39.19,81.48 38.3,80.59 13.41,80.59 13.16,80.85 13.16,82.5 13.54,82.88 22.05,82.88 26.87,87.71 26.87,114.88 30.1,118.11 109.22,118.11 110.74,119.63 110.74,165.61 118.43,173.29 118.43,178.63 120.14,180.34 124.46,180.34 125.35,181.23 138.81,181.23 139.19,180.85 139.19,177.93 138.05,176.78 138.05,174.62
+V3.3SB on TOP (solid shape): 81.1,82.88 81.1,81.48 80.98,81.36 79.32,81.36 79.2,81.48 79.2,82.88 79.32,83.01 80.98,83.01
+V3.3SB on TOP: 127.66,101.85 130.71,101.85 130.84,101.73 130.84,91.69 130.71,91.57 125.88,91.57 125.76,91.69 125.76,97.41 127.53,99.19 127.53,101.73
+V3.3SB on TOP: 116,41.43 122.4,41.43 123.47,40.36 125.25,40.36 125.37,40.23 125.37,39.01 125.3,38.94 123.27,38.94 121.84,40.36 115.98,40.36 115.9,40.44 115.9,41.33
+V3.3SB on TOP: 34.67,43.18 38.23,43.18 39.62,41.78 92.96,41.78 93.22,41.53 93.22,39.88 92.84,39.5 87.25,39.5 86.49,40.26 34.54,40.26 34.42,40.39 34.42,42.93
+V3.3SB on TOP: 53.52,104.17 55.6,104.17 55.93,103.84 58.19,103.84 58.29,103.73 58.29,103.25 58.24,103.2 53.29,103.2 53.21,103.28 53.21,103.86
+V3.3SB on BOTTOM: 139.57,177.32 140.57,177.32 140.6,177.31 140.61,177.29 140.61,177.01 140.44,176.83 140.44,176.33 139.73,175.62 139.73,174.93 139.67,174.88 138.86,174.88 138.76,174.98 138.76,177.47 138.81,177.52 139.37,177.52
+V3.3SB on BOTTOM: 129.06,141.25 129.05,141.22 129.03,141.2 128.78,141.2 128.6,141.38 128.04,141.38 127.41,142.01 127.41,143.05 127.51,143.15 129.01,143.15 129.06,143.1
+V3.3SB on BOTTOM: 131.6,102.11 131.72,101.98 131.72,98.55 130.84,97.66 130.84,91.69 130.71,91.57 125.88,91.57 125.76,91.69 125.76,98.3 127.79,100.33 127.79,101.98 127.91,102.11
+V3.3SB on IN2: outline of 94 points within 32.59,38.43 148.08,178.18
+V3.3SB on VCC: outline of 231 points within 32.51,13.97 151.89,42.55
+V3P3A_HUB on TOP (solid shape): 83.64,82.88 83.64,81.62 83.63,81.61 83.64,81.59 83.64,81.48 83.52,81.36 81.61,81.36 81.48,81.48 81.48,82.88 81.61,83.01 83.52,83.01
+V3P3A_HUB on TOP: 77.11,60.63 77.9,60.63 78.46,60.07 78.46,59.21 78.41,59.16 77.17,59.16 77.04,59.28 77.04,60.55
+V3P3A_HUB on IN2: 91.4,74.87 91.64,74.63 91.64,59.51 89.99,57.86 73.23,57.86 71.83,59.26 71.83,61.8 70.56,63.07 70.56,68.96 76.61,75.01 76.61,77.28 80.16,80.84 80.48,80.84 82.45,82.8 83.97,82.8 91.4,75.37
+V5S on TOP: 27.94,183.9 27.94,181.1 28.19,180.85 29.46,180.85 29.59,180.72 29.59,178.44 29.46,178.31 25.91,178.31 25.78,178.44 25.78,183.9 25.91,184.02 27.81,184.02
+V5S on TOP: 144.2,153.59 145.52,153.59 145.62,153.49 145.62,152.35 145.57,152.3 144.22,152.3 144.12,152.4 144.12,153.52
+V5S on TOP: 135.89,169.54 137.54,169.54 137.67,169.42 137.67,167.13 136.65,166.12 135.25,166.12 135.13,166.24 135.13,168.78
+V5S on TOP: 117.12,101.35 123.34,101.35 123.47,101.22 123.47,93.73 122.96,93.22 115.85,93.22 115.72,93.34 115.72,97.16 116.99,98.42 116.99,101.22
+V5S on TOP: 110.11,51.74 111.56,51.74 111.63,51.66 111.63,50.42 111.58,50.37 110.08,50.37 110.03,50.42 110.03,51.66
+V5S on TOP: 90.25,156.03 91.77,156.03 91.9,155.91 91.9,154.25 91.77,154.13 90.25,154.13 90.12,154.25 90.12,155.91
+V5S on TOP: 70.03,135.76 86.49,135.76 86.97,135.28 86.97,132.66 86.84,132.54 69.67,132.54 69.47,132.74 69.47,135.2
+V5S on BOTTOM: 25.91,184.02 27.81,184.02 27.94,183.9 27.94,177.8 27.81,177.67 25.91,177.67 25.78,177.8 25.78,183.9
+V5S on BOTTOM: 123.47,93.47 123.47,101.22 123.22,101.47 120.29,101.47 119.53,102.23 117.25,102.23 116.99,101.98 116.99,93.34 117.12,93.22 123.22,93.22
+V5S on IN1: 115.98,95.38 117.75,95.38 118.01,95.12 118.01,93.09 117.75,92.84 115.47,92.84 114.71,92.08 114.71,90.81 115.09,90.42 115.09,85.72 110.39,81.03 110.39,78.61 105.56,73.79 99.85,73.79 96.16,70.1 96.16,69.34 96.04,69.22 94.13,69.22 93.88,69.47 93.88,70.87 94.26,71.25 95.4,71.25 99.72,75.56 104.55,75.56 108.74,79.76 108.74,81.41 113.44,86.11 113.44,92.84
+V5S on IN2: 24.71,183.08 28.02,183.08 28.27,182.83 28.27,178 29.03,177.24 34.37,177.24 36.27,175.34 40.84,175.34 46.05,170.13 69.29,170.13 69.93,170.76 79.71,170.76 83.39,174.45 87.71,174.45 88.09,174.07 88.09,169.11 87.2,168.22 87.2,164.29 91.9,159.59 91.9,139.01 87.2,134.32 87.2,133.93 86.18,132.92 69.29,132.92 68.78,133.43 68.78,163.78 67.01,165.56 39.19,165.56 35,169.75 26.11,169.75 23.44,172.42 23.44,181.81
+V5S on IN2: 101.63,51.94 111.53,51.94 111.79,51.69 111.79,49.28 110.39,47.88 92.35,47.88 89.81,50.42 77.5,50.42 74.32,53.59 74.32,56.9 74.57,57.15 90.96,57.15 96.42,62.61 96.42,68.07 95.66,68.83 94.01,68.83 93.75,69.09 93.75,70.36 94.01,70.61 97.43,70.61 99.47,68.58 99.47,54.1
+V5S on VCC: outline of 102 points within 62.48,93.09 127.38,135.13 ; 1 cut-out
+V5S on IN3: 136.65,168.53 136.4,168.28 131.57,168.28 123.44,176.4 90.55,176.4 84.84,170.69 80.92,170.69 80.47,171.15 80.47,180.26 81.43,181.23 135.41,181.23 136.65,179.98
+V5S_ISO on TOP: 78.57,183.88 78.97,184.28 78.97,187.02 78.69,187.3 77.11,187.3 77.09,187.32 75.62,187.32 73.91,189.03 70.28,189.03 70.13,188.87 70.13,187.15 70.47,186.8 70.75,186.8 71.31,186.25 71.31,185.48 71.3,185.47 71.3,184.02 71.44,183.88
+V5S_ISO on TOP: 62.1,185.04 62.23,185.17 63.37,185.17 63.5,185.29 63.5,187.2 63.37,187.32 62.74,187.32 62.61,187.45 62.61,188.09 62.87,188.34 62.87,188.72 62.74,188.85 60.96,188.85 60.83,188.72 60.83,182.7 61.01,182.52 61.9,182.52 62.1,182.73
+V5S_ISO on BOTTOM: 69.6,188.98 69.72,188.85 69.72,186.06 70.1,185.67 73.03,185.67 74.68,187.32 78.87,187.32 78.99,187.2 78.99,184.28 78.49,183.77 69.72,183.77 68.96,183.01 68.33,183.01 67.82,183.51 67.82,185.17 67.69,185.29 66.67,185.29 66.55,185.42 66.55,187.2 66.67,187.32 67.06,187.32 67.18,187.45 67.18,188.85 67.31,188.98
+V5S_ISO on IN1: 61.09,183.77 90.68,183.77 100.71,193.8 100.71,198.75 100.33,199.14 72.26,199.14 71.37,198.25 71.37,194.56 67.18,190.37 61.21,190.37 60.83,189.99 60.83,184.02
+V5SB on TOP (solid shape): 94.18,62.56 94.18,60.66 94.06,60.53 91.26,60.53 91.14,60.66 91.14,62.56 91.26,62.69 94.06,62.69
+V5SB on TOP (solid shape): 83.21,92.71 83.21,90.68 83.08,90.55 80.8,90.55 80.67,90.68 80.67,92.71 80.8,92.84 83.08,92.84
+V5SB on TOP (solid shape): 87.2,97.33 87.2,95.07 87.12,95 85.12,95 84.99,95.12 84.99,97.28 85.12,97.41 87.12,97.41
+V5SB on TOP: 45.29,92.41 44.93,92.76 42.47,92.76 42.39,92.84 42.39,93.04 42.27,93.17 41.45,93.17 41.43,93.19 41.43,93.45 41.45,93.47 47.85,93.47 47.87,93.46 48.3,93.46 48.46,93.29 48.46,91.26 48.21,91.01 45.42,91.01 45.29,91.14
+V5SB on TOP: 70.31,53 74.03,53 74.12,52.91 74.12,51.89 73.91,51.69 70.26,51.69 70.18,51.77 70.18,52.87
+V5SB on TOP: 125.5,90.17 125.76,89.92 125.76,88.77 125.88,88.65 126.52,88.65 126.64,88.52 126.64,80.39 126.52,80.26 120.29,80.26 120.17,80.39 120.17,90.04 120.29,90.17
+V5SB on TOP: 45.29,102.06 44.93,102.41 42.47,102.41 42.39,102.49 42.39,102.69 42.27,102.82 41.45,102.82 41.43,102.84 41.43,103.1 41.45,103.12 47.85,103.12 47.87,103.11 48.3,103.11 48.46,102.95 48.46,100.91 48.21,100.66 45.42,100.66 45.29,100.79
+V5SB on BOTTOM: 85.34,99.69 85.62,99.69 85.67,99.64 85.67,97.64 85.88,97.43 87.1,97.43 87.2,97.33 87.2,95.08 87.12,95 85.12,95 84.99,95.12 84.99,100.71 85.01,100.74 85.19,100.74 85.22,100.71 85.22,99.82
+V5SB on BOTTOM: 86.44,92.51 86.39,92.46 85.75,92.46 85.37,92.08 83.46,92.08 83.34,91.95 83.34,90.68 83.21,90.55 80.8,90.55 80.67,90.68 80.67,92.68 80.77,92.79 86.39,92.79 86.44,92.74
+V5SB on BOTTOM: 45.42,103.07 48.34,103.07 48.46,102.95 48.46,100.79 48.34,100.66 45.42,100.66 45.29,100.79 45.29,102.95
+V5SB on BOTTOM: 122.71,92.46 123.22,91.95 124.99,91.95 125.12,91.82 125.12,81.41 124.87,81.15 118.39,81.15 118.14,81.41 118.14,88.9 119.15,89.92 119.15,92.33 119.28,92.46
+V5SB on BOTTOM: 45.42,93.42 48.34,93.42 48.46,93.29 48.46,91.14 48.34,91.01 45.42,91.01 45.29,91.14 45.29,93.29
+V5SB on BOTTOM: 74.24,51.64 78.05,51.64 78.18,51.51 78.18,49.73 78.05,49.61 72.72,49.61 72.59,49.73 72.59,52.78 72.72,52.91 73.99,52.91 74.12,52.78 74.12,51.77
+V5SB on VCC: outline of 142 points within 25.53,39.88 143.89,109.09 ; 3 cut-outs
+V12SB on TOP: 146.46,88.01 150.65,88.01 150.77,87.88 150.77,83.06 150.65,82.93 146.46,82.93 146.33,83.06 146.33,87.88
+V12SB on TOP: 145.57,96.39 145.57,97.92 146.46,98.81 150.01,98.81 150.14,98.68 150.14,96.39 150.01,96.27 145.69,96.27
+V12SB on TOP: 52.78,165.18 67.51,165.18 67.77,164.92 67.77,159.21 67.64,159.08 64.85,159.08 64.34,158.57 58.75,158.57 58.5,158.32 58.5,157.05 58.37,156.92 52.65,156.92 52.4,157.18 52.4,164.8
+V12SB on BOTTOM: 144.93,96.27 144.68,96.52 143.94,96.52 143.89,96.57 143.89,97 143.92,97.03 145.19,97.03 145.54,97.38 145.54,97.89 146.46,98.81 150.01,98.81 150.14,98.68 150.14,96.39 150.01,96.27
+V12SB on BOTTOM: 146.46,88.01 151.16,88.01 151.28,87.88 151.28,83.06 151.16,82.93 146.46,82.93 146.33,83.06 146.33,87.88
+V12SB on BOTTOM: 51.89,165.05 66.88,165.05 67.13,164.8 67.13,159.08 66.62,158.57 51.77,158.57 51.64,158.7 51.64,164.8
+V12SB on VCC: outline of 147 points within 50.93,58.67 159.49,181.49 ; 1 cut-out
AGND on BOTTOM (solid shape): 151.41,142.98 151.41,141.78 151.28,141.66 150.34,141.66 150.22,141.78 150.22,142.98 150.32,143.08 151.31,143.08
AGND on TOP: 136.53,144.02 137.92,144.02 138.43,144.53 138.68,144.53 138.81,144.4 138.81,142.75 139.19,142.37 143.76,142.37 144.02,142.62 144.02,144.4 144.4,144.78 151,144.78 151.38,144.4 151.38,141.48 149.61,139.7 140.08,139.7 139.95,139.83 139.95,140.59 139.57,140.97 139.57,141.35 139.45,141.48 138.94,141.48 138.56,141.1 137.54,141.1 137.16,140.72 136.78,140.72 136.4,141.1 136.4,143.89
AGND on BOTTOM: 136.6,139.45 137.16,139.45 137.29,139.57 137.29,140.97 137.79,141.48 137.79,142.49 137.72,142.57 136.45,142.57 136.42,142.54 136.42,139.62
AGND on GND1, VCC, GND2: 147.55,156.84 157.63,156.84 158.5,155.98 158.5,144.38 158.14,144.02 152.02,144.02 151.92,144 151.84,143.94 151.33,143.44 151.28,143.35 151.26,143.26 151.26,142.09 148.48,139.32 146.3,139.32 146.21,139.3 146.12,139.24 145.74,138.86 145.69,138.78 145.67,138.68 145.67,138.41 145.31,138.05 137.52,138.05 136.53,139.04 136.53,143.66 136.63,143.76 136.91,143.76 137,143.78 137.09,143.84 137.65,144.4 138.45,144.4 138.56,144.29 138.56,142.88 138.58,142.78 138.63,142.7 139.01,142.31 139.09,142.26 139.19,142.24 143.38,142.24 143.48,142.26 143.56,142.31 143.94,142.7 144,142.78 144.02,142.88 144.02,146.18 144.78,146.18 144.88,146.2 144.96,146.25 145.72,147.01 145.78,147.1 145.8,147.19 145.8,148.36 146.1,148.66 146.16,148.75 146.18,148.84 146.18,155.47
AVDD33_HUB on TOP: 78.87,59.87 80.21,59.87 80.26,59.82 80.26,58.72 80.19,58.65 79.3,58.65 78.82,59.13 78.82,59.82
AVDD33_HUB on IN3: 87.2,72.72 89.61,72.72 91.01,71.32 91.01,61.93 87.45,58.37 84.79,58.37 84.43,58.01 79.35,58.01 79.22,58.14 79.22,59.28 79.83,59.89 82.5,59.89 86.31,63.7 88.09,63.7 88.47,64.08 88.47,66.37 87.96,66.88 87.96,67.39 88.98,68.4 88.98,70.56 87.71,71.83 87.07,71.83 86.94,71.96 86.94,72.47
AVDD_CAM_2V8 on TOP: 125.22,176.78 129.92,176.78 130.05,176.66 130.05,175.51 129.41,174.88 125.22,174.88 125.09,175.01 125.09,176.66
AVDD_CAM_2V8 on BOTTOM: 131.57,178.94 132.46,178.94 132.59,178.82 132.59,177.67 132.46,177.55 131.95,177.55 131.83,177.42 130.68,177.42 128.14,174.88 120.4,174.88 119.19,173.67 119.19,170.75 117.73,169.29 117.73,165.48 115.19,162.94 114.05,162.94 113.92,163.07 113.92,166.62 114.55,167.26 114.55,169.04 113.41,170.18 113.41,173.61 117.73,177.93 127.76,177.93 128.27,178.44 131.06,178.44
DVDD10_HUB on IN1: 88.6,69.8 89.61,69.8 89.87,69.55 89.87,65.99 88.34,64.47 76.53,64.47 75.77,65.23 75.77,68.28 76.02,68.53 78.44,68.53 78.94,68.02 78.94,66.75 79.32,66.37 85.55,66.37 85.8,66.62 88.21,66.62 88.47,66.88 88.47,69.67
DVDD33_HUB on IN3: 85.93,64.59 87.83,64.59 88.21,64.97 88.21,66.12 87.71,66.62 87.71,68.53 88.6,69.42 88.6,70.31 87.45,71.45 84.15,71.45 83.39,72.21 77.67,72.21 75.26,69.8 75.26,68.78 75.39,68.66 78.18,68.66 79.2,69.67 85.55,69.67 85.67,69.55 85.67,64.85
GND on TOP (solid shape): 43.13,31.7 43.13,28.22 43.08,28.17 39.6,28.17 39.52,28.24 39.52,31.7 39.62,31.8 43.03,31.8
GND on TOP (solid shape): 61.42,31.7 61.42,28.22 61.37,28.17 57.89,28.17 57.81,28.24 57.81,31.7 57.91,31.8 61.32,31.8
GND on TOP (solid shape): 72.8,111.76 72.8,109.37 72.53,109.11 68.97,109.11 68.86,109.22 68.86,111.63 69.49,112.27 72.29,112.27
GND on TOP (solid shape): 79.2,58.24 79.2,55.96 79.07,55.83 76.28,55.83 76.15,55.96 76.15,58.24 76.28,58.37 79.07,58.37
GND on TOP (solid shape): 79.71,31.7 79.71,28.22 79.65,28.17 76.17,28.17 76.1,28.24 76.1,31.7 76.2,31.8 79.6,31.8
GND on TOP (solid shape): 83.08,94.61 83.08,93.22 82.96,93.09 80.8,93.09 80.67,93.22 80.67,95.25 80.8,95.38 82.32,95.38
GND on TOP (solid shape): 84.73,97.28 84.73,95.12 84.61,95 83.08,95 82.32,95.76 82.32,97.28 82.45,97.41 84.61,97.41
GND on TOP (solid shape): 96.85,53.8 96.85,51 96.72,50.88 93.04,50.88 92.91,51 92.91,53.8 93.04,53.92 96.72,53.92
GND on TOP (solid shape): 97.99,31.7 97.99,28.22 97.94,28.17 94.46,28.17 94.39,28.24 94.39,31.7 94.49,31.8 97.89,31.8
GND on TOP (solid shape): 116.28,31.7 116.28,28.22 116.23,28.17 112.75,28.17 112.67,28.24 112.67,31.7 112.78,31.8 116.18,31.8
GND on TOP (solid shape): 134.57,32.08 134.57,28.6 134.52,28.55 131.04,28.55 130.96,28.63 130.96,32.08 131.06,32.18 134.47,32.18
GND on TOP (solid shape): 88.8,97.28 88.8,95.48 88.67,95.35 87.53,95.35 87.45,95.43 87.45,97.33 87.53,97.41 88.67,97.41
GND on TOP (solid shape): 94.18,60.22 94.18,59.59 94.13,59.54 92.89,59.54 92.33,58.98 91.26,58.98 91.19,59.05 91.19,60.2 91.26,60.27 94.13,60.27
GND on TOP (solid shape): 47.27,58.93 47.27,57.48 47.14,57.35 46.05,57.35 46,57.4 46,58.67 46.33,59 47.19,59
GND on TOP (solid shape): 73.23,108.79 73.23,108.28 73.1,108.15 66.62,108.15 66.5,108.28 66.5,108.79 66.62,108.92 73.1,108.92
GND on TOP (solid shape): 83.34,90.17 83.34,88.65 83.21,88.52 80.8,88.52 80.67,88.65 80.67,90.17 80.8,90.3 83.21,90.3
GND on TOP (solid shape): 27.28,199.49 27.25,199.24 27.3,198.98 1.02,198.98 1.02,16.94 0.51,16.94 0.51,199.49
GND on TOP (solid shape): 66.5,55.98 66.5,55.7 66.47,55.68 66.47,54.36 66.9,53.92 66.9,53.34 66.78,53.21 62.53,53.21 61.77,52.45 61.16,52.45 61.09,52.53 61.09,55.8 61.37,56.08 66.4,56.08
GND on TOP (solid shape): 159.49,58.7 158.98,58.7 158.98,181.98 159.02,182.02 159.06,182.06 159.06,183.32 159.03,183.35 158.98,183.4 158.98,183.41 158.67,183.72 158.67,185.69 158.98,186 158.98,198.98 75.52,198.98 75.44,199.02 75.42,199.11 75.44,199.24 75.44,199.38 75.46,199.46 75.54,199.49 159.49,199.49
GND on TOP (solid shape): 128.52,52.4 130.94,52.4 131.65,53.11 131.65,53.11 131.74,53.08 131.83,53.07 131.91,53.08 132,53.11 132.13,53.11 132.26,53.24 134.54,53.24 134.61,53.18 134.61,53 134.92,52.68 134.92,49.81 134.99,49.75 134.99,45.83 135.41,45.42 135.41,44.72 135.41,44.5 135.33,44.42 129.84,44.42 129.75,44.45 129.67,44.46 129.58,44.45 129.49,44.42 127.43,44.42 126.92,44.93 126.92,52.02 127,52.09 127,53.34 127.58,53.34
GND on TOP (solid shape): outline of 137 points within 56.34,89.94 69.8,101.12
GND on TOP (solid shape): outline of 254 points within 6.75,183.5 15.75,192.5
GND on TOP (solid shape): outline of 254 points within 6.75,23.6 15.75,32.6
GND on TOP (solid shape): outline of 254 points within 144.25,160.6 153.25,169.6
GND on TOP (solid shape): outline of 254 points within 144.25,23.6 153.25,32.6
GND on BOTTOM (solid shape): 35.26,116.66 35.26,100.15 35,99.9 29.79,99.9 29.16,100.53 29.16,116.54 29.54,116.92 35,116.92
GND on BOTTOM (solid shape): 75.64,158.19 75.64,154.38 74.88,153.62 71.58,153.62 70.82,154.38 70.82,158.7 71.07,158.95 74.88,158.95
GND on BOTTOM (solid shape): 94.89,97.03 94.89,93.85 94.64,93.6 89.94,93.6 89.69,93.85 89.69,96.9 90.58,97.79 94.13,97.79
GND on BOTTOM (solid shape): 132.94,50.62 132.94,46.96 132.87,46.89 129.29,46.89 129.18,46.99 129.18,50.65 129.26,50.72 132.84,50.72
GND on BOTTOM (solid shape): 152.91,143.03 152.91,141.78 152.81,141.68 151.74,141.68 151.66,141.76 151.66,143.03 151.74,143.1 152.83,143.1
GND on BOTTOM (solid shape): 3.61,19.13 3.61,17.02 3.48,16.89 1.7,16.89 1.57,17.02 1.57,19.13 1.73,19.28 3.45,19.28
GND on BOTTOM (solid shape): 23.57,168.1 23.57,165.18 24.33,164.41 24.33,156.79 22.3,154.76 10.87,154.76 10.36,155.27 10.36,162.38 16.33,168.35 23.32,168.35
GND on BOTTOM (solid shape): 47.45,70.18 47.45,68.28 47.19,68.02 45.54,68.02 44.78,68.78 42.62,68.78 41.99,69.42 41.99,71.96 42.62,72.59 45.03,72.59
GND on BOTTOM (solid shape): 83.34,90.17 83.34,88.65 83.21,88.52 80.8,88.52 80.67,88.65 80.67,90.17 80.8,90.3 83.21,90.3
GND on BOTTOM (solid shape): 96.42,68.45 96.42,65.28 95.78,64.64 93.37,64.64 93.24,64.77 93.24,68.58 93.37,68.71 96.16,68.71
GND on BOTTOM (solid shape): 27.28,199.49 27.25,199.24 27.3,198.98 1.02,198.98 1.02,16.92 0.51,16.92 0.51,199.49
GND on BOTTOM (solid shape): 84.73,98.27 84.73,95.12 84.61,95 83.11,95 82.37,95.73 82.37,97.66 82.5,97.79 83.92,97.79 84.02,97.89 84.02,98.27 84.07,98.32 84.68,98.32
GND on BOTTOM (solid shape): 83.21,94.46 83.21,94.11 83.59,93.73 83.97,93.73 84.1,93.6 84.1,93.09 84.02,93.01 83.16,93.01 83.08,93.09 80.8,93.09 80.67,93.22 80.67,95.25 80.8,95.38 82.3,95.38
GND on BOTTOM (solid shape): 159.49,58.7 158.98,58.7 158.98,176.09 159.28,176.39 159.28,177.49 158.98,177.79 158.98,181.91 159.14,182.07 159.14,183.31 158.74,183.71 158.74,185.12 158.98,185.36 158.98,198.98 75.5,198.98 75.5,199.49 159.49,199.49
GND on BOTTOM (solid shape): outline of 254 points within 6.75,183.5 15.75,192.5
GND on BOTTOM (solid shape): outline of 254 points within 6.75,23.6 15.75,32.6
GND on BOTTOM (solid shape): outline of 254 points within 144.25,160.6 153.25,169.6
GND on BOTTOM (solid shape): outline of 254 points within 144.25,23.6 153.25,32.6
GND on IN1 (solid shape): 43.13,31.7 43.13,28.22 43.08,28.17 39.6,28.17 39.52,28.24 39.52,31.7 39.62,31.8 43.03,31.8
GND on IN1 (solid shape): 50.93,25.53 50.93,22 50.8,21.87 47.22,21.87 46.96,22.12 46.96,25.53 47.09,25.65 50.8,25.65
GND on IN1 (solid shape): 61.42,31.7 61.42,28.22 61.37,28.17 57.89,28.17 57.81,28.24 57.81,31.7 57.91,31.8 61.32,31.8
GND on IN1 (solid shape): 69.22,25.53 69.22,22 69.09,21.87 65.51,21.87 65.25,22.12 65.25,25.53 65.38,25.65 69.09,25.65
GND on IN1 (solid shape): 79.71,31.7 79.71,28.22 79.65,28.17 76.17,28.17 76.1,28.24 76.1,31.7 76.2,31.8 79.6,31.8
GND on IN1 (solid shape): 87.5,25.53 87.5,22 87.38,21.87 83.79,21.87 83.54,22.12 83.54,25.53 83.67,25.65 87.38,25.65
GND on IN1 (solid shape): 97.99,31.7 97.99,28.22 97.94,28.17 94.46,28.17 94.39,28.24 94.39,31.7 94.49,31.8 97.89,31.8
GND on IN1 (solid shape): 105.79,25.53 105.79,22 105.66,21.87 102.08,21.87 101.83,22.12 101.83,25.53 101.96,25.65 105.66,25.65
GND on IN1 (solid shape): 116.28,31.7 116.28,28.22 116.23,28.17 112.75,28.17 112.67,28.24 112.67,31.7 112.78,31.8 116.18,31.8
GND on IN1 (solid shape): 124.08,25.53 124.08,22 123.95,21.87 120.37,21.87 120.12,22.12 120.12,25.53 120.24,25.65 123.95,25.65
GND on IN1 (solid shape): 132.74,50.42 132.74,47.24 132.61,47.12 129.57,47.12 129.44,47.24 129.44,50.42 129.57,50.55 132.61,50.55
GND on IN1 (solid shape): 134.57,32.08 134.57,28.6 134.52,28.55 131.04,28.55 130.96,28.63 130.96,32.08 131.06,32.18 134.47,32.18
GND on IN1 (solid shape): 136.04,60.07 136.04,57.15 135.92,57.02 132.11,57.02 131.98,57.15 131.98,60.07 132.11,60.2 135.92,60.2
GND on IN1 (solid shape): 72.8,111.76 72.8,109.22 72.54,108.97 69.11,108.97 68.86,109.22 68.86,111.63 69.49,112.27 72.29,112.27
GND on IN1 (solid shape): 141.94,25.83 142.24,25.1 142.24,22 142.11,21.87 138.53,21.87 138.28,22.12 138.28,25.53 138.3,25.55 138.3,25.76 138.58,26.04 141.73,26.04
GND on IN1 (solid shape): 27.32,199.49 27.3,199.38 27.29,199.26 27.3,199.12 27.34,198.98 1.02,198.98 1.02,17.11 0.51,17.11 0.51,199.49
GND on IN1 (solid shape): 159.49,58.72 158.98,58.72 158.98,198.98 53.76,198.98 53.8,199.12 53.81,199.26 53.8,199.38 53.78,199.49 159.49,199.49
GND on IN2 (solid shape): 34.16,28.27 34.16,24.92 34.04,24.79 30.45,24.79 30.2,25.04 30.2,28.45 30.33,28.57 33.86,28.57
GND on IN2 (solid shape): 43.13,31.7 43.13,28.22 43.08,28.17 39.6,28.17 39.52,28.24 39.52,31.7 39.62,31.8 43.03,31.8
GND on IN2 (solid shape): 50.93,25.53 50.93,22 50.8,21.87 47.22,21.87 46.96,22.12 46.96,25.53 47.09,25.65 50.8,25.65
GND on IN2 (solid shape): 61.42,31.7 61.42,28.22 61.37,28.17 57.89,28.17 57.81,28.24 57.81,31.7 57.91,31.8 61.32,31.8
GND on IN2 (solid shape): 69.22,25.53 69.22,22 69.09,21.87 65.51,21.87 65.25,22.12 65.25,25.53 65.38,25.65 69.09,25.65
GND on IN2 (solid shape): 75.64,158.19 75.64,154.38 74.88,153.62 71.58,153.62 70.82,154.38 70.82,158.7 71.07,158.95 74.88,158.95
GND on IN2 (solid shape): 79.71,31.7 79.71,28.22 79.65,28.17 76.17,28.17 76.1,28.24 76.1,31.7 76.2,31.8 79.6,31.8
GND on IN2 (solid shape): 87.5,25.53 87.5,22 87.38,21.87 83.79,21.87 83.54,22.12 83.54,25.53 83.67,25.65 87.38,25.65
GND on IN2 (solid shape): 94.89,97.03 94.89,93.85 94.64,93.6 89.94,93.6 89.69,93.85 89.69,96.9 90.58,97.79 94.13,97.79
GND on IN2 (solid shape): 97.99,31.7 97.99,28.22 97.94,28.17 94.46,28.17 94.39,28.24 94.39,31.7 94.49,31.8 97.89,31.8
GND on IN2 (solid shape): 105.79,25.53 105.79,22 105.66,21.87 102.08,21.87 101.83,22.12 101.83,25.53 101.96,25.65 105.66,25.65
GND on IN2 (solid shape): 116.28,31.37 116.28,28.22 116.23,28.17 112.75,28.17 112.67,28.24 112.67,31.37 112.8,31.5 116.15,31.5
GND on IN2 (solid shape): 124.08,25.53 124.08,22 123.95,21.87 120.37,21.87 120.12,22.12 120.12,25.53 120.24,25.65 123.95,25.65
GND on IN2 (solid shape): 132.74,50.42 132.74,47.24 132.61,47.12 129.57,47.12 129.44,47.24 129.44,50.42 129.57,50.55 132.61,50.55
GND on IN2 (solid shape): 134.57,32.08 134.57,28.6 134.52,28.55 131.04,28.55 130.96,28.63 130.96,32.08 131.06,32.18 134.47,32.18
GND on IN2 (solid shape): 136.04,60.07 136.04,57.15 135.92,57.02 132.11,57.02 131.98,57.15 131.98,60.07 132.11,60.2 135.92,60.2
GND on IN2 (solid shape): 47.45,70.18 47.45,68.28 47.19,68.02 45.54,68.02 44.78,68.78 42.62,68.78 41.99,69.42 41.99,71.96 42.62,72.59 45.03,72.59
GND on IN2 (solid shape): 72.8,111.76 72.8,109.22 72.54,108.97 69.11,108.97 68.86,109.22 68.86,111.63 69.49,112.27 72.29,112.27
GND on IN2 (solid shape): 96.42,68.45 96.42,65.28 95.78,64.64 93.37,64.64 93.24,64.77 93.24,68.58 93.37,68.71 96.16,68.71
GND on IN2 (solid shape): 27.32,199.49 27.3,199.38 27.29,199.26 27.3,199.12 27.34,198.98 1.02,198.98 1.02,16.92 0.51,16.92 0.51,199.49
GND on IN2 (solid shape): 142.37,25.81 142.37,22 142.24,21.87 138.66,21.87 138.2,22.33 138.2,24.82 138.79,25.4 139.47,25.4 139.98,25.91 142.27,25.91
GND on IN2 (solid shape): 159.49,58.7 158.98,58.7 158.98,198.98 75.34,198.98 75.39,199.13 75.4,199.29 75.4,199.39 75.38,199.49 159.49,199.49
GND on IN3 (solid shape): 50.93,25.53 50.93,22 50.8,21.87 47.22,21.87 46.96,22.12 46.96,25.53 47.09,25.65 50.8,25.65
GND on IN3 (solid shape): 69.22,25.53 69.22,22 69.09,21.87 65.51,21.87 65.25,22.12 65.25,25.53 65.38,25.65 69.09,25.65
GND on IN3 (solid shape): 75.64,158.19 75.64,154.38 74.88,153.62 71.58,153.62 70.82,154.38 70.82,158.7 71.07,158.95 74.88,158.95
GND on IN3 (solid shape): 87.5,25.53 87.5,22 87.38,21.87 83.79,21.87 83.54,22.12 83.54,25.53 83.67,25.65 87.38,25.65
GND on IN3 (solid shape): 94.61,97.31 94.61,94.28 93.93,93.6 89.94,93.6 89.69,93.85 89.69,96.9 90.58,97.79 94.13,97.79
GND on IN3 (solid shape): 105.79,25.53 105.79,22 105.66,21.87 102.08,21.87 101.83,22.12 101.83,25.53 101.96,25.65 105.66,25.65
GND on IN3 (solid shape): 124.08,25.53 124.08,22 123.95,21.87 120.37,21.87 120.12,22.12 120.12,25.53 120.24,25.65 123.95,25.65
GND on IN3 (solid shape): 47.45,70.18 47.45,68.28 47.19,68.02 45.54,68.02 44.78,68.78 42.62,68.78 41.99,69.42 41.99,71.96 42.62,72.59 45.03,72.59
GND on IN3 (solid shape): 72.8,111.76 72.8,109.22 72.54,108.97 69.11,108.97 68.86,109.22 68.86,111.63 69.49,112.27 72.29,112.27
GND on IN3 (solid shape): 96.42,68.45 96.42,65.28 95.78,64.64 93.37,64.64 93.24,64.77 93.24,68.58 93.37,68.71 96.16,68.71
GND on IN3 (solid shape): 27.32,199.49 27.3,199.38 27.29,199.26 27.3,199.12 27.34,198.98 1.02,198.98 1.02,16.89 0.51,16.89 0.51,199.49
GND on IN3 (solid shape): 142.39,25.91 142.39,25.55 142.37,25.53 142.37,22 142.24,21.87 138.43,21.87 138.2,22.1 138.2,24.82 138.46,25.07 138.46,25.91 138.58,26.04 142.27,26.04
GND on IN3 (solid shape): 159.49,58.7 158.98,58.7 158.98,198.98 75.34,198.98 75.39,199.13 75.4,199.29 75.4,199.39 75.38,199.49 159.49,199.49
GND on TOP: 137.57,108.08 142.01,108.08 142.14,107.95 142.14,106.68 142.01,106.55 137.57,106.55 137.44,106.68 137.44,107.95
GND on TOP: 126.44,35.66 126.44,35.23 126.39,35.18 124.79,35.18 124.69,35.28 124.69,37.11 124.74,37.16 125.02,37.16 125.04,37.13 125.04,35.86 125.15,35.76 126.34,35.76
GND on TOP: 141.25,147.32 142.37,147.32 142.62,147.57 142.62,149.73 142.37,149.99 141.22,149.99 141.1,150.11 141.1,151.38 141.22,151.51 143.76,151.51 143.89,151.38 143.89,146.69 143.51,146.3 143.51,142.75 143.38,142.62 139.32,142.62 139.19,142.75 139.19,143.28 138.94,143.54 138.94,144.48 139.19,144.73 139.19,147.19 139.2,147.21 139.2,148.2 139.47,148.46 140.87,148.46 141,148.34 141,147.57
GND on TOP: 150.85,41.48 152.63,41.48 152.76,41.35 152.76,39.4 152.6,39.24 150.98,39.24 150.77,39.45 150.77,41.4
GND on TOP: 39.57,181.81 41.99,181.81 42.11,181.69 42.11,178.51 41.86,178.26 39.57,178.26 39.45,178.38 39.45,181.69
GND on TOP: 115.21,101.09 116.51,101.09 116.61,100.99 116.61,98.37 116.36,98.12 115.19,98.12 115.01,98.3 115.01,100.89
GND on TOP: 41.35,91.14 41.48,91.01 41.48,88.85 41.35,88.72 38.81,88.72 38.68,88.85 38.68,91.01 38.81,91.14
GND on TOP: 101.96,25.65 105.49,25.65 105.79,25.35 105.79,22 105.66,21.87 102.08,21.87 101.83,22.12 101.83,25.53
GND on TOP: 120.24,25.65 123.77,25.65 124.08,25.35 124.08,22 123.95,21.87 120.37,21.87 120.12,22.12 120.12,25.53
GND on TOP: 68.15,181.66 70.82,181.66 70.89,181.58 70.89,179.35 70.69,179.15 68.2,179.15 67.87,179.48 67.87,181.38
GND on TOP: 55.12,174.24 59.31,174.24 59.44,174.12 59.44,172.59 59.31,172.47 55.12,172.47 54.99,172.59 54.99,174.12
GND on TOP: 111.56,26.11 118.57,26.11 118.77,26.31 118.77,29.39 118.06,30.1 118.06,32.51 119,33.45 119,34.04 118.92,34.11 110.59,34.11 110.08,33.6 110.08,25.7 110.16,25.63 111.07,25.63
GND on TOP: 38.3,173.3 43.26,173.3 43.38,173.18 43.38,167.72 43.26,167.59 38.3,167.59 38.05,167.84 38.05,173.05
GND on TOP: 18.8,119.71 18.8,124.46 18.92,124.59 21.08,124.59 21.21,124.46 21.21,119.76 21.03,119.58 18.92,119.58
GND on TOP: 86.87,169.16 125.86,169.16 125.98,169.04 125.98,167.51 125.86,167.39 86.87,167.39 86.74,167.51 86.74,169.04
GND on TOP: 70.31,53.95 71.7,53.95 72.19,54.43 73.99,54.43 74.12,54.31 74.12,53.29 74.03,53.2 70.31,53.2 70.18,53.33 70.18,53.82
GND on TOP: 133.12,93.22 138.46,93.22 138.58,93.09 138.58,91.44 138.46,91.31 133.12,91.31 132.99,91.44 132.99,93.09
GND on TOP: 19.96,197.87 23.14,197.87 23.52,197.49 23.52,192.91 23.39,192.79 20.09,192.79 19.84,193.04 19.84,197.74
GND on TOP: 53.29,35.31 53.29,34.87 53.24,34.82 51.64,34.82 51.54,34.92 51.54,36.75 51.59,36.8 51.87,36.8 51.89,36.78 51.89,35.51 51.99,35.41 53.19,35.41
GND on TOP: 56.69,26.11 63.7,26.11 63.91,26.31 63.91,29.39 63.2,30.1 63.2,32.51 64.14,33.45 64.14,34.04 64.06,34.11 55.73,34.11 55.22,33.6 55.22,25.7 55.3,25.63 56.21,25.63
GND on TOP: 125.78,42.47 126.21,42.47 126.26,42.42 126.26,40.82 126.16,40.72 124.33,40.72 124.28,40.77 124.28,41.05 124.31,41.07 125.58,41.07 125.68,41.17 125.68,42.37
GND on TOP: 25.68,16.76 27.33,16.76 27.46,16.64 27.46,14.48 27.33,14.35 25.55,14.35 25.43,14.48 25.43,16.51
GND on TOP: 30.33,28.57 33.86,28.57 34.16,28.27 34.16,24.92 34.04,24.79 30.45,24.79 30.2,25.04 30.2,28.45
GND on TOP: 49.89,98.45 51.08,98.45 51.26,98.63 51.26,100.36 51.79,100.89 51.79,102.72 51.71,102.79 49.94,102.79 49.76,102.62 49.76,98.58
GND on TOP: 41.35,100.79 41.48,100.66 41.48,98.5 41.35,98.37 38.81,98.37 38.68,98.5 38.68,100.66 38.81,100.79
GND on TOP: 117.37,87.25 119.41,87.25 119.53,87.12 119.53,80.39 119.41,80.26 117.37,80.26 117.25,80.39 117.25,87.12
GND on TOP: 47.09,25.65 50.62,25.65 50.93,25.35 50.93,22 50.8,21.87 47.22,21.87 46.96,22.12 46.96,25.53
GND on TOP: 82.3,181.86 84.2,181.86 84.33,181.74 84.33,179.96 84.2,179.83 82.3,179.83 82.17,179.96 82.17,181.74
GND on TOP: 65.38,25.65 68.91,25.65 69.22,25.35 69.22,22 69.09,21.87 65.51,21.87 65.25,22.12 65.25,25.53
GND on TOP: 147.52,12.85 158.14,12.85 158.45,13.16 158.45,34.7 157.96,35.18 155.24,35.18 153.16,37.26 153.16,40.97 152.65,41.48 150.88,41.48 149,39.6 145.16,39.6 143.48,37.92 143.48,30.68 144.22,29.95 144.22,20.62 143.81,20.22 133.17,20.22 132.92,19.96 132.92,18.29 133.12,18.08 145.64,18.08 146.74,16.99 146.74,13.64
GND on TOP: 83.67,25.65 87.2,25.65 87.5,25.35 87.5,22 87.38,21.87 83.79,21.87 83.54,22.12 83.54,25.53
GND on TOP: 38.4,26.11 45.42,26.11 45.62,26.31 45.62,29.39 44.91,30.1 44.91,32.51 45.85,33.45 45.85,34.04 45.77,34.11 37.44,34.11 36.93,33.6 36.93,25.7 37.01,25.63 37.92,25.63
GND on TOP: 3.61,17.02 3.48,16.89 1.7,16.89 1.57,17.02 1.57,19.13 1.73,19.28 3.45,19.28 3.61,19.13
GND on TOP: 29.54,116.92 35,116.92 35.26,116.66 35.26,100.15 35,99.9 29.79,99.9 29.16,100.53 29.16,116.54
GND on TOP: 58.52,103.68 65.07,103.68 65.2,103.56 65.2,102.01 65.1,101.9 58.88,101.9 58.8,101.98 58.8,102.92 58.47,103.25 58.47,103.63
GND on TOP: 44.65,96.09 48.21,96.09 48.46,95.83 48.46,93.93 48.34,93.8 44.78,93.8 44.65,93.68 43.89,93.68 43.76,93.8 43.76,94.31 43.89,94.44 44.4,94.44 44.53,94.56 44.53,95.96
GND on TOP: 71.58,35.31 71.58,34.87 71.53,34.82 69.93,34.82 69.82,34.92 69.82,36.75 69.88,36.8 70.15,36.8 70.18,36.78 70.18,35.51 70.28,35.41 71.48,35.41
GND on TOP: 77.09,174.37 78.84,174.37 78.99,174.22 78.99,171.7 78.74,171.45 70.03,171.45 69.85,171.63 69.85,172.9 70.15,173.2 75.92,173.2
GND on TOP: 38.18,120.47 35.38,120.47 35.26,120.6 35.26,124.28 35.38,124.41 38.3,124.41 38.43,124.28 38.43,120.73
GND on TOP: 18.24,38.23 18.24,37.8 18.19,37.74 16.59,37.74 16.48,37.85 16.48,39.67 16.54,39.73 16.81,39.73 16.84,39.7 16.84,38.43 16.94,38.33 18.14,38.33
GND on TOP: 133.1,144.55 133.83,144.55 133.96,144.68 133.96,146.74 134.72,147.5 134.72,151.46 134.67,151.51 133.91,151.51 133.02,150.62 133.02,144.63
GND on TOP: 23.62,184.66 25.27,184.66 25.4,184.53 25.4,178.56 25.27,178.44 24.64,178.44 23.5,179.58 23.5,184.53
GND on TOP: 97.87,60.27 103.2,60.27 103.33,60.15 103.33,57.61 103.2,57.48 97.74,57.48 97.61,57.61 97.61,60.02
GND on TOP: 108.15,35.28 108.15,34.85 108.1,34.8 106.5,34.8 106.4,34.9 106.4,36.73 106.45,36.78 106.73,36.78 106.76,36.75 106.76,35.48 106.86,35.38 108.05,35.38
GND on TOP: 117.22,131.44 119.51,131.44 119.63,131.32 119.63,128.91 119.51,128.78 117.22,128.78 117.09,128.91 117.09,131.32
GND on TOP: 116.99,92.96 123.34,92.96 123.85,93.47 123.85,100.33 123.98,100.46 125.25,100.46 125.37,100.33 125.37,91.31 124.61,90.55 116.99,90.55 116.87,90.68 116.87,92.84
GND on TOP: 150.75,185.67 154.18,185.67 154.43,185.93 154.43,190.75 154.05,191.13 151.64,191.13 151.51,191.26 151.51,193.55 150.62,194.44 147.57,194.44 147.45,194.56 147.45,197.36 147.83,197.74 156.46,197.74 156.97,197.23 156.97,175.77 156.72,175.51 151.89,175.51 151.51,175.9 151.51,181.1 151.26,181.36 150.62,181.36 150.5,181.48 150.5,185.42
GND on TOP: 42.55,129.92 44.07,129.92 44.2,129.79 44.2,127 44.07,126.87 42.55,126.87 42.42,127 42.42,129.79
GND on TOP: 133.35,130.68 135.89,130.68 136.4,130.18 148.97,130.18 149.1,130.05 149.1,129.29 148.84,129.03 146.18,129.03 145.92,128.78 134.62,128.78 133.22,130.18 133.22,130.56
GND on TOP: 36.96,157.23 37.08,157.1 37.08,153.54 36.96,153.42 33.27,153.42 33.02,153.67 33.02,156.97 33.27,157.23
GND on TOP: 150.01,96.01 150.14,95.89 150.14,93.47 149.89,93.22 145.82,93.22 145.57,93.47 145.57,95.89 145.69,96.01
GND on TOP: 4.62,183.18 4.52,183.08 1.35,183.08 1.24,183.18 1.24,186.61 1.4,186.77 4.52,186.77 4.62,186.66
GND on TOP: 138.46,98.4 138.46,102.44 138.33,102.57 131.65,102.57 131.47,102.39 131.47,100.05 133.25,98.27 138.33,98.27
GND on TOP: 75.41,97.31 76.86,97.31 76.99,97.18 76.99,94.69 76.89,94.59 75.44,94.59 75.34,94.69 75.34,97.23
GND on TOP: 21.64,29.03 28.65,29.03 28.85,29.24 28.85,32.31 28.14,33.02 28.14,35.43 29.08,36.37 29.08,36.96 29.01,37.03 20.68,37.03 20.17,36.53 20.17,28.63 20.24,28.55 21.16,28.55
GND on TOP: 108.79,49.81 110.13,49.81 110.26,49.68 110.26,48.46 110.13,48.34 108.81,48.34 108.71,48.44 108.71,49.73
GND on TOP: 132.72,60.2 135.38,60.2 136.14,59.44 136.14,57.02 136.02,56.9 132.21,56.9 131.95,57.15 131.95,59.44
GND on TOP: 35,35.31 35,34.87 34.95,34.82 33.35,34.82 33.25,34.92 33.25,36.75 33.3,36.8 33.58,36.8 33.6,36.78 33.6,35.51 33.71,35.41 34.9,35.41
GND on TOP: 12.45,165.35 22.99,165.35 23.24,165.1 23.24,156.84 22.99,156.59 11.68,156.59 11.3,156.97 11.3,164.21
GND on TOP: 74.98,26.11 81.99,26.11 82.19,26.31 82.19,29.39 81.48,30.1 81.48,32.51 82.42,33.45 82.42,34.04 82.35,34.11 74.02,34.11 73.51,33.6 73.51,25.7 73.58,25.63 74.5,25.63
GND on TOP: 127.15,89.28 131.6,89.28 131.98,88.9 131.98,83.57 132.99,82.55 133.63,82.55 134.14,83.06 134.14,84.2 134.26,84.33 137.57,84.33 137.95,83.95 141.38,83.95 141.5,83.82 141.5,81.66 141.38,81.53 134.9,81.53 133.63,80.26 127.15,80.26 127.03,80.39 127.03,89.15
GND on TOP: 139.98,103.5 142.14,103.5 142.27,103.63 142.27,105.79 142.14,105.92 139.98,105.92 139.85,105.79 139.85,103.63
GND on TOP: 44.65,105.74 48.21,105.74 48.46,105.49 48.46,103.58 48.34,103.45 44.78,103.45 44.65,103.33 43.89,103.33 43.76,103.45 43.76,103.96 43.89,104.09 44.4,104.09 44.53,104.22 44.53,105.61
GND on TOP: 125.22,178.82 127.89,178.82 128.02,178.69 128.02,177.16 127.89,177.04 125.22,177.04 125.09,177.16 125.09,178.69
GND on TOP: 93.27,26.11 100.28,26.11 100.48,26.31 100.48,29.39 99.77,30.1 99.77,32.51 100.71,33.45 100.71,34.04 100.63,34.11 92.3,34.11 91.8,33.6 91.8,25.7 91.87,25.63 92.79,25.63
GND on TOP: 138.53,26.04 142.06,26.04 142.37,25.73 142.37,22.38 142.24,22.25 138.66,22.25 138.4,22.5 138.4,25.91
GND on TOP: 129.84,26.49 136.86,26.49 137.06,26.7 137.06,29.77 136.35,30.48 136.35,32.89 137.29,33.83 137.29,34.42 137.21,34.49 128.88,34.49 128.37,33.99 128.37,26.09 128.45,26.01 129.36,26.01
GND on TOP: 89.87,35.31 89.87,34.87 89.81,34.82 88.21,34.82 88.11,34.92 88.11,36.75 88.16,36.8 88.44,36.8 88.47,36.78 88.47,35.51 88.57,35.41 89.76,35.41
GND on BOTTOM: 12.83,181.36 13.84,181.36 13.97,181.23 13.97,178.69 13.84,178.56 12.83,178.56 12.7,178.69 12.7,181.23
GND on BOTTOM: 106.5,35.36 107.87,35.36 108.1,35.13 108.1,33.91 108.05,33.86 106.4,33.86 106.35,33.91 106.35,35.2
GND on BOTTOM: 68.33,182.5 68.83,182.5 69.6,181.74 70.74,181.74 70.87,181.61 70.87,180.09 69.72,178.94 68.45,178.94 67.82,179.58 67.82,181.99
GND on BOTTOM: 88.21,35.36 89.59,35.36 89.81,35.13 89.81,33.91 89.76,33.86 88.11,33.86 88.06,33.91 88.06,35.2
GND on BOTTOM: 69.93,35.36 71.3,35.36 71.53,35.13 71.53,33.91 71.48,33.86 69.82,33.86 69.77,33.91 69.77,35.2
GND on BOTTOM: 82.5,182.32 84.18,182.32 84.33,182.17 84.33,179.96 84.2,179.83 82.45,179.83 82.3,179.98 82.3,182.12
GND on BOTTOM: 125.68,40.84 125.68,42.21 125.91,42.44 127.13,42.44 127.18,42.39 127.18,40.74 127.13,40.69 125.83,40.69
GND on BOTTOM: 6.17,47.96 8.2,47.96 8.33,47.83 8.33,46.18 8.2,46.05 6.17,46.05 6.05,46.18 6.05,47.83
GND on BOTTOM: 45.42,105.74 48.21,105.74 48.46,105.49 48.46,103.58 48.34,103.45 45.42,103.45 45.29,103.58 45.29,105.61
GND on BOTTOM: 124.79,35.74 126.16,35.74 126.39,35.51 126.39,34.29 126.34,34.24 124.69,34.24 124.64,34.29 124.64,35.59
GND on BOTTOM: 134.14,84.33 140.87,84.33 141.5,83.69 141.5,81.66 141.38,81.53 134.65,81.53 133.5,80.39 127.79,80.39 127.66,80.52 127.66,82.42 127.79,82.55 133.63,82.55 134.01,82.93 134.01,84.2
GND on BOTTOM: 22.3,123.9 22.3,117.3 22.17,117.17 19.91,117.17 18.39,115.65 17.35,115.65 17.09,115.9 17.09,119.56 17.17,119.63 18.69,119.63 18.95,119.89 18.95,130.63 19.2,130.89 21.54,130.89 21.74,130.68 21.74,124.46
GND on BOTTOM: 37.03,173.3 43.13,173.3 45.92,170.51 63.58,170.51 64.34,169.75 64.34,165.81 64.08,165.56 51.64,165.56 51.13,165.05 51.13,158.45 51.51,158.06 60.4,158.06 60.66,157.81 60.66,154.89 60.27,154.51 42.75,154.51 40.59,152.35 33.35,152.35 33.1,152.6 33.1,156.92 33.35,157.18 36.4,157.18 36.78,157.56 36.78,173.05
GND on BOTTOM: 124.05,97.05 125.3,97.05 125.43,97.18 125.43,100.36 125.32,100.46 123.98,100.46 123.88,100.36 123.88,97.23
GND on BOTTOM: 50.24,150.19 52.91,150.19 53.04,150.06 53.04,146.25 52.91,146.13 51.89,146.13 51.64,145.87 51.64,144.22 51.51,144.09 50.11,144.09 49.99,144.22 49.99,145.62 49.73,145.87 49.73,148.29 50.11,148.67 50.11,150.06
GND on BOTTOM: 13.97,79.81 17.04,79.81 17.25,79.6 17.25,69.77 17.02,69.55 13.79,69.55 13.67,69.67 13.67,71.75 13.36,72.06 11.43,72.06 11.18,72.31 11.18,78.59 11.38,78.79 12.95,78.79
GND on BOTTOM: 25.4,177.8 25.27,177.67 24.13,177.67 22.23,179.58 19.3,179.58 19.18,179.71 19.18,182.88 19.3,183.01 22.35,183.01 23.11,183.77 23.11,184.53 23.24,184.66 25.27,184.66 25.4,184.53
GND on BOTTOM: 108.48,88.01 111.4,88.01 111.53,87.88 111.53,83.06 111.4,82.93 108.48,82.93 108.36,83.06 108.36,87.88
GND on BOTTOM: 20.24,198.02 23.09,198.02 23.22,197.89 23.22,195.81 23.06,195.66 20.27,195.66 20.04,195.88 20.04,197.82
GND on BOTTOM: 120.02,170.81 124.97,170.81 125.35,170.43 125.35,167 125.09,166.75 118.62,166.75 118.36,167 118.36,169.16
GND on BOTTOM: 6.17,59.26 8.2,59.26 8.33,59.13 8.33,57.48 8.2,57.35 6.17,57.35 6.05,57.48 6.05,59.13
GND on BOTTOM: 87.5,97.49 88.8,97.49 88.87,97.41 88.87,95.4 88.75,95.28 87.55,95.28 87.45,95.38 87.45,97.43
GND on BOTTOM: 64.06,147.68 67.21,147.68 67.34,147.55 67.34,143.36 67.59,143.1 69.55,143.1 69.65,143 69.65,138.71 69.39,138.46 64.06,138.46 63.88,138.63 63.88,147.5
GND on BOTTOM: 21.16,59.26 23.19,59.26 23.32,59.13 23.32,57.48 23.19,57.35 21.16,57.35 21.03,57.48 21.03,59.13
GND on BOTTOM: 45.42,96.09 48.21,96.09 48.46,95.83 48.46,93.93 48.34,93.8 45.42,93.8 45.29,93.93 45.29,95.96
GND on BOTTOM: 151.36,120.02 156.49,120.02 156.69,119.81 156.69,115.49 156.21,115.01 152.93,115.01 152.63,115.32 152.63,117.3 151.23,118.69 151.23,119.89
GND on BOTTOM: 21.16,47.96 23.19,47.96 23.32,47.83 23.32,46.18 23.19,46.05 21.16,46.05 21.03,46.18 21.03,47.83
GND on BOTTOM: 13.67,59.26 15.7,59.26 15.82,59.13 15.82,57.48 15.7,57.35 13.67,57.35 13.54,57.48 13.54,59.13
GND on BOTTOM: 101.75,84.33 102.9,84.33 103.02,84.2 103.02,79.88 102.9,79.76 101.63,79.76 101.5,79.88 101.5,80.77 101.63,80.9 101.63,84.2
GND on BOTTOM: 39.09,100.94 41.3,100.94 41.43,100.81 41.43,98.3 41.27,98.15 38.89,98.15 38.73,98.3 38.73,100.58
GND on BOTTOM: 149.76,64.26 149.76,62.87 149.63,62.74 147.85,62.74 147.73,62.87 147.73,64.26 147.85,64.39 149.63,64.39
GND on BOTTOM: 136.17,108.08 143.66,108.08 143.79,107.95 143.79,106.68 143.66,106.55 136.17,106.55 136.04,106.68 136.04,107.95
GND on BOTTOM: 39.01,91.26 41.35,91.26 41.45,91.16 41.45,88.57 41.33,88.44 38.94,88.44 38.79,88.6 38.79,91.03
GND on BOTTOM: 1.42,186.84 4.52,186.84 4.7,186.66 4.7,183.18 4.47,182.96 1.37,182.96 1.22,183.11 1.22,186.64
GND on BOTTOM: 28.65,47.96 30.68,47.96 30.81,47.83 30.81,46.18 30.68,46.05 28.65,46.05 28.52,46.18 28.52,47.83
GND on BOTTOM: 33.35,35.36 34.72,35.36 34.95,35.13 34.95,33.91 34.9,33.86 33.25,33.86 33.2,33.91 33.2,35.2
GND on BOTTOM: 11.63,129.36 11.76,129.24 11.76,127.18 11.07,126.49 11.07,124.71 10.95,124.59 10.19,124.59 10.06,124.71 10.06,129.16 10.26,129.36
GND on BOTTOM: 16.59,38.28 17.96,38.28 18.19,38.05 18.19,36.83 18.14,36.78 16.48,36.78 16.43,36.83 16.43,38.13
GND on BOTTOM: 28.65,59.26 30.68,59.26 30.81,59.13 30.81,57.48 30.68,57.35 28.65,57.35 28.52,57.48 28.52,59.13
GND on BOTTOM: 144.55,96.01 150.01,96.01 150.14,95.89 150.14,93.47 149.89,93.22 146.08,93.22 145.69,93.6 145.69,94.77 144.91,95.55 143.87,95.55 143.81,95.61 143.81,95.89 143.87,95.94 144.48,95.94
GND on BOTTOM: 115.21,101.09 116.48,101.09 116.61,100.97 116.61,98.17 116.48,98.04 115.21,98.04 115.09,98.17 115.09,100.97
GND on BOTTOM: 51.64,35.36 53.01,35.36 53.24,35.13 53.24,33.91 53.19,33.86 51.54,33.86 51.49,33.91 51.49,35.2
GND on BOTTOM: 98.7,85.6 98.7,89.15 98.58,89.28 93.5,89.28 92.99,89.79 92.99,90.04 92.61,90.42 91.85,90.42 91.72,90.3 91.72,85.72 89.56,83.57 89.56,82.93 89.69,82.8 90.7,82.8 91.08,82.42 96.55,82.42 96.93,82.8 98.07,82.8 98.32,83.06 98.32,85.22
GND on BOTTOM: 13.67,47.96 15.7,47.96 15.82,47.83 15.82,46.18 15.7,46.05 13.67,46.05 13.54,46.18 13.54,47.83
GND on BOTTOM: 83.64,53.92 87.07,53.92 87.2,53.8 87.2,52.27 86.94,52.02 82.12,52.02 81.99,52.15 81.99,53.16 82.12,53.29 82.37,53.29 82.5,53.16 83.39,53.16 83.52,53.29 83.52,53.8
GND on GND1, GND2: 103.12,199.49 159.49,199.49 159.49,58.67 153.88,58.67 149.97,62.59 149.8,62.7 149.61,62.74 145.03,62.74 144.84,62.7 144.67,62.59 143.91,61.83 143.8,61.66 143.76,61.47 143.76,42.29 143.8,42.1 143.91,41.93 144.67,41.17 144.84,41.06 145.03,41.02 149.99,41.02 150.18,41.06 150.35,41.17 150.71,41.53 152.57,41.53 153.16,40.94 153.16,24.72 152.04,23.6 151.93,23.44 151.89,23.24 151.89,19.01 151.17,18.29 148.84,18.29 148.65,18.25 148.48,18.14 147.72,17.38 147.61,17.21 147.57,17.02 147.57,15.83 145.71,13.97 9.86,13.97 7.09,16.74 6.93,16.85 6.73,16.89 0.51,16.89 0.51,199.49 22.1,199.49 22.1,189.61 22.19,189.12 22.47,188.71 26.28,184.9 26.69,184.63 27.18,184.53 33.64,184.53 36.19,181.98 36.6,181.71 37.08,181.61 41.13,181.61 41.77,180.97 42.19,180.69 42.67,180.59 62.48,180.59 62.97,180.69 63.38,180.97 63.9,181.48 92.08,181.48 92.56,181.58 92.97,181.85 102.75,191.63 103.03,192.05 103.12,192.53 ; 1 cut-out
GND on IN1: 92.61,88.52 98.07,88.52 98.32,88.27 98.32,82.68 98.07,82.42 92.61,82.42 92.35,82.68 92.35,88.27
GND on IN1: 71.07,158.95 74.88,158.95 75.64,158.19 75.64,154.38 74.88,153.62 71.58,153.62 70.82,154.38 70.82,158.7
GND on IN1: 90.58,97.79 94.13,97.79 94.89,97.03 94.89,94.49 94.01,93.6 89.94,93.6 89.69,93.85 89.69,96.9
GND on IN1: 42.62,72.59 45.03,72.59 47.45,70.18 47.45,68.28 47.19,68.02 45.54,68.02 44.78,68.78 42.62,68.78 41.99,69.42 41.99,71.96
GND on IN1: 136.93,122.3 152.04,122.3 152.3,122.05 152.3,116.71 152.04,116.46 136.68,116.46 136.42,116.71 136.42,121.79
GND on IN1: 88.27,163.45 111.63,163.45 112.27,164.08 112.27,164.72 114.3,166.75 114.3,169.8 112.27,171.83 112.27,172.72 112.65,173.1 112.65,174.12 111.12,175.64 88.77,175.64 87.88,174.75 87.88,163.83
GND on IN1: 96.16,68.71 96.42,68.45 96.42,65.28 95.78,64.64 93.37,64.64 93.24,64.77 93.24,68.58 93.37,68.71
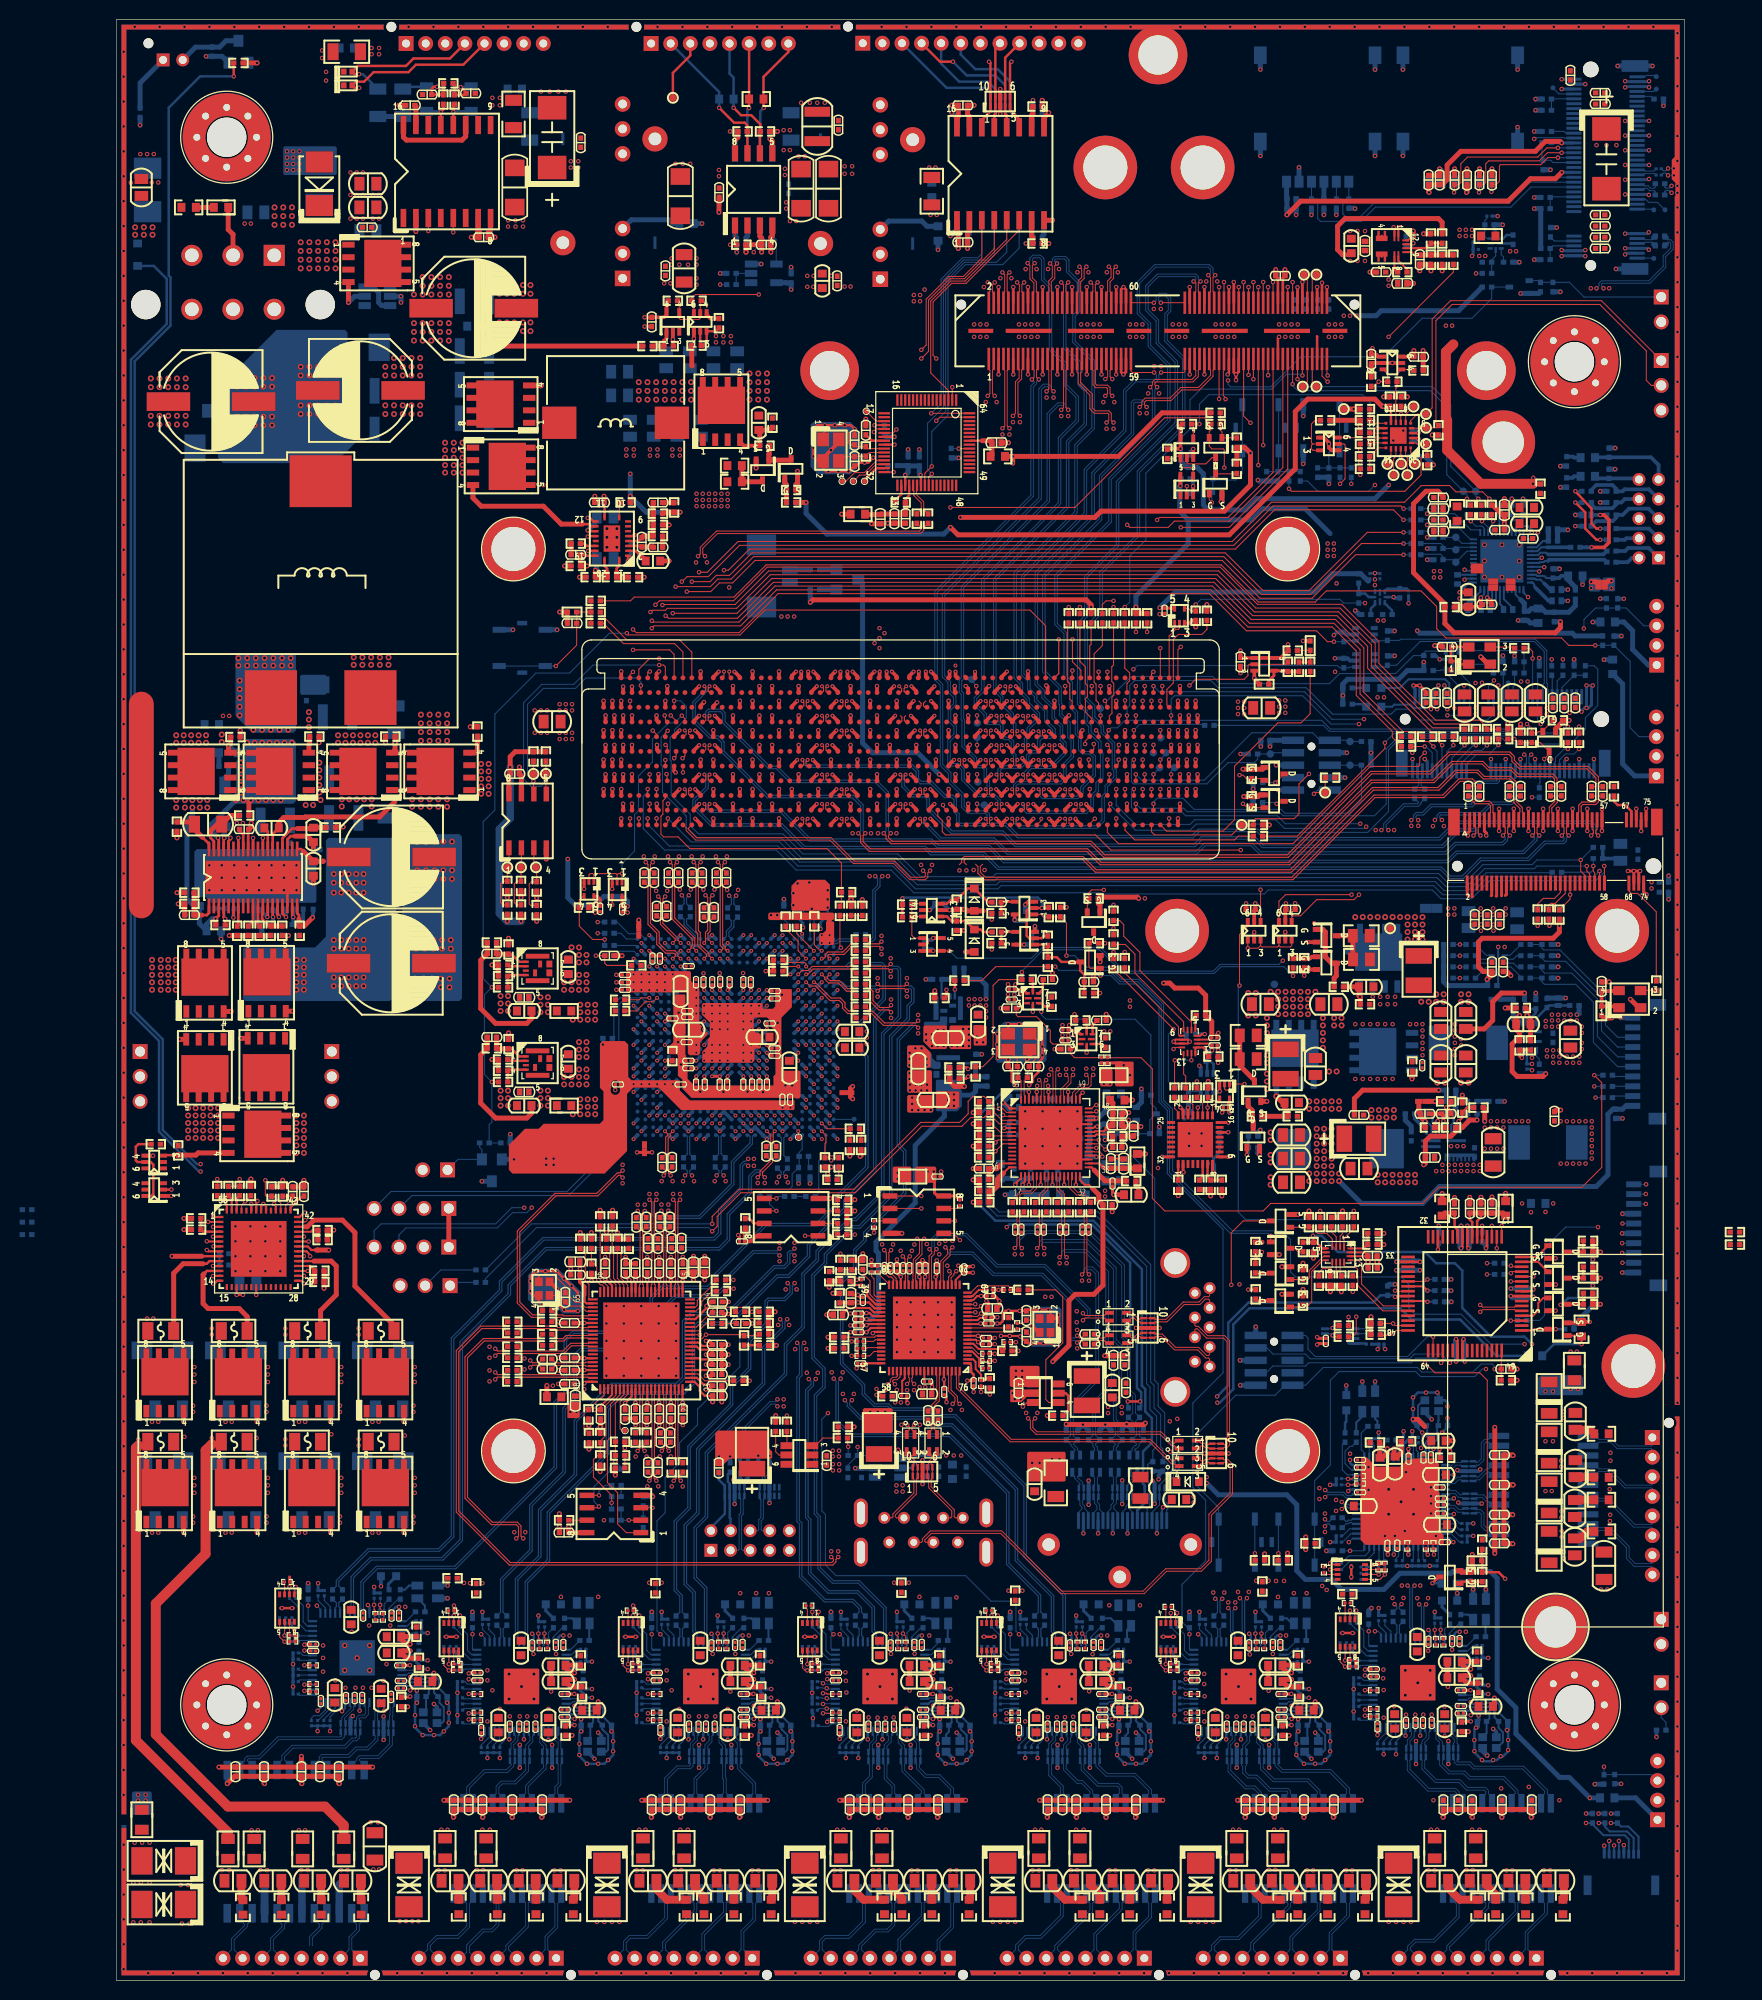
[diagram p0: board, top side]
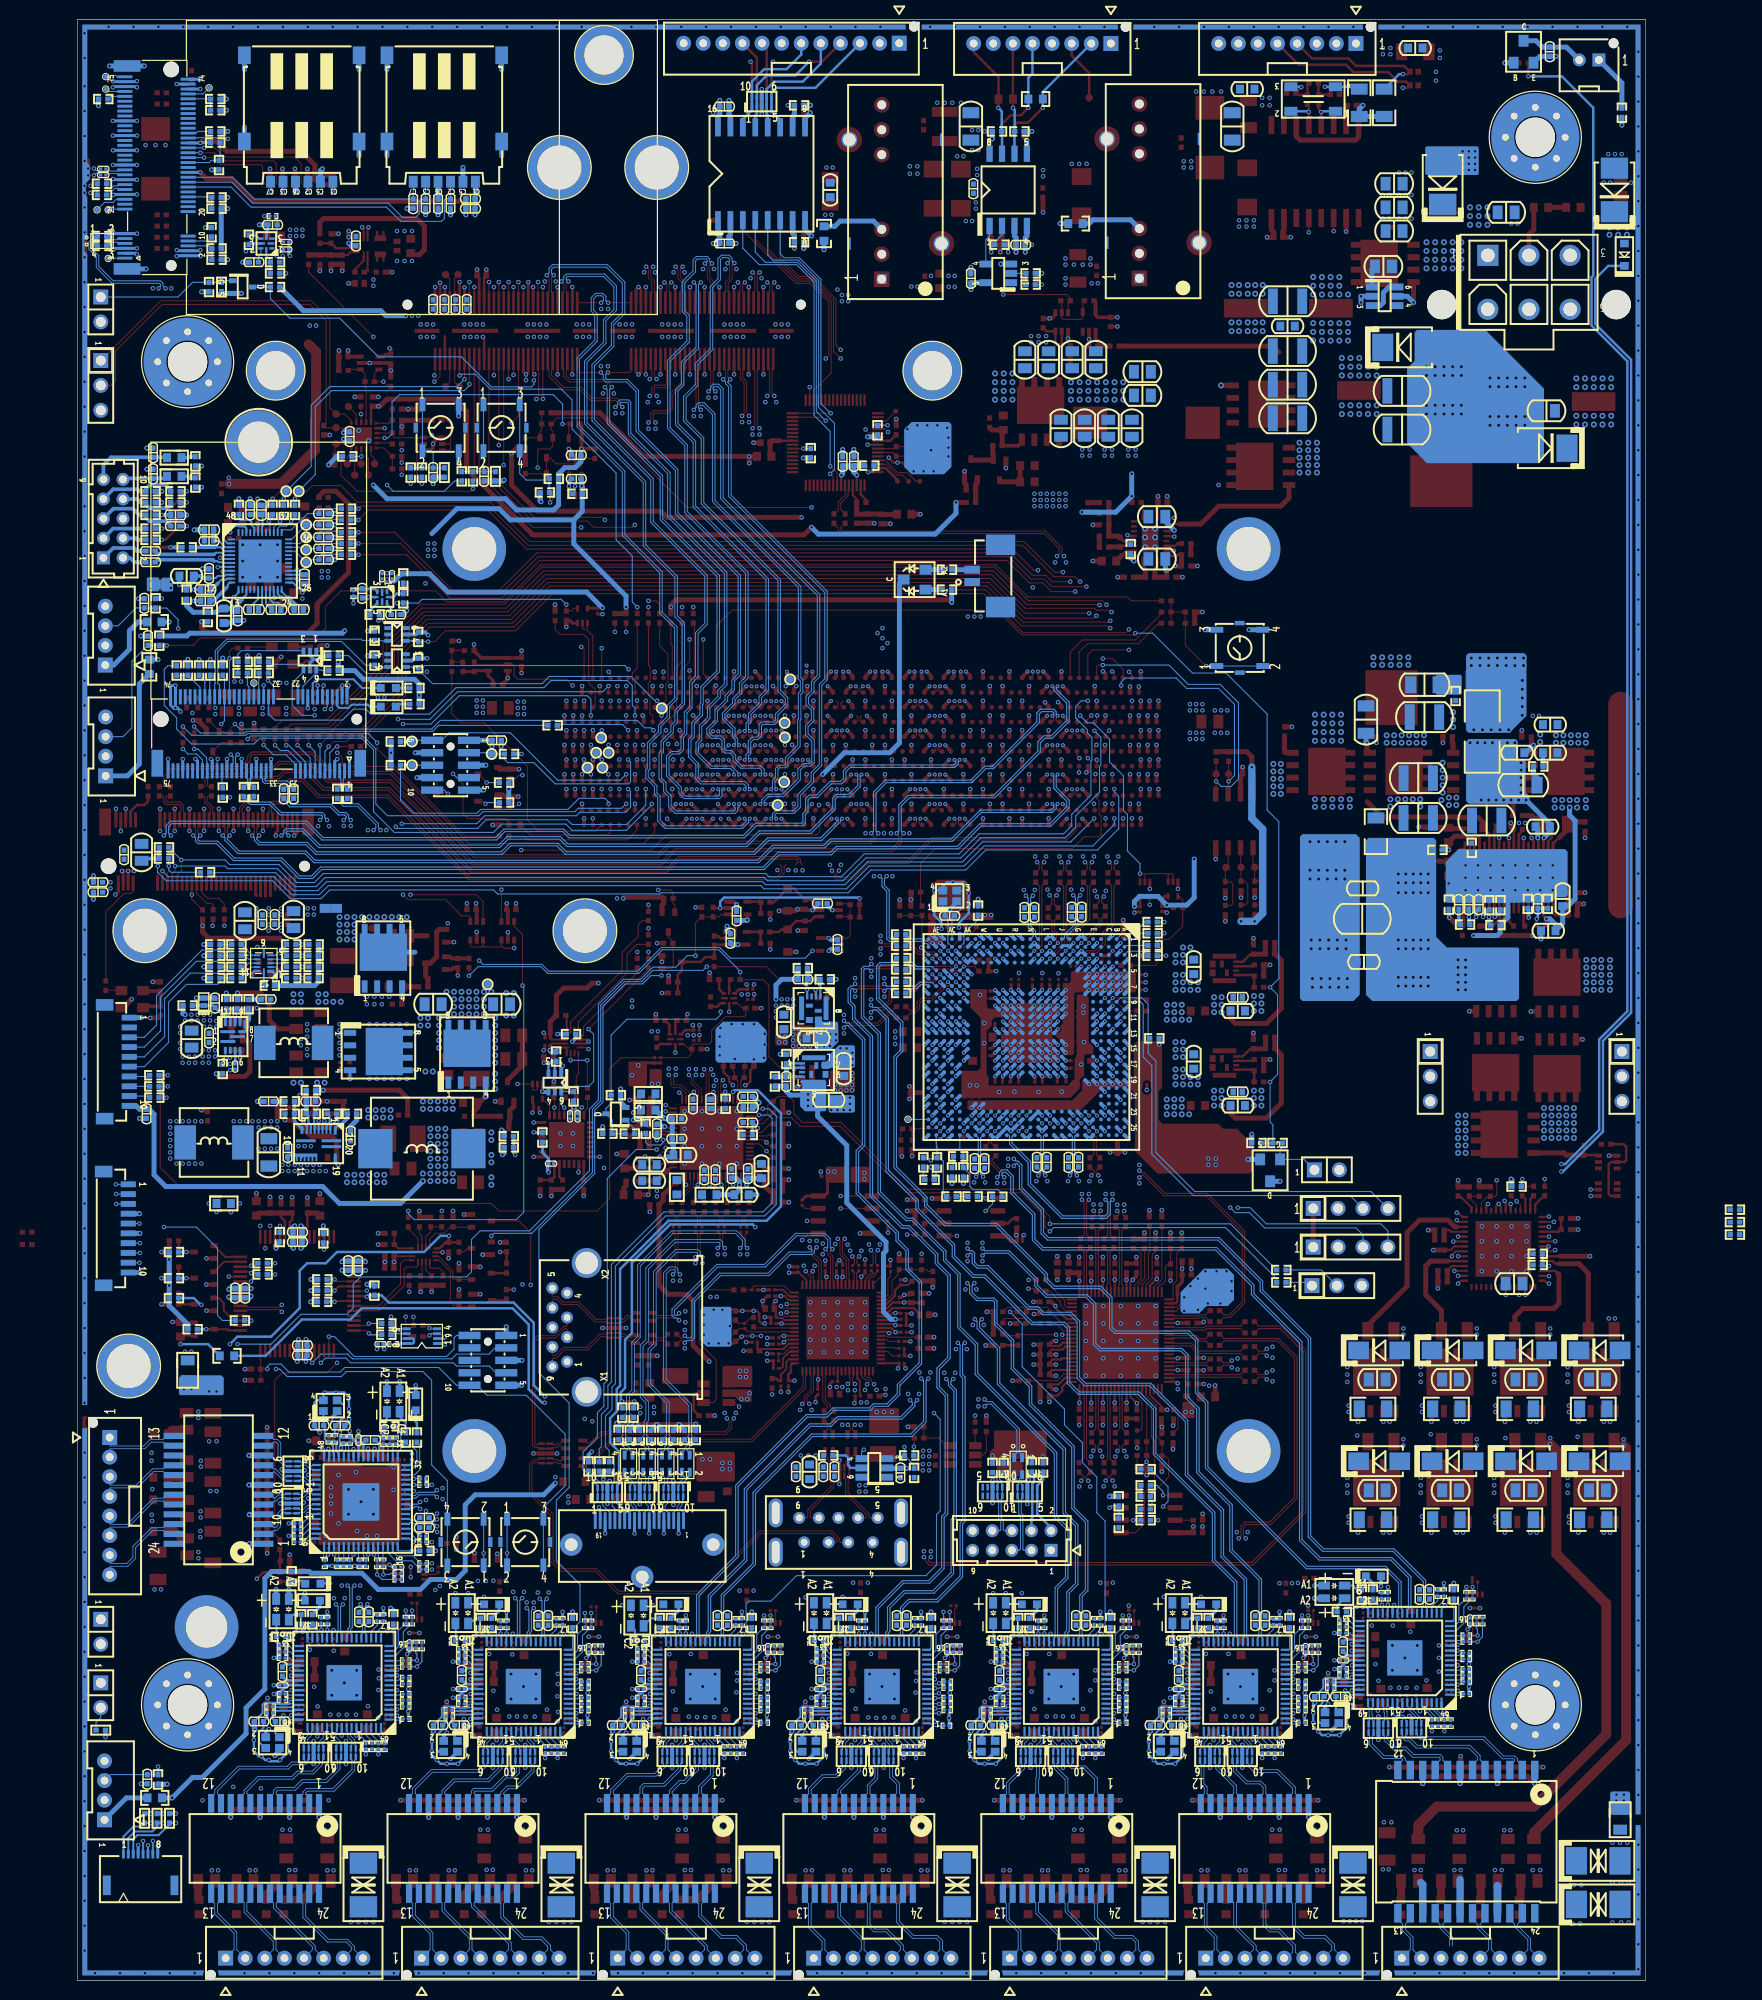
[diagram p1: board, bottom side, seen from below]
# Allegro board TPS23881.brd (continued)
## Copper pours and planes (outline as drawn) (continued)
GND on VCC: 132.57,60.2 135.28,60.2 136.02,59.46 136.02,57.13 135.91,57.02 132.19,57.02 132.08,57.13 132.08,59.71
GND on VCC: 120.7,25.91 123.54,25.91 124.03,25.42 124.03,22.33 123.54,21.84 120.83,21.84 120.22,22.46 120.22,25.42
GND on VCC: 143.51,41.53 143.61,41.55 143.69,41.6 143.97,41.88 144.67,41.17 144.84,41.06 145.03,41.02 149.99,41.02 150.18,41.06 150.35,41.17 150.71,41.53 152.57,41.53 153.16,40.94 153.16,24.72 152.04,23.6 151.93,23.44 151.89,23.24 151.89,22.35 146.03,22.35 144.2,24.18 144.12,24.24 144.02,24.26 142.82,24.26 142.82,25.78 142.8,25.88 142.75,25.96 142.75,41.53
GND on VCC: 47.55,25.78 50.39,25.78 50.88,25.29 50.88,22.2 50.39,21.72 47.68,21.72 47.07,22.33 47.07,25.29
GND on VCC: 14.71,138.05 27.07,138.05 34.67,130.45 34.67,109.6 27.05,109.6 26.95,109.58 26.87,109.53 25.98,108.64 25.93,108.56 25.91,108.46 25.91,99.67 25.09,98.86 25.04,98.78 25.02,98.68 25.02,88.5 24.82,88.7 24.74,88.75 24.64,88.77 21.7,88.77 21.26,89.21 21.18,89.26 21.08,89.28 12.7,89.28 12.6,89.26 12.52,89.21 11.76,88.44 11.7,88.36 11.68,88.27 11.68,86.34 10.94,85.6 0.51,85.6 0.51,118.75 9.78,118.75 9.88,118.76 9.96,118.82 10.34,119.2 10.39,119.28 10.41,119.38 10.41,129.05 12.12,130.76 12.17,130.84 12.19,130.94 12.19,135.53
GND on VCC: 30.79,28.83 33.63,28.83 34.11,28.34 34.11,25.25 33.63,24.77 30.92,24.77 30.3,25.38 30.3,28.34
GND on VCC: 65.84,25.91 68.68,25.91 69.16,25.42 69.16,22.33 68.68,21.84 65.97,21.84 65.35,22.46 65.35,25.42
GND on VCC: 0.51,199.49 22.1,199.49 22.1,189.61 22.19,189.12 22.47,188.71 26.28,184.9 26.69,184.63 27.18,184.53 28.96,184.53 28.96,178.05 25.4,178.05 25.3,178.03 25.22,177.98 24.71,177.47 24.66,177.39 24.64,177.29 24.64,174.22 24.41,173.99 20.83,173.99 20.73,173.97 20.65,173.92 18.74,172.01 18.69,171.93 18.67,171.83 18.67,169.4 15.9,166.62 13.21,166.62 13.11,166.6 13.03,166.55 10.49,164.01 10.43,163.93 10.41,163.83 10.41,159.74 3.83,153.16 0.51,153.16
GND on VCC: 84.13,25.91 86.97,25.91 87.45,25.42 87.45,22.33 86.97,21.84 84.26,21.84 83.64,22.46 83.64,25.42
GND on VCC: 103.12,199.49 159.49,199.49 159.49,144.02 158.86,144.02 158.93,144.09 158.98,144.17 159,144.27 159,156.08 158.98,156.18 158.93,156.26 157.91,157.28 157.83,157.33 157.73,157.35 147.45,157.35 147.35,157.33 147.27,157.28 146.18,156.19 146.18,159.89 146.16,159.99 146.1,160.07 144.02,162.16 144.02,165.74 144,165.83 143.94,165.91 140.72,169.14 140.72,177.8 140.7,177.9 140.64,177.98 136.96,181.66 136.88,181.72 136.78,181.74 92.84,181.74 92.91,181.79 92.97,181.85 102.75,191.63 103.03,192.05 103.12,192.53
GND on VCC: 71.48,158.88 75.08,158.88 75.56,158.39 75.56,154.41 74.82,153.67 71.99,153.67 70.87,154.79 70.87,158.26
GND on VCC: 102.42,25.78 105.25,25.78 105.74,25.29 105.74,22.2 105.25,21.72 102.54,21.72 101.93,22.33 101.93,25.29
GND on VCC: 93.45,68.58 95.91,68.58 96.27,68.22 96.27,65.26 95.78,64.77 93.45,64.77 93.22,65 93.22,68.35
GND on VCC: 42.65,72.52 44.98,72.52 45.09,72.41 45.09,69.19 44.73,68.83 42.9,68.83 42.04,69.7 42.04,71.9
GND on VCC: 69.45,112.14 72.41,112.14 72.77,111.78 72.77,109.2 72.54,108.97 69.07,108.97 68.83,109.2 68.83,111.53
GND on VCC: 81.21,130.94 83.22,130.94 83.31,130.84 83.44,130.81 83.51,130.81 83.69,130.63 83.69,128.27 83.7,128.22 83.73,128.18 83.82,128.09 83.82,126.75 83.83,126.7 83.86,126.66 84.45,126.06 84.45,123.95 84.46,123.9 84.49,123.86 84.96,123.39 84.96,122.81 84.97,122.76 85,122.72 87.25,120.47 87.25,116.97 87.26,116.92 87.29,116.88 87.77,116.4 87.76,116.37 87.76,116.33 87.78,116.23 87.83,116.15 87.96,116.03 88.04,115.97 88.14,115.95 88.97,115.95 89.03,115.9 89.03,113.08 88.72,112.78 85.65,112.78 85.34,113.08 85.34,114.94 85.33,114.98 85.31,115.02 84.58,115.75 84.58,118.87 84.57,118.92 84.54,118.96 84.07,119.43 84.07,120.4 84.06,120.44 84.04,120.49 83.82,120.7 83.82,121.54 83.81,121.59 83.78,121.63 83.4,122.01 83.36,122.04 83.31,122.05 82.6,122.05 81.92,122.73 81.92,124.21 81.91,124.25 81.88,124.3 78.99,127.18 78.99,129.49 79.3,129.79 80.01,129.79 80.06,129.8 80.1,129.83
GND on VCC: 8.87,33.78 13.74,33.78 17.02,30.5 17.02,25.63 12.85,21.46 9.63,21.46 5.46,25.63 5.46,30.37
GND on VCC: 89.66,98.3 92.86,98.3 92.91,98.25 92.99,98.19 93.09,98.17 94.74,98.17 94.74,94.09 94.38,93.73 90.02,93.73 89.66,94.09
GND on VCC: 138.99,26.16 141.83,26.16 142.32,25.68 142.32,22.58 141.83,22.1 139.12,22.1 138.51,22.71 138.51,25.68
GND on IN3: 132.11,60.2 135.92,60.2 136.04,60.07 136.04,57.15 135.92,57.02 132.11,57.02 131.98,57.15 131.98,60.07
GND on IN3: 129.57,50.55 132.61,50.55 132.74,50.42 132.74,47.24 132.61,47.12 129.57,47.12 129.44,47.24 129.44,50.42
GND on IN3: 39.62,31.8 43.03,31.8 43.13,31.7 43.13,28.22 43.08,28.17 39.6,28.17 39.52,28.24 39.52,31.7
GND on IN3: 57.91,31.8 61.32,31.8 61.42,31.7 61.42,28.22 61.37,28.17 57.89,28.17 57.81,28.24 57.81,31.7
GND on IN3: 76.2,31.8 79.6,31.8 79.71,31.7 79.71,28.22 79.65,28.17 76.17,28.17 76.1,28.24 76.1,31.7
GND on IN3: 112.78,31.8 116.18,31.8 116.28,31.7 116.28,28.22 116.23,28.17 112.75,28.17 112.67,28.24 112.67,31.7
GND on IN3: 131.06,32.18 134.47,32.18 134.57,32.08 134.57,28.6 134.52,28.55 131.04,28.55 130.96,28.63 130.96,32.08
GND on IN3: 94.49,31.8 97.89,31.8 97.99,31.7 97.99,28.22 97.94,28.17 94.46,28.17 94.39,28.24 94.39,31.7
GNDA on TOP (solid shape): 73.23,107.9 73.23,105.74 73.1,105.61 71.83,105.61 71.7,105.74 71.7,106.73 71.78,106.81 72.09,106.81 72.39,107.11 72.39,107.98 72.44,108.03 73.1,108.03
GNDA on TOP: 56.81,89.29 57.53,88.57 69.55,88.57 70.13,89.15 70.13,94.49 70.46,94.82 73.05,94.82 74.41,93.46 74.41,87.38 74.28,87.25 72.64,87.25 72.14,87.76 71.7,87.76 71.58,87.63 71.58,85.34 71.22,84.99 68.28,84.99 67.69,85.57 67.69,86.77 67.39,87.07 66.12,87.07 65.49,86.45 65.49,85.38 65.06,84.95 64.48,84.95 64.47,84.94 57.28,84.94 57.12,85.09 57.12,86.59 56.77,86.94 55.73,86.94 55.55,86.77 55.55,85.24 55.24,84.94 52.7,84.94 52.5,85.14 52.5,88.75 53.05,89.29
GNDA on TOP: 52.53,106.88 54.43,106.88 54.56,106.76 54.56,105.61 52.91,103.96 52.53,103.96 52.4,104.09 52.4,106.76
GNDA on IN1: 67.75,108.12 68.55,107.31 74.5,107.31 74.75,107.06 74.75,85.67 74.24,85.17 58.88,85.17 58.78,85.27 58.78,87.55 58.45,87.88 54.64,87.88 53.92,87.17 53.92,85.78 53.57,85.42 52.27,85.42 51.89,85.8 51.89,106.17 52.78,107.06 62.76,107.06 63.82,108.12
GNDA on IN3: 52.65,88.65 61.62,88.65 61.8,88.47 61.8,85.57 61.04,84.81 52.22,84.81 51.89,85.14 51.89,87.88
V0P9_LAN1 on TOP: 23.62,27.05 23.5,26.92 21.84,26.92 21.72,27.05 21.72,28.65 21.79,28.73 23.55,28.73 23.62,28.65
V0P9_LAN1 on TOP: 28.07,38.33 30.84,38.33 31.06,38.1 31.06,35.94 30.86,35.74 29.97,35.74 29.82,35.89 29.82,37.08 29.64,37.26 27.94,37.26 27.86,37.34 27.86,38.13
V0P9_LAN1 on IN3: 29.72,38.18 29.72,33.78 30.35,33.15 30.35,31.88 29.34,30.86 29.34,30.1 28.35,29.11 28.35,28.22 28.07,27.94 24.51,27.94 23.75,27.18 21.46,27.18 21.34,27.3 21.34,29.72 19.68,31.37 19.68,33.78 19.43,34.04 19.05,34.04 18.92,34.16 18.92,36.07 21.21,38.35 29.54,38.35
V0P9_LAN2 on TOP: 45.09,35.43 47.75,35.43 47.88,35.31 47.88,32.89 47.75,32.77 46.61,32.77 46.35,33.02 46.35,34.16 46.23,34.29 44.7,34.29 44.58,34.42 44.58,34.92
V0P9_LAN2 on TOP: 40.39,24.13 40.26,24 38.61,24 38.48,24.13 38.48,25.73 38.56,25.81 40.31,25.81 40.39,25.73
V0P9_LAN2 on IN3: 46.48,35.26 46.48,30.86 47.12,30.23 47.12,28.96 46.1,27.94 46.1,27.18 45.11,26.19 45.11,25.3 44.83,25.02 41.27,25.02 40.51,24.26 38.23,24.26 38.1,24.38 38.1,26.8 36.45,28.45 36.45,30.86 36.2,31.11 35.81,31.11 35.69,31.24 35.69,33.15 37.97,35.43 46.3,35.43
V0P9_LAN3 on TOP: 58.67,24.13 58.55,24 56.9,24 56.77,24.13 56.77,25.73 56.85,25.81 58.6,25.81 58.67,25.73
V0P9_LAN3 on TOP: 63.37,35.43 66.04,35.43 66.17,35.31 66.17,32.89 66.04,32.77 64.9,32.77 64.64,33.02 64.64,34.16 64.52,34.29 62.99,34.29 62.87,34.42 62.87,34.92
V0P9_LAN3 on IN3: 64.64,35.81 64.77,35.69 64.77,30.86 65.41,30.23 65.41,28.96 64.39,27.94 64.39,27.05 63.5,26.16 63.5,25.15 63.37,25.02 59.56,25.02 58.8,24.26 56.52,24.26 56.39,24.38 56.39,26.8 54.74,28.45 54.74,30.86 54.48,31.11 54.1,31.11 53.98,31.24 53.98,33.15 56.64,35.81
V0P9_LAN4 on TOP: 76.96,24.13 76.83,24 75.18,24 75.06,24.13 75.06,25.73 75.13,25.81 76.89,25.81 76.96,25.73
V0P9_LAN4 on TOP: 81.66,35.43 84.33,35.43 84.45,35.31 84.45,32.89 84.33,32.77 83.19,32.77 82.93,33.02 82.93,34.16 82.8,34.29 81.28,34.29 81.15,34.42 81.15,34.92
V0P9_LAN4 on IN3: 82.93,35.81 83.06,35.69 83.06,30.86 83.69,30.23 83.69,28.96 82.68,27.94 82.68,25.27 82.42,25.02 77.85,25.02 77.09,24.26 74.8,24.26 74.68,24.38 74.68,26.8 73.03,28.45 73.03,30.86 72.77,31.11 72.39,31.11 72.26,31.24 72.26,33.15 74.93,35.81
V0P9_LAN5 on TOP: 99.95,35.43 102.62,35.43 102.74,35.31 102.74,32.89 102.62,32.77 101.47,32.77 101.22,33.02 101.22,34.16 101.09,34.29 99.57,34.29 99.44,34.42 99.44,34.92
V0P9_LAN5 on TOP: 95.25,24.13 95.12,24 93.47,24 93.34,24.13 93.34,25.73 93.42,25.81 95.17,25.81 95.25,25.73
V0P9_LAN5 on IN3: 101.35,35.36 101.35,30.86 101.98,30.23 101.98,28.96 100.97,27.94 100.97,25.27 100.71,25.02 96.14,25.02 95.38,24.26 93.09,24.26 92.96,24.38 92.96,26.8 91.31,28.45 91.31,30.86 91.06,31.11 90.68,31.11 90.55,31.24 90.55,33.15 92.33,34.92 95.25,34.92 95.76,35.43 101.27,35.43
V0P9_LAN6 on TOP: 118.24,35.43 120.9,35.43 121.03,35.31 121.03,32.89 120.9,32.77 119.76,32.77 119.51,33.02 119.51,34.16 119.38,34.29 117.86,34.29 117.73,34.42 117.73,34.92
V0P9_LAN6 on TOP: 113.54,24.13 113.41,24 111.76,24 111.63,24.13 111.63,25.73 111.71,25.81 113.46,25.81 113.54,25.73
V0P9_LAN6 on IN3: 119.63,35.43 119.63,30.86 120.27,30.23 120.27,28.96 119.25,27.94 119.25,25.27 119,25.02 114.43,25.02 113.67,24.26 111.38,24.26 111.25,24.38 111.25,26.8 109.6,28.45 109.6,30.86 109.35,31.11 108.97,31.11 108.84,31.24 108.84,33.15 110.74,35.05 117.09,35.05 117.73,35.69 119.38,35.69
V0P9_LAN7 on TOP: 131.83,24.51 131.7,24.38 130.05,24.38 129.92,24.51 129.92,26.11 130,26.19 131.75,26.19 131.83,26.11
V0P9_LAN7 on TOP: 136.53,35.81 139.19,35.81 139.32,35.69 139.32,33.27 139.19,33.15 138.05,33.15 137.79,33.4 137.79,34.54 137.67,34.67 136.14,34.67 136.02,34.8 136.02,35.31
V0P9_LAN7 on IN3: 137.79,35.81 137.92,35.69 137.92,30.86 138.56,30.23 138.56,28.96 137.54,27.94 137.54,27.15 135.97,25.58 132.44,25.58 132.21,25.35 132.21,24.51 131.95,24.26 129.67,24.26 129.54,24.38 129.54,26.8 127.89,28.45 127.89,30.86 127.64,31.11 127.25,31.11 127.13,31.24 127.13,33.15 129.79,35.81
V0P9_LAN8 on TOP: 125.6,52.58 125.6,55.24 125.73,55.37 128.14,55.37 128.27,55.24 128.27,54.1 128.02,53.85 126.87,53.85 126.75,53.72 126.75,52.2 126.62,52.07 126.11,52.07
V0P9_LAN8 on TOP: 136.91,47.88 137.03,47.75 137.03,46.1 136.91,45.97 135.31,45.97 135.23,46.05 135.23,47.8 135.31,47.88
V0P9_LAN8 on IN3: 126.26,54.99 133.63,54.99 133.88,54.74 133.88,53.34 134.65,52.58 134.65,49.91 136.68,47.88 136.68,43.81 135.92,43.05 126.52,43.05 125.88,43.69 125.88,49.28 125.37,49.78 125.37,54.1
V1P5_LAN1 on TOP: 24.08,27.28 24,27.36 24,28.68 24.05,28.73 25.22,28.73 25.27,28.68 25.27,27.33 25.22,27.28
V1P5_LAN1 on TOP: 31.22,32.13 31.22,30.02 31.17,29.97 30.45,29.97 30.3,29.82 30.3,29.46 30.2,29.36 29.13,29.36 29.06,29.44 29.06,31.47 29.21,31.62 29.95,31.62 30.33,32 30.33,32.13 30.45,32.26 31.09,32.26
V1P5_LAN2 on TOP: 40.84,24.36 40.77,24.43 40.77,25.76 40.82,25.81 41.99,25.81 42.04,25.76 42.04,24.41 41.99,24.36
V1P5_LAN2 on TOP: 47.98,29.21 47.98,27.1 47.93,27.05 47.22,27.05 47.07,26.9 47.07,26.54 46.96,26.44 45.9,26.44 45.82,26.52 45.82,28.55 45.97,28.7 46.71,28.7 47.09,29.08 47.09,29.21 47.22,29.34 47.85,29.34
V1P5_LAN3 on TOP: 66.27,29.21 66.27,27.1 66.22,27.05 65.51,27.05 65.35,26.9 65.35,26.54 65.25,26.44 64.19,26.44 64.11,26.52 64.11,28.55 64.26,28.7 65,28.7 65.38,29.08 65.38,29.21 65.51,29.34 66.14,29.34
V1P5_LAN3 on TOP: 59.13,24.36 59.05,24.43 59.05,25.76 59.11,25.81 60.27,25.81 60.33,25.76 60.33,24.41 60.27,24.36
V1P5_LAN4 on TOP: 77.42,24.36 77.34,24.43 77.34,25.76 77.39,25.81 78.56,25.81 78.61,25.76 78.61,24.41 78.56,24.36
V1P5_LAN4 on TOP: 84.56,29.21 84.56,27.1 84.51,27.05 83.79,27.05 83.64,26.9 83.64,26.54 83.54,26.44 82.47,26.44 82.4,26.52 82.4,28.55 82.55,28.7 83.29,28.7 83.67,29.08 83.67,29.21 83.79,29.34 84.43,29.34
V1P5_LAN5 on TOP: 95.71,24.36 95.63,24.43 95.63,25.76 95.68,25.81 96.85,25.81 96.9,25.76 96.9,24.41 96.85,24.36
V1P5_LAN5 on TOP: 102.84,29.21 102.84,27.1 102.79,27.05 102.08,27.05 101.93,26.9 101.93,26.54 101.83,26.44 100.76,26.44 100.69,26.52 100.69,28.55 100.84,28.7 101.57,28.7 101.96,29.08 101.96,29.21 102.08,29.34 102.72,29.34
V1P5_LAN6 on TOP: 121.13,29.21 121.13,27.1 121.08,27.05 120.37,27.05 120.22,26.9 120.22,26.54 120.12,26.44 119.05,26.44 118.97,26.52 118.97,28.55 119.13,28.7 119.86,28.7 120.24,29.08 120.24,29.21 120.37,29.34 121.01,29.34
V1P5_LAN6 on TOP: 114,24.36 113.92,24.43 113.92,25.76 113.97,25.81 115.14,25.81 115.19,25.76 115.19,24.41 115.14,24.36
V1P5_LAN7 on TOP: 132.28,24.74 132.21,24.82 132.21,26.14 132.26,26.19 133.43,26.19 133.48,26.14 133.48,24.79 133.43,24.74
V1P5_LAN7 on TOP: 139.42,29.59 139.42,27.48 139.37,27.43 138.66,27.43 138.51,27.28 138.51,26.92 138.4,26.82 137.34,26.82 137.26,26.9 137.26,28.93 137.41,29.08 138.15,29.08 138.53,29.46 138.53,29.59 138.66,29.72 139.29,29.72
V1P5_LAN8 on TOP: 136.68,48.34 136.6,48.26 135.28,48.26 135.23,48.31 135.23,49.48 135.28,49.53 136.63,49.53 136.68,49.48
V1P5_LAN8 on TOP: 131.83,55.47 133.86,55.47 133.88,55.5 134.49,55.5 134.59,55.4 134.59,53.52 134.52,53.44 132.49,53.44 132.33,53.59 132.33,54.2 131.95,54.58 131.83,54.58 131.7,54.71 131.7,55.35
V3.3_M2_B on TOP: 150.37,194.18 151.26,193.29 151.26,191.01 151.51,190.75 153.29,190.75 153.54,190.5 153.54,186.56 153.29,186.31 150.37,186.31 150.11,186.06 150.11,181.1 150.24,180.97 151.13,180.97 151.26,180.85 151.26,175.77 150.75,175.26 140.34,175.26 140.21,175.39 140.21,180.21 140.46,180.47 142.37,180.47 145.03,183.13 147.32,183.13 148.08,183.9 148.08,187.96 147.7,188.34 144.53,188.34 144.27,188.59 144.27,193.8 144.65,194.18
V3.3_M2_B on BOTTOM: 141.81,177.42 143.13,177.42 143.26,177.29 143.26,176.15 143.13,176.02 141.99,176.02 141.86,176.15 141.86,176.78 141.73,176.91 140.89,176.91 140.82,176.99 140.82,177.29 140.87,177.34 141.73,177.34
V3.3_M2_B on IN1: 144.53,175.13 153.03,175.13 153.42,175.51 153.42,194.82 153.16,195.07 144.53,195.07 144.02,194.56 144.02,185.01 141.91,182.91 141.91,175.31 142.07,175.15 144.51,175.15
V3P3_LAN1 on TOP: 14.58,43.41 33.83,43.41 34.09,43.15 34.09,38.81 33.77,38.49 33.54,38.49 32.77,37.72 32.77,33.27 33.23,32.81 33.23,32.34 32.77,31.88 32.59,31.97 32.38,32 31.99,31.87 31.75,31.53 31.74,31.5 31.62,31.5 31.5,31.62 31.5,32.21 31.54,32.29 31.63,32.31 31.69,32.29 31.75,32.29 32.11,32.64 31.75,33 31.69,32.99 31.63,32.98 31.54,32.99 31.5,33.07 31.5,38.43 31.24,38.68 26.11,38.68 25.91,38.48 25.91,37.26 25.83,37.19 20.42,37.19 19.84,36.6 19.84,35.53 18.8,34.49 18.8,34.11 19.05,33.86 19.84,33.86 19.94,33.76 19.94,32.79 19.81,32.66 19.02,32.66 18.8,32.44 18.8,29.18 19.61,28.37 21.21,28.37 21.39,28.19 21.39,26.75 21.56,26.57 25.45,26.57 25.65,26.77 25.65,28.68 25.7,28.73 28.19,28.73 28.32,28.6 28.32,23.77 27.94,23.39 18.03,23.39 17.65,23.77 17.65,31.24 13.59,35.31 13.59,42.42 ; 1 cut-out
V3P3_LAN2 on TOP: 35.43,36.09 35.43,37.39 35.28,37.54 34.29,37.54 34.14,37.69 34.14,38.23 34.54,38.63 34.54,39.62 34.67,39.75 49.63,39.75 50.14,39.24 50.14,30.02 52.02,28.14 52.02,20.7 51.79,20.47 34.8,20.47 34.42,20.85 34.42,30.48 34.75,30.81 34.75,32.49 34.7,32.54 34.7,34.01 35.18,34.49 35.18,35.84 ; 1 cut-out
V3P3_LAN2 on BOTTOM: 44.96,39.5 49.4,39.5 49.53,39.37 49.53,37.97 49.4,37.85 44.96,37.85 44.83,37.97 44.83,39.37
V3P3_LAN3 on TOP: 53.72,36.09 53.72,37.39 53.57,37.54 52.58,37.54 52.43,37.69 52.43,39.62 52.68,39.88 67.92,39.88 68.43,39.37 68.43,30.02 70.31,28.14 70.31,20.7 70.08,20.47 53.09,20.47 52.7,20.85 52.7,30.48 53.04,30.81 53.04,32.49 52.98,32.54 52.98,34.01 53.47,34.49 53.47,35.84 ; 1 cut-out
V3P3_LAN3 on BOTTOM: 63.27,39.88 67.16,39.88 67.26,39.78 67.26,37.95 67.18,37.87 63.22,37.87 63.14,37.95 63.14,39.75
V3P3_LAN4 on TOP: 72.01,36.09 72.01,37.39 71.86,37.54 70.87,37.54 70.71,37.69 70.71,39.62 70.97,39.88 85.7,39.88 86.72,38.86 86.72,30.02 88.6,28.14 88.6,20.7 88.37,20.47 71.37,20.47 70.99,20.85 70.99,30.48 71.32,30.81 71.32,32.49 71.27,32.54 71.27,34.01 71.75,34.49 71.75,35.84 ; 1 cut-out
V3P3_LAN4 on BOTTOM: 81.61,39.37 85.88,39.37 86,39.24 86,37.9 85.88,37.77 81.58,37.77 81.48,37.87 81.48,39.24
V3P3_LAN5 on TOP: 90.3,36.09 90.3,37.39 90.14,37.54 89.15,37.54 89,37.69 89,38.48 89.64,39.12 104.22,39.12 105,38.33 105,30.02 106.88,28.14 106.88,20.7 106.65,20.47 89.66,20.47 89.28,20.85 89.28,30.48 89.61,30.81 89.61,32.49 89.56,32.54 89.56,34.01 90.04,34.49 90.04,35.84 ; 1 cut-out
V3P3_LAN5 on BOTTOM: 99.92,39.17 104.65,39.17 104.75,39.07 104.75,37.74 104.62,37.62 99.87,37.62 99.75,37.74 99.75,38.99
V3P3_LAN6 on TOP: 108.58,36.09 108.58,37.64 108.33,37.9 107.43,37.9 107.35,37.97 107.35,39.05 107.63,39.33 111.19,39.33 112.8,37.72 114.71,37.72 115.93,38.94 115.93,39.75 116.15,39.98 121.59,39.98 123.29,38.28 123.29,30.02 125.17,28.14 125.17,20.7 124.94,20.47 107.95,20.47 107.57,20.85 107.57,30.48 107.9,30.81 107.9,32.49 107.85,32.54 107.85,34.01 108.33,34.49 108.33,35.84 ; 1 cut-out
V3P3_LAN6 on BOTTOM: 118.16,39.95 121.97,39.95 122.1,39.83 122.1,38 121.97,37.87 118.11,37.87 118.01,37.97 118.01,39.8
V3P3_LAN7 on TOP: 126.87,36.47 126.87,37.9 126.62,38.15 125.83,38.15 125.69,38.29 125.69,40.11 125.76,40.17 125.76,40.18 125.91,40.34 130.02,40.34 130.56,40.87 140.61,40.87 141.58,39.9 141.58,30.4 143.46,28.52 143.46,21.08 143.23,20.85 126.24,20.85 125.86,21.23 125.86,30.86 126.19,31.19 126.19,32.87 126.14,32.92 126.14,34.39 126.62,34.87 126.62,36.22 ; 1 cut-out
V3P3_LAN8 on TOP: 124.94,42.93 123.65,42.93 123.49,42.77 123.49,42.06 123.42,41.99 122.07,41.99 121.95,42.11 121.95,50.55 123.47,52.07 123.47,60.71 124.23,61.47 138.94,61.47 139.75,60.66 139.75,45.16 139.18,44.59 138.44,44.59 135.76,41.91 130.56,41.91 130.23,42.24 128.55,42.24 128.5,42.19 127.03,42.19 126.54,42.67 125.2,42.67 ; 1 cut-out
V3P3_LAN8 on BOTTOM: 125.25,61.47 128.93,61.47 129.06,61.34 129.06,59.56 128.93,59.44 126.39,59.44 126.14,59.18 125.12,59.18 124.99,59.31 124.99,61.21
VCC5_USB1 on TOP: 96.6,63.2 103.58,63.2 104.22,63.83 110.19,63.83 110.57,63.45 110.57,61.93 110.19,61.54 107.26,61.54 106.25,60.53 95.58,60.53 95.45,60.66 95.45,62.05
VCC5_USB2 on TOP: 76.35,54.56 79.71,54.56 79.83,54.43 79.83,53.16 80.47,52.53 80.47,49.73 80.21,49.48 75.51,49.48 72.85,46.81 62.05,46.81 61.8,46.56 61.8,43.38 61.57,43.15 58.47,43.15 58.17,43.46 58.17,49.61 58.75,50.19 58.75,51.71 59.18,52.15 61.87,52.15 62.76,53.04 68.35,53.04 68.58,52.81 68.58,51.56 68.88,51.26 72.82,51.26 72.83,51.27 74.76,51.27 75.13,51.64 75.41,51.64 75.97,52.2 75.97,54.18
VCC5_USB2 on BOTTOM: 82.63,51.89 87.83,51.89 88.09,51.64 88.09,43.51 87.83,43.26 84.28,43.26 84.02,43.51 84.02,45.03 83.39,45.67 81.36,45.67 80.98,46.05 80.98,47.57 79.2,49.35 79.2,51.51 79.32,51.64 82.37,51.64
VCC25P on TOP: 68.4,98.12 74.04,98.12 74.75,97.41 74.75,94.67 74.65,94.56 73.69,94.56 73.18,95.07 70.05,95.07 69.8,94.82 69.8,93.42 69.67,93.29 68.15,93.29 68.15,97.87
VCC25P on TOP: 46.05,90.37 49.1,90.37 49.23,90.25 49.23,88.09 49.1,87.96 46.18,87.96 45.92,88.21 45.92,90.25
VCC25P on IN2: 53.92,58.37 59.51,58.37 60.4,59.26 60.4,60.4 60.66,60.66 60.66,63.45 59.64,64.47 59.64,65.86 60.02,66.24 62.69,66.24 63.32,66.88 63.32,77.42 74.7,88.8 74.7,100.97 74.07,101.6 52.96,101.6 49.61,98.25 49.61,92.79 45.67,88.85 45.67,72.47 46.43,71.7 51.26,71.7 51.64,72.09 52.91,72.09 53.16,71.83 53.16,70.31 47.32,64.47 47.32,60.02 47.83,59.51 52.78,59.51
VCC_DCIN on TOP: 25.27,177.55 33.15,177.55 36.07,174.62 36.07,168.28 40.64,163.7 40.64,158.5 40.51,158.37 25.91,158.37 25.15,159.13 25.15,177.42
VCC_DCIN on TOP: 10.03,119.38 9.91,119.25 5.33,119.25 5.21,119.38 5.21,127.13 5.46,127.38 9.91,127.38 10.03,127.25
VCC_DCIN on BOTTOM: 30.18,174.45 35.89,174.45 36.14,174.19 36.14,157.94 36.02,157.81 33.1,157.81 32.46,157.18 32.46,147.78 27.51,142.82 17.35,142.82 9.68,135.15 9.68,119.46 9.42,119.2 5.92,119.2 5.79,119.33 5.79,149.81 10.11,154.13 22.68,154.13 25.35,156.79 25.35,164.67 24.59,165.43 24.59,170.98 24.62,171.02 25.32,171.02 25.54,171.05 25.73,171.14 25.75,171.15 25.98,171.15 25.99,171.1 26.05,170.83 26.21,170.61 26.52,170.29 26.77,170.13 27.06,170.07 27.91,170.07 28.07,170.08 28.21,170.13 29.03,170.13 29.36,170.46 29.37,170.46 29.68,170.74 29.79,171.15 29.79,171.78 29.76,172 29.67,172.2 29.67,173.94
VCC_DCIN on IN1: 26.67,175.13 35.05,175.13 35.31,174.88 35.31,159.77 11.63,136.09 11.63,120.98 9.98,119.33 3.51,119.33 3,119.84 3,151.46 7.89,156.35 7.89,166.64 9.35,168.1 19.63,168.1
VCC_DCIN on IN2: 35.31,168.3 35.31,159.77 9.86,134.32 9.86,119.46 9.73,119.33 5.33,119.33 5.08,119.58 5.08,153.54 9.92,158.38 9.92,162.7 16.59,169.37 34.24,169.37
VCC_DCIN on VCC: 25.51,177.55 33.17,177.55 35.81,174.9 35.81,159.87 24.84,148.9 24.78,148.81 24.77,148.72 24.77,138.56 14.61,138.56 14.51,138.54 14.43,138.48 11.76,135.82 11.7,135.73 11.68,135.64 11.68,131.04 9.98,129.34 9.93,129.26 9.91,129.16 9.91,119.49 9.67,119.25 0.61,119.25 0.56,119.31 0.54,119.33 0.51,119.35 0.51,152.65 3.94,152.65 4.03,152.67 4.12,152.73 10.85,159.46 10.9,159.54 10.92,159.64 10.92,163.72 13.31,166.12 16,166.12 16.1,166.14 16.18,166.19 19.1,169.11 19.16,169.19 19.18,169.29 19.18,171.73 20.93,173.48 24.51,173.48 24.61,173.5 24.69,173.56 25.07,173.94 25.13,174.02 25.15,174.12 25.15,177.19
VCC_SRC on TOP: 108.58,131.44 116.46,131.44 116.59,131.32 116.59,127.38 113.79,124.59 113.79,119 113.54,118.75 108.33,118.75 107.95,119.13 107.95,130.81
VCC_SRC on TOP: 55.63,180.85 59.18,180.85 59.44,180.59 59.44,174.62 59.31,174.5 53.21,174.5 52.45,175.26 50.8,175.26 50.55,175.51 50.55,177.16 50.8,177.42 52.2,177.42
VCC_SRC on TOP: 45.34,132.21 51.82,132.21 52.07,131.95 52.07,119 51.82,118.75 45.21,118.75 44.7,119.25 44.7,131.57
VCC_SRC on TOP: 59.18,157.86 62.61,157.86 62.74,157.73 62.74,150.24 62.43,149.94 59,149.94 58.75,150.19 58.75,156.24 59.05,156.54 59.05,157.73
VCC_SRC on TOP: 71.65,181.71 75.9,181.71 76.68,180.92 76.68,178.03 77.19,177.52 78.69,177.52 78.92,177.29 78.92,175.01 78.71,174.8 77.17,174.8 75.9,173.53 70.18,173.53 69.98,173.74 69.98,175.13 70.23,175.39 72.44,175.39 73.3,176.25 73.3,177.88 71.55,179.63 71.55,181.61
VCC_SRC on BOTTOM: 52.63,132.38 52.83,132.18 52.83,118.14 52.53,117.83 45.09,117.83 44.7,118.21 44.7,130.94 44.96,131.19 47.12,131.19 48.31,132.38
VCC_SRC on IN2: 70.94,181.56 78.31,181.56 78.82,181.05 78.82,173.94 78.31,173.43 50.88,173.43 50.62,173.69 50.62,179.65 50.75,179.65 51.89,180.8 59.13,180.8 59.77,180.16 69.55,180.16
VCC_SRC on VCC: outline of 123 points within 25.27,107.7 115.44,184.53
VDD105 on IN2: 60.02,65.48 62.94,65.48 63.2,65.23 63.2,55.93 62.51,55.24 47.4,55.24 42.75,59.89 42.75,63.32 47.83,68.4 47.83,70.82 48.84,71.83 52.4,71.83 52.53,71.7 52.53,70.43 46.94,64.85 46.94,59.77 47.57,59.13 52.15,59.13 53.16,58.12 59.64,58.12 61.04,59.51 61.04,63.83 59.89,64.97 59.89,65.35
VDD105P on TOP (solid shape): 58.62,102.82 58.62,101.93 58.83,101.73 59.39,101.73 59.46,101.65 59.46,97.59 59.69,97.36 59.76,97.36 59.76,97.28 59.75,97.27 59.66,97.16 59.63,97.02 59.73,96.78 59.96,96.69 60.06,96.7 60.14,96.74 60.25,96.75 60.3,96.66 60.3,96.44 59.56,95.71 59.56,94.56 59.36,94.36 58.47,94.36 58.29,94.54 58.29,100.63 58.15,100.77 52.08,100.77 51.99,100.86 51.99,102.8 52.12,102.93 52.16,102.93 52.18,102.94 52.21,102.95 58.5,102.95
VDD105P on TOP: 66.12,92.79 66.95,92.79 67.06,92.89 67.06,96.82 66.57,97.31 66.57,97.76 66.52,97.82 66.07,97.82 66.01,97.76 66.01,92.89
VDD105P on TOP: 44.91,59.18 44.91,60.27 45,60.37 45.09,60.36 45.76,60.36 45.86,60.37 45.97,60.4 46.18,60.4 46.3,60.53 46.3,60.99 46.61,61.29 47.83,61.29 48.08,61.04 48.08,59.49 47.9,59.31 46,59.31 45.75,59.05 45.03,59.05
VDD105P on TOP: 46.05,100.03 49.1,100.03 49.23,99.9 49.23,97.74 49.1,97.61 46.18,97.61 45.92,97.87 45.92,99.9
VDD105P on VCC: 54.08,107.7 64.16,107.7 64.9,106.96 64.9,103.12 64.92,103.03 64.97,102.94 69.04,98.88 69.12,98.83 69.22,98.81 75.06,98.81 75.06,80.75 74.62,80.32 74.57,80.23 74.55,80.14 74.55,74.4 70.13,69.98 52.81,69.98 52.07,70.72 52.07,72.16 52.63,72.72 52.69,72.8 52.7,72.9 52.7,74.32 53.27,74.88 53.32,74.96 53.34,75.06 53.34,77.22 53.32,77.31 53.27,77.4 52.58,78.08 52.58,79.12 52.56,79.22 52.5,79.3 50.42,81.39 50.42,91.44 50.4,91.54 50.34,91.62 48.31,93.65 48.23,93.71 48.13,93.73 46.59,93.73 45.97,94.34 45.97,99.21 46.71,99.95 48.26,99.95 48.36,99.97 48.44,100.02 48.82,100.4 48.88,100.49 48.9,100.58 48.9,107.19 53.47,107.19 53.56,107.21 53.65,107.26
VDD105P on IN3: 50.88,72.59 59.89,72.59 60.91,71.58 60.91,59 60.4,58.5 51.46,58.5 49.89,60.07 47.45,60.07 47.29,60.22 47.29,67.36 47.96,68.02 47.96,70.56 45.16,73.36 45.16,74.88 48.59,74.88
VDD_1V8_CDC on TOP: 135,151.51 136.91,151.51 137.54,150.88 140.72,150.88 140.84,150.75 140.84,150.24 140.72,150.11 137.79,150.11 137.41,149.73 135.13,149.73 135,149.86
VDDE_A on TOP (solid shape): 101.63,92.84 101.63,91.31 101.5,91.19 100.48,91.19 100.36,91.31 100.36,92.84 100.48,92.96 101.5,92.96
VDDE_A on IN1: 100.74,87 100.74,79.63 100.23,79.12 87.78,79.12 86.39,80.52 86.39,89.15 86.77,89.53 88.93,89.53 89.56,90.17 94.89,90.17 96.67,91.95 101.24,91.95 101.63,91.57 101.63,90.55 100.1,89.03 100.1,87.63
51770_AGND on BOTTOM (solid shape): 20.4,114.07 20.4,110.06 20.27,109.93 9.68,109.93 9.12,110.49 8.15,110.49 7.95,110.69 7.95,115.14 8.2,115.39 19.08,115.39
51770_VCC on TOP: 12.14,118.31 13.16,118.31 13.28,118.19 13.28,117.93 12.9,117.55 12.9,117.17 12.78,117.04 12.14,117.04 12.01,117.17 12.01,118.19
51770_VCC on BOTTOM: 15.32,119.71 15.44,119.58 15.44,117.17 15.19,116.92 12.14,116.92 12.01,117.04 12.01,119.58 12.14,119.71
ASM_VCC33 on TOP (solid shape): 52.22,95.45 52.22,92.15 52.55,91.82 57.43,91.82 57.48,91.77 57.48,90.78 58.5,89.76 69.14,89.76 69.19,89.71 69.19,88.87 69.09,88.77 57.61,88.77 55.32,91.06 52.73,91.06 52.1,90.42 52.1,84.58 49.81,82.3 40.41,82.3 40.03,82.68 40.03,85.22 41.68,86.87 43.08,86.87 43.59,87.38 49.3,87.38 49.68,87.76 49.68,90.68 49.54,90.82 50.41,90.82 50.41,90.79 50.42,90.72 50.43,90.66 50.46,90.6 50.49,90.55 50.53,90.5 50.57,90.45 50.62,90.42 50.68,90.38 50.73,90.36 50.79,90.34 50.86,90.34 50.92,90.34 50.98,90.34 51.04,90.36 51.1,90.38 51.16,90.42 51.21,90.45 51.25,90.5 51.29,90.55 51.32,90.6 51.35,90.66 51.36,90.72 51.37,90.79 51.37,90.85 51.36,90.92 51.34,90.99 51.31,91.05 51.3,91.08 51.3,91.56 51.06,91.8 50.72,91.8 50.48,91.56 50.48,91.08 50.46,91.05 50.44,90.99 50.42,90.92 50.41,90.85 50.41,90.82 49.54,90.82 49.33,91.03 49.33,95.55 49.58,95.81 51.87,95.81
ASM_VCC33 on BOTTOM: 49.5,47.32 50.77,47.32 50.83,47.27 50.83,46.58 50.93,46.48 54.08,46.48 54.13,46.43 54.13,45.49 54,45.36 49.5,45.36 49.33,45.54 49.33,47.14
ASM_VCC33 on IN1: 52.27,46.05 51.51,45.29 44.02,45.29 42.88,46.43 34.24,46.43 32.59,48.08 32.59,67.01 35.76,70.18 35.76,77.55 36.02,77.8 36.14,77.8 36.14,82.75 37.8,84.4 46.18,84.4 47.45,83.13 47.45,78.94 49.73,76.66 49.73,73.23 52.15,70.82 59.26,70.82 60.4,69.67 60.4,66.12 59.39,65.1 43.64,65.1 42.24,66.5 38.18,66.5 37.41,65.74 37.41,59.64 37.92,59.13 42.24,59.13 42.49,58.88 48.97,58.88 49.23,59.13 49.99,59.13 52.27,56.85
ASM_VCC33 on IN3: 67.77,101.3 74.88,101.3 75.59,100.58 75.59,78.11 75.21,77.72 75.08,77.72 73.43,76.07 70,76.07 69.24,75.31 64.16,75.31 63.78,75.69 63.78,78.23 66.7,81.15 66.7,88.9 66.5,89.1 56.08,89.1 56.03,89.15 52.73,89.15 52.4,89.48 52.4,91.64 52.46,91.71 52.46,95.49 53.87,96.9 67.34,96.9 67.51,97.08 67.51,101.04
CAN_REF on TOP: 36.58,188.21 38.73,188.21 38.86,188.34 38.86,189.74 39.37,190.25 41.53,190.25 41.78,190.5 41.78,192.41 41.66,192.53 40.59,192.53 40.39,192.74 40.34,192.74 40.34,194.39 39.95,194.77 30.94,194.77 30.05,193.88 30.05,188.42 30.18,188.29 30.81,188.29 30.94,188.42 30.94,190.45 31.57,191.08 31.57,193.5 31.83,193.75 36.27,193.75 36.45,193.57 36.45,188.34
CAN_REF on BOTTOM: 40.39,191.01 40.26,190.88 38.1,190.88 37.97,191.01 37.97,194.44 38.61,195.07 38.61,198.12 38.86,198.37 40.13,198.37 40.39,198.12
CASE1_GND on TOP: 24.26,198.5 30.23,198.5 30.35,198.37 30.35,196.8 29.39,195.83 24.26,195.83 24.13,195.96 24.13,198.37
CASE1_GND on BOTTOM: 30.23,198.5 30.35,198.37 30.35,195.96 30.23,195.83 23.88,195.83 23.75,195.96 23.75,198.25 24,198.5
HDMI_GND on TOP: 110.82,43.13 110.57,42.88 106.88,42.88 104.22,40.21 96.98,40.21 92.79,44.4 92.79,50.11 93.04,50.37 96.85,50.37 97.1,50.11 97.1,47.96 97.87,47.19 110.44,47.19 110.82,46.81
ISO12_REF on TOP: 42.8,189.87 42.55,189.61 39.62,189.61 39.37,189.36 39.37,184.02 39.62,183.77 42.04,183.77 42.29,184.02 42.29,187.45 42.55,187.71 52.83,187.71 53.59,188.47 53.59,190.63 55.37,192.41 55.37,198.37 55.24,198.5 43.18,198.5 42.8,198.12
ISO12_REF on BOTTOM: 41.02,193.55 45.97,193.55 46.23,193.29 46.23,189.87 45.97,189.61 41.02,189.61 40.89,189.74 40.89,193.42
ISO_+V12S on TOP: 43.43,183.13 59.69,183.13 59.94,183.39 59.94,192.02 61.34,193.42 61.34,198.37 61.21,198.5 59.82,198.5 59.69,198.37 59.69,195.96 57.78,194.06 57.78,191.26 57.02,190.5 57.02,187.71 56.52,187.2 43.18,187.2 42.93,186.94 42.93,183.64
ISO_+V12S on BOTTOM: 52.96,187.2 53.34,186.82 53.34,185.29 53.72,184.91 56.13,184.91 56.77,185.55 59.18,185.55 59.44,185.29 59.44,183.51 59.05,183.13 43.43,183.13 41.02,185.55 41.02,188.34 41.15,188.47 43.43,188.47 43.56,188.34 43.56,187.83 43.69,187.71 43.69,187.07 44.45,186.31 46.74,186.31 47.62,187.2
ISO_+V12S on IN1: 43.31,183.13 59.69,183.13 59.94,183.39 59.94,192.02 60.58,192.66 60.71,192.66 61.34,193.29 61.34,198.37 61.21,198.5 41.15,198.5 40.77,198.12 40.77,195.33 42.8,193.29 42.8,183.64
ISO_GND on TOP: 68.83,183.77 70.74,183.77 70.87,183.9 70.87,186.18 70.74,186.31 68.83,186.31 68.71,186.18 68.71,183.9
ISO_GND on TOP: 69.47,192.66 74.8,192.66 77.34,190.12 78.74,190.12 78.87,189.99 78.87,188.09 78.74,187.96 75.69,187.96 74.3,189.36 69.34,189.36 69.22,189.48 69.22,192.41
ISO_GND on BOTTOM: 68.45,192.66 74.8,192.66 77.34,190.12 78.74,190.12 78.87,189.99 78.87,188.09 78.74,187.96 75.69,187.96 74.3,189.36 68.07,189.36 67.94,189.48 67.94,192.15
ISO_GND on GND1, VCC, GND2: 24.64,199.49 100.58,199.49 100.58,193.06 91.55,184.02 63.37,184.02 62.89,183.93 62.47,183.65 61.96,183.13 43.2,183.13 42.55,183.78 42.14,184.05 41.66,184.15 37.61,184.15 35.06,186.7 34.65,186.97 34.16,187.07 27.7,187.07 24.64,190.14
LAN1_CT1_A+_V- on TOP: 12.01,13.03 12.14,12.9 12.14,11.63 11.76,11.25 11.76,9.22 11.63,9.09 10.24,9.09 8.59,10.74 6.05,10.74 5.92,10.87 5.92,13.54 6.05,13.67 8.46,13.67 9.09,13.03
LAN1_CT1_A+_V- on BOTTOM: 11.76,11.38 11.76,5.92 11.63,5.79 10.36,5.79 10.24,5.92 10.24,11.38 10.36,11.51 11.63,11.51
LAN1_CT2_A-_V+ on TOP: 13.41,13.03 15.57,13.03 15.7,12.9 15.7,9.6 15.57,9.47 14.68,9.47 14.05,10.11 14.05,10.87 13.28,11.63 13.28,12.9
LAN1_CT2_A-_V+ on BOTTOM: 15.82,9.6 15.7,9.47 14.68,9.47 12.14,12.01 9.86,12.01 8.59,10.74 6.05,10.74 5.92,10.87 5.92,13.54 6.05,13.67 8.46,13.67 9.09,13.03 15.57,13.03 15.82,12.78
LAN1_CT3_B+_V+ on TOP: 17.98,13.03 19.76,13.03 19.89,12.9 19.89,9.47 19.76,9.35 17.98,9.35 17.86,9.47 17.86,12.9
LAN1_CT3_B+_V+ on TOP: 8.59,9.73 8.59,6.43 8.46,6.3 5.92,6.3 5.79,6.43 5.79,9.86 5.92,9.98 8.33,9.98
LAN1_CT3_B+_V+ on BOTTOM: 17.98,11.89 19.76,11.89 19.89,11.76 19.89,9.47 19.76,9.35 17.98,9.35 17.86,9.47 17.86,11.76
LAN1_CT3_B+_V+ on IN1: 17.73,11.63 20.14,11.63 20.27,11.51 20.27,9.09 20.02,8.84 6.17,8.84 6.05,8.97 6.05,10.49 6.3,10.74 16.84,10.74
LAN1_CT4_B-_V- on TOP: 22.3,12.9 23.83,12.9 23.95,12.78 23.95,9.47 23.83,9.35 22.3,9.35 22.17,9.47 22.17,12.78
LAN1_CT4_B-_V- on BOTTOM: 8.59,9.09 8.59,5.54 8.46,5.41 5.92,5.41 5.79,5.54 5.79,9.09 5.92,9.22 8.46,9.22
LAN1_CT4_B-_V- on BOTTOM: 22.3,11.89 23.83,11.89 23.95,11.76 23.95,9.47 23.83,9.35 22.3,9.35 22.17,9.47 22.17,11.76
LAN1_CT4_B-_V- on IN1: 21.29,11.63 24.21,11.63 24.46,11.38 24.46,6.43 23.32,5.28 6.17,5.28 5.92,5.54 5.92,8.08 6.05,8.2 20.4,8.2 21.03,8.84 21.03,11.38
LAN2_CT1_A+_V- on TOP: 34.42,11.43 34.04,11.05 34.04,9.4 33.91,9.27 32.64,9.27 31.27,10.64 28.47,10.64 28.37,10.74 28.37,12.95 28.45,13.03 34.24,13.03 34.42,12.85
LAN2_CT1_A+_V- on BOTTOM: 34.72,11.28 34.72,7.92 34.67,7.87 32.66,7.87 32.51,8.03 32.51,11.35 32.64,11.48 34.52,11.48
LAN2_CT2_A-_V+ on TOP: 38.46,11.61 37.77,10.92 37.77,9.47 37.72,9.42 36.42,9.42 36.32,9.53 36.32,12.83 36.45,12.95 38.4,12.95 38.46,12.9
LAN2_CT2_A-_V+ on BOTTOM: 37.95,10.19 37.74,9.98 37.74,7.9 37.72,7.87 37.06,7.87 37.03,7.9 37.03,10.49 35.6,11.93 32.32,11.93 31.27,10.87 28.45,10.87 28.4,10.92 28.4,12.95 28.47,13.03 37.62,13.03 37.95,12.7
LAN3_CT1_A+_V- on TOP: 54.61,11.43 54.23,11.05 54.23,9.4 54.1,9.27 52.83,9.27 51.46,10.64 48.67,10.64 48.56,10.74 48.56,12.95 48.64,13.03 54.43,13.03 54.61,12.85
LAN3_CT1_A+_V- on BOTTOM: 54.91,11.28 54.91,7.92 54.86,7.87 52.93,7.87 52.73,8.08 52.73,11.33 52.88,11.48 54.71,11.48
LAN3_CT2_A-_V+ on TOP: 58.65,11.61 57.96,10.92 57.96,9.47 57.91,9.42 56.62,9.42 56.52,9.53 56.52,12.83 56.64,12.95 58.6,12.95 58.65,12.9
LAN3_CT2_A-_V+ on BOTTOM: 58.14,10.19 57.94,9.98 57.94,7.9 57.91,7.87 57.25,7.87 57.23,7.9 57.23,10.49 55.79,11.93 52.51,11.93 51.46,10.87 48.64,10.87 48.59,10.92 48.59,12.95 48.67,13.03 57.81,13.03 58.14,12.7
LAN4_CT1_A+_V- on TOP: 74.8,11.43 74.42,11.05 74.42,9.4 74.3,9.27 73.03,9.27 71.65,10.64 68.86,10.64 68.76,10.74 68.76,12.95 68.83,13.03 74.63,13.03 74.8,12.85
LAN4_CT1_A+_V- on BOTTOM: 75.11,11.28 75.11,7.92 75.06,7.87 73.15,7.87 72.97,8.05 72.97,11.33 73.13,11.48 74.9,11.48
LAN4_CT2_A-_V+ on TOP: 78.84,11.61 78.16,10.92 78.16,9.47 78.11,9.42 76.81,9.42 76.71,9.53 76.71,12.83 76.83,12.95 78.79,12.95 78.84,12.9
LAN4_CT2_A-_V+ on BOTTOM: 78.33,10.19 78.13,9.98 78.13,7.9 78.11,7.87 77.44,7.87 77.42,7.9 77.42,10.49 75.98,11.93 72.71,11.93 71.65,10.87 68.83,10.87 68.78,10.92 68.78,12.95 68.86,13.03 78,13.03 78.33,12.7
LAN5_CT1_A+_V- on TOP: 95,11.43 94.61,11.05 94.61,9.4 94.49,9.27 93.22,9.27 91.85,10.64 89.05,10.64 88.95,10.74 88.95,12.95 89.03,13.03 94.82,13.03 95,12.85
LAN5_CT1_A+_V- on BOTTOM: 95.3,11.28 95.3,7.92 95.25,7.87 93.32,7.87 93.19,8 93.19,11.35 93.32,11.48 95.1,11.48
LAN5_CT2_A-_V+ on TOP: 99.03,11.61 98.35,10.92 98.35,9.47 98.3,9.42 97,9.42 96.9,9.53 96.9,12.83 97.03,12.95 98.98,12.95 99.03,12.9
LAN5_CT2_A-_V+ on BOTTOM: 98.53,10.19 98.32,9.98 98.32,7.9 98.3,7.87 97.64,7.87 97.61,7.9 97.61,10.49 96.18,11.93 92.9,11.93 91.85,10.87 89.03,10.87 88.98,10.92 88.98,12.95 89.05,13.03 98.2,13.03 98.53,12.7
LAN6_CT1_A+_V- on TOP: 115.19,11.43 114.81,11.05 114.81,9.4 114.68,9.27 113.41,9.27 112.04,10.64 109.25,10.64 109.14,10.74 109.14,12.95 109.22,13.03 115.01,13.03 115.19,12.85
LAN6_CT1_A+_V- on BOTTOM: 115.49,11.28 115.49,7.92 115.44,7.87 113.54,7.87 113.28,8.13 113.28,11.25 113.51,11.48 115.29,11.48
LAN6_CT2_A-_V+ on TOP: 119.23,11.61 118.54,10.92 118.54,9.47 118.49,9.42 117.2,9.42 117.09,9.53 117.09,12.83 117.22,12.95 119.18,12.95 119.23,12.9
LAN6_CT2_A-_V+ on BOTTOM: 118.72,10.19 118.52,9.98 118.52,7.9 118.49,7.87 117.83,7.87 117.81,7.9 117.81,10.49 116.37,11.93 113.09,11.93 112.04,10.87 109.22,10.87 109.17,10.92 109.17,12.95 109.25,13.03 118.39,13.03 118.72,12.7
LAN7_CT1_A+_V- on TOP: 135.38,11.43 135,11.05 135,9.4 134.87,9.27 133.6,9.27 132.23,10.64 129.44,10.64 129.34,10.74 129.34,12.95 129.41,13.03 135.2,13.03 135.38,12.85
LAN7_CT1_A+_V- on BOTTOM: 135.69,11.28 135.69,7.92 135.64,7.87 133.6,7.87 133.48,8 133.48,11.3 133.65,11.48 135.48,11.48
LAN7_CT2_A-_V+ on TOP: 139.42,11.61 138.73,10.92 138.73,9.47 138.68,9.42 137.39,9.42 137.29,9.53 137.29,12.83 137.41,12.95 139.37,12.95 139.42,12.9
LAN7_CT2_A-_V+ on BOTTOM: 138.91,10.19 138.71,9.98 138.71,7.9 138.68,7.87 138.02,7.87 138,7.9 138,10.49 136.56,11.93 133.29,11.93 132.23,10.87 129.41,10.87 129.36,10.92 129.36,12.95 129.44,13.03 138.58,13.03 138.91,12.7
LAN_GND on TOP (solid shape): 1.02,1.02 25.71,1.02 25.6,0.77 25.57,0.51 0.51,0.51 0.51,15.57 1.02,15.57
LAN_GND on TOP (solid shape): 159.49,0.51 147.17,0.51 147.15,0.74 147.07,0.96 147.1,1 147.16,1.02 158.98,1.02 158.98,56.39 159.16,56.87 158.98,57.36 158.98,57.53 159.49,57.53
LAN_GND on BOTTOM (solid shape): 149.63,61.47 149.63,59.82 149.5,59.69 145.19,59.69 145.06,59.82 145.06,61.47 145.31,61.72 149.38,61.72
LAN_GND on BOTTOM (solid shape): 1.02,1.02 25.71,1.02 25.6,0.77 25.57,0.51 0.51,0.51 0.51,15.85 1.02,15.85
LAN_GND on BOTTOM (solid shape): 159.49,0.51 147.17,0.51 147.15,0.74 147.07,0.96 147.1,1 147.16,1.02 158.98,1.02 158.98,56.33 159.49,56.33
LAN_GND on IN1 (solid shape): 1.02,1.02 25.71,1.02 25.6,0.77 25.57,0.51 0.51,0.51 0.51,15.85 1.02,15.85
LAN_GND on IN1 (solid shape): 159.49,0.51 147.17,0.51 147.14,0.77 147.03,1.02 158.98,1.02 158.98,56.33 159.49,56.33
LAN_GND on IN2 (solid shape): 1.02,1.02 25.71,1.02 25.6,0.77 25.57,0.51 0.51,0.51 0.51,15.84 1.02,15.84
LAN_GND on IN2 (solid shape): 159.49,0.51 147.17,0.51 147.14,0.77 147.03,1.02 158.98,1.02 158.98,56.01 159.49,56.01
LAN_GND on IN3 (solid shape): 1.02,1.02 25.71,1.02 25.6,0.77 25.57,0.51 0.51,0.51 0.51,15.88 1.02,15.88
LAN_GND on IN3 (solid shape): 159.49,0.51 147.17,0.51 147.14,0.77 147.03,1.02 158.98,1.02 158.98,56.26 159.49,56.26
LAN_GND on TOP: 1.32,16.38 3.96,16.38 4.14,16.21 4.14,5.66 4.39,5.41 10.59,5.41 12.5,7.32 26.09,7.32 27.41,8.64 32.41,8.64 33.73,7.32 47.14,7.32 48.46,8.64 54.03,8.64 55.35,7.32 67.54,7.32 68.86,8.64 74.22,8.64 75.54,7.32 87.73,7.32 89.05,8.64 94.39,8.64 95.71,7.32 107.92,7.32 109.25,8.64 114.68,8.64 116,7.32 128.12,7.32 129.44,8.64 134.8,8.64 136.12,7.32 147.93,7.32 148.06,7.19 148.06,3.66 147.9,3.51 1.47,3.51 1.22,3.76 1.22,16.28
LAN_GND on TOP: 151.69,56.13 151.82,56.26 153.16,56.26 153.29,56.13 153.29,43.18 153.16,43.05 150.88,43.05 150.75,43.18 150.75,44.32 151.69,45.26
LAN_GND on TOP: 145.16,56.52 147.07,56.52 147.19,56.39 147.19,54.86 147.07,54.74 145.16,54.74 145.03,54.86 145.03,56.39
LAN_GND on TOP: 145.31,61.72 149.38,61.72 149.63,61.47 149.63,59.82 149.5,59.69 145.19,59.69 145.06,59.82 145.06,61.47
LAN_GND on TOP: 145.41,46.35 147.7,46.35 147.83,46.23 147.83,44.96 147.7,44.83 145.41,44.83 145.29,44.96 145.29,46.23
LAN_GND on TOP: 25.4,12.9 27.53,12.9 27.64,12.8 27.64,11.25 27.43,11.05 25.58,11.05 25.35,11.28 25.35,12.85
LAN_GND on TOP: 145.29,51.44 146.94,51.44 147.07,51.31 147.07,49.66 146.94,49.53 145.29,49.53 145.16,49.66 145.16,51.31
LAN_GND on BOTTOM: 48.77,8.64 51.82,8.64 51.94,8.51 51.94,5.71 51.82,5.59 48.77,5.59 48.64,5.71 48.64,8.51
LAN_GND on BOTTOM: 129.54,8.64 132.59,8.64 132.72,8.51 132.72,5.71 132.59,5.59 129.54,5.59 129.41,5.71 129.41,8.51
LAN_GND on BOTTOM: 109.35,8.64 112.39,8.64 112.52,8.51 112.52,5.71 112.39,5.59 109.35,5.59 109.22,5.71 109.22,8.51
LAN_GND on BOTTOM: 68.96,8.64 72.01,8.64 72.14,8.51 72.14,5.71 72.01,5.59 68.96,5.59 68.83,5.71 68.83,8.51
LAN_GND on BOTTOM: 4.14,5.54 4.01,5.41 1.47,5.41 1.35,5.54 1.35,16.23 1.5,16.38 3.96,16.38 4.14,16.21
LAN_GND on BOTTOM: 89.15,8.64 92.2,8.64 92.33,8.51 92.33,5.71 92.2,5.59 89.15,5.59 89.03,5.71 89.03,8.51
LAN_GND on BOTTOM: 28.57,8.64 31.62,8.64 31.75,8.51 31.75,5.71 31.62,5.59 28.57,5.59 28.45,5.71 28.45,8.51
LAN_GND on GND1, VCC, GND2: 145.24,61.72 149.4,61.72 153.31,57.81 153.48,57.7 153.67,57.66 159.49,57.66 159.49,0.51 0.51,0.51 0.51,15.88 6.52,15.88 9.29,13.1 9.46,12.99 9.65,12.95 145.92,12.95 146.12,12.99 146.28,13.1 148.44,15.26 148.55,15.43 148.59,15.62 148.59,16.81 149.05,17.27 151.38,17.27 151.58,17.31 151.74,17.42 152.76,18.44 152.87,18.6 152.91,18.8 152.91,23.03 154.03,24.15 154.14,24.32 154.18,24.51 154.18,41.15 154.14,41.34 154.03,41.51 153.14,42.4 152.98,42.51 152.78,42.55 150.5,42.55 150.3,42.51 150.14,42.4 149.78,42.04 145.24,42.04 144.78,42.5 144.78,61.26
LAN_GND on IN1: 9.45,12.88 158.14,12.88 158.55,12.47 158.55,4.14 157.84,3.43 1.75,3.43 1.35,3.84 1.35,14.83 1.93,15.42 6.91,15.42 ; 1 cut-out
LAN_GND on IN1: 145.24,61.67 149.43,61.67 153.47,57.63 157.71,57.63 158.55,56.79 158.55,38.89 158.04,38.38 154.79,38.38 154.25,38.91 154.25,41.43 153.09,42.6 150.24,42.6 149.73,42.09 145.26,42.09 144.81,42.55 144.81,61.24
LAN_GND on IN2: 1.73,15.82 6.45,15.82 9.45,12.83 146.08,12.83 148.69,15.44 152.43,15.44 154.33,17.35 154.33,41.33 153.06,42.6 150.27,42.6 149.73,42.06 145.24,42.06 144.81,42.49 144.81,61.24 145.29,61.72 149.38,61.72 153.49,57.61 158.47,57.61 158.6,57.48 158.6,4.06 157.86,3.33 1.7,3.33 1.35,3.68 1.35,15.44
LAN_GND on IN3: 6.45,15.85 9.4,12.9 146.15,12.9 148.69,15.44 152.43,15.44 154.33,17.35 154.33,41.33 153.06,42.6 150.27,42.6 149.73,42.06 145.24,42.06 144.81,42.49 144.81,61.24 145.26,61.7 149.4,61.7 153.49,57.61 158.47,57.61 158.6,57.48 158.6,4.06 157.86,3.33 1.7,3.33 1.32,3.71 1.32,15.42 1.75,15.85
MCU2_VDD on BOTTOM: 143.03,80.14 144.81,80.14 144.93,80.01 144.93,77.85 144.81,77.72 143.03,77.72 142.9,77.85 142.9,80.01
MCU2_VDD on IN2: 135.31,80.77 150.65,80.77 151.54,79.88 151.54,66.55 148.29,63.3 148.29,63.27 147.93,62.92 144.81,62.92 143.61,61.72 143.61,60.91 143.28,60.58 121.95,60.58 115.98,66.55 115.98,75.56 119.39,78.98 133.52,78.98
MCU_VDD on TOP: 131.6,97.92 138.33,97.92 138.46,97.79 138.46,93.6 138.33,93.47 131.6,93.47 131.47,93.6 131.47,97.79
MCU_VDD on BOTTOM: 145.44,80.14 146.96,80.14 147.09,80.01 147.09,77.85 146.96,77.72 145.44,77.72 145.31,77.85 145.31,80.01
MCU_VDD on BOTTOM: 131.6,93.73 131.47,93.85 131.47,97.79 131.72,98.04 137.57,98.04 137.69,97.92 137.69,93.85 137.57,93.73
MCU_VDD on IN1: 131.6,97.92 138.33,97.92 138.46,97.79 138.46,94.11 138.84,93.73 142.52,93.73 143.41,94.61 145.69,94.61 152.81,87.5 152.81,81.41 149.12,77.72 145.57,77.72 145.44,77.85 145.44,80.14 145.57,80.26 148.62,80.26 151.16,82.8 151.16,87.25 147.98,90.42 138.2,90.42 135.79,92.84 131.72,92.84 131.47,93.09 131.47,97.79
POE_56 on BOTTOM (solid shape): 28.52,116.28 28.52,100.53 27.89,99.9 13.16,99.9 12.9,100.15 12.9,105.23 13.03,105.36 20.27,105.36 21.36,106.45 21.36,116.28 21.62,116.54 28.27,116.54
POE_56 on TOP: 13.16,99.9 12.9,100.15 12.9,105.49 13.16,105.74 18.01,105.74 18.44,106.17 18.44,106.88 18.57,107.01 20.52,107.01 20.9,107.39 20.9,116.66 21.16,116.92 28.27,116.92 28.52,116.66 28.52,100.53 27.89,99.9
POE_GATE on TOP: 17.73,94.44 17.86,94.31 17.86,89.48 17.73,89.36 12.52,89.36 12.27,89.1 12.27,85.42 12.14,85.29 7.44,85.29 6.93,84.79 4.27,84.79 4.14,84.91 4.14,87.58 5.79,89.23 5.79,94.18 6.05,94.44
POE_IN on TOP, IN3: 6.73,156.72 9.53,156.72 9.91,157.1 9.91,163.96 14.48,168.53 14.48,172.34 12.57,174.24 11.3,174.24 10.16,175.39 10.16,176.91 9.78,177.29 6.1,177.29 5.08,176.28 5.08,169.67 1.14,165.74 1.14,100.48 1.6,100.03 11.3,100.03 11.56,100.28 11.56,105.56 11.25,105.87 5.16,105.87 4.45,106.58 4.45,154.43
POE_IN on BOTTOM: 6.68,177.75 13.67,177.75 14.05,177.37 14.05,174.07 14.94,173.18 14.94,168.22 9.86,163.14 9.86,155.14 5.28,150.57 5.28,109.8 11.89,103.2 11.89,101.17 11.13,100.41 3.51,100.41 2.49,101.42 2.49,164.29 6.17,167.97 6.17,177.24
POE_IN on IN2: 14.48,168.53 14.48,172.34 12.57,174.24 11.3,174.24 10.16,175.39 10.16,176.91 9.78,177.29 6.1,177.29 5.08,176.28 5.08,169.67 1.14,165.74 1.14,100.48 1.6,100.03 11.3,100.03 11.56,100.28 11.56,105.56 11.25,105.87 5.16,105.87 4.45,106.58 4.45,154.43 8.97,158.95 8.97,163.02
POE_IN_MOS on TOP: 9.98,99.52 10.11,99.39 10.11,98.12 10.36,97.87 11.25,97.87 11.38,97.74 11.38,95.45 11.25,95.33 7.95,95.33 7.82,95.45 7.82,96.72 7.7,96.85 5.41,96.85 5.16,96.6 5.16,94.44 4.65,93.93 1.6,93.93 1.35,94.18 1.35,99.26 1.6,99.52
POE_OUT1A on TOP: 1.85,55.96 3.89,55.96 4.01,55.83 4.01,53.92 3.89,53.8 1.85,53.8 1.73,53.92 1.73,55.83
POE_OUT1A on BOTTOM: 1.6,55.96 4.39,55.96 4.65,55.7 4.65,49.23 4.52,49.1 1.6,49.1 1.47,49.23 1.47,55.83
POE_OUT1B on TOP: 9.35,55.96 11.38,55.96 11.51,55.83 11.51,53.92 11.38,53.8 9.35,53.8 9.22,53.92 9.22,55.83
POE_OUT1B on BOTTOM: 9.09,55.96 11.89,55.96 12.14,55.7 12.14,49.23 12.01,49.1 9.09,49.1 8.97,49.23 8.97,55.83
POE_OUT2 on TOP: 2.62,65.1 2.49,65.23 2.49,67.89 2.62,68.02 4.01,68.02 4.14,67.89 4.14,65.23 4.01,65.1
POE_OUT2 on TOP: 32.77,15.75 34.42,15.75 34.54,15.62 34.54,14.1 34.42,13.97 32.77,13.97 32.64,14.1 32.64,15.62
POE_OUT2 on BOTTOM: 4.65,60.53 4.52,60.4 1.6,60.4 1.47,60.53 1.47,67.89 1.6,68.02 4.52,68.02 4.65,67.89
POE_OUT2 on IN2: 34.32,16 34.44,15.88 34.44,14.73 34.32,14.61 31.52,14.61 31.39,14.73 31.39,15.88 31.52,16
POE_OUT2 on IN2: 2.95,68.2 4.6,68.2 4.72,68.07 4.72,66.17 4.6,66.04 2.82,66.04 2.69,66.17 2.69,67.94
POE_OUT3 on TOP: 9.35,67.26 11.38,67.26 11.51,67.13 11.51,65.23 11.38,65.1 9.35,65.1 9.22,65.23 9.22,67.13
POE_OUT3 on TOP: 52.96,15.75 54.61,15.75 54.74,15.62 54.74,14.1 54.61,13.97 52.96,13.97 52.83,14.1 52.83,15.62
POE_OUT3 on BOTTOM: 9.09,67.26 11.89,67.26 12.14,67.01 12.14,60.53 12.01,60.4 9.09,60.4 8.97,60.53 8.97,67.13
POE_OUT3 on IN2: 52.6,16 54.25,16 54.38,15.88 54.38,14.48 54.25,14.35 52.6,14.35 52.48,14.48 52.48,15.88
POE_OUT3 on IN2: 8.92,67.31 11.07,67.31 11.2,67.18 11.2,64.64 11.07,64.52 8.92,64.52 8.79,64.64 8.79,67.18
POE_OUT4 on TOP: 16.84,55.96 18.87,55.96 19,55.83 19,53.92 18.87,53.8 16.84,53.8 16.71,53.92 16.71,55.83
POE_OUT4 on TOP: 73.15,15.75 74.8,15.75 74.93,15.62 74.93,14.1 74.8,13.97 73.15,13.97 73.03,14.1 73.03,15.62
POE_OUT4 on BOTTOM: 16.59,55.96 19.38,55.96 19.63,55.7 19.63,49.23 19.51,49.1 16.59,49.1 16.46,49.23 16.46,55.83
POE_OUT4 on IN2: 16.66,55.75 18.44,55.75 18.57,55.63 18.57,53.85 18.44,53.72 16.66,53.72 16.54,53.85 16.54,55.63
POE_OUT4 on IN2: 72.16,16.13 74.57,16.13 74.7,16 74.7,14.61 74.57,14.48 72.16,14.48 72.03,14.61 72.03,16
POE_OUT5 on TOP: 16.84,67.26 18.87,67.26 19,67.13 19,65.23 18.87,65.1 16.84,65.1 16.71,65.23 16.71,67.13
POE_OUT5 on TOP: 93.34,15.75 95,15.75 95.12,15.62 95.12,14.1 95,13.97 93.34,13.97 93.22,14.1 93.22,15.62
POE_OUT5 on BOTTOM: 16.59,67.26 19.38,67.26 19.63,67.01 19.63,60.53 19.51,60.4 16.59,60.4 16.46,60.53 16.46,67.13
POE_OUT5 on IN2: 92.1,16 94.64,16 94.77,15.88 94.77,14.61 94.64,14.48 91.97,14.48 91.85,14.61 91.85,15.75
POE_OUT5 on IN2: 16.79,67.06 18.69,67.06 18.82,66.93 18.82,65.02 18.57,64.77 16.79,64.77 16.54,65.02 16.54,66.8
POE_OUT6 on TOP: 113.54,15.75 115.19,15.75 115.32,15.62 115.32,14.1 115.19,13.97 113.54,13.97 113.41,14.1 113.41,15.62
POE_OUT6 on TOP: 24.33,55.96 26.37,55.96 26.49,55.83 26.49,53.92 26.37,53.8 24.33,53.8 24.21,53.92 24.21,55.83
POE_OUT6 on BOTTOM: 24.08,55.96 26.87,55.96 27.13,55.7 27.13,49.23 27,49.1 24.08,49.1 23.95,49.23 23.95,55.83
POE_OUT6 on IN2: 113.31,15.88 114.96,15.88 115.09,15.75 115.09,14.48 114.96,14.35 113.18,14.35 113.06,14.48 113.06,15.62
POE_OUT6 on IN2: 25.3,55.5 25.43,55.37 25.43,53.34 25.3,53.21 23.9,53.21 23.77,53.34 23.77,55.37 23.9,55.5
POE_OUT7 on TOP: 24.33,67.26 26.37,67.26 26.49,67.13 26.49,65.23 26.37,65.1 24.33,65.1 24.21,65.23 24.21,67.13
POE_OUT7 on TOP: 133.73,15.75 135.38,15.75 135.51,15.62 135.51,14.1 135.38,13.97 133.73,13.97 133.6,14.1 133.6,15.62
POE_OUT7 on BOTTOM: 24.08,67.26 26.87,67.26 27.13,67.01 27.13,60.53 27,60.4 24.08,60.4 23.95,60.53 23.95,67.13
POE_OUT7 on IN2: 24.03,67.06 25.81,67.06 25.93,66.93 25.93,64.9 25.68,64.64 24.03,64.64 23.77,64.9 23.77,66.8
POE_OUT7 on IN2: 133.12,16 135.03,16 135.15,15.88 135.15,14.86 135.03,14.73 132.99,14.73 132.87,14.86 132.87,15.75
POE_VCC on TOP: 58.93,14.1 58.8,13.97 56.9,13.97 56.77,14.1 56.77,15.62 56.9,15.75 58.8,15.75 58.93,15.62
POE_VCC on TOP: 79.12,14.1 78.99,13.97 77.09,13.97 76.96,14.1 76.96,15.62 77.09,15.75 78.99,15.75 79.12,15.62
POE_VCC on TOP: 139.7,14.1 139.57,13.97 137.67,13.97 137.54,14.1 137.54,15.62 137.67,15.75 139.57,15.75 139.7,15.62
POE_VCC on TOP: 13.41,13.79 19.76,13.79 19.89,13.92 19.89,16.08 19.76,16.21 13.41,16.21 13.28,16.08 13.28,13.92
POE_VCC on TOP: 99.31,14.1 99.19,13.97 97.28,13.97 97.16,14.1 97.16,15.62 97.28,15.75 99.19,15.75 99.31,15.62
POE_VCC on TOP: 38.73,14.1 38.61,13.97 36.7,13.97 36.58,14.1 36.58,15.62 36.7,15.75 38.61,15.75 38.73,15.62
POE_VCC on TOP: 119.51,14.1 119.38,13.97 117.47,13.97 117.35,14.1 117.35,15.62 117.47,15.75 119.38,15.75 119.51,15.62
POE_VCC on TOP: 13.03,88.85 19.51,88.85 19.63,88.72 19.63,83.77 19.51,83.64 13.03,83.64 12.9,83.77 12.9,88.72
POE_VCC on BOTTOM: 12.01,71.83 13.03,71.83 13.16,71.7 13.16,69.67 13.03,69.55 12.01,69.55 11.89,69.67 11.89,71.7
POE_VCC on BOTTOM: 27.89,49.1 27.76,49.23 27.76,54.05 27.89,54.18 30.81,54.18 30.94,54.05 30.94,49.23 30.81,49.1
POE_VCC on BOTTOM: 27.89,60.4 27.76,60.53 27.76,65.35 27.89,65.48 30.81,65.48 30.94,65.35 30.94,60.53 30.81,60.4
POE_VCC on BOTTOM: 12.9,60.4 12.78,60.53 12.78,65.35 12.9,65.48 15.82,65.48 15.95,65.35 15.95,60.53 15.82,60.4
POE_VCC on BOTTOM: 20.4,49.1 20.27,49.23 20.27,54.05 20.4,54.18 23.32,54.18 23.44,54.05 23.44,49.23 23.32,49.1
POE_VCC on BOTTOM: 5.41,60.4 5.28,60.53 5.28,65.35 5.41,65.48 8.33,65.48 8.46,65.35 8.46,60.53 8.33,60.4
POE_VCC on BOTTOM: 5.41,49.1 5.28,49.23 5.28,54.05 5.41,54.18 8.33,54.18 8.46,54.05 8.46,49.23 8.33,49.1
POE_VCC on BOTTOM: 12.9,49.1 12.78,49.23 12.78,54.05 12.9,54.18 15.82,54.18 15.95,54.05 15.95,49.23 15.82,49.1
POE_VCC on BOTTOM: 20.4,60.4 20.27,60.53 20.27,65.35 20.4,65.48 23.32,65.48 23.44,65.35 23.44,60.53 23.32,60.4
POE_VCC on VCC: outline of 92 points within 0.51,13.97 139.45,88.77 ; 1 cut-out
POE_VCC_MOS on TOP: 14.3,95.33 17.98,95.33 19.51,93.8 22.81,93.8 22.94,93.93 22.94,97.74 22.81,97.87 16.71,97.87 16.46,98.12 16.46,99.39 16.33,99.52 13.03,99.52 12.9,99.39 12.9,97.23 13.03,97.1 13.92,97.1 14.17,96.85 14.17,95.45
PSE_D1 on TOP: 4.9,55.96 7.19,55.96 7.32,55.83 7.32,48.34 7.19,48.21 2.62,48.21 2.49,48.34 2.49,53.04 2.74,53.29 4.52,53.29 4.78,53.54 4.78,55.83
PSE_D2 on TOP: 12.4,55.96 14.68,55.96 14.81,55.83 14.81,48.34 14.68,48.21 10.11,48.21 9.98,48.34 9.98,53.04 10.24,53.29 12.01,53.29 12.27,53.54 12.27,55.83
PSE_D3 on TOP: 4.9,67.26 7.19,67.26 7.32,67.13 7.32,59.64 7.19,59.51 2.62,59.51 2.49,59.64 2.49,64.34 2.74,64.59 4.52,64.59 4.78,64.85 4.78,67.13
PSE_D4 on TOP: 12.4,67.26 14.68,67.26 14.81,67.13 14.81,59.64 14.68,59.51 10.11,59.51 9.98,59.64 9.98,64.34 10.24,64.59 12.01,64.59 12.27,64.85 12.27,67.13
PSE_D5 on TOP: 19.89,55.96 22.17,55.96 22.3,55.83 22.3,48.34 22.17,48.21 17.6,48.21 17.48,48.34 17.48,53.04 17.73,53.29 19.51,53.29 19.76,53.54 19.76,55.83
PSE_D6 on TOP: 19.89,67.26 22.17,67.26 22.3,67.13 22.3,59.64 22.17,59.51 17.6,59.51 17.48,59.64 17.48,64.34 17.73,64.59 19.51,64.59 19.76,64.85 19.76,67.13
PSE_D7 on TOP: 27.38,55.96 29.67,55.96 29.79,55.83 29.79,48.34 29.67,48.21 25.1,48.21 24.97,48.34 24.97,53.04 25.22,53.29 27,53.29 27.25,53.54 27.25,55.83
